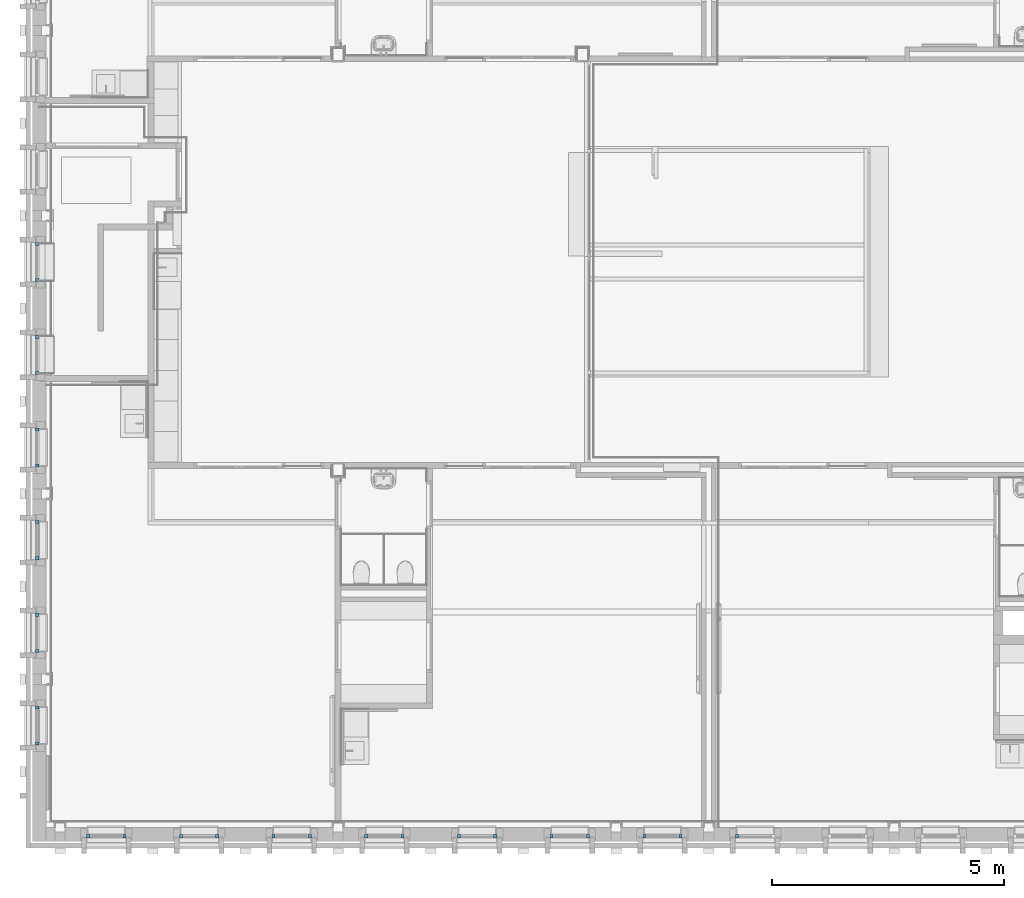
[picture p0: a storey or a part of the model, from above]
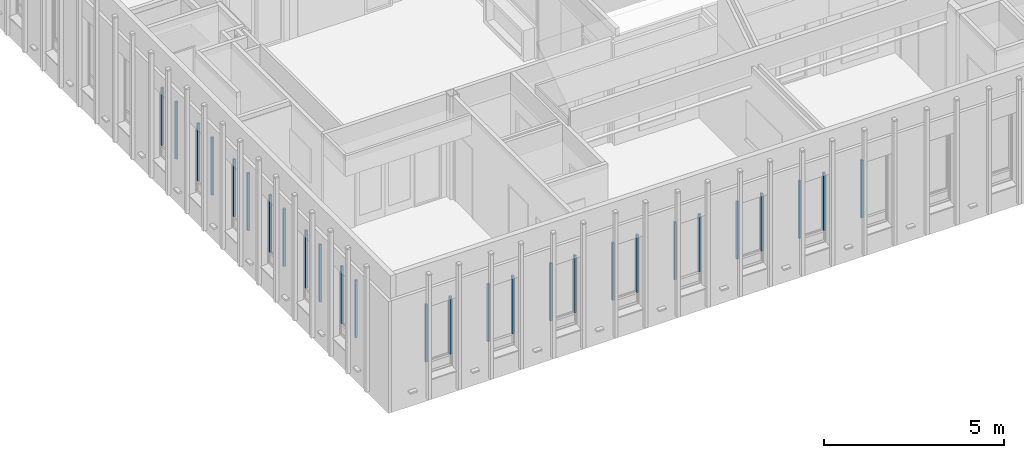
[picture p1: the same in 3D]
Properties of the parts of a building model (IFC2X3), part 1 of 94

# File
Description: ViewDefinition [CoordinationView_V2.0], RevitIdentifiers [VersionGUID: 146ff33c-e50f-46ca-b9aa-af931701fe89, NumberOfSaves: 1052], ExchangeRequirement [], CoordinateReference [CoordinateBase: Shared Coordinates, ProjectSite: Internal]
File name: 6755
Time: 2025-07-30T16:03:44
Organization: BDG Architecten
Written by: ODA IFC SDK 22.8
Made in: 22.1.30.34 - Exporter 22.6.0.0 - Alternate UI 22.6.0.0

# IfcProject, 6755
LongName: IKC Rummerinkhof Haren; Phase: Uitvoering Ontwerp

# IfcSite, Locatie
RefLatitude: 52, 22, 58, 797912; RefLongitude: 4, 54, 57, 599601; RefElevation: 0 mm
Phasing - Phase Created: 2. nieuwbouw
Dimensions - Projected Area: 0.473999 m2; Surface Area: 0.473999 m2
Identity Data - Workset: Workset1
Other - Category: Topography

# IfcSite: zitelementen trap:zitelementen trap, zitelementen trap:zitelementen trap:2230231
Material: <Unnamed>
Constraints - Moves With Nearby Elements: no
Phasing - Phase Created: 2. nieuwbouw
Dimensions - Area: 20.7661 m2; Volume: 9.77428 m3
Identity Data - Workset: Workset1
Other - Category: Site; Family: zitelementen trap; Family and Type: zitelementen trap: zitelementen trap; Type: zitelementen trap; Type Id: 2230229
Identity Data(Type) - Workset: Workset1; Type Name: zitelementen trap
Other(Type) - Category: Site; Family Name: zitelementen trap

# IfcBuilding, Bouwwerk
LongName: Bouwwerk
Text - CON: 22-12-2021; concepttekst: concept:; INST: 10-05-2022; modelverantwoordelijke: REU; ontwerpverantwoordelijke: SAM; Project_fase_afkorting: UO; projectverantwoordelijke: SAM; template_versie: 2019.1
Identity Data - Building Name: Bouwwerk; Organization Description: BDG Architecten; Organization Name: BDG Architecten; SiteName: Locatie; Workset: Project Info
Other - BCB_ProjectFolder: P:\0000_BDG_Revit_Bibliotheek\01 Template\; Category: Project Information; Client Name: Gemeente Groningen; Project Address: straatnaam + nummer postcode + plaatsnaam; Project Issue Date: 01-01-2019; Project Name: IKC Rummerinkhof Haren; Project Number: 6755; Project Status: Uitvoering Ontwerp

# IfcBuildingStorey: Level:A_hoogte_3.5mm (4)
In: Bouwwerk
Identity Data - Workset: Shared Levels and Grids
Other - Category: Levels; Family: Level
Constraints(Type) - Elevation Base: Project Base Point
Graphics(Type) - Line Pattern: levels; Line Weight: 1
Identity Data(Type) - Workset: Level Types
Other(Type) - Category: Levels; Family Name: Level
Name | LongName | Elevation (mm) | Constraints, Elevation (mm) | Computation Height (mm) | Building Story = Symbol at End 2 Default | Name | Structural = Symbol at End 1 Default | Family and Type | Type = Type Name | Type Id | Color | Symbol
00 begane grond | 00 begane grond | -5.41434e-13 | -1120 | 0 | no | ok. fundering | yes | Level: S_hoogte_1.8mm_fundering | S_hoogte_1.8mm_fundering | 2455 | 16711680 | NLRS_00_TAG_LVL_onder_binnen : 1.8mm | Extents - Scope Box: projectomtrek
01 eerste verdieping | 01 eerste verdieping | 4000 | 4000 | 1500 | yes | 01 eerste verdieping | no | Level: A_hoogte_3.5mm | A_hoogte_3.5mm | 2431 | 8421504 | NLRS_00_TAG_LVL : 3.5mm | Extents - Scope Box: projectomtrek
02 tweede verdieping | 02 tweede verdieping | 7800 | 7800 | 1500 | yes | 02 tweede verdieping | no | Level: A_hoogte_3.5mm | A_hoogte_3.5mm | 2431 | 8421504 | NLRS_00_TAG_LVL : 3.5mm
03 derde verdieping | 03 derde verdieping | 11600 | 11600 | 1500 | yes | 03 derde verdieping | no | Level: A_hoogte_3.5mm | A_hoogte_3.5mm | 2431 | 8421504 | NLRS_00_TAG_LVL : 3.5mm

# IfcAnnotation (51)
Name (Model Lines:...) | In | Group
2755334 | 01 eerste verdieping | Model Group:BI-30:2755094
2755564 | 01 eerste verdieping | Model Group:BI-30:2755094
2755577 | 01 eerste verdieping | Model Group:BI-30:2755094
2867687 | 00 begane grond | Model Group:pantry 1 kinderopvang:1511177
2868407 | 00 begane grond | Model Group:pantry 1 kinderopvang:1511177
2869288 | 00 begane grond | Model Group:pantry 1 kinderopvang:1223752
2869295 | 00 begane grond | Model Group:pantry 1 kinderopvang:1223752
2869762 | 00 begane grond | Model Group:pantry 1 kinderopvang:1511177
2869850 | 00 begane grond | Model Group:pantry 1 kinderopvang:1223752
2871598 | 00 begane grond | Model Group:pantry 1.2 MF BSO:1614348
2872757 | 01 eerste verdieping | Model Group:pantry 3 BS groepsruimten:1223713
2872777 | 02 tweede verdieping | Model Group:pantry 3 BS groepsruimten:1694326
2872792 | 01 eerste verdieping | Model Group:pantry 3 BS groepsruimten:2860118
2872797 | 01 eerste verdieping | Model Group:pantry 6 BSO startruimte:2860361
2872802 | 01 eerste verdieping | Model Group:pantry 3 BS groepsruimten:2860456
2872807 | 01 eerste verdieping | Model Group:pantry 3 BS groepsruimten:2860491
2872822 | 02 tweede verdieping | Model Group:pantry 3 BS groepsruimten:2860760
2872837 | 02 tweede verdieping | Model Group:pantry 3 BS groepsruimten:2860796
2873451 | 00 begane grond | Model Group:pantry 4 werkruimte OB:2071170
2873727 | 00 begane grond
2874626 | 01 eerste verdieping | Model Group:pantry 5 personeelsruimte:1672603
2875017 | 01 eerste verdieping | Model Group:pantry 5 personeelsruimte:1672603
2875172 | 01 eerste verdieping | Model Group:pantry 5 personeelsruimte:1672603
2875823 | 00 begane grond | Model Group:pantry 1.2 MF BSO:1614348
3028946 | 01 eerste verdieping
3221200 | 00 begane grond
3222013 | 00 begane grond
3222908 | 00 begane grond
3223677 | 00 begane grond
3267584 | 01 eerste verdieping | Model Group:pantry 3 BS groepsruimten:3267579
3267599 | 01 eerste verdieping | Model Group:pantry 3 BS groepsruimten:3267594
3267613 | 02 tweede verdieping | Model Group:pantry 3 BS groepsruimten:3267608
3267627 | 02 tweede verdieping | Model Group:pantry 3 BS groepsruimten:3267622
3267641 | 02 tweede verdieping | Model Group:pantry 3 BS groepsruimten:3267636
3270465 | 00 begane grond
3270484 | 00 begane grond
3473625 | 00 begane grond
3474388 | 00 begane grond
3685066 | 00 begane grond | Model Group:pantry 1.2 MF BSO:1614348
3694029 | 00 begane grond | Model Group:pantry 1 kinderopvang:1223752
4748769 | 01 eerste verdieping | Model Group:pantry 5 werkruimte MB BB:2860130
4749337 | 02 tweede verdieping | Model Group:pantry 5 werkruimte MB BB:4747283
4781338 | 00 begane grond
4782312 | 01 eerste verdieping | Model Group:pantry 5 werkruimte MB BB:2860130
4782402 | 02 tweede verdieping | Model Group:pantry 5 werkruimte MB BB:4747283
4782632 | 01 eerste verdieping
5027851 | 00 begane grond | Model Group:pantry 3 BS groepsruimten:5027846
5027942 | 00 begane grond | Model Group:pantry 3 BS groepsruimten:5027924
5027947 | 00 begane grond | Model Group:pantry 3 BS groepsruimten:5027929
5027957 | 00 begane grond | Model Group:pantry 3 BS groepsruimten:5027952
5101478 | 00 begane grond

# IfcBeam: NLRS_28_SF_LIB_balk hoeklijn_gen_ISR:balk_gen_L80x8 (13)
In: 01 eerste verdieping
Type - Structural Section Geometry - Centroid Horizontal: 22.6 mm; Centroid Vertical: 22.6 mm; Flange Fillet: 5 mm; Flange Thickness: 8 mm; Height: 80 mm; Web Fillet: 10 mm; Web Thickness: 8 mm; Width: 80 mm
Type - Structural Analysis - Perimeter: 0 mm; Warping Constant: 0; Elastic Modulus strong axis: 0.0000126 m3; Elastic Modulus weak axis: 0.0000126 m3; Moment of Inertia strong axis: 7.22e-07 m4; Moment of Inertia weak axis: 7.22e-07 m4; Nominal Weight: 9.62996; Plastic Modulus strong axis: 0 m3; Plastic Modulus weak axis: 0 m3; Principal Axes Angle: 45 deg; Section Area: 0.00123 m2; Torsional Moment of Inertia: 0 m4
Type - Structural - Section Shape: 11
Type - Dimensions - NLRS_C_breedte: 80 mm; NLRS_C_hoogte: 80 mm; r: 10 mm; RSen_C_thickness: 8 mm
Type - Identity Data - Assembly Code: 28.11; Assembly Description: hoofddraagconstructies; kolommen en liggers, kolom-/liggerconstructies; Code Name: EN 10056-1; DIN EN 10056-1; Description: L80X8; Section Name Key: L80X8; SmartRevit_Versie: 2019.1; Type Name: balk_gen_L80x8; Workset: Family : Structural Framing : NLRS_28_SF_LIB_balk hoeklijn_gen_ISR
Type - Other - Category: Structural Framing; Family Name: NLRS_28_SF_LIB_balk hoeklijn_gen_ISR
Classification: 28.11 Uniformat (Uniformat); Material: h2_staal_gen
Geometric Position - y Offset Value: 0 mm; yz Justification: Uniform; Join Status: Both joins enabled; End Extension: 434.108 mm; z Justification: Bottom; z Offset Value: -200 mm
Constraints - Reference Level: 01 eerste verdieping; Cross-Section Rotation: 0 deg; Orientation: Normal; Reference Level Elevation: 4000 mm; Work Plane: Reference Plane : dak fietsenstalling
Phasing - Phase Created: 2. nieuwbouw
Structural - Enable Analytical Model: yes; Stick Symbol Location: Center of Geometry; Structural Usage: Other
Identity Data - Workset: BDG_fietsenstalling
Other - Family: NLRS_28_SF_LIB_balk hoeklijn_gen_ISR; Family and Type: NLRS_28_SF_LIB_balk hoeklijn_gen_ISR: balk_gen_L80x8; Type: balk_gen_L80x8; Type Id: 4126976
Name (NLRS_28_SF_LIB_balk hoeklijn_gen_ISR:balk_gen_L80x8:...) | Start Extension (mm) | y Justification | End Level Offset (mm) | Start Level Offset (mm) | Cut Length (mm) | Length (mm) = NLRS_C_lengte (mm) | Volume (m3) | Group
4129964 | -92.8679 | Right | -1577.65 | -1835.93 | 3304.64 | 2963.4 | 0.00405391 | Model Group:hoeklijnen L80:4129968
4129966 | -767.325 | Left | -1577.65 | -1894.72 | 3304.68 | 3637.9 | 0.00405396 | Model Group:hoeklijnen L80:4129968
4136355 | 378.749 | Right | -1536.79 | -1829.51 | 3320.2 | 3358.6 | 0.00407299 | Model Group:fietsenstalling:4188142 | Geometric Position - End Join Cutback: 0 mm; Start Join Cutback: 0 mm
4137484 | -92.8679 | Right | -1577.65 | -1835.93 | 3304.64 | 2963.4 | 0.00405391 | Model Group:hoeklijnen L80:4137488
4137486 | -767.325 | Left | -1577.65 | -1894.72 | 3304.68 | 3637.9 | 0.00405396 | Model Group:hoeklijnen L80:4137488
4137510 | -92.8679 | Right | -1577.65 | -1835.93 | 3304.64 | 2963.4 | 0.00405391 | Model Group:hoeklijnen L80:4137514
4137512 | -767.325 | Left | -1577.65 | -1894.72 | 3304.68 | 3637.9 | 0.00405396 | Model Group:hoeklijnen L80:4137514
4137573 | -92.8679 | Right | -1577.65 | -1835.93 | 3304.64 | 2963.4 | 0.00405391 | Model Group:hoeklijnen L80:4137577
4137575 | -767.325 | Left | -1577.65 | -1894.72 | 3304.68 | 3637.9 | 0.00405396 | Model Group:hoeklijnen L80:4137577
4137597 | -92.8679 | Right | -1577.65 | -1835.93 | 3304.64 | 2963.4 | 0.00405391 | Model Group:hoeklijnen L80:4137601
4137599 | -767.325 | Left | -1577.65 | -1894.72 | 3304.68 | 3637.9 | 0.00405396 | Model Group:hoeklijnen L80:4137601
4137623 | -92.8679 | Right | -1577.65 | -1835.93 | 3304.64 | 2963.4 | 0.00405391 | Model Group:hoeklijnen L80:4137627
4137625 | -767.325 | Left | -1577.65 | -1894.72 | 3304.68 | 3637.9 | 0.00405396 | Model Group:hoeklijnen L80:4137627

# IfcBeam: NLRS_28_SF_LIB_balk koker ongelijk_gen_ISR:balk gen k150x100x4 (2)
In: 01 eerste verdieping
Type - PredefinedType: BEAM
Type - Structural Section Geometry - Centroid Horizontal: 50 mm; Centroid Vertical: 75 mm; Height: 150 mm; Inner Fillet: 4 mm; Outer Fillet: 8 mm; Wall Nominal Thickness: 4 mm; Width: 100 mm
Type - Structural Analysis - Nominal Weight: 0; Perimeter: 0 mm; Elastic Modulus strong axis: 0 m3; Elastic Modulus weak axis: 0 m3; Moment of Inertia strong axis: 0 m4; Moment of Inertia weak axis: 0 m4; Plastic Modulus strong axis: 0 m3; Plastic Modulus weak axis: 0 m3; Section Area: 0 m2; Torsional Modulus: 0 m3; Torsional Moment of Inertia: 0 m4
Type - Structural - Section Shape: 14
Type - Dimensions - NLRS_C_breedte: 100 mm; NLRS_C_hoogte: 150 mm; r: 8 mm; r1: 4 mm; RSen_C_thickness: 4 mm; Wall Design Thickness: 4 mm
Type - Identity Data - Workset: Family : Structural Framing : NLRS_28_SF_LIB_balk koker ongelijk_gen_ISR; Assembly Code: 28.10; Assembly Description: hoofddraagconstructies; kolommen en liggers, algemeen (verzamelniveau); Code Name: EN 10210-2; DIN EN 10210-2; Description: K150x100x4; SmartRevit_Versie: 2021.1; Type Name: balk gen k150x100x4
Type - Other - Category: Structural Framing; Family Name: NLRS_28_SF_LIB_balk koker ongelijk_gen_ISR
Classification: 28.10 Uniformat (Uniformat); Material: h2_staal_gen
Geometric Position - y Justification: Origin; y Offset Value: 0 mm; yz Justification: Uniform; z Justification: Top; z Offset Value: 0 mm; Join Status: Both joins enabled; End Extension: -112.5 mm; Start Extension: 575 mm
Constraints - Cross-Section Rotation: 0 deg
Phasing - Phase Created: 2. nieuwbouw
Structural - Enable Analytical Model: yes; Stick Symbol Location: Center of Geometry; Structural Usage: Other; Cut Length: 8445 mm
Dimensions - Length: 7982.5 mm; NLRS_C_lengte: 7982.5 mm; Volume: 0.0160015 m3
Identity Data - Workset: Workset1
Other - Family: NLRS_28_SF_LIB_balk koker ongelijk_gen_ISR; Family and Type: NLRS_28_SF_LIB_balk koker ongelijk_gen_ISR: balk gen k150x100x4; Type: balk gen k150x100x4; Type Id: 1358057
Name (NLRS_28_SF_LIB_balk koker ongelijk_gen_ISR:balk gen k150x100x4:...) | Reference Level | End Level Offset (mm) = Start Level Offset (mm) | Reference Level Elevation (mm) | Elevation at Bottom (mm) | Elevation at Top (mm)
3952707 | 01 eerste verdieping | 330 | 4000 | 4180 | 4330
3952937 | 01 ok. plafond | 430 | 6800 | 7080 | 7230

# IfcBeam: NLRS_28_SF_LIB_balk koker ongelijk_gen_ISR:balk gen k200x100x6 (6)
In: 01 eerste verdieping
Type - PredefinedType: BEAM
Type - Structural Section Geometry - Centroid Horizontal: 50 mm; Centroid Vertical: 100 mm; Height: 200 mm; Inner Fillet: 6 mm; Outer Fillet: 12 mm; Wall Nominal Thickness: 6 mm; Width: 100 mm
Type - Structural Analysis - Nominal Weight: 0; Perimeter: 0 mm; Elastic Modulus strong axis: 0 m3; Elastic Modulus weak axis: 0 m3; Moment of Inertia strong axis: 0 m4; Moment of Inertia weak axis: 0 m4; Plastic Modulus strong axis: 0 m3; Plastic Modulus weak axis: 0 m3; Section Area: 0 m2; Torsional Modulus: 0 m3; Torsional Moment of Inertia: 0 m4
Type - Structural - Section Shape: 14
Type - Dimensions - NLRS_C_breedte: 100 mm; NLRS_C_hoogte: 200 mm; r: 12 mm; r1: 6 mm; RSen_C_thickness: 6 mm; Wall Design Thickness: 6 mm
Type - Identity Data - Workset: Family : Structural Framing : NLRS_28_SF_LIB_balk koker ongelijk_gen_ISR; Assembly Code: 28.10; Assembly Description: hoofddraagconstructies; kolommen en liggers, algemeen (verzamelniveau); Code Name: EN 10210-2; DIN EN 10210-2; Description: K200x100x6; SmartRevit_Versie: 2021.1; Type Name: balk gen k200x100x6
Type - Other - Category: Structural Framing; Family Name: NLRS_28_SF_LIB_balk koker ongelijk_gen_ISR
Description: FRQ{AF4261DB-57B6-492A-99EC-BCCF86134FA2}; Classification: 28.10 Uniformat (Uniformat); Material: h2_staal_gen
ProfileProperties - SectionFamily: {AF4261DB-57B6-492A-99EC-BCCF86134FA2}FRQ; Section: FRQ{AF4261DB-57B6-492A-99EC-BCCF86134FA2}
Geometric Position - y Justification: Origin; y Offset Value: 0 mm; yz Justification: Uniform; z Justification: Top; z Offset Value: 0 mm; Join Status: Both joins enabled
Constraints - Reference Level: 01 eerste verdieping; End Level Offset: 2900 mm; Reference Level Elevation: 4000 mm; Start Level Offset: 2900 mm
Phasing - Phase Created: 2. nieuwbouw
Structural - Enable Analytical Model: yes; Stick Symbol Location: Center of Geometry; Structural Usage: Other; Coating: -
Identity Data - Workset: Workset1
Other - Family: NLRS_28_SF_LIB_balk koker ongelijk_gen_ISR; Family and Type: NLRS_28_SF_LIB_balk koker ongelijk_gen_ISR: balk gen k200x100x6; Type: balk gen k200x100x6; Type Id: 1357985
Name (NLRS_28_SF_LIB_balk koker ongelijk_gen_ISR:balk gen k200x100x6:...) | Cross-Section Rotation (deg) | Cut Length (mm) | Exact Weight (kg) | Paint Area (m2) | Weight (kg) | Elevation at Bottom (mm) | Elevation at Top (mm) | Length (mm) = NLRS_C_lengte (mm) | Volume (m3)
2552460 | 90 | 14868.8 | 138.321 | 8.92127 | 139.257 | 6750 | 7050 | 14768.7 | 0.0510409
2552454 | 90 | 6750 | 61.3457 | 4.05 | 63.2189 | 6850 | 6950 | 6550 | 0.0226368
2464441 | -90 | 6260 | 57.6931 | 3.756 | 58.6296 | 6750 | 7050 | 6160 | 0.021289
2552452 | 90 | 9725 | 90.1454 | 5.835 | 91.082 | 6850 | 6950 | 9725 | 0.033264
2552462 | -90 | 6175 | 56.897 | 3.705 | 57.8336 | 6750 | 7050 | 6075 | 0.0209952
2552456 | 90 | 18249.9 | 169.987 | 10.9499 | 170.924 | 6850 | 6950 | 18179.8 | 0.062726

# IfcBeam: NLRS_28_SF_LIB_balk koker ongelijk_gen_ISR:balk gen k80x50x4 (31)
In: 01 eerste verdieping
Type - PredefinedType: BEAM
Type - Structural Section Geometry - Centroid Horizontal: 25 mm; Centroid Vertical: 40 mm; Height: 80 mm; Inner Fillet: 4 mm; Outer Fillet: 8 mm; Wall Nominal Thickness: 4 mm; Width: 50 mm
Type - Structural Analysis - Elastic Modulus strong axis: 0 m3; Elastic Modulus weak axis: 0 m3; Moment of Inertia strong axis: 0 m4; Moment of Inertia weak axis: 0 m4; Nominal Weight: 0; Perimeter: 0 mm; Plastic Modulus strong axis: 0 m3; Plastic Modulus weak axis: 0 m3; Section Area: 0 m2; Torsional Modulus: 0 m3; Torsional Moment of Inertia: 0 m4
Type - Structural - Section Shape: 14
Type - Dimensions - NLRS_C_breedte: 50 mm; NLRS_C_hoogte: 80 mm; r: 8 mm; r1: 4 mm; RSen_C_thickness: 4 mm; Wall Design Thickness: 4 mm
Type - Identity Data - Assembly Code: 28.10; Assembly Description: hoofddraagconstructies; kolommen en liggers, algemeen (verzamelniveau); Code Name: EN 10210-2; DIN EN 10210-2; Description: K80x50x4; SmartRevit_Versie: 2021.1; Type Name: balk gen k80x50x4; Workset: Family : Structural Framing : NLRS_28_SF_LIB_balk koker ongelijk_gen_ISR
Type - Other - Category: Structural Framing; Family Name: NLRS_28_SF_LIB_balk koker ongelijk_gen_ISR
Classification: 28.10 Uniformat (Uniformat); Material: h2_staal_gen
Geometric Position - Join Status: One or two joins disabled; y Justification: Origin; y Offset Value: 0 mm; yz Justification: Uniform; z Justification: Top; z Offset Value: 0 mm
Constraints - Reference Level: 01 eerste verdieping; Reference Level Elevation: 4000 mm
Phasing - Phase Created: 2. nieuwbouw
Structural - Enable Analytical Model: yes; Stick Symbol Location: Center of Geometry; Structural Usage: Other
Identity Data - Workset: Workset1
Other - Family: NLRS_28_SF_LIB_balk koker ongelijk_gen_ISR; Family and Type: NLRS_28_SF_LIB_balk koker ongelijk_gen_ISR: balk gen k80x50x4; Type: balk gen k80x50x4; Type Id: 1358229
Name (NLRS_28_SF_LIB_balk koker ongelijk_gen_ISR:balk gen k80x50x4:...) | End Extension (mm) | Start Extension (mm) | Cross-Section Rotation (deg) | End Level Offset (mm) = Start Level Offset (mm) | Cut Length (mm) | Elevation at Bottom (mm) | Elevation at Top (mm) | Length (mm) = NLRS_C_lengte (mm) | Volume (m3)
2766380 | 0 | 0 | 90 | 900 | 1900 | 4875 | 4925 | 1900 | 0.0017761
2767286 | 0 | 0 | 90 | 900 | 1900 | 4875 | 4925 | 1900 | 0.0017761
2767301 | 0 | 0 | 90 | 900 | 1900 | 4875 | 4925 | 1900 | 0.0017761
2767314 | 0 | 0 | 90 | 900 | 1577 | 4875 | 4925 | 1577 | 0.00147416
2767377 | 0 | 0 | 90 | 900 | 1900 | 4875 | 4925 | 1900 | 0.0017761
2767541 | 65 | 0 | 90 | 900 | 1900 | 4875 | 4925 | 1835 | 0.0017761
2767805 | 0 | 0 | 90 | 900 | 1900 | 4875 | 4925 | 1900 | 0.0017761
2767822 | 0 | 0 | 90 | 900 | 1900 | 4875 | 4925 | 1900 | 0.0017761
2767837 | 0 | 0 | 90 | 900 | 1900 | 4875 | 4925 | 1900 | 0.0017761
2767852 | 0 | 0 | 90 | 900 | 1900 | 4875 | 4925 | 1900 | 0.0017761
2767869 | 0 | 0 | 90 | 900 | 1900 | 4875 | 4925 | 1900 | 0.0017761
2767888 | 0 | 0 | 90 | 900 | 990 | 4875 | 4925 | 990 | 0.000925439
2768090 | 0 | -15 | 90 | 900 | 2053.3 | 4875 | 4925 | 2068.3 | 0.0019194
2768313 | 0 | 0 | 90 | 900 | 2083.4 | 4875 | 4925 | 2083.4 | 0.00194754
2768391 | 0 | 0 | 90 | 900 | 2142.6 | 4875 | 4925 | 2142.6 | 0.00200287
2768988 | 0 | 0 | 90 | 330 | 860 | 4305 | 4355 | 860 | 0.000803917
2769003 | 0 | 0 | 90 | 900 | 270 | 4875 | 4925 | 270 | 0.000252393
2770761 | 0 | 0 | 90 | 900 | 1875 | 4875 | 4925 | 1875 | 0.00175273
2771299 | 0 | 0 | 90 | 900 | 912.7 | 4875 | 4925 | 912.7 | 0.00085318
2771316 | 0 | 0 | 90 | 900 | 1900.2 | 4875 | 4925 | 1900.2 | 0.00177628
2772880 | 0 | 0 | -90 | 300 | 1875 | 4275 | 4325 | 1875 | 0.00175273
2772883 | 0 | 0 | -90 | 300 | 1875 | 4275 | 4325 | 1875 | 0.00175273
2772885 | 0 | 0 | -90 | 300 | 1900.2 | 4275 | 4325 | 1900.2 | 0.00177628
2879938 | 0 | 0 | 90 | 900 | 1900 | 4875 | 4925 | 1900 | 0.0017761
2880081 | 0 | 0 | 90 | 900 | 1900 | 4875 | 4925 | 1900 | 0.0017761
2880092 | 0 | 0 | 90 | 900 | 1900 | 4875 | 4925 | 1900 | 0.0017761
2880107 | 0 | 0 | 90 | 900 | 1900 | 4875 | 4925 | 1900 | 0.0017761
2880124 | 0 | 0 | 90 | 900 | 1900 | 4875 | 4925 | 1900 | 0.0017761
2880139 | 0 | 0 | 90 | 900 | 1900 | 4875 | 4925 | 1900 | 0.0017761
2880150 | 0 | 0 | 90 | 900 | 1900 | 4875 | 4925 | 1900 | 0.0017761
2880163 | 0 | 0 | 90 | 900 | 525 | 4875 | 4925 | 525 | 0.000490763

# IfcBeam: NLRS_28_SF_LIB_balk koker_gen_ongelijk_ISR:balk_gen_K60x60x4 (20)
In: 00 begane grond
Type - Structural Section Geometry - Centroid Horizontal: 30 mm; Centroid Vertical: 30 mm; Height: 60 mm; Inner Fillet: 4 mm; Outer Fillet: 6 mm; Wall Nominal Thickness: 4 mm; Width: 60 mm
Type - Structural Analysis - Elastic Modulus strong axis: 0.0000109 m3; Elastic Modulus weak axis: 0.00000852 m3; Moment of Inertia strong axis: 3.28e-07 m4; Moment of Inertia weak axis: 1.7e-07 m4; Nominal Weight: 5.63998; Perimeter: 190 mm; Plastic Modulus strong axis: 0.0000138 m3; Plastic Modulus weak axis: 0.0000103 m3; Section Area: 0.000719 m2; Torsional Modulus: 0.00001371 m3; Torsional Moment of Inertia: 3.67e-07 m4
Type - Structural - Section Shape: 14
Type - Dimensions - NLRS_C_breedte: 60 mm; NLRS_C_hoogte: 60 mm; r: 4 mm; RSen_C_thickness: 4 mm; Wall Design Thickness: 4 mm
Type - Identity Data - Assembly Code: 28.11; Assembly Description: hoofddraagconstructies; kolommen en liggers, kolom-/liggerconstructies; Code Name: EN 10210-2; DIN EN 10210-2; Description: K60X40X4; Section Name Key: R60X40X4; SmartRevit_Versie: 2019.1; Type Name: balk_gen_K60x60x4; Workset: Family : Structural Framing : NLRS_28_SF_LIB_balk koker_gen_ongelijk_ISR
Type - Other - Category: Structural Framing; Family Name: NLRS_28_SF_LIB_balk koker_gen_ongelijk_ISR
Classification: 28.11 Uniformat (Uniformat); Material: h2_staal_gen
Geometric Position - End Extension: 0 mm; Join Status: One or two joins disabled; Start Extension: 0 mm; y Justification: Origin; y Offset Value: 0 mm; yz Justification: Uniform; z Justification: Top; z Offset Value: 0 mm
Constraints - Cross-Section Rotation: 0 deg
Phasing - Phase Created: 2. nieuwbouw
Structural - Enable Analytical Model: yes; Stick Symbol Location: Center of Geometry; Structural Usage: Other
Identity Data - Workset: BDG_fietsenstalling
Other - Family: NLRS_28_SF_LIB_balk koker_gen_ongelijk_ISR; Family and Type: NLRS_28_SF_LIB_balk koker_gen_ongelijk_ISR: balk_gen_K60x60x4; Type: balk_gen_K60x60x4; Type Id: 4098477
Name (NLRS_28_SF_LIB_balk koker_gen_ongelijk_ISR:balk_gen_K60x60x4:...) | End Level Offset (mm) = Start Level Offset (mm) | Reference Level | Reference Level Elevation (mm) | Cut Length (mm) = Length (mm) = NLRS_C_lengte (mm) | Elevation at Bottom (mm) | Elevation at Top (mm) | Volume (m3) | Group
4158217 | -600 | 00 ok. plafond | 2800 | 959.7 | 2140 | 2200 | 0.000820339 | Model Group:enkele deur-kokers:4158221
4158219 | 60 | 00 begane grond | 0 | 958.5 | 0 | 60 | 0.000819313 | Model Group:enkele deur-kokers:4158221
4158252 | -600 | 00 ok. plafond | 2800 | 959.7 | 2140 | 2200 | 0.000820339 | Model Group:enkele deur-kokers:4158256
4158254 | 60 | 00 begane grond | 0 | 958.5 | 0 | 60 | 0.000819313 | Model Group:enkele deur-kokers:4158256
4158441 | -600 | 00 ok. plafond | 2800 | 959.7 | 2140 | 2200 | 0.000820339 | Model Group:enkele deur-kokers:4158445
4158443 | 60 | 00 begane grond | 0 | 958.5 | 0 | 60 | 0.000819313 | Model Group:enkele deur-kokers:4158445
4158453 | -600 | 00 ok. plafond | 2800 | 959.7 | 2140 | 2200 | 0.000820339 | Model Group:enkele deur-kokers:4158457
4158455 | 60 | 00 begane grond | 0 | 958.5 | 0 | 60 | 0.000819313 | Model Group:enkele deur-kokers:4158457
4158493 | -600 | 00 ok. plafond | 2800 | 959.7 | 2140 | 2200 | 0.000820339 | Model Group:enkele deur-kokers:4158497
4158495 | 60 | 00 begane grond | 0 | 958.5 | 0 | 60 | 0.000819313 | Model Group:enkele deur-kokers:4158497
4158505 | -600 | 00 ok. plafond | 2800 | 959.7 | 2140 | 2200 | 0.000820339 | Model Group:enkele deur-kokers:4158509
4158507 | 60 | 00 begane grond | 0 | 958.5 | 0 | 60 | 0.000819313 | Model Group:enkele deur-kokers:4158509
4158519 | -600 | 00 ok. plafond | 2800 | 959.7 | 2140 | 2200 | 0.000820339 | Model Group:enkele deur-kokers:4158523
4158521 | 60 | 00 begane grond | 0 | 958.5 | 0 | 60 | 0.000819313 | Model Group:enkele deur-kokers:4158523
4158531 | -600 | 00 ok. plafond | 2800 | 959.7 | 2140 | 2200 | 0.000820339 | Model Group:enkele deur-kokers:4158535
4158533 | 60 | 00 begane grond | 0 | 958.5 | 0 | 60 | 0.000819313 | Model Group:enkele deur-kokers:4158535
4158545 | -600 | 00 ok. plafond | 2800 | 959.7 | 2140 | 2200 | 0.000820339 | Model Group:enkele deur-kokers:4158549
4158547 | 60 | 00 begane grond | 0 | 958.5 | 0 | 60 | 0.000819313 | Model Group:enkele deur-kokers:4158549
4158557 | -600 | 00 ok. plafond | 2800 | 959.7 | 2140 | 2200 | 0.000820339 | Model Group:enkele deur-kokers:4158561
4158559 | 60 | 00 begane grond | 0 | 958.5 | 0 | 60 | 0.000819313 | Model Group:enkele deur-kokers:4158561

# IfcBeam: NLRS_28_SF_LIB_balk unp_gen_ISR:balk_gen_UNP200 (6)
Type - PredefinedType: BEAM
Type - Structural Section Geometry - Centroid Horizontal: 19.2 mm; Centroid Vertical: 100 mm; Flange Fillet: 5.5 mm; Flange Thickness: 11 mm; Flange Thickness Location: 35 mm; Height: 200 mm; Sloped Flange Angle: 0 deg; Web Fillet: 11 mm; Web Thickness: 8 mm; Width: 70 mm
Type - Structural Analysis - Warping Constant: 0; Elastic Modulus strong axis: 0.00015 m3; Elastic Modulus weak axis: 0.0000224 m3; Moment of Inertia strong axis: 0.0000135 m4; Moment of Inertia weak axis: 0.00000114 m4; Nominal Weight: 21.9999; Perimeter: 611 mm; Plastic Modulus strong axis: 0 m3; Plastic Modulus weak axis: 0 m3; Section Area: 0.0028 m2; Torsional Moment of Inertia: 0 m4
Type - Structural - Section Shape: 10
Type - Dimensions - Clear Web Height: 0 mm; NLRS_C_breedte: 70 mm; NLRS_C_hoogte: 200 mm; r: 11 mm; r1: 5.5 mm; tf: 11 mm; tw: 8 mm; Web Toe of Fillet: 0 mm
Type - Identity Data - Assembly Code: 28.10; Assembly Description: hoofddraagconstructies; kolommen en liggers, algemeen (verzamelniveau); Code Name: DIN1026-1:2009; NF A 45-202; Description: UNP180; SmartRevit_Versie: 2021.1; Type Name: balk_gen_UNP200; Workset: Family : Structural Framing : NLRS_28_SF_LIB_balk unp_gen_ISR
Type - Other - Category: Structural Framing; Angle: 4.58 deg; Family Name: NLRS_28_SF_LIB_balk unp_gen_ISR
Classification: 28.10 Uniformat (Uniformat); Material: h2_staal_gen
Geometric Position - y Justification: Origin; y Offset Value: 0 mm; yz Justification: Uniform; z Justification: Top; z Offset Value: 0 mm; Join Status: Both joins enabled
Phasing - Phase Created: 2. nieuwbouw
Structural - Enable Analytical Model: yes; Stick Symbol Location: Center of Geometry; Structural Usage: Other
Other - Family: NLRS_28_SF_LIB_balk unp_gen_ISR; Family and Type: NLRS_28_SF_LIB_balk unp_gen_ISR: balk_gen_UNP200; Type: balk_gen_UNP200; Type Id: 3268208
Name (NLRS_28_SF_LIB_balk unp_gen_ISR:balk_gen_UNP200:...) | In | End Extension (mm) | Start Extension (mm) | Cross-Section Rotation (deg) | End Level Offset (mm) | Reference Level | Reference Level Elevation (mm) | Start Level Offset (mm) | Cut Length (mm) | Elevation at Bottom (mm) | Elevation at Top (mm) | Length (mm) = NLRS_C_lengte (mm) | Volume (m3) | Workset | Orientation | Work Plane | Group
3268982 | 00 begane grond | 0 | 0 | 90 | 3000 | 00 begane grond | 0 | 3000 | 2028.5 | 2980.8 | 3050.8 | 2033.8 | 0.00607789 | Workset1 | Geometric Position - End Join Cutback: -45.5 mm; Start Join Cutback: -45.5 mm; Structural - End Attachment Type: End Elevation; Start Attachment Type: End Elevation
4121682 | 01 eerste verdieping | -396.262 | 0 | 0 | -1829.51 | 01 eerste verdieping | 4000 | -1536.79 | 3460.23 |  |  | 3358.6 | 0.0100619 | BDG_fietsenstalling | Normal | Reference Plane : dak fietsenstalling | Model Group:UNP rand fietsenstalling:4046343
4121830 | 01 eerste verdieping | 0 | -72.33 | 0 | -1829.51 | 01 eerste verdieping | 4000 | -1829.51 | 14340 | 1966.82 | 2172.16 | 14238.4 | 0.0426652 | BDG_fietsenstalling | Normal | Reference Plane : dak fietsenstalling | Model Group:UNP rand fietsenstalling:4046343
4126428 | 01 eerste verdieping | 0 | 0 | 0 | -1536.79 | 01 eerste verdieping | 4000 | -1829.51 | 3460.23 |  |  | 3358.6 | 0.0100619 | BDG_fietsenstalling | Normal | Reference Plane : dak fietsenstalling | Model Group:UNP rand fietsenstalling:4046343
4126781 | 01 eerste verdieping | 0 | 0 | 0 | -1536.79 | 01 eerste verdieping | 4000 | -1536.79 | 14340 | 2262.3 | 2467.64 | 14238.4 | 0.0426652 | BDG_fietsenstalling | Normal | Reference Plane : dak fietsenstalling | Model Group:UNP rand fietsenstalling:4046343
4198678 | 00 begane grond | 0 | 0 | -90 | 3000 | 00 begane grond | 0 | 3000 | 1293 | 2980.8 | 3050.8 | 1298.3 | 0.00387415 | Workset1 | Geometric Position - End Join Cutback: -45.5 mm; Start Join Cutback: -45.5 mm; Structural - End Attachment Type: End Elevation; Start Attachment Type: End Elevation

# IfcBuildingElementProxy: 00_BDG_GM_Nulpunt:00_BDG_GM_Nulpunt, 00_BDG_GM_Nulpunt:00_BDG_GM_Nulpunt:668490
In: 00 begane grond
Type - Material: BDG - Zwart, BDG - Wit
Type - Constraints - Default Elevation: 0 mm
Type - Identity Data - algemeen_URL: www.bdgarchitecten.nl; Description: Nulpuntobject; Type Name: 00_BDG_GM_Nulpunt; Workset: Family : Generic Models : 00_BDG_GM_Nulpunt
Type - Other - Category: Generic Models; Family Name: 00_BDG_GM_Nulpunt
Constraints - Elevation from Level: 0 mm; Host: Level : 00 begane grond; Level: 00 begane grond; Moves With Nearby Elements: no; Offset from Host: 0 mm
Phasing - Phase Created: 2. nieuwbouw
Dimensions - Area: 3.45179 m2; Volume: 1.00565 m3
Identity Data - Workset: Workset1
Other - Family: 00_BDG_GM_Nulpunt; Family and Type: 00_BDG_GM_Nulpunt: 00_BDG_GM_Nulpunt; Type: 00_BDG_GM_Nulpunt; Type Id: 668474

# IfcBuildingElementProxy: 200_50_BDG_noodoverstort:NO-01 (2)
In: 03 derde verdieping
Type - Material: GAG_noodoverstort
Type - Constraints - Default Elevation: 0 mm
Type - Materials and Finishes - materiaal: GAG_noodoverstort
Type - Dimensions - breedte: 350 mm; diepte_binnen_stramien: 180 mm; diepte_buiten_stramien: 170 mm; hoek: 7.5 deg; hoogte: 120 mm; offset_peil: 225 mm
Type - Identity Data - Workset: Family : Generic Models : 200_50_BDG_noodoverstort; Description: NO.; Type Name: NO-01
Type - Other - Category: Generic Models; Family Name: 200_50_BDG_noodoverstort
Constraints - Moves With Nearby Elements: no; Level: 03 derde verdieping; Elevation from Level: 70 mm; Host: Level : 03 derde verdieping; Offset from Host: 70 mm
Phasing - Phase Created: 2. nieuwbouw
Dimensions - Area: 0.330895 m2; Volume: 0.00065803 m3
Identity Data - Workset: Workset1
Other - Family: 200_50_BDG_noodoverstort; Family and Type: 200_50_BDG_noodoverstort: NO-01; Type: NO-01; Type Id: 4693193
Name (200_50_BDG_noodoverstort:NO-01:...)
4693038
4693404

# IfcBuildingElementProxy: 200_50_BDG_noodoverstort:NO-02 (2)
In: 01 eerste verdieping
Type - Material: GAG_noodoverstort
Type - Constraints - Default Elevation: 0 mm
Type - Materials and Finishes - materiaal: GAG_noodoverstort
Type - Dimensions - breedte: 200 mm; diepte_binnen_stramien: 180 mm; diepte_buiten_stramien: 170 mm; hoek: 10 deg; hoogte: 120 mm; offset_peil: 225 mm
Type - Identity Data - Workset: Family : Generic Models : 200_50_BDG_noodoverstort; Description: NO.; Type Name: NO-02
Type - Other - Category: Generic Models; Family Name: 200_50_BDG_noodoverstort
Constraints - Moves With Nearby Elements: no; Elevation from Level: 270 mm; Host: Level : 02 bk. constructie gymzaal; Level: 02 bk. constructie gymzaal; Offset from Host: 270 mm
Phasing - Phase Created: 2. nieuwbouw
Dimensions - Area: 0.225896 m2; Volume: 0.000449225 m3
Identity Data - Workset: Workset1
Other - Family: 200_50_BDG_noodoverstort; Family and Type: 200_50_BDG_noodoverstort: NO-02; Type: NO-02; Type Id: 4692311
Name (200_50_BDG_noodoverstort:NO-02:...)
4692275
4692902

# IfcBuildingElementProxy: 200_50_BDG_noodoverstort:NO-03, 200_50_BDG_noodoverstort:NO-03:4690609
In: 01 eerste verdieping
Type - Material: GAG_noodoverstort
Type - Constraints - Default Elevation: 0 mm
Type - Materials and Finishes - materiaal: GAG_noodoverstort
Type - Dimensions - breedte: 350 mm; diepte_binnen_stramien: 110 mm; diepte_buiten_stramien: 260 mm; hoek: 10 deg; hoogte: 150 mm; offset_peil: 225 mm
Type - Identity Data - Workset: Family : Generic Models : 200_50_BDG_noodoverstort; Description: NO.; Type Name: NO-03
Type - Other - Category: Generic Models; Family Name: 200_50_BDG_noodoverstort
Constraints - Moves With Nearby Elements: no; Level: 01 eerste verdieping; Elevation from Level: 50 mm; Host: Level : 01 eerste verdieping; Offset from Host: 50 mm
Phasing - Phase Created: 2. nieuwbouw
Dimensions - Area: 0.374717 m2; Volume: 0.000745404 m3
Identity Data - Workset: Workset1
Other - Family: 200_50_BDG_noodoverstort; Family and Type: 200_50_BDG_noodoverstort: NO-03; Type: NO-03; Type Id: 4690830

# IfcBuildingElementProxy: 200_50_BDG_noodoverstort:noodoverstort verdieping, 200_50_BDG_noodoverstort:noodoverstort verdieping:2224659
In: 02 tweede verdieping
Type - Material: GAG_noodoverstort
Type - Constraints - Default Elevation: 0 mm
Type - Materials and Finishes - materiaal: GAG_noodoverstort
Type - Dimensions - breedte: 230 mm; diepte_binnen_stramien: 160 mm; diepte_buiten_stramien: 300 mm; hoek: 10 deg; hoogte: 70 mm; offset_peil: 225 mm
Type - Identity Data - Description: NO.; Type Name: noodoverstort verdieping; Workset: Family : Generic Models : 200_50_BDG_noodoverstort
Type - Other - Category: Generic Models; Family Name: 200_50_BDG_noodoverstort
Constraints - Moves With Nearby Elements: no; Level: 02 tweede verdieping; Elevation from Level: 50 mm; Host: Level : 02 tweede verdieping; Offset from Host: 50 mm
Phasing - Phase Created: 2. nieuwbouw
Dimensions - Area: 0.277723 m2; Volume: 0.000553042 m3
Identity Data - Workset: Workset1
Other - Family: 200_50_BDG_noodoverstort; Family and Type: 200_50_BDG_noodoverstort: noodoverstort verdieping; Type: noodoverstort verdieping; Type Id: 2224213

# IfcBuildingElementProxy: 28_BDG_ladderborging:Type 1, 28_BDG_ladderborging:Type 1:2803350
In: 01 eerste verdieping
Type - Material: Aluminium
Type - Constraints - Default Elevation: 0 mm
Type - Materials and Finishes - materiaal: Aluminium
Type - Identity Data - Type Name: Type 1; Workset: Family : Generic Models : 28_BDG_ladderborging
Type - Other - Category: Generic Models; Family Name: 28_BDG_ladderborging
Constraints - Level: 01 eerste verdieping; Elevation from Level: 2975 mm
Phasing - Phase Created: 2. nieuwbouw
Dimensions - Area: 0.158771 m2; Volume: 0.000748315 m3
Identity Data - Workset: Workset1
Other - Type: Type 1; Family: 28_BDG_ladderborging; Family and Type: 28_BDG_ladderborging: Type 1; Host Id: 1888559; Type Id: 2803331

# IfcBuildingElementProxy: 80_FUS_UN_garderobe:GK 1A 2231x350x1050 (2)
Type - Material: ISR_Hout
Type - Constraints - Default Elevation: 1219.2 mm; aantal_haken: 27
Type - Materials and Finishes - materiaal_kader: ISR_Hout; materiaal_kastframe: ISR_Hout
Type - Construction - 2 tussenpanelen: no; tussenpaneel: no
Type - Dimensions - diepte: 350 mm; diepte_kastplanken: 310 mm; kasthoogte: 1050 mm; lengte: 2231 mm; plaatmateriaal_dikte: 40 mm; rij-afstand haken: 75 mm
Type - Identity Data - Type Comments: GK 1A; Type Name: GK 1A 2231x350x1050; Workset: Family : Generic Models : 80_FUS_UN_garderobe
Type - Other - Category: Generic Models; afstand_eerste_laatste_tussenvak: 434 mm; ber_aantal_haken: 26; ber_aantal_haken_rij1: 13; ber_aantal_haken_rij2: 14; ber_afstand_eerste_haak: 100.5 mm; ber_lengte_haken_rij1: 1800 mm; ber_lengte_haken_rij2: 1950 mm; Family Name: 80_FUS_UN_garderobe
Material: <Unnamed>, ISR_Hout
Constraints - Elevation from Level: 0 mm; Offset from Host: 0 mm
Phasing - Phase Created: 2. nieuwbouw
Dimensions - Area: 6.56335 m2; Volume: 0.169559 m3
Identity Data - Workset: Workset1; Comments: GK 1A
Other - Family: 80_FUS_UN_garderobe; Family and Type: 80_FUS_UN_garderobe: GK 1A 2231x350x1050; Type: GK 1A 2231x350x1050; Type Id: 2808452
Name (80_FUS_UN_garderobe:GK 1A 2231x350x1050:...) | In | Level = Schedule Level | Work Plane
1784800 | 00 begane grond | 00 begane grond | Level : 00 begane grond
2882982 | 02 tweede verdieping | 02 tweede verdieping | Floor : NLRS_43_FL_cementdekvloer 50_gen_ISR

# IfcBuildingElementProxy: 80_FUS_UN_garderobe:GK 1B 3070x350x1050, 80_FUS_UN_garderobe:GK 1B 3070x350x1050:2812023
In: 00 begane grond
Type - Material: ISR_Hout
Type - Constraints - Default Elevation: 1219.2 mm; aantal_haken: 38
Type - Materials and Finishes - materiaal_kader: ISR_Hout; materiaal_kastframe: ISR_Hout
Type - Construction - 2 tussenpanelen: no; tussenpaneel: yes
Type - Dimensions - diepte: 350 mm; diepte_kastplanken: 310 mm; kasthoogte: 1050 mm; lengte: 3070 mm; plaatmateriaal_dikte: 40 mm; rij-afstand haken: 75 mm
Type - Identity Data - Workset: Family : Generic Models : 80_FUS_UN_garderobe; Type Comments: GK 1B; Type Name: GK 1B 3070x350x1050
Type - Other - Category: Generic Models; afstand_eerste_laatste_tussenvak: 434 mm; ber_aantal_haken: 37; ber_aantal_haken_rij1: 19; ber_aantal_haken_rij2: 19; ber_afstand_eerste_haak: 107.5 mm; ber_lengte_haken_rij1: 2700 mm; ber_lengte_haken_rij2: 2700 mm; Family Name: 80_FUS_UN_garderobe
Material: <Unnamed>, ISR_Hout
Constraints - Elevation from Level: 0 mm; Level: 00 begane grond; Offset from Host: 0 mm; Schedule Level: 00 begane grond; Work Plane: Level : 00 begane grond
Phasing - Phase Created: 2. nieuwbouw
Dimensions - Area: 8.30152 m2; Volume: 0.234678 m3
Identity Data - Workset: Workset1; Comments: GK 1B
Other - Family: 80_FUS_UN_garderobe; Family and Type: 80_FUS_UN_garderobe: GK 1B 3070x350x1050; Type: GK 1B 3070x350x1050; Type Id: 2812189

# IfcBuildingElementProxy: 80_FUS_UN_garderobe:GK 2 4750x350x1050 (2)
In: 00 begane grond
Type - Material: ISR_Hout
Type - Constraints - Default Elevation: 1219.2 mm; aantal_haken: 61
Type - Materials and Finishes - materiaal_kader: ISR_Hout; materiaal_kastframe: ISR_Hout
Type - Construction - tussenpaneel: no; 2 tussenpanelen: yes
Type - Dimensions - diepte: 350 mm; diepte_kastplanken: 310 mm; kasthoogte: 1050 mm; lengte: 4750 mm; plaatmateriaal_dikte: 40 mm; rij-afstand haken: 75 mm
Type - Identity Data - Workset: Family : Generic Models : 80_FUS_UN_garderobe; Type Comments: GK 2; Type Name: GK 2 4750x350x1050
Type - Other - Category: Generic Models; afstand_eerste_laatste_tussenvak: 434 mm; ber_aantal_haken: 60; ber_aantal_haken_rij1: 30; ber_aantal_haken_rij2: 31; ber_afstand_eerste_haak: 85 mm; ber_lengte_haken_rij1: 4350 mm; ber_lengte_haken_rij2: 4500 mm; Family Name: 80_FUS_UN_garderobe
Material: <Unnamed>, ISR_Hout
Constraints - Elevation from Level: 0 mm; Level: 00 begane grond; Offset from Host: 0 mm; Schedule Level: 00 begane grond; Work Plane: Level : 00 begane grond
Phasing - Phase Created: 2. nieuwbouw
Dimensions - Area: 11.7843 m2; Volume: 0.353543 m3
Identity Data - Workset: Workset1; Comments: GK 2
Other - Family: 80_FUS_UN_garderobe; Family and Type: 80_FUS_UN_garderobe: GK 2 4750x350x1050; Type: GK 2 4750x350x1050; Type Id: 2812893
Name (80_FUS_UN_garderobe:GK 2 4750x350x1050:...)
2812851
2813166

# IfcBuildingElementProxy: 80_FUS_UN_garderobe:GK 3 2110x600x1045, 80_FUS_UN_garderobe:GK 3 2110x600x1045:2812398
In: 00 begane grond
Type - Material: ISR_Hout
Type - Constraints - Default Elevation: 1219.2 mm; aantal_haken: 11
Type - Materials and Finishes - materiaal_kader: ISR_Hout; materiaal_kastframe: ISR_Hout
Type - Construction - 2 tussenpanelen: no; tussenpaneel: no
Type - Dimensions - diepte: 650 mm; diepte_kastplanken: 610 mm; kasthoogte: 1050 mm; lengte: 1045 mm; plaatmateriaal_dikte: 40 mm; rij-afstand haken: 100 mm
Type - Identity Data - Workset: Family : Generic Models : 80_FUS_UN_garderobe; Type Comments: GK 3; Type Name: GK 3 2110x600x1045
Type - Other - Category: Generic Models; afstand_eerste_laatste_tussenvak: 434 mm; ber_aantal_haken: 10; ber_aantal_haken_rij1: 5; ber_aantal_haken_rij2: 6; ber_afstand_eerste_haak: 107.5 mm; ber_lengte_haken_rij1: 600 mm; ber_lengte_haken_rij2: 750 mm; Family Name: 80_FUS_UN_garderobe
Material: <Unnamed>, ISR_Hout
Constraints - Elevation from Level: 0 mm; Level: 00 begane grond; Offset from Host: 0 mm; Schedule Level: 00 begane grond; Work Plane: Level : 00 begane grond
Phasing - Phase Created: 2. nieuwbouw
Dimensions - Area: 6.24961 m2; Volume: 0.135761 m3
Identity Data - Workset: Workset1; Comments: GK 3
Other - Family: 80_FUS_UN_garderobe; Family and Type: 80_FUS_UN_garderobe: GK 3 2110x600x1045; Type: GK 3 2110x600x1045; Type Id: 2812446

# IfcBuildingElementProxy: 80_FUS_UN_garderobe:GK 4A 3300x600x1050 (2)
Type - Material: ISR_Hout
Type - Constraints - Default Elevation: 1219.2 mm; aantal_haken: 41
Type - Materials and Finishes - materiaal_kader: ISR_Hout; materiaal_kastframe: ISR_Hout
Type - Construction - 2 tussenpanelen: no; tussenpaneel: yes
Type - Dimensions - diepte: 600 mm; diepte_kastplanken: 560 mm; kasthoogte: 1050 mm; lengte: 3300 mm; plaatmateriaal_dikte: 40 mm; rij-afstand haken: 100 mm
Type - Identity Data - Workset: Family : Generic Models : 80_FUS_UN_garderobe; Type Comments: GK 4A; Type Name: GK 4A 3300x600x1050
Type - Other - Category: Generic Models; afstand_eerste_laatste_tussenvak: 434 mm; ber_aantal_haken: 40; ber_aantal_haken_rij1: 20; ber_aantal_haken_rij2: 21; ber_afstand_eerste_haak: 110 mm; ber_lengte_haken_rij1: 2850 mm; ber_lengte_haken_rij2: 3000 mm; Family Name: 80_FUS_UN_garderobe
Material: <Unnamed>, ISR_Hout
Constraints - Elevation from Level: 0 mm; Offset from Host: 0 mm
Phasing - Phase Created: 2. nieuwbouw
Dimensions - Area: 11.6925 m2; Volume: 0.326985 m3
Identity Data - Workset: Workset1; Comments: GK 4A
Other - Family: 80_FUS_UN_garderobe; Family and Type: 80_FUS_UN_garderobe: GK 4A 3300x600x1050; Type: GK 4A 3300x600x1050; Type Id: 2830210
Name (80_FUS_UN_garderobe:GK 4A 3300x600x1050:...) | In | Work Plane
2854499 | 01 eerste verdieping | Floor : NLRS_43_FL_cementdekvloer 50_gen_ISR
2882969 | 02 tweede verdieping | Level : 02 tweede verdieping | Constraints - Level: 02 tweede verdieping; Schedule Level: 02 tweede verdieping

# IfcBuildingElementProxy: 80_FUS_UN_garderobe:GK 4B 1730x600x1050 (2)
Type - Material: ISR_Hout
Type - Constraints - Default Elevation: 1219.2 mm; aantal_haken: 21
Type - Materials and Finishes - materiaal_kader: ISR_Hout; materiaal_kastframe: ISR_Hout
Type - Construction - 2 tussenpanelen: no; tussenpaneel: no
Type - Dimensions - diepte: 600 mm; diepte_kastplanken: 560 mm; kasthoogte: 1050 mm; lengte: 1730 mm; plaatmateriaal_dikte: 40 mm; rij-afstand haken: 100 mm
Type - Identity Data - Workset: Family : Generic Models : 80_FUS_UN_garderobe; Type Comments: GK 4B; Type Name: GK 4B 1730x600x1050
Type - Other - Category: Generic Models; afstand_eerste_laatste_tussenvak: 434 mm; ber_aantal_haken: 20; ber_aantal_haken_rij1: 10; ber_aantal_haken_rij2: 11; ber_afstand_eerste_haak: 75 mm; ber_lengte_haken_rij1: 1350 mm; ber_lengte_haken_rij2: 1500 mm; Family Name: 80_FUS_UN_garderobe
Material: <Unnamed>, ISR_Hout
Constraints - Elevation from Level: 0 mm; Offset from Host: 0 mm
Phasing - Phase Created: 2. nieuwbouw
Dimensions - Area: 7.6563 m2; Volume: 0.182473 m3
Identity Data - Workset: Workset1; Comments: GK 4B
Other - Family: 80_FUS_UN_garderobe; Family and Type: 80_FUS_UN_garderobe: GK 4B 1730x600x1050; Type: GK 4B 1730x600x1050; Type Id: 2830577
Name (80_FUS_UN_garderobe:GK 4B 1730x600x1050:...) | In | Work Plane
2854500 | 01 eerste verdieping | Floor : NLRS_43_FL_cementdekvloer 50_gen_ISR
2882970 | 02 tweede verdieping | Level : 02 tweede verdieping | Constraints - Level: 02 tweede verdieping; Schedule Level: 02 tweede verdieping

# IfcBuildingElementProxy: 80_FUS_UN_garderobe:GK 5 2360x350x1050, 80_FUS_UN_garderobe:GK 5 2360x350x1050:3053404
In: 01 eerste verdieping
Type - Material: ISR_Hout
Type - Constraints - Default Elevation: 1219.2 mm; aantal_haken: 60
Type - Materials and Finishes - materiaal_kader: ISR_Hout; materiaal_kastframe: ISR_Hout
Type - Construction - tussenpaneel: no; 2 tussenpanelen: yes
Type - Dimensions - diepte: 350 mm; diepte_kastplanken: 310 mm; kasthoogte: 1050 mm; lengte: 4720 mm; plaatmateriaal_dikte: 40 mm; rij-afstand haken: 75 mm
Type - Identity Data - Workset: Family : Generic Models : 80_FUS_UN_garderobe; Type Comments: GK 5; Type Name: GK 5 2360x350x1050
Type - Other - Category: Generic Models; afstand_eerste_laatste_tussenvak: 434 mm; ber_aantal_haken: 59; ber_aantal_haken_rij1: 30; ber_aantal_haken_rij2: 30; ber_afstand_eerste_haak: 107.5 mm; ber_lengte_haken_rij1: 4350 mm; ber_lengte_haken_rij2: 4350 mm; Family Name: 80_FUS_UN_garderobe
Material: <Unnamed>, ISR_Hout
Constraints - Elevation from Level: 0 mm; Offset from Host: 0 mm; Work Plane: Floor : NLRS_43_FL_cementdekvloer 50_gen_ISR
Phasing - Phase Created: 2. nieuwbouw
Dimensions - Area: 11.7207 m2; Volume: 0.351622 m3
Identity Data - Workset: Workset1; Comments: GK 5
Other - Family: 80_FUS_UN_garderobe; Family and Type: 80_FUS_UN_garderobe: GK 5 2360x350x1050; Type: GK 5 2360x350x1050; Type Id: 2813336

# IfcBuildingElementProxy: 80_FUS_UN_garderobe:GK 6 2865x300x1050, 80_FUS_UN_garderobe:GK 6 2865x300x1050:2829682
In: 01 eerste verdieping
Type - Material: ISR_Hout
Type - Constraints - Default Elevation: 1219.2 mm; aantal_haken: 36
Type - Materials and Finishes - materiaal_kader: ISR_Hout; materiaal_kastframe: ISR_Hout
Type - Construction - 2 tussenpanelen: no; tussenpaneel: no
Type - Dimensions - diepte: 300 mm; diepte_kastplanken: 260 mm; kasthoogte: 1050 mm; lengte: 2865 mm; plaatmateriaal_dikte: 40 mm; rij-afstand haken: 50 mm
Type - Identity Data - Workset: Family : Generic Models : 80_FUS_UN_garderobe; Type Comments: GK 6; Type Name: GK 6 2865x300x1050
Type - Other - Category: Generic Models; afstand_eerste_laatste_tussenvak: 434 mm; ber_aantal_haken: 35; ber_aantal_haken_rij1: 18; ber_aantal_haken_rij2: 18; ber_afstand_eerste_haak: 80 mm; ber_lengte_haken_rij1: 2550 mm; ber_lengte_haken_rij2: 2550 mm; Family Name: 80_FUS_UN_garderobe
Material: <Unnamed>, ISR_Hout
Constraints - Elevation from Level: 0 mm; Offset from Host: 0 mm; Level: 01 eerste verdieping; Schedule Level: 01 eerste verdieping; Work Plane: Floor : NLRS_43_FL_cementdekvloer 50_gen_ISR
Phasing - Phase Created: 2. nieuwbouw
Dimensions - Area: 7.33908 m2; Volume: 0.197799 m3
Identity Data - Workset: Workset1; Comments: GK 6
Other - Family: 80_FUS_UN_garderobe; Family and Type: 80_FUS_UN_garderobe: GK 6 2865x300x1050; Type: GK 6 2865x300x1050; Type Id: 2829761

# IfcBuildingElementProxy: 80_FUS_UN_garderobe:GK 7 2475x350x1050 (2)
In: 02 tweede verdieping
Type - Material: ISR_Hout
Type - Constraints - Default Elevation: 1219.2 mm; aantal_haken: 30
Type - Materials and Finishes - materiaal_kader: ISR_Hout; materiaal_kastframe: ISR_Hout
Type - Construction - 2 tussenpanelen: no; tussenpaneel: no
Type - Dimensions - diepte: 350 mm; diepte_kastplanken: 310 mm; kasthoogte: 1050 mm; lengte: 2475 mm; plaatmateriaal_dikte: 40 mm; rij-afstand haken: 75 mm
Type - Identity Data - Workset: Family : Generic Models : 80_FUS_UN_garderobe; Type Comments: GK 7; Type Name: GK 7 2475x350x1050
Type - Other - Category: Generic Models; afstand_eerste_laatste_tussenvak: 434 mm; ber_aantal_haken: 29; ber_aantal_haken_rij1: 15; ber_aantal_haken_rij2: 15; ber_afstand_eerste_haak: 110 mm; ber_lengte_haken_rij1: 2100 mm; ber_lengte_haken_rij2: 2100 mm; Family Name: 80_FUS_UN_garderobe
Material: <Unnamed>, ISR_Hout
Constraints - Elevation from Level: 0 mm; Offset from Host: 0 mm; Level: 02 tweede verdieping; Schedule Level: 02 tweede verdieping; Work Plane: Floor : NLRS_43_FL_cementdekvloer 50_gen_ISR
Phasing - Phase Created: 2. nieuwbouw
Dimensions - Area: 7.06837 m2; Volume: 0.185149 m3
Identity Data - Workset: Workset1; Comments: GK 7
Other - Family: 80_FUS_UN_garderobe; Family and Type: 80_FUS_UN_garderobe: GK 7 2475x350x1050; Type: GK 7 2475x350x1050; Type Id: 3536025
Name (80_FUS_UN_garderobe:GK 7 2475x350x1050:...)
3535947
3536435

# IfcBuildingElementProxy: Aesy_Lift_A5000_standaard:liftschacht 1362 x 1520_glas_2_3_4_5, Aesy_Lift_A5000_standaard:liftschacht 1362 x 1520_glas_2_3_4_5:1723846
In: 00 begane grond
Type - Material: cibes_RAL_9016, cibes_glass, cibes_glass_black, cibes_plastic_red, cibes_plastic_yellow, Green, Black, Cibes_Chrome, cibes_floor_rubber, <Unnamed>
Type - Constraints(Type) - Default Elevation: 0 mm; hoogte_glaspaneel_boven_deur: 1950 mm; hoogte_paspaneel_glaswand: 526 mm; hoogte_plint_glaswand_tov_peil: 0 mm; hoogte_plintpaneel_tov_peil: 600 mm; hoogte_standaard_paneel: 910 mm; liftput_diepte: 50 mm; liftschacht_breedte: 1362 mm; liftschacht_lengte: 1520 mm; opvoerhoogte: 7800 mm; schachtkop: 2500 mm
Type - Materials and Finishes(Type) - materiaal: cibes_RAL_9016; materiaal_alarmknop: cibes_plastic_yellow; materiaal_alu_kaders: cibes_RAL_9016; materiaal_beugel_platform: Cibes_Chrome; materiaal_glas: cibes_glass; materiaal_level0_knop: Green; materiaal_levels_knop: Black; materiaal_liftdeur: cibes_RAL_9016; materiaal_noodknop: cibes_plastic_red; materiaal_vloerafwerking: cibes_floor_rubber; materiaal_zwart_glas: cibes_glass_black; materiaal spiegel: cibes_glass
Type - Construction(Type) - dak_exterieur: no; dak_interieur: yes; schacht: yes; wandtype_zijde_2: Aesy_glaswand : schachtwand_zijde_2; wandtype_zijde_3: Aesy_glaswand : schachtwand_zijde_3; wandtype_zijde_4: Aesy_glaswand : schachtwand_zijde_4; wandtype_zijde_5: Aesy_glaswand : schachtwand_zijde_5
Type - Dimensions(Type) - afstand_liftschacht_platform: 277.5 mm; afstand_liftschacht_wand4: 267.5 mm; afstand_liftschacht-aandrijving: 140 mm; hoekprofiel_onderkant: -50 mm; hoogte_paneel_boven_deur: 5581.5 mm; hoogte_paneel_boven_deur_bsp: 291.5 mm; lengte_schachtpaneel_zijde_2: 1480 mm; lengte_schachtpaneel_zijde_3: 1335 mm; lengte_schachtpaneel_zijde_4: 1430 mm; lengte_schachtpaneel_zijde_5: 1493 mm; liftput_breedte: 1380 mm; liftput_lengte: 1550 mm; ok_paneel_boven_deur: 2208.5 mm; paneel_boven_deur_afst_tussendorpel1: 522 mm; paneel_boven_deur_afst_tussendorpel2: 910 mm; platform_breedte: 1060 mm; platform_diepte: 1473 mm; staander_bovenkant: 10050 mm; staander_onderkant: -50 mm; staanders_buitenzijde: 1490 mm; totaalhoogte_liftschacht: 10300 mm
Type - Identity Data(Type) - Type Name: liftschacht 1362 x 1520_glas_2_3_4_5; Workset: Family : Mechanical Equipment : Aesy_Lift_A5000_standaard
Type - Other(Type) - Category: Mechanical Equipment; deurtype: Aesy_Aluminium_Deurelement : liftdeur2000_1362_osp; deurtype osp: Aesy_Aluminium_Deurelement : liftdeur2000_1362_osp; Family Name: Aesy_Lift_A5000_standaard; glaspaneel_10: no; glaspaneel_7: yes; glaspaneel_8: yes; glaspaneel_9: no; paneel_boven_deur: Aesy_vulpaneel_boven_deur : glaspaneel_boven_deur; paneel_boven_deur_bsp: Aesy_vulpaneel_boven_deur_bovenstestopplaats : glaspaneel; paneel_boven_deur_tussendorpel1: yes; paneel_boven_deur_tussendorpel2: yes; paspaneel: no
Constraints - Level: 00 begane grond; Moves With Nearby Elements: no; bk platformvloer: 0 mm
Phasing - Phase Created: 2. nieuwbouw
Dimensions - Area: 112.755 m2; Volume: 1.1223 m3
Identity Data - Workset: Workset1; Mark: 3
Other - Category: Mechanical Equipment; Family: Aesy_Lift_A5000_standaard; Family and Type: Aesy_Lift_A5000_standaard: liftschacht 1362 x 1520_glas_2_3_4_5; Host Id: 1295401; Type: liftschacht 1362 x 1520_glas_2_3_4_5; Type Id: 3081228

# IfcBuildingElementProxy: GM_BDG_Plantbak bouwkundig:GM_BDG_Plantbak bouwkundig (7)
In: 01 eerste verdieping
Type - Material: h2_staal_gen, p1_grond
Type - Constraints - Default Elevation: 0 mm
Type - Materials and Finishes - afwerking: h2_staal_gen; vulling: p1_grond
Type - Identity Data - Type Name: GM_BDG_Plantbak bouwkundig; Workset: Family : Generic Models : GM_BDG_Plantbak bouwkundig
Type - Other - Category: Generic Models; Family Name: GM_BDG_Plantbak bouwkundig
Constraints - Moves With Nearby Elements: no; Level: 01 eerste verdieping; Elevation from Level: 210 mm; Host: Level : 01 eerste verdieping; Offset from Host: 210 mm
Phasing - Phase Created: 2. nieuwbouw
Identity Data - Workset: Workset1
Other - Family: GM_BDG_Plantbak bouwkundig; Family and Type: GM_BDG_Plantbak bouwkundig: GM_BDG_Plantbak bouwkundig; hoek A (neg): no; Type: GM_BDG_Plantbak bouwkundig; Type Id: 2548495
Name (GM_BDG_Plantbak bouwkundig:GM_BDG_Plantbak bouwkundig:...) | Area (m2) | lengte (mm) | Volume (m3) | eindplaat A | eindplaat B | hoek A | hoek B | hoek B (neg)
2548391 | 14.9285 | 4950 | 0.751446 | yes | no | no | yes | no
2548397 | 28.5575 | 9490 | 1.47641 | no | yes | yes | no | no
2548398 | 36.0388 | 11740 | 1.87483 | no | yes | no | no | no
2548399 | 5.71231 | 1880 | 0.261216 | no | yes | yes | no | no
2548400 | 2.3289 | 850 | 0.0969116 | yes | no | no | no | yes
2548401 | 20.2145 | 7050 | 1.04593 | no | no | yes | no | yes
2548403 | 45.1376 | 14770.9 | 2.36071 | yes | yes | no | no | no

# IfcBuildingElementProxy: Geluidscherm frame:Geluidscherm frame, Geluidscherm frame:Geluidscherm frame:3320543
In: 01 eerste verdieping
Type - Material: h2_staal_gen
Type - Structural - Section Shape: 0
Type - Identity Data - Workset: Workset1; Type Name: Geluidscherm frame
Type - Other - Category: Structural Framing; Family Name: Geluidscherm frame
Constraints - Moves With Nearby Elements: no
Phasing - Phase Created: 2. nieuwbouw
Structural - Rebar Cover: 30mm <30 mm>
Dimensions - Volume: 0.0313955 m3
Other - Family: Geluidscherm frame; Family and Type: Geluidscherm frame: Geluidscherm frame; Type: Geluidscherm frame; Type Id: 3320541

# IfcBuildingElementProxy: Model Text:Model Text 1 (3)
Type - Text - Bold: no; Italic: no; Text Font: Agency FB; Text Size: 520 mm
Type - Identity Data - Type Name: Model Text 1; Workset: Model Text Types
Type - Other - Category: Generic Models; Family Name: Model Text
Phasing - Phase Created: 2. nieuwbouw
Graphics - Horizontal Align: Left
Identity Data - Workset: Workset1; Subcategory: Generic Models
Other - Family: Model Text; Family and Type: Model Text: Model Text 1; Type: Model Text 1; Type Id: 1528
Name (Model Text:Model Text 1:...) | In | Work Plane | Text | Depth (mm)
1900973 | 01 eerste verdieping | <not associated> | RUMMERINKHOF | 10
1901047 | 00 begane grond | Basic Wall : 21_WA_metselwerk_middel_100_gen_bdg | SPORT | 50
1901073 | 00 begane grond | Basic Wall : 21_WA_metselwerk_middel_100_gen_bdg | RUMMERINKHOF | 50

# IfcBuildingElementProxy: NLRS_21_GM_insectensteen_bdg:NLRS_21_GM_insectensteen_bdg (18)
In: 01 eerste verdieping
Type - Material: <Unnamed>
Type - Constraints(Type) - Default Elevation: 1219.2 mm
Type - Identity Data(Type) - Type Name: NLRS_21_GM_insectensteen_bdg; Workset: Family : Generic Models : NLRS_21_GM_insectensteen_bdg
Type - Other(Type) - Category: Generic Models; Family Name: NLRS_21_GM_insectensteen_bdg
Constraints - Level: 01 eerste verdieping; Schedule Level: 01 eerste verdieping; Host: Basic Wall : 21_WA_metselwerk_licht_100_gen_bdg
Phasing - Phase Created: 2. nieuwbouw
Dimensions - Area: 0.0585729 m2; Volume: 0.00125254 m3
Identity Data - Workset: Workset1
Other - Category: Generic Models; Family: NLRS_21_GM_insectensteen_bdg; Family and Type: NLRS_21_GM_insectensteen_bdg: NLRS_21_GM_insectensteen_bdg; Type: NLRS_21_GM_insectensteen_bdg; Type Id: 3061136
Name (NLRS_21_GM_insectensteen_bdg:NLRS_21_GM_insectensteen_bdg:...) | Elevation from Level (mm)
3061823 | 1332.5
3061891 | 1332.5
3062467 | 2070.5
3062469 | 2070.5
3062471 | 2070.5
3062498 | 1701
3062500 | 1701
3062502 | 1701
3062596 | 1701
3062598 | 2070.5
3062621 | 1332.5
3062661 | 1701
3062665 | 1701
3062667 | 2070.5
3062669 | 2070.5
3062694 | 1332.5
3062695 | 1332.5
3062696 | 1332.5

# IfcBuildingElementProxy: NLRS_21_GM_muurafdekker penant alu_bdg:NLRS_21_GM_muurafdekker penant alu_bdg (190)
Type - Material: Aluminium afdekker penant
Type - Constraints - Default Elevation: 0 mm
Type - Materials and Finishes - materiaal: Aluminium afdekker penant
Type - Identity Data - Type Name: NLRS_21_GM_muurafdekker penant alu_bdg; Workset: Family : Generic Models : NLRS_21_GM_muurafdekker penant alu_bdg
Type - Other - Category: Generic Models; Family Name: NLRS_21_GM_muurafdekker penant alu_bdg
Constraints - Moves With Nearby Elements: no
Phasing - Phase Created: 2. nieuwbouw
Identity Data - Workset: Workset1
Other - Family: NLRS_21_GM_muurafdekker penant alu_bdg; Family and Type: NLRS_21_GM_muurafdekker penant alu_bdg: NLRS_21_GM_muurafdekker penant alu_bdg; Type: NLRS_21_GM_muurafdekker penant alu_bdg; Type Id: 3960666
Name (NLRS_21_GM_muurafdekker penant alu_bdg:NLRS_21_GM_muurafdekker penant alu_bdg:...) | In | Level | Elevation from Level (mm) = Offset from Host (mm) | Host | Area (m2) | breedte (mm) | Volume (m3) | Group
3961972 | 02 tweede verdieping | 02 tweede verdieping | 4232 | Level : 02 tweede verdieping | 0.0508005 | 110 | 0.0000996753 | Model Group:21_penant v2:864468
3962064 | 02 tweede verdieping | 02 tweede verdieping | 4232 | Level : 02 tweede verdieping | 0.0508005 | 110 | 0.0000996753 | Model Group:21_penant v2:863826
3962068 | 02 tweede verdieping | 02 tweede verdieping | 4232 | Level : 02 tweede verdieping | 0.0508005 | 110 | 0.0000996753 | Model Group:21_penant v2:864499
3962070 | 02 tweede verdieping | 02 tweede verdieping | 4232 | Level : 02 tweede verdieping | 0.0508005 | 110 | 0.0000996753 | Model Group:21_penant v2:870619
3962072 | 02 tweede verdieping | 02 tweede verdieping | 4232 | Level : 02 tweede verdieping | 0.0508005 | 110 | 0.0000996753 | Model Group:21_penant v2:870636
3962074 | 02 tweede verdieping | 02 tweede verdieping | 4232 | Level : 02 tweede verdieping | 0.0508005 | 110 | 0.0000996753 | Model Group:21_penant v2:870660
3962076 | 02 tweede verdieping | 02 tweede verdieping | 4232 | Level : 02 tweede verdieping | 0.0508005 | 110 | 0.0000996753 | Model Group:21_penant v2:870701
3962078 | 02 tweede verdieping | 02 tweede verdieping | 4232 | Level : 02 tweede verdieping | 0.0508005 | 110 | 0.0000996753 | Model Group:21_penant v2:870718
3962080 | 02 tweede verdieping | 02 tweede verdieping | 4232 | Level : 02 tweede verdieping | 0.0508005 | 110 | 0.0000996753 | Model Group:21_penant v2:870742
3962082 | 02 tweede verdieping | 02 tweede verdieping | 4232 | Level : 02 tweede verdieping | 0.0508005 | 110 | 0.0000996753 | Model Group:21_penant v2:870814
3962084 | 02 tweede verdieping | 02 tweede verdieping | 4232 | Level : 02 tweede verdieping | 0.0508005 | 110 | 0.0000996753 | Model Group:21_penant v2:870831
3962086 | 02 tweede verdieping | 02 tweede verdieping | 4232 | Level : 02 tweede verdieping | 0.0508005 | 110 | 0.0000996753 | Model Group:21_penant v2:870855
3962088 | 02 tweede verdieping | 02 tweede verdieping | 4232 | Level : 02 tweede verdieping | 0.0508005 | 110 | 0.0000996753 | Model Group:21_penant v2:870922
3962090 | 02 tweede verdieping | 02 tweede verdieping | 4232 | Level : 02 tweede verdieping | 0.0508005 | 110 | 0.0000996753 | Model Group:21_penant v2:871619
3962092 | 02 tweede verdieping | 02 tweede verdieping | 4232 | Level : 02 tweede verdieping | 0.0508005 | 110 | 0.0000996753 | Model Group:21_penant v2:871652
3962094 | 02 tweede verdieping | 02 tweede verdieping | 4232 | Level : 02 tweede verdieping | 0.0508005 | 110 | 0.0000996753 | Model Group:21_penant v2:871685
3962096 | 02 tweede verdieping | 02 tweede verdieping | 4232 | Level : 02 tweede verdieping | 0.0508005 | 110 | 0.0000996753 | Model Group:21_penant v2:871871
3962098 | 02 tweede verdieping | 02 tweede verdieping | 4232 | Level : 02 tweede verdieping | 0.0508005 | 110 | 0.0000996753 | Model Group:21_penant v2:871903
3962100 | 02 tweede verdieping | 02 tweede verdieping | 4232 | Level : 02 tweede verdieping | 0.0508005 | 110 | 0.0000996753 | Model Group:21_penant v2:871935
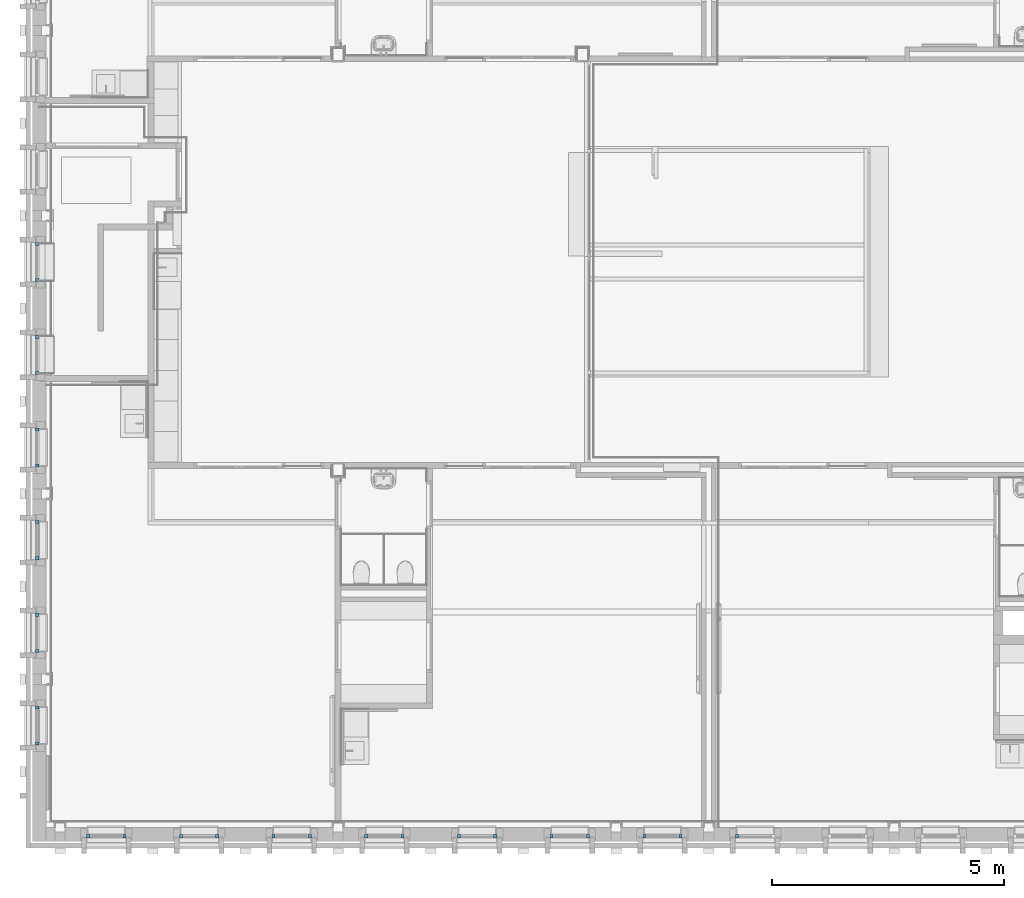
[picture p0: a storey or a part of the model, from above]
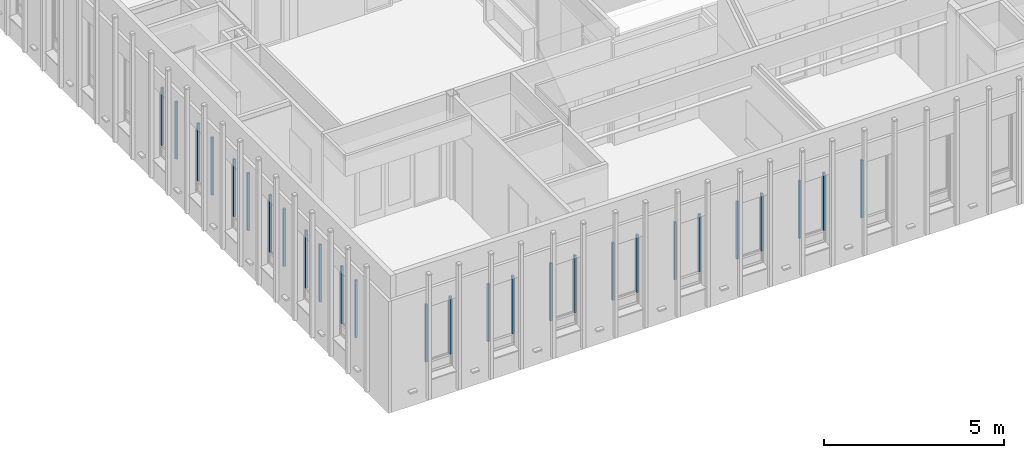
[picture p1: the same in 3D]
Properties of the parts of a building model (IFC2X3), part 2 of 94

# IfcBuildingElementProxy: NLRS_21_GM_muurafdekker penant alu_bdg:NLRS_21_GM_muurafdekker penant alu_bdg (190)
Name (NLRS_21_GM_muurafdekker penant alu_bdg:NLRS_21_GM_muurafdekker penant alu_bdg:...) | In | Level | Elevation from Level (mm) = Offset from Host (mm) | Host | Area (m2) | breedte (mm) | Volume (m3) | Group
3962102 | 02 tweede verdieping | 02 tweede verdieping | 4232 | Level : 02 tweede verdieping | 0.0508005 | 110 | 0.0000996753 | Model Group:21_penant v2:871967
3962104 | 02 tweede verdieping | 02 tweede verdieping | 4232 | Level : 02 tweede verdieping | 0.0508005 | 110 | 0.0000996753 | Model Group:21_penant v2:872009
3962106 | 02 tweede verdieping | 02 tweede verdieping | 4232 | Level : 02 tweede verdieping | 0.0508005 | 110 | 0.0000996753 | Model Group:21_penant v2:872275
3962108 | 02 tweede verdieping | 02 tweede verdieping | 4232 | Level : 02 tweede verdieping | 0.0508005 | 110 | 0.0000996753 | Model Group:21_penant v2:872809
3962110 | 02 tweede verdieping | 02 tweede verdieping | 4232 | Level : 02 tweede verdieping | 0.0508005 | 110 | 0.0000996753 | Model Group:21_penant v2:872842
3962112 | 02 tweede verdieping | 02 tweede verdieping | 4232 | Level : 02 tweede verdieping | 0.0508005 | 110 | 0.0000996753 | Model Group:21_penant v2:872875
3962114 | 02 tweede verdieping | 02 tweede verdieping | 4232 | Level : 02 tweede verdieping | 0.0508005 | 110 | 0.0000996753 | Model Group:21_penant v2:872908
3962116 | 02 tweede verdieping | 02 tweede verdieping | 4232 | Level : 02 tweede verdieping | 0.0508005 | 110 | 0.0000996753 | Model Group:21_penant v2:872941
3962118 | 02 tweede verdieping | 02 tweede verdieping | 4232 | Level : 02 tweede verdieping | 0.0508005 | 110 | 0.0000996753 | Model Group:21_penant v2:872974
3962120 | 02 tweede verdieping | 02 tweede verdieping | 4232 | Level : 02 tweede verdieping | 0.0508005 | 110 | 0.0000996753 | Model Group:21_penant v2:873007
3962122 | 02 tweede verdieping | 02 tweede verdieping | 4232 | Level : 02 tweede verdieping | 0.0508005 | 110 | 0.0000996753 | Model Group:21_penant v2:873040
3962124 | 02 tweede verdieping | 02 tweede verdieping | 4232 | Level : 02 tweede verdieping | 0.0508005 | 110 | 0.0000996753 | Model Group:21_penant v2:873073
3962126 | 02 tweede verdieping | 02 tweede verdieping | 4232 | Level : 02 tweede verdieping | 0.0508005 | 110 | 0.0000996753 | Model Group:21_penant v2:873106
3962128 | 02 tweede verdieping | 02 tweede verdieping | 4232 | Level : 02 tweede verdieping | 0.0508005 | 110 | 0.0000996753 | Model Group:21_penant v2:873392
3962130 | 02 tweede verdieping | 02 tweede verdieping | 4232 | Level : 02 tweede verdieping | 0.0508005 | 110 | 0.0000996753 | Model Group:21_penant v2:873442
3962132 | 02 tweede verdieping | 02 tweede verdieping | 4232 | Level : 02 tweede verdieping | 0.0508005 | 110 | 0.0000996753 | Model Group:21_penant v2:873473
3962134 | 02 tweede verdieping | 02 tweede verdieping | 4232 | Level : 02 tweede verdieping | 0.0508005 | 110 | 0.0000996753 | Model Group:21_penant v2:873504
3962136 | 02 tweede verdieping | 02 tweede verdieping | 4232 | Level : 02 tweede verdieping | 0.0508005 | 110 | 0.0000996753 | Model Group:21_penant v2:873535
3962138 | 02 tweede verdieping | 02 tweede verdieping | 4232 | Level : 02 tweede verdieping | 0.0508005 | 110 | 0.0000996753 | Model Group:21_penant v2:873566
3962140 | 02 tweede verdieping | 02 tweede verdieping | 4232 | Level : 02 tweede verdieping | 0.0508005 | 110 | 0.0000996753 | Model Group:21_penant v2:873597
3962142 | 02 tweede verdieping | 02 tweede verdieping | 4232 | Level : 02 tweede verdieping | 0.0508005 | 110 | 0.0000996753 | Model Group:21_penant v2:873628
3962144 | 02 tweede verdieping | 02 tweede verdieping | 4232 | Level : 02 tweede verdieping | 0.0508005 | 110 | 0.0000996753 | Model Group:21_penant v2:873659
3962146 | 02 tweede verdieping | 02 tweede verdieping | 4232 | Level : 02 tweede verdieping | 0.0508005 | 110 | 0.0000996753 | Model Group:21_penant v2:873690
3962148 | 02 tweede verdieping | 02 tweede verdieping | 4232 | Level : 02 tweede verdieping | 0.0508005 | 110 | 0.0000996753 | Model Group:21_penant v2:873721
3963197 | 02 tweede verdieping | 02 tweede verdieping | 4232 | Level : 02 tweede verdieping | 0.0508005 | 110 | 0.0000996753 | Model Group:21_penant v2:864468
3963294 | 02 tweede verdieping | 02 tweede verdieping | 4232 | Level : 02 tweede verdieping | 0.0508005 | 110 | 0.0000996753 | Model Group:21_penant v2:863826
3963298 | 02 tweede verdieping | 02 tweede verdieping | 4232 | Level : 02 tweede verdieping | 0.0508005 | 110 | 0.0000996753 | Model Group:21_penant v2:864499
3963300 | 02 tweede verdieping | 02 tweede verdieping | 4232 | Level : 02 tweede verdieping | 0.0508005 | 110 | 0.0000996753 | Model Group:21_penant v2:870619
3963302 | 02 tweede verdieping | 02 tweede verdieping | 4232 | Level : 02 tweede verdieping | 0.0508005 | 110 | 0.0000996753 | Model Group:21_penant v2:870636
3963304 | 02 tweede verdieping | 02 tweede verdieping | 4232 | Level : 02 tweede verdieping | 0.0508005 | 110 | 0.0000996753 | Model Group:21_penant v2:870660
3963306 | 02 tweede verdieping | 02 tweede verdieping | 4232 | Level : 02 tweede verdieping | 0.0508005 | 110 | 0.0000996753 | Model Group:21_penant v2:870701
3963308 | 02 tweede verdieping | 02 tweede verdieping | 4232 | Level : 02 tweede verdieping | 0.0508005 | 110 | 0.0000996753 | Model Group:21_penant v2:870718
3963310 | 02 tweede verdieping | 02 tweede verdieping | 4232 | Level : 02 tweede verdieping | 0.0508005 | 110 | 0.0000996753 | Model Group:21_penant v2:870742
3963312 | 02 tweede verdieping | 02 tweede verdieping | 4232 | Level : 02 tweede verdieping | 0.0508005 | 110 | 0.0000996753 | Model Group:21_penant v2:870814
3963314 | 02 tweede verdieping | 02 tweede verdieping | 4232 | Level : 02 tweede verdieping | 0.0508005 | 110 | 0.0000996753 | Model Group:21_penant v2:870831
3963316 | 02 tweede verdieping | 02 tweede verdieping | 4232 | Level : 02 tweede verdieping | 0.0508005 | 110 | 0.0000996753 | Model Group:21_penant v2:870855
3963318 | 02 tweede verdieping | 02 tweede verdieping | 4232 | Level : 02 tweede verdieping | 0.0508005 | 110 | 0.0000996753 | Model Group:21_penant v2:870922
3963320 | 02 tweede verdieping | 02 tweede verdieping | 4232 | Level : 02 tweede verdieping | 0.0508005 | 110 | 0.0000996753 | Model Group:21_penant v2:871619
3963322 | 02 tweede verdieping | 02 tweede verdieping | 4232 | Level : 02 tweede verdieping | 0.0508005 | 110 | 0.0000996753 | Model Group:21_penant v2:871652
3963324 | 02 tweede verdieping | 02 tweede verdieping | 4232 | Level : 02 tweede verdieping | 0.0508005 | 110 | 0.0000996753 | Model Group:21_penant v2:871685
3963326 | 02 tweede verdieping | 02 tweede verdieping | 4232 | Level : 02 tweede verdieping | 0.0508005 | 110 | 0.0000996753 | Model Group:21_penant v2:871871
3963328 | 02 tweede verdieping | 02 tweede verdieping | 4232 | Level : 02 tweede verdieping | 0.0508005 | 110 | 0.0000996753 | Model Group:21_penant v2:871903
3963330 | 02 tweede verdieping | 02 tweede verdieping | 4232 | Level : 02 tweede verdieping | 0.0508005 | 110 | 0.0000996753 | Model Group:21_penant v2:871935
3963332 | 02 tweede verdieping | 02 tweede verdieping | 4232 | Level : 02 tweede verdieping | 0.0508005 | 110 | 0.0000996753 | Model Group:21_penant v2:871967
3963334 | 02 tweede verdieping | 02 tweede verdieping | 4232 | Level : 02 tweede verdieping | 0.0508005 | 110 | 0.0000996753 | Model Group:21_penant v2:872009
3963336 | 02 tweede verdieping | 02 tweede verdieping | 4232 | Level : 02 tweede verdieping | 0.0508005 | 110 | 0.0000996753 | Model Group:21_penant v2:872275
3963338 | 02 tweede verdieping | 02 tweede verdieping | 4232 | Level : 02 tweede verdieping | 0.0508005 | 110 | 0.0000996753 | Model Group:21_penant v2:872809
3963340 | 02 tweede verdieping | 02 tweede verdieping | 4232 | Level : 02 tweede verdieping | 0.0508005 | 110 | 0.0000996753 | Model Group:21_penant v2:872842
3963342 | 02 tweede verdieping | 02 tweede verdieping | 4232 | Level : 02 tweede verdieping | 0.0508005 | 110 | 0.0000996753 | Model Group:21_penant v2:872875
3963344 | 02 tweede verdieping | 02 tweede verdieping | 4232 | Level : 02 tweede verdieping | 0.0508005 | 110 | 0.0000996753 | Model Group:21_penant v2:872908
3963346 | 02 tweede verdieping | 02 tweede verdieping | 4232 | Level : 02 tweede verdieping | 0.0508005 | 110 | 0.0000996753 | Model Group:21_penant v2:872941
3963348 | 02 tweede verdieping | 02 tweede verdieping | 4232 | Level : 02 tweede verdieping | 0.0508005 | 110 | 0.0000996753 | Model Group:21_penant v2:872974
3963350 | 02 tweede verdieping | 02 tweede verdieping | 4232 | Level : 02 tweede verdieping | 0.0508005 | 110 | 0.0000996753 | Model Group:21_penant v2:873007
3963352 | 02 tweede verdieping | 02 tweede verdieping | 4232 | Level : 02 tweede verdieping | 0.0508005 | 110 | 0.0000996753 | Model Group:21_penant v2:873040
3963354 | 02 tweede verdieping | 02 tweede verdieping | 4232 | Level : 02 tweede verdieping | 0.0508005 | 110 | 0.0000996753 | Model Group:21_penant v2:873073
3963356 | 02 tweede verdieping | 02 tweede verdieping | 4232 | Level : 02 tweede verdieping | 0.0508005 | 110 | 0.0000996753 | Model Group:21_penant v2:873106
3963358 | 02 tweede verdieping | 02 tweede verdieping | 4232 | Level : 02 tweede verdieping | 0.0508005 | 110 | 0.0000996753 | Model Group:21_penant v2:873392
3963360 | 02 tweede verdieping | 02 tweede verdieping | 4232 | Level : 02 tweede verdieping | 0.0508005 | 110 | 0.0000996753 | Model Group:21_penant v2:873442
3963362 | 02 tweede verdieping | 02 tweede verdieping | 4232 | Level : 02 tweede verdieping | 0.0508005 | 110 | 0.0000996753 | Model Group:21_penant v2:873473
3963364 | 02 tweede verdieping | 02 tweede verdieping | 4232 | Level : 02 tweede verdieping | 0.0508005 | 110 | 0.0000996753 | Model Group:21_penant v2:873504
3963366 | 02 tweede verdieping | 02 tweede verdieping | 4232 | Level : 02 tweede verdieping | 0.0508005 | 110 | 0.0000996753 | Model Group:21_penant v2:873535
3963368 | 02 tweede verdieping | 02 tweede verdieping | 4232 | Level : 02 tweede verdieping | 0.0508005 | 110 | 0.0000996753 | Model Group:21_penant v2:873566
3963370 | 02 tweede verdieping | 02 tweede verdieping | 4232 | Level : 02 tweede verdieping | 0.0508005 | 110 | 0.0000996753 | Model Group:21_penant v2:873597
3963372 | 02 tweede verdieping | 02 tweede verdieping | 4232 | Level : 02 tweede verdieping | 0.0508005 | 110 | 0.0000996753 | Model Group:21_penant v2:873628
3963374 | 02 tweede verdieping | 02 tweede verdieping | 4232 | Level : 02 tweede verdieping | 0.0508005 | 110 | 0.0000996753 | Model Group:21_penant v2:873659
3963376 | 02 tweede verdieping | 02 tweede verdieping | 4232 | Level : 02 tweede verdieping | 0.0508005 | 110 | 0.0000996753 | Model Group:21_penant v2:873690
3963378 | 02 tweede verdieping | 02 tweede verdieping | 4232 | Level : 02 tweede verdieping | 0.0508005 | 110 | 0.0000996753 | Model Group:21_penant v2:873721
3963453 | 02 tweede verdieping | 02 tweede verdieping | 419.042 | Level : 02 tweede verdieping | 0.0928629 | 225 | 0.000183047 | Model Group:21_penant v1:874890
3963590 | 02 tweede verdieping | 02 tweede verdieping | 419.042 | Level : 02 tweede verdieping | 0.0928629 | 225 | 0.000183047 | Model Group:21_penant v1:774399
3963592 | 02 tweede verdieping | 02 tweede verdieping | 419.042 | Level : 02 tweede verdieping | 0.0928629 | 225 | 0.000183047 | Model Group:21_penant v1:774488
3963594 | 02 tweede verdieping | 02 tweede verdieping | 419.042 | Level : 02 tweede verdieping | 0.0928629 | 225 | 0.000183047 | Model Group:21_penant v1:774500
3963598 | 02 tweede verdieping | 02 tweede verdieping | 419.042 | Level : 02 tweede verdieping | 0.0928629 | 225 | 0.000183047 | Model Group:21_penant v1:874894
3963600 | 02 tweede verdieping | 02 tweede verdieping | 419.042 | Level : 02 tweede verdieping | 0.0928629 | 225 | 0.000183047 | Model Group:21_penant v1:874898
3963602 | 02 tweede verdieping | 02 tweede verdieping | 419.042 | Level : 02 tweede verdieping | 0.0928629 | 225 | 0.000183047 | Model Group:21_penant v1:874980
3963604 | 02 tweede verdieping | 02 tweede verdieping | 419.042 | Level : 02 tweede verdieping | 0.0928629 | 225 | 0.000183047 | Model Group:21_penant v1:874984
3963606 | 02 tweede verdieping | 02 tweede verdieping | 419.042 | Level : 02 tweede verdieping | 0.0928629 | 225 | 0.000183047 | Model Group:21_penant v1:874988
3963608 | 02 tweede verdieping | 02 tweede verdieping | 419.042 | Level : 02 tweede verdieping | 0.0928629 | 225 | 0.000183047 | Model Group:21_penant v1:875217
3963610 | 02 tweede verdieping | 02 tweede verdieping | 419.042 | Level : 02 tweede verdieping | 0.0928629 | 225 | 0.000183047 | Model Group:21_penant v1:875253
3963612 | 02 tweede verdieping | 02 tweede verdieping | 419.042 | Level : 02 tweede verdieping | 0.0928629 | 225 | 0.000183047 | Model Group:21_penant v1:875289
3963614 | 02 tweede verdieping | 02 tweede verdieping | 419.042 | Level : 02 tweede verdieping | 0.0928629 | 225 | 0.000183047 | Model Group:21_penant v1:875325
3963616 | 02 tweede verdieping | 02 tweede verdieping | 419.042 | Level : 02 tweede verdieping | 0.0928629 | 225 | 0.000183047 | Model Group:21_penant v1:875361
3963618 | 02 tweede verdieping | 02 tweede verdieping | 419.042 | Level : 02 tweede verdieping | 0.0928629 | 225 | 0.000183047 | Model Group:21_penant v1:876469
3963620 | 02 tweede verdieping | 02 tweede verdieping | 419.042 | Level : 02 tweede verdieping | 0.0928629 | 225 | 0.000183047 | Model Group:21_penant v1:876484
3963622 | 02 tweede verdieping | 02 tweede verdieping | 419.042 | Level : 02 tweede verdieping | 0.0928629 | 225 | 0.000183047 | Model Group:21_penant v1:876499
3963624 | 02 tweede verdieping | 02 tweede verdieping | 419.042 | Level : 02 tweede verdieping | 0.0928629 | 225 | 0.000183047 | Model Group:21_penant v1:876887
3963626 | 02 tweede verdieping | 02 tweede verdieping | 419.042 | Level : 02 tweede verdieping | 0.0928629 | 225 | 0.000183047 | Model Group:21_penant v1:876902
3963628 | 02 tweede verdieping | 02 tweede verdieping | 419.042 | Level : 02 tweede verdieping | 0.0928629 | 225 | 0.000183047 | Model Group:21_penant v1:876917
3963630 | 02 tweede verdieping | 02 tweede verdieping | 419.042 | Level : 02 tweede verdieping | 0.0928629 | 225 | 0.000183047 | Model Group:21_penant v1:877004
3963632 | 02 tweede verdieping | 02 tweede verdieping | 419.042 | Level : 02 tweede verdieping | 0.0928629 | 225 | 0.000183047 | Model Group:21_penant v1:877019
3963634 | 02 tweede verdieping | 02 tweede verdieping | 419.042 | Level : 02 tweede verdieping | 0.0928629 | 225 | 0.000183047 | Model Group:21_penant v1:877034
3963636 | 02 tweede verdieping | 02 tweede verdieping | 419.042 | Level : 02 tweede verdieping | 0.0928629 | 225 | 0.000183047 | Model Group:21_penant v1:877094
3963638 | 02 tweede verdieping | 02 tweede verdieping | 419.042 | Level : 02 tweede verdieping | 0.0928629 | 225 | 0.000183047 | Model Group:21_penant v1:877109
3963640 | 02 tweede verdieping | 02 tweede verdieping | 419.042 | Level : 02 tweede verdieping | 0.0928629 | 225 | 0.000183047 | Model Group:21_penant v1:877124
3963642 | 02 tweede verdieping | 02 tweede verdieping | 419.042 | Level : 02 tweede verdieping | 0.0928629 | 225 | 0.000183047 | Model Group:21_penant v1:877184
3963644 | 02 tweede verdieping | 02 tweede verdieping | 419.042 | Level : 02 tweede verdieping | 0.0928629 | 225 | 0.000183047 | Model Group:21_penant v1:877199
3963646 | 02 tweede verdieping | 02 tweede verdieping | 419.042 | Level : 02 tweede verdieping | 0.0928629 | 225 | 0.000183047 | Model Group:21_penant v1:877214
3963648 | 02 tweede verdieping | 02 tweede verdieping | 419.042 | Level : 02 tweede verdieping | 0.0928629 | 225 | 0.000183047 | Model Group:21_penant v1:880918
3963650 | 02 tweede verdieping | 02 tweede verdieping | 419.042 | Level : 02 tweede verdieping | 0.0928629 | 225 | 0.000183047 | Model Group:21_penant v1:881607
3963652 | 02 tweede verdieping | 02 tweede verdieping | 419.042 | Level : 02 tweede verdieping | 0.0928629 | 225 | 0.000183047 | Model Group:21_penant v1:881643
3963654 | 02 tweede verdieping | 02 tweede verdieping | 419.042 | Level : 02 tweede verdieping | 0.0928629 | 225 | 0.000183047 | Model Group:21_penant v1:881679
3963656 | 02 tweede verdieping | 02 tweede verdieping | 419.042 | Level : 02 tweede verdieping | 0.0928629 | 225 | 0.000183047 | Model Group:21_penant v1:881755
3963658 | 02 tweede verdieping | 02 tweede verdieping | 419.042 | Level : 02 tweede verdieping | 0.0928629 | 225 | 0.000183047 | Model Group:21_penant v1:881782
3963660 | 02 tweede verdieping | 02 tweede verdieping | 419.042 | Level : 02 tweede verdieping | 0.0928629 | 225 | 0.000183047 | Model Group:21_penant v1:881809
3963662 | 02 tweede verdieping | 02 tweede verdieping | 419.042 | Level : 02 tweede verdieping | 0.0928629 | 225 | 0.000183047 | Model Group:21_penant v1:891629
3963664 | 02 tweede verdieping | 02 tweede verdieping | 419.042 | Level : 02 tweede verdieping | 0.0928629 | 225 | 0.000183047 | Model Group:21_penant v1:891651
3963666 | 02 tweede verdieping | 02 tweede verdieping | 419.042 | Level : 02 tweede verdieping | 0.0928629 | 225 | 0.000183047 | Model Group:21_penant v1:891673
3963668 | 02 tweede verdieping | 02 tweede verdieping | 419.042 | Level : 02 tweede verdieping | 0.0928629 | 225 | 0.000183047 | Model Group:21_penant v1:891695
3963670 | 02 tweede verdieping | 02 tweede verdieping | 419.042 | Level : 02 tweede verdieping | 0.0928629 | 225 | 0.000183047 | Model Group:21_penant v1:891717
3963672 | 02 tweede verdieping | 02 tweede verdieping | 419.042 | Level : 02 tweede verdieping | 0.0928629 | 225 | 0.000183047 | Model Group:21_penant v1:891763
3963674 | 02 tweede verdieping | 02 tweede verdieping | 419.042 | Level : 02 tweede verdieping | 0.0928629 | 225 | 0.000183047 | Model Group:21_penant v1:891785
3963676 | 02 tweede verdieping | 02 tweede verdieping | 419.042 | Level : 02 tweede verdieping | 0.0928629 | 225 | 0.000183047 | Model Group:21_penant v1:891807
3963678 | 02 tweede verdieping | 02 tweede verdieping | 419 | Level : 02 tweede verdieping | 0.0910341 | 220 | 0.000179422
3963680 | 02 tweede verdieping | 02 tweede verdieping | 419 | Level : 02 tweede verdieping | 0.0910341 | 220 | 0.000179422
3963682 | 02 tweede verdieping | 02 tweede verdieping | 419.042 | Level : 02 tweede verdieping | 0.0928629 | 225 | 0.000183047 | Model Group:21_penant v1:891902
3963684 | 02 tweede verdieping | 02 tweede verdieping | 419.042 | Level : 02 tweede verdieping | 0.0928629 | 225 | 0.000183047 | Model Group:21_penant v1:891924
3963686 | 02 tweede verdieping | 02 tweede verdieping | 419.042 | Level : 02 tweede verdieping | 0.0928629 | 225 | 0.000183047 | Model Group:21_penant v1:891946
3963688 | 02 tweede verdieping | 02 tweede verdieping | 419.042 | Level : 02 tweede verdieping | 0.0928629 | 225 | 0.000183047 | Model Group:21_penant v1:891974
3963690 | 02 tweede verdieping | 02 tweede verdieping | 419.042 | Level : 02 tweede verdieping | 0.0928629 | 225 | 0.000183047 | Model Group:21_penant v1:891996
3963963 | 02 tweede verdieping | 02 tweede verdieping | 419.019 | Level : 02 tweede verdieping | 0.0910341 | 220 | 0.000179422 | Model Group:21_penant v1 ROND:1302570
3963978 | 02 tweede verdieping | 02 tweede verdieping | 419.019 | Level : 02 tweede verdieping | 0.0910341 | 220 | 0.000179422 | Model Group:21_penant v1 ROND:1341016
3964053 | 01 eerste verdieping | 01 eerste verdieping | 1820.03 | Level : 01 eerste verdieping | 0.0910341 | 220 | 0.000179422
3964054 | 01 eerste verdieping | 01 eerste verdieping | 3173.11 | Level : 01 eerste verdieping | 0.0910341 | 220 | 0.000179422
3964055 | 02 tweede verdieping | 02 tweede verdieping | 419 | Level : 02 tweede verdieping | 0.0910341 | 220 | 0.000179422
3964056 | 02 tweede verdieping | 02 tweede verdieping | 419 | Level : 02 tweede verdieping | 0.0910341 | 220 | 0.000179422
3964086 | 02 tweede verdieping | 02 tweede verdieping | 4232 | Level : 02 tweede verdieping | 0.0508005 | 110 | 0.0000996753 | Model Group:21_penant v2 deur:871839
3964087 | 02 tweede verdieping | 02 tweede verdieping | 4232 | Level : 02 tweede verdieping | 0.0508005 | 110 | 0.0000996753 | Model Group:21_penant v2 deur:871839
3964088 | 02 tweede verdieping | 02 tweede verdieping | 4232 | Level : 02 tweede verdieping | 0.0508005 | 110 | 0.0000996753 | Model Group:21_penant v2 deur:871839
3964103 | 02 tweede verdieping | 02 tweede verdieping | 4232 | Level : 02 tweede verdieping | 0.0508005 | 110 | 0.0000996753 | Model Group:21_penant v2 deur:1483196
3964104 | 02 tweede verdieping | 02 tweede verdieping | 4232 | Level : 02 tweede verdieping | 0.0508005 | 110 | 0.0000996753 | Model Group:21_penant v2 deur:1483196
3964105 | 02 tweede verdieping | 02 tweede verdieping | 4232 | Level : 02 tweede verdieping | 0.0508005 | 110 | 0.0000996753 | Model Group:21_penant v2 deur:1483196
3964145 | 02 tweede verdieping | 02 tweede verdieping | 4232 | Level : 02 tweede verdieping | 0.0508005 | 110 | 0.0000996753
3964209 | 02 tweede verdieping | 02 tweede verdieping | 4232 | Level : 02 tweede verdieping | 0.0508005 | 110 | 0.0000996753
3964253 | 01 eerste verdieping | 01 eerste verdieping | 2989.03 | Level : 01 eerste verdieping | 0.0928629 | 225 | 0.000183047 | Model Group:21_penant_v1 gym:1912830
3964389 | 01 eerste verdieping | 01 eerste verdieping | 2989.03 | Level : 01 eerste verdieping | 0.0928629 | 225 | 0.000183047 | Model Group:21_penant_v1 gym:1911143
3964391 | 01 eerste verdieping | 01 eerste verdieping | 2989.03 | Level : 01 eerste verdieping | 0.0928629 | 225 | 0.000183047 | Model Group:21_penant_v1 gym:1911150
3964393 | 01 eerste verdieping | 01 eerste verdieping | 2989.03 | Level : 01 eerste verdieping | 0.0928629 | 225 | 0.000183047 | Model Group:21_penant_v1 gym:1911157
3964395 | 01 eerste verdieping | 01 eerste verdieping | 2989.03 | Level : 01 eerste verdieping | 0.0928629 | 225 | 0.000183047 | Model Group:21_penant_v1 gym:1911164
3964397 | 01 eerste verdieping | 01 eerste verdieping | 2989.03 | Level : 01 eerste verdieping | 0.0928629 | 225 | 0.000183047 | Model Group:21_penant_v1 gym:1911171
3964399 | 01 eerste verdieping | 01 eerste verdieping | 2989.03 | Level : 01 eerste verdieping | 0.0928629 | 225 | 0.000183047 | Model Group:21_penant_v1 gym:1911178
3964401 | 01 eerste verdieping | 01 eerste verdieping | 2989.03 | Level : 01 eerste verdieping | 0.0928629 | 225 | 0.000183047 | Model Group:21_penant_v1 gym:1911185
3964403 | 01 eerste verdieping | 01 eerste verdieping | 2989.03 | Level : 01 eerste verdieping | 0.0928629 | 225 | 0.000183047 | Model Group:21_penant_v1 gym:1912551
3964405 | 01 eerste verdieping | 01 eerste verdieping | 2989.03 | Level : 01 eerste verdieping | 0.0928629 | 225 | 0.000183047 | Model Group:21_penant_v1 gym:1912590
3964411 | 01 eerste verdieping | 01 eerste verdieping | 2989.03 | Level : 01 eerste verdieping | 0.0928629 | 225 | 0.000183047 | Model Group:21_penant_v1 gym:1912705
3964413 | 01 eerste verdieping | 01 eerste verdieping | 2989.03 | Level : 01 eerste verdieping | 0.0928629 | 225 | 0.000183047 | Model Group:21_penant_v1 gym:1912709
3964415 | 01 eerste verdieping | 01 eerste verdieping | 2989.03 | Level : 01 eerste verdieping | 0.0928629 | 225 | 0.000183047 | Model Group:21_penant_v1 gym:1912715
3964417 | 01 eerste verdieping | 01 eerste verdieping | 2989.03 | Level : 01 eerste verdieping | 0.0928629 | 225 | 0.000183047 | Model Group:21_penant_v1 gym:1912719
3964419 | 01 eerste verdieping | 01 eerste verdieping | 2989.03 | Level : 01 eerste verdieping | 0.0928629 | 225 | 0.000183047 | Model Group:21_penant_v1 gym:1912725
3964421 | 01 eerste verdieping | 01 eerste verdieping | 2989.03 | Level : 01 eerste verdieping | 0.0928629 | 225 | 0.000183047 | Model Group:21_penant_v1 gym:1912729
3964423 | 01 eerste verdieping | 01 eerste verdieping | 2989.03 | Level : 01 eerste verdieping | 0.0928629 | 225 | 0.000183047 | Model Group:21_penant_v1 gym:1912735
3964425 | 01 eerste verdieping | 01 eerste verdieping | 2989.03 | Level : 01 eerste verdieping | 0.0928629 | 225 | 0.000183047 | Model Group:21_penant_v1 gym:1912739
3964427 | 01 eerste verdieping | 01 eerste verdieping | 2989.03 | Level : 01 eerste verdieping | 0.0928629 | 225 | 0.000183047 | Model Group:21_penant_v1 gym:1912745
3964429 | 01 eerste verdieping | 01 eerste verdieping | 2989.03 | Level : 01 eerste verdieping | 0.0928629 | 225 | 0.000183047 | Model Group:21_penant_v1 gym:1912755
3964431 | 01 eerste verdieping | 01 eerste verdieping | 2989.03 | Level : 01 eerste verdieping | 0.0928629 | 225 | 0.000183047 | Model Group:21_penant_v1 gym:1912759
3964433 | 01 eerste verdieping | 01 eerste verdieping | 2989.03 | Level : 01 eerste verdieping | 0.0928629 | 225 | 0.000183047 | Model Group:21_penant_v1 gym:1912765
3964435 | 01 eerste verdieping | 01 eerste verdieping | 2989.03 | Level : 01 eerste verdieping | 0.0928629 | 225 | 0.000183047 | Model Group:21_penant_v1 gym:1912769
3964437 | 01 eerste verdieping | 01 eerste verdieping | 2989.03 | Level : 01 eerste verdieping | 0.0928629 | 225 | 0.000183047 | Model Group:21_penant_v1 gym:1912775
3964439 | 01 eerste verdieping | 01 eerste verdieping | 2989.03 | Level : 01 eerste verdieping | 0.0928629 | 225 | 0.000183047 | Model Group:21_penant_v1 gym:1912779
3964441 | 01 eerste verdieping | 01 eerste verdieping | 2989.03 | Level : 01 eerste verdieping | 0.0928629 | 225 | 0.000183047 | Model Group:21_penant_v1 gym:1912818
3964443 | 01 eerste verdieping | 01 eerste verdieping | 2989.03 | Level : 01 eerste verdieping | 0.0928629 | 225 | 0.000183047 | Model Group:21_penant_v1 gym:1913071
3964445 | 01 eerste verdieping | 01 eerste verdieping | 2989.03 | Level : 01 eerste verdieping | 0.0928629 | 225 | 0.000183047 | Model Group:21_penant_v1 gym:1913224
3964447 | 01 eerste verdieping | 01 eerste verdieping | 2989.03 | Level : 01 eerste verdieping | 0.0928629 | 225 | 0.000183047 | Model Group:21_penant_v1 gym:1913265
3964449 | 01 eerste verdieping | 01 eerste verdieping | 2989.03 | Level : 01 eerste verdieping | 0.0928629 | 225 | 0.000183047 | Model Group:21_penant_v1 gym:1913279
3964451 | 01 eerste verdieping | 01 eerste verdieping | 2989.03 | Level : 01 eerste verdieping | 0.0928629 | 225 | 0.000183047 | Model Group:21_penant_v1 gym:1913889
3964453 | 01 eerste verdieping | 01 eerste verdieping | 2989.03 | Level : 01 eerste verdieping | 0.0928629 | 225 | 0.000183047 | Model Group:21_penant_v1 gym:1913893
3964455 | 01 eerste verdieping | 01 eerste verdieping | 2989.03 | Level : 01 eerste verdieping | 0.0928629 | 225 | 0.000183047 | Model Group:21_penant_v1 gym:1913917
3964457 | 01 eerste verdieping | 01 eerste verdieping | 2989.03 | Level : 01 eerste verdieping | 0.0928629 | 225 | 0.000183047 | Model Group:21_penant_v1 gym:1913931
3964459 | 01 eerste verdieping | 01 eerste verdieping | 2989.03 | Level : 01 eerste verdieping | 0.0928629 | 225 | 0.000183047 | Model Group:21_penant_v1 gym:1913943
3964510 | 01 eerste verdieping | 01 eerste verdieping | 2989 | Level : 01 eerste verdieping | 0.0928629 | 225 | 0.000183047 | Model Group:21_penant_v1 gym laag:1913291
3964595 | 02 tweede verdieping | 02 tweede verdieping | 4232 | Level : 02 tweede verdieping | 0.0508005 | 110 | 0.0000996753
3964677 | 02 tweede verdieping | 02 tweede verdieping | 4232 | Level : 02 tweede verdieping | 0.0508005 | 110 | 0.0000996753
4444515 | 02 tweede verdieping | 02 tweede verdieping | 419.042 | Level : 02 tweede verdieping | 0.0928629 | 225 | 0.000183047 | Model Group:21_penant v1:774467

# IfcBuildingElementProxy: NLRS_21_GM_vleermuiskast_bdg:std (6)
In: 01 eerste verdieping
Type - Material: f2_beton prefab
Type - Constraints(Type) - Default Elevation: 0 mm
Type - Materials and Finishes(Type) - materiaal: f2_beton prefab
Type - Identity Data(Type) - Workset: Family : Generic Models : NLRS_21_GM_vleermuiskast_bdg; Type Name: std
Type - Other(Type) - Category: Generic Models; Family Name: NLRS_21_GM_vleermuiskast_bdg; uitbreiding: no
Constraints - Level: 01 eerste verdieping; Elevation from Level: 1707 mm
Phasing - Phase Created: 2. nieuwbouw
Dimensions - Area: 0.538016 m2; Volume: 0.00724071 m3
Identity Data - Workset: Workset1
Other - Category: Generic Models; Type: std; Family: NLRS_21_GM_vleermuiskast_bdg; Family and Type: NLRS_21_GM_vleermuiskast_bdg: std; Type Id: 3059170
Name (NLRS_21_GM_vleermuiskast_bdg:std:...) | Host Id
3059183 | 1885508
3059184 | 1887903
3059185 | 1885505
3059186 | 1885558
3059187 | 1885574
3060154 | 1885481

# IfcBuildingElementProxy: NLRS_21_GM_vleermuiskast_bdg:uitbreiding (2)
In: 01 eerste verdieping
Type - Material: f2_beton prefab
Type - Constraints(Type) - Default Elevation: 0 mm
Type - Materials and Finishes(Type) - materiaal: f2_beton prefab
Type - Identity Data(Type) - Type Name: uitbreiding; Workset: Family : Generic Models : NLRS_21_GM_vleermuiskast_bdg
Type - Other(Type) - Category: Generic Models; Family Name: NLRS_21_GM_vleermuiskast_bdg; uitbreiding: yes
Constraints - Level: 01 eerste verdieping; Elevation from Level: 1707 mm
Phasing - Phase Created: 2. nieuwbouw
Dimensions - Area: 0.538016 m2; Volume: 0.0203597 m3
Identity Data - Workset: Workset1
Other - Category: Generic Models; Family: NLRS_21_GM_vleermuiskast_bdg; Family and Type: NLRS_21_GM_vleermuiskast_bdg: uitbreiding; Type: uitbreiding; Type Id: 3063739
Name (NLRS_21_GM_vleermuiskast_bdg:uitbreiding:...) | Host Id
3059705 | 1885555
3060153 | 1884232

# IfcBuildingElementProxy: NLRS_24_GM_UN_betonnen bloktrede_gen_ISR:bloktrede bordes, NLRS_24_GM_UN_betonnen bloktrede_gen_ISR:bloktrede bordes:2978011
In: 00 begane grond
Type - PredefinedType: USERDEFINED; Material: f2_beton_prefab_gen
Type - Constraints - Default Elevation: 0 mm
Type - Materials and Finishes - NLRS_C_materiaal: f2_beton_prefab_gen
Type - Dimensions - hoek_a: 0 deg; hoek_b: 0 deg; optrede: 200 mm; sponning_breedte: 65 mm; sponning_hoogte: 20 mm; trede_breedte: 1100 mm; wel: 40 mm
Type - Identity Data - Workset: Family : Generic Models : NLRS_24_GM_UN_betonnen bloktrede_gen_ISR; Assembly Code: 24.11; Assembly Description: trappen en hellingen; trappen, rechte steektrappen; Datum_Gewijzigd: 12-11-2020; Description: bloktrede; Model: LOD300; SmartRevit_Versie: 2021.1; Type Name: bloktrede bordes
Type - Other - Category: Generic Models; berekende_hoek_a: 90 deg; berekende_hoek_b: 90 deg; Family Name: NLRS_24_GM_UN_betonnen bloktrede_gen_ISR; hulp_lengte_hoek_a: 400 mm; hulp_lengte_hoek_b: 400 mm
Classification: 24.11 Uniformat (Uniformat)
Constraints - Length: 4670 mm; Offset from Host: 1663.16 mm; Work Plane: Floor : NLRS_23_FL_basisvloer 500
Phasing - Phase Created: 2. nieuwbouw
Structural - Rebar Cover: 30mm <30 mm>
Dimensions - Area: 6.20155 m2; Volume: 1.00265 m3
Identity Data - Workset: Workset1
Other - Family: NLRS_24_GM_UN_betonnen bloktrede_gen_ISR; Family and Type: NLRS_24_GM_UN_betonnen bloktrede_gen_ISR: bloktrede bordes; Type: bloktrede bordes; Type Id: 2976348

# IfcBuildingElementProxy: NLRS_24_GM_UN_betonnen bloktrede_gen_ISR:bloktrede bordes boven, NLRS_24_GM_UN_betonnen bloktrede_gen_ISR:bloktrede bordes boven:2978204
In: 01 eerste verdieping
Type - PredefinedType: USERDEFINED; Material: f2_beton_prefab_gen
Type - Constraints - Default Elevation: 0 mm
Type - Materials and Finishes - NLRS_C_materiaal: f2_beton_prefab_gen
Type - Dimensions - hoek_a: 0 deg; hoek_b: 0 deg; optrede: 200 mm; sponning_breedte: 65 mm; sponning_hoogte: 20 mm; trede_breedte: 1700 mm; wel: 40 mm
Type - Identity Data - Workset: Family : Generic Models : NLRS_24_GM_UN_betonnen bloktrede_gen_ISR; Assembly Code: 24.11; Assembly Description: trappen en hellingen; trappen, rechte steektrappen; Datum_Gewijzigd: 12-11-2020; Description: bloktrede; Model: LOD300; SmartRevit_Versie: 2021.1; Type Name: bloktrede bordes boven
Type - Other - Category: Generic Models; berekende_hoek_a: 90 deg; berekende_hoek_b: 90 deg; Family Name: NLRS_24_GM_UN_betonnen bloktrede_gen_ISR; hulp_lengte_hoek_a: 400 mm; hulp_lengte_hoek_b: 400 mm
Classification: 24.11 Uniformat (Uniformat)
Constraints - Length: 4670 mm; Offset from Host: 3340 mm; Work Plane: Floor : NLRS_23_FL_basisvloer 500
Phasing - Phase Created: 2. nieuwbouw
Structural - Rebar Cover: 30mm <30 mm>
Dimensions - Area: 9.12355 m2; Volume: 1.56305 m3
Identity Data - Workset: Workset1
Other - Family: NLRS_24_GM_UN_betonnen bloktrede_gen_ISR; Family and Type: NLRS_24_GM_UN_betonnen bloktrede_gen_ISR: bloktrede bordes boven; Type: bloktrede bordes boven; Type Id: 2978278

# IfcBuildingElementProxy: NLRS_24_GM_UN_betonnen bloktrede_gen_ISR:bloktrede gen h 250 (17)
In: 00 begane grond
Type - PredefinedType: USERDEFINED; Material: f2_beton_prefab_gen
Type - Constraints - Default Elevation: 0 mm
Type - Materials and Finishes - NLRS_C_materiaal: f2_beton_prefab_gen
Type - Dimensions - hoek_a: 0 deg; hoek_b: 0 deg; optrede: 200 mm; sponning_breedte: 65 mm; sponning_hoogte: 20 mm; trede_breedte: 350 mm; wel: 40 mm
Type - Identity Data - Assembly Code: 24.11; Assembly Description: trappen en hellingen; trappen, rechte steektrappen; Datum_Gewijzigd: 12-11-2020; Description: bloktrede; Model: LOD300; SmartRevit_Versie: 2021.1; Type Name: bloktrede gen h 250; Workset: Family : Generic Models : NLRS_24_GM_UN_betonnen bloktrede_gen_ISR
Type - Other - Category: Generic Models; berekende_hoek_a: 90 deg; berekende_hoek_b: 90 deg; Family Name: NLRS_24_GM_UN_betonnen bloktrede_gen_ISR; hulp_lengte_hoek_a: 400 mm; hulp_lengte_hoek_b: 400 mm
Classification: 24.11 Uniformat (Uniformat)
Constraints - Length: 4670 mm; Work Plane: Floor : NLRS_23_FL_basisvloer 500
Phasing - Phase Created: 2. nieuwbouw
Structural - Rebar Cover: 30mm <30 mm>
Dimensions - Area: 2.54905 m2; Volume: 0.302149 m3
Identity Data - Workset: Workset1
Other - Family: NLRS_24_GM_UN_betonnen bloktrede_gen_ISR; Family and Type: NLRS_24_GM_UN_betonnen bloktrede_gen_ISR: bloktrede gen h 250; Type: bloktrede gen h 250; Type Id: 2971848
Name (NLRS_24_GM_UN_betonnen bloktrede_gen_ISR:bloktrede gen h 250:...) | Offset from Host (mm)
2977947 | 172.632
2977954 | 358.947
2977963 | 545.263
2977972 | 731.579
2977981 | 917.895
2977990 | 1104.21
2977997 | 1290.53
2978004 | 1476.84
2978041 | 1849.47
2978127 | 2035.79
2978134 | 2222.11
2978143 | 2408.42
2978152 | 2594.74
2978161 | 2781.05
2978170 | 2967.37
2978192 | 3153.68
2980998 | -13.6842

# IfcBuildingElementProxy: NLRS_27_GM_extra tribunetrede_bdg:NLRS_27_GM_extra tribunetrede_bdg, NLRS_27_GM_extra tribunetrede_bdg:NLRS_27_GM_extra tribunetrede_bdg:2084102
In: 01 eerste verdieping
Type - Material: ISR_Hout
Type - Constraints - Default Elevation: 0 mm
Type - Materials and Finishes - afwerking: ISR_Hout
Type - Identity Data - Type Name: NLRS_27_GM_extra tribunetrede_bdg; Workset: Family : Generic Models : NLRS_27_GM_extra tribunetrede_bdg
Type - Other - Category: Generic Models; Family Name: NLRS_27_GM_extra tribunetrede_bdg
Constraints - Elevation from Level: 0 mm; Moves With Nearby Elements: no; Offset from Host: 0 mm; Level: 01 eerste verdieping; Host: Floor : NLRS_43_FL_cementdekvloer 50_gen_ISR
Phasing - Phase Created: 2. nieuwbouw
Dimensions - Area: 4.25034 m2; Volume: 0.219881 m3
Identity Data - Workset: Workset1
Other - Family: NLRS_27_GM_extra tribunetrede_bdg; Family and Type: NLRS_27_GM_extra tribunetrede_bdg: NLRS_27_GM_extra tribunetrede_bdg; Type: NLRS_27_GM_extra tribunetrede_bdg; Type Id: 2084078

# IfcBuildingElementProxy: NLRS_27_GM_hellingbaanelement_bdg:NLRS_27_GM_hellingbaanelement_bdg, NLRS_27_GM_hellingbaanelement_bdg:NLRS_27_GM_hellingbaanelement_bdg:2079868
In: 01 eerste verdieping
Type - Material: ISR_Hout
Type - Constraints - Default Elevation: 0 mm
Type - Materials and Finishes - materiaal: ISR_Hout
Type - Identity Data - Type Name: NLRS_27_GM_hellingbaanelement_bdg; Workset: Family : Generic Models : NLRS_27_GM_hellingbaanelement_bdg
Type - Other - Category: Generic Models; Family Name: NLRS_27_GM_hellingbaanelement_bdg
Constraints - Elevation from Level: 0 mm; Moves With Nearby Elements: no; Offset from Host: 0 mm; Level: 01 eerste verdieping; Host: Floor : NLRS_43_FL_cementdekvloer 50_gen_ISR
Phasing - Phase Created: 2. nieuwbouw
Dimensions - Area: 14.3941 m2; Volume: 0.451663 m3
Identity Data - Workset: Workset1
Other - Family: NLRS_27_GM_hellingbaanelement_bdg; Family and Type: NLRS_27_GM_hellingbaanelement_bdg: NLRS_27_GM_hellingbaanelement_bdg; Type: NLRS_27_GM_hellingbaanelement_bdg; Type Id: 2079804

# IfcBuildingElementProxy: NLRS_27_GM_optrede V1_bdg:NLRS_27_GM_optrede V1_bdg, NLRS_27_GM_optrede V1_bdg:NLRS_27_GM_optrede V1_bdg:3524611
In: 01 eerste verdieping
Type - Material: <Unnamed>
Type - Constraints - Default Elevation: 0 mm
Type - Identity Data - Type Name: NLRS_27_GM_optrede V1_bdg; Workset: Family : Generic Models : NLRS_27_GM_optrede V1_bdg
Type - Other - Category: Generic Models; Family Name: NLRS_27_GM_optrede V1_bdg
Constraints - Elevation from Level: 0 mm; Moves With Nearby Elements: no; Offset from Host: 0 mm; Level: 01 eerste verdieping; Host: Floor : NLRS_43_FL_cementdekvloer 50_gen_ISR
Phasing - Phase Created: 2. nieuwbouw
Dimensions - Area: 4.1305 m2; Volume: 0.145381 m3
Identity Data - Workset: Workset1
Other - Family: NLRS_27_GM_optrede V1_bdg; Family and Type: NLRS_27_GM_optrede V1_bdg: NLRS_27_GM_optrede V1_bdg; Type: NLRS_27_GM_optrede V1_bdg; Type Id: 3520807

# IfcBuildingElementProxy: NLRS_27_GM_terrasbordes_bdg:NLRS_27_GM_terrasbordes_bdg, NLRS_27_GM_terrasbordes_bdg:NLRS_27_GM_terrasbordes_bdg:3521818
In: 02 tweede verdieping
Type - Material: <Unnamed>
Type - Constraints - Default Elevation: 0 mm
Type - Identity Data - Type Name: NLRS_27_GM_terrasbordes_bdg; Workset: Family : Generic Models : NLRS_27_GM_terrasbordes_bdg
Type - Other - Category: Generic Models; Family Name: NLRS_27_GM_terrasbordes_bdg
Constraints - Elevation from Level: 0 mm; Moves With Nearby Elements: no; Offset from Host: 0 mm; Level: 02 tweede verdieping; Host: Floor : NLRS_43_FL_cementdekvloer 50_gen_ISR
Phasing - Phase Created: 2. nieuwbouw
Dimensions - Area: 5.92092 m2; Volume: 0.207194 m3
Identity Data - Workset: Workset1
Other - Family: NLRS_27_GM_terrasbordes_bdg; Family and Type: NLRS_27_GM_terrasbordes_bdg: NLRS_27_GM_terrasbordes_bdg; Type: NLRS_27_GM_terrasbordes_bdg; Type Id: 2117319

# IfcBuildingElementProxy: NLRS_33_GM_FL_kruipluik:Kruipluik 600 x 1000 (5)
In: 00 begane grond
Type - Material: Default
Type - Constraints(Type) - Default Elevation: 1219.2 mm
Type - Materials and Finishes(Type) - material: Default
Type - Dimensions(Type) - breedte: 600 mm; diepte: 330 mm; hoogte: 0 mm; lengte: 800 mm; randdikte: 30 mm
Type - Identity Data(Type) - Description: kr.l.; Manufacturer: Fermi; Type Name: Kruipluik 600 x 1000; Workset: Family : Generic Models : NLRS_33_GM_FL_kruipluik
Type - Other(Type) - Category: Generic Models; Family Name: NLRS_33_GM_FL_kruipluik
Constraints - Level: 00 begane grond; Schedule Level: 00 begane grond
Phasing - Phase Created: 2. nieuwbouw
Dimensions - Area: 1.4028 m2; Volume: 0.03852 m3
Identity Data - Workset: Workset1
Other - Category: Generic Models; Family: NLRS_33_GM_FL_kruipluik; Family and Type: NLRS_33_GM_FL_kruipluik: Kruipluik 600 x 1000; Type: Kruipluik 600 x 1000; Type Id: 2108229
Name (NLRS_33_GM_FL_kruipluik:Kruipluik 600 x 1000:...) | Elevation from Level (mm) | Host
2108285 | 0 | Floor : NLRS_43_FL_cementdekvloer 60_gen_ISR
2108454 | 5 | Floor : 43_FL_schoonloopmat_5
2108660 | 0 | Floor : NLRS_43_FL_cementdekvloer 60_gen_ISR
2108764 | 0 | Floor : NLRS_43_FL_cementdekvloer 60_gen_ISR
2108983 | 0 | Floor : NLRS_43_FL_cementdekvloer 60_gen_ISR

# IfcBuildingElementProxy: NLRS_40_GM_UN_bekleding_kolom_gen_bdg:kolom HE140A (5)
In: 00 begane grond
Type - Material: ISR_brandwerende beplating
Type - Constraints - Default Elevation: 0 mm
Type - Materials and Finishes - materiaal_bekleding: ISR_brandwerende beplating
Type - Construction - beplating_achterzijde: yes; beplating_linkerzijde: yes; beplating_rechterzijde: yes; beplating_voorzijde: yes; beplating_zijkanten_afwijkend: no
Type - Dimensions - beplating_dikte: 15 mm; hoogte_beplating_links: 50 mm; hoogte_beplating_rechts: 75 mm; kolom_breedte: 133 mm; kolom_hoogte: 140 mm
Type - Identity Data - Workset: Family : Generic Models : NLRS_40_GM_UN_bekleding_kolom_gen_bdg; Type Name: kolom HE140A
Type - Other - Category: Generic Models; ber_beplating_links: 140 mm; ber_beplating_rechts: 140 mm; Family Name: NLRS_40_GM_UN_bekleding_kolom_gen_bdg
Constraints - Elevation from Level: 0 mm; Level: 00 begane grond; Moves With Nearby Elements: no; Offset from Host: 0 mm; Host: Level : 00 begane grond
Phasing - Phase Created: 2. nieuwbouw
Dimensions - Area: 2.53989 m2; hoogte: 3800 mm; Volume: 0.034542 m3
Identity Data - Workset: Workset1
Other - Family: NLRS_40_GM_UN_bekleding_kolom_gen_bdg; Family and Type: NLRS_40_GM_UN_bekleding_kolom_gen_bdg: kolom HE140A; Type: kolom HE140A; Type Id: 3541447
Name (NLRS_40_GM_UN_bekleding_kolom_gen_bdg:kolom HE140A:...)
3541398
3541904
3542301
3542698
3543095

# IfcBuildingElementProxy: NLRS_40_GM_UN_bekleding_kolom_gen_bdg:kolom HE240B (2)
In: 00 begane grond
Type - Material: ISR_brandwerende beplating
Type - Constraints - Default Elevation: 0 mm
Type - Materials and Finishes - materiaal_bekleding: ISR_brandwerende beplating
Type - Construction - beplating_achterzijde: yes; beplating_linkerzijde: yes; beplating_rechterzijde: yes; beplating_voorzijde: yes; beplating_zijkanten_afwijkend: no
Type - Dimensions - beplating_dikte: 15 mm; hoogte_beplating_links: 50 mm; hoogte_beplating_rechts: 75 mm; kolom_breedte: 240 mm; kolom_hoogte: 240 mm
Type - Identity Data - Type Name: kolom HE240B; Workset: Family : Generic Models : NLRS_40_GM_UN_bekleding_kolom_gen_bdg
Type - Other - Category: Generic Models; ber_beplating_links: 240 mm; ber_beplating_rechts: 240 mm; Family Name: NLRS_40_GM_UN_bekleding_kolom_gen_bdg
Constraints - Elevation from Level: 0 mm; Level: 00 begane grond; Moves With Nearby Elements: no; Offset from Host: 0 mm; Host: Floor : NLRS_43_FL_cementdekvloer 60_gen_ISR
Phasing - Phase Created: 2. nieuwbouw
Dimensions - Area: 4.8753 m2; hoogte: 4500 mm; Volume: 0.06885 m3
Identity Data - Workset: Workset1
Other - Family: NLRS_40_GM_UN_bekleding_kolom_gen_bdg; Family and Type: NLRS_40_GM_UN_bekleding_kolom_gen_bdg: kolom HE240B; Type: kolom HE240B; Type Id: 2996068
Name (NLRS_40_GM_UN_bekleding_kolom_gen_bdg:kolom HE240B:...)
2996138
4334296

# IfcBuildingElementProxy: NLRS_41_GM_WPB_kantplank-geisoleerd_generiek_ISR:10+120isol (27)
In: 00 begane grond
Type - Material: ISR_Vezelcement, n7_isolatie_PIR
Type - Constraints - Default Elevation: 1219.2 mm
Type - Materials and Finishes - beplating_materiaal: ISR_Vezelcement; isolatie_materiaal: n7_isolatie_PIR
Type - Dimensions - beplating_dikte: 10 mm; breedte: 50 mm; isolatie_dikte: 120 mm; kantplank_hoogte: 475 mm; sponninghoogte_bovenzijde_isolatie: 0 mm
Type - Identity Data - Assembly Code: 41.12; Assembly Description: buitenwandafwerkingen; bekledingen; Datum_Gewijzigd: 20160502; Description: kantplank; Model: LOD300; SmartRevit_Versie: 2019.1; Type Name: 10+120isol; Workset: Family : Generic Models : NLRS_41_GM_WPB_kantplank-geisoleerd_generiek_ISR
Type - Other - Category: Generic Models; berekende_isolatie_hoogte: 475 mm; berekende_vertical_offset_isolatie: 0 mm; Family Name: NLRS_41_GM_WPB_kantplank-geisoleerd_generiek_ISR
Classification: 41.12 Uniformat (Uniformat)
Constraints - Level: 00 begane grond; Moves With Nearby Elements: no
Phasing - Phase Created: 2. nieuwbouw
Graphics - hoek_b: 0 deg
Dimensions - verlenging_a: 0 mm; verlenging_b: 0 mm; NLRS_C_breedte: 50 mm; NLRS_C_hoogte: 475 mm
Identity Data - Workset: Workset1
Other - berekende_overstek_b: 0 mm; berekende_verlenging_a: 2000 mm; berekende_verlenging_b: 2000 mm; Family: NLRS_41_GM_WPB_kantplank-geisoleerd_generiek_ISR; Family and Type: NLRS_41_GM_WPB_kantplank-geisoleerd_generiek_ISR: 10+120isol; Type: 10+120isol; Type Id: 904604
Name (NLRS_41_GM_WPB_kantplank-geisoleerd_generiek_ISR:10+120isol:...) | Elevation from Level (mm) = Offset from Host (mm) | Host | lengte (mm) = NLRS_C_lengte (mm) | hoek_a (deg) | Area (m2) | element_lengte (mm) | Volume (m3) | berekende_hoek_a (deg) | berekende_overstek_a (mm)
897882 | 869.638 | Basic Wall : NLRS_22_WA_HSB bispouw 30-245-12-13 glaswol_gen_ISR | 1814 | 0 | 2.02087 | 1814 | 0.112014 | 0 | 0
897935 | 869.638 | Basic Wall : NLRS_22_WA_HSB bispouw 30-245-12-13 glaswol_gen_ISR | 914 | 0 | 1.04887 | 914 | 0.0564395 | 0 | 0
898543 | 869.638 | Basic Wall : NLRS_22_WA_HSB bispouw 30-245-12-13 glaswol_gen_ISR | 2114 | 0 | 2.34487 | 2114 | 0.130539 | 0 | 0
898555 | 869.638 | Basic Wall : NLRS_22_WA_HSB bispouw 30-245-12-13 glaswol_gen_ISR | 1514 | 0 | 1.69687 | 1514 | 0.0934895 | 0 | 0
1219782 | 869.638 | Basic Wall : NLRS_22_WA_HSB bispouw 30-245-12-13 glaswol_gen_ISR | 1814 | 0 | 2.02087 | 1814 | 0.112014 | 0 | 0
1220532 | 869.638 | Basic Wall : NLRS_22_WA_HSB bispouw 30-245-12-13 glaswol_gen_ISR | 3014 | 0 | 3.31687 | 3014 | 0.186114 | 0 | 0
1221366 | 869.638 | Basic Wall : NLRS_22_WA_HSB bispouw 30-245-12-13 glaswol_gen_ISR | 914 | 0 | 1.04887 | 914 | 0.0564395 | 0 | 0
1221377 | 869.638 | Basic Wall : NLRS_22_WA_HSB bispouw 30-245-12-13 glaswol_gen_ISR | 2980 | 0 | 3.28015 | 2980 | 0.184015 | 0 | 0
1221598 | 869.638 | Basic Wall : NLRS_22_WA_HSB bispouw 30-245-12-13 glaswol_gen_ISR | 3314 | 0 | 3.64087 | 3314 | 0.204639 | 0 | 0
1222353 | 869.638 | Basic Wall : NLRS_22_WA_HSB bispouw 30-245-12-13 glaswol_gen_ISR | 914 | 0 | 1.04887 | 914 | 0.0564395 | 0 | 0
1222795 | 869.638 | Basic Wall : NLRS_22_WA_HSB bispouw 30-245-12-13 glaswol_gen_ISR | 914 | 0 | 1.04887 | 914 | 0.0564395 | 0 | 0
1223372 | 869.638 | Basic Wall : NLRS_22_WA_HSB bispouw 30-245-12-13 glaswol_gen_ISR | 2714 | 0 | 2.99287 | 2714 | 0.167589 | 0 | 0
1224041 | 869.638 | Basic Wall : NLRS_22_WA_HSB bispouw 30-245-12-13 glaswol_gen_ISR | 2969.5 | 0 | 3.26881 | 2969.5 | 0.183367 | 0 | 0
1224160 | 869.638 | Basic Wall : NLRS_22_WA_HSB bispouw 30-245-12-13 glaswol_gen_ISR | 4189 | 0 | 4.58587 | 4189 | 0.258671 | 0 | 0
1488569 | 931.638 | Basic Wall : 22_WA_binnenwand_ms125 25-75-25 _gen_bdg | 3014 | 0 | 3.31687 | 3014 | 0.186114 | 0 | 0
1492643 | 931.638 | Basic Wall : NLRS_22_WA_HSB bispouw 30-245-12-13 glaswol_gen_ISR | 4189 | 0 | 4.58587 | 4189 | 0.258671 | 0 | 0
1493179 | 931.638 | Level : 00 begane grond | 3014 | 0 | 3.31687 | 3014 | 0.186114 | 0 | 0
1502428 | 931.638 | Level : 00 begane grond | 3014 | 0 | 3.31687 | 3014 | 0.186114 | 0 | 0
1502787 | 931.638 | Level : 00 begane grond | 3014 | 0 | 3.31687 | 3014 | 0.186114 | 0 | 0
1503068 | 931.638 | Level : 00 begane grond | 914 | 0 | 1.04887 | 914 | 0.0564395 | 0 | 0
1503710 | 931.638 | Level : 00 begane grond | 4189 | 0 | 4.58587 | 4189 | 0.258671 | 0 | 0
1822616 | 931.638 | Basic Wall : NLRS_22_WA_HSB bispouw 30-245-12-13 glaswol_gen_ISR | 4189 | 0 | 4.58587 | 4189 | 0.258671 | 0 | 0
2239504 | 931.638 | Basic Wall : NLRS_22_WA_HSB bispouw 30-245-12-13 glaswol_gen_ISR | 1367 | -45 | 1.51422 | 1367 | 0.0809922 | 45 | 0
2239550 | 931.638 | Basic Wall : NLRS_22_WA_HSB bispouw 30-245-12-13 glaswol_gen_ISR | 847 | -45 | 0.952615 | 847 | 0.0488822 | 45 | 0
2785705 | 931.638 | Basic Wall : 22_WA_binnenwand_ms125 25-75-25 _gen_bdg | 1864.5 | -45 | 2.05152 | 1864.5 | 0.111713 | 45 | 0
2786083 | 931.638 | Basic Wall : NLRS_22_WA_HSB bispouw 30-245-12-13 glaswol_gen_ISR | 2308 | 45 | 2.57593 | 2358 | 0.144775 | -45 | 50
2790502 | 931.638 | Basic Wall : 22_WA_binnenwand_ms125 25-75-25 _gen_bdg | 3100.76 | -45 | 3.38667 | 3100.76 | 0.188052 | 45 | 0

# IfcBuildingElementProxy: NLRS_41_GM_WPB_kantplank-geisoleerd_generiek_ISR:10+120isol h450 (2)
In: 00 begane grond
Type - Material: ISR_Vezelcement, n7_isolatie_PIR
Type - Constraints - Default Elevation: 1219.2 mm
Type - Materials and Finishes - beplating_materiaal: ISR_Vezelcement; isolatie_materiaal: n7_isolatie_PIR
Type - Dimensions - sponninghoogte_bovenzijde_isolatie: 0 mm; beplating_dikte: 10 mm; breedte: 50 mm; isolatie_dikte: 120 mm; kantplank_hoogte: 450 mm
Type - Identity Data - Workset: Family : Generic Models : NLRS_41_GM_WPB_kantplank-geisoleerd_generiek_ISR; Assembly Code: 41.12; Assembly Description: buitenwandafwerkingen; bekledingen; Datum_Gewijzigd: 20160502; Description: kantplank; Model: LOD300; SmartRevit_Versie: 2019.1; Type Name: 10+120isol h450
Type - Other - Category: Generic Models; berekende_vertical_offset_isolatie: 0 mm; berekende_isolatie_hoogte: 450 mm; Family Name: NLRS_41_GM_WPB_kantplank-geisoleerd_generiek_ISR
Classification: 41.12 Uniformat (Uniformat)
Constraints - Level: 00 begane grond; Moves With Nearby Elements: no; Host: Basic Wall : NLRS_22_WA_HSB bispouw 30-245-12-13 glaswol_gen_ISR
Phasing - Phase Created: 2. nieuwbouw
Graphics - hoek_a: 0 deg; hoek_b: 0 deg
Dimensions - verlenging_a: 0 mm; verlenging_b: 0 mm; NLRS_C_breedte: 50 mm; NLRS_C_hoogte: 450 mm
Identity Data - Workset: Workset1
Other - berekende_hoek_a: 0 deg; berekende_overstek_a: 0 mm; berekende_overstek_b: 0 mm; Family: NLRS_41_GM_WPB_kantplank-geisoleerd_generiek_ISR; berekende_verlenging_a: 2000 mm; berekende_verlenging_b: 2000 mm; Family and Type: NLRS_41_GM_WPB_kantplank-geisoleerd_generiek_ISR: 10+120isol h450; Type: 10+120isol h450; Type Id: 4863061
Name (NLRS_41_GM_WPB_kantplank-geisoleerd_generiek_ISR:10+120isol h450:...) | Elevation from Level (mm) = Offset from Host (mm) | lengte (mm) = element_lengte (mm) = NLRS_C_lengte (mm) | Area (m2) | Volume (m3)
1224052 | 869.638 | 2263 | 2.38939 | 0.132385
1818652 | 931.638 | 5014 | 5.22292 | 0.293319

# IfcBuildingElementProxy: NLRS_41_GM_WPB_multiplex-SH_generiek_ISR:151x10 gipsvezel dagkant (340)
Type - Material: f7_gipsvezel
Type - Constraints - Default Elevation: 1219.2 mm
Type - Materials and Finishes - materiaal: f7_gipsvezel
Type - Dimensions - breedte: 10 mm; hoogte: 151 mm
Type - Identity Data - Assembly Code: 42; Assembly Description: binnenwandafwerkingen; Datum_Gewijzigd: 20160502; Description: multiplex; Model: LOD300; SmartRevit_Versie: 2019.1; Type Name: 151x10 gipsvezel dagkant; Workset: Family : Generic Models : NLRS_41_GM_WPB_multiplex-SH_generiek_ISR
Type - Other - Category: Generic Models; Family Name: NLRS_41_GM_WPB_multiplex-SH_generiek_ISR
Classification: 42 Uniformat (Uniformat)
Constraints - Moves With Nearby Elements: no
Phasing - Phase Created: 2. nieuwbouw
Graphics - hoek_a: 0 deg; hoek_b: 0 deg
Dimensions - NLRS_C_breedte: 10 mm; NLRS_C_hoogte: 151 mm
Identity Data - Workset: Workset1
Other - berekende_hoek_a: 0 deg; berekende_overstek_a: 0 mm; berekende_overstek_b: 0 mm; Family: NLRS_41_GM_WPB_multiplex-SH_generiek_ISR; Family and Type: NLRS_41_GM_WPB_multiplex-SH_generiek_ISR: 151x10 gipsvezel dagkant; Type: 151x10 gipsvezel dagkant; Type Id: 776503
Name (NLRS_41_GM_WPB_multiplex-SH_generiek_ISR:151x10 gipsvezel dagkant:...) | In | Level | Elevation from Level (mm) = Offset from Host (mm) | Host | lengte (mm) = NLRS_C_lengte (mm) | Area (m2) | element_lengte (mm) | verlenging_a (mm) | verlenging_b (mm) | Volume (m3) | berekende_verlenging_a (mm) | berekende_verlenging_b (mm)
832756 | 01 eerste verdieping | 01 eerste verdieping | -3882.36 | Basic Wall : NLRS_22_WA_HSB bispouw 30-245-12-13 glaswol_gen_ISR | 2000 | 0.281972 | 1742 | -129 | -129 | 0.00263042 | 1871 | 1871
832757 | 01 eerste verdieping | 01 eerste verdieping | -16409.4 | Basic Wall : NLRS_22_WA_HSB bispouw 30-245-12-13 glaswol_gen_ISR | 2079 | 0.316748 | 1958 | -27 | -94 | 0.00295658 | 1973 | 1906
832758 | 01 eerste verdieping | 01 eerste verdieping | 27320.6 | Basic Wall : NLRS_22_WA_HSB bispouw 30-245-12-13 glaswol_gen_ISR | 2079 | 0.316748 | 1958 | -94 | -27 | 0.00295658 | 1906 | 1973
858916 | 01 eerste verdieping | 01 eerste verdieping | -3882.36 | Level : 01 eerste verdieping | 2000 | 0.281972 | 1742 | -129 | -129 | 0.00263042 | 1871 | 1871
858917 | 01 eerste verdieping | 01 eerste verdieping | -16409.4 | Level : 01 eerste verdieping | 2079 | 0.316748 | 1958 | -27 | -94 | 0.00295658 | 1973 | 1906
858918 | 01 eerste verdieping | 01 eerste verdieping | 27320.6 | Level : 01 eerste verdieping | 2079 | 0.316748 | 1958 | -94 | -27 | 0.00295658 | 1906 | 1973
858942 | 01 eerste verdieping | 01 eerste verdieping | -3882.36 | Level : 01 eerste verdieping | 2000 | 0.281972 | 1742 | -129 | -129 | 0.00263042 | 1871 | 1871
858943 | 01 eerste verdieping | 01 eerste verdieping | -16409.4 | Level : 01 eerste verdieping | 2079 | 0.316748 | 1958 | -27 | -94 | 0.00295658 | 1973 | 1906
858944 | 01 eerste verdieping | 01 eerste verdieping | 27320.6 | Level : 01 eerste verdieping | 2079 | 0.316748 | 1958 | -94 | -27 | 0.00295658 | 1906 | 1973
859971 | 02 tweede verdieping | 02 tweede verdieping | -773.711 | Basic Wall : NLRS_22_WA_HSB bispouw 30-245-12-13 glaswol_gen_ISR | 1112 | 0.132886 | 816 | -148 | -148 | 0.00123216 | 1852 | 1852
859972 | 02 tweede verdieping | 02 tweede verdieping | -12010.9 | Basic Wall : NLRS_22_WA_HSB bispouw 30-245-12-13 glaswol_gen_ISR | 2449 | 0.376318 | 2328 | -27 | -94 | 0.00351528 | 1973 | 1906
859973 | 02 tweede verdieping | 02 tweede verdieping | 29169.4 | Basic Wall : NLRS_22_WA_HSB bispouw 30-245-12-13 glaswol_gen_ISR | 2449 | 0.376318 | 2328 | -94 | -27 | 0.00351528 | 1906 | 1973
864457 | 02 tweede verdieping | 02 tweede verdieping | -773.711 | Level : 02 tweede verdieping | 1112 | 0.132886 | 816 | -148 | -148 | 0.00123216 | 1852 | 1852
864458 | 02 tweede verdieping | 02 tweede verdieping | -12010.9 | Level : 02 tweede verdieping | 2449 | 0.376318 | 2328 | -27 | -94 | 0.00351528 | 1973 | 1906
864459 | 02 tweede verdieping | 02 tweede verdieping | 29169.4 | Level : 02 tweede verdieping | 2449 | 0.376318 | 2328 | -94 | -27 | 0.00351528 | 1906 | 1973
864488 | 02 tweede verdieping | 02 tweede verdieping | -773.711 | Level : 02 tweede verdieping | 1112 | 0.132886 | 816 | -148 | -148 | 0.00123216 | 1852 | 1852
864489 | 02 tweede verdieping | 02 tweede verdieping | -12010.9 | Level : 02 tweede verdieping | 2449 | 0.376318 | 2328 | -27 | -94 | 0.00351528 | 1973 | 1906
864490 | 02 tweede verdieping | 02 tweede verdieping | 29169.4 | Level : 02 tweede verdieping | 2449 | 0.376318 | 2328 | -94 | -27 | 0.00351528 | 1906 | 1973
870615 | 02 tweede verdieping | 02 tweede verdieping | -773.711 | Level : 02 tweede verdieping | 1112 | 0.132886 | 816 | -148 | -148 | 0.00123216 | 1852 | 1852
870616 | 02 tweede verdieping | 02 tweede verdieping | -12010.9 | Level : 02 tweede verdieping | 2449 | 0.376318 | 2328 | -27 | -94 | 0.00351528 | 1973 | 1906
870617 | 02 tweede verdieping | 02 tweede verdieping | 29169.4 | Level : 02 tweede verdieping | 2449 | 0.376318 | 2328 | -94 | -27 | 0.00351528 | 1906 | 1973
870632 | 02 tweede verdieping | 02 tweede verdieping | -773.711 | Level : 02 tweede verdieping | 1112 | 0.132886 | 816 | -148 | -148 | 0.00123216 | 1852 | 1852
870633 | 02 tweede verdieping | 02 tweede verdieping | -12010.9 | Level : 02 tweede verdieping | 2449 | 0.376318 | 2328 | -27 | -94 | 0.00351528 | 1973 | 1906
870634 | 02 tweede verdieping | 02 tweede verdieping | 29169.4 | Level : 02 tweede verdieping | 2449 | 0.376318 | 2328 | -94 | -27 | 0.00351528 | 1906 | 1973
870649 | 02 tweede verdieping | 02 tweede verdieping | -773.711 | Level : 02 tweede verdieping | 1112 | 0.132886 | 816 | -148 | -148 | 0.00123216 | 1852 | 1852
870650 | 02 tweede verdieping | 02 tweede verdieping | -12010.9 | Level : 02 tweede verdieping | 2449 | 0.376318 | 2328 | -27 | -94 | 0.00351528 | 1973 | 1906
870651 | 02 tweede verdieping | 02 tweede verdieping | 29169.4 | Level : 02 tweede verdieping | 2449 | 0.376318 | 2328 | -94 | -27 | 0.00351528 | 1906 | 1973
870697 | 02 tweede verdieping | 02 tweede verdieping | -773.711 | Level : 02 tweede verdieping | 1112 | 0.132886 | 816 | -148 | -148 | 0.00123216 | 1852 | 1852
870698 | 02 tweede verdieping | 02 tweede verdieping | -12010.9 | Level : 02 tweede verdieping | 2449 | 0.376318 | 2328 | -27 | -94 | 0.00351528 | 1973 | 1906
870699 | 02 tweede verdieping | 02 tweede verdieping | 29169.4 | Level : 02 tweede verdieping | 2449 | 0.376318 | 2328 | -94 | -27 | 0.00351528 | 1906 | 1973
870714 | 02 tweede verdieping | 02 tweede verdieping | -773.711 | Level : 02 tweede verdieping | 1112 | 0.132886 | 816 | -148 | -148 | 0.00123216 | 1852 | 1852
870715 | 02 tweede verdieping | 02 tweede verdieping | -12010.9 | Level : 02 tweede verdieping | 2449 | 0.376318 | 2328 | -27 | -94 | 0.00351528 | 1973 | 1906
870716 | 02 tweede verdieping | 02 tweede verdieping | 29169.4 | Level : 02 tweede verdieping | 2449 | 0.376318 | 2328 | -94 | -27 | 0.00351528 | 1906 | 1973
870731 | 02 tweede verdieping | 02 tweede verdieping | -773.711 | Level : 02 tweede verdieping | 1112 | 0.132886 | 816 | -148 | -148 | 0.00123216 | 1852 | 1852
870732 | 02 tweede verdieping | 02 tweede verdieping | -12010.9 | Level : 02 tweede verdieping | 2449 | 0.376318 | 2328 | -27 | -94 | 0.00351528 | 1973 | 1906
870733 | 02 tweede verdieping | 02 tweede verdieping | 29169.4 | Level : 02 tweede verdieping | 2449 | 0.376318 | 2328 | -94 | -27 | 0.00351528 | 1906 | 1973
870810 | 02 tweede verdieping | 02 tweede verdieping | -773.711 | Level : 02 tweede verdieping | 1112 | 0.132886 | 816 | -148 | -148 | 0.00123216 | 1852 | 1852
870811 | 02 tweede verdieping | 02 tweede verdieping | -12010.9 | Level : 02 tweede verdieping | 2449 | 0.376318 | 2328 | -27 | -94 | 0.00351528 | 1973 | 1906
870812 | 02 tweede verdieping | 02 tweede verdieping | 29169.4 | Level : 02 tweede verdieping | 2449 | 0.376318 | 2328 | -94 | -27 | 0.00351528 | 1906 | 1973
870827 | 02 tweede verdieping | 02 tweede verdieping | -773.711 | Level : 02 tweede verdieping | 1112 | 0.132886 | 816 | -148 | -148 | 0.00123216 | 1852 | 1852
870828 | 02 tweede verdieping | 02 tweede verdieping | -12010.9 | Level : 02 tweede verdieping | 2449 | 0.376318 | 2328 | -27 | -94 | 0.00351528 | 1973 | 1906
870829 | 02 tweede verdieping | 02 tweede verdieping | 29169.4 | Level : 02 tweede verdieping | 2449 | 0.376318 | 2328 | -94 | -27 | 0.00351528 | 1906 | 1973
870844 | 02 tweede verdieping | 02 tweede verdieping | -773.711 | Level : 02 tweede verdieping | 1112 | 0.132886 | 816 | -148 | -148 | 0.00123216 | 1852 | 1852
870845 | 02 tweede verdieping | 02 tweede verdieping | -12010.9 | Level : 02 tweede verdieping | 2449 | 0.376318 | 2328 | -27 | -94 | 0.00351528 | 1973 | 1906
870846 | 02 tweede verdieping | 02 tweede verdieping | 29169.4 | Level : 02 tweede verdieping | 2449 | 0.376318 | 2328 | -94 | -27 | 0.00351528 | 1906 | 1973
870954 | 02 tweede verdieping | 02 tweede verdieping | 44732.6 | Basic Wall : 21_WA_metselwerk_licht_100_gen_bdg | 1112 | 0.132886 | 816 | -148 | -148 | 0.00123216 | 1852 | 1852
870955 | 02 tweede verdieping | 02 tweede verdieping | -2201.86 | Basic Wall : 21_WA_metselwerk_licht_100_gen_bdg | 2449 | 0.376318 | 2328 | -27 | -94 | 0.00351528 | 1973 | 1906
870956 | 02 tweede verdieping | 02 tweede verdieping | 20648.1 | Basic Wall : 21_WA_metselwerk_licht_100_gen_bdg | 2449 | 0.376318 | 2328 | -94 | -27 | 0.00351528 | 1906 | 1973
871632 | 02 tweede verdieping | 02 tweede verdieping | 44732.6 | Level : 02 tweede verdieping | 1112 | 0.132886 | 816 | -148 | -148 | 0.00123216 | 1852 | 1852
871633 | 02 tweede verdieping | 02 tweede verdieping | -2201.86 | Level : 02 tweede verdieping | 2449 | 0.376318 | 2328 | -27 | -94 | 0.00351528 | 1973 | 1906
871634 | 02 tweede verdieping | 02 tweede verdieping | 20648.1 | Level : 02 tweede verdieping | 2449 | 0.376318 | 2328 | -94 | -27 | 0.00351528 | 1906 | 1973
871665 | 02 tweede verdieping | 02 tweede verdieping | 44732.6 | Level : 02 tweede verdieping | 1112 | 0.132886 | 816 | -148 | -148 | 0.00123216 | 1852 | 1852
871666 | 02 tweede verdieping | 02 tweede verdieping | -2201.86 | Level : 02 tweede verdieping | 2449 | 0.376318 | 2328 | -27 | -94 | 0.00351528 | 1973 | 1906
871667 | 02 tweede verdieping | 02 tweede verdieping | 20648.1 | Level : 02 tweede verdieping | 2449 | 0.376318 | 2328 | -94 | -27 | 0.00351528 | 1906 | 1973
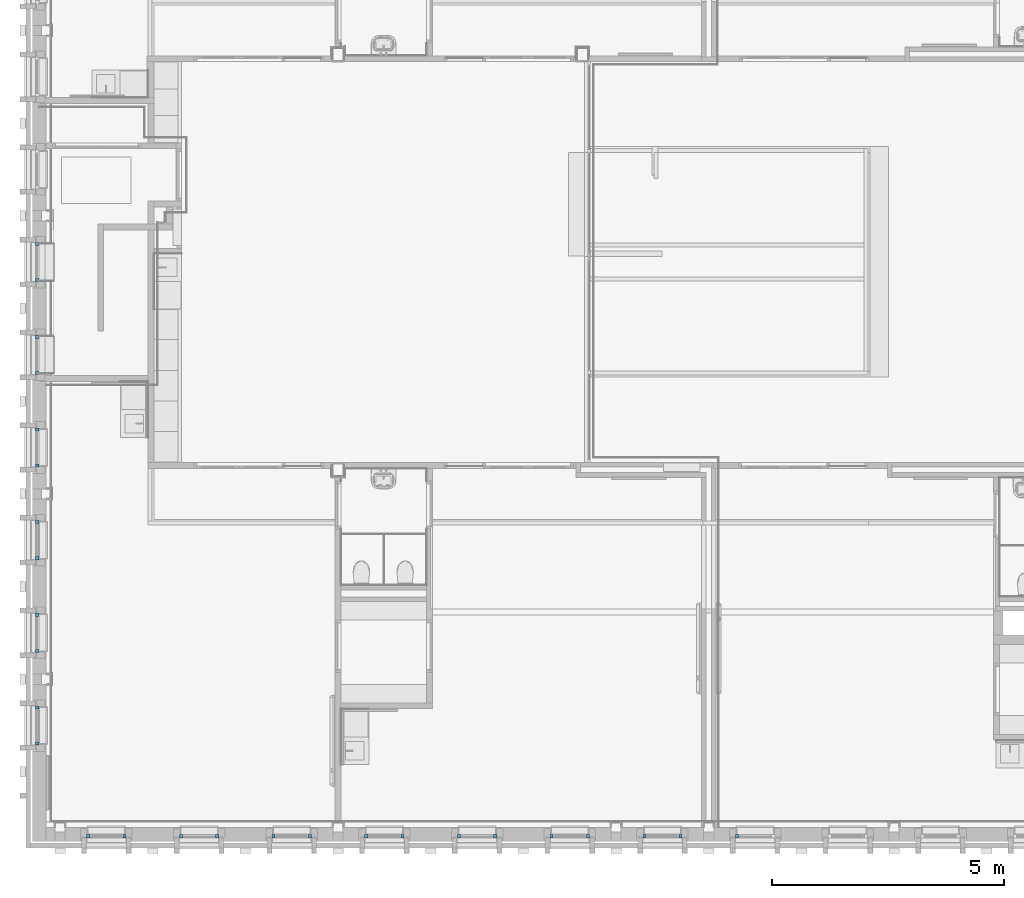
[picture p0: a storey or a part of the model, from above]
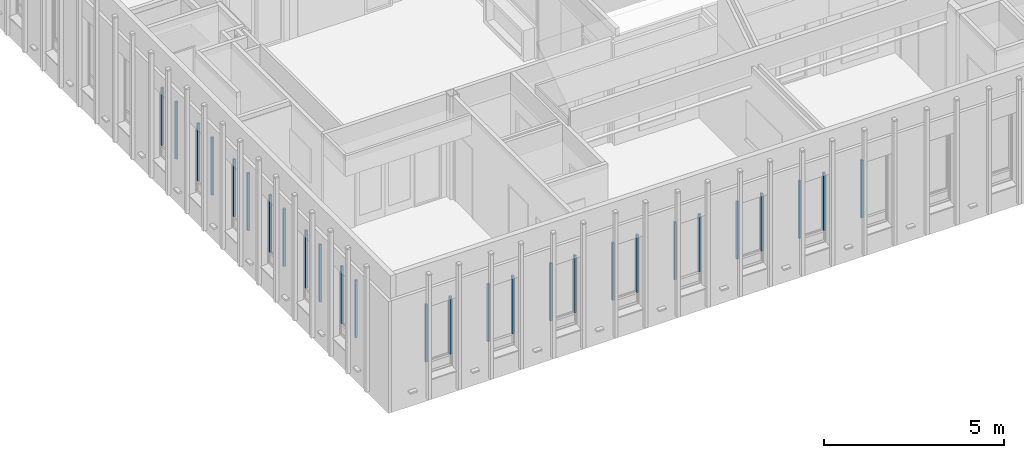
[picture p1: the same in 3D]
Properties of the parts of a building model (IFC2X3), part 3 of 94

# IfcBuildingElementProxy: NLRS_41_GM_WPB_multiplex-SH_generiek_ISR:151x10 gipsvezel dagkant (340)
Name (NLRS_41_GM_WPB_multiplex-SH_generiek_ISR:151x10 gipsvezel dagkant:...) | In | Level | Elevation from Level (mm) = Offset from Host (mm) | Host | lengte (mm) = NLRS_C_lengte (mm) | Area (m2) | element_lengte (mm) | verlenging_a (mm) | verlenging_b (mm) | Volume (m3) | berekende_verlenging_a (mm) | berekende_verlenging_b (mm)
871698 | 02 tweede verdieping | 02 tweede verdieping | 44732.6 | Level : 02 tweede verdieping | 1112 | 0.132886 | 816 | -148 | -148 | 0.00123216 | 1852 | 1852
871699 | 02 tweede verdieping | 02 tweede verdieping | -2201.86 | Level : 02 tweede verdieping | 2449 | 0.376318 | 2328 | -27 | -94 | 0.00351528 | 1973 | 1906
871700 | 02 tweede verdieping | 02 tweede verdieping | 20648.1 | Level : 02 tweede verdieping | 2449 | 0.376318 | 2328 | -94 | -27 | 0.00351528 | 1906 | 1973
871884 | 02 tweede verdieping | 02 tweede verdieping | 44732.6 | Level : 02 tweede verdieping | 1112 | 0.132886 | 816 | -148 | -148 | 0.00123216 | 1852 | 1852
871885 | 02 tweede verdieping | 02 tweede verdieping | -2201.86 | Level : 02 tweede verdieping | 2449 | 0.376318 | 2328 | -27 | -94 | 0.00351528 | 1973 | 1906
871886 | 02 tweede verdieping | 02 tweede verdieping | 20648.1 | Level : 02 tweede verdieping | 2449 | 0.376318 | 2328 | -94 | -27 | 0.00351528 | 1906 | 1973
871916 | 02 tweede verdieping | 02 tweede verdieping | 44732.6 | Level : 02 tweede verdieping | 1112 | 0.132886 | 816 | -148 | -148 | 0.00123216 | 1852 | 1852
871917 | 02 tweede verdieping | 02 tweede verdieping | -2201.86 | Level : 02 tweede verdieping | 2449 | 0.376318 | 2328 | -27 | -94 | 0.00351528 | 1973 | 1906
871918 | 02 tweede verdieping | 02 tweede verdieping | 20648.1 | Level : 02 tweede verdieping | 2449 | 0.376318 | 2328 | -94 | -27 | 0.00351528 | 1906 | 1973
871948 | 02 tweede verdieping | 02 tweede verdieping | 44732.6 | Level : 02 tweede verdieping | 1112 | 0.132886 | 816 | -148 | -148 | 0.00123216 | 1852 | 1852
871949 | 02 tweede verdieping | 02 tweede verdieping | -2201.86 | Level : 02 tweede verdieping | 2449 | 0.376318 | 2328 | -27 | -94 | 0.00351528 | 1973 | 1906
871950 | 02 tweede verdieping | 02 tweede verdieping | 20648.1 | Level : 02 tweede verdieping | 2449 | 0.376318 | 2328 | -94 | -27 | 0.00351528 | 1906 | 1973
871980 | 02 tweede verdieping | 02 tweede verdieping | 44732.6 | Level : 02 tweede verdieping | 1112 | 0.132886 | 816 | -148 | -148 | 0.00123216 | 1852 | 1852
871981 | 02 tweede verdieping | 02 tweede verdieping | -2201.86 | Level : 02 tweede verdieping | 2449 | 0.376318 | 2328 | -27 | -94 | 0.00351528 | 1973 | 1906
871982 | 02 tweede verdieping | 02 tweede verdieping | 20648.1 | Level : 02 tweede verdieping | 2449 | 0.376318 | 2328 | -94 | -27 | 0.00351528 | 1906 | 1973
872044 | 02 tweede verdieping | 02 tweede verdieping | -25047.4 | Basic Wall : 21_WA_metselwerk_licht_100_gen_bdg | 1112 | 0.132886 | 816 | -148 | -148 | 0.00123216 | 1852 | 1852
872045 | 02 tweede verdieping | 02 tweede verdieping | -22371.1 | Basic Wall : 21_WA_metselwerk_licht_100_gen_bdg | 2449 | 0.376318 | 2328 | -27 | -94 | 0.00351528 | 1973 | 1906
872046 | 02 tweede verdieping | 02 tweede verdieping | 40817.4 | Basic Wall : 21_WA_metselwerk_licht_100_gen_bdg | 2449 | 0.376318 | 2328 | -94 | -27 | 0.00351528 | 1906 | 1973
872079 | 02 tweede verdieping | 02 tweede verdieping | -25047.4 | Basic Wall : 21_WA_metselwerk_licht_100_gen_bdg | 1112 | 0.132886 | 816 | -148 | -148 | 0.00123216 | 1852 | 1852
872080 | 02 tweede verdieping | 02 tweede verdieping | -22508 | Basic Wall : 21_WA_metselwerk_licht_100_gen_bdg | 2449 | 0.376318 | 2328 | -27 | -94 | 0.00351528 | 1973 | 1906
872081 | 02 tweede verdieping | 02 tweede verdieping | 40954.3 | Basic Wall : 21_WA_metselwerk_licht_100_gen_bdg | 2449 | 0.376318 | 2328 | -94 | -27 | 0.00351528 | 1906 | 1973
872805 | 02 tweede verdieping | 02 tweede verdieping | -25047.4 | Level : 02 tweede verdieping | 1112 | 0.132886 | 816 | -148 | -148 | 0.00123216 | 1852 | 1852
872806 | 02 tweede verdieping | 02 tweede verdieping | -22508 | Level : 02 tweede verdieping | 2449 | 0.376318 | 2328 | -27 | -94 | 0.00351528 | 1973 | 1906
872807 | 02 tweede verdieping | 02 tweede verdieping | 40954.3 | Level : 02 tweede verdieping | 2449 | 0.376318 | 2328 | -94 | -27 | 0.00351528 | 1906 | 1973
872838 | 02 tweede verdieping | 02 tweede verdieping | -25047.4 | Level : 02 tweede verdieping | 1112 | 0.132886 | 816 | -148 | -148 | 0.00123216 | 1852 | 1852
872839 | 02 tweede verdieping | 02 tweede verdieping | -22508 | Level : 02 tweede verdieping | 2449 | 0.376318 | 2328 | -27 | -94 | 0.00351528 | 1973 | 1906
872840 | 02 tweede verdieping | 02 tweede verdieping | 40954.3 | Level : 02 tweede verdieping | 2449 | 0.376318 | 2328 | -94 | -27 | 0.00351528 | 1906 | 1973
872871 | 02 tweede verdieping | 02 tweede verdieping | -25047.4 | Level : 02 tweede verdieping | 1112 | 0.132886 | 816 | -148 | -148 | 0.00123216 | 1852 | 1852
872872 | 02 tweede verdieping | 02 tweede verdieping | -22508 | Level : 02 tweede verdieping | 2449 | 0.376318 | 2328 | -27 | -94 | 0.00351528 | 1973 | 1906
872873 | 02 tweede verdieping | 02 tweede verdieping | 40954.3 | Level : 02 tweede verdieping | 2449 | 0.376318 | 2328 | -94 | -27 | 0.00351528 | 1906 | 1973
872970 | 02 tweede verdieping | 02 tweede verdieping | -25047.4 | Level : 02 tweede verdieping | 1112 | 0.132886 | 816 | -148 | -148 | 0.00123216 | 1852 | 1852
872971 | 02 tweede verdieping | 02 tweede verdieping | -22508 | Level : 02 tweede verdieping | 2449 | 0.376318 | 2328 | -27 | -94 | 0.00351528 | 1973 | 1906
872972 | 02 tweede verdieping | 02 tweede verdieping | 40954.3 | Level : 02 tweede verdieping | 2449 | 0.376318 | 2328 | -94 | -27 | 0.00351528 | 1906 | 1973
873003 | 02 tweede verdieping | 02 tweede verdieping | -25047.4 | Level : 02 tweede verdieping | 1112 | 0.132886 | 816 | -148 | -148 | 0.00123216 | 1852 | 1852
873004 | 02 tweede verdieping | 02 tweede verdieping | -22508 | Level : 02 tweede verdieping | 2449 | 0.376318 | 2328 | -27 | -94 | 0.00351528 | 1973 | 1906
873005 | 02 tweede verdieping | 02 tweede verdieping | 40954.3 | Level : 02 tweede verdieping | 2449 | 0.376318 | 2328 | -94 | -27 | 0.00351528 | 1906 | 1973
873036 | 02 tweede verdieping | 02 tweede verdieping | -25047.4 | Level : 02 tweede verdieping | 1112 | 0.132886 | 816 | -148 | -148 | 0.00123216 | 1852 | 1852
873037 | 02 tweede verdieping | 02 tweede verdieping | -22508 | Level : 02 tweede verdieping | 2449 | 0.376318 | 2328 | -27 | -94 | 0.00351528 | 1973 | 1906
873038 | 02 tweede verdieping | 02 tweede verdieping | 40954.3 | Level : 02 tweede verdieping | 2449 | 0.376318 | 2328 | -94 | -27 | 0.00351528 | 1906 | 1973
873069 | 02 tweede verdieping | 02 tweede verdieping | -25047.4 | Level : 02 tweede verdieping | 1112 | 0.132886 | 816 | -148 | -148 | 0.00123216 | 1852 | 1852
873070 | 02 tweede verdieping | 02 tweede verdieping | -22508 | Level : 02 tweede verdieping | 2449 | 0.376318 | 2328 | -27 | -94 | 0.00351528 | 1973 | 1906
873071 | 02 tweede verdieping | 02 tweede verdieping | 40954.3 | Level : 02 tweede verdieping | 2449 | 0.376318 | 2328 | -94 | -27 | 0.00351528 | 1906 | 1973
873102 | 02 tweede verdieping | 02 tweede verdieping | -25047.4 | Level : 02 tweede verdieping | 1112 | 0.132886 | 816 | -148 | -148 | 0.00123216 | 1852 | 1852
873103 | 02 tweede verdieping | 02 tweede verdieping | -22508 | Level : 02 tweede verdieping | 2449 | 0.376318 | 2328 | -27 | -94 | 0.00351528 | 1973 | 1906
873104 | 02 tweede verdieping | 02 tweede verdieping | 40954.3 | Level : 02 tweede verdieping | 2449 | 0.376318 | 2328 | -94 | -27 | 0.00351528 | 1906 | 1973
873413 | 02 tweede verdieping | 02 tweede verdieping | -25047.4 | Level : 02 tweede verdieping | 1112 | 0.132886 | 816 | -148 | -148 | 0.00123216 | 1852 | 1852
873414 | 02 tweede verdieping | 02 tweede verdieping | -22371.1 | Level : 02 tweede verdieping | 2449 | 0.376318 | 2328 | -27 | -94 | 0.00351528 | 1973 | 1906
873415 | 02 tweede verdieping | 02 tweede verdieping | 40817.4 | Level : 02 tweede verdieping | 2449 | 0.376318 | 2328 | -94 | -27 | 0.00351528 | 1906 | 1973
873463 | 02 tweede verdieping | 02 tweede verdieping | -25047.4 | Level : 02 tweede verdieping | 1112 | 0.132886 | 816 | -148 | -148 | 0.00123216 | 1852 | 1852
873464 | 02 tweede verdieping | 02 tweede verdieping | -22371.1 | Level : 02 tweede verdieping | 2449 | 0.376318 | 2328 | -27 | -94 | 0.00351528 | 1973 | 1906
873465 | 02 tweede verdieping | 02 tweede verdieping | 40817.4 | Level : 02 tweede verdieping | 2449 | 0.376318 | 2328 | -94 | -27 | 0.00351528 | 1906 | 1973
873494 | 02 tweede verdieping | 02 tweede verdieping | -25047.4 | Level : 02 tweede verdieping | 1112 | 0.132886 | 816 | -148 | -148 | 0.00123216 | 1852 | 1852
873495 | 02 tweede verdieping | 02 tweede verdieping | -22371.1 | Level : 02 tweede verdieping | 2449 | 0.376318 | 2328 | -27 | -94 | 0.00351528 | 1973 | 1906
873496 | 02 tweede verdieping | 02 tweede verdieping | 40817.4 | Level : 02 tweede verdieping | 2449 | 0.376318 | 2328 | -94 | -27 | 0.00351528 | 1906 | 1973
873525 | 02 tweede verdieping | 02 tweede verdieping | -25047.4 | Level : 02 tweede verdieping | 1112 | 0.132886 | 816 | -148 | -148 | 0.00123216 | 1852 | 1852
873526 | 02 tweede verdieping | 02 tweede verdieping | -22371.1 | Level : 02 tweede verdieping | 2449 | 0.376318 | 2328 | -27 | -94 | 0.00351528 | 1973 | 1906
873527 | 02 tweede verdieping | 02 tweede verdieping | 40817.4 | Level : 02 tweede verdieping | 2449 | 0.376318 | 2328 | -94 | -27 | 0.00351528 | 1906 | 1973
873556 | 02 tweede verdieping | 02 tweede verdieping | -25047.4 | Level : 02 tweede verdieping | 1112 | 0.132886 | 816 | -148 | -148 | 0.00123216 | 1852 | 1852
873557 | 02 tweede verdieping | 02 tweede verdieping | -22371.1 | Level : 02 tweede verdieping | 2449 | 0.376318 | 2328 | -27 | -94 | 0.00351528 | 1973 | 1906
873558 | 02 tweede verdieping | 02 tweede verdieping | 40817.4 | Level : 02 tweede verdieping | 2449 | 0.376318 | 2328 | -94 | -27 | 0.00351528 | 1906 | 1973
873587 | 02 tweede verdieping | 02 tweede verdieping | -25047.4 | Level : 02 tweede verdieping | 1112 | 0.132886 | 816 | -148 | -148 | 0.00123216 | 1852 | 1852
873588 | 02 tweede verdieping | 02 tweede verdieping | -22371.1 | Level : 02 tweede verdieping | 2449 | 0.376318 | 2328 | -27 | -94 | 0.00351528 | 1973 | 1906
873589 | 02 tweede verdieping | 02 tweede verdieping | 40817.4 | Level : 02 tweede verdieping | 2449 | 0.376318 | 2328 | -94 | -27 | 0.00351528 | 1906 | 1973
873618 | 02 tweede verdieping | 02 tweede verdieping | -25047.4 | Level : 02 tweede verdieping | 1112 | 0.132886 | 816 | -148 | -148 | 0.00123216 | 1852 | 1852
873619 | 02 tweede verdieping | 02 tweede verdieping | -22371.1 | Level : 02 tweede verdieping | 2449 | 0.376318 | 2328 | -27 | -94 | 0.00351528 | 1973 | 1906
873620 | 02 tweede verdieping | 02 tweede verdieping | 40817.4 | Level : 02 tweede verdieping | 2449 | 0.376318 | 2328 | -94 | -27 | 0.00351528 | 1906 | 1973
873649 | 02 tweede verdieping | 02 tweede verdieping | -25047.4 | Level : 02 tweede verdieping | 1112 | 0.132886 | 816 | -148 | -148 | 0.00123216 | 1852 | 1852
873650 | 02 tweede verdieping | 02 tweede verdieping | -22371.1 | Level : 02 tweede verdieping | 2449 | 0.376318 | 2328 | -27 | -94 | 0.00351528 | 1973 | 1906
873651 | 02 tweede verdieping | 02 tweede verdieping | 40817.4 | Level : 02 tweede verdieping | 2449 | 0.376318 | 2328 | -94 | -27 | 0.00351528 | 1906 | 1973
873680 | 02 tweede verdieping | 02 tweede verdieping | -25047.4 | Level : 02 tweede verdieping | 1112 | 0.132886 | 816 | -148 | -148 | 0.00123216 | 1852 | 1852
873681 | 02 tweede verdieping | 02 tweede verdieping | -22371.1 | Level : 02 tweede verdieping | 2449 | 0.376318 | 2328 | -27 | -94 | 0.00351528 | 1973 | 1906
873682 | 02 tweede verdieping | 02 tweede verdieping | 40817.4 | Level : 02 tweede verdieping | 2449 | 0.376318 | 2328 | -94 | -27 | 0.00351528 | 1906 | 1973
873711 | 02 tweede verdieping | 02 tweede verdieping | -25047.4 | Level : 02 tweede verdieping | 1112 | 0.132886 | 816 | -148 | -148 | 0.00123216 | 1852 | 1852
873712 | 02 tweede verdieping | 02 tweede verdieping | -22371.1 | Level : 02 tweede verdieping | 2449 | 0.376318 | 2328 | -27 | -94 | 0.00351528 | 1973 | 1906
873713 | 02 tweede verdieping | 02 tweede verdieping | 40817.4 | Level : 02 tweede verdieping | 2449 | 0.376318 | 2328 | -94 | -27 | 0.00351528 | 1906 | 1973
873742 | 02 tweede verdieping | 02 tweede verdieping | -25047.4 | Level : 02 tweede verdieping | 1112 | 0.132886 | 816 | -148 | -148 | 0.00123216 | 1852 | 1852
873743 | 02 tweede verdieping | 02 tweede verdieping | -22371.1 | Level : 02 tweede verdieping | 2449 | 0.376318 | 2328 | -27 | -94 | 0.00351528 | 1973 | 1906
873744 | 02 tweede verdieping | 02 tweede verdieping | 40817.4 | Level : 02 tweede verdieping | 2449 | 0.376318 | 2328 | -94 | -27 | 0.00351528 | 1906 | 1973
874908 | 01 eerste verdieping | 01 eerste verdieping | -3882.36 | Level : 01 eerste verdieping | 2000 | 0.281972 | 1742 | -129 | -129 | 0.00263042 | 1871 | 1871
874909 | 01 eerste verdieping | 01 eerste verdieping | -16409.4 | Level : 01 eerste verdieping | 2079 | 0.316748 | 1958 | -27 | -94 | 0.00295658 | 1973 | 1906
874910 | 01 eerste verdieping | 01 eerste verdieping | 27320.6 | Level : 01 eerste verdieping | 2079 | 0.316748 | 1958 | -94 | -27 | 0.00295658 | 1906 | 1973
874920 | 01 eerste verdieping | 01 eerste verdieping | -3882.36 | Level : 01 eerste verdieping | 2000 | 0.281972 | 1742 | -129 | -129 | 0.00263042 | 1871 | 1871
874921 | 01 eerste verdieping | 01 eerste verdieping | -16409.4 | Level : 01 eerste verdieping | 2079 | 0.316748 | 1958 | -27 | -94 | 0.00295658 | 1973 | 1906
874922 | 01 eerste verdieping | 01 eerste verdieping | 27320.6 | Level : 01 eerste verdieping | 2079 | 0.316748 | 1958 | -94 | -27 | 0.00295658 | 1906 | 1973
874932 | 01 eerste verdieping | 01 eerste verdieping | -3882.36 | Level : 01 eerste verdieping | 2000 | 0.281972 | 1742 | -129 | -129 | 0.00263042 | 1871 | 1871
874933 | 01 eerste verdieping | 01 eerste verdieping | -16409.4 | Level : 01 eerste verdieping | 2079 | 0.316748 | 1958 | -27 | -94 | 0.00295658 | 1973 | 1906
874934 | 01 eerste verdieping | 01 eerste verdieping | 27320.6 | Level : 01 eerste verdieping | 2079 | 0.316748 | 1958 | -94 | -27 | 0.00295658 | 1906 | 1973
874998 | 01 eerste verdieping | 01 eerste verdieping | -3882.36 | Level : 01 eerste verdieping | 2000 | 0.281972 | 1742 | -129 | -129 | 0.00263042 | 1871 | 1871
874999 | 01 eerste verdieping | 01 eerste verdieping | -16409.4 | Level : 01 eerste verdieping | 2079 | 0.316748 | 1958 | -27 | -94 | 0.00295658 | 1973 | 1906
875000 | 01 eerste verdieping | 01 eerste verdieping | 27320.6 | Level : 01 eerste verdieping | 2079 | 0.316748 | 1958 | -94 | -27 | 0.00295658 | 1906 | 1973
875010 | 01 eerste verdieping | 01 eerste verdieping | -3882.36 | Level : 01 eerste verdieping | 2000 | 0.281972 | 1742 | -129 | -129 | 0.00263042 | 1871 | 1871
875011 | 01 eerste verdieping | 01 eerste verdieping | -16409.4 | Level : 01 eerste verdieping | 2079 | 0.316748 | 1958 | -27 | -94 | 0.00295658 | 1973 | 1906
875012 | 01 eerste verdieping | 01 eerste verdieping | 27320.6 | Level : 01 eerste verdieping | 2079 | 0.316748 | 1958 | -94 | -27 | 0.00295658 | 1906 | 1973
875022 | 01 eerste verdieping | 01 eerste verdieping | -3882.36 | Level : 01 eerste verdieping | 2000 | 0.281972 | 1742 | -129 | -129 | 0.00263042 | 1871 | 1871
875023 | 01 eerste verdieping | 01 eerste verdieping | -16409.4 | Level : 01 eerste verdieping | 2079 | 0.316748 | 1958 | -27 | -94 | 0.00295658 | 1973 | 1906
875024 | 01 eerste verdieping | 01 eerste verdieping | 27320.6 | Level : 01 eerste verdieping | 2079 | 0.316748 | 1958 | -94 | -27 | 0.00295658 | 1906 | 1973
875227 | 01 eerste verdieping | 01 eerste verdieping | -3882.36 | Level : 01 eerste verdieping | 2000 | 0.281972 | 1742 | -129 | -129 | 0.00263042 | 1871 | 1871
875228 | 01 eerste verdieping | 01 eerste verdieping | -16409.4 | Level : 01 eerste verdieping | 2079 | 0.316748 | 1958 | -27 | -94 | 0.00295658 | 1973 | 1906
875229 | 01 eerste verdieping | 01 eerste verdieping | 27320.6 | Level : 01 eerste verdieping | 2079 | 0.316748 | 1958 | -94 | -27 | 0.00295658 | 1906 | 1973
875263 | 01 eerste verdieping | 01 eerste verdieping | -3882.36 | Level : 01 eerste verdieping | 2000 | 0.281972 | 1742 | -129 | -129 | 0.00263042 | 1871 | 1871
875264 | 01 eerste verdieping | 01 eerste verdieping | -16409.4 | Level : 01 eerste verdieping | 2079 | 0.316748 | 1958 | -27 | -94 | 0.00295658 | 1973 | 1906
875265 | 01 eerste verdieping | 01 eerste verdieping | 27320.6 | Level : 01 eerste verdieping | 2079 | 0.316748 | 1958 | -94 | -27 | 0.00295658 | 1906 | 1973
875299 | 01 eerste verdieping | 01 eerste verdieping | -3882.36 | Level : 01 eerste verdieping | 2000 | 0.281972 | 1742 | -129 | -129 | 0.00263042 | 1871 | 1871
875300 | 01 eerste verdieping | 01 eerste verdieping | -16409.4 | Level : 01 eerste verdieping | 2079 | 0.316748 | 1958 | -27 | -94 | 0.00295658 | 1973 | 1906
875301 | 01 eerste verdieping | 01 eerste verdieping | 27320.6 | Level : 01 eerste verdieping | 2079 | 0.316748 | 1958 | -94 | -27 | 0.00295658 | 1906 | 1973
875335 | 01 eerste verdieping | 01 eerste verdieping | -3882.36 | Level : 01 eerste verdieping | 2000 | 0.281972 | 1742 | -129 | -129 | 0.00263042 | 1871 | 1871
875336 | 01 eerste verdieping | 01 eerste verdieping | -16409.4 | Level : 01 eerste verdieping | 2079 | 0.316748 | 1958 | -27 | -94 | 0.00295658 | 1973 | 1906
875337 | 01 eerste verdieping | 01 eerste verdieping | 27320.6 | Level : 01 eerste verdieping | 2079 | 0.316748 | 1958 | -94 | -27 | 0.00295658 | 1906 | 1973
875371 | 01 eerste verdieping | 01 eerste verdieping | -3882.36 | Level : 01 eerste verdieping | 2000 | 0.281972 | 1742 | -129 | -129 | 0.00263042 | 1871 | 1871
875372 | 01 eerste verdieping | 01 eerste verdieping | -16409.4 | Level : 01 eerste verdieping | 2079 | 0.316748 | 1958 | -27 | -94 | 0.00295658 | 1973 | 1906
875373 | 01 eerste verdieping | 01 eerste verdieping | 27320.6 | Level : 01 eerste verdieping | 2079 | 0.316748 | 1958 | -94 | -27 | 0.00295658 | 1906 | 1973
876536 | 01 eerste verdieping | 01 eerste verdieping | 40882.6 | Level : 01 eerste verdieping | 2000 | 0.281972 | 1742 | -129 | -129 | 0.00263042 | 1871 | 1871
876537 | 01 eerste verdieping | 01 eerste verdieping | 28778.1 | Level : 01 eerste verdieping | 2079 | 0.316748 | 1958 | -27 | -94 | 0.00295658 | 1973 | 1906
876538 | 01 eerste verdieping | 01 eerste verdieping | -17931.9 | Level : 01 eerste verdieping | 2079 | 0.316748 | 1958 | -94 | -27 | 0.00295658 | 1906 | 1973
876773 | 01 eerste verdieping | 01 eerste verdieping | 40882.6 | Level : 01 eerste verdieping | 2000 | 0.281972 | 1742 | -129 | -129 | 0.00263042 | 1871 | 1871
876774 | 01 eerste verdieping | 01 eerste verdieping | 28778.1 | Level : 01 eerste verdieping | 2079 | 0.316748 | 1958 | -27 | -94 | 0.00295658 | 1973 | 1906
876775 | 01 eerste verdieping | 01 eerste verdieping | -17931.9 | Level : 01 eerste verdieping | 2079 | 0.316748 | 1958 | -94 | -27 | 0.00295658 | 1906 | 1973
876792 | 01 eerste verdieping | 01 eerste verdieping | 40882.6 | Level : 01 eerste verdieping | 2000 | 0.281972 | 1742 | -129 | -129 | 0.00263042 | 1871 | 1871
876793 | 01 eerste verdieping | 01 eerste verdieping | 28778.1 | Level : 01 eerste verdieping | 2079 | 0.316748 | 1958 | -27 | -94 | 0.00295658 | 1973 | 1906
876794 | 01 eerste verdieping | 01 eerste verdieping | -17931.9 | Level : 01 eerste verdieping | 2079 | 0.316748 | 1958 | -94 | -27 | 0.00295658 | 1906 | 1973
876938 | 01 eerste verdieping | 01 eerste verdieping | 40882.6 | Level : 01 eerste verdieping | 2000 | 0.281972 | 1742 | -129 | -129 | 0.00263042 | 1871 | 1871
876939 | 01 eerste verdieping | 01 eerste verdieping | 28778.1 | Level : 01 eerste verdieping | 2079 | 0.316748 | 1958 | -27 | -94 | 0.00295658 | 1973 | 1906
876940 | 01 eerste verdieping | 01 eerste verdieping | -17931.9 | Level : 01 eerste verdieping | 2079 | 0.316748 | 1958 | -94 | -27 | 0.00295658 | 1906 | 1973
876950 | 01 eerste verdieping | 01 eerste verdieping | 40882.6 | Level : 01 eerste verdieping | 2000 | 0.281972 | 1742 | -129 | -129 | 0.00263042 | 1871 | 1871
876951 | 01 eerste verdieping | 01 eerste verdieping | 28778.1 | Level : 01 eerste verdieping | 2079 | 0.316748 | 1958 | -27 | -94 | 0.00295658 | 1973 | 1906
876952 | 01 eerste verdieping | 01 eerste verdieping | -17931.9 | Level : 01 eerste verdieping | 2079 | 0.316748 | 1958 | -94 | -27 | 0.00295658 | 1906 | 1973
876962 | 01 eerste verdieping | 01 eerste verdieping | 40882.6 | Level : 01 eerste verdieping | 2000 | 0.281972 | 1742 | -129 | -129 | 0.00263042 | 1871 | 1871
876963 | 01 eerste verdieping | 01 eerste verdieping | 28778.1 | Level : 01 eerste verdieping | 2079 | 0.316748 | 1958 | -27 | -94 | 0.00295658 | 1973 | 1906
876964 | 01 eerste verdieping | 01 eerste verdieping | -17931.9 | Level : 01 eerste verdieping | 2079 | 0.316748 | 1958 | -94 | -27 | 0.00295658 | 1906 | 1973
877055 | 01 eerste verdieping | 01 eerste verdieping | 40882.6 | Level : 01 eerste verdieping | 2000 | 0.281972 | 1742 | -129 | -129 | 0.00263042 | 1871 | 1871
877056 | 01 eerste verdieping | 01 eerste verdieping | 28778.1 | Level : 01 eerste verdieping | 2079 | 0.316748 | 1958 | -27 | -94 | 0.00295658 | 1973 | 1906
877057 | 01 eerste verdieping | 01 eerste verdieping | -17931.9 | Level : 01 eerste verdieping | 2079 | 0.316748 | 1958 | -94 | -27 | 0.00295658 | 1906 | 1973
877067 | 01 eerste verdieping | 01 eerste verdieping | 40882.6 | Level : 01 eerste verdieping | 2000 | 0.281972 | 1742 | -129 | -129 | 0.00263042 | 1871 | 1871
877068 | 01 eerste verdieping | 01 eerste verdieping | 28778.1 | Level : 01 eerste verdieping | 2079 | 0.316748 | 1958 | -27 | -94 | 0.00295658 | 1973 | 1906
877069 | 01 eerste verdieping | 01 eerste verdieping | -17931.9 | Level : 01 eerste verdieping | 2079 | 0.316748 | 1958 | -94 | -27 | 0.00295658 | 1906 | 1973
877079 | 01 eerste verdieping | 01 eerste verdieping | 40882.6 | Level : 01 eerste verdieping | 2000 | 0.281972 | 1742 | -129 | -129 | 0.00263042 | 1871 | 1871
877080 | 01 eerste verdieping | 01 eerste verdieping | 28778.1 | Level : 01 eerste verdieping | 2079 | 0.316748 | 1958 | -27 | -94 | 0.00295658 | 1973 | 1906
877081 | 01 eerste verdieping | 01 eerste verdieping | -17931.9 | Level : 01 eerste verdieping | 2079 | 0.316748 | 1958 | -94 | -27 | 0.00295658 | 1906 | 1973
877145 | 01 eerste verdieping | 01 eerste verdieping | 40882.6 | Level : 01 eerste verdieping | 2000 | 0.281972 | 1742 | -129 | -129 | 0.00263042 | 1871 | 1871
877146 | 01 eerste verdieping | 01 eerste verdieping | 28778.1 | Level : 01 eerste verdieping | 2079 | 0.316748 | 1958 | -27 | -94 | 0.00295658 | 1973 | 1906
877147 | 01 eerste verdieping | 01 eerste verdieping | -17931.9 | Level : 01 eerste verdieping | 2079 | 0.316748 | 1958 | -94 | -27 | 0.00295658 | 1906 | 1973
877157 | 01 eerste verdieping | 01 eerste verdieping | 40882.6 | Level : 01 eerste verdieping | 2000 | 0.281972 | 1742 | -129 | -129 | 0.00263042 | 1871 | 1871
877158 | 01 eerste verdieping | 01 eerste verdieping | 28778.1 | Level : 01 eerste verdieping | 2079 | 0.316748 | 1958 | -27 | -94 | 0.00295658 | 1973 | 1906
877159 | 01 eerste verdieping | 01 eerste verdieping | -17931.9 | Level : 01 eerste verdieping | 2079 | 0.316748 | 1958 | -94 | -27 | 0.00295658 | 1906 | 1973
877169 | 01 eerste verdieping | 01 eerste verdieping | 40882.6 | Level : 01 eerste verdieping | 2000 | 0.281972 | 1742 | -129 | -129 | 0.00263042 | 1871 | 1871
877170 | 01 eerste verdieping | 01 eerste verdieping | 28778.1 | Level : 01 eerste verdieping | 2079 | 0.316748 | 1958 | -27 | -94 | 0.00295658 | 1973 | 1906
877171 | 01 eerste verdieping | 01 eerste verdieping | -17931.9 | Level : 01 eerste verdieping | 2079 | 0.316748 | 1958 | -94 | -27 | 0.00295658 | 1906 | 1973
877235 | 01 eerste verdieping | 01 eerste verdieping | 40882.6 | Level : 01 eerste verdieping | 2000 | 0.281972 | 1742 | -129 | -129 | 0.00263042 | 1871 | 1871
877236 | 01 eerste verdieping | 01 eerste verdieping | 28778.1 | Level : 01 eerste verdieping | 2079 | 0.316748 | 1958 | -27 | -94 | 0.00295658 | 1973 | 1906
877237 | 01 eerste verdieping | 01 eerste verdieping | -17931.9 | Level : 01 eerste verdieping | 2079 | 0.316748 | 1958 | -94 | -27 | 0.00295658 | 1906 | 1973
877247 | 01 eerste verdieping | 01 eerste verdieping | 40882.6 | Level : 01 eerste verdieping | 2000 | 0.281972 | 1742 | -129 | -129 | 0.00263042 | 1871 | 1871
877248 | 01 eerste verdieping | 01 eerste verdieping | 28778.1 | Level : 01 eerste verdieping | 2079 | 0.316748 | 1958 | -27 | -94 | 0.00295658 | 1973 | 1906
877249 | 01 eerste verdieping | 01 eerste verdieping | -17931.9 | Level : 01 eerste verdieping | 2079 | 0.316748 | 1958 | -94 | -27 | 0.00295658 | 1906 | 1973
881637 | 01 eerste verdieping | 01 eerste verdieping | 16792.6 | Level : 01 eerste verdieping | 2000 | 0.281972 | 1742 | -129 | -129 | 0.00263042 | 1871 | 1871
881638 | 01 eerste verdieping | 01 eerste verdieping | -26974.3 | Level : 01 eerste verdieping | 2029 | 0.308698 | 1908 | -27 | -94 | 0.00288108 | 1973 | 1906
881639 | 01 eerste verdieping | 01 eerste verdieping | 38820.6 | Level : 01 eerste verdieping | 2029 | 0.308698 | 1908 | -94 | -27 | 0.00288108 | 1906 | 1973
881673 | 01 eerste verdieping | 01 eerste verdieping | 16792.6 | Level : 01 eerste verdieping | 2000 | 0.281972 | 1742 | -129 | -129 | 0.00263042 | 1871 | 1871
881674 | 01 eerste verdieping | 01 eerste verdieping | -26974.3 | Level : 01 eerste verdieping | 2079 | 0.316748 | 1958 | -27 | -94 | 0.00295658 | 1973 | 1906
881675 | 01 eerste verdieping | 01 eerste verdieping | 38820.6 | Level : 01 eerste verdieping | 2079 | 0.316748 | 1958 | -94 | -27 | 0.00295658 | 1906 | 1973
881749 | 01 eerste verdieping | 01 eerste verdieping | 16792.6 | Level : 01 eerste verdieping | 2000 | 0.281972 | 1742 | -129 | -129 | 0.00263042 | 1871 | 1871
881750 | 01 eerste verdieping | 01 eerste verdieping | -26974.3 | Level : 01 eerste verdieping | 2079 | 0.316748 | 1958 | -27 | -94 | 0.00295658 | 1973 | 1906
881751 | 01 eerste verdieping | 01 eerste verdieping | 38820.6 | Level : 01 eerste verdieping | 2079 | 0.316748 | 1958 | -94 | -27 | 0.00295658 | 1906 | 1973
881776 | 01 eerste verdieping | 01 eerste verdieping | 16792.6 | Level : 01 eerste verdieping | 2000 | 0.281972 | 1742 | -129 | -129 | 0.00263042 | 1871 | 1871
881777 | 01 eerste verdieping | 01 eerste verdieping | -26974.3 | Level : 01 eerste verdieping | 2079 | 0.316748 | 1958 | -27 | -94 | 0.00295658 | 1973 | 1906
881778 | 01 eerste verdieping | 01 eerste verdieping | 38820.6 | Level : 01 eerste verdieping | 2079 | 0.316748 | 1958 | -94 | -27 | 0.00295658 | 1906 | 1973
891626 | 01 eerste verdieping | 01 eerste verdieping | 16792.6 | Level : 01 eerste verdieping | 637.5 | 0.0647025 | 392.5 | -45 | -200 | 0.000592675 | 1955 | 1800
891628 | 01 eerste verdieping | 01 eerste verdieping | 38820.6 | Level : 01 eerste verdieping | 2079 | 0.316748 | 1958 | -94 | -27 | 0.00295658 | 1906 | 1973
891648 | 01 eerste verdieping | 01 eerste verdieping | 16792.6 | Level : 01 eerste verdieping | 2000 | 0.281972 | 1742 | -129 | -129 | 0.00263042 | 1871 | 1871
891649 | 01 eerste verdieping | 01 eerste verdieping | -26974.3 | Level : 01 eerste verdieping | 2079 | 0.316748 | 1958 | -27 | -94 | 0.00295658 | 1973 | 1906
891650 | 01 eerste verdieping | 01 eerste verdieping | 38820.6 | Level : 01 eerste verdieping | 2079 | 0.316748 | 1958 | -94 | -27 | 0.00295658 | 1906 | 1973
891670 | 01 eerste verdieping | 01 eerste verdieping | 16792.6 | Level : 01 eerste verdieping | 2000 | 0.281972 | 1742 | -129 | -129 | 0.00263042 | 1871 | 1871
891671 | 01 eerste verdieping | 01 eerste verdieping | -26974.3 | Level : 01 eerste verdieping | 2079 | 0.316748 | 1958 | -27 | -94 | 0.00295658 | 1973 | 1906
891672 | 01 eerste verdieping | 01 eerste verdieping | 38820.6 | Level : 01 eerste verdieping | 2079 | 0.316748 | 1958 | -94 | -27 | 0.00295658 | 1906 | 1973
891692 | 01 eerste verdieping | 01 eerste verdieping | 16792.6 | Level : 01 eerste verdieping | 2000 | 0.281972 | 1742 | -129 | -129 | 0.00263042 | 1871 | 1871
891693 | 01 eerste verdieping | 01 eerste verdieping | -26974.3 | Level : 01 eerste verdieping | 2079 | 0.316748 | 1958 | -27 | -94 | 0.00295658 | 1973 | 1906
891694 | 01 eerste verdieping | 01 eerste verdieping | 38820.6 | Level : 01 eerste verdieping | 2079 | 0.316748 | 1958 | -94 | -27 | 0.00295658 | 1906 | 1973
891714 | 01 eerste verdieping | 01 eerste verdieping | 16792.6 | Level : 01 eerste verdieping | 2000 | 0.281972 | 1742 | -129 | -129 | 0.00263042 | 1871 | 1871
891715 | 01 eerste verdieping | 01 eerste verdieping | -26974.3 | Level : 01 eerste verdieping | 2079 | 0.316748 | 1958 | -27 | -94 | 0.00295658 | 1973 | 1906
891716 | 01 eerste verdieping | 01 eerste verdieping | 38820.6 | Level : 01 eerste verdieping | 2079 | 0.316748 | 1958 | -94 | -27 | 0.00295658 | 1906 | 1973
891754 | 01 eerste verdieping | 01 eerste verdieping | 47298.7 | Basic Wall : 21_WA_metselwerk_licht_100_gen_bdg | 2000 | 0.281972 | 1742 | -129 | -129 | 0.00263042 | 1871 | 1871
891755 | 01 eerste verdieping | 01 eerste verdieping | -3326.48 | Basic Wall : 21_WA_metselwerk_licht_100_gen_bdg | 2079 | 0.316748 | 1958 | -27 | -94 | 0.00295658 | 1973 | 1906
891756 | 01 eerste verdieping | 01 eerste verdieping | 17904.9 | Basic Wall : 21_WA_metselwerk_licht_100_gen_bdg | 2079 | 0.316748 | 1958 | -94 | -27 | 0.00295658 | 1906 | 1973
891782 | 01 eerste verdieping | 01 eerste verdieping | 47298.7 | Level : 01 eerste verdieping | 2000 | 0.281972 | 1742 | -129 | -129 | 0.00263042 | 1871 | 1871
891783 | 01 eerste verdieping | 01 eerste verdieping | -3326.48 | Level : 01 eerste verdieping | 2079 | 0.316748 | 1958 | -27 | -94 | 0.00295658 | 1973 | 1906
891784 | 01 eerste verdieping | 01 eerste verdieping | 17904.9 | Level : 01 eerste verdieping | 2079 | 0.316748 | 1958 | -94 | -27 | 0.00295658 | 1906 | 1973
891899 | 01 eerste verdieping | 01 eerste verdieping | 47298.7 | Level : 01 eerste verdieping | 2000 | 0.281972 | 1742 | -129 | -129 | 0.00263042 | 1871 | 1871
891900 | 01 eerste verdieping | 01 eerste verdieping | -3326.48 | Level : 01 eerste verdieping | 2079 | 0.316748 | 1958 | -27 | -94 | 0.00295658 | 1973 | 1906
891901 | 01 eerste verdieping | 01 eerste verdieping | 17904.9 | Level : 01 eerste verdieping | 2079 | 0.316748 | 1958 | -94 | -27 | 0.00295658 | 1906 | 1973
891921 | 01 eerste verdieping | 01 eerste verdieping | 47298.7 | Level : 01 eerste verdieping | 2000 | 0.281972 | 1742 | -129 | -129 | 0.00263042 | 1871 | 1871
891922 | 01 eerste verdieping | 01 eerste verdieping | -3326.48 | Level : 01 eerste verdieping | 2079 | 0.316748 | 1958 | -27 | -94 | 0.00295658 | 1973 | 1906
891923 | 01 eerste verdieping | 01 eerste verdieping | 17904.9 | Level : 01 eerste verdieping | 2079 | 0.316748 | 1958 | -94 | -27 | 0.00295658 | 1906 | 1973
891943 | 01 eerste verdieping | 01 eerste verdieping | 47298.7 | Level : 01 eerste verdieping | 2000 | 0.30902 | 1910 | -45 | -45 | 0.0028841 | 1955 | 1955
891944 | 01 eerste verdieping | 01 eerste verdieping | -3326.48 | Level : 01 eerste verdieping | 2643 | 0.416568 | 2578 | -27 | -38 | 0.00389278 | 1973 | 1962
891945 | 01 eerste verdieping | 01 eerste verdieping | 17904.9 | Level : 01 eerste verdieping | 2643 | 0.416568 | 2578 | -38 | -27 | 0.00389278 | 1962 | 1973
891971 | 01 eerste verdieping | 01 eerste verdieping | 47298.7 | Level : 01 eerste verdieping | 2000 | 0.281972 | 1742 | -129 | -129 | 0.00263042 | 1871 | 1871
891972 | 01 eerste verdieping | 01 eerste verdieping | -3326.48 | Level : 01 eerste verdieping | 2079 | 0.316748 | 1958 | -27 | -94 | 0.00295658 | 1973 | 1906
891973 | 01 eerste verdieping | 01 eerste verdieping | 17904.9 | Level : 01 eerste verdieping | 2079 | 0.316748 | 1958 | -94 | -27 | 0.00295658 | 1906 | 1973
897888 | 00 begane grond | 00 begane grond | -8507.36 | Basic Wall : NLRS_22_WA_HSB bispouw 30-245-12-13 glaswol_gen_ISR | 1942 | 0.261042 | 1612 | -165 | -165 | 0.00243412 | 1835 | 1835
897889 | 00 begane grond | 00 begane grond | -22996.9 | Basic Wall : NLRS_22_WA_HSB bispouw 30-245-12-13 glaswol_gen_ISR | 3081 | 0.483061 | 2991 | -27 | -63 | 0.00451641 | 1973 | 1937
897890 | 00 begane grond | 00 begane grond | 25843.1 | Basic Wall : NLRS_22_WA_HSB bispouw 30-245-12-13 glaswol_gen_ISR | 3081 | 0.483061 | 2991 | -63 | -27 | 0.00451641 | 1937 | 1973
897941 | 00 begane grond | 00 begane grond | -8507.36 | Basic Wall : NLRS_22_WA_HSB bispouw 30-245-12-13 glaswol_gen_ISR | 1162 | 0.135462 | 832 | -165 | -165 | 0.00125632 | 1835 | 1835
897942 | 00 begane grond | 00 begane grond | -24616.9 | Basic Wall : NLRS_22_WA_HSB bispouw 30-245-12-13 glaswol_gen_ISR | 3081 | 0.483061 | 2991 | -27 | -63 | 0.00451641 | 1973 | 1937
897943 | 00 begane grond | 00 begane grond | 27463.1 | Basic Wall : NLRS_22_WA_HSB bispouw 30-245-12-13 glaswol_gen_ISR | 3081 | 0.483061 | 2991 | -63 | -27 | 0.00451641 | 1937 | 1973
898549 | 00 begane grond | 00 begane grond | -8507.36 | Basic Wall : NLRS_22_WA_HSB bispouw 30-245-12-13 glaswol_gen_ISR | 2362 | 0.328662 | 2032 | -165 | -165 | 0.00306832 | 1835 | 1835
898550 | 00 begane grond | 00 begane grond | -22996.9 | Basic Wall : NLRS_22_WA_HSB bispouw 30-245-12-13 glaswol_gen_ISR | 3081 | 0.483061 | 2991 | -27 | -63 | 0.00451641 | 1973 | 1937
898551 | 00 begane grond | 00 begane grond | 25843.1 | Basic Wall : NLRS_22_WA_HSB bispouw 30-245-12-13 glaswol_gen_ISR | 3081 | 0.483061 | 2991 | -63 | -27 | 0.00451641 | 1937 | 1973
898561 | 00 begane grond | 00 begane grond | -8507.36 | Basic Wall : NLRS_22_WA_HSB bispouw 30-245-12-13 glaswol_gen_ISR | 1762 | 0.232062 | 1432 | -165 | -165 | 0.00216232 | 1835 | 1835
898562 | 00 begane grond | 00 begane grond | -24616.9 | Basic Wall : NLRS_22_WA_HSB bispouw 30-245-12-13 glaswol_gen_ISR | 3081 | 0.483061 | 2991 | -27 | -63 | 0.00451641 | 1973 | 1937
898563 | 00 begane grond | 00 begane grond | 27463.1 | Basic Wall : NLRS_22_WA_HSB bispouw 30-245-12-13 glaswol_gen_ISR | 3081 | 0.483061 | 2991 | -63 | -27 | 0.00451641 | 1937 | 1973
1219787 | 00 begane grond | 00 begane grond | -8507.36 | Basic Wall : NLRS_22_WA_HSB bispouw 30-245-12-13 glaswol_gen_ISR | 2062 | 0.280362 | 1732 | -165 | -165 | 0.00261532 | 1835 | 1835
1219788 | 00 begane grond | 00 begane grond | -24616.9 | Basic Wall : NLRS_22_WA_HSB bispouw 30-245-12-13 glaswol_gen_ISR | 3081 | 0.483061 | 2991 | -27 | -63 | 0.00451641 | 1973 | 1937
1219789 | 00 begane grond | 00 begane grond | 27463.1 | Basic Wall : NLRS_22_WA_HSB bispouw 30-245-12-13 glaswol_gen_ISR | 3081 | 0.483061 | 2991 | -63 | -27 | 0.00451641 | 1937 | 1973
1220537 | 00 begane grond | 00 begane grond | -8507.36 | Basic Wall : NLRS_22_WA_HSB bispouw 30-245-12-13 glaswol_gen_ISR | 3262 | 0.473562 | 2932 | -165 | -165 | 0.00442732 | 1835 | 1835
1220538 | 00 begane grond | 00 begane grond | -22996.9 | Basic Wall : NLRS_22_WA_HSB bispouw 30-245-12-13 glaswol_gen_ISR | 3081 | 0.483061 | 2991 | -27 | -63 | 0.00451641 | 1973 | 1937
1220539 | 00 begane grond | 00 begane grond | 25843.1 | Basic Wall : NLRS_22_WA_HSB bispouw 30-245-12-13 glaswol_gen_ISR | 3081 | 0.483061 | 2991 | -63 | -27 | 0.00451641 | 1937 | 1973
1221371 | 00 begane grond | 00 begane grond | -8507.36 | Basic Wall : NLRS_22_WA_HSB bispouw 30-245-12-13 glaswol_gen_ISR | 1162 | 0.135462 | 832 | -165 | -165 | 0.00125632 | 1835 | 1835
1221372 | 00 begane grond | 00 begane grond | -22996.9 | Basic Wall : NLRS_22_WA_HSB bispouw 30-245-12-13 glaswol_gen_ISR | 3081 | 0.483061 | 2991 | -27 | -63 | 0.00451641 | 1973 | 1937
1221373 | 00 begane grond | 00 begane grond | 25843.1 | Basic Wall : NLRS_22_WA_HSB bispouw 30-245-12-13 glaswol_gen_ISR | 3081 | 0.483061 | 2991 | -63 | -27 | 0.00451641 | 1937 | 1973
1221382 | 00 begane grond | 00 begane grond | -8507.36 | Basic Wall : NLRS_22_WA_HSB bispouw 30-245-12-13 glaswol_gen_ISR | 3228 | 0.468088 | 2898 | -165 | -165 | 0.00437598 | 1835 | 1835
1221383 | 00 begane grond | 00 begane grond | -24616.9 | Basic Wall : NLRS_22_WA_HSB bispouw 30-245-12-13 glaswol_gen_ISR | 3081 | 0.483061 | 2991 | -27 | -63 | 0.00451641 | 1973 | 1937
1221384 | 00 begane grond | 00 begane grond | 27463.1 | Basic Wall : NLRS_22_WA_HSB bispouw 30-245-12-13 glaswol_gen_ISR | 3081 | 0.483061 | 2991 | -63 | -27 | 0.00451641 | 1937 | 1973
1221603 | 00 begane grond | 00 begane grond | -8507.36 | Basic Wall : NLRS_22_WA_HSB bispouw 30-245-12-13 glaswol_gen_ISR | 3562 | 0.521862 | 3232 | -165 | -165 | 0.00488032 | 1835 | 1835
1221604 | 00 begane grond | 00 begane grond | -22996.9 | Basic Wall : NLRS_22_WA_HSB bispouw 30-245-12-13 glaswol_gen_ISR | 3081 | 0.483061 | 2991 | -27 | -63 | 0.00451641 | 1973 | 1937
1221605 | 00 begane grond | 00 begane grond | 25843.1 | Basic Wall : NLRS_22_WA_HSB bispouw 30-245-12-13 glaswol_gen_ISR | 3081 | 0.483061 | 2991 | -63 | -27 | 0.00451641 | 1937 | 1973
1222358 | 00 begane grond | 00 begane grond | -8507.36 | Basic Wall : NLRS_22_WA_HSB bispouw 30-245-12-13 glaswol_gen_ISR | 1162 | 0.135462 | 832 | -165 | -165 | 0.00125632 | 1835 | 1835
1222359 | 00 begane grond | 00 begane grond | -22996.9 | Basic Wall : NLRS_22_WA_HSB bispouw 30-245-12-13 glaswol_gen_ISR | 3081 | 0.483061 | 2991 | -27 | -63 | 0.00451641 | 1973 | 1937
1222360 | 00 begane grond | 00 begane grond | 25843.1 | Basic Wall : NLRS_22_WA_HSB bispouw 30-245-12-13 glaswol_gen_ISR | 3081 | 0.483061 | 2991 | -63 | -27 | 0.00451641 | 1937 | 1973
1222800 | 00 begane grond | 00 begane grond | -8507.36 | Basic Wall : NLRS_22_WA_HSB bispouw 30-245-12-13 glaswol_gen_ISR | 1162 | 0.135462 | 832 | -165 | -165 | 0.00125632 | 1835 | 1835
1222801 | 00 begane grond | 00 begane grond | -22996.9 | Basic Wall : NLRS_22_WA_HSB bispouw 30-245-12-13 glaswol_gen_ISR | 3081 | 0.483061 | 2991 | -27 | -63 | 0.00451641 | 1973 | 1937
1222802 | 00 begane grond | 00 begane grond | 25843.1 | Basic Wall : NLRS_22_WA_HSB bispouw 30-245-12-13 glaswol_gen_ISR | 3081 | 0.483061 | 2991 | -63 | -27 | 0.00451641 | 1937 | 1973
1223377 | 00 begane grond | 00 begane grond | -8507.36 | Basic Wall : NLRS_22_WA_HSB bispouw 30-245-12-13 glaswol_gen_ISR | 2962 | 0.425262 | 2632 | -165 | -165 | 0.00397432 | 1835 | 1835
1223378 | 00 begane grond | 00 begane grond | -22996.9 | Basic Wall : NLRS_22_WA_HSB bispouw 30-245-12-13 glaswol_gen_ISR | 3081 | 0.483061 | 2991 | -27 | -63 | 0.00451641 | 1973 | 1937
1223379 | 00 begane grond | 00 begane grond | 25843.1 | Basic Wall : NLRS_22_WA_HSB bispouw 30-245-12-13 glaswol_gen_ISR | 3081 | 0.483061 | 2991 | -63 | -27 | 0.00451641 | 1937 | 1973
1224046 | 00 begane grond | 00 begane grond | -8507.36 | Basic Wall : NLRS_22_WA_HSB bispouw 30-245-12-13 glaswol_gen_ISR | 3097.5 | 0.447077 | 2767.5 | -165 | -165 | 0.00417892 | 1835 | 1835
1224047 | 00 begane grond | 00 begane grond | -22996.9 | Basic Wall : NLRS_22_WA_HSB bispouw 30-245-12-13 glaswol_gen_ISR | 3081 | 0.483061 | 2991 | -27 | -63 | 0.00451641 | 1973 | 1937
1224048 | 00 begane grond | 00 begane grond | 25843.1 | Basic Wall : NLRS_22_WA_HSB bispouw 30-245-12-13 glaswol_gen_ISR | 3081 | 0.483061 | 2991 | -63 | -27 | 0.00451641 | 1937 | 1973
1224165 | 00 begane grond | 00 begane grond | -8507.36 | Basic Wall : NLRS_22_WA_HSB bispouw 30-245-12-13 glaswol_gen_ISR | 4437 | 0.662737 | 4107 | -165 | -165 | 0.00620157 | 1835 | 1835
1224166 | 00 begane grond | 00 begane grond | -22996.9 | Basic Wall : NLRS_22_WA_HSB bispouw 30-245-12-13 glaswol_gen_ISR | 3081 | 0.483061 | 2991 | -27 | -63 | 0.00451641 | 1973 | 1937
1224167 | 00 begane grond | 00 begane grond | 25843.1 | Basic Wall : NLRS_22_WA_HSB bispouw 30-245-12-13 glaswol_gen_ISR | 3081 | 0.483061 | 2991 | -63 | -27 | 0.00451641 | 1937 | 1973
1488574 | 00 begane grond | 00 begane grond | 28480.1 | Basic Wall : 22_WA_binnenwand_ms125 25-75-25 _gen_bdg | 3262 | 0.473562 | 2932 | -165 | -165 | 0.00442732 | 1835 | 1835
1488575 | 00 begane grond | 00 begane grond | -32543.4 | Basic Wall : 22_WA_binnenwand_ms125 25-75-25 _gen_bdg | 3081 | 0.483061 | 2991 | -27 | -63 | 0.00451641 | 1973 | 1937
1488576 | 00 begane grond | 00 begane grond | 35389.6 | Basic Wall : 22_WA_binnenwand_ms125 25-75-25 _gen_bdg | 3081 | 0.483061 | 2991 | -63 | -27 | 0.00451641 | 1937 | 1973
1492648 | 00 begane grond | 00 begane grond | -28237.4 | Basic Wall : NLRS_22_WA_HSB bispouw 30-245-12-13 glaswol_gen_ISR | 4437 | 0.662737 | 4107 | -165 | -165 | 0.00620157 | 1835 | 1835
1492649 | 00 begane grond | 00 begane grond | -44552.2 | Basic Wall : NLRS_22_WA_HSB bispouw 30-245-12-13 glaswol_gen_ISR | 3081 | 0.483061 | 2991 | -27 | -63 | 0.00451641 | 1973 | 1937
1492650 | 00 begane grond | 00 begane grond | 49443.4 | Basic Wall : NLRS_22_WA_HSB bispouw 30-245-12-13 glaswol_gen_ISR | 3081 | 0.483061 | 2991 | -63 | -27 | 0.00451641 | 1937 | 1973
1492949 | 00 begane grond | 00 begane grond | 11497.6 | Basic Wall : 21_WA_metselwerk_middel_100_gen_bdg | 3562 | 0.521862 | 3232 | -165 | -165 | 0.00488032 | 1835 | 1835
1492950 | 00 begane grond | 00 begane grond | 48012.2 | Basic Wall : 21_WA_metselwerk_middel_100_gen_bdg | 2680 | 0.4185 | 2590 | -27 | -63 | 0.0039109 | 1973 | 1937
1492951 | 00 begane grond | 00 begane grond | -45165.9 | Basic Wall : 21_WA_metselwerk_middel_100_gen_bdg | 2680 | 0.4185 | 2590 | -63 | -27 | 0.0039109 | 1937 | 1973
1493184 | 00 begane grond | 00 begane grond | 11497.6 | Level : 00 begane grond | 3262 | 0.473562 | 2932 | -165 | -165 | 0.00442732 | 1835 | 1835
1493185 | 00 begane grond | 00 begane grond | 48012.2 | Level : 00 begane grond | 3081 | 0.483061 | 2991 | -27 | -63 | 0.00451641 | 1973 | 1937
1493186 | 00 begane grond | 00 begane grond | -45165.9 | Level : 00 begane grond | 3081 | 0.483061 | 2991 | -63 | -27 | 0.00451641 | 1937 | 1973
1822621 | 00 begane grond | 00 begane grond | 13912.6 | Basic Wall : NLRS_22_WA_HSB bispouw 30-245-12-13 glaswol_gen_ISR | 4437 | 0.662737 | 4107 | -165 | -165 | 0.00620157 | 1835 | 1835
1822622 | 00 begane grond | 00 begane grond | 51249.7 | Basic Wall : NLRS_22_WA_HSB bispouw 30-245-12-13 glaswol_gen_ISR | 3081 | 0.483061 | 2991 | -27 | -63 | 0.00451641 | 1973 | 1937
1822623 | 00 begane grond | 00 begane grond | -46358.4 | Basic Wall : NLRS_22_WA_HSB bispouw 30-245-12-13 glaswol_gen_ISR | 3081 | 0.483061 | 2991 | -63 | -27 | 0.00451641 | 1937 | 1973
1847952 | 02 tweede verdieping | 02 tweede verdieping | 42080.1 | Basic Wall : 22_WA_binnenwand_ms125 25-75-25 _gen_bdg | 5112 | 0.810052 | 5022 | -45 | -45 | 0.00758322 | 1955 | 1955
1847953 | 02 tweede verdieping | 02 tweede verdieping | -12629.4 | Basic Wall : 22_WA_binnenwand_ms125 25-75-25 _gen_bdg | 2815 | 0.435244 | 2694 | -27 | -94 | 0.00406794 | 1973 | 1906
1847954 | 02 tweede verdieping | 02 tweede verdieping | 31120.6 | Basic Wall : 22_WA_binnenwand_ms125 25-75-25 _gen_bdg | 2815 | 0.435244 | 2694 | -94 | -27 | 0.00406794 | 1906 | 1973
2239351 | 01 eerste verdieping | 01 eerste verdieping | 47298.7 | Level : 01 eerste verdieping | 1503 | 0.204048 | 1258 | -45 | -200 | 0.00189958 | 1955 | 1800
2239353 | 01 eerste verdieping | 01 eerste verdieping | 17904.9 | Level : 01 eerste verdieping | 2079 | 0.316748 | 1958 | -94 | -27 | 0.00295658 | 1906 | 1973
2239387 | 01 eerste verdieping | 01 eerste verdieping | -27532.4 | Basic Wall : NLRS_22_WA_HSB bispouw 30-245-12-13 glaswol_gen_ISR | 1103 | 0.139648 | 858 | -45 | -200 | 0.00129558 | 1955 | 1800
2239388 | 01 eerste verdieping | 01 eerste verdieping | 44915.4 | Basic Wall : NLRS_22_WA_HSB bispouw 30-245-12-13 glaswol_gen_ISR | 2079 | 0.316748 | 1958 | -94 | -27 | 0.00295658 | 1906 | 1973
2239481 | 01 eerste verdieping | 01 eerste verdieping | 16867.6 | Basic Wall : NLRS_22_WA_HSB bispouw 30-245-12-13 glaswol_gen_ISR | 603 | 0.059148 | 358 | -45 | -200 | 0.00054058 | 1955 | 1800
2239482 | 01 eerste verdieping | 01 eerste verdieping | 40069 | Basic Wall : NLRS_22_WA_HSB bispouw 30-245-12-13 glaswol_gen_ISR | 2079 | 0.316748 | 1958 | -94 | -27 | 0.00295658 | 1906 | 1973
2239499 | 01 eerste verdieping | 01 eerste verdieping | -3832.36 | Basic Wall : NLRS_22_WA_HSB bispouw 30-245-12-13 glaswol_gen_ISR | 1503 | 0.204048 | 1258 | -45 | -200 | 0.00189958 | 1955 | 1800
2239500 | 01 eerste verdieping | 01 eerste verdieping | -4384.86 | Basic Wall : NLRS_22_WA_HSB bispouw 30-245-12-13 glaswol_gen_ISR | 2079 | 0.316748 | 1958 | -94 | -27 | 0.00295658 | 1906 | 1973
2239509 | 00 begane grond | 00 begane grond | -30487.4 | Basic Wall : NLRS_22_WA_HSB bispouw 30-245-12-13 glaswol_gen_ISR | 1615 | 0.208395 | 1285 | -165 | -165 | 0.00194035 | 1835 | 1835
2239511 | 00 begane grond | 00 begane grond | 15543.7 | Basic Wall : NLRS_22_WA_HSB bispouw 30-245-12-13 glaswol_gen_ISR | 3109 | 0.487569 | 3019 | -63 | -27 | 0.00455869 | 1937 | 1973
2239554 | 00 begane grond | 00 begane grond | 13912.6 | Basic Wall : NLRS_22_WA_HSB bispouw 30-245-12-13 glaswol_gen_ISR | 1095 | 0.124675 | 765 | -165 | -165 | 0.00115515 | 1835 | 1835
2239555 | 00 begane grond | 00 begane grond | 36608.3 | Basic Wall : NLRS_22_WA_HSB bispouw 30-245-12-13 glaswol_gen_ISR | 3109 | 0.487569 | 3019 | -63 | -27 | 0.00455869 | 1937 | 1973
2546400 | 00 begane grond | 00 begane grond | 11497.6 | Level : 00 begane grond | 1162 | 0.135462 | 832 | -165 | -165 | 0.00125632 | 1835 | 1835
2546401 | 00 begane grond | 00 begane grond | 48012.2 | Level : 00 begane grond | 2680 | 0.4185 | 2590 | -27 | -63 | 0.0039109 | 1973 | 1937
2546402 | 00 begane grond | 00 begane grond | -45165.9 | Level : 00 begane grond | 2680 | 0.4185 | 2590 | -63 | -27 | 0.0039109 | 1937 | 1973
2749546 | 01 eerste verdieping | 01 eerste verdieping | 47298.7 | Level : 01 eerste verdieping | 2000 | 0.30902 | 1910 | -45 | -45 | 0.0028841 | 1955 | 1955
2749547 | 01 eerste verdieping | 01 eerste verdieping | -3326.48 | Level : 01 eerste verdieping | 2629 | 0.414314 | 2564 | -27 | -38 | 0.00387164 | 1973 | 1962
2749548 | 01 eerste verdieping | 01 eerste verdieping | 17904.9 | Level : 01 eerste verdieping | 2629 | 0.414314 | 2564 | -38 | -27 | 0.00387164 | 1962 | 1973
2749763 | 01 eerste verdieping | 01 eerste verdieping | -3882.36 | Level : 01 eerste verdieping | 805 | 0.089577 | 547 | -129 | -129 | 0.00082597 | 1871 | 1871
2749764 | 01 eerste verdieping | 01 eerste verdieping | -16409.4 | Level : 01 eerste verdieping | 2079 | 0.316748 | 1958 | -27 | -94 | 0.00295658 | 1973 | 1906
2749765 | 01 eerste verdieping | 01 eerste verdieping | 27320.6 | Level : 01 eerste verdieping | 2079 | 0.316748 | 1958 | -94 | -27 | 0.00295658 | 1906 | 1973
2759483 | 01 eerste verdieping | 01 eerste verdieping | 25705.1 | Basic Wall : 22_WA_binnenwand_ms125 25-75-25 _gen_bdg | 1503 | 0.204048 | 1258 | -45 | -200 | 0.00189958 | 1955 | 1800
2759484 | 01 eerste verdieping | 01 eerste verdieping | -5144.86 | Basic Wall : 22_WA_binnenwand_ms125 25-75-25 _gen_bdg | 2079 | 0.316748 | 1958 | -94 | -27 | 0.00295658 | 1906 | 1973
2762379 | 01 eerste verdieping | 01 eerste verdieping | 25698.5 | Basic Wall : 22_WA_koof_96 12-12-50 | 603 | 0.059148 | 358 | -45 | -200 | 0.00054058 | 1955 | 1800
2762380 | 01 eerste verdieping | 01 eerste verdieping | -4731.36 | Basic Wall : 22_WA_koof_96 12-12-50 | 2079 | 0.316748 | 1958 | -94 | -27 | 0.00295658 | 1906 | 1973
2785709 | 00 begane grond | 00 begane grond | -23909.9 | Basic Wall : 22_WA_binnenwand_ms125 25-75-25 _gen_bdg | 2112.5 | 0.288492 | 1782.5 | -165 | -165 | 0.00269157 | 1835 | 1835
2785710 | 00 begane grond | 00 begane grond | 16307.2 | Basic Wall : 22_WA_binnenwand_ms125 25-75-25 _gen_bdg | 3081 | 0.483061 | 2991 | -63 | -27 | 0.00451641 | 1937 | 1973
2790506 | 00 begane grond | 00 begane grond | -10144.9 | Basic Wall : 22_WA_binnenwand_ms125 25-75-25 _gen_bdg | 3348.76 | 0.48753 | 3018.76 | -165 | -165 | 0.00455833 | 1835 | 1835
2790507 | 00 begane grond | 00 begane grond | -31808.5 | Basic Wall : 22_WA_binnenwand_ms125 25-75-25 _gen_bdg | 3081 | 0.483061 | 2991 | -63 | -27 | 0.00451641 | 1937 | 1973

# IfcBuildingElementProxy: NLRS_41_GM_WPB_multiplex-SH_generiek_ISR:151x12 (8)
In: 00 begane grond
Type - Material: f7_gipsvezel
Type - Constraints - Default Elevation: 1219.2 mm
Type - Materials and Finishes - materiaal: f7_gipsvezel
Type - Dimensions - breedte: 12 mm; hoogte: 151 mm
Type - Identity Data - Workset: Family : Generic Models : NLRS_41_GM_WPB_multiplex-SH_generiek_ISR; Assembly Code: 42; Assembly Description: binnenwandafwerkingen; Datum_Gewijzigd: 20160502; Description: multiplex; Model: LOD300; SmartRevit_Versie: 2019.1; Type Name: 151x12
Type - Other - Category: Generic Models; Family Name: NLRS_41_GM_WPB_multiplex-SH_generiek_ISR
Classification: 42 Uniformat (Uniformat)
Constraints - Level: 00 begane grond; Moves With Nearby Elements: no; Host: Basic Wall : NLRS_22_WA_HSB bispouw 30-245-12-13 glaswol_gen_ISR
Phasing - Phase Created: 2. nieuwbouw
Graphics - hoek_a: 0 deg; hoek_b: 0 deg
Dimensions - NLRS_C_breedte: 12 mm; NLRS_C_hoogte: 151 mm
Identity Data - Workset: Workset1
Other - berekende_hoek_a: 0 deg; berekende_overstek_a: 0 mm; berekende_overstek_b: 0 mm; Family: NLRS_41_GM_WPB_multiplex-SH_generiek_ISR; Family and Type: NLRS_41_GM_WPB_multiplex-SH_generiek_ISR: 151x12; Type: 151x12; Type Id: 2783838
Name (NLRS_41_GM_WPB_multiplex-SH_generiek_ISR:151x12:...) | Elevation from Level (mm) = Offset from Host (mm) | lengte (mm) = NLRS_C_lengte (mm) | Area (m2) | element_lengte (mm) | verlenging_a (mm) | verlenging_b (mm) | Volume (m3) | berekende_verlenging_a (mm) | berekende_verlenging_b (mm)
1224057 | -8507.36 | 2461 | 0.349165 | 2131 | -165 | -165 | 0.00386137 | 1835 | 1835
1224058 | -22996.9 | 3081 | 0.489345 | 2991 | -27 | -63 | 0.00541969 | 1973 | 1937
1224059 | 25843.1 | 3081 | 0.489345 | 2991 | -63 | -27 | 0.00541969 | 1937 | 1973
1818657 | 16659.6 | 5212 | 0.797578 | 4882 | -165 | -165 | 0.00884618 | 1835 | 1835
1818658 | 13927.5 | 3081 | 0.489345 | 2991 | -27 | -63 | 0.00541969 | 1973 | 1937
1818659 | -9036.2 | 3081 | 0.489345 | 2991 | -63 | -27 | 0.00541969 | 1937 | 1973
2786087 | -17432.4 | 2671 | 0.383395 | 2341 | -165 | -165 | 0.00424189 | 1835 | 1835
2786088 | -8671.86 | 3081 | 0.489345 | 2991 | -63 | -27 | 0.00541969 | 1937 | 1973

# IfcBuildingElementProxy: NLRS_41_GM_WPB_multiplex-SH_generiek_ISR:214x10 (12)
In: 00 begane grond
Type - Material: i4_multiplex
Type - Constraints - Default Elevation: 1219.2 mm
Type - Materials and Finishes - materiaal: i4_multiplex
Type - Dimensions - breedte: 10 mm; hoogte: 214 mm
Type - Identity Data - Workset: Family : Generic Models : NLRS_41_GM_WPB_multiplex-SH_generiek_ISR; Assembly Code: 42; Assembly Description: binnenwandafwerkingen; Datum_Gewijzigd: 20160502; Description: multiplex; Model: LOD300; SmartRevit_Versie: 2019.1; Type Name: 214x10
Type - Other - Category: Generic Models; Family Name: NLRS_41_GM_WPB_multiplex-SH_generiek_ISR
Classification: 42 Uniformat (Uniformat)
Constraints - Level: 00 begane grond; Moves With Nearby Elements: no; Host: Level : 00 begane grond
Phasing - Phase Created: 2. nieuwbouw
Graphics - hoek_a: 0 deg; hoek_b: 0 deg
Dimensions - NLRS_C_breedte: 10 mm; NLRS_C_hoogte: 214 mm
Identity Data - Workset: Workset1
Other - berekende_hoek_a: 0 deg; berekende_overstek_a: 0 mm; berekende_overstek_b: 0 mm; Family: NLRS_41_GM_WPB_multiplex-SH_generiek_ISR; Family and Type: NLRS_41_GM_WPB_multiplex-SH_generiek_ISR: 214x10; Type: 214x10; Type Id: 4323287
Name (NLRS_41_GM_WPB_multiplex-SH_generiek_ISR:214x10:...) | Elevation from Level (mm) = Offset from Host (mm) | lengte (mm) = NLRS_C_lengte (mm) | Area (m2) | element_lengte (mm) | verlenging_a (mm) | verlenging_b (mm) | Volume (m3) | berekende_verlenging_a (mm) | berekende_verlenging_b (mm)
1502433 | 39467.6 | 3262 | 0.658908 | 2932 | -165 | -165 | 0.00627448 | 1835 | 1835
1502434 | 67773.1 | 3081 | 0.672124 | 2991 | -27 | -63 | 0.00640074 | 1973 | 1937
1502435 | -64926.9 | 3081 | 0.672124 | 2991 | -63 | -27 | 0.00640074 | 1937 | 1973
1502792 | 39467.6 | 3262 | 0.658908 | 2932 | -165 | -165 | 0.00627448 | 1835 | 1835
1502793 | 67773.1 | 3081 | 0.672124 | 2991 | -27 | -63 | 0.00640074 | 1973 | 1937
1502794 | -64926.9 | 3081 | 0.672124 | 2991 | -63 | -27 | 0.00640074 | 1937 | 1973
1503073 | 82867.6 | 1162 | 0.188508 | 832 | -165 | -165 | 0.00178048 | 1835 | 1835
1503074 | -25701.9 | 3081 | 0.672124 | 2991 | -27 | -63 | 0.00640074 | 1973 | 1937
1503075 | 28548.1 | 3081 | 0.672124 | 2991 | -63 | -27 | 0.00640074 | 1937 | 1973
1503715 | 82867.6 | 4437 | 0.922108 | 4107 | -165 | -165 | 0.00878898 | 1835 | 1835
1503716 | -25701.9 | 3081 | 0.672124 | 2991 | -27 | -63 | 0.00640074 | 1973 | 1937
1503717 | 28548.1 | 3081 | 0.672124 | 2991 | -63 | -27 | 0.00640074 | 1937 | 1973

# IfcBuildingElementProxy: NLRS_41_GM_WPB_multiplex-SH_generiek_ISR:306x10 gipsvezel dagkant (14)
Type - Material: f7_gipsvezel
Type - Constraints - Default Elevation: 1219.2 mm
Type - Materials and Finishes - materiaal: f7_gipsvezel
Type - Dimensions - breedte: 10 mm; hoogte: 306 mm
Type - Identity Data - Workset: Family : Generic Models : NLRS_41_GM_WPB_multiplex-SH_generiek_ISR; Assembly Code: 42; Assembly Description: binnenwandafwerkingen; Datum_Gewijzigd: 20160502; Description: multiplex; Model: LOD300; SmartRevit_Versie: 2019.1; Type Name: 306x10 gipsvezel dagkant
Type - Other - Category: Generic Models; Family Name: NLRS_41_GM_WPB_multiplex-SH_generiek_ISR
Classification: 42 Uniformat (Uniformat)
Constraints - Moves With Nearby Elements: no
Phasing - Phase Created: 2. nieuwbouw
Graphics - hoek_a: 0 deg; hoek_b: 0 deg
Dimensions - NLRS_C_breedte: 10 mm; NLRS_C_hoogte: 306 mm
Identity Data - Workset: Workset1
Other - berekende_hoek_a: 0 deg; berekende_overstek_a: 0 mm; berekende_overstek_b: 0 mm; Family: NLRS_41_GM_WPB_multiplex-SH_generiek_ISR; Family and Type: NLRS_41_GM_WPB_multiplex-SH_generiek_ISR: 306x10 gipsvezel dagkant; Type: 306x10 gipsvezel dagkant; Type Id: 4342096
Name (NLRS_41_GM_WPB_multiplex-SH_generiek_ISR:306x10 gipsvezel dagkant:...) | In | Level | Elevation from Level (mm) = Offset from Host (mm) | Host | lengte (mm) = NLRS_C_lengte (mm) | Area (m2) | element_lengte (mm) | verlenging_a (mm) | verlenging_b (mm) | Volume (m3) | berekende_verlenging_a (mm) | berekende_verlenging_b (mm)
872904 | 02 tweede verdieping | 02 tweede verdieping | -25047.4 | Level : 02 tweede verdieping | 1112 | 0.260916 | 816 | -148 | -148 | 0.00249696 | 1852 | 1852
872905 | 02 tweede verdieping | 02 tweede verdieping | -22508 | Level : 02 tweede verdieping | 2449 | 0.738708 | 2328 | -27 | -94 | 0.00712368 | 1973 | 1906
872906 | 02 tweede verdieping | 02 tweede verdieping | 40954.3 | Level : 02 tweede verdieping | 2449 | 0.738708 | 2328 | -94 | -27 | 0.00712368 | 1906 | 1973
872937 | 02 tweede verdieping | 02 tweede verdieping | -25047.4 | Level : 02 tweede verdieping | 1112 | 0.260916 | 816 | -148 | -148 | 0.00249696 | 1852 | 1852
872938 | 02 tweede verdieping | 02 tweede verdieping | -22508 | Level : 02 tweede verdieping | 2449 | 0.738708 | 2328 | -27 | -94 | 0.00712368 | 1973 | 1906
872939 | 02 tweede verdieping | 02 tweede verdieping | 40954.3 | Level : 02 tweede verdieping | 2449 | 0.738708 | 2328 | -94 | -27 | 0.00712368 | 1906 | 1973
880833 | 01 eerste verdieping | 01 eerste verdieping | 16792.6 | Basic Wall : NLRS_22_WA_HSB bispouw 30-245-12-13 glaswol_gen_ISR | 2000 | 0.551952 | 1737 | -131.5 | -131.5 | 0.00531522 | 1868.5 | 1868.5
880834 | 01 eerste verdieping | 01 eerste verdieping | -26974.3 | Basic Wall : NLRS_22_WA_HSB bispouw 30-245-12-13 glaswol_gen_ISR | 2079 | 0.621788 | 1958 | -27 | -94 | 0.00599148 | 1973 | 1906
880835 | 01 eerste verdieping | 01 eerste verdieping | 38820.6 | Basic Wall : NLRS_22_WA_HSB bispouw 30-245-12-13 glaswol_gen_ISR | 2079 | 0.621788 | 1958 | -94 | -27 | 0.00599148 | 1906 | 1973
881601 | 01 eerste verdieping | 01 eerste verdieping | 16792.6 | Level : 01 eerste verdieping | 2000 | 0.551952 | 1737 | -131.5 | -131.5 | 0.00531522 | 1868.5 | 1868.5
881602 | 01 eerste verdieping | 01 eerste verdieping | -26974.3 | Level : 01 eerste verdieping | 2079 | 0.621788 | 1958 | -27 | -94 | 0.00599148 | 1973 | 1906
881603 | 01 eerste verdieping | 01 eerste verdieping | 38820.6 | Level : 01 eerste verdieping | 2079 | 0.621788 | 1958 | -94 | -27 | 0.00599148 | 1906 | 1973
4343094 | 01 eerste verdieping | 01 eerste verdieping | 16792.6 | Level : 01 eerste verdieping | 1662.5 | 0.45099 | 1417.5 | -45 | -200 | 0.00433755 | 1955 | 1800
4343095 | 01 eerste verdieping | 01 eerste verdieping | 38820.6 | Level : 01 eerste verdieping | 2079 | 0.621788 | 1958 | -94 | -27 | 0.00599148 | 1906 | 1973

# IfcBuildingElementProxy: NLRS_41_GM_WPB_spouwlat-SH_generiek_ISR:185x28 (4)
Type - Material: i4_hout_gen
Type - Constraints - Default Elevation: 1219.2 mm
Type - Materials and Finishes - materiaal: i4_hout_gen
Type - Dimensions - breedte: 28 mm; hoogte: 185 mm
Type - Identity Data - Workset: Family : Generic Models : NLRS_41_GM_WPB_spouwlat-SH_generiek_ISR; Assembly Code: 21; Assembly Description: buitenwanden; Datum_Gewijzigd: 20160502; Description: spouwlat; Model: LOD300; SmartRevit_Versie: 2019.1; Type Name: 185x28
Type - Other - Category: Generic Models; Family Name: NLRS_41_GM_WPB_spouwlat-SH_generiek_ISR
Classification: 21 Uniformat (Uniformat)
Constraints - Moves With Nearby Elements: no
Phasing - Phase Created: 2. nieuwbouw
Graphics - hoek_a: 0 deg; hoek_b: 0 deg
Dimensions - NLRS_C_breedte: 28 mm; NLRS_C_hoogte: 185 mm; verlenging_a: -17 mm; verlenging_b: -17 mm
Identity Data - Workset: Workset1
Other - berekende_hoek_a: 0 deg; berekende_overstek_a: 0 mm; berekende_overstek_b: 0 mm; Family: NLRS_41_GM_WPB_spouwlat-SH_generiek_ISR; berekende_verlenging_a: 1983 mm; berekende_verlenging_b: 1983 mm; Family and Type: NLRS_41_GM_WPB_spouwlat-SH_generiek_ISR: 185x28; Type: 185x28; Type Id: 2324906
Name (NLRS_41_GM_WPB_spouwlat-SH_generiek_ISR:185x28:...) | In | Level | Elevation from Level (mm) = Offset from Host (mm) | Host | lengte (mm) = NLRS_C_lengte (mm) | Area (m2) | element_lengte (mm) | Volume (m3)
897886 | 00 begane grond | 00 begane grond | -22960.4 | Basic Wall : NLRS_22_WA_HSB bispouw 30-245-12-13 glaswol_gen_ISR | 3008 | 0.638642 | 2974 | 0.0154053
1224044 | 00 begane grond | 00 begane grond | -22960.4 | Basic Wall : NLRS_22_WA_HSB bispouw 30-245-12-13 glaswol_gen_ISR | 3008 | 0.638642 | 2974 | 0.0154053
2749761 | 01 eerste verdieping | 01 eerste verdieping | -16405.4 | Level : 01 eerste verdieping | 2020 | 0.428198 | 1986 | 0.0102875
2785707 | 00 begane grond | 00 begane grond | 16343.7 | Basic Wall : 22_WA_binnenwand_ms125 25-75-25 _gen_bdg | 3008 | 0.638642 | 2974 | 0.0154053

# IfcBuildingElementProxy: NLRS_41_GM_WPB_spouwlat-SH_generiek_ISR:185x45 (36)
Type - Material: i4_hout_gen
Type - Constraints - Default Elevation: 1219.2 mm
Type - Materials and Finishes - materiaal: i4_hout_gen
Type - Dimensions - breedte: 45 mm; hoogte: 185 mm
Type - Identity Data - Workset: Family : Generic Models : NLRS_41_GM_WPB_spouwlat-SH_generiek_ISR; Assembly Code: 21; Assembly Description: buitenwanden; Datum_Gewijzigd: 20160502; Description: spouwlat; Model: LOD300; SmartRevit_Versie: 2019.1; Type Name: 185x45
Type - Other - Category: Generic Models; Family Name: NLRS_41_GM_WPB_spouwlat-SH_generiek_ISR
Classification: 21 Uniformat (Uniformat)
Constraints - Moves With Nearby Elements: no
Phasing - Phase Created: 2. nieuwbouw
Graphics - hoek_a: 0 deg; hoek_b: 0 deg
Dimensions - NLRS_C_breedte: 45 mm; NLRS_C_hoogte: 185 mm; verlenging_b: 28 mm
Identity Data - Workset: Workset1
Other - berekende_hoek_a: 0 deg; berekende_overstek_a: 0 mm; berekende_overstek_b: 0 mm; Family: NLRS_41_GM_WPB_spouwlat-SH_generiek_ISR; berekende_verlenging_b: 2028 mm; Family and Type: NLRS_41_GM_WPB_spouwlat-SH_generiek_ISR: 185x45; Type: 185x45; Type Id: 775274
Name (NLRS_41_GM_WPB_spouwlat-SH_generiek_ISR:185x45:...) | In | Level | Elevation from Level (mm) = Offset from Host (mm) | Host | lengte (mm) = NLRS_C_lengte (mm) | Area (m2) | element_lengte (mm) | verlenging_a (mm) | Volume (m3) | berekende_verlenging_a (mm)
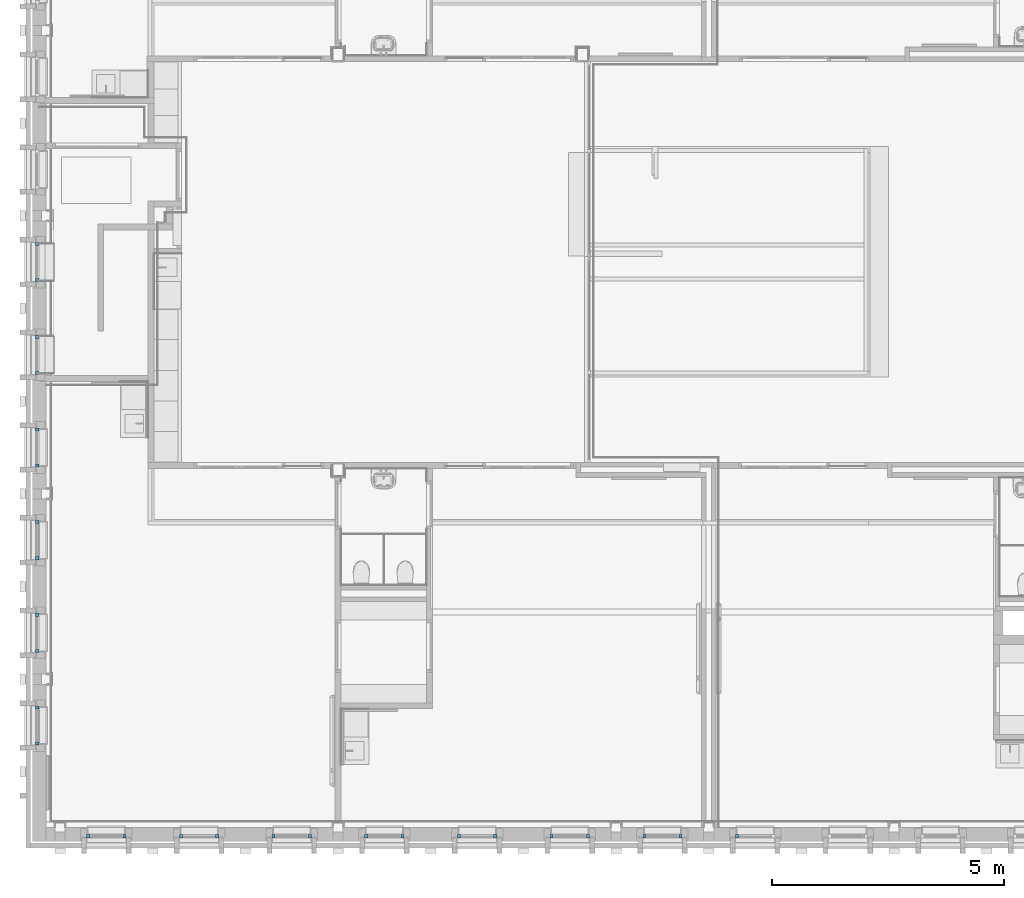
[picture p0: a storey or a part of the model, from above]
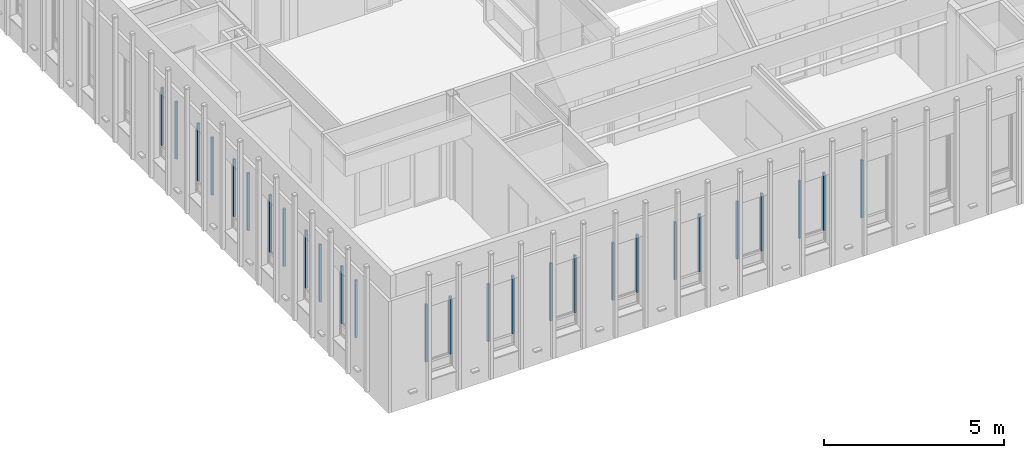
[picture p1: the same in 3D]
Properties of the parts of a building model (IFC2X3), part 4 of 94

# IfcBuildingElementProxy: NLRS_41_GM_WPB_spouwlat-SH_generiek_ISR:185x45 (36)
Name (NLRS_41_GM_WPB_spouwlat-SH_generiek_ISR:185x45:...) | In | Level | Elevation from Level (mm) = Offset from Host (mm) | Host | lengte (mm) = NLRS_C_lengte (mm) | Area (m2) | element_lengte (mm) | verlenging_a (mm) | Volume (m3) | berekende_verlenging_a (mm)
891622 | 01 eerste verdieping | 01 eerste verdieping | -2907.36 | Level : 01 eerste verdieping | 373 | 0.126315 | 513 | 112 | 0.00427073 | 2112
897887 | 00 begane grond | 00 begane grond | -9473.36 | Basic Wall : NLRS_22_WA_HSB bispouw 30-245-12-13 glaswol_gen_ISR | 1800 | 0.426235 | 1817 | -11 | 0.0151265 | 1989
897940 | 00 begane grond | 00 begane grond | -9473.36 | Basic Wall : NLRS_22_WA_HSB bispouw 30-245-12-13 glaswol_gen_ISR | 900 | 0.228205 | 956 | 28 | 0.0079587 | 2028
898548 | 00 begane grond | 00 begane grond | -9473.36 | Basic Wall : NLRS_22_WA_HSB bispouw 30-245-12-13 glaswol_gen_ISR | 2100 | 0.504205 | 2156 | 28 | 0.0179487 | 2028
898560 | 00 begane grond | 00 begane grond | -9473.36 | Basic Wall : NLRS_22_WA_HSB bispouw 30-245-12-13 glaswol_gen_ISR | 1500 | 0.366205 | 1556 | 28 | 0.0129537 | 2028
1219786 | 00 begane grond | 00 begane grond | -9473.36 | Basic Wall : NLRS_22_WA_HSB bispouw 30-245-12-13 glaswol_gen_ISR | 1800 | 0.435205 | 1856 | 28 | 0.0154512 | 2028
1220536 | 00 begane grond | 00 begane grond | -9473.36 | Basic Wall : NLRS_22_WA_HSB bispouw 30-245-12-13 glaswol_gen_ISR | 3000 | 0.711205 | 3056 | 28 | 0.0254412 | 2028
1221370 | 00 begane grond | 00 begane grond | -9473.36 | Basic Wall : NLRS_22_WA_HSB bispouw 30-245-12-13 glaswol_gen_ISR | 900 | 0.228205 | 956 | 28 | 0.0079587 | 2028
1221381 | 00 begane grond | 00 begane grond | -9473.36 | Basic Wall : NLRS_22_WA_HSB bispouw 30-245-12-13 glaswol_gen_ISR | 2966 | 0.703385 | 3022 | 28 | 0.0251582 | 2028
1221602 | 00 begane grond | 00 begane grond | -9473.36 | Basic Wall : NLRS_22_WA_HSB bispouw 30-245-12-13 glaswol_gen_ISR | 3300 | 0.780205 | 3356 | 28 | 0.0279387 | 2028
1222357 | 00 begane grond | 00 begane grond | -9473.36 | Basic Wall : NLRS_22_WA_HSB bispouw 30-245-12-13 glaswol_gen_ISR | 900 | 0.228205 | 956 | 28 | 0.0079587 | 2028
1222799 | 00 begane grond | 00 begane grond | -9473.36 | Basic Wall : NLRS_22_WA_HSB bispouw 30-245-12-13 glaswol_gen_ISR | 900 | 0.228205 | 956 | 28 | 0.0079587 | 2028
1223376 | 00 begane grond | 00 begane grond | -9473.36 | Basic Wall : NLRS_22_WA_HSB bispouw 30-245-12-13 glaswol_gen_ISR | 2700 | 0.642205 | 2756 | 28 | 0.0229437 | 2028
1224045 | 00 begane grond | 00 begane grond | -9473.36 | Basic Wall : NLRS_22_WA_HSB bispouw 30-245-12-13 glaswol_gen_ISR | 2955.5 | 0.692 | 2972.5 | -11 | 0.0247461 | 1989
1224164 | 00 begane grond | 00 begane grond | -9473.36 | Basic Wall : NLRS_22_WA_HSB bispouw 30-245-12-13 glaswol_gen_ISR | 4175 | 0.981455 | 4231 | 28 | 0.0352231 | 2028
1488573 | 00 begane grond | 00 begane grond | 27514.1 | Basic Wall : 22_WA_binnenwand_ms125 25-75-25 _gen_bdg | 3000 | 0.711205 | 3056 | 28 | 0.0254412 | 2028
1492647 | 00 begane grond | 00 begane grond | -31248.4 | Basic Wall : NLRS_22_WA_HSB bispouw 30-245-12-13 glaswol_gen_ISR | 4175 | 0.981455 | 4231 | 28 | 0.0352231 | 2028
1492945 | 00 begane grond | 00 begane grond | -7612.36 | Basic Wall : 21_WA_metselwerk_middel_100_gen_bdg | 3300 | 0.780205 | 3356 | 28 | 0.0279387 | 2028
1493183 | 00 begane grond | 00 begane grond | 10531.6 | Level : 00 begane grond | 3000 | 0.711205 | 3056 | 28 | 0.0254412 | 2028
1502432 | 00 begane grond | 00 begane grond | 38501.6 | Level : 00 begane grond | 3000 | 0.711205 | 3056 | 28 | 0.0254412 | 2028
1502791 | 00 begane grond | 00 begane grond | 38501.6 | Level : 00 begane grond | 3000 | 0.711205 | 3056 | 28 | 0.0254412 | 2028
1503072 | 00 begane grond | 00 begane grond | 81901.6 | Level : 00 begane grond | 900 | 0.228205 | 956 | 28 | 0.0079587 | 2028
1503714 | 00 begane grond | 00 begane grond | 81901.6 | Level : 00 begane grond | 4175 | 0.981455 | 4231 | 28 | 0.0352231 | 2028
1822620 | 00 begane grond | 00 begane grond | 10901.6 | Basic Wall : NLRS_22_WA_HSB bispouw 30-245-12-13 glaswol_gen_ISR | 4175 | 0.981455 | 4231 | 28 | 0.0352231 | 2028
2239347 | 01 eerste verdieping | 01 eerste verdieping | -31681.3 | Level : 01 eerste verdieping | 1238.5 | 0.32538 | 1378.5 | 112 | 0.011476 | 2112
2239384 | 01 eerste verdieping | 01 eerste verdieping | 41417.6 | Basic Wall : NLRS_22_WA_HSB bispouw 30-245-12-13 glaswol_gen_ISR | 838.5 | 0.23338 | 978.5 | 112 | 0.00814601 | 2112
2239478 | 01 eerste verdieping | 01 eerste verdieping | -2982.36 | Basic Wall : NLRS_22_WA_HSB bispouw 30-245-12-13 glaswol_gen_ISR | 338.5 | 0.11838 | 478.5 | 112 | 0.00398351 | 2112
2239496 | 01 eerste verdieping | 01 eerste verdieping | 15717.6 | Basic Wall : NLRS_22_WA_HSB bispouw 30-245-12-13 glaswol_gen_ISR | 1238.5 | 0.32538 | 1378.5 | 112 | 0.011476 | 2112
2239508 | 00 begane grond | 00 begane grond | -33498.4 | Basic Wall : NLRS_22_WA_HSB bispouw 30-245-12-13 glaswol_gen_ISR | 1353 | 0.332395 | 1409 | 28 | 0.0117299 | 2028
2239553 | 00 begane grond | 00 begane grond | 10901.6 | Basic Wall : NLRS_22_WA_HSB bispouw 30-245-12-13 glaswol_gen_ISR | 833 | 0.212795 | 889 | 28 | 0.00740093 | 2028
2546396 | 00 begane grond | 00 begane grond | -7612.36 | Level : 00 begane grond | 900 | 0.228205 | 956 | 28 | 0.0079587 | 2028
2759480 | 01 eerste verdieping | 01 eerste verdieping | -13819.9 | Basic Wall : 22_WA_binnenwand_ms125 25-75-25 _gen_bdg | 1238.5 | 0.32538 | 1378.5 | 112 | 0.011476 | 2112
2762376 | 01 eerste verdieping | 01 eerste verdieping | -13813.3 | Basic Wall : 22_WA_koof_96 12-12-50 | 338.5 | 0.11838 | 478.5 | 112 | 0.00398351 | 2112
2785708 | 00 begane grond | 00 begane grond | -24875.9 | Basic Wall : 22_WA_binnenwand_ms125 25-75-25 _gen_bdg | 1850.5 | 0.44682 | 1906.5 | 28 | 0.0158716 | 2028
2786086 | 00 begane grond | 00 begane grond | -18398.4 | Basic Wall : NLRS_22_WA_HSB bispouw 30-245-12-13 glaswol_gen_ISR | 2294 | 0.548825 | 2350 | 28 | 0.0195637 | 2028
2790505 | 00 begane grond | 00 begane grond | -11110.9 | Basic Wall : 22_WA_binnenwand_ms125 25-75-25 _gen_bdg | 3086.76 | 0.731159 | 3142.76 | 28 | 0.0261635 | 2028

# IfcBuildingElementProxy: NLRS_41_GM_WPB_spouwlat-SH_generiek_ISR:185x76 (97)
Type - Material: i4_hout_gen
Type - Constraints - Default Elevation: 1219.2 mm
Type - Materials and Finishes - materiaal: i4_hout_gen
Type - Dimensions - breedte: 76 mm; hoogte: 185 mm
Type - Identity Data - Assembly Code: 21; Assembly Description: buitenwanden; Datum_Gewijzigd: 20160502; Description: spouwlat; Model: LOD300; SmartRevit_Versie: 2019.1; Type Name: 185x76; Workset: Family : Generic Models : NLRS_41_GM_WPB_spouwlat-SH_generiek_ISR
Type - Other - Category: Generic Models; Family Name: NLRS_41_GM_WPB_spouwlat-SH_generiek_ISR
Classification: 21 Uniformat (Uniformat)
Constraints - Moves With Nearby Elements: no
Phasing - Phase Created: 2. nieuwbouw
Graphics - hoek_a: 0 deg; hoek_b: 0 deg
Dimensions - NLRS_C_breedte: 76 mm; NLRS_C_hoogte: 185 mm
Identity Data - Workset: Workset1
Other - berekende_hoek_a: 0 deg; berekende_overstek_a: 0 mm; berekende_overstek_b: 0 mm; Family: NLRS_41_GM_WPB_spouwlat-SH_generiek_ISR; Family and Type: NLRS_41_GM_WPB_spouwlat-SH_generiek_ISR: 185x76; Type: 185x76; Type Id: 2038274
Name (NLRS_41_GM_WPB_spouwlat-SH_generiek_ISR:185x76:...) | In | Level | Elevation from Level (mm) = Offset from Host (mm) | Host | lengte (mm) = NLRS_C_lengte (mm) | Area (m2) | element_lengte (mm) | verlenging_a (mm) | verlenging_b (mm) | Volume (m3) | berekende_verlenging_a (mm) | berekende_verlenging_b (mm)
832755 | 01 eerste verdieping | 01 eerste verdieping | -4898.36 | Basic Wall : NLRS_22_WA_HSB bispouw 30-245-12-13 glaswol_gen_ISR | 1771 | 0.534755 | 1995 | 112 | 112 | 0.0280497 | 2112 | 2112
858915 | 01 eerste verdieping | 01 eerste verdieping | -4898.36 | Level : 01 eerste verdieping | 1771 | 0.534755 | 1995 | 112 | 112 | 0.0280497 | 2112 | 2112
858941 | 01 eerste verdieping | 01 eerste verdieping | -4898.36 | Level : 01 eerste verdieping | 1771 | 0.534755 | 1995 | 112 | 112 | 0.0280497 | 2112 | 2112
859970 | 02 tweede verdieping | 02 tweede verdieping | -1739.71 | Basic Wall : NLRS_22_WA_HSB bispouw 30-245-12-13 glaswol_gen_ISR | 850 | 0.246872 | 892 | 21 | 21 | 0.0125415 | 2021 | 2021
864456 | 02 tweede verdieping | 02 tweede verdieping | -1739.71 | Level : 02 tweede verdieping | 850 | 0.246872 | 892 | 21 | 21 | 0.0125415 | 2021 | 2021
864487 | 02 tweede verdieping | 02 tweede verdieping | -1739.71 | Level : 02 tweede verdieping | 850 | 0.246872 | 892 | 21 | 21 | 0.0125415 | 2021 | 2021
870614 | 02 tweede verdieping | 02 tweede verdieping | -1739.71 | Level : 02 tweede verdieping | 850 | 0.246872 | 892 | 21 | 21 | 0.0125415 | 2021 | 2021
870631 | 02 tweede verdieping | 02 tweede verdieping | -1739.71 | Level : 02 tweede verdieping | 850 | 0.246872 | 892 | 21 | 21 | 0.0125415 | 2021 | 2021
870648 | 02 tweede verdieping | 02 tweede verdieping | -1739.71 | Level : 02 tweede verdieping | 850 | 0.246872 | 892 | 21 | 21 | 0.0125415 | 2021 | 2021
870696 | 02 tweede verdieping | 02 tweede verdieping | -1739.71 | Level : 02 tweede verdieping | 850 | 0.246872 | 892 | 21 | 21 | 0.0125415 | 2021 | 2021
870713 | 02 tweede verdieping | 02 tweede verdieping | -1739.71 | Level : 02 tweede verdieping | 850 | 0.246872 | 892 | 21 | 21 | 0.0125415 | 2021 | 2021
870730 | 02 tweede verdieping | 02 tweede verdieping | -1739.71 | Level : 02 tweede verdieping | 850 | 0.246872 | 892 | 21 | 21 | 0.0125415 | 2021 | 2021
870809 | 02 tweede verdieping | 02 tweede verdieping | -1739.71 | Level : 02 tweede verdieping | 850 | 0.246872 | 892 | 21 | 21 | 0.0125415 | 2021 | 2021
870826 | 02 tweede verdieping | 02 tweede verdieping | -1739.71 | Level : 02 tweede verdieping | 850 | 0.246872 | 892 | 21 | 21 | 0.0125415 | 2021 | 2021
870843 | 02 tweede verdieping | 02 tweede verdieping | -1739.71 | Level : 02 tweede verdieping | 850 | 0.246872 | 892 | 21 | 21 | 0.0125415 | 2021 | 2021
870953 | 02 tweede verdieping | 02 tweede verdieping | 43766.6 | Basic Wall : 21_WA_metselwerk_licht_100_gen_bdg | 850 | 0.246872 | 892 | 21 | 21 | 0.0125415 | 2021 | 2021
871631 | 02 tweede verdieping | 02 tweede verdieping | 43766.6 | Level : 02 tweede verdieping | 850 | 0.246872 | 892 | 21 | 21 | 0.0125415 | 2021 | 2021
871664 | 02 tweede verdieping | 02 tweede verdieping | 43766.6 | Level : 02 tweede verdieping | 850 | 0.246872 | 892 | 21 | 21 | 0.0125415 | 2021 | 2021
871697 | 02 tweede verdieping | 02 tweede verdieping | 43766.6 | Level : 02 tweede verdieping | 850 | 0.246872 | 892 | 21 | 21 | 0.0125415 | 2021 | 2021
871883 | 02 tweede verdieping | 02 tweede verdieping | 43766.6 | Level : 02 tweede verdieping | 850 | 0.246872 | 892 | 21 | 21 | 0.0125415 | 2021 | 2021
871915 | 02 tweede verdieping | 02 tweede verdieping | 43766.6 | Level : 02 tweede verdieping | 850 | 0.246872 | 892 | 21 | 21 | 0.0125415 | 2021 | 2021
871947 | 02 tweede verdieping | 02 tweede verdieping | 43766.6 | Level : 02 tweede verdieping | 850 | 0.246872 | 892 | 21 | 21 | 0.0125415 | 2021 | 2021
871979 | 02 tweede verdieping | 02 tweede verdieping | 43766.6 | Level : 02 tweede verdieping | 850 | 0.246872 | 892 | 21 | 21 | 0.0125415 | 2021 | 2021
872043 | 02 tweede verdieping | 02 tweede verdieping | -26013.4 | Basic Wall : 21_WA_metselwerk_licht_100_gen_bdg | 850 | 0.246872 | 892 | 21 | 21 | 0.0125415 | 2021 | 2021
872078 | 02 tweede verdieping | 02 tweede verdieping | -26013.4 | Basic Wall : 21_WA_metselwerk_licht_100_gen_bdg | 850 | 0.246872 | 892 | 21 | 21 | 0.0125415 | 2021 | 2021
872804 | 02 tweede verdieping | 02 tweede verdieping | -26013.4 | Level : 02 tweede verdieping | 850 | 0.246872 | 892 | 21 | 21 | 0.0125415 | 2021 | 2021
872837 | 02 tweede verdieping | 02 tweede verdieping | -26013.4 | Level : 02 tweede verdieping | 850 | 0.246872 | 892 | 21 | 21 | 0.0125415 | 2021 | 2021
872870 | 02 tweede verdieping | 02 tweede verdieping | -26013.4 | Level : 02 tweede verdieping | 850 | 0.246872 | 892 | 21 | 21 | 0.0125415 | 2021 | 2021
872903 | 02 tweede verdieping | 02 tweede verdieping | -26013.4 | Level : 02 tweede verdieping | 850 | 0.246872 | 892 | 21 | 21 | 0.0125415 | 2021 | 2021
872936 | 02 tweede verdieping | 02 tweede verdieping | -26013.4 | Level : 02 tweede verdieping | 850 | 0.246872 | 892 | 21 | 21 | 0.0125415 | 2021 | 2021
872969 | 02 tweede verdieping | 02 tweede verdieping | -26013.4 | Level : 02 tweede verdieping | 850 | 0.246872 | 892 | 21 | 21 | 0.0125415 | 2021 | 2021
873002 | 02 tweede verdieping | 02 tweede verdieping | -26013.4 | Level : 02 tweede verdieping | 850 | 0.246872 | 892 | 21 | 21 | 0.0125415 | 2021 | 2021
873035 | 02 tweede verdieping | 02 tweede verdieping | -26013.4 | Level : 02 tweede verdieping | 850 | 0.246872 | 892 | 21 | 21 | 0.0125415 | 2021 | 2021
873068 | 02 tweede verdieping | 02 tweede verdieping | -26013.4 | Level : 02 tweede verdieping | 850 | 0.246872 | 892 | 21 | 21 | 0.0125415 | 2021 | 2021
873101 | 02 tweede verdieping | 02 tweede verdieping | -26013.4 | Level : 02 tweede verdieping | 850 | 0.246872 | 892 | 21 | 21 | 0.0125415 | 2021 | 2021
873412 | 02 tweede verdieping | 02 tweede verdieping | -26013.4 | Level : 02 tweede verdieping | 850 | 0.246872 | 892 | 21 | 21 | 0.0125415 | 2021 | 2021
873462 | 02 tweede verdieping | 02 tweede verdieping | -26013.4 | Level : 02 tweede verdieping | 850 | 0.246872 | 892 | 21 | 21 | 0.0125415 | 2021 | 2021
873493 | 02 tweede verdieping | 02 tweede verdieping | -26013.4 | Level : 02 tweede verdieping | 850 | 0.246872 | 892 | 21 | 21 | 0.0125415 | 2021 | 2021
873524 | 02 tweede verdieping | 02 tweede verdieping | -26013.4 | Level : 02 tweede verdieping | 850 | 0.246872 | 892 | 21 | 21 | 0.0125415 | 2021 | 2021
873555 | 02 tweede verdieping | 02 tweede verdieping | -26013.4 | Level : 02 tweede verdieping | 850 | 0.246872 | 892 | 21 | 21 | 0.0125415 | 2021 | 2021
873586 | 02 tweede verdieping | 02 tweede verdieping | -26013.4 | Level : 02 tweede verdieping | 850 | 0.246872 | 892 | 21 | 21 | 0.0125415 | 2021 | 2021
873617 | 02 tweede verdieping | 02 tweede verdieping | -26013.4 | Level : 02 tweede verdieping | 850 | 0.246872 | 892 | 21 | 21 | 0.0125415 | 2021 | 2021
873648 | 02 tweede verdieping | 02 tweede verdieping | -26013.4 | Level : 02 tweede verdieping | 850 | 0.246872 | 892 | 21 | 21 | 0.0125415 | 2021 | 2021
873679 | 02 tweede verdieping | 02 tweede verdieping | -26013.4 | Level : 02 tweede verdieping | 850 | 0.246872 | 892 | 21 | 21 | 0.0125415 | 2021 | 2021
873710 | 02 tweede verdieping | 02 tweede verdieping | -26013.4 | Level : 02 tweede verdieping | 850 | 0.246872 | 892 | 21 | 21 | 0.0125415 | 2021 | 2021
873741 | 02 tweede verdieping | 02 tweede verdieping | -26013.4 | Level : 02 tweede verdieping | 850 | 0.246872 | 892 | 21 | 21 | 0.0125415 | 2021 | 2021
874907 | 01 eerste verdieping | 01 eerste verdieping | -4898.36 | Level : 01 eerste verdieping | 1771 | 0.534755 | 1995 | 112 | 112 | 0.0280497 | 2112 | 2112
874919 | 01 eerste verdieping | 01 eerste verdieping | -4898.36 | Level : 01 eerste verdieping | 1771 | 0.534755 | 1995 | 112 | 112 | 0.0280497 | 2112 | 2112
874931 | 01 eerste verdieping | 01 eerste verdieping | -4898.36 | Level : 01 eerste verdieping | 1771 | 0.534755 | 1995 | 112 | 112 | 0.0280497 | 2112 | 2112
874997 | 01 eerste verdieping | 01 eerste verdieping | -4898.36 | Level : 01 eerste verdieping | 1771 | 0.534755 | 1995 | 112 | 112 | 0.0280497 | 2112 | 2112
875009 | 01 eerste verdieping | 01 eerste verdieping | -4898.36 | Level : 01 eerste verdieping | 1771 | 0.534755 | 1995 | 112 | 112 | 0.0280497 | 2112 | 2112
875021 | 01 eerste verdieping | 01 eerste verdieping | -4898.36 | Level : 01 eerste verdieping | 1771 | 0.534755 | 1995 | 112 | 112 | 0.0280497 | 2112 | 2112
875226 | 01 eerste verdieping | 01 eerste verdieping | -4898.36 | Level : 01 eerste verdieping | 1771 | 0.534755 | 1995 | 112 | 112 | 0.0280497 | 2112 | 2112
875262 | 01 eerste verdieping | 01 eerste verdieping | -4898.36 | Level : 01 eerste verdieping | 1771 | 0.534755 | 1995 | 112 | 112 | 0.0280497 | 2112 | 2112
875298 | 01 eerste verdieping | 01 eerste verdieping | -4898.36 | Level : 01 eerste verdieping | 1771 | 0.534755 | 1995 | 112 | 112 | 0.0280497 | 2112 | 2112
875334 | 01 eerste verdieping | 01 eerste verdieping | -4898.36 | Level : 01 eerste verdieping | 1771 | 0.534755 | 1995 | 112 | 112 | 0.0280497 | 2112 | 2112
875370 | 01 eerste verdieping | 01 eerste verdieping | -4898.36 | Level : 01 eerste verdieping | 1771 | 0.534755 | 1995 | 112 | 112 | 0.0280497 | 2112 | 2112
876535 | 01 eerste verdieping | 01 eerste verdieping | 39916.6 | Level : 01 eerste verdieping | 1771 | 0.534755 | 1995 | 112 | 112 | 0.0280497 | 2112 | 2112
876772 | 01 eerste verdieping | 01 eerste verdieping | 39916.6 | Level : 01 eerste verdieping | 1771 | 0.534755 | 1995 | 112 | 112 | 0.0280497 | 2112 | 2112
876791 | 01 eerste verdieping | 01 eerste verdieping | 39916.6 | Level : 01 eerste verdieping | 1771 | 0.534755 | 1995 | 112 | 112 | 0.0280497 | 2112 | 2112
876937 | 01 eerste verdieping | 01 eerste verdieping | 39916.6 | Level : 01 eerste verdieping | 1771 | 0.534755 | 1995 | 112 | 112 | 0.0280497 | 2112 | 2112
876949 | 01 eerste verdieping | 01 eerste verdieping | 39916.6 | Level : 01 eerste verdieping | 1771 | 0.534755 | 1995 | 112 | 112 | 0.0280497 | 2112 | 2112
876961 | 01 eerste verdieping | 01 eerste verdieping | 39916.6 | Level : 01 eerste verdieping | 1771 | 0.534755 | 1995 | 112 | 112 | 0.0280497 | 2112 | 2112
877054 | 01 eerste verdieping | 01 eerste verdieping | 39916.6 | Level : 01 eerste verdieping | 1771 | 0.534755 | 1995 | 112 | 112 | 0.0280497 | 2112 | 2112
877066 | 01 eerste verdieping | 01 eerste verdieping | 39916.6 | Level : 01 eerste verdieping | 1771 | 0.534755 | 1995 | 112 | 112 | 0.0280497 | 2112 | 2112
877078 | 01 eerste verdieping | 01 eerste verdieping | 39916.6 | Level : 01 eerste verdieping | 1771 | 0.534755 | 1995 | 112 | 112 | 0.0280497 | 2112 | 2112
877144 | 01 eerste verdieping | 01 eerste verdieping | 39916.6 | Level : 01 eerste verdieping | 1771 | 0.534755 | 1995 | 112 | 112 | 0.0280497 | 2112 | 2112
877156 | 01 eerste verdieping | 01 eerste verdieping | 39916.6 | Level : 01 eerste verdieping | 1771 | 0.534755 | 1995 | 112 | 112 | 0.0280497 | 2112 | 2112
877168 | 01 eerste verdieping | 01 eerste verdieping | 39916.6 | Level : 01 eerste verdieping | 1771 | 0.534755 | 1995 | 112 | 112 | 0.0280497 | 2112 | 2112
877234 | 01 eerste verdieping | 01 eerste verdieping | 39916.6 | Level : 01 eerste verdieping | 1771 | 0.534755 | 1995 | 112 | 112 | 0.0280497 | 2112 | 2112
877246 | 01 eerste verdieping | 01 eerste verdieping | 39916.6 | Level : 01 eerste verdieping | 1771 | 0.534755 | 1995 | 112 | 112 | 0.0280497 | 2112 | 2112
880832 | 01 eerste verdieping | 01 eerste verdieping | 14826.6 | Basic Wall : NLRS_22_WA_HSB bispouw 30-245-12-13 glaswol_gen_ISR | 1771 | 0.534755 | 1995 | 112 | 112 | 0.0280497 | 2112 | 2112
881600 | 01 eerste verdieping | 01 eerste verdieping | 14826.6 | Level : 01 eerste verdieping | 1771 | 0.534755 | 1995 | 112 | 112 | 0.0280497 | 2112 | 2112
881636 | 01 eerste verdieping | 01 eerste verdieping | 14826.6 | Level : 01 eerste verdieping | 1771 | 0.534755 | 1995 | 112 | 112 | 0.0280497 | 2112 | 2112
881672 | 01 eerste verdieping | 01 eerste verdieping | 14826.6 | Level : 01 eerste verdieping | 1771 | 0.534755 | 1995 | 112 | 112 | 0.0280497 | 2112 | 2112
881748 | 01 eerste verdieping | 01 eerste verdieping | 14826.6 | Level : 01 eerste verdieping | 1771 | 0.534755 | 1995 | 112 | 112 | 0.0280497 | 2112 | 2112
881775 | 01 eerste verdieping | 01 eerste verdieping | 14826.6 | Level : 01 eerste verdieping | 1771 | 0.534755 | 1995 | 112 | 112 | 0.0280497 | 2112 | 2112
891625 | 01 eerste verdieping | 01 eerste verdieping | 14826.6 | Level : 01 eerste verdieping | 373 | 0.147953 | 513 | 28 | 112 | 0.00721278 | 2028 | 2112
891647 | 01 eerste verdieping | 01 eerste verdieping | 14826.6 | Level : 01 eerste verdieping | 1771 | 0.534755 | 1995 | 112 | 112 | 0.0280497 | 2112 | 2112
891669 | 01 eerste verdieping | 01 eerste verdieping | 14826.6 | Level : 01 eerste verdieping | 1771 | 0.534755 | 1995 | 112 | 112 | 0.0280497 | 2112 | 2112
891691 | 01 eerste verdieping | 01 eerste verdieping | 14826.6 | Level : 01 eerste verdieping | 1771 | 0.534755 | 1995 | 112 | 112 | 0.0280497 | 2112 | 2112
891713 | 01 eerste verdieping | 01 eerste verdieping | 14826.6 | Level : 01 eerste verdieping | 1771 | 0.534755 | 1995 | 112 | 112 | 0.0280497 | 2112 | 2112
891753 | 01 eerste verdieping | 01 eerste verdieping | 46332.7 | Basic Wall : 21_WA_metselwerk_licht_100_gen_bdg | 1771 | 0.534755 | 1995 | 112 | 112 | 0.0280497 | 2112 | 2112
891781 | 01 eerste verdieping | 01 eerste verdieping | 46332.7 | Level : 01 eerste verdieping | 1771 | 0.534755 | 1995 | 112 | 112 | 0.0280497 | 2112 | 2112
891898 | 01 eerste verdieping | 01 eerste verdieping | 46332.7 | Level : 01 eerste verdieping | 1771 | 0.534755 | 1995 | 112 | 112 | 0.0280497 | 2112 | 2112
891920 | 01 eerste verdieping | 01 eerste verdieping | 46332.7 | Level : 01 eerste verdieping | 1771 | 0.534755 | 1995 | 112 | 112 | 0.0280497 | 2112 | 2112
891970 | 01 eerste verdieping | 01 eerste verdieping | 46332.7 | Level : 01 eerste verdieping | 1771 | 0.534755 | 1995 | 112 | 112 | 0.0280497 | 2112 | 2112
1492948 | 00 begane grond | 00 begane grond | 10531.6 | Basic Wall : 21_WA_metselwerk_middel_100_gen_bdg | 3300 | 0.889976 | 3356 | 28 | 28 | 0.0471854 | 2028 | 2028
2239350 | 01 eerste verdieping | 01 eerste verdieping | 46332.7 | Level : 01 eerste verdieping | 1238.5 | 0.373848 | 1378.5 | 28 | 112 | 0.0193817 | 2028 | 2112
2239386 | 01 eerste verdieping | 01 eerste verdieping | -29498.4 | Basic Wall : NLRS_22_WA_HSB bispouw 30-245-12-13 glaswol_gen_ISR | 838.5 | 0.269449 | 978.5 | 28 | 112 | 0.0137577 | 2028 | 2112
2239480 | 01 eerste verdieping | 01 eerste verdieping | 14901.6 | Basic Wall : NLRS_22_WA_HSB bispouw 30-245-12-13 glaswol_gen_ISR | 338.5 | 0.138949 | 478.5 | 28 | 112 | 0.00672771 | 2028 | 2112
2239498 | 01 eerste verdieping | 01 eerste verdieping | -4798.36 | Basic Wall : NLRS_22_WA_HSB bispouw 30-245-12-13 glaswol_gen_ISR | 1238.5 | 0.373848 | 1378.5 | 28 | 112 | 0.0193817 | 2028 | 2112
2546399 | 00 begane grond | 00 begane grond | 10531.6 | Level : 00 begane grond | 900 | 0.263576 | 956 | 28 | 28 | 0.0134414 | 2028 | 2028
2749762 | 01 eerste verdieping | 01 eerste verdieping | -4898.36 | Level : 01 eerste verdieping | 576 | 0.22286 | 800 | 112 | 112 | 0.011248 | 2112 | 2112
2759482 | 01 eerste verdieping | 01 eerste verdieping | 24739.1 | Basic Wall : 22_WA_binnenwand_ms125 25-75-25 _gen_bdg | 1238.5 | 0.373848 | 1378.5 | 28 | 112 | 0.0193817 | 2028 | 2112
2762378 | 01 eerste verdieping | 01 eerste verdieping | 24732.5 | Basic Wall : 22_WA_koof_96 12-12-50 | 338.5 | 0.138949 | 478.5 | 28 | 112 | 0.00672771 | 2028 | 2112
4343093 | 01 eerste verdieping | 01 eerste verdieping | 14826.6 | Level : 01 eerste verdieping | 1398 | 0.415478 | 1538 | 28 | 112 | 0.0216243 | 2028 | 2112

# IfcBuildingElementProxy: NLRS_41_GM_WPB_spouwlat-SH_generiek_ISR:187x38 (3)
Type - Material: i4_hout_gen
Type - Constraints - Default Elevation: 1219.2 mm
Type - Materials and Finishes - materiaal: i4_hout_gen
Type - Dimensions - breedte: 38 mm; hoogte: 187 mm
Type - Identity Data - Workset: Family : Generic Models : NLRS_41_GM_WPB_spouwlat-SH_generiek_ISR; Assembly Code: 21; Assembly Description: buitenwanden; Datum_Gewijzigd: 20160502; Description: spouwlat; Model: LOD300; SmartRevit_Versie: 2019.1; Type Name: 187x38
Type - Other - Category: Generic Models; Family Name: NLRS_41_GM_WPB_spouwlat-SH_generiek_ISR
Classification: 21 Uniformat (Uniformat)
Constraints - Moves With Nearby Elements: no
Phasing - Phase Created: 2. nieuwbouw
Graphics - hoek_a: 0 deg; hoek_b: 0 deg
Dimensions - NLRS_C_breedte: 38 mm; NLRS_C_hoogte: 187 mm
Identity Data - Workset: Workset1
Other - berekende_hoek_a: 0 deg; berekende_overstek_a: 0 mm; berekende_overstek_b: 0 mm; Family: NLRS_41_GM_WPB_spouwlat-SH_generiek_ISR; Family and Type: NLRS_41_GM_WPB_spouwlat-SH_generiek_ISR: 187x38; Type: 187x38; Type Id: 2326734
Name (NLRS_41_GM_WPB_spouwlat-SH_generiek_ISR:187x38:...) | In | Level | Elevation from Level (mm) = Offset from Host (mm) | Host | lengte (mm) = NLRS_C_lengte (mm) | Area (m2) | element_lengte (mm) | verlenging_a (mm) = verlenging_b (mm) | Volume (m3) | berekende_verlenging_a (mm) = berekende_verlenging_b (mm)
1836032 | 01 eerste verdieping | 01 eerste verdieping | 43637 | Basic Wall : NLRS_22_WA_HSB bispouw 30-245-12-13 glaswol_gen_ISR | 1771 | 0.418181 | 1827 | 28 | 0.0129827 | 2028
1847951 | 02 tweede verdieping | 02 tweede verdieping | 41114.1 | Basic Wall : 22_WA_binnenwand_ms125 25-75-25 _gen_bdg | 4850 | 1.10781 | 4892 | 21 | 0.0347626 | 2021
2749552 | 01 eerste verdieping | 01 eerste verdieping | 43637 | Level : 01 eerste verdieping | 1771 | 0.418181 | 1827 | 28 | 0.0129827 | 2028

# IfcBuildingElementProxy: NLRS_41_GM_WPB_spouwlat-SH_generiek_ISR:DTS 130x80 (2)
In: 00 begane grond
Type - Material: 00_Natuursteen
Type - Constraints - Default Elevation: 1219.2 mm
Type - Materials and Finishes - materiaal: 00_Natuursteen
Type - Dimensions - breedte: 130 mm; hoogte: 80 mm
Type - Identity Data - Workset: Family : Generic Models : NLRS_41_GM_WPB_spouwlat-SH_generiek_ISR; Assembly Code: 21; Assembly Description: buitenwanden; Datum_Gewijzigd: 20160502; Description: spouwlat; Model: LOD300; SmartRevit_Versie: 2019.1; Type Name: DTS 130x80
Type - Other - Category: Generic Models; Family Name: NLRS_41_GM_WPB_spouwlat-SH_generiek_ISR
Classification: 21 Uniformat (Uniformat)
Constraints - Level: 00 begane grond; Moves With Nearby Elements: no; Elevation from Level: 959.638 mm; Host: Basic Wall : NLRS_22_WA_HSB bispouw 30-245-12-13 glaswol_gen_ISR; Offset from Host: 959.638 mm
Phasing - Phase Created: 2. nieuwbouw
Graphics - hoek_a: 0 deg; hoek_b: 0 deg
Dimensions - NLRS_C_breedte: 130 mm; NLRS_C_hoogte: 80 mm; verlenging_a: -45 mm; verlenging_b: -45 mm
Identity Data - Workset: Workset1
Other - berekende_hoek_a: 0 deg; berekende_overstek_a: 0 mm; berekende_overstek_b: 0 mm; Family: NLRS_41_GM_WPB_spouwlat-SH_generiek_ISR; berekende_verlenging_a: 1955 mm; berekende_verlenging_b: 1955 mm; Family and Type: NLRS_41_GM_WPB_spouwlat-SH_generiek_ISR: DTS 130x80; Type: DTS 130x80; Type Id: 4862059
Name (NLRS_41_GM_WPB_spouwlat-SH_generiek_ISR:DTS 130x80:...) | lengte (mm) = NLRS_C_lengte (mm) | Area (m2) | element_lengte (mm) | Volume (m3)
4862519 | 2461 | 0.50831 | 2371 | 0.0246584
4862538 | 5212 | 1.08602 | 5122 | 0.0532688

# IfcBuildingElementProxy: NLRS_41_GM_WPB_waterslag barok-SH_roval_ISR:waterslag_roval_Types Barok_roval_b 270 (43)
In: 02 tweede verdieping
Type - Material: h4_aluminium
Type - Constraints - Default Elevation: 1219.2 mm
Type - Dimensions - breedte: 270 mm; hoogte: 85 mm
Type - Identity Data - Workset: Family : Generic Models : NLRS_41_GM_WPB_waterslag barok-SH_roval_ISR; Assembly Code: 2D(41.1); Datum_Gewijzigd: 20150713; Description: Roval waterslag Barok; Model: LOD400; SmartRevit_Versie: 2015.4; Type Name: waterslag_roval_Types Barok_roval_b 270
Type - Other - Category: Generic Models; Family Name: NLRS_41_GM_WPB_waterslag barok-SH_roval_ISR
Classification: 2D(41.1) Uniformat (Uniformat)
Constraints - Moves With Nearby Elements: no; Level: 02 tweede verdieping; Elevation from Level: 869.638 mm; lengte: 1064 mm; Offset from Host: 869.638 mm
Phasing - Phase Created: 2. nieuwbouw
Graphics - hoek_a: 0 deg; hoek_b: 0 deg
Dimensions - Area: 0.2837 m2; element_lengte: 864 mm; NLRS_C_breedte: 270 mm; NLRS_C_hoogte: 85 mm; NLRS_C_lengte: 1064 mm; verlenging_a: -100 mm; verlenging_b: -100 mm; Volume: 0.000493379 m3
Identity Data - Workset: Workset1
Other - berekende_hoek_a: 0 deg; berekende_overstek_a: 0 mm; berekende_overstek_b: 0 mm; Family: NLRS_41_GM_WPB_waterslag barok-SH_roval_ISR; berekende_verlenging_a: 1900 mm; berekende_verlenging_b: 1900 mm; Family and Type: NLRS_41_GM_WPB_waterslag barok-SH_roval_ISR: waterslag_roval_Types Barok_roval_b 270; Type: waterslag_roval_Types Barok_roval_b 270; Type Id: 2037752
Name (NLRS_41_GM_WPB_waterslag barok-SH_roval_ISR:waterslag_roval_Types Barok_roval_b 270:...) | Host
859965 | Basic Wall : NLRS_22_WA_HSB bispouw 30-245-12-13 glaswol_gen_ISR
864451 | Level : 02 tweede verdieping
864482 | Level : 02 tweede verdieping
870609 | Level : 02 tweede verdieping
870626 | Level : 02 tweede verdieping
870643 | Level : 02 tweede verdieping
870691 | Level : 02 tweede verdieping
870708 | Level : 02 tweede verdieping
870725 | Level : 02 tweede verdieping
870804 | Level : 02 tweede verdieping
870821 | Level : 02 tweede verdieping
870838 | Level : 02 tweede verdieping
870948 | Basic Wall : 21_WA_metselwerk_licht_100_gen_bdg
871626 | Level : 02 tweede verdieping
871659 | Level : 02 tweede verdieping
871692 | Level : 02 tweede verdieping
871878 | Level : 02 tweede verdieping
871910 | Level : 02 tweede verdieping
871942 | Level : 02 tweede verdieping
871974 | Level : 02 tweede verdieping
872038 | Basic Wall : 21_WA_metselwerk_licht_100_gen_bdg
872073 | Basic Wall : 21_WA_metselwerk_licht_100_gen_bdg
872799 | Level : 02 tweede verdieping
872832 | Level : 02 tweede verdieping
872865 | Level : 02 tweede verdieping
872898 | Level : 02 tweede verdieping
872931 | Level : 02 tweede verdieping
872964 | Level : 02 tweede verdieping
872997 | Level : 02 tweede verdieping
873030 | Level : 02 tweede verdieping
873063 | Level : 02 tweede verdieping
873096 | Level : 02 tweede verdieping
873407 | Level : 02 tweede verdieping
873457 | Level : 02 tweede verdieping
873488 | Level : 02 tweede verdieping
873519 | Level : 02 tweede verdieping
873550 | Level : 02 tweede verdieping
873581 | Level : 02 tweede verdieping
873612 | Level : 02 tweede verdieping
873643 | Level : 02 tweede verdieping
873674 | Level : 02 tweede verdieping
873705 | Level : 02 tweede verdieping
873736 | Level : 02 tweede verdieping

# IfcBuildingElementProxy: NLRS_41_GM_WPB_waterslag barok-SH_roval_ISR:waterslag_roval_Types Barok_roval_b 320 (52)
In: 01 eerste verdieping
Type - Material: h4_aluminium
Type - Constraints - Default Elevation: 1219.2 mm
Type - Materials and Finishes - materiaal: h4_aluminium
Type - Dimensions - breedte: 320 mm; hoogte: 85 mm
Type - Identity Data - Assembly Code: 2D(41.1); Datum_Gewijzigd: 20150713; Description: Roval waterslag Barok; Model: LOD400; SmartRevit_Versie: 2015.4; Type Name: waterslag_roval_Types Barok_roval_b 320; Workset: Family : Generic Models : NLRS_41_GM_WPB_waterslag barok-SH_roval_ISR
Type - Other - Category: Generic Models; Family Name: NLRS_41_GM_WPB_waterslag barok-SH_roval_ISR
Classification: 2D(41.1) Uniformat (Uniformat)
Constraints - Moves With Nearby Elements: no; Level: 01 eerste verdieping
Phasing - Phase Created: 2. nieuwbouw
Graphics - hoek_b: 0 deg
Dimensions - verlenging_b: 0 mm; NLRS_C_breedte: 320 mm; NLRS_C_hoogte: 85 mm
Identity Data - Workset: Workset1
Other - berekende_overstek_b: 0 mm; berekende_verlenging_b: 2000 mm; Family: NLRS_41_GM_WPB_waterslag barok-SH_roval_ISR; Family and Type: NLRS_41_GM_WPB_waterslag barok-SH_roval_ISR: waterslag_roval_Types Barok_roval_b 320; Type: waterslag_roval_Types Barok_roval_b 320; Type Id: 865095
Name (NLRS_41_GM_WPB_waterslag barok-SH_roval_ISR:waterslag_roval_Types Barok_roval_b 320:...) | Elevation from Level (mm) = Offset from Host (mm) | Host | lengte (mm) = NLRS_C_lengte (mm) | hoek_a (deg) | verlenging_a (mm) | Area (m2) | element_lengte (mm) | Volume (m3) | berekende_hoek_a (deg) | berekende_overstek_a (mm) | berekende_verlenging_a (mm)
832750 | 889.638 | Basic Wall : NLRS_22_WA_HSB bispouw 30-245-12-13 glaswol_gen_ISR | 1785 | 0 | 0 | 0.675177 | 1785 | 0.0011754 | 0 | 0 | 2000
858910 | 889.638 | Level : 01 eerste verdieping | 1785 | 0 | 0 | 0.675177 | 1785 | 0.0011754 | 0 | 0 | 2000
858936 | 889.638 | Level : 01 eerste verdieping | 1785 | 0 | 0 | 0.675177 | 1785 | 0.0011754 | 0 | 0 | 2000
874902 | 889.638 | Level : 01 eerste verdieping | 1785 | 0 | 0 | 0.675177 | 1785 | 0.0011754 | 0 | 0 | 2000
874914 | 889.638 | Level : 01 eerste verdieping | 1785 | 0 | 0 | 0.675177 | 1785 | 0.0011754 | 0 | 0 | 2000
874926 | 889.638 | Level : 01 eerste verdieping | 1785 | 0 | 0 | 0.675177 | 1785 | 0.0011754 | 0 | 0 | 2000
874992 | 889.638 | Level : 01 eerste verdieping | 1785 | 0 | 0 | 0.675177 | 1785 | 0.0011754 | 0 | 0 | 2000
875004 | 889.638 | Level : 01 eerste verdieping | 1785 | 0 | 0 | 0.675177 | 1785 | 0.0011754 | 0 | 0 | 2000
875016 | 889.638 | Level : 01 eerste verdieping | 1785 | 0 | 0 | 0.675177 | 1785 | 0.0011754 | 0 | 0 | 2000
875221 | 889.638 | Level : 01 eerste verdieping | 1785 | 0 | 0 | 0.675177 | 1785 | 0.0011754 | 0 | 0 | 2000
875257 | 889.638 | Level : 01 eerste verdieping | 1785 | 0 | 0 | 0.675177 | 1785 | 0.0011754 | 0 | 0 | 2000
875293 | 889.638 | Level : 01 eerste verdieping | 1785 | 0 | 0 | 0.675177 | 1785 | 0.0011754 | 0 | 0 | 2000
875329 | 889.638 | Level : 01 eerste verdieping | 1785 | 0 | 0 | 0.675177 | 1785 | 0.0011754 | 0 | 0 | 2000
875365 | 889.638 | Level : 01 eerste verdieping | 1785 | 0 | 0 | 0.675177 | 1785 | 0.0011754 | 0 | 0 | 2000
876530 | 869.638 | Level : 01 eerste verdieping | 1785 | 0 | 0 | 0.675177 | 1785 | 0.0011754 | 0 | 0 | 2000
876767 | 869.638 | Level : 01 eerste verdieping | 1785 | 0 | 0 | 0.675177 | 1785 | 0.0011754 | 0 | 0 | 2000
876786 | 869.638 | Level : 01 eerste verdieping | 1785 | 0 | 0 | 0.675177 | 1785 | 0.0011754 | 0 | 0 | 2000
876932 | 869.638 | Level : 01 eerste verdieping | 1785 | 0 | 0 | 0.675177 | 1785 | 0.0011754 | 0 | 0 | 2000
876944 | 869.638 | Level : 01 eerste verdieping | 1785 | 0 | 0 | 0.675177 | 1785 | 0.0011754 | 0 | 0 | 2000
876956 | 869.638 | Level : 01 eerste verdieping | 1785 | 0 | 0 | 0.675177 | 1785 | 0.0011754 | 0 | 0 | 2000
877049 | 869.638 | Level : 01 eerste verdieping | 1785 | 0 | 0 | 0.675177 | 1785 | 0.0011754 | 0 | 0 | 2000
877061 | 869.638 | Level : 01 eerste verdieping | 1785 | 0 | 0 | 0.675177 | 1785 | 0.0011754 | 0 | 0 | 2000
877073 | 869.638 | Level : 01 eerste verdieping | 1785 | 0 | 0 | 0.675177 | 1785 | 0.0011754 | 0 | 0 | 2000
877139 | 869.638 | Level : 01 eerste verdieping | 1785 | 0 | 0 | 0.675177 | 1785 | 0.0011754 | 0 | 0 | 2000
877151 | 869.638 | Level : 01 eerste verdieping | 1785 | 0 | 0 | 0.675177 | 1785 | 0.0011754 | 0 | 0 | 2000
877163 | 869.638 | Level : 01 eerste verdieping | 1785 | 0 | 0 | 0.675177 | 1785 | 0.0011754 | 0 | 0 | 2000
877229 | 869.638 | Level : 01 eerste verdieping | 1785 | 0 | 0 | 0.675177 | 1785 | 0.0011754 | 0 | 0 | 2000
877241 | 869.638 | Level : 01 eerste verdieping | 1785 | 0 | 0 | 0.675177 | 1785 | 0.0011754 | 0 | 0 | 2000
880827 | 869.638 | Basic Wall : NLRS_22_WA_HSB bispouw 30-245-12-13 glaswol_gen_ISR | 1785 | 0 | 0 | 0.675177 | 1785 | 0.0011754 | 0 | 0 | 2000
881595 | 869.638 | Level : 01 eerste verdieping | 1785 | 0 | 0 | 0.675177 | 1785 | 0.0011754 | 0 | 0 | 2000
881631 | 869.638 | Level : 01 eerste verdieping | 1785 | 0 | 0 | 0.675177 | 1785 | 0.0011754 | 0 | 0 | 2000
881667 | 869.638 | Level : 01 eerste verdieping | 1785 | 0 | 0 | 0.675177 | 1785 | 0.0011754 | 0 | 0 | 2000
881743 | 869.638 | Level : 01 eerste verdieping | 1785 | 0 | 0 | 0.675177 | 1785 | 0.0011754 | 0 | 0 | 2000
881770 | 869.638 | Level : 01 eerste verdieping | 1785 | 0 | 0 | 0.675177 | 1785 | 0.0011754 | 0 | 0 | 2000
891620 | 869.638 | Level : 01 eerste verdieping | 387 | 0 | -7 | 0.144254 | 380 | 0.000250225 | 0 | 0 | 1993
891642 | 869.638 | Level : 01 eerste verdieping | 1785 | 0 | 0 | 0.675177 | 1785 | 0.0011754 | 0 | 0 | 2000
891664 | 869.638 | Level : 01 eerste verdieping | 1785 | 0 | 0 | 0.675177 | 1785 | 0.0011754 | 0 | 0 | 2000
891686 | 869.638 | Level : 01 eerste verdieping | 1785 | 0 | 0 | 0.675177 | 1785 | 0.0011754 | 0 | 0 | 2000
891708 | 869.638 | Level : 01 eerste verdieping | 1785 | 0 | 0 | 0.675177 | 1785 | 0.0011754 | 0 | 0 | 2000
891748 | 869.638 | Basic Wall : 21_WA_metselwerk_licht_100_gen_bdg | 1785 | 0 | 0 | 0.675177 | 1785 | 0.0011754 | 0 | 0 | 2000
891776 | 869.638 | Level : 01 eerste verdieping | 1785 | 0 | 0 | 0.675177 | 1785 | 0.0011754 | 0 | 0 | 2000
891893 | 869.638 | Level : 01 eerste verdieping | 1785 | 0 | 0 | 0.675177 | 1785 | 0.0011754 | 0 | 0 | 2000
891915 | 869.638 | Level : 01 eerste verdieping | 1785 | 0 | 0 | 0.675177 | 1785 | 0.0011754 | 0 | 0 | 2000
891965 | 869.638 | Level : 01 eerste verdieping | 1785 | 0 | 0 | 0.675177 | 1785 | 0.0011754 | 0 | 0 | 2000
2239345 | 869.638 | Level : 01 eerste verdieping | 1252.5 | 45 | 20 | 0.545643 | 1592.5 | 0.000948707 | -45 | 320 | 2020
2239382 | 876.638 | Basic Wall : NLRS_22_WA_HSB bispouw 30-245-12-13 glaswol_gen_ISR | 852.5 | 45 | 20 | 0.39449 | 1192.5 | 0.000685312 | -45 | 320 | 2020
2239476 | 876.638 | Basic Wall : NLRS_22_WA_HSB bispouw 30-245-12-13 glaswol_gen_ISR | 352.5 | 45 | 20 | 0.205549 | 692.5 | 0.000356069 | -45 | 320 | 2020
2239494 | 876.638 | Basic Wall : NLRS_22_WA_HSB bispouw 30-245-12-13 glaswol_gen_ISR | 1252.5 | 45 | 20 | 0.545643 | 1592.5 | 0.000948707 | -45 | 320 | 2020
2749757 | 889.638 | Level : 01 eerste verdieping | 590 | 0 | 0 | 0.223609 | 590 | 0.000388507 | 0 | 0 | 2000
2759478 | 876.638 | Basic Wall : 22_WA_binnenwand_ms125 25-75-25 _gen_bdg | 1252.5 | 45 | 20 | 0.545643 | 1592.5 | 0.000948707 | -45 | 320 | 2020
2762374 | 876.638 | Basic Wall : 22_WA_koof_96 12-12-50 | 352.5 | 45 | 20 | 0.205549 | 692.5 | 0.000356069 | -45 | 320 | 2020
4343089 | 869.638 | Level : 01 eerste verdieping | 1412 | 0 | -7 | 0.531582 | 1405 | 0.000925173 | 0 | 0 | 1993

# IfcBuildingElementProxy: NLRS_41_GM_un_screen_gen_bdg:screen95 (118)
Type - Material: h4_aluminium als kozijn
Type - Constraints - Default Elevation: 1219.2 mm; screendoek_gelijk_aan_hoogte: yes
Type - Dimensions - kast_afmeting: 95 mm; kast_breedte: 95 mm; kast_hoogte: 95 mm; screendoek_hoogte: 2850 mm
Type - Identity Data - Assembly Code: 31.20; Assembly Description: buitenwandopeningen; gevuld met ramen, algemeen (verzamelniveau); Description: screen; Type Name: screen95; Workset: Family : Generic Models : NLRS_41_GM_un_screen_gen_bdg
Type - Other - Category: Generic Models; Family Name: NLRS_41_GM_un_screen_gen_bdg; hartlijn diagonaal: no; kast_125: no; kast_75: no; kast_85: no
Classification: 31.20 Uniformat (Uniformat)
Phasing - Phase Created: 2. nieuwbouw
Identity Data - Workset: Workset1
Other - Family: NLRS_41_GM_un_screen_gen_bdg; Family and Type: NLRS_41_GM_un_screen_gen_bdg: screen95; NLRS_C_breedte_02: 0 mm; NLRS_C_hoogte_02: 50 mm; Type: screen95; Type Id: 867660
Name (NLRS_41_GM_un_screen_gen_bdg:screen95:...) | In | Level = Schedule Level | Elevation from Level (mm) | Offset from Host (mm) | Work Plane | Area (m2) | berekende_screendoek_hoogte (mm) = hoogte_totaal (mm) = NLRS_C_hoogte (mm) | breedte_totaal (mm) = NLRS_C_breedte (mm) = NLRS_C_breedte_01 (mm) | Volume (m3) | berekende_-hoogte (mm) | NLRS_C_hoogte_01 (mm) | Group
874673 | 01 eerste verdieping | 01 eerste verdieping | 2975 | 2975 | Level : 01 eerste verdieping | 0.587815 | 2115 | 1761 | 0.019529 | -2115 | 1970 | Model Group:BU-26:874674
874957 | 01 eerste verdieping | 01 eerste verdieping | 2975 | 2975 | Level : 01 eerste verdieping | 0.587815 | 2115 | 1761 | 0.019529 | -2115 | 1970 | Model Group:BU-26:874958
875038 | 01 eerste verdieping | 01 eerste verdieping | 2975 | 2975 | Level : 01 eerste verdieping | 0.587815 | 2115 | 1761 | 0.019529 | -2115 | 1970 | Model Group:BU-29A:875039
875047 | 01 eerste verdieping | 01 eerste verdieping | 2975 | 2975 | Level : 01 eerste verdieping | 0.587815 | 2115 | 1761 | 0.019529 | -2115 | 1970 | Model Group:BU-26:875048
875056 | 01 eerste verdieping | 01 eerste verdieping | 2975 | 2975 | Level : 01 eerste verdieping | 0.587815 | 2115 | 1761 | 0.019529 | -2115 | 1970 | Model Group:BU-28B:875057
875275 | 01 eerste verdieping | 01 eerste verdieping | 2975 | 2975 | Level : 01 eerste verdieping | 0.587815 | 2115 | 1761 | 0.019529 | -2115 | 1970 | Model Group:BU-26:875276
875311 | 01 eerste verdieping | 01 eerste verdieping | 2975 | 2975 | Level : 01 eerste verdieping | 0.588765 | 2115 | 1766 | 0.0195741 | -2115 | 1970 | Model Group:BU-28A:875312
875383 | 01 eerste verdieping | 01 eerste verdieping | 2975 | 2975 | Level : 01 eerste verdieping | 0.587815 | 2115 | 1761 | 0.019529 | -2115 | 1970 | Model Group:BU-26:875384
876494 | 01 eerste verdieping | 01 eerste verdieping | 2975 | 2975 | Level : 01 eerste verdieping | 0.587815 | 2115 | 1761 | 0.019529 | -2115 | 1970 | Model Group:BU-26:876495
876912 | 01 eerste verdieping | 01 eerste verdieping | 2975 | 2975 | Level : 01 eerste verdieping | 0.587815 | 2115 | 1761 | 0.019529 | -2115 | 1970 | Model Group:BU-26:876913
877029 | 01 eerste verdieping | 01 eerste verdieping | 2975 | 2975 | Level : 01 eerste verdieping | 0.587815 | 2115 | 1761 | 0.019529 | -2115 | 1970 | Model Group:BU-26:877030
877119 | 01 eerste verdieping | 01 eerste verdieping | 2975 | 2975 | Level : 01 eerste verdieping | 0.587815 | 2115 | 1761 | 0.019529 | -2115 | 1970 | Model Group:BU-26:877120
880928 | 01 eerste verdieping | 01 eerste verdieping | 2975 | 2975 | Level : 01 eerste verdieping | 0.587815 | 2115 | 1761 | 0.019529 | -2115 | 1970 | Model Group:BU-26:880929
881689 | 01 eerste verdieping | 01 eerste verdieping | 2975 | 2975 | Level : 01 eerste verdieping | 0.587815 | 2115 | 1761 | 0.019529 | -2115 | 1970 | Model Group:BU-26:881690
891681 | 01 eerste verdieping | 01 eerste verdieping | 2975 | 2975 | Level : 01 eerste verdieping | 0.587815 | 2115 | 1761 | 0.019529 | -2115 | 1970 | Model Group:BU-26:891682
891793 | 01 eerste verdieping | 01 eerste verdieping | 2975 | 2975 | Level : 01 eerste verdieping | 0.587815 | 2115 | 1761 | 0.019529 | -2115 | 1970 | Model Group:BU-26:891794
891910 | 01 eerste verdieping | 01 eerste verdieping | 2975 | 2975 | Level : 01 eerste verdieping | 0.587815 | 2115 | 1761 | 0.019529 | -2115 | 1970 | Model Group:BU-26:891911
891932 | 01 eerste verdieping | 01 eerste verdieping | 2975 | 2975 | Level : 01 eerste verdieping | 0.587815 | 2115 | 1761 | 0.019529 | -2115 | 1970 | Model Group:BU-26:891933
891982 | 01 eerste verdieping | 01 eerste verdieping | 2975 | 2975 | Level : 01 eerste verdieping | 0.587815 | 2115 | 1761 | 0.019529 | -2115 | 1970 | Model Group:BU-26:891983
1864621 | 01 eerste verdieping | 01 eerste verdieping | 2975 | 2975 | Level : 01 eerste verdieping | 0.587815 | 2115 | 1761 | 0.019529 | -2115 | 1970 | Model Group:BU-29:874949
1864939 | 01 eerste verdieping | 01 eerste verdieping | 2975 | 2975 | Level : 01 eerste verdieping | 0.587815 | 2115 | 1761 | 0.019529 | -2115 | 1970 | Model Group:BU-28B:874967
1864983 | 01 eerste verdieping | 01 eerste verdieping | 2975 | 2975 | Level : 01 eerste verdieping | 0.587815 | 2115 | 1761 | 0.019529 | -2115 | 1970 | Model Group:BU-29A:874609
1865008 | 01 eerste verdieping | 01 eerste verdieping | 2975 | 2975 | Level : 01 eerste verdieping | 0.587815 | 2115 | 1761 | 0.019529 | -2115 | 1970 | Model Group:BU-28B:874689
1865031 | 01 eerste verdieping | 01 eerste verdieping | 2975 | 2975 | Level : 01 eerste verdieping | 0.587815 | 2115 | 1761 | 0.019529 | -2115 | 1970 | Model Group:BU-29A:875240
1865575 | 01 eerste verdieping | 01 eerste verdieping | 2975 | 2975 | Level : 01 eerste verdieping | 0.588765 | 2115 | 1766 | 0.0195741 | -2115 | 1970 | Model Group:BU-28A:876928
1865609 | 01 eerste verdieping | 01 eerste verdieping | 2975 | 2975 | Level : 01 eerste verdieping | 0.588765 | 2115 | 1766 | 0.0195741 | -2115 | 1970 | Model Group:BU-28A:877135
1865656 | 01 eerste verdieping | 01 eerste verdieping | 2975 | 2975 | Level : 01 eerste verdieping | 0.588765 | 2115 | 1766 | 0.0195741 | -2115 | 1970 | Model Group:BI-29B:876898
1865675 | 01 eerste verdieping | 01 eerste verdieping | 2975 | 2975 | Level : 01 eerste verdieping | 0.588765 | 2115 | 1766 | 0.0195741 | -2115 | 1970 | Model Group:BI-29B:877015
1865782 | 01 eerste verdieping | 01 eerste verdieping | 2975 | 2975 | Level : 01 eerste verdieping | 0.588765 | 2115 | 1766 | 0.0195741 | -2115 | 1970 | Model Group:BU-28A:881793
1865803 | 01 eerste verdieping | 01 eerste verdieping | 2975 | 2975 | Level : 01 eerste verdieping | 0.588765 | 2115 | 1766 | 0.0195741 | -2115 | 1970 | Model Group:BI-29B:881766
1865924 | 01 eerste verdieping | 01 eerste verdieping | 2975 | 2975 | Level : 01 eerste verdieping | 0.587815 | 2115 | 1761 | 0.019529 | -2115 | 1970 | Model Group:BU-28B:891704
1865947 | 01 eerste verdieping | 01 eerste verdieping | 2975 | 2975 | Level : 01 eerste verdieping | 0.587815 | 2115 | 1761 | 0.019529 | -2115 | 1970 | Model Group:BU-29A:891726
1866083 | 01 eerste verdieping | 01 eerste verdieping | 2975 | 2975 | Level : 01 eerste verdieping | 0.587815 | 2115 | 1761 | 0.019529 | -2115 | 1970 | Model Group:BU-29C:891772
1867158 | 02 tweede verdieping | 02 tweede verdieping | 3168 | 3168 | Level : 02 tweede verdieping | 0.457225 | 2485 | 840 | 0.011883 | -2485 | 2340 | Model Group:BU-39:870548
1867595 | 02 tweede verdieping | 02 tweede verdieping | 3168 | 3168 | Level : 02 tweede verdieping | 0.457225 | 2485 | 840 | 0.011883 | -2485 | 2340 | Model Group:BU-39:870754
1867599 | 02 tweede verdieping | 02 tweede verdieping | 3168 | 3168 | Level : 02 tweede verdieping | 0.457225 | 2485 | 840 | 0.011883 | -2485 | 2340 | Model Group:BU-39:870867
1867605 | 02 tweede verdieping | 02 tweede verdieping | 3168 | 3168 | Level : 02 tweede verdieping | 0.457225 | 2485 | 840 | 0.011883 | -2485 | 2340 | Model Group:BU-39:871642
1867607 | 02 tweede verdieping | 02 tweede verdieping | 3168 | 3168 | Level : 02 tweede verdieping | 0.457225 | 2485 | 840 | 0.011883 | -2485 | 2340 | Model Group:BU-39:871675
1867613 | 02 tweede verdieping | 02 tweede verdieping | 3168 | 3168 | Level : 02 tweede verdieping | 0.457225 | 2485 | 840 | 0.011883 | -2485 | 2340 | Model Group:BU-39:871926
1867615 | 02 tweede verdieping | 02 tweede verdieping | 3168 | 3168 | Level : 02 tweede verdieping | 0.457225 | 2485 | 840 | 0.011883 | -2485 | 2340 | Model Group:BU-39:871958
1867623 | 02 tweede verdieping | 02 tweede verdieping | 3168 | 3168 | Level : 02 tweede verdieping | 0.457225 | 2485 | 840 | 0.011883 | -2485 | 2340 | Model Group:BU-39:872820
1867627 | 02 tweede verdieping | 02 tweede verdieping | 3168 | 3168 | Level : 02 tweede verdieping | 0.457225 | 2485 | 840 | 0.011883 | -2485 | 2340 | Model Group:BU-39:872886
1867629 | 02 tweede verdieping | 02 tweede verdieping | 3168 | 3168 | Level : 02 tweede verdieping | 0.457225 | 2485 | 840 | 0.011883 | -2485 | 2340 | Model Group:BU-39:872919
1867631 | 02 tweede verdieping | 02 tweede verdieping | 3168 | 3168 | Level : 02 tweede verdieping | 0.457225 | 2485 | 840 | 0.011883 | -2485 | 2340 | Model Group:BU-39:872952
1867633 | 02 tweede verdieping | 02 tweede verdieping | 3168 | 3168 | Level : 02 tweede verdieping | 0.457225 | 2485 | 840 | 0.011883 | -2485 | 2340 | Model Group:BU-39:872985
1867635 | 02 tweede verdieping | 02 tweede verdieping | 3168 | 3168 | Level : 02 tweede verdieping | 0.457225 | 2485 | 840 | 0.011883 | -2485 | 2340 | Model Group:BU-39:873018
1867639 | 02 tweede verdieping | 02 tweede verdieping | 3168 | 3168 | Level : 02 tweede verdieping | 0.457225 | 2485 | 840 | 0.011883 | -2485 | 2340 | Model Group:BU-39:873084
1867649 | 02 tweede verdieping | 02 tweede verdieping | 3168 | 3168 | Level : 02 tweede verdieping | 0.457225 | 2485 | 840 | 0.011883 | -2485 | 2340 | Model Group:BU-39:873515
1867655 | 02 tweede verdieping | 02 tweede verdieping | 3168 | 3168 | Level : 02 tweede verdieping | 0.457225 | 2485 | 840 | 0.011883 | -2485 | 2340 | Model Group:BU-39:873608
1867661 | 02 tweede verdieping | 02 tweede verdieping | 3168 | 3168 | Level : 02 tweede verdieping | 0.457225 | 2485 | 840 | 0.011883 | -2485 | 2340 | Model Group:BU-39:873701
1867725 | 02 tweede verdieping | 02 tweede verdieping | 3168 | 3168 | Level : 02 tweede verdieping | 0.457225 | 2485 | 840 | 0.011883 | -2485 | 2340 | Model Group:BU-39A:1867105
1869352 | 02 tweede verdieping | 02 tweede verdieping | 3168 | 3168 | Level : 02 tweede verdieping | 0.457225 | 2485 | 840 | 0.011883 | -2485 | 2340 | Model Group:BU-39A:865431
1869369 | 02 tweede verdieping | 02 tweede verdieping | 3168 | 3168 | Level : 02 tweede verdieping | 0.457225 | 2485 | 840 | 0.011883 | -2485 | 2340 | Model Group:BU-39A:870563
1869386 | 02 tweede verdieping | 02 tweede verdieping | 3168 | 3168 | Level : 02 tweede verdieping | 0.457225 | 2485 | 840 | 0.011883 | -2485 | 2340 | Model Group:BU-39A:870664
1869403 | 02 tweede verdieping | 02 tweede verdieping | 3168 | 3168 | Level : 02 tweede verdieping | 0.457225 | 2485 | 840 | 0.011883 | -2485 | 2340 | Model Group:BU-39A:870680
1869420 | 02 tweede verdieping | 02 tweede verdieping | 3168 | 3168 | Level : 02 tweede verdieping | 0.457225 | 2485 | 840 | 0.011883 | -2485 | 2340 | Model Group:BU-39A:870746
1869437 | 02 tweede verdieping | 02 tweede verdieping | 3168 | 3168 | Level : 02 tweede verdieping | 0.457225 | 2485 | 840 | 0.011883 | -2485 | 2340 | Model Group:BU-39A:870762
1869454 | 02 tweede verdieping | 02 tweede verdieping | 3168 | 3168 | Level : 02 tweede verdieping | 0.457225 | 2485 | 840 | 0.011883 | -2485 | 2340 | Model Group:BU-39A:870875
1869612 | 02 tweede verdieping | 02 tweede verdieping | 3168 | 3168 | Level : 02 tweede verdieping | 0.457225 | 2485 | 840 | 0.011883 | -2485 | 2340 | Model Group:BU-39B:873453
1869629 | 02 tweede verdieping | 02 tweede verdieping | 3168 | 3168 | Level : 02 tweede verdieping | 0.457225 | 2485 | 840 | 0.011883 | -2485 | 2340 | Model Group:BU-39B:873484
1869646 | 02 tweede verdieping | 02 tweede verdieping | 3168 | 3168 | Level : 02 tweede verdieping | 0.457225 | 2485 | 840 | 0.011883 | -2485 | 2340 | Model Group:BU-39B:873546
1869663 | 02 tweede verdieping | 02 tweede verdieping | 3168 | 3168 | Level : 02 tweede verdieping | 0.457225 | 2485 | 840 | 0.011883 | -2485 | 2340 | Model Group:BU-39B:873577
1869680 | 02 tweede verdieping | 02 tweede verdieping | 3168 | 3168 | Level : 02 tweede verdieping | 0.457225 | 2485 | 840 | 0.011883 | -2485 | 2340 | Model Group:BU-39B:873639
1869697 | 02 tweede verdieping | 02 tweede verdieping | 3168 | 3168 | Level : 02 tweede verdieping | 0.457225 | 2485 | 840 | 0.011883 | -2485 | 2340 | Model Group:BU-39B:873670
1869714 | 02 tweede verdieping | 02 tweede verdieping | 3168 | 3168 | Level : 02 tweede verdieping | 0.457225 | 2485 | 840 | 0.011883 | -2485 | 2340 | Model Group:BU-39B:873732
1869733 | 02 tweede verdieping | 02 tweede verdieping | 3168 | 3168 | Level : 02 tweede verdieping | 0.457225 | 2485 | 840 | 0.011883 | -2485 | 2340 | Model Group:BU-39B:871535
1869750 | 02 tweede verdieping | 02 tweede verdieping | 3168 | 3168 | Level : 02 tweede verdieping | 0.457225 | 2485 | 840 | 0.011883 | -2485 | 2340 | Model Group:BU-39B:871708
1869768 | 02 tweede verdieping | 02 tweede verdieping | 3168 | 3168 | Level : 02 tweede verdieping | 0.457225 | 2485 | 840 | 0.011883 | -2485 | 2340 | Model Group:BU-39A:871894
1869785 | 02 tweede verdieping | 02 tweede verdieping | 3168 | 3168 | Level : 02 tweede verdieping | 0.457225 | 2485 | 840 | 0.011883 | -2485 | 2340 | Model Group:BU-39A:871990
1869804 | 02 tweede verdieping | 02 tweede verdieping | 3168 | 3168 | Level : 02 tweede verdieping | 0.457225 | 2485 | 840 | 0.011883 | -2485 | 2340 | Model Group:BU-39A:872286
1869821 | 02 tweede verdieping | 02 tweede verdieping | 3168 | 3168 | Level : 02 tweede verdieping | 0.457225 | 2485 | 840 | 0.011883 | -2485 | 2340 | Model Group:BU-39A:872853
1869838 | 02 tweede verdieping | 02 tweede verdieping | 3168 | 3168 | Level : 02 tweede verdieping | 0.457225 | 2485 | 840 | 0.011883 | -2485 | 2340 | Model Group:BU-39A:873051
1869855 | 02 tweede verdieping | 02 tweede verdieping | 3168 | 3168 | Level : 02 tweede verdieping | 0.457225 | 2485 | 840 | 0.011883 | -2485 | 2340 | Model Group:BU-39A:873117
1898046 | 01 eerste verdieping | 01 eerste verdieping | 2975 | 2975 | Level : 01 eerste verdieping | 0.588765 | 2115 | 1766 | 0.0195741 | -2115 | 1970 | Model Group:BU-28A:877045
2012532 | 01 eerste verdieping | 01 eerste verdieping | 2975 | 2975 | Level : 01 eerste verdieping | 0.587815 | 2115 | 1761 | 0.019529 | -2115 | 1970 | Model Group:BU-29A:875348
2012562 | 01 eerste verdieping | 01 eerste verdieping | 2975 | 2975 | Level : 01 eerste verdieping | 0.587815 | 2115 | 1761 | 0.019529 | -2115 | 1970 | Model Group:BU-29A:891660
2012577 | 01 eerste verdieping | 01 eerste verdieping | 2975 | 2975 | Level : 01 eerste verdieping | 0.581815 | 2065 | 1761 | 0.019439 | -2065 | 1920
2172437 | 01 eerste verdieping | 01 eerste verdieping | 2975 | 2975 | Level : 01 eerste verdieping | 0.587815 | 2115 | 1761 | 0.019529 | -2115 | 1970 | Model Group:BU-27:891638
2266692 | 01 eerste verdieping | 01 eerste verdieping | 2975 | 2975 | Level : 01 eerste verdieping | 0.588765 | 2115 | 1766 | 0.0195741 | -2115 | 1970 | Model Group:BI-29B:876480
2266714 | 02 tweede verdieping | 02 tweede verdieping | 3168 | 3168 | Level : 02 tweede verdieping | 0.457225 | 2485 | 840 | 0.011883 | -2485 | 2340 | Model Group:BU-39B:873403
2266729 | 02 tweede verdieping | 02 tweede verdieping | 3168 | 3168 | Level : 02 tweede verdieping | 0.457225 | 2485 | 840 | 0.011883 | -2485 | 2340 | Model Group:BU-39A:870672
2776737 | 01 eerste verdieping | 01 eerste verdieping | 2975 | 2975 | Level : 01 eerste verdieping | 0.587815 | 2115 | 1761 | 0.019529 | -2115 | 1970 | Model Group:BU-29:2698865
3058136 | 00 begane grond | 00 begane grond | 3096 | 3096 | Floor : NLRS_43_FL_cementdekvloer 60_gen_ISR | 0.921835 | 3103 | 2895 | 0.0315418 | -3103 | 2958 | Model Group:BU-03 b5800:1818868
3058140 | 00 begane grond | 00 begane grond | 3096 | 3096 | <not associated> | 0.711885 | 3103 | 1790 | 0.0215691 | -3103 | 2958 | Model Group:BU-06 b1800:894434
3058152 | 00 begane grond |  | 0 | 3096 | <not associated> | 0.540885 | 3103 | 890 | 0.0134466 | -3103 | 2958 | Model Group:BU-07 b900:894363
3058158 | 00 begane grond | 00 begane grond | 3096 | 3096 | Level : 00 begane grond | 0.540885 | 3103 | 890 | 0.0134466 | -3103 | 2958 | Model Group:BU-07 b900:1502980
3058166 | 00 begane grond | 00 begane grond | 3096 | 3096 | <not associated> | 0.768885 | 3103 | 2090 | 0.0242766 | -3103 | 2958 | Model Group:BU-08 b2100:1220076
3058169 | 00 begane grond | 00 begane grond | 3096 | 3096 | <not associated> | 0.654885 | 3103 | 1490 | 0.0188616 | -3103 | 2958 | Model Group:BU-09 b1500:1220175
3058172 | 00 begane grond | 00 begane grond | 3096 | 3096 | <not associated> | 0.521885 | 3103 | 790 | 0.0125441 | -3103 | 2958
3058173 | 00 begane grond | 00 begane grond | 3096 | 3096 | <not associated> | 0.939885 | 3103 | 2990 | 0.0323992 | -3103 | 2958
3058174 | 00 begane grond | 00 begane grond | 3096 | 3096 | <not associated> | 0.562165 | 3103 | 1002 | 0.0144574 | -3103 | 2958 | Model Group:BU-47 b4200:1822720
3058175 | 00 begane grond | 00 begane grond | 3096 | 3096 | <not associated> | 0.760065 | 2716 | 2288 | 0.025367 | -2716 | 2571 | Model Group:BU-13 b3300:1862274
3058178 | 00 begane grond | 00 begane grond | 3096 | 3096 | Level : 00 begane grond | 0.787315 | 3103 | 2187 | 0.0251521 | -3103 | 2958
3058180 | 00 begane grond | 00 begane grond | 3096 | 3096 | Level : 00 begane grond | 0.562165 | 3103 | 1002 | 0.0144574 | -3103 | 2958 | Model Group:BU-12 b4200:1817348
3058183 | 00 begane grond | 00 begane grond | 3096 | 3096 | Level : 00 begane grond | 0.749885 | 3103 | 1990 | 0.0233741 | -3103 | 2958 | Model Group:BU-17 b3000:1900158
3058184 | 00 begane grond | 00 begane grond | 3096 | 3096 | Level : 00 begane grond | 0.552285 | 3103 | 950 | 0.0139881 | -3103 | 2958
3058187 | 00 begane grond | 00 begane grond | 3096 | 3096 | Level : 00 begane grond | 0.498895 | 3103 | 669 | 0.0114521 | -3103 | 2958
3058192 | 00 begane grond | 00 begane grond | 3096 | 3096 | Level : 00 begane grond | 0.93143 | 3103 | 2945.5 | 0.0319975 | -3103 | 2958
3058193 | 00 begane grond | 00 begane grond | 3096 | 3096 | Level : 00 begane grond | 0.782375 | 3103 | 2161 | 0.0249174 | -3103 | 2958
3058194 | 00 begane grond | 00 begane grond | 3096 | 3096 | Level : 00 begane grond | 0.562165 | 3103 | 1002 | 0.0144574 | -3103 | 2958
3058195 | 00 begane grond | 00 begane grond | 3096 | 3096 | Level : 00 begane grond | 0.562165 | 3103 | 1002 | 0.0144574 | -3103 | 2958
3058196 | 00 begane grond | 00 begane grond | 3096 | 3096 | <not associated> | 0.769835 | 3103 | 2095 | 0.0243218 | -3103 | 2958 | Model Group:BU-03 b5800:1818868
3058199 | 00 begane grond | 00 begane grond | 3096 | 3096 | <not associated> | 0.782375 | 3103 | 2161 | 0.0249174 | -3103 | 2958 | Model Group:BU-47 b4200:1822720
3058200 | 00 begane grond | 00 begane grond | 3096 | 3096 | Level : 00 begane grond | 0.782755 | 3103 | 2163 | 0.0249355 | -3103 | 2958 | Model Group:BU-12 b4200:1817348
3058219 | 00 begane grond | 00 begane grond | 3096 | 3096 | <not associated> | 0.515725 | 2716 | 1002 | 0.0137608 | -2716 | 2571 | Model Group:BU-13 b3300:1862274
3058237 | 01 eerste verdieping | 01 eerste verdieping | 2975 | 2975 | Level : 01 eerste verdieping | 0.588765 | 2115 | 1766 | 0.0195741 | -2115 | 1970 | Model Group:BU-28A:3058229
3058246 | 01 eerste verdieping | 01 eerste verdieping | 2975 | 2975 | Level : 01 eerste verdieping | 0.50032 | 2115 | 1300.5 | 0.015373 | -2115 | 1970 | Model Group:BU-36:2701416
3058250 | 01 eerste verdieping | 01 eerste verdieping | 2975 | 2975 | Level : 01 eerste verdieping | 0.50032 | 2115 | 1300.5 | 0.015373 | -2115 | 1970 | Model Group:BU-33:2712443
3058252 | 01 eerste verdieping | 01 eerste verdieping | 2975 | 2975 | Level : 01 eerste verdieping | 0.50032 | 2115 | 1300.5 | 0.015373 | -2115 | 1970 | Model Group:BU-33:2700705
3058259 | 01 eerste verdieping | 01 eerste verdieping | 2975 | 2975 | Level : 01 eerste verdieping | 0.467235 | 2703 | 755 | 0.0115083 | -2703 | 2558
3058272 | 02 tweede verdieping | 02 tweede verdieping | 3168 | 3168 | Level : 02 tweede verdieping | 0.518275 | 2894 | 903 | 0.0131878 | -2894 | 2749 | Model Group:BU-40:2712884
3058289 | 00 begane grond | 00 begane grond | 3096 | 3096 | <not associated> | 0.566345 | 3103 | 1024 | 0.014656 | -3103 | 2958 | Model Group:BU-14 b3000:1494513
3064877 | 02 tweede verdieping | 02 tweede verdieping | 3168 | 3168 | Level : 02 tweede verdieping | 0.518275 | 2894 | 903 | 0.0131878 | -2894 | 2749 | Model Group:BU-40:2712884
3451944 | 00 begane grond | 00 begane grond | 3096 | 3096 | Level : 00 begane grond | 0.494445 | 2716 | 890 | 0.01275 | -2716 | 2571 | Model Group:BU-45 b900:2546304
3539171 | 01 eerste verdieping | 01 eerste verdieping | 2975 | 2975 | Level : 01 eerste verdieping | 0.32932 | 2115 | 400.5 | 0.00725051 | -2115 | 1970 | Model Group:BU-37:2712501
3539735 | 01 eerste verdieping | 01 eerste verdieping | 2975 | 2975 | Level : 01 eerste verdieping | 0.32932 | 2115 | 400.5 | 0.00725051 | -2115 | 1970
4225767 | 00 begane grond | 00 begane grond | 3096 | 3096 | <not associated> | 0.559885 | 3103 | 990 | 0.0143491 | -3103 | 2958
4226131 | 00 begane grond | 00 begane grond | 3096 | 3096 | <not associated> | 0.562165 | 3103 | 1002 | 0.0144574 | -3103 | 2958

# IfcBuildingElementProxy: NLRS_41_SF_LIB_latei_staal_generiek_ISR:90x150 (126)
Type - Material: h2_staal_gen
Type - Constraints - bodemplaat: no; Default Elevation: 1219.2 mm
Type - Structural - Section Shape: 11
Type - Dimensions - bodemplaat_breedte: 80 mm; bodemplaat_dikte: 2 mm; bodemplaat_hoogte: 50 mm; latei_breedte: 90 mm; latei_dikte: 4 mm; latei_hoogte: 150 mm
Type - Identity Data - Assembly Code: 2D(41.12); Datum_Gewijzigd: 20150713; Description: latei; Model: LOD300; SmartRevit_Versie: 2015.3; Type Name: 90x150; Workset: Family : Structural Framing : NLRS_41_SF_LIB_latei_staal_generiek_ISR
Type - Other - Category: Structural Framing; Family Name: NLRS_41_SF_LIB_latei_staal_generiek_ISR
Classification: 2D(41.12) Uniformat (Uniformat)
Constraints - Moves With Nearby Elements: no
Phasing - Phase Created: 2. nieuwbouw
Graphics - hoek_b: 0 deg
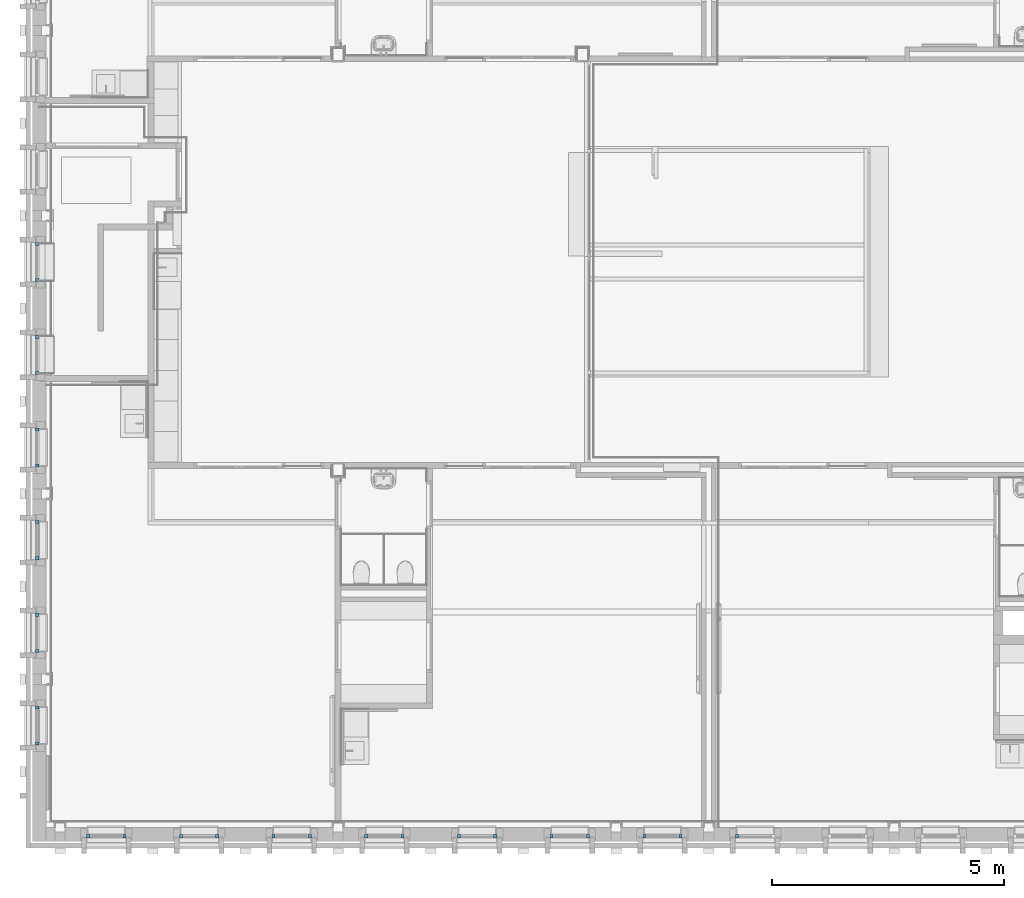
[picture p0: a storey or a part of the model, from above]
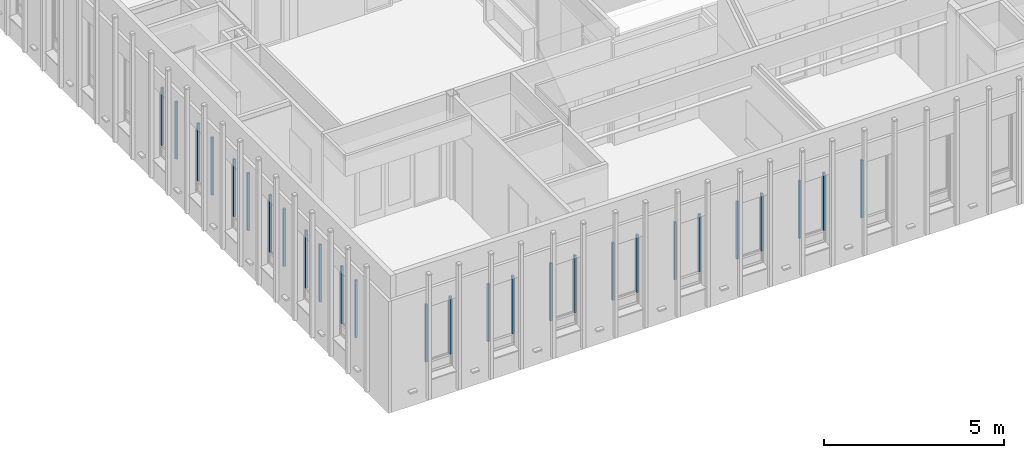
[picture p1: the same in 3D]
Properties of the parts of a building model (IFC2X3), part 5 of 94

# IfcBuildingElementProxy: NLRS_41_SF_LIB_latei_staal_generiek_ISR:90x150 (126)
Dimensions - berekende_hoek_b+180: 180 deg; NLRS_C_breedte: 90 mm; NLRS_C_hoogte: 150 mm; verlenging_a: 0 mm; verlenging_b: 0 mm
Identity Data - Workset: Workset1
Other - berekende_overstek_b: 0 mm; berekende_verlenging_a: 2000 mm; berekende_verlenging_b: 2000 mm; Family: NLRS_41_SF_LIB_latei_staal_generiek_ISR; Family and Type: NLRS_41_SF_LIB_latei_staal_generiek_ISR: 90x150; Type: 90x150; Type Id: 862346
Name (NLRS_41_SF_LIB_latei_staal_generiek_ISR:90x150:...) | In | Level | Host | lengte (mm) = NLRS_C_lengte (mm) | Offset from Host (mm) | hoek_a (deg) | berekende_hoek_a+180 (deg) | element_lengte (mm) | Volume (m3) | berekende_hoek_a (deg) | berekende_overstek_a (mm)
832749 | 01 eerste verdieping | 01 eerste verdieping | Basic Wall : NLRS_22_WA_HSB bispouw 30-245-12-13 glaswol_gen_ISR | 1785 | 1966.64 | 0 | -180 | 1785 | 0.0016747 | 0 | 0
858909 | 01 eerste verdieping | 01 eerste verdieping | Level : 01 eerste verdieping | 1785 | 1966.64 | 0 | -180 | 1785 | 0.0016747 | 0 | 0
858935 | 01 eerste verdieping | 01 eerste verdieping | Level : 01 eerste verdieping | 1785 | 1966.64 | 0 | -180 | 1785 | 0.0016747 | 0 | 0
859964 | 02 tweede verdieping | 02 tweede verdieping | Basic Wall : NLRS_22_WA_HSB bispouw 30-245-12-13 glaswol_gen_ISR | 1064 | 1966.64 | 0 | -180 | 1064 | 0.00099825 | 0 | 0
864450 | 02 tweede verdieping | 02 tweede verdieping | Level : 02 tweede verdieping | 1064 | 1966.64 | 0 | -180 | 1064 | 0.00099825 | 0 | 0
864481 | 02 tweede verdieping | 02 tweede verdieping | Level : 02 tweede verdieping | 1064 | 1966.64 | 0 | -180 | 1064 | 0.00099825 | 0 | 0
870608 | 02 tweede verdieping | 02 tweede verdieping | Level : 02 tweede verdieping | 1064 | 1966.64 | 0 | -180 | 1064 | 0.00099825 | 0 | 0
870625 | 02 tweede verdieping | 02 tweede verdieping | Level : 02 tweede verdieping | 1064 | 1966.64 | 0 | -180 | 1064 | 0.00099825 | 0 | 0
870642 | 02 tweede verdieping | 02 tweede verdieping | Level : 02 tweede verdieping | 1064 | 1966.64 | 0 | -180 | 1064 | 0.00099825 | 0 | 0
870690 | 02 tweede verdieping | 02 tweede verdieping | Level : 02 tweede verdieping | 1064 | 1966.64 | 0 | -180 | 1064 | 0.00099825 | 0 | 0
870707 | 02 tweede verdieping | 02 tweede verdieping | Level : 02 tweede verdieping | 1064 | 1966.64 | 0 | -180 | 1064 | 0.00099825 | 0 | 0
870724 | 02 tweede verdieping | 02 tweede verdieping | Level : 02 tweede verdieping | 1064 | 1966.64 | 0 | -180 | 1064 | 0.00099825 | 0 | 0
870803 | 02 tweede verdieping | 02 tweede verdieping | Level : 02 tweede verdieping | 1064 | 1966.64 | 0 | -180 | 1064 | 0.00099825 | 0 | 0
870820 | 02 tweede verdieping | 02 tweede verdieping | Level : 02 tweede verdieping | 1064 | 1966.64 | 0 | -180 | 1064 | 0.00099825 | 0 | 0
870837 | 02 tweede verdieping | 02 tweede verdieping | Level : 02 tweede verdieping | 1064 | 1966.64 | 0 | -180 | 1064 | 0.00099825 | 0 | 0
870947 | 02 tweede verdieping | 02 tweede verdieping | Basic Wall : 21_WA_metselwerk_licht_100_gen_bdg | 1064 | 1967.64 | 0 | -180 | 1064 | 0.00099825 | 0 | 0
871625 | 02 tweede verdieping | 02 tweede verdieping | Level : 02 tweede verdieping | 1064 | 1967.64 | 0 | -180 | 1064 | 0.00099825 | 0 | 0
871658 | 02 tweede verdieping | 02 tweede verdieping | Level : 02 tweede verdieping | 1064 | 1967.64 | 0 | -180 | 1064 | 0.00099825 | 0 | 0
871691 | 02 tweede verdieping | 02 tweede verdieping | Level : 02 tweede verdieping | 1064 | 1967.64 | 0 | -180 | 1064 | 0.00099825 | 0 | 0
871877 | 02 tweede verdieping | 02 tweede verdieping | Level : 02 tweede verdieping | 1064 | 1967.64 | 0 | -180 | 1064 | 0.00099825 | 0 | 0
871909 | 02 tweede verdieping | 02 tweede verdieping | Level : 02 tweede verdieping | 1064 | 1967.64 | 0 | -180 | 1064 | 0.00099825 | 0 | 0
871941 | 02 tweede verdieping | 02 tweede verdieping | Level : 02 tweede verdieping | 1064 | 1967.64 | 0 | -180 | 1064 | 0.00099825 | 0 | 0
871973 | 02 tweede verdieping | 02 tweede verdieping | Level : 02 tweede verdieping | 1064 | 1967.64 | 0 | -180 | 1064 | 0.00099825 | 0 | 0
872037 | 02 tweede verdieping | 02 tweede verdieping | Basic Wall : 21_WA_metselwerk_licht_100_gen_bdg | 1064 | 1967.64 | 0 | -180 | 1064 | 0.00099825 | 0 | 0
872072 | 02 tweede verdieping | 02 tweede verdieping | Basic Wall : 21_WA_metselwerk_licht_100_gen_bdg | 1064 | 1967.64 | 0 | -180 | 1064 | 0.00099825 | 0 | 0
872798 | 02 tweede verdieping | 02 tweede verdieping | Level : 02 tweede verdieping | 1064 | 1967.64 | 0 | -180 | 1064 | 0.00099825 | 0 | 0
872831 | 02 tweede verdieping | 02 tweede verdieping | Level : 02 tweede verdieping | 1064 | 1967.64 | 0 | -180 | 1064 | 0.00099825 | 0 | 0
872864 | 02 tweede verdieping | 02 tweede verdieping | Level : 02 tweede verdieping | 1064 | 1967.64 | 0 | -180 | 1064 | 0.00099825 | 0 | 0
872897 | 02 tweede verdieping | 02 tweede verdieping | Level : 02 tweede verdieping | 1064 | 1967.64 | 0 | -180 | 1064 | 0.00099825 | 0 | 0
872930 | 02 tweede verdieping | 02 tweede verdieping | Level : 02 tweede verdieping | 1064 | 1967.64 | 0 | -180 | 1064 | 0.00099825 | 0 | 0
872963 | 02 tweede verdieping | 02 tweede verdieping | Level : 02 tweede verdieping | 1064 | 1967.64 | 0 | -180 | 1064 | 0.00099825 | 0 | 0
872996 | 02 tweede verdieping | 02 tweede verdieping | Level : 02 tweede verdieping | 1064 | 1967.64 | 0 | -180 | 1064 | 0.00099825 | 0 | 0
873029 | 02 tweede verdieping | 02 tweede verdieping | Level : 02 tweede verdieping | 1064 | 1967.64 | 0 | -180 | 1064 | 0.00099825 | 0 | 0
873062 | 02 tweede verdieping | 02 tweede verdieping | Level : 02 tweede verdieping | 1064 | 1967.64 | 0 | -180 | 1064 | 0.00099825 | 0 | 0
873095 | 02 tweede verdieping | 02 tweede verdieping | Level : 02 tweede verdieping | 1064 | 1967.64 | 0 | -180 | 1064 | 0.00099825 | 0 | 0
873406 | 02 tweede verdieping | 02 tweede verdieping | Level : 02 tweede verdieping | 1064 | 1967.64 | 0 | -180 | 1064 | 0.00099825 | 0 | 0
873456 | 02 tweede verdieping | 02 tweede verdieping | Level : 02 tweede verdieping | 1064 | 1967.64 | 0 | -180 | 1064 | 0.00099825 | 0 | 0
873487 | 02 tweede verdieping | 02 tweede verdieping | Level : 02 tweede verdieping | 1064 | 1967.64 | 0 | -180 | 1064 | 0.00099825 | 0 | 0
873518 | 02 tweede verdieping | 02 tweede verdieping | Level : 02 tweede verdieping | 1064 | 1967.64 | 0 | -180 | 1064 | 0.00099825 | 0 | 0
873549 | 02 tweede verdieping | 02 tweede verdieping | Level : 02 tweede verdieping | 1064 | 1967.64 | 0 | -180 | 1064 | 0.00099825 | 0 | 0
873580 | 02 tweede verdieping | 02 tweede verdieping | Level : 02 tweede verdieping | 1064 | 1967.64 | 0 | -180 | 1064 | 0.00099825 | 0 | 0
873611 | 02 tweede verdieping | 02 tweede verdieping | Level : 02 tweede verdieping | 1064 | 1967.64 | 0 | -180 | 1064 | 0.00099825 | 0 | 0
873642 | 02 tweede verdieping | 02 tweede verdieping | Level : 02 tweede verdieping | 1064 | 1967.64 | 0 | -180 | 1064 | 0.00099825 | 0 | 0
873673 | 02 tweede verdieping | 02 tweede verdieping | Level : 02 tweede verdieping | 1064 | 1967.64 | 0 | -180 | 1064 | 0.00099825 | 0 | 0
873704 | 02 tweede verdieping | 02 tweede verdieping | Level : 02 tweede verdieping | 1064 | 1967.64 | 0 | -180 | 1064 | 0.00099825 | 0 | 0
873735 | 02 tweede verdieping | 02 tweede verdieping | Level : 02 tweede verdieping | 1064 | 1967.64 | 0 | -180 | 1064 | 0.00099825 | 0 | 0
874901 | 01 eerste verdieping | 01 eerste verdieping | Level : 01 eerste verdieping | 1785 | 1966.64 | 0 | -180 | 1785 | 0.0016747 | 0 | 0
874913 | 01 eerste verdieping | 01 eerste verdieping | Level : 01 eerste verdieping | 1785 | 1966.64 | 0 | -180 | 1785 | 0.0016747 | 0 | 0
874925 | 01 eerste verdieping | 01 eerste verdieping | Level : 01 eerste verdieping | 1785 | 1966.64 | 0 | -180 | 1785 | 0.0016747 | 0 | 0
874991 | 01 eerste verdieping | 01 eerste verdieping | Level : 01 eerste verdieping | 1785 | 1966.64 | 0 | -180 | 1785 | 0.0016747 | 0 | 0
875003 | 01 eerste verdieping | 01 eerste verdieping | Level : 01 eerste verdieping | 1785 | 1966.64 | 0 | -180 | 1785 | 0.0016747 | 0 | 0
875015 | 01 eerste verdieping | 01 eerste verdieping | Level : 01 eerste verdieping | 1785 | 1966.64 | 0 | -180 | 1785 | 0.0016747 | 0 | 0
875220 | 01 eerste verdieping | 01 eerste verdieping | Level : 01 eerste verdieping | 1785 | 1966.64 | 0 | -180 | 1785 | 0.0016747 | 0 | 0
875256 | 01 eerste verdieping | 01 eerste verdieping | Level : 01 eerste verdieping | 1785 | 1966.64 | 0 | -180 | 1785 | 0.0016747 | 0 | 0
875292 | 01 eerste verdieping | 01 eerste verdieping | Level : 01 eerste verdieping | 1785 | 1966.64 | 0 | -180 | 1785 | 0.0016747 | 0 | 0
875328 | 01 eerste verdieping | 01 eerste verdieping | Level : 01 eerste verdieping | 1785 | 1966.64 | 0 | -180 | 1785 | 0.0016747 | 0 | 0
875364 | 01 eerste verdieping | 01 eerste verdieping | Level : 01 eerste verdieping | 1785 | 1966.64 | 0 | -180 | 1785 | 0.0016747 | 0 | 0
876529 | 01 eerste verdieping | 01 eerste verdieping | Level : 01 eerste verdieping | 1785 | 1967.64 | 0 | -180 | 1785 | 0.0016747 | 0 | 0
876766 | 01 eerste verdieping | 01 eerste verdieping | Level : 01 eerste verdieping | 1785 | 1967.64 | 0 | -180 | 1785 | 0.0016747 | 0 | 0
876785 | 01 eerste verdieping | 01 eerste verdieping | Level : 01 eerste verdieping | 1785 | 1967.64 | 0 | -180 | 1785 | 0.0016747 | 0 | 0
876931 | 01 eerste verdieping | 01 eerste verdieping | Level : 01 eerste verdieping | 1785 | 1967.64 | 0 | -180 | 1785 | 0.0016747 | 0 | 0
876943 | 01 eerste verdieping | 01 eerste verdieping | Level : 01 eerste verdieping | 1785 | 1967.64 | 0 | -180 | 1785 | 0.0016747 | 0 | 0
876955 | 01 eerste verdieping | 01 eerste verdieping | Level : 01 eerste verdieping | 1785 | 1967.64 | 0 | -180 | 1785 | 0.0016747 | 0 | 0
877048 | 01 eerste verdieping | 01 eerste verdieping | Level : 01 eerste verdieping | 1785 | 1967.64 | 0 | -180 | 1785 | 0.0016747 | 0 | 0
877060 | 01 eerste verdieping | 01 eerste verdieping | Level : 01 eerste verdieping | 1785 | 1967.64 | 0 | -180 | 1785 | 0.0016747 | 0 | 0
877072 | 01 eerste verdieping | 01 eerste verdieping | Level : 01 eerste verdieping | 1785 | 1967.64 | 0 | -180 | 1785 | 0.0016747 | 0 | 0
877138 | 01 eerste verdieping | 01 eerste verdieping | Level : 01 eerste verdieping | 1785 | 1967.64 | 0 | -180 | 1785 | 0.0016747 | 0 | 0
877150 | 01 eerste verdieping | 01 eerste verdieping | Level : 01 eerste verdieping | 1785 | 1967.64 | 0 | -180 | 1785 | 0.0016747 | 0 | 0
877162 | 01 eerste verdieping | 01 eerste verdieping | Level : 01 eerste verdieping | 1785 | 1967.64 | 0 | -180 | 1785 | 0.0016747 | 0 | 0
877228 | 01 eerste verdieping | 01 eerste verdieping | Level : 01 eerste verdieping | 1785 | 1967.64 | 0 | -180 | 1785 | 0.0016747 | 0 | 0
877240 | 01 eerste verdieping | 01 eerste verdieping | Level : 01 eerste verdieping | 1785 | 1967.64 | 0 | -180 | 1785 | 0.0016747 | 0 | 0
880826 | 01 eerste verdieping | 01 eerste verdieping | Basic Wall : NLRS_22_WA_HSB bispouw 30-245-12-13 glaswol_gen_ISR | 1785 | 2967.64 | 0 | -180 | 1785 | 0.0016747 | 0 | 0
881594 | 01 eerste verdieping | 01 eerste verdieping | Level : 01 eerste verdieping | 1785 | 2967.64 | 0 | -180 | 1785 | 0.0016747 | 0 | 0
881630 | 01 eerste verdieping | 01 eerste verdieping | Level : 01 eerste verdieping | 1785 | 2967.64 | 0 | -180 | 1785 | 0.0016747 | 0 | 0
881666 | 01 eerste verdieping | 01 eerste verdieping | Level : 01 eerste verdieping | 1785 | 2967.64 | 0 | -180 | 1785 | 0.0016747 | 0 | 0
881742 | 01 eerste verdieping | 01 eerste verdieping | Level : 01 eerste verdieping | 1785 | 2967.64 | 0 | -180 | 1785 | 0.0016747 | 0 | 0
881769 | 01 eerste verdieping | 01 eerste verdieping | Level : 01 eerste verdieping | 1785 | 2967.64 | 0 | -180 | 1785 | 0.0016747 | 0 | 0
891619 | 01 eerste verdieping | 01 eerste verdieping | Level : 01 eerste verdieping | 387 | 2967.64 | 0 | -180 | 387 | 0.000363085 | 0 | 0
891641 | 01 eerste verdieping | 01 eerste verdieping | Level : 01 eerste verdieping | 1785 | 2967.64 | 0 | -180 | 1785 | 0.0016747 | 0 | 0
891663 | 01 eerste verdieping | 01 eerste verdieping | Level : 01 eerste verdieping | 1785 | 2967.64 | 0 | -180 | 1785 | 0.0016747 | 0 | 0
891685 | 01 eerste verdieping | 01 eerste verdieping | Level : 01 eerste verdieping | 1785 | 2967.64 | 0 | -180 | 1785 | 0.0016747 | 0 | 0
891707 | 01 eerste verdieping | 01 eerste verdieping | Level : 01 eerste verdieping | 1785 | 2967.64 | 0 | -180 | 1785 | 0.0016747 | 0 | 0
891747 | 01 eerste verdieping | 01 eerste verdieping | Basic Wall : 21_WA_metselwerk_licht_100_gen_bdg | 1785 | 1967.64 | 0 | -180 | 1785 | 0.0016747 | 0 | 0
891775 | 01 eerste verdieping | 01 eerste verdieping | Level : 01 eerste verdieping | 1785 | 1967.64 | 0 | -180 | 1785 | 0.0016747 | 0 | 0
891892 | 01 eerste verdieping | 01 eerste verdieping | Level : 01 eerste verdieping | 1785 | 1967.64 | 0 | -180 | 1785 | 0.0016747 | 0 | 0
891914 | 01 eerste verdieping | 01 eerste verdieping | Level : 01 eerste verdieping | 1785 | 1967.64 | 0 | -180 | 1785 | 0.0016747 | 0 | 0
891936 | 01 eerste verdieping | 01 eerste verdieping | Level : 01 eerste verdieping | 1785 | 1967.64 | 0 | -180 | 1785 | 0.0016747 | 0 | 0
891964 | 01 eerste verdieping | 01 eerste verdieping | Level : 01 eerste verdieping | 1785 | 1967.64 | 0 | -180 | 1785 | 0.0016747 | 0 | 0
897881 | 00 begane grond | 00 begane grond | Basic Wall : NLRS_22_WA_HSB bispouw 30-245-12-13 glaswol_gen_ISR | 1814 | 1967.64 | 0 | -180 | 1814 | 0.0017019 | 0 | 0
897934 | 00 begane grond | 00 begane grond | Basic Wall : NLRS_22_WA_HSB bispouw 30-245-12-13 glaswol_gen_ISR | 914 | 1967.64 | 0 | -180 | 914 | 0.000857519 | 0 | 0
898542 | 00 begane grond | 00 begane grond | Basic Wall : NLRS_22_WA_HSB bispouw 30-245-12-13 glaswol_gen_ISR | 2114 | 1967.64 | 0 | -180 | 2114 | 0.00198336 | 0 | 0
898554 | 00 begane grond | 00 begane grond | Basic Wall : NLRS_22_WA_HSB bispouw 30-245-12-13 glaswol_gen_ISR | 1514 | 1967.64 | 0 | -180 | 1514 | 0.00142044 | 0 | 0
1219781 | 00 begane grond | 00 begane grond | Basic Wall : NLRS_22_WA_HSB bispouw 30-245-12-13 glaswol_gen_ISR | 1814 | 1967.64 | 0 | -180 | 1814 | 0.0017019 | 0 | 0
1220531 | 00 begane grond | 00 begane grond | Basic Wall : NLRS_22_WA_HSB bispouw 30-245-12-13 glaswol_gen_ISR | 3014 | 1967.64 | 0 | -180 | 3014 | 0.00282775 | 0 | 0
1221365 | 00 begane grond | 00 begane grond | Basic Wall : NLRS_22_WA_HSB bispouw 30-245-12-13 glaswol_gen_ISR | 914 | 1967.64 | 0 | -180 | 914 | 0.000857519 | 0 | 0
1221376 | 00 begane grond | 00 begane grond | Basic Wall : NLRS_22_WA_HSB bispouw 30-245-12-13 glaswol_gen_ISR | 2980 | 1967.64 | 0 | -180 | 2980 | 0.00279585 | 0 | 0
1221597 | 00 begane grond | 00 begane grond | Basic Wall : NLRS_22_WA_HSB bispouw 30-245-12-13 glaswol_gen_ISR | 3314 | 1967.64 | 0 | -180 | 3314 | 0.00310921 | 0 | 0
1222352 | 00 begane grond | 00 begane grond | Basic Wall : NLRS_22_WA_HSB bispouw 30-245-12-13 glaswol_gen_ISR | 914 | 1967.64 | 0 | -180 | 914 | 0.000857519 | 0 | 0
1222794 | 00 begane grond | 00 begane grond | Basic Wall : NLRS_22_WA_HSB bispouw 30-245-12-13 glaswol_gen_ISR | 914 | 1967.64 | 0 | -180 | 914 | 0.000857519 | 0 | 0
1223371 | 00 begane grond | 00 begane grond | Basic Wall : NLRS_22_WA_HSB bispouw 30-245-12-13 glaswol_gen_ISR | 2714 | 1967.64 | 0 | -180 | 2714 | 0.00254629 | 0 | 0
1224040 | 00 begane grond | 00 begane grond | Basic Wall : NLRS_22_WA_HSB bispouw 30-245-12-13 glaswol_gen_ISR | 2969.5 | 1967.64 | 0 | -180 | 2969.5 | 0.002786 | 0 | 0
1224159 | 00 begane grond | 00 begane grond | Basic Wall : NLRS_22_WA_HSB bispouw 30-245-12-13 glaswol_gen_ISR | 4189 | 1967.64 | 0 | -180 | 4189 | 0.00393014 | 0 | 0
1488568 | 00 begane grond | 00 begane grond | Basic Wall : 22_WA_binnenwand_ms125 25-75-25 _gen_bdg | 3014 | 2077.64 | 0 | -180 | 3014 | 0.00282775 | 0 | 0
1492642 | 00 begane grond | 00 begane grond | Basic Wall : NLRS_22_WA_HSB bispouw 30-245-12-13 glaswol_gen_ISR | 4189 | 4122.64 | 0 | -180 | 4189 | 0.00393014 | 0 | 0
1492943 | 00 begane grond | 00 begane grond | Basic Wall : 21_WA_metselwerk_middel_100_gen_bdg | 3314 | 2077.64 | 0 | -180 | 3314 | 0.00310921 | 0 | 0
1502427 | 00 begane grond | 00 begane grond | Level : 00 begane grond | 3014 | 2077.64 | 0 | -180 | 3014 | 0.00282775 | 0 | 0
1502786 | 00 begane grond | 00 begane grond | Level : 00 begane grond | 3014 | 2077.64 | 0 | -180 | 3014 | 0.00282775 | 0 | 0
1503067 | 00 begane grond | 00 begane grond | Level : 00 begane grond | 914 | 2077.64 | 0 | -180 | 914 | 0.000857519 | 0 | 0
1503709 | 00 begane grond | 00 begane grond | Level : 00 begane grond | 4189 | 2077.64 | 0 | -180 | 4189 | 0.00393014 | 0 | 0
1822615 | 00 begane grond | 00 begane grond | Basic Wall : NLRS_22_WA_HSB bispouw 30-245-12-13 glaswol_gen_ISR | 4189 | 4122.64 | 0 | -180 | 4189 | 0.00393014 | 0 | 0
1847946 | 02 tweede verdieping | 02 tweede verdieping | Basic Wall : 22_WA_binnenwand_ms125 25-75-25 _gen_bdg | 5064 | 1967.64 | 0 | -180 | 5064 | 0.00475107 | 0 | 0
2239344 | 01 eerste verdieping | 01 eerste verdieping | Level : 01 eerste verdieping | 1252.5 | 1967.64 | 45 | -225 | 1342.5 | 0.00119247 | -45 | 90
2239381 | 01 eerste verdieping | 01 eerste verdieping | Basic Wall : NLRS_22_WA_HSB bispouw 30-245-12-13 glaswol_gen_ISR | 852.5 | 2962.64 | 45 | -225 | 942.5 | 0.000817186 | -45 | 90
2239475 | 01 eerste verdieping | 01 eerste verdieping | Basic Wall : NLRS_22_WA_HSB bispouw 30-245-12-13 glaswol_gen_ISR | 352.5 | 2962.64 | 45 | -225 | 442.5 | 0.000348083 | -45 | 90
2239493 | 01 eerste verdieping | 01 eerste verdieping | Basic Wall : NLRS_22_WA_HSB bispouw 30-245-12-13 glaswol_gen_ISR | 1252.5 | 1962.64 | 45 | -225 | 1342.5 | 0.00119247 | -45 | 90
2239503 | 00 begane grond | 00 begane grond | Basic Wall : NLRS_22_WA_HSB bispouw 30-245-12-13 glaswol_gen_ISR | 1367 | 4012.64 | -45 | -135 | 1367 | 0.00126516 | 45 | 0
2239549 | 00 begane grond | 00 begane grond | Basic Wall : NLRS_22_WA_HSB bispouw 30-245-12-13 glaswol_gen_ISR | 847 | 4012.64 | -45 | -135 | 847 | 0.000777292 | 45 | 0
2546395 | 00 begane grond | 00 begane grond | Level : 00 begane grond | 914 | 2077.64 | 0 | -180 | 914 | 0.000857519 | 0 | 0
2749542 | 01 eerste verdieping | 01 eerste verdieping | Level : 01 eerste verdieping | 1785 | 1967.64 | 0 | -180 | 1785 | 0.0016747 | 0 | 0
2749756 | 01 eerste verdieping | 01 eerste verdieping | Level : 01 eerste verdieping | 590 | 1966.64 | 0 | -180 | 590 | 0.000553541 | 0 | 0
2759477 | 01 eerste verdieping | 01 eerste verdieping | Basic Wall : 22_WA_binnenwand_ms125 25-75-25 _gen_bdg | 1252.5 | 1962.64 | 45 | -225 | 1342.5 | 0.00119247 | -45 | 90
2762373 | 01 eerste verdieping | 01 eerste verdieping | Basic Wall : 22_WA_koof_96 12-12-50 | 352.5 | 1962.64 | 45 | -225 | 442.5 | 0.000348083 | -45 | 90
2785704 | 00 begane grond | 00 begane grond | Basic Wall : 22_WA_binnenwand_ms125 25-75-25 _gen_bdg | 1864.5 | 1967.64 | -45 | -135 | 1864.5 | 0.00173191 | 45 | 0
2786082 | 00 begane grond | 00 begane grond | Basic Wall : NLRS_22_WA_HSB bispouw 30-245-12-13 glaswol_gen_ISR | 2308 | 1967.64 | 45 | -225 | 2398 | 0.00218274 | -45 | 90
2790501 | 00 begane grond | 00 begane grond | Basic Wall : 22_WA_binnenwand_ms125 25-75-25 _gen_bdg | 3100.76 | 1967.64 | -45 | -135 | 3100.76 | 0.00289178 | 45 | 0
4343088 | 01 eerste verdieping | 01 eerste verdieping | Level : 01 eerste verdieping | 1412 | 2967.64 | 0 | -180 | 1412 | 0.00132475 | 0 | 0

# IfcBuildingElementProxy: NLRS_42_GM_WPB_vensterbank_natuursteen-SH_generiek_ISR:180x18 vensterbank composiet (92)
Type - Material: 00_Natuursteen
Type - Constraints - Default Elevation: 1219.2 mm
Type - Materials and Finishes - materiaal: 00_Natuursteen
Type - Dimensions - breedte: 180 mm; hoogte: 18 mm
Type - Identity Data - Assembly Code: 42; Assembly Description: binnenwandafwerkingen; Datum_Gewijzigd: 20160502; Description: vensterbank; Model: LOD300; SmartRevit_Versie: 2019.1; Type Name: 180x18 vensterbank composiet; Workset: Family : Generic Models : NLRS_42_GM_WPB_vensterbank_natuursteen-SH_generiek_ISR
Type - Other - Category: Generic Models; Family Name: NLRS_42_GM_WPB_vensterbank_natuursteen-SH_generiek_ISR
Classification: 42 Uniformat (Uniformat)
Constraints - Moves With Nearby Elements: no
Phasing - Phase Created: 2. nieuwbouw
Graphics - hoek_a: 0 deg
Dimensions - NLRS_C_breedte: 180 mm; NLRS_C_hoogte: 18 mm
Identity Data - Workset: Workset1
Other - berekende_hoek_a: 0 deg; berekende_overstek_a: 0 mm; berekende_overstek_b: 0 mm; Family: NLRS_42_GM_WPB_vensterbank_natuursteen-SH_generiek_ISR; Family and Type: NLRS_42_GM_WPB_vensterbank_natuursteen-SH_generiek_ISR: 180x18 vensterbank composiet; Type: 180x18 vensterbank composiet; Type Id: 775209
Name (NLRS_42_GM_WPB_vensterbank_natuursteen-SH_generiek_ISR:180x18 vensterbank composiet:...) | In | Level | Elevation from Level (mm) = Offset from Host (mm) | Host | lengte (mm) = NLRS_C_lengte (mm) | hoek_b (deg) | Area (m2) | element_lengte (mm) | verlenging_a (mm) | verlenging_b (mm) | Volume (m3) | berekende_verlenging_a (mm) | berekende_verlenging_b (mm)
832751 | 01 eerste verdieping | 01 eerste verdieping | 951.638 | Basic Wall : NLRS_22_WA_HSB bispouw 30-245-12-13 glaswol_gen_ISR | 2000 | 0 | 0.347166 | 1737 | -131.5 | -131.5 | 0.00562788 | 1868.5 | 1868.5
858911 | 01 eerste verdieping | 01 eerste verdieping | 951.638 | Level : 01 eerste verdieping | 2000 | 0 | 0.347166 | 1737 | -131.5 | -131.5 | 0.00562788 | 1868.5 | 1868.5
858937 | 01 eerste verdieping | 01 eerste verdieping | 951.638 | Level : 01 eerste verdieping | 2000 | 0 | 0.347166 | 1737 | -131.5 | -131.5 | 0.00562788 | 1868.5 | 1868.5
859966 | 02 tweede verdieping | 02 tweede verdieping | 976.638 | Basic Wall : NLRS_22_WA_HSB bispouw 30-245-12-13 glaswol_gen_ISR | 1112 | 0 | 0.164808 | 816 | -148 | -148 | 0.00264384 | 1852 | 1852
864452 | 02 tweede verdieping | 02 tweede verdieping | 976.638 | Level : 02 tweede verdieping | 1112 | 0 | 0.164808 | 816 | -148 | -148 | 0.00264384 | 1852 | 1852
864483 | 02 tweede verdieping | 02 tweede verdieping | 976.638 | Level : 02 tweede verdieping | 1112 | 0 | 0.164808 | 816 | -148 | -148 | 0.00264384 | 1852 | 1852
870610 | 02 tweede verdieping | 02 tweede verdieping | 976.638 | Level : 02 tweede verdieping | 1112 | 0 | 0.164808 | 816 | -148 | -148 | 0.00264384 | 1852 | 1852
870627 | 02 tweede verdieping | 02 tweede verdieping | 976.638 | Level : 02 tweede verdieping | 1112 | 0 | 0.164808 | 816 | -148 | -148 | 0.00264384 | 1852 | 1852
870644 | 02 tweede verdieping | 02 tweede verdieping | 976.638 | Level : 02 tweede verdieping | 1112 | 0 | 0.164808 | 816 | -148 | -148 | 0.00264384 | 1852 | 1852
870692 | 02 tweede verdieping | 02 tweede verdieping | 976.638 | Level : 02 tweede verdieping | 1112 | 0 | 0.164808 | 816 | -148 | -148 | 0.00264384 | 1852 | 1852
870709 | 02 tweede verdieping | 02 tweede verdieping | 976.638 | Level : 02 tweede verdieping | 1112 | 0 | 0.164808 | 816 | -148 | -148 | 0.00264384 | 1852 | 1852
870726 | 02 tweede verdieping | 02 tweede verdieping | 976.638 | Level : 02 tweede verdieping | 1112 | 0 | 0.164808 | 816 | -148 | -148 | 0.00264384 | 1852 | 1852
870805 | 02 tweede verdieping | 02 tweede verdieping | 976.638 | Level : 02 tweede verdieping | 1112 | 0 | 0.164808 | 816 | -148 | -148 | 0.00264384 | 1852 | 1852
870822 | 02 tweede verdieping | 02 tweede verdieping | 976.638 | Level : 02 tweede verdieping | 1112 | 0 | 0.164808 | 816 | -148 | -148 | 0.00264384 | 1852 | 1852
870839 | 02 tweede verdieping | 02 tweede verdieping | 976.638 | Level : 02 tweede verdieping | 1112 | 0 | 0.164808 | 816 | -148 | -148 | 0.00264384 | 1852 | 1852
870949 | 02 tweede verdieping | 02 tweede verdieping | 976.638 | Basic Wall : 21_WA_metselwerk_licht_100_gen_bdg | 1112 | 0 | 0.164808 | 816 | -148 | -148 | 0.00264384 | 1852 | 1852
871627 | 02 tweede verdieping | 02 tweede verdieping | 976.638 | Level : 02 tweede verdieping | 1112 | 0 | 0.164808 | 816 | -148 | -148 | 0.00264384 | 1852 | 1852
871660 | 02 tweede verdieping | 02 tweede verdieping | 976.638 | Level : 02 tweede verdieping | 1112 | 0 | 0.164808 | 816 | -148 | -148 | 0.00264384 | 1852 | 1852
871693 | 02 tweede verdieping | 02 tweede verdieping | 976.638 | Level : 02 tweede verdieping | 1112 | 0 | 0.164808 | 816 | -148 | -148 | 0.00264384 | 1852 | 1852
871879 | 02 tweede verdieping | 02 tweede verdieping | 976.638 | Level : 02 tweede verdieping | 1112 | 0 | 0.164808 | 816 | -148 | -148 | 0.00264384 | 1852 | 1852
871911 | 02 tweede verdieping | 02 tweede verdieping | 976.638 | Level : 02 tweede verdieping | 1112 | 0 | 0.164808 | 816 | -148 | -148 | 0.00264384 | 1852 | 1852
871943 | 02 tweede verdieping | 02 tweede verdieping | 976.638 | Level : 02 tweede verdieping | 1112 | 0 | 0.164808 | 816 | -148 | -148 | 0.00264384 | 1852 | 1852
871975 | 02 tweede verdieping | 02 tweede verdieping | 976.638 | Level : 02 tweede verdieping | 1112 | 0 | 0.164808 | 816 | -148 | -148 | 0.00264384 | 1852 | 1852
872039 | 02 tweede verdieping | 02 tweede verdieping | 976.638 | Basic Wall : 21_WA_metselwerk_licht_100_gen_bdg | 1112 | 0 | 0.164808 | 816 | -148 | -148 | 0.00264384 | 1852 | 1852
872074 | 02 tweede verdieping | 02 tweede verdieping | 976.638 | Basic Wall : 21_WA_metselwerk_licht_100_gen_bdg | 1112 | 0 | 0.164808 | 816 | -148 | -148 | 0.00264384 | 1852 | 1852
872800 | 02 tweede verdieping | 02 tweede verdieping | 976.638 | Level : 02 tweede verdieping | 1112 | 0 | 0.164808 | 816 | -148 | -148 | 0.00264384 | 1852 | 1852
872833 | 02 tweede verdieping | 02 tweede verdieping | 976.638 | Level : 02 tweede verdieping | 1112 | 0 | 0.164808 | 816 | -148 | -148 | 0.00264384 | 1852 | 1852
872866 | 02 tweede verdieping | 02 tweede verdieping | 976.638 | Level : 02 tweede verdieping | 1112 | 0 | 0.164808 | 816 | -148 | -148 | 0.00264384 | 1852 | 1852
872965 | 02 tweede verdieping | 02 tweede verdieping | 976.638 | Level : 02 tweede verdieping | 1112 | 0 | 0.164808 | 816 | -148 | -148 | 0.00264384 | 1852 | 1852
872998 | 02 tweede verdieping | 02 tweede verdieping | 976.638 | Level : 02 tweede verdieping | 1112 | 0 | 0.164808 | 816 | -148 | -148 | 0.00264384 | 1852 | 1852
873031 | 02 tweede verdieping | 02 tweede verdieping | 976.638 | Level : 02 tweede verdieping | 1112 | 0 | 0.164808 | 816 | -148 | -148 | 0.00264384 | 1852 | 1852
873064 | 02 tweede verdieping | 02 tweede verdieping | 976.638 | Level : 02 tweede verdieping | 1112 | 0 | 0.164808 | 816 | -148 | -148 | 0.00264384 | 1852 | 1852
873097 | 02 tweede verdieping | 02 tweede verdieping | 976.638 | Level : 02 tweede verdieping | 1112 | 0 | 0.164808 | 816 | -148 | -148 | 0.00264384 | 1852 | 1852
873408 | 02 tweede verdieping | 02 tweede verdieping | 976.638 | Level : 02 tweede verdieping | 1112 | 0 | 0.164808 | 816 | -148 | -148 | 0.00264384 | 1852 | 1852
873458 | 02 tweede verdieping | 02 tweede verdieping | 976.638 | Level : 02 tweede verdieping | 1112 | 0 | 0.164808 | 816 | -148 | -148 | 0.00264384 | 1852 | 1852
873489 | 02 tweede verdieping | 02 tweede verdieping | 976.638 | Level : 02 tweede verdieping | 1112 | 0 | 0.164808 | 816 | -148 | -148 | 0.00264384 | 1852 | 1852
873520 | 02 tweede verdieping | 02 tweede verdieping | 976.638 | Level : 02 tweede verdieping | 1112 | 0 | 0.164808 | 816 | -148 | -148 | 0.00264384 | 1852 | 1852
873551 | 02 tweede verdieping | 02 tweede verdieping | 976.638 | Level : 02 tweede verdieping | 1112 | 0 | 0.164808 | 816 | -148 | -148 | 0.00264384 | 1852 | 1852
873582 | 02 tweede verdieping | 02 tweede verdieping | 976.638 | Level : 02 tweede verdieping | 1112 | 0 | 0.164808 | 816 | -148 | -148 | 0.00264384 | 1852 | 1852
873613 | 02 tweede verdieping | 02 tweede verdieping | 976.638 | Level : 02 tweede verdieping | 1112 | 0 | 0.164808 | 816 | -148 | -148 | 0.00264384 | 1852 | 1852
873644 | 02 tweede verdieping | 02 tweede verdieping | 976.638 | Level : 02 tweede verdieping | 1112 | 0 | 0.164808 | 816 | -148 | -148 | 0.00264384 | 1852 | 1852
873675 | 02 tweede verdieping | 02 tweede verdieping | 976.638 | Level : 02 tweede verdieping | 1112 | 0 | 0.164808 | 816 | -148 | -148 | 0.00264384 | 1852 | 1852
873706 | 02 tweede verdieping | 02 tweede verdieping | 976.638 | Level : 02 tweede verdieping | 1112 | 0 | 0.164808 | 816 | -148 | -148 | 0.00264384 | 1852 | 1852
873737 | 02 tweede verdieping | 02 tweede verdieping | 976.638 | Level : 02 tweede verdieping | 1112 | 0 | 0.164808 | 816 | -148 | -148 | 0.00264384 | 1852 | 1852
874903 | 01 eerste verdieping | 01 eerste verdieping | 951.638 | Level : 01 eerste verdieping | 2000 | 0 | 0.347166 | 1737 | -131.5 | -131.5 | 0.00562788 | 1868.5 | 1868.5
874915 | 01 eerste verdieping | 01 eerste verdieping | 951.638 | Level : 01 eerste verdieping | 2000 | 0 | 0.347166 | 1737 | -131.5 | -131.5 | 0.00562788 | 1868.5 | 1868.5
874927 | 01 eerste verdieping | 01 eerste verdieping | 951.638 | Level : 01 eerste verdieping | 2000 | 0 | 0.347166 | 1737 | -131.5 | -131.5 | 0.00562788 | 1868.5 | 1868.5
874993 | 01 eerste verdieping | 01 eerste verdieping | 951.638 | Level : 01 eerste verdieping | 2000 | 0 | 0.347166 | 1737 | -131.5 | -131.5 | 0.00562788 | 1868.5 | 1868.5
875005 | 01 eerste verdieping | 01 eerste verdieping | 951.638 | Level : 01 eerste verdieping | 2000 | 0 | 0.347166 | 1737 | -131.5 | -131.5 | 0.00562788 | 1868.5 | 1868.5
875017 | 01 eerste verdieping | 01 eerste verdieping | 951.638 | Level : 01 eerste verdieping | 2000 | 0 | 0.347166 | 1737 | -131.5 | -131.5 | 0.00562788 | 1868.5 | 1868.5
875222 | 01 eerste verdieping | 01 eerste verdieping | 951.638 | Level : 01 eerste verdieping | 2000 | 0 | 0.347166 | 1737 | -131.5 | -131.5 | 0.00562788 | 1868.5 | 1868.5
875258 | 01 eerste verdieping | 01 eerste verdieping | 951.638 | Level : 01 eerste verdieping | 2000 | 0 | 0.347166 | 1737 | -131.5 | -131.5 | 0.00562788 | 1868.5 | 1868.5
875294 | 01 eerste verdieping | 01 eerste verdieping | 951.638 | Level : 01 eerste verdieping | 2000 | 0 | 0.347166 | 1737 | -131.5 | -131.5 | 0.00562788 | 1868.5 | 1868.5
875330 | 01 eerste verdieping | 01 eerste verdieping | 951.638 | Level : 01 eerste verdieping | 2000 | 0 | 0.347166 | 1737 | -131.5 | -131.5 | 0.00562788 | 1868.5 | 1868.5
875366 | 01 eerste verdieping | 01 eerste verdieping | 951.638 | Level : 01 eerste verdieping | 2000 | 0 | 0.347166 | 1737 | -131.5 | -131.5 | 0.00562788 | 1868.5 | 1868.5
876531 | 01 eerste verdieping | 01 eerste verdieping | 976.638 | Level : 01 eerste verdieping | 2000 | 0 | 0.347166 | 1737 | -131.5 | -131.5 | 0.00562788 | 1868.5 | 1868.5
876768 | 01 eerste verdieping | 01 eerste verdieping | 976.638 | Level : 01 eerste verdieping | 2000 | 0 | 0.347166 | 1737 | -131.5 | -131.5 | 0.00562788 | 1868.5 | 1868.5
876787 | 01 eerste verdieping | 01 eerste verdieping | 976.638 | Level : 01 eerste verdieping | 2000 | 0 | 0.347166 | 1737 | -131.5 | -131.5 | 0.00562788 | 1868.5 | 1868.5
876933 | 01 eerste verdieping | 01 eerste verdieping | 976.638 | Level : 01 eerste verdieping | 2000 | 0 | 0.347166 | 1737 | -131.5 | -131.5 | 0.00562788 | 1868.5 | 1868.5
876945 | 01 eerste verdieping | 01 eerste verdieping | 976.638 | Level : 01 eerste verdieping | 2000 | 0 | 0.347166 | 1737 | -131.5 | -131.5 | 0.00562788 | 1868.5 | 1868.5
876957 | 01 eerste verdieping | 01 eerste verdieping | 976.638 | Level : 01 eerste verdieping | 2000 | 0 | 0.347166 | 1737 | -131.5 | -131.5 | 0.00562788 | 1868.5 | 1868.5
877050 | 01 eerste verdieping | 01 eerste verdieping | 976.638 | Level : 01 eerste verdieping | 2000 | 0 | 0.347166 | 1737 | -131.5 | -131.5 | 0.00562788 | 1868.5 | 1868.5
877062 | 01 eerste verdieping | 01 eerste verdieping | 976.638 | Level : 01 eerste verdieping | 2000 | 0 | 0.347166 | 1737 | -131.5 | -131.5 | 0.00562788 | 1868.5 | 1868.5
877074 | 01 eerste verdieping | 01 eerste verdieping | 976.638 | Level : 01 eerste verdieping | 2000 | 0 | 0.347166 | 1737 | -131.5 | -131.5 | 0.00562788 | 1868.5 | 1868.5
877140 | 01 eerste verdieping | 01 eerste verdieping | 976.638 | Level : 01 eerste verdieping | 2000 | 0 | 0.347166 | 1737 | -131.5 | -131.5 | 0.00562788 | 1868.5 | 1868.5
877152 | 01 eerste verdieping | 01 eerste verdieping | 976.638 | Level : 01 eerste verdieping | 2000 | 0 | 0.347166 | 1737 | -131.5 | -131.5 | 0.00562788 | 1868.5 | 1868.5
877164 | 01 eerste verdieping | 01 eerste verdieping | 976.638 | Level : 01 eerste verdieping | 2000 | 0 | 0.347166 | 1737 | -131.5 | -131.5 | 0.00562788 | 1868.5 | 1868.5
877230 | 01 eerste verdieping | 01 eerste verdieping | 976.638 | Level : 01 eerste verdieping | 2000 | 0 | 0.347166 | 1737 | -131.5 | -131.5 | 0.00562788 | 1868.5 | 1868.5
877242 | 01 eerste verdieping | 01 eerste verdieping | 976.638 | Level : 01 eerste verdieping | 2000 | 0 | 0.347166 | 1737 | -131.5 | -131.5 | 0.00562788 | 1868.5 | 1868.5
881632 | 01 eerste verdieping | 01 eerste verdieping | 976.638 | Level : 01 eerste verdieping | 2000 | 0 | 0.347166 | 1737 | -131.5 | -131.5 | 0.00562788 | 1868.5 | 1868.5
881668 | 01 eerste verdieping | 01 eerste verdieping | 976.638 | Level : 01 eerste verdieping | 2000 | 0 | 0.347166 | 1737 | -131.5 | -131.5 | 0.00562788 | 1868.5 | 1868.5
881744 | 01 eerste verdieping | 01 eerste verdieping | 976.638 | Level : 01 eerste verdieping | 2000 | 0 | 0.347166 | 1737 | -131.5 | -131.5 | 0.00562788 | 1868.5 | 1868.5
881771 | 01 eerste verdieping | 01 eerste verdieping | 976.638 | Level : 01 eerste verdieping | 2000 | 0 | 0.347166 | 1737 | -131.5 | -131.5 | 0.00562788 | 1868.5 | 1868.5
891621 | 01 eerste verdieping | 01 eerste verdieping | 976.638 | Level : 01 eerste verdieping | 637.5 | 0 | 0.066303 | 318.5 | -131.5 | -187.5 | 0.00103194 | 1868.5 | 1812.5
891643 | 01 eerste verdieping | 01 eerste verdieping | 976.638 | Level : 01 eerste verdieping | 2000 | 0 | 0.347166 | 1737 | -131.5 | -131.5 | 0.00562788 | 1868.5 | 1868.5
891665 | 01 eerste verdieping | 01 eerste verdieping | 976.638 | Level : 01 eerste verdieping | 2000 | 0 | 0.347166 | 1737 | -131.5 | -131.5 | 0.00562788 | 1868.5 | 1868.5
891687 | 01 eerste verdieping | 01 eerste verdieping | 976.638 | Level : 01 eerste verdieping | 2000 | 0 | 0.347166 | 1737 | -131.5 | -131.5 | 0.00562788 | 1868.5 | 1868.5
891709 | 01 eerste verdieping | 01 eerste verdieping | 976.638 | Level : 01 eerste verdieping | 2000 | 0 | 0.347166 | 1737 | -131.5 | -131.5 | 0.00562788 | 1868.5 | 1868.5
891749 | 01 eerste verdieping | 01 eerste verdieping | 976.638 | Basic Wall : 21_WA_metselwerk_licht_100_gen_bdg | 2000 | 0 | 0.347166 | 1737 | -131.5 | -131.5 | 0.00562788 | 1868.5 | 1868.5
891777 | 01 eerste verdieping | 01 eerste verdieping | 976.638 | Level : 01 eerste verdieping | 2000 | 0 | 0.347166 | 1737 | -131.5 | -131.5 | 0.00562788 | 1868.5 | 1868.5
891894 | 01 eerste verdieping | 01 eerste verdieping | 976.638 | Level : 01 eerste verdieping | 2000 | 0 | 0.347166 | 1737 | -131.5 | -131.5 | 0.00562788 | 1868.5 | 1868.5
891916 | 01 eerste verdieping | 01 eerste verdieping | 976.638 | Level : 01 eerste verdieping | 2000 | 0 | 0.347166 | 1737 | -131.5 | -131.5 | 0.00562788 | 1868.5 | 1868.5
891966 | 01 eerste verdieping | 01 eerste verdieping | 976.638 | Level : 01 eerste verdieping | 2000 | 0 | 0.347166 | 1737 | -131.5 | -131.5 | 0.00562788 | 1868.5 | 1868.5
2196515 | 00 begane grond | 00 begane grond | 976.638 | Basic Wall : NLRS_22_WA_HSB bispouw 30-245-12-13 glaswol_gen_ISR | 3562 | 0 | 0.649908 | 3266 | -148 | -148 | 0.0105818 | 1852 | 1852
2239346 | 01 eerste verdieping | 01 eerste verdieping | 976.638 | Level : 01 eerste verdieping | 1503 | -45 | 0.227552 | 1219.5 | -131.5 | -152 | 0.00365958 | 1868.5 | 1848
2239383 | 01 eerste verdieping | 01 eerste verdieping | 976.638 | Basic Wall : NLRS_22_WA_HSB bispouw 30-245-12-13 glaswol_gen_ISR | 1103 | -45 | 0.148352 | 819.5 | -131.5 | -152 | 0.00236358 | 1868.5 | 1848
2239477 | 01 eerste verdieping | 01 eerste verdieping | 976.638 | Basic Wall : NLRS_22_WA_HSB bispouw 30-245-12-13 glaswol_gen_ISR | 603 | -45 | 0.049352 | 319.5 | -131.5 | -152 | 0.00074358 | 1868.5 | 1848
2239495 | 01 eerste verdieping | 01 eerste verdieping | 976.638 | Basic Wall : NLRS_22_WA_HSB bispouw 30-245-12-13 glaswol_gen_ISR | 1503 | -45 | 0.227552 | 1219.5 | -131.5 | -152 | 0.00365958 | 1868.5 | 1848
2546403 | 00 begane grond | 00 begane grond | 1725 | Level : 00 begane grond | 1162 | 0 | 0.174708 | 866 | -148 | -148 | 0.00280584 | 1852 | 1852
2749758 | 01 eerste verdieping | 01 eerste verdieping | 951.638 | Level : 01 eerste verdieping | 805 | 0 | 0.110556 | 542 | -131.5 | -131.5 | 0.00175608 | 1868.5 | 1868.5
2759479 | 01 eerste verdieping | 01 eerste verdieping | 976.638 | Basic Wall : 22_WA_binnenwand_ms125 25-75-25 _gen_bdg | 1503 | -45 | 0.227552 | 1219.5 | -131.5 | -152 | 0.00365958 | 1868.5 | 1848
2762375 | 01 eerste verdieping | 01 eerste verdieping | 976.638 | Basic Wall : 22_WA_koof_96 12-12-50 | 603 | -45 | 0.049352 | 319.5 | -131.5 | -152 | 0.00074358 | 1868.5 | 1848

# IfcBuildingElementProxy: NLRS_42_GM_WPB_vensterbank_natuursteen-SH_generiek_ISR:335x18 vensterbank composiet (5)
Type - Material: 00_Natuursteen
Type - Constraints - Default Elevation: 1219.2 mm
Type - Materials and Finishes - materiaal: 00_Natuursteen
Type - Dimensions - breedte: 335 mm; hoogte: 18 mm
Type - Identity Data - Workset: Family : Generic Models : NLRS_42_GM_WPB_vensterbank_natuursteen-SH_generiek_ISR; Assembly Code: 42; Assembly Description: binnenwandafwerkingen; Datum_Gewijzigd: 20160502; Description: vensterbank; Model: LOD300; SmartRevit_Versie: 2019.1; Type Name: 335x18 vensterbank composiet
Type - Other - Category: Generic Models; Family Name: NLRS_42_GM_WPB_vensterbank_natuursteen-SH_generiek_ISR
Classification: 42 Uniformat (Uniformat)
Constraints - Moves With Nearby Elements: no; Elevation from Level: 976.638 mm; Offset from Host: 976.638 mm
Phasing - Phase Created: 2. nieuwbouw
Graphics - hoek_a: 0 deg; hoek_b: 0 deg
Dimensions - NLRS_C_breedte: 335 mm; NLRS_C_hoogte: 18 mm
Identity Data - Workset: Workset1
Other - berekende_hoek_a: 0 deg; berekende_overstek_a: 0 mm; berekende_overstek_b: 0 mm; Family: NLRS_42_GM_WPB_vensterbank_natuursteen-SH_generiek_ISR; Family and Type: NLRS_42_GM_WPB_vensterbank_natuursteen-SH_generiek_ISR: 335x18 vensterbank composiet; Type: 335x18 vensterbank composiet; Type Id: 4342040
Name (NLRS_42_GM_WPB_vensterbank_natuursteen-SH_generiek_ISR:335x18 vensterbank composiet:...) | In | Level | Host | lengte (mm) = NLRS_C_lengte (mm) | Area (m2) | element_lengte (mm) | verlenging_a (mm) | verlenging_b (mm) | Volume (m3) | berekende_verlenging_a (mm) | berekende_verlenging_b (mm)
872899 | 02 tweede verdieping | 02 tweede verdieping | Level : 02 tweede verdieping | 1112 | 0.294078 | 816 | -148 | -148 | 0.00492048 | 1852 | 1852
872932 | 02 tweede verdieping | 02 tweede verdieping | Level : 02 tweede verdieping | 1112 | 0.294078 | 816 | -148 | -148 | 0.00492048 | 1852 | 1852
880828 | 01 eerste verdieping | 01 eerste verdieping | Basic Wall : NLRS_22_WA_HSB bispouw 30-245-12-13 glaswol_gen_ISR | 2000 | 0.619191 | 1737 | -131.5 | -131.5 | 0.0104741 | 1868.5 | 1868.5
881596 | 01 eerste verdieping | 01 eerste verdieping | Level : 01 eerste verdieping | 2000 | 0.619191 | 1737 | -131.5 | -131.5 | 0.0104741 | 1868.5 | 1868.5
4343090 | 01 eerste verdieping | 01 eerste verdieping | Level : 01 eerste verdieping | 1662.5 | 0.480285 | 1343.5 | -131.5 | -187.5 | 0.0081013 | 1868.5 | 1812.5

# IfcBuildingElementProxy: NLRS_47_GM_WPB_hwa_gen_ISR:hwa_gen, NLRS_47_GM_WPB_hwa_gen_ISR:hwa_gen:5087125
In: 01 eerste verdieping
Type - Material: n6_kunststof_grijs
Type - Constraints - Default Elevation: 1219.2 mm
Type - Dimensions - tussenstuk_breedte: 0 mm; tussenstuk_hoogte: 0 mm; bovenstuk_hoogte: 400 mm; hwa_radius: 87.5 mm
Type - Identity Data - Assembly Code: 47.1; Description: hwa; Model: LOD300; SmartRevit_Versie: 2019.1; Type Name: hwa_gen; Workset: Family : Generic Models : NLRS_47_GM_WPB_hwa_gen_ISR
Type - Other - Category: Generic Models; berekende_binnen_radius: 82.5 mm; Family Name: NLRS_47_GM_WPB_hwa_gen_ISR
Classification: 47.1 Uniformat (Uniformat)
Constraints - Elevation from Level: 0 mm; Host: Level : 02 bk. ruwe vloer; Level: 02 bk. ruwe vloer; Schedule Level: 02 bk. ruwe vloer
Phasing - Phase Created: 2. nieuwbouw
Dimensions - Area: 2.26873 m2; hwa_hoogte: 3800 mm; Volume: 0.010147 m3
Identity Data - Workset: Workset1
Other - Family: NLRS_47_GM_WPB_hwa_gen_ISR; Family and Type: NLRS_47_GM_WPB_hwa_gen_ISR: hwa_gen; Type: hwa_gen; Type Id: 5085731

# IfcBuildingElementProxy: NLRS_47_GM_WPB_hwa_generiek_ISR:zinken HWA (2)
In: 01 eerste verdieping
Type - Material: ISR_Dak_zink
Type - Constraints - Default Elevation: -100 mm
Type - Materials and Finishes - materiaal: ISR_Dak_zink
Type - Dimensions - bovenstuk_hoogte: 50 mm; hwa_radius: 40 mm; tussenstuk_breedte: 0 mm; tussenstuk_hoogte: 0 mm
Type - Identity Data - Assembly Code: 52.12; Assembly Description: afvoeren; regenwater, afvoerinstallatie; buiten het gebouw; Datum_Gewijzigd: 20160502; Description: hwa; Model: LOD300; SmartRevit_Versie: 2016.2; Type Name: zinken HWA; Workset: Family : Generic Models : NLRS_47_GM_WPB_hwa_generiek_ISR
Type - Other - Category: Generic Models; berekende_binnen_radius: 35 mm; Family Name: NLRS_47_GM_WPB_hwa_generiek_ISR
Classification: 52.12 Uniformat (Uniformat); Group: Model Group:fietsenstalling:4188142
Constraints - Level: 01 eerste verdieping; Schedule Level: 01 eerste verdieping; Host: <not associated>
Phasing - Phase Created: 2. nieuwbouw
Structural - Rebar Cover: 30mm <30 mm>
Dimensions - Area: 0.534665 m2; hwa_hoogte: 2264.19 mm; Volume: 0.00266733 m3
Identity Data - Workset: BDG_fietsenstalling
Other - Family: NLRS_47_GM_WPB_hwa_generiek_ISR; Family and Type: NLRS_47_GM_WPB_hwa_generiek_ISR: zinken HWA; Type: zinken HWA; Type Id: 4051822
Name (NLRS_47_GM_WPB_hwa_generiek_ISR:zinken HWA:...) | Elevation from Level (mm)
4053864 | -1816.1
4078830 | -1816.16

# IfcBuildingElementProxy: NLRS_65_GM_WPB_brandscheiding_gen_ISR:30 minuten (2)
In: 00 begane grond
Type - Material: 65_30_minuten
Type - Fire Protection - NLRS_C_brandwerendheid: 30
Type - Constraints - Default Elevation: 0 mm
Type - Materials and Finishes - NLRS_C_materiaal: 65_30_minuten
Type - Graphics - brandscheiding_120_minuten: no; brandscheiding_90_minuten: no; brandscheiding_30_minuten: yes; brandscheiding_60_minuten: no
Type - Dimensions - offset_brandscheiding: 0 mm; dikte: 10 mm
Type - Identity Data - Workset: Family : Generic Models : NLRS_65_GM_WPB_brandscheiding_gen_ISR; Assembly Code: 65.1; Description: brandscheiding 30min; Manufacturer: gen; Model: LOD300; Type Comments: niet meenemen bij het clashen; Type Name: 30 minuten
Type - Other - Category: Generic Models; Family Name: NLRS_65_GM_WPB_brandscheiding_gen_ISR
Classification: 65.1 Uniformat (Uniformat)
Constraints - Offset from Host: 0 mm; Work Plane: Floor : NLRS_43_FL_cementdekvloer 60_gen_ISR
Phasing - Phase Created: 2. nieuwbouw
Dimensions - NLRS_C_hoogte: 3600 mm
Identity Data - Workset: Workset1
Other - Family: NLRS_65_GM_WPB_brandscheiding_gen_ISR; Family and Type: NLRS_65_GM_WPB_brandscheiding_gen_ISR: 30 minuten; Type: 30 minuten; Type Id: 1364372
Name (NLRS_65_GM_WPB_brandscheiding_gen_ISR:30 minuten:...) | Length (mm) | Area (m2) | Volume (m3)
2103321 | 8350 | 30.1795 | 0.3006
2104239 | 2493.48 | 9.03748 | 0.0897654

# IfcBuildingElementProxy: NLRS_65_GM_WPB_brandscheiding_gen_ISR:60 minuten (50)
Type - Material: 65_60_minuten
Type - Fire Protection - NLRS_C_brandwerendheid: 60
Type - Constraints - Default Elevation: 0 mm
Type - Materials and Finishes - NLRS_C_materiaal: 65_60_minuten
Type - Graphics - brandscheiding_120_minuten: no; brandscheiding_30_minuten: no; brandscheiding_60_minuten: yes; brandscheiding_90_minuten: no
Type - Dimensions - dikte: 10 mm; offset_brandscheiding: 0 mm
Type - Identity Data - Assembly Code: 65.1; Description: brandscheiding 60min; Manufacturer: gen; Model: LOD300; Type Comments: niet meenemen bij het clashen; Type Name: 60 minuten; Workset: Family : Generic Models : NLRS_65_GM_WPB_brandscheiding_gen_ISR
Type - Other - Category: Generic Models; Family Name: NLRS_65_GM_WPB_brandscheiding_gen_ISR
Classification: 65.1 Uniformat (Uniformat)
Constraints - Offset from Host: 0 mm
Phasing - Phase Created: 2. nieuwbouw
Identity Data - Workset: Workset1
Other - Family: NLRS_65_GM_WPB_brandscheiding_gen_ISR; Family and Type: NLRS_65_GM_WPB_brandscheiding_gen_ISR: 60 minuten; Type: 60 minuten; Type Id: 1364373
Name (NLRS_65_GM_WPB_brandscheiding_gen_ISR:60 minuten:...) | In | Length (mm) | Work Plane | Area (m2) | NLRS_C_hoogte (mm) | Volume (m3)
1364332 | 01 eerste verdieping | 8400 | Level : 01 eerste verdieping | 28.678 | 3400 | 0.2856
1798541 | 00 begane grond | 8658.78 | Level : 00 begane grond | 31.2942 | 3600 | 0.311716
1798712 | 00 begane grond | 8171.36 | Level : 00 begane grond | 29.5346 | 3600 | 0.294169
1798821 | 00 begane grond | 5781.22 | Level : 00 begane grond | 20.9062 | 3600 | 0.208124
1798904 | 00 begane grond | 2479.43 | Level : 00 begane grond | 8.98676 | 3600 | 0.0892596
1798957 | 00 begane grond | 3004.81 | Level : 00 begane grond | 10.8834 | 3600 | 0.108173
1799033 | 00 begane grond | 1260 | Level : 00 begane grond | 4.5846 | 3600 | 0.04536
1799060 | 00 begane grond | 320 | Level : 00 begane grond | 1.1912 | 3600 | 0.01152
1799268 | 00 begane grond | 13665.6 | Level : 00 begane grond | 49.3687 | 3600 | 0.49196
1799328 | 00 begane grond | 2200 | Level : 00 begane grond | 7.978 | 3600 | 0.0792
1799410 | 00 begane grond | 8460 | Level : 00 begane grond | 30.5766 | 3600 | 0.30456
1799767 | 00 begane grond | 2401.22 | Level : 00 begane grond | 8.7044 | 3600 | 0.0864439
1799819 | 00 begane grond | 3260 | Level : 00 begane grond | 11.8046 | 3600 | 0.11736
1799888 | 00 begane grond | 2400 | Level : 00 begane grond | 8.7 | 3600 | 0.0864
1799981 | 00 begane grond | 4050.89 | Level : 00 begane grond | 14.6597 | 3600 | 0.145832
1800219 | 00 begane grond | 9323.41 | Level : 00 begane grond | 33.6935 | 3600 | 0.335643
1800370 | 01 eerste verdieping | 2680 | Level : 01 eerste verdieping | 9.1728 | 3400 | 0.09112
1800446 | 01 eerste verdieping | 8000 | Level : 01 eerste verdieping | 27.314 | 3400 | 0.272
1800517 | 01 eerste verdieping | 2700 | Level : 01 eerste verdieping | 9.241 | 3400 | 0.0918
1800582 | 01 eerste verdieping | 7985.5 | Level : 01 eerste verdieping | 27.2646 | 3400 | 0.271507
1800655 | 01 eerste verdieping | 889.336 | Level : 01 eerste verdieping | 3.06664 | 3400 | 0.0302374
1800762 | 01 eerste verdieping | 3510 | Level : 01 eerste verdieping | 12.0031 | 3400 | 0.11934
1800815 | 01 eerste verdieping | 2125 | Level : 01 eerste verdieping | 7.28025 | 3400 | 0.07225
1800914 | 02 tweede verdieping | 8480 | Level : 02 tweede verdieping | 28.9508 | 3400 | 0.28832
1800915 | 02 tweede verdieping | 2680 | Level : 02 tweede verdieping | 9.1728 | 3400 | 0.09112
1800916 | 02 tweede verdieping | 7920 | Level : 02 tweede verdieping | 27.0412 | 3400 | 0.26928
1800917 | 02 tweede verdieping | 2700 | Level : 02 tweede verdieping | 9.241 | 3400 | 0.0918
1800918 | 02 tweede verdieping | 7985.5 | Level : 02 tweede verdieping | 27.2646 | 3400 | 0.271507
2102834 | 00 begane grond | 6364.34 | Floor : NLRS_43_FL_cementdekvloer 60_gen_ISR | 23.0113 | 3600 | 0.229116
2102977 | 00 begane grond | 6426.59 | Floor : NLRS_43_FL_cementdekvloer 60_gen_ISR | 23.236 | 3600 | 0.231357
2103113 | 00 begane grond | 2390 | Floor : NLRS_43_FL_cementdekvloer 60_gen_ISR | 8.6639 | 3600 | 0.08604
2105241 | 01 eerste verdieping | 1046 | Floor : NLRS_43_FL_cementdekvloer 50_gen_ISR | 3.60086 | 3400 | 0.035564
2105327 | 01 eerste verdieping | 473.272 | Floor : NLRS_43_FL_cementdekvloer 50_gen_ISR | 1.64786 | 3400 | 0.0160913
2105530 | 02 tweede verdieping | 911.916 | Level : 02 tweede verdieping | 3.14363 | 3400 | 0.0310051
2105531 | 02 tweede verdieping | 3510 | Level : 02 tweede verdieping | 12.0031 | 3400 | 0.11934
2105532 | 02 tweede verdieping | 2400 | Level : 02 tweede verdieping | 8.218 | 3400 | 0.0816
2105534 | 02 tweede verdieping | 1619.86 | Level : 02 tweede verdieping | 5.55774 | 3400 | 0.0550754
2105536 | 02 tweede verdieping | 473.272 | Level : 02 tweede verdieping | 1.64786 | 3400 | 0.0160913
2384846 | 02 tweede verdieping | 2272.36 | Level : 02 tweede verdieping | 7.78274 | 3400 | 0.0772601
2384896 | 02 tweede verdieping | 660 | Floor : NLRS_43_FL_cementdekvloer 50_gen_ISR | 2.2846 | 3400 | 0.02244
2409319 | 02 tweede verdieping | 160 | Level : 02 tweede verdieping | 0.5796 | 3400 | 0.00544
2409320 | 02 tweede verdieping | 210.136 | Level : 02 tweede verdieping | 0.750564 | 3400 | 0.00714463
2409329 | 01 eerste verdieping | 435 | Level : 01 eerste verdieping | 1.51735 | 3400 | 0.01479
2409330 | 01 eerste verdieping | 515 | Level : 01 eerste verdieping | 1.79015 | 3400 | 0.01751
3023053 | 01 eerste verdieping | 679.45 | Floor : NLRS_43_FL_cementdekvloer 50_gen_ISR | 2.35092 | 3400 | 0.0231013
3023112 | 01 eerste verdieping | 2260 | NLRS_70_GM_UN_aanrechtblad : std | 7.7406 | 3400 | 0.07684
5034014 | 00 begane grond | 2390 | Floor : NLRS_43_FL_cementdekvloer 60_gen_ISR | 8.6639 | 3600 | 0.08604
5045031 | 00 begane grond | 3307.94 | Floor : NLRS_43_FL_cementdekvloer 60_gen_ISR | 11.9777 | 3600 | 0.119086
5045104 | 00 begane grond | 3192 | Floor : NLRS_43_FL_cementdekvloer 60_gen_ISR | 11.5591 | 3600 | 0.114912
5045150 | 00 begane grond | 465 | Floor : NLRS_43_FL_cementdekvloer 60_gen_ISR | 1.71465 | 3600 | 0.01674

# IfcBuildingElementProxy: NLRS_70_FUS_wandspiegel_gen_bdg:1050x750mm (2)
In: 00 begane grond
Type - Material: <Unnamed>
Type - Constraints(Type) - Default Elevation: 1120 mm
Type - Dimensions(Type) - breedte: 1050 mm; hoogte: 750 mm; spiegel_dikte: 10 mm
Type - Identity Data(Type) - Description: spiegel 1050x750; Type Name: 1050x750mm; Workset: Family : Generic Models : NLRS_70_FUS_wandspiegel_gen_bdg
Type - Other(Type) - Category: Generic Models; Family Name: NLRS_70_FUS_wandspiegel_gen_bdg
Constraints - Level: 00 begane grond; Schedule Level: 00 begane grond; Host: <not associated>
Phasing - Phase Created: 2. nieuwbouw
Dimensions - Area: 0.8055 m2; Volume: 0.007875 m3
Identity Data - Workset: Workset1
Other - Category: Generic Models; Family: NLRS_70_FUS_wandspiegel_gen_bdg; Family and Type: NLRS_70_FUS_wandspiegel_gen_bdg: 1050x750mm; Type: 1050x750mm; Type Id: 5074581
Name (NLRS_70_FUS_wandspiegel_gen_bdg:1050x750mm:...) | Elevation from Level (mm)
5055068 | 1375
5055719 | 1075

# IfcBuildingElementProxy: NLRS_70_FUS_wandspiegel_gen_bdg:600x750mm, NLRS_70_FUS_wandspiegel_gen_bdg:600x750mm:5060379
In: 00 begane grond
Type - Material: <Unnamed>
Type - Constraints(Type) - Default Elevation: 1120 mm
Type - Dimensions(Type) - breedte: 600 mm; hoogte: 750 mm; spiegel_dikte: 10 mm
Type - Identity Data(Type) - Workset: Family : Generic Models : NLRS_70_FUS_wandspiegel_gen_bdg; Description: spiegel 600x750; Type Name: 600x750mm
Type - Other(Type) - Category: Generic Models; Family Name: NLRS_70_FUS_wandspiegel_gen_bdg
Constraints - Level: 00 begane grond; Schedule Level: 00 begane grond; Elevation from Level: 9175 mm; Host: <not associated>
Phasing - Phase Created: 2. nieuwbouw
Dimensions - Area: 0.4635 m2; Volume: 0.0045 m3
Identity Data - Workset: Workset1
Other - Category: Generic Models; Family: NLRS_70_FUS_wandspiegel_gen_bdg; Family and Type: NLRS_70_FUS_wandspiegel_gen_bdg: 600x750mm; Type: 600x750mm; Type Id: 5075414

# IfcBuildingElementProxy: NLRS_70_FUS_wandspiegel_gen_bdg:750x750mm (2)
In: 00 begane grond
Type - Material: <Unnamed>
Type - Constraints(Type) - Default Elevation: 1120 mm
Type - Dimensions(Type) - breedte: 750 mm; hoogte: 750 mm; spiegel_dikte: 10 mm
Type - Identity Data(Type) - Workset: Family : Generic Models : NLRS_70_FUS_wandspiegel_gen_bdg; Description: spiegel 750x750; Type Name: 750x750mm
Type - Other(Type) - Category: Generic Models; Family Name: NLRS_70_FUS_wandspiegel_gen_bdg
Constraints - Level: 00 begane grond; Schedule Level: 00 begane grond; Elevation from Level: 5375 mm; Host: <not associated>
Phasing - Phase Created: 2. nieuwbouw
Dimensions - Area: 0.5775 m2; Volume: 0.005625 m3
Identity Data - Workset: Workset1
Other - Category: Generic Models; Family: NLRS_70_FUS_wandspiegel_gen_bdg; Family and Type: NLRS_70_FUS_wandspiegel_gen_bdg: 750x750mm; Type: 750x750mm; Type Id: 5075056
Name (NLRS_70_FUS_wandspiegel_gen_bdg:750x750mm:...)
5058489
5059132

# IfcBuildingElementProxy: NLRS_70_FUS_wandspiegel_gen_bdg:900x750mm (8)
In: 00 begane grond
Type - Material: <Unnamed>
Type - Constraints(Type) - Default Elevation: 1120 mm
Type - Dimensions(Type) - breedte: 900 mm; hoogte: 750 mm; spiegel_dikte: 10 mm
Type - Identity Data(Type) - Workset: Family : Generic Models : NLRS_70_FUS_wandspiegel_gen_bdg; Description: spiegel 900x750; Type Comments: 900x750; Type Name: 900x750mm
Type - Other(Type) - Category: Generic Models; Family Name: NLRS_70_FUS_wandspiegel_gen_bdg
Constraints - Level: 00 begane grond; Schedule Level: 00 begane grond; Host: <not associated>
Phasing - Phase Created: 2. nieuwbouw
Dimensions - Area: 0.6915 m2; Volume: 0.00675 m3
Identity Data - Workset: Workset1
Other - Category: Generic Models; Family: NLRS_70_FUS_wandspiegel_gen_bdg; Family and Type: NLRS_70_FUS_wandspiegel_gen_bdg: 900x750mm; Type: 900x750mm; Type Id: 5052545
Name (NLRS_70_FUS_wandspiegel_gen_bdg:900x750mm:...) | Elevation from Level (mm)
5052574 | 1375
5056237 | 1525
5057531 | 1375
5057995 | 1525
5059366 | 5375
5059689 | 5375
5059998 | 9175
5060682 | 9175

# IfcBuildingElementProxy: NLRS_70_GM_UN_aanrechtblad300:std (2)
In: 00 begane grond
Type - Material: <Unnamed>
Type - Constraints - Default Elevation: 0 mm
Type - Identity Data - Type Name: std; Workset: Family : Generic Models : NLRS_70_GM_UN_aanrechtblad300
Type - Other - Category: Generic Models; Family Name: NLRS_70_GM_UN_aanrechtblad300
Constraints - Level: 00 begane grond; Moves With Nearby Elements: no; Elevation from Level: 870 mm; Host: Level : 00 begane grond; Offset from Host: 870 mm
Phasing - Phase Created: 2. nieuwbouw
Dimensions - Area: 0.25425 m2; breedte: 375 mm; diepte: 600 mm; dikte: 30 mm; Volume: 0.00675 m3
Identity Data - Workset: Workset1
Other - Type: std; aanrechtblad: no; wasbak: yes; Family: NLRS_70_GM_UN_aanrechtblad300; Family and Type: NLRS_70_GM_UN_aanrechtblad300: std; Type Id: 1690954
Name (NLRS_70_GM_UN_aanrechtblad300:std:...) | Group
1693031 | Model Group:pantry 1 kinderopvang:1223752
1693070 | Model Group:pantry 1 kinderopvang:1511177

# IfcBuildingElementProxy: NLRS_70_GM_UN_aanrechtblad:std (57)
Type - Material: <Unnamed>
Type - Constraints - Default Elevation: 0 mm
Type - Identity Data - Type Name: std; Workset: Family : Generic Models : NLRS_70_GM_UN_aanrechtblad
Type - Other - Category: Generic Models; Family Name: NLRS_70_GM_UN_aanrechtblad
Constraints - Moves With Nearby Elements: no; Elevation from Level: 870 mm; Offset from Host: 870 mm
Phasing - Phase Created: 2. nieuwbouw
Dimensions - dikte: 30 mm
Identity Data - Workset: Workset1
Other - Type: std; Family: NLRS_70_GM_UN_aanrechtblad; Family and Type: NLRS_70_GM_UN_aanrechtblad: std; Type Id: 1209147
Name (NLRS_70_GM_UN_aanrechtblad:std:...) | In | Level | Host | Area (m2) | breedte (mm) | diepte (mm) | Volume (m3) | aanrechtblad | wasbak | Group
1510250 | 00 begane grond | 00 begane grond | Level : 00 begane grond | 0.26 | 600 | 600 | 0.006 | no | yes | Model Group:pantry 1 kinderopvang:1223752
1510252 | 00 begane grond | 00 begane grond | Level : 00 begane grond | 0.396 | 600 | 600 | 0.0108 | yes | no | Model Group:pantry 1 kinderopvang:1223752
1511179 | 00 begane grond | 00 begane grond | Level : 00 begane grond | 0.26 | 600 | 600 | 0.006 | no | yes | Model Group:pantry 1 kinderopvang:1511177
1511181 | 00 begane grond | 00 begane grond | Level : 00 begane grond | 0.396 | 600 | 600 | 0.0108 | yes | no | Model Group:pantry 1 kinderopvang:1511177
1614345 | 00 begane grond | 00 begane grond | Level : 00 begane grond | 0.26 | 600 | 600 | 0.006 | no | yes | Model Group:pantry 1.2 MF BSO:1614348
1614347 | 00 begane grond | 00 begane grond | Level : 00 begane grond | 0.396 | 600 | 600 | 0.0108 | yes | no | Model Group:pantry 1.2 MF BSO:1614348
1672600 | 01 eerste verdieping | 01 eerste verdieping | Level : 01 eerste verdieping | 0.26 | 600 | 600 | 0.006 | no | yes | Model Group:pantry 5 personeelsruimte:1672603
1672602 | 01 eerste verdieping | 01 eerste verdieping | Level : 01 eerste verdieping | 0.396 | 600 | 600 | 0.0108 | yes | no | Model Group:pantry 5 personeelsruimte:1672603
1691999 | 01 eerste verdieping | 01 eerste verdieping | Level : 01 eerste verdieping | 0.396 | 600 | 600 | 0.0108 | yes | no | Model Group:pantry 5 personeelsruimte:1672603
1996525 | 00 begane grond | 00 begane grond | Level : 00 begane grond | 0.3545 | 600 | 750 | 0.0087 | no | yes | Model Group:70_verschoonmeubel KDV:1996810
1996645 | 00 begane grond | 00 begane grond | Level : 00 begane grond | 0.4905 | 600 | 750 | 0.0135 | yes | no | Model Group:70_verschoonmeubel KDV:1996810
1996670 | 00 begane grond | 00 begane grond | Level : 00 begane grond | 0.4905 | 600 | 750 | 0.0135 | yes | no | Model Group:70_verschoonmeubel KDV:1996810
1996683 | 00 begane grond | 00 begane grond | Level : 00 begane grond | 0.3735 | 450 | 750 | 0.010125 | yes | no | Model Group:70_verschoonmeubel KDV:1996810
1996758 | 00 begane grond | 00 begane grond | Level : 00 begane grond | 0.3735 | 450 | 750 | 0.010125 | yes | no | Model Group:70_verschoonmeubel KDV:1996810
2071172 | 00 begane grond | 00 begane grond | Level : 00 begane grond | 0.26 | 600 | 600 | 0.006 | no | yes | Model Group:pantry 4 werkruimte OB:2071170
2071174 | 00 begane grond | 00 begane grond | Level : 00 begane grond | 0.396 | 600 | 600 | 0.0108 | yes | no | Model Group:pantry 4 werkruimte OB:2071170
2860054 | 01 eerste verdieping | 01 eerste verdieping | Level : 01 eerste verdieping | 0.26 | 600 | 600 | 0.006 | no | yes | Model Group:pantry 3 BS groepsruimten:1223713
2860056 | 01 eerste verdieping | 01 eerste verdieping | Level : 01 eerste verdieping | 0.396 | 600 | 600 | 0.0108 | yes | no | Model Group:pantry 3 BS groepsruimten:1223713
2860134 | 01 eerste verdieping | 01 eerste verdieping | Level : 01 eerste verdieping | 0.396 | 600 | 600 | 0.0108 | yes | no | Model Group:pantry 5 werkruimte MB BB:2860130
2860319 | 01 eerste verdieping | 01 eerste verdieping | Level : 01 eerste verdieping | 0.396 | 600 | 600 | 0.0108 | yes | no | Model Group:pantry 5 personeelsruimte:1672603
2860363 | 01 eerste verdieping | 01 eerste verdieping | Level : 01 eerste verdieping | 0.26 | 600 | 600 | 0.006 | no | yes | Model Group:pantry 6 BSO startruimte:2860361
2860365 | 01 eerste verdieping | 01 eerste verdieping | Level : 01 eerste verdieping | 0.396 | 600 | 600 | 0.0108 | yes | no | Model Group:pantry 6 BSO startruimte:2860361
2860422 | 01 eerste verdieping | 01 eerste verdieping | Level : 01 eerste verdieping | 0.26 | 600 | 600 | 0.006 | no | yes | Model Group:pantry 3 BS groepsruimten:2860118
2860424 | 01 eerste verdieping | 01 eerste verdieping | Level : 01 eerste verdieping | 0.396 | 600 | 600 | 0.0108 | yes | no | Model Group:pantry 3 BS groepsruimten:2860118
2860458 | 01 eerste verdieping | 01 eerste verdieping | Level : 01 eerste verdieping | 0.26 | 600 | 600 | 0.006 | no | yes | Model Group:pantry 3 BS groepsruimten:2860456
2860460 | 01 eerste verdieping | 01 eerste verdieping | Level : 01 eerste verdieping | 0.396 | 600 | 600 | 0.0108 | yes | no | Model Group:pantry 3 BS groepsruimten:2860456
2860493 | 01 eerste verdieping | 01 eerste verdieping | Level : 01 eerste verdieping | 0.26 | 600 | 600 | 0.006 | no | yes | Model Group:pantry 3 BS groepsruimten:2860491
2860495 | 01 eerste verdieping | 01 eerste verdieping | Level : 01 eerste verdieping | 0.396 | 600 | 600 | 0.0108 | yes | no | Model Group:pantry 3 BS groepsruimten:2860491
2860703 | 02 tweede verdieping | 02 tweede verdieping | Level : 02 tweede verdieping | 0.26 | 600 | 600 | 0.006 | no | yes | Model Group:pantry 3 BS groepsruimten:1694326
2860705 | 02 tweede verdieping | 02 tweede verdieping | Level : 02 tweede verdieping | 0.396 | 600 | 600 | 0.0108 | yes | no | Model Group:pantry 3 BS groepsruimten:1694326
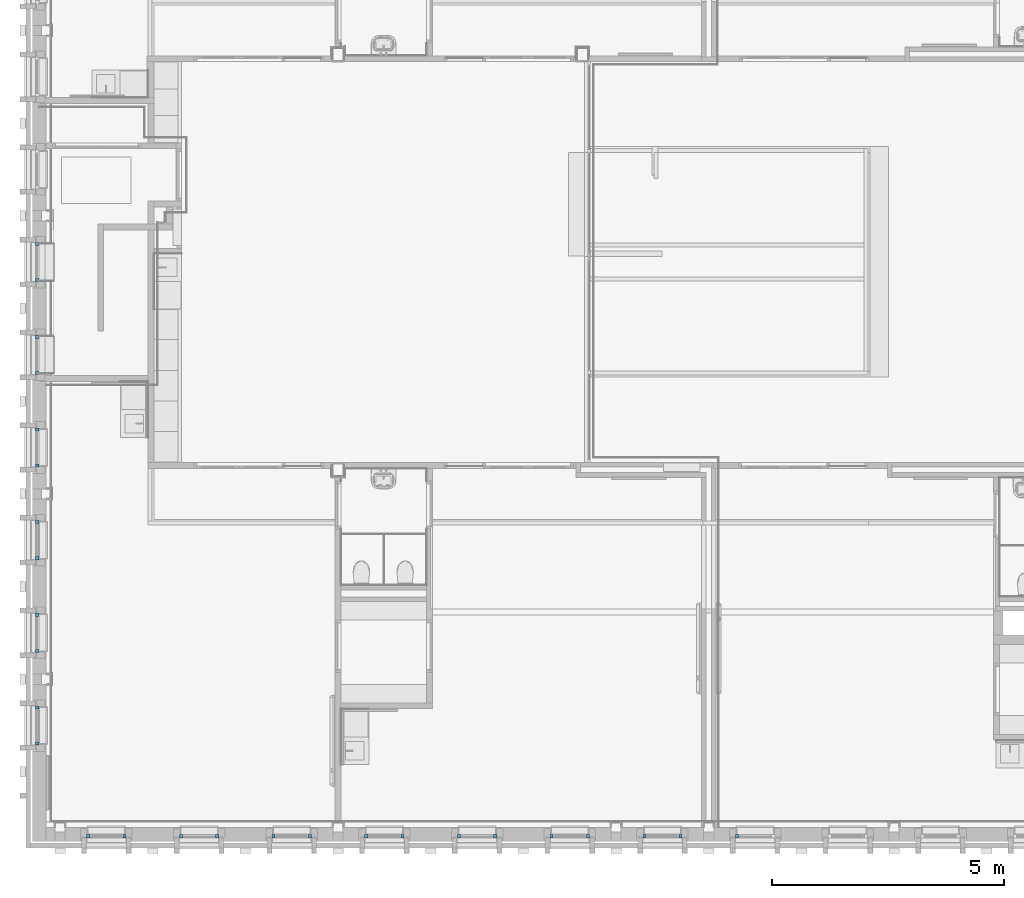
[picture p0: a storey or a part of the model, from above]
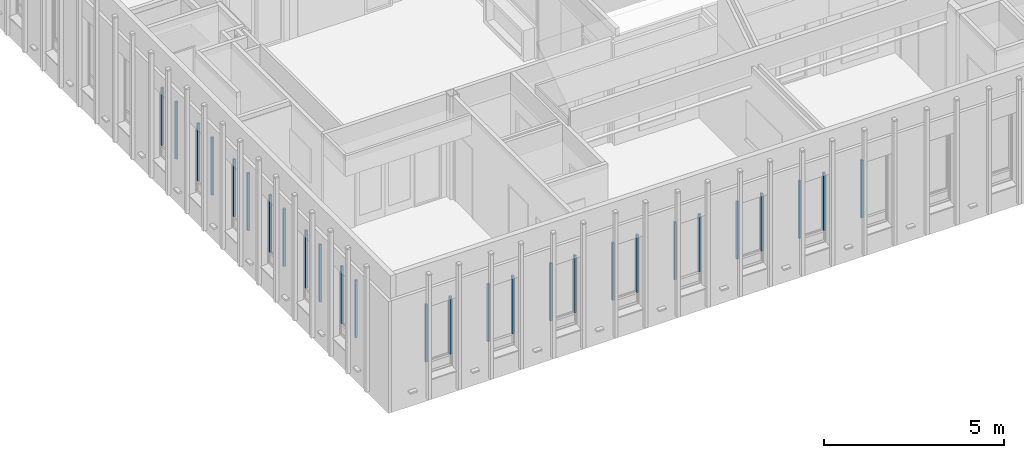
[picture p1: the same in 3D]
Properties of the parts of a building model (IFC2X3), part 6 of 94

# IfcBuildingElementProxy: NLRS_70_GM_UN_aanrechtblad:std (57)
Name (NLRS_70_GM_UN_aanrechtblad:std:...) | In | Level | Host | Area (m2) | breedte (mm) | diepte (mm) | Volume (m3) | aanrechtblad | wasbak | Group
2860762 | 02 tweede verdieping | 02 tweede verdieping | Level : 02 tweede verdieping | 0.26 | 600 | 600 | 0.006 | no | yes | Model Group:pantry 3 BS groepsruimten:2860760
2860764 | 02 tweede verdieping | 02 tweede verdieping | Level : 02 tweede verdieping | 0.396 | 600 | 600 | 0.0108 | yes | no | Model Group:pantry 3 BS groepsruimten:2860760
2860798 | 02 tweede verdieping | 02 tweede verdieping | Level : 02 tweede verdieping | 0.26 | 600 | 600 | 0.006 | no | yes | Model Group:pantry 3 BS groepsruimten:2860796
2860800 | 02 tweede verdieping | 02 tweede verdieping | Level : 02 tweede verdieping | 0.396 | 600 | 600 | 0.0108 | yes | no | Model Group:pantry 3 BS groepsruimten:2860796
3267581 | 01 eerste verdieping | 01 eerste verdieping | Level : 01 eerste verdieping | 0.26 | 600 | 600 | 0.006 | no | yes | Model Group:pantry 3 BS groepsruimten:3267579
3267583 | 01 eerste verdieping | 01 eerste verdieping | Level : 01 eerste verdieping | 0.396 | 600 | 600 | 0.0108 | yes | no | Model Group:pantry 3 BS groepsruimten:3267579
3267596 | 01 eerste verdieping | 01 eerste verdieping | Level : 01 eerste verdieping | 0.26 | 600 | 600 | 0.006 | no | yes | Model Group:pantry 3 BS groepsruimten:3267594
3267598 | 01 eerste verdieping | 01 eerste verdieping | Level : 01 eerste verdieping | 0.396 | 600 | 600 | 0.0108 | yes | no | Model Group:pantry 3 BS groepsruimten:3267594
3267610 | 02 tweede verdieping | 02 tweede verdieping | Level : 02 tweede verdieping | 0.26 | 600 | 600 | 0.006 | no | yes | Model Group:pantry 3 BS groepsruimten:3267608
3267612 | 02 tweede verdieping | 02 tweede verdieping | Level : 02 tweede verdieping | 0.396 | 600 | 600 | 0.0108 | yes | no | Model Group:pantry 3 BS groepsruimten:3267608
3267624 | 02 tweede verdieping | 02 tweede verdieping | Level : 02 tweede verdieping | 0.26 | 600 | 600 | 0.006 | no | yes | Model Group:pantry 3 BS groepsruimten:3267622
3267626 | 02 tweede verdieping | 02 tweede verdieping | Level : 02 tweede verdieping | 0.396 | 600 | 600 | 0.0108 | yes | no | Model Group:pantry 3 BS groepsruimten:3267622
3267638 | 02 tweede verdieping | 02 tweede verdieping | Level : 02 tweede verdieping | 0.26 | 600 | 600 | 0.006 | no | yes | Model Group:pantry 3 BS groepsruimten:3267636
3267640 | 02 tweede verdieping | 02 tweede verdieping | Level : 02 tweede verdieping | 0.396 | 600 | 600 | 0.0108 | yes | no | Model Group:pantry 3 BS groepsruimten:3267636
3684888 | 00 begane grond | 00 begane grond | Level : 00 begane grond | 0.396 | 600 | 600 | 0.0108 | yes | no | Model Group:pantry 1.2 MF BSO:1614348
3834208 | 01 eerste verdieping | 01 eerste verdieping | Level : 01 eerste verdieping | 0.396 | 600 | 600 | 0.0108 | yes | no | Model Group:pantry 6 BSO startruimte:2860361
4747287 | 02 tweede verdieping | 02 tweede verdieping | Level : 02 tweede verdieping | 0.396 | 600 | 600 | 0.0108 | yes | no | Model Group:pantry 5 werkruimte MB BB:4747283
4782425 | 01 eerste verdieping | 01 eerste verdieping | Level : 01 eerste verdieping | 0.26 | 600 | 600 | 0.006 | no | yes | Model Group:pantry 5 werkruimte MB BB:2860130
4782441 | 02 tweede verdieping | 02 tweede verdieping | Level : 02 tweede verdieping | 0.26 | 600 | 600 | 0.006 | no | yes | Model Group:pantry 5 werkruimte MB BB:4747283
5027848 | 00 begane grond | 00 begane grond | Level : 00 begane grond | 0.26 | 600 | 600 | 0.006 | no | yes | Model Group:pantry 3 BS groepsruimten:5027846
5027850 | 00 begane grond | 00 begane grond | Level : 00 begane grond | 0.396 | 600 | 600 | 0.0108 | yes | no | Model Group:pantry 3 BS groepsruimten:5027846
5027926 | 00 begane grond | 00 begane grond | Level : 00 begane grond | 0.26 | 600 | 600 | 0.006 | no | yes | Model Group:pantry 3 BS groepsruimten:5027924
5027928 | 00 begane grond | 00 begane grond | Level : 00 begane grond | 0.396 | 600 | 600 | 0.0108 | yes | no | Model Group:pantry 3 BS groepsruimten:5027924
5027931 | 00 begane grond | 00 begane grond | Level : 00 begane grond | 0.26 | 600 | 600 | 0.006 | no | yes | Model Group:pantry 3 BS groepsruimten:5027929
5027933 | 00 begane grond | 00 begane grond | Level : 00 begane grond | 0.396 | 600 | 600 | 0.0108 | yes | no | Model Group:pantry 3 BS groepsruimten:5027929
5027954 | 00 begane grond | 00 begane grond | Level : 00 begane grond | 0.26 | 600 | 600 | 0.006 | no | yes | Model Group:pantry 3 BS groepsruimten:5027952
5027956 | 00 begane grond | 00 begane grond | Level : 00 begane grond | 0.396 | 600 | 600 | 0.0108 | yes | no | Model Group:pantry 3 BS groepsruimten:5027952

# IfcBuildingElementProxy: NLRS_70_GM_opslagkisten trap:NLRS_70_GM_opslagkisten trap, NLRS_70_GM_opslagkisten trap:NLRS_70_GM_opslagkisten trap:3496828
In: 00 begane grond
Type - Material: ISR_Hout, <Unnamed>
Type - Constraints - Default Elevation: 0 mm
Type - Materials and Finishes - afwerking: ISR_Hout
Type - Identity Data - OmniClass Number: 23.40.20.00; OmniClass Title: General Furniture and Specialties; Type Name: NLRS_70_GM_opslagkisten trap; Workset: Family : Generic Models : NLRS_70_GM_opslagkisten trap
Type - Other - Category: Generic Models; Family Name: NLRS_70_GM_opslagkisten trap
Constraints - Elevation from Level: 0 mm; Level: 00 begane grond; Moves With Nearby Elements: no; Offset from Host: 0 mm; Host: Floor : NLRS_43_FL_cementdekvloer 60_gen_ISR
Phasing - Phase Created: 2. nieuwbouw
Dimensions - Area: 5.95884 m2; Volume: 0.112396 m3
Identity Data - Workset: Workset1
Other - Family: NLRS_70_GM_opslagkisten trap; Family and Type: NLRS_70_GM_opslagkisten trap: NLRS_70_GM_opslagkisten trap; Type: NLRS_70_GM_opslagkisten trap; Type Id: 3496787

# IfcBuildingElementProxy: NLRS_82 ME_UN_wasdroger_generiek_ISR:wasdroger_gen, NLRS_82 ME_UN_wasdroger_generiek_ISR:wasdroger_gen:2544603
In: 00 begane grond
Type - Material: <Unnamed>
Type - Mechanical - Flow - lucht_afvoer: 41.6667 m3/s
Type - Electrical - Loads - aansluit_waarde: 3000 W
Type - Text - text: yes
Type - Constraints - Default Elevation: 0 mm
Type - Dimensions - droger_breedte: 600 mm; droger_diepte: 590 mm; droger_hoogte: 850 mm; flex_diameter: 100 mm; NLRS_C_breedte: 600 mm; NLRS_C_diepte: 590 mm; NLRS_C_hoogte: 850 mm
Type - Identity Data - Assembly Code: 85.11; Assembly Description: losse schoonmaakinventaris; standaard, schoonmaakapparatuur; Description: wasdroger - luchtafvoer; Model: LOD300; SmartRevit_Versie: 2019.1; Type Comments: WD; Type Name: wasdroger_gen; Workset: Family : Mechanical Equipment : NLRS_82 ME_UN_wasdroger_generiek_ISR
Type - Other - Category: Mechanical Equipment; Family Name: NLRS_82 ME_UN_wasdroger_generiek_ISR; flex_radius: 50 mm
Classification: 85.11 Uniformat (Uniformat)
Constraints - Elevation from Level: 0 mm; Level: 00 begane grond; Offset from Host: 0 mm; Host: Level : 00 begane grond
Phasing - Phase Created: 2. nieuwbouw
Mechanical - System Classification: Exhaust Air,Power
Dimensions - Area: 1.19644 m2; Volume: 0.241119 m3
Identity Data - Workset: Workset1; Mark: 9
Other - Family: NLRS_82 ME_UN_wasdroger_generiek_ISR; Family and Type: NLRS_82 ME_UN_wasdroger_generiek_ISR: wasdroger_gen; Type: wasdroger_gen; Type Id: 1629792

# IfcBuildingElementProxy: NLRS_90_GM_UN_tafelblad vide:NLRS_90_GM_UN_tafelblad vide (2)
Type - Material: i4_multiplex
Type - Constraints - Default Elevation: 0 mm
Type - Materials and Finishes - afwerking: i4_multiplex
Type - Identity Data - Type Name: NLRS_90_GM_UN_tafelblad vide; Workset: Family : Generic Models : NLRS_90_GM_UN_tafelblad vide
Type - Other - Category: Generic Models; Family Name: NLRS_90_GM_UN_tafelblad vide
Constraints - Moves With Nearby Elements: no
Phasing - Phase Created: 2. nieuwbouw
Identity Data - Workset: Workset1
Other - Family: NLRS_90_GM_UN_tafelblad vide; Family and Type: NLRS_90_GM_UN_tafelblad vide: NLRS_90_GM_UN_tafelblad vide; Type: NLRS_90_GM_UN_tafelblad vide; Type Id: 1696780
Name (NLRS_90_GM_UN_tafelblad vide:NLRS_90_GM_UN_tafelblad vide:...) | In | Level | Area (m2) | breedte (mm) | Volume (m3) | Host Id
1696805 | 02 tweede verdieping | 02 tweede verdieping | 2.2556 | 4968 | 0.09936 | 895350
4899092 | 01 eerste verdieping | 01 eerste verdieping | 1.28 | 2800 | 0.056 | 865214

# IfcBuildingElementProxy: NLRS_90_PA_fiets_parkeerplaats:enkel_375x2000_2100_1250 (30)
In: 00 begane grond
Type - Material: 00_Luchtspouw
Type - Constraints - Default Elevation: 1219.2 mm
Type - Materials and Finishes - blok_materiaal: 00_Luchtspouw
Type - Graphics - dubbele_hoogte: no; enkele_hoogte: yes
Type - Dimensions - breedte: 375 mm; breedte_gangpad: 2100 mm; hoogte: 1250 mm; lengte: 2000 mm
Type - Identity Data - Description: fietsen; Type Name: enkel_375x2000_2100_1250; Workset: Family : Parking : NLRS_90_PA_fiets_parkeerplaats
Type - Other - Category: Parking; dubbele_hoogte_grijs: no; Family Name: NLRS_90_PA_fiets_parkeerplaats
Constraints - Level: bk. fundering; Schedule Level: bk. fundering; Offset from Host: 500 mm; Work Plane: Level : bk. fundering
Phasing - Phase Created: 2. nieuwbouw
Dimensions - Area: 3.71875 m2; Volume: 0.9375 m3
Identity Data - Workset: BDG_fietsenstalling
Other - Family: NLRS_90_PA_fiets_parkeerplaats; Family and Type: NLRS_90_PA_fiets_parkeerplaats: enkel_375x2000_2100_1250; gangpad: no; scooter_doorsnede: yes; Type: enkel_375x2000_2100_1250; Type Id: 4044294
Name (NLRS_90_PA_fiets_parkeerplaats:enkel_375x2000_2100_1250:...) | Group
4045816 | Model Group:6 fietsen:4064988
4063906 | Model Group:6 fietsen:4064988
4063959 | Model Group:6 fietsen:4064988
4063962 | Model Group:6 fietsen:4064988
4063965 | Model Group:6 fietsen:4064988
4063968 | Model Group:6 fietsen:4064988
4065020 | Model Group:6 fietsen:4065027
4065022 | Model Group:6 fietsen:4065027
4065023 | Model Group:6 fietsen:4065027
4065024 | Model Group:6 fietsen:4065027
4065025 | Model Group:6 fietsen:4065027
4065026 | Model Group:6 fietsen:4065027
4065213 | Model Group:6 fietsen:4065219
4065214 | Model Group:6 fietsen:4065219
4065215 | Model Group:6 fietsen:4065219
4065216 | Model Group:6 fietsen:4065219
4065217 | Model Group:6 fietsen:4065219
4065218 | Model Group:6 fietsen:4065219
4065229 | Model Group:6 fietsen:4065235
4065230 | Model Group:6 fietsen:4065235
4065231 | Model Group:6 fietsen:4065235
4065232 | Model Group:6 fietsen:4065235
4065233 | Model Group:6 fietsen:4065235
4065234 | Model Group:6 fietsen:4065235
4154648 | Model Group:6 fietsen:4154654
4154649 | Model Group:6 fietsen:4154654
4154650 | Model Group:6 fietsen:4154654
4154651 | Model Group:6 fietsen:4154654
4154652 | Model Group:6 fietsen:4154654
4154653 | Model Group:6 fietsen:4154654

# IfcBuildingElementProxy: Receptieloket:Receptieloket, Receptieloket:Receptieloket:1811872
In: 00 begane grond
Type - Material: ISR_Glas, <Unnamed>, i4_hout_gen
Type - Constraints(Type) - Default Elevation: 0 mm
Type - Materials and Finishes(Type) - materiaal_kastframe: i4_hout_gen
Type - Dimensions(Type) - diepte_balie: 300 mm; diepte_werkblad: 600 mm; dikte_blad: 40 mm; hoogte_balie: 1000 mm; hoogte_werkblad: 760 mm; lengte: 1600 mm
Type - Identity Data(Type) - Type Name: Receptieloket; Workset: Family : Generic Models : Receptieloket
Type - Other(Type) - Category: Generic Models; Family Name: Receptieloket
Constraints - Elevation from Level: 0 mm; Level: 00 begane grond; Moves With Nearby Elements: no; Offset from Host: 0 mm; Host: Level : 00 begane grond
Phasing - Phase Created: 2. nieuwbouw
Dimensions - Area: 4.9038 m2; Volume: 0.0827373 m3
Identity Data - Workset: Workset1; Mark: schuifloket
Other - Category: Generic Models; Family: Receptieloket; Family and Type: Receptieloket: Receptieloket; Type: Receptieloket; Type Id: 1811910

# IfcBuildingElementProxy: Smart_Board_4805:digibord (16)
Type - Material: Default, White Board Surface
Type - Constraints - Default Elevation: 0 mm
Type - Construction - Height: 1312 mm
Type - Dimensions - Width: 1973 mm
Type - Identity Data - Description: digibord; Type Name: digibord; Workset: Family : Generic Models : Smart_Board_4805
Type - Other - Category: Generic Models; Family Name: Smart_Board_4805
Phasing - Phase Created: 2. nieuwbouw
Dimensions - Area: 3.04742 m2; offset: 14.6893 mm; Volume: 0.0700128 m3
Identity Data - Workset: Workset1
Other - Family: Smart_Board_4805; Family and Type: Smart_Board_4805: digibord; Type: digibord; Type Id: 1669944
Name (Smart_Board_4805:digibord:...) | In | Level | Elevation from Level (mm) | Host Id
1670480 | 00 begane grond | 00 begane grond | 940 | 1337914
1670626 | 00 begane grond | 00 begane grond | 940 | 1832794
1670749 | 00 begane grond | 00 begane grond | 940.341 | 1218306
1670832 | 01 eerste verdieping | 01 eerste verdieping | 940 | 886608
1670969 | 01 eerste verdieping | 01 eerste verdieping | 940 | 1360041
1671135 | 01 eerste verdieping | 01 eerste verdieping | 940 | 1359936
1671173 | 01 eerste verdieping | 01 eerste verdieping | 940 | 889022
1671437 | 02 tweede verdieping | 02 tweede verdieping | 940 | 1360460
1671438 | 02 tweede verdieping | 02 tweede verdieping | 940 | 884331
1833385 | 00 begane grond | 00 begane grond | 940.341 | 1833038
1834281 | 01 eerste verdieping | 01 eerste verdieping | 940.341 | 1834253
1834509 | 01 eerste verdieping | 01 eerste verdieping | 940.341 | 1834398
1984004 | 02 tweede verdieping | 02 tweede verdieping | 940 | 1984003
1984006 | 02 tweede verdieping | 02 tweede verdieping | 940.341 | 1984005
1984126 | 02 tweede verdieping | 02 tweede verdieping | 940.341 | 1983178
1984156 | 02 tweede verdieping | 02 tweede verdieping | 940.341 | 1983179

# IfcBuildingElementProxy: afdekker:afdekker, afdekker:afdekker:5098842
In: 01 eerste verdieping
Type - Material: <Unnamed>
Type - Identity Data - Workset: Workset1; Type Name: afdekker
Type - Other - Category: Generic Models; Family Name: afdekker
Constraints - Moves With Nearby Elements: no
Phasing - Phase Created: 2. nieuwbouw
Dimensions - Area: 0.821852 m2; Volume: 0.00217881 m3
Other - Family: afdekker; Family and Type: afdekker: afdekker; Type: afdekker; Type Id: 5098840

# IfcBuildingElementProxy: dakveiligheid:dakveiligheid, dakveiligheid:dakveiligheid:2545922
In: 03 derde verdieping
Type - Material: h2_staal_gen
Type - Identity Data - Workset: Workset1; Type Name: dakveiligheid
Type - Other - Category: Generic Models; Family Name: dakveiligheid
Constraints - Elevation from Level: 0 mm; Moves With Nearby Elements: no
Phasing - Phase Created: 2. nieuwbouw
Dimensions - Area: 1.3113 m2; Volume: 0.00655632 m3
Other - Family: dakveiligheid; Family and Type: dakveiligheid: dakveiligheid; Type: dakveiligheid; Type Id: 2545920

# IfcBuildingElementProxy: dakveiligheid_gymzaal:dakveiligheid_gymzaal, dakveiligheid_gymzaal:dakveiligheid_gymzaal:2546215
In: 01 eerste verdieping
Type - Material: <Unnamed>
Type - Identity Data - Workset: Workset1; Type Name: dakveiligheid_gymzaal
Type - Other - Category: Generic Models; Family Name: dakveiligheid_gymzaal
Constraints - Elevation from Level: 0 mm; Moves With Nearby Elements: no
Phasing - Phase Created: 2. nieuwbouw
Dimensions - Area: 0.943577 m2; Volume: 0.00471775 m3
Other - Family: dakveiligheid_gymzaal; Family and Type: dakveiligheid_gymzaal: dakveiligheid_gymzaal; Type: dakveiligheid_gymzaal; Type Id: 2546213

# IfcColumn: NLRS_28_SCO_TLB_kolom ipe_gen_ISR:kolom_gen_HE120 (3)
In: 00 begane grond
Type - PredefinedType: COLUMN; Material: <Unnamed>, h2_staal_gen
Type - Structural Section Geometry - Centroid Horizontal: 60 mm; Centroid Vertical: 57 mm; Flange Thickness: 8 mm; Height: 114 mm; Web Fillet: 9 mm; Web Thickness: 5.3 mm; Width: 120 mm
Type - Structural Analysis - Warping Constant: 0; Elastic Modulus strong axis: 0.000146 m3; Elastic Modulus weak axis: 0.0000222 m3; Moment of Inertia strong axis: 0.0000132 m4; Moment of Inertia weak axis: 0.00000101 m4; Nominal Weight: 18.7999; Perimeter: 698 mm; Plastic Modulus strong axis: 0.000166 m3; Plastic Modulus weak axis: 0.0000346 m3; Section Area: 0.00239 m2; Torsional Moment of Inertia: 0 m4
Type - Structural - SG: 0; Section Shape: 6
Type - Dimensions - kr: 9 mm; NLRS_C_breedte: 120 mm; NLRS_C_hoogte: 114 mm; tf: 8 mm; tw: 5.3 mm
Type - Identity Data - Workset: Family : Structural Columns : NLRS_28_SCO_TLB_kolom ipe_gen_ISR; Assembly Code: 28.10; Assembly Description: hoofddraagconstructies; kolommen en liggers, algemeen (verzamelniveau); Code Name: EURONORM 19-57; DIN 1025; Datum_Gewijzigd: 12-11-2020; Description: IPE180; Section Name Key: IPE180; SmartRevit_Versie: 2021.1; Type Name: kolom_gen_HE120
Type - Other - Category: Structural Columns; Family Name: NLRS_28_SCO_TLB_kolom ipe_gen_ISR
Classification: 28.10 Uniformat (Uniformat); Material: h2_staal_gen
Constraints - Level: 00 begane grond; Column Style: Vertical; Moves With Grids: yes; Top Level: 01 eerste verdieping; Base Level: 00 begane grond; Base Offset: -300 mm; Top Offset: 3000 mm
Phasing - Phase Created: 2. nieuwbouw
Structural - Enable Analytical Model: yes
Dimensions - Length: 7300 mm; NLRS_C_lengte: 7300 mm; Volume: 0.0183165 m3
Identity Data - Workset: Workset1
Other - Family: NLRS_28_SCO_TLB_kolom ipe_gen_ISR; Family and Type: NLRS_28_SCO_TLB_kolom ipe_gen_ISR: kolom_gen_HE120; Type: kolom_gen_HE120; Type Id: 4015751
Name (NLRS_28_SCO_TLB_kolom ipe_gen_ISR:kolom_gen_HE120:...) | Column Location Mark
5095981 | H-8(2642)
5096151 | G(1098)-8(2642)
5096271 | F(448)-8(2642)

# IfcColumn: NLRS_28_SCO_TLB_kolom ipe_gen_ISR:kolom_gen_IPE180 (6)
In: 00 begane grond
Type - PredefinedType: COLUMN; Material: h2_staal
Type - Structural Section Geometry - Centroid Horizontal: 45.5 mm; Centroid Vertical: 90 mm; Flange Thickness: 8 mm; Height: 180 mm; Web Fillet: 9 mm; Web Thickness: 5.3 mm; Width: 91 mm
Type - Structural Analysis - Elastic Modulus strong axis: 0.000146 m3; Elastic Modulus weak axis: 0.0000222 m3; Moment of Inertia strong axis: 0.0000132 m4; Moment of Inertia weak axis: 0.00000101 m4; Nominal Weight: 18.7999; Perimeter: 698 mm; Plastic Modulus strong axis: 0.000166 m3; Plastic Modulus weak axis: 0.0000346 m3; Section Area: 0.00239 m2; Torsional Moment of Inertia: 0 m4; Warping Constant: 0
Type - Structural - SG: 0; Section Shape: 6
Type - Dimensions - kr: 9 mm; NLRS_C_breedte: 91 mm; NLRS_C_hoogte: 180 mm; tf: 8 mm; tw: 5.3 mm
Type - Identity Data - Assembly Code: 28.10; Assembly Description: hoofddraagconstructies; kolommen en liggers, algemeen (verzamelniveau); Code Name: EURONORM 19-57; DIN 1025; Datum_Gewijzigd: 12-11-2020; Description: IPE180; Section Name Key: IPE180; SmartRevit_Versie: 2021.1; Type Name: kolom_gen_IPE180; Workset: Family : Structural Columns : NLRS_28_SCO_TLB_kolom ipe_gen_ISR
Type - Other - Category: Structural Columns; Family Name: NLRS_28_SCO_TLB_kolom ipe_gen_ISR
Classification: 28.10 Uniformat (Uniformat)
Constraints - Base Offset: 0 mm; Column Style: Vertical; Moves With Grids: yes; Level: bk. fundering; Base Level: bk. fundering; Top Level: 00 begane grond; Top Offset: 3280 mm
Phasing - Phase Created: 2. nieuwbouw
Structural - Enable Analytical Model: yes
Materials and Finishes - Structural Material: h2_staal
Dimensions - Length: 3800 mm; NLRS_C_lengte: 3800 mm; Volume: 0.00910062 m3
Identity Data - Workset: Workset1
Other - Family: NLRS_28_SCO_TLB_kolom ipe_gen_ISR; Family and Type: NLRS_28_SCO_TLB_kolom ipe_gen_ISR: kolom_gen_IPE180; Type: kolom_gen_IPE180; Type Id: 3267651
Name (NLRS_28_SCO_TLB_kolom ipe_gen_ISR:kolom_gen_IPE180:...) | Column Location Mark
3268135 | F(500)-8(3215)
3268141 | G(-1017)-8(3215)
3268159 | H-9(-500)
3268165 | H-9(-1497)
3268171 | H-9(-2500)
4196771 | H(-572)-8(3215)

# IfcColumn: NLRS_28_SCO_TLB_kolom koker_gen_ISR1:kolom_gen_K60x60x4 (25)
In: 00 begane grond
Type - PredefinedType: COLUMN; Material: h2_staal_gen
Type - Structural Section Geometry - Centroid Horizontal: 30 mm; Centroid Vertical: 30 mm; Height: 60 mm; Inner Fillet: 3 mm; Outer Fillet: 6 mm; Wall Nominal Thickness: 3 mm; Width: 60 mm
Type - Text - Shape: rechthoek
Type - Structural - A: 0.001815 m2; Section Shape: 14; SG: 7850
Type - Dimensions - b: 60 mm; h: 60 mm; r: 6 mm; r_inw: 3 mm; t: 3 mm; Wall Design Thickness: 3 mm
Type - Identity Data - Assembly Code: 28.11; Assembly Description: hoofddraagconstructies; kolommen en liggers, kolom-/liggerconstructies; Description: K200X100X12.5; Model: LOD300; SmartRevit_Versie: 2019.1.2; Type Name: kolom_gen_K60x60x4; Workset: Family : Structural Columns : NLRS_28_SCO_TLB_kolom koker_gen_ISR1
Type - Other - Category: Structural Columns; Family Name: NLRS_28_SCO_TLB_kolom koker_gen_ISR1
Classification: 28.11 Uniformat (Uniformat)
Constraints - Level: 00 begane grond; Base Offset: 0 mm; Column Style: Vertical; Moves With Grids: yes; Top Level: 00 begane grond; Base Level: 00 begane grond; Top Offset: 2200 mm
Phasing - Phase Created: 2. nieuwbouw
Structural - Enable Analytical Model: yes
Materials and Finishes - Structural Material: h2_staal_gen; soortelijke_massa: 7850
Dimensions - Length: 2200 mm; NLRS_C_hoogte: 60 mm; Volume: 0.0014538 m3
Identity Data - Workset: BDG_fietsenstalling
Other - Family: NLRS_28_SCO_TLB_kolom koker_gen_ISR1; Family and Type: NLRS_28_SCO_TLB_kolom koker_gen_ISR1: kolom_gen_K60x60x4; Type: kolom_gen_K60x60x4; Type Id: 4096312
Name (NLRS_28_SCO_TLB_kolom koker_gen_ISR1:kolom_gen_K60x60x4:...) | Column Location Mark | Group
4096498 | A(-14663)-7(-529) | Model Group:fietsenstalling_dubbele deur:4153902
4154028 | A(-14663)-7(1971) | Model Group:fietsenstalling_dubbele deur:4154050
4154098 | A(-14663)-8(-1979) | Model Group:fietsenstalling_dubbele deur:4154120
4154166 | A(-14663)-8(521) | Model Group:fietsenstalling_dubbele deur:4154188
4154236 | A(-14663)-8(3021) | Model Group:fietsenstalling_dubbele deur:4154258
4158213 | A(-14663)-8(1938) | Model Group:enkele deur-kokers:4158221
4158223 | A(-14663)-8(2956) | Model Group:enkele deur-kokers:4158221
4158248 | A(-14663)-9(-2395) | Model Group:enkele deur-kokers:4158256
4158258 | A(-14663)-8(3086) | Model Group:enkele deur-kokers:4158256
4158437 | A(-14663)-7(-1612) | Model Group:enkele deur-kokers:4158445
4158447 | A(-14663)-7(-594) | Model Group:enkele deur-kokers:4158445
4158449 | A(-14663)-7(555) | Model Group:enkele deur-kokers:4158457
4158459 | A(-14663)-7(-464) | Model Group:enkele deur-kokers:4158457
4158489 | A(-14663)-7(888) | Model Group:enkele deur-kokers:4158497
4158499 | A(-14663)-7(1906) | Model Group:enkele deur-kokers:4158497
4158501 | A(-14663)-7(3055) | Model Group:enkele deur-kokers:4158509
4158511 | A(-14663)-7(2036) | Model Group:enkele deur-kokers:4158509
4158515 | A(-14663)-8(-3062) | Model Group:enkele deur-kokers:4158523
4158525 | A(-14663)-8(-2044) | Model Group:enkele deur-kokers:4158523
4158527 | A(-14663)-8(-895) | Model Group:enkele deur-kokers:4158535
4158537 | A(-14663)-8(-1914) | Model Group:enkele deur-kokers:4158535
4158541 | A(-14663)-8(-562) | Model Group:enkele deur-kokers:4158549
4158551 | A(-14663)-8(456) | Model Group:enkele deur-kokers:4158549
4158553 | A(-14663)-8(1605) | Model Group:enkele deur-kokers:4158561
4158563 | A(-14663)-8(586) | Model Group:enkele deur-kokers:4158561

# IfcColumn: NLRS_28_SCO_TLB_kolom koker_gen_ISR:kolom gen k140x50x5, NLRS_28_SCO_TLB_kolom koker_gen_ISR:kolom gen k140x50x5:2880290
In: 01 eerste verdieping
Type - PredefinedType: COLUMN; Material: h2_staal_gen
Type - Structural Section Geometry - Centroid Horizontal: 25 mm; Centroid Vertical: 70 mm; Height: 140 mm; Inner Fillet: 5 mm; Outer Fillet: 10 mm; Wall Nominal Thickness: 5 mm; Width: 50 mm
Type - Text - Shape: rechthoek
Type - Structural - SG: 0; Section Shape: 14
Type - Dimensions - NLRS_C_breedte: 50 mm; NLRS_C_hoogte: 140 mm; r: 10 mm; r_inw: 5 mm; RSen_C_thickness: 5 mm; Wall Design Thickness: 5 mm
Type - Identity Data - Workset: Family : Structural Columns : NLRS_28_SCO_TLB_kolom koker_gen_ISR; Assembly Code: 28.10; Assembly Description: hoofddraagconstructies; kolommen en liggers, algemeen (verzamelniveau); Description: K200x100x5; Model: LOD300; SmartRevit_Versie: 2021.1; Type Name: kolom gen k140x50x5
Type - Other - Category: Structural Columns; Family Name: NLRS_28_SCO_TLB_kolom koker_gen_ISR; h: 140 mm
Classification: 28.10 Uniformat (Uniformat)
Constraints - Level: 01 eerste verdieping; Base Offset: 0 mm; Base Level: 01 eerste verdieping; Column Style: Vertical; Moves With Grids: yes; Top Level: 01 eerste verdieping; Column Location Mark: F(225)-6(600); Top Offset: 2850 mm
Phasing - Phase Created: 2. nieuwbouw
Structural - Enable Analytical Model: yes
Dimensions - Length: 2850 mm; Volume: 0.00494648 m3
Identity Data - Workset: Workset1
Other - Family: NLRS_28_SCO_TLB_kolom koker_gen_ISR; Family and Type: NLRS_28_SCO_TLB_kolom koker_gen_ISR: kolom gen k140x50x5; Type: kolom gen k140x50x5; Type Id: 3200588

# IfcColumn: NLRS_28_SCO_TLB_kolom koker_gen_ISR:kolom gen k200x100x5 (8)
In: 01 eerste verdieping
Type - PredefinedType: COLUMN; Material: h2_staal_gen
Type - Structural Section Geometry - Centroid Horizontal: 50 mm; Centroid Vertical: 100 mm; Height: 200 mm; Inner Fillet: 5 mm; Outer Fillet: 10 mm; Wall Nominal Thickness: 5 mm; Width: 100 mm
Type - Text - Shape: rechthoek
Type - Structural - Section Shape: 14; SG: 0
Type - Dimensions - NLRS_C_breedte: 100 mm; NLRS_C_hoogte: 200 mm; r: 10 mm; r_inw: 5 mm; RSen_C_thickness: 5 mm; Wall Design Thickness: 5 mm
Type - Identity Data - Assembly Code: 28.10; Assembly Description: hoofddraagconstructies; kolommen en liggers, algemeen (verzamelniveau); Description: K200x100x5; Model: LOD300; SmartRevit_Versie: 2021.1; Type Name: kolom gen k200x100x5; Workset: Family : Structural Columns : NLRS_28_SCO_TLB_kolom koker_gen_ISR
Type - Other - Category: Structural Columns; Family Name: NLRS_28_SCO_TLB_kolom koker_gen_ISR; h: 200 mm
Classification: 28.10 Uniformat (Uniformat)
Constraints - Level: 01 eerste verdieping; Base Offset: 0 mm; Base Level: 01 eerste verdieping; Column Style: Vertical; Moves With Grids: yes; Top Level: 01 eerste verdieping; Top Offset: 2850 mm
Phasing - Phase Created: 2. nieuwbouw
Structural - Enable Analytical Model: yes
Dimensions - Length: 2850 mm; Volume: 0.00808147 m3
Identity Data - Workset: Workset1
Other - Family: NLRS_28_SCO_TLB_kolom koker_gen_ISR; Family and Type: NLRS_28_SCO_TLB_kolom koker_gen_ISR: kolom gen k200x100x5; Type: kolom gen k200x100x5; Type Id: 1355359
Name (NLRS_28_SCO_TLB_kolom koker_gen_ISR:kolom gen k200x100x5:...) | Column Location Mark
2548363 | F(245)-7(750)
2548365 | F(245)-7(-1250)
2548367 | F(245)-7(2750)
2548369 | F(245)-8(-1700)
2548371 | F(245)-8(300)
2548373 | F(245)-8(2300)
2548375 | F(245)-6(3200)
2548377 | F(245)-6(1200)

# IfcColumn: NLRS_28_SCO_TLB_kolom unp_gen_ISR:kolom_gen_UNP180 (2)
In: 00 begane grond
Type - PredefinedType: COLUMN; Material: h2_staal
Type - Structural Section Geometry - Sloped Flange Angle: 0 deg; Centroid Horizontal: 19.2 mm; Centroid Vertical: 90 mm; Flange Fillet: 5.5 mm; Flange Thickness: 11 mm; Flange Thickness Location: 35 mm; Height: 180 mm; Web Fillet: 11 mm; Web Thickness: 8 mm; Width: 70 mm
Type - Structural Analysis - Warping Constant: 0; Elastic Modulus strong axis: 0.00015 m3; Elastic Modulus weak axis: 0.0000224 m3; Moment of Inertia strong axis: 0.0000135 m4; Moment of Inertia weak axis: 0.00000114 m4; Nominal Weight: 21.9999; Perimeter: 611 mm; Plastic Modulus strong axis: 0 m3; Plastic Modulus weak axis: 0 m3; Section Area: 0.0028 m2; Torsional Moment of Inertia: 0 m4
Type - Structural - SG: 0; Section Shape: 10
Type - Dimensions - kr: 11 mm; NLRS_C_breedte: 70 mm; NLRS_C_hoogte: 180 mm; tf: 11 mm; tw: 8 mm
Type - Identity Data - Assembly Code: 28.10; Assembly Description: hoofddraagconstructies; kolommen en liggers, algemeen (verzamelniveau); Code Name: DIN1026-1:2009; NF A 45-202; Datum_Gewijzigd: 12-11-2020; Description: UNP180; Section Name Key: UPN 180; SmartRevit_Versie: 2021.1; Type Name: kolom_gen_UNP180; Workset: Family : Structural Columns : NLRS_28_SCO_TLB_kolom unp_gen_ISR
Type - Other - Category: Structural Columns; Angle: 4.58 deg; Family Name: NLRS_28_SCO_TLB_kolom unp_gen_ISR
Classification: 28.10 Uniformat (Uniformat)
Constraints - Base Offset: 0 mm; Column Style: Vertical; Moves With Grids: yes; Level: bk. fundering; Base Level: bk. fundering; Top Level: 00 begane grond; Top Offset: 3280 mm
Phasing - Phase Created: 2. nieuwbouw
Structural - Enable Analytical Model: yes
Materials and Finishes - Structural Material: h2_staal
Dimensions - Length: 3800 mm; NLRS_C_lengte: 3800 mm; Volume: 0.0107777 m3
Identity Data - Workset: Workset1
Other - Family: NLRS_28_SCO_TLB_kolom unp_gen_ISR; Family and Type: NLRS_28_SCO_TLB_kolom unp_gen_ISR: kolom_gen_UNP180; Type: kolom_gen_UNP180; Type Id: 4198274
Name (NLRS_28_SCO_TLB_kolom unp_gen_ISR:kolom_gen_UNP180:...) | Column Location Mark
4198229 | G(1179)-8(3215)
4198377 | G(1017)-8(3215)

# IfcColumn: NLRS_28_SC_TLB_kolom HEA_generiek_ISR:kolom_gen_HEA140 (12)
In: 00 begane grond
Type - PredefinedType: COLUMN; Material: h2_staal_gen
Type - Structural Section Geometry - Centroid Horizontal: 70 mm; Centroid Vertical: 66.5 mm; Flange Thickness: 8.5 mm; Height: 133 mm; Web Fillet: 12 mm; Web Thickness: 5.5 mm; Width: 140 mm
Type - Structural Analysis - Warping Constant: 0; Elastic Modulus strong axis: 0.0000728 m3; Elastic Modulus weak axis: 0.0000268 m3; Moment of Inertia strong axis: 0.00000349 m4; Moment of Inertia weak axis: 0.00000134 m4; Nominal Weight: 16.6999; Perimeter: 561 mm; Plastic Modulus strong axis: 0.00008301 m3; Plastic Modulus weak axis: 0.00004114 m3; Section Area: 0.00212 m2; Torsional Moment of Inertia: 0 m4
Type - Structural - Section Shape: 8
Type - Dimensions - kr: 12 mm; NLRS_C_breedte: 140 mm; NLRS_C_hoogte: 133 mm; tf: 8.5 mm; tw: 5.5 mm
Type - Identity Data - Assembly Code: 28.11; Assembly Description: hoofddraagconstructies; kolommen en liggers, kolom-/liggerconstructies; Code Name: EURONORM 53-62; DIN 1025-3; Description: HEA100; Section Name Key: HEA100; SmartRevit_Versie: 2019.1.2; Type Name: kolom_gen_HEA140; Workset: Family : Structural Columns : NLRS_28_SC_TLB_kolom HEA_generiek_ISR
Type - Other - Category: Structural Columns; Family Name: NLRS_28_SC_TLB_kolom HEA_generiek_ISR
Classification: 28.11 Uniformat (Uniformat); Group: Model Group:fietsenstalling:4188142
Constraints - Level: 00 begane grond; Base Offset: 0 mm; Column Style: Vertical; Moves With Grids: yes; Top Level: 00 begane grond; Base Level: 00 begane grond
Phasing - Phase Created: 2. nieuwbouw
Structural - Enable Analytical Model: yes
Materials and Finishes - soortelijke_massa: 7850; Structural Material: h2_staal_gen
Identity Data - Workset: BDG_fietsenstalling
Other - Family: NLRS_28_SC_TLB_kolom HEA_generiek_ISR; Family and Type: NLRS_28_SC_TLB_kolom HEA_generiek_ISR: kolom_gen_HEA140; Type: kolom_gen_HEA140; Type Id: 4080493
Name (NLRS_28_SC_TLB_kolom HEA_generiek_ISR:kolom_gen_HEA140:...) | Column Location Mark | Top Offset (mm) = Length (mm) = NLRS_C_lengte (mm) | Volume (m3)
4021813 | A(-17143)-7(-1779) | 2000 | 0.00628386
4022413 | A(-14703)-7(-1779) | 2200 | 0.00691224
4022427 | A(-17143)-9(-2229) | 2000 | 0.00628386
4022441 | A(-14703)-9(-2229) | 2200 | 0.00691224
4022480 | A(-17143)-8(1771) | 2000 | 0.00628386
4022482 | A(-14703)-8(1771) | 2200 | 0.00691224
4022519 | A(-17143)-8(-729) | 2000 | 0.00628386
4022521 | A(-14703)-8(-729) | 2200 | 0.00691224
4022537 | A(-17143)-7(3221) | 2000 | 0.00628386
4022539 | A(-14703)-7(3221) | 2200 | 0.00691224
4022557 | A(-17143)-7(721) | 2000 | 0.00628386
4022559 | A(-14703)-7(721) | 2200 | 0.00691224

# IfcColumn: Rectangular Mullion:CWM_Closing jamb Select 100 K/U_Multiwal, Rectangular Mullion:CWM_Closing jamb Select 100 K/U_Multiwal:1322232
In: 00 begane grond
Type - Description: SL Closing Jamb; PredefinedType: COLUMN; Material: Aluminium
Type - Data - BIMObjectName: Pr_20_76_51_02-Multiwal-SL Closing Jamb-LOD400; ClassificationName: Uniclass2015; ClassificationValue: Pr_20_76_51_02; COBie.Type.AccessibilityPerformance: N/A; COBie.Type.AssetType: Fixed; COBie.Type.Category: 23.25.20.14.11.11 - Curtain Wall Components; COBie.Type.CodePerformance: N/A; COBie.Type.Color: Aluminium - grey; COBie.Type.Constituents: N/A; COBie.Type.CreatedBy: Itannex bv; COBie.Type.CreatedOn: 2018.11.20; COBie.Type.Description: SL Closing Jamb; COBie.Type.DurationUnit: N/A; COBie.Type.ExpectedLife: N/A; COBie.Type.Features: N/A; COBie.Type.Finish: Aluminium; COBie.Type.Grade: 3; COBie.Type.Length: 60 mm; COBie.Type.Manufacturer: Multiwal; COBie.Type.Material: Aluminium; COBie.Type.ModelNumber: N/A; COBie.Type.ModelReference: SL Closing Jamb; COBie.Type.Name: Sluitlijst SL 100x60mm; COBie.Type.NominalHeight: 12000 mm; COBie.Type.NominalLength: 60 mm; COBie.Type.NominalWidth: 105 mm; COBie.Type.Shape: Rectangular; COBie.Type.Size: 100x60mm; COBie.Type.SustainabilityPerformance: N/A; COBie.Type.WarrantyDescription: N/A; COBie.Type.WarrantyDurationLabor: N/A; COBie.Type.WarrantyDurationParts: N/A; COBie.Type.WarrantyDurationUnit: N/A; COBie.Type.WarrantyGuarantorLabor: N/A; COBie.Type.WarrantyGuarantorParts: N/A
Type - General - RSen_C_content_creator: Itannex bv
Type - Constraints - Angle: 0 deg; Offset: 0 mm
Type - Materials and Finishes - Material: Aluminium
Type - Construction - Corner Mullion: no; Position: Perpendicular to Face; Profile: PR_Closing jamb_Multiwal : Select 100 K/U; Thickness: 105 mm
Type - Dimensions - Width on side 1: -20 mm; Width on side 2: 60 mm
Type - Identity Data - Workset: Family : Curtain Wall Mullions : Rectangular Mullion; Assembly Code: 22.14; Assembly Description: binnenwanden; niet constructief, systeemwanden; verplaatsbaar; Description: SL Closing Jamb; Manufacturer: Multiwal; Manufacturers Address: Norman Road, Rochdale, OL11 4HS, United Kingdom; Manufacturers Email: info@multiwal.co.uk; Manufacturers Telephone Number: +441273497370; Model: SL Closing Jamb; NLRS_C_content_datum_gewijzigd: 2018.11.20; NLRS_C_content_provider: Multiwal; NLRS_C_content_versie: 1.0; RSen_C_product_description: Closing jamb SL 100x60mm; Type Comments: for normal element NE; Type Name: CWM_Closing jamb Select 100 K/U_Multiwal; URL: https://uk.multiwal.eu/products/moveable-walls/moveable-wall-select/select-100-u/
Type - Other - Category: Curtain Wall Mullions; Family Name: Rectangular Mullion
Classification: 22.14 Uniformat (Uniformat); Group: Model Group:BI-11 8834x2800:2521973
Constraints - Level: 00 begane grond
Phasing - Phase Created: 2. nieuwbouw
Dimensions - Area: 0.511203 m2; Length: 2800 mm; Volume: 0.015344 m3
Identity Data - Workset: Workset1
Other - Family: Rectangular Mullion; Host Id: 1322223; Family and Type: Rectangular Mullion: CWM_Closing jamb Select 100 K/U_Multiwal; Type: CWM_Closing jamb Select 100 K/U_Multiwal; Type Id: 1316254

# IfcColumn: Rectangular Mullion:CWM_Wall jamb Select 100 K/U - 85mm_Multiwal, Rectangular Mullion:CWM_Wall jamb Select 100 K/U - 85mm_Multiwal:1322231
In: 00 begane grond
Type - Description: WAL Wall Jamb; PredefinedType: COLUMN; Material: Aluminium
Type - Data - BIMObjectName: Pr_20_76_51_02-Multiwal-WAL Wall Jamb-LOD400; ClassificationName: Uniclass2015; ClassificationValue: Pr_20_76_51_02; COBie.Type.AccessibilityPerformance: N/A; COBie.Type.AssetType: Fixed; COBie.Type.Category: 23.25.20.14.11.11 - Curtain Wall Components; COBie.Type.CodePerformance: N/A; COBie.Type.Color: Aluminium - grey; COBie.Type.Constituents: N/A; COBie.Type.CreatedBy: Itannex bv; COBie.Type.CreatedOn: 2018.11.20; COBie.Type.Description: WAL Wall Jamb; COBie.Type.DurationUnit: N/A; COBie.Type.ExpectedLife: N/A; COBie.Type.Features: N/A; COBie.Type.Finish: Aluminium; COBie.Type.Grade: 3; COBie.Type.Length: 85 mm; COBie.Type.Manufacturer: Multiwal; COBie.Type.Material: Aluminium; COBie.Type.ModelNumber: N/A; COBie.Type.ModelReference: WAL Wall Jamb; COBie.Type.Name: Wandlijst WAL 100x85mm; COBie.Type.NominalHeight: 12000 mm; COBie.Type.NominalLength: 85 mm; COBie.Type.NominalWidth: 105 mm; COBie.Type.Shape: Rectangular; COBie.Type.Size: 105x85mm; COBie.Type.SustainabilityPerformance: N/A; COBie.Type.WarrantyDescription: N/A; COBie.Type.WarrantyDurationLabor: N/A; COBie.Type.WarrantyDurationParts: N/A; COBie.Type.WarrantyDurationUnit: N/A; COBie.Type.WarrantyGuarantorLabor: N/A; COBie.Type.WarrantyGuarantorParts: N/A
Type - General - RSen_C_content_creator: Itannex bv
Type - Constraints - Angle: 0 deg; Offset: 0 mm
Type - Materials and Finishes - Material: Aluminium
Type - Construction - Corner Mullion: no; Position: Perpendicular to Face; Profile: PR_Wall jamb_Multiwal : Select 100 K/U - 85mm; Thickness: 105 mm
Type - Dimensions - Width on side 1: 85 mm; Width on side 2: -20 mm
Type - Identity Data - Workset: Family : Curtain Wall Mullions : Rectangular Mullion; Assembly Code: 22.14; Assembly Description: binnenwanden; niet constructief, systeemwanden; verplaatsbaar; Description: WAL Wall Jamb; Manufacturer: Multiwal; Manufacturers Address: Norman Road, Rochdale, OL11 4HS, United Kingdom; Manufacturers Email: info@multiwal.co.uk; Manufacturers Telephone Number: +441273497370; Model: WAL Wall Jamb; NLRS_C_content_datum_gewijzigd: 2018.11.20; NLRS_C_content_provider: Multiwal; NLRS_C_content_versie: 1.0; RSen_C_product_description: Wall jamb WAL 100x85mm; Type Comments: for telescopic element TE; Type Name: CWM_Wall jamb Select 100 K/U - 85mm_Multiwal; URL: https://uk.multiwal.eu/products/moveable-walls/moveable-wall-select/select-100-u/
Type - Other - Category: Curtain Wall Mullions; Family Name: Rectangular Mullion
Classification: 22.14 Uniformat (Uniformat); Group: Model Group:BI-11 8834x2800:2521973
Constraints - Level: 00 begane grond
Phasing - Phase Created: 2. nieuwbouw
Dimensions - Area: 0.583828 m2; Length: 2800 mm; Volume: 0.022694 m3
Identity Data - Workset: Workset1
Other - Family: Rectangular Mullion; Family and Type: Rectangular Mullion: CWM_Wall jamb Select 100 K/U - 85mm_Multiwal; Host Id: 1322223; Type: CWM_Wall jamb Select 100 K/U - 85mm_Multiwal; Type Id: 1316256

# IfcCovering: Compound Ceiling:NLRS_45_CE_P01 systeemplafond 600x1200 (10)
Type - PredefinedType: CEILING
Type - Analytical Properties - Roughness: 1; Absorptance: 0.1; Heat Transfer Coefficient (U): 1.14 kg/K/s3; Thermal Mass: 19.43; Thermal Resistance (R): 0.877193
Type - Graphics - Coarse Scale Fill Pattern: <Solid fill>; Coarse Scale Fill Color: 0
Type - Construction - Thickness: 50 mm
Type - Identity Data - Workset: Ceiling Types; Assembly Code: 45; Assembly Description: plafondafwerkingen; Description: systeemplafond balvast; SmartRevit_Versie: 2018.2; Type Name: NLRS_45_CE_P01 systeemplafond 600x1200
Type - Other - Category: Ceilings; Family Name: Compound Ceiling
Classification: 45 Uniformat (Uniformat); Material: m1_plafondplaten_600x1200 50 mm
Constraints - Room Bounding: yes; Height Offset From Level: 2800 mm
Phasing - Phase Created: 2. nieuwbouw
Identity Data - Workset: Workset1
Other - Family: Compound Ceiling; Family and Type: Compound Ceiling: NLRS_45_CE_P01 systeemplafond 600x1200; Type: NLRS_45_CE_P01 systeemplafond 600x1200; Type Id: 4986006
Name (Compound Ceiling:NLRS_45_CE_P01 systeemplafond 600x1200:...) | In | Level | Area (m2) | Perimeter (mm) | Volume (m3)
895453 | 01 eerste verdieping | 01 eerste verdieping | 2.70902 | 7260.04 | 0.135451
895671 | 01 eerste verdieping | 01 eerste verdieping | 2.7825 | 7400 | 0.139125
895776 | 02 tweede verdieping | 02 tweede verdieping | 1.87 | 6100 | 0.0935
895848 | 02 tweede verdieping | 02 tweede verdieping | 2.93733 | 7437 | 0.146867
895856 | 02 tweede verdieping | 02 tweede verdieping | 2.20186 | 6145 | 0.110093
895864 | 02 tweede verdieping | 02 tweede verdieping | 2.56989 | 6627 | 0.128494
895970 | 02 tweede verdieping | 02 tweede verdieping | 3.09156 | 7570 | 0.154578
895978 | 02 tweede verdieping | 02 tweede verdieping | 2.28214 | 6228.04 | 0.114107
1281998 | 01 eerste verdieping | 01 eerste verdieping | 3.096 | 7560 | 0.1548
2796306 | 01 eerste verdieping | 01 eerste verdieping | 1.88125 | 6095 | 0.0940625

# IfcCovering: Compound Ceiling:NLRS_45_CE_P01 systeemplafond 600x600 (55)
Type - PredefinedType: CEILING
Type - Analytical Properties - Roughness: 1; Absorptance: 0.1; Heat Transfer Coefficient (U): 1.14 kg/K/s3; Thermal Mass: 19.43; Thermal Resistance (R): 0.877193
Type - Graphics - Coarse Scale Fill Pattern: <Solid fill>; Coarse Scale Fill Color: 0
Type - Construction - Thickness: 100 mm
Type - Identity Data - Workset: Ceiling Types; Assembly Code: 45; Assembly Description: plafondafwerkingen; Description: systeemplafond; SmartRevit_Versie: 2018.2; Type Name: NLRS_45_CE_P01 systeemplafond 600x600
Type - Other - Category: Ceilings; Family Name: Compound Ceiling
Classification: 45 Uniformat (Uniformat); Material: ISR_Clashobject 50 mm, m1_plafondplaten_600x600 50 mm
Constraints - Room Bounding: yes
Phasing - Phase Created: 2. nieuwbouw
Identity Data - Workset: Workset1
Other - Family: Compound Ceiling; Family and Type: Compound Ceiling: NLRS_45_CE_P01 systeemplafond 600x600; Type: NLRS_45_CE_P01 systeemplafond 600x600; Type Id: 1303725
Name (Compound Ceiling:NLRS_45_CE_P01 systeemplafond 600x600:...) | In | Level | Height Offset From Level (mm) | Area (m2) | Perimeter (mm) | Volume (m3)
895412 | 01 eerste verdieping | 01 eerste verdieping | 2800 | 4.74683 | 8850.01 | 0.474683
895419 | 01 eerste verdieping | 01 eerste verdieping | 2800 | 4.04226 | 8070.01 | 0.404226
895446 | 01 eerste verdieping | 01 eerste verdieping | 2800 | 2.36236 | 6148 | 0.236236
895631 | 01 eerste verdieping | 01 eerste verdieping | 2800 | 4.65432 | 8750 | 0.465432
895639 | 01 eerste verdieping | 01 eerste verdieping | 2800 | 4.04225 | 8070 | 0.404225
895687 | 01 eerste verdieping | 01 eerste verdieping | 2850 | 12.7356 | 14590 | 1.27356
895695 | 01 eerste verdieping | 01 eerste verdieping | 2850 | 14.2047 | 15940 | 1.42047
895703 | 01 eerste verdieping | 01 eerste verdieping | 2800 | 4.91837 | 9040 | 0.491837
895784 | 02 tweede verdieping | 02 tweede verdieping | 3200 | 9.40581 | 20400 | 0.940581
895810 | 02 tweede verdieping | 02 tweede verdieping | 2800 | 4.65432 | 8750 | 0.465432
895818 | 02 tweede verdieping | 02 tweede verdieping | 2800 | 4.04225 | 8070 | 0.404225
895872 | 02 tweede verdieping | 02 tweede verdieping | 3050 | 11.0921 | 15656 | 1.10921
895882 | 02 tweede verdieping | 02 tweede verdieping | 2800 | 75.6588 | 66508 | 7.56588
895890 | 02 tweede verdieping | 02 tweede verdieping | 2800 | 75.2291 | 34694 | 7.52291
895910 | 02 tweede verdieping | 02 tweede verdieping | 2800 | 4.74682 | 8850 | 0.474682
895918 | 02 tweede verdieping | 02 tweede verdieping | 2800 | 4.04225 | 8070 | 0.404225
895948 | 02 tweede verdieping | 02 tweede verdieping | 3050 | 7.04678 | 10902 | 0.704678
896196 | 01 eerste verdieping | 01 eerste verdieping | 2850 | 32.9212 | 24633 | 3.29212
896206 | 01 eerste verdieping | 01 eerste verdieping | 2800 | 119.475 | 77655 | 11.9475
1291565 | 01 eerste verdieping | 01 eerste verdieping | 3200 | 5.56671 | 10645 | 0.556671
1350962 | 00 begane grond | 00 begane grond | 2800 | 9.31658 | 13040 | 0.931658
1352788 | 00 begane grond | 00 begane grond | 3200 | 10.6885 | 13674 | 1.06885
1352821 | 00 begane grond | 00 begane grond | 3000 | 18.1562 | 17696 | 1.81562
1352837 | 00 begane grond | 00 begane grond | 3000 | 9.63912 | 12595 | 0.963912
1353061 | 00 begane grond | 00 begane grond | 3200 | 35.0584 | 29806 | 3.50584
1353407 | 00 begane grond | 00 begane grond | 2800 | 12.1044 | 16250 | 1.21044
1353467 | 00 begane grond | 00 begane grond | 2800 | 91.6093 | 47175 | 9.16093
1354149 | 00 begane grond | 00 begane grond | 2800 | 21.1386 | 27702 | 2.11386
1354182 | 00 begane grond | 00 begane grond | 3200 | 3.707 | 7770 | 0.3707
1477666 | 01 eerste verdieping | 01 eerste verdieping | 2800 | 75.2291 | 34694 | 7.52291
1614874 | 00 begane grond | 00 begane grond | 2800 | 4.68 | 8700 | 0.468
1614930 | 00 begane grond | 00 begane grond | 2800 | 5.05512 | 9165 | 0.505512
1615029 | 00 begane grond | 00 begane grond | 2800 | 4.13475 | 8170 | 0.413475
1615069 | 00 begane grond | 00 begane grond | 2800 | 5.05512 | 9165 | 0.505512
1615130 | 00 begane grond | 00 begane grond | 2800 | 4.13475 | 8170 | 0.413475
1615199 | 00 begane grond | 00 begane grond | 2800 | 7.90855 | 12699.9 | 0.790855
1615209 | 00 begane grond | 00 begane grond | 2800 | 5.60021 | 9998.73 | 0.560021
1779853 | 00 begane grond | 00 begane grond | 2800 | 92.8085 | 95956.8 | 9.28087
1832648 | 00 begane grond | 00 begane grond | 2800 | 56.6821 | 31518 | 5.66821
1890087 | 00 begane grond | 00 begane grond | 2800 | 32.2457 | 49233 | 3.22457
1890099 | 00 begane grond | 00 begane grond | 2550 | 10.9751 | 13420 | 1.09751
1890108 | 00 begane grond | 00 begane grond | 2800 | 7.01575 | 10870 | 0.701575
1890116 | 00 begane grond | 00 begane grond | 2800 | 5.26737 | 9950 | 0.526737
1890464 | 00 begane grond | 00 begane grond | 2650 | 4.36035 | 8830 | 0.436035
2021601 | 00 begane grond | 00 begane grond | 2800 | 7.15575 | 10930 | 0.715575
2211352 | 02 tweede verdieping | 02 tweede verdieping | 2800 | 6.235 | 10100 | 0.6235
2212582 | 01 eerste verdieping | 01 eerste verdieping | 2800 | 5.48373 | 9496 | 0.548373
2212633 | 01 eerste verdieping | 01 eerste verdieping | 2800 | 15.617 | 17082 | 1.5617
2437747 | 00 begane grond | 00 begane grond | 2600 | 15.9598 | 18640 | 1.59598
3073107 | 00 begane grond | 00 begane grond | 3370 | 2.42078 | 7228.98 | 0.242078
3073478 | 00 begane grond | 00 begane grond | 2800 | 4.76969 | 10680 | 0.476969
3431365 | 00 begane grond | 00 begane grond | 2800 | 1.23947 | 4817.05 | 0.123947
3431475 | 00 begane grond | 00 begane grond | 2800 | 1.60578 | 5859.8 | 0.160578
4630861 | 00 begane grond | 00 begane grond | 3000 | 8.0574 | 11620 | 0.80574
4890189 | 02 tweede verdieping | 02 tweede verdieping | 2800 | 6.88562 | 13050 | 0.688562

# IfcCovering: Compound Ceiling:NLRS_45_CE_P02 systeemplafond 600x600+mwol 50mm (34)
Type - PredefinedType: CEILING
Type - Analytical Properties - Roughness: 1; Absorptance: 0.1; Heat Transfer Coefficient (U): 1.14 kg/K/s3; Thermal Mass: 19.43; Thermal Resistance (R): 0.877193
Type - Graphics - Coarse Scale Fill Pattern: <Solid fill>; Coarse Scale Fill Color: 0
Type - Construction - Thickness: 150 mm
Type - Identity Data - Assembly Code: 45; Assembly Description: plafondafwerkingen; Description: systeemplafond + minerale wol; SmartRevit_Versie: 2018.2; Type Name: NLRS_45_CE_P02 systeemplafond 600x600+mwol 50mm; Workset: Ceiling Types
Type - Other - Category: Ceilings; Family Name: Compound Ceiling
Classification: 45 Uniformat (Uniformat); Material: ISR_Clashobject 50 mm, isolatie 50 mm, m1_plafondplaten_600x600 50 mm
Constraints - Room Bounding: yes
Phasing - Phase Created: 2. nieuwbouw
Identity Data - Workset: Workset1
Other - Family: Compound Ceiling; Family and Type: Compound Ceiling: NLRS_45_CE_P02 systeemplafond 600x600+mwol 50mm; Type: NLRS_45_CE_P02 systeemplafond 600x600+mwol 50mm; Type Id: 2239340
Name (Compound Ceiling:NLRS_45_CE_P02 systeemplafond 600x600+mwol 50mm:...) | In | Level | Height Offset From Level (mm) | Area (m2) | Perimeter (mm) | Volume (m3)
895403 | 01 eerste verdieping | 01 eerste verdieping | 3200 | 43.9664 | 30090 | 6.59497
895426 | 01 eerste verdieping | 01 eerste verdieping | 3200 | 41.8201 | 28335 | 6.27302
895437 | 01 eerste verdieping | 01 eerste verdieping | 3200 | 43.6397 | 28340 | 6.54595
895621 | 01 eerste verdieping | 01 eerste verdieping | 3200 | 44.9634 | 31065 | 6.74451
895647 | 01 eerste verdieping | 01 eerste verdieping | 3200 | 41.8201 | 28335 | 6.27302
895659 | 01 eerste verdieping | 01 eerste verdieping | 3200 | 41.6184 | 28340 | 6.24276
895766 | 02 tweede verdieping | 02 tweede verdieping | 3200 | 45.3663 | 29775 | 6.80495
895800 | 02 tweede verdieping | 02 tweede verdieping | 3200 | 47.413 | 32493 | 7.11195
895826 | 02 tweede verdieping | 02 tweede verdieping | 3200 | 31.6695 | 24997 | 4.75043
895838 | 02 tweede verdieping | 02 tweede verdieping | 3200 | 29.8323 | 23939 | 4.47485
895898 | 02 tweede verdieping | 02 tweede verdieping | 3200 | 31.6779 | 24997 | 4.75169
895938 | 02 tweede verdieping | 02 tweede verdieping | 3200 | 30.7576 | 24047 | 4.61364
1322702 | 00 begane grond | 00 begane grond | 3000 | 53.9157 | 31981 | 8.08736
1323266 | 00 begane grond | 00 begane grond | 3000 | 53.0898 | 31744 | 7.96346
1323296 | 00 begane grond | 00 begane grond | 3000 | 53.1565 | 31606 | 7.97347
1323328 | 00 begane grond | 00 begane grond | 3000 | 53.5503 | 31856 | 8.03255
1350938 | 00 begane grond | 00 begane grond | 3200 | 7.43219 | 11616 | 1.11483
1350946 | 00 begane grond | 00 begane grond | 3200 | 7.2345 | 11090 | 1.08517
1350954 | 00 begane grond | 00 begane grond | 3200 | 7.2345 | 11090 | 1.08517
1350970 | 00 begane grond | 00 begane grond | 3200 | 7.46927 | 11320 | 1.12039
2172475 | 01 eerste verdieping | 01 eerste verdieping | 2800 | 11.1597 | 21775 | 1.67395
2172482 | 01 eerste verdieping | 01 eerste verdieping | 2800 | 6.36814 | 14281 | 0.955221
2172492 | 01 eerste verdieping | 01 eerste verdieping | 2800 | 4.28682 | 10025 | 0.643023
2172501 | 01 eerste verdieping | 01 eerste verdieping | 2800 | 4.28682 | 10025 | 0.643023
2172511 | 01 eerste verdieping | 01 eerste verdieping | 2800 | 6.36259 | 14281 | 0.954389
2172523 | 01 eerste verdieping | 01 eerste verdieping | 2800 | 6.36669 | 14510 | 0.955003
2175485 | 02 tweede verdieping | 02 tweede verdieping | 2800 | 6.18182 | 14267 | 0.927273
2175492 | 02 tweede verdieping | 02 tweede verdieping | 2800 | 5.85902 | 13815 | 0.878853
2175499 | 02 tweede verdieping | 02 tweede verdieping | 2800 | 4.28682 | 10025 | 0.643023
2175506 | 02 tweede verdieping | 02 tweede verdieping | 2800 | 4.28682 | 10025 | 0.643023
2175513 | 02 tweede verdieping | 02 tweede verdieping | 2800 | 6.32964 | 14211 | 0.949446
2175520 | 02 tweede verdieping | 02 tweede verdieping | 2800 | 6.21606 | 14180 | 0.932409
2411554 | 00 begane grond | 00 begane grond | 3200 | 55.3237 | 35862 | 8.29855
2411574 | 00 begane grond | 00 begane grond | 3200 | 55.3675 | 35566 | 8.30512

# IfcCovering: Compound Ceiling:NLRS_45_CE_P03 systeemplafond 600x600 balvast (2)
In: 00 begane grond
Type - PredefinedType: CEILING
Type - Analytical Properties - Roughness: 1; Absorptance: 0.1; Heat Transfer Coefficient (U): 1.14 kg/K/s3; Thermal Mass: 19.43; Thermal Resistance (R): 0.877193
Type - Graphics - Coarse Scale Fill Pattern: <Solid fill>; Coarse Scale Fill Color: 0
Type - Construction - Thickness: 100 mm
Type - Identity Data - Workset: Ceiling Types; Assembly Code: 45; Assembly Description: plafondafwerkingen; Description: systeemplafond balvast; SmartRevit_Versie: 2018.2; Type Name: NLRS_45_CE_P03 systeemplafond 600x600 balvast
Type - Other - Category: Ceilings; Family Name: Compound Ceiling
Classification: 45 Uniformat (Uniformat); Material: ISR_Clashobject 50 mm, m1_plafondplaten_600x600 50 mm
Constraints - Level: 00 begane grond; Room Bounding: yes
Phasing - Phase Created: 2. nieuwbouw
Identity Data - Workset: Workset1
Other - Family: Compound Ceiling; Family and Type: Compound Ceiling: NLRS_45_CE_P03 systeemplafond 600x600 balvast; Type: NLRS_45_CE_P03 systeemplafond 600x600 balvast; Type Id: 2418676
Name (Compound Ceiling:NLRS_45_CE_P03 systeemplafond 600x600 balvast:...) | Height Offset From Level (mm) | Area (m2) | Perimeter (mm) | Volume (m3)
1315792 | 3500 | 40.1449 | 25520 | 4.01449
1322519 | 3027 | 15.0802 | 20341.6 | 1.50802

# IfcCovering: Compound Ceiling:NLRS_45_CE_P04 plafond sport sanitair (3)
In: 00 begane grond
Type - PredefinedType: CEILING
Type - Analytical Properties - Roughness: 1; Absorptance: 0.1
Type - Graphics - Coarse Scale Fill Pattern: <Solid fill>; Coarse Scale Fill Color: 0
Type - Construction - Thickness: 100 mm
Type - Identity Data - Workset: Ceiling Types; Assembly Code: 45; Assembly Description: plafondafwerkingen; Description: systeemplafond, vochtbestendig; SmartRevit_Versie: 2018.2; Type Name: NLRS_45_CE_P04 plafond sport sanitair
Type - Other - Category: Ceilings; Family Name: Compound Ceiling
Classification: 45 Uniformat (Uniformat); Material: ISR_Clashobject 50 mm, m1_plafond sport 50 mm
Constraints - Level: 00 begane grond; Room Bounding: yes; Height Offset From Level: 2800 mm
Phasing - Phase Created: 2. nieuwbouw
Identity Data - Workset: Workset1
Other - Family: Compound Ceiling; Family and Type: Compound Ceiling: NLRS_45_CE_P04 plafond sport sanitair; Type: NLRS_45_CE_P04 plafond sport sanitair; Type Id: 2411540
Name (Compound Ceiling:NLRS_45_CE_P04 plafond sport sanitair:...) | Area (m2) | Perimeter (mm) | Volume (m3)
1890126 | 6.85452 | 12555 | 0.685452
1890148 | 41.467 | 36420 | 4.1467
1890180 | 41.5677 | 42052 | 4.15677

# IfcCovering: Compound Ceiling:NLRS_45_CE_P04 plafond sport sanitair 1200x600 (4)
In: 00 begane grond
Type - PredefinedType: CEILING
Type - Analytical Properties - Roughness: 1; Absorptance: 0.1
Type - Graphics - Coarse Scale Fill Pattern: <Solid fill>; Coarse Scale Fill Color: 0
Type - Construction - Thickness: 100 mm
Type - Identity Data - Workset: Ceiling Types; Assembly Code: 45; Assembly Description: plafondafwerkingen; Description: systeemplafond, vochtbestendig; SmartRevit_Versie: 2018.2; Type Name: NLRS_45_CE_P04 plafond sport sanitair 1200x600
Type - Other - Category: Ceilings; Family Name: Compound Ceiling
Classification: 45 Uniformat (Uniformat); Material: ISR_Clashobject 50 mm, m1_plafond sport 1200x600 50 mm
Constraints - Level: 00 begane grond; Room Bounding: yes; Height Offset From Level: 2800 mm
Phasing - Phase Created: 2. nieuwbouw
Identity Data - Workset: Workset1
Other - Family: Compound Ceiling; Family and Type: Compound Ceiling: NLRS_45_CE_P04 plafond sport sanitair 1200x600; Type: NLRS_45_CE_P04 plafond sport sanitair 1200x600; Type Id: 4985084
Name (Compound Ceiling:NLRS_45_CE_P04 plafond sport sanitair 1200x600:...) | Area (m2) | Perimeter (mm) | Volume (m3)
1890140 | 1.38125 | 4710 | 0.138125
1890172 | 1.494 | 4890 | 0.1494
1890204 | 1.80492 | 5551 | 0.180492
4980326 | 3.49954 | 8544 | 0.349954

# IfcCovering: Compound Ceiling:NLRS_45_CE_P05 gipsplafond (38)
Type - PredefinedType: CEILING
Type - Analytical Properties - Roughness: 1; Absorptance: 0.1
Type - Graphics - Coarse Scale Fill Pattern: <Solid fill>; Coarse Scale Fill Color: 0
Type - Construction - Thickness: 32 mm
Type - Identity Data - Workset: Ceiling Types; Assembly Code: 45; Assembly Description: plafondafwerkingen; Description: houtwol plafond; SmartRevit_Versie: 2018.2; Type Name: NLRS_45_CE_P05 gipsplafond
Type - Other - Category: Ceilings; Family Name: Compound Ceiling
Classification: 45 Uniformat (Uniformat); Material: ISR_Luchtspouw 22 mm, f7_gipsvezel 10 mm
Constraints - Room Bounding: yes
Phasing - Phase Created: 2. nieuwbouw
Identity Data - Workset: Workset1
Other - Family: Compound Ceiling; Family and Type: Compound Ceiling: NLRS_45_CE_P05 gipsplafond; Type: NLRS_45_CE_P05 gipsplafond; Type Id: 2021809
Name (Compound Ceiling:NLRS_45_CE_P05 gipsplafond:...) | In | Level | Height Offset From Level (mm) | Area (m2) | Perimeter (mm) | Volume (m3)
1324937 | 00 begane grond | 00 begane grond | 2800 | 8.96063 | 19469.8 | 0.28674
1351961 | 00 begane grond | 00 begane grond | 3027 | 5.31665 | 17701.7 | 0.170133
1645341 | 01 eerste verdieping | 01 eerste verdieping | 3200 | 3.44503 | 7617.13 | 0.110241
2022569 | 00 begane grond | 00 begane grond | 3027 | 12.9618 | 29950.7 | 0.414778
2072409 | 02 tweede verdieping | 02 tweede verdieping | 3400 | 4.83111 | 13448 | 0.154595
2199346 | 00 begane grond | 00 begane grond | 2800 | 9.88931 | 57210.3 | 0.316458
2211678 | 02 tweede verdieping | 02 tweede verdieping | 3036 | 0.9911 | 10311 | 0.0317152
2211716 | 02 tweede verdieping | 02 tweede verdieping | 3036 | 0.58 | 6200 | 0.01856
2211764 | 02 tweede verdieping | 02 tweede verdieping | 3036 | 0.7804 | 8204 | 0.0249728
2716500 | 00 begane grond | 00 begane grond | 2387 | 1.86935 | 12082 | 0.0598192
2738554 | 00 begane grond | 00 begane grond | 2400 | 1.2696 | 4624 | 0.0406272
3135589 | 02 tweede verdieping | 02 tweede verdieping | 2400 | 0.5175 | 3510 | 0.01656
3267572 | 00 begane grond | 00 ok. ruwe vloer | 2370 | 0.833887 | 3940.94 | 0.0266844
4194574 | 02 tweede verdieping | 02 tweede verdieping | 2387 | 0.60375 | 3250 | 0.01932
4632001 | 01 eerste verdieping | 01 eerste verdieping | 2400 | 1.365 | 5750 | 0.04368
4891435 | 02 tweede verdieping | 02 tweede verdieping | 3036 | 0.8 | 8400 | 0.0256
4892108 | 02 tweede verdieping | 02 tweede verdieping | 3036 | 1.57283 | 16712 | 0.0503306
4903780 | 01 eerste verdieping | 01 eerste verdieping | 3075 | 6.87225 | 87260 | 0.219912
4904253 | 01 eerste verdieping | 01 eerste verdieping | 3125 | 2.50857 | 36341 | 0.0802743
4983693 | 00 begane grond | 00 begane grond | 2800 | 0.69875 | 11430 | 0.02236
4985351 | 01 eerste verdieping | 01 eerste verdieping | 2800 | 0.642187 | 10525 | 0.02055
4985565 | 01 eerste verdieping | 01 eerste verdieping | 2800 | 0.730313 | 11935 | 0.02337
4985621 | 01 eerste verdieping | 01 eerste verdieping | 2800 | 0.85625 | 13950 | 0.0274
4986411 | 01 eerste verdieping | 01 eerste verdieping | 2800 | 0.642187 | 10525 | 0.02055
4986420 | 01 eerste verdieping | 01 eerste verdieping | 2800 | 0.730313 | 11935 | 0.02337
4986545 | 01 eerste verdieping | 01 eerste verdieping | 2800 | 0.769376 | 12560 | 0.02462
4986634 | 02 tweede verdieping | 02 tweede verdieping | 2800 | 0.642187 | 10525 | 0.02055
4986643 | 02 tweede verdieping | 02 tweede verdieping | 2800 | 0.725938 | 11865 | 0.02323
4986650 | 02 tweede verdieping | 02 tweede verdieping | 2800 | 0.74875 | 12230 | 0.02396
4986659 | 02 tweede verdieping | 02 tweede verdieping | 2800 | 0.642187 | 10525 | 0.02055
4986668 | 02 tweede verdieping | 02 tweede verdieping | 2800 | 0.725938 | 11865 | 0.02323
4986675 | 02 tweede verdieping | 02 tweede verdieping | 2800 | 0.74875 | 12230 | 0.02396
4987385 | 02 tweede verdieping | 02 tweede verdieping | 2800 | 0.725938 | 11865 | 0.02323
4987392 | 02 tweede verdieping | 02 tweede verdieping | 2800 | 0.74875 | 12230 | 0.02396
4987525 | 02 tweede verdieping | 02 tweede verdieping | 2800 | 0.725938 | 11865 | 0.02323
4987532 | 02 tweede verdieping | 02 tweede verdieping | 2800 | 0.74875 | 12230 | 0.02396
4987586 | 02 tweede verdieping | 02 tweede verdieping | 2800 | 2.09749 | 33809.8 | 0.0671197
4988157 | 01 eerste verdieping | 01 eerste verdieping | 2800 | 2.09749 | 33809.8 | 0.0671197

# IfcCovering: Compound Ceiling:NLRS_45_CE_P05 gipsplafond op ms-rail, Compound Ceiling:NLRS_45_CE_P05 gipsplafond op ms-rail:3032727
In: 01 eerste verdieping
Type - PredefinedType: CEILING
Type - Analytical Properties - Roughness: 1; Absorptance: 0.1
Type - Graphics - Coarse Scale Fill Pattern: <Solid fill>; Coarse Scale Fill Color: 0
Type - Construction - Thickness: 70 mm
Type - Identity Data - Workset: Ceiling Types; Assembly Code: 45; Assembly Description: plafondafwerkingen; Description: houtwol plafond; SmartRevit_Versie: 2018.2; Type Name: NLRS_45_CE_P05 gipsplafond op ms-rail
Type - Other - Category: Ceilings; Family Name: Compound Ceiling
Classification: 45 Uniformat (Uniformat); Material: n7_isolatie_glaswol 45 mm, f7_gips 12.5 mm, f7_gipsvezel 12.5 mm
Constraints - Room Bounding: yes; Level: 01 eerste verdieping; Height Offset From Level: -87.6683 mm
Phasing - Phase Created: 2. nieuwbouw
Dimensions - Area: 8.33067 m2; Perimeter: 11869 mm; Volume: 0.583147 m3
Identity Data - Workset: Workset1
Other - Family: Compound Ceiling; Family and Type: Compound Ceiling: NLRS_45_CE_P05 gipsplafond op ms-rail; Type: NLRS_45_CE_P05 gipsplafond op ms-rail; Type Id: 3033539

# IfcCovering: Compound Ceiling:NLRS_45_CE_P06 rigitone (5)
Type - PredefinedType: CEILING
Type - Analytical Properties - Roughness: 1; Absorptance: 0.1
Type - Graphics - Coarse Scale Fill Pattern: <Solid fill>; Coarse Scale Fill Color: 0
Type - Construction - Thickness: 82.5 mm
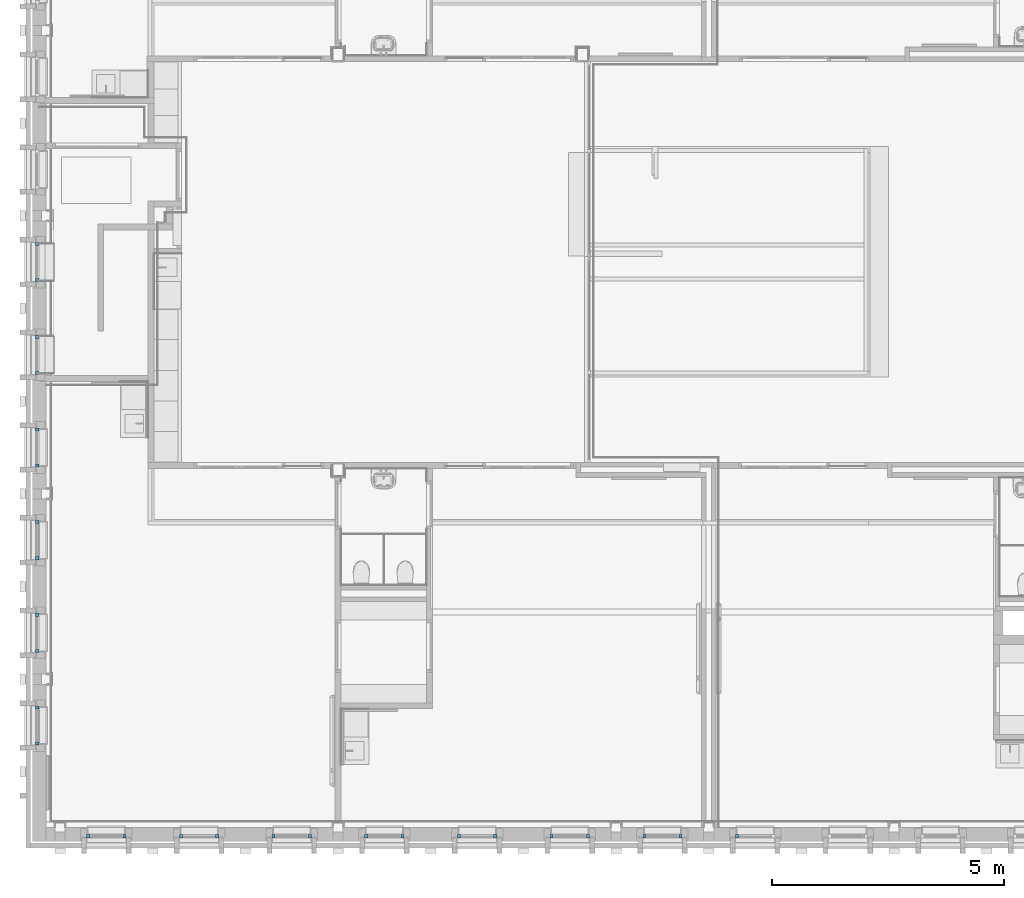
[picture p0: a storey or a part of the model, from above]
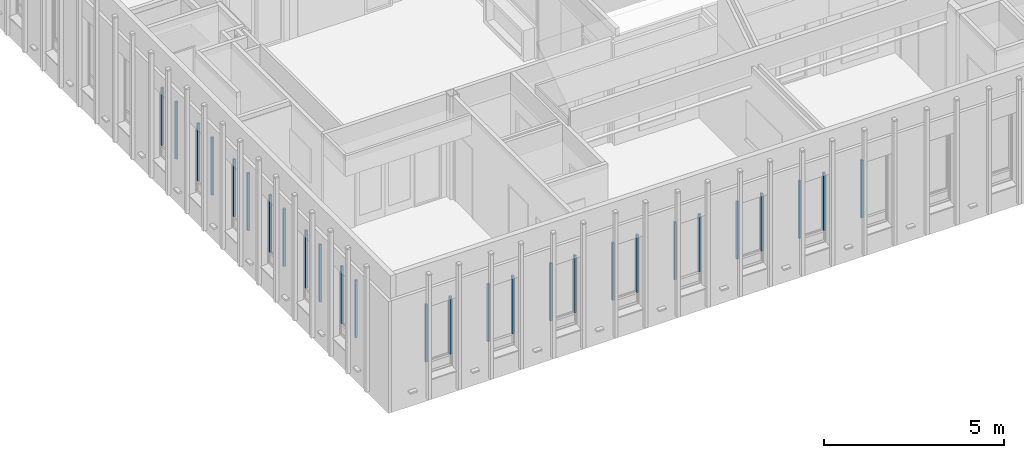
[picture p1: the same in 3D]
Properties of the parts of a building model (IFC2X3), part 7 of 94

# IfcCovering: Compound Ceiling:NLRS_45_CE_P06 rigitone (5)
Type - Identity Data - Workset: Ceiling Types; Assembly Code: 45; Assembly Description: plafondafwerkingen; Description: akoestisch plafond; SmartRevit_Versie: 2018.2; Type Name: NLRS_45_CE_P06 rigitone
Type - Other - Category: Ceilings; Family Name: Compound Ceiling
Classification: 45 Uniformat (Uniformat); Material: n7_isolatie_glaswol 50 mm, j9_luchtspouw 20 mm, f7_gips_rigitone_gyproc 8/18 12.5 mm
Constraints - Room Bounding: yes
Phasing - Phase Created: 2. nieuwbouw
Identity Data - Workset: Workset1
Other - Family: Compound Ceiling; Family and Type: Compound Ceiling: NLRS_45_CE_P06 rigitone; Type: NLRS_45_CE_P06 rigitone; Type Id: 2444890
Name (Compound Ceiling:NLRS_45_CE_P06 rigitone:...) | In | Level | Height Offset From Level (mm) | Area (m2) | Perimeter (mm) | Volume (m3)
1351017 | 00 begane grond | 00 begane grond | 3353 | 29.5462 | 38474.3 | 2.43756
2444835 | 02 tweede verdieping | 02 tweede verdieping | 3959.5 | 25.491 | 30843 | 2.10301
2445178 | 02 tweede verdieping | 02 tweede verdieping | 3959.5 | 25.491 | 30843 | 2.10301
3075750 | 02 tweede verdieping | 02 tweede verdieping | 3959.5 | 13.7324 | 15711.8 | 1.13293
3075857 | 02 tweede verdieping | 02 tweede verdieping | 3959.5 | 13.7324 | 15711.8 | 1.13293

# IfcCovering: Compound Ceiling:NLRS_45_CE_P10 cementvezel (4)
In: 00 begane grond
Type - PredefinedType: CEILING
Type - Analytical Properties - Roughness: 1; Absorptance: 0.1
Type - Graphics - Coarse Scale Fill Pattern: <Solid fill>; Coarse Scale Fill Color: 0
Type - Construction - Thickness: 73 mm
Type - Identity Data - Workset: Ceiling Types; Assembly Code: 45; Assembly Description: plafondafwerkingen; Description: houtwol plafond; SmartRevit_Versie: 2018.2; Type Name: NLRS_45_CE_P10 cementvezel
Type - Other - Category: Ceilings; Family Name: Compound Ceiling
Classification: 45 Uniformat (Uniformat); Material: ISR_Luchtspouw 50 mm, multiplex_horizontaal 15 mm, ISR_Vezelcement 8 mm
Constraints - Level: 00 begane grond; Room Bounding: yes; Height Offset From Level: 3000 mm
Phasing - Phase Created: 2. nieuwbouw
Identity Data - Workset: Workset1
Other - Family: Compound Ceiling; Family and Type: Compound Ceiling: NLRS_45_CE_P10 cementvezel; Type: NLRS_45_CE_P10 cementvezel; Type Id: 2022474
Name (Compound Ceiling:NLRS_45_CE_P10 cementvezel:...) | Area (m2) | Perimeter (mm) | Volume (m3)
2021834 | 28.4006 | 28169 | 2.07326
2200197 | 8.39271 | 12654 | 0.612668
2202080 | 9.1696 | 19483.8 | 0.669383
2418680 | 2.7092 | 7882.23 | 0.197772

# IfcCovering: Compound Ceiling:NLRS_45_CE_gipsplafond, Compound Ceiling:NLRS_45_CE_gipsplafond:3135602
In: 01 eerste verdieping
Type - PredefinedType: CEILING
Type - Analytical Properties - Roughness: 1; Absorptance: 0.1
Type - Graphics - Coarse Scale Fill Pattern: <Solid fill>; Coarse Scale Fill Color: 0
Type - Construction - Thickness: 50 mm
Type - Identity Data - Workset: Ceiling Types; Assembly Code: 45; Assembly Description: plafondafwerkingen; Description: houtwol plafond; SmartRevit_Versie: 2018.2; Type Name: NLRS_45_CE_gipsplafond
Type - Other - Category: Ceilings; Family Name: Compound Ceiling
Classification: 45 Uniformat (Uniformat); Material: ISR_Luchtspouw 40 mm, f7_gipsvezel 10 mm
Constraints - Room Bounding: yes; Level: 01 eerste verdieping; Height Offset From Level: 2400 mm
Phasing - Phase Created: 2. nieuwbouw
Dimensions - Area: 0.4968 m2; Perimeter: 3480 mm; Volume: 0.02484 m3
Identity Data - Workset: Workset1
Other - Family: Compound Ceiling; Family and Type: Compound Ceiling: NLRS_45_CE_gipsplafond; Type: NLRS_45_CE_gipsplafond; Type Id: 1351853

# IfcCurtainWall: Basic Wall:22_WA_binnenwand_ms125 25-75-25 _gen_bdg, Basic Wall:22_WA_binnenwand_ms125 25-75-25 _gen_bdg:2694146
In: 02 tweede verdieping
Type - Material: f7_gipsvezel 12.5 mm, f7_gips 12.5 mm, n7_isolatie_glaswol 75 mm, f7_gips 12.5 mm, f7_gipsvezel 12.5 mm
Type - Analytical Properties - Roughness: 1; Absorptance: 0.1
Type - Materials and Finishes - Structural Material: f7_gipsvezel
Type - Graphics - Coarse Scale Fill Pattern: <Solid fill>; Coarse Scale Fill Color: 12632256
Type - Construction - Function: Interior; Wrapping at Inserts: Do not wrap; Width: 125 mm; Wrapping at Ends: Exterior
Type - Identity Data - Workset: Wall Types; Assembly Code: 2E(22.11); Datum_Gewijzigd: 26-05-2014; Description: Binnenwand 100mm; Model: LOD300; SmartRevit_Versie: 2015.1; Type Name: 22_WA_binnenwand_ms125 25-75-25 _gen_bdg
Type - Other - Category: Walls; Family Name: Basic Wall
Cross-Section Definition - Cross-Section: Vertical
Constraints - Base Constraint: 02 tweede verdieping; Base Extension Distance: 0 mm; Related to Mass: no; Top Extension Distance: 0 mm; Base Offset: 0 mm; Location Line: Wall Centerline; Location Line Offset: -32.5 mm; Unconnected Height: 1050 mm
Phasing - Phase Created: 2. nieuwbouw
Structural - Enable Analytical Model: no; Structural: no; Structural Usage: Non-bearing
Dimensions - Area: 2.35746 m2; Height: 1050 mm; Length: 2245.2 mm; Volume: 0.294683 m3; Width: 2245.2 mm
Identity Data - Workset: Workset1; Categorize as: Panel
Other - Family: Basic Wall; Category: Curtain Panels; Family and Type: Basic Wall: 22_WA_binnenwand_ms125 25-75-25 _gen_bdg; Type: 22_WA_binnenwand_ms125 25-75-25 _gen_bdg; Type Id: 875572
Group: Model Group:BI-29bw 60min:1476114

# IfcCurtainWall: Curtain Wall:20_opening (11)
Type - Horizontal Grid(Type) - Adjust for Mullion Size: yes; Spacing: 1500 mm
Type - Vertical Grid(Type) - Adjust for Mullion Size: yes; Spacing: 1500 mm
Type - Construction(Type) - Function: Interior; Automatically Embed: yes; Join Condition: Border and Vertical Grid Continuous; Curtain Panel: Empty System Panel : leeg
Type - Identity Data(Type) - Workset: Curtain Wall Types; Type Name: 20_opening
Type - Other(Type) - Category: Walls; Family Name: Curtain Wall
Cross-Section Definition - Cross-Section: Vertical
Horizontal Grid - Angle: 0 deg; Justification: Beginning; Number: 4; Offset: 0 mm; sets with these values: 2
Constraints - Base is Attached: no; Related to Mass: no; Room Bounding: yes; Top is Attached: no
Phasing - Phase Created: 2. nieuwbouw
Structural - Enable Analytical Model: no; Structural: no; Structural Usage: Non-bearing
Identity Data - Workset: Workset1
Other - Category: Walls; Family: Curtain Wall; Family and Type: Curtain Wall: 20_opening; Type: 20_opening; Type Id: 1306490
Name (Curtain Wall:20_opening:...) | In | Base Constraint | Top Constraint | Base Offset (mm) | Top Offset (mm) | Unconnected Height (mm) | Area (m2) | Length (mm)
1306431 | 01 eerste verdieping | 01 eerste verdieping | Up to level: 01 eerste verdieping | -50 | 150 | 200 | 0.32 | 1600
1306777 | 01 eerste verdieping | 01 eerste verdieping | Up to level: 01 eerste verdieping | -50 | 2850 | 2900 | 4.93 | 1700
1340920 | 01 eerste verdieping | 01 eerste verdieping | Up to level: 01 eerste verdieping | -50 | 2850 | 2900 | 5.539 | 1910
1347514 | 01 eerste verdieping | 01 eerste verdieping | Up to level: 01 eerste verdieping | -50 | 2850 | 2900 | 4.93 | 1700
2387607 | 00 begane grond | bk. fundering | Up to level: 01 ok. ruwe vloer | 0 | 0 | 4150 | 1.245 | 300
2551990 | 01 eerste verdieping | 01 eerste verdieping | Up to level: 01 eerste verdieping | -50 | 2877 | 2927 | 10.3396 | 3532.5
2756939 | 01 eerste verdieping | 01 eerste verdieping | Up to level: 02 ok. ruwe vloer | 260 | -580 | 2590 | 4.921 | 1900
2765839 | 01 eerste verdieping | 01 eerste verdieping | Up to level: 02 ok. ruwe vloer | 260 | -580 | 2590 | 4.3771 | 1690
2769524 | 01 eerste verdieping | 01 eerste verdieping | Up to level: 02 ok. ruwe vloer | 260 | -580 | 2590 | 2.36338 | 912.5
5095168 | 00 begane grond | 00 begane grond | Up to level: 00 begane grond | -300 | 0 | 300 | 0.591473 | 1971.58
5095313 | 00 begane grond | 00 begane grond | Up to level: 00 begane grond | -320 | 0 | 320 | 0.3952 | 1235

# IfcCurtainWall: Curtain Wall:32_BDG_Jansen Economy 50 (3)
Type - Horizontal Mullions(Type) - Border 1 Type: Rectangular Mullion : CWM_Jansen Economy 50 bxh=50x60mm; Border 2 Type: Rectangular Mullion : CWM_Jansen Economy 50 bxh=50x60mm; Interior Type: Rectangular Mullion : CWM_Jansen Economy 50 bxh=50x60mm
Type - Vertical Mullions(Type) - Border 1 Type: Rectangular Mullion : CWM_Jansen Economy 50 bxh=50x60mm; Border 2 Type: Rectangular Mullion : CWM_Jansen Economy 50 bxh=50x60mm; Interior Type: Rectangular Mullion : CWM_Jansen Economy 50 bxh=50x60mm
Type - Horizontal Grid(Type) - Adjust for Mullion Size: yes; Spacing: 1500 mm
Type - Vertical Grid(Type) - Adjust for Mullion Size: yes; Spacing: 1500 mm
Type - Construction(Type) - Function: Interior; Automatically Embed: yes; Join Condition: Border and Vertical Grid Continuous; Curtain Panel: System Panel : glas binnen stalen kozijnen
Type - Identity Data(Type) - Workset: Curtain Wall Types; Type Name: 32_BDG_Jansen Economy 50
Type - Other(Type) - Category: Walls; Family Name: Curtain Wall
Cross-Section Definition - Cross-Section: Vertical
Horizontal Grid - Angle: 0 deg; Justification: Beginning; Number: 4; Offset: 0 mm; sets with these values: 2
Constraints - Base is Attached: no; Related to Mass: no; Room Bounding: yes; Top is Attached: no; Top Offset: 0 mm
Phasing - Phase Created: 2. nieuwbouw
Structural - Enable Analytical Model: no; Structural: no; Structural Usage: Non-bearing
Identity Data - Workset: Workset1
Other - Category: Walls; Family: Curtain Wall; Family and Type: Curtain Wall: 32_BDG_Jansen Economy 50; Type: 32_BDG_Jansen Economy 50; Type Id: 1470051
Name (Curtain Wall:32_BDG_Jansen Economy 50:...) | In | Base Constraint | Base Offset (mm) | Top Constraint | Unconnected Height (mm) | Area (m2) | Length (mm) | Comments | Group
1470455 | 01 eerste verdieping | 01 eerste verdieping | 1200 | Up to level: 01 ok. plafond | 1600 | 19.2638 | 8650 | BI-26bw | Model Group:BI-26bw:2535201
1476038 | 02 tweede verdieping | 02 tweede verdieping | 1200 | Up to level: 02 ok. plafond | 1600 | 24.22 | 8650 | BI-29bw | Model Group:BI-29bw 60min:1476114
1478229 | 00 begane grond | 00 begane grond | 0 | Up to level: 00 ok. plafond | 2800 | 21.042 | 7515 | BI-13bw | Model Group:BI-13bw 7515x2800:2527306

# IfcCurtainWall: Curtain Wall:32_gevelrooster DucoWall Screening 70 (2)
In: 01 eerste verdieping
Type - Horizontal Mullions - Interior Type: Rectangular Mullion : CWM_35x82
Type - Horizontal Grid - Adjust for Mullion Size: yes; Layout: Fixed Distance; Spacing: 75 mm
Type - Vertical Grid - Adjust for Mullion Size: yes; Spacing: 1500 mm
Type - Construction - Function: Exterior; Automatically Embed: no; Join Condition: Border and Vertical Grid Continuous; Curtain Panel: Empty System Panel : leeg
Type - Identity Data - Workset: Curtain Wall Types; Type Name: 32_gevelrooster DucoWall Screening 70
Type - Other - Category: Walls; Family Name: Curtain Wall
Cross-Section Definition - Cross-Section: Vertical
Horizontal Grid - Angle: 0 deg; Justification: Beginning; Offset: 0 mm; Number: 25
Vertical Grid - Angle: 0 deg; Justification: Beginning; Number: 4; Offset: 0 mm
Constraints - Base is Attached: no; Related to Mass: no; Room Bounding: yes; Top is Attached: no; Base Constraint: 01 eerste verdieping; Top Constraint: Up to level: 01 eerste verdieping; Base Offset: 775 mm; Top Offset: 2680 mm; Unconnected Height: 1905 mm
Phasing - Phase Created: 2. nieuwbouw
Structural - Enable Analytical Model: no; Structural: no; Structural Usage: Non-bearing
Identity Data - Workset: Workset1
Other - Family: Curtain Wall; Family and Type: Curtain Wall: 32_gevelrooster DucoWall Screening 70; Type: 32_gevelrooster DucoWall Screening 70; Type Id: 2176982
Name (Curtain Wall:32_gevelrooster DucoWall Screening 70:...) | Area (m2) | Length (mm)
2409143 | 3.34137 | 1754
2409220 | 1.69164 | 888

# IfcCurtainWall: Curtain Wall:32_ontwerpkozijn binnen 125*67 (17)
Type - Horizontal Mullions(Type) - Border 1 Type: Rectangular Mullion : 67x125; Border 2 Type: Rectangular Mullion : 67x125; Interior Type: Rectangular Mullion : 67x125
Type - Vertical Mullions(Type) - Border 1 Type: Rectangular Mullion : 67x125; Border 2 Type: Rectangular Mullion : 67x125; Interior Type: Rectangular Mullion : 67x125
Type - Horizontal Grid(Type) - Adjust for Mullion Size: yes; Spacing: 1500 mm
Type - Vertical Grid(Type) - Adjust for Mullion Size: yes; Spacing: 1500 mm
Type - Construction(Type) - Function: Interior; Automatically Embed: yes; Curtain Panel: System Panel : glas_offset-35; Join Condition: Border and Vertical Grid Continuous
Type - Identity Data(Type) - Workset: Curtain Wall Types; Type Name: 32_ontwerpkozijn binnen 125*67
Type - Other(Type) - Category: Walls; Family Name: Curtain Wall
Cross-Section Definition - Cross-Section: Vertical
Horizontal Grid - Angle: 0 deg; Justification: Beginning; Number: 4; Offset: 0 mm; sets with these values: 2
Constraints - Base is Attached: no; Related to Mass: no; Room Bounding: yes; Top is Attached: no
Phasing - Phase Created: 2. nieuwbouw
Structural - Enable Analytical Model: no; Structural: no; Structural Usage: Non-bearing
Identity Data - Workset: Workset1
Other - Category: Walls; Family: Curtain Wall; Family and Type: Curtain Wall: 32_ontwerpkozijn binnen 125*67; Type: 32_ontwerpkozijn binnen 125*67; Type Id: 1227226
Name (Curtain Wall:32_ontwerpkozijn binnen 125*67:...) | In | Top Offset (mm) | Base Constraint | Base Offset (mm) | Unconnected Height (mm) | Area (m2) | Length (mm) | Comments | Group | Top Constraint
1367977 | 00 begane grond | 0 | 00 begane grond | 0 | 2387 | 5.7288 | 2400 | BI-04bw | Model Group:BI-04bw 2400x2387:1367983
1420134 | 01 eerste verdieping | 0 | 01 eerste verdieping | 0 | 2387 | 5.7288 | 2400 | BI-04w | Model Group:BI-04w 2400x2387:1420140
1420368 | 01 eerste verdieping | 0 | 01 eerste verdieping | 0 | 2387 | 4.35627 | 1825 | BI-25bw | Model Group:BI-25bw 1825x2387:1420374
1612555 | 00 begane grond | 0 | 00 begane grond | 0 | 2800 | 11.802 | 4215 | BI-10 | Model Group:BI-10 4215x2800:2522162 | Up to level: 00 ok. plafond
1729467 | 02 tweede verdieping | 2800 | 02 tweede verdieping | 0 | 2800 | 5.5048 | 1966 | BI-28 | Model Group:BI-28:2534707 | Up to level: 02 tweede verdieping
1730033 | 01 eerste verdieping | 2800 | 01 eerste verdieping | 250 | 2550 | 5.1204 | 2008 | BI-22 | Model Group:BI-22 1965x2550:2532537 | Up to level: 01 eerste verdieping
1731562 | 02 tweede verdieping | 2800 | 02 tweede verdieping | 1050 | 1750 | 4.37115 | 2497.8 | BI-27 | Model Group:BI-27 2500x1700:2534618 | Up to level: 02 tweede verdieping
1731625 | 02 tweede verdieping | 2800 | 02 tweede verdieping | 1050 | 1750 | 0.81725 | 467 | BI-29 | Model Group:BI-28:2534707 | Up to level: 02 tweede verdieping
1734721 | 02 tweede verdieping | 2800 | 02 tweede verdieping | 1050 | 1750 | 0.81725 | 467 | BI-29 | Model Group:BI-28:2534707 | Up to level: 02 tweede verdieping
1735010 | 01 eerste verdieping | 2800 | 01 eerste verdieping | 1050 | 1750 | 5.01375 | 2865 | BI-20 | Model Group:BI-20 2865x1750:2532482 | Up to level: 01 eerste verdieping
1735395 | 01 eerste verdieping | 2800 | 01 eerste verdieping | 1050 | 1750 | 4.59375 | 2625 | BI-21w | Model Group:BI-21w 2630x1750:2532641 | Up to level: 01 eerste verdieping
1735559 | 01 eerste verdieping | 2800 | 01 eerste verdieping | 0 | 2800 | 12.8127 | 4575.96 | BI-23w | Model Group:BI-23w 4635x2800:2532690 | Up to level: 01 eerste verdieping
1940853 | 00 begane grond | 0 | 00 begane grond | 0 | 2387 | 2.98375 | 1250 | BI-31w | Model Group:BI-31w 1250x2387:1940859
2140318 | 00 begane grond | 0 | 00 begane grond | 0 | 2387 | 3.18426 | 1334 | BI-16y | Model Group:BI-16y 1334x2387:2530506
2534664 | 02 tweede verdieping | 2800 | 02 tweede verdieping | 1050 | 1750 | 4.37115 | 2497.8 | BI-27 | Model Group:BI-27 2500x1700:2534674 | Up to level: 02 tweede verdieping
2591152 | 00 begane grond | 0 | 00 begane grond | 0 | 2387 | 5.7288 | 2400 | BI-04av | Model Group:BI-04av 2400x2387:1367879
3843747 | 00 begane grond | 2387 | 00 begane grond | 0 | 2387 | 5.24663 | 2198 | BI-02 | Model Group:BI-02 2198x2387 (members excluded):3844191 | Up to level: 00 begane grond

# IfcCurtainWall: Curtain Wall:32_schuifwand binnen 40*85, Curtain Wall:32_schuifwand binnen 40*85:2082374
In: 01 eerste verdieping
Type - Horizontal Mullions - Border 1 Type: Rectangular Mullion : 3x85; Border 2 Type: Rectangular Mullion : 40x85
Type - Vertical Mullions - Border 1 Type: Rectangular Mullion : 3x85; Border 2 Type: Rectangular Mullion : 3x85
Type - Horizontal Grid - Adjust for Mullion Size: yes; Spacing: 1500 mm
Type - Vertical Grid - Adjust for Mullion Size: yes; Spacing: 1500 mm
Type - Construction - Function: Interior; Automatically Embed: yes; Curtain Panel: System Panel : glas_offset-35; Join Condition: Border and Vertical Grid Continuous
Type - Identity Data - Workset: Curtain Wall Types; Type Name: 32_schuifwand binnen 40*85
Type - Other - Category: Walls; Family Name: Curtain Wall
Cross-Section Definition - Cross-Section: Vertical
Horizontal Grid - Angle: 0 deg; Justification: Beginning; Number: 4; Offset: 0 mm; sets with these values: 2
Constraints - Base is Attached: no; Related to Mass: no; Room Bounding: yes; Top is Attached: no; Base Constraint: 01 eerste verdieping; Top Constraint: Up to level: 01 eerste verdieping; Base Offset: 0 mm; Top Offset: 2387 mm; Unconnected Height: 2387 mm
Phasing - Phase Created: 2. nieuwbouw
Structural - Enable Analytical Model: no; Structural: no; Structural Usage: Non-bearing
Dimensions - Area: 6.43297 m2; Length: 2695 mm
Identity Data - Workset: Workset1; Comments: BI-30
Other - Family: Curtain Wall; Family and Type: Curtain Wall: 32_schuifwand binnen 40*85; Type: 32_schuifwand binnen 40*85; Type Id: 2753422
Group: Model Group:BI-30:2755094

# IfcCurtainWall: Curtain Wall:CWA_Select 100 K_Multiwal, Curtain Wall:CWA_Select 100 K_Multiwal:1322223
In: 00 begane grond
Type - Description: Select 100 K
Type - Data - BIMObjectName: Pr_40_30_20_02-Multiwal-Select 100 K-LOD400; ClassificationName: Uniclass2015; ClassificationValue: Pr_40_30_20_02; COBie.Type.AccessibilityPerformance: N/A; COBie.Type.AssetType: Fixed; COBie.Type.Category: 23.25.20.14.11.11.17 - Infill Panels; COBie.Type.CodePerformance: N/A; COBie.Type.Color: N/A; COBie.Type.Constituents: N/A; COBie.Type.CreatedBy: Itannex bv; COBie.Type.CreatedOn: 2018.11.20; COBie.Type.Description: Select 100 K; COBie.Type.DurationUnit: N/A; COBie.Type.ExpectedLife: N/A; COBie.Type.Features: N/A; COBie.Type.Finish: N/A; COBie.Type.Grade: 3; COBie.Type.Length: 1260 mm; COBie.Type.Manufacturer: Multiwal; COBie.Type.Material: N/A; COBie.Type.ModelNumber: N/A; COBie.Type.ModelReference: 100 K; COBie.Type.Name: Select 100 K; COBie.Type.NominalHeight: 12000 mm; COBie.Type.NominalLength: 1260 mm; COBie.Type.NominalWidth: 105 mm; COBie.Type.Shape: Rectangular; COBie.Type.Size: 105 mm Thickness; COBie.Type.SustainabilityPerformance: N/A; COBie.Type.WarrantyDescription: N/A; COBie.Type.WarrantyDurationLabor: N/A; COBie.Type.WarrantyDurationParts: N/A; COBie.Type.WarrantyDurationUnit: N/A; COBie.Type.WarrantyGuarantorLabor: N/A; COBie.Type.WarrantyGuarantorParts: N/A
Type - General - RSen_C_code_ETIM: EC011925; RSen_C_code_ETIM_url: https://prod.etim-international.com/Class/Details?classId=EC011925&classVersion=3; RSen_C_content_creator: Itannex bv
Type - Vertical Mullions - Border 1 Type: Rectangular Mullion : CWM_Closing jamb Select 100 K/U_Multiwal; Border 2 Type: Rectangular Mullion : CWM_Wall jamb Select 100 K/U - 85mm_Multiwal
Type - Horizontal Grid - Adjust for Mullion Size: yes; Spacing: 12000 mm
Type - Vertical Grid - Adjust for Mullion Size: yes; Layout: Maximum Spacing; Spacing: 1260 mm
Type - Construction - Function: Interior; Automatically Embed: no; Join Condition: Not Defined; Curtain Panel: CP_NE Standard basic panel_Multiwal : NE - Select 100 K/U
Type - Identity Data - Workset: Curtain Wall Types; Assembly Code: 22.14; Assembly Description: binnenwanden; niet constructief, systeemwanden; verplaatsbaar; Description: Select 100 K; Manufacturers Address: Norman Road, Rochdale, OL11 4HS, United Kingdom; Manufacturers Email: info@multiwal.co.uk; Manufacturers Telephone Number: +441273497370; Model: Select 100 K; NLRS_C_content_datum_gewijzigd: 2018.11.20; NLRS_C_content_provider: Multiwal; NLRS_C_content_versie: 1.0; RSen_C_product_description: Select 100 K; Type Comments: Sound insulation 41-53 dB; Type Name: CWA_Select 100 K_Multiwal; URL: https://uk.multiwal.eu/products/moveable-walls/moveable-wall-select/select-100-k/
Type - Other - Category: Walls; Family Name: Curtain Wall
Classification: 22.14 Uniformat (Uniformat); Group: Model Group:BI-11 8834x2800:2521973
Cross-Section Definition - Cross-Section: Vertical
Horizontal Grid - Angle: 0 deg; Justification: Beginning; Number: 4; Offset: 0 mm
Vertical Grid - Angle: 0 deg; Justification: Beginning; Offset: 0 mm; Number: 6
Constraints - Base is Attached: no; Related to Mass: no; Room Bounding: yes; Top is Attached: no; Base Constraint: 00 begane grond; Base Offset: 0 mm; Top Constraint: Up to level: 00 begane grond; Top Offset: 2800 mm; Unconnected Height: 2800 mm
Phasing - Phase Created: 2. nieuwbouw
Structural - Enable Analytical Model: no; Structural: no; Structural Usage: Non-bearing
Dimensions - Area: 24.7361 m2; Length: 8834.33 mm
Identity Data - Workset: Workset1; Comments: BI-11
Other - Family: Curtain Wall; Family and Type: Curtain Wall: CWA_Select 100 K_Multiwal; Type: CWA_Select 100 K_Multiwal; Type Id: 1316253

# IfcCurtainWall: Curtain Wall:NLRS_21_CW_Ontwerpkozijn_aluminium_RT72 (137)
Type - Horizontal Mullions(Type) - Border 1 Type: Rectangular Mullion : RT72_Vo_raam; Border 2 Type: Rectangular Mullion : RT72_Vb_raam; Interior Type: Rectangular Mullion : RT72_Vm_raam
Type - Vertical Mullions(Type) - Border 1 Type: Rectangular Mullion : RT72_Hr_raam; Border 2 Type: Rectangular Mullion : RT72_Hl_raam; Interior Type: Rectangular Mullion : RT72_Hm_raam_78
Type - Horizontal Grid(Type) - Adjust for Mullion Size: no
Type - Vertical Grid(Type) - Adjust for Mullion Size: no
Type - Construction(Type) - Function: Exterior; Automatically Embed: no; Curtain Panel: System Panel : RT72_glas; Join Condition: Not Defined
Type - Identity Data(Type) - Type Name: NLRS_21_CW_Ontwerpkozijn_aluminium_RT72; Workset: Curtain Wall Types
Type - Other(Type) - Category: Walls; Family Name: Curtain Wall
Cross-Section Definition - Cross-Section: Vertical
Horizontal Grid - Angle: 0 deg; Justification: Beginning; Number: 4; Offset: 0 mm; sets with these values: 2
Constraints - Base is Attached: no; Related to Mass: no; Room Bounding: yes; Top is Attached: no
Phasing - Phase Created: 2. nieuwbouw
Structural - Enable Analytical Model: no; Structural: no; Structural Usage: Non-bearing
Identity Data - Workset: Workset1
Other - Category: Walls; Family: Curtain Wall; Family and Type: Curtain Wall: NLRS_21_CW_Ontwerpkozijn_aluminium_RT72; Type: NLRS_21_CW_Ontwerpkozijn_aluminium_RT72; Type Id: 835097
Name (Curtain Wall:NLRS_21_CW_Ontwerpkozijn_aluminium_RT72:...) | In | Base Constraint | Top Offset (mm) | Base Offset (mm) | Unconnected Height (mm) | Area (m2) | Length (mm) | Comments | Group
870541 | 02 tweede verdieping | 02 tweede verdieping | 0 | 673 | 2390 | 2.0315 | 850 | BU-39 | Model Group:31_2A:870547
870747 | 02 tweede verdieping | 02 tweede verdieping | 0 | 673 | 2390 | 2.0315 | 850 | BU-39 | Model Group:31_2A:870753
870860 | 02 tweede verdieping | 02 tweede verdieping | 0 | 673 | 2390 | 2.0315 | 850 | BU-39 | Model Group:31_2A:870866
871635 | 02 tweede verdieping | 02 tweede verdieping | 0 | 673 | 2390 | 2.0315 | 850 | BU-39 | Model Group:31_2A:871641
871668 | 02 tweede verdieping | 02 tweede verdieping | 0 | 673 | 2390 | 2.0315 | 850 | BU-39 | Model Group:31_2A:871674
871919 | 02 tweede verdieping | 02 tweede verdieping | 0 | 673 | 2390 | 2.0315 | 850 | BU-39 | Model Group:31_2A:871925
871951 | 02 tweede verdieping | 02 tweede verdieping | 0 | 673 | 2390 | 2.0315 | 850 | BU-39 | Model Group:31_2A:871957
872813 | 02 tweede verdieping | 02 tweede verdieping | 0 | 673 | 2390 | 2.0315 | 850 | BU-39 | Model Group:31_2A:872819
872879 | 02 tweede verdieping | 02 tweede verdieping | 0 | 673 | 2390 | 2.0315 | 850 | BU-39 | Model Group:31_2A:872885
872912 | 02 tweede verdieping | 02 tweede verdieping | 0 | 673 | 2390 | 2.0315 | 850 | BU-39 | Model Group:31_2A:872918
872945 | 02 tweede verdieping | 02 tweede verdieping | 0 | 673 | 2390 | 2.0315 | 850 | BU-39 | Model Group:31_2A:872951
872978 | 02 tweede verdieping | 02 tweede verdieping | 0 | 673 | 2390 | 2.0315 | 850 | BU-39 | Model Group:31_2A:872984
873011 | 02 tweede verdieping | 02 tweede verdieping | 0 | 673 | 2390 | 2.0315 | 850 | BU-39 | Model Group:31_2A:873017
873077 | 02 tweede verdieping | 02 tweede verdieping | 0 | 673 | 2390 | 2.0315 | 850 | BU-39 | Model Group:31_2A:873083
873508 | 02 tweede verdieping | 02 tweede verdieping | 0 | 673 | 2390 | 2.0315 | 850 | BU-39 | Model Group:31_2A:873514
873601 | 02 tweede verdieping | 02 tweede verdieping | 0 | 673 | 2390 | 2.0315 | 850 | BU-39 | Model Group:31_2A:873607
873694 | 02 tweede verdieping | 02 tweede verdieping | 0 | 673 | 2390 | 2.0315 | 850 | BU-39 | Model Group:31_2A:873700
874666 | 01 eerste verdieping | 01 eerste verdieping | 0 | 850 | 2020 | 3.57742 | 1771 | BU-26 | Model Group:31_1A:874672
874950 | 01 eerste verdieping | 01 eerste verdieping | 0 | 850 | 2020 | 3.57742 | 1771 | BU-26 | Model Group:31_1A:874956
875025 | 01 eerste verdieping | 01 eerste verdieping | 0 | 850 | 2020 | 3.57742 | 1771 | BU-29A | Model Group:31_1A DKD L:875031
875040 | 01 eerste verdieping | 01 eerste verdieping | 0 | 850 | 2020 | 3.57742 | 1771 | BU-26 | Model Group:31_1A:875046
875049 | 01 eerste verdieping | 01 eerste verdieping | 0 | 850 | 2020 | 3.57742 | 1771 | BU-28B | Model Group:31_1A DK R:875055
875268 | 01 eerste verdieping | 01 eerste verdieping | 0 | 850 | 2020 | 3.57742 | 1771 | BU-26 | Model Group:31_1A:875274
875304 | 01 eerste verdieping | 01 eerste verdieping | 0 | 850 | 2020 | 3.57742 | 1771 | BU-28A | Model Group:31_1A DKD R:875310
875376 | 01 eerste verdieping | 01 eerste verdieping | 0 | 850 | 2020 | 3.57742 | 1771 | BU-26 | Model Group:31_1A:875382
876487 | 01 eerste verdieping | 01 eerste verdieping | 0 | 850 | 2020 | 3.57742 | 1771 | BU-26 | Model Group:31_1A:876493
876905 | 01 eerste verdieping | 01 eerste verdieping | 0 | 850 | 2020 | 3.57742 | 1771 | BU-26 | Model Group:31_1A:876911
877022 | 01 eerste verdieping | 01 eerste verdieping | 0 | 850 | 2020 | 3.57742 | 1771 | BU-26 | Model Group:31_1A:877028
877112 | 01 eerste verdieping | 01 eerste verdieping | 0 | 850 | 2020 | 3.57742 | 1771 | BU-26 | Model Group:31_1A:877118
877202 | 01 eerste verdieping | 01 eerste verdieping | 0 | 850 | 2020 | 3.57742 | 1771 | BU-26 | Model Group:31_1A:877208
877517 | 02 tweede verdieping | 02 tweede verdieping | 3063 | 256 | 2807 | 13.6139 | 4850 | BU-40 | Model Group:BU-40:2712884 | Constraints - Top Constraint: Up to level: 02 tweede verdieping
880921 | 01 eerste verdieping | 01 eerste verdieping | 0 | 850 | 2020 | 3.57742 | 1771 | BU-26 | Model Group:31_1A:880927
881682 | 01 eerste verdieping | 01 eerste verdieping | 0 | 850 | 2020 | 3.57742 | 1771 | BU-26 | Model Group:31_1A:881688
881846 | 01 eerste verdieping | 01 eerste verdieping | 0 | 850 | 2020 | 0.82921 | 410.5 | BU-35 | Model Group:BU-35:2701985
891674 | 01 eerste verdieping | 01 eerste verdieping | 0 | 850 | 2020 | 3.57742 | 1771 | BU-26 | Model Group:31_1A:891680
891757 | 01 eerste verdieping | 01 eerste verdieping | 0 | 850 | 2020 | 1.16352 | 576 | BU-30 | Model Group:BU-30:2700215
891786 | 01 eerste verdieping | 01 eerste verdieping | 0 | 850 | 2020 | 3.57742 | 1771 | BU-26 | Model Group:31_1A:891792
891903 | 01 eerste verdieping | 01 eerste verdieping | 0 | 850 | 2020 | 3.57742 | 1771 | BU-26 | Model Group:31_1A:891909
891925 | 01 eerste verdieping | 01 eerste verdieping | 0 | 850 | 2020 | 3.57742 | 1771 | BU-26 | Model Group:31_1A:891931
891975 | 01 eerste verdieping | 01 eerste verdieping | 0 | 850 | 2020 | 3.57742 | 1771 | BU-26 | Model Group:31_1A:891981
891997 | 01 eerste verdieping | 01 eerste verdieping | 0 | 262 | 2608 | 4.61877 | 1771 | BU-32 | Model Group:BU-32:892003
892038 | 00 begane grond | 00 begane grond | 2991 | -17 | 3008 | 2.7072 | 900 | BU-07 | Model Group:BU-07 b900:894363 | Constraints - Top Constraint: Up to level: 00 begane grond
894428 | 00 begane grond | 00 begane grond | 2991 | -17 | 3008 | 5.4144 | 1800 | BU-06 | Model Group:BU-06 b1800:894434 | Constraints - Top Constraint: Up to level: 00 begane grond
1220070 | 00 begane grond | 00 begane grond | 2991 | -17 | 3008 | 6.3168 | 2100 | BU-08 | Model Group:BU-08 b2100:1220076 | Constraints - Top Constraint: Up to level: 00 begane grond
1220169 | 00 begane grond | 00 begane grond | 2991 | -17 | 3008 | 4.512 | 1500 | BU-09 | Model Group:BU-09 b1500:1220175 | Constraints - Top Constraint: Up to level: 00 begane grond
1220847 | 00 begane grond | 00 begane grond | 2991 | -17 | 3008 | 9.024 | 3000 | BU-11 | Model Group:BU-11 b3000:1220846 | Constraints - Top Constraint: Up to level: 00 begane grond
1300401 | 00 begane grond | 00 begane grond | 2991 | -17 | 3008 | 2.7072 | 900 | BU-07 | Model Group:BU-07 b900 (members excluded):1300407 | Constraints - Top Constraint: Up to level: 00 begane grond
1300453 | 00 begane grond | 00 begane grond | 2991 | -17 | 3008 | 8.1216 | 2700 | BU-22 | Model Group:BU-22 b2700:1300414 | Constraints - Top Constraint: Up to level: 00 begane grond
1300742 | 00 begane grond | 00 begane grond | 2991 | -17 | 3008 | 8.92173 | 2966 | BU-21 | Model Group:BU-21 b2966:1300741 | Constraints - Top Constraint: Up to level: 00 begane grond
1300954 | 00 begane grond | 00 begane grond | 2991 | -17 | 3008 | 9.9264 | 3300 | BU-20 | Model Group:BU-20 b3300:1300930 | Constraints - Top Constraint: Up to level: 00 begane grond
1300992 | 00 begane grond | 00 begane grond | 2991 | -17 | 3008 | 4.2864 | 1425 | BU-23 | Model Group:BU-23 b1353:2651710 | Constraints - Top Constraint: Up to level: 00 begane grond
1302054 | 01 eerste verdieping | 01 eerste verdieping | 2870 | 243 | 2627 | 4.65242 | 1771 | BU-31 | Model Group:BU-31:891953 | Constraints - Top Constraint: Up to level: 01 eerste verdieping
1493475 | 00 begane grond | 00 begane grond | 2991 | -17 | 3008 | 8.89014 | 2955.5 | BU-25 | Model Group:BU-25 b3000:1493474 | Constraints - Top Constraint: Up to level: 00 begane grond
1494105 | 00 begane grond | 00 begane grond | 2991 | -17 | 3008 | 12.5584 | 4175 | BU-02 | Model Group:BU-02 b4200:1494104 | Constraints - Top Constraint: Up to level: 00 begane grond
1494514 | 00 begane grond | 00 begane grond | 2991 | -17 | 3008 | 9.024 | 3000 | BU-14 | Model Group:BU-14 b3000:1494513 | Constraints - Top Constraint: Up to level: 00 begane grond
1502981 | 00 begane grond | 00 begane grond | 2991 | -17 | 3008 | 2.7072 | 900 | BU-07 | Model Group:BU-07 b900:1502980 | Constraints - Top Constraint: Up to level: 00 begane grond
1817349 | 00 begane grond | 00 begane grond | 2991 | -17 | 3008 | 12.5584 | 4175 | BU-12 | Model Group:BU-12 b4200:1817348 | Constraints - Top Constraint: Up to level: 00 begane grond
1818869 | 00 begane grond | 00 begane grond | 2991 | -17 | 3008 | 15.04 | 5000 | BU-03 | Model Group:BU-03 b5800:1818868 | Constraints - Top Constraint: Up to level: 00 begane grond
1819902 | 00 begane grond | 00 begane grond | 2991 | -37 | 3028 | 6.09385 | 2012.5 | BU-05 | Model Group:BU-05 b1910:2648634 | Constraints - Top Constraint: Up to level: 00 begane grond
1822151 | 00 begane grond | 00 begane grond | 2991 | -17 | 3008 | 5.4144 | 1800 | BU-10 | Model Group:BU-10 b1800:1822150 | Constraints - Top Constraint: Up to level: 00 begane grond
1823298 | 00 begane grond | 00 begane grond | 2991 | -17 | 3008 | 12.5584 | 4175 | BU-15 | Model Group:BU-15 b4200:1823297 | Constraints - Top Constraint: Up to level: 00 begane grond
1853992 | 00 begane grond | 00 begane grond | 2991 | -17 | 3008 | 9.03152 | 3002.5 | BU-18 | Model Group:BU-18 b3017:2651211 | Constraints - Top Constraint: Up to level: 00 begane grond
1854929 | 00 begane grond | 00 begane grond | 2991 | -17 | 3008 | 6.43411 | 2139 | BU-19 | Model Group:BU-19 b2067:2651286 | Constraints - Top Constraint: Up to level: 00 begane grond
1862275 | 00 begane grond | 00 begane grond | 2991 | 370 | 2621 | 8.6493 | 3300 | BU-13 | Model Group:BU-13 b3300:1862274 | Constraints - Top Constraint: Up to level: 00 begane grond
1864614 | 01 eerste verdieping | 01 eerste verdieping | 0 | 850 | 2020 | 3.57742 | 1771 | BU-29 | Model Group:31_1A SVGD L:1864620
1864932 | 01 eerste verdieping | 01 eerste verdieping | 0 | 850 | 2020 | 3.57742 | 1771 | BU-28B | Model Group:31_1A DK R:1864938
1864976 | 01 eerste verdieping | 01 eerste verdieping | 0 | 850 | 2020 | 3.57742 | 1771 | BU-29A | Model Group:31_1A DKD L:1864982
1865001 | 01 eerste verdieping | 01 eerste verdieping | 0 | 850 | 2020 | 3.57742 | 1771 | BU-28B | Model Group:31_1A DK R:1865007
1865024 | 01 eerste verdieping | 01 eerste verdieping | 0 | 850 | 2020 | 3.57742 | 1771 | BU-29A | Model Group:31_1A DKD L:1865030
1865340 | 01 eerste verdieping | 01 eerste verdieping | 0 | 850 | 2020 | 3.57742 | 1771 | BU-28A | Model Group:31_1A DKD R:1865346
1865361 | 01 eerste verdieping | 01 eerste verdieping | 0 | 850 | 2020 | 3.57742 | 1771 | BU-29B | Model Group:31_1A DK L:1865367
1865568 | 01 eerste verdieping | 01 eerste verdieping | 0 | 850 | 2020 | 3.57742 | 1771 | BU-28A | Model Group:31_1A DKD R:1865574
1865602 | 01 eerste verdieping | 01 eerste verdieping | 0 | 850 | 2020 | 3.57742 | 1771 | BU-28A | Model Group:31_1A DKD R:1865608
1865649 | 01 eerste verdieping | 01 eerste verdieping | 0 | 850 | 2020 | 3.57742 | 1771 | BU-29B | Model Group:31_1A DK L:1865655
1865668 | 01 eerste verdieping | 01 eerste verdieping | 0 | 850 | 2020 | 3.57742 | 1771 | BU-29B | Model Group:31_1A DK L:1865674
1865775 | 01 eerste verdieping | 01 eerste verdieping | 0 | 850 | 2020 | 3.57742 | 1771 | BU-28A | Model Group:31_1A DKD R:1865781
1865796 | 01 eerste verdieping | 01 eerste verdieping | 0 | 850 | 2020 | 3.57742 | 1771 | BU-29B | Model Group:31_1A DK L:1865802
1865917 | 01 eerste verdieping | 01 eerste verdieping | 0 | 850 | 2020 | 3.57742 | 1771 | BU-28B | Model Group:31_1A DK R:1865923
1865940 | 01 eerste verdieping | 01 eerste verdieping | 0 | 850 | 2020 | 3.57742 | 1771 | BU-29A | Model Group:31_1A DKD L:1865946
1866076 | 01 eerste verdieping | 01 eerste verdieping | 0 | 850 | 2020 | 3.57742 | 1771 | BU-29C | Model Group:31_1A DKg R:1866082
1867671 | 02 tweede verdieping | 02 tweede verdieping | 0 | 673 | 2390 | 2.0315 | 850 | BU-39A | Model Group:31_2A DK R:1867677
1869339 | 02 tweede verdieping | 02 tweede verdieping | 0 | 673 | 2390 | 2.0315 | 850 | BU-39A | Model Group:31_2A DK R:1869345
1869356 | 02 tweede verdieping | 02 tweede verdieping | 0 | 673 | 2390 | 2.0315 | 850 | BU-39A | Model Group:31_2A DK R:1869362
1869373 | 02 tweede verdieping | 02 tweede verdieping | 0 | 673 | 2390 | 2.0315 | 850 | BU-39A | Model Group:31_2A DK R:1869379
1869390 | 02 tweede verdieping | 02 tweede verdieping | 0 | 673 | 2390 | 2.0315 | 850 | BU-39A | Model Group:31_2A DK R:1869396
1869407 | 02 tweede verdieping | 02 tweede verdieping | 0 | 673 | 2390 | 2.0315 | 850 | BU-39A | Model Group:31_2A DK R:1869413
1869424 | 02 tweede verdieping | 02 tweede verdieping | 0 | 673 | 2390 | 2.0315 | 850 | BU-39A | Model Group:31_2A DK R:1869430
1869441 | 02 tweede verdieping | 02 tweede verdieping | 0 | 673 | 2390 | 2.0315 | 850 | BU-39A | Model Group:31_2A DK R:1869447
1869461 | 02 tweede verdieping | 02 tweede verdieping | 0 | 673 | 2390 | 2.0315 | 850 | BU-39B | Model Group:31_2A DK L:1869467
1869600 | 02 tweede verdieping | 02 tweede verdieping | 0 | 673 | 2390 | 2.0315 | 850 | BU-39B | Model Group:31_2A DK L:1869606
1869617 | 02 tweede verdieping | 02 tweede verdieping | 0 | 673 | 2390 | 2.0315 | 850 | BU-39B | Model Group:31_2A DK L:1869623
1869634 | 02 tweede verdieping | 02 tweede verdieping | 0 | 673 | 2390 | 2.0315 | 850 | BU-39B | Model Group:31_2A DK L:1869640
1869651 | 02 tweede verdieping | 02 tweede verdieping | 0 | 673 | 2390 | 2.0315 | 850 | BU-39B | Model Group:31_2A DK L:1869657
1869668 | 02 tweede verdieping | 02 tweede verdieping | 0 | 673 | 2390 | 2.0315 | 850 | BU-39B | Model Group:31_2A DK L:1869674
1869685 | 02 tweede verdieping | 02 tweede verdieping | 0 | 673 | 2390 | 2.0315 | 850 | BU-39B | Model Group:31_2A DK L:1869691
1869702 | 02 tweede verdieping | 02 tweede verdieping | 0 | 673 | 2390 | 2.0315 | 850 | BU-39B | Model Group:31_2A DK L:1869708
1869721 | 02 tweede verdieping | 02 tweede verdieping | 0 | 673 | 2390 | 2.0315 | 850 | BU-39B | Model Group:31_2A DK L:1869727
1869738 | 02 tweede verdieping | 02 tweede verdieping | 0 | 673 | 2390 | 2.0315 | 850 | BU-39B | Model Group:31_2A DK L:1869744
1869755 | 02 tweede verdieping | 02 tweede verdieping | 0 | 673 | 2390 | 2.0315 | 850 | BU-39A | Model Group:31_2A DK R:1869761
1869772 | 02 tweede verdieping | 02 tweede verdieping | 0 | 673 | 2390 | 2.0315 | 850 | BU-39A | Model Group:31_2A DK R:1869778
1869791 | 02 tweede verdieping | 02 tweede verdieping | 0 | 673 | 2390 | 2.0315 | 850 | BU-39A | Model Group:31_2A DK R:1869797
1869808 | 02 tweede verdieping | 02 tweede verdieping | 0 | 673 | 2390 | 2.0315 | 850 | BU-39A | Model Group:31_2A DK R:1869814
1869825 | 02 tweede verdieping | 02 tweede verdieping | 0 | 673 | 2390 | 2.0315 | 850 | BU-39A | Model Group:31_2A DK R:1869831
1869842 | 02 tweede verdieping | 02 tweede verdieping | 0 | 673 | 2390 | 2.0315 | 850 | BU-39A | Model Group:31_2A DK R:1869848
1897632 | 00 begane grond | 00 begane grond | 2991 | -17 | 3008 | 2.7072 | 900 | BU-07 | Model Group:BU-07 b900 (members excluded):1300686 | Constraints - Top Constraint: Up to level: 00 begane grond
1897646 | 00 begane grond | 00 begane grond | 2991 | -17 | 3008 | 2.7072 | 900 | BU-07 | Model Group:BU-07 b900 (members excluded):1818605 | Constraints - Top Constraint: Up to level: 00 begane grond
1898039 | 01 eerste verdieping | 01 eerste verdieping | 0 | 850 | 2020 | 3.57742 | 1771 | BU-28A | Model Group:31_1A DKD R:1898045
1932979 | 00 begane grond | 00 begane grond | 2991 | -17 | 3008 | 9.024 | 3000 | BU-17 | Model Group:BU-17 b3000:1900158 | Constraints - Top Constraint: Up to level: 00 begane grond
2012525 | 01 eerste verdieping | 01 eerste verdieping | 0 | 850 | 2020 | 3.57742 | 1771 | BU-29A | Model Group:31_1A DKD L:2012531
2012555 | 01 eerste verdieping | 01 eerste verdieping | 0 | 850 | 2020 | 3.57742 | 1771 | BU-29A | Model Group:31_1A DKD L:2012561
2012570 | 01 eerste verdieping | 01 eerste verdieping | 0 | 900 | 1970 | 3.48887 | 1771 | BU-38 | Model Group:BU-38:2702101
2172430 | 01 eerste verdieping | 01 eerste verdieping | 0 | 850 | 2020 | 3.57742 | 1771 | BU-27 | Model Group:31_1A SVGD R:2172436
2182229 | 03 derde verdieping | 03 derde verdieping | 1400 | 400 | 1000 | 5.906 | 5906 | BU-44 | Model Group:daklicht A1:2182252 | Constraints - Top Constraint: Up to level: 03 derde verdieping
2182282 | 03 derde verdieping | 03 derde verdieping | 1400 | 400 | 1000 | 5.906 | 5906 | BU-44 | Model Group:daklicht A1 (members excluded):2182288 | Constraints - Top Constraint: Up to level: 03 derde verdieping
2182302 | 03 derde verdieping | 03 derde verdieping | 1400 | 400 | 1000 | 6.025 | 6025 | BU-42 | Model Group:31_daklicht_B (members excluded):2194619 | Constraints - Top Constraint: Up to level: 03 derde verdieping
2194629 | 03 derde verdieping | 03 derde verdieping | 1400 | 400 | 1000 | 5.8425 | 5842.5 | BU-43 | Model Group:31_daklicht_C:2194635 | Constraints - Top Constraint: Up to level: 03 derde verdieping
2194776 | 03 derde verdieping | 03 derde verdieping | 1400 | 400 | 1000 | 6.025 | 6025 | BU-42 | Model Group:31_daklicht_B:2194786 | Constraints - Top Constraint: Up to level: 03 derde verdieping
2194787 | 03 derde verdieping | 03 derde verdieping | 1400 | 400 | 1000 | 5.8425 | 5842.5 | BU-43 | Model Group:31_daklicht_C:2194793 | Constraints - Top Constraint: Up to level: 03 derde verdieping
2245638 | 01 eerste verdieping | 01 eerste verdieping | 0 | 850 | 2020 | 2.43713 | 1206.5 | BU-33 | Model Group:BU-33:2700705
2245686 | 01 eerste verdieping | 01 eerste verdieping | 0 | 850 | 2020 | 1.83921 | 910.5 | BU-34 | Model Group:BU-34:2700766
2266685 | 01 eerste verdieping | 01 eerste verdieping | 0 | 850 | 2020 | 3.57742 | 1771 | BU-29B | Model Group:31_1A DK L:2266691
2266702 | 02 tweede verdieping | 02 tweede verdieping | 0 | 673 | 2390 | 2.0315 | 850 | BU-39B | Model Group:31_2A DK L:2266708
2266717 | 02 tweede verdieping | 02 tweede verdieping | 0 | 673 | 2390 | 2.0315 | 850 | BU-39A | Model Group:31_2A DK R:2266723
2649834 | 00 begane grond | 00 begane grond | 2991 | -17 | 3008 | 12.5584 | 4175 | BU-47 | Model Group:BU-47 b4200:1822720 | Constraints - Top Constraint: Up to level: 00 begane grond
2652544 | 00 begane grond | 00 begane grond | 2991 | -17 | 3008 | 9.024 | 3000 | BU-11 | Model Group:BU-11 b3000:1502212 | Constraints - Top Constraint: Up to level: 00 begane grond
2652630 | 00 begane grond | 00 begane grond | 2991 | -17 | 3008 | 9.024 | 3000 | BU-11 | Model Group:BU-11 b3000:1502763 | Constraints - Top Constraint: Up to level: 00 begane grond
2712306 | 01 eerste verdieping | 01 eerste verdieping | 0 | 850 | 2020 | 2.43713 | 1206.5 | BU-36 | Model Group:BU-36:2701416
2712495 | 01 eerste verdieping | 01 eerste verdieping | 0 | 850 | 2020 | 0.82921 | 410.5 | BU-37 | Model Group:BU-37:2712501
2760155 | 01 eerste verdieping | 01 eerste verdieping | 0 | 850 | 2020 | 2.43713 | 1206.5 | BU-33 | Model Group:BU-33:2712443
2776730 | 01 eerste verdieping | 01 eerste verdieping | 0 | 850 | 2020 | 3.57742 | 1771 | BU-29 | Model Group:31_1A SVGD L:2776736
3003068 | 00 begane grond | 00 begane grond | 2991 | -17 | 3008 | 6.76499 | 2249 | BU-01 | Model Group:BU-01 b1500:3003067 | Constraints - Top Constraint: Up to level: 00 begane grond
3016883 | 00 begane grond | 00 begane grond | 2991 | -17 | 3008 | 2.72224 | 905 | BU-24 | Constraints - Top Constraint: Up to level: 00 begane grond
3058230 | 01 eerste verdieping | 01 eerste verdieping | 0 | 850 | 2020 | 3.57742 | 1771 | BU-28A | Model Group:31_1A DKD R:3058236
3451930 | 00 begane grond | 00 begane grond | 2991 | 370 | 2621 | 2.3589 | 900 | BU-45 | Model Group:BU-45 b900:2546304 | Constraints - Top Constraint: Up to level: 00 begane grond
3702020 | 00 begane grond | 00 begane grond | 2991 | -17 | 3008 | 7.38765 | 2456 | BU-04 | Model Group:BU-04 b2500:1820005 | Constraints - Top Constraint: Up to level: 00 begane grond
3836657 | 00 begane grond | 00 begane grond | 2991 | -37 | 3028 | 5.96994 | 1971.58 | BU-16 | Model Group:BU-16:3836676 | Constraints - Top Constraint: Up to level: 00 begane grond
4196773 | 00 begane grond | 00 begane grond | 2991 | -37 | 3028 | 3.74261 | 1236 | BU-46 | Model Group:BU-46:4200502 | Constraints - Top Constraint: Up to level: 00 begane grond

# IfcCurtainWall: Curtain Wall:RSen_21_CWA_continuous louvre wall - DucoWall screening 70/75Z with 40/21-double support profile_gen_duco projects (7)
In: 01 eerste verdieping
Type - General - Edition number: 1
Type - Model Properties - WT_I Acoustic attenuation Rw (C,Ctr): n\a; WT_I Physical free area: 37; WT_I Visual free area: 53; WT_I Weather performance_v 0.5m/s: B; WT_I Weather performance_v 0m/s: A; WT_I Weather performance_v 1.5m/s: C; WT_I Weather performance_v 1m/s: C; WT_I Weather performance_v 2.5m/s: D; WT_I Weather performance_v 2m/s: D; WT_V K factor_exhaust: 25.00; WT_V K factor_intake: 30.20
Type - Vertical Mullions - Border 1 Type: Rectangular Mullion : RSen_21_CWM_support profile - 40x70-double - right_gen_duco projects; Border 2 Type: Rectangular Mullion : RSen_21_CWM_support profile - 40x70-double - left_gen_duco projects; Interior Type: Rectangular Mullion : RSen_21_CWM_support profile - 40x70-double_gen_duco projects
Type - Horizontal Grid - Adjust for Mullion Size: no; Layout: Fixed Distance; Spacing: 6000 mm
Type - Vertical Grid - Adjust for Mullion Size: no; Layout: Maximum Spacing; Spacing: 2000 mm
Type - Materials and Finishes - RSen_C_material_01: Aluminum - Duco - Anodized Silver; RSen_C_material_01_description: blade; RSen_C_material_02: Aluminum - Duco - Anodized Silver; RSen_C_material_02_description: support profile
Type - Construction - Function: Exterior; Automatically Embed: yes; Join Condition: Border and Vertical Grid Continuous; Curtain Panel: Screening 70-75 : Screening 70-75
Type - Identity Data - Workset: Curtain Wall Types; Assembly Code: B20; Description: duco projects_continuous louvre wall - ducowall 70/75Z with 40/21-double; Keynote: 10210; Manufacturer: Duco Projects; Model: screening 70/75Z with 40/21-double; RSen_C_code_gtin: -; RSen_C_content_provider: Duco Projects; RSen_C_model: DucoWall; RSen_C_type: screening 70/75Z with 40/21-double; RSen_C_type_comments: continuous louvre wall; Type Comments: continuous louvre wall; Type Name: RSen_21_CWA_continuous louvre wall - DucoWall screening 70/75Z with 40/21-double support profile_gen_duco projects; URL: http://www.duco.eu/en-gb-products/intensive-ventilation/continuous-louvre-walls; WT_I BaseKeynote: 21.1
Type - Other - Category: Walls; Family Name: Curtain Wall
Classification: B20 Uniformat (Uniformat)
Cross-Section Definition - Cross-Section: Vertical
Horizontal Grid - Angle: 0 deg; Justification: Beginning; Offset: 0 mm
Constraints - Base is Attached: no; Related to Mass: no; Room Bounding: yes; Top is Attached: no; Base Constraint: 01 eerste verdieping; Top Constraint: Up to level: 01 eerste verdieping; Top Offset: 2877 mm
Phasing - Phase Created: 2. nieuwbouw
Structural - Enable Analytical Model: no; Structural: no; Structural Usage: Non-bearing
Identity Data - Workset: Workset1
Other - Family: Curtain Wall; Family and Type: Curtain Wall: RSen_21_CWA_continuous louvre wall - DucoWall screening 70/75Z with 40/21-double support profile_gen_duco projects; Type: RSen_21_CWA_continuous louvre wall - DucoWall screening 70/75Z with 40/21-double support profile_gen_duco projects; Type Id: 3247639
Name (Curtain Wall:RSen_21_CWA_continuous louvre wall - DucoWall screening 70/75Z with 40/21-double support profile_gen_duco projects:...) | Horizontal Grid, Number | Angle (deg) = Offset (mm) | Justification | Vertical Grid, Number | Base Offset (mm) | Unconnected Height (mm) | Area (m2) | Length (mm)
2178599 | 28 | 0 | Beginning | 4 | 820 | 2057 | 3.6306 | 1765
2179969 | 28 | 0 | Beginning | 4 | 820 | 2057 | 0.294151 | 143
2551643 | 28 | 0 | Beginning | 4 | 820 | 2057 | 0.620357 | 301.583
2551798 | 34 | 0 | Beginning | 4 | 310 | 2567 | 3.61947 | 1410
2551890 | 34 | 0 | Beginning | 4 | 310 | 2567 | 1.51581 | 590.5
3195265 | 34 | 0 | Beginning | 4 | 310 | 2567 | 2.95975 | 1153
3256902 | 4 |  |  |  | 820 | 2057 | 3.63061 | 1765 | Horizontal Grid - sets with these values: 2

# IfcCurtainWall: Curtain Wall:railing 120x40 (6)
Type - Horizontal Mullions - Border 1 Type: Rectangular Mullion : 40x120 railing; Border 2 Type: Rectangular Mullion : 40x120 railing; Interior Type: Rectangular Mullion : 40x120 railing
Type - Vertical Mullions - Border 1 Type: Rectangular Mullion : 40x120 railing; Border 2 Type: Rectangular Mullion : 40x120 railing; Interior Type: Rectangular Mullion : 40x120 railing
Type - Horizontal Grid - Adjust for Mullion Size: no
Type - Vertical Grid - Adjust for Mullion Size: no; Spacing: 1800 mm
Type - Construction - Function: Exterior; Automatically Embed: no; Join Condition: Not Defined; Curtain Panel: Empty System Panel : leeg
Type - Identity Data - Workset: Curtain Wall Types; Type Name: railing 120x40
Type - Other - Category: Walls; Family Name: Curtain Wall
Cross-Section Definition - Cross-Section: Vertical
Horizontal Grid - Angle: 0 deg; Justification: Beginning; Number: 4; Offset: 0 mm
Constraints - Base is Attached: no; Related to Mass: no; Room Bounding: yes; Top is Attached: no; Top Constraint: Up to level: 02 tweede verdieping; Top Offset: 1280 mm
Phasing - Phase Created: 2. nieuwbouw
Structural - Enable Analytical Model: no; Structural: no; Structural Usage: Non-bearing
Identity Data - Workset: Workset1
Other - Family: Curtain Wall; Family and Type: Curtain Wall: railing 120x40; Type: railing 120x40; Type Id: 3263912
Name (Curtain Wall:railing 120x40:...) | In | Base Constraint | Base Offset (mm) | Unconnected Height (mm) | Area (m2) | Length (mm) | sets with these values
3262497 | 01 eerste verdieping | 01 eerste verdieping | 450 | 4630 | 9.19672 | 9015 | Vertical Grid - Angle: 0 deg; Justification: Beginning; Offset: 0 mm; Number: 5
3265965 | 02 tweede verdieping | 02 tweede verdieping | 233 | 1047 | 7.38659 | 7055 | 2
3270773 | 02 tweede verdieping | 02 tweede verdieping | 233 | 1047 | 1.79309 | 1765 | 2
3270779 | 02 tweede verdieping | 02 tweede verdieping | 233 | 1047 | 0.612045 | 584.57 | 2
3270785 | 02 tweede verdieping | 02 tweede verdieping | 233 | 1047 | 22.0341 | 21045 | 2
3270789 | 02 tweede verdieping | 02 tweede verdieping | 233 | 1047 | 4.06236 | 3880 | 2

# IfcDistributionPort (54)
Description: Flow
Name | FlowDirection
OutPort_1291628_4 | SOURCE
InPort_1291628_5 | SINK
InPort_1291628_6 | SINK
OutPort_1508872_4 | SOURCE
InPort_1508872_5 | SINK
InPort_1508872_6 | SINK
OutPort_1512360_4 | SOURCE
InPort_1512360_5 | SINK
InPort_1512360_6 | SINK
OutPort_1512564_4 | SOURCE
InPort_1512564_5 | SINK
InPort_1512564_6 | SINK
OutPort_1512620_4 | SOURCE
InPort_1512620_5 | SINK
InPort_1512620_6 | SINK
OutPort_1518944_4 | SOURCE
InPort_1518944_5 | SINK
InPort_1518944_6 | SINK
OutPort_1518992_4 | SOURCE
InPort_1518992_5 | SINK
InPort_1518992_6 | SINK
OutPort_1519494_4 | SOURCE
InPort_1519494_5 | SINK
InPort_1519494_6 | SINK
OutPort_1526379_4 | SOURCE
InPort_1526379_5 | SINK
InPort_1526379_6 | SINK
InPort_1808008_1 | SINK
OutPort_1808008_2 | SOURCE
InPort_1811464_1 | SINK
OutPort_1811464_2 | SOURCE
InPort_1814539_1 | SINK
InPort_1890558_1 | SINK
InPort_1932373_1 | SINK
InPort_1932698_1 | SINK
OutPort_1991821_4 | SOURCE
InPort_1991821_5 | SINK
InPort_1991821_6 | SINK
OutPort_2000490_4 | SOURCE
InPort_2000490_5 | SINK
InPort_2000490_6 | SINK
InPort_2204706_1 | SINK
OutPort_2437037_4 | SOURCE
InPort_2437037_5 | SINK
InPort_2437037_6 | SINK
InPort_2544580_1 | SINK
OutPort_2544580_2 | SOURCE
Port_2544580_3 | SOURCEANDSINK
OutPort_2544603_4 | SOURCE
Port_2544603_5 | SOURCEANDSINK
OutPort_4193503_4 | SOURCE
InPort_4193503_5 | SINK
InPort_4193503_6 | SINK
InPort_5033578_1 | SINK

# IfcDoor: 300_32_ISR_samenstelling_binnenkozijn_hout:dubbele deur (3)
Type - ConstructionType: USERDEFINED; ParameterTakesPrecedence: no; Sizeable: no; Material: n6_binnenkozijn
Type - Analytical Properties - Define Thermal Properties by: Schematic Type; Analytic Construction: <None>
Type - Constraints - Default Elevation: 0 mm
Type - Graphics - dubbele_deur: yes; Vlak B1: Panel : dubbel glas; deur_type: 32_ISR_onderdeel_deur : dichte deur
Type - Construction - Function: Interior; Construction Type: binnenkozijn hout
Type - Dimensions - tong_naald: 2 mm
Type - Identity Data - Workset: Family : Doors : 300_32_ISR_samenstelling_binnenkozijn_hout; Assembly Code: 2E(32.31.21); Datum_Gewijzigd: 14-11-2012; Description: binnendeur dubbel; Model: LOD300; SmartRevit_Versie: 2013.2; Type Comments: samenstelling; Type Mark: 44; Type Name: dubbele deur
Type - Other - Category: Doors; Family Name: 300_32_ISR_samenstelling_binnenkozijn_hout
Classification: 2E(32.31.21) Uniformat (Uniformat)
Fire Protection - brandwerendheid_120min: no; brandwerendheid_30min: no; brandwerendheid_90min: no
Constraints - Moves With Nearby Elements: no; Offset from Host: 0 mm
Phasing - Phase Created: 2. nieuwbouw
Graphics - WBDBO_tekst_andere_zijde: no; dorpel: no
Construction - stijl_breedte: 67 mm; stijl_diepte: 125 mm
Dimensions - deur_hoogte: 2315 mm; dikte_onderdorpel: 5 mm; ruimte_onder_deur: 20 mm
Identity Data - Workset: Workset1
Other - Family: 300_32_ISR_samenstelling_binnenkozijn_hout; berekende_ruimte_onder_deur: 20 mm; Family and Type: 300_32_ISR_samenstelling_binnenkozijn_hout: dubbele deur; stijl_lengte: 2337 mm; Type: dubbele deur; Type Id: 1416990
Name (300_32_ISR_samenstelling_binnenkozijn_hout:dubbele deur:...) | In | OverallHeight (mm) = kozijn_hoogte (mm) = Height (mm) | OverallWidth (mm) = kozijn_breedte (mm) = Width (mm) | zelfsluitend = brandwerendheid_60min | Level | deur_breedte (mm) | Host | Area (m2) | sponning_breedte (mm) | sponning_diepte (mm) | Thickness (mm) | Volume (m3) | Mark | berekende_deur_breedte (mm) | deur_offset (mm) | positie_deur (mm)
1763187 | 00 begane grond | 2387 | 1906 | no | 00 begane grond | 900 | Basic Wall : 22_WA_binnenwand_ms350 25-300-25 _gen_bdg | 1.51566 | 17 | 50 | 40 | 0.0493437 | 378 | 1802 | 451 | 52
2089377 | 02 tweede verdieping | 2387 | 1906 | no | 02 tweede verdieping | 900 | Basic Wall : 22_WA_binnenwand_ms125 25-75-25 _gen_bdg | 1.51566 | 17 | 50 | 40 | 0.0493437 | 436 | 1802 | 451 | 52
3832978 | 00 begane grond | 2379 | 1950 | yes | 00 begane grond | 930 | Basic Wall : NLRS_22_WA_HSB bispouw 30-245-12-13 glaswol_gen_ISR | 1.52801 | 25 | 65 | 55 | 0.044511 | 391 | 1862 | 466 | 44

# IfcDoor: 300_32_ISR_samenstelling_binnenkozijn_hout:dubbele deur met glas (3)
In: 00 begane grond
Type - ConstructionType: USERDEFINED; ParameterTakesPrecedence: no; Sizeable: no; Material: n6_binnenkozijn
Type - Analytical Properties - Define Thermal Properties by: Schematic Type; Analytic Construction: <None>
Type - Constraints - Default Elevation: 0 mm
Type - Graphics - dubbele_deur: yes; Vlak B1: Panel : dubbel glas; deur_type: 32_ISR_onderdeel_deur : deur met glas
Type - Construction - Function: Interior; Construction Type: binnenkozijn hout
Type - Dimensions - tong_naald: 2 mm
Type - Identity Data - Workset: Family : Doors : 300_32_ISR_samenstelling_binnenkozijn_hout; Assembly Code: 2E(32.31.21); Datum_Gewijzigd: 14-11-2012; Description: binnendeur dubbel; Model: LOD300; SmartRevit_Versie: 2013.2; Type Comments: samenstelling; Type Mark: 42; Type Name: dubbele deur met glas
Type - Other - Category: Doors; Family Name: 300_32_ISR_samenstelling_binnenkozijn_hout
OverallHeight: 2387 mm; OverallWidth: 1934 mm; Classification: 2E(32.31.21) Uniformat (Uniformat)
Fire Protection - brandwerendheid_120min: no; brandwerendheid_30min: no; brandwerendheid_90min: no
Constraints - Level: 00 begane grond; Moves With Nearby Elements: no; Offset from Host: 0 mm; Host: Basic Wall : 22_WA_binnenwand_ms125 25-75-25 _gen_bdg; kozijn_breedte: 1934 mm
Phasing - Phase Created: 2. nieuwbouw
Graphics - WBDBO_tekst_andere_zijde: no; dorpel: no
Construction - kozijn_hoogte: 2387 mm; stijl_breedte: 67 mm; stijl_diepte: 125 mm
Dimensions - dikte_onderdorpel: 5 mm; Height: 2387 mm; ruimte_onder_deur: 20 mm; Width: 1934 mm
Identity Data - Workset: Workset1
Other - Family: 300_32_ISR_samenstelling_binnenkozijn_hout; berekende_ruimte_onder_deur: 20 mm; Family and Type: 300_32_ISR_samenstelling_binnenkozijn_hout: dubbele deur met glas; Type: dubbele deur met glas; Type Id: 1416987
Name (300_32_ISR_samenstelling_binnenkozijn_hout:dubbele deur met glas:...) | zelfsluitend | brandwerendheid_60min | deur_breedte (mm) | Area (m2) | deur_hoogte (mm) | sponning_breedte (mm) | sponning_diepte (mm) | Thickness (mm) | Volume (m3) | Mark | berekende_deur_breedte (mm) | deur_offset (mm) | positie_deur (mm) | stijl_lengte (mm)
1419328 | no | no | 914 | 1.52468 | 2315 | 17 | 50 | 40 | 0.0495544 | 303 | 1830 | 458 | 52 | 2337
1945806 | yes | yes | 922 | 1.52593 | 2323 | 25 | 65 | 55 | 0.044511 | 420 | 1846 | 462 | 44 | 2345
2719869 | yes | no | 914 | 1.52468 | 2315 | 17 | 50 | 40 | 0.0495544 | 451 | 1830 | 458 | 52 | 2337

# IfcDoor: 300_32_ISR_samenstelling_binnenkozijn_hout:enkele deur met glasstrook (14)
Type - ConstructionType: USERDEFINED; ParameterTakesPrecedence: no; Sizeable: no; Material: n6_binnenkozijn
Type - Analytical Properties - Define Thermal Properties by: Schematic Type; Analytic Construction: <None>
Type - Constraints - Default Elevation: 0 mm
Type - Graphics - dubbele_deur: no; deur_type: 32_ISR_onderdeel_deur : deur met glasstrook; Vlak B1: Panel : dubbel glas
Type - Construction - Function: Interior; Construction Type: binnenkozijn hout
Type - Dimensions - tong_naald: 2 mm
Type - Identity Data - Assembly Code: 2E(32.31.21); Datum_Gewijzigd: 14-11-2012; Description: binnendeur enkel; Model: LOD300; SmartRevit_Versie: 2013.2; Type Comments: samenstelling; Type Mark: 47; Type Name: enkele deur met glasstrook; Workset: Family : Doors : 300_32_ISR_samenstelling_binnenkozijn_hout
Type - Other - Category: Doors; Family Name: 300_32_ISR_samenstelling_binnenkozijn_hout
OverallHeight: 2387 mm; Classification: 2E(32.31.21) Uniformat (Uniformat)
Fire Protection - zelfsluitend: no; brandwerendheid_120min: no; brandwerendheid_30min: no; brandwerendheid_60min: no; brandwerendheid_90min: no
Constraints - Moves With Nearby Elements: no; Offset from Host: 0 mm
Phasing - Phase Created: 2. nieuwbouw
Graphics - WBDBO_tekst_andere_zijde: no; dorpel: no
Construction - kozijn_hoogte: 2387 mm; stijl_breedte: 67 mm; stijl_diepte: 125 mm
Dimensions - deur_hoogte: 2315 mm; dikte_onderdorpel: 5 mm; Height: 2387 mm; ruimte_onder_deur: 20 mm; sponning_breedte: 17 mm; sponning_diepte: 50 mm; Thickness: 40 mm
Identity Data - Workset: Workset1
Other - deur_offset: 0 mm; berekende_ruimte_onder_deur: 20 mm; Family: 300_32_ISR_samenstelling_binnenkozijn_hout; Family and Type: 300_32_ISR_samenstelling_binnenkozijn_hout: enkele deur met glasstrook; positie_deur: 52 mm; stijl_lengte: 2337 mm; Type: enkele deur met glasstrook; Type Id: 1417018
Name (300_32_ISR_samenstelling_binnenkozijn_hout:enkele deur met glasstrook:...) | In | OverallWidth (mm) = kozijn_breedte (mm) = Width (mm) | Level | deur_breedte (mm) = berekende_deur_breedte (mm) | Host | Area (m2) | Volume (m3) | Mark
1292037 | 02 tweede verdieping | 1034 | 02 tweede verdieping | 930 | Basic Wall : 22_WA_binnenwand_ms125 25-75-25 _gen_bdg | 1.23488 | 0.0427819 | 87
1294821 | 00 begane grond | 1034 | 00 begane grond | 930 | Basic Wall : 22_WA_binnenwand_ms125 25-75-25 _gen_bdg | 1.23488 | 0.0427819 | 192
1294864 | 00 begane grond | 1034 | 00 begane grond | 930 | Basic Wall : 22_WA_binnenwand_ms125 25-75-25 _gen_bdg | 1.23488 | 0.0427819 | 195
1366925 | 00 begane grond | 1034 | 00 begane grond | 930 | Basic Wall : 22_WA_binnenwand_ms205 25-75-5-75-25 _gen_bdg | 1.23488 | 0.0427819 | 219
1366962 | 00 begane grond | 1034 | 00 begane grond | 930 | Basic Wall : 22_WA_binnenwand_ms125 25-75-25 _gen_bdg | 1.23488 | 0.0427819 | 222
1366998 | 00 begane grond | 1034 | 00 begane grond | 930 | Basic Wall : 22_WA_binnenwand_ms125 25-75-25 _gen_bdg | 1.23488 | 0.0427819 | 225
1367105 | 00 begane grond | 1034 | 00 begane grond | 930 | Basic Wall : 22_WA_binnenwand_ms125 25-75-25 _gen_bdg | 1.23488 | 0.0427819 | 228
1367158 | 00 begane grond | 1034 | 00 begane grond | 930 | Basic Wall : 22_WA_binnenwand_ms125 25-75-25 _gen_bdg | 1.23488 | 0.0427819 | 231
1367240 | 00 begane grond | 1034 | 00 begane grond | 930 | Basic Wall : 22_WA_binnenwand_ms125 25-75-25 _gen_bdg | 1.23488 | 0.0427819 | 234
1367337 | 00 begane grond | 1034 | 00 begane grond | 930 | Basic Wall : 22_WA_binnenwand_ms125 25-75-25 _gen_bdg | 1.23488 | 0.0427819 | 240
1367458 | 00 begane grond | 1034 | 00 begane grond | 930 | Basic Wall : 22_WA_binnenwand_ms125 25-75-25 _gen_bdg | 1.23488 | 0.0427819 | 243
1371862 | 00 begane grond | 1134 | 00 begane grond | 1030 | Basic Wall : 22_WA_kalkzandsteen_120mm | 1.26708 | 0.0435344 | 270
1516491 | 02 tweede verdieping | 1034 | 02 tweede verdieping | 930 | Basic Wall : 22_WA_binnenwand_ms125 25-75-25 _gen_bdg | 1.23488 | 0.0427819 | 299
1878840 | 00 begane grond | 1034 | 00 begane grond | 930 | Level : 00 begane grond | 1.23488 | 0.0427819 | 405

# IfcDoor: 300_32_ISR_samenstelling_binnenkozijn_hout_met_zijlicht:dubbele deur met glas 1xZL (12)
Type - ConstructionType: USERDEFINED; ParameterTakesPrecedence: no; Sizeable: no; Material: n6_binnenkozijn
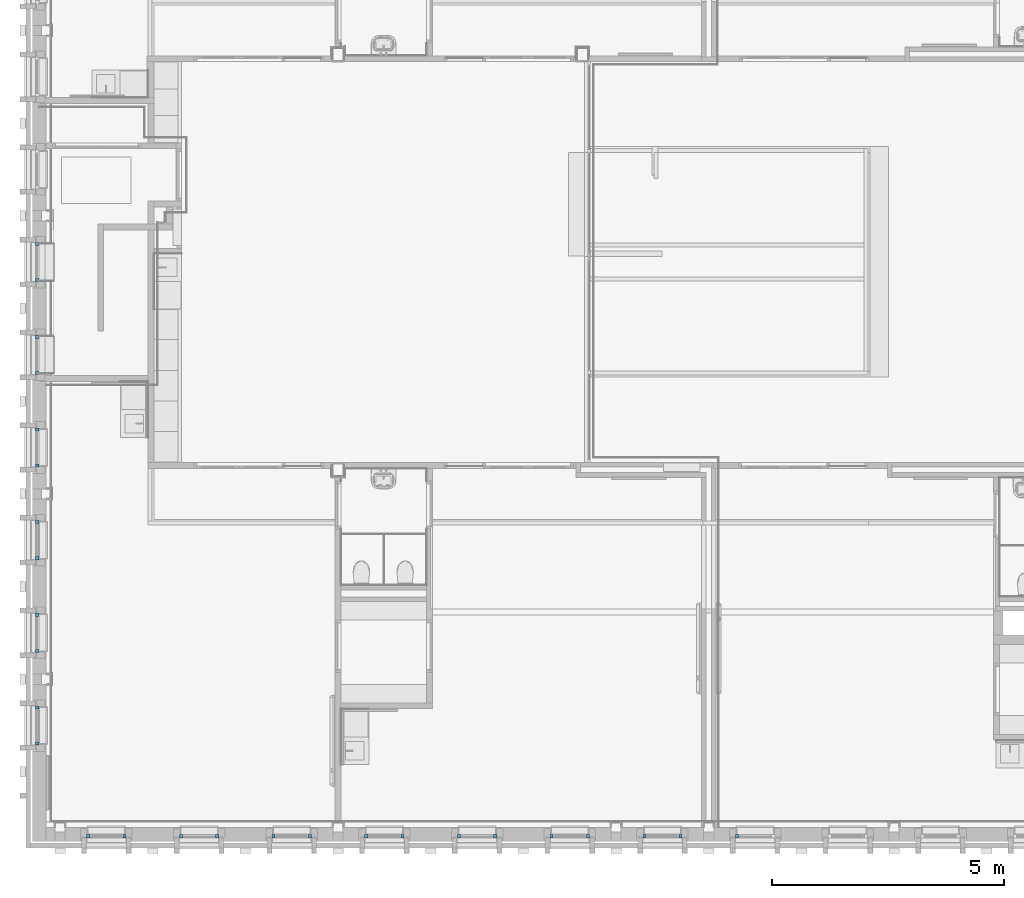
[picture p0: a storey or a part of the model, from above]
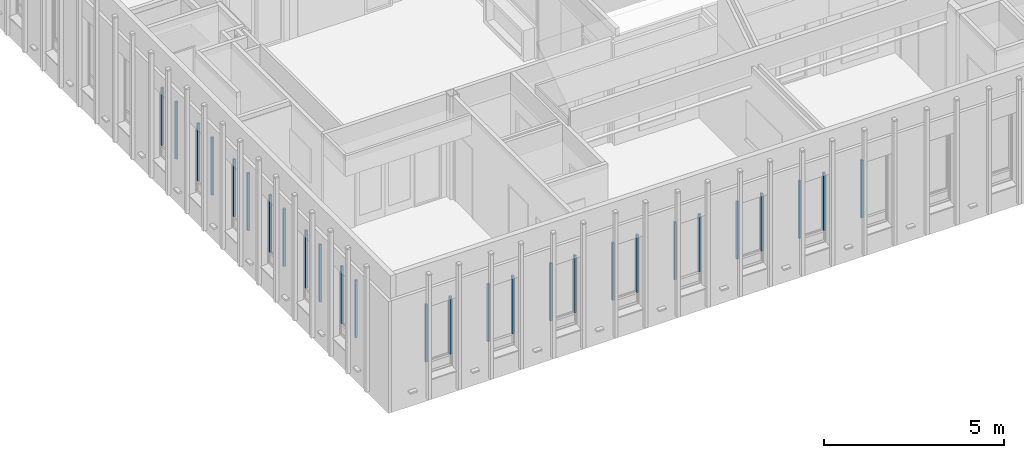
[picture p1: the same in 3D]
Properties of the parts of a building model (IFC2X3), part 8 of 94

# IfcDoor: 300_32_ISR_samenstelling_binnenkozijn_hout_met_zijlicht:dubbele deur met glas 1xZL (12)
Type - Analytical Properties - Define Thermal Properties by: Schematic Type; Analytic Construction: <None>
Type - Constraints - Default Elevation: 0 mm
Type - Materials and Finishes - glas_materiaal: ISR_Glas
Type - Graphics - dubbele_deur: yes; Vlak B1: Panel : dubbel glas; deur_type: 32_ISR_onderdeel_deur : deur met glas
Type - Construction - Function: Interior; Construction Type: binnenkozijn hout; stijl_breedte: 67 mm
Type - Dimensions - dikte_onderdorpel: 25 mm; tong_naald: 2 mm
Type - Identity Data - Workset: Family : Doors : 300_32_ISR_samenstelling_binnenkozijn_hout_met_zijlicht; Assembly Code: 2E(32.31.21); Datum_Gewijzigd: 14-11-2012; Description: binnendeur dubbel met zijlicht; Model: LOD300; SmartRevit_Versie: 2013.2; Type Comments: samenstelling; Type Mark: 33; Type Name: dubbele deur met glas 1xZL
Type - Other - Category: Doors; Family Name: 300_32_ISR_samenstelling_binnenkozijn_hout_met_zijlicht
OverallHeight: 2387 mm; Classification: 2E(32.31.21) Uniformat (Uniformat)
Fire Protection - zelfsluitend: no; brandwerendheid_120min: no; brandwerendheid_30min: no; brandwerendheid_60min: no; brandwerendheid_90min: no
Constraints - Moves With Nearby Elements: no; Offset from Host: 0 mm; deur_breedte: 930 mm
Phasing - Phase Created: 2. nieuwbouw
Graphics - dorpel: no; WBDBO_tekst_andere_zijde: yes; deur_LR_wisselen: no
Construction - kozijn_hoogte: 2387 mm; stijl_diepte: 125 mm; tussenstijl_breedte: 67 mm; tussenstijl_diepte: 125 mm
Dimensions - zijlicht_LR_verdelen: no; deur_hoogte: 2320 mm; Height: 2387 mm; ruimte_onder_deur: 15 mm; sponning_breedte: 17 mm; sponning_diepte: 50 mm; Thickness: 40 mm; Width: 1966 mm
Identity Data - Workset: Workset1
Other - deur_R: yes; Family: 300_32_ISR_samenstelling_binnenkozijn_hout_met_zijlicht; ts_delta: 0 mm; basis_breedte: 1966 mm; berekende_deur_breedte: 1862 mm; berekende_ruimte_onder_deur: 15 mm; deur_L: yes; deur_offset_l: 466 mm; deur_offset_r: 466 mm; Family and Type: 300_32_ISR_samenstelling_binnenkozijn_hout_met_zijlicht: dubbele deur met glas 1xZL; glas_hoogte: 2285 mm; ok_glas: 52 mm; positie_deur: 52 mm; positie_es_r: 983 mm; positie_ts: 949.5 mm; ref_onderdorpel: 33.5 mm; stijl_lengte: 2337 mm; Type: dubbele deur met glas 1xZL; Type Id: 1396174; void_es_r: 250 mm
Name (300_32_ISR_samenstelling_binnenkozijn_hout_met_zijlicht:dubbele deur met glas 1xZL:...) | In | OverallWidth (mm) | Level | Host | kozijn_breedte (mm) | zijlicht_breedte (mm) = zijlicht_lr_breedte (mm) | Area (m2) | Volume (m3) | Mark | positie_es_l (mm) | zijlicht_OD_lengte (mm) | zijlicht_pos (mm)
1419664 | 00 begane grond | 3764 | 00 begane grond | Basic Wall : 22_WA_binnenwand_ms125 25-75-25 _gen_bdg | 2890 | 891 | 3.01509 | 0.100844 | 313 | 1907 | 941 | 462
4001722 | 01 eerste verdieping | 3576 | 01 eerste verdieping | Basic Wall : 22_WA_binnenwand_ms125 25-75-25 _gen_bdg | 2796 | 797 | 2.96184 | 0.0987721 | 444 | 1813 | 847 | 415
4006592 | 01 eerste verdieping | 3576 | 01 eerste verdieping | Floor : NLRS_43_FL_cementdekvloer 50_gen_ISR | 2796 | 797 | 2.96184 | 0.0987721 | 446 | 1813 | 847 | 415
4006666 | 01 eerste verdieping | 3576 | 01 eerste verdieping | Floor : NLRS_43_FL_cementdekvloer 50_gen_ISR | 2796 | 797 | 2.96184 | 0.0987721 | 473 | 1813 | 847 | 415
4006701 | 01 eerste verdieping | 3576 | 01 eerste verdieping | Basic Wall : 22_WA_binnenwand_ms125 25-75-25 _gen_bdg | 2796 | 797 | 2.96184 | 0.0987721 | 483 | 1813 | 847 | 415
4006751 | 01 eerste verdieping | 3576 | 01 eerste verdieping | Floor : NLRS_43_FL_cementdekvloer 50_gen_ISR | 2796 | 797 | 2.96184 | 0.0987721 | 485 | 1813 | 847 | 415
4008222 | 02 tweede verdieping | 3576 | 02 tweede verdieping | Basic Wall : 21_WA_metselwerk_licht_100_gen_bdg | 2796 | 797 | 2.96184 | 0.0987721 | 493 | 1813 | 847 | 415
4008277 | 02 tweede verdieping | 3576 | 02 tweede verdieping | Floor : NLRS_43_FL_cementdekvloer 50_gen_ISR | 2796 | 797 | 2.96184 | 0.0987721 | 495 | 1813 | 847 | 415
4008306 | 02 tweede verdieping | 3576 | 02 tweede verdieping | Floor : NLRS_43_FL_cementdekvloer 50_gen_ISR | 2796 | 797 | 2.96184 | 0.0987721 | 500 | 1813 | 847 | 415
4008319 | 02 tweede verdieping | 3576 | 02 tweede verdieping | Basic Wall : 22_WA_binnenwand_ms125 25-75-25 _gen_bdg | 2796 | 797 | 2.96184 | 0.0987721 | 508 | 1813 | 847 | 415
4008390 | 02 tweede verdieping | 3576 | 02 tweede verdieping | Floor : NLRS_43_FL_cementdekvloer 50_gen_ISR | 2796 | 797 | 2.96184 | 0.0987721 | 510 | 1813 | 847 | 415
4008417 | 02 tweede verdieping | 3576 | 02 tweede verdieping | Floor : NLRS_43_FL_cementdekvloer 50_gen_ISR | 2796 | 797 | 2.96184 | 0.0987721 | 515 | 1813 | 847 | 415

# IfcDoor: 300_32_ISR_samenstelling_binnenkozijn_hout_met_zijlicht:enkele deur 1xZL (11)
Type - ConstructionType: USERDEFINED; ParameterTakesPrecedence: no; Sizeable: no; Material: n6_binnenkozijn
Type - Analytical Properties - Define Thermal Properties by: Schematic Type; Analytic Construction: <None>
Type - Constraints - Default Elevation: 0 mm
Type - Materials and Finishes - glas_materiaal: ISR_Glas
Type - Graphics - dubbele_deur: no; deur_type: 32_ISR_onderdeel_deur : dichte deur; Vlak B1: Panel : dubbel glas
Type - Construction - Function: Interior; Construction Type: binnenkozijn hout; stijl_breedte: 67 mm
Type - Dimensions - dikte_onderdorpel: 25 mm; tong_naald: 2 mm
Type - Identity Data - Assembly Code: 2E(32.31.21); Datum_Gewijzigd: 14-11-2012; Description: binnendeur enkel met zijlicht; Model: LOD300; SmartRevit_Versie: 2013.2; Type Comments: samenstelling; Type Mark: 32; Type Name: enkele deur 1xZL; Workset: Family : Doors : 300_32_ISR_samenstelling_binnenkozijn_hout_met_zijlicht
Type - Other - Category: Doors; Family Name: 300_32_ISR_samenstelling_binnenkozijn_hout_met_zijlicht
OverallHeight: 2387 mm; Classification: 2E(32.31.21) Uniformat (Uniformat)
Fire Protection - zelfsluitend: no; brandwerendheid_120min: no; brandwerendheid_30min: no; brandwerendheid_60min: no; brandwerendheid_90min: no
Constraints - Moves With Nearby Elements: no; Offset from Host: 0 mm; deur_breedte: 930 mm
Phasing - Phase Created: 2. nieuwbouw
Graphics - dorpel: no; deur_LR_wisselen: yes; WBDBO_tekst_andere_zijde: yes
Construction - kozijn_hoogte: 2387 mm; stijl_diepte: 125 mm; tussenstijl_breedte: 67 mm; tussenstijl_diepte: 125 mm
Dimensions - zijlicht_LR_verdelen: no; deur_hoogte: 2320 mm; Height: 2387 mm; ruimte_onder_deur: 15 mm; sponning_breedte: 17 mm; sponning_diepte: 50 mm; Thickness: 40 mm; Width: 1034 mm
Identity Data - Workset: Workset1
Other - basis_breedte: 1034 mm; berekende_deur_breedte: 930 mm; berekende_ruimte_onder_deur: 15 mm; deur_L: no; deur_offset_l: 0 mm; deur_offset_r: 0 mm; deur_R: yes; Family: 300_32_ISR_samenstelling_binnenkozijn_hout_met_zijlicht; Family and Type: 300_32_ISR_samenstelling_binnenkozijn_hout_met_zijlicht: enkele deur 1xZL; glas_hoogte: 2285 mm; ok_glas: 52 mm; positie_deur: 52 mm; positie_es_r: 517 mm; positie_ts: 483.5 mm; ref_onderdorpel: 33.5 mm; stijl_lengte: 2337 mm; ts_delta: 0 mm; Type: enkele deur 1xZL; Type Id: 1396169; void_es_r: 250 mm
Name (300_32_ISR_samenstelling_binnenkozijn_hout_met_zijlicht:enkele deur 1xZL:...) | In | OverallWidth (mm) | Level | Host | kozijn_breedte (mm) | zijlicht_breedte (mm) = zijlicht_lr_breedte (mm) | Area (m2) | Volume (m3) | Mark | positie_es_l (mm) | zijlicht_OD_lengte (mm) | zijlicht_pos (mm)
1292445 | 01 eerste verdieping | 1986 | 01 eerste verdieping | Basic Wall : 22_WA_binnenwand_ms205 25-75-5-75-25 _gen_bdg | 1535 | 468 | 2.45673 | 0.0845064 | 123 | 1018 | 518 | 250.5
1292583 | 01 eerste verdieping | 1986 | 01 eerste verdieping | Basic Wall : 22_WA_binnenwand_ms125 25-75-25 _gen_bdg | 1535 | 468 | 2.45673 | 0.0845064 | 129 | 1018 | 518 | 250.5
1292652 | 01 eerste verdieping | 1986 | 01 eerste verdieping | Basic Wall : 22_WA_binnenwand_ms125 25-75-25 _gen_bdg | 1535 | 468 | 2.45673 | 0.0845064 | 132 | 1018 | 518 | 250.5
1399701 | 00 begane grond | 4876 | 00 begane grond | Basic Wall : 22_WA_binnenwand_ms125 25-75-25 _gen_bdg | 2980 | 1913 | 3.2753 | 0.116359 | 279 | 2463 | 1963 | 973
1399972 | 00 begane grond | 4876 | 00 begane grond | Basic Wall : 22_WA_binnenwand_ms125 25-75-25 _gen_bdg | 2980 | 1913 | 3.2753 | 0.116359 | 284 | 2463 | 1963 | 973
1400065 | 00 begane grond | 4876 | 00 begane grond | Floor : NLRS_43_FL_cementdekvloer 60_gen_ISR | 2980 | 1913 | 3.2753 | 0.116359 | 287 | 2463 | 1963 | 973
1400117 | 00 begane grond | 4876 | 00 begane grond | Basic Wall : 22_WA_binnenwand_ms125 25-75-25 _gen_bdg | 2980 | 1913 | 3.2753 | 0.116359 | 293 | 2463 | 1963 | 973
1527030 | 00 begane grond | 1986 | 00 begane grond | Basic Wall : 22_WA_binnenwand_ms125 25-75-25 _gen_bdg | 1535 | 468 | 2.45673 | 0.0845064 | 300 | 1018 | 518 | 250.5
1612366 | 00 begane grond | 1986 | 00 begane grond | Basic Wall : 22_WA_binnenwand_ms125 25-75-25 _gen_bdg | 1535 | 468 | 2.45673 | 0.0845064 | 321 | 1018 | 518 | 250.5
1612427 | 00 begane grond | 1986 | 00 begane grond | Floor : NLRS_43_FL_cementdekvloer 60_gen_ISR | 1535 | 468 | 2.45673 | 0.0845064 | 323 | 1018 | 518 | 250.5
4493360 | 01 eerste verdieping | 2376 | 01 eerste verdieping | Floor : NLRS_43_FL_cementdekvloer 50_gen_ISR | 1730 | 663 | 2.56719 | 0.0888049 | 392 | 1213 | 713 | 348

# IfcDoor: 300_32_ISR_samenstelling_binnenkozijn_hout_met_zijlicht:enkele deur met glas 1xZL (2)
In: 00 begane grond
Type - ConstructionType: USERDEFINED; ParameterTakesPrecedence: no; Sizeable: no; Material: n6_binnenkozijn
Type - Analytical Properties - Define Thermal Properties by: Schematic Type; Analytic Construction: <None>
Type - Constraints - Default Elevation: 0 mm
Type - Materials and Finishes - glas_materiaal: ISR_Glas
Type - Graphics - dubbele_deur: no; Vlak B1: Panel : dubbel glas; deur_type: 32_ISR_onderdeel_deur : deur met glas
Type - Construction - Function: Interior; Construction Type: binnenkozijn hout; stijl_breedte: 67 mm
Type - Dimensions - dikte_onderdorpel: 25 mm; tong_naald: 2 mm
Type - Identity Data - Workset: Family : Doors : 300_32_ISR_samenstelling_binnenkozijn_hout_met_zijlicht; Assembly Code: 2E(32.31.21); Datum_Gewijzigd: 14-11-2012; Description: binnendeur enkel met zijlicht; Model: LOD300; SmartRevit_Versie: 2013.2; Type Comments: samenstelling; Type Mark: 720; Type Name: enkele deur met glas 1xZL
Type - Other - Category: Doors; Family Name: 300_32_ISR_samenstelling_binnenkozijn_hout_met_zijlicht
OverallHeight: 2387 mm; Classification: 2E(32.31.21) Uniformat (Uniformat)
Fire Protection - brandwerendheid_120min: no; brandwerendheid_30min: no; brandwerendheid_90min: no; brandwerendheid_60min: yes; zelfsluitend: yes
Constraints - Level: 00 begane grond; Moves With Nearby Elements: no; Offset from Host: 0 mm; deur_breedte: 930 mm; Host: Basic Wall : 22_WA_binnenwand_ms125 25-75-25 _gen_bdg
Phasing - Phase Created: 2. nieuwbouw
Graphics - dorpel: no; deur_LR_wisselen: yes; WBDBO_tekst_andere_zijde: yes
Construction - kozijn_hoogte: 2387 mm; stijl_diepte: 125 mm; tussenstijl_breedte: 67 mm; tussenstijl_diepte: 125 mm
Dimensions - zijlicht_LR_verdelen: no; deur_hoogte: 2315 mm; Height: 2387 mm; ruimte_onder_deur: 20 mm; sponning_breedte: 17 mm; sponning_diepte: 65 mm; Thickness: 55 mm; Width: 1034 mm
Identity Data - Workset: Workset1
Other - deur_L: no; deur_offset_l: 0 mm; deur_offset_r: 0 mm; deur_R: yes; Family: 300_32_ISR_samenstelling_binnenkozijn_hout_met_zijlicht; ts_delta: 0 mm; basis_breedte: 1034 mm; berekende_deur_breedte: 930 mm; berekende_ruimte_onder_deur: 20 mm; Family and Type: 300_32_ISR_samenstelling_binnenkozijn_hout_met_zijlicht: enkele deur met glas 1xZL; glas_hoogte: 2285 mm; ok_glas: 52 mm; positie_deur: 52 mm; positie_es_r: 517 mm; positie_ts: 483.5 mm; ref_onderdorpel: 33.5 mm; stijl_lengte: 2337 mm; Type: enkele deur met glas 1xZL; Type Id: 1396177; void_es_r: 250 mm
Name (300_32_ISR_samenstelling_binnenkozijn_hout_met_zijlicht:enkele deur met glas 1xZL:...) | OverallWidth (mm) | kozijn_breedte (mm) | zijlicht_breedte (mm) = zijlicht_lr_breedte (mm) | Area (m2) | Volume (m3) | Mark | positie_es_l (mm) | zijlicht_OD_lengte (mm) | zijlicht_pos (mm)
2522335 | 2796 | 1940 | 873 | 2.68342 | 0.0886961 | 464 | 1423 | 923 | 453
2659985 | 2286 | 1685 | 618 | 2.5397 | 0.0833636 | 383 | 1168 | 668 | 325.5

# IfcDoor: 31_DO_deur_0:deur_RT72_dicht, 31_DO_deur_0:deur_RT72_dicht:4196774
In: 00 begane grond
Type - ParameterTakesPrecedence: no; Sizeable: no; Material: <Unnamed>
Type - Analytical Properties - Define Thermal Properties by: Schematic Type; Analytic Construction: <None>
Type - Constraints - Offset: 8 mm; offset_bovenkant: 28 mm; offset_links: 28 mm; offset_onderkant: 28 mm; offset_rechts: 28 mm
Type - Dimensions - Thickness: 72 mm
Type - Identity Data - Workset: Family : Doors : 31_DO_deur_0; Assembly Code: 31.3; Description: deur dicht; Manufacturer: ITANNEX; Model: 01-05-2018; Type Comments: deuren; Type Mark: 26; Type Name: deur_RT72_dicht; URL: www.bimvoorfabrikanten.nl
Type - Other - Category: Doors; Family Name: 31_DO_deur_0
OverallHeight: 2373 mm; OverallWidth: 1156 mm; Group: Model Group:BU-46:4200502
Model Properties - diepte_offset_a: 0 mm; draairichting_a_type: BU deur rechts BDG : BU deur rechts
Constraints - Level: 00 begane grond
Phasing - Phase Created: 2. nieuwbouw
Dimensions - Area: 2.5487 m2; Height: 2317 mm; netto_breedte: 1156 mm; netto_hoogte: 2373 mm; paneel_oppervlakte: 2.74319 m2; Volume: 0.19751 m3; Width: 1100 mm
Identity Data - Workset: Workset1; Mark: 522
Other - Family: 31_DO_deur_0; Family and Type: 31_DO_deur_0: deur_RT72_dicht; HeightReport: 2317 mm; Host Id: 4196773; offset_a: 8 mm; offset_b: 16 mm; offset_bovenkant_a: 28 mm; offset_bovenkant_b: 56 mm; offset_links_a: 28 mm; offset_links_b: 56 mm; offset_onderkant_a: 28 mm; offset_onderkant_b: 56 mm; offset_rechts_a: 28 mm; offset_rechts_b: 56 mm; Type: deur_RT72_dicht; Type Id: 835119; WidthReport: 1100 mm

# IfcDoor: 31_DO_deur_0:deur_RT72_dicht L, 31_DO_deur_0:deur_RT72_dicht L:3836669
In: 00 begane grond
Type - ParameterTakesPrecedence: no; Sizeable: no; Material: <Unnamed>
Type - Analytical Properties - Define Thermal Properties by: Schematic Type; Analytic Construction: <None>
Type - Constraints - offset_rechts: 0 mm; Offset: 8 mm; offset_bovenkant: 28 mm; offset_links: 28 mm; offset_onderkant: 28 mm
Type - Dimensions - Thickness: 72 mm
Type - Identity Data - Workset: Family : Doors : 31_DO_deur_0; Assembly Code: 31.3; Description: deur dicht; Manufacturer: ITANNEX; Model: 01-05-2018; Type Comments: deuren; Type Mark: 105; Type Name: deur_RT72_dicht L; URL: www.bimvoorfabrikanten.nl
Type - Other - Category: Doors; Family Name: 31_DO_deur_0
OverallHeight: 2373 mm; OverallWidth: 960 mm; Group: Model Group:BU-16:3836676
Model Properties - diepte_offset_a: 0 mm; draairichting_a_type: BU deur links BDG : BU deur links
Constraints - Level: 00 begane grond
Phasing - Phase Created: 2. nieuwbouw
Dimensions - Area: 2.15944 m2; Height: 2317 mm; netto_breedte: 960 mm; netto_hoogte: 2373 mm; paneel_oppervlakte: 2.27808 m2; Volume: 0.164022 m3; Width: 932 mm
Identity Data - Workset: Workset1; Mark: 438
Other - offset_rechts_a: 0 mm; offset_rechts_b: 0 mm; Family: 31_DO_deur_0; Host Id: 3836657; Family and Type: 31_DO_deur_0: deur_RT72_dicht L; HeightReport: 2317 mm; offset_a: 8 mm; offset_b: 16 mm; offset_bovenkant_a: 28 mm; offset_bovenkant_b: 56 mm; offset_links_a: 28 mm; offset_links_b: 56 mm; offset_onderkant_a: 28 mm; offset_onderkant_b: 56 mm; Type: deur_RT72_dicht L; Type Id: 2011443; WidthReport: 932 mm

# IfcDoor: 31_DO_deur_0:deur_RT72_dicht dubbel R, 31_DO_deur_0:deur_RT72_dicht dubbel R:3836658
In: 00 begane grond
Type - ParameterTakesPrecedence: no; Sizeable: no; Material: <Unnamed>
Type - Analytical Properties - Define Thermal Properties by: Schematic Type; Analytic Construction: <None>
Type - Constraints - offset_links: 0 mm; Offset: 8 mm; offset_bovenkant: 28 mm; offset_onderkant: 28 mm; offset_rechts: 28 mm
Type - Dimensions - Thickness: 72 mm
Type - Identity Data - Workset: Family : Doors : 31_DO_deur_0; Assembly Code: 31.3; Description: deur dicht; Manufacturer: ITANNEX; Model: 01-05-2018; Type Comments: deuren; Type Mark: 104; Type Name: deur_RT72_dicht dubbel R; URL: www.bimvoorfabrikanten.nl
Type - Other - Category: Doors; Family Name: 31_DO_deur_0
OverallHeight: 2373 mm; OverallWidth: 931.577 mm; Group: Model Group:BU-16:3836676
Model Properties - diepte_offset_a: 0 mm; draairichting_a_type: BU deur rechts BDG : BU deur rechts
Constraints - Level: 00 begane grond
Phasing - Phase Created: 2. nieuwbouw
Dimensions - Area: 2.09359 m2; Height: 2317 mm; netto_breedte: 931.577 mm; netto_hoogte: 2373 mm; paneel_oppervlakte: 2.21063 m2; Volume: 0.159166 m3; Width: 903.577 mm
Identity Data - Workset: Workset1; Mark: 433
Other - offset_links_a: 0 mm; offset_links_b: 0 mm; Family: 31_DO_deur_0; Family and Type: 31_DO_deur_0: deur_RT72_dicht dubbel R; HeightReport: 2317 mm; Host Id: 3836657; offset_a: 8 mm; offset_b: 16 mm; offset_bovenkant_a: 28 mm; offset_bovenkant_b: 56 mm; offset_onderkant_a: 28 mm; offset_onderkant_b: 56 mm; offset_rechts_a: 28 mm; offset_rechts_b: 56 mm; Type: deur_RT72_dicht dubbel R; Type Id: 2011358; WidthReport: 903.577 mm

# IfcDoor: 31_DO_deur_0:std bi (3)
In: 00 begane grond
Type - ParameterTakesPrecedence: no; Sizeable: no; Material: <Unnamed>
Type - Analytical Properties - Define Thermal Properties by: Schematic Type; Analytic Construction: <None>
Type - Constraints - offset_bovenkant: 0 mm; offset_links: 0 mm; offset_onderkant: 0 mm; offset_rechts: 0 mm; Offset: 8 mm
Type - Dimensions - Thickness: 40 mm
Type - Identity Data - Workset: Family : Doors : 31_DO_deur_0; Assembly Code: 31.3; Description: deur dicht; Manufacturer: ITANNEX; Model: 01-05-2018; Type Comments: deuren; Type Mark: 107; Type Name: std bi; URL: www.bimvoorfabrikanten.nl
Type - Other - Category: Doors; Family Name: 31_DO_deur_0
OverallHeight: 2320 mm
Constraints - Level: 00 begane grond
Phasing - Phase Created: 2. nieuwbouw
Dimensions - Height: 2320 mm; netto_hoogte: 2320 mm
Identity Data - Workset: Workset1
Other - offset_bovenkant_a: 0 mm; offset_bovenkant_b: 0 mm; offset_links_a: 0 mm; offset_links_b: 0 mm; offset_onderkant_a: 0 mm; offset_onderkant_b: 0 mm; offset_rechts_a: 0 mm; offset_rechts_b: 0 mm; Family: 31_DO_deur_0; Family and Type: 31_DO_deur_0: std bi; HeightReport: 2320 mm; Type: std bi; Type Id: 2082719
Name (31_DO_deur_0:std bi:...) | OverallWidth (mm) = netto_breedte (mm) = Width (mm) = WidthReport (mm) | diepte_offset_a (mm) | draairichting_a_type | Area (m2) = paneel_oppervlakte (m2) | Volume (m3) | Host Id | offset_a (mm) | offset_b (mm) | Group
2140319 | 900 | 0 | BI deur links BDG : BI deur links | 2.088 | 0.08352 | 2140318 | 8 | 16 | Model Group:BI-16y 1334x2387:2530506
2140879 | 300 | 0 | BI deur rechts BDG : BI deur rechts | 0.696 | 0.02784 | 2140318 | 8 | 16 | Model Group:BI-16y 1334x2387:2530506
3843748 | 900 | 70 | BU deur links BDG : BU deur links | 2.088 | 0.08352 | 3843747 | 70 | 140 | Model Group:BI-02 2198x2387 (members excluded):3844191

# IfcDoor: 31_DO_deur_0:std bi schuif (3)
In: 01 eerste verdieping
Type - ParameterTakesPrecedence: no; Sizeable: no; Material: <Unnamed>
Type - Analytical Properties - Define Thermal Properties by: Schematic Type; Analytic Construction: <None>
Type - Constraints - offset_bovenkant: 0 mm; offset_links: 0 mm; offset_onderkant: 0 mm; offset_rechts: 0 mm; Offset: 8 mm
Type - Dimensions - Thickness: 19 mm
Type - Identity Data - Assembly Code: 31.3; Description: deur dicht; Manufacturer: ITANNEX; Model: 01-05-2018; Type Comments: deuren; Type Mark: BI-29x; Type Name: std bi schuif; URL: www.bimvoorfabrikanten.nl; Workset: Family : Doors : 31_DO_deur_0
Type - Other - Category: Doors; Family Name: 31_DO_deur_0
OverallHeight: 2344 mm; Group: Model Group:BI-30:2755094
Model Properties - draairichting_a_type: BI vast
Constraints - Level: 01 eerste verdieping
Phasing - Phase Created: 2. nieuwbouw
Dimensions - Height: 2344 mm; netto_hoogte: 2344 mm
Identity Data - Workset: Workset1
Other - offset_bovenkant_a: 0 mm; offset_bovenkant_b: 0 mm; offset_links_a: 0 mm; offset_links_b: 0 mm; offset_onderkant_a: 0 mm; offset_onderkant_b: 0 mm; offset_rechts_a: 0 mm; offset_rechts_b: 0 mm; Family: 31_DO_deur_0; Family and Type: 31_DO_deur_0: std bi schuif; HeightReport: 2344 mm; Host Id: 2082374; Type: std bi schuif; Type Id: 2753637
Name (31_DO_deur_0:std bi schuif:...) | OverallWidth (mm) = netto_breedte (mm) = Width (mm) = WidthReport (mm) | diepte_offset_a (mm) = offset_a (mm) | Area (m2) = paneel_oppervlakte (m2) | Volume (m3) | offset_b (mm)
2082375 | 897.5 | 35 | 2.10374 | 0.0399711 | 70
2082561 | 894 | 75 | 2.09554 | 0.0398152 | 150
2082636 | 897.5 | 35 | 2.10374 | 0.0399711 | 70

# IfcDoor: 31_DO_deur_1:0std_RT72_glasdeur (6)
Type - ParameterTakesPrecedence: no; Sizeable: no; Material: <Unnamed>
Type - Analytical Properties - Define Thermal Properties by: Schematic Type; Analytic Construction: <None>
Type - Constraints - Offset: 8 mm; offset_bovenkant: 28 mm; offset_links: 28 mm; offset_onderkant: 28 mm; offset_rechts: 28 mm
Type - Dimensions - SillStacks: 0; Frame: 94 mm; Head: 94 mm; Sill: 94 mm; Thickness: 72 mm
Type - Identity Data - Assembly Code: 31.3; Description: deur met 1 stapeldorpel; Manufacturer: ITANNEX; Model: 01-05-2018; Type Comments: deuren; Type Mark: 22; Type Name: 0std_RT72_glasdeur; URL: www.bimvoorfabrikanten.nl; Workset: Family : Doors : 31_DO_deur_1
Type - Other - Category: Doors; Family Name: 31_DO_deur_1
OverallWidth: 956 mm
Model Properties - subpaneel_a1_roedes_hor: 0; subpaneel_a1_roedes_ver: 0; subpaneel_a1_type: WI_subvak : glas 2; diepte_offset_a: 0 mm
Phasing - Phase Created: 2. nieuwbouw
Dimensions - netto_breedte: 956 mm; Width: 900 mm
Identity Data - Workset: Workset1
Other - SillStacksCalc: 2; Type: 0std_RT72_glasdeur; Family: 31_DO_deur_1; Family and Type: 31_DO_deur_1: 0std_RT72_glasdeur; offset_a: 8 mm; offset_b: 16 mm; offset_bovenkant_a: 28 mm; offset_bovenkant_b: 56 mm; offset_links_a: 28 mm; offset_links_b: 56 mm; offset_onderkant_a: 28 mm; offset_onderkant_b: 56 mm; offset_rechts_a: 28 mm; offset_rechts_b: 56 mm; subpaneel_a_breedte: 768 mm; Type Id: 835108; WidthReport: 900 mm
Name (31_DO_deur_1:0std_RT72_glasdeur:...) | In | OverallHeight (mm) = netto_hoogte (mm) | draairichting_a_type | Level | Area (m2) | Height (mm) = HeightReport (mm) | paneel_oppervlakte (m2) | Volume (m3) | Host Id | subpaneel_1_hoogte (mm) | subpaneel_a1_oppervlakte (m2) | Group
1837439 | 01 eerste verdieping | 2528 | BU deur links BDG : BU deur links | 01 eerste verdieping | 2.2248 | 2472 | 0.619648 | 0.0044496 | 891997 | 2340 | 1.79712 | Model Group:BU-32:892003
1300454 | 00 begane grond | 2353 | BU deur rechts BDG : BU deur rechts | 00 begane grond | 2.0673 | 2297 | 0.586748 | 0.0041346 | 1300453 | 2165 | 1.66272 | Model Group:BU-22 b2700:1300414
1300743 | 00 begane grond | 2353 | BU deur rechts BDG : BU deur rechts | 00 begane grond | 2.0673 | 2297 | 0.586748 | 0.0041346 | 1300742 | 2165 | 1.66272 | Model Group:BU-21 b2966:1300741
1300955 | 00 begane grond | 2353 | BU deur rechts BDG : BU deur rechts | 00 begane grond | 2.0673 | 2297 | 0.586748 | 0.0041346 | 1300954 | 2165 | 1.66272 | Model Group:BU-20 b3300:1300930
1817635 | 00 begane grond | 2353 | BU deur links BDG : BU deur links | 00 begane grond | 2.0673 | 2297 | 0.586748 | 0.0041346 | 1817349 | 2165 | 1.66272 | Model Group:BU-12 b4200:1817348
1932980 | 00 begane grond | 2353 | BU deur rechts BDG : BU deur rechts | 00 begane grond | 2.0673 | 2297 | 0.586748 | 0.0041346 | 1932979 | 2165 | 1.66272 | Model Group:BU-17 b3000:1900158 | Identity Data - Mark: 415

# IfcDoor: 31_DO_deur_1:0std_RT72_glasdeur bi (2)
In: 00 begane grond
Type - ParameterTakesPrecedence: no; Sizeable: no; Material: <Unnamed>
Type - Analytical Properties - Define Thermal Properties by: Schematic Type; Analytic Construction: <None>
Type - Constraints - Offset: -8 mm; offset_bovenkant: 28 mm; offset_links: 28 mm; offset_onderkant: 28 mm; offset_rechts: 28 mm
Type - Dimensions - SillStacks: 0; Frame: 94 mm; Head: 94 mm; Sill: 94 mm; Thickness: 72 mm
Type - Identity Data - Workset: Family : Doors : 31_DO_deur_1; Assembly Code: 31.3; Description: deur met 1 stapeldorpel; Manufacturer: ITANNEX; Model: 01-05-2018; Type Comments: deuren; Type Mark: BI-19x; Type Name: 0std_RT72_glasdeur bi; URL: www.bimvoorfabrikanten.nl
Type - Other - Category: Doors; Family Name: 31_DO_deur_1
OverallHeight: 2353 mm; OverallWidth: 956 mm
Model Properties - subpaneel_a1_roedes_hor: 0; subpaneel_a1_roedes_ver: 0; subpaneel_a1_type: WI_subvak : glas 2; diepte_offset_a: 0 mm
Constraints - Level: 00 begane grond
Phasing - Phase Created: 2. nieuwbouw
Dimensions - Area: 2.0673 m2; Height: 2297 mm; netto_breedte: 956 mm; netto_hoogte: 2353 mm; paneel_oppervlakte: 0.586748 m2; Volume: 0.0041346 m3; Width: 900 mm
Identity Data - Workset: Workset1
Other - offset_b: 0 mm; SillStacksCalc: 2; Family: 31_DO_deur_1; Family and Type: 31_DO_deur_1: 0std_RT72_glasdeur bi; HeightReport: 2297 mm; offset_a: 8 mm; offset_bovenkant_a: 28 mm; offset_bovenkant_b: 56 mm; offset_links_a: 28 mm; offset_links_b: 56 mm; offset_onderkant_a: 28 mm; offset_onderkant_b: 56 mm; offset_rechts_a: 28 mm; offset_rechts_b: 56 mm; subpaneel_1_hoogte: 2165 mm; subpaneel_a_breedte: 768 mm; subpaneel_a1_oppervlakte: 1.66272 m2; Type: 0std_RT72_glasdeur bi; Type Id: 4225593; WidthReport: 900 mm
Name (31_DO_deur_1:0std_RT72_glasdeur bi:...) | draairichting_a_type | Mark | Host Id | Group
1822152 | BI deur links BDG : BI deur links | 400 | 1822151 | Model Group:BU-10 b1800:1822150
2649845 | BI deur rechts BDG : BI deur rechts | 432 | 2649834 | Model Group:BU-47 b4200:1822720

# IfcDoor: 31_DO_deur_1:0std_RT72_glasdeur dubbel links (2)
In: 00 begane grond
Type - ParameterTakesPrecedence: no; Sizeable: no; Material: <Unnamed>
Type - Analytical Properties - Define Thermal Properties by: Schematic Type; Analytic Construction: <None>
Type - Constraints - offset_rechts: 0 mm; Offset: 10 mm; offset_bovenkant: 17 mm; offset_links: 17 mm; offset_onderkant: 17 mm
Type - Dimensions - SillStacks: 0; Frame: 94 mm; Head: 94 mm; Sill: 94 mm; Thickness: 72 mm
Type - Identity Data - Workset: Family : Doors : 31_DO_deur_1; Assembly Code: 31.3; Description: deur met 1 stapeldorpel; Manufacturer: ITANNEX; Model: 01-05-2018; Type Comments: deuren; Type Mark: 101; Type Name: 0std_RT72_glasdeur dubbel links; URL: www.bimvoorfabrikanten.nl
Type - Other - Category: Doors; Family Name: 31_DO_deur_1
OverallHeight: 2331 mm
Model Properties - subpaneel_a1_roedes_hor: 0; subpaneel_a1_roedes_ver: 0; subpaneel_a1_type: WI_subvak : glas 2; diepte_offset_a: 0 mm; draairichting_a_type: BU deur links BDG : BU deur links
Constraints - Level: 00 begane grond
Phasing - Phase Created: 2. nieuwbouw
Dimensions - Height: 2297 mm; netto_hoogte: 2331 mm
Identity Data - Workset: Workset1
Other - SillStacksCalc: 2; offset_rechts_a: 0 mm; offset_rechts_b: 0 mm; Family: 31_DO_deur_1; Family and Type: 31_DO_deur_1: 0std_RT72_glasdeur dubbel links; HeightReport: 2297 mm; offset_a: 10 mm; offset_b: 20 mm; offset_bovenkant_a: 17 mm; offset_bovenkant_b: 34 mm; offset_links_a: 17 mm; offset_links_b: 34 mm; offset_onderkant_a: 17 mm; offset_onderkant_b: 34 mm; subpaneel_1_hoogte: 2143 mm; Type: 0std_RT72_glasdeur dubbel links; Type Id: 1827904
Name (31_DO_deur_1:0std_RT72_glasdeur dubbel links:...) | OverallWidth (mm) | Area (m2) | netto_breedte (mm) | paneel_oppervlakte (m2) | Volume (m3) | Width (mm) = WidthReport (mm) | Mark | Host Id | subpaneel_a_breedte (mm) | subpaneel_a1_oppervlakte (m2) | Group
1823317 | 964.5 | 2.15688 | 956 | 0.582612 | 0.00431377 | 939 | 402 | 1823298 | 768 | 1.64582 | Model Group:BU-15 b4200:1823297
3003079 | 925.5 | 2.0673 | 917 | 0.57528 | 0.0041346 | 900 | 389 | 3003068 | 729 | 1.56225 | Model Group:BU-01 b1500:3003067

# IfcDoor: 31_DO_deur_1:0std_RT72_glasdeur dubbel rechts (2)
In: 00 begane grond
Type - ParameterTakesPrecedence: no; Sizeable: no; Material: <Unnamed>
Type - Analytical Properties - Define Thermal Properties by: Schematic Type; Analytic Construction: <None>
Type - Constraints - offset_links: 0 mm; Offset: 10 mm; offset_bovenkant: 17 mm; offset_onderkant: 17 mm; offset_rechts: 17 mm
Type - Dimensions - SillStacks: 0; Frame: 94 mm; Head: 94 mm; Sill: 94 mm; Thickness: 72 mm
Type - Identity Data - Workset: Family : Doors : 31_DO_deur_1; Assembly Code: 31.3; Description: deur met 1 stapeldorpel; Manufacturer: ITANNEX; Model: 01-05-2018; Type Comments: deuren; Type Mark: 100; Type Name: 0std_RT72_glasdeur dubbel rechts; URL: www.bimvoorfabrikanten.nl
Type - Other - Category: Doors; Family Name: 31_DO_deur_1
OverallHeight: 2331 mm
Model Properties - subpaneel_a1_roedes_hor: 0; subpaneel_a1_roedes_ver: 0; subpaneel_a1_type: WI_subvak : glas 2; diepte_offset_a: 0 mm; draairichting_a_type: BU deur rechts BDG : BU deur rechts
Constraints - Level: 00 begane grond
Phasing - Phase Created: 2. nieuwbouw
Dimensions - Height: 2297 mm; netto_hoogte: 2331 mm
Identity Data - Workset: Workset1
Other - SillStacksCalc: 2; offset_links_a: 0 mm; offset_links_b: 0 mm; Family: 31_DO_deur_1; Family and Type: 31_DO_deur_1: 0std_RT72_glasdeur dubbel rechts; HeightReport: 2297 mm; offset_a: 10 mm; offset_b: 20 mm; offset_bovenkant_a: 17 mm; offset_bovenkant_b: 34 mm; offset_onderkant_a: 17 mm; offset_onderkant_b: 34 mm; offset_rechts_a: 17 mm; offset_rechts_b: 34 mm; subpaneel_1_hoogte: 2143 mm; Type: 0std_RT72_glasdeur dubbel rechts; Type Id: 1827594
Name (31_DO_deur_1:0std_RT72_glasdeur dubbel rechts:...) | OverallWidth (mm) | Area (m2) | netto_breedte (mm) | paneel_oppervlakte (m2) | Volume (m3) | Width (mm) = WidthReport (mm) | Mark | Host Id | subpaneel_a_breedte (mm) | subpaneel_a1_oppervlakte (m2) | Group
1823299 | 964.5 | 2.15688 | 956 | 0.582612 | 0.00431377 | 939 | 401 | 1823298 | 768 | 1.64582 | Model Group:BU-15 b4200:1823297
3003087 | 659.5 | 1.4563 | 651 | 0.525272 | 0.0029126 | 634 | 390 | 3003068 | 463 | 0.992209 | Model Group:BU-01 b1500:3003067

# IfcDoor: 31_DO_deur_1:1std bi (7)
Type - ParameterTakesPrecedence: no; Sizeable: no; Material: <Unnamed>
Type - Analytical Properties - Define Thermal Properties by: Schematic Type; Analytic Construction: <None>
Type - Constraints - offset_bovenkant: 0 mm; offset_links: 0 mm; offset_rechts: 0 mm; Offset: -30 mm; offset_onderkant: -20 mm
Type - Dimensions - SillStacks: 0; Frame: 85 mm; Head: 85 mm; Sill: 180 mm; Thickness: 40 mm
Type - Identity Data - Workset: Family : Doors : 31_DO_deur_1; Assembly Code: 31.3; Description: deur met 1 stapeldorpel; Manufacturer: ITANNEX; Model: 01-05-2018; Type Comments: deuren; Type Mark: 97; Type Name: 1std bi; URL: www.bimvoorfabrikanten.nl
Type - Other - Category: Doors; Family Name: 31_DO_deur_1
Model Properties - subpaneel_a1_roedes_hor: 0; subpaneel_a1_roedes_ver: 0; subpaneel_a1_type: WI_subvak : glas 2
Phasing - Phase Created: 2. nieuwbouw
Identity Data - Workset: Workset1
Other - SillStacksCalc: 2; offset_bovenkant_a: 0 mm; offset_bovenkant_b: 0 mm; offset_links_a: 0 mm; offset_links_b: 0 mm; offset_onderkant_b: 0 mm; offset_rechts_a: 0 mm; offset_rechts_b: 0 mm; Family: 31_DO_deur_1; Family and Type: 31_DO_deur_1: 1std bi; offset_onderkant_a: 20 mm; Type: 1std bi; Type Id: 1632871
Name (31_DO_deur_1:1std bi:...) | In | OverallHeight (mm) = Height (mm) = HeightReport (mm) | OverallWidth (mm) = netto_breedte (mm) = Width (mm) = WidthReport (mm) | draairichting_a_type | diepte_offset_a (mm) = offset_a (mm) | Level | Area (m2) | netto_hoogte (mm) | paneel_oppervlakte (m2) | Volume (m3) | Host Id | offset_b (mm) | subpaneel_1_hoogte (mm) | subpaneel_a_breedte (mm) | subpaneel_a1_oppervlakte (m2) | Group
1612826 | 00 begane grond | 2320 | 916 | BU deur rechts BDG : BU deur rechts | 85 | 00 begane grond | 2.12512 | 2300 | 0.58869 | 0.00425024 | 1612555 | 170 | 2035 | 746 | 1.51811 | Model Group:BI-10 4215x2800:2522162
1612975 | 00 begane grond | 2320 | 916 | BU deur links BDG : BU deur links | 85 | 00 begane grond | 2.12512 | 2300 | 0.58869 | 0.00425024 | 1612555 | 170 | 2035 | 746 | 1.51811 | Model Group:BI-10 4215x2800:2522162
1729468 | 02 tweede verdieping | 2320 | 916 | BI deur links BDG : BI deur links | 10 | 02 tweede verdieping | 2.12512 | 2300 | 0.58869 | 0.00425024 | 1729467 | 20 | 2035 | 746 | 1.51811 | Model Group:BI-28:2534707
1729483 | 02 tweede verdieping | 2320 | 916 | BI deur rechts BDG : BI deur rechts | 10 | 02 tweede verdieping | 2.12512 | 2300 | 0.58869 | 0.00425024 | 1729467 | 20 | 2035 | 746 | 1.51811 | Model Group:BI-28:2534707 | Identity Data - Mark: 373
1730034 | 01 eerste verdieping | 2483 | 937 | BI deur links BDG : BI deur links | 10 | 01 eerste verdieping | 2.32657 | 2463 | 0.621965 | 0.00465314 | 1730033 | 20 | 2198 | 767 | 1.68587 | Model Group:BI-22 1965x2550:2532537
1730369 | 01 eerste verdieping | 2483 | 937 | BI deur rechts BDG : BI deur rechts | 10 | 01 eerste verdieping | 2.32657 | 2463 | 0.621965 | 0.00465314 | 1730033 | 20 | 2198 | 767 | 1.68587 | Model Group:BI-22 1965x2550:2532537
1735560 | 01 eerste verdieping | 2320 | 900 | BI deur links BDG : BI deur links | 10 | 01 eerste verdieping | 2.088 | 2300 | 0.58445 | 0.004176 | 1735559 | 20 | 2035 | 730 | 1.48555 | Model Group:BI-23w 4635x2800:2532690

# IfcDoor: 31_DO_deur_1:stalen pui (8)
Type - ParameterTakesPrecedence: no; Sizeable: no; Material: <Unnamed>
Type - Analytical Properties - Define Thermal Properties by: Schematic Type; Analytic Construction: <None>
Type - Constraints - offset_bovenkant: 0 mm; offset_links: 0 mm; offset_rechts: 0 mm; Offset: -25 mm; offset_onderkant: -20 mm
Type - Dimensions - SillStacks: 0; Frame: 70 mm; Head: 70 mm; Sill: 70 mm; Thickness: 50 mm
Type - Identity Data - Workset: Family : Doors : 31_DO_deur_1; Assembly Code: 31.3; Description: deur met 1 stapeldorpel; Manufacturer: ITANNEX; Model: 01-05-2018; Type Comments: deuren; Type Mark: BI-29y; Type Name: stalen pui; URL: www.bimvoorfabrikanten.nl
Type - Other - Category: Doors; Family Name: 31_DO_deur_1
Model Properties - subpaneel_a1_roedes_hor: 0; subpaneel_a1_roedes_ver: 0; subpaneel_a1_type: WI_subvak : glas 2; diepte_offset_a: 0 mm
Phasing - Phase Created: 2. nieuwbouw
Identity Data - Workset: Workset1
Other - offset_b: 0 mm; SillStacksCalc: 2; offset_bovenkant_a: 0 mm; offset_bovenkant_b: 0 mm; offset_links_a: 0 mm; offset_links_b: 0 mm; offset_onderkant_b: 0 mm; offset_rechts_a: 0 mm; offset_rechts_b: 0 mm; Family: 31_DO_deur_1; Family and Type: 31_DO_deur_1: stalen pui; offset_a: 25 mm; offset_onderkant_a: 20 mm; Type: stalen pui; Type Id: 3301137
Name (31_DO_deur_1:stalen pui:...) | In | OverallHeight (mm) | OverallWidth (mm) = netto_breedte (mm) = Width (mm) = WidthReport (mm) | draairichting_a_type | Level | Area (m2) | Height (mm) = HeightReport (mm) | netto_hoogte (mm) | paneel_oppervlakte (m2) | Volume (m3) | Host Id | subpaneel_1_hoogte (mm) | subpaneel_a_breedte (mm) | subpaneel_a1_oppervlakte (m2) | Group
1470456 | 01 eerste verdieping | 2332.5 | 920 | BU deur rechts BDG : BU deur rechts | 01 eerste verdieping | 2.1367 | 2322.5 | 2302.5 | 0.43155 | 0.0042734 | 1470455 | 2162.5 | 780 | 1.68675 | Model Group:BI-26bw:2535201
1474295 | 01 eerste verdieping | 2332.5 | 919.813 | BU deur links BDG : BU deur links | 01 eerste verdieping | 2.13627 | 2322.5 | 2302.5 | 0.431524 | 0.00427253 | 1470455 | 2162.5 | 779.813 | 1.68635 | Model Group:BI-26bw:2535201
2691239 | 02 tweede verdieping | 2332.5 | 920 | BU deur rechts BDG : BU deur rechts | 02 tweede verdieping | 2.1367 | 2322.5 | 2302.5 | 0.43155 | 0.0042734 | 1476038 | 2162.5 | 780 | 1.68675 | Model Group:BI-29bw 60min:1476114
2691240 | 02 tweede verdieping | 2332.5 | 919.963 | BI deur rechts BDG : BI deur rechts | 02 tweede verdieping | 2.13661 | 2322.5 | 2302.5 | 0.431545 | 0.00427323 | 1476038 | 2162.5 | 779.963 | 1.68667 | Model Group:BI-29bw 60min:1476114
2691241 | 02 tweede verdieping | 2332.5 | 927.337 | BI deur links BDG : BI deur links | 02 tweede verdieping | 2.15374 | 2322.5 | 2302.5 | 0.432577 | 0.00430748 | 1476038 | 2162.5 | 787.337 | 1.70262 | Model Group:BI-29bw 60min:1476114
2691242 | 02 tweede verdieping | 2332.5 | 925 | BU deur links BDG : BU deur links | 02 tweede verdieping | 2.14831 | 2322.5 | 2302.5 | 0.43225 | 0.00429663 | 1476038 | 2162.5 | 785 | 1.69756 | Model Group:BI-29bw 60min:1476114
1939634 | 00 begane grond | 2352.5 | 864.5 | BI deur links BDG : BI deur links | 00 begane grond | 2.02509 | 2342.5 | 2322.5 | 0.42658 | 0.00405018 | 1478229 | 2182.5 | 724.5 | 1.58122 | Model Group:BI-13bw 7515x2800:2527306 | Identity Data - Mark: 416
1480119 | 00 begane grond | 2352.5 | 935.5 | BU deur links BDG : BU deur links | 00 begane grond | 2.19141 | 2342.5 | 2322.5 | 0.43652 | 0.00438282 | 1478229 | 2182.5 | 795.5 | 1.73618 | Model Group:BI-13bw 7515x2800:2527306 | Identity Data - Mark: 337

# IfcDoor: 31_DO_stolpdeur:0std_RT72_glasdeur (5)
Type - ParameterTakesPrecedence: no; Sizeable: no; Material: <Unnamed>
Type - Analytical Properties - Define Thermal Properties by: Schematic Type; Analytic Construction: <None>
Type - Constraints - offset_b: 0 mm; offset_a: 0 mm
Type - Construction - opening: 0 mm; Width_A: 0 mm
Type - Dimensions - SillStacks: 0; Frame: 94 mm; Head: 94 mm; Sill: 94 mm; Thickness: 72 mm
Type - Identity Data - Assembly Code: 31.3; Description: stolpdeur met 1 subvak en 4 std; Manufacturer: ITANNEX; Model: 01-05-2018; Type Comments: stolpdeuren; Type Mark: 25; Type Name: 0std_RT72_glasdeur; URL: www.bimvoorfabrikanten.nl; Workset: Family : Doors : 31_DO_stolpdeur
Type - Other - Category: Doors; Family Name: 31_DO_stolpdeur
Model Properties - subpaneel_a1_roedes_hor: 0; subpaneel_a1_roedes_ver: 0; subpaneel_a1_type: WI_subvak : glas 2; diepte_offset_a: 0 mm; diepte_offset_b: 0 mm; draairichting_a_type: BU deur links BDG : BU deur links; draairichting_b_type: BU deur rechts BDG : BU deur rechts; subpaneel_b1_type: WI_subvak : glas 2
Constraints - offset_bovenkant: 0 mm; offset_links: 0 mm; offset_onderkant: 0 mm; offset_rechts: 0 mm
Phasing - Phase Created: 2. nieuwbouw
Identity Data - Workset: Workset1
Other - SillStacksCalc: 2; Family: 31_DO_stolpdeur; Family and Type: 31_DO_stolpdeur: 0std_RT72_glasdeur; offset_aa: 0 mm; offset_ab: 0 mm; offset_ba: 0 mm; offset_bb: 0 mm; offset_bovenkant_a: 0 mm; offset_bovenkant_b: 0 mm; offset_links_a: 0 mm; offset_links_b: 0 mm; offset_onderkant_a: 0 mm; offset_onderkant_b: 0 mm; offset_rechts_a: 0 mm; offset_rechts_b: 0 mm; Type: 0std_RT72_glasdeur; Type Id: 835112
Name (31_DO_stolpdeur:0std_RT72_glasdeur:...) | In | OverallHeight (mm) = Height (mm) = netto_hoogte (mm) = HeightReport (mm) | OverallWidth (mm) = netto_breedte (mm) = Width (mm) = WidthReport (mm) | Level | Area (m2) | paneel_oppervlakte (m2) | Volume (m3) | Host Id | CenterCalc (mm) = paneel_breedte_a (mm) = paneel_breedte_b (mm) | CenterLeft (mm) = CenterRight (mm) | subpaneel_1_hoogte (mm) | subpaneel_a_breedte (mm) = subpaneel_b_breedte (mm) | subpaneel_a1_oppervlakte (m2) = subpaneel_b1_oppervlakte (m2) | Group
877791 | 02 tweede verdieping | 2393 | 1800 | 02 tweede verdieping | 4.3074 | 1.16748 | 0.0086148 | 877517 | 900 | 450 | 2205 | 712 | 1.56996 | Model Group:BU-40:2712884
1302055 | 01 eerste verdieping | 2491 | 1635 | 01 eerste verdieping | 4.07278 | 1.17331 | 0.00814557 | 1302054 | 817.5 | 408.75 | 2303 | 629.5 | 1.44974 | Model Group:BU-31:891953
1494515 | 00 begane grond | 2297 | 1878 | 00 begane grond | 4.31377 | 1.14605 | 0.00862753 | 1494514 | 939 | 469.5 | 2109 | 751 | 1.58386 | Model Group:BU-14 b3000:1494513
1853993 | 00 begane grond | 2297 | 1881.5 | 00 begane grond | 4.32181 | 1.14671 | 0.00864361 | 1853992 | 940.75 | 470.375 | 2109 | 752.75 | 1.58755 | Model Group:BU-18 b3017:2651211 | Identity Data - Mark: 379
3702029 | 00 begane grond | 2317 | 1800 | 00 begane grond | 4.1706 | 1.1389 | 0.0083412 | 3702020 | 900 | 450 | 2129 | 712 | 1.51585 | Model Group:BU-04 b2500:1820005 | Identity Data - Mark: 385

# IfcDoor: 32_DO_kanteldeur_sport_Basiswall_bdg:32_DO_kanteldeur_sport_Basiswall_BI-32, 32_DO_kanteldeur_sport_Basiswall_bdg:32_DO_kanteldeur_sport_Basiswall_BI-32:2043463
In: 00 begane grond
Type - ParameterTakesPrecedence: no; Sizeable: no; Material: <Unnamed>, i4_multiplex_perfo, inbouwruimte
Type - Analytical Properties(Type) - Define Thermal Properties by: Schematic Type; Analytic Construction: <None>
Type - Constraints(Type) - dagmaat_breedte: 3700 mm; dagmaat_hoogte: 2500 mm
Type - Materials and Finishes(Type) - plank_materiaal: i4_multiplex_perfo
Type - Construction(Type) - Function: Interior; Wall Closure: By host
Type - Dimensions(Type) - Height: 2700 mm; plank_dikte: 16 mm; Width: 4000 mm
Type - Identity Data(Type) - Description: balbestendige kanteldeur v.v. basiswall beplating netto opening 4000x2500 mm; OmniClass Number: 23.30.10.00; OmniClass Title: Doors; Type Mark: 106; Type Name: 32_DO_kanteldeur_sport_Basiswall_BI-32; Workset: Family : Doors : 32_DO_kanteldeur_sport_Basiswall_bdg
Type - Other(Type) - Category: Doors; Family Name: 32_DO_kanteldeur_sport_Basiswall_bdg; Frame Projection Ext.: 25 mm; Frame Projection Int.: 25 mm; Frame Width: 75 mm
OverallHeight: 2700 mm; OverallWidth: 4000 mm
Constraints - Level: 00 begane grond; Sill Height: 0 mm
Phasing - Phase Created: 2. nieuwbouw
Dimensions - Area: 38.6015 m2; Volume: 2.87449 m3
Identity Data - Workset: Workset1; Comments: overheaddeur bxh 3700x2500
Other - Category: Doors; Family: 32_DO_kanteldeur_sport_Basiswall_bdg; Family and Type: 32_DO_kanteldeur_sport_Basiswall_bdg: 32_DO_kanteldeur_sport_Basiswall_BI-32; Head Height: 2700 mm; Host Id: 1510277; Type: 32_DO_kanteldeur_sport_Basiswall_BI-32; Type Id: 2043444

# IfcDoor: 32_ISR_onderdeel_deur:deur met glas, 32_ISR_onderdeel_deur:deur met glas:1419329
In: 00 begane grond
Type - OperationType: SINGLE_SWING_RIGHT; ConstructionType: USERDEFINED; ParameterTakesPrecedence: no; Sizeable: no; Material: a_paneel, ISR_Glas
Type - 32_ISR_onderdeel_deur:deur met glas:1419329:1 - PanelOperation: SWINGING
Type - Analytical Properties - Define Thermal Properties by: Schematic Type; Analytic Construction: <None>
Type - Materials and Finishes - glas_materiaal: ISR_Glas
Type - Graphics - deur_met_glas: yes; dichte_deur: no; symbool_plgr: graphic_rond : 90_gr
Type - Construction - Function: Interior; Construction Type: deurblad
Type - Dimensions - deur_lijst_borstwering: 300 mm; deur_lijst_breedte: 110 mm; deur_lijst_breedte_scharnier: 110 mm
Type - Identity Data - Workset: Family : Doors : 32_ISR_onderdeel_deur; Assembly Code: 2E(32.31.21); Datum_Gewijzigd: 14-11-2012; Description: deur met glas; Fire Rating: 60; Model: LOD300; SmartRevit_Versie: 2013.2; Type Comments: deurblad; Type Mark: 18; Type Name: deur met glas
Type - Other - Category: Doors; Family Name: 32_ISR_onderdeel_deur
OverallHeight: 2315 mm; OverallWidth: 914 mm; Classification: 2E(32.31.21) Uniformat (Uniformat)
Visibility - tekst_positie_boven: no
Fire Protection - zelfsluitend: no; brandwerendheid_120_min: no; brandwerendheid_30_min: no; brandwerendheid_60_min: no; brandwerendheid_90_min: no
Constraints - Level: 00 begane grond; Moves With Nearby Elements: no; deur_breedte: 914 mm; Host: Level : 00 begane grond; Offset from Host: 20 mm
Phasing - Phase Created: 2. nieuwbouw
Dimensions - Area: 4.62009 m2; deur_hoogte: 2315 mm; Height: 2315 mm; Thickness: 40 mm; Volume: 0.0449743 m3; Width: 914 mm
Identity Data - Workset: Workset1; Mark: 302
Other - tekst_boven: no; tekst_onder: no; Family: 32_ISR_onderdeel_deur; Family and Type: 32_ISR_onderdeel_deur: deur met glas; Type: deur met glas; Type Id: 1396098

# IfcDoor: 32_ISR_onderdeel_deur:deur met glas, 32_ISR_onderdeel_deur:deur met glas:1419384
In: 00 begane grond
Type - OperationType: SINGLE_SWING_RIGHT; ConstructionType: USERDEFINED; ParameterTakesPrecedence: no; Sizeable: no; Material: a_paneel, ISR_Glas
Type - Analytical Properties - Define Thermal Properties by: Schematic Type; Analytic Construction: <None>
Type - Materials and Finishes - glas_materiaal: ISR_Glas
Type - Graphics - deur_met_glas: yes; dichte_deur: no; symbool_plgr: graphic_rond : 90_gr
Type - Construction - Function: Interior; Construction Type: deurblad
Type - Dimensions - deur_lijst_borstwering: 300 mm; deur_lijst_breedte: 110 mm; deur_lijst_breedte_scharnier: 110 mm
Type - Identity Data - Workset: Family : Doors : 32_ISR_onderdeel_deur; Assembly Code: 2E(32.31.21); Datum_Gewijzigd: 14-11-2012; Description: deur met glas; Fire Rating: 60; Model: LOD300; SmartRevit_Versie: 2013.2; Type Comments: deurblad; Type Mark: 18; Type Name: deur met glas
Type - Other - Category: Doors; Family Name: 32_ISR_onderdeel_deur
Type - 32_ISR_onderdeel_deur:deur met glas:1419384:1 - PanelOperation: SWINGING
OverallHeight: 2315 mm; OverallWidth: 914 mm; Classification: 2E(32.31.21) Uniformat (Uniformat)
Visibility - tekst_positie_boven: no
Fire Protection - zelfsluitend: no; brandwerendheid_120_min: no; brandwerendheid_30_min: no; brandwerendheid_60_min: no; brandwerendheid_90_min: no
Constraints - Level: 00 begane grond; Moves With Nearby Elements: no; deur_breedte: 914 mm; Host: Level : 00 begane grond; Offset from Host: 10 mm
Phasing - Phase Created: 2. nieuwbouw
Dimensions - Area: 4.62009 m2; deur_hoogte: 2315 mm; Height: 2315 mm; Thickness: 40 mm; Volume: 0.0449743 m3; Width: 914 mm
Identity Data - Workset: Workset1; Mark: 304
Other - tekst_boven: no; tekst_onder: no; Family: 32_ISR_onderdeel_deur; Family and Type: 32_ISR_onderdeel_deur: deur met glas; Type: deur met glas; Type Id: 1396098

# IfcDoor: 32_ISR_onderdeel_deur:deur met glas (12)
Type - OperationType: SINGLE_SWING_RIGHT; ConstructionType: USERDEFINED; ParameterTakesPrecedence: no; Sizeable: no; Material: a_paneel, ISR_Glas
Type - Analytical Properties - Define Thermal Properties by: Schematic Type; Analytic Construction: <None>
Type - Materials and Finishes - glas_materiaal: ISR_Glas
Type - Graphics - deur_met_glas: yes; dichte_deur: no; symbool_plgr: graphic_rond : 90_gr
Type - Construction - Function: Interior; Construction Type: deurblad
Type - Dimensions - deur_lijst_borstwering: 300 mm; deur_lijst_breedte: 110 mm; deur_lijst_breedte_scharnier: 110 mm
Type - Identity Data - Workset: Family : Doors : 32_ISR_onderdeel_deur; Assembly Code: 2E(32.31.21); Datum_Gewijzigd: 14-11-2012; Description: deur met glas; Fire Rating: 60; Model: LOD300; SmartRevit_Versie: 2013.2; Type Comments: deurblad; Type Mark: 18; Type Name: deur met glas
Type - Other - Category: Doors; Family Name: 32_ISR_onderdeel_deur
Type - 32_ISR_onderdeel_deur:deur met glas:1419665:1 - PanelOperation: SWINGING
OverallHeight: 2320 mm; OverallWidth: 930 mm; Classification: 2E(32.31.21) Uniformat (Uniformat)
Visibility - tekst_positie_boven: yes
Fire Protection - zelfsluitend: no; brandwerendheid_120_min: no; brandwerendheid_30_min: no; brandwerendheid_60_min: no; brandwerendheid_90_min: no
Constraints - Moves With Nearby Elements: no; deur_breedte: 930 mm
Phasing - Phase Created: 2. nieuwbouw
Dimensions - Area: 4.7062 m2; deur_hoogte: 2320 mm; Height: 2320 mm; Thickness: 40 mm; Volume: 0.045621 m3; Width: 930 mm
Identity Data - Workset: Workset1
Other - tekst_boven: no; tekst_onder: no; Family: 32_ISR_onderdeel_deur; Family and Type: 32_ISR_onderdeel_deur: deur met glas; Type: deur met glas; Type Id: 1396098
Name (32_ISR_onderdeel_deur:deur met glas:...) | In | Level | Host | Offset from Host (mm) | Mark
1419665 | 00 begane grond | 00 begane grond | Level : 00 begane grond | 10 | 312
4001724 | 01 eerste verdieping | 01 eerste verdieping | Level : 01 eerste verdieping | 15 | 439
4006593 | 01 eerste verdieping | 01 eerste verdieping | Floor : NLRS_43_FL_cementdekvloer 50_gen_ISR | 15 | 447
4006668 | 01 eerste verdieping | 01 eerste verdieping | Floor : NLRS_43_FL_cementdekvloer 50_gen_ISR | 15 | 475
4006702 | 01 eerste verdieping | 01 eerste verdieping | Level : 01 eerste verdieping | 15 | 482
4006753 | 01 eerste verdieping | 01 eerste verdieping | Floor : NLRS_43_FL_cementdekvloer 50_gen_ISR | 15 | 487
4008224 | 02 tweede verdieping | 02 tweede verdieping | Level : 02 tweede verdieping | 15 | 491
4008278 | 02 tweede verdieping | 02 tweede verdieping | Floor : NLRS_43_FL_cementdekvloer 50_gen_ISR | 15 | 496
4008308 | 02 tweede verdieping | 02 tweede verdieping | Floor : NLRS_43_FL_cementdekvloer 50_gen_ISR | 15 | 502
4008320 | 02 tweede verdieping | 02 tweede verdieping | Level : 02 tweede verdieping | 15 | 507
4008392 | 02 tweede verdieping | 02 tweede verdieping | Floor : NLRS_43_FL_cementdekvloer 50_gen_ISR | 15 | 512
4008418 | 02 tweede verdieping | 02 tweede verdieping | Floor : NLRS_43_FL_cementdekvloer 50_gen_ISR | 15 | 516

# IfcDoor: 32_ISR_onderdeel_deur:deur met glas (12)
Type - OperationType: SINGLE_SWING_RIGHT; ConstructionType: USERDEFINED; ParameterTakesPrecedence: no; Sizeable: no; Material: a_paneel, ISR_Glas
Type - Analytical Properties - Define Thermal Properties by: Schematic Type; Analytic Construction: <None>
Type - Materials and Finishes - glas_materiaal: ISR_Glas
Type - Graphics - deur_met_glas: yes; dichte_deur: no; symbool_plgr: graphic_rond : 90_gr
Type - Construction - Function: Interior; Construction Type: deurblad
Type - Dimensions - deur_lijst_borstwering: 300 mm; deur_lijst_breedte: 110 mm; deur_lijst_breedte_scharnier: 110 mm
Type - Identity Data - Workset: Family : Doors : 32_ISR_onderdeel_deur; Assembly Code: 2E(32.31.21); Datum_Gewijzigd: 14-11-2012; Description: deur met glas; Fire Rating: 60; Model: LOD300; SmartRevit_Versie: 2013.2; Type Comments: deurblad; Type Mark: 18; Type Name: deur met glas
Type - Other - Category: Doors; Family Name: 32_ISR_onderdeel_deur
Type - 32_ISR_onderdeel_deur:deur met glas:1419666:1 - PanelOperation: SWINGING
OverallHeight: 2320 mm; OverallWidth: 930 mm; Classification: 2E(32.31.21) Uniformat (Uniformat)
Visibility - tekst_positie_boven: yes
Fire Protection - zelfsluitend: no; brandwerendheid_120_min: no; brandwerendheid_30_min: no; brandwerendheid_60_min: no; brandwerendheid_90_min: no
Constraints - Moves With Nearby Elements: no; deur_breedte: 930 mm
Phasing - Phase Created: 2. nieuwbouw
Dimensions - Area: 4.7062 m2; deur_hoogte: 2320 mm; Height: 2320 mm; Thickness: 40 mm; Volume: 0.045621 m3; Width: 930 mm
Identity Data - Workset: Workset1
Other - tekst_boven: no; tekst_onder: no; Family: 32_ISR_onderdeel_deur; Family and Type: 32_ISR_onderdeel_deur: deur met glas; Type: deur met glas; Type Id: 1396098
Name (32_ISR_onderdeel_deur:deur met glas:...) | In | Level | Host | Offset from Host (mm) | Mark
1419666 | 00 begane grond | 00 begane grond | Level : 00 begane grond | 10 | 311
4001723 | 01 eerste verdieping | 01 eerste verdieping | Level : 01 eerste verdieping | 15 | 440
4006594 | 01 eerste verdieping | 01 eerste verdieping | Floor : NLRS_43_FL_cementdekvloer 50_gen_ISR | 15 | 448
4006667 | 01 eerste verdieping | 01 eerste verdieping | Floor : NLRS_43_FL_cementdekvloer 50_gen_ISR | 15 | 474
4006703 | 01 eerste verdieping | 01 eerste verdieping | Level : 01 eerste verdieping | 15 | 481
4006752 | 01 eerste verdieping | 01 eerste verdieping | Floor : NLRS_43_FL_cementdekvloer 50_gen_ISR | 15 | 486
4008223 | 02 tweede verdieping | 02 tweede verdieping | Level : 02 tweede verdieping | 15 | 492
4008279 | 02 tweede verdieping | 02 tweede verdieping | Floor : NLRS_43_FL_cementdekvloer 50_gen_ISR | 15 | 497
4008307 | 02 tweede verdieping | 02 tweede verdieping | Floor : NLRS_43_FL_cementdekvloer 50_gen_ISR | 15 | 501
4008321 | 02 tweede verdieping | 02 tweede verdieping | Level : 02 tweede verdieping | 15 | 506
4008391 | 02 tweede verdieping | 02 tweede verdieping | Floor : NLRS_43_FL_cementdekvloer 50_gen_ISR | 15 | 511
4008419 | 02 tweede verdieping | 02 tweede verdieping | Floor : NLRS_43_FL_cementdekvloer 50_gen_ISR | 15 | 517

# IfcDoor: 32_ISR_onderdeel_deur:deur met glas, 32_ISR_onderdeel_deur:deur met glas:1945807
In: 00 begane grond
Type - OperationType: SINGLE_SWING_RIGHT; ConstructionType: USERDEFINED; ParameterTakesPrecedence: no; Sizeable: no; Material: a_paneel, ISR_Glas
Type - Analytical Properties - Define Thermal Properties by: Schematic Type; Analytic Construction: <None>
Type - Materials and Finishes - glas_materiaal: ISR_Glas
Type - Graphics - deur_met_glas: yes; dichte_deur: no; symbool_plgr: graphic_rond : 90_gr
Type - Construction - Function: Interior; Construction Type: deurblad
Type - Dimensions - deur_lijst_borstwering: 300 mm; deur_lijst_breedte: 110 mm; deur_lijst_breedte_scharnier: 110 mm
Type - Identity Data - Workset: Family : Doors : 32_ISR_onderdeel_deur; Assembly Code: 2E(32.31.21); Datum_Gewijzigd: 14-11-2012; Description: deur met glas; Fire Rating: 60; Model: LOD300; SmartRevit_Versie: 2013.2; Type Comments: deurblad; Type Mark: 18; Type Name: deur met glas
Type - Other - Category: Doors; Family Name: 32_ISR_onderdeel_deur
Type - 32_ISR_onderdeel_deur:deur met glas:1945807:1 - PanelOperation: SWINGING
OverallHeight: 2323 mm; OverallWidth: 922 mm; Classification: 2E(32.31.21) Uniformat (Uniformat)
Visibility - tekst_positie_boven: no
Fire Protection - brandwerendheid_120_min: no; brandwerendheid_30_min: no; brandwerendheid_90_min: no; zelfsluitend: yes; brandwerendheid_60_min: yes; fire_rating: 60
Constraints - Level: 00 begane grond; Moves With Nearby Elements: no; deur_breedte: 922 mm; Host: Level : 00 begane grond; Offset from Host: 10 mm
Phasing - Phase Created: 2. nieuwbouw
Dimensions - Area: 4.84976 m2; deur_hoogte: 2323 mm; Height: 2323 mm; Thickness: 55 mm; Volume: 0.0775116 m3; Width: 922 mm
Identity Data - Workset: Workset1; Mark: 419
Other - tekst_boven: no; Family: 32_ISR_onderdeel_deur; tekst_onder: yes; Family and Type: 32_ISR_onderdeel_deur: deur met glas; Type: deur met glas; Type Id: 1396098

# IfcDoor: 32_ISR_onderdeel_deur:deur met glas, 32_ISR_onderdeel_deur:deur met glas:1945808
In: 00 begane grond
Type - OperationType: SINGLE_SWING_RIGHT; ConstructionType: USERDEFINED; ParameterTakesPrecedence: no; Sizeable: no; Material: a_paneel, ISR_Glas
Type - Analytical Properties - Define Thermal Properties by: Schematic Type; Analytic Construction: <None>
Type - Materials and Finishes - glas_materiaal: ISR_Glas
Type - Graphics - deur_met_glas: yes; dichte_deur: no; symbool_plgr: graphic_rond : 90_gr
Type - Construction - Function: Interior; Construction Type: deurblad
Type - Dimensions - deur_lijst_borstwering: 300 mm; deur_lijst_breedte: 110 mm; deur_lijst_breedte_scharnier: 110 mm
Type - Identity Data - Workset: Family : Doors : 32_ISR_onderdeel_deur; Assembly Code: 2E(32.31.21); Datum_Gewijzigd: 14-11-2012; Description: deur met glas; Fire Rating: 60; Model: LOD300; SmartRevit_Versie: 2013.2; Type Comments: deurblad; Type Mark: 18; Type Name: deur met glas
Type - Other - Category: Doors; Family Name: 32_ISR_onderdeel_deur
Type - 32_ISR_onderdeel_deur:deur met glas:1945808:1 - PanelOperation: SWINGING
OverallHeight: 2323 mm; OverallWidth: 922 mm; Classification: 2E(32.31.21) Uniformat (Uniformat)
Visibility - tekst_positie_boven: no
Fire Protection - brandwerendheid_120_min: no; brandwerendheid_30_min: no; brandwerendheid_90_min: no; zelfsluitend: yes; brandwerendheid_60_min: yes; fire_rating: 60
Constraints - Level: 00 begane grond; Moves With Nearby Elements: no; deur_breedte: 922 mm; Host: Level : 00 begane grond; Offset from Host: 10 mm
Phasing - Phase Created: 2. nieuwbouw
Dimensions - Area: 4.84976 m2; deur_hoogte: 2323 mm; Height: 2323 mm; Thickness: 55 mm; Volume: 0.0775116 m3; Width: 922 mm
Identity Data - Workset: Workset1; Mark: 418
Other - tekst_boven: no; Family: 32_ISR_onderdeel_deur; tekst_onder: yes; Family and Type: 32_ISR_onderdeel_deur: deur met glas; Type: deur met glas; Type Id: 1396098

# IfcDoor: 32_ISR_onderdeel_deur:deur met glas, 32_ISR_onderdeel_deur:deur met glas:2522336
In: 00 begane grond
Type - OperationType: SINGLE_SWING_RIGHT; ConstructionType: USERDEFINED; ParameterTakesPrecedence: no; Sizeable: no; Material: a_paneel, ISR_Glas
Type - Analytical Properties - Define Thermal Properties by: Schematic Type; Analytic Construction: <None>
Type - Materials and Finishes - glas_materiaal: ISR_Glas
Type - Graphics - deur_met_glas: yes; dichte_deur: no; symbool_plgr: graphic_rond : 90_gr
Type - Construction - Function: Interior; Construction Type: deurblad
Type - Dimensions - deur_lijst_borstwering: 300 mm; deur_lijst_breedte: 110 mm; deur_lijst_breedte_scharnier: 110 mm
Type - Identity Data - Workset: Family : Doors : 32_ISR_onderdeel_deur; Assembly Code: 2E(32.31.21); Datum_Gewijzigd: 14-11-2012; Description: deur met glas; Fire Rating: 60; Model: LOD300; SmartRevit_Versie: 2013.2; Type Comments: deurblad; Type Mark: 18; Type Name: deur met glas
Type - Other - Category: Doors; Family Name: 32_ISR_onderdeel_deur
Type - 32_ISR_onderdeel_deur:deur met glas:2522336:1 - PanelOperation: SWINGING
OverallHeight: 2315 mm; OverallWidth: 930 mm; Classification: 2E(32.31.21) Uniformat (Uniformat)
Visibility - tekst_positie_boven: yes
Fire Protection - brandwerendheid_120_min: no; brandwerendheid_30_min: no; brandwerendheid_90_min: no; zelfsluitend: yes; brandwerendheid_60_min: yes; fire_rating: 60
Constraints - Level: 00 begane grond; Moves With Nearby Elements: no; deur_breedte: 930 mm; Host: Level : 00 begane grond; Offset from Host: 15 mm
Phasing - Phase Created: 2. nieuwbouw
Dimensions - Area: 4.87205 m2; deur_hoogte: 2315 mm; Height: 2315 mm; Thickness: 55 mm; Volume: 0.0778358 m3; Width: 930 mm
Identity Data - Workset: Workset1; Mark: 463
Other - tekst_onder: no; Family: 32_ISR_onderdeel_deur; Family and Type: 32_ISR_onderdeel_deur: deur met glas; Type: deur met glas; Type Id: 1396098; tekst_boven: yes

# IfcDoor: 32_ISR_onderdeel_deur:deur met glas, 32_ISR_onderdeel_deur:deur met glas:2661591
In: 00 begane grond
Type - OperationType: SINGLE_SWING_RIGHT; ConstructionType: USERDEFINED; ParameterTakesPrecedence: no; Sizeable: no; Material: a_paneel, ISR_Glas
Type - Analytical Properties - Define Thermal Properties by: Schematic Type; Analytic Construction: <None>
Type - Materials and Finishes - glas_materiaal: ISR_Glas
Type - Graphics - deur_met_glas: yes; dichte_deur: no; symbool_plgr: graphic_rond : 90_gr
Type - Construction - Function: Interior; Construction Type: deurblad
Type - Dimensions - deur_lijst_borstwering: 300 mm; deur_lijst_breedte: 110 mm; deur_lijst_breedte_scharnier: 110 mm
Type - Identity Data - Workset: Family : Doors : 32_ISR_onderdeel_deur; Assembly Code: 2E(32.31.21); Datum_Gewijzigd: 14-11-2012; Description: deur met glas; Fire Rating: 60; Model: LOD300; SmartRevit_Versie: 2013.2; Type Comments: deurblad; Type Mark: 18; Type Name: deur met glas
Type - Other - Category: Doors; Family Name: 32_ISR_onderdeel_deur
Type - 32_ISR_onderdeel_deur:deur met glas:2661591:1 - PanelOperation: SWINGING
OverallHeight: 2315 mm; OverallWidth: 930 mm; Classification: 2E(32.31.21) Uniformat (Uniformat)
Visibility - tekst_positie_boven: yes
Fire Protection - brandwerendheid_120_min: no; brandwerendheid_30_min: no; brandwerendheid_90_min: no; zelfsluitend: yes; brandwerendheid_60_min: yes; fire_rating: 60
Constraints - Level: 00 begane grond; Moves With Nearby Elements: no; deur_breedte: 930 mm; Host: Level : 00 begane grond; Offset from Host: 20 mm
Phasing - Phase Created: 2. nieuwbouw
Dimensions - Area: 4.87205 m2; deur_hoogte: 2315 mm; Height: 2315 mm; Thickness: 55 mm; Volume: 0.0778358 m3; Width: 930 mm
Identity Data - Workset: Workset1; Mark: 384
Other - tekst_onder: no; Family: 32_ISR_onderdeel_deur; Family and Type: 32_ISR_onderdeel_deur: deur met glas; Type: deur met glas; Type Id: 1396098; tekst_boven: yes

# IfcDoor: 32_ISR_onderdeel_deur:deur met glas, 32_ISR_onderdeel_deur:deur met glas:2719870
In: 00 begane grond
Type - OperationType: SINGLE_SWING_RIGHT; ConstructionType: USERDEFINED; ParameterTakesPrecedence: no; Sizeable: no; Material: a_paneel, ISR_Glas
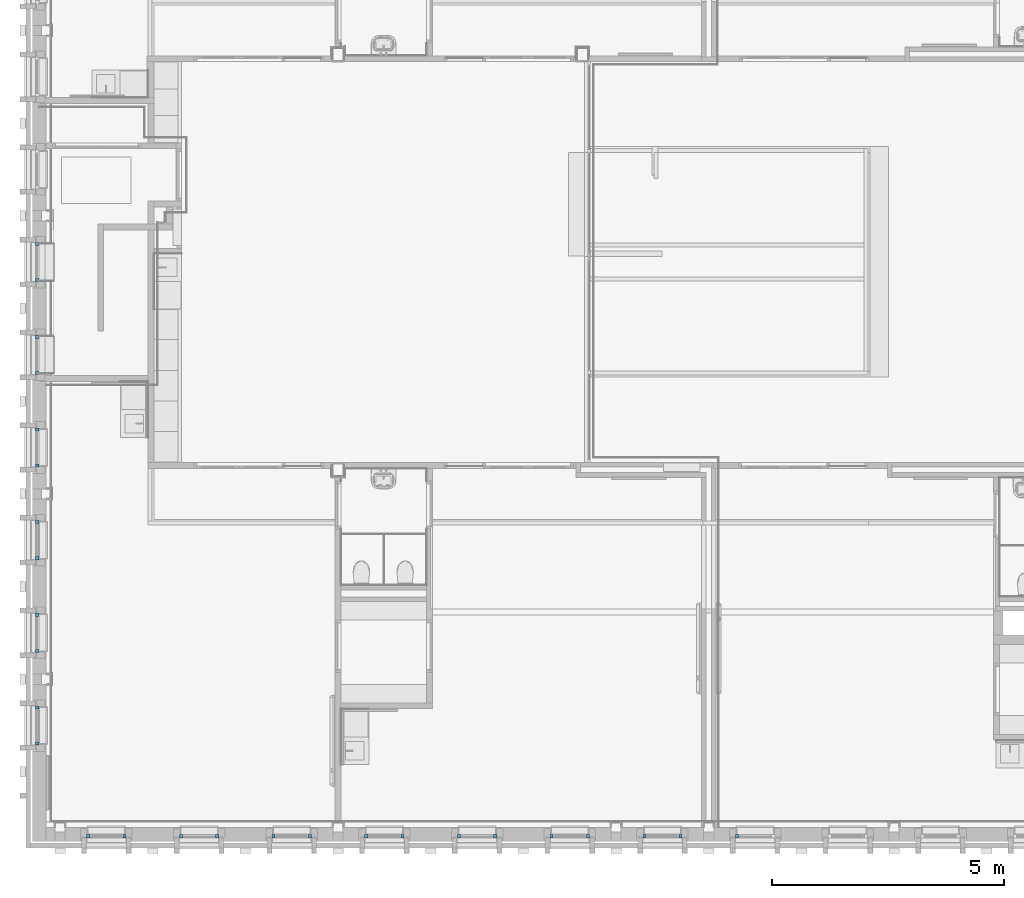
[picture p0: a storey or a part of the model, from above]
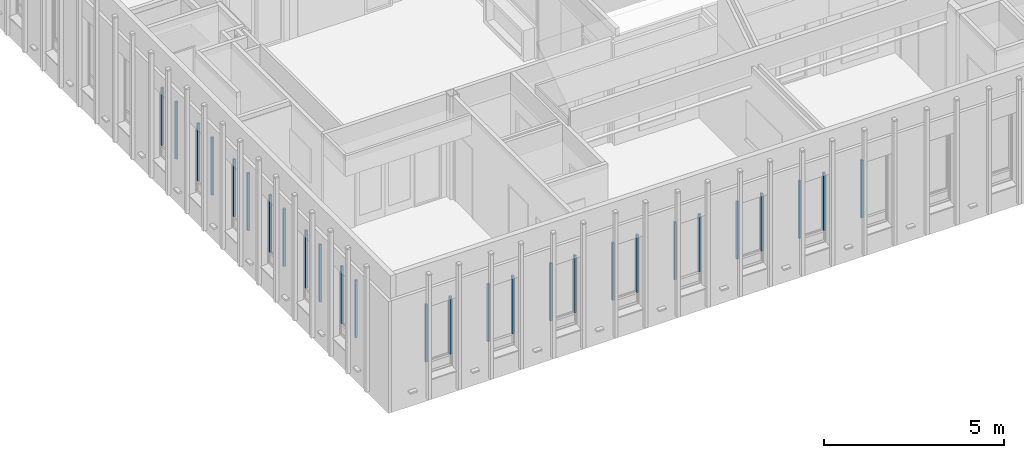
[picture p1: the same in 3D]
Properties of the parts of a building model (IFC2X3), part 9 of 94

# IfcDoor: 32_ISR_onderdeel_deur:deur met glas, 32_ISR_onderdeel_deur:deur met glas:2719870
Type - Analytical Properties - Define Thermal Properties by: Schematic Type; Analytic Construction: <None>
Type - Materials and Finishes - glas_materiaal: ISR_Glas
Type - Graphics - deur_met_glas: yes; dichte_deur: no; symbool_plgr: graphic_rond : 90_gr
Type - Construction - Function: Interior; Construction Type: deurblad
Type - Dimensions - deur_lijst_borstwering: 300 mm; deur_lijst_breedte: 110 mm; deur_lijst_breedte_scharnier: 110 mm
Type - Identity Data - Workset: Family : Doors : 32_ISR_onderdeel_deur; Assembly Code: 2E(32.31.21); Datum_Gewijzigd: 14-11-2012; Description: deur met glas; Fire Rating: 60; Model: LOD300; SmartRevit_Versie: 2013.2; Type Comments: deurblad; Type Mark: 18; Type Name: deur met glas
Type - Other - Category: Doors; Family Name: 32_ISR_onderdeel_deur
Type - 32_ISR_onderdeel_deur:deur met glas:2719870:1 - PanelOperation: SWINGING
OverallHeight: 2315 mm; OverallWidth: 914 mm; Classification: 2E(32.31.21) Uniformat (Uniformat)
Visibility - tekst_positie_boven: no
Fire Protection - brandwerendheid_120_min: no; brandwerendheid_30_min: no; brandwerendheid_60_min: no; brandwerendheid_90_min: no; zelfsluitend: yes
Constraints - Level: 00 begane grond; Moves With Nearby Elements: no; deur_breedte: 914 mm; Host: Level : 00 begane grond; Offset from Host: 10 mm
Phasing - Phase Created: 2. nieuwbouw
Dimensions - Area: 4.62009 m2; deur_hoogte: 2315 mm; Height: 2315 mm; Thickness: 40 mm; Volume: 0.0449743 m3; Width: 914 mm
Identity Data - Workset: Workset1; Mark: 452
Other - tekst_boven: no; tekst_onder: no; Family: 32_ISR_onderdeel_deur; Family and Type: 32_ISR_onderdeel_deur: deur met glas; Type: deur met glas; Type Id: 1396098

# IfcDoor: 32_ISR_onderdeel_deur:deur met glas, 32_ISR_onderdeel_deur:deur met glas:2719871
In: 00 begane grond
Type - OperationType: SINGLE_SWING_RIGHT; ConstructionType: USERDEFINED; ParameterTakesPrecedence: no; Sizeable: no; Material: a_paneel, ISR_Glas
Type - Analytical Properties - Define Thermal Properties by: Schematic Type; Analytic Construction: <None>
Type - Materials and Finishes - glas_materiaal: ISR_Glas
Type - Graphics - deur_met_glas: yes; dichte_deur: no; symbool_plgr: graphic_rond : 90_gr
Type - Construction - Function: Interior; Construction Type: deurblad
Type - Dimensions - deur_lijst_borstwering: 300 mm; deur_lijst_breedte: 110 mm; deur_lijst_breedte_scharnier: 110 mm
Type - Identity Data - Workset: Family : Doors : 32_ISR_onderdeel_deur; Assembly Code: 2E(32.31.21); Datum_Gewijzigd: 14-11-2012; Description: deur met glas; Fire Rating: 60; Model: LOD300; SmartRevit_Versie: 2013.2; Type Comments: deurblad; Type Mark: 18; Type Name: deur met glas
Type - Other - Category: Doors; Family Name: 32_ISR_onderdeel_deur
Type - 32_ISR_onderdeel_deur:deur met glas:2719871:1 - PanelOperation: SWINGING
OverallHeight: 2315 mm; OverallWidth: 914 mm; Classification: 2E(32.31.21) Uniformat (Uniformat)
Visibility - tekst_positie_boven: no
Fire Protection - brandwerendheid_120_min: no; brandwerendheid_30_min: no; brandwerendheid_60_min: no; brandwerendheid_90_min: no; zelfsluitend: yes
Constraints - Level: 00 begane grond; Moves With Nearby Elements: no; deur_breedte: 914 mm; Host: Level : 00 begane grond; Offset from Host: 10 mm
Phasing - Phase Created: 2. nieuwbouw
Dimensions - Area: 4.62009 m2; deur_hoogte: 2315 mm; Height: 2315 mm; Thickness: 40 mm; Volume: 0.0449743 m3; Width: 914 mm
Identity Data - Workset: Workset1; Mark: 453
Other - tekst_boven: no; tekst_onder: no; Family: 32_ISR_onderdeel_deur; Family and Type: 32_ISR_onderdeel_deur: deur met glas; Type: deur met glas; Type Id: 1396098

# IfcDoor: 32_ISR_onderdeel_deur:deur met glasstrook (7)
Type - OperationType: SINGLE_SWING_RIGHT; ConstructionType: USERDEFINED; ParameterTakesPrecedence: no; Sizeable: no; Material: a_paneel, ISR_Glas
Type - 32_ISR_onderdeel_deur:deur met glasstrook:1292038:1 - PanelOperation: SWINGING
Type - Analytical Properties - Define Thermal Properties by: Schematic Type; Analytic Construction: <None>
Type - Materials and Finishes - glas_materiaal: ISR_Glas
Type - Graphics - deur_met_glas: yes; dichte_deur: no; symbool_plgr: graphic_rond : 90_gr
Type - Construction - Function: Interior; Construction Type: deurblad
Type - Dimensions - deur_lijst_borstwering: 300 mm; deur_lijst_breedte: 110 mm; deur_lijst_breedte_scharnier: 670 mm
Type - Identity Data - Assembly Code: 2E(32.31.21); Datum_Gewijzigd: 14-11-2012; Description: deur met glas; Fire Rating: 60; Model: LOD300; SmartRevit_Versie: 2013.2; Type Comments: deurblad; Type Mark: 46; Type Name: deur met glasstrook; Workset: Family : Doors : 32_ISR_onderdeel_deur
Type - Other - Category: Doors; Family Name: 32_ISR_onderdeel_deur
OverallHeight: 2315 mm; OverallWidth: 930 mm; Classification: 2E(32.31.21) Uniformat (Uniformat)
Visibility - tekst_positie_boven: no
Fire Protection - zelfsluitend: no; brandwerendheid_120_min: no; brandwerendheid_30_min: no; brandwerendheid_60_min: no; brandwerendheid_90_min: no
Constraints - Moves With Nearby Elements: no; deur_breedte: 930 mm; Offset from Host: 20 mm
Phasing - Phase Created: 2. nieuwbouw
Dimensions - Area: 4.66825 m2; deur_hoogte: 2315 mm; Height: 2315 mm; Thickness: 40 mm; Volume: 0.0775455 m3; Width: 930 mm
Identity Data - Workset: Workset1
Other - tekst_boven: no; tekst_onder: no; Family: 32_ISR_onderdeel_deur; Family and Type: 32_ISR_onderdeel_deur: deur met glasstrook; Type: deur met glasstrook; Type Id: 1417016
Name (32_ISR_onderdeel_deur:deur met glasstrook:...) | In | Level | Host | Mark
1292038 | 02 tweede verdieping | 02 tweede verdieping | Level : 02 tweede verdieping | 86
1294822 | 00 begane grond | 00 begane grond | Level : 00 begane grond | 191
1366926 | 00 begane grond | 00 begane grond | Level : 00 begane grond | 218
1366999 | 00 begane grond | 00 begane grond | Level : 00 begane grond | 224
1367241 | 00 begane grond | 00 begane grond | Level : 00 begane grond | 233
1367338 | 00 begane grond | 00 begane grond | Level : 00 begane grond | 239
1878841 | 00 begane grond | 00 begane grond | Level : 00 begane grond | 404

# IfcDoor: 32_ISR_onderdeel_deur:deur met glasstrook (6)
Type - OperationType: SINGLE_SWING_RIGHT; ConstructionType: USERDEFINED; ParameterTakesPrecedence: no; Sizeable: no; Material: a_paneel, ISR_Glas
Type - Analytical Properties - Define Thermal Properties by: Schematic Type; Analytic Construction: <None>
Type - Materials and Finishes - glas_materiaal: ISR_Glas
Type - Graphics - deur_met_glas: yes; dichte_deur: no; symbool_plgr: graphic_rond : 90_gr
Type - Construction - Function: Interior; Construction Type: deurblad
Type - Dimensions - deur_lijst_borstwering: 300 mm; deur_lijst_breedte: 110 mm; deur_lijst_breedte_scharnier: 670 mm
Type - Identity Data - Assembly Code: 2E(32.31.21); Datum_Gewijzigd: 14-11-2012; Description: deur met glas; Fire Rating: 60; Model: LOD300; SmartRevit_Versie: 2013.2; Type Comments: deurblad; Type Mark: 46; Type Name: deur met glasstrook; Workset: Family : Doors : 32_ISR_onderdeel_deur
Type - Other - Category: Doors; Family Name: 32_ISR_onderdeel_deur
Type - 32_ISR_onderdeel_deur:deur met glasstrook:1294865:1 - PanelOperation: SWINGING
OverallHeight: 2315 mm; OverallWidth: 930 mm; Classification: 2E(32.31.21) Uniformat (Uniformat)
Visibility - tekst_positie_boven: no
Fire Protection - zelfsluitend: no; brandwerendheid_120_min: no; brandwerendheid_30_min: no; brandwerendheid_60_min: no; brandwerendheid_90_min: no
Constraints - Moves With Nearby Elements: no; deur_breedte: 930 mm; Offset from Host: 20 mm
Phasing - Phase Created: 2. nieuwbouw
Dimensions - Area: 4.66825 m2; deur_hoogte: 2315 mm; Height: 2315 mm; Thickness: 40 mm; Volume: 0.0775455 m3; Width: 930 mm
Identity Data - Workset: Workset1
Other - tekst_boven: no; tekst_onder: no; Family: 32_ISR_onderdeel_deur; Family and Type: 32_ISR_onderdeel_deur: deur met glasstrook; Type: deur met glasstrook; Type Id: 1417016
Name (32_ISR_onderdeel_deur:deur met glasstrook:...) | In | Level | Host | Mark
1294865 | 00 begane grond | 00 begane grond | Level : 00 begane grond | 194
1366963 | 00 begane grond | 00 begane grond | Level : 00 begane grond | 221
1367106 | 00 begane grond | 00 begane grond | Level : 00 begane grond | 227
1367159 | 00 begane grond | 00 begane grond | Level : 00 begane grond | 230
1367459 | 00 begane grond | 00 begane grond | Level : 00 begane grond | 242
1516492 | 02 tweede verdieping | 02 tweede verdieping | Level : 02 tweede verdieping | 298

# IfcDoor: 32_ISR_onderdeel_deur:deur met glasstrook, 32_ISR_onderdeel_deur:deur met glasstrook:1371863
In: 00 begane grond
Type - OperationType: SINGLE_SWING_RIGHT; ConstructionType: USERDEFINED; ParameterTakesPrecedence: no; Sizeable: no; Material: a_paneel, ISR_Glas
Type - Analytical Properties - Define Thermal Properties by: Schematic Type; Analytic Construction: <None>
Type - Materials and Finishes - glas_materiaal: ISR_Glas
Type - Graphics - deur_met_glas: yes; dichte_deur: no; symbool_plgr: graphic_rond : 90_gr
Type - Construction - Function: Interior; Construction Type: deurblad
Type - Dimensions - deur_lijst_borstwering: 300 mm; deur_lijst_breedte: 110 mm; deur_lijst_breedte_scharnier: 670 mm
Type - Identity Data - Assembly Code: 2E(32.31.21); Datum_Gewijzigd: 14-11-2012; Description: deur met glas; Fire Rating: 60; Model: LOD300; SmartRevit_Versie: 2013.2; Type Comments: deurblad; Type Mark: 46; Type Name: deur met glasstrook; Workset: Family : Doors : 32_ISR_onderdeel_deur
Type - Other - Category: Doors; Family Name: 32_ISR_onderdeel_deur
Type - 32_ISR_onderdeel_deur:deur met glasstrook:1371863:1 - PanelOperation: SWINGING
OverallHeight: 2315 mm; OverallWidth: 1030 mm; Classification: 2E(32.31.21) Uniformat (Uniformat)
Visibility - tekst_positie_boven: no
Fire Protection - zelfsluitend: no; brandwerendheid_120_min: no; brandwerendheid_30_min: no; brandwerendheid_60_min: no; brandwerendheid_90_min: no
Constraints - Level: 00 begane grond; Moves With Nearby Elements: no; deur_breedte: 1030 mm; Host: Level : 00 begane grond; Offset from Host: 20 mm
Phasing - Phase Created: 2. nieuwbouw
Dimensions - Area: 5.14425 m2; deur_hoogte: 2315 mm; Height: 2315 mm; Thickness: 40 mm; Volume: 0.0810905 m3; Width: 1030 mm
Identity Data - Workset: Workset1; Mark: 269
Other - tekst_boven: no; tekst_onder: no; Family: 32_ISR_onderdeel_deur; Family and Type: 32_ISR_onderdeel_deur: deur met glasstrook; Type: deur met glasstrook; Type Id: 1417016

# IfcDoor: 32_ISR_onderdeel_deur:dichte deur (7)
Type - OperationType: SINGLE_SWING_RIGHT; ConstructionType: USERDEFINED; ParameterTakesPrecedence: no; Sizeable: no; Material: a_paneel
Type - 32_ISR_onderdeel_deur:dichte deur:1399834:1 - PanelOperation: SWINGING
Type - Analytical Properties - Define Thermal Properties by: Schematic Type; Analytic Construction: <None>
Type - Graphics - deur_met_glas: no; dichte_deur: yes; symbool_plgr: graphic_rond : 90_gr
Type - Construction - Function: Interior; Construction Type: deurblad
Type - Dimensions - deur_lijst_borstwering: 300 mm; deur_lijst_breedte: 110 mm; deur_lijst_breedte_scharnier: 110 mm
Type - Identity Data - Workset: Family : Doors : 32_ISR_onderdeel_deur; Assembly Code: 2E(32.31.21); Datum_Gewijzigd: 14-11-2012; Description: deur; Model: LOD300; SmartRevit_Versie: 2013.2; Type Comments: deurblad; Type Mark: 19; Type Name: dichte deur
Type - Other - Category: Doors; Family Name: 32_ISR_onderdeel_deur
OverallHeight: 2320 mm; OverallWidth: 930 mm; Classification: 2E(32.31.21) Uniformat (Uniformat)
Visibility - tekst_positie_boven: yes
Fire Protection - zelfsluitend: no; brandwerendheid_120_min: no; brandwerendheid_30_min: no; brandwerendheid_60_min: no; brandwerendheid_90_min: no
Constraints - Moves With Nearby Elements: no; deur_breedte: 930 mm; Offset from Host: 15 mm
Phasing - Phase Created: 2. nieuwbouw
Dimensions - Area: 4.7062 m2; deur_hoogte: 2320 mm; Height: 2320 mm; Thickness: 40 mm; Volume: 0.086304 m3; Width: 930 mm
Identity Data - Workset: Workset1
Other - tekst_boven: no; tekst_onder: no; Type: dichte deur; Family: 32_ISR_onderdeel_deur; Family and Type: 32_ISR_onderdeel_deur: dichte deur; Type Id: 1396099
Name (32_ISR_onderdeel_deur:dichte deur:...) | In | Level | Host | Mark
1399834 | 00 begane grond | 00 begane grond | Level : 00 begane grond | 280
1400067 | 00 begane grond | 00 begane grond | Floor : NLRS_43_FL_cementdekvloer 60_gen_ISR | 289
1527031 | 00 begane grond | 00 begane grond | Level : 00 begane grond | 299
1612428 | 00 begane grond | 00 begane grond | Floor : NLRS_43_FL_cementdekvloer 60_gen_ISR | 324
2045690 | 01 eerste verdieping | 01 eerste verdieping | Level : 01 eerste verdieping | 425
2048871 | 01 eerste verdieping | 01 eerste verdieping | Level : 01 eerste verdieping | 427
2743619 | 01 eerste verdieping | 01 eerste verdieping | Level : 01 eerste verdieping | 477

# IfcDoor: 32_ISR_onderdeel_deur:dichte deur (4)
Type - OperationType: SINGLE_SWING_RIGHT; ConstructionType: USERDEFINED; ParameterTakesPrecedence: no; Sizeable: no; Material: a_paneel
Type - Analytical Properties - Define Thermal Properties by: Schematic Type; Analytic Construction: <None>
Type - Graphics - deur_met_glas: no; dichte_deur: yes; symbool_plgr: graphic_rond : 90_gr
Type - Construction - Function: Interior; Construction Type: deurblad
Type - Dimensions - deur_lijst_borstwering: 300 mm; deur_lijst_breedte: 110 mm; deur_lijst_breedte_scharnier: 110 mm
Type - Identity Data - Workset: Family : Doors : 32_ISR_onderdeel_deur; Assembly Code: 2E(32.31.21); Datum_Gewijzigd: 14-11-2012; Description: deur; Model: LOD300; SmartRevit_Versie: 2013.2; Type Comments: deurblad; Type Mark: 19; Type Name: dichte deur
Type - Other - Category: Doors; Family Name: 32_ISR_onderdeel_deur
Type - 32_ISR_onderdeel_deur:dichte deur:1400007:1 - PanelOperation: SWINGING
OverallHeight: 2320 mm; OverallWidth: 930 mm; Classification: 2E(32.31.21) Uniformat (Uniformat)
Visibility - tekst_positie_boven: yes
Fire Protection - zelfsluitend: no; brandwerendheid_120_min: no; brandwerendheid_30_min: no; brandwerendheid_60_min: no; brandwerendheid_90_min: no
Constraints - Moves With Nearby Elements: no; deur_breedte: 930 mm; Offset from Host: 15 mm
Phasing - Phase Created: 2. nieuwbouw
Dimensions - Area: 4.7062 m2; deur_hoogte: 2320 mm; Height: 2320 mm; Thickness: 40 mm; Volume: 0.086304 m3; Width: 930 mm
Identity Data - Workset: Workset1
Other - tekst_boven: no; tekst_onder: no; Type: dichte deur; Family: 32_ISR_onderdeel_deur; Family and Type: 32_ISR_onderdeel_deur: dichte deur; Type Id: 1396099
Name (32_ISR_onderdeel_deur:dichte deur:...) | In | Level | Host | Mark
1400007 | 00 begane grond | 00 begane grond | Level : 00 begane grond | 285
1400146 | 00 begane grond | 00 begane grond | Level : 00 begane grond | 294
1612367 | 00 begane grond | 00 begane grond | Level : 00 begane grond | 320
4493361 | 01 eerste verdieping | 01 eerste verdieping | Floor : NLRS_43_FL_cementdekvloer 50_gen_ISR | 398

# IfcDoor: 32_ISR_onderdeel_deur:dichte deur (2)
Type - OperationType: SINGLE_SWING_RIGHT; ConstructionType: USERDEFINED; ParameterTakesPrecedence: no; Sizeable: no; Material: a_paneel
Type - Analytical Properties - Define Thermal Properties by: Schematic Type; Analytic Construction: <None>
Type - Graphics - deur_met_glas: no; dichte_deur: yes; symbool_plgr: graphic_rond : 90_gr
Type - Construction - Function: Interior; Construction Type: deurblad
Type - Dimensions - deur_lijst_borstwering: 300 mm; deur_lijst_breedte: 110 mm; deur_lijst_breedte_scharnier: 110 mm
Type - Identity Data - Workset: Family : Doors : 32_ISR_onderdeel_deur; Assembly Code: 2E(32.31.21); Datum_Gewijzigd: 14-11-2012; Description: deur; Model: LOD300; SmartRevit_Versie: 2013.2; Type Comments: deurblad; Type Mark: 19; Type Name: dichte deur
Type - Other - Category: Doors; Family Name: 32_ISR_onderdeel_deur
Type - 32_ISR_onderdeel_deur:dichte deur:1763188:1 - PanelOperation: SWINGING
OverallHeight: 2315 mm; OverallWidth: 900 mm; Classification: 2E(32.31.21) Uniformat (Uniformat)
Visibility - tekst_positie_boven: no
Fire Protection - zelfsluitend: no; brandwerendheid_120_min: no; brandwerendheid_30_min: no; brandwerendheid_60_min: no; brandwerendheid_90_min: no
Constraints - Moves With Nearby Elements: no; deur_breedte: 900 mm
Phasing - Phase Created: 2. nieuwbouw
Dimensions - Area: 4.55345 m2; deur_hoogte: 2315 mm; Height: 2315 mm; Thickness: 40 mm; Volume: 0.08334 m3; Width: 900 mm
Identity Data - Workset: Workset1
Other - tekst_boven: no; tekst_onder: no; Type: dichte deur; Family: 32_ISR_onderdeel_deur; Family and Type: 32_ISR_onderdeel_deur: dichte deur; Type Id: 1396099
Name (32_ISR_onderdeel_deur:dichte deur:...) | In | Level | Host | Offset from Host (mm) | Mark
1763188 | 00 begane grond | 00 begane grond | Level : 00 begane grond | 10 | 377
2089378 | 02 tweede verdieping | 02 tweede verdieping | Level : 02 tweede verdieping | 20 | 435

# IfcDoor: 32_ISR_onderdeel_deur:dichte deur (2)
Type - OperationType: SINGLE_SWING_RIGHT; ConstructionType: USERDEFINED; ParameterTakesPrecedence: no; Sizeable: no; Material: a_paneel
Type - Analytical Properties - Define Thermal Properties by: Schematic Type; Analytic Construction: <None>
Type - Graphics - deur_met_glas: no; dichte_deur: yes; symbool_plgr: graphic_rond : 90_gr
Type - Construction - Function: Interior; Construction Type: deurblad
Type - Dimensions - deur_lijst_borstwering: 300 mm; deur_lijst_breedte: 110 mm; deur_lijst_breedte_scharnier: 110 mm
Type - Identity Data - Workset: Family : Doors : 32_ISR_onderdeel_deur; Assembly Code: 2E(32.31.21); Datum_Gewijzigd: 14-11-2012; Description: deur; Model: LOD300; SmartRevit_Versie: 2013.2; Type Comments: deurblad; Type Mark: 19; Type Name: dichte deur
Type - Other - Category: Doors; Family Name: 32_ISR_onderdeel_deur
Type - 32_ISR_onderdeel_deur:dichte deur:1763189:1 - PanelOperation: SWINGING
OverallHeight: 2315 mm; OverallWidth: 900 mm; Classification: 2E(32.31.21) Uniformat (Uniformat)
Visibility - tekst_positie_boven: no
Fire Protection - zelfsluitend: no; brandwerendheid_120_min: no; brandwerendheid_30_min: no; brandwerendheid_60_min: no; brandwerendheid_90_min: no
Constraints - Moves With Nearby Elements: no; deur_breedte: 900 mm; Offset from Host: 10 mm
Phasing - Phase Created: 2. nieuwbouw
Dimensions - Area: 4.55345 m2; deur_hoogte: 2315 mm; Height: 2315 mm; Thickness: 40 mm; Volume: 0.08334 m3; Width: 900 mm
Identity Data - Workset: Workset1
Other - tekst_boven: no; tekst_onder: no; Type: dichte deur; Family: 32_ISR_onderdeel_deur; Family and Type: 32_ISR_onderdeel_deur: dichte deur; Type Id: 1396099
Name (32_ISR_onderdeel_deur:dichte deur:...) | In | Level | Host | Mark
1763189 | 00 begane grond | 00 begane grond | Level : 00 begane grond | 376
2412596 | 02 tweede verdieping | 02 tweede verdieping | Level : 02 tweede verdieping | 437

# IfcDoor: 32_ISR_onderdeel_deur:dichte deur, 32_ISR_onderdeel_deur:dichte deur:3832979
In: 00 begane grond
Type - OperationType: SINGLE_SWING_RIGHT; ConstructionType: USERDEFINED; ParameterTakesPrecedence: no; Sizeable: no; Material: a_paneel
Type - Analytical Properties - Define Thermal Properties by: Schematic Type; Analytic Construction: <None>
Type - Graphics - deur_met_glas: no; dichte_deur: yes; symbool_plgr: graphic_rond : 90_gr
Type - Construction - Function: Interior; Construction Type: deurblad
Type - Dimensions - deur_lijst_borstwering: 300 mm; deur_lijst_breedte: 110 mm; deur_lijst_breedte_scharnier: 110 mm
Type - Identity Data - Workset: Family : Doors : 32_ISR_onderdeel_deur; Assembly Code: 2E(32.31.21); Datum_Gewijzigd: 14-11-2012; Description: deur; Model: LOD300; SmartRevit_Versie: 2013.2; Type Comments: deurblad; Type Mark: 19; Type Name: dichte deur
Type - Other - Category: Doors; Family Name: 32_ISR_onderdeel_deur
Type - 32_ISR_onderdeel_deur:dichte deur:3832979:1 - PanelOperation: SWINGING
OverallHeight: 2315 mm; OverallWidth: 930 mm; Classification: 2E(32.31.21) Uniformat (Uniformat)
Visibility - tekst_positie_boven: no
Fire Protection - brandwerendheid_120_min: no; brandwerendheid_30_min: no; brandwerendheid_90_min: no; zelfsluitend: yes; brandwerendheid_60_min: yes; fire_rating: 60
Constraints - Level: 00 begane grond; Moves With Nearby Elements: no; deur_breedte: 930 mm; Host: Level : 00 begane grond; Offset from Host: 20 mm
Phasing - Phase Created: 2. nieuwbouw
Dimensions - Area: 4.87205 m2; deur_hoogte: 2315 mm; Height: 2315 mm; Thickness: 55 mm; Volume: 0.118412 m3; Width: 930 mm
Identity Data - Workset: Workset1; Mark: 388
Other - tekst_boven: no; Type: dichte deur; Family: 32_ISR_onderdeel_deur; tekst_onder: yes; Family and Type: 32_ISR_onderdeel_deur: dichte deur; Type Id: 1396099

# IfcDoor: 32_ISR_onderdeel_deur:dichte deur, 32_ISR_onderdeel_deur:dichte deur:3832980
In: 00 begane grond
Type - OperationType: SINGLE_SWING_RIGHT; ConstructionType: USERDEFINED; ParameterTakesPrecedence: no; Sizeable: no; Material: a_paneel
Type - Analytical Properties - Define Thermal Properties by: Schematic Type; Analytic Construction: <None>
Type - Graphics - deur_met_glas: no; dichte_deur: yes; symbool_plgr: graphic_rond : 90_gr
Type - Construction - Function: Interior; Construction Type: deurblad
Type - Dimensions - deur_lijst_borstwering: 300 mm; deur_lijst_breedte: 110 mm; deur_lijst_breedte_scharnier: 110 mm
Type - Identity Data - Workset: Family : Doors : 32_ISR_onderdeel_deur; Assembly Code: 2E(32.31.21); Datum_Gewijzigd: 14-11-2012; Description: deur; Model: LOD300; SmartRevit_Versie: 2013.2; Type Comments: deurblad; Type Mark: 19; Type Name: dichte deur
Type - Other - Category: Doors; Family Name: 32_ISR_onderdeel_deur
Type - 32_ISR_onderdeel_deur:dichte deur:3832980:1 - PanelOperation: SWINGING
OverallHeight: 2315 mm; OverallWidth: 930 mm; Classification: 2E(32.31.21) Uniformat (Uniformat)
Visibility - tekst_positie_boven: no
Fire Protection - brandwerendheid_120_min: no; brandwerendheid_30_min: no; brandwerendheid_90_min: no; zelfsluitend: yes; brandwerendheid_60_min: yes; fire_rating: 60
Constraints - Level: 00 begane grond; Moves With Nearby Elements: no; deur_breedte: 930 mm; Host: Level : 00 begane grond; Offset from Host: 20 mm
Phasing - Phase Created: 2. nieuwbouw
Dimensions - Area: 4.87205 m2; deur_hoogte: 2315 mm; Height: 2315 mm; Thickness: 55 mm; Volume: 0.118412 m3; Width: 930 mm
Identity Data - Workset: Workset1; Mark: 387
Other - tekst_boven: no; Type: dichte deur; Family: 32_ISR_onderdeel_deur; tekst_onder: yes; Family and Type: 32_ISR_onderdeel_deur: dichte deur; Type Id: 1396099

# IfcDoor: 32_ISR_onderdeel_glasvlakvulling:glas (25)
Type - ConstructionType: USERDEFINED; ParameterTakesPrecedence: no; Sizeable: no; Material: ISR_Glas
Type - Analytical Properties - Define Thermal Properties by: Schematic Type; Analytic Construction: <None>
Type - Materials and Finishes - glas_materiaal: ISR_Glas
Type - Graphics - glas: yes; glas_symbool: 30_ISR_glassymbool_enkel
Type - Construction - Construction Type: glas in kozijn
Type - Dimensions - sponning_breedte: 17 mm
Type - Identity Data - Assembly Code: 2E(32.21.21); Datum_Gewijzigd: 14-11-2012; Description: glas in kozijn; Model: LOD300; SmartRevit_Versie: 2013.2; Type Comments: glas; Type Mark: 20; Type Name: glas; Workset: Family : Doors : 32_ISR_onderdeel_glasvlakvulling
Type - Other - Category: Doors; Family Name: 32_ISR_onderdeel_glasvlakvulling
OverallHeight: 2285 mm; Classification: 2E(32.21.21) Uniformat (Uniformat)
Analysis Results - lichtdoorlaat_hoogte: 2251 mm
Constraints - Moves With Nearby Elements: no; Offset from Host: 52 mm
Phasing - Phase Created: 2. nieuwbouw
Dimensions - glas_dikte: 8 mm; GlasHoogte: 2285 mm; Height: 2285 mm
Identity Data - Workset: Workset1
Other - Family: 32_ISR_onderdeel_glasvlakvulling; Family and Type: 32_ISR_onderdeel_glasvlakvulling: glas; glas_hartlijn: 35 mm; Type: glas; Type Id: 1396160
Name (32_ISR_onderdeel_glasvlakvulling:glas:...) | In | OverallWidth (mm) = GlasBreedte (mm) = Width (mm) | lichtdoorlaat_breedte (mm) | lichtdoorlaat_opp (m2) | Level | Host | Area (m2) | GlasOpp (m2) | Volume (m3) | Mark
1399704 | 00 begane grond | 1913 | 1879 | 3.63748 | 00 begane grond | Level : 00 begane grond | 8.80958 | 4.3712 | 0.0349696 | 276
1399974 | 00 begane grond | 1913 | 1879 | 3.63748 | 00 begane grond | Level : 00 begane grond | 8.80958 | 4.3712 | 0.0349696 | 282
1400066 | 00 begane grond | 1913 | 1879 | 3.63748 | 00 begane grond | Floor : NLRS_43_FL_cementdekvloer 60_gen_ISR | 8.80958 | 4.3712 | 0.0349696 | 288
1400119 | 00 begane grond | 1913 | 1879 | 3.63748 | 00 begane grond | Level : 00 begane grond | 8.80958 | 4.3712 | 0.0349696 | 291
1419667 | 00 begane grond | 891 | 857 | 1.65903 | 00 begane grond | Level : 00 begane grond | 4.12269 | 2.03594 | 0.0162875 | 310
1527032 | 00 begane grond | 468 | 434 | 0.840163 | 00 begane grond | Level : 00 begane grond | 2.18281 | 1.06938 | 0.00855504 | 298
1612368 | 00 begane grond | 468 | 434 | 0.840163 | 00 begane grond | Level : 00 begane grond | 2.18281 | 1.06938 | 0.00855504 | 319
1612429 | 00 begane grond | 468 | 434 | 0.840163 | 00 begane grond | Floor : NLRS_43_FL_cementdekvloer 60_gen_ISR | 2.18281 | 1.06938 | 0.00855504 | 325
2045674 | 01 eerste verdieping | 468 | 434 | 0.840163 | 01 eerste verdieping | Level : 01 eerste verdieping | 2.18281 | 1.06938 | 0.00855504 | 414
2048869 | 01 eerste verdieping | 468 | 434 | 0.840163 | 01 eerste verdieping | Level : 01 eerste verdieping | 2.18281 | 1.06938 | 0.00855504 | 426
2522337 | 00 begane grond | 873 | 839 | 1.62419 | 00 begane grond | Level : 00 begane grond | 4.04014 | 1.9948 | 0.0159584 | 462
2659987 | 00 begane grond | 618 | 584 | 1.13054 | 00 begane grond | Level : 00 begane grond | 2.87071 | 1.41213 | 0.011297 | 381
2743617 | 01 eerste verdieping | 468 | 434 | 0.840163 | 01 eerste verdieping | Level : 01 eerste verdieping | 2.18281 | 1.06938 | 0.00855504 | 476
4001725 | 01 eerste verdieping | 797 | 763 | 1.47706 | 01 eerste verdieping | Level : 01 eerste verdieping | 3.6916 | 1.82114 | 0.0145692 | 431
4006595 | 01 eerste verdieping | 797 | 763 | 1.47706 | 01 eerste verdieping | Floor : NLRS_43_FL_cementdekvloer 50_gen_ISR | 3.6916 | 1.82114 | 0.0145692 | 449
4006669 | 01 eerste verdieping | 797 | 763 | 1.47706 | 01 eerste verdieping | Floor : NLRS_43_FL_cementdekvloer 50_gen_ISR | 3.6916 | 1.82114 | 0.0145692 | 478
4006704 | 01 eerste verdieping | 797 | 763 | 1.47706 | 01 eerste verdieping | Level : 01 eerste verdieping | 3.6916 | 1.82114 | 0.0145692 | 480
4006754 | 01 eerste verdieping | 797 | 763 | 1.47706 | 01 eerste verdieping | Floor : NLRS_43_FL_cementdekvloer 50_gen_ISR | 3.6916 | 1.82114 | 0.0145692 | 488
4008225 | 02 tweede verdieping | 797 | 763 | 1.47706 | 02 tweede verdieping | Level : 02 tweede verdieping | 3.6916 | 1.82114 | 0.0145692 | 490
4008280 | 02 tweede verdieping | 797 | 763 | 1.47706 | 02 tweede verdieping | Floor : NLRS_43_FL_cementdekvloer 50_gen_ISR | 3.6916 | 1.82114 | 0.0145692 | 498
4008309 | 02 tweede verdieping | 797 | 763 | 1.47706 | 02 tweede verdieping | Floor : NLRS_43_FL_cementdekvloer 50_gen_ISR | 3.6916 | 1.82114 | 0.0145692 | 503
4008322 | 02 tweede verdieping | 797 | 763 | 1.47706 | 02 tweede verdieping | Level : 02 tweede verdieping | 3.6916 | 1.82114 | 0.0145692 | 505
4008393 | 02 tweede verdieping | 797 | 763 | 1.47706 | 02 tweede verdieping | Floor : NLRS_43_FL_cementdekvloer 50_gen_ISR | 3.6916 | 1.82114 | 0.0145692 | 513
4008420 | 02 tweede verdieping | 797 | 763 | 1.47706 | 02 tweede verdieping | Floor : NLRS_43_FL_cementdekvloer 50_gen_ISR | 3.6916 | 1.82114 | 0.0145692 | 518
4493362 | 01 eerste verdieping | 663 | 629 | 1.21766 | 01 eerste verdieping | Floor : NLRS_43_FL_cementdekvloer 50_gen_ISR | 3.07708 | 1.51496 | 0.0121196 | 412

# IfcDoor: DO_DT Pass door panel single hinged_Multiwal:DT - Select 100 K/U, DO_DT Pass door panel single hinged_Multiwal:DT - Select 100 K/U:1322224
In: 00 begane grond
Type - Description: DT Pass Door Panel (single hinged); ParameterTakesPrecedence: no; Sizeable: no; Material: Panel, Aluminium, black
Type - Analytical Properties - Define Thermal Properties by: Schematic Type; Analytic Construction: <None>
Type - Data - BIMObjectName: Pr_30_59_24_30-Multiwal-DT Pass Door Panel (single hinged)-LOD400; ClassificationName: Uniclass2015; ClassificationValue: Pr_30_59_24_30; COBie.Type.AccessibilityPerformance: N/A; COBie.Type.AssetType: Fixed; COBie.Type.Category: 23.30.10.00 - Doors; COBie.Type.CodePerformance: N/A; COBie.Type.Constituents: N/A; COBie.Type.CreatedBy: Itannex bv; COBie.Type.CreatedOn: 2018.11.29; COBie.Type.Description: DT Pass Door Panel (single hinged); COBie.Type.DurationUnit: N/A; COBie.Type.ExpectedLife: N/A; COBie.Type.Features: N/A; COBie.Type.Finish: N/A; COBie.Type.Grade: 3; COBie.Type.Manufacturer: Multiwal; COBie.Type.Material: N/A; COBie.Type.ModelNumber: N/A; COBie.Type.ModelReference: DT; COBie.Type.Name: Pass door panel (single hinged) DT - 100 K/U; COBie.Type.ReplacementCost: 0; COBie.Type.Shape: Rectangular; COBie.Type.Size: Thickness 105mm; COBie.Type.SustainabilityPerformance: N/A; COBie.Type.WarrantyDescription: N/A; COBie.Type.WarrantyDurationLabor: N/A; COBie.Type.WarrantyDurationParts: N/A; COBie.Type.WarrantyDurationUnit: N/A; COBie.Type.WarrantyGuarantorLabor: N/A; COBie.Type.WarrantyGuarantorParts: N/A
Type - General - RSen_C_code_ETIM: EC011925; RSen_C_code_ETIM_url: https://prod.etim-international.com/Class/Details?classId=EC011925&classVersion=3; RSen_C_content_creator: Itannex bv
Type - Materials and Finishes - NLRS_C_materiaal_01: ISR_Glas; NLRS_C_materiaal_02: Aluminium, black
Type - Construction - Function: Interior
Type - Dimensions - Thickness: 105 mm
Type - Identity Data - Assembly Code: 32.31; Assembly Description: binnenwandopeningen; gevuld met deuren, draaideuren; Description: DT Pass Door Panel (single hinged); Manufacturer: Multiwal; Manufacturers Address: Norman Road, Rochdale, OL11 4HS, United Kingdom; Manufacturers Email: info@multiwal.co.uk; Manufacturers Telephone Number: +441273497370; Model: DT; NLRS_C_content_datum_gewijzigd: 2018.12.28; NLRS_C_content_provider: Multiwal; NLRS_C_content_versie: 1.0; OmniClass Number: 23.30.10.00; OmniClass Title: Doors; RSen_C_product_description: Pass door panel (single hinged) DT - 100 K/U; Type Comments: Thickness 105mm, for Select 100 K/U; Type Mark: 9; Type Name: DT - Select 100 K/U; URL: https://uk.multiwal.eu/products/moveable-walls/moveable-wall-select/select-100-u/; Workset: Family : Doors : DO_DT Pass door panel single hinged_Multiwal
Type - Other - Category: Doors; Family Name: DO_DT Pass door panel single hinged_Multiwal; maxH: 12000 mm; maxW: 1210 mm; minH: 2000 mm; minW: 1210 mm
OverallHeight: 2800 mm; OverallWidth: 1230 mm; Classification: 22.14 Uniformat (Uniformat); Group: Model Group:BI-11 8834x2800:2521973
Data - COBie.Type.Area: 3.388 m2; COBie.Type.Length: 1210 mm; COBie.Type.NominalHeight: 2800 mm; COBie.Type.NominalLength: 1210 mm; COBie.Type.NominalWidth: 105 mm
Constraints - Level: 00 begane grond; door_height: 2100 mm; door_inside: yes; door_outside: no; door_rotation: Left/Inside; hinge_left: yes; hinge_right: no; soundproofing: 41; soundproofing_limits: 41-53 dB; window: no; window_height: 750 mm; window_height_offset: 1180 mm; window_manual_dimensions: no; window_width: 500 mm
Phasing - Phase Created: 2. nieuwbouw
Materials and Finishes - NLRS_C_materiaal: Panel
Construction - height_warning: -; width_warning: -
Dimensions - Area: 3.388 m2; glass_height: 0 mm; glass_width: 0 mm; H: 2800 mm; Height: 2800 mm; NLRS_C_breedte: 1210 mm; NLRS_C_hoogte: 2800 mm; RSen_C_thickness: 105 mm; s: 105 mm; Volume: 0.957872 m3; W: 1210 mm; W_door: 920 mm; W_panel: 145 mm; Width: 1210 mm
Identity Data - Workset: Workset1
Other - door_height_check: 2100 mm; door_inside_left: yes; door_inside_right: no; door_outside_left: no; door_outside_right: no; Family: DO_DT Pass door panel single hinged_Multiwal; Family and Type: DO_DT Pass door panel single hinged_Multiwal: DT - Select 100 K/U; glasspanel: no; Host Id: 1322223; max_door_height: 2300 mm; min_door_height: 2100 mm; panel_top: yes; panel_top_height: 675 mm; Type: DT - Select 100 K/U; Type Id: 1316252; Warning: no; window_H_check: 10 mm; window_height_offset_check: 2900 mm; window_offset_left: 760 mm; window_offset_right: 150 mm; window_W_check: 10 mm

# IfcDoor: NLRS_32_onderdeel_deur_BDG:deur met glasstrook, NLRS_32_onderdeel_deur_BDG:deur met glasstrook:1294757
In: 00 begane grond
Type - OperationType: SINGLE_SWING_RIGHT; ConstructionType: USERDEFINED; ParameterTakesPrecedence: no; Sizeable: no; Material: a_paneel, ISR_Glas
Type - Analytical Properties - Define Thermal Properties by: Schematic Type; Analytic Construction: <None>
Type - Graphics - symbool_plgr: graphic_rond : 90_gr; deur_met_glas: yes; dichte_deur: no
Type - Construction - Function: Interior; Construction Type: deurblad
Type - Dimensions - deur_lijst_borstwering: 300 mm; deur_lijst_breedte: 110 mm; deur_lijst_breedte_scharnier: 670 mm
Type - Identity Data - Workset: Family : Doors : NLRS_32_onderdeel_deur_BDG; Assembly Code: 2E(32.31.21); Datum_Gewijzigd: 14-11-2012; Description: deur met glas; Fire Rating: 60; Model: LOD300; SmartRevit_Versie: 2013.2; Type Comments: deurblad; Type Mark: 826; Type Name: deur met glasstrook
Type - Other - Category: Doors; Family Name: NLRS_32_onderdeel_deur_BDG
Type - NLRS_32_onderdeel_deur_BDG:deur met glasstrook:1294757:1 - PanelOperation: SWINGING
OverallHeight: 2323 mm; OverallWidth: 1046 mm; Classification: 2E(32.31.21) Uniformat (Uniformat)
Visibility - tekst_positie_boven: no
Fire Protection - brandwerendheid_120_min: no; brandwerendheid_60_min: no; brandwerendheid_90_min: no; zelfsluitend: yes; brandwerendheid_30_min: yes; fire_rating: 30
Constraints - Level: 00 begane grond; Moves With Nearby Elements: no; deur_breedte: 1046 mm; Host: Level : 00 begane grond; Offset from Host: 20 mm
Phasing - Phase Created: 2. nieuwbouw
Dimensions - Area: 5.40463 m2; deur_hoogte: 2323 mm; Height: 2323 mm; Thickness: 55 mm; Volume: 0.118376 m3; Width: 1046 mm
Identity Data - Workset: Workset1; Mark: 188
Other - Family: NLRS_32_onderdeel_deur_BDG; tekst_boven: no; Type: deur met glasstrook; tekst_onder: yes; Family and Type: NLRS_32_onderdeel_deur_BDG: deur met glasstrook; Type Id: 1251179

# IfcDoor: NLRS_32_onderdeel_deur_BDG:deur met glasstrook, NLRS_32_onderdeel_deur_BDG:deur met glasstrook:1294628
In: 00 begane grond
Type - OperationType: SINGLE_SWING_RIGHT; ConstructionType: USERDEFINED; ParameterTakesPrecedence: no; Sizeable: no; Material: a_paneel, ISR_Glas
Type - NLRS_32_onderdeel_deur_BDG:deur met glasstrook:1294628:1 - PanelOperation: SWINGING
Type - Analytical Properties - Define Thermal Properties by: Schematic Type; Analytic Construction: <None>
Type - Graphics - symbool_plgr: graphic_rond : 90_gr; deur_met_glas: yes; dichte_deur: no
Type - Construction - Function: Interior; Construction Type: deurblad
Type - Dimensions - deur_lijst_borstwering: 300 mm; deur_lijst_breedte: 110 mm; deur_lijst_breedte_scharnier: 670 mm
Type - Identity Data - Workset: Family : Doors : NLRS_32_onderdeel_deur_BDG; Assembly Code: 2E(32.31.21); Datum_Gewijzigd: 14-11-2012; Description: deur met glas; Fire Rating: 60; Model: LOD300; SmartRevit_Versie: 2013.2; Type Comments: deurblad; Type Mark: 826; Type Name: deur met glasstrook
Type - Other - Category: Doors; Family Name: NLRS_32_onderdeel_deur_BDG
OverallHeight: 2323 mm; OverallWidth: 1046 mm; Classification: 2E(32.31.21) Uniformat (Uniformat)
Visibility - tekst_positie_boven: no
Fire Protection - brandwerendheid_120_min: no; brandwerendheid_60_min: no; brandwerendheid_90_min: no; zelfsluitend: yes; brandwerendheid_30_min: yes; fire_rating: 30
Constraints - Level: 00 begane grond; Moves With Nearby Elements: no; deur_breedte: 1046 mm; Host: Level : 00 begane grond; Offset from Host: 20 mm
Phasing - Phase Created: 2. nieuwbouw
Dimensions - Area: 5.40463 m2; deur_hoogte: 2323 mm; Height: 2323 mm; Thickness: 55 mm; Volume: 0.118376 m3; Width: 1046 mm
Identity Data - Workset: Workset1; Mark: 185
Other - Family: NLRS_32_onderdeel_deur_BDG; tekst_boven: no; Type: deur met glasstrook; tekst_onder: yes; Family and Type: NLRS_32_onderdeel_deur_BDG: deur met glasstrook; Type Id: 1251179

# IfcDoor: NLRS_32_onderdeel_deur_BDG:dichte deur (14)
Type - OperationType: SINGLE_SWING_RIGHT; ConstructionType: USERDEFINED; ParameterTakesPrecedence: no; Sizeable: no; Material: a_paneel
Type - Analytical Properties - Define Thermal Properties by: Schematic Type; Analytic Construction: <None>
Type - Graphics - deur_met_glas: no; dichte_deur: yes; symbool_plgr: graphic_rond : 90_gr
Type - Construction - Function: Interior; Construction Type: deurblad
Type - Dimensions - deur_lijst_borstwering: 300 mm; deur_lijst_breedte: 110 mm; deur_lijst_breedte_scharnier: 110 mm
Type - Identity Data - Assembly Code: 2E(32.31.21); Datum_Gewijzigd: 14-11-2012; Description: deur; Model: LOD300; SmartRevit_Versie: 2013.2; Type Comments: deurblad; Type Mark: 680; Type Name: dichte deur; Workset: Family : Doors : NLRS_32_onderdeel_deur_BDG
Type - Other - Category: Doors; Family Name: NLRS_32_onderdeel_deur_BDG
Type - NLRS_32_onderdeel_deur_BDG:dichte deur:1291646:1 - PanelOperation: SWINGING
OverallHeight: 2315 mm; OverallWidth: 930 mm; Classification: 2E(32.31.21) Uniformat (Uniformat)
Visibility - tekst_positie_boven: no
Fire Protection - zelfsluitend: no; brandwerendheid_120_min: no; brandwerendheid_30_min: no; brandwerendheid_60_min: no; brandwerendheid_90_min: no
Constraints - Moves With Nearby Elements: no; deur_breedte: 930 mm; Offset from Host: 20 mm
Phasing - Phase Created: 2. nieuwbouw
Dimensions - Area: 4.69625 m2; deur_hoogte: 2315 mm; Height: 2315 mm; Thickness: 40 mm; Volume: 0.086118 m3; Width: 930 mm
Identity Data - Workset: Workset1
Other - Family: NLRS_32_onderdeel_deur_BDG; Family and Type: NLRS_32_onderdeel_deur_BDG: dichte deur; tekst_boven: no; tekst_onder: no; Type: dichte deur; Type Id: 1251178
Name (NLRS_32_onderdeel_deur_BDG:dichte deur:...) | In | Level | Host | Mark
1291646 | 02 tweede verdieping | 02 tweede verdieping | Level : 02 tweede verdieping | 41
1291652 | 02 tweede verdieping | 02 tweede verdieping | Level : 02 tweede verdieping | 44
1291658 | 02 tweede verdieping | 02 tweede verdieping | Level : 02 tweede verdieping | 50
1291678 | 02 tweede verdieping | 02 tweede verdieping | Level : 02 tweede verdieping | 65
1292212 | 01 eerste verdieping | 01 eerste verdieping | Level : 01 eerste verdieping | 110
1292918 | 01 eerste verdieping | 01 eerste verdieping | Level : 01 eerste verdieping | 140
1293823 | 00 begane grond | 00 begane grond | Level : 00 begane grond | 152
1293858 | 00 begane grond | 00 begane grond | Level : 00 begane grond | 155
1293908 | 00 begane grond | 00 begane grond | Level : 00 begane grond | 158
1294015 | 00 begane grond | 00 begane grond | Level : 00 begane grond | 161
1294117 | 00 begane grond | 00 begane grond | Level : 00 begane grond | 167
1371700 | 00 begane grond | 00 begane grond | Level : 00 begane grond | 257
1814316 | 00 begane grond | 00 begane grond | Level : 00 begane grond | 394
1878845 | 00 begane grond | 00 begane grond | Level : 00 begane grond | 407

# IfcDoor: NLRS_32_onderdeel_deur_BDG:dichte deur (9)
Type - OperationType: SINGLE_SWING_RIGHT; ConstructionType: USERDEFINED; ParameterTakesPrecedence: no; Sizeable: no; Material: a_paneel
Type - Analytical Properties - Define Thermal Properties by: Schematic Type; Analytic Construction: <None>
Type - Graphics - deur_met_glas: no; dichte_deur: yes; symbool_plgr: graphic_rond : 90_gr
Type - Construction - Function: Interior; Construction Type: deurblad
Type - Dimensions - deur_lijst_borstwering: 300 mm; deur_lijst_breedte: 110 mm; deur_lijst_breedte_scharnier: 110 mm
Type - Identity Data - Assembly Code: 2E(32.31.21); Datum_Gewijzigd: 14-11-2012; Description: deur; Model: LOD300; SmartRevit_Versie: 2013.2; Type Comments: deurblad; Type Mark: 680; Type Name: dichte deur; Workset: Family : Doors : NLRS_32_onderdeel_deur_BDG
Type - Other - Category: Doors; Family Name: NLRS_32_onderdeel_deur_BDG
Type - NLRS_32_onderdeel_deur_BDG:dichte deur:1291661:1 - PanelOperation: SWINGING
OverallHeight: 2315 mm; OverallWidth: 1030 mm; Classification: 2E(32.31.21) Uniformat (Uniformat)
Visibility - tekst_positie_boven: no
Fire Protection - zelfsluitend: no; brandwerendheid_120_min: no; brandwerendheid_30_min: no; brandwerendheid_60_min: no; brandwerendheid_90_min: no
Constraints - Moves With Nearby Elements: no; deur_breedte: 1030 mm; Offset from Host: 20 mm
Phasing - Phase Created: 2. nieuwbouw
Dimensions - Area: 5.17225 m2; deur_hoogte: 2315 mm; Height: 2315 mm; Thickness: 40 mm; Volume: 0.095378 m3; Width: 1030 mm
Identity Data - Workset: Workset1
Other - Family: NLRS_32_onderdeel_deur_BDG; Family and Type: NLRS_32_onderdeel_deur_BDG: dichte deur; tekst_boven: no; tekst_onder: no; Type: dichte deur; Type Id: 1251178
Name (NLRS_32_onderdeel_deur_BDG:dichte deur:...) | In | Level | Host | Mark
1291661 | 02 tweede verdieping | 02 tweede verdieping | Level : 02 tweede verdieping | 53
1291690 | 02 tweede verdieping | 02 tweede verdieping | Level : 02 tweede verdieping | 77
1292148 | 01 eerste verdieping | 01 eerste verdieping | Floor : NLRS_43_FL_cementdekvloer 50_gen_ISR | 93
1292157 | 01 eerste verdieping | 01 eerste verdieping | Floor : NLRS_43_FL_cementdekvloer 50_gen_ISR | 102
1294447 | 00 begane grond | 00 begane grond | Level : 00 begane grond | 179
1294946 | 00 begane grond | 00 begane grond | Level : 00 begane grond | 197
1328649 | 02 tweede verdieping | 02 tweede verdieping | Floor : NLRS_43_FL_cementdekvloer 50_gen_ISR | 142
1367302 | 00 begane grond | 00 begane grond | Level : 00 begane grond | 236
1371780 | 00 begane grond | 00 begane grond | Level : 00 begane grond | 263

# IfcDoor: NLRS_32_onderdeel_deur_BDG:dichte deur (12)
Type - OperationType: SINGLE_SWING_RIGHT; ConstructionType: USERDEFINED; ParameterTakesPrecedence: no; Sizeable: no; Material: a_paneel
Type - Analytical Properties - Define Thermal Properties by: Schematic Type; Analytic Construction: <None>
Type - Graphics - deur_met_glas: no; dichte_deur: yes; symbool_plgr: graphic_rond : 90_gr
Type - Construction - Function: Interior; Construction Type: deurblad
Type - Dimensions - deur_lijst_borstwering: 300 mm; deur_lijst_breedte: 110 mm; deur_lijst_breedte_scharnier: 110 mm
Type - Identity Data - Assembly Code: 2E(32.31.21); Datum_Gewijzigd: 14-11-2012; Description: deur; Model: LOD300; SmartRevit_Versie: 2013.2; Type Comments: deurblad; Type Mark: 680; Type Name: dichte deur; Workset: Family : Doors : NLRS_32_onderdeel_deur_BDG
Type - Other - Category: Doors; Family Name: NLRS_32_onderdeel_deur_BDG
Type - NLRS_32_onderdeel_deur_BDG:dichte deur:1291669:1 - PanelOperation: SWINGING
OverallHeight: 2315 mm; OverallWidth: 1030 mm; Classification: 2E(32.31.21) Uniformat (Uniformat)
Visibility - tekst_positie_boven: no
Fire Protection - zelfsluitend: no; brandwerendheid_120_min: no; brandwerendheid_30_min: no; brandwerendheid_60_min: no; brandwerendheid_90_min: no
Constraints - Moves With Nearby Elements: no; deur_breedte: 1030 mm; Offset from Host: 20 mm
Phasing - Phase Created: 2. nieuwbouw
Dimensions - Area: 5.17225 m2; deur_hoogte: 2315 mm; Height: 2315 mm; Thickness: 40 mm; Volume: 0.095378 m3; Width: 1030 mm
Identity Data - Workset: Workset1
Other - Family: NLRS_32_onderdeel_deur_BDG; Family and Type: NLRS_32_onderdeel_deur_BDG: dichte deur; tekst_boven: no; tekst_onder: no; Type: dichte deur; Type Id: 1251178
Name (NLRS_32_onderdeel_deur_BDG:dichte deur:...) | In | Level | Host | Mark
1291669 | 02 tweede verdieping | 02 tweede verdieping | Level : 02 tweede verdieping | 59
1291687 | 02 tweede verdieping | 02 tweede verdieping | Level : 02 tweede verdieping | 74
1291693 | 02 tweede verdieping | 02 tweede verdieping | Level : 02 tweede verdieping | 80
1292151 | 01 eerste verdieping | 01 eerste verdieping | Floor : NLRS_43_FL_cementdekvloer 50_gen_ISR | 96
1292154 | 01 eerste verdieping | 01 eerste verdieping | Floor : NLRS_43_FL_cementdekvloer 50_gen_ISR | 99
1292160 | 01 eerste verdieping | 01 eerste verdieping | Floor : NLRS_43_FL_cementdekvloer 50_gen_ISR | 105
1294411 | 00 begane grond | 00 begane grond | Level : 00 begane grond | 176
1294993 | 00 begane grond | 00 begane grond | Level : 00 begane grond | 200
1371810 | 00 begane grond | 00 begane grond | Level : 00 begane grond | 266
1878837 | 00 begane grond | 00 begane grond | Level : 00 begane grond | 397
2439710 | 00 begane grond | 00 begane grond | Level : 00 begane grond | 455
2444397 | 01 eerste verdieping | 01 eerste verdieping | Level : 01 eerste verdieping | 455

# IfcDoor: NLRS_32_onderdeel_deur_BDG:dichte deur (3)
Type - OperationType: SINGLE_SWING_RIGHT; ConstructionType: USERDEFINED; ParameterTakesPrecedence: no; Sizeable: no; Material: a_paneel
Type - Analytical Properties - Define Thermal Properties by: Schematic Type; Analytic Construction: <None>
Type - Graphics - deur_met_glas: no; dichte_deur: yes; symbool_plgr: graphic_rond : 90_gr
Type - Construction - Function: Interior; Construction Type: deurblad
Type - Dimensions - deur_lijst_borstwering: 300 mm; deur_lijst_breedte: 110 mm; deur_lijst_breedte_scharnier: 110 mm
Type - Identity Data - Assembly Code: 2E(32.31.21); Datum_Gewijzigd: 14-11-2012; Description: deur; Model: LOD300; SmartRevit_Versie: 2013.2; Type Comments: deurblad; Type Mark: 680; Type Name: dichte deur; Workset: Family : Doors : NLRS_32_onderdeel_deur_BDG
Type - Other - Category: Doors; Family Name: NLRS_32_onderdeel_deur_BDG
Type - NLRS_32_onderdeel_deur_BDG:dichte deur:1292163:1 - PanelOperation: SWINGING
OverallHeight: 2323 mm; OverallWidth: 1046 mm; Classification: 2E(32.31.21) Uniformat (Uniformat)
Visibility - tekst_positie_boven: no
Fire Protection - brandwerendheid_120_min: no; brandwerendheid_30_min: no; brandwerendheid_90_min: no; zelfsluitend: yes; brandwerendheid_60_min: yes; fire_rating: 60
Constraints - Moves With Nearby Elements: no; deur_breedte: 1046 mm; Offset from Host: 20 mm
Phasing - Phase Created: 2. nieuwbouw
Dimensions - Area: 5.44943 m2; deur_hoogte: 2323 mm; Height: 2323 mm; Thickness: 55 mm; Volume: 0.133642 m3; Width: 1046 mm
Identity Data - Workset: Workset1
Other - Family: NLRS_32_onderdeel_deur_BDG; Family and Type: NLRS_32_onderdeel_deur_BDG: dichte deur; tekst_boven: no; Type: dichte deur; Type Id: 1251178; tekst_onder: yes
Name (NLRS_32_onderdeel_deur_BDG:dichte deur:...) | In | Level | Host | Mark
1292163 | 01 eerste verdieping | 01 eerste verdieping | Floor : NLRS_43_FL_cementdekvloer 50_gen_ISR | 108
1367549 | 00 begane grond | 00 begane grond | Level : 00 begane grond | 251
2089157 | 02 tweede verdieping | 02 tweede verdieping | Floor : NLRS_43_FL_cementdekvloer 50_gen_ISR | 430

# IfcDoor: NLRS_32_onderdeel_deur_BDG:dichte deur, NLRS_32_onderdeel_deur_BDG:dichte deur:1367487
In: 00 begane grond
Type - OperationType: SINGLE_SWING_RIGHT; ConstructionType: USERDEFINED; ParameterTakesPrecedence: no; Sizeable: no; Material: a_paneel
Type - Analytical Properties - Define Thermal Properties by: Schematic Type; Analytic Construction: <None>
Type - Graphics - deur_met_glas: no; dichte_deur: yes; symbool_plgr: graphic_rond : 90_gr
Type - Construction - Function: Interior; Construction Type: deurblad
Type - Dimensions - deur_lijst_borstwering: 300 mm; deur_lijst_breedte: 110 mm; deur_lijst_breedte_scharnier: 110 mm
Type - Identity Data - Assembly Code: 2E(32.31.21); Datum_Gewijzigd: 14-11-2012; Description: deur; Model: LOD300; SmartRevit_Versie: 2013.2; Type Comments: deurblad; Type Mark: 680; Type Name: dichte deur; Workset: Family : Doors : NLRS_32_onderdeel_deur_BDG
Type - Other - Category: Doors; Family Name: NLRS_32_onderdeel_deur_BDG
Type - NLRS_32_onderdeel_deur_BDG:dichte deur:1367487:1 - PanelOperation: SWINGING
OverallHeight: 2323 mm; OverallWidth: 1046 mm; Classification: 2E(32.31.21) Uniformat (Uniformat)
Visibility - tekst_positie_boven: no
Fire Protection - brandwerendheid_120_min: no; brandwerendheid_30_min: no; brandwerendheid_90_min: no; zelfsluitend: yes; brandwerendheid_60_min: yes; fire_rating: 60
Constraints - Level: 00 begane grond; Moves With Nearby Elements: no; deur_breedte: 1046 mm; Host: Level : 00 begane grond; Offset from Host: 20 mm
Phasing - Phase Created: 2. nieuwbouw
Dimensions - Area: 5.44943 m2; deur_hoogte: 2323 mm; Height: 2323 mm; Thickness: 55 mm; Volume: 0.133642 m3; Width: 1046 mm
Identity Data - Workset: Workset1; Mark: 245
Other - Family: NLRS_32_onderdeel_deur_BDG; Family and Type: NLRS_32_onderdeel_deur_BDG: dichte deur; tekst_boven: no; Type: dichte deur; Type Id: 1251178; tekst_onder: yes

# IfcDoor: NLRS_32_onderdeel_deur_BDG:dichte deur (2)
In: 00 begane grond
Type - OperationType: SINGLE_SWING_RIGHT; ConstructionType: USERDEFINED; ParameterTakesPrecedence: no; Sizeable: no; Material: a_paneel
Type - Analytical Properties - Define Thermal Properties by: Schematic Type; Analytic Construction: <None>
Type - Graphics - deur_met_glas: no; dichte_deur: yes; symbool_plgr: graphic_rond : 90_gr
Type - Construction - Function: Interior; Construction Type: deurblad
Type - Dimensions - deur_lijst_borstwering: 300 mm; deur_lijst_breedte: 110 mm; deur_lijst_breedte_scharnier: 110 mm
Type - Identity Data - Assembly Code: 2E(32.31.21); Datum_Gewijzigd: 14-11-2012; Description: deur; Model: LOD300; SmartRevit_Versie: 2013.2; Type Comments: deurblad; Type Mark: 680; Type Name: dichte deur; Workset: Family : Doors : NLRS_32_onderdeel_deur_BDG
Type - Other - Category: Doors; Family Name: NLRS_32_onderdeel_deur_BDG
Type - NLRS_32_onderdeel_deur_BDG:dichte deur:2326505:1 - PanelOperation: SWINGING
OverallHeight: 2323 mm; OverallWidth: 946 mm; Classification: 2E(32.31.21) Uniformat (Uniformat)
Visibility - tekst_positie_boven: no
Fire Protection - brandwerendheid_120_min: no; brandwerendheid_30_min: no; brandwerendheid_90_min: no; zelfsluitend: yes; brandwerendheid_60_min: yes; fire_rating: 60
Constraints - Level: 00 begane grond; Moves With Nearby Elements: no; deur_breedte: 946 mm; Host: Level : 00 begane grond; Offset from Host: 20 mm
Phasing - Phase Created: 2. nieuwbouw
Dimensions - Area: 4.96583 m2; deur_hoogte: 2323 mm; Height: 2323 mm; Thickness: 55 mm; Volume: 0.120866 m3; Width: 946 mm
Identity Data - Workset: Workset1
Other - Family: NLRS_32_onderdeel_deur_BDG; Family and Type: NLRS_32_onderdeel_deur_BDG: dichte deur; tekst_boven: no; Type: dichte deur; Type Id: 1251178; tekst_onder: yes
Name (NLRS_32_onderdeel_deur_BDG:dichte deur:...) | Mark
2326505 | 423
5033766 | 457

# IfcDoor: NLRS_32_onderdeel_deur_BDG:dichte deur (14)
Type - OperationType: SINGLE_SWING_RIGHT; ConstructionType: USERDEFINED; ParameterTakesPrecedence: no; Sizeable: no; Material: a_paneel
Type - NLRS_32_onderdeel_deur_BDG:dichte deur:1281943:1 - PanelOperation: SWINGING
Type - Analytical Properties - Define Thermal Properties by: Schematic Type; Analytic Construction: <None>
Type - Graphics - deur_met_glas: no; dichte_deur: yes; symbool_plgr: graphic_rond : 90_gr
Type - Construction - Function: Interior; Construction Type: deurblad
Type - Dimensions - deur_lijst_borstwering: 300 mm; deur_lijst_breedte: 110 mm; deur_lijst_breedte_scharnier: 110 mm
Type - Identity Data - Assembly Code: 2E(32.31.21); Datum_Gewijzigd: 14-11-2012; Description: deur; Model: LOD300; SmartRevit_Versie: 2013.2; Type Comments: deurblad; Type Mark: 680; Type Name: dichte deur; Workset: Family : Doors : NLRS_32_onderdeel_deur_BDG
Type - Other - Category: Doors; Family Name: NLRS_32_onderdeel_deur_BDG
OverallHeight: 2315 mm; OverallWidth: 930 mm; Classification: 2E(32.31.21) Uniformat (Uniformat)
Visibility - tekst_positie_boven: no
Fire Protection - zelfsluitend: no; brandwerendheid_120_min: no; brandwerendheid_30_min: no; brandwerendheid_60_min: no; brandwerendheid_90_min: no
Constraints - Moves With Nearby Elements: no; deur_breedte: 930 mm
Phasing - Phase Created: 2. nieuwbouw
Dimensions - Area: 4.69625 m2; deur_hoogte: 2315 mm; Height: 2315 mm; Thickness: 40 mm; Volume: 0.086118 m3; Width: 930 mm
Identity Data - Workset: Workset1
Other - Family: NLRS_32_onderdeel_deur_BDG; Family and Type: NLRS_32_onderdeel_deur_BDG: dichte deur; tekst_boven: no; tekst_onder: no; Type: dichte deur; Type Id: 1251178
Name (NLRS_32_onderdeel_deur_BDG:dichte deur:...) | In | Level | Host | Offset from Host (mm) | Mark
1281943 | 02 tweede verdieping | 02 tweede verdieping | Level : 02 tweede verdieping | 10 | 36
1291675 | 02 tweede verdieping | 02 tweede verdieping | Level : 02 tweede verdieping | 20 | 62
1291681 | 02 tweede verdieping | 02 tweede verdieping | Level : 02 tweede verdieping | 20 | 68
1292273 | 01 eerste verdieping | 01 eerste verdieping | Level : 01 eerste verdieping | 20 | 113
1292328 | 01 eerste verdieping | 01 eerste verdieping | Level : 01 eerste verdieping | 20 | 116
1292392 | 01 eerste verdieping | 01 eerste verdieping | Level : 01 eerste verdieping | 20 | 119
1292839 | 01 eerste verdieping | 01 eerste verdieping | Level : 01 eerste verdieping | 20 | 137
1330448 | 01 eerste verdieping | 01 eerste verdieping | Level : 01 eerste verdieping | 20 | 147
1371640 | 00 begane grond | 00 begane grond | Level : 00 begane grond | 20 | 254
1371730 | 00 begane grond | 00 begane grond | Level : 00 begane grond | 20 | 260
1657870 | 00 begane grond | 00 begane grond | Level : 00 begane grond | 20 | 358
1878849 | 00 begane grond | 00 begane grond | Level : 00 begane grond | 20 | 410
2437633 | 00 begane grond | 00 begane grond | Level : 00 begane grond | 20 | 443
2544765 | 00 begane grond | 00 begane grond | Floor : NLRS_43_FL_cementdekvloer 60_gen_ISR | 20 | 467

# IfcDoor: NLRS_32_samenstelling_binnenkozijn_hout_BDG:enkele deur (55)
Type - ConstructionType: USERDEFINED; ParameterTakesPrecedence: no; Sizeable: no; Material: n6_binnenkozijn
Type - Analytical Properties - Define Thermal Properties by: Schematic Type; Analytic Construction: <None>
Type - Constraints - Default Elevation: 0 mm
Type - Graphics - dubbele_deur: no; deur_type: NLRS_32_onderdeel_deur_BDG : dichte deur; Vlak B1: Panel : dubbel glas
Type - Construction - Function: Interior; Construction Type: binnenkozijn hout
Type - Dimensions - tong_naald: 2 mm
Type - Identity Data - Assembly Code: 2E(32.31.21); Datum_Gewijzigd: 14-11-2012; Description: binnendeur enkel; Model: LOD300; SmartRevit_Versie: 2013.2; Type Comments: samenstelling; Type Mark: 678; Type Name: enkele deur; Workset: Family : Doors : NLRS_32_samenstelling_binnenkozijn_hout_BDG
Type - Other - Category: Doors; Family Name: NLRS_32_samenstelling_binnenkozijn_hout_BDG
OverallHeight: 2387 mm; Classification: 2E(32.31.21) Uniformat (Uniformat)
Fire Protection - brandwerendheid_120min: no; brandwerendheid_30min: no; brandwerendheid_90min: no
Constraints - Moves With Nearby Elements: no; Offset from Host: 0 mm
Phasing - Phase Created: 2. nieuwbouw
Graphics - WBDBO_tekst_andere_zijde: no; dorpel: no
Construction - kozijn_hoogte: 2387 mm; stijl_breedte: 67 mm; stijl_diepte: 125 mm
Dimensions - dikte_onderdorpel: 5 mm; Height: 2387 mm; ruimte_onder_deur: 20 mm
Identity Data - Workset: Workset1
Other - berekende_ruimte_onder_deur: 20 mm; deur_offset: 0 mm; Family: NLRS_32_samenstelling_binnenkozijn_hout_BDG; Family and Type: NLRS_32_samenstelling_binnenkozijn_hout_BDG: enkele deur; Type: enkele deur; Type Id: 1274095
Name (NLRS_32_samenstelling_binnenkozijn_hout_BDG:enkele deur:...) | In | OverallWidth (mm) = kozijn_breedte (mm) = Width (mm) | zelfsluitend = brandwerendheid_60min | Level | deur_breedte (mm) = berekende_deur_breedte (mm) | Host | Area (m2) | deur_hoogte (mm) | sponning_breedte (mm) | sponning_diepte (mm) | Thickness (mm) | Volume (m3) | Mark | positie_deur (mm) | stijl_lengte (mm)
1281942 | 02 tweede verdieping | 1034 | no | 02 tweede verdieping | 930 | Basic Wall : 22_WA_binnenwand_ms125 25-75-25 _gen_bdg | 1.23488 | 2315 | 17 | 50 | 40 | 0.0427819 | 37 | 52 | 2337
1291645 | 02 tweede verdieping | 1034 | no | 02 tweede verdieping | 930 | Basic Wall : 22_WA_binnenwand_ms125 25-75-25 _gen_bdg | 1.23488 | 2315 | 17 | 50 | 40 | 0.0427819 | 42 | 52 | 2337
1291651 | 02 tweede verdieping | 1034 | no | 02 tweede verdieping | 930 | Basic Wall : 22_WA_voorzetwand_ms100 25-75 _gen_bdg | 1.23488 | 2315 | 17 | 50 | 40 | 0.0427819 | 45 | 52 | 2337
1291657 | 02 tweede verdieping | 1034 | no | 02 tweede verdieping | 930 | Level : 02 tweede verdieping | 1.23488 | 2315 | 17 | 50 | 40 | 0.0427819 | 51 | 52 | 2337
1291660 | 02 tweede verdieping | 1134 | no | 02 tweede verdieping | 1030 | Level : 02 tweede verdieping | 1.26708 | 2315 | 17 | 50 | 40 | 0.0435344 | 54 | 52 | 2337
1291668 | 02 tweede verdieping | 1134 | no | 02 tweede verdieping | 1030 | Basic Wall : 22_WA_binnenwand_ms125 25-75-25 _gen_bdg | 1.26708 | 2315 | 17 | 50 | 40 | 0.0435344 | 60 | 52 | 2337
1291674 | 02 tweede verdieping | 1034 | no | 02 tweede verdieping | 930 | Basic Wall : 22_WA_binnenwand_ms125 25-75-25 _gen_bdg | 1.23488 | 2315 | 17 | 50 | 40 | 0.0427819 | 63 | 52 | 2337
1291677 | 02 tweede verdieping | 1034 | no | 02 tweede verdieping | 930 | Basic Wall : 22_WA_binnenwand_ms125 25-75-25 _gen_bdg | 1.23488 | 2315 | 17 | 50 | 40 | 0.0427819 | 66 | 52 | 2337
1291680 | 02 tweede verdieping | 1034 | no | 02 tweede verdieping | 930 | Level : 02 tweede verdieping | 1.23488 | 2315 | 17 | 50 | 40 | 0.0427819 | 69 | 52 | 2337
1291686 | 02 tweede verdieping | 1134 | no | 02 tweede verdieping | 1030 | Basic Wall : 22_WA_binnenwand_ms125 25-75-25 _gen_bdg | 1.26708 | 2315 | 17 | 50 | 40 | 0.0435344 | 75 | 52 | 2337
1291689 | 02 tweede verdieping | 1134 | no | 02 tweede verdieping | 1030 | Basic Wall : 22_WA_binnenwand_ms125 25-75-25 _gen_bdg | 1.26708 | 2315 | 17 | 50 | 40 | 0.0435344 | 78 | 52 | 2337
1291692 | 02 tweede verdieping | 1134 | no | 02 tweede verdieping | 1030 | Basic Wall : 22_WA_binnenwand_ms125 25-75-25 _gen_bdg | 1.26708 | 2315 | 17 | 50 | 40 | 0.0435344 | 81 | 52 | 2337
1292147 | 01 eerste verdieping | 1134 | no | 01 eerste verdieping | 1030 | Floor : NLRS_43_FL_cementdekvloer 50_gen_ISR | 1.26708 | 2315 | 17 | 50 | 40 | 0.0435344 | 92 | 52 | 2337
1292150 | 01 eerste verdieping | 1134 | no | 01 eerste verdieping | 1030 | Floor : NLRS_43_FL_cementdekvloer 50_gen_ISR | 1.26708 | 2315 | 17 | 50 | 40 | 0.0435344 | 95 | 52 | 2337
1292153 | 01 eerste verdieping | 1134 | no | 01 eerste verdieping | 1030 | Floor : NLRS_43_FL_cementdekvloer 50_gen_ISR | 1.26708 | 2315 | 17 | 50 | 40 | 0.0435344 | 98 | 52 | 2337
1292156 | 01 eerste verdieping | 1134 | no | 01 eerste verdieping | 1030 | Floor : NLRS_43_FL_cementdekvloer 50_gen_ISR | 1.26708 | 2315 | 17 | 50 | 40 | 0.0435344 | 101 | 52 | 2337
1292159 | 01 eerste verdieping | 1134 | no | 01 eerste verdieping | 1030 | Floor : NLRS_43_FL_cementdekvloer 50_gen_ISR | 1.26708 | 2315 | 17 | 50 | 40 | 0.0435344 | 104 | 52 | 2337
1292162 | 01 eerste verdieping | 1134 | yes | 01 eerste verdieping | 1046 | Floor : NLRS_43_FL_cementdekvloer 50_gen_ISR | 1.26833 | 2323 | 25 | 65 | 55 | 0.039111 | 107 | 44 | 2345
1292211 | 01 eerste verdieping | 1034 | no | 01 eerste verdieping | 930 | Basic Wall : NLRS_41_WA_sanitairwand 13_gen_ISR | 1.23488 | 2315 | 17 | 50 | 40 | 0.0427819 | 111 | 52 | 2337
1292272 | 01 eerste verdieping | 1034 | no | 01 eerste verdieping | 930 | Level : 01 eerste verdieping | 1.23488 | 2315 | 17 | 50 | 40 | 0.0427819 | 114 | 52 | 2337
1292327 | 01 eerste verdieping | 1034 | no | 01 eerste verdieping | 930 | Basic Wall : 22_WA_binnenwand_ms125 25-75-25 _gen_bdg | 1.23488 | 2315 | 17 | 50 | 40 | 0.0427819 | 117 | 52 | 2337
1292391 | 01 eerste verdieping | 1034 | no | 01 eerste verdieping | 930 | Level : 01 eerste verdieping | 1.23488 | 2315 | 17 | 50 | 40 | 0.0427819 | 120 | 52 | 2337
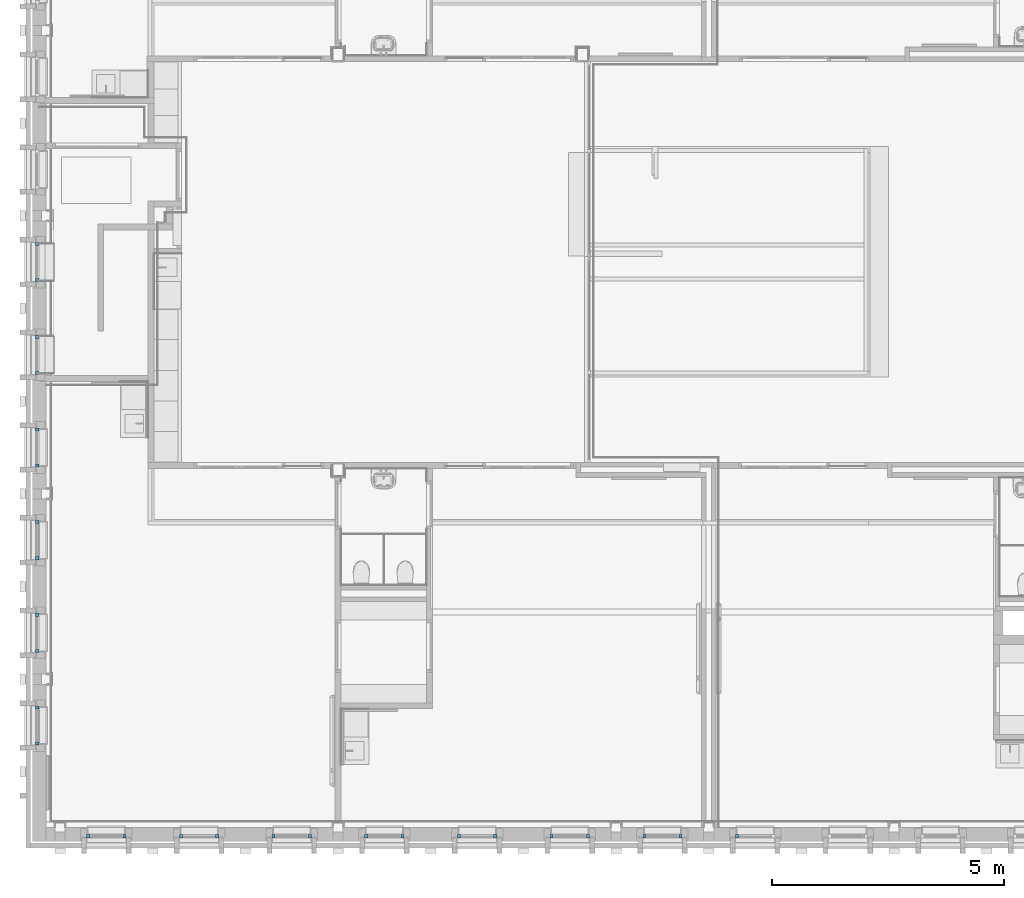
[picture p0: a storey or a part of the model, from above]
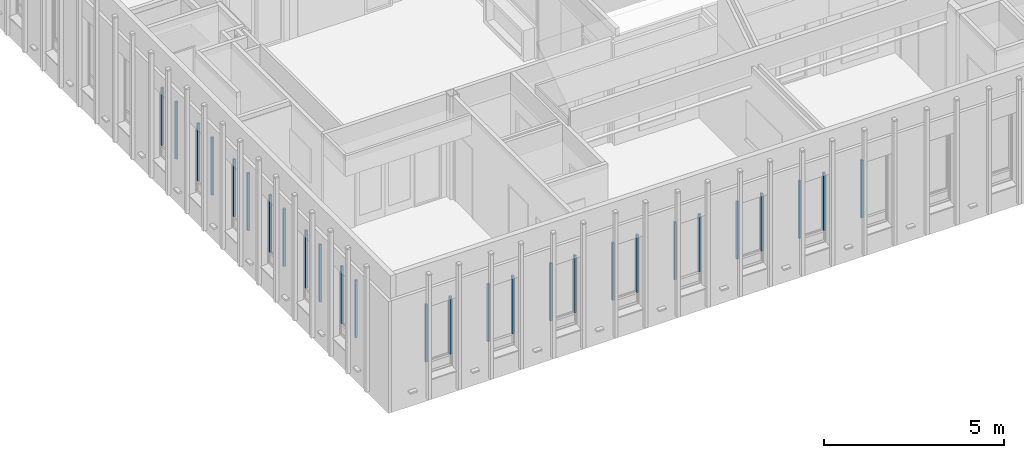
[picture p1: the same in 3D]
Properties of the parts of a building model (IFC2X3), part 10 of 94

# IfcDoor: NLRS_32_samenstelling_binnenkozijn_hout_BDG:enkele deur (55)
Name (NLRS_32_samenstelling_binnenkozijn_hout_BDG:enkele deur:...) | In | OverallWidth (mm) = kozijn_breedte (mm) = Width (mm) | zelfsluitend = brandwerendheid_60min | Level | deur_breedte (mm) = berekende_deur_breedte (mm) | Host | Area (m2) | deur_hoogte (mm) | sponning_breedte (mm) | sponning_diepte (mm) | Thickness (mm) | Volume (m3) | Mark | positie_deur (mm) | stijl_lengte (mm)
1292838 | 01 eerste verdieping | 1034 | no | 01 eerste verdieping | 930 | Basic Wall : 22_WA_binnenwand_ms125 25-75-25 _gen_bdg | 1.23488 | 2315 | 17 | 50 | 40 | 0.0427819 | 138 | 52 | 2337
1292917 | 01 eerste verdieping | 1034 | no | 01 eerste verdieping | 930 | Level : 01 eerste verdieping | 1.23488 | 2315 | 17 | 50 | 40 | 0.0427819 | 141 | 52 | 2337
1293822 | 00 begane grond | 1034 | no | 00 begane grond | 930 | Level : 00 begane grond | 1.23488 | 2315 | 17 | 50 | 40 | 0.0427819 | 153 | 52 | 2337
1293857 | 00 begane grond | 1034 | no | 00 begane grond | 930 | Level : 00 begane grond | 1.23488 | 2315 | 17 | 50 | 40 | 0.0427819 | 156 | 52 | 2337
1293907 | 00 begane grond | 1034 | no | 00 begane grond | 930 | Basic Wall : 22_WA_binnenwand_ms125 25-75-25 _gen_bdg | 1.23488 | 2315 | 17 | 50 | 40 | 0.0427819 | 159 | 52 | 2337
1294014 | 00 begane grond | 1034 | no | 00 begane grond | 930 | Basic Wall : 22_WA_binnenwand_ms125 25-75-25 _gen_bdg | 1.23488 | 2315 | 17 | 50 | 40 | 0.0427819 | 162 | 52 | 2337
1294116 | 00 begane grond | 1034 | no | 00 begane grond | 930 | Level : 00 begane grond | 1.23488 | 2315 | 17 | 50 | 40 | 0.0427819 | 168 | 52 | 2337
1294410 | 00 begane grond | 1134 | no | 00 begane grond | 1030 | Basic Wall : 22_WA_binnenwand_ms125 25-75-25 _gen_bdg | 1.26708 | 2315 | 17 | 50 | 40 | 0.0435344 | 177 | 52 | 2337
1294446 | 00 begane grond | 1134 | no | 00 begane grond | 1030 | Basic Wall : 22_WA_binnenwand_ms125 25-75-25 _gen_bdg | 1.26708 | 2315 | 17 | 50 | 40 | 0.0435344 | 180 | 52 | 2337
1294945 | 00 begane grond | 1134 | no | 00 begane grond | 1030 | Basic Wall : 22_WA_binnenwand_ms125 25-75-25 _gen_bdg | 1.26708 | 2315 | 17 | 50 | 40 | 0.0435344 | 198 | 52 | 2337
1294992 | 00 begane grond | 1134 | no | 00 begane grond | 1030 | Basic Wall : 22_WA_binnenwand_ms125 25-75-25 _gen_bdg | 1.26708 | 2315 | 17 | 50 | 40 | 0.0435344 | 201 | 52 | 2337
1328648 | 02 tweede verdieping | 1134 | no | 02 tweede verdieping | 1030 | Floor : NLRS_43_FL_cementdekvloer 50_gen_ISR | 1.26708 | 2315 | 17 | 50 | 40 | 0.0435344 | 90 | 52 | 2337
1330447 | 01 eerste verdieping | 1034 | no | 01 eerste verdieping | 930 | Basic Wall : 22_WA_binnenwand_ms125 25-75-25 _gen_bdg | 1.23488 | 2315 | 17 | 50 | 40 | 0.0427819 | 181 | 52 | 2337
1367301 | 00 begane grond | 1134 | no | 00 begane grond | 1030 | Basic Wall : 22_WA_binnenwand_ms125 25-75-25 _gen_bdg | 1.26708 | 2315 | 17 | 50 | 40 | 0.0435344 | 237 | 52 | 2337
1367486 | 00 begane grond | 1134 | yes | 00 begane grond | 1046 | Basic Wall : 22_WA_binnenwand_ms125 25-75-25 _gen_bdg | 1.26833 | 2323 | 25 | 65 | 55 | 0.039111 | 246 | 44 | 2345
1367548 | 00 begane grond | 1134 | yes | 00 begane grond | 1046 | Basic Wall : 22_WA_binnenwand_ms125 25-75-25 _gen_bdg | 1.26833 | 2323 | 25 | 65 | 55 | 0.039111 | 252 | 44 | 2345
1371639 | 00 begane grond | 1034 | no | 00 begane grond | 930 | Basic Wall : 22_WA_binnenwand_ms125 25-75-25 _gen_bdg | 1.23488 | 2315 | 17 | 50 | 40 | 0.0427819 | 255 | 52 | 2337
1371699 | 00 begane grond | 1034 | no | 00 begane grond | 930 | Basic Wall : 22_WA_kalkzandsteen_120mm | 1.23488 | 2315 | 17 | 50 | 40 | 0.0427819 | 258 | 52 | 2337
1371729 | 00 begane grond | 1034 | no | 00 begane grond | 930 | Basic Wall : 22_WA_kalkzandsteen_120mm | 1.23488 | 2315 | 17 | 50 | 40 | 0.0427819 | 261 | 52 | 2337
1371779 | 00 begane grond | 1134 | no | 00 begane grond | 1030 | Basic Wall : 22_WA_kalkzandsteen_120mm | 1.26708 | 2315 | 17 | 50 | 40 | 0.0435344 | 264 | 52 | 2337
1371809 | 00 begane grond | 1134 | no | 00 begane grond | 1030 | Basic Wall : 22_WA_kalkzandsteen_120mm | 1.26708 | 2315 | 17 | 50 | 40 | 0.0435344 | 267 | 52 | 2337
1657869 | 00 begane grond | 1034 | no | 00 begane grond | 930 | Basic Wall : 22_WA_binnenwand_ms125 25-75-25 _gen_bdg | 1.23488 | 2315 | 17 | 50 | 40 | 0.0427819 | 359 | 52 | 2337
1814315 | 00 begane grond | 1034 | no | 00 begane grond | 930 | Basic Wall : 22_WA_binnenwand_ms125 25-75-25 _gen_bdg | 1.23488 | 2315 | 17 | 50 | 40 | 0.0427819 | 395 | 52 | 2337
1878836 | 00 begane grond | 1134 | no | 00 begane grond | 1030 | Basic Wall : NLRS_22_WA_akoestische voorzetwand hout gym 96_gen_bdg | 1.26708 | 2315 | 17 | 50 | 40 | 0.0435344 | 399 | 52 | 2337
1878844 | 00 begane grond | 1034 | no | 00 begane grond | 930 | Level : 00 begane grond | 1.23488 | 2315 | 17 | 50 | 40 | 0.0427819 | 408 | 52 | 2337
1878848 | 00 begane grond | 1034 | no | 00 begane grond | 930 | Level : 00 begane grond | 1.23488 | 2315 | 17 | 50 | 40 | 0.0427819 | 411 | 52 | 2337
2089156 | 02 tweede verdieping | 1134 | yes | 02 tweede verdieping | 1046 | Floor : NLRS_43_FL_cementdekvloer 50_gen_ISR | 1.26833 | 2323 | 25 | 65 | 55 | 0.039111 | 429 | 44 | 2345
2326504 | 00 begane grond | 1034 | yes | 00 begane grond | 946 | Basic Wall : 22_WA_binnenwand_ms125 25-75-25 _gen_bdg | 1.23613 | 2323 | 25 | 65 | 55 | 0.038436 | 424 | 44 | 2345
2437632 | 00 begane grond | 1034 | no | 00 begane grond | 930 | Basic Wall : 22_WA_binnenwand_ms125 25-75-25 _gen_bdg | 1.23488 | 2315 | 17 | 50 | 40 | 0.0427819 | 442 | 52 | 2337
2439709 | 00 begane grond | 1134 | no | 00 begane grond | 1030 | Basic Wall : 22_WA_kalkzandsteen_120mm | 1.26708 | 2315 | 17 | 50 | 40 | 0.0435344 | 456 | 52 | 2337
2444396 | 01 eerste verdieping | 1134 | no | 01 eerste verdieping | 1030 | Basic Wall : 22_WA_binnenwand_ms125 25-75-25 _gen_bdg | 1.26708 | 2315 | 17 | 50 | 40 | 0.0435344 | 456 | 52 | 2337
2544764 | 00 begane grond | 1034 | no | 00 begane grond | 930 | Floor : NLRS_43_FL_cementdekvloer 60_gen_ISR | 1.23488 | 2315 | 17 | 50 | 40 | 0.0427819 | 466 | 52 | 2337
5033765 | 00 begane grond | 1034 | yes | 00 begane grond | 946 | Basic Wall : 22_WA_binnenwand_ms125 25-75-25 _gen_bdg | 1.23613 | 2323 | 25 | 65 | 55 | 0.038436 | 458 | 44 | 2345

# IfcDoor: NLRS_32_samenstelling_binnenkozijn_hout_BDG:enkele deur met glasstrook (2)
In: 00 begane grond
Type - ConstructionType: USERDEFINED; ParameterTakesPrecedence: no; Sizeable: no; Material: n6_binnenkozijn
Type - Analytical Properties - Define Thermal Properties by: Schematic Type; Analytic Construction: <None>
Type - Constraints - Default Elevation: 0 mm
Type - Graphics - dubbele_deur: no; Vlak B1: Panel : dubbel glas; deur_type: NLRS_32_onderdeel_deur_BDG : deur met glasstrook
Type - Construction - Function: Interior; Construction Type: binnenkozijn hout
Type - Dimensions - tong_naald: 2 mm
Type - Identity Data - Workset: Family : Doors : NLRS_32_samenstelling_binnenkozijn_hout_BDG; Assembly Code: 2E(32.31.21); Datum_Gewijzigd: 14-11-2012; Description: binnendeur enkel; Model: LOD300; SmartRevit_Versie: 2013.2; Type Comments: samenstelling; Type Mark: 828; Type Name: enkele deur met glasstrook
Type - Other - Category: Doors; Family Name: NLRS_32_samenstelling_binnenkozijn_hout_BDG
OverallHeight: 2387 mm; OverallWidth: 1134 mm; Classification: 2E(32.31.21) Uniformat (Uniformat)
Fire Protection - brandwerendheid_120min: no; brandwerendheid_60min: no; brandwerendheid_90min: no; zelfsluitend: yes; brandwerendheid_30min: yes
Constraints - Level: 00 begane grond; Moves With Nearby Elements: no; Offset from Host: 0 mm; deur_breedte: 1046 mm; kozijn_breedte: 1134 mm
Phasing - Phase Created: 2. nieuwbouw
Graphics - WBDBO_tekst_andere_zijde: no; dorpel: no
Construction - kozijn_hoogte: 2387 mm; stijl_breedte: 67 mm; stijl_diepte: 125 mm
Dimensions - Area: 1.26833 m2; deur_hoogte: 2323 mm; dikte_onderdorpel: 5 mm; Height: 2387 mm; ruimte_onder_deur: 20 mm; sponning_breedte: 25 mm; sponning_diepte: 65 mm; Thickness: 55 mm; Volume: 0.039111 m3; Width: 1134 mm
Identity Data - Workset: Workset1
Other - deur_offset: 0 mm; Family: NLRS_32_samenstelling_binnenkozijn_hout_BDG; Type: enkele deur met glasstrook; berekende_deur_breedte: 1046 mm; berekende_ruimte_onder_deur: 20 mm; Family and Type: NLRS_32_samenstelling_binnenkozijn_hout_BDG: enkele deur met glasstrook; positie_deur: 44 mm; stijl_lengte: 2345 mm; Type Id: 1274097
Name (NLRS_32_samenstelling_binnenkozijn_hout_BDG:enkele deur met glasstrook:...) | Host | Mark
1294627 | Level : 00 begane grond | 186
1294756 | Basic Wall : 22_WA_binnenwand_ms125 25-75-25 _gen_bdg | 189

# IfcFlowController: NLRS_56_PIA_UN_bekersifon_generiek_ISR:std (13)
Type - Material: <Unnamed>
Type - Constraints - Default Elevation: 0 mm
Type - Mechanical - Loss Method: Not Defined
Type - Dimensions - Afvoer Radius: 16 mm; Radius groot: 19 mm
Type - Identity Data - Assembly Code: 56.11.11; Assembly Description: cv-radiatorsysteem; Description: Bekersifon; Keynote: 15400; Manufacturer: Viega; Model: LOD300; SmartRevit_Versie: 2019.1; Type Name: std; Workset: Family : Pipe Accessories : NLRS_56_PIA_UN_bekersifon_generiek_ISR
Type - Other - Category: Pipe Accessories; Family Name: NLRS_56_PIA_UN_bekersifon_generiek_ISR
Classification: 56.11.11 Uniformat (Uniformat)
Insulation - Insulation Thickness: 0 mm
Constraints - Moves With Nearby Elements: no
Phasing - Phase Created: 2. nieuwbouw
Dimensions - Area: 0.0129865 m2; Volume: 0.000160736 m3
Identity Data - Workset: Workset1
Other - Family: NLRS_56_PIA_UN_bekersifon_generiek_ISR; Family and Type: NLRS_56_PIA_UN_bekersifon_generiek_ISR: std; Type: std; Type Id: 1245054
Name (NLRS_56_PIA_UN_bekersifon_generiek_ISR:std:...) | In | Elevation from Level (mm) | Mark
1291629 | 00 begane grond | -9335.87 | 3
1508874 | 00 begane grond | 59068 | 12
1512362 | 01 eerste verdieping | 25397.7 | 21
1512566 | 01 eerste verdieping | 22893 | 24
1512622 | 01 eerste verdieping | 21099.6 | 27
1518946 | 02 tweede verdieping | -18552.4 | 36
1518994 | 02 tweede verdieping | -1535.87 | 39
1519496 | 02 tweede verdieping | -18244.5 | 42
1526381 | 02 tweede verdieping | 35988.2 | 48
1991822 | 01 eerste verdieping | -29917 | 18
2000491 | 01 eerste verdieping | -23263.7 | 30
2437038 | 00 begane grond | -18512 | 52
4193504 | 02 tweede verdieping | 26160.1 | 64

# IfcFlowController: NLRS_74_PIA_UN_hoekstopkraan_generiek_ISR:std (26)
Type - Material: <Unnamed>
Type - Constraints - Default Elevation: 600 mm
Type - Mechanical - Loss Method: Not Defined
Type - Dimensions - Radius 1: 7.5 mm; Radius 2: 12 mm
Type - Identity Data - Assembly Code: 74.11.51; Assembly Description: kraancombinatie; Description: Hoekstopkraan; Keynote: 15400; Manufacturer: VSH; Model: LOD300; SmartRevit_Versie: 2019.1; Type Name: std; Workset: Family : Pipe Accessories : NLRS_74_PIA_UN_hoekstopkraan_generiek_ISR
Type - Other - Category: Pipe Accessories; Family Name: NLRS_74_PIA_UN_hoekstopkraan_generiek_ISR
Classification: 74.11.51 Uniformat (Uniformat)
Insulation - Insulation Thickness: 0 mm
Constraints - Moves With Nearby Elements: no
Phasing - Phase Created: 2. nieuwbouw
Dimensions - Area: 0.00428674 m2; Volume: 0.000026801 m3
Identity Data - Workset: Workset1
Other - Type: std; Family: NLRS_74_PIA_UN_hoekstopkraan_generiek_ISR; Family and Type: NLRS_74_PIA_UN_hoekstopkraan_generiek_ISR: std; Type Id: 1245053
Name (NLRS_74_PIA_UN_hoekstopkraan_generiek_ISR:std:...) | In | Mark
1291630 | 00 begane grond | 2
1291631 | 00 begane grond | 1
1508875 | 00 begane grond | 11
1508876 | 00 begane grond | 10
1512363 | 01 eerste verdieping | 20
1512364 | 01 eerste verdieping | 19
1512567 | 01 eerste verdieping | 23
1512568 | 01 eerste verdieping | 22
1512623 | 01 eerste verdieping | 26
1512624 | 01 eerste verdieping | 25
1518947 | 02 tweede verdieping | 35
1518948 | 02 tweede verdieping | 34
1518995 | 02 tweede verdieping | 38
1518996 | 02 tweede verdieping | 37
1519497 | 02 tweede verdieping | 41
1519498 | 02 tweede verdieping | 40
1526382 | 02 tweede verdieping | 47
1526383 | 02 tweede verdieping | 46
1991823 | 01 eerste verdieping | 17
1991824 | 01 eerste verdieping | 16
2000492 | 01 eerste verdieping | 29
2000493 | 01 eerste verdieping | 28
2437039 | 00 begane grond | 53
2437040 | 00 begane grond | 54
4193505 | 02 tweede verdieping | 65
4193506 | 02 tweede verdieping | 66

# IfcFlowTerminal: 300_74_ISR_brandslanghaspel_inbouw:65_BDG_BSH 30 m¹ (6)
Type - Material: RAL 9010 - wit
Type - Constraints(Type) - Default Elevation: 410 mm
Type - Materials and Finishes(Type) - haspelkast_materiaal: RAL 9010 - wit
Type - Dimensions(Type) - haspelkast_breedte: 790 mm; haspelkast_diepte: 185 mm; haspelkast_hoogte: 790 mm; leiding_diameter: 22 mm; leiding_radius: 11 mm
Type - Identity Data(Type) - Assembly Code: 65.13; Assembly Description: beveiliging; brand, brandbestrijding; Datum_Gewijzigd: 09-05-2012; Description: bsh; SmartRevit_Versie: 2013.1; Type Name: 65_BDG_BSH 30 m¹; Workset: Family : Plumbing Fixtures : 300_74_ISR_brandslanghaspel_inbouw
Type - Other(Type) - Category: Plumbing Fixtures; Family Name: 300_74_ISR_brandslanghaspel_inbouw; slang_lengte: 30000 mm
Classification: 65.13 Uniformat (Uniformat)
Phasing - Phase Created: 2. nieuwbouw
Mechanical - brandslanghaspel_kw_flow: 0.361 m3/s; System Classification: Domestic Cold Water
Graphics - slang_bereik: no
Dimensions - Area: 0.916815 m2; Volume: 0.115459 m3
Identity Data - Workset: Workset1
Other - Category: Plumbing Fixtures; Family: 300_74_ISR_brandslanghaspel_inbouw; Family and Type: 300_74_ISR_brandslanghaspel_inbouw: 65_BDG_BSH 30 m¹; Type: 65_BDG_BSH 30 m¹; Type Id: 1812937
Name (300_74_ISR_brandslanghaspel_inbouw:65_BDG_BSH 30 m¹:...) | In | Level = Schedule Level | Elevation from Level (mm) | Host | Mark
1814539 | 00 begane grond | 00 begane grond | 800 | <not associated> | 51
1890558 | 01 eerste verdieping | 01 eerste verdieping | 800 | Basic Wall : 22_WA_binnenwand_ms100 25-75 _gen_bdg | 85
1932373 | 00 begane grond | 00 begane grond | 800 | Basic Wall : 22_WA_binnenwand_ms125 25-75-25 _gen_bdg | 88
1932698 | 02 tweede verdieping | 02 tweede verdieping | 800 | <not associated> | 89
2204706 | 02 tweede verdieping |  | 0 | Basic Wall : 22_WA_voorzetwand_ms100 25-75 _gen_bdg | 96
5033578 | 00 begane grond | 00 begane grond | 800 | Basic Wall : 22_WA_voorzetwand_ms100 25-75 _gen_bdg | 130

# IfcFlowTerminal: 300_74_ISR_inbouwreservoir_toilet1:std 2_optie miva (2)
In: 00 begane grond
Type - Material: <Unnamed>
Type - Constraints - Default Elevation: 0 mm
Type - Mechanical - CWFU: 1; HWFU: 1; WFU: 1
Type - Dimensions - kw_radius: 7.5 mm; reservoir_breedte: 500 mm; reservoir_diepte: 120 mm; vwa_radius: 45 mm
Type - Identity Data - Assembly Code: 4A(74.11.11); Datum_Gewijzigd: 14-11-2012; Description: inbouwreservoir toilet; Model: LOD300; SmartRevit_Versie: 2013.2; Type Name: std 2_optie miva; Workset: Family : Plumbing Fixtures : 300_74_ISR_inbouwreservoir_toilet1
Type - Other - Category: Plumbing Fixtures; Family Name: 300_74_ISR_inbouwreservoir_toilet1
Classification: 4A(74.11.11) Uniformat (Uniformat)
Constraints - Elevation from Level: 0 mm; Host: Basic Wall : 22_WA_voorzetwand_ms100 25-75 _gen_bdg
Phasing - Phase Created: 2. nieuwbouw
Mechanical - KW_flow: 0.04 m3/s; System Classification: Domestic Cold Water,Sanitary
Dimensions - Area: 0.423339 m2; kw_hoogte: 1045 mm; reservoir_hoogte: 1120 mm; toilet_hoogte: 410 mm; Volume: 0.0258822 m3; wand_dikte: 50 mm
Identity Data - Workset: Workset1
Other - Family: 300_74_ISR_inbouwreservoir_toilet1; Family and Type: 300_74_ISR_inbouwreservoir_toilet1: std 2_optie miva; MIVA: yes; toilet: 300_74_ISR_toilet_wand : std; Type: std 2_optie miva; Type Id: 1808056
Name (300_74_ISR_inbouwreservoir_toilet1:std 2_optie miva:...) | Mark
1808008 | 37 | Constraints - Level: 00 begane grond; Schedule Level: 00 begane grond
1811464 | 49

# IfcFlowTerminal: 300_74_ISR_toilet_wand:std (2)
In: 00 begane grond
Type - Material: <Unnamed>
Type - Constraints - Default Elevation: 400 mm
Type - Dimensions - toilet_breedte: 355 mm; toilet_diepte: 530 mm
Type - Identity Data - Assembly Code: 4A(74.11.11); Datum_Gewijzigd: 14-11-2012; Description: wand toilet; Model: LOD300; SmartRevit_Versie: 2013.2; Type Name: std; Workset: Family : Plumbing Fixtures : 300_74_ISR_toilet_wand
Type - Other - Category: Plumbing Fixtures
Classification: 4A(74.11.11) Uniformat (Uniformat)
Constraints - Moves With Nearby Elements: no; Host: Basic Wall : 22_WA_voorzetwand_ms100 25-75 _gen_bdg
Phasing - Phase Created: 2. nieuwbouw
Dimensions - Area: 0.680955 m2; Volume: 0.0324605 m3
Identity Data - Workset: Workset1
Other - Type: std; Family and Type: 300_74_ISR_toilet_wand: std; Type Id: 1808054
Name (300_74_ISR_toilet_wand:std:...) | Mark
1808009 | 48
1811465 | 50

# IfcFlowTerminal: 74_BDG_wastrog toiletten:Type 1 (6)
In: 00 begane grond
Type - Material: Default
Type - Constraints - Default Elevation: 0 mm
Type - Dimensions - hoogte_wasbak: 600 mm
Type - Identity Data - Assembly Code: 82.11; Assembly Description: losse gebruikersinventaris; standaard, meubilering; Type Name: Type 1; Workset: Family : Plumbing Fixtures : 74_BDG_wastrog toiletten
Type - Other - Category: Plumbing Fixtures; Family Name: 74_BDG_wastrog toiletten
Classification: 82.11 Uniformat (Uniformat)
Constraints - Level: 00 begane grond
Phasing - Phase Created: 2. nieuwbouw
Dimensions - Area: 1.11539 m2; Volume: 0.0525117 m3
Identity Data - Workset: Workset1; algemeen_leverancier: ICN Solutions B.V.; algemeen_URL: www.3b-werkmethodiek.nl
Other - algemeen_methode: 3B Werkmethodiek; Family: 74_BDG_wastrog toiletten; Family and Type: 74_BDG_wastrog toiletten: Type 1; Type: Type 1; Type Id: 1964405
Name (74_BDG_wastrog toiletten:Type 1:...) | Elevation from Level (mm) | Mark | Host Id
1964459 | 800 | 90 | 1878851
1964932 | 800 | 92 | 1878850
3831228 | 400 | 120 | 2161149
4008949 | 400 | 121 | 2161147
4009167 | 400 | 122 | 2426873
4009217 | 400 | 123 | 2160282

# IfcFlowTerminal: 74_PF_WPB_douchehoek:74_PF_WPB_douchehoek (16)
In: 00 begane grond
Type - Material: <Unnamed>
Type - Constraints - Default Elevation: 1219.2 mm
Type - Dimensions - hoogte_douchewand: 2000 mm; hoogte_kraan: 1000 mm
Type - Identity Data - Type Name: 74_PF_WPB_douchehoek; Workset: Family : Plumbing Fixtures : 74_PF_WPB_douchehoek
Type - Other - Category: Plumbing Fixtures; Family Name: 74_PF_WPB_douchehoek
Constraints - Elevation from Level: 0 mm; Level: 00 begane grond; Offset from Host: 0 mm; Schedule Level: 00 begane grond
Phasing - Phase Created: 2. nieuwbouw
Dimensions - Volume: 0.00093295 m3
Identity Data - Workset: Workset1
Other - contouren: no; douchewand: no; Family: 74_PF_WPB_douchehoek; Family and Type: 74_PF_WPB_douchehoek: 74_PF_WPB_douchehoek; Type: 74_PF_WPB_douchehoek; Type Id: 1878877
Name (74_PF_WPB_douchehoek:74_PF_WPB_douchehoek:...) | Work Plane | Area (m2) | breedte (mm) | lengte (mm) | Mark
1878853 | Level : 00 begane grond | 1.642 | 900 | 800 | 7
1879784 | Level : 00 begane grond | 1.642 | 880 | 800 | 53
1879786 | Level : 00 begane grond | 1.642 | 880 | 800 | 55
1879788 | Level : 00 begane grond | 1.642 | 880 | 800 | 57
1882212 | Level : 00 begane grond | 1.642 | 880 | 800 | 63
1882575 | Level : 00 begane grond | 1.642 | 900 | 800 | 71
1882577 | Level : 00 begane grond | 1.642 | 880 | 800 | 73
1882579 | Level : 00 begane grond | 1.642 | 880 | 800 | 75
1882581 | Level : 00 begane grond | 1.642 | 880 | 800 | 77
1882603 | Level : 00 begane grond | 1.642 | 880 | 800 | 83
2409334 | Level : 00 begane grond | 1.642 | 880 | 800 | 101
2411518 | Floor : NLRS_43_FL_cementdekvloer 60_gen_ISR | 1.642 | 880 | 800 | 103
2411530 | Level : 00 begane grond | 1.642 | 880 | 800 | 105
2411532 | Level : 00 begane grond | 1.642 | 880 | 800 | 112
5073857 | Floor : NLRS_43_FL_cementdekvloer 60_gen_ISR | 2.51053 | 880 | 1231.03 | 131
5073968 | Level : 00 begane grond | 1.642 | 880 | 800 | 133

# IfcFlowTerminal: 74_PF_uitstortgootsteen:Type 1 (2)
In: 00 begane grond
Type - Material: <Unnamed>
Type - Constraints - Default Elevation: 0 mm
Type - Dimensions - hoogte_wasbak: 450 mm
Type - Identity Data - Assembly Code: 4A(74.10); Type Name: Type 1; Workset: Family : Plumbing Fixtures : 74_PF_uitstortgootsteen
Type - Other - Category: Plumbing Fixtures; Family Name: 74_PF_uitstortgootsteen
Classification: 4A(74.10) Uniformat (Uniformat)
Constraints - Level: 00 begane grond; Elevation from Level: 600 mm
Phasing - Phase Created: 2. nieuwbouw
Dimensions - Area: 0.758564 m2; Volume: 0.0234412 m3
Identity Data - Workset: Workset1; algemeen_leverancier: ICN Solutions B.V.; algemeen_URL: www.3b-werkmethodiek.nl
Other - Type: Type 1; algemeen_methode: 3B Werkmethodiek; Family: 74_PF_uitstortgootsteen; Family and Type: 74_PF_uitstortgootsteen: Type 1; Type Id: 1986444
Name (74_PF_uitstortgootsteen:Type 1:...) | Mark | Host Id
1987494 | 94 | 1218274
2326184 | 98 | 2326015

# IfcFlowTerminal: NLRS_74_PF_FB_toilet wand_generiek_ISR:toilet_gen (26)
Type - Material: <Unnamed>
Type - Constraints - Default Elevation: 400 mm
Type - Dimensions - toilet_breedte: 355 mm; toilet_diepte: 530 mm
Type - Identity Data - Assembly Code: 74.11.11; Assembly Description: closetcombinatie; Description: wand toilet; Model: LOD300; SmartRevit_Versie: 2019.1; Type Name: toilet_gen; Workset: Family : Plumbing Fixtures : NLRS_74_PF_FB_toilet wand_generiek_ISR
Type - Other - Category: Plumbing Fixtures; Family Name: NLRS_74_PF_FB_toilet wand_generiek_ISR
Classification: 74.11.11 Uniformat (Uniformat)
Constraints - Elevation from Level: 500 mm
Phasing - Phase Created: 2. nieuwbouw
Dimensions - Area: 0.681091 m2; Volume: 0.0325026 m3
Identity Data - Workset: Workset1
Other - Family: NLRS_74_PF_FB_toilet wand_generiek_ISR; Family and Type: NLRS_74_PF_FB_toilet wand_generiek_ISR: toilet_gen; Type: toilet_gen; Type Id: 1245062
Name (NLRS_74_PF_FB_toilet wand_generiek_ISR:toilet_gen:...) | In | Level = Schedule Level | Host | Mark
1244967 | 02 tweede verdieping | 02 tweede verdieping | Basic Wall : 22_WA_voorzetwand_ms100 25-75 _gen_bdg | 111
1291577 | 02 tweede verdieping | 02 tweede verdieping | Basic Wall : 22_WA_voorzetwand_ms100 25-75 _gen_bdg | 1
1291578 | 02 tweede verdieping | 02 tweede verdieping | Basic Wall : 22_WA_voorzetwand_ms100 25-75 _gen_bdg | 2
1291580 | 02 tweede verdieping | 02 tweede verdieping | Basic Wall : 22_WA_voorzetwand_ms100 25-75 _gen_bdg | 3
1291582 | 02 tweede verdieping | 02 tweede verdieping | Basic Wall : 22_WA_voorzetwand_ms100 25-75 _gen_bdg | 4
1291583 | 02 tweede verdieping | 02 tweede verdieping | Basic Wall : 22_WA_voorzetwand_ms100 25-75 _gen_bdg | 5
1291585 | 02 tweede verdieping | 02 tweede verdieping | Basic Wall : 22_WA_voorzetwand_ms100 25-75 _gen_bdg | 6
1291588 | 01 eerste verdieping | 01 eerste verdieping | Basic Wall : 22_WA_voorzetwand_ms100 25-75 _gen_bdg | 8
1291590 | 01 eerste verdieping | 01 eerste verdieping | Basic Wall : 22_WA_voorzetwand_ms100 25-75 _gen_bdg | 9
1291591 | 01 eerste verdieping | 01 eerste verdieping | Basic Wall : 22_WA_voorzetwand_ms100 25-75 _gen_bdg | 10
1291593 | 01 eerste verdieping | 01 eerste verdieping | Basic Wall : 22_WA_voorzetwand_ms100 25-75 _gen_bdg | 11
1291594 | 01 eerste verdieping | 01 eerste verdieping | Basic Wall : 22_WA_voorzetwand_ms100 25-75 _gen_bdg | 12
1291596 | 01 eerste verdieping | 01 eerste verdieping | Basic Wall : 22_WA_voorzetwand_ms100 25-75 _gen_bdg | 13
1291603 | 00 begane grond | 00 begane grond | Basic Wall : 22_WA_voorzetwand_ms100 25-75 _gen_bdg | 17
1291605 | 00 begane grond | 00 begane grond | Basic Wall : 22_WA_voorzetwand_ms100 25-75 _gen_bdg | 18
1330069 | 01 eerste verdieping | 01 eerste verdieping | Basic Wall : 22_WA_voorzetwand_ms100 25-75 _gen_bdg | 22
1370063 | 00 begane grond | 00 begane grond | Basic Wall : 22_WA_voorzetwand_ms100 25-75 _gen_bdg | 23
1370136 | 00 begane grond | 00 begane grond | Basic Wall : 22_WA_voorzetwand_ms100 25-75 _gen_bdg | 24
1370230 | 00 begane grond | 00 begane grond | Basic Wall : 22_WA_kalkzandsteen_120mm | 25
1370492 | 00 begane grond | 00 begane grond | Basic Wall : 22_WA_kalkzandsteen_120mm | 26
1370700 | 00 begane grond | 00 begane grond | Basic Wall : 22_WA_kalkzandsteen_120mm | 27
1370822 | 00 begane grond | 00 begane grond | Basic Wall : 22_WA_voorzetwand_ms100 25-75 _gen_bdg | 28
1371056 | 00 begane grond | 00 begane grond | Basic Wall : 22_WA_voorzetwand_ms100 25-75 _gen_bdg | 29
1509722 | 00 begane grond | 00 begane grond | Basic Wall : 22_WA_voorzetwand_ms100 25-75 _gen_bdg | 34
1509918 | 00 begane grond | 00 begane grond | Basic Wall : 22_WA_voorzetwand_ms100 25-75 _gen_bdg | 35
1509957 | 00 begane grond | 00 begane grond | Basic Wall : 22_WA_voorzetwand_ms100 25-75 _gen_bdg | 36

# IfcFlowTerminal: NLRS_74_PF_FB_wastafel_generiek_ISR:wastafel_gen (13)
Type - Material: <Unnamed>
Type - Constraints - Default Elevation: 900 mm
Type - Mechanical - CWFU: 1; HWFU: 1; wastafel_kw_flow: 0.083 m3/s; wastafel_vwa_flow: 0.5 m3/s; wastafel_ww_flow: 0.042 m3/s; WFU: 1
Type - Dimensions - afvoer_radius: 16 mm; wastafel_breedte: 550 mm; wastafel_diepte: 445 mm; wastafel_diepte_afvoer: 220 mm; wastafel_hoogte: 180 mm; water_radius: 7.5 mm
Type - Identity Data - Assembly Code: 74.11.31; Assembly Description: wastafelcombinatie; Description: wastafel; Model: LOD300; SmartRevit_Versie: 2019.1; Type Name: wastafel_gen; Workset: Family : Plumbing Fixtures : NLRS_74_PF_FB_wastafel_generiek_ISR
Type - Other - Category: Plumbing Fixtures; afvoer_radius_rond: 21 mm; Family Name: NLRS_74_PF_FB_wastafel_generiek_ISR; water_radius_rond: 10.5 mm
Classification: 74.11.31 Uniformat (Uniformat)
Phasing - Phase Created: 2. nieuwbouw
Mechanical - System Classification: Sanitary,Domestic Hot Water,Domestic Cold Water
Dimensions - Area: 0.415747 m2; Volume: 0.0238908 m3
Identity Data - Workset: Workset1
Other - Family: NLRS_74_PF_FB_wastafel_generiek_ISR; Family and Type: NLRS_74_PF_FB_wastafel_generiek_ISR: wastafel_gen; Hoekstopkraan: NLRS_74_PIA_UN_hoekstopkraan_generiek_ISR : std; Sifon: NLRS_56_PIA_UN_bekersifon_generiek_ISR : std; Type: wastafel_gen; Type Id: 1245063
Name (NLRS_74_PF_FB_wastafel_generiek_ISR:wastafel_gen:...) | In | Level = Schedule Level | Elevation from Level (mm) | Host | Mark
1291628 | 00 begane grond | 00 begane grond | 900 | Basic Wall : 22_WA_binnenwand_ms125 25-75-25 _gen_bdg | 19
1508872 | 00 begane grond | 00 begane grond | 900 | Basic Wall : 22_WA_binnenwand_ms125 25-75-25 _gen_bdg | 31
1512360 | 01 eerste verdieping | 01 eerste verdieping | 900 | NLRS_32_houten_binnenkozijn_BDG : BI-06v 930x2315 enkel 67x125 | 38
1512564 | 01 eerste verdieping | 01 eerste verdieping | 900 | Basic Wall : 22_WA_binnenwand_ms125 25-75-25 _gen_bdg | 39
1512620 | 01 eerste verdieping | 01 eerste verdieping | 900 | Basic Wall : 22_WA_binnenwand_ms125 25-75-25 _gen_bdg | 40
1518944 | 02 tweede verdieping | 02 tweede verdieping | 900 | Basic Wall : 22_WA_binnenwand_ms125 25-75-25 _gen_bdg | 43
1518992 | 02 tweede verdieping | 02 tweede verdieping | 900 | Basic Wall : 22_WA_voorzetwand_ms100 25-75 _gen_bdg | 44
1519494 | 02 tweede verdieping | 02 tweede verdieping | 900 | Basic Wall : 22_WA_voorzetwand_ms100 25-75 _gen_bdg | 45
1526379 | 02 tweede verdieping | 02 tweede verdieping | 900 | Basic Wall : 22_WA_binnenwand_ms125 25-75-25 _gen_bdg | 47
1991821 | 01 eerste verdieping | 01 eerste verdieping | 900 | Basic Wall : 22_WA_voorzetwand_ms100 25-75 _gen_bdg | 86
2000490 | 01 eerste verdieping | 01 eerste verdieping | 900 | Basic Wall : 22_WA_voorzetwand_ms100 25-75 _gen_bdg | 87
2437037 | 00 begane grond |  | 0 | Basic Wall : 22_WA_binnenwand_ms125 25-75-25 _gen_bdg | 114
4193503 | 02 tweede verdieping |  | 0 | Basic Wall : 22_WA_voorzetwand_ms100 25-75 _gen_bdg | 128

# IfcFlowTerminal: NLRS_82 PF_UN_wasmaschine_generiek_ISR:wasmachine_gen, NLRS_82 PF_UN_wasmaschine_generiek_ISR:wasmachine_gen:2544580
In: 00 begane grond
Type - Material: <Unnamed>
Type - Electrical - Loads - aansluit_waarde: 2300 W
Type - Text - text: yes
Type - Constraints - Default Elevation: 0 mm
Type - Dimensions - KW_radius: 11 mm; NLRS_C_breedte: 600 mm; NLRS_C_diepte: 590 mm; NLRS_C_hoogte: 850 mm; VWA_radius: 20 mm; wasmaschine_breedte: 600 mm; wasmaschine_diepte: 590 mm; wasmaschine_hoogte: 850 mm
Type - Identity Data - Assembly Code: 85.11; Assembly Description: losse schoonmaakinventaris; standaard, schoonmaakapparatuur; Description: wasmachine; Model: LOD300; SmartRevit_Versie: 2019.1; Type Comments: WM; Type Name: wasmachine_gen; Workset: Family : Plumbing Fixtures : NLRS_82 PF_UN_wasmaschine_generiek_ISR
Type - Other - Category: Plumbing Fixtures; Family Name: NLRS_82 PF_UN_wasmaschine_generiek_ISR
Classification: 85.11 Uniformat (Uniformat)
Constraints - Elevation from Level: 0 mm; Level: 00 begane grond; Offset from Host: 0 mm; Host: Level : 00 begane grond
Phasing - Phase Created: 2. nieuwbouw
Mechanical - System Classification: Domestic Cold Water,Sanitary,Power
Dimensions - Area: 1.19115 m2; Volume: 0.241093 m3
Identity Data - Workset: Workset1; Mark: 119
Other - Family: NLRS_82 PF_UN_wasmaschine_generiek_ISR; Family and Type: NLRS_82 PF_UN_wasmaschine_generiek_ISR: wasmachine_gen; Type: wasmachine_gen; Type Id: 1629793

# IfcFurnishingElement: 00_GM_kleedkamerbank:wandsysteem h=400 (6)
In: 00 begane grond
Type - Material: Steel, 45-345, Wood - Stained
Type - Constraints - Default Elevation: 0 mm
Type - Materials and Finishes - materiaal_constructie: Steel, 45-345; materiaal_haakjes: Steel, 45-345; materiaal_zitvlak_kapstok: Wood - Stained
Type - Dimensions - diepte_zitvlak: 536 mm; hoogte_kapstok: 1805 mm; hoogte_zitvlak: 400 mm
Type - Identity Data - Description: vrijhangende zitbank incl. haakjes; Type Name: wandsysteem h=400; Workset: Family : Furniture : 00_GM_kleedkamerbank
Type - Other - Category: Furniture; Family Name: 00_GM_kleedkamerbank; hoogte: 400 mm; vloersysteem: no; wandsysteem: yes
Constraints - Offset from Host: 0 mm; Work Plane: Level : 00 begane grond
Phasing - Phase Created: 2. nieuwbouw
Identity Data - Workset: Workset1
Other - Family: 00_GM_kleedkamerbank; Family and Type: 00_GM_kleedkamerbank: wandsysteem h=400; Type: wandsysteem h=400; Type Id: 1841924
Name (00_GM_kleedkamerbank:wandsysteem h=400:...) | getal1 = aantal_haakjes | Length (mm) = lengte (mm) | Area (m2) | Volume (m3) | constructie_hoh
1842418 | 24 | 4780 | 4.97074 | 0.0945125 | 4
1844525 | 11 | 2200 | 2.37004 | 0.0450222 | 2
1845664 | 15 | 3000 | 3.35802 | 0.0640063 | 3
1846092 | 20 | 4000 | 4.47345 | 0.0853418 | 4
1846600 | 20 | 4000 | 4.47345 | 0.0853418 | 4
1847088 | 10 | 2000 | 2.24259 | 0.0426709 | 2

# IfcFurnishingElement: 80_FUS_UN_bovenkast enkel:520x650x1337 (2)
In: 00 begane grond
Type - Material: i4_multiplex
Type - Constraints - Default Elevation: 0 mm
Type - Materials and Finishes - afwerking kastdeur: i4_multiplex; materiaal algemeen: i4_multiplex
Type - Dimensions - breedte: 520 mm; diepte_bovenkast: 650 mm; hoogte_bovenkast: 1337 mm; ok bovenkast tov vloer: 1500 mm
Type - Identity Data - Workset: Family : Furniture Systems : 80_FUS_UN_bovenkast enkel; Type Name: 520x650x1337
Type - Other - Category: Furniture Systems; Family Name: 80_FUS_UN_bovenkast enkel
Constraints - Level: 00 begane grond; Moves With Nearby Elements: no; Elevation from Level: -450 mm; Host: Floor : NLRS_43_FL_cementdekvloer 60_gen_ISR; Offset from Host: -450 mm
Phasing - Phase Created: 2. nieuwbouw
Dimensions - Area: 3.68382 m2; Volume: 0.0576722 m3
Identity Data - Workset: Workset1
Other - Family: 80_FUS_UN_bovenkast enkel; Family and Type: 80_FUS_UN_bovenkast enkel: 520x650x1337; Type: 520x650x1337; Type Id: 4780521
Name (80_FUS_UN_bovenkast enkel:520x650x1337:...)
4774701
4775119

# IfcFurnishingElement: 80_FUS_UN_bovenkast enkel:525x650x1337 (2)
In: 00 begane grond
Type - Material: i4_multiplex
Type - Constraints - Default Elevation: 0 mm
Type - Materials and Finishes - afwerking kastdeur: i4_multiplex; materiaal algemeen: i4_multiplex
Type - Dimensions - breedte: 525 mm; diepte_bovenkast: 650 mm; hoogte_bovenkast: 1337 mm; ok bovenkast tov vloer: 1500 mm
Type - Identity Data - Type Name: 525x650x1337; Workset: Family : Furniture Systems : 80_FUS_UN_bovenkast enkel
Type - Other - Category: Furniture Systems; Family Name: 80_FUS_UN_bovenkast enkel
Constraints - Level: 00 begane grond; Moves With Nearby Elements: no; Elevation from Level: -450 mm; Host: Floor : NLRS_43_FL_cementdekvloer 60_gen_ISR; Offset from Host: -450 mm
Phasing - Phase Created: 2. nieuwbouw
Dimensions - Area: 3.70346 m2; Volume: 0.0579974 m3
Identity Data - Workset: Workset1
Other - Family: 80_FUS_UN_bovenkast enkel; Family and Type: 80_FUS_UN_bovenkast enkel: 525x650x1337; Type: 525x650x1337; Type Id: 3057968
Name (80_FUS_UN_bovenkast enkel:525x650x1337:...)
2071442
4775338

# IfcFurnishingElement: 80_FUS_UN_bovenkast enkel:575x600x1337 (4)
Type - Material: i4_multiplex
Type - Constraints - Default Elevation: 0 mm
Type - Materials and Finishes - afwerking kastdeur: i4_multiplex; materiaal algemeen: i4_multiplex
Type - Dimensions - breedte: 575 mm; diepte_bovenkast: 600 mm; hoogte_bovenkast: 1337 mm; ok bovenkast tov vloer: 1500 mm
Type - Identity Data - Workset: Family : Furniture Systems : 80_FUS_UN_bovenkast enkel; Type Name: 575x600x1337
Type - Other - Category: Furniture Systems; Family Name: 80_FUS_UN_bovenkast enkel
Constraints - Moves With Nearby Elements: no; Elevation from Level: -450 mm; Host: Floor : NLRS_43_FL_cementdekvloer 50_gen_ISR; Offset from Host: -450 mm
Phasing - Phase Created: 2. nieuwbouw
Dimensions - Area: 3.71171 m2; Volume: 0.0584266 m3
Identity Data - Workset: Workset1
Other - Family: 80_FUS_UN_bovenkast enkel; Family and Type: 80_FUS_UN_bovenkast enkel: 575x600x1337; Type: 575x600x1337; Type Id: 3058038
Name (80_FUS_UN_bovenkast enkel:575x600x1337:...) | In | Level
2843341 | 01 eerste verdieping | 01 eerste verdieping
4778357 | 01 eerste verdieping | 01 eerste verdieping
4784255 | 02 tweede verdieping | 02 tweede verdieping
4784341 | 02 tweede verdieping | 02 tweede verdieping

# IfcFurnishingElement: 80_FUS_UN_bovenkast enkel:580x600x1337 (2)
Type - Material: i4_multiplex
Type - Constraints - Default Elevation: 0 mm
Type - Materials and Finishes - afwerking kastdeur: i4_multiplex; materiaal algemeen: i4_multiplex
Type - Dimensions - breedte: 580 mm; diepte_bovenkast: 600 mm; hoogte_bovenkast: 1337 mm; ok bovenkast tov vloer: 1500 mm
Type - Identity Data - Workset: Family : Furniture Systems : 80_FUS_UN_bovenkast enkel; Type Name: 580x600x1337
Type - Other - Category: Furniture Systems; Family Name: 80_FUS_UN_bovenkast enkel
Constraints - Moves With Nearby Elements: no; Elevation from Level: -450 mm; Host: Floor : NLRS_43_FL_cementdekvloer 50_gen_ISR; Offset from Host: -450 mm
Phasing - Phase Created: 2. nieuwbouw
Dimensions - Area: 3.73086 m2; Volume: 0.0587444 m3
Identity Data - Workset: Workset1
Other - Family: 80_FUS_UN_bovenkast enkel; Family and Type: 80_FUS_UN_bovenkast enkel: 580x600x1337; Type: 580x600x1337; Type Id: 4778278
Name (80_FUS_UN_bovenkast enkel:580x600x1337:...) | In | Level
2849403 | 01 eerste verdieping | 01 eerste verdieping
4784256 | 02 tweede verdieping | 02 tweede verdieping

# IfcFurnishingElement: 80_FUS_UN_bovenkast enkel:600x600x587 (6)
Type - Material: <Unnamed>
Type - Constraints - Default Elevation: 0 mm
Type - Dimensions - breedte: 600 mm; diepte_bovenkast: 600 mm; hoogte_bovenkast: 587 mm; ok bovenkast tov vloer: 1800 mm
Type - Identity Data - Workset: Family : Furniture Systems : 80_FUS_UN_bovenkast enkel; Type Name: 600x600x587
Type - Other - Category: Furniture Systems; Family Name: 80_FUS_UN_bovenkast enkel
Constraints - Elevation from Level: 0 mm; Moves With Nearby Elements: no; Offset from Host: 0 mm
Phasing - Phase Created: 2. nieuwbouw
Dimensions - Area: 2.04119 m2; Volume: 0.0317028 m3
Identity Data - Workset: Workset1
Other - Family: 80_FUS_UN_bovenkast enkel; Family and Type: 80_FUS_UN_bovenkast enkel: 600x600x587; Type: 600x600x587; Type Id: 2066879
Name (80_FUS_UN_bovenkast enkel:600x600x587:...) | In | Level | Host
2201780 | 01 eerste verdieping | 01 eerste verdieping | Floor : NLRS_43_FL_cementdekvloer 50_gen_ISR
2838676 | 01 eerste verdieping | 01 eerste verdieping | Floor : NLRS_43_FL_cementdekvloer 50_gen_ISR
2843502 | 00 begane grond | 00 begane grond | Floor : NLRS_43_FL_cementdekvloer 60_gen_ISR
2843598 | 00 begane grond | 00 begane grond | Floor : NLRS_43_FL_cementdekvloer 60_gen_ISR
2854497 | 02 tweede verdieping | 02 tweede verdieping | Floor : NLRS_43_FL_cementdekvloer 50_gen_ISR
2854501 | 02 tweede verdieping | 02 tweede verdieping | Floor : NLRS_43_FL_cementdekvloer 50_gen_ISR

# IfcFurnishingElement: 80_FUS_UN_bovenkast enkel:660x600x1337 (10)
Type - Material: i4_multiplex
Type - Constraints - Default Elevation: 0 mm
Type - Materials and Finishes - afwerking kastdeur: i4_multiplex; materiaal algemeen: i4_multiplex
Type - Dimensions - breedte: 660 mm; diepte_bovenkast: 600 mm; hoogte_bovenkast: 1337 mm; ok bovenkast tov vloer: 1050 mm
Type - Identity Data - Workset: Family : Furniture Systems : 80_FUS_UN_bovenkast enkel; Type Name: 660x600x1337
Type - Other - Category: Furniture Systems; Family Name: 80_FUS_UN_bovenkast enkel
Constraints - Elevation from Level: 0 mm; Moves With Nearby Elements: no; Offset from Host: 0 mm; Host: Floor : NLRS_43_FL_cementdekvloer 50_gen_ISR
Phasing - Phase Created: 2. nieuwbouw
Dimensions - Area: 4.03718 m2; Volume: 0.063828 m3
Identity Data - Workset: Workset1
Other - Family: 80_FUS_UN_bovenkast enkel; Family and Type: 80_FUS_UN_bovenkast enkel: 660x600x1337; Type: 660x600x1337; Type Id: 2842834
Name (80_FUS_UN_bovenkast enkel:660x600x1337:...) | In | Level
2843098 | 01 eerste verdieping | 01 eerste verdieping
2850231 | 01 eerste verdieping | 01 eerste verdieping
2850268 | 01 eerste verdieping | 01 eerste verdieping
2850303 | 01 eerste verdieping | 01 eerste verdieping
2850338 | 01 eerste verdieping | 01 eerste verdieping
2854502 | 02 tweede verdieping | 02 tweede verdieping
2854506 | 02 tweede verdieping | 02 tweede verdieping
2854507 | 02 tweede verdieping | 02 tweede verdieping
2854508 | 02 tweede verdieping | 02 tweede verdieping
2854509 | 02 tweede verdieping | 02 tweede verdieping

# IfcFurnishingElement: 80_FUS_UN_bovenkast enkel:kast boven koelkast (2)
In: 00 begane grond
Type - Material: <Unnamed>
Type - Constraints - Default Elevation: 0 mm
Type - Dimensions - breedte: 600 mm; diepte_bovenkast: 600 mm; hoogte_bovenkast: 500 mm; ok bovenkast tov vloer: 2000 mm
Type - Identity Data - Workset: Family : Furniture Systems : 80_FUS_UN_bovenkast enkel; Type Name: kast boven koelkast
Type - Other - Category: Furniture Systems; Family Name: 80_FUS_UN_bovenkast enkel
Constraints - Elevation from Level: 0 mm; Level: 00 begane grond; Moves With Nearby Elements: no; Offset from Host: 0 mm; Host: Level : 00 begane grond
Phasing - Phase Created: 2. nieuwbouw
Dimensions - Area: 1.8363 m2; Volume: 0.0284185 m3
Identity Data - Workset: Workset1
Other - Family: 80_FUS_UN_bovenkast enkel; Family and Type: 80_FUS_UN_bovenkast enkel: kast boven koelkast; Type: kast boven koelkast; Type Id: 2867443
Name (80_FUS_UN_bovenkast enkel:kast boven koelkast:...) | Group
2867290 | Model Group:pantry 1 kinderopvang:1511177
2867409 | Model Group:pantry 1 kinderopvang:1223752

# IfcFurnishingElement: 80_FUS_UN_bovenkast magnetron:kast boven koelkast, 80_FUS_UN_bovenkast magnetron:kast boven koelkast:3685344
In: 00 begane grond
Type - Material: <Unnamed>
Type - Constraints - Default Elevation: 0 mm
Type - Dimensions - breedte: 600 mm; diepte_bovenkast: 600 mm; hoogte_bovenkast: 500 mm; ok bovenkast tov vloer: 2000 mm
Type - Identity Data - Type Name: kast boven koelkast; Workset: Family : Furniture Systems : 80_FUS_UN_bovenkast magnetron
Type - Other - Category: Furniture Systems; Family Name: 80_FUS_UN_bovenkast magnetron
Constraints - Moves With Nearby Elements: no; Level: bk. fundering; Elevation from Level: 20 mm; Host: Level : bk. fundering; Offset from Host: 20 mm
Phasing - Phase Created: 2. nieuwbouw
Dimensions - Area: 1.84395 m2; Volume: 0.0269885 m3
Identity Data - Workset: Workset1
Other - Type: kast boven koelkast; Family: 80_FUS_UN_bovenkast magnetron; Family and Type: 80_FUS_UN_bovenkast magnetron: kast boven koelkast; Type Id: 3689569
Group: Model Group:pantry 1 kinderopvang:1511177

# IfcFurnishingElement: 80_FUS_UN_centrale keuken:zonder bovenkastjes_gen, 80_FUS_UN_centrale keuken:zonder bovenkastjes_gen:2500989
In: 00 begane grond
Type - Material: <Unnamed>
Type - Constraints - Default Elevation: 0 mm
Type - Graphics - met_bovenkastjes: no; met_kookzone: yes
Type - Dimensions - aanrecht_lengte: 1800 mm; blad_hoogte: 900 mm; bovenkast_hoogte: 900 mm; keuken_hoogte: 2200 mm
Type - Identity Data - Assembly Code: 73.11; Assembly Description: vaste keukenvoorzieningen; standaard, keukenmeubilering; Description: aanrechtblok zonder bovenkastjes; Model: LOD300; SmartRevit_Versie: 2019.1; Type Name: zonder bovenkastjes_gen; Workset: Family : Furniture Systems : 80_FUS_UN_centrale keuken
Type - Other - Category: Furniture Systems; afronding_bak: 50 mm; bak_afstand: 50 mm; bak_breedte_1: 300 mm; bak_breedte_2: 300 mm; bak_hoogte: 200 mm; bak_plaatsing: 875 mm; bovenkast_diepte: 300 mm; Family Name: 80_FUS_UN_centrale keuken; fornuis_plaatsing: 300 mm; vrije_hoogte: 600 mm
Classification: 73.11 Uniformat (Uniformat)
Constraints - Elevation from Level: 0 mm; Level: 00 begane grond; Moves With Nearby Elements: no; Offset from Host: 0 mm; Host: Level : 00 begane grond
Phasing - Phase Created: 2. nieuwbouw
Dimensions - Area: 6.39078 m2; NLRS_C_hoogte: 2200 mm; NLRS_C_lengte: 1800 mm; Volume: 1.67312 m3
Identity Data - Workset: Workset1
Other - Type: zonder bovenkastjes_gen; Family: 80_FUS_UN_centrale keuken; Family and Type: 80_FUS_UN_centrale keuken: zonder bovenkastjes_gen; Type Id: 2492144

# IfcFurnishingElement: 80_FUS_UN_centrale keuken_kookeiland:zonder bovenkastjes_gen, 80_FUS_UN_centrale keuken_kookeiland:zonder bovenkastjes_gen:1957233
In: 00 begane grond
Type - Material: <Unnamed>
Type - Constraints - Default Elevation: 0 mm
Type - Graphics - met_bovenkastjes: no; met_kookzone: yes
Type - Dimensions - aanrecht_lengte: 3000 mm; blad_hoogte: 900 mm; bovenkast_hoogte: 900 mm; keuken_hoogte: 2200 mm
Type - Identity Data - Assembly Code: 73.11; Assembly Description: vaste keukenvoorzieningen; standaard, keukenmeubilering; Description: aanrechtblok zonder bovenkastjes; Model: LOD300; SmartRevit_Versie: 2019.1; Type Name: zonder bovenkastjes_gen; Workset: Family : Furniture Systems : 80_FUS_UN_centrale keuken_kookeiland
Type - Other - Category: Furniture Systems; afronding_bak: 50 mm; bak_afstand: 50 mm; bak_breedte_1: 400 mm; bak_breedte_2: 400 mm; bak_hoogte: 200 mm; bak_plaatsing: 625 mm; bovenkast_diepte: 300 mm; Family Name: 80_FUS_UN_centrale keuken_kookeiland; fornuis_plaatsing: 25 mm; vrije_hoogte: 600 mm
Classification: 73.11 Uniformat (Uniformat)
Constraints - Elevation from Level: 0 mm; Level: 00 begane grond; Moves With Nearby Elements: no; Offset from Host: 0 mm; Host: Level : 00 begane grond
Phasing - Phase Created: 2. nieuwbouw
Dimensions - Area: 6.74277 m2; NLRS_C_hoogte: 2200 mm; NLRS_C_lengte: 3000 mm; Volume: 2.30056 m3
Identity Data - Workset: Workset1; Comments: keuken
Other - wasbak: yes; Family: 80_FUS_UN_centrale keuken_kookeiland; Family and Type: 80_FUS_UN_centrale keuken_kookeiland: zonder bovenkastjes_gen; Type: zonder bovenkastjes_gen; Type Id: 1956060

# IfcFurnishingElement: 80_FUS_UN_opslagplanken:diepte 400 (21)
Type - Material: i4_multiplex
Type - Constraints - Default Elevation: 0 mm
Type - Materials and Finishes - materiaal: i4_multiplex
Type - Dimensions - plankdiepte: 400 mm
Type - Identity Data - Type Name: diepte 400; Workset: Family : Furniture Systems : 80_FUS_UN_opslagplanken
Type - Other - Category: Furniture Systems; Family Name: 80_FUS_UN_opslagplanken
Constraints - Elevation from Level: 0 mm; Moves With Nearby Elements: no; Offset from Host: 0 mm
Phasing - Phase Created: 2. nieuwbouw
Identity Data - Workset: Workset1; Comments: legplanken
Other - Family: 80_FUS_UN_opslagplanken; Family and Type: 80_FUS_UN_opslagplanken: diepte 400; Type: diepte 400; Type Id: 3197045
Name (80_FUS_UN_opslagplanken:diepte 400:...) | In | Level | Host | Area (m2) | lengte (mm) | Volume (m3)
3197062 | 00 begane grond | 00 begane grond | Level : 00 begane grond | 2.355 | 1850 | 0.0444
3197291 | 00 begane grond | 00 begane grond | Level : 00 begane grond | 2.355 | 1850 | 0.0444
3197450 | 00 begane grond | 00 begane grond | Level : 00 begane grond | 2.355 | 1850 | 0.0444
3197451 | 00 begane grond | 00 begane grond | Level : 00 begane grond | 2.355 | 1850 | 0.0444
3197523 | 01 eerste verdieping | 01 eerste verdieping | Floor : NLRS_43_FL_cementdekvloer 50_gen_ISR | 1.1076 | 860 | 0.02064
3197692 | 01 eerste verdieping | 01 eerste verdieping | Floor : NLRS_43_FL_cementdekvloer 50_gen_ISR | 1.1076 | 860 | 0.02064
3197740 | 01 eerste verdieping | 01 eerste verdieping | Floor : NLRS_43_FL_cementdekvloer 50_gen_ISR | 1.95684 | 1534 | 0.036816
3197931 | 01 eerste verdieping | 01 eerste verdieping | Floor : NLRS_43_FL_cementdekvloer 50_gen_ISR | 1.4604 | 1140 | 0.02736
3198022 | 01 eerste verdieping | 01 eerste verdieping | Level : 01 eerste verdieping | 2.355 | 1850 | 0.0444
3198089 | 01 eerste verdieping | 01 eerste verdieping | Level : 01 eerste verdieping | 2.355 | 1850 | 0.0444
3198256 | 01 eerste verdieping | 01 eerste verdieping | Level : 01 eerste verdieping | 2.355 | 1850 | 0.0444
3198257 | 01 eerste verdieping | 01 eerste verdieping | Level : 01 eerste verdieping | 2.355 | 1850 | 0.0444
3198411 | 02 tweede verdieping | 02 tweede verdieping | Level : 02 tweede verdieping | 2.355 | 1850 | 0.0444
3198464 | 02 tweede verdieping | 02 tweede verdieping | Level : 02 tweede verdieping | 2.355 | 1850 | 0.0444
3198623 | 02 tweede verdieping | 02 tweede verdieping | Floor : NLRS_43_FL_cementdekvloer 50_gen_ISR | 1.5108 | 1180 | 0.02832
3198801 | 02 tweede verdieping | 02 tweede verdieping | Floor : NLRS_43_FL_cementdekvloer 50_gen_ISR | 1.5108 | 1180 | 0.02832
3199545 | 02 tweede verdieping | 02 tweede verdieping | Floor : NLRS_43_FL_cementdekvloer 50_gen_ISR | 1.45851 | 1138.5 | 0.027324
3199675 | 02 tweede verdieping | 02 tweede verdieping | Floor : NLRS_43_FL_cementdekvloer 50_gen_ISR | 1.45851 | 1138.5 | 0.027324
3199808 | 02 tweede verdieping | 02 tweede verdieping | Level : 02 tweede verdieping | 2.355 | 1850 | 0.0444
3199809 | 02 tweede verdieping | 02 tweede verdieping | Level : 02 tweede verdieping | 2.355 | 1850 | 0.0444
3247290 | 00 begane grond | 00 begane grond | Level : 00 begane grond | 2.418 | 1900 | 0.0456

# IfcFurnishingElement: 80_FUS_UN_opslagplanken:diepte 600, 80_FUS_UN_opslagplanken:diepte 600:3197346
In: 00 begane grond
Type - Material: i4_multiplex
Type - Constraints - Default Elevation: 0 mm
Type - Materials and Finishes - materiaal: i4_multiplex
Type - Dimensions - plankdiepte: 600 mm
Type - Identity Data - Workset: Family : Furniture Systems : 80_FUS_UN_opslagplanken; Type Name: diepte 600
Type - Other - Category: Furniture Systems; Family Name: 80_FUS_UN_opslagplanken
Constraints - Elevation from Level: 0 mm; Level: 00 begane grond; Moves With Nearby Elements: no; Offset from Host: 0 mm; Host: Level : 00 begane grond
Phasing - Phase Created: 2. nieuwbouw
Dimensions - Area: 2.268 m2; lengte: 1200 mm; Volume: 0.0432 m3
Identity Data - Workset: Workset1; Comments: legplanken
Other - Family: 80_FUS_UN_opslagplanken; Family and Type: 80_FUS_UN_opslagplanken: diepte 600; Type: diepte 600; Type Id: 3197363

# IfcFurnishingElement: 80_FUS_UN_pantry300:h900 b375 hoge bovenkast (2)
In: 00 begane grond
Type - Material: <Unnamed>
Type - Constraints - Default Elevation: 0 mm
Type - Materials and Finishes - mat_spoelbalk: ISR_RVS
Type - Dimensions - breedte: 375 mm; diepte: 600 mm; diepte_bovenkast: 300 mm; dikte_aanrechtblad: 30 mm; hoogte: 900 mm; hoogte_bovenkast: 1000 mm; hoogte_plint: 120 mm
Type - Identity Data - Type Name: h900 b375 hoge bovenkast; Workset: Family : Furniture Systems : 80_FUS_UN_pantry300
Type - Other - Category: Furniture Systems; Family Name: 80_FUS_UN_pantry300
Constraints - Elevation from Level: 0 mm; Level: 00 begane grond; Moves With Nearby Elements: no; Offset from Host: 0 mm; Host: Level : 00 begane grond
Phasing - Phase Created: 2. nieuwbouw
Dimensions - Area: 2.48215 m2; Volume: 0.2994 m3
Identity Data - Workset: Workset1; Comments: pantry 1
Other - 2 lades: no; 3 lades: no; aanrechtblad: no; bovenkast: yes; kastdeur: yes; Family: 80_FUS_UN_pantry300; Family and Type: 80_FUS_UN_pantry300: h900 b375 hoge bovenkast; Type: h900 b375 hoge bovenkast; Type Id: 2867212
Name (80_FUS_UN_pantry300:h900 b375 hoge bovenkast:...) | Group
1693023 | Model Group:pantry 1 kinderopvang:1223752
1693069 | Model Group:pantry 1 kinderopvang:1511177

# IfcFurnishingElement: 80_FUS_UN_pantry:h900 b450 d750 (2)
In: 00 begane grond
Type - Material: <Unnamed>
Type - Constraints - Default Elevation: 0 mm
Type - Materials and Finishes - mat_spoelbalk: ISR_RVS
Type - Dimensions - breedte: 450 mm; diepte: 750 mm; diepte_bovenkast: 300 mm; dikte_aanrechtblad: 30 mm; hoogte: 900 mm; hoogte_bovenkast: 600 mm; hoogte_plint: 120 mm
Type - Identity Data - Workset: Family : Furniture Systems : 80_FUS_UN_pantry; Type Name: h900 b450 d750
Type - Other - Category: Furniture Systems; Family Name: 80_FUS_UN_pantry
Constraints - Elevation from Level: 0 mm; Level: 00 begane grond; Moves With Nearby Elements: no; Offset from Host: 0 mm; Host: Level : 00 begane grond
Phasing - Phase Created: 2. nieuwbouw
Dimensions - Area: 2.76407 m2; Volume: 0.283272 m3
Identity Data - Workset: Workset1
Other - 2 lades: no; 3 lades: no; Family: 80_FUS_UN_pantry; kastdeur: yes; koelkast: no; kookplaat: no; oven: no; vaatwasser: no; aanrechtblad: yes; wasbak: no; bovenkast: no; Family and Type: 80_FUS_UN_pantry: h900 b450 d750; Type: h900 b450 d750; Type Id: 1996728
Group: Model Group:70_verschoonmeubel KDV:1996810
Name (80_FUS_UN_pantry:h900 b450 d750:...)
1996682
1996757

# IfcFurnishingElement: 80_FUS_UN_pantry:h900 b600 (48)
Type - Material: <Unnamed>
Type - Constraints - Default Elevation: 0 mm
Type - Materials and Finishes - mat_spoelbalk: ISR_RVS
Type - Dimensions - breedte: 600 mm; diepte: 600 mm; diepte_bovenkast: 300 mm; dikte_aanrechtblad: 30 mm; hoogte: 900 mm; hoogte_bovenkast: 1000 mm; hoogte_plint: 120 mm
Type - Identity Data - Workset: Family : Furniture Systems : 80_FUS_UN_pantry; Type Name: h900 b600
Type - Other - Category: Furniture Systems; Family Name: 80_FUS_UN_pantry
Constraints - Elevation from Level: 0 mm; Moves With Nearby Elements: no; Offset from Host: 0 mm
Phasing - Phase Created: 2. nieuwbouw
Dimensions - Area: 3.8987 m2
Identity Data - Workset: Workset1
Other - 2 lades: no; 3 lades: no; Family: 80_FUS_UN_pantry; kookplaat: no; Family and Type: 80_FUS_UN_pantry: h900 b600; Type: h900 b600; Type Id: 1209141
Name (80_FUS_UN_pantry:h900 b600:...) | In | Level | Host | Volume (m3) | Comments | aanrechtblad | bovenkast | kastdeur | koelkast | oven | vaatwasser | wasbak | Group
1614344 | 00 begane grond | 00 begane grond | Level : 00 begane grond | 0.479307 | pantry 2 | no | yes | yes | no | no | no | yes | Model Group:pantry 1.2 MF BSO:1614348
1614346 | 00 begane grond | 00 begane grond | Level : 00 begane grond | 0.479307 | pantry 2 | yes | yes | yes | no | no | yes | no | Model Group:pantry 1.2 MF BSO:1614348
1672599 | 01 eerste verdieping | 01 eerste verdieping | Level : 01 eerste verdieping | 0.479307 | pantry 5 | no | yes | yes | no | no | no | yes | Model Group:pantry 5 personeelsruimte:1672603
1672601 | 01 eerste verdieping | 01 eerste verdieping | Level : 01 eerste verdieping | 0.479307 | pantry 5 | yes | yes | yes | no | no | yes | no | Model Group:pantry 5 personeelsruimte:1672603
1691998 | 01 eerste verdieping | 01 eerste verdieping | Level : 01 eerste verdieping | 0.479307 | pantry 5 | yes | yes | yes | yes | no | no | no | Model Group:pantry 5 personeelsruimte:1672603
2071171 | 00 begane grond | 00 begane grond | Level : 00 begane grond | 0.299307 | pantry 4 | no | no | yes | no | no | no | yes | Model Group:pantry 4 werkruimte OB:2071170
2071173 | 00 begane grond | 00 begane grond | Level : 00 begane grond | 0.299307 | pantry 4 | yes | no | yes | no | no | no | no | Model Group:pantry 4 werkruimte OB:2071170
2860053 | 01 eerste verdieping | 01 eerste verdieping | Level : 01 eerste verdieping | 0.299307 | pantry 3 | no | no | yes | no | no | no | yes | Model Group:pantry 3 BS groepsruimten:1223713
2860055 | 01 eerste verdieping | 01 eerste verdieping | Level : 01 eerste verdieping | 0.299307 | pantry 3 | yes | no | yes | yes | no | no | no | Model Group:pantry 3 BS groepsruimten:1223713
2860133 | 01 eerste verdieping | 01 eerste verdieping | Level : 01 eerste verdieping | 0.299307 | pantry 7 | yes | no | yes | no | no | no | no | Model Group:pantry 5 werkruimte MB BB:2860130
2860318 | 01 eerste verdieping | 01 eerste verdieping | Level : 01 eerste verdieping | 0.474427 | pantry 5 | yes | yes | no | no | yes | no | no | Model Group:pantry 5 personeelsruimte:1672603
2860362 | 01 eerste verdieping | 01 eerste verdieping | Level : 01 eerste verdieping | 0.299307 | pantry 6 | no | no | yes | no | no | no | yes | Model Group:pantry 6 BSO startruimte:2860361
2860364 | 01 eerste verdieping | 01 eerste verdieping | Level : 01 eerste verdieping | 0.299307 | pantry 6 | yes | no | yes | yes | no | no | no | Model Group:pantry 6 BSO startruimte:2860361
2860421 | 01 eerste verdieping | 01 eerste verdieping | Level : 01 eerste verdieping | 0.299307 | pantry 3 | no | no | yes | no | no | no | yes | Model Group:pantry 3 BS groepsruimten:2860118
2860423 | 01 eerste verdieping | 01 eerste verdieping | Level : 01 eerste verdieping | 0.299307 | pantry 3 | yes | no | yes | yes | no | no | no | Model Group:pantry 3 BS groepsruimten:2860118
2860457 | 01 eerste verdieping | 01 eerste verdieping | Level : 01 eerste verdieping | 0.299307 | pantry 3 | no | no | yes | no | no | no | yes | Model Group:pantry 3 BS groepsruimten:2860456
2860459 | 01 eerste verdieping | 01 eerste verdieping | Level : 01 eerste verdieping | 0.299307 | pantry 3 | yes | no | yes | yes | no | no | no | Model Group:pantry 3 BS groepsruimten:2860456
2860492 | 01 eerste verdieping | 01 eerste verdieping | Level : 01 eerste verdieping | 0.299307 | pantry 3 | no | no | yes | no | no | no | yes | Model Group:pantry 3 BS groepsruimten:2860491
2860494 | 01 eerste verdieping | 01 eerste verdieping | Level : 01 eerste verdieping | 0.299307 | pantry 3 | yes | no | yes | yes | no | no | no | Model Group:pantry 3 BS groepsruimten:2860491
2860702 | 02 tweede verdieping | 02 tweede verdieping | Level : 02 tweede verdieping | 0.299307 | pantry 3 | no | no | yes | no | no | no | yes | Model Group:pantry 3 BS groepsruimten:1694326
2860704 | 02 tweede verdieping | 02 tweede verdieping | Level : 02 tweede verdieping | 0.299307 | pantry 3 | yes | no | yes | yes | no | no | no | Model Group:pantry 3 BS groepsruimten:1694326
2860761 | 02 tweede verdieping | 02 tweede verdieping | Level : 02 tweede verdieping | 0.299307 | pantry 3 | no | no | yes | no | no | no | yes | Model Group:pantry 3 BS groepsruimten:2860760
2860763 | 02 tweede verdieping | 02 tweede verdieping | Level : 02 tweede verdieping | 0.299307 | pantry 3 | yes | no | yes | yes | no | no | no | Model Group:pantry 3 BS groepsruimten:2860760
2860797 | 02 tweede verdieping | 02 tweede verdieping | Level : 02 tweede verdieping | 0.299307 | pantry 3 | no | no | yes | no | no | no | yes | Model Group:pantry 3 BS groepsruimten:2860796
2860799 | 02 tweede verdieping | 02 tweede verdieping | Level : 02 tweede verdieping | 0.299307 | pantry 3 | yes | no | yes | yes | no | no | no | Model Group:pantry 3 BS groepsruimten:2860796
3267580 | 01 eerste verdieping | 01 eerste verdieping | Level : 01 eerste verdieping | 0.299307 | pantry 3 | no | no | yes | no | no | no | yes | Model Group:pantry 3 BS groepsruimten:3267579
3267582 | 01 eerste verdieping | 01 eerste verdieping | Level : 01 eerste verdieping | 0.299307 | pantry 3 | yes | no | yes | yes | no | no | no | Model Group:pantry 3 BS groepsruimten:3267579
3267595 | 01 eerste verdieping | 01 eerste verdieping | Level : 01 eerste verdieping | 0.299307 | pantry 3 | no | no | yes | no | no | no | yes | Model Group:pantry 3 BS groepsruimten:3267594
3267597 | 01 eerste verdieping | 01 eerste verdieping | Level : 01 eerste verdieping | 0.299307 | pantry 3 | yes | no | yes | yes | no | no | no | Model Group:pantry 3 BS groepsruimten:3267594
3267609 | 02 tweede verdieping | 02 tweede verdieping | Level : 02 tweede verdieping | 0.299307 | pantry 3 | no | no | yes | no | no | no | yes | Model Group:pantry 3 BS groepsruimten:3267608
3267611 | 02 tweede verdieping | 02 tweede verdieping | Level : 02 tweede verdieping | 0.299307 | pantry 3 | yes | no | yes | yes | no | no | no | Model Group:pantry 3 BS groepsruimten:3267608
3267623 | 02 tweede verdieping | 02 tweede verdieping | Level : 02 tweede verdieping | 0.299307 | pantry 3 | no | no | yes | no | no | no | yes | Model Group:pantry 3 BS groepsruimten:3267622
3267625 | 02 tweede verdieping | 02 tweede verdieping | Level : 02 tweede verdieping | 0.299307 | pantry 3 | yes | no | yes | yes | no | no | no | Model Group:pantry 3 BS groepsruimten:3267622
3267637 | 02 tweede verdieping | 02 tweede verdieping | Level : 02 tweede verdieping | 0.299307 | pantry 3 | no | no | yes | no | no | no | yes | Model Group:pantry 3 BS groepsruimten:3267636
3267639 | 02 tweede verdieping | 02 tweede verdieping | Level : 02 tweede verdieping | 0.299307 | pantry 3 | yes | no | yes | yes | no | no | no | Model Group:pantry 3 BS groepsruimten:3267636
3684887 | 00 begane grond | 00 begane grond | Level : 00 begane grond | 0.479307 | pantry 2 | yes | yes | yes | yes | no | no | no | Model Group:pantry 1.2 MF BSO:1614348
3834207 | 01 eerste verdieping | 01 eerste verdieping | Level : 01 eerste verdieping | 0.299307 | pantry 6 | yes | no | yes | no | no | no | no | Model Group:pantry 6 BSO startruimte:2860361
4747286 | 02 tweede verdieping | 02 tweede verdieping | Level : 02 tweede verdieping | 0.299307 | pantry 7 | yes | no | yes | no | no | no | no | Model Group:pantry 5 werkruimte MB BB:4747283
4782424 | 01 eerste verdieping | 01 eerste verdieping | Level : 01 eerste verdieping | 0.299307 | pantry 7 | no | no | yes | no | no | no | yes | Model Group:pantry 5 werkruimte MB BB:2860130
4782440 | 02 tweede verdieping | 02 tweede verdieping | Level : 02 tweede verdieping | 0.299307 | pantry 7 | no | no | yes | no | no | no | yes | Model Group:pantry 5 werkruimte MB BB:4747283
5027847 | 00 begane grond | 00 begane grond | Level : 00 begane grond | 0.299307 | pantry 3 | no | no | yes | no | no | no | yes | Model Group:pantry 3 BS groepsruimten:5027846
5027849 | 00 begane grond | 00 begane grond | Level : 00 begane grond | 0.299307 | pantry 3 | yes | no | yes | yes | no | no | no | Model Group:pantry 3 BS groepsruimten:5027846
5027925 | 00 begane grond | 00 begane grond | Level : 00 begane grond | 0.299307 | pantry 3 | no | no | yes | no | no | no | yes | Model Group:pantry 3 BS groepsruimten:5027924
5027927 | 00 begane grond | 00 begane grond | Level : 00 begane grond | 0.299307 | pantry 3 | yes | no | yes | yes | no | no | no | Model Group:pantry 3 BS groepsruimten:5027924
5027930 | 00 begane grond | 00 begane grond | Level : 00 begane grond | 0.299307 | pantry 3 | no | no | yes | no | no | no | yes | Model Group:pantry 3 BS groepsruimten:5027929
5027932 | 00 begane grond | 00 begane grond | Level : 00 begane grond | 0.299307 | pantry 3 | yes | no | yes | yes | no | no | no | Model Group:pantry 3 BS groepsruimten:5027929
5027953 | 00 begane grond | 00 begane grond | Level : 00 begane grond | 0.299307 | pantry 3 | no | no | yes | no | no | no | yes | Model Group:pantry 3 BS groepsruimten:5027952
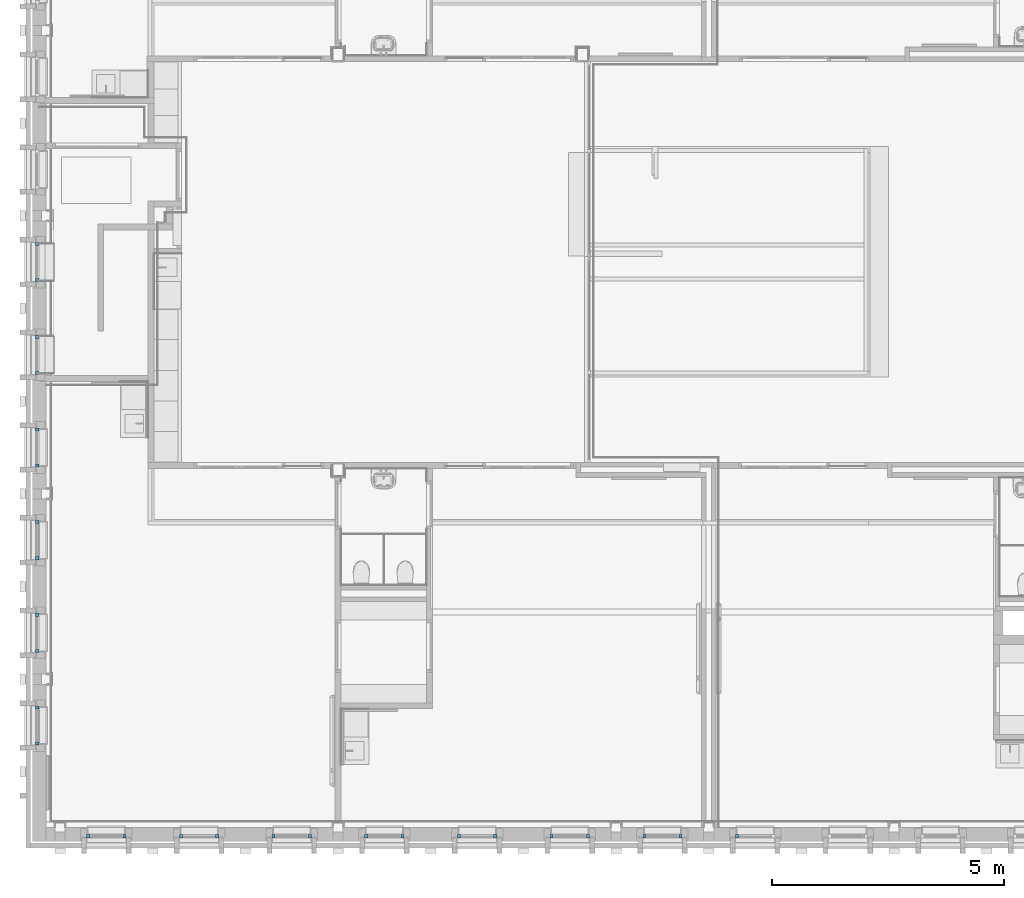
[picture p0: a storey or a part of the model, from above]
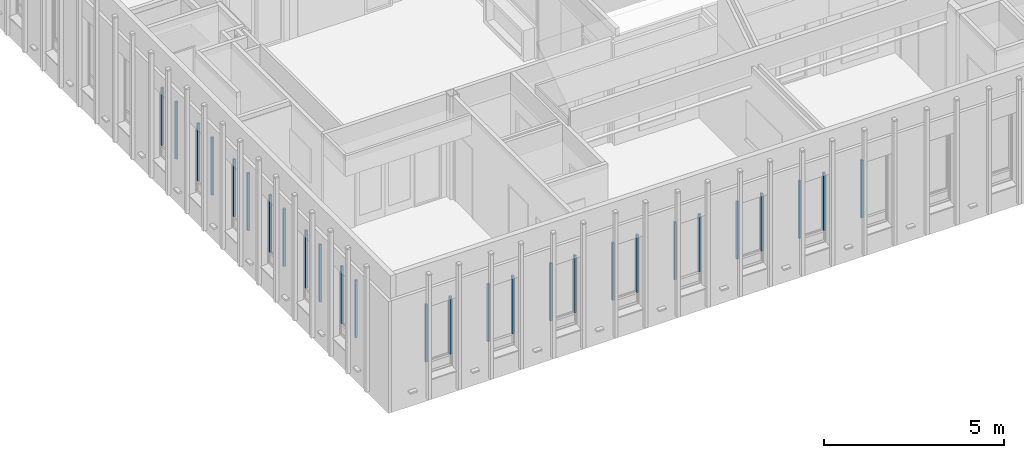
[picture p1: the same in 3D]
Properties of the parts of a building model (IFC2X3), part 11 of 94

# IfcFurnishingElement: 80_FUS_UN_pantry:h900 b600 (48)
Name (80_FUS_UN_pantry:h900 b600:...) | In | Level | Host | Volume (m3) | Comments | aanrechtblad | bovenkast | kastdeur | koelkast | oven | vaatwasser | wasbak | Group
5027955 | 00 begane grond | 00 begane grond | Level : 00 begane grond | 0.299307 | pantry 3 | yes | no | yes | yes | no | no | no | Model Group:pantry 3 BS groepsruimten:5027952

# IfcFurnishingElement: 80_FUS_UN_pantry:h900 b600 d750 (3)
In: 00 begane grond
Type - Material: <Unnamed>
Type - Constraints - Default Elevation: 0 mm
Type - Materials and Finishes - mat_spoelbalk: ISR_RVS
Type - Dimensions - breedte: 600 mm; diepte: 750 mm; diepte_bovenkast: 300 mm; dikte_aanrechtblad: 30 mm; hoogte: 900 mm; hoogte_bovenkast: 600 mm; hoogte_plint: 120 mm
Type - Identity Data - Workset: Family : Furniture Systems : 80_FUS_UN_pantry; Type Name: h900 b600 d750
Type - Other - Category: Furniture Systems; Family Name: 80_FUS_UN_pantry
Constraints - Elevation from Level: 0 mm; Level: 00 begane grond; Moves With Nearby Elements: no; Offset from Host: 0 mm; Host: Level : 00 begane grond
Phasing - Phase Created: 2. nieuwbouw
Dimensions - Area: 3.59495 m2; Volume: 0.377607 m3
Identity Data - Workset: Workset1
Other - 2 lades: no; 3 lades: no; Family: 80_FUS_UN_pantry; kastdeur: yes; koelkast: no; kookplaat: no; oven: no; vaatwasser: no; bovenkast: no; Family and Type: 80_FUS_UN_pantry: h900 b600 d750; Type: h900 b600 d750; Type Id: 1996617
Group: Model Group:70_verschoonmeubel KDV:1996810
Name (80_FUS_UN_pantry:h900 b600 d750:...) | aanrechtblad | wasbak
1996524 | no | yes
1996644 | yes | no
1996669 | yes | no

# IfcFurnishingElement: 80_FUS_UN_pantry:h900 b600 hoge bovenkast (4)
In: 00 begane grond
Type - Material: <Unnamed>
Type - Constraints - Default Elevation: 0 mm
Type - Materials and Finishes - mat_spoelbalk: ISR_RVS
Type - Dimensions - breedte: 600 mm; diepte: 600 mm; diepte_bovenkast: 300 mm; dikte_aanrechtblad: 30 mm; hoogte: 900 mm; hoogte_bovenkast: 1000 mm; hoogte_plint: 120 mm
Type - Identity Data - Type Name: h900 b600 hoge bovenkast; Workset: Family : Furniture Systems : 80_FUS_UN_pantry
Type - Other - Category: Furniture Systems; Family Name: 80_FUS_UN_pantry
Constraints - Elevation from Level: 0 mm; Level: 00 begane grond; Moves With Nearby Elements: no; Offset from Host: 0 mm; Host: Level : 00 begane grond
Phasing - Phase Created: 2. nieuwbouw
Dimensions - Area: 3.8987 m2; Volume: 0.479307 m3
Identity Data - Workset: Workset1; Comments: pantry 1
Other - 2 lades: no; 3 lades: no; bovenkast: yes; Family: 80_FUS_UN_pantry; Family and Type: 80_FUS_UN_pantry: h900 b600 hoge bovenkast; kastdeur: yes; koelkast: no; kookplaat: no; oven: no; Type: h900 b600 hoge bovenkast; Type Id: 2867156; vaatwasser: no
Name (80_FUS_UN_pantry:h900 b600 hoge bovenkast:...) | aanrechtblad | wasbak | Group
1510249 | no | yes | Model Group:pantry 1 kinderopvang:1223752
1510251 | yes | no | Model Group:pantry 1 kinderopvang:1223752
1511178 | no | yes | Model Group:pantry 1 kinderopvang:1511177
1511180 | yes | no | Model Group:pantry 1 kinderopvang:1511177

# IfcFurnishingElement: 80_FUS_UN_pantry:koelkast hoog (2)
In: 00 begane grond
Type - Material: <Unnamed>
Type - Constraints - Default Elevation: 0 mm
Type - Materials and Finishes - mat_spoelbalk: ISR_RVS
Type - Dimensions - breedte: 600 mm; diepte: 600 mm; diepte_bovenkast: 300 mm; dikte_aanrechtblad: 0 mm; hoogte: 1500 mm; hoogte_bovenkast: 600 mm; hoogte_plint: 120 mm
Type - Identity Data - Workset: Family : Furniture Systems : 80_FUS_UN_pantry; Type Name: koelkast hoog
Type - Other - Category: Furniture Systems; Family Name: 80_FUS_UN_pantry
Constraints - Elevation from Level: 0 mm; Level: 00 begane grond; Moves With Nearby Elements: no; Offset from Host: 0 mm; Host: Level : 00 begane grond
Phasing - Phase Created: 2. nieuwbouw
Dimensions - Area: 4.5083 m2; Volume: 0.518547 m3
Identity Data - Workset: Workset1; Comments: pantry 1.1
Other - 2 lades: no; 3 lades: no; Family: 80_FUS_UN_pantry; kastdeur: yes; kookplaat: no; oven: no; vaatwasser: no; aanrechtblad: yes; wasbak: no; bovenkast: no; Family and Type: 80_FUS_UN_pantry: koelkast hoog; koelkast: yes; Type: koelkast hoog; Type Id: 1952790
Name (80_FUS_UN_pantry:koelkast hoog:...) | Group
1510253 | Model Group:pantry 1 kinderopvang:1223752
1511182 | Model Group:pantry 1 kinderopvang:1511177

# IfcFurnishingElement: Commode:Commode, Commode:Commode:3830572
In: 00 begane grond
Type - Material: <Unnamed>
Type - Identity Data - Workset: Workset1; Type Name: Commode
Type - Other - Category: Furniture Systems; Family Name: Commode
Constraints - Moves With Nearby Elements: no
Phasing - Phase Created: 2. nieuwbouw
Dimensions - Area: 0.4788 m2; Volume: 0.02394 m3
Identity Data - Comments: commode
Other - Family: Commode; Family and Type: Commode: Commode; Type: Commode; Type Id: 3830570

# IfcFurnishingElement: NLRS_82_FU_UN_bed enkel_gen_ISR:kinderbed (12)
In: 00 begane grond
Type - Material: n6_kunststof_wit
Type - Constraints - Default Elevation: 0 mm
Type - Dimensions - bak_hoogte: 700 mm; bodem_dikte: 50 mm; kop_dikte: 50 mm; matras_afronding: 25 mm; matras_breedte: 700 mm; matras_dikte: 120 mm; matras_lengte: 1200 mm; poot_breedte: 42 mm; poot_diepte: 42 mm; poot_hoogte: 50 mm; zijkant_dikte: 25 mm
Type - Identity Data - Assembly Code: 82.10; Assembly Description: losse gebruikersinventaris; standaard, algemeen (verzamelniveau); Datum_Gewijzigd: 12-11-2020; Description: enkel kinderbed; Model: LOD300; SmartRevit_Versie: 2021.1; Type Name: kinderbed; Workset: Family : Furniture : NLRS_82_FU_UN_bed enkel_gen_ISR
Type - Other - Category: Furniture; Family Name: NLRS_82_FU_UN_bed enkel_gen_ISR
Classification: 82.10 Uniformat (Uniformat)
Constraints - Elevation from Level: 0 mm; Level: 00 begane grond; Moves With Nearby Elements: no; Offset from Host: 0 mm
Phasing - Phase Created: 2. nieuwbouw
Dimensions - Area: 3.98329 m2; NLRS_C_breedte: 750 mm; NLRS_C_hoogte: 220 mm; NLRS_C_lengte: 1300 mm; Volume: 0.195616 m3
Identity Data - Workset: Workset1
Other - Family: NLRS_82_FU_UN_bed enkel_gen_ISR; Family and Type: NLRS_82_FU_UN_bed enkel_gen_ISR: kinderbed; Type: kinderbed; Type Id: 1658805
Name (NLRS_82_FU_UN_bed enkel_gen_ISR:kinderbed:...) | Host
1658766 | Level : 00 begane grond
1659884 | Floor : NLRS_43_FL_cementdekvloer 60_gen_ISR
1659973 | Floor : NLRS_43_FL_cementdekvloer 60_gen_ISR
1660486 | Level : 00 begane grond
1660656 | Level : 00 begane grond
1660690 | Level : 00 begane grond
1661425 | Level : 00 begane grond
1661426 | Level : 00 begane grond
1661427 | Level : 00 begane grond
1661473 | Level : 00 begane grond
1661474 | Floor : NLRS_43_FL_cementdekvloer 60_gen_ISR
1661475 | Floor : NLRS_43_FL_cementdekvloer 60_gen_ISR

# IfcFurnishingElement: Postkast:Postkast, Postkast:Postkast:3702581
In: 00 begane grond
Type - Material: Panel
Type - Identity Data - Workset: Workset1; Type Mark: postkast; Type Name: Postkast
Type - Other - Category: Furniture Systems; Family Name: Postkast
Constraints - Moves With Nearby Elements: no
Phasing - Phase Created: 2. nieuwbouw
Dimensions - Area: 0.064264 m2; Volume: 0.0273074 m3
Other - Family: Postkast; Family and Type: Postkast: Postkast; Type: Postkast; Type Id: 3702579

# IfcGroup: Model Group:21_hsb_v0_A (2)
Constraints - Origin Level Offset: 0 mm; Reference Level: 00 begane grond
Identity Data - Workset: Workset1
Other - Category: Model Groups; Family: Model Group; Family and Type: Model Group: 21_hsb_v0_A; Type: 21_hsb_v0_A; Type Id: 897748
Identity Data(Type) - Workset: Workset1; Type Name: 21_hsb_v0_A
Other(Type) - Category: Model Groups; Family Name: Model Group
Name (Model Group:21_hsb_v0_A:...)
897872
1222349

# IfcGroup: Model Group:21_penant v1 (50)
Constraints - Origin Level Offset: 0 mm; Reference Level: 01 eerste verdieping
Identity Data - Workset: Workset1
Other - Category: Model Groups; Family: Model Group; Family and Type: Model Group: 21_penant v1; Type: 21_penant v1; Type Id: 863203
Identity Data(Type) - Workset: Workset1; Type Name: 21_penant v1
Other(Type) - Category: Model Groups; Family Name: Model Group
Name (Model Group:21_penant v1:...)
774399
774467
774488
774500
874890
874894
874898
874980
874984
874988
875217
875253
875289
875325
875361
876469
876484
876499
876887
876902
876917
877004
877019
877034
877094
877109
877124
877184
877199
877214
880918
881607
881643
881679
881755
881782
881809
891629
891651
891673
891695
891717
891763
891785
891807
891902
891924
891946
891974
891996

# IfcGroup: Model Group:21_penant v1 ROND (2)
Constraints - Origin Level Offset: 0 mm; Reference Level: 01 eerste verdieping
Identity Data - Workset: Workset1
Other - Category: Model Groups; Family: Model Group; Family and Type: Model Group: 21_penant v1 ROND; Type: 21_penant v1 ROND; Type Id: 3186733
Identity Data(Type) - Workset: Workset1; Type Name: 21_penant v1 ROND
Other(Type) - Category: Model Groups; Family Name: Model Group
Name (Model Group:21_penant v1 ROND:...)
1302570
1341016

# IfcGroup: Model Group:21_penant v2 (43)
Constraints - Origin Level Offset: 0 mm; Reference Level: 02 tweede verdieping
Identity Data - Workset: Workset1
Other - Category: Model Groups; Family: Model Group; Family and Type: Model Group: 21_penant v2; Type: 21_penant v2; Type Id: 863827
Identity Data(Type) - Workset: Workset1; Type Name: 21_penant v2
Other(Type) - Category: Model Groups; Family Name: Model Group
Name (Model Group:21_penant v2:...)
863826
864468
864499
870619
870636
870660
870701
870718
870742
870814
870831
870855
870922
871619
871652
871685
871871
871903
871935
871967
872009
872275
872809
872842
872875
872908
872941
872974
873007
873040
873073
873106
873392
873442
873473
873504
873535
873566
873597
873628
873659
873690
873721

# IfcGroup: Model Group:21_penant v2 deur (2)
Constraints - Origin Level Offset: 0 mm; Reference Level: 02 tweede verdieping
Identity Data - Workset: Workset1
Other - Category: Model Groups; Family: Model Group; Family and Type: Model Group: 21_penant v2 deur; Type: 21_penant v2 deur; Type Id: 1483013
Identity Data(Type) - Workset: Workset1; Type Name: 21_penant v2 deur
Other(Type) - Category: Model Groups; Family Name: Model Group
Name (Model Group:21_penant v2 deur:...)
871839
1483196

# IfcGroup: Model Group:21_penant_v0 (26)
Identity Data - Workset: Workset1
Other - Category: Model Groups; Family: Model Group; Family and Type: Model Group: 21_penant_v0; Type: 21_penant_v0; Type Id: 892304
Identity Data(Type) - Workset: Workset1; Type Name: 21_penant_v0
Other(Type) - Category: Model Groups; Family Name: Model Group
Name (Model Group:21_penant_v0:...) | Origin Level Offset (mm) | Reference Level
892303 | -20 | 00 begane grond
892310 | -20 | 00 begane grond
892358 | -20 | 00 begane grond
892370 | -20 | 00 begane grond
892382 | -20 | 00 begane grond
892408 | -20 | 00 begane grond
892433 | -20 | 00 begane grond
892447 | -20 | 00 begane grond
892464 | -20 | 00 begane grond
892518 | -20 | 00 begane grond
892530 | -20 | 00 begane grond
1223874 | -20 | 00 begane grond
1224081 | -20 | 00 begane grond
1224137 | -20 | 00 begane grond
1289941 | -20 | 00 begane grond
1308627 | 500 | bk. fundering
1310182 | -20 | 00 begane grond
1311150 | 500 | bk. fundering
1343011 | 500 | bk. fundering
1343144 | 500 | bk. fundering
1348665 | -20 | 00 begane grond
1348881 | 500 | bk. fundering
1500685 | 500 | bk. fundering
1500694 | 500 | bk. fundering
1500896 | 500 | bk. fundering
1500921 | 500 | bk. fundering

# IfcGroup: Model Group:21_penant_v1 gym (35)
Constraints - Reference Level: 01 eerste verdieping; Origin Level Offset: 500 mm
Identity Data - Workset: Workset1
Other - Category: Model Groups; Family: Model Group; Family and Type: Model Group: 21_penant_v1 gym; Type: 21_penant_v1 gym; Type Id: 1884013
Identity Data(Type) - Workset: Workset1; Type Name: 21_penant_v1 gym
Other(Type) - Category: Model Groups; Family Name: Model Group
Name (Model Group:21_penant_v1 gym:...)
1911143
1911150
1911157
1911164
1911171
1911178
1911185
1912551 | Group: Model Group:MW_gevelvlak_V1 a (members excluded):1885437
1912590 | Group: Model Group:MW_gevelvlak_V1 a (members excluded):1885437
1912705 | Group: Model Group:MW_gevelvlak_V1 a (members excluded):1885483
1912709 | Group: Model Group:MW_gevelvlak_V1 a (members excluded):1885483
1912715 | Group: Model Group:MW_gevelvlak_V1 a (members excluded):1885510
1912719 | Group: Model Group:MW_gevelvlak_V1 a (members excluded):1885510
1912725 | Group: Model Group:MW_gevelvlak_V1 a (members excluded):1885560
1912729 | Group: Model Group:MW_gevelvlak_V1 a (members excluded):1885560
1912735 | Group: Model Group:MW_gevelvlak_V1 a:1885576
1912739 | Group: Model Group:MW_gevelvlak_V1 a:1885576
1912745
1912755 | Group: Model Group:MW_gevelvlak_V1 a:1886481
1912759 | Group: Model Group:MW_gevelvlak_V1 a:1886481
1912765 | Group: Model Group:MW_gevelvlak_V1 a:1886487
1912769 | Group: Model Group:MW_gevelvlak_V1 a:1886487
1912775 | Group: Model Group:MW_gevelvlak_V1 a:1886493
1912779 | Group: Model Group:MW_gevelvlak_V1 a:1886493
1912818
1912830
1913071
1913224
1913265
1913279
1913889
1913893
1913917
1913931
1913943

# IfcGroup: Model Group:21_penant_v1 gym laag, Model Group:21_penant_v1 gym laag:1913291
Constraints - Reference Level: 01 eerste verdieping; Origin Level Offset: 500 mm
Identity Data - Workset: Workset1
Other - Category: Model Groups; Family: Model Group; Family and Type: Model Group: 21_penant_v1 gym laag; Type: 21_penant_v1 gym laag; Type Id: 2162936
Identity Data(Type) - Workset: Workset1; Type Name: 21_penant_v1 gym laag
Other(Type) - Category: Model Groups; Family Name: Model Group

# IfcGroup: Model Group:21_rond (2)
Constraints - Origin Level Offset: 0 mm; Reference Level: 01 eerste verdieping
Identity Data - Workset: Workset1
Other - Category: Model Groups; Family: Model Group; Family and Type: Model Group: 21_rond; Type: 21_rond; Type Id: 1344285
Identity Data(Type) - Workset: Workset1; Type Name: 21_rond
Other(Type) - Category: Model Groups; Family Name: Model Group
Name (Model Group:21_rond:...)
1344284
1344849

# IfcGroup: Model Group:31_1A (17)
Constraints - Origin Level Offset: 0 mm; Reference Level: 01 eerste verdieping
Identity Data - Workset: Workset1
Other - Category: Model Groups; Family: Model Group; Family and Type: Model Group: 31_1A; Type: 31_1A; Type Id: 858854
Identity Data(Type) - Workset: Workset1; Type Name: 31_1A
Other(Type) - Category: Model Groups; Family Name: Model Group
Name (Model Group:31_1A:...) | Group
874672 | Model Group:BU-26:874674
874956 | Model Group:BU-26:874958
875046 | Model Group:BU-26:875048
875274 | Model Group:BU-26:875276
875382 | Model Group:BU-26:875384
876493 | Model Group:BU-26:876495
876911 | Model Group:BU-26:876913
877028 | Model Group:BU-26:877030
877118 | Model Group:BU-26:877120
877208 | Model Group:BU-26 (members excluded):877210
880927 | Model Group:BU-26:880929
881688 | Model Group:BU-26:881690
891680 | Model Group:BU-26:891682
891792 | Model Group:BU-26:891794
891909 | Model Group:BU-26:891911
891931 | Model Group:BU-26:891933
891981 | Model Group:BU-26:891983

# IfcGroup: Model Group:31_1A DK L (5)
Constraints - Origin Level Offset: 0 mm; Reference Level: 01 eerste verdieping
Identity Data - Workset: Workset1
Other - Category: Model Groups; Family: Model Group; Family and Type: Model Group: 31_1A DK L; Type: 31_1A DK L; Type Id: 1865404
Identity Data(Type) - Workset: Workset1; Type Name: 31_1A DK L
Other(Type) - Category: Model Groups; Family Name: Model Group
Name (Model Group:31_1A DK L:...) | Group
1865367 | Model Group:BI-29B (members excluded):877105
1865655 | Model Group:BI-29B:876898
1865674 | Model Group:BI-29B:877015
1865802 | Model Group:BI-29B:881766
2266691 | Model Group:BI-29B:876480

# IfcGroup: Model Group:31_1A DK R (4)
Constraints - Origin Level Offset: 0 mm; Reference Level: 01 eerste verdieping
Identity Data - Workset: Workset1
Other - Category: Model Groups; Family: Model Group; Family and Type: Model Group: 31_1A DK R; Type: 31_1A DK R; Type Id: 1864654
Identity Data(Type) - Workset: Workset1; Type Name: 31_1A DK R
Other(Type) - Category: Model Groups; Family Name: Model Group
Name (Model Group:31_1A DK R:...) | Group
875055 | Model Group:BU-28B:875057
1864938 | Model Group:BU-28B:874967
1865007 | Model Group:BU-28B:874689
1865923 | Model Group:BU-28B:891704

# IfcGroup: Model Group:31_1A DKD L (6)
Constraints - Origin Level Offset: 0 mm; Reference Level: 01 eerste verdieping
Identity Data - Workset: Workset1
Other - Category: Model Groups; Family: Model Group; Family and Type: Model Group: 31_1A DKD L; Type: 31_1A DKD L; Type Id: 1864334
Identity Data(Type) - Workset: Workset1; Type Name: 31_1A DKD L
Other(Type) - Category: Model Groups; Family Name: Model Group
Name (Model Group:31_1A DKD L:...) | Group
875031 | Model Group:BU-29A:875039
1864982 | Model Group:BU-29A:874609
1865030 | Model Group:BU-29A:875240
1865946 | Model Group:BU-29A:891726
2012531 | Model Group:BU-29A:875348
2012561 | Model Group:BU-29A:891660

# IfcGroup: Model Group:31_1A DKD R (7)
Constraints - Origin Level Offset: 0 mm; Reference Level: 01 eerste verdieping
Identity Data - Workset: Workset1
Other - Category: Model Groups; Family: Model Group; Family and Type: Model Group: 31_1A DKD R; Type: 31_1A DKD R; Type Id: 1865074
Identity Data(Type) - Workset: Workset1; Type Name: 31_1A DKD R
Other(Type) - Category: Model Groups; Family Name: Model Group
Name (Model Group:31_1A DKD R:...) | Group
875310 | Model Group:BU-28A:875312
1865346 | Model Group:BU-28A (members excluded):877225
1865574 | Model Group:BU-28A:876928
1865608 | Model Group:BU-28A:877135
1865781 | Model Group:BU-28A:881793
1898045 | Model Group:BU-28A:877045
3058236 | Model Group:BU-28A:3058229

# IfcGroup: Model Group:31_1A DKg R, Model Group:31_1A DKg R:1866082
Constraints - Origin Level Offset: 0 mm; Reference Level: 01 eerste verdieping
Identity Data - Workset: Workset1
Other - Category: Model Groups; Family: Model Group; Family and Type: Model Group: 31_1A DKg R; Type: 31_1A DKg R; Type Id: 1866120
Identity Data(Type) - Workset: Workset1; Type Name: 31_1A DKg R
Other(Type) - Category: Model Groups; Family Name: Model Group
Group: Model Group:BU-29C:891772

# IfcGroup: Model Group:31_1A SVGD L (2)
Constraints - Origin Level Offset: 0 mm; Reference Level: 01 eerste verdieping
Identity Data - Workset: Workset1
Other - Category: Model Groups; Family: Model Group; Family and Type: Model Group: 31_1A SVGD L; Type: 31_1A SVGD L; Type Id: 2172416
Identity Data(Type) - Workset: Workset1; Type Name: 31_1A SVGD L
Other(Type) - Category: Model Groups; Family Name: Model Group
Name (Model Group:31_1A SVGD L:...) | Group
1864620 | Model Group:BU-29:874949
2776736 | Model Group:BU-29:2698865

# IfcGroup: Model Group:31_1A SVGD R, Model Group:31_1A SVGD R:2172436
Constraints - Origin Level Offset: 0 mm; Reference Level: 01 eerste verdieping
Identity Data - Workset: Workset1
Other - Category: Model Groups; Family: Model Group; Family and Type: Model Group: 31_1A SVGD R; Type: 31_1A SVGD R; Type Id: 2172385
Identity Data(Type) - Workset: Workset1; Type Name: 31_1A SVGD R
Other(Type) - Category: Model Groups; Family Name: Model Group
Group: Model Group:BU-27:891638

# IfcGroup: Model Group:31_2A (17)
Constraints - Origin Level Offset: 0 mm; Reference Level: 02 tweede verdieping
Identity Data - Workset: Workset1
Other - Category: Model Groups; Family: Model Group; Family and Type: Model Group: 31_2A; Type: 31_2A; Type Id: 861342
Identity Data(Type) - Workset: Workset1; Type Name: 31_2A
Other(Type) - Category: Model Groups; Family Name: Model Group
Name (Model Group:31_2A:...) | Group
870547 | Model Group:BU-39:870548
870753 | Model Group:BU-39:870754
870866 | Model Group:BU-39:870867
871641 | Model Group:BU-39:871642
871674 | Model Group:BU-39:871675
871925 | Model Group:BU-39:871926
871957 | Model Group:BU-39:871958
872819 | Model Group:BU-39:872820
872885 | Model Group:BU-39:872886
872918 | Model Group:BU-39:872919
872951 | Model Group:BU-39:872952
872984 | Model Group:BU-39:872985
873017 | Model Group:BU-39:873018
873083 | Model Group:BU-39:873084
873514 | Model Group:BU-39:873515
873607 | Model Group:BU-39:873608
873700 | Model Group:BU-39:873701

# IfcGroup: Model Group:31_2A DK L (11)
Constraints - Origin Level Offset: 0 mm; Reference Level: 02 tweede verdieping
Identity Data - Workset: Workset1
Other - Category: Model Groups; Family: Model Group; Family and Type: Model Group: 31_2A DK L; Type: 31_2A DK L; Type Id: 1869502
Identity Data(Type) - Workset: Workset1; Type Name: 31_2A DK L
Other(Type) - Category: Model Groups; Family Name: Model Group
Name (Model Group:31_2A DK L:...) | Group
1869467 | Model Group:BU-39B (members excluded):872020
1869606 | Model Group:BU-39B:873453
1869623 | Model Group:BU-39B:873484
1869640 | Model Group:BU-39B:873546
1869657 | Model Group:BU-39B:873577
1869674 | Model Group:BU-39B:873639
1869691 | Model Group:BU-39B:873670
1869708 | Model Group:BU-39B:873732
1869727 | Model Group:BU-39B:871535
1869744 | Model Group:BU-39B:871708
2266708 | Model Group:BU-39B:873403

# IfcGroup: Model Group:31_2A DK R (15)
Constraints - Origin Level Offset: 0 mm; Reference Level: 02 tweede verdieping
Identity Data - Workset: Workset1
Other - Category: Model Groups; Family: Model Group; Family and Type: Model Group: 31_2A DK R; Type: 31_2A DK R; Type Id: 1869198
Identity Data(Type) - Workset: Workset1; Type Name: 31_2A DK R
Other(Type) - Category: Model Groups; Family Name: Model Group
Name (Model Group:31_2A DK R:...) | Group
1867677 | Model Group:BU-39A:1867105
1869345 | Model Group:BU-39A:865431
1869362 | Model Group:BU-39A:870563
1869379 | Model Group:BU-39A:870664
1869396 | Model Group:BU-39A:870680
1869413 | Model Group:BU-39A:870746
1869430 | Model Group:BU-39A:870762
1869447 | Model Group:BU-39A:870875
1869761 | Model Group:BU-39A:871894
1869778 | Model Group:BU-39A:871990
1869797 | Model Group:BU-39A:872286
1869814 | Model Group:BU-39A:872853
1869831 | Model Group:BU-39A:873051
1869848 | Model Group:BU-39A:873117
2266723 | Model Group:BU-39A:870672

# IfcGroup: Model Group:31_daklicht_B (2)
Constraints - Origin Level Offset: 0 mm; Reference Level: 03 derde verdieping
Identity Data - Workset: Workset1
Other - Category: Model Groups; Family: Model Group; Family and Type: Model Group: 31_daklicht_B; Type: 31_daklicht_B; Type Id: 2194620
Identity Data(Type) - Workset: Workset1; Type Name: 31_daklicht_B
Other(Type) - Category: Model Groups; Family Name: Model Group
Name (Model Group:...) | Group
31_daklicht_B (members excluded):2194619 | Model Group:BU-42 daklicht B lokaal:2182308
31_daklicht_B:2194786 | Model Group:BU-42 daklicht B lokaal:2194782

# IfcGroup: Model Group:31_daklicht_C (2)
Constraints - Origin Level Offset: 0 mm; Reference Level: 03 derde verdieping
Identity Data - Workset: Workset1
Other - Category: Model Groups; Family: Model Group; Family and Type: Model Group: 31_daklicht_C; Type: 31_daklicht_C; Type Id: 2195000
Identity Data(Type) - Workset: Workset1; Type Name: 31_daklicht_C
Other(Type) - Category: Model Groups; Family Name: Model Group
Name (Model Group:31_daklicht_C:...) | Group
2194635 | Model Group:BU-42 daklicht B lokaal:2182308
2194793 | Model Group:BU-42 daklicht B lokaal:2194782

# IfcGroup: Model Group:6 fietsen (5)
Constraints - Reference Level: 00 begane grond; Origin Level Offset: -20 mm
Identity Data - Workset: BDG_fietsenstalling
Other - Category: Model Groups; Family: Model Group; Family and Type: Model Group: 6 fietsen; Type: 6 fietsen; Type Id: 4064989
Identity Data(Type) - Workset: BDG_fietsenstalling; Type Name: 6 fietsen
Other(Type) - Category: Model Groups; Family Name: Model Group
Group: Model Group:fietsenstalling:4188142
Name (Model Group:6 fietsen:...)
4064988
4065027
4065219
4065235
4154654

# IfcGroup: Model Group:70_verschoonmeubel KDV, Model Group:70_verschoonmeubel KDV:1996810
Constraints - Origin Level Offset: 0 mm; Reference Level: 00 begane grond
Identity Data - Workset: Workset1
Other - Category: Model Groups; Family: Model Group; Family and Type: Model Group: 70_verschoonmeubel KDV; Type: 70_verschoonmeubel KDV; Type Id: 1996811
Identity Data(Type) - Workset: Workset1; Type Name: 70_verschoonmeubel KDV
Other(Type) - Category: Model Groups; Family Name: Model Group

# IfcGroup: Model Group:BI-02 2198x2387, Model Group:BI-02 2198x2387 (members excluded):3844191
Constraints - Origin Level Offset: 0 mm; Reference Level: 00 begane grond
Identity Data - Workset: Workset1
Other - Category: Model Groups; Family: Model Group; Family and Type: Model Group: BI-02 2198x2387; Type: BI-02 2198x2387; Type Id: 3844192
Identity Data(Type) - Workset: Workset1; Type Name: BI-02 2198x2387
Other(Type) - Category: Model Groups; Family Name: Model Group

# IfcGroup: Model Group:BI-04av 2400x2387, Model Group:BI-04av 2400x2387:1367879
Constraints - Origin Level Offset: 0 mm; Reference Level: 00 begane grond
Identity Data - Workset: Workset1
Other - Category: Model Groups; Family: Model Group; Family and Type: Model Group: BI-04av 2400x2387; Type: BI-04av 2400x2387; Type Id: 1367880
Identity Data(Type) - Workset: Workset1; Type Name: BI-04av 2400x2387
Other(Type) - Category: Model Groups; Family Name: Model Group

# IfcGroup: Model Group:BI-04bw 2400x2387, Model Group:BI-04bw 2400x2387:1367983
Constraints - Origin Level Offset: 0 mm; Reference Level: 00 begane grond
Identity Data - Workset: Workset1
Other - Category: Model Groups; Family: Model Group; Family and Type: Model Group: BI-04bw 2400x2387; Type: BI-04bw 2400x2387; Type Id: 2530265
Identity Data(Type) - Workset: Workset1; Type Name: BI-04bw 2400x2387
Other(Type) - Category: Model Groups; Family Name: Model Group

# IfcGroup: Model Group:BI-04w 2400x2387, Model Group:BI-04w 2400x2387:1420140
Constraints - Origin Level Offset: 0 mm; Reference Level: 01 eerste verdieping
Identity Data - Workset: Workset1
Other - Category: Model Groups; Family: Model Group; Family and Type: Model Group: BI-04w 2400x2387; Type: BI-04w 2400x2387; Type Id: 2636025
Identity Data(Type) - Workset: Workset1; Type Name: BI-04w 2400x2387
Other(Type) - Category: Model Groups; Family Name: Model Group

# IfcGroup: Model Group:BI-10 4215x2800, Model Group:BI-10 4215x2800:2522162
Constraints - Origin Level Offset: 0 mm; Reference Level: 00 begane grond
Identity Data - Workset: Workset1
Other - Category: Model Groups; Family: Model Group; Family and Type: Model Group: BI-10 4215x2800; Type: BI-10 4215x2800; Type Id: 2522163
Identity Data(Type) - Workset: Workset1; Type Name: BI-10 4215x2800
Other(Type) - Category: Model Groups; Family Name: Model Group

# IfcGroup: Model Group:BI-11 8834x2800, Model Group:BI-11 8834x2800:2521973
Constraints - Origin Level Offset: 0 mm; Reference Level: 00 begane grond
Identity Data - Workset: Workset1
Other - Category: Model Groups; Family: Model Group; Family and Type: Model Group: BI-11 8834x2800; Type: BI-11 8834x2800; Type Id: 2521974
Identity Data(Type) - Workset: Workset1; Type Name: BI-11 8834x2800
Other(Type) - Category: Model Groups; Family Name: Model Group

# IfcGroup: Model Group:BI-13bw 7515x2800, Model Group:BI-13bw 7515x2800:2527306
Constraints - Origin Level Offset: 0 mm; Reference Level: 00 begane grond
Identity Data - Workset: Workset1
Other - Category: Model Groups; Family: Model Group; Family and Type: Model Group: BI-13bw 7515x2800; Type: BI-13bw 7515x2800; Type Id: 2527307
Identity Data(Type) - Workset: Workset1; Type Name: BI-13bw 7515x2800
Other(Type) - Category: Model Groups; Family Name: Model Group

# IfcGroup: Model Group:BI-16y 1334x2387, Model Group:BI-16y 1334x2387:2530506
Constraints - Origin Level Offset: 0 mm; Reference Level: 00 begane grond
Identity Data - Workset: Workset1
Other - Category: Model Groups; Family: Model Group; Family and Type: Model Group: BI-16y 1334x2387; Type: BI-16y 1334x2387; Type Id: 2530507
Identity Data(Type) - Workset: Workset1; Type Name: BI-16y 1334x2387
Other(Type) - Category: Model Groups; Family Name: Model Group

# IfcGroup: Model Group:BI-20 2865x1750, Model Group:BI-20 2865x1750:2532482
Constraints - Origin Level Offset: 0 mm; Reference Level: 01 eerste verdieping
Identity Data - Workset: Workset1
Other - Category: Model Groups; Family: Model Group; Family and Type: Model Group: BI-20 2865x1750; Type: BI-20 2865x1750; Type Id: 2532483
Identity Data(Type) - Workset: Workset1; Type Name: BI-20 2865x1750
Other(Type) - Category: Model Groups; Family Name: Model Group

# IfcGroup: Model Group:BI-21w 2630x1750, Model Group:BI-21w 2630x1750:2532641
Constraints - Origin Level Offset: 0 mm; Reference Level: 01 eerste verdieping
Identity Data - Workset: Workset1
Other - Category: Model Groups; Family: Model Group; Family and Type: Model Group: BI-21w 2630x1750; Type: BI-21w 2630x1750; Type Id: 2532642
Identity Data(Type) - Workset: Workset1; Type Name: BI-21w 2630x1750
Other(Type) - Category: Model Groups; Family Name: Model Group

# IfcGroup: Model Group:BI-22 1965x2550, Model Group:BI-22 1965x2550:2532537
Constraints - Origin Level Offset: 0 mm; Reference Level: 01 eerste verdieping
Identity Data - Workset: Workset1
Other - Category: Model Groups; Family: Model Group; Family and Type: Model Group: BI-22 1965x2550; Type: BI-22 1965x2550; Type Id: 2532538
Identity Data(Type) - Workset: Workset1; Type Name: BI-22 1965x2550
Other(Type) - Category: Model Groups; Family Name: Model Group

# IfcGroup: Model Group:BI-23w 4635x2800, Model Group:BI-23w 4635x2800:2532690
Constraints - Origin Level Offset: 0 mm; Reference Level: 01 eerste verdieping
Identity Data - Workset: Workset1
Other - Category: Model Groups; Family: Model Group; Family and Type: Model Group: BI-23w 4635x2800; Type: BI-23w 4635x2800; Type Id: 2532691
Identity Data(Type) - Workset: Workset1; Type Name: BI-23w 4635x2800
Other(Type) - Category: Model Groups; Family Name: Model Group

# IfcGroup: Model Group:BI-25bw 1825x2387, Model Group:BI-25bw 1825x2387:1420374
Constraints - Origin Level Offset: 0 mm; Reference Level: 01 eerste verdieping
Identity Data - Workset: Workset1
Other - Category: Model Groups; Family: Model Group; Family and Type: Model Group: BI-25bw 1825x2387; Type: BI-25bw 1825x2387; Type Id: 2534505
Identity Data(Type) - Workset: Workset1; Type Name: BI-25bw 1825x2387
Other(Type) - Category: Model Groups; Family Name: Model Group

# IfcGroup: Model Group:BI-26bw, Model Group:BI-26bw:2535201
Constraints - Origin Level Offset: 0 mm; Reference Level: 01 eerste verdieping
Identity Data - Workset: Workset1
Other - Category: Model Groups; Family: Model Group; Family and Type: Model Group: BI-26bw; Type: BI-26bw; Type Id: 2535202
Identity Data(Type) - Workset: Workset1; Type Name: BI-26bw
Other(Type) - Category: Model Groups; Family Name: Model Group

# IfcGroup: Model Group:BI-27 2500x1700 (2)
Constraints - Origin Level Offset: 0 mm; Reference Level: 02 tweede verdieping
Identity Data - Workset: Workset1
Other - Category: Model Groups; Family: Model Group; Family and Type: Model Group: BI-27 2500x1700; Type: BI-27 2500x1700; Type Id: 2534619
Identity Data(Type) - Workset: Workset1; Type Name: BI-27 2500x1700
Other(Type) - Category: Model Groups; Family Name: Model Group
Name (Model Group:BI-27 2500x1700:...)
2534618
2534674

# IfcGroup: Model Group:BI-28, Model Group:BI-28:2534707
Constraints - Origin Level Offset: 0 mm; Reference Level: 02 tweede verdieping
Identity Data - Workset: Workset1
Other - Category: Model Groups; Family: Model Group; Family and Type: Model Group: BI-28; Type: BI-28; Type Id: 2534708
Identity Data(Type) - Workset: Workset1; Type Name: BI-28
Other(Type) - Category: Model Groups; Family Name: Model Group

# IfcGroup: Model Group:BI-29B (5)
Constraints - Origin Level Offset: 0 mm; Reference Level: 01 eerste verdieping
Identity Data - Workset: Workset1
Other - Category: Model Groups; Family: Model Group; Family and Type: Model Group: BI-29B; Type: BI-29B; Type Id: 1865380
Identity Data(Type) - Workset: Workset1; Type Name: BI-29B
Other(Type) - Category: Model Groups; Family Name: Model Group
Name (Model Group:...)
BI-29B:876480
BI-29B:876898
BI-29B:877015
BI-29B (members excluded):877105
BI-29B:881766

# IfcGroup: Model Group:BI-29bw 60min, Model Group:BI-29bw 60min:1476114
Constraints - Origin Level Offset: 0 mm; Reference Level: 02 tweede verdieping
Identity Data - Workset: Workset1
Other - Category: Model Groups; Family: Model Group; Family and Type: Model Group: BI-29bw 60min; Type: BI-29bw 60min; Type Id: 1476660
Identity Data(Type) - Workset: Workset1; Type Name: BI-29bw 60min
Other(Type) - Category: Model Groups; Family Name: Model Group

# IfcGroup: Model Group:BI-30, Model Group:BI-30:2755094
Constraints - Origin Level Offset: 0 mm; Reference Level: 01 eerste verdieping
Identity Data - Workset: Workset1
Other - Category: Model Groups; Family: Model Group; Family and Type: Model Group: BI-30; Type: BI-30; Type Id: 2755095
Identity Data(Type) - Workset: Workset1; Type Name: BI-30
Other(Type) - Category: Model Groups; Family Name: Model Group

# IfcGroup: Model Group:BI-31w 1250x2387, Model Group:BI-31w 1250x2387:1940859
Constraints - Origin Level Offset: 0 mm; Reference Level: 00 begane grond
Identity Data - Workset: Workset1
Other - Category: Model Groups; Family: Model Group; Family and Type: Model Group: BI-31w 1250x2387; Type: BI-31w 1250x2387; Type Id: 1940869
Identity Data(Type) - Workset: Workset1; Type Name: BI-31w 1250x2387
Other(Type) - Category: Model Groups; Family Name: Model Group

# IfcGroup: Model Group:BU-01 b1500, Model Group:BU-01 b1500:3003067
Constraints - Origin Level Offset: 0 mm; Reference Level: 00 begane grond
Identity Data - Workset: Workset1
Other - Category: Model Groups; Family: Model Group; Family and Type: Model Group: BU-01 b1500; Type: BU-01 b1500; Type Id: 1818198
Identity Data(Type) - Workset: Workset1; Type Name: BU-01 b1500
Other(Type) - Category: Model Groups; Family Name: Model Group

# IfcGroup: Model Group:BU-02 b4200, Model Group:BU-02 b4200:1494104
Constraints - Reference Level: 00 begane grond; Origin Level Offset: -520 mm
Identity Data - Workset: Workset1
Other - Category: Model Groups; Family: Model Group; Family and Type: Model Group: BU-02 b4200; Type: BU-02 b4200; Type Id: 1494132
Identity Data(Type) - Workset: Workset1; Type Name: BU-02 b4200
Other(Type) - Category: Model Groups; Family Name: Model Group

# IfcGroup: Model Group:BU-03 b5800, Model Group:BU-03 b5800:1818868
Constraints - Origin Level Offset: 0 mm; Reference Level: 00 begane grond
Identity Data - Workset: Workset1
Other - Category: Model Groups; Family: Model Group; Family and Type: Model Group: BU-03 b5800; Type: BU-03 b5800; Type Id: 1818990
Identity Data(Type) - Workset: Workset1; Type Name: BU-03 b5800
Other(Type) - Category: Model Groups; Family Name: Model Group

# IfcGroup: Model Group:BU-04 b2500, Model Group:BU-04 b2500:1820005
Constraints - Origin Level Offset: 0 mm; Reference Level: 00 begane grond
Identity Data - Workset: Workset1
Other - Category: Model Groups; Family: Model Group; Family and Type: Model Group: BU-04 b2500; Type: BU-04 b2500; Type Id: 1820875
Identity Data(Type) - Workset: Workset1; Type Name: BU-04 b2500
Other(Type) - Category: Model Groups; Family Name: Model Group

# IfcGroup: Model Group:BU-05 b1910, Model Group:BU-05 b1910:2648634
Constraints - Origin Level Offset: 0 mm; Reference Level: 00 begane grond
Identity Data - Workset: Workset1
Other - Category: Model Groups; Family: Model Group; Family and Type: Model Group: BU-05 b1910; Type: BU-05 b1910; Type Id: 2648635
Identity Data(Type) - Workset: Workset1; Type Name: BU-05 b1910
Other(Type) - Category: Model Groups; Family Name: Model Group

# IfcGroup: Model Group:BU-06 b1800, Model Group:BU-06 b1800:894434
Constraints - Origin Level Offset: 0 mm; Reference Level: 00 begane grond
Identity Data - Workset: Workset1
Other - Category: Model Groups; Family: Model Group; Family and Type: Model Group: BU-06 b1800; Type: BU-06 b1800; Type Id: 894509
Identity Data(Type) - Workset: Workset1; Type Name: BU-06 b1800
Other(Type) - Category: Model Groups; Family Name: Model Group

# IfcGroup: Model Group:BU-07 b900 (5)
Constraints - Origin Level Offset: 0 mm; Reference Level: 00 begane grond
Identity Data - Workset: Workset1
Other - Category: Model Groups; Family: Model Group; Family and Type: Model Group: BU-07 b900; Type: BU-07 b900; Type Id: 894364
Identity Data(Type) - Workset: Workset1; Type Name: BU-07 b900
Other(Type) - Category: Model Groups; Family Name: Model Group
Name (Model Group:...)
BU-07 b900:894363
BU-07 b900 (members excluded):1300407
BU-07 b900 (members excluded):1300686
BU-07 b900:1502980
BU-07 b900 (members excluded):1818605

# IfcGroup: Model Group:BU-08 b2100, Model Group:BU-08 b2100:1220076
Constraints - Origin Level Offset: 0 mm; Reference Level: 00 begane grond
Identity Data - Workset: Workset1
Other - Category: Model Groups; Family: Model Group; Family and Type: Model Group: BU-08 b2100; Type: BU-08 b2100; Type Id: 1220252
Identity Data(Type) - Workset: Workset1; Type Name: BU-08 b2100
Other(Type) - Category: Model Groups; Family Name: Model Group

# IfcGroup: Model Group:BU-09 b1500, Model Group:BU-09 b1500:1220175
Constraints - Origin Level Offset: 0 mm; Reference Level: 00 begane grond
Identity Data - Workset: Workset1
Other - Category: Model Groups; Family: Model Group; Family and Type: Model Group: BU-09 b1500; Type: BU-09 b1500; Type Id: 1894393
Identity Data(Type) - Workset: Workset1; Type Name: BU-09 b1500
Other(Type) - Category: Model Groups; Family Name: Model Group

# IfcGroup: Model Group:BU-10 b1800, Model Group:BU-10 b1800:1822150
Constraints - Origin Level Offset: 0 mm; Reference Level: 00 begane grond
Identity Data - Workset: Workset1
Other - Category: Model Groups; Family: Model Group; Family and Type: Model Group: BU-10 b1800; Type: BU-10 b1800; Type Id: 1937884
Identity Data(Type) - Workset: Workset1; Type Name: BU-10 b1800
Other(Type) - Category: Model Groups; Family Name: Model Group

# IfcGroup: Model Group:BU-11 b3000 (3)
Constraints - Origin Level Offset: 0 mm; Reference Level: 00 begane grond
Identity Data - Workset: Workset1
Other - Category: Model Groups; Family: Model Group; Family and Type: Model Group: BU-11 b3000; Type: BU-11 b3000; Type Id: 1822008
Identity Data(Type) - Workset: Workset1; Type Name: BU-11 b3000
Other(Type) - Category: Model Groups; Family Name: Model Group
Name (Model Group:BU-11 b3000:...)
1220846
1502212
1502763

# IfcGroup: Model Group:BU-12 b4200, Model Group:BU-12 b4200:1817348
Constraints - Origin Level Offset: 0 mm; Reference Level: 00 begane grond
Identity Data - Workset: Workset1
Other - Category: Model Groups; Family: Model Group; Family and Type: Model Group: BU-12 b4200; Type: BU-12 b4200; Type Id: 2192685
Identity Data(Type) - Workset: Workset1; Type Name: BU-12 b4200
Other(Type) - Category: Model Groups; Family Name: Model Group

# IfcGroup: Model Group:BU-13 b3300, Model Group:BU-13 b3300:1862274
Constraints - Origin Level Offset: 0 mm; Reference Level: 00 begane grond
Identity Data - Workset: Workset1
Other - Category: Model Groups; Family: Model Group; Family and Type: Model Group: BU-13 b3300; Type: BU-13 b3300; Type Id: 1862376
Identity Data(Type) - Workset: Workset1; Type Name: BU-13 b3300
Other(Type) - Category: Model Groups; Family Name: Model Group

# IfcGroup: Model Group:BU-14 b3000, Model Group:BU-14 b3000:1494513
Constraints - Origin Level Offset: 0 mm; Reference Level: 00 begane grond
Identity Data - Workset: Workset1
Other - Category: Model Groups; Family: Model Group; Family and Type: Model Group: BU-14 b3000; Type: BU-14 b3000; Type Id: 1863181
Identity Data(Type) - Workset: Workset1; Type Name: BU-14 b3000
Other(Type) - Category: Model Groups; Family Name: Model Group

# IfcGroup: Model Group:BU-15 b4200, Model Group:BU-15 b4200:1823297
Constraints - Origin Level Offset: 0 mm; Reference Level: 00 begane grond
Identity Data - Workset: Workset1
Other - Category: Model Groups; Family: Model Group; Family and Type: Model Group: BU-15 b4200; Type: BU-15 b4200; Type Id: 1822960
Identity Data(Type) - Workset: Workset1; Type Name: BU-15 b4200
Other(Type) - Category: Model Groups; Family Name: Model Group

# IfcGroup: Model Group:BU-16, Model Group:BU-16:3836676
Constraints - Origin Level Offset: 0 mm; Reference Level: 00 begane grond
Identity Data - Workset: Workset1
Other - Category: Model Groups; Family: Model Group; Family and Type: Model Group: BU-16; Type: BU-16; Type Id: 2650965
Identity Data(Type) - Workset: Workset1; Type Name: BU-16
Other(Type) - Category: Model Groups; Family Name: Model Group

# IfcGroup: Model Group:BU-17 b3000, Model Group:BU-17 b3000:1900158
Constraints - Origin Level Offset: 0 mm; Reference Level: 00 begane grond
Identity Data - Workset: Workset1
Other - Category: Model Groups; Family: Model Group; Family and Type: Model Group: BU-17 b3000; Type: BU-17 b3000; Type Id: 1826371
Identity Data(Type) - Workset: Workset1; Type Name: BU-17 b3000
Other(Type) - Category: Model Groups; Family Name: Model Group

# IfcGroup: Model Group:BU-18 b3017, Model Group:BU-18 b3017:2651211
Constraints - Origin Level Offset: 0 mm; Reference Level: 00 begane grond
Identity Data - Workset: Workset1
Other - Category: Model Groups; Family: Model Group; Family and Type: Model Group: BU-18 b3017; Type: BU-18 b3017; Type Id: 2651212
Identity Data(Type) - Workset: Workset1; Type Name: BU-18 b3017
Other(Type) - Category: Model Groups; Family Name: Model Group

# IfcGroup: Model Group:BU-19 b2067, Model Group:BU-19 b2067:2651286
Constraints - Origin Level Offset: 0 mm; Reference Level: 00 begane grond
Identity Data - Workset: Workset1
Other - Category: Model Groups; Family: Model Group; Family and Type: Model Group: BU-19 b2067; Type: BU-19 b2067; Type Id: 2651287
Identity Data(Type) - Workset: Workset1; Type Name: BU-19 b2067
Other(Type) - Category: Model Groups; Family Name: Model Group

# IfcGroup: Model Group:BU-20 b3300, Model Group:BU-20 b3300:1300930
Constraints - Origin Level Offset: 0 mm; Reference Level: 00 begane grond
Identity Data - Workset: Workset1
Other - Category: Model Groups; Family: Model Group; Family and Type: Model Group: BU-20 b3300; Type: BU-20 b3300; Type Id: 1220966
Identity Data(Type) - Workset: Workset1; Type Name: BU-20 b3300
Other(Type) - Category: Model Groups; Family Name: Model Group

# IfcGroup: Model Group:BU-21 b2966, Model Group:BU-21 b2966:1300741
Constraints - Origin Level Offset: 0 mm; Reference Level: 00 begane grond
Identity Data - Workset: Workset1
Other - Category: Model Groups; Family: Model Group; Family and Type: Model Group: BU-21 b2966; Type: BU-21 b2966; Type Id: 1300764
Identity Data(Type) - Workset: Workset1; Type Name: BU-21 b2966
Other(Type) - Category: Model Groups; Family Name: Model Group

# IfcGroup: Model Group:BU-22 b2700, Model Group:BU-22 b2700:1300414
Constraints - Origin Level Offset: 0 mm; Reference Level: 00 begane grond
Identity Data - Workset: Workset1
Other - Category: Model Groups; Family: Model Group; Family and Type: Model Group: BU-22 b2700; Type: BU-22 b2700; Type Id: 1300541
Identity Data(Type) - Workset: Workset1; Type Name: BU-22 b2700
Other(Type) - Category: Model Groups; Family Name: Model Group

# IfcGroup: Model Group:BU-23 b1353, Model Group:BU-23 b1353:2651710
Constraints - Origin Level Offset: 0 mm; Reference Level: 00 begane grond
Identity Data - Workset: Workset1
Other - Category: Model Groups; Family: Model Group; Family and Type: Model Group: BU-23 b1353; Type: BU-23 b1353; Type Id: 2651711
Identity Data(Type) - Workset: Workset1; Type Name: BU-23 b1353
Other(Type) - Category: Model Groups; Family Name: Model Group

# IfcGroup: Model Group:BU-25 b3000, Model Group:BU-25 b3000:1493474
Constraints - Origin Level Offset: 0 mm; Reference Level: 00 begane grond
Identity Data - Workset: Workset1
Other - Category: Model Groups; Family: Model Group; Family and Type: Model Group: BU-25 b3000; Type: BU-25 b3000; Type Id: 1493608
Identity Data(Type) - Workset: Workset1; Type Name: BU-25 b3000
Other(Type) - Category: Model Groups; Family Name: Model Group

# IfcGroup: Model Group:BU-26 (17)
Constraints - Origin Level Offset: 0 mm; Reference Level: 01 eerste verdieping
Identity Data - Workset: Workset1
Other - Category: Model Groups; Family: Model Group; Family and Type: Model Group: BU-26; Type: BU-26; Type Id: 874610
Identity Data(Type) - Workset: Workset1; Type Name: BU-26
Other(Type) - Category: Model Groups; Family Name: Model Group
Name (Model Group:...)
BU-26:874674
BU-26:874958
BU-26:875048
BU-26:875276
BU-26:875384
BU-26:876495
BU-26:876913
BU-26:877030
BU-26:877120
BU-26 (members excluded):877210
BU-26:880929
BU-26:881690
BU-26:891682
BU-26:891794
BU-26:891911
BU-26:891933
BU-26:891983

# IfcGroup: Model Group:BU-27, Model Group:BU-27:891638
Constraints - Origin Level Offset: 0 mm; Reference Level: 01 eerste verdieping
Identity Data - Workset: Workset1
Other - Category: Model Groups; Family: Model Group; Family and Type: Model Group: BU-27; Type: BU-27; Type Id: 2776447
Identity Data(Type) - Workset: Workset1; Type Name: BU-27
Other(Type) - Category: Model Groups; Family Name: Model Group

# IfcGroup: Model Group:BU-28A (7)
Constraints - Origin Level Offset: 0 mm; Reference Level: 01 eerste verdieping
Identity Data - Workset: Workset1
Other - Category: Model Groups; Family: Model Group; Family and Type: Model Group: BU-28A; Type: BU-28A; Type Id: 1865056
Identity Data(Type) - Workset: Workset1; Type Name: BU-28A
Other(Type) - Category: Model Groups; Family Name: Model Group
Name (Model Group:...)
BU-28A:875312
BU-28A:876928
BU-28A:877045
BU-28A:877135
BU-28A (members excluded):877225
BU-28A:881793
BU-28A:3058229

# IfcGroup: Model Group:BU-28B (4)
Constraints - Origin Level Offset: 0 mm; Reference Level: 01 eerste verdieping
Identity Data - Workset: Workset1
Other - Category: Model Groups; Family: Model Group; Family and Type: Model Group: BU-28B; Type: BU-28B; Type Id: 1864635
Identity Data(Type) - Workset: Workset1; Type Name: BU-28B
Other(Type) - Category: Model Groups; Family Name: Model Group
Name (Model Group:BU-28B:...)
874689
874967
875057
891704

# IfcGroup: Model Group:BU-29 (2)
Constraints - Origin Level Offset: 0 mm; Reference Level: 01 eerste verdieping
Identity Data - Workset: Workset1
Other - Category: Model Groups; Family: Model Group; Family and Type: Model Group: BU-29; Type: BU-29; Type Id: 2172399
Identity Data(Type) - Workset: Workset1; Type Name: BU-29
Other(Type) - Category: Model Groups; Family Name: Model Group
Name (Model Group:BU-29:...)
874949
2698865

# IfcGroup: Model Group:BU-29A (6)
Constraints - Origin Level Offset: 0 mm; Reference Level: 01 eerste verdieping
Identity Data - Workset: Workset1
Other - Category: Model Groups; Family: Model Group; Family and Type: Model Group: BU-29A; Type: BU-29A; Type Id: 1864314
Identity Data(Type) - Workset: Workset1; Type Name: BU-29A
Other(Type) - Category: Model Groups; Family Name: Model Group
Name (Model Group:BU-29A:...)
874609
875039
875240
875348
891660
891726

# IfcGroup: Model Group:BU-29C, Model Group:BU-29C:891772
Constraints - Origin Level Offset: 0 mm; Reference Level: 01 eerste verdieping
Identity Data - Workset: Workset1
Other - Category: Model Groups; Family: Model Group; Family and Type: Model Group: BU-29C; Type: BU-29C; Type Id: 1866096
Identity Data(Type) - Workset: Workset1; Type Name: BU-29C
Other(Type) - Category: Model Groups; Family Name: Model Group

# IfcGroup: Model Group:BU-30, Model Group:BU-30:2700215
Constraints - Origin Level Offset: 0 mm; Reference Level: 01 eerste verdieping
Identity Data - Workset: Workset1
Other - Category: Model Groups; Family: Model Group; Family and Type: Model Group: BU-30; Type: BU-30; Type Id: 2700216
Identity Data(Type) - Workset: Workset1; Type Name: BU-30
Other(Type) - Category: Model Groups; Family Name: Model Group

# IfcGroup: Model Group:BU-31, Model Group:BU-31:891953
Constraints - Origin Level Offset: 0 mm; Reference Level: 01 eerste verdieping
Identity Data - Workset: Workset1
Other - Category: Model Groups; Family: Model Group; Family and Type: Model Group: BU-31; Type: BU-31; Type Id: 1301973
Identity Data(Type) - Workset: Workset1; Type Name: BU-31
Other(Type) - Category: Model Groups; Family Name: Model Group

# IfcGroup: Model Group:BU-32, Model Group:BU-32:892003
Constraints - Origin Level Offset: 0 mm; Reference Level: 01 eerste verdieping
Identity Data - Workset: Workset1
Other - Category: Model Groups; Family: Model Group; Family and Type: Model Group: BU-32; Type: BU-32; Type Id: 1837052
Identity Data(Type) - Workset: Workset1; Type Name: BU-32
Other(Type) - Category: Model Groups; Family Name: Model Group

# IfcGroup: Model Group:BU-33 (2)
Constraints - Origin Level Offset: 0 mm; Reference Level: 01 eerste verdieping
Identity Data - Workset: Workset1
Other - Category: Model Groups; Family: Model Group; Family and Type: Model Group: BU-33; Type: BU-33; Type Id: 2759830
Identity Data(Type) - Workset: Workset1; Type Name: BU-33
Other(Type) - Category: Model Groups; Family Name: Model Group
Name (Model Group:BU-33:...)
2700705
2712443

# IfcGroup: Model Group:BU-34, Model Group:BU-34:2700766
Constraints - Origin Level Offset: 0 mm; Reference Level: 01 eerste verdieping
Identity Data - Workset: Workset1
Other - Category: Model Groups; Family: Model Group; Family and Type: Model Group: BU-34; Type: BU-34; Type Id: 2700767
Identity Data(Type) - Workset: Workset1; Type Name: BU-34
Other(Type) - Category: Model Groups; Family Name: Model Group

# IfcGroup: Model Group:BU-35, Model Group:BU-35:2701985
Constraints - Origin Level Offset: 0 mm; Reference Level: 01 eerste verdieping
Identity Data - Workset: Workset1
Other - Category: Model Groups; Family: Model Group; Family and Type: Model Group: BU-35; Type: BU-35; Type Id: 2701986
Identity Data(Type) - Workset: Workset1; Type Name: BU-35
Other(Type) - Category: Model Groups; Family Name: Model Group

# IfcGroup: Model Group:BU-36, Model Group:BU-36:2701416
Constraints - Origin Level Offset: 0 mm; Reference Level: 01 eerste verdieping
Identity Data - Workset: Workset1
Other - Category: Model Groups; Family: Model Group; Family and Type: Model Group: BU-36; Type: BU-36; Type Id: 2700706
Identity Data(Type) - Workset: Workset1; Type Name: BU-36
Other(Type) - Category: Model Groups; Family Name: Model Group

# IfcGroup: Model Group:BU-37, Model Group:BU-37:2712501
Constraints - Origin Level Offset: 0 mm; Reference Level: 01 eerste verdieping
Identity Data - Workset: Workset1
Other - Category: Model Groups; Family: Model Group; Family and Type: Model Group: BU-37; Type: BU-37; Type Id: 2760187
Identity Data(Type) - Workset: Workset1; Type Name: BU-37
Other(Type) - Category: Model Groups; Family Name: Model Group

# IfcGroup: Model Group:BU-38, Model Group:BU-38:2702101
Constraints - Origin Level Offset: 0 mm; Reference Level: 01 eerste verdieping
Identity Data - Workset: Workset1
Other - Category: Model Groups; Family: Model Group; Family and Type: Model Group: BU-38; Type: BU-38; Type Id: 2702102
Identity Data(Type) - Workset: Workset1; Type Name: BU-38
Other(Type) - Category: Model Groups; Family Name: Model Group

# IfcGroup: Model Group:BU-39 (17)
Constraints - Origin Level Offset: 0 mm; Reference Level: 02 tweede verdieping
Identity Data - Workset: Workset1
Other - Category: Model Groups; Family: Model Group; Family and Type: Model Group: BU-39; Type: BU-39; Type Id: 865432
Identity Data(Type) - Workset: Workset1; Type Name: BU-39
Other(Type) - Category: Model Groups; Family Name: Model Group
Name (Model Group:BU-39:...)
870548
870754
870867
871642
871675
871926
871958
872820
872886
872919
872952
872985
873018
873084
873515
873608
873701

# IfcGroup: Model Group:BU-39A (15)
Constraints - Origin Level Offset: 0 mm; Reference Level: 02 tweede verdieping
Identity Data - Workset: Workset1
Other - Category: Model Groups; Family: Model Group; Family and Type: Model Group: BU-39A; Type: BU-39A; Type Id: 1866190
Identity Data(Type) - Workset: Workset1; Type Name: BU-39A
Other(Type) - Category: Model Groups; Family Name: Model Group
Name (Model Group:BU-39A:...)
865431
870563
870664
870672
870680
870746
870762
870875
871894
871990
872286
872853
873051
873117
1867105

# IfcGroup: Model Group:BU-39B (11)
Constraints - Origin Level Offset: 0 mm; Reference Level: 02 tweede verdieping
Identity Data - Workset: Workset1
Other - Category: Model Groups; Family: Model Group; Family and Type: Model Group: BU-39B; Type: BU-39B; Type Id: 1869478
Identity Data(Type) - Workset: Workset1; Type Name: BU-39B
Other(Type) - Category: Model Groups; Family Name: Model Group
Name (Model Group:...)
BU-39B:871535
BU-39B:871708
BU-39B (members excluded):872020
BU-39B:873403
BU-39B:873453
BU-39B:873484
BU-39B:873546
BU-39B:873577
BU-39B:873639
BU-39B:873670
BU-39B:873732

# IfcGroup: Model Group:BU-40, Model Group:BU-40:2712884
Constraints - Origin Level Offset: 0 mm; Reference Level: 02 tweede verdieping
Identity Data - Workset: Workset1
Other - Category: Model Groups; Family: Model Group; Family and Type: Model Group: BU-40; Type: BU-40; Type Id: 2712885
Identity Data(Type) - Workset: Workset1; Type Name: BU-40
Other(Type) - Category: Model Groups; Family Name: Model Group

# IfcGroup: Model Group:BU-42 daklicht B lokaal (2)
Constraints - Origin Level Offset: 0 mm; Reference Level: 03 derde verdieping
Identity Data - Workset: Workset1
Other - Category: Model Groups; Family: Model Group; Family and Type: Model Group: BU-42 daklicht B lokaal; Type: BU-42 daklicht B lokaal; Type Id: 2194601
Identity Data(Type) - Workset: Workset1; Type Name: BU-42 daklicht B lokaal
Other(Type) - Category: Model Groups; Family Name: Model Group
Name (Model Group:BU-42 daklicht B lokaal:...)
2182308
2194782

# IfcGroup: Model Group:BU-45 b900, Model Group:BU-45 b900:2546304
Constraints - Origin Level Offset: 0 mm; Reference Level: 00 begane grond
Identity Data - Workset: Workset1
Other - Category: Model Groups; Family: Model Group; Family and Type: Model Group: BU-45 b900; Type: BU-45 b900; Type Id: 3451907
Identity Data(Type) - Workset: Workset1; Type Name: BU-45 b900
Other(Type) - Category: Model Groups; Family Name: Model Group

# IfcGroup: Model Group:BU-46, Model Group:BU-46:4200502
Constraints - Origin Level Offset: 0 mm; Reference Level: 00 begane grond
Identity Data - Workset: Workset1
Other - Category: Model Groups; Family: Model Group; Family and Type: Model Group: BU-46; Type: BU-46; Type Id: 4200503
Identity Data(Type) - Workset: Workset1; Type Name: BU-46
Other(Type) - Category: Model Groups; Family Name: Model Group

# IfcGroup: Model Group:BU-47 b4200, Model Group:BU-47 b4200:1822720
Constraints - Origin Level Offset: 0 mm; Reference Level: 00 begane grond
Identity Data - Workset: Workset1
Other - Category: Model Groups; Family: Model Group; Family and Type: Model Group: BU-47 b4200; Type: BU-47 b4200; Type Id: 4225874
Identity Data(Type) - Workset: Workset1; Type Name: BU-47 b4200
Other(Type) - Category: Model Groups; Family Name: Model Group

# IfcGroup: Model Group:HSB iso 200 tpv. kolom V2 (16)
Constraints - Origin Level Offset: 0 mm; Reference Level: 02 tweede verdieping
Identity Data - Workset: Workset1
Other - Category: Model Groups; Family: Model Group; Family and Type: Model Group: HSB iso 200 tpv. kolom V2; Type: HSB iso 200 tpv. kolom V2; Type Id: 2574205
Identity Data(Type) - Workset: Workset1; Type Name: HSB iso 200 tpv. kolom V2
Other(Type) - Category: Model Groups; Family Name: Model Group
Name (Model Group:HSB iso 200 tpv. kolom V2:...)
2339525
2339559
2339574
2339589
2339600
2339636
2340615
2340655
2340666
2340677
2340688
2340699
2340737
2340748
2340761
2340838

# IfcGroup: Model Group:MW_gevelvlak_V1 a (8)
Constraints - Origin Level Offset: 0 mm; Reference Level: 01 eerste verdieping
Identity Data - Workset: Workset1
Other - Category: Model Groups; Family: Model Group; Family and Type: Model Group: MW_gevelvlak_V1 a; Type: MW_gevelvlak_V1 a; Type Id: 1885438
Identity Data(Type) - Workset: Workset1; Type Name: MW_gevelvlak_V1 a
Other(Type) - Category: Model Groups; Family Name: Model Group
Name (Model Group:...)
MW_gevelvlak_V1 a (members excluded):1885437
MW_gevelvlak_V1 a (members excluded):1885483
MW_gevelvlak_V1 a (members excluded):1885510
MW_gevelvlak_V1 a (members excluded):1885560
MW_gevelvlak_V1 a:1885576
MW_gevelvlak_V1 a:1886481
MW_gevelvlak_V1 a:1886487
MW_gevelvlak_V1 a:1886493

# IfcGroup: Model Group:UNP rand fietsenstalling, Model Group:UNP rand fietsenstalling:4046343
Constraints - Reference Level: 00 begane grond; Origin Level Offset: 2005.04 mm
Identity Data - Workset: BDG_fietsenstalling
Other - Category: Model Groups; Family: Model Group; Family and Type: Model Group: UNP rand fietsenstalling; Type: UNP rand fietsenstalling; Type Id: 4046344
Identity Data(Type) - Workset: BDG_fietsenstalling; Type Name: UNP rand fietsenstalling
Other(Type) - Category: Model Groups; Family Name: Model Group
Group: Model Group:fietsenstalling:4188142

# IfcGroup: Model Group:daklicht A1 (2)
Constraints - Origin Level Offset: 0 mm; Reference Level: 03 derde verdieping
Identity Data - Workset: Workset1
Other - Category: Model Groups; Family: Model Group; Family and Type: Model Group: daklicht A1; Type: daklicht A1; Type Id: 2182253
Identity Data(Type) - Workset: Workset1; Type Name: daklicht A1
Other(Type) - Category: Model Groups; Family Name: Model Group
Name (Model Group:...)
daklicht A1:2182252
daklicht A1 (members excluded):2182288

# IfcGroup: Model Group:enkele deur-kokers (10)
Constraints - Origin Level Offset: 0 mm; Reference Level: 00 begane grond
Identity Data - Workset: BDG_fietsenstalling
Other - Category: Model Groups; Family: Model Group; Family and Type: Model Group: enkele deur-kokers; Type: enkele deur-kokers; Type Id: 4104444
Identity Data(Type) - Workset: BDG_fietsenstalling; Type Name: enkele deur-kokers
Other(Type) - Category: Model Groups; Family Name: Model Group
Name (Model Group:enkele deur-kokers:...) | Group
4158221 | Model Group:fietsenstalling_dubbele deur:4154258
4158256 | Model Group:fietsenstalling_dubbele deur:4154258
4158445 | Model Group:fietsenstalling_dubbele deur:4153902
4158457 | Model Group:fietsenstalling_dubbele deur:4153902
4158497 | Model Group:fietsenstalling_dubbele deur:4154050
4158509 | Model Group:fietsenstalling_dubbele deur:4154050
4158523 | Model Group:fietsenstalling_dubbele deur:4154120
4158535 | Model Group:fietsenstalling_dubbele deur:4154120
4158549 | Model Group:fietsenstalling_dubbele deur:4154188
4158561 | Model Group:fietsenstalling_dubbele deur:4154188

# IfcGroup: Model Group:fietsenstalling, Model Group:fietsenstalling:4188142
Constraints - Origin Level Offset: 0 mm; Reference Level: 00 begane grond
Identity Data - Workset: BDG_fietsenstalling
Other - Category: Model Groups; Family: Model Group; Family and Type: Model Group: fietsenstalling; Type: fietsenstalling; Type Id: 4188143
Identity Data(Type) - Workset: BDG_fietsenstalling; Type Name: fietsenstalling
Other(Type) - Category: Model Groups; Family Name: Model Group

# IfcGroup: Model Group:fietsenstalling_dubbele deur (5)
Constraints - Origin Level Offset: 0 mm; Reference Level: 00 begane grond
Identity Data - Workset: BDG_fietsenstalling
Other - Category: Model Groups; Family: Model Group; Family and Type: Model Group: fietsenstalling_dubbele deur; Type: fietsenstalling_dubbele deur; Type Id: 4153903
Identity Data(Type) - Workset: BDG_fietsenstalling; Type Name: fietsenstalling_dubbele deur
Other(Type) - Category: Model Groups; Family Name: Model Group
Group: Model Group:fietsenstalling:4188142
Name (Model Group:fietsenstalling_dubbele deur:...)
4153902
4154050
4154120
4154188
4154258

# IfcGroup: Model Group:hoeklijnen L80 (6)
Constraints - Reference Level: 00 begane grond; Origin Level Offset: 1906.05 mm
Identity Data - Workset: BDG_fietsenstalling
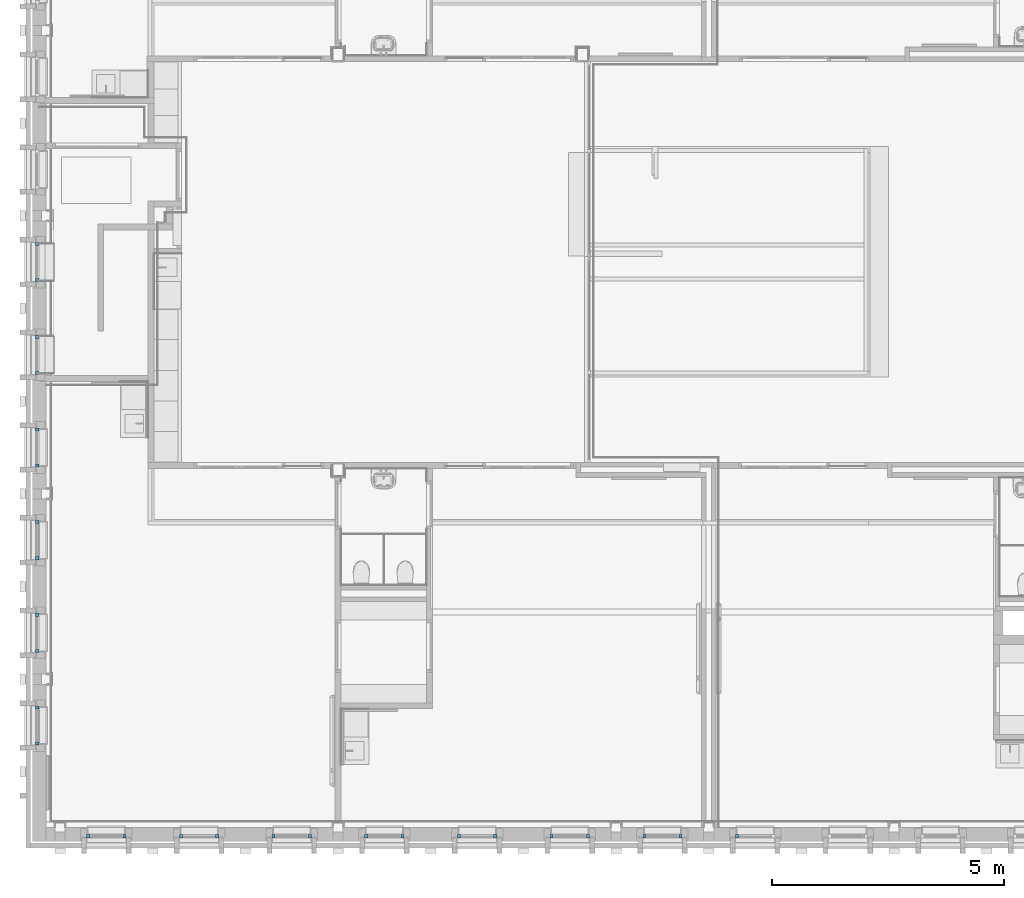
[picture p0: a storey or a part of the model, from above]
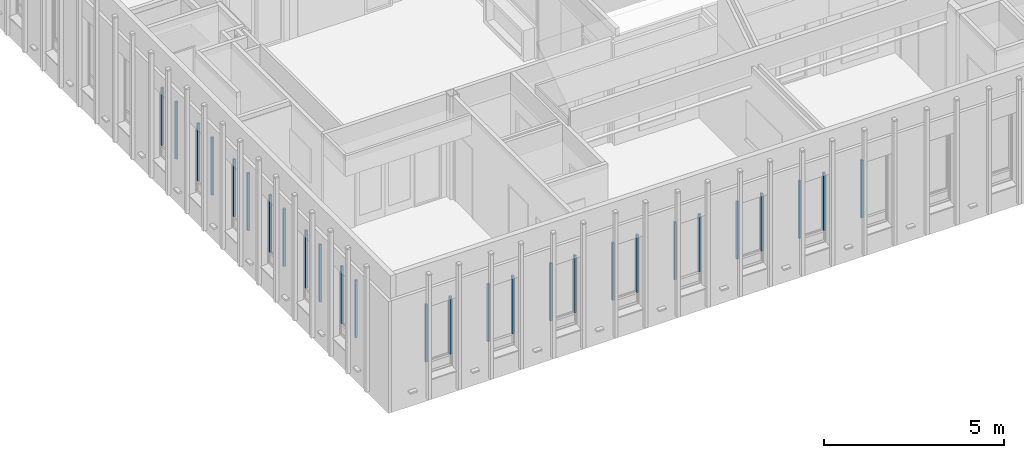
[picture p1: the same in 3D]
Properties of the parts of a building model (IFC2X3), part 12 of 94

# IfcGroup: Model Group:hoeklijnen L80 (6)
Other - Category: Model Groups; Family: Model Group; Family and Type: Model Group: hoeklijnen L80; Type: hoeklijnen L80; Type Id: 4129894
Identity Data(Type) - Workset: BDG_fietsenstalling; Type Name: hoeklijnen L80
Other(Type) - Category: Model Groups; Family Name: Model Group
Group: Model Group:fietsenstalling:4188142
Name (Model Group:hoeklijnen L80:...)
4129968
4137488
4137514
4137577
4137601
4137627

# IfcGroup: Model Group:pantry 1 kinderopvang (2)
Constraints - Origin Level Offset: 0 mm; Reference Level: 00 begane grond
Identity Data - Workset: Workset1
Other - Category: Model Groups; Family: Model Group; Family and Type: Model Group: pantry 1 kinderopvang; Type: pantry 1 kinderopvang; Type Id: 1511167
Identity Data(Type) - Workset: Workset1; Type Name: pantry 1 kinderopvang
Other(Type) - Category: Model Groups; Family Name: Model Group
Name (Model Group:pantry 1 kinderopvang:...)
1223752
1511177

# IfcGroup: Model Group:pantry 1.2 MF BSO, Model Group:pantry 1.2 MF BSO:1614348
Constraints - Origin Level Offset: 0 mm; Reference Level: 00 begane grond
Identity Data - Workset: Workset1
Other - Category: Model Groups; Family: Model Group; Family and Type: Model Group: pantry 1.2 MF BSO; Type: pantry 1.2 MF BSO; Type Id: 1223621
Identity Data(Type) - Workset: Workset1; Type Name: pantry 1.2 MF BSO
Other(Type) - Category: Model Groups; Family Name: Model Group

# IfcGroup: Model Group:pantry 3 BS groepsruimten (16)
Constraints - Origin Level Offset: 0 mm
Identity Data - Workset: Workset1
Other - Category: Model Groups; Family: Model Group; Family and Type: Model Group: pantry 3 BS groepsruimten; Type: pantry 3 BS groepsruimten; Type Id: 1693631
Identity Data(Type) - Workset: Workset1; Type Name: pantry 3 BS groepsruimten
Other(Type) - Category: Model Groups; Family Name: Model Group
Name (Model Group:pantry 3 BS groepsruimten:...) | Reference Level
1223713 | 01 eerste verdieping
1694326 | 02 tweede verdieping
2860118 | 01 eerste verdieping
2860456 | 01 eerste verdieping
2860491 | 01 eerste verdieping
2860760 | 02 tweede verdieping
2860796 | 02 tweede verdieping
3267579 | 01 eerste verdieping
3267594 | 01 eerste verdieping
3267608 | 02 tweede verdieping
3267622 | 02 tweede verdieping
3267636 | 02 tweede verdieping
5027846 | 00 begane grond
5027924 | 00 begane grond
5027929 | 00 begane grond
5027952 | 00 begane grond

# IfcGroup: Model Group:pantry 4 werkruimte OB, Model Group:pantry 4 werkruimte OB:2071170
Constraints - Origin Level Offset: 0 mm; Reference Level: 00 begane grond
Identity Data - Workset: Workset1
Other - Category: Model Groups; Family: Model Group; Family and Type: Model Group: pantry 4 werkruimte OB; Type: pantry 4 werkruimte OB; Type Id: 1671878
Identity Data(Type) - Workset: Workset1; Type Name: pantry 4 werkruimte OB
Other(Type) - Category: Model Groups; Family Name: Model Group

# IfcGroup: Model Group:pantry 5 personeelsruimte, Model Group:pantry 5 personeelsruimte:1672603
Constraints - Origin Level Offset: 0 mm; Reference Level: 01 eerste verdieping
Identity Data - Workset: Workset1
Other - Category: Model Groups; Family: Model Group; Family and Type: Model Group: pantry 5 personeelsruimte; Type: pantry 5 personeelsruimte; Type Id: 1691980
Identity Data(Type) - Workset: Workset1; Type Name: pantry 5 personeelsruimte
Other(Type) - Category: Model Groups; Family Name: Model Group

# IfcGroup: Model Group:pantry 5 werkruimte MB BB (2)
Constraints - Origin Level Offset: 0 mm
Identity Data - Workset: Workset1
Other - Category: Model Groups; Family: Model Group; Family and Type: Model Group: pantry 5 werkruimte MB BB; Type: pantry 5 werkruimte MB BB; Type Id: 2859973
Identity Data(Type) - Workset: Workset1; Type Name: pantry 5 werkruimte MB BB
Other(Type) - Category: Model Groups; Family Name: Model Group
Name (Model Group:pantry 5 werkruimte MB BB:...) | Reference Level
2860130 | 01 eerste verdieping
4747283 | 02 tweede verdieping

# IfcGroup: Model Group:pantry 6 BSO startruimte, Model Group:pantry 6 BSO startruimte:2860361
Constraints - Origin Level Offset: 0 mm; Reference Level: 01 eerste verdieping
Identity Data - Workset: Workset1
Other - Category: Model Groups; Family: Model Group; Family and Type: Model Group: pantry 6 BSO startruimte; Type: pantry 6 BSO startruimte; Type Id: 3834171
Identity Data(Type) - Workset: Workset1; Type Name: pantry 6 BSO startruimte
Other(Type) - Category: Model Groups; Family Name: Model Group

# IfcMember: Rectangular Mullion:125x125, Rectangular Mullion:125x125:1735148
In: 01 eerste verdieping
Type - PredefinedType: MULLION; Material: RAL 9010 - wit
Type - Constraints - Angle: 0 deg; Offset: 62.5 mm
Type - Materials and Finishes - Material: RAL 9010 - wit
Type - Construction - Corner Mullion: no; Position: Perpendicular to Face; Profile: System Mullion Profile: Rectangular; Thickness: 125 mm
Type - Dimensions - Width on side 1: 62.4 mm; Width on side 2: 62.5 mm
Type - Identity Data - Workset: Family : Curtain Wall Mullions : Rectangular Mullion; SmartRevit_Versie: 2013.2; Type Name: 125x125
Type - Other - Category: Curtain Wall Mullions; Family Name: Rectangular Mullion
Constraints - Level: 01 eerste verdieping
Phasing - Phase Created: 2. nieuwbouw
Dimensions - Area: 0.452938 m2; Length: 1750 mm; Volume: 0.0273219 m3
Identity Data - Workset: Workset1
Other - Family: Rectangular Mullion; Host Id: 1735010; Family and Type: Rectangular Mullion: 125x125; Type: 125x125; Type Id: 1728667
Group: Model Group:BI-20 2865x1750:2532482

# IfcMember: Rectangular Mullion:3x85 (5)
In: 01 eerste verdieping
Type - PredefinedType: MULLION; Material: RAL 9010 - wit
Type - Constraints - Angle: 0 deg; Offset: 62.5 mm
Type - Materials and Finishes - Material: RAL 9010 - wit
Type - Construction - Corner Mullion: no; Position: Perpendicular to Face; Profile: System Mullion Profile: Rectangular; Thickness: 85 mm
Type - Dimensions - Width on side 1: 1.5 mm; Width on side 2: 1.5 mm
Type - Identity Data - Workset: Family : Curtain Wall Mullions : Rectangular Mullion; SmartRevit_Versie: 2013.2; Type Name: 3x85
Type - Other - Category: Curtain Wall Mullions; Family Name: Rectangular Mullion
Constraints - Level: 01 eerste verdieping
Phasing - Phase Created: 2. nieuwbouw
Identity Data - Workset: Workset1
Other - Family: Rectangular Mullion; Host Id: 2082374; Family and Type: Rectangular Mullion: 3x85; Type: 3x85; Type Id: 2753402
Group: Model Group:BI-30:2755094
Name (Rectangular Mullion:3x85:...) | Area (m2) | Length (mm) | Volume (m3)
2082379 | 0.206527 | 2344 | 0.00059772
2082380 | 0.206527 | 2344 | 0.00059772
2755134 | 0.079499 | 900.5 | 0.000229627
2755135 | 0.078927 | 894 | 0.00022797
2755136 | 0.079499 | 900.5 | 0.000229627

# IfcMember: Rectangular Mullion:40x120 railing (152)
Type - PredefinedType: MULLION; Material: staal
Type - Constraints - Angle: 0 deg; Offset: 0 mm
Type - Materials and Finishes - Material: staal
Type - Construction - Corner Mullion: no; Position: Perpendicular to Face; Profile: System Mullion Profile: Rectangular; Thickness: 120 mm
Type - Dimensions - Width on side 1: 20 mm; Width on side 2: 20 mm
Type - Identity Data - Workset: Family : Curtain Wall Mullions : Rectangular Mullion; Type Name: 40x120 railing
Type - Other - Category: Curtain Wall Mullions; Family Name: Rectangular Mullion
Phasing - Phase Created: 2. nieuwbouw
Identity Data - Workset: Workset1
Other - Family: Rectangular Mullion; Family and Type: Rectangular Mullion: 40x120 railing; Type: 40x120 railing; Type Id: 3263895
Name (Rectangular Mullion:40x120 railing:...) | In | Level | Area (m2) | Length (mm) | Volume (m3) | Host Id
3262578 | 01 eerste verdieping | 01 eerste verdieping | 0.0303092 | 165 | 0.000761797 | 3262497
3264852 | 01 eerste verdieping | 01 eerste verdieping | 0.1056 | 630 | 0.003024 | 3262497
3265404 | 01 eerste verdieping | 01 eerste verdieping | 0.150268 | 1000.16 | 0.00433241 | 3262497
3265552 | 01 eerste verdieping | 01 eerste verdieping | 0.150268 | 1000.16 | 0.00433241 | 3262497
3265734 | 01 eerste verdieping | 01 eerste verdieping | 0.1648 | 1000 | 0.0048 | 3262497
3265735 | 01 eerste verdieping | 01 eerste verdieping | 0.0398536 | 224.652 | 0.00104813 | 3262497
3265736 | 01 eerste verdieping | 01 eerste verdieping | 0.16592 | 1007 | 0.0048336 | 3262497
3265776 | 01 eerste verdieping | 01 eerste verdieping | 0.1584 | 960 | 0.004608 | 3262497
3265777 | 01 eerste verdieping | 01 eerste verdieping | 0.1088 | 650 | 0.00312 | 3262497
3265778 | 01 eerste verdieping | 01 eerste verdieping | 0.16592 | 1007 | 0.0048336 | 3262497
3272419 | 01 eerste verdieping | 01 eerste verdieping | 0.1648 | 1000 | 0.0048 | 3262497
3272420 | 01 eerste verdieping | 01 eerste verdieping | 0.1584 | 960 | 0.004608 | 3262497
3272421 | 01 eerste verdieping | 01 eerste verdieping | 0.16592 | 1007 | 0.0048336 | 3262497
3272450 | 01 eerste verdieping | 01 eerste verdieping | 0.1648 | 1000 | 0.0048 | 3262497
3272451 | 01 eerste verdieping | 01 eerste verdieping | 0.1584 | 960 | 0.004608 | 3262497
3272452 | 01 eerste verdieping | 01 eerste verdieping | 0.16592 | 1007 | 0.0048336 | 3262497
3272606 | 01 eerste verdieping | 01 eerste verdieping | 0.150268 | 1000.16 | 0.00433241 | 3262497
3272647 | 01 eerste verdieping | 01 eerste verdieping | 0.150268 | 1000.16 | 0.00433241 | 3262497
3272686 | 01 eerste verdieping | 01 eerste verdieping | 0.150268 | 1000.16 | 0.00433241 | 3262497
4725173 | 01 eerste verdieping | 01 eerste verdieping | 0.160118 | 1000.16 | 0.0045666 | 3262497
4842577 | 01 eerste verdieping | 01 eerste verdieping | 0.0746694 | 445.195 | 0.00208688 | 3262497
4842578 | 01 eerste verdieping | 01 eerste verdieping | 0.166863 | 1018.46 | 0.0048584 | 3262497
4842579 | 01 eerste verdieping | 01 eerste verdieping | 0.199954 | 1219.71 | 0.00585461 | 3262497
4842580 | 01 eerste verdieping | 01 eerste verdieping | 0.199954 | 1219.71 | 0.00585461 | 3262497
4842581 | 01 eerste verdieping | 01 eerste verdieping | 0.199954 | 1219.71 | 0.00585461 | 3262497
4842582 | 01 eerste verdieping | 01 eerste verdieping | 0.199954 | 1219.71 | 0.00585461 | 3262497
4842583 | 01 eerste verdieping | 01 eerste verdieping | 0.155788 | 949.24 | 0.00452615 | 3262497
4842584 | 01 eerste verdieping | 01 eerste verdieping | 0.199954 | 1219.71 | 0.00585461 | 3262497
4842585 | 01 eerste verdieping | 01 eerste verdieping | 0.199954 | 1219.71 | 0.00585461 | 3262497
4842586 | 01 eerste verdieping | 01 eerste verdieping | 0.199954 | 1219.71 | 0.00585461 | 3262497
4842587 | 01 eerste verdieping | 01 eerste verdieping | 0.199954 | 1219.71 | 0.00585461 | 3262497
4842588 | 01 eerste verdieping | 01 eerste verdieping | 0.0726847 | 445.195 | 0.0019528 | 3262497
3265968 | 02 tweede verdieping | 02 tweede verdieping | 0.0536 | 305 | 0.001464 | 3265965
3265969 | 02 tweede verdieping | 02 tweede verdieping | 0.1152 | 690 | 0.003312 | 3265965
3265971 | 02 tweede verdieping | 02 tweede verdieping | 0.16592 | 1007 | 0.0048336 | 3265965
3266647 | 02 tweede verdieping | 02 tweede verdieping | 0.1248 | 750 | 0.0036 | 3265965
3266648 | 02 tweede verdieping | 02 tweede verdieping | 0.1584 | 960 | 0.004608 | 3265965
3266649 | 02 tweede verdieping | 02 tweede verdieping | 0.16592 | 1007 | 0.0048336 | 3265965
3266723 | 02 tweede verdieping | 02 tweede verdieping | 0.1648 | 1000 | 0.0048 | 3265965
3266724 | 02 tweede verdieping | 02 tweede verdieping | 0.1584 | 960 | 0.004608 | 3265965
3266725 | 02 tweede verdieping | 02 tweede verdieping | 0.16592 | 1007 | 0.0048336 | 3265965
3266743 | 02 tweede verdieping | 02 tweede verdieping | 0.1648 | 1000 | 0.0048 | 3265965
3266744 | 02 tweede verdieping | 02 tweede verdieping | 0.1584 | 960 | 0.004608 | 3265965
3266745 | 02 tweede verdieping | 02 tweede verdieping | 0.16592 | 1007 | 0.0048336 | 3265965
3272203 | 02 tweede verdieping | 02 tweede verdieping | 0.1584 | 960 | 0.004608 | 3265965
3272204 | 02 tweede verdieping | 02 tweede verdieping | 0.1648 | 1000 | 0.0048 | 3265965
3272205 | 02 tweede verdieping | 02 tweede verdieping | 0.1584 | 960 | 0.004608 | 3265965
3272206 | 02 tweede verdieping | 02 tweede verdieping | 0.1648 | 1000 | 0.0048 | 3265965
3272207 | 02 tweede verdieping | 02 tweede verdieping | 0.16592 | 1007 | 0.0048336 | 3265965
3272208 | 02 tweede verdieping | 02 tweede verdieping | 0.16592 | 1007 | 0.0048336 | 3265965
3272321 | 02 tweede verdieping | 02 tweede verdieping | 0.1648 | 1000 | 0.0048 | 3265965
3272322 | 02 tweede verdieping | 02 tweede verdieping | 0.1584 | 960 | 0.004608 | 3265965
3272323 | 02 tweede verdieping | 02 tweede verdieping | 0.16592 | 1007 | 0.0048336 | 3265965
3272342 | 02 tweede verdieping | 02 tweede verdieping | 0.1648 | 1000 | 0.0048 | 3265965
3272343 | 02 tweede verdieping | 02 tweede verdieping | 0.0504 | 285 | 0.001368 | 3265965
3272344 | 02 tweede verdieping | 02 tweede verdieping | 0.16592 | 1007 | 0.0048336 | 3265965
3270775 | 02 tweede verdieping | 02 tweede verdieping | 0.0712 | 415 | 0.001992 | 3270773
3270776 | 02 tweede verdieping | 02 tweede verdieping | 0.0366536 | 204.652 | 0.000952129 | 3270773
3270778 | 02 tweede verdieping | 02 tweede verdieping | 0.160118 | 1000.16 | 0.0045666 | 3270773
3273205 | 02 tweede verdieping | 02 tweede verdieping | 0.0271092 | 145 | 0.000665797 | 3270773
3273206 | 02 tweede verdieping | 02 tweede verdieping | 0.068 | 395 | 0.001896 | 3270773
3273207 | 02 tweede verdieping | 02 tweede verdieping | 0.16592 | 1007 | 0.0048336 | 3270773
3273263 | 02 tweede verdieping | 02 tweede verdieping | 0.150268 | 1000.16 | 0.00433241 | 3270773
4842727 | 02 tweede verdieping | 02 tweede verdieping | 0.166863 | 1018.46 | 0.0048584 | 3270773
4842728 | 02 tweede verdieping | 02 tweede verdieping | 0.0756451 | 451.293 | 0.00211616 | 3270773
4842729 | 02 tweede verdieping | 02 tweede verdieping | 0.0736605 | 451.293 | 0.00198207 | 3270773
4842730 | 02 tweede verdieping | 02 tweede verdieping | 0.155788 | 949.24 | 0.00452615 | 3270773
3270781 | 02 tweede verdieping | 02 tweede verdieping | 0.0515656 | 292.285 | 0.00140297 | 3270779
3270782 | 02 tweede verdieping | 02 tweede verdieping | 0.0483656 | 272.285 | 0.00130697 | 3270779
3273340 | 02 tweede verdieping | 02 tweede verdieping | 0.0515656 | 292.285 | 0.00140297 | 3270779
3273341 | 02 tweede verdieping | 02 tweede verdieping | 0.0483656 | 272.285 | 0.00130697 | 3270779
3273342 | 02 tweede verdieping | 02 tweede verdieping | 0.16592 | 1007 | 0.0048336 | 3270779
3270787 | 02 tweede verdieping | 02 tweede verdieping | 0.1088 | 650 | 0.00312 | 3270785
3270788 | 02 tweede verdieping | 02 tweede verdieping | 0.0648 | 375 | 0.0018 | 3270785
3270894 | 02 tweede verdieping | 02 tweede verdieping | 0.1648 | 1000 | 0.0048 | 3270785
3270895 | 02 tweede verdieping | 02 tweede verdieping | 0.1584 | 960 | 0.004608 | 3270785
3270896 | 02 tweede verdieping | 02 tweede verdieping | 0.16592 | 1007 | 0.0048336 | 3270785
3270899 | 02 tweede verdieping | 02 tweede verdieping | 0.1648 | 1000 | 0.0048 | 3270785
3270900 | 02 tweede verdieping | 02 tweede verdieping | 0.1584 | 960 | 0.004608 | 3270785
3270901 | 02 tweede verdieping | 02 tweede verdieping | 0.16592 | 1007 | 0.0048336 | 3270785
3270904 | 02 tweede verdieping | 02 tweede verdieping | 0.1648 | 1000 | 0.0048 | 3270785
3270905 | 02 tweede verdieping | 02 tweede verdieping | 0.1584 | 960 | 0.004608 | 3270785
3270906 | 02 tweede verdieping | 02 tweede verdieping | 0.16592 | 1007 | 0.0048336 | 3270785
3270909 | 02 tweede verdieping | 02 tweede verdieping | 0.1648 | 1000 | 0.0048 | 3270785
3270910 | 02 tweede verdieping | 02 tweede verdieping | 0.1584 | 960 | 0.004608 | 3270785
3270911 | 02 tweede verdieping | 02 tweede verdieping | 0.16592 | 1007 | 0.0048336 | 3270785
3270914 | 02 tweede verdieping | 02 tweede verdieping | 0.1648 | 1000 | 0.0048 | 3270785
3270915 | 02 tweede verdieping | 02 tweede verdieping | 0.1584 | 960 | 0.004608 | 3270785
3270916 | 02 tweede verdieping | 02 tweede verdieping | 0.16592 | 1007 | 0.0048336 | 3270785
3270919 | 02 tweede verdieping | 02 tweede verdieping | 0.1648 | 1000 | 0.0048 | 3270785
3270920 | 02 tweede verdieping | 02 tweede verdieping | 0.1584 | 960 | 0.004608 | 3270785
3270921 | 02 tweede verdieping | 02 tweede verdieping | 0.16592 | 1007 | 0.0048336 | 3270785
3270924 | 02 tweede verdieping | 02 tweede verdieping | 0.1648 | 1000 | 0.0048 | 3270785
3270925 | 02 tweede verdieping | 02 tweede verdieping | 0.1584 | 960 | 0.004608 | 3270785
3270926 | 02 tweede verdieping | 02 tweede verdieping | 0.16592 | 1007 | 0.0048336 | 3270785
3270929 | 02 tweede verdieping | 02 tweede verdieping | 0.1648 | 1000 | 0.0048 | 3270785
3270930 | 02 tweede verdieping | 02 tweede verdieping | 0.1584 | 960 | 0.004608 | 3270785
3270931 | 02 tweede verdieping | 02 tweede verdieping | 0.16592 | 1007 | 0.0048336 | 3270785
3270934 | 02 tweede verdieping | 02 tweede verdieping | 0.1648 | 1000 | 0.0048 | 3270785
3270935 | 02 tweede verdieping | 02 tweede verdieping | 0.1584 | 960 | 0.004608 | 3270785
3270936 | 02 tweede verdieping | 02 tweede verdieping | 0.16592 | 1007 | 0.0048336 | 3270785
3270939 | 02 tweede verdieping | 02 tweede verdieping | 0.1648 | 1000 | 0.0048 | 3270785
3270940 | 02 tweede verdieping | 02 tweede verdieping | 0.1584 | 960 | 0.004608 | 3270785
3270941 | 02 tweede verdieping | 02 tweede verdieping | 0.16592 | 1007 | 0.0048336 | 3270785
3272813 | 02 tweede verdieping | 02 tweede verdieping | 0.1584 | 960 | 0.004608 | 3270785
3272814 | 02 tweede verdieping | 02 tweede verdieping | 0.1648 | 1000 | 0.0048 | 3270785
3272815 | 02 tweede verdieping | 02 tweede verdieping | 0.1584 | 960 | 0.004608 | 3270785
3272816 | 02 tweede verdieping | 02 tweede verdieping | 0.1648 | 1000 | 0.0048 | 3270785
3272817 | 02 tweede verdieping | 02 tweede verdieping | 0.16592 | 1007 | 0.0048336 | 3270785
3272818 | 02 tweede verdieping | 02 tweede verdieping | 0.16592 | 1007 | 0.0048336 | 3270785
3272849 | 02 tweede verdieping | 02 tweede verdieping | 0.1648 | 1000 | 0.0048 | 3270785
3272850 | 02 tweede verdieping | 02 tweede verdieping | 0.1056 | 630 | 0.003024 | 3270785
3272851 | 02 tweede verdieping | 02 tweede verdieping | 0.16592 | 1007 | 0.0048336 | 3270785
3272900 | 02 tweede verdieping | 02 tweede verdieping | 0.1584 | 960 | 0.004608 | 3270785
3272901 | 02 tweede verdieping | 02 tweede verdieping | 0.1648 | 1000 | 0.0048 | 3270785
3272902 | 02 tweede verdieping | 02 tweede verdieping | 0.1584 | 960 | 0.004608 | 3270785
3272903 | 02 tweede verdieping | 02 tweede verdieping | 0.1648 | 1000 | 0.0048 | 3270785
3272904 | 02 tweede verdieping | 02 tweede verdieping | 0.1584 | 960 | 0.004608 | 3270785
3272905 | 02 tweede verdieping | 02 tweede verdieping | 0.1648 | 1000 | 0.0048 | 3270785
3272906 | 02 tweede verdieping | 02 tweede verdieping | 0.1584 | 960 | 0.004608 | 3270785
3272907 | 02 tweede verdieping | 02 tweede verdieping | 0.1648 | 1000 | 0.0048 | 3270785
3272908 | 02 tweede verdieping | 02 tweede verdieping | 0.1584 | 960 | 0.004608 | 3270785
3272909 | 02 tweede verdieping | 02 tweede verdieping | 0.1648 | 1000 | 0.0048 | 3270785
3272910 | 02 tweede verdieping | 02 tweede verdieping | 0.16592 | 1007 | 0.0048336 | 3270785
3272911 | 02 tweede verdieping | 02 tweede verdieping | 0.16592 | 1007 | 0.0048336 | 3270785
3272912 | 02 tweede verdieping | 02 tweede verdieping | 0.16592 | 1007 | 0.0048336 | 3270785
3272913 | 02 tweede verdieping | 02 tweede verdieping | 0.16592 | 1007 | 0.0048336 | 3270785
3272914 | 02 tweede verdieping | 02 tweede verdieping | 0.16592 | 1007 | 0.0048336 | 3270785
3272944 | 02 tweede verdieping | 02 tweede verdieping | 0.1584 | 960 | 0.004608 | 3270785
3272945 | 02 tweede verdieping | 02 tweede verdieping | 0.1648 | 1000 | 0.0048 | 3270785
3272946 | 02 tweede verdieping | 02 tweede verdieping | 0.16592 | 1007 | 0.0048336 | 3270785
3272984 | 02 tweede verdieping | 02 tweede verdieping | 0.1584 | 960 | 0.004608 | 3270785
3272985 | 02 tweede verdieping | 02 tweede verdieping | 0.1648 | 1000 | 0.0048 | 3270785
3272986 | 02 tweede verdieping | 02 tweede verdieping | 0.16592 | 1007 | 0.0048336 | 3270785
3273006 | 02 tweede verdieping | 02 tweede verdieping | 0.1584 | 960 | 0.004608 | 3270785
3273007 | 02 tweede verdieping | 02 tweede verdieping | 0.068 | 395 | 0.001896 | 3270785
3273008 | 02 tweede verdieping | 02 tweede verdieping | 0.16592 | 1007 | 0.0048336 | 3270785
3270791 | 02 tweede verdieping | 02 tweede verdieping | 0.1248 | 750 | 0.0036 | 3270789
3270792 | 02 tweede verdieping | 02 tweede verdieping | 0.0224 | 110 | 0.000528 | 3270789
3270793 | 02 tweede verdieping | 02 tweede verdieping | 0.16592 | 1007 | 0.0048336 | 3270789
3270944 | 02 tweede verdieping | 02 tweede verdieping | 0.1648 | 1000 | 0.0048 | 3270789
3270945 | 02 tweede verdieping | 02 tweede verdieping | 0.1584 | 960 | 0.004608 | 3270789
3270946 | 02 tweede verdieping | 02 tweede verdieping | 0.16592 | 1007 | 0.0048336 | 3270789
3270949 | 02 tweede verdieping | 02 tweede verdieping | 0.1648 | 1000 | 0.0048 | 3270789
3270950 | 02 tweede verdieping | 02 tweede verdieping | 0.1152 | 690 | 0.003312 | 3270789
3270951 | 02 tweede verdieping | 02 tweede verdieping | 0.16592 | 1007 | 0.0048336 | 3270789
3273085 | 02 tweede verdieping | 02 tweede verdieping | 0.1584 | 960 | 0.004608 | 3270789
3273086 | 02 tweede verdieping | 02 tweede verdieping | 0.1648 | 1000 | 0.0048 | 3270789
3273087 | 02 tweede verdieping | 02 tweede verdieping | 0.16592 | 1007 | 0.0048336 | 3270789
3273102 | 02 tweede verdieping | 02 tweede verdieping | 0.1584 | 960 | 0.004608 | 3270789
3273103 | 02 tweede verdieping | 02 tweede verdieping | 0.0256 | 130 | 0.000624 | 3270789
3273104 | 02 tweede verdieping | 02 tweede verdieping | 0.16592 | 1007 | 0.0048336 | 3270789

# IfcMember: Rectangular Mullion:40x85 (3)
In: 01 eerste verdieping
Type - PredefinedType: MULLION; Material: RAL 9010 - wit
Type - Constraints - Angle: 0 deg; Offset: 62.5 mm
Type - Materials and Finishes - Material: RAL 9010 - wit
Type - Construction - Corner Mullion: no; Position: Perpendicular to Face; Profile: System Mullion Profile: Rectangular; Thickness: 85 mm
Type - Dimensions - Width on side 1: 20 mm; Width on side 2: 20 mm
Type - Identity Data - Workset: Family : Curtain Wall Mullions : Rectangular Mullion; SmartRevit_Versie: 2013.2; Type Name: 40x85
Type - Other - Category: Curtain Wall Mullions; Family Name: Rectangular Mullion
Constraints - Level: 01 eerste verdieping
Phasing - Phase Created: 2. nieuwbouw
Identity Data - Workset: Workset1
Other - Family: Rectangular Mullion; Family and Type: Rectangular Mullion: 40x85; Host Id: 2082374; Type: 40x85; Type Id: 2753400
Group: Model Group:BI-30:2755094
Name (Rectangular Mullion:40x85:...) | Area (m2) | Length (mm) | Volume (m3)
2082377 | 0.115962 | 900.5 | 0.0030617
2082567 | 0.115962 | 900.5 | 0.0030617
2082643 | 0.11515 | 894 | 0.0030396

# IfcMember: Rectangular Mullion:67x125 (95)
Type - PredefinedType: MULLION; Material: RAL 9010 - wit
Type - Constraints - Angle: 0 deg; Offset: 62.5 mm
Type - Materials and Finishes - Material: RAL 9010 - wit
Type - Construction - Corner Mullion: no; Position: Perpendicular to Face; Profile: System Mullion Profile: Rectangular; Thickness: 125 mm
Type - Dimensions - Width on side 1: 33.5 mm; Width on side 2: 33.5 mm
Type - Identity Data - Workset: Family : Curtain Wall Mullions : Rectangular Mullion; SmartRevit_Versie: 2013.2; Type Name: 67x125
Type - Other - Category: Curtain Wall Mullions; Family Name: Rectangular Mullion
Phasing - Phase Created: 2. nieuwbouw
Identity Data - Workset: Workset1
Other - Family: Rectangular Mullion; Family and Type: Rectangular Mullion: 67x125; Type: 67x125; Type Id: 1227223
Name (Rectangular Mullion:67x125:...) | In | Level | Area (m2) | Length (mm) | Volume (m3) | Host Id | Group
1367979 | 00 begane grond | 00 begane grond | 0.469175 | 2400 | 0.0201 | 1367977 | Model Group:BI-04bw 2400x2387:1367983
1367980 | 00 begane grond | 00 begane grond | 0.469175 | 2400 | 0.0201 | 1367977 | Model Group:BI-04bw 2400x2387:1367983
1367981 | 00 begane grond | 00 begane grond | 0.440951 | 2253 | 0.0188689 | 1367977 | Model Group:BI-04bw 2400x2387:1367983
1367982 | 00 begane grond | 00 begane grond | 0.440951 | 2253 | 0.0188689 | 1367977 | Model Group:BI-04bw 2400x2387:1367983
1420136 | 01 eerste verdieping | 01 eerste verdieping | 0.469175 | 2400 | 0.0201 | 1420134 | Model Group:BI-04w 2400x2387:1420140
1420137 | 01 eerste verdieping | 01 eerste verdieping | 0.469175 | 2400 | 0.0201 | 1420134 | Model Group:BI-04w 2400x2387:1420140
1420138 | 01 eerste verdieping | 01 eerste verdieping | 0.440951 | 2253 | 0.0188689 | 1420134 | Model Group:BI-04w 2400x2387:1420140
1420139 | 01 eerste verdieping | 01 eerste verdieping | 0.440951 | 2253 | 0.0188689 | 1420134 | Model Group:BI-04w 2400x2387:1420140
1420370 | 01 eerste verdieping | 01 eerste verdieping | 0.358775 | 1825 | 0.0152844 | 1420368 | Model Group:BI-25bw 1825x2387:1420374
1420371 | 01 eerste verdieping | 01 eerste verdieping | 0.358775 | 1825 | 0.0152844 | 1420368 | Model Group:BI-25bw 1825x2387:1420374
1420372 | 01 eerste verdieping | 01 eerste verdieping | 0.440951 | 2253 | 0.0188689 | 1420368 | Model Group:BI-25bw 1825x2387:1420374
1420373 | 01 eerste verdieping | 01 eerste verdieping | 0.440951 | 2253 | 0.0188689 | 1420368 | Model Group:BI-25bw 1825x2387:1420374
1612558 | 00 begane grond | 00 begane grond | 0.197111 | 983 | 0.00823263 | 1612555 | Model Group:BI-10 4215x2800:2522162
1612559 | 00 begane grond | 00 begane grond | 0.453047 | 2316 | 0.0193965 | 1612555 | Model Group:BI-10 4215x2800:2522162
1612560 | 00 begane grond | 00 begane grond | 0.460247 | 2353.5 | 0.0197106 | 1612555 | Model Group:BI-10 4215x2800:2522162
1612561 | 00 begane grond | 00 begane grond | 0.081239 | 379.5 | 0.00317831 | 1612555 | Model Group:BI-10 4215x2800:2522162
1612833 | 00 begane grond | 00 begane grond | 0.446615 | 2282.5 | 0.0191159 | 1612555 | Model Group:BI-10 4215x2800:2522162
1612835 | 00 begane grond | 00 begane grond | 0.447383 | 2286.5 | 0.0191494 | 1612555 | Model Group:BI-10 4215x2800:2522162
1612982 | 00 begane grond | 00 begane grond | 0.190679 | 949.5 | 0.00795206 | 1612555 | Model Group:BI-10 4215x2800:2522162
1613152 | 00 begane grond | 00 begane grond | 0.081239 | 379.5 | 0.00317831 | 1612555 | Model Group:BI-10 4215x2800:2522162
1613153 | 00 begane grond | 00 begane grond | 0.447383 | 2286.5 | 0.0191494 | 1612555 | Model Group:BI-10 4215x2800:2522162
1613156 | 00 begane grond | 00 begane grond | 0.184247 | 916 | 0.0076715 | 1612555 | Model Group:BI-10 4215x2800:2522162
1613157 | 00 begane grond | 00 begane grond | 0.184247 | 916 | 0.0076715 | 1612555 | Model Group:BI-10 4215x2800:2522162
1613159 | 00 begane grond | 00 begane grond | 0.081239 | 379.5 | 0.00317831 | 1612555 | Model Group:BI-10 4215x2800:2522162
1729469 | 02 tweede verdieping | 02 tweede verdieping | 0.197111 | 983 | 0.00823263 | 1729467 | Model Group:BI-28:2534707
1729472 | 02 tweede verdieping | 02 tweede verdieping | 0.081239 | 379.5 | 0.00317831 | 1729467 | Model Group:BI-28:2534707
1729484 | 02 tweede verdieping | 02 tweede verdieping | 0.197111 | 983 | 0.00823263 | 1729467 | Model Group:BI-28:2534707
1729494 | 02 tweede verdieping | 02 tweede verdieping | 0.081239 | 379.5 | 0.00317831 | 1729467 | Model Group:BI-28:2534707
1729496 | 02 tweede verdieping | 02 tweede verdieping | 0.184247 | 916 | 0.0076715 | 1729467 | Model Group:BI-28:2534707
1729498 | 02 tweede verdieping | 02 tweede verdieping | 0.184247 | 916 | 0.0076715 | 1729467 | Model Group:BI-28:2534707
1732567 | 02 tweede verdieping | 02 tweede verdieping | 0.460247 | 2353.5 | 0.0197106 | 1729467 | Model Group:BI-28:2534707
1732648 | 02 tweede verdieping | 02 tweede verdieping | 0.460247 | 2353.5 | 0.0197106 | 1729467 | Model Group:BI-28:2534707
1730036 | 01 eerste verdieping | 01 eerste verdieping | 0.201143 | 1004 | 0.0084085 | 1730033 | Model Group:BI-22 1965x2550:2532537
1730038 | 01 eerste verdieping | 01 eerste verdieping | 0.485111 | 2483 | 0.0207951 | 1730033 | Model Group:BI-22 1965x2550:2532537
1730039 | 01 eerste verdieping | 01 eerste verdieping | 0.485111 | 2483 | 0.0207951 | 1730033 | Model Group:BI-22 1965x2550:2532537
1730381 | 01 eerste verdieping | 01 eerste verdieping | 0.201143 | 1004 | 0.0084085 | 1730033 | Model Group:BI-22 1965x2550:2532537
1731564 | 02 tweede verdieping | 02 tweede verdieping | 0.118206 | 625.5 | 0.00471512 | 1731562 | Model Group:BI-27 2500x1700:2534618
1731565 | 02 tweede verdieping | 02 tweede verdieping | 0.391857 | 1997.3 | 0.0167274 | 1731562 | Model Group:BI-27 2500x1700:2534618
1731566 | 02 tweede verdieping | 02 tweede verdieping | 0.318647 | 1616 | 0.013534 | 1731562 | Model Group:BI-27 2500x1700:2534618
1731569 | 02 tweede verdieping | 02 tweede verdieping | 0.391857 | 1997.3 | 0.0167274 | 1731562 | Model Group:BI-27 2500x1700:2534618
1731570 | 02 tweede verdieping | 02 tweede verdieping | 0.118206 | 625.5 | 0.00471513 | 1731562 | Model Group:BI-27 2500x1700:2534618
1731571 | 02 tweede verdieping | 02 tweede verdieping | 0.318647 | 1616 | 0.013534 | 1731562 | Model Group:BI-27 2500x1700:2534618
1731627 | 02 tweede verdieping | 02 tweede verdieping | 0.111774 | 592 | 0.00443456 | 1731625 | Model Group:BI-28:2534707
1731628 | 02 tweede verdieping | 02 tweede verdieping | 0.111774 | 592 | 0.00443456 | 1731625 | Model Group:BI-28:2534707
1734723 | 02 tweede verdieping | 02 tweede verdieping | 0.111774 | 592 | 0.00443456 | 1734721 | Model Group:BI-28:2534707
1734724 | 02 tweede verdieping | 02 tweede verdieping | 0.111774 | 592 | 0.00443456 | 1734721 | Model Group:BI-28:2534707
1735012 | 01 eerste verdieping | 01 eerste verdieping | 0.0148262 | 33.6 | 0.0002814 | 1735010 | Model Group:BI-20 2865x1750:2532482
1735013 | 01 eerste verdieping | 01 eerste verdieping | 0.534455 | 2740 | 0.0229475 | 1735010 | Model Group:BI-20 2865x1750:2532482
1735014 | 01 eerste verdieping | 01 eerste verdieping | 0.318647 | 1616 | 0.013534 | 1735010 | Model Group:BI-20 2865x1750:2532482
1735326 | 01 eerste verdieping | 01 eerste verdieping | 0.528023 | 2706.5 | 0.0226669 | 1735010 | Model Group:BI-20 2865x1750:2532482
1735328 | 01 eerste verdieping | 01 eerste verdieping | 0.318647 | 1616 | 0.013534 | 1735010 | Model Group:BI-20 2865x1750:2532482
1735397 | 01 eerste verdieping | 01 eerste verdieping | 0.512375 | 2625 | 0.0219844 | 1735395 | Model Group:BI-21w 2630x1750:2532641
1735398 | 01 eerste verdieping | 01 eerste verdieping | 0.512375 | 2625 | 0.0219844 | 1735395 | Model Group:BI-21w 2630x1750:2532641
1735399 | 01 eerste verdieping | 01 eerste verdieping | 0.318647 | 1616 | 0.013534 | 1735395 | Model Group:BI-21w 2630x1750:2532641
1735400 | 01 eerste verdieping | 01 eerste verdieping | 0.318647 | 1616 | 0.013534 | 1735395 | Model Group:BI-21w 2630x1750:2532641
1735563 | 01 eerste verdieping | 01 eerste verdieping | 0.354835 | 1804.48 | 0.0151125 | 1735559 | Model Group:BI-23w 4635x2800:2532690
1735565 | 01 eerste verdieping | 01 eerste verdieping | 0.447383 | 2286.5 | 0.0191494 | 1735559 | Model Group:BI-23w 4635x2800:2532690
1735566 | 01 eerste verdieping | 01 eerste verdieping | 0.081239 | 379.5 | 0.00317831 | 1735559 | Model Group:BI-23w 4635x2800:2532690
1735916 | 01 eerste verdieping | 01 eerste verdieping | 0.200471 | 1000.5 | 0.00837919 | 1735559 | Model Group:BI-23w 4635x2800:2532690
1735917 | 01 eerste verdieping | 01 eerste verdieping | 0.341971 | 1737.48 | 0.0145514 | 1735559 | Model Group:BI-23w 4635x2800:2532690
1735918 | 01 eerste verdieping | 01 eerste verdieping | 0.460247 | 2353.5 | 0.0197106 | 1735559 | Model Group:BI-23w 4635x2800:2532690
1736563 | 01 eerste verdieping | 01 eerste verdieping | 0.081239 | 379.5 | 0.00317831 | 1735559 | Model Group:BI-23w 4635x2800:2532690
1736564 | 01 eerste verdieping | 01 eerste verdieping | 0.460247 | 2353.5 | 0.0197106 | 1735559 | Model Group:BI-23w 4635x2800:2532690
1736569 | 01 eerste verdieping | 01 eerste verdieping | 0.081239 | 379.5 | 0.00317831 | 1735559 | Model Group:BI-23w 4635x2800:2532690
2080481 | 01 eerste verdieping | 01 eerste verdieping | 0.181175 | 900 | 0.0075375 | 1735559 | Model Group:BI-23w 4635x2800:2532690
2081492 | 01 eerste verdieping | 01 eerste verdieping | 0.348403 | 1770.98 | 0.014832 | 1735559 | Model Group:BI-23w 4635x2800:2532690
2753119 | 01 eerste verdieping | 01 eerste verdieping | 0.354835 | 1804.48 | 0.0151125 | 1735559 | Model Group:BI-23w 4635x2800:2532690
1940855 | 00 begane grond | 00 begane grond | 0.248375 | 1250 | 0.0104688 | 1940853 | Model Group:BI-31w 1250x2387:1940859
1940856 | 00 begane grond | 00 begane grond | 0.248375 | 1250 | 0.0104688 | 1940853 | Model Group:BI-31w 1250x2387:1940859
1940857 | 00 begane grond | 00 begane grond | 0.440951 | 2253 | 0.0188689 | 1940853 | Model Group:BI-31w 1250x2387:1940859
1940858 | 00 begane grond | 00 begane grond | 0.440951 | 2253 | 0.0188689 | 1940853 | Model Group:BI-31w 1250x2387:1940859
2140321 | 00 begane grond | 00 begane grond | 0.078839 | 367 | 0.00307362 | 2140318 | Model Group:BI-16y 1334x2387:2530506
2140323 | 00 begane grond | 00 begane grond | 0.453815 | 2320 | 0.01943 | 2140318 | Model Group:BI-16y 1334x2387:2530506
2140324 | 00 begane grond | 00 begane grond | 0.453815 | 2320 | 0.01943 | 2140318 | Model Group:BI-16y 1334x2387:2530506
2140884 | 00 begane grond | 00 begane grond | 0.194039 | 967 | 0.00809863 | 2140318 | Model Group:BI-16y 1334x2387:2530506
2534666 | 02 tweede verdieping | 02 tweede verdieping | 0.118206 | 625.5 | 0.00471512 | 2534664 | Model Group:BI-27 2500x1700:2534674
2534667 | 02 tweede verdieping | 02 tweede verdieping | 0.391857 | 1997.3 | 0.0167274 | 2534664 | Model Group:BI-27 2500x1700:2534674
2534668 | 02 tweede verdieping | 02 tweede verdieping | 0.318647 | 1616 | 0.013534 | 2534664 | Model Group:BI-27 2500x1700:2534674
2534671 | 02 tweede verdieping | 02 tweede verdieping | 0.391857 | 1997.3 | 0.0167274 | 2534664 | Model Group:BI-27 2500x1700:2534674
2534672 | 02 tweede verdieping | 02 tweede verdieping | 0.118206 | 625.5 | 0.00471512 | 2534664 | Model Group:BI-27 2500x1700:2534674
2534673 | 02 tweede verdieping | 02 tweede verdieping | 0.318647 | 1616 | 0.013534 | 2534664 | Model Group:BI-27 2500x1700:2534674
2591154 | 00 begane grond | 00 begane grond | 0.469175 | 2400 | 0.0201 | 2591152 | Model Group:BI-04av 2400x2387:1367879
2591155 | 00 begane grond | 00 begane grond | 0.469175 | 2400 | 0.0201 | 2591152 | Model Group:BI-04av 2400x2387:1367879
2591156 | 00 begane grond | 00 begane grond | 0.440951 | 2253 | 0.0188689 | 2591152 | Model Group:BI-04av 2400x2387:1367879
2591157 | 00 begane grond | 00 begane grond | 0.440951 | 2253 | 0.0188689 | 2591152 | Model Group:BI-04av 2400x2387:1367879
3843750 | 00 begane grond | 00 begane grond | 0.238295 | 1197.5 | 0.0100291 | 3843747 | Model Group:BI-02 2198x2387 (members excluded):3844191
3843752 | 00 begane grond | 00 begane grond | 0.062231 | 280.5 | 0.00234919 | 3843747 | Model Group:BI-02 2198x2387 (members excluded):3844191
3843753 | 00 begane grond | 00 begane grond | 0.387095 | 1972.5 | 0.0165197 | 3843747 | Model Group:BI-02 2198x2387 (members excluded):3844191
3843954 | 00 begane grond | 00 begane grond | 0.200471 | 1000.5 | 0.00837919 | 3843747 | Model Group:BI-02 2198x2387 (members excluded):3844191
3843955 | 00 begane grond | 00 begane grond | 0.231863 | 1164 | 0.0097485 | 3843747 | Model Group:BI-02 2198x2387 (members excluded):3844191
3843956 | 00 begane grond | 00 begane grond | 0.075095 | 347.5 | 0.00291031 | 3843747 | Model Group:BI-02 2198x2387 (members excluded):3844191
3844321 | 00 begane grond | 00 begane grond | 0.387095 | 1972.5 | 0.0165197 | 3843747 | Model Group:BI-02 2198x2387 (members excluded):3844191
3844322 | 00 begane grond | 00 begane grond | 0.075095 | 347.5 | 0.00291031 | 3843747 | Model Group:BI-02 2198x2387 (members excluded):3844191
3844324 | 00 begane grond | 00 begane grond | 0.218999 | 1097 | 0.00918737 | 3843747 | Model Group:BI-02 2198x2387 (members excluded):3844191
3844325 | 00 begane grond | 00 begane grond | 0.387095 | 1972.5 | 0.0165197 | 3843747 | Model Group:BI-02 2198x2387 (members excluded):3844191

# IfcMember: Rectangular Mullion:CWM_35x82 (50)
In: 01 eerste verdieping
Type - PredefinedType: MULLION; Material: <Unnamed>, a_kozijn
Type - Constraints - Angle: 28 deg; Offset: -63 mm
Type - Construction - Corner Mullion: no; Position: Perpendicular to Face; Profile: System Mullion Profile: Rectangular; Thickness: 82 mm
Type - Dimensions - Width on side 1: 17.5 mm; Width on side 2: 17.5 mm
Type - Identity Data - Workset: Family : Curtain Wall Mullions : Rectangular Mullion; SmartRevit_Versie: 2019.1; Type Name: CWM_35x82
Type - Other - Category: Curtain Wall Mullions; Family Name: Rectangular Mullion
Material: a_kozijn
Constraints - Level: 01 eerste verdieping
Phasing - Phase Created: 2. nieuwbouw
Identity Data - Workset: Workset1
Other - Family: Rectangular Mullion; Family and Type: Rectangular Mullion: CWM_35x82; Type: CWM_35x82; Type Id: 2177029
Name (Rectangular Mullion:CWM_35x82:...) | Area (m2) | Length (mm) | Volume (m3) | Host Id
2409195 | 0.208088 | 1754 | 0.00503398 | 2409143
2409196 | 0.208088 | 1754 | 0.00503398 | 2409143
2409197 | 0.208088 | 1754 | 0.00503398 | 2409143
2409198 | 0.208088 | 1754 | 0.00503398 | 2409143
2409199 | 0.208088 | 1754 | 0.00503398 | 2409143
2409200 | 0.208088 | 1754 | 0.00503398 | 2409143
2409201 | 0.208088 | 1754 | 0.00503398 | 2409143
2409202 | 0.208088 | 1754 | 0.00503398 | 2409143
2409203 | 0.208088 | 1754 | 0.00503398 | 2409143
2409204 | 0.208088 | 1754 | 0.00503398 | 2409143
2409205 | 0.208088 | 1754 | 0.00503398 | 2409143
2409206 | 0.208088 | 1754 | 0.00503398 | 2409143
2409207 | 0.208088 | 1754 | 0.00503398 | 2409143
2409208 | 0.208088 | 1754 | 0.00503398 | 2409143
2409209 | 0.208088 | 1754 | 0.00503398 | 2409143
2409210 | 0.208088 | 1754 | 0.00503398 | 2409143
2409211 | 0.208088 | 1754 | 0.00503398 | 2409143
2409212 | 0.208088 | 1754 | 0.00503398 | 2409143
2409213 | 0.208088 | 1754 | 0.00503398 | 2409143
2409214 | 0.208088 | 1754 | 0.00503398 | 2409143
2409215 | 0.208088 | 1754 | 0.00503398 | 2409143
2409216 | 0.208088 | 1754 | 0.00503398 | 2409143
2409217 | 0.208088 | 1754 | 0.00503398 | 2409143
2409218 | 0.208088 | 1754 | 0.00503398 | 2409143
2409219 | 0.208088 | 1754 | 0.00503398 | 2409143
2409272 | 0.106766 | 888 | 0.00254856 | 2409220
2409273 | 0.106766 | 888 | 0.00254856 | 2409220
2409274 | 0.106766 | 888 | 0.00254856 | 2409220
2409275 | 0.106766 | 888 | 0.00254856 | 2409220
2409276 | 0.106766 | 888 | 0.00254856 | 2409220
2409277 | 0.106766 | 888 | 0.00254856 | 2409220
2409278 | 0.106766 | 888 | 0.00254856 | 2409220
2409279 | 0.106766 | 888 | 0.00254856 | 2409220
2409280 | 0.106766 | 888 | 0.00254856 | 2409220
2409281 | 0.106766 | 888 | 0.00254856 | 2409220
2409282 | 0.106766 | 888 | 0.00254856 | 2409220
2409283 | 0.106766 | 888 | 0.00254856 | 2409220
2409284 | 0.106766 | 888 | 0.00254856 | 2409220
2409285 | 0.106766 | 888 | 0.00254856 | 2409220
2409286 | 0.106766 | 888 | 0.00254856 | 2409220
2409287 | 0.106766 | 888 | 0.00254856 | 2409220
2409288 | 0.106766 | 888 | 0.00254856 | 2409220
2409289 | 0.106766 | 888 | 0.00254856 | 2409220
2409290 | 0.106766 | 888 | 0.00254856 | 2409220
2409291 | 0.106766 | 888 | 0.00254856 | 2409220
2409292 | 0.106766 | 888 | 0.00254856 | 2409220
2409293 | 0.106766 | 888 | 0.00254856 | 2409220
2409294 | 0.106766 | 888 | 0.00254856 | 2409220
2409295 | 0.106766 | 888 | 0.00254856 | 2409220
2409296 | 0.106766 | 888 | 0.00254856 | 2409220

# IfcMember: Rectangular Mullion:CWM_Jansen Economy 50 bxh=50x60mm (83)
Type - PredefinedType: MULLION; Material: h2_staal_gen
Type - Constraints - Angle: 0 deg; Offset: 0 mm
Type - Materials and Finishes - Material: h2_staal_gen
Type - Construction - Corner Mullion: no; Position: Perpendicular to Face; Profile: System Mullion Profile: Rectangular; Thickness: 50 mm
Type - Dimensions - Width on side 1: 30 mm; Width on side 2: 30 mm
Type - Identity Data - Workset: Family : Curtain Wall Mullions : Rectangular Mullion; SmartRevit_Versie: 2019.1; Type Name: CWM_Jansen Economy 50 bxh=50x60mm
Type - Other - Category: Curtain Wall Mullions; Family Name: Rectangular Mullion
Phasing - Phase Created: 2. nieuwbouw
Identity Data - Workset: Workset1
Other - Family: Rectangular Mullion; Family and Type: Rectangular Mullion: CWM_Jansen Economy 50 bxh=50x60mm; Type: CWM_Jansen Economy 50 bxh=50x60mm; Type Id: 3299010
Name (Rectangular Mullion:CWM_Jansen Economy 50 bxh=50x60mm:...) | In | Level | Area (m2) | Length (mm) | Volume (m3) | Host Id | Group
1470457 | 01 eerste verdieping | 01 eerste verdieping | 0.2164 | 1940 | 0.00582 | 1470455 | Model Group:BI-26bw:2535201
1470458 | 01 eerste verdieping | 01 eerste verdieping | 0.246689 | 2215.35 | 0.00664605 | 1470455 | Model Group:BI-26bw:2535201
1470459 | 01 eerste verdieping | 01 eerste verdieping | 0.255175 | 2292.5 | 0.0068775 | 1470455 | Model Group:BI-26bw:2535201
1470460 | 01 eerste verdieping | 01 eerste verdieping | 0.045625 | 387.5 | 0.0011625 | 1470455 | Model Group:BI-26bw:2535201
1473921 | 01 eerste verdieping | 01 eerste verdieping | 0.275232 | 2474.84 | 0.00742451 | 1470455 | Model Group:BI-26bw:2535201
1473923 | 01 eerste verdieping | 01 eerste verdieping | 0.255175 | 2292.5 | 0.0068775 | 1470455 | Model Group:BI-26bw:2535201
1474085 | 01 eerste verdieping | 01 eerste verdieping | 0.107479 | 949.813 | 0.00284944 | 1470455 | Model Group:BI-26bw:2535201
1474087 | 01 eerste verdieping | 01 eerste verdieping | 0.261775 | 2352.5 | 0.0070575 | 1470455 | Model Group:BI-26bw:2535201
1474302 | 01 eerste verdieping | 01 eerste verdieping | 0.1108 | 980 | 0.00294 | 1470455 | Model Group:BI-26bw:2535201
1475195 | 01 eerste verdieping | 01 eerste verdieping | 0.045625 | 387.5 | 0.0011625 | 1470455 | Model Group:BI-26bw:2535201
1475196 | 01 eerste verdieping | 01 eerste verdieping | 0.261775 | 2352.5 | 0.0070575 | 1470455 | Model Group:BI-26bw:2535201
1475197 | 01 eerste verdieping | 01 eerste verdieping | 0.1042 | 920 | 0.00276 | 1470455 | Model Group:BI-26bw:2535201
1475198 | 01 eerste verdieping | 01 eerste verdieping | 0.104179 | 919.813 | 0.00275944 | 1470455 | Model Group:BI-26bw:2535201
1475201 | 01 eerste verdieping | 01 eerste verdieping | 0.045625 | 387.5 | 0.0011625 | 1470455 | Model Group:BI-26bw:2535201
1475202 | 01 eerste verdieping | 01 eerste verdieping | 0.045625 | 387.5 | 0.0011625 | 1470455 | Model Group:BI-26bw:2535201
1745531 | 01 eerste verdieping | 01 eerste verdieping | 0.2065 | 1850 | 0.00555 | 1470455 | Model Group:BI-26bw:2535201
1745590 | 01 eerste verdieping | 01 eerste verdieping | 0.0096 | 60 | 0.00018 | 1470455 | Model Group:BI-26bw:2535201
1745591 | 01 eerste verdieping | 01 eerste verdieping | 0.271932 | 2444.84 | 0.00733451 | 1470455 | Model Group:BI-26bw:2535201
1745592 | 01 eerste verdieping | 01 eerste verdieping | 0.139675 | 1242.5 | 0.0037275 | 1470455 | Model Group:BI-26bw:2535201
1745593 | 01 eerste verdieping | 01 eerste verdieping | 0.045625 | 387.5 | 0.0011625 | 1470455 | Model Group:BI-26bw:2535201
1745633 | 01 eerste verdieping | 01 eerste verdieping | 0.249989 | 2245.35 | 0.00673605 | 1470455 | Model Group:BI-26bw:2535201
1745634 | 01 eerste verdieping | 01 eerste verdieping | 0.0096 | 60 | 0.00018 | 1470455 | Model Group:BI-26bw:2535201
1745635 | 01 eerste verdieping | 01 eerste verdieping | 0.139675 | 1242.5 | 0.0037275 | 1470455 | Model Group:BI-26bw:2535201
1745636 | 01 eerste verdieping | 01 eerste verdieping | 0.045625 | 387.5 | 0.0011625 | 1470455 | Model Group:BI-26bw:2535201
2694503 | 01 eerste verdieping | 01 eerste verdieping | 0.2164 | 1940 | 0.00582 | 1470455 | Model Group:BI-26bw:2535201
3299653 | 01 eerste verdieping | 01 eerste verdieping | 0.0063 | 30 | 0.00009 | 1470455 | Model Group:BI-26bw:2535201
1476040 | 02 tweede verdieping | 02 tweede verdieping | 0.11135 | 985 | 0.002955 | 1476038 | Model Group:BI-29bw 60min:1476114
1476042 | 02 tweede verdieping | 02 tweede verdieping | 0.1218 | 1080 | 0.00324 | 1476038 | Model Group:BI-29bw 60min:1476114
1476043 | 02 tweede verdieping | 02 tweede verdieping | 0.045625 | 387.5 | 0.0011625 | 1476038 | Model Group:BI-29bw 60min:1476114
1476066 | 02 tweede verdieping | 02 tweede verdieping | 0.138988 | 1236.25 | 0.00370875 | 1476038 | Model Group:BI-29bw 60min:1476114
1476067 | 02 tweede verdieping | 02 tweede verdieping | 0.1218 | 1080 | 0.00324 | 1476038 | Model Group:BI-29bw 60min:1476114
1476071 | 02 tweede verdieping | 02 tweede verdieping | 0.107479 | 949.813 | 0.00284944 | 1476038 | Model Group:BI-29bw 60min:1476114
1476072 | 02 tweede verdieping | 02 tweede verdieping | 0.1218 | 1080 | 0.00324 | 1476038 | Model Group:BI-29bw 60min:1476114
1476075 | 02 tweede verdieping | 02 tweede verdieping | 0.108307 | 957.337 | 0.00287201 | 1476038 | Model Group:BI-29bw 60min:1476114
1476079 | 02 tweede verdieping | 02 tweede verdieping | 0.1108 | 980 | 0.00294 | 1476038 | Model Group:BI-29bw 60min:1476114
1476086 | 02 tweede verdieping | 02 tweede verdieping | 0.045625 | 387.5 | 0.0011625 | 1476038 | Model Group:BI-29bw 60min:1476114
1476087 | 02 tweede verdieping | 02 tweede verdieping | 0.142975 | 1272.5 | 0.0038175 | 1476038 | Model Group:BI-29bw 60min:1476114
1476088 | 02 tweede verdieping | 02 tweede verdieping | 0.1042 | 920 | 0.00276 | 1476038 | Model Group:BI-29bw 60min:1476114
1476089 | 02 tweede verdieping | 02 tweede verdieping | 0.104179 | 919.813 | 0.00275944 | 1476038 | Model Group:BI-29bw 60min:1476114
1476090 | 02 tweede verdieping | 02 tweede verdieping | 0.104746 | 924.963 | 0.00277489 | 1476038 | Model Group:BI-29bw 60min:1476114
1476091 | 02 tweede verdieping | 02 tweede verdieping | 0.045625 | 387.5 | 0.0011625 | 1476038 | Model Group:BI-29bw 60min:1476114
1476092 | 02 tweede verdieping | 02 tweede verdieping | 0.045625 | 387.5 | 0.0011625 | 1476038 | Model Group:BI-29bw 60min:1476114
1477010 | 02 tweede verdieping | 02 tweede verdieping | 0.105007 | 927.337 | 0.00278201 | 1476038 | Model Group:BI-29bw 60min:1476114
1745100 | 02 tweede verdieping | 02 tweede verdieping | 0.0096 | 60 | 0.00018 | 1476038 | Model Group:BI-29bw 60min:1476114
1745102 | 02 tweede verdieping | 02 tweede verdieping | 0.1218 | 1080 | 0.00324 | 1476038 | Model Group:BI-29bw 60min:1476114
1745103 | 02 tweede verdieping | 02 tweede verdieping | 0.045625 | 387.5 | 0.0011625 | 1476038 | Model Group:BI-29bw 60min:1476114
2688951 | 02 tweede verdieping | 02 tweede verdieping | 0.135687 | 1206.25 | 0.00361875 | 1476038 | Model Group:BI-29bw 60min:1476114
2690030 | 02 tweede verdieping | 02 tweede verdieping | 0.142975 | 1272.5 | 0.0038175 | 1476038 | Model Group:BI-29bw 60min:1476114
2690031 | 02 tweede verdieping | 02 tweede verdieping | 0.1218 | 1080 | 0.00324 | 1476038 | Model Group:BI-29bw 60min:1476114
2690034 | 02 tweede verdieping | 02 tweede verdieping | 0.246672 | 2215.2 | 0.0066456 | 1476038 | Model Group:BI-29bw 60min:1476114
2690039 | 02 tweede verdieping | 02 tweede verdieping | 0.142975 | 1272.5 | 0.0038175 | 1476038 | Model Group:BI-29bw 60min:1476114
2690040 | 02 tweede verdieping | 02 tweede verdieping | 0.142975 | 1272.5 | 0.0038175 | 1476038 | Model Group:BI-29bw 60min:1476114
2690041 | 02 tweede verdieping | 02 tweede verdieping | 0.142975 | 1272.5 | 0.0038175 | 1476038 | Model Group:BI-29bw 60min:1476114
2691326 | 02 tweede verdieping | 02 tweede verdieping | 0.249989 | 2245.35 | 0.00673605 | 1476038 | Model Group:BI-29bw 60min:1476114
2691328 | 02 tweede verdieping | 02 tweede verdieping | 0.0063 | 30 | 0.00009 | 1476038 | Model Group:BI-29bw 60min:1476114
2691330 | 02 tweede verdieping | 02 tweede verdieping | 0.139675 | 1242.5 | 0.0037275 | 1476038 | Model Group:BI-29bw 60min:1476114
2691331 | 02 tweede verdieping | 02 tweede verdieping | 0.045625 | 387.5 | 0.0011625 | 1476038 | Model Group:BI-29bw 60min:1476114
2692149 | 02 tweede verdieping | 02 tweede verdieping | 0.138987 | 1236.25 | 0.00370875 | 1476038 | Model Group:BI-29bw 60min:1476114
2692150 | 02 tweede verdieping | 02 tweede verdieping | 0.135688 | 1206.25 | 0.00361875 | 1476038 | Model Group:BI-29bw 60min:1476114
1478231 | 00 begane grond | 00 begane grond | 0.209662 | 1878.75 | 0.00563625 | 1478229 | Model Group:BI-13bw 7515x2800:2527306
1478233 | 00 begane grond | 00 begane grond | 0.257375 | 2312.5 | 0.0069375 | 1478229 | Model Group:BI-13bw 7515x2800:2527306
1478234 | 00 begane grond | 00 begane grond | 0.043425 | 367.5 | 0.0011025 | 1478229 | Model Group:BI-13bw 7515x2800:2527306
1478274 | 00 begane grond | 00 begane grond | 0.043425 | 367.5 | 0.0011025 | 1478229 | Model Group:BI-13bw 7515x2800:2527306
1478275 | 00 begane grond | 00 begane grond | 0.257375 | 2312.5 | 0.0069375 | 1478229 | Model Group:BI-13bw 7515x2800:2527306
1479526 | 00 begane grond | 00 begane grond | 0.109205 | 965.5 | 0.0028965 | 1478229 | Model Group:BI-13bw 7515x2800:2527306
1479527 | 00 begane grond | 00 begane grond | 0.0063 | 30 | 0.00009 | 1478229 | Model Group:BI-13bw 7515x2800:2527306
1479529 | 00 begane grond | 00 begane grond | 0.263975 | 2372.5 | 0.0071175 | 1478229 | Model Group:BI-13bw 7515x2800:2527306
1479530 | 00 begane grond | 00 begane grond | 0.043425 | 367.5 | 0.0011025 | 1478229 | Model Group:BI-13bw 7515x2800:2527306
1480286 | 00 begane grond | 00 begane grond | 0.101395 | 894.5 | 0.0026835 | 1478229 | Model Group:BI-13bw 7515x2800:2527306
1480926 | 00 begane grond | 00 begane grond | 0.105905 | 935.5 | 0.0028065 | 1478229 | Model Group:BI-13bw 7515x2800:2527306
1481156 | 00 begane grond | 00 begane grond | 0.206362 | 1848.75 | 0.00554625 | 1478229 | Model Group:BI-13bw 7515x2800:2527306
1481157 | 00 begane grond | 00 begane grond | 0.209662 | 1878.75 | 0.00563625 | 1478229 | Model Group:BI-13bw 7515x2800:2527306
1481158 | 00 begane grond | 00 begane grond | 0.257375 | 2312.5 | 0.0069375 | 1478229 | Model Group:BI-13bw 7515x2800:2527306
1481159 | 00 begane grond | 00 begane grond | 0.043425 | 367.5 | 0.0011025 | 1478229 | Model Group:BI-13bw 7515x2800:2527306
1939800 | 00 begane grond | 00 begane grond | 0.208425 | 1867.5 | 0.0056025 | 1478229 | Model Group:BI-13bw 7515x2800:2527306
1939802 | 00 begane grond | 00 begane grond | 0.098095 | 864.5 | 0.0025935 | 1478229 | Model Group:BI-13bw 7515x2800:2527306
1939803 | 00 begane grond | 00 begane grond | 0.263975 | 2372.5 | 0.0071175 | 1478229 | Model Group:BI-13bw 7515x2800:2527306
1939804 | 00 begane grond | 00 begane grond | 0.043425 | 367.5 | 0.0011025 | 1478229 | Model Group:BI-13bw 7515x2800:2527306
1941179 | 00 begane grond | 00 begane grond | 0.205125 | 1837.5 | 0.0055125 | 1478229 | Model Group:BI-13bw 7515x2800:2527306
2614211 | 00 begane grond | 00 begane grond | 0.0096 | 60 | 0.00018 | 1478229 | Model Group:BI-13bw 7515x2800:2527306
2614212 | 00 begane grond | 00 begane grond | 0.206362 | 1848.75 | 0.00554625 | 1478229 | Model Group:BI-13bw 7515x2800:2527306
2614213 | 00 begane grond | 00 begane grond | 0.257375 | 2312.5 | 0.0069375 | 1478229 | Model Group:BI-13bw 7515x2800:2527306
2614214 | 00 begane grond | 00 begane grond | 0.043425 | 367.5 | 0.0011025 | 1478229 | Model Group:BI-13bw 7515x2800:2527306

# IfcMember: Rectangular Mullion:RSen_21_CWM_support profile - 40x21-double_gen_duco projects, Rectangular Mullion:RSen_21_CWM_support profile - 40x21-double_gen_duco projects:3619625
In: 01 eerste verdieping
Type - PredefinedType: MULLION; Material: RSen_h4_aluminium
Type - General - Edition number: 1
Type - Constraints - Angle: 0 deg; Offset: 1 mm
Type - Materials and Finishes - Material: RSen_h4_aluminium
Type - Construction - Corner Mullion: no; Position: Perpendicular to Face; Profile: RSen_21_PRF_support profile_gen_duco projects : 40/21-double - gen_ducowall; Thickness: 21 mm
Type - Dimensions - Width on side 1: 0 mm; Width on side 2: 0 mm
Type - Identity Data - Workset: Family : Curtain Wall Mullions : Rectangular Mullion; Assembly Code: 20; Description: CW Mullion; Keynote: 10210; Manufacturer: Duco Projects; Model: 40/21-double; RSen_C_code_article: n\a; RSen_C_code_CBNL: Zonweringsinstallatie; RSen_C_code_CBNL_URL: http://ont.cbnl.org/cb/def/Zonweringsinstallatie; RSen_C_code_ETIM: Gevelstrook; RSen_C_code_ETIM_URL: http://prod.etim-international.com/Class/Details?classId=EC003108&classVersion=2; RSen_C_content_creator: © Witas; RSen_C_content_date_changed: 24/07/2017; RSen_C_content_date_issue: 24/07/2017; RSen_C_content_manual: http://www.witas.be/nl/duco-projects; RSen_C_content_provider: Duco Projects; RSen_C_content_version: 1; RSen_C_description: duco projects_40/21 - ducowall support profile; RSen_C_IFC_version: 2x3; RSen_C_model: DucoWall; RSen_C_revit_version: 2015; RSen_C_type: support profile; RSen_C_type_comments: 40/21; Type Name: RSen_21_CWM_support profile - 40x21-double_gen_duco projects; URL: http://www.duco.eu/en-gb-products/intensive-ventilation/continuous-louvre-walls; WT_I BaseKeynote: 21.1
Type - Other - Category: Curtain Wall Mullions; Family Name: Rectangular Mullion
Classification: B20 Uniformat (Uniformat)
Constraints - Level: 01 eerste verdieping
Phasing - Phase Created: 2. nieuwbouw
Dimensions - Area: 0.126317 m2; Length: 2057 mm; Volume: 0.00172788 m3
Identity Data - Workset: Workset1
Other - Family: Rectangular Mullion; Family and Type: Rectangular Mullion: RSen_21_CWM_support profile - 40x21-double_gen_duco projects; Host Id: 2551643; Type: RSen_21_CWM_support profile - 40x21-double_gen_duco projects; Type Id: 3247633

# IfcMember: Rectangular Mullion:RSen_21_CWM_support profile - 40x70-double - left_gen_duco projects (4)
In: 01 eerste verdieping
Type - PredefinedType: MULLION; Material: RSen_h4_aluminium
Type - General - Edition number: 1
Type - Constraints - Angle: 0 deg; Offset: 1 mm
Type - Materials and Finishes - Material: RSen_h4_aluminium
Type - Construction - Corner Mullion: no; Position: Perpendicular to Face; Profile: RSen_21_PRF_support profile_gen_duco projects : 40/70-double - border left_gen_ducowall; Thickness: 0 mm
Type - Dimensions - Width on side 1: 0 mm; Width on side 2: 0 mm
Type - Identity Data - Workset: Family : Curtain Wall Mullions : Rectangular Mullion; Assembly Code: 20; Description: CW Mullion; Keynote: 10210; Manufacturer: Duco Projects; Model: 40/70-double; RSen_C_code_article: n\a; RSen_C_code_CBNL: Zonweringsinstallatie; RSen_C_code_CBNL_URL: http://ont.cbnl.org/cb/def/Zonweringsinstallatie; RSen_C_code_ETIM: Gevelstrook; RSen_C_code_ETIM_URL: http://prod.etim-international.com/Class/Details?classId=EC003108&classVersion=2; RSen_C_content_creator: © Witas; RSen_C_content_date_changed: 24/07/2017; RSen_C_content_date_issue: 24/07/2017; RSen_C_content_manual: http://www.witas.be/nl/duco-projects; RSen_C_content_provider: Duco Projects; RSen_C_content_version: 1; RSen_C_description: duco projects_40/70 - ducowall support profile; RSen_C_IFC_version: 2x3; RSen_C_model: DucoWall; RSen_C_revit_version: 2015; RSen_C_type: support profile; RSen_C_type_comments: 40/70; Type Name: RSen_21_CWM_support profile - 40x70-double - left_gen_duco projects; URL: http://www.duco.eu/en-gb-products/intensive-ventilation/continuous-louvre-walls; WT_I BaseKeynote: 21.1
Type - Other - Category: Curtain Wall Mullions; Family Name: Rectangular Mullion
Classification: B20 Uniformat (Uniformat)
Constraints - Level: 01 eerste verdieping
Phasing - Phase Created: 2. nieuwbouw
Identity Data - Workset: Workset1
Other - Family: Rectangular Mullion; Family and Type: Rectangular Mullion: RSen_21_CWM_support profile - 40x70-double - left_gen_duco projects; Type: RSen_21_CWM_support profile - 40x70-double - left_gen_duco projects; Type Id: 3450881
Name (Rectangular Mullion:RSen_21_CWM_support profile - 40x70-double - left_gen_duco projects:...) | Area (m2) | Length (mm) | Volume (m3) | Host Id
3257540 | 0.232215 | 2057 | 0.00588302 | 2178599
3258436 | 0.28908 | 2567 | 0.00734162 | 2551798
3258434 | 0.28908 | 2567 | 0.00734162 | 2551890
3258438 | 0.28908 | 2567 | 0.00734162 | 3195265

# IfcMember: Rectangular Mullion:RSen_21_CWM_support profile - 40x70-double - right_gen_duco projects (4)
In: 01 eerste verdieping
Type - PredefinedType: MULLION; Material: RSen_h4_aluminium
Type - General - Edition number: 1
Type - Constraints - Angle: 0 deg; Offset: 1 mm
Type - Materials and Finishes - Material: RSen_h4_aluminium
Type - Construction - Corner Mullion: no; Position: Perpendicular to Face; Thickness: 0 mm; Profile: RSen_21_PRF_support profile_gen_duco projects : 40/70-double - border right_gen_ducowall
Type - Dimensions - Width on side 1: 0 mm; Width on side 2: 0 mm
Type - Identity Data - Workset: Family : Curtain Wall Mullions : Rectangular Mullion; Assembly Code: 20; Description: CW Mullion; Keynote: 10210; Manufacturer: Duco Projects; Model: 40/70-double; RSen_C_code_article: n\a; RSen_C_code_CBNL: Zonweringsinstallatie; RSen_C_code_CBNL_URL: http://ont.cbnl.org/cb/def/Zonweringsinstallatie; RSen_C_code_ETIM: Gevelstrook; RSen_C_code_ETIM_URL: http://prod.etim-international.com/Class/Details?classId=EC003108&classVersion=2; RSen_C_content_creator: © Witas; RSen_C_content_date_changed: 24/07/2017; RSen_C_content_date_issue: 24/07/2017; RSen_C_content_manual: http://www.witas.be/nl/duco-projects; RSen_C_content_provider: Duco Projects; RSen_C_content_version: 1; RSen_C_description: duco projects_40/70 - ducowall support profile; RSen_C_IFC_version: 2x3; RSen_C_model: DucoWall; RSen_C_revit_version: 2015; RSen_C_type: support profile; RSen_C_type_comments: 40/70; Type Name: RSen_21_CWM_support profile - 40x70-double - right_gen_duco projects; URL: http://www.duco.eu/en-gb-products/intensive-ventilation/continuous-louvre-walls; WT_I BaseKeynote: 21.1
Type - Other - Category: Curtain Wall Mullions; Family Name: Rectangular Mullion
Classification: B20 Uniformat (Uniformat)
Constraints - Level: 01 eerste verdieping
Phasing - Phase Created: 2. nieuwbouw
Identity Data - Workset: Workset1
Other - Family: Rectangular Mullion; Family and Type: Rectangular Mullion: RSen_21_CWM_support profile - 40x70-double - right_gen_duco projects; Type: RSen_21_CWM_support profile - 40x70-double - right_gen_duco projects; Type Id: 3450883
Name (Rectangular Mullion:RSen_21_CWM_support profile - 40x70-double - right_gen_duco projects:...) | Area (m2) | Length (mm) | Volume (m3) | Host Id
3257541 | 0.232215 | 2057 | 0.00588302 | 2178599
3258437 | 0.28908 | 2567 | 0.00734162 | 2551798
3258439 | 0.28908 | 2567 | 0.00734162 | 3195265
3256990 | 0.232215 | 2057 | 0.00588302 | 3256902

# IfcMember: Rectangular Mullion:RSen_21_CWM_support profile - 40x70-double_gen_duco projects (2)
In: 01 eerste verdieping
Type - PredefinedType: MULLION; Material: RSen_h4_aluminium
Type - General - Edition number: 1
Type - Constraints - Angle: 0 deg; Offset: 1 mm
Type - Materials and Finishes - Material: RSen_h4_aluminium
Type - Construction - Corner Mullion: no; Position: Perpendicular to Face; Profile: RSen_21_PRF_support profile_gen_duco projects : 40/70-double - gen_ducowall; Thickness: 71.5 mm
Type - Dimensions - Width on side 1: 0 mm; Width on side 2: 0 mm
Type - Identity Data - Workset: Family : Curtain Wall Mullions : Rectangular Mullion; Assembly Code: 20; Description: CW Mullion; Keynote: 10210; Manufacturer: Duco Projects; Model: 40/70-double; RSen_C_code_article: n\a; RSen_C_code_CBNL: Zonweringsinstallatie; RSen_C_code_CBNL_URL: http://ont.cbnl.org/cb/def/Zonweringsinstallatie; RSen_C_code_ETIM: Gevelstrook; RSen_C_code_ETIM_URL: http://prod.etim-international.com/Class/Details?classId=EC003108&classVersion=2; RSen_C_content_creator: © Witas; RSen_C_content_date_changed: 24/07/2017; RSen_C_content_date_issue: 24/07/2017; RSen_C_content_manual: http://www.witas.be/nl/duco-projects; RSen_C_content_provider: Duco Projects; RSen_C_content_version: 1; RSen_C_description: duco projects_40/70 - ducowall support profile; RSen_C_IFC_version: 2x3; RSen_C_model: DucoWall; RSen_C_revit_version: 2015; RSen_C_type: support profile; RSen_C_type_comments: 40/70; Type Name: RSen_21_CWM_support profile - 40x70-double_gen_duco projects; URL: http://www.duco.eu/en-gb-products/intensive-ventilation/continuous-louvre-walls; WT_I BaseKeynote: 21.1
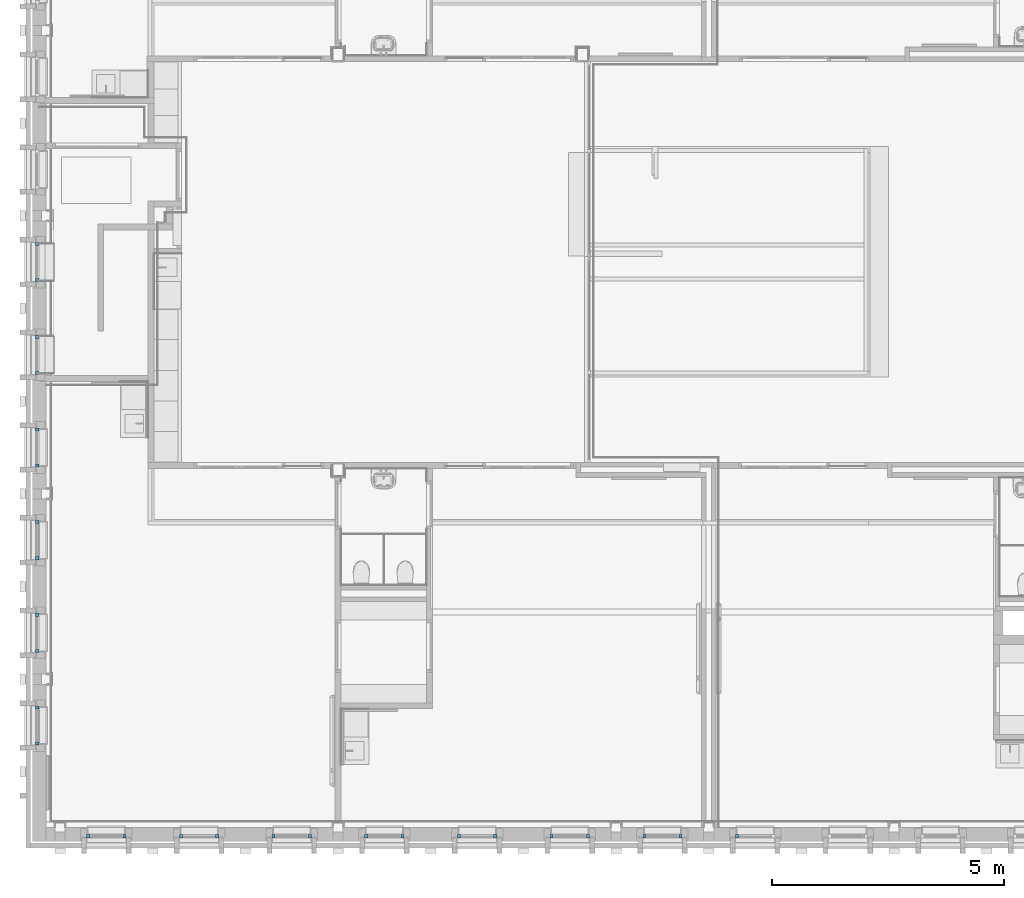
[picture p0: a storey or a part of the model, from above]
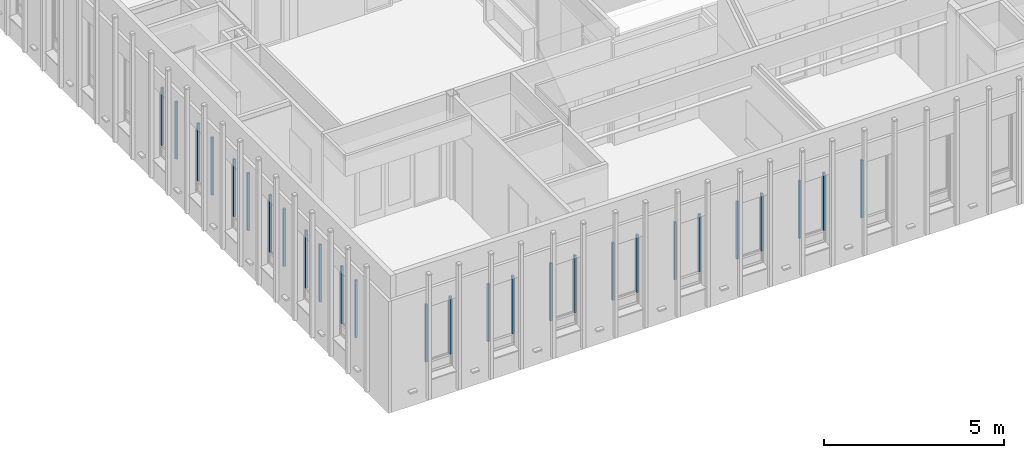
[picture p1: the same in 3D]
Properties of the parts of a building model (IFC2X3), part 13 of 94

# IfcMember: Rectangular Mullion:RSen_21_CWM_support profile - 40x70-double_gen_duco projects (2)
Type - Other - Category: Curtain Wall Mullions; Family Name: Rectangular Mullion
Classification: B20 Uniformat (Uniformat)
Constraints - Level: 01 eerste verdieping
Phasing - Phase Created: 2. nieuwbouw
Identity Data - Workset: Workset1
Other - Family: Rectangular Mullion; Family and Type: Rectangular Mullion: RSen_21_CWM_support profile - 40x70-double_gen_duco projects; Type: RSen_21_CWM_support profile - 40x70-double_gen_duco projects; Type Id: 3450885
Name (Rectangular Mullion:RSen_21_CWM_support profile - 40x70-double_gen_duco projects:...) | Area (m2) | Length (mm) | Volume (m3) | Host Id
3620893 | 0.28908 | 2567 | 0.00734162 | 2551890
3617929 | 0.232215 | 2057 | 0.00588302 | 3256902

# IfcMember: Rectangular Mullion:RT72_Hl_raam (215)
Type - PredefinedType: MULLION; Material: <Unnamed>, a_kozijn
Type - Constraints - Angle: 0 deg; Offset: 0 mm
Type - Construction - Corner Mullion: no; Position: Perpendicular to Face; Profile: BDG_RT72_Vm_raam : Hl_raam; Thickness: 72 mm
Type - Dimensions - Width on side 1: 34 mm; Width on side 2: 34 mm
Type - Identity Data - Workset: Family : Curtain Wall Mullions : Rectangular Mullion; Type Name: RT72_Hl_raam
Type - Other - Category: Curtain Wall Mullions; Family Name: Rectangular Mullion
Material: a_kozijn
Phasing - Phase Created: 2. nieuwbouw
Identity Data - Workset: Workset1
Other - Family: Rectangular Mullion; Family and Type: Rectangular Mullion: RT72_Hl_raam; Type: RT72_Hl_raam; Type Id: 835100
Name (Rectangular Mullion:RT72_Hl_raam:...) | In | Level | Area (m2) | Length (mm) | Volume (m3) | Host Id | Group
870545 | 02 tweede verdieping | 02 tweede verdieping | 0.047036 | 301 | 0.0014737 | 870541 | Model Group:31_2A:870547
879498 | 02 tweede verdieping | 02 tweede verdieping | 0.278316 | 1953 | 0.00956189 | 870541 | Model Group:31_2A:870547
870751 | 02 tweede verdieping | 02 tweede verdieping | 0.047036 | 301 | 0.0014737 | 870747 | Model Group:31_2A:870753
879534 | 02 tweede verdieping | 02 tweede verdieping | 0.278316 | 1953 | 0.00956189 | 870747 | Model Group:31_2A:870753
870864 | 02 tweede verdieping | 02 tweede verdieping | 0.047036 | 301 | 0.0014737 | 870860 | Model Group:31_2A:870866
879552 | 02 tweede verdieping | 02 tweede verdieping | 0.278316 | 1953 | 0.00956189 | 870860 | Model Group:31_2A:870866
871639 | 02 tweede verdieping | 02 tweede verdieping | 0.047036 | 301 | 0.0014737 | 871635 | Model Group:31_2A:871641
878915 | 02 tweede verdieping | 02 tweede verdieping | 0.278316 | 1953 | 0.00956189 | 871635 | Model Group:31_2A:871641
871672 | 02 tweede verdieping | 02 tweede verdieping | 0.047036 | 301 | 0.0014737 | 871668 | Model Group:31_2A:871674
879570 | 02 tweede verdieping | 02 tweede verdieping | 0.278316 | 1953 | 0.00956189 | 871668 | Model Group:31_2A:871674
871923 | 02 tweede verdieping | 02 tweede verdieping | 0.047036 | 301 | 0.0014737 | 871919 | Model Group:31_2A:871925
879588 | 02 tweede verdieping | 02 tweede verdieping | 0.278316 | 1953 | 0.00956189 | 871919 | Model Group:31_2A:871925
871955 | 02 tweede verdieping | 02 tweede verdieping | 0.047036 | 301 | 0.0014737 | 871951 | Model Group:31_2A:871957
879594 | 02 tweede verdieping | 02 tweede verdieping | 0.278316 | 1953 | 0.00956189 | 871951 | Model Group:31_2A:871957
872817 | 02 tweede verdieping | 02 tweede verdieping | 0.047036 | 301 | 0.0014737 | 872813 | Model Group:31_2A:872819
879618 | 02 tweede verdieping | 02 tweede verdieping | 0.278316 | 1953 | 0.00956189 | 872813 | Model Group:31_2A:872819
872883 | 02 tweede verdieping | 02 tweede verdieping | 0.047036 | 301 | 0.0014737 | 872879 | Model Group:31_2A:872885
879630 | 02 tweede verdieping | 02 tweede verdieping | 0.278316 | 1953 | 0.00956189 | 872879 | Model Group:31_2A:872885
872916 | 02 tweede verdieping | 02 tweede verdieping | 0.047036 | 301 | 0.0014737 | 872912 | Model Group:31_2A:872918
879636 | 02 tweede verdieping | 02 tweede verdieping | 0.278316 | 1953 | 0.00956189 | 872912 | Model Group:31_2A:872918
872949 | 02 tweede verdieping | 02 tweede verdieping | 0.047036 | 301 | 0.0014737 | 872945 | Model Group:31_2A:872951
879642 | 02 tweede verdieping | 02 tweede verdieping | 0.278316 | 1953 | 0.00956189 | 872945 | Model Group:31_2A:872951
872982 | 02 tweede verdieping | 02 tweede verdieping | 0.047036 | 301 | 0.0014737 | 872978 | Model Group:31_2A:872984
879648 | 02 tweede verdieping | 02 tweede verdieping | 0.278316 | 1953 | 0.00956189 | 872978 | Model Group:31_2A:872984
873015 | 02 tweede verdieping | 02 tweede verdieping | 0.047036 | 301 | 0.0014737 | 873011 | Model Group:31_2A:873017
879654 | 02 tweede verdieping | 02 tweede verdieping | 0.278316 | 1953 | 0.00956189 | 873011 | Model Group:31_2A:873017
873081 | 02 tweede verdieping | 02 tweede verdieping | 0.047036 | 301 | 0.0014737 | 873077 | Model Group:31_2A:873083
879666 | 02 tweede verdieping | 02 tweede verdieping | 0.278316 | 1953 | 0.00956189 | 873077 | Model Group:31_2A:873083
873512 | 02 tweede verdieping | 02 tweede verdieping | 0.047036 | 301 | 0.0014737 | 873508 | Model Group:31_2A:873514
879702 | 02 tweede verdieping | 02 tweede verdieping | 0.278316 | 1953 | 0.00956189 | 873508 | Model Group:31_2A:873514
873605 | 02 tweede verdieping | 02 tweede verdieping | 0.047036 | 301 | 0.0014737 | 873601 | Model Group:31_2A:873607
879720 | 02 tweede verdieping | 02 tweede verdieping | 0.278316 | 1953 | 0.00956189 | 873601 | Model Group:31_2A:873607
873698 | 02 tweede verdieping | 02 tweede verdieping | 0.047036 | 301 | 0.0014737 | 873694 | Model Group:31_2A:873700
879738 | 02 tweede verdieping | 02 tweede verdieping | 0.278316 | 1953 | 0.00956189 | 873694 | Model Group:31_2A:873700
874670 | 01 eerste verdieping | 01 eerste verdieping | 0.268656 | 1884 | 0.00922406 | 874666 | Model Group:31_1A:874672
874954 | 01 eerste verdieping | 01 eerste verdieping | 0.268656 | 1884 | 0.00922406 | 874950 | Model Group:31_1A:874956
875029 | 01 eerste verdieping | 01 eerste verdieping | 0.268656 | 1884 | 0.00922406 | 875025 | Model Group:31_1A DKD L:875031
875044 | 01 eerste verdieping | 01 eerste verdieping | 0.268656 | 1884 | 0.00922406 | 875040 | Model Group:31_1A:875046
875053 | 01 eerste verdieping | 01 eerste verdieping | 0.268656 | 1884 | 0.00922406 | 875049 | Model Group:31_1A DK R:875055
875272 | 01 eerste verdieping | 01 eerste verdieping | 0.268656 | 1884 | 0.00922406 | 875268 | Model Group:31_1A:875274
875308 | 01 eerste verdieping | 01 eerste verdieping | 0.268656 | 1884 | 0.00922406 | 875304 | Model Group:31_1A DKD R:875310
875380 | 01 eerste verdieping | 01 eerste verdieping | 0.268656 | 1884 | 0.00922406 | 875376 | Model Group:31_1A:875382
876491 | 01 eerste verdieping | 01 eerste verdieping | 0.268656 | 1884 | 0.00922406 | 876487 | Model Group:31_1A:876493
876909 | 01 eerste verdieping | 01 eerste verdieping | 0.268656 | 1884 | 0.00922406 | 876905 | Model Group:31_1A:876911
877026 | 01 eerste verdieping | 01 eerste verdieping | 0.268656 | 1884 | 0.00922406 | 877022 | Model Group:31_1A:877028
877116 | 01 eerste verdieping | 01 eerste verdieping | 0.268656 | 1884 | 0.00922406 | 877112 | Model Group:31_1A:877118
877206 | 01 eerste verdieping | 01 eerste verdieping | 0.268656 | 1884 | 0.00922406 | 877202 | Model Group:31_1A:877208
877521 | 02 tweede verdieping | 02 tweede verdieping | 0.345376 | 2432 | 0.0119071 | 877517 | Model Group:BU-40:2712884
877675 | 02 tweede verdieping | 02 tweede verdieping | 0.038356 | 239 | 0.00117014 | 877517 | Model Group:BU-40:2712884
1483767 | 02 tweede verdieping | 02 tweede verdieping | 0.345376 | 2432 | 0.0119071 | 877517 | Model Group:BU-40:2712884
1483768 | 02 tweede verdieping | 02 tweede verdieping | 0.038356 | 239 | 0.00117014 | 877517 | Model Group:BU-40:2712884
1483874 | 02 tweede verdieping | 02 tweede verdieping | 0.345376 | 2432 | 0.0119071 | 877517 | Model Group:BU-40:2712884
1483875 | 02 tweede verdieping | 02 tweede verdieping | 0.038356 | 239 | 0.00117014 | 877517 | Model Group:BU-40:2712884
1848503 | 02 tweede verdieping | 02 tweede verdieping | 0.345376 | 2432 | 0.0119071 | 877517 | Model Group:BU-40:2712884
1848504 | 02 tweede verdieping | 02 tweede verdieping | 0.038356 | 239 | 0.00117014 | 877517 | Model Group:BU-40:2712884
1848736 | 02 tweede verdieping | 02 tweede verdieping | 0.345376 | 2432 | 0.0119071 | 877517 | Model Group:BU-40:2712884
1848737 | 02 tweede verdieping | 02 tweede verdieping | 0.038356 | 239 | 0.00117014 | 877517 | Model Group:BU-40:2712884
880925 | 01 eerste verdieping | 01 eerste verdieping | 0.268656 | 1884 | 0.00922406 | 880921 | Model Group:31_1A:880927
881686 | 01 eerste verdieping | 01 eerste verdieping | 0.268656 | 1884 | 0.00922406 | 881682 | Model Group:31_1A:881688
881850 | 01 eerste verdieping | 01 eerste verdieping | 0.268656 | 1884 | 0.00922406 | 881846 | Model Group:BU-35:2701985
891678 | 01 eerste verdieping | 01 eerste verdieping | 0.268656 | 1884 | 0.00922406 | 891674 | Model Group:31_1A:891680
891761 | 01 eerste verdieping | 01 eerste verdieping | 0.268656 | 1884 | 0.00922406 | 891757 | Model Group:BU-30:2700215
891790 | 01 eerste verdieping | 01 eerste verdieping | 0.268656 | 1884 | 0.00922406 | 891786 | Model Group:31_1A:891792
891907 | 01 eerste verdieping | 01 eerste verdieping | 0.268656 | 1884 | 0.00922406 | 891903 | Model Group:31_1A:891909
891929 | 01 eerste verdieping | 01 eerste verdieping | 0.268656 | 1884 | 0.00922406 | 891925 | Model Group:31_1A:891931
891979 | 01 eerste verdieping | 01 eerste verdieping | 0.268656 | 1884 | 0.00922406 | 891975 | Model Group:31_1A:891981
892001 | 01 eerste verdieping | 01 eerste verdieping | 0.350976 | 2472 | 0.0121029 | 891997 | Model Group:BU-32:892003
892042 | 00 begane grond | 00 begane grond | 0.331936 | 2336 | 0.0114371 | 892038 | Model Group:BU-07 b900:894363
1826975 | 00 begane grond | 00 begane grond | 0.079936 | 536 | 0.00262426 | 892038 | Model Group:BU-07 b900:894363
894432 | 00 begane grond | 00 begane grond | 0.406976 | 2872 | 0.0140613 | 894428 | Model Group:BU-06 b1800:894434
1220074 | 00 begane grond | 00 begane grond | 0.331936 | 2336 | 0.0114371 | 1220070 | Model Group:BU-08 b2100:1220076
1861256 | 00 begane grond | 00 begane grond | 0.079936 | 536 | 0.00262426 | 1220070 | Model Group:BU-08 b2100:1220076
1220173 | 00 begane grond | 00 begane grond | 0.331936 | 2336 | 0.0114371 | 1220169 | Model Group:BU-09 b1500:1220175
1859846 | 00 begane grond | 00 begane grond | 0.079936 | 536 | 0.00262426 | 1220169 | Model Group:BU-09 b1500:1220175
1220851 | 00 begane grond | 00 begane grond | 0.331936 | 2336 | 0.0114371 | 1220847 | Model Group:BU-11 b3000:1220846
1492357 | 00 begane grond | 00 begane grond | 0.079936 | 536 | 0.00262426 | 1220847 | Model Group:BU-11 b3000:1220846
1300405 | 00 begane grond | 00 begane grond | 0.331936 | 2336 | 0.0114371 | 1300401 | Model Group:BU-07 b900 (members excluded):1300407
1827109 | 00 begane grond | 00 begane grond | 0.079936 | 536 | 0.00262426 | 1300401 | Model Group:BU-07 b900 (members excluded):1300407
1300457 | 00 begane grond | 00 begane grond | 0.331936 | 2336 | 0.0114371 | 1300453 | Model Group:BU-22 b2700:1300414
1490587 | 00 begane grond | 00 begane grond | 0.079936 | 536 | 0.00262426 | 1300453 | Model Group:BU-22 b2700:1300414
1300746 | 00 begane grond | 00 begane grond | 0.331936 | 2336 | 0.0114371 | 1300742 | Model Group:BU-21 b2966:1300741
1491547 | 00 begane grond | 00 begane grond | 0.079936 | 536 | 0.00262426 | 1300742 | Model Group:BU-21 b2966:1300741
1300958 | 00 begane grond | 00 begane grond | 0.331936 | 2336 | 0.0114371 | 1300954 | Model Group:BU-20 b3300:1300930
1492201 | 00 begane grond | 00 begane grond | 0.079936 | 536 | 0.00262426 | 1300954 | Model Group:BU-20 b3300:1300930
1300996 | 00 begane grond | 00 begane grond | 0.331936 | 2336 | 0.0114371 | 1300992 | Model Group:BU-23 b1353:2651710
1899462 | 00 begane grond | 00 begane grond | 0.079936 | 536 | 0.00262426 | 1300992 | Model Group:BU-23 b1353:2651710
1302058 | 01 eerste verdieping | 01 eerste verdieping | 0.353636 | 2491 | 0.0121959 | 1302054 | Model Group:BU-31:891953
1493479 | 00 begane grond | 00 begane grond | 0.331936 | 2336 | 0.0114371 | 1493475 | Model Group:BU-25 b3000:1493474
1493949 | 00 begane grond | 00 begane grond | 0.079936 | 536 | 0.00262426 | 1493475 | Model Group:BU-25 b3000:1493474
1494109 | 00 begane grond | 00 begane grond | 0.331936 | 2336 | 0.0114371 | 1494105 | Model Group:BU-02 b4200:1494104
1494119 | 00 begane grond | 00 begane grond | 0.079936 | 536 | 0.00262426 | 1494105 | Model Group:BU-02 b4200:1494104
1494518 | 00 begane grond | 00 begane grond | 0.331936 | 2336 | 0.0114371 | 1494514 | Model Group:BU-14 b3000:1494513
1494528 | 00 begane grond | 00 begane grond | 0.079936 | 536 | 0.00262426 | 1494514 | Model Group:BU-14 b3000:1494513
1502985 | 00 begane grond | 00 begane grond | 0.331936 | 2336 | 0.0114371 | 1502981 | Model Group:BU-07 b900:1502980
1827115 | 00 begane grond | 00 begane grond | 0.079936 | 536 | 0.00262426 | 1502981 | Model Group:BU-07 b900:1502980
1817353 | 00 begane grond | 00 begane grond | 0.331936 | 2336 | 0.0114371 | 1817349 | Model Group:BU-12 b4200:1817348
1817363 | 00 begane grond | 00 begane grond | 0.079936 | 536 | 0.00262426 | 1817349 | Model Group:BU-12 b4200:1817348
1818873 | 00 begane grond | 00 begane grond | 0.331936 | 2336 | 0.0114371 | 1818869 | Model Group:BU-03 b5800:1818868
1818883 | 00 begane grond | 00 begane grond | 0.079936 | 536 | 0.00262426 | 1818869 | Model Group:BU-03 b5800:1818868
1822155 | 00 begane grond | 00 begane grond | 0.331936 | 2336 | 0.0114371 | 1822151 | Model Group:BU-10 b1800:1822150
1822167 | 00 begane grond | 00 begane grond | 0.079936 | 536 | 0.00262426 | 1822151 | Model Group:BU-10 b1800:1822150
1823302 | 00 begane grond | 00 begane grond | 0.331936 | 2336 | 0.0114371 | 1823298 | Model Group:BU-15 b4200:1823297
1823312 | 00 begane grond | 00 begane grond | 0.079936 | 536 | 0.00262426 | 1823298 | Model Group:BU-15 b4200:1823297
1853996 | 00 begane grond | 00 begane grond | 0.331936 | 2336 | 0.0114371 | 1853992 | Model Group:BU-18 b3017:2651211
1854006 | 00 begane grond | 00 begane grond | 0.079936 | 536 | 0.00262426 | 1853992 | Model Group:BU-18 b3017:2651211
1862279 | 00 begane grond | 00 begane grond | 0.273836 | 1921 | 0.00940522 | 1862275 | Model Group:BU-13 b3300:1862274
1862289 | 00 begane grond | 00 begane grond | 0.083856 | 564 | 0.00276134 | 1862275 | Model Group:BU-13 b3300:1862274
1864618 | 01 eerste verdieping | 01 eerste verdieping | 0.268656 | 1884 | 0.00922406 | 1864614 | Model Group:31_1A SVGD L:1864620
1864936 | 01 eerste verdieping | 01 eerste verdieping | 0.268656 | 1884 | 0.00922406 | 1864932 | Model Group:31_1A DK R:1864938
1864980 | 01 eerste verdieping | 01 eerste verdieping | 0.268656 | 1884 | 0.00922406 | 1864976 | Model Group:31_1A DKD L:1864982
1865005 | 01 eerste verdieping | 01 eerste verdieping | 0.268656 | 1884 | 0.00922406 | 1865001 | Model Group:31_1A DK R:1865007
1865028 | 01 eerste verdieping | 01 eerste verdieping | 0.268656 | 1884 | 0.00922406 | 1865024 | Model Group:31_1A DKD L:1865030
1865344 | 01 eerste verdieping | 01 eerste verdieping | 0.268656 | 1884 | 0.00922406 | 1865340 | Model Group:31_1A DKD R:1865346
1865365 | 01 eerste verdieping | 01 eerste verdieping | 0.268656 | 1884 | 0.00922406 | 1865361 | Model Group:31_1A DK L:1865367
1865572 | 01 eerste verdieping | 01 eerste verdieping | 0.268656 | 1884 | 0.00922406 | 1865568 | Model Group:31_1A DKD R:1865574
1865606 | 01 eerste verdieping | 01 eerste verdieping | 0.268656 | 1884 | 0.00922406 | 1865602 | Model Group:31_1A DKD R:1865608
1865653 | 01 eerste verdieping | 01 eerste verdieping | 0.268656 | 1884 | 0.00922406 | 1865649 | Model Group:31_1A DK L:1865655
1865672 | 01 eerste verdieping | 01 eerste verdieping | 0.268656 | 1884 | 0.00922406 | 1865668 | Model Group:31_1A DK L:1865674
1865779 | 01 eerste verdieping | 01 eerste verdieping | 0.268656 | 1884 | 0.00922406 | 1865775 | Model Group:31_1A DKD R:1865781
1865800 | 01 eerste verdieping | 01 eerste verdieping | 0.268656 | 1884 | 0.00922406 | 1865796 | Model Group:31_1A DK L:1865802
1865921 | 01 eerste verdieping | 01 eerste verdieping | 0.268656 | 1884 | 0.00922406 | 1865917 | Model Group:31_1A DK R:1865923
1865944 | 01 eerste verdieping | 01 eerste verdieping | 0.268656 | 1884 | 0.00922406 | 1865940 | Model Group:31_1A DKD L:1865946
1866080 | 01 eerste verdieping | 01 eerste verdieping | 0.268656 | 1884 | 0.00922406 | 1866076 | Model Group:31_1A DKg R:1866082
1867675 | 02 tweede verdieping | 02 tweede verdieping | 0.047036 | 301 | 0.0014737 | 1867671 | Model Group:31_2A DK R:1867677
1867681 | 02 tweede verdieping | 02 tweede verdieping | 0.278316 | 1953 | 0.00956189 | 1867671 | Model Group:31_2A DK R:1867677
1869343 | 02 tweede verdieping | 02 tweede verdieping | 0.047036 | 301 | 0.0014737 | 1869339 | Model Group:31_2A DK R:1869345
1869348 | 02 tweede verdieping | 02 tweede verdieping | 0.278316 | 1953 | 0.00956189 | 1869339 | Model Group:31_2A DK R:1869345
1869360 | 02 tweede verdieping | 02 tweede verdieping | 0.047036 | 301 | 0.0014737 | 1869356 | Model Group:31_2A DK R:1869362
1869365 | 02 tweede verdieping | 02 tweede verdieping | 0.278316 | 1953 | 0.00956189 | 1869356 | Model Group:31_2A DK R:1869362
1869377 | 02 tweede verdieping | 02 tweede verdieping | 0.047036 | 301 | 0.0014737 | 1869373 | Model Group:31_2A DK R:1869379
1869382 | 02 tweede verdieping | 02 tweede verdieping | 0.278316 | 1953 | 0.00956189 | 1869373 | Model Group:31_2A DK R:1869379
1869394 | 02 tweede verdieping | 02 tweede verdieping | 0.047036 | 301 | 0.0014737 | 1869390 | Model Group:31_2A DK R:1869396
1869399 | 02 tweede verdieping | 02 tweede verdieping | 0.278316 | 1953 | 0.00956189 | 1869390 | Model Group:31_2A DK R:1869396
1869411 | 02 tweede verdieping | 02 tweede verdieping | 0.047036 | 301 | 0.0014737 | 1869407 | Model Group:31_2A DK R:1869413
1869416 | 02 tweede verdieping | 02 tweede verdieping | 0.278316 | 1953 | 0.00956189 | 1869407 | Model Group:31_2A DK R:1869413
1869428 | 02 tweede verdieping | 02 tweede verdieping | 0.047036 | 301 | 0.0014737 | 1869424 | Model Group:31_2A DK R:1869430
1869433 | 02 tweede verdieping | 02 tweede verdieping | 0.278316 | 1953 | 0.00956189 | 1869424 | Model Group:31_2A DK R:1869430
1869445 | 02 tweede verdieping | 02 tweede verdieping | 0.047036 | 301 | 0.0014737 | 1869441 | Model Group:31_2A DK R:1869447
1869450 | 02 tweede verdieping | 02 tweede verdieping | 0.278316 | 1953 | 0.00956189 | 1869441 | Model Group:31_2A DK R:1869447
1869465 | 02 tweede verdieping | 02 tweede verdieping | 0.047036 | 301 | 0.0014737 | 1869461 | Model Group:31_2A DK L:1869467
1869470 | 02 tweede verdieping | 02 tweede verdieping | 0.278316 | 1953 | 0.00956189 | 1869461 | Model Group:31_2A DK L:1869467
1869604 | 02 tweede verdieping | 02 tweede verdieping | 0.047036 | 301 | 0.0014737 | 1869600 | Model Group:31_2A DK L:1869606
1869609 | 02 tweede verdieping | 02 tweede verdieping | 0.278316 | 1953 | 0.00956189 | 1869600 | Model Group:31_2A DK L:1869606
1869621 | 02 tweede verdieping | 02 tweede verdieping | 0.047036 | 301 | 0.0014737 | 1869617 | Model Group:31_2A DK L:1869623
1869626 | 02 tweede verdieping | 02 tweede verdieping | 0.278316 | 1953 | 0.00956189 | 1869617 | Model Group:31_2A DK L:1869623
1869638 | 02 tweede verdieping | 02 tweede verdieping | 0.047036 | 301 | 0.0014737 | 1869634 | Model Group:31_2A DK L:1869640
1869643 | 02 tweede verdieping | 02 tweede verdieping | 0.278316 | 1953 | 0.00956189 | 1869634 | Model Group:31_2A DK L:1869640
1869655 | 02 tweede verdieping | 02 tweede verdieping | 0.047036 | 301 | 0.0014737 | 1869651 | Model Group:31_2A DK L:1869657
1869660 | 02 tweede verdieping | 02 tweede verdieping | 0.278316 | 1953 | 0.00956189 | 1869651 | Model Group:31_2A DK L:1869657
1869672 | 02 tweede verdieping | 02 tweede verdieping | 0.047036 | 301 | 0.0014737 | 1869668 | Model Group:31_2A DK L:1869674
1869677 | 02 tweede verdieping | 02 tweede verdieping | 0.278316 | 1953 | 0.00956189 | 1869668 | Model Group:31_2A DK L:1869674
1869689 | 02 tweede verdieping | 02 tweede verdieping | 0.047036 | 301 | 0.0014737 | 1869685 | Model Group:31_2A DK L:1869691
1869694 | 02 tweede verdieping | 02 tweede verdieping | 0.278316 | 1953 | 0.00956189 | 1869685 | Model Group:31_2A DK L:1869691
1869706 | 02 tweede verdieping | 02 tweede verdieping | 0.047036 | 301 | 0.0014737 | 1869702 | Model Group:31_2A DK L:1869708
1869711 | 02 tweede verdieping | 02 tweede verdieping | 0.278316 | 1953 | 0.00956189 | 1869702 | Model Group:31_2A DK L:1869708
1869725 | 02 tweede verdieping | 02 tweede verdieping | 0.047036 | 301 | 0.0014737 | 1869721 | Model Group:31_2A DK L:1869727
1869730 | 02 tweede verdieping | 02 tweede verdieping | 0.278316 | 1953 | 0.00956189 | 1869721 | Model Group:31_2A DK L:1869727
1869742 | 02 tweede verdieping | 02 tweede verdieping | 0.047036 | 301 | 0.0014737 | 1869738 | Model Group:31_2A DK L:1869744
1869747 | 02 tweede verdieping | 02 tweede verdieping | 0.278316 | 1953 | 0.00956189 | 1869738 | Model Group:31_2A DK L:1869744
1869759 | 02 tweede verdieping | 02 tweede verdieping | 0.047036 | 301 | 0.0014737 | 1869755 | Model Group:31_2A DK R:1869761
1869764 | 02 tweede verdieping | 02 tweede verdieping | 0.278316 | 1953 | 0.00956189 | 1869755 | Model Group:31_2A DK R:1869761
1869776 | 02 tweede verdieping | 02 tweede verdieping | 0.047036 | 301 | 0.0014737 | 1869772 | Model Group:31_2A DK R:1869778
1869781 | 02 tweede verdieping | 02 tweede verdieping | 0.278316 | 1953 | 0.00956189 | 1869772 | Model Group:31_2A DK R:1869778
1869795 | 02 tweede verdieping | 02 tweede verdieping | 0.047036 | 301 | 0.0014737 | 1869791 | Model Group:31_2A DK R:1869797
1869800 | 02 tweede verdieping | 02 tweede verdieping | 0.278316 | 1953 | 0.00956189 | 1869791 | Model Group:31_2A DK R:1869797
1869812 | 02 tweede verdieping | 02 tweede verdieping | 0.047036 | 301 | 0.0014737 | 1869808 | Model Group:31_2A DK R:1869814
1869817 | 02 tweede verdieping | 02 tweede verdieping | 0.278316 | 1953 | 0.00956189 | 1869808 | Model Group:31_2A DK R:1869814
1869829 | 02 tweede verdieping | 02 tweede verdieping | 0.047036 | 301 | 0.0014737 | 1869825 | Model Group:31_2A DK R:1869831
1869834 | 02 tweede verdieping | 02 tweede verdieping | 0.278316 | 1953 | 0.00956189 | 1869825 | Model Group:31_2A DK R:1869831
1869846 | 02 tweede verdieping | 02 tweede verdieping | 0.047036 | 301 | 0.0014737 | 1869842 | Model Group:31_2A DK R:1869848
1869851 | 02 tweede verdieping | 02 tweede verdieping | 0.278316 | 1953 | 0.00956189 | 1869842 | Model Group:31_2A DK R:1869848
1897636 | 00 begane grond | 00 begane grond | 0.331936 | 2336 | 0.0114371 | 1897632 | Model Group:BU-07 b900 (members excluded):1300686
1897640 | 00 begane grond | 00 begane grond | 0.079936 | 536 | 0.00262426 | 1897632 | Model Group:BU-07 b900 (members excluded):1300686
1897650 | 00 begane grond | 00 begane grond | 0.331936 | 2336 | 0.0114371 | 1897646 | Model Group:BU-07 b900 (members excluded):1818605
1897654 | 00 begane grond | 00 begane grond | 0.079936 | 536 | 0.00262426 | 1897646 | Model Group:BU-07 b900 (members excluded):1818605
1898043 | 01 eerste verdieping | 01 eerste verdieping | 0.268656 | 1884 | 0.00922406 | 1898039 | Model Group:31_1A DKD R:1898045
1932983 | 00 begane grond | 00 begane grond | 0.331936 | 2336 | 0.0114371 | 1932979 | Model Group:BU-17 b3000:1900158
1932993 | 00 begane grond | 00 begane grond | 0.079936 | 536 | 0.00262426 | 1932979 | Model Group:BU-17 b3000:1900158
2012529 | 01 eerste verdieping | 01 eerste verdieping | 0.268656 | 1884 | 0.00922406 | 2012525 | Model Group:31_1A DKD L:2012531
2012559 | 01 eerste verdieping | 01 eerste verdieping | 0.268656 | 1884 | 0.00922406 | 2012555 | Model Group:31_1A DKD L:2012561
2012574 | 01 eerste verdieping | 01 eerste verdieping | 0.261656 | 1834 | 0.00897926 | 2012570 | Model Group:BU-38:2702101
2172434 | 01 eerste verdieping | 01 eerste verdieping | 0.278176 | 1952 | 0.00955699 | 2172430 | Model Group:31_1A SVGD R:2172436
2172442 | 01 eerste verdieping | 01 eerste verdieping | 0.268656 | 1884 | 0.00922406 | 2172430 | Model Group:31_1A SVGD R:2172436
3023502 | 01 eerste verdieping | 01 eerste verdieping | 0.268656 | 1884 | 0.00922406 | 2172430 | Model Group:31_1A SVGD R:2172436
2182233 | 03 derde verdieping | 03 derde verdieping | 0.125856 | 864 | 0.00423014 | 2182229 | Model Group:daklicht A1:2182252
2182286 | 03 derde verdieping | 03 derde verdieping | 0.125856 | 864 | 0.00423014 | 2182282 | Model Group:daklicht A1 (members excluded):2182288
2182306 | 03 derde verdieping | 03 derde verdieping | 0.125856 | 864 | 0.00423014 | 2182302 | Model Group:31_daklicht_B (members excluded):2194619
2194633 | 03 derde verdieping | 03 derde verdieping | 0.125856 | 864 | 0.00423014 | 2194629 | Model Group:31_daklicht_C:2194635
2194780 | 03 derde verdieping | 03 derde verdieping | 0.125856 | 864 | 0.00423014 | 2194776 | Model Group:31_daklicht_B:2194786
2194791 | 03 derde verdieping | 03 derde verdieping | 0.125856 | 864 | 0.00423014 | 2194787 | Model Group:31_daklicht_C:2194793
2759867 | 01 eerste verdieping | 01 eerste verdieping | 0.268656 | 1884 | 0.00922406 | 2245638 | Model Group:BU-33:2700705
2266689 | 01 eerste verdieping | 01 eerste verdieping | 0.268656 | 1884 | 0.00922406 | 2266685 | Model Group:31_1A DK L:2266691
2266706 | 02 tweede verdieping | 02 tweede verdieping | 0.047036 | 301 | 0.0014737 | 2266702 | Model Group:31_2A DK L:2266708
2266711 | 02 tweede verdieping | 02 tweede verdieping | 0.278316 | 1953 | 0.00956189 | 2266702 | Model Group:31_2A DK L:2266708
2266721 | 02 tweede verdieping | 02 tweede verdieping | 0.047036 | 301 | 0.0014737 | 2266717 | Model Group:31_2A DK R:2266723
2266726 | 02 tweede verdieping | 02 tweede verdieping | 0.278316 | 1953 | 0.00956189 | 2266717 | Model Group:31_2A DK R:2266723
2649838 | 00 begane grond | 00 begane grond | 0.331936 | 2336 | 0.0114371 | 2649834 | Model Group:BU-47 b4200:1822720
2649842 | 00 begane grond | 00 begane grond | 0.079936 | 536 | 0.00262426 | 2649834 | Model Group:BU-47 b4200:1822720
2652548 | 00 begane grond | 00 begane grond | 0.331936 | 2336 | 0.0114371 | 2652544 | Model Group:BU-11 b3000:1502212
2652558 | 00 begane grond | 00 begane grond | 0.079936 | 536 | 0.00262426 | 2652544 | Model Group:BU-11 b3000:1502212
2652634 | 00 begane grond | 00 begane grond | 0.331936 | 2336 | 0.0114371 | 2652630 | Model Group:BU-11 b3000:1502763
2652644 | 00 begane grond | 00 begane grond | 0.079936 | 536 | 0.00262426 | 2652630 | Model Group:BU-11 b3000:1502763
2760159 | 01 eerste verdieping | 01 eerste verdieping | 0.268656 | 1884 | 0.00922406 | 2760155 | Model Group:BU-33:2712443
2776734 | 01 eerste verdieping | 01 eerste verdieping | 0.268656 | 1884 | 0.00922406 | 2776730 | Model Group:31_1A SVGD L:2776736
3003072 | 00 begane grond | 00 begane grond | 0.331936 | 2336 | 0.0114371 | 3003068 | Model Group:BU-01 b1500:3003067
3003076 | 00 begane grond | 00 begane grond | 0.079936 | 536 | 0.00262426 | 3003068 | Model Group:BU-01 b1500:3003067
3058234 | 01 eerste verdieping | 01 eerste verdieping | 0.268656 | 1884 | 0.00922406 | 3058230 | Model Group:31_1A DKD R:3058236
3451934 | 00 begane grond | 00 begane grond | 0.273836 | 1921 | 0.00940522 | 3451930 | Model Group:BU-45 b900:2546304
3451938 | 00 begane grond | 00 begane grond | 0.083856 | 564 | 0.00276134 | 3451930 | Model Group:BU-45 b900:2546304
3702024 | 00 begane grond | 00 begane grond | 0.334736 | 2356 | 0.011535 | 3702020 | Model Group:BU-04 b2500:1820005
3702027 | 00 begane grond | 00 begane grond | 0.077136 | 516 | 0.00252634 | 3702020 | Model Group:BU-04 b2500:1820005
3836661 | 00 begane grond | 00 begane grond | 0.334736 | 2356 | 0.011535 | 3836657 | Model Group:BU-16:3836676
3836665 | 00 begane grond | 00 begane grond | 0.079936 | 536 | 0.00262426 | 3836657 | Model Group:BU-16:3836676
4196777 | 00 begane grond | 00 begane grond | 0.334736 | 2356 | 0.011535 | 4196773 | Model Group:BU-46:4200502
4196781 | 00 begane grond | 00 begane grond | 0.079936 | 536 | 0.00262426 | 4196773 | Model Group:BU-46:4200502

# IfcMember: Rectangular Mullion:RT72_Hm_raam_78 (109)
Type - PredefinedType: MULLION; Material: <Unnamed>, a_kozijn
Type - Constraints - Angle: 0 deg; Offset: 0 mm
Type - Construction - Corner Mullion: no; Position: Perpendicular to Face; Profile: BDG_RT72_Vm_raam : Hm_raam_78; Thickness: 72 mm
Type - Dimensions - Width on side 1: 39 mm; Width on side 2: 39 mm
Type - Identity Data - Workset: Family : Curtain Wall Mullions : Rectangular Mullion; Type Name: RT72_Hm_raam_78
Type - Other - Category: Curtain Wall Mullions; Family Name: Rectangular Mullion
Material: a_kozijn
Phasing - Phase Created: 2. nieuwbouw
Identity Data - Workset: Workset1
Other - Family: Rectangular Mullion; Family and Type: Rectangular Mullion: RT72_Hm_raam_78; Type: RT72_Hm_raam_78; Type Id: 835092
Name (Rectangular Mullion:RT72_Hm_raam_78:...) | In | Level | Area (m2) | Length (mm) | Volume (m3) | Host Id | Group
1864426 | 01 eerste verdieping | 01 eerste verdieping | 0.288216 | 1884 | 0.0105805 | 875025 | Model Group:31_1A DKD L:875031
1864689 | 01 eerste verdieping | 01 eerste verdieping | 0.288216 | 1884 | 0.0105805 | 875049 | Model Group:31_1A DK R:875055
1865122 | 01 eerste verdieping | 01 eerste verdieping | 0.288216 | 1884 | 0.0105805 | 875304 | Model Group:31_1A DKD R:875310
877742 | 02 tweede verdieping | 02 tweede verdieping | 0.364566 | 2393 | 0.0134391 | 877517 | Model Group:BU-40:2712884
877804 | 02 tweede verdieping | 02 tweede verdieping | 0.364566 | 2393 | 0.0134391 | 877517 | Model Group:BU-40:2712884
1837447 | 01 eerste verdieping | 01 eerste verdieping | 0.376416 | 2472 | 0.0138828 | 891997 | Model Group:BU-32:892003
1861212 | 00 begane grond | 00 begane grond | 0.356016 | 2336 | 0.013119 | 1220070 | Model Group:BU-08 b2100:1220076
1861260 | 00 begane grond | 00 begane grond | 0.086016 | 536 | 0.00301018 | 1220070 | Model Group:BU-08 b2100:1220076
1859716 | 00 begane grond | 00 begane grond | 0.356016 | 2336 | 0.013119 | 1220169 | Model Group:BU-09 b1500:1220175
1859850 | 00 begane grond | 00 begane grond | 0.086016 | 536 | 0.00301018 | 1220169 | Model Group:BU-09 b1500:1220175
1492353 | 00 begane grond | 00 begane grond | 0.356016 | 2336 | 0.013119 | 1220847 | Model Group:BU-11 b3000:1220846
1492360 | 00 begane grond | 00 begane grond | 0.086016 | 536 | 0.00301018 | 1220847 | Model Group:BU-11 b3000:1220846
1489289 | 00 begane grond | 00 begane grond | 0.356016 | 2336 | 0.013119 | 1300453 | Model Group:BU-22 b2700:1300414
1490591 | 00 begane grond | 00 begane grond | 0.086016 | 536 | 0.00301018 | 1300453 | Model Group:BU-22 b2700:1300414
1491169 | 00 begane grond | 00 begane grond | 0.356016 | 2336 | 0.013119 | 1300742 | Model Group:BU-21 b2966:1300741
1491551 | 00 begane grond | 00 begane grond | 0.086016 | 536 | 0.00301018 | 1300742 | Model Group:BU-21 b2966:1300741
1491989 | 00 begane grond | 00 begane grond | 0.356016 | 2336 | 0.013119 | 1300954 | Model Group:BU-20 b3300:1300930
1492205 | 00 begane grond | 00 begane grond | 0.086016 | 536 | 0.00301018 | 1300954 | Model Group:BU-20 b3300:1300930
1899351 | 00 begane grond | 00 begane grond | 0.356016 | 2336 | 0.013119 | 1300992 | Model Group:BU-23 b1353:2651710
1899466 | 00 begane grond | 00 begane grond | 0.086016 | 536 | 0.00301018 | 1300992 | Model Group:BU-23 b1353:2651710
1493867 | 00 begane grond | 00 begane grond | 0.356016 | 2336 | 0.013119 | 1493475 | Model Group:BU-25 b3000:1493474
1493953 | 00 begane grond | 00 begane grond | 0.086016 | 536 | 0.00301018 | 1493475 | Model Group:BU-25 b3000:1493474
1494115 | 00 begane grond | 00 begane grond | 0.356016 | 2336 | 0.013119 | 1494105 | Model Group:BU-02 b4200:1494104
1494122 | 00 begane grond | 00 begane grond | 0.086016 | 536 | 0.00301018 | 1494105 | Model Group:BU-02 b4200:1494104
2012620 | 00 begane grond | 00 begane grond | 0.356016 | 2336 | 0.013119 | 1494105 | Model Group:BU-02 b4200:1494104
2012621 | 00 begane grond | 00 begane grond | 0.086016 | 536 | 0.00301018 | 1494105 | Model Group:BU-02 b4200:1494104
1823029 | 00 begane grond | 00 begane grond | 0.356016 | 2336 | 0.013119 | 1494514 | Model Group:BU-14 b3000:1494513
1823030 | 00 begane grond | 00 begane grond | 0.086016 | 536 | 0.00301018 | 1494514 | Model Group:BU-14 b3000:1494513
1817645 | 00 begane grond | 00 begane grond | 0.356016 | 2336 | 0.013119 | 1817349 | Model Group:BU-12 b4200:1817348
1817646 | 00 begane grond | 00 begane grond | 0.086016 | 536 | 0.00301018 | 1817349 | Model Group:BU-12 b4200:1817348
1817866 | 00 begane grond | 00 begane grond | 0.356016 | 2336 | 0.013119 | 1817349 | Model Group:BU-12 b4200:1817348
1817867 | 00 begane grond | 00 begane grond | 0.086016 | 536 | 0.00301018 | 1817349 | Model Group:BU-12 b4200:1817348
1818879 | 00 begane grond | 00 begane grond | 0.356016 | 2336 | 0.013119 | 1818869 | Model Group:BU-03 b5800:1818868
1818886 | 00 begane grond | 00 begane grond | 0.086016 | 536 | 0.00301018 | 1818869 | Model Group:BU-03 b5800:1818868
1818892 | 00 begane grond | 00 begane grond | 0.356016 | 2336 | 0.013119 | 1818869 | Model Group:BU-03 b5800:1818868
1818893 | 00 begane grond | 00 begane grond | 0.086016 | 536 | 0.00301018 | 1818869 | Model Group:BU-03 b5800:1818868
1819726 | 00 begane grond | 00 begane grond | 0.356016 | 2336 | 0.013119 | 1818869 | Model Group:BU-03 b5800:1818868
1819727 | 00 begane grond | 00 begane grond | 0.086016 | 536 | 0.00301018 | 1818869 | Model Group:BU-03 b5800:1818868
1822161 | 00 begane grond | 00 begane grond | 0.356016 | 2336 | 0.013119 | 1822151 | Model Group:BU-10 b1800:1822150
1822170 | 00 begane grond | 00 begane grond | 0.086016 | 536 | 0.00301018 | 1822151 | Model Group:BU-10 b1800:1822150
1823329 | 00 begane grond | 00 begane grond | 0.356016 | 2336 | 0.013119 | 1823298 | Model Group:BU-15 b4200:1823297
1823330 | 00 begane grond | 00 begane grond | 0.086016 | 536 | 0.00301018 | 1823298 | Model Group:BU-15 b4200:1823297
1853997 | 00 begane grond | 00 begane grond | 0.086016 | 536 | 0.00301018 | 1853992 | Model Group:BU-18 b3017:2651211
1854002 | 00 begane grond | 00 begane grond | 0.356016 | 2336 | 0.013119 | 1853992 | Model Group:BU-18 b3017:2651211
1854009 | 00 begane grond | 00 begane grond | 0.086016 | 536 | 0.00301018 | 1853992 | Model Group:BU-18 b3017:2651211
1856677 | 00 begane grond | 00 begane grond | 0.356016 | 2336 | 0.013119 | 1853992 | Model Group:BU-18 b3017:2651211
1856678 | 00 begane grond | 00 begane grond | 0.086016 | 536 | 0.00301018 | 1853992 | Model Group:BU-18 b3017:2651211
2793293 | 00 begane grond | 00 begane grond | 0.356016 | 2336 | 0.013119 | 1853992 | Model Group:BU-18 b3017:2651211
1862285 | 00 begane grond | 00 begane grond | 0.293766 | 1921 | 0.0107883 | 1862275 | Model Group:BU-13 b3300:1862274
1862292 | 00 begane grond | 00 begane grond | 0.090216 | 564 | 0.00316742 | 1862275 | Model Group:BU-13 b3300:1862274
1864626 | 01 eerste verdieping | 01 eerste verdieping | 0.288216 | 1884 | 0.0105805 | 1864614 | Model Group:31_1A SVGD L:1864620
1864944 | 01 eerste verdieping | 01 eerste verdieping | 0.288216 | 1884 | 0.0105805 | 1864932 | Model Group:31_1A DK R:1864938
1864988 | 01 eerste verdieping | 01 eerste verdieping | 0.288216 | 1884 | 0.0105805 | 1864976 | Model Group:31_1A DKD L:1864982
1865013 | 01 eerste verdieping | 01 eerste verdieping | 0.288216 | 1884 | 0.0105805 | 1865001 | Model Group:31_1A DK R:1865007
1865036 | 01 eerste verdieping | 01 eerste verdieping | 0.288216 | 1884 | 0.0105805 | 1865024 | Model Group:31_1A DKD L:1865030
1865352 | 01 eerste verdieping | 01 eerste verdieping | 0.288216 | 1884 | 0.0105805 | 1865340 | Model Group:31_1A DKD R:1865346
1865373 | 01 eerste verdieping | 01 eerste verdieping | 0.288216 | 1884 | 0.0105805 | 1865361 | Model Group:31_1A DK L:1865367
1865580 | 01 eerste verdieping | 01 eerste verdieping | 0.288216 | 1884 | 0.0105805 | 1865568 | Model Group:31_1A DKD R:1865574
1865614 | 01 eerste verdieping | 01 eerste verdieping | 0.288216 | 1884 | 0.0105805 | 1865602 | Model Group:31_1A DKD R:1865608
1865661 | 01 eerste verdieping | 01 eerste verdieping | 0.288216 | 1884 | 0.0105805 | 1865649 | Model Group:31_1A DK L:1865655
1865680 | 01 eerste verdieping | 01 eerste verdieping | 0.288216 | 1884 | 0.0105805 | 1865668 | Model Group:31_1A DK L:1865674
1865787 | 01 eerste verdieping | 01 eerste verdieping | 0.288216 | 1884 | 0.0105805 | 1865775 | Model Group:31_1A DKD R:1865781
1865808 | 01 eerste verdieping | 01 eerste verdieping | 0.288216 | 1884 | 0.0105805 | 1865796 | Model Group:31_1A DK L:1865802
1865929 | 01 eerste verdieping | 01 eerste verdieping | 0.288216 | 1884 | 0.0105805 | 1865917 | Model Group:31_1A DK R:1865923
1865952 | 01 eerste verdieping | 01 eerste verdieping | 0.288216 | 1884 | 0.0105805 | 1865940 | Model Group:31_1A DKD L:1865946
1866088 | 01 eerste verdieping | 01 eerste verdieping | 0.288216 | 1884 | 0.0105805 | 1866076 | Model Group:31_1A DKg R:1866082
1898051 | 01 eerste verdieping | 01 eerste verdieping | 0.288216 | 1884 | 0.0105805 | 1898039 | Model Group:31_1A DKD R:1898045
1932989 | 00 begane grond | 00 begane grond | 0.356016 | 2336 | 0.013119 | 1932979 | Model Group:BU-17 b3000:1900158
1932996 | 00 begane grond | 00 begane grond | 0.086016 | 536 | 0.00301018 | 1932979 | Model Group:BU-17 b3000:1900158
2012537 | 01 eerste verdieping | 01 eerste verdieping | 0.288216 | 1884 | 0.0105805 | 2012525 | Model Group:31_1A DKD L:2012531
2012567 | 01 eerste verdieping | 01 eerste verdieping | 0.288216 | 1884 | 0.0105805 | 2012555 | Model Group:31_1A DKD L:2012561
2012582 | 01 eerste verdieping | 01 eerste verdieping | 0.280716 | 1834 | 0.0102997 | 2012570 | Model Group:BU-38:2702101
2194546 | 03 derde verdieping | 03 derde verdieping | 0.135216 | 864 | 0.00485222 | 2182229 | Model Group:daklicht A1:2182252
2194551 | 03 derde verdieping | 03 derde verdieping | 0.135216 | 864 | 0.00485222 | 2182229 | Model Group:daklicht A1:2182252
2194558 | 03 derde verdieping | 03 derde verdieping | 0.135216 | 864 | 0.00485222 | 2182229 | Model Group:daklicht A1:2182252
2194589 | 03 derde verdieping | 03 derde verdieping | 0.135216 | 864 | 0.00485222 | 2182282 | Model Group:daklicht A1 (members excluded):2182288
2194594 | 03 derde verdieping | 03 derde verdieping | 0.135216 | 864 | 0.00485222 | 2182282 | Model Group:daklicht A1 (members excluded):2182288
2194599 | 03 derde verdieping | 03 derde verdieping | 0.135216 | 864 | 0.00485222 | 2182282 | Model Group:daklicht A1 (members excluded):2182288
2194883 | 03 derde verdieping | 03 derde verdieping | 0.135216 | 864 | 0.00485222 | 2182302 | Model Group:31_daklicht_B (members excluded):2194619
2194894 | 03 derde verdieping | 03 derde verdieping | 0.135216 | 864 | 0.00485222 | 2182302 | Model Group:31_daklicht_B (members excluded):2194619
2194905 | 03 derde verdieping | 03 derde verdieping | 0.135216 | 864 | 0.00485222 | 2182302 | Model Group:31_daklicht_B (members excluded):2194619
2195052 | 03 derde verdieping | 03 derde verdieping | 0.135216 | 864 | 0.00485222 | 2194629 | Model Group:31_daklicht_C:2194635
2195062 | 03 derde verdieping | 03 derde verdieping | 0.135216 | 864 | 0.00485222 | 2194629 | Model Group:31_daklicht_C:2194635
2195073 | 03 derde verdieping | 03 derde verdieping | 0.135216 | 864 | 0.00485222 | 2194629 | Model Group:31_daklicht_C:2194635
2194974 | 03 derde verdieping | 03 derde verdieping | 0.135216 | 864 | 0.00485222 | 2194776 | Model Group:31_daklicht_B:2194786
2194979 | 03 derde verdieping | 03 derde verdieping | 0.135216 | 864 | 0.00485222 | 2194776 | Model Group:31_daklicht_B:2194786
2194984 | 03 derde verdieping | 03 derde verdieping | 0.135216 | 864 | 0.00485222 | 2194776 | Model Group:31_daklicht_B:2194786
2195096 | 03 derde verdieping | 03 derde verdieping | 0.135216 | 864 | 0.00485222 | 2194787 | Model Group:31_daklicht_C:2194793
2195101 | 03 derde verdieping | 03 derde verdieping | 0.135216 | 864 | 0.00485222 | 2194787 | Model Group:31_daklicht_C:2194793
2195106 | 03 derde verdieping | 03 derde verdieping | 0.135216 | 864 | 0.00485222 | 2194787 | Model Group:31_daklicht_C:2194793
2266697 | 01 eerste verdieping | 01 eerste verdieping | 0.288216 | 1884 | 0.0105805 | 2266685 | Model Group:31_1A DK L:2266691
2649849 | 00 begane grond | 00 begane grond | 0.356016 | 2336 | 0.013119 | 2649834 | Model Group:BU-47 b4200:1822720
2649850 | 00 begane grond | 00 begane grond | 0.086016 | 536 | 0.00301018 | 2649834 | Model Group:BU-47 b4200:1822720
2649858 | 00 begane grond | 00 begane grond | 0.356016 | 2336 | 0.013119 | 2649834 | Model Group:BU-47 b4200:1822720
2649859 | 00 begane grond | 00 begane grond | 0.086016 | 536 | 0.00301018 | 2649834 | Model Group:BU-47 b4200:1822720
2652554 | 00 begane grond | 00 begane grond | 0.356016 | 2336 | 0.013119 | 2652544 | Model Group:BU-11 b3000:1502212
2652561 | 00 begane grond | 00 begane grond | 0.086016 | 536 | 0.00301018 | 2652544 | Model Group:BU-11 b3000:1502212
2652640 | 00 begane grond | 00 begane grond | 0.356016 | 2336 | 0.013119 | 2652630 | Model Group:BU-11 b3000:1502763
2652647 | 00 begane grond | 00 begane grond | 0.086016 | 536 | 0.00301018 | 2652630 | Model Group:BU-11 b3000:1502763
2776742 | 01 eerste verdieping | 01 eerste verdieping | 0.288216 | 1884 | 0.0105805 | 2776730 | Model Group:31_1A SVGD L:2776736
3003091 | 00 begane grond | 00 begane grond | 0.356016 | 2336 | 0.013119 | 3003068 | Model Group:BU-01 b1500:3003067
3003092 | 00 begane grond | 00 begane grond | 0.086016 | 536 | 0.00301018 | 3003068 | Model Group:BU-01 b1500:3003067
3003098 | 00 begane grond | 00 begane grond | 0.356016 | 2336 | 0.013119 | 3003068 | Model Group:BU-01 b1500:3003067
3003099 | 00 begane grond | 00 begane grond | 0.086016 | 536 | 0.00301018 | 3003068 | Model Group:BU-01 b1500:3003067
3016900 | 00 begane grond | 00 begane grond | 0.366216 | 2404 | 0.0135009 | 3016883
3016901 | 00 begane grond | 00 begane grond | 0.086016 | 536 | 0.00301018 | 3016883
3058242 | 01 eerste verdieping | 01 eerste verdieping | 0.288216 | 1884 | 0.0105805 | 3058230 | Model Group:31_1A DKD R:3058236
3702034 | 00 begane grond | 00 begane grond | 0.359016 | 2356 | 0.0132313 | 3702020 | Model Group:BU-04 b2500:1820005
3702035 | 00 begane grond | 00 begane grond | 0.083016 | 516 | 0.00289786 | 3702020 | Model Group:BU-04 b2500:1820005

# IfcMember: Rectangular Mullion:RT72_Hr_raam (203)
Type - PredefinedType: MULLION; Material: <Unnamed>, a_kozijn
Type - Constraints - Angle: 0 deg; Offset: 0 mm
Type - Construction - Corner Mullion: no; Position: Perpendicular to Face; Profile: BDG_RT72_Vm_raam : Hr_raam; Thickness: 72 mm
Type - Dimensions - Width on side 1: 34 mm; Width on side 2: 34 mm
Type - Identity Data - Workset: Family : Curtain Wall Mullions : Rectangular Mullion; Type Name: RT72_Hr_raam
Type - Other - Category: Curtain Wall Mullions; Family Name: Rectangular Mullion
Material: a_kozijn
Phasing - Phase Created: 2. nieuwbouw
Identity Data - Workset: Workset1
Other - Family: Rectangular Mullion; Family and Type: Rectangular Mullion: RT72_Hr_raam; Type: RT72_Hr_raam; Type Id: 835098
Name (Rectangular Mullion:RT72_Hr_raam:...) | In | Level | Area (m2) | Length (mm) | Volume (m3) | Host Id | Group
870546 | 02 tweede verdieping | 02 tweede verdieping | 0.278316 | 1953 | 0.00956189 | 870541 | Model Group:31_2A:870547
879499 | 02 tweede verdieping | 02 tweede verdieping | 0.047036 | 301 | 0.0014737 | 870541 | Model Group:31_2A:870547
870752 | 02 tweede verdieping | 02 tweede verdieping | 0.278316 | 1953 | 0.00956189 | 870747 | Model Group:31_2A:870753
879535 | 02 tweede verdieping | 02 tweede verdieping | 0.047036 | 301 | 0.0014737 | 870747 | Model Group:31_2A:870753
870865 | 02 tweede verdieping | 02 tweede verdieping | 0.278316 | 1953 | 0.00956189 | 870860 | Model Group:31_2A:870866
879553 | 02 tweede verdieping | 02 tweede verdieping | 0.047036 | 301 | 0.0014737 | 870860 | Model Group:31_2A:870866
871640 | 02 tweede verdieping | 02 tweede verdieping | 0.278316 | 1953 | 0.00956189 | 871635 | Model Group:31_2A:871641
878916 | 02 tweede verdieping | 02 tweede verdieping | 0.047036 | 301 | 0.0014737 | 871635 | Model Group:31_2A:871641
871673 | 02 tweede verdieping | 02 tweede verdieping | 0.278316 | 1953 | 0.00956189 | 871668 | Model Group:31_2A:871674
879571 | 02 tweede verdieping | 02 tweede verdieping | 0.047036 | 301 | 0.0014737 | 871668 | Model Group:31_2A:871674
871924 | 02 tweede verdieping | 02 tweede verdieping | 0.278316 | 1953 | 0.00956189 | 871919 | Model Group:31_2A:871925
879589 | 02 tweede verdieping | 02 tweede verdieping | 0.047036 | 301 | 0.0014737 | 871919 | Model Group:31_2A:871925
871956 | 02 tweede verdieping | 02 tweede verdieping | 0.278316 | 1953 | 0.00956189 | 871951 | Model Group:31_2A:871957
879595 | 02 tweede verdieping | 02 tweede verdieping | 0.047036 | 301 | 0.0014737 | 871951 | Model Group:31_2A:871957
872818 | 02 tweede verdieping | 02 tweede verdieping | 0.278316 | 1953 | 0.00956189 | 872813 | Model Group:31_2A:872819
879619 | 02 tweede verdieping | 02 tweede verdieping | 0.047036 | 301 | 0.0014737 | 872813 | Model Group:31_2A:872819
872884 | 02 tweede verdieping | 02 tweede verdieping | 0.278316 | 1953 | 0.00956189 | 872879 | Model Group:31_2A:872885
879631 | 02 tweede verdieping | 02 tweede verdieping | 0.047036 | 301 | 0.0014737 | 872879 | Model Group:31_2A:872885
872917 | 02 tweede verdieping | 02 tweede verdieping | 0.278316 | 1953 | 0.00956189 | 872912 | Model Group:31_2A:872918
879637 | 02 tweede verdieping | 02 tweede verdieping | 0.047036 | 301 | 0.0014737 | 872912 | Model Group:31_2A:872918
872950 | 02 tweede verdieping | 02 tweede verdieping | 0.278316 | 1953 | 0.00956189 | 872945 | Model Group:31_2A:872951
879643 | 02 tweede verdieping | 02 tweede verdieping | 0.047036 | 301 | 0.0014737 | 872945 | Model Group:31_2A:872951
872983 | 02 tweede verdieping | 02 tweede verdieping | 0.278316 | 1953 | 0.00956189 | 872978 | Model Group:31_2A:872984
879649 | 02 tweede verdieping | 02 tweede verdieping | 0.047036 | 301 | 0.0014737 | 872978 | Model Group:31_2A:872984
873016 | 02 tweede verdieping | 02 tweede verdieping | 0.278316 | 1953 | 0.00956189 | 873011 | Model Group:31_2A:873017
879655 | 02 tweede verdieping | 02 tweede verdieping | 0.047036 | 301 | 0.0014737 | 873011 | Model Group:31_2A:873017
873082 | 02 tweede verdieping | 02 tweede verdieping | 0.278316 | 1953 | 0.00956189 | 873077 | Model Group:31_2A:873083
879667 | 02 tweede verdieping | 02 tweede verdieping | 0.047036 | 301 | 0.0014737 | 873077 | Model Group:31_2A:873083
873513 | 02 tweede verdieping | 02 tweede verdieping | 0.278316 | 1953 | 0.00956189 | 873508 | Model Group:31_2A:873514
879703 | 02 tweede verdieping | 02 tweede verdieping | 0.047036 | 301 | 0.0014737 | 873508 | Model Group:31_2A:873514
873606 | 02 tweede verdieping | 02 tweede verdieping | 0.278316 | 1953 | 0.00956189 | 873601 | Model Group:31_2A:873607
879721 | 02 tweede verdieping | 02 tweede verdieping | 0.047036 | 301 | 0.0014737 | 873601 | Model Group:31_2A:873607
873699 | 02 tweede verdieping | 02 tweede verdieping | 0.278316 | 1953 | 0.00956189 | 873694 | Model Group:31_2A:873700
879739 | 02 tweede verdieping | 02 tweede verdieping | 0.047036 | 301 | 0.0014737 | 873694 | Model Group:31_2A:873700
874671 | 01 eerste verdieping | 01 eerste verdieping | 0.268656 | 1884 | 0.00922406 | 874666 | Model Group:31_1A:874672
874955 | 01 eerste verdieping | 01 eerste verdieping | 0.268656 | 1884 | 0.00922406 | 874950 | Model Group:31_1A:874956
875030 | 01 eerste verdieping | 01 eerste verdieping | 0.268656 | 1884 | 0.00922406 | 875025 | Model Group:31_1A DKD L:875031
875045 | 01 eerste verdieping | 01 eerste verdieping | 0.268656 | 1884 | 0.00922406 | 875040 | Model Group:31_1A:875046
875054 | 01 eerste verdieping | 01 eerste verdieping | 0.268656 | 1884 | 0.00922406 | 875049 | Model Group:31_1A DK R:875055
875273 | 01 eerste verdieping | 01 eerste verdieping | 0.268656 | 1884 | 0.00922406 | 875268 | Model Group:31_1A:875274
875309 | 01 eerste verdieping | 01 eerste verdieping | 0.268656 | 1884 | 0.00922406 | 875304 | Model Group:31_1A DKD R:875310
875381 | 01 eerste verdieping | 01 eerste verdieping | 0.268656 | 1884 | 0.00922406 | 875376 | Model Group:31_1A:875382
876492 | 01 eerste verdieping | 01 eerste verdieping | 0.268656 | 1884 | 0.00922406 | 876487 | Model Group:31_1A:876493
876910 | 01 eerste verdieping | 01 eerste verdieping | 0.268656 | 1884 | 0.00922406 | 876905 | Model Group:31_1A:876911
877027 | 01 eerste verdieping | 01 eerste verdieping | 0.268656 | 1884 | 0.00922406 | 877022 | Model Group:31_1A:877028
877117 | 01 eerste verdieping | 01 eerste verdieping | 0.268656 | 1884 | 0.00922406 | 877112 | Model Group:31_1A:877118
877207 | 01 eerste verdieping | 01 eerste verdieping | 0.268656 | 1884 | 0.00922406 | 877202 | Model Group:31_1A:877208
877522 | 02 tweede verdieping | 02 tweede verdieping | 0.038356 | 239 | 0.00117014 | 877517 | Model Group:BU-40:2712884
877676 | 02 tweede verdieping | 02 tweede verdieping | 0.345376 | 2432 | 0.0119071 | 877517 | Model Group:BU-40:2712884
880926 | 01 eerste verdieping | 01 eerste verdieping | 0.268656 | 1884 | 0.00922406 | 880921 | Model Group:31_1A:880927
881687 | 01 eerste verdieping | 01 eerste verdieping | 0.268656 | 1884 | 0.00922406 | 881682 | Model Group:31_1A:881688
891679 | 01 eerste verdieping | 01 eerste verdieping | 0.268656 | 1884 | 0.00922406 | 891674 | Model Group:31_1A:891680
891762 | 01 eerste verdieping | 01 eerste verdieping | 0.268656 | 1884 | 0.00922406 | 891757 | Model Group:BU-30:2700215
891791 | 01 eerste verdieping | 01 eerste verdieping | 0.268656 | 1884 | 0.00922406 | 891786 | Model Group:31_1A:891792
891908 | 01 eerste verdieping | 01 eerste verdieping | 0.268656 | 1884 | 0.00922406 | 891903 | Model Group:31_1A:891909
891930 | 01 eerste verdieping | 01 eerste verdieping | 0.268656 | 1884 | 0.00922406 | 891925 | Model Group:31_1A:891931
891980 | 01 eerste verdieping | 01 eerste verdieping | 0.268656 | 1884 | 0.00922406 | 891975 | Model Group:31_1A:891981
892002 | 01 eerste verdieping | 01 eerste verdieping | 0.350976 | 2472 | 0.0121029 | 891997 | Model Group:BU-32:892003
892043 | 00 begane grond | 00 begane grond | 0.079936 | 536 | 0.00262426 | 892038 | Model Group:BU-07 b900:894363
1826976 | 00 begane grond | 00 begane grond | 0.331936 | 2336 | 0.0114371 | 892038 | Model Group:BU-07 b900:894363
894433 | 00 begane grond | 00 begane grond | 0.406976 | 2872 | 0.0140613 | 894428 | Model Group:BU-06 b1800:894434
1220075 | 00 begane grond | 00 begane grond | 0.079936 | 536 | 0.00262426 | 1220070 | Model Group:BU-08 b2100:1220076
1861257 | 00 begane grond | 00 begane grond | 0.331936 | 2336 | 0.0114371 | 1220070 | Model Group:BU-08 b2100:1220076
1220174 | 00 begane grond | 00 begane grond | 0.079936 | 536 | 0.00262426 | 1220169 | Model Group:BU-09 b1500:1220175
1859847 | 00 begane grond | 00 begane grond | 0.331936 | 2336 | 0.0114371 | 1220169 | Model Group:BU-09 b1500:1220175
1220852 | 00 begane grond | 00 begane grond | 0.079936 | 536 | 0.00262426 | 1220847 | Model Group:BU-11 b3000:1220846
1492358 | 00 begane grond | 00 begane grond | 0.331936 | 2336 | 0.0114371 | 1220847 | Model Group:BU-11 b3000:1220846
1300406 | 00 begane grond | 00 begane grond | 0.079936 | 536 | 0.00262426 | 1300401 | Model Group:BU-07 b900 (members excluded):1300407
1827110 | 00 begane grond | 00 begane grond | 0.331936 | 2336 | 0.0114371 | 1300401 | Model Group:BU-07 b900 (members excluded):1300407
1300458 | 00 begane grond | 00 begane grond | 0.079936 | 536 | 0.00262426 | 1300453 | Model Group:BU-22 b2700:1300414
1490588 | 00 begane grond | 00 begane grond | 0.331936 | 2336 | 0.0114371 | 1300453 | Model Group:BU-22 b2700:1300414
1300747 | 00 begane grond | 00 begane grond | 0.079936 | 536 | 0.00262426 | 1300742 | Model Group:BU-21 b2966:1300741
1491548 | 00 begane grond | 00 begane grond | 0.331936 | 2336 | 0.0114371 | 1300742 | Model Group:BU-21 b2966:1300741
1300959 | 00 begane grond | 00 begane grond | 0.079936 | 536 | 0.00262426 | 1300954 | Model Group:BU-20 b3300:1300930
1492202 | 00 begane grond | 00 begane grond | 0.331936 | 2336 | 0.0114371 | 1300954 | Model Group:BU-20 b3300:1300930
1302059 | 01 eerste verdieping | 01 eerste verdieping | 0.353636 | 2491 | 0.0121959 | 1302054 | Model Group:BU-31:891953
1493480 | 00 begane grond | 00 begane grond | 0.079936 | 536 | 0.00262426 | 1493475 | Model Group:BU-25 b3000:1493474
1493950 | 00 begane grond | 00 begane grond | 0.331936 | 2336 | 0.0114371 | 1493475 | Model Group:BU-25 b3000:1493474
1494110 | 00 begane grond | 00 begane grond | 0.079936 | 536 | 0.00262426 | 1494105 | Model Group:BU-02 b4200:1494104
1494120 | 00 begane grond | 00 begane grond | 0.331936 | 2336 | 0.0114371 | 1494105 | Model Group:BU-02 b4200:1494104
1494519 | 00 begane grond | 00 begane grond | 0.079936 | 536 | 0.00262426 | 1494514 | Model Group:BU-14 b3000:1494513
1494529 | 00 begane grond | 00 begane grond | 0.331936 | 2336 | 0.0114371 | 1494514 | Model Group:BU-14 b3000:1494513
1502986 | 00 begane grond | 00 begane grond | 0.079936 | 536 | 0.00262426 | 1502981 | Model Group:BU-07 b900:1502980
1827116 | 00 begane grond | 00 begane grond | 0.331936 | 2336 | 0.0114371 | 1502981 | Model Group:BU-07 b900:1502980
1817354 | 00 begane grond | 00 begane grond | 0.079936 | 536 | 0.00262426 | 1817349 | Model Group:BU-12 b4200:1817348
1817364 | 00 begane grond | 00 begane grond | 0.331936 | 2336 | 0.0114371 | 1817349 | Model Group:BU-12 b4200:1817348
1818874 | 00 begane grond | 00 begane grond | 0.079936 | 536 | 0.00262426 | 1818869 | Model Group:BU-03 b5800:1818868
1818884 | 00 begane grond | 00 begane grond | 0.331936 | 2336 | 0.0114371 | 1818869 | Model Group:BU-03 b5800:1818868
1819907 | 00 begane grond | 00 begane grond | 0.409776 | 2892 | 0.0141592 | 1819902 | Model Group:BU-05 b1910:2648634
1822156 | 00 begane grond | 00 begane grond | 0.079936 | 536 | 0.00262426 | 1822151 | Model Group:BU-10 b1800:1822150
1822168 | 00 begane grond | 00 begane grond | 0.331936 | 2336 | 0.0114371 | 1822151 | Model Group:BU-10 b1800:1822150
1823303 | 00 begane grond | 00 begane grond | 0.079936 | 536 | 0.00262426 | 1823298 | Model Group:BU-15 b4200:1823297
1823313 | 00 begane grond | 00 begane grond | 0.331936 | 2336 | 0.0114371 | 1823298 | Model Group:BU-15 b4200:1823297
1854934 | 00 begane grond | 00 begane grond | 0.406976 | 2872 | 0.0140613 | 1854929 | Model Group:BU-19 b2067:2651286
1862280 | 00 begane grond | 00 begane grond | 0.083856 | 564 | 0.00276134 | 1862275 | Model Group:BU-13 b3300:1862274
1862290 | 00 begane grond | 00 begane grond | 0.273836 | 1921 | 0.00940522 | 1862275 | Model Group:BU-13 b3300:1862274
1864619 | 01 eerste verdieping | 01 eerste verdieping | 0.268656 | 1884 | 0.00922406 | 1864614 | Model Group:31_1A SVGD L:1864620
1864937 | 01 eerste verdieping | 01 eerste verdieping | 0.268656 | 1884 | 0.00922406 | 1864932 | Model Group:31_1A DK R:1864938
1864981 | 01 eerste verdieping | 01 eerste verdieping | 0.268656 | 1884 | 0.00922406 | 1864976 | Model Group:31_1A DKD L:1864982
1865006 | 01 eerste verdieping | 01 eerste verdieping | 0.268656 | 1884 | 0.00922406 | 1865001 | Model Group:31_1A DK R:1865007
1865029 | 01 eerste verdieping | 01 eerste verdieping | 0.268656 | 1884 | 0.00922406 | 1865024 | Model Group:31_1A DKD L:1865030
1865345 | 01 eerste verdieping | 01 eerste verdieping | 0.268656 | 1884 | 0.00922406 | 1865340 | Model Group:31_1A DKD R:1865346
1865366 | 01 eerste verdieping | 01 eerste verdieping | 0.268656 | 1884 | 0.00922406 | 1865361 | Model Group:31_1A DK L:1865367
1865573 | 01 eerste verdieping | 01 eerste verdieping | 0.268656 | 1884 | 0.00922406 | 1865568 | Model Group:31_1A DKD R:1865574
1865607 | 01 eerste verdieping | 01 eerste verdieping | 0.268656 | 1884 | 0.00922406 | 1865602 | Model Group:31_1A DKD R:1865608
1865654 | 01 eerste verdieping | 01 eerste verdieping | 0.268656 | 1884 | 0.00922406 | 1865649 | Model Group:31_1A DK L:1865655
1865673 | 01 eerste verdieping | 01 eerste verdieping | 0.268656 | 1884 | 0.00922406 | 1865668 | Model Group:31_1A DK L:1865674
1865780 | 01 eerste verdieping | 01 eerste verdieping | 0.268656 | 1884 | 0.00922406 | 1865775 | Model Group:31_1A DKD R:1865781
1865801 | 01 eerste verdieping | 01 eerste verdieping | 0.268656 | 1884 | 0.00922406 | 1865796 | Model Group:31_1A DK L:1865802
1865922 | 01 eerste verdieping | 01 eerste verdieping | 0.268656 | 1884 | 0.00922406 | 1865917 | Model Group:31_1A DK R:1865923
1865945 | 01 eerste verdieping | 01 eerste verdieping | 0.268656 | 1884 | 0.00922406 | 1865940 | Model Group:31_1A DKD L:1865946
1866081 | 01 eerste verdieping | 01 eerste verdieping | 0.268656 | 1884 | 0.00922406 | 1866076 | Model Group:31_1A DKg R:1866082
1867676 | 02 tweede verdieping | 02 tweede verdieping | 0.278316 | 1953 | 0.00956189 | 1867671 | Model Group:31_2A DK R:1867677
1867682 | 02 tweede verdieping | 02 tweede verdieping | 0.047036 | 301 | 0.0014737 | 1867671 | Model Group:31_2A DK R:1867677
1869344 | 02 tweede verdieping | 02 tweede verdieping | 0.278316 | 1953 | 0.00956189 | 1869339 | Model Group:31_2A DK R:1869345
1869349 | 02 tweede verdieping | 02 tweede verdieping | 0.047036 | 301 | 0.0014737 | 1869339 | Model Group:31_2A DK R:1869345
1869361 | 02 tweede verdieping | 02 tweede verdieping | 0.278316 | 1953 | 0.00956189 | 1869356 | Model Group:31_2A DK R:1869362
1869366 | 02 tweede verdieping | 02 tweede verdieping | 0.047036 | 301 | 0.0014737 | 1869356 | Model Group:31_2A DK R:1869362
1869378 | 02 tweede verdieping | 02 tweede verdieping | 0.278316 | 1953 | 0.00956189 | 1869373 | Model Group:31_2A DK R:1869379
1869383 | 02 tweede verdieping | 02 tweede verdieping | 0.047036 | 301 | 0.0014737 | 1869373 | Model Group:31_2A DK R:1869379
1869395 | 02 tweede verdieping | 02 tweede verdieping | 0.278316 | 1953 | 0.00956189 | 1869390 | Model Group:31_2A DK R:1869396
1869400 | 02 tweede verdieping | 02 tweede verdieping | 0.047036 | 301 | 0.0014737 | 1869390 | Model Group:31_2A DK R:1869396
1869412 | 02 tweede verdieping | 02 tweede verdieping | 0.278316 | 1953 | 0.00956189 | 1869407 | Model Group:31_2A DK R:1869413
1869417 | 02 tweede verdieping | 02 tweede verdieping | 0.047036 | 301 | 0.0014737 | 1869407 | Model Group:31_2A DK R:1869413
1869429 | 02 tweede verdieping | 02 tweede verdieping | 0.278316 | 1953 | 0.00956189 | 1869424 | Model Group:31_2A DK R:1869430
1869434 | 02 tweede verdieping | 02 tweede verdieping | 0.047036 | 301 | 0.0014737 | 1869424 | Model Group:31_2A DK R:1869430
1869446 | 02 tweede verdieping | 02 tweede verdieping | 0.278316 | 1953 | 0.00956189 | 1869441 | Model Group:31_2A DK R:1869447
1869451 | 02 tweede verdieping | 02 tweede verdieping | 0.047036 | 301 | 0.0014737 | 1869441 | Model Group:31_2A DK R:1869447
1869466 | 02 tweede verdieping | 02 tweede verdieping | 0.278316 | 1953 | 0.00956189 | 1869461 | Model Group:31_2A DK L:1869467
1869471 | 02 tweede verdieping | 02 tweede verdieping | 0.047036 | 301 | 0.0014737 | 1869461 | Model Group:31_2A DK L:1869467
1869605 | 02 tweede verdieping | 02 tweede verdieping | 0.278316 | 1953 | 0.00956189 | 1869600 | Model Group:31_2A DK L:1869606
1869610 | 02 tweede verdieping | 02 tweede verdieping | 0.047036 | 301 | 0.0014737 | 1869600 | Model Group:31_2A DK L:1869606
1869622 | 02 tweede verdieping | 02 tweede verdieping | 0.278316 | 1953 | 0.00956189 | 1869617 | Model Group:31_2A DK L:1869623
1869627 | 02 tweede verdieping | 02 tweede verdieping | 0.047036 | 301 | 0.0014737 | 1869617 | Model Group:31_2A DK L:1869623
1869639 | 02 tweede verdieping | 02 tweede verdieping | 0.278316 | 1953 | 0.00956189 | 1869634 | Model Group:31_2A DK L:1869640
1869644 | 02 tweede verdieping | 02 tweede verdieping | 0.047036 | 301 | 0.0014737 | 1869634 | Model Group:31_2A DK L:1869640
1869656 | 02 tweede verdieping | 02 tweede verdieping | 0.278316 | 1953 | 0.00956189 | 1869651 | Model Group:31_2A DK L:1869657
1869661 | 02 tweede verdieping | 02 tweede verdieping | 0.047036 | 301 | 0.0014737 | 1869651 | Model Group:31_2A DK L:1869657
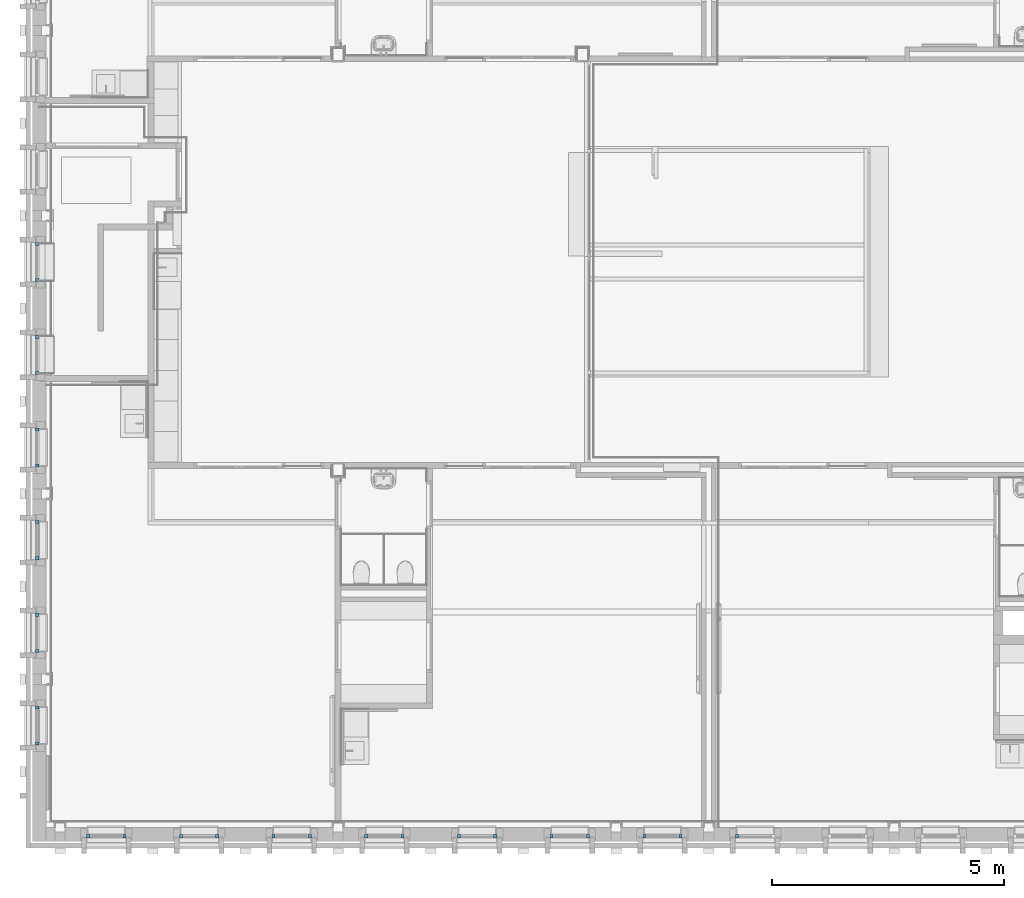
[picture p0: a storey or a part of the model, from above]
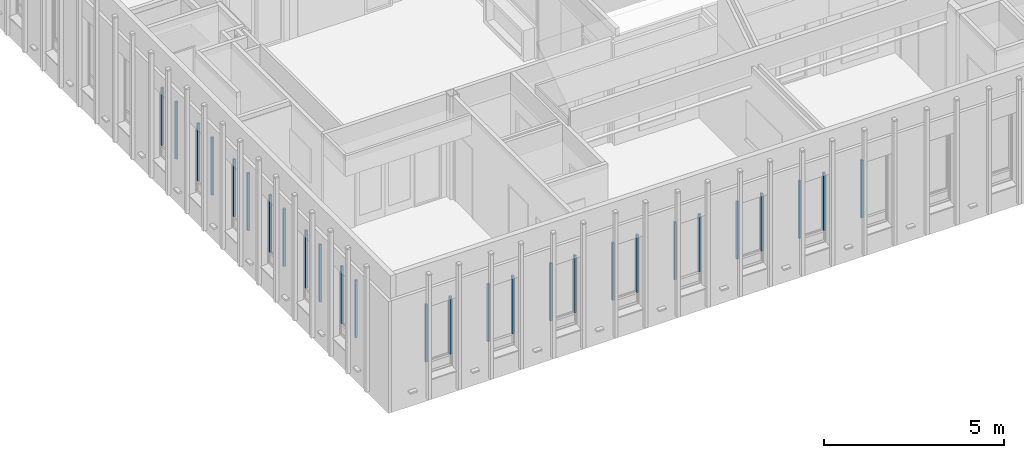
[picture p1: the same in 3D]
Properties of the parts of a building model (IFC2X3), part 14 of 94

# IfcMember: Rectangular Mullion:RT72_Hr_raam (203)
Name (Rectangular Mullion:RT72_Hr_raam:...) | In | Level | Area (m2) | Length (mm) | Volume (m3) | Host Id | Group
1869673 | 02 tweede verdieping | 02 tweede verdieping | 0.278316 | 1953 | 0.00956189 | 1869668 | Model Group:31_2A DK L:1869674
1869678 | 02 tweede verdieping | 02 tweede verdieping | 0.047036 | 301 | 0.0014737 | 1869668 | Model Group:31_2A DK L:1869674
1869690 | 02 tweede verdieping | 02 tweede verdieping | 0.278316 | 1953 | 0.00956189 | 1869685 | Model Group:31_2A DK L:1869691
1869695 | 02 tweede verdieping | 02 tweede verdieping | 0.047036 | 301 | 0.0014737 | 1869685 | Model Group:31_2A DK L:1869691
1869707 | 02 tweede verdieping | 02 tweede verdieping | 0.278316 | 1953 | 0.00956189 | 1869702 | Model Group:31_2A DK L:1869708
1869712 | 02 tweede verdieping | 02 tweede verdieping | 0.047036 | 301 | 0.0014737 | 1869702 | Model Group:31_2A DK L:1869708
1869726 | 02 tweede verdieping | 02 tweede verdieping | 0.278316 | 1953 | 0.00956189 | 1869721 | Model Group:31_2A DK L:1869727
1869731 | 02 tweede verdieping | 02 tweede verdieping | 0.047036 | 301 | 0.0014737 | 1869721 | Model Group:31_2A DK L:1869727
1869743 | 02 tweede verdieping | 02 tweede verdieping | 0.278316 | 1953 | 0.00956189 | 1869738 | Model Group:31_2A DK L:1869744
1869748 | 02 tweede verdieping | 02 tweede verdieping | 0.047036 | 301 | 0.0014737 | 1869738 | Model Group:31_2A DK L:1869744
1869760 | 02 tweede verdieping | 02 tweede verdieping | 0.278316 | 1953 | 0.00956189 | 1869755 | Model Group:31_2A DK R:1869761
1869765 | 02 tweede verdieping | 02 tweede verdieping | 0.047036 | 301 | 0.0014737 | 1869755 | Model Group:31_2A DK R:1869761
1869777 | 02 tweede verdieping | 02 tweede verdieping | 0.278316 | 1953 | 0.00956189 | 1869772 | Model Group:31_2A DK R:1869778
1869782 | 02 tweede verdieping | 02 tweede verdieping | 0.047036 | 301 | 0.0014737 | 1869772 | Model Group:31_2A DK R:1869778
1869796 | 02 tweede verdieping | 02 tweede verdieping | 0.278316 | 1953 | 0.00956189 | 1869791 | Model Group:31_2A DK R:1869797
1869801 | 02 tweede verdieping | 02 tweede verdieping | 0.047036 | 301 | 0.0014737 | 1869791 | Model Group:31_2A DK R:1869797
1869813 | 02 tweede verdieping | 02 tweede verdieping | 0.278316 | 1953 | 0.00956189 | 1869808 | Model Group:31_2A DK R:1869814
1869818 | 02 tweede verdieping | 02 tweede verdieping | 0.047036 | 301 | 0.0014737 | 1869808 | Model Group:31_2A DK R:1869814
1869830 | 02 tweede verdieping | 02 tweede verdieping | 0.278316 | 1953 | 0.00956189 | 1869825 | Model Group:31_2A DK R:1869831
1869835 | 02 tweede verdieping | 02 tweede verdieping | 0.047036 | 301 | 0.0014737 | 1869825 | Model Group:31_2A DK R:1869831
1869847 | 02 tweede verdieping | 02 tweede verdieping | 0.278316 | 1953 | 0.00956189 | 1869842 | Model Group:31_2A DK R:1869848
1869852 | 02 tweede verdieping | 02 tweede verdieping | 0.047036 | 301 | 0.0014737 | 1869842 | Model Group:31_2A DK R:1869848
1897637 | 00 begane grond | 00 begane grond | 0.079936 | 536 | 0.00262426 | 1897632 | Model Group:BU-07 b900 (members excluded):1300686
1897641 | 00 begane grond | 00 begane grond | 0.331936 | 2336 | 0.0114371 | 1897632 | Model Group:BU-07 b900 (members excluded):1300686
1897651 | 00 begane grond | 00 begane grond | 0.079936 | 536 | 0.00262426 | 1897646 | Model Group:BU-07 b900 (members excluded):1818605
1897655 | 00 begane grond | 00 begane grond | 0.331936 | 2336 | 0.0114371 | 1897646 | Model Group:BU-07 b900 (members excluded):1818605
1898044 | 01 eerste verdieping | 01 eerste verdieping | 0.268656 | 1884 | 0.00922406 | 1898039 | Model Group:31_1A DKD R:1898045
1932984 | 00 begane grond | 00 begane grond | 0.079936 | 536 | 0.00262426 | 1932979 | Model Group:BU-17 b3000:1900158
1932994 | 00 begane grond | 00 begane grond | 0.331936 | 2336 | 0.0114371 | 1932979 | Model Group:BU-17 b3000:1900158
2012530 | 01 eerste verdieping | 01 eerste verdieping | 0.268656 | 1884 | 0.00922406 | 2012525 | Model Group:31_1A DKD L:2012531
2012560 | 01 eerste verdieping | 01 eerste verdieping | 0.268656 | 1884 | 0.00922406 | 2012555 | Model Group:31_1A DKD L:2012561
2012575 | 01 eerste verdieping | 01 eerste verdieping | 0.261656 | 1834 | 0.00897926 | 2012570 | Model Group:BU-38:2702101
2172435 | 01 eerste verdieping | 01 eerste verdieping | 0.268656 | 1884 | 0.00922406 | 2172430 | Model Group:31_1A SVGD R:2172436
2182234 | 03 derde verdieping | 03 derde verdieping | 0.125856 | 864 | 0.00423014 | 2182229 | Model Group:daklicht A1:2182252
2182287 | 03 derde verdieping | 03 derde verdieping | 0.125856 | 864 | 0.00423014 | 2182282 | Model Group:daklicht A1 (members excluded):2182288
2182307 | 03 derde verdieping | 03 derde verdieping | 0.125856 | 864 | 0.00423014 | 2182302 | Model Group:31_daklicht_B (members excluded):2194619
2194634 | 03 derde verdieping | 03 derde verdieping | 0.125856 | 864 | 0.00423014 | 2194629 | Model Group:31_daklicht_C:2194635
2194781 | 03 derde verdieping | 03 derde verdieping | 0.125856 | 864 | 0.00423014 | 2194776 | Model Group:31_daklicht_B:2194786
2194792 | 03 derde verdieping | 03 derde verdieping | 0.125856 | 864 | 0.00423014 | 2194787 | Model Group:31_daklicht_C:2194793
2245691 | 01 eerste verdieping | 01 eerste verdieping | 0.268656 | 1884 | 0.00922406 | 2245686 | Model Group:BU-34:2700766
2266690 | 01 eerste verdieping | 01 eerste verdieping | 0.268656 | 1884 | 0.00922406 | 2266685 | Model Group:31_1A DK L:2266691
2266707 | 02 tweede verdieping | 02 tweede verdieping | 0.278316 | 1953 | 0.00956189 | 2266702 | Model Group:31_2A DK L:2266708
2266712 | 02 tweede verdieping | 02 tweede verdieping | 0.047036 | 301 | 0.0014737 | 2266702 | Model Group:31_2A DK L:2266708
2266722 | 02 tweede verdieping | 02 tweede verdieping | 0.278316 | 1953 | 0.00956189 | 2266717 | Model Group:31_2A DK R:2266723
2266727 | 02 tweede verdieping | 02 tweede verdieping | 0.047036 | 301 | 0.0014737 | 2266717 | Model Group:31_2A DK R:2266723
2649839 | 00 begane grond | 00 begane grond | 0.079936 | 536 | 0.00262426 | 2649834 | Model Group:BU-47 b4200:1822720
2649843 | 00 begane grond | 00 begane grond | 0.331936 | 2336 | 0.0114371 | 2649834 | Model Group:BU-47 b4200:1822720
2652549 | 00 begane grond | 00 begane grond | 0.079936 | 536 | 0.00262426 | 2652544 | Model Group:BU-11 b3000:1502212
2652559 | 00 begane grond | 00 begane grond | 0.331936 | 2336 | 0.0114371 | 2652544 | Model Group:BU-11 b3000:1502212
2652635 | 00 begane grond | 00 begane grond | 0.079936 | 536 | 0.00262426 | 2652630 | Model Group:BU-11 b3000:1502763
2652645 | 00 begane grond | 00 begane grond | 0.331936 | 2336 | 0.0114371 | 2652630 | Model Group:BU-11 b3000:1502763
2712311 | 01 eerste verdieping | 01 eerste verdieping | 0.268656 | 1884 | 0.00922406 | 2712306 | Model Group:BU-36:2701416
2712500 | 01 eerste verdieping | 01 eerste verdieping | 0.268656 | 1884 | 0.00922406 | 2712495 | Model Group:BU-37:2712501
2776735 | 01 eerste verdieping | 01 eerste verdieping | 0.268656 | 1884 | 0.00922406 | 2776730 | Model Group:31_1A SVGD L:2776736
3003073 | 00 begane grond | 00 begane grond | 0.079936 | 536 | 0.00262426 | 3003068 | Model Group:BU-01 b1500:3003067
3003077 | 00 begane grond | 00 begane grond | 0.331936 | 2336 | 0.0114371 | 3003068 | Model Group:BU-01 b1500:3003067
3016887 | 00 begane grond | 00 begane grond | 0.079936 | 536 | 0.00262426 | 3016883
3016890 | 00 begane grond | 00 begane grond | 0.331936 | 2336 | 0.0114371 | 3016883
3058235 | 01 eerste verdieping | 01 eerste verdieping | 0.268656 | 1884 | 0.00922406 | 3058230 | Model Group:31_1A DKD R:3058236
3451935 | 00 begane grond | 00 begane grond | 0.083856 | 564 | 0.00276134 | 3451930 | Model Group:BU-45 b900:2546304
3451939 | 00 begane grond | 00 begane grond | 0.273836 | 1921 | 0.00940522 | 3451930 | Model Group:BU-45 b900:2546304
3836662 | 00 begane grond | 00 begane grond | 0.079936 | 536 | 0.00262426 | 3836657 | Model Group:BU-16:3836676
3836666 | 00 begane grond | 00 begane grond | 0.334736 | 2356 | 0.011535 | 3836657 | Model Group:BU-16:3836676
4196778 | 00 begane grond | 00 begane grond | 0.079936 | 536 | 0.00262426 | 4196773 | Model Group:BU-46:4200502
4196782 | 00 begane grond | 00 begane grond | 0.334736 | 2356 | 0.011535 | 4196773 | Model Group:BU-46:4200502

# IfcMember: Rectangular Mullion:RT72_Hr_raam hoek A, Rectangular Mullion:RT72_Hr_raam hoek A:881851
In: 01 eerste verdieping
Type - PredefinedType: MULLION; Material: <Unnamed>, a_kozijn
Type - Constraints - Angle: 0 deg; Offset: 20 mm
Type - Construction - Corner Mullion: no; Position: Perpendicular to Face; Profile: RT72_hoekoplossing profiel : RT72_hoekoplossing profiel; Thickness: 104 mm
Type - Dimensions - Width on side 1: 52 mm; Width on side 2: 52 mm
Type - Identity Data - Workset: Family : Curtain Wall Mullions : Rectangular Mullion; Type Name: RT72_Hr_raam hoek A
Type - Other - Category: Curtain Wall Mullions; Family Name: Rectangular Mullion
Material: a_kozijn; Group: Model Group:BU-35:2701985
Constraints - Level: 01 eerste verdieping
Phasing - Phase Created: 2. nieuwbouw
Dimensions - Area: 0.429952 m2; Length: 2020 mm; Volume: 0.0197798 m3
Identity Data - Workset: Workset1
Other - Family: Rectangular Mullion; Host Id: 881846; Family and Type: Rectangular Mullion: RT72_Hr_raam hoek A; Type: RT72_Hr_raam hoek A; Type Id: 2758291

# IfcMember: Rectangular Mullion:RT72_Hr_raam hoek B (2)
In: 01 eerste verdieping
Type - PredefinedType: MULLION; Material: <Unnamed>, a_kozijn
Type - Constraints - Angle: 90 deg; Offset: 20 mm
Type - Construction - Corner Mullion: no; Position: Perpendicular to Face; Profile: RT72_hoekoplossing profiel : RT72_hoekoplossing profiel; Thickness: 104 mm
Type - Dimensions - Width on side 1: 52 mm; Width on side 2: 52 mm
Type - Identity Data - Workset: Family : Curtain Wall Mullions : Rectangular Mullion; Type Name: RT72_Hr_raam hoek B
Type - Other - Category: Curtain Wall Mullions; Family Name: Rectangular Mullion
Material: a_kozijn
Constraints - Level: 01 eerste verdieping
Phasing - Phase Created: 2. nieuwbouw
Dimensions - Area: 0.429952 m2; Length: 2020 mm; Volume: 0.0197798 m3
Identity Data - Workset: Workset1
Other - Family: Rectangular Mullion; Family and Type: Rectangular Mullion: RT72_Hr_raam hoek B; Type: RT72_Hr_raam hoek B; Type Id: 2759954
Name (Rectangular Mullion:RT72_Hr_raam hoek B:...) | Host Id | Group
2245690 | 2245686 | Model Group:BU-34:2700766
2712499 | 2712495 | Model Group:BU-37:2712501

# IfcMember: Rectangular Mullion:RT72_Hr_raam hoek omgekeerd, Rectangular Mullion:RT72_Hr_raam hoek omgekeerd:1854933
In: 00 begane grond
Type - PredefinedType: MULLION; Material: <Unnamed>, a_kozijn
Type - Constraints - Angle: 90 deg; Offset: 52 mm
Type - Construction - Corner Mullion: no; Position: Perpendicular to Face; Profile: RT72_hoekoplossing profiel - omgekeerd : RT72_hoekoplossing profiel - omgekeerd; Thickness: 104 mm
Type - Dimensions - Width on side 1: 52 mm; Width on side 2: 52 mm
Type - Identity Data - Workset: Family : Curtain Wall Mullions : Rectangular Mullion; Type Name: RT72_Hr_raam hoek omgekeerd
Type - Other - Category: Curtain Wall Mullions; Family Name: Rectangular Mullion
Material: a_kozijn; Group: Model Group:BU-19 b2067:2651286
Constraints - Level: 00 begane grond
Phasing - Phase Created: 2. nieuwbouw
Dimensions - Area: 0.607168 m2; Length: 2872 mm; Volume: 0.0281226 m3
Identity Data - Workset: Workset1
Other - Family: Rectangular Mullion; Host Id: 1854929; Family and Type: Rectangular Mullion: RT72_Hr_raam hoek omgekeerd; Type: RT72_Hr_raam hoek omgekeerd; Type Id: 2792376

# IfcMember: Rectangular Mullion:RT72_Vb_raam (266)
Type - PredefinedType: MULLION; Material: <Unnamed>, a_kozijn
Type - Constraints - Angle: 0 deg; Offset: 0 mm
Type - Construction - Corner Mullion: no; Position: Perpendicular to Face; Profile: BDG_RT72_Vm_raam : Vb_raam; Thickness: 72 mm
Type - Dimensions - Width on side 1: 34 mm; Width on side 2: 34 mm
Type - Identity Data - Type Name: RT72_Vb_raam; Workset: Family : Curtain Wall Mullions : Rectangular Mullion
Type - Other - Category: Curtain Wall Mullions; Family Name: Rectangular Mullion
Material: a_kozijn
Phasing - Phase Created: 2. nieuwbouw
Identity Data - Workset: Workset1
Other - Family: Rectangular Mullion; Family and Type: Rectangular Mullion: RT72_Vb_raam; Type: RT72_Vb_raam; Type Id: 835104
Name (Rectangular Mullion:RT72_Vb_raam:...) | In | Level | Area (m2) | Length (mm) | Volume (m3) | Host Id | Group
870543 | 02 tweede verdieping | 02 tweede verdieping | 0.123896 | 850 | 0.0041616 | 870541 | Model Group:31_2A:870547
879500 | 02 tweede verdieping | 02 tweede verdieping | 0.104856 | 714 | 0.00349574 | 870541 | Model Group:31_2A:870547
870749 | 02 tweede verdieping | 02 tweede verdieping | 0.123896 | 850 | 0.0041616 | 870747 | Model Group:31_2A:870753
879536 | 02 tweede verdieping | 02 tweede verdieping | 0.104856 | 714 | 0.00349574 | 870747 | Model Group:31_2A:870753
870862 | 02 tweede verdieping | 02 tweede verdieping | 0.123896 | 850 | 0.0041616 | 870860 | Model Group:31_2A:870866
879554 | 02 tweede verdieping | 02 tweede verdieping | 0.104856 | 714 | 0.00349574 | 870860 | Model Group:31_2A:870866
871637 | 02 tweede verdieping | 02 tweede verdieping | 0.123896 | 850 | 0.0041616 | 871635 | Model Group:31_2A:871641
878917 | 02 tweede verdieping | 02 tweede verdieping | 0.104856 | 714 | 0.00349574 | 871635 | Model Group:31_2A:871641
871670 | 02 tweede verdieping | 02 tweede verdieping | 0.123896 | 850 | 0.0041616 | 871668 | Model Group:31_2A:871674
879572 | 02 tweede verdieping | 02 tweede verdieping | 0.104856 | 714 | 0.00349574 | 871668 | Model Group:31_2A:871674
871921 | 02 tweede verdieping | 02 tweede verdieping | 0.123896 | 850 | 0.0041616 | 871919 | Model Group:31_2A:871925
879590 | 02 tweede verdieping | 02 tweede verdieping | 0.104856 | 714 | 0.00349574 | 871919 | Model Group:31_2A:871925
871953 | 02 tweede verdieping | 02 tweede verdieping | 0.123896 | 850 | 0.0041616 | 871951 | Model Group:31_2A:871957
879596 | 02 tweede verdieping | 02 tweede verdieping | 0.104856 | 714 | 0.00349574 | 871951 | Model Group:31_2A:871957
872815 | 02 tweede verdieping | 02 tweede verdieping | 0.123896 | 850 | 0.0041616 | 872813 | Model Group:31_2A:872819
879620 | 02 tweede verdieping | 02 tweede verdieping | 0.104856 | 714 | 0.00349574 | 872813 | Model Group:31_2A:872819
872881 | 02 tweede verdieping | 02 tweede verdieping | 0.123896 | 850 | 0.0041616 | 872879 | Model Group:31_2A:872885
879632 | 02 tweede verdieping | 02 tweede verdieping | 0.104856 | 714 | 0.00349574 | 872879 | Model Group:31_2A:872885
872914 | 02 tweede verdieping | 02 tweede verdieping | 0.123896 | 850 | 0.0041616 | 872912 | Model Group:31_2A:872918
879638 | 02 tweede verdieping | 02 tweede verdieping | 0.104856 | 714 | 0.00349574 | 872912 | Model Group:31_2A:872918
872947 | 02 tweede verdieping | 02 tweede verdieping | 0.123896 | 850 | 0.0041616 | 872945 | Model Group:31_2A:872951
879644 | 02 tweede verdieping | 02 tweede verdieping | 0.104856 | 714 | 0.00349574 | 872945 | Model Group:31_2A:872951
872980 | 02 tweede verdieping | 02 tweede verdieping | 0.123896 | 850 | 0.0041616 | 872978 | Model Group:31_2A:872984
879650 | 02 tweede verdieping | 02 tweede verdieping | 0.104856 | 714 | 0.00349574 | 872978 | Model Group:31_2A:872984
873013 | 02 tweede verdieping | 02 tweede verdieping | 0.123896 | 850 | 0.0041616 | 873011 | Model Group:31_2A:873017
879656 | 02 tweede verdieping | 02 tweede verdieping | 0.104856 | 714 | 0.00349574 | 873011 | Model Group:31_2A:873017
873079 | 02 tweede verdieping | 02 tweede verdieping | 0.123896 | 850 | 0.0041616 | 873077 | Model Group:31_2A:873083
879668 | 02 tweede verdieping | 02 tweede verdieping | 0.104856 | 714 | 0.00349574 | 873077 | Model Group:31_2A:873083
873510 | 02 tweede verdieping | 02 tweede verdieping | 0.123896 | 850 | 0.0041616 | 873508 | Model Group:31_2A:873514
879704 | 02 tweede verdieping | 02 tweede verdieping | 0.104856 | 714 | 0.00349574 | 873508 | Model Group:31_2A:873514
873603 | 02 tweede verdieping | 02 tweede verdieping | 0.123896 | 850 | 0.0041616 | 873601 | Model Group:31_2A:873607
879722 | 02 tweede verdieping | 02 tweede verdieping | 0.104856 | 714 | 0.00349574 | 873601 | Model Group:31_2A:873607
873696 | 02 tweede verdieping | 02 tweede verdieping | 0.123896 | 850 | 0.0041616 | 873694 | Model Group:31_2A:873700
879740 | 02 tweede verdieping | 02 tweede verdieping | 0.104856 | 714 | 0.00349574 | 873694 | Model Group:31_2A:873700
874668 | 01 eerste verdieping | 01 eerste verdieping | 0.252836 | 1771 | 0.00867082 | 874666 | Model Group:31_1A:874672
874952 | 01 eerste verdieping | 01 eerste verdieping | 0.252836 | 1771 | 0.00867082 | 874950 | Model Group:31_1A:874956
875027 | 01 eerste verdieping | 01 eerste verdieping | 0.067056 | 444 | 0.00217382 | 875025 | Model Group:31_1A DKD L:875031
1864424 | 01 eerste verdieping | 01 eerste verdieping | 0.190676 | 1327 | 0.00649699 | 875025 | Model Group:31_1A DKD L:875031
875042 | 01 eerste verdieping | 01 eerste verdieping | 0.252836 | 1771 | 0.00867082 | 875040 | Model Group:31_1A:875046
875051 | 01 eerste verdieping | 01 eerste verdieping | 0.190676 | 1327 | 0.00649699 | 875049 | Model Group:31_1A DK R:875055
1864687 | 01 eerste verdieping | 01 eerste verdieping | 0.067056 | 444 | 0.00217382 | 875049 | Model Group:31_1A DK R:875055
875270 | 01 eerste verdieping | 01 eerste verdieping | 0.252836 | 1771 | 0.00867082 | 875268 | Model Group:31_1A:875274
875306 | 01 eerste verdieping | 01 eerste verdieping | 0.190676 | 1327 | 0.00649699 | 875304 | Model Group:31_1A DKD R:875310
1865120 | 01 eerste verdieping | 01 eerste verdieping | 0.067056 | 444 | 0.00217382 | 875304 | Model Group:31_1A DKD R:875310
875378 | 01 eerste verdieping | 01 eerste verdieping | 0.252836 | 1771 | 0.00867082 | 875376 | Model Group:31_1A:875382
876489 | 01 eerste verdieping | 01 eerste verdieping | 0.252836 | 1771 | 0.00867082 | 876487 | Model Group:31_1A:876493
876907 | 01 eerste verdieping | 01 eerste verdieping | 0.252836 | 1771 | 0.00867082 | 876905 | Model Group:31_1A:876911
877024 | 01 eerste verdieping | 01 eerste verdieping | 0.252836 | 1771 | 0.00867082 | 877022 | Model Group:31_1A:877028
877114 | 01 eerste verdieping | 01 eerste verdieping | 0.252836 | 1771 | 0.00867082 | 877112 | Model Group:31_1A:877118
877204 | 01 eerste verdieping | 01 eerste verdieping | 0.252836 | 1771 | 0.00867082 | 877202 | Model Group:31_1A:877208
877519 | 02 tweede verdieping | 02 tweede verdieping | 0.127536 | 876 | 0.0042889 | 877517 | Model Group:BU-40:2712884
877739 | 02 tweede verdieping | 02 tweede verdieping | 0.267816 | 1878 | 0.00919469 | 877517 | Model Group:BU-40:2712884
877801 | 02 tweede verdieping | 02 tweede verdieping | 0.080146 | 537.5 | 0.0026316 | 877517 | Model Group:BU-40:2712884
1483764 | 02 tweede verdieping | 02 tweede verdieping | 0.015116 | 73 | 0.000357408 | 877517 | Model Group:BU-40:2712884
1483871 | 02 tweede verdieping | 02 tweede verdieping | 0.127466 | 875.5 | 0.00428645 | 877517 | Model Group:BU-40:2712884
1848500 | 02 tweede verdieping | 02 tweede verdieping | 0.080076 | 537 | 0.00262915 | 877517 | Model Group:BU-40:2712884
1848733 | 02 tweede verdieping | 02 tweede verdieping | 0.015116 | 73 | 0.000357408 | 877517 | Model Group:BU-40:2712884
880923 | 01 eerste verdieping | 01 eerste verdieping | 0.252836 | 1771 | 0.00867082 | 880921 | Model Group:31_1A:880927
881684 | 01 eerste verdieping | 01 eerste verdieping | 0.252836 | 1771 | 0.00867082 | 881682 | Model Group:31_1A:881688
881848 | 01 eerste verdieping | 01 eerste verdieping | 0.047806 | 306.5 | 0.00150062 | 881846 | Model Group:BU-35:2701985
891676 | 01 eerste verdieping | 01 eerste verdieping | 0.252836 | 1771 | 0.00867082 | 891674 | Model Group:31_1A:891680
891759 | 01 eerste verdieping | 01 eerste verdieping | 0.085536 | 576 | 0.0028201 | 891757 | Model Group:BU-30:2700215
891788 | 01 eerste verdieping | 01 eerste verdieping | 0.252836 | 1771 | 0.00867082 | 891786 | Model Group:31_1A:891792
891905 | 01 eerste verdieping | 01 eerste verdieping | 0.252836 | 1771 | 0.00867082 | 891903 | Model Group:31_1A:891909
891927 | 01 eerste verdieping | 01 eerste verdieping | 0.252836 | 1771 | 0.00867082 | 891925 | Model Group:31_1A:891931
891977 | 01 eerste verdieping | 01 eerste verdieping | 0.252836 | 1771 | 0.00867082 | 891975 | Model Group:31_1A:891981
891999 | 01 eerste verdieping | 01 eerste verdieping | 0.145876 | 1007 | 0.00493027 | 891997 | Model Group:BU-32:892003
1837445 | 01 eerste verdieping | 01 eerste verdieping | 0.111856 | 764 | 0.00374054 | 891997 | Model Group:BU-32:892003
892040 | 00 begane grond | 00 begane grond | 0.130896 | 900 | 0.0044064 | 892038 | Model Group:BU-07 b900:894363
894430 | 00 begane grond | 00 begane grond | 0.256896 | 1800 | 0.0088128 | 894428 | Model Group:BU-06 b1800:894434
1220072 | 00 begane grond | 00 begane grond | 0.145876 | 1007 | 0.00493027 | 1220070 | Model Group:BU-08 b2100:1220076
1861210 | 00 begane grond | 00 begane grond | 0.157916 | 1093 | 0.00535133 | 1220070 | Model Group:BU-08 b2100:1220076
1220171 | 00 begane grond | 00 begane grond | 0.073916 | 493 | 0.00241373 | 1220169 | Model Group:BU-09 b1500:1220175
1859714 | 00 begane grond | 00 begane grond | 0.145876 | 1007 | 0.00493027 | 1220169 | Model Group:BU-09 b1500:1220175
1220849 | 00 begane grond | 00 begane grond | 0.283916 | 1993 | 0.00975773 | 1220847 | Model Group:BU-11 b3000:1220846
1492351 | 00 begane grond | 00 begane grond | 0.145876 | 1007 | 0.00493027 | 1220847 | Model Group:BU-11 b3000:1220846
1300403 | 00 begane grond | 00 begane grond | 0.130896 | 900 | 0.0044064 | 1300401 | Model Group:BU-07 b900 (members excluded):1300407
1300455 | 00 begane grond | 00 begane grond | 0.241916 | 1693 | 0.00828893 | 1300453 | Model Group:BU-22 b2700:1300414
1489287 | 00 begane grond | 00 begane grond | 0.145876 | 1007 | 0.00493027 | 1300453 | Model Group:BU-22 b2700:1300414
1300744 | 00 begane grond | 00 begane grond | 0.279156 | 1959 | 0.00959126 | 1300742 | Model Group:BU-21 b2966:1300741
1491167 | 00 begane grond | 00 begane grond | 0.145876 | 1007 | 0.00493027 | 1300742 | Model Group:BU-21 b2966:1300741
1300956 | 00 begane grond | 00 begane grond | 0.325916 | 2293 | 0.0112265 | 1300954 | Model Group:BU-20 b3300:1300930
1491987 | 00 begane grond | 00 begane grond | 0.145876 | 1007 | 0.00493027 | 1300954 | Model Group:BU-20 b3300:1300930
1300994 | 00 begane grond | 00 begane grond | 0.145876 | 1007 | 0.00493027 | 1300992 | Model Group:BU-23 b1353:2651710
1899349 | 00 begane grond | 00 begane grond | 0.063416 | 418 | 0.00204653 | 1300992 | Model Group:BU-23 b1353:2651710
1302056 | 01 eerste verdieping | 01 eerste verdieping | 0.252836 | 1771 | 0.00867082 | 1302054 | Model Group:BU-31:891953
1493477 | 00 begane grond | 00 begane grond | 0.145876 | 1007 | 0.00493027 | 1493475 | Model Group:BU-25 b3000:1493474
1493865 | 00 begane grond | 00 begane grond | 0.277686 | 1948.5 | 0.00953986 | 1493475 | Model Group:BU-25 b3000:1493474
1494107 | 00 begane grond | 00 begane grond | 0.145876 | 1007 | 0.00493027 | 1494105 | Model Group:BU-02 b4200:1494104
1494113 | 00 begane grond | 00 begane grond | 0.307436 | 2161 | 0.0105803 | 1494105 | Model Group:BU-02 b4200:1494104
2012618 | 00 begane grond | 00 begane grond | 0.145876 | 1007 | 0.00493027 | 1494105 | Model Group:BU-02 b4200:1494104
1494516 | 00 begane grond | 00 begane grond | 0.146996 | 1015 | 0.00496944 | 1494514 | Model Group:BU-14 b3000:1494513
1823027 | 00 begane grond | 00 begane grond | 0.282796 | 1985 | 0.00971856 | 1494514 | Model Group:BU-14 b3000:1494513
1502983 | 00 begane grond | 00 begane grond | 0.130896 | 900 | 0.0044064 | 1502981 | Model Group:BU-07 b900:1502980
1817351 | 00 begane grond | 00 begane grond | 0.145876 | 1007 | 0.00493027 | 1817349 | Model Group:BU-12 b4200:1817348
1817643 | 00 begane grond | 00 begane grond | 0.307436 | 2161 | 0.0105803 | 1817349 | Model Group:BU-12 b4200:1817348
1817863 | 00 begane grond | 00 begane grond | 0.145876 | 1007 | 0.00493027 | 1817349 | Model Group:BU-12 b4200:1817348
1818871 | 00 begane grond | 00 begane grond | 0.161976 | 1122 | 0.00549331 | 1818869 | Model Group:BU-03 b5800:1818868
1818877 | 00 begane grond | 00 begane grond | 0.141816 | 978 | 0.00478829 | 1818869 | Model Group:BU-03 b5800:1818868
1818890 | 00 begane grond | 00 begane grond | 0.145876 | 1007 | 0.00493027 | 1818869 | Model Group:BU-03 b5800:1818868
1819724 | 00 begane grond | 00 begane grond | 0.269916 | 1893 | 0.00926813 | 1818869 | Model Group:BU-03 b5800:1818868
1819904 | 00 begane grond | 00 begane grond | 0.286646 | 2012.5 | 0.0098532 | 1819902 | Model Group:BU-05 b1910:2648634
1822153 | 00 begane grond | 00 begane grond | 0.115916 | 793 | 0.00388253 | 1822151 | Model Group:BU-10 b1800:1822150
1822159 | 00 begane grond | 00 begane grond | 0.145876 | 1007 | 0.00493027 | 1822151 | Model Group:BU-10 b1800:1822150
1823300 | 00 begane grond | 00 begane grond | 0.311496 | 2190 | 0.0107222 | 1823298 | Model Group:BU-15 b4200:1823297
1823319 | 00 begane grond | 00 begane grond | 0.145876 | 1007 | 0.00493027 | 1823298 | Model Group:BU-15 b4200:1823297
1823327 | 00 begane grond | 00 begane grond | 0.141816 | 978 | 0.00478829 | 1823298 | Model Group:BU-15 b4200:1823297
1853994 | 00 begane grond | 00 begane grond | 0.133836 | 921 | 0.00450922 | 1853992 | Model Group:BU-18 b3017:2651211
1854000 | 00 begane grond | 00 begane grond | 0.284686 | 1998.5 | 0.00978466 | 1853992 | Model Group:BU-18 b3017:2651211
1856675 | 00 begane grond | 00 begane grond | 0.016516 | 83 | 0.000406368 | 1853992 | Model Group:BU-18 b3017:2651211
1854931 | 00 begane grond | 00 begane grond | 0.304356 | 2139 | 0.0104725 | 1854929 | Model Group:BU-19 b2067:2651286
1862277 | 00 begane grond | 00 begane grond | 0.145876 | 1007 | 0.00493027 | 1862275 | Model Group:BU-13 b3300:1862274
1862283 | 00 begane grond | 00 begane grond | 0.325916 | 2293 | 0.0112265 | 1862275 | Model Group:BU-13 b3300:1862274
1864616 | 01 eerste verdieping | 01 eerste verdieping | 0.067056 | 444 | 0.00217382 | 1864614 | Model Group:31_1A SVGD L:1864620
1864624 | 01 eerste verdieping | 01 eerste verdieping | 0.190676 | 1327 | 0.00649699 | 1864614 | Model Group:31_1A SVGD L:1864620
1864934 | 01 eerste verdieping | 01 eerste verdieping | 0.190676 | 1327 | 0.00649699 | 1864932 | Model Group:31_1A DK R:1864938
1864942 | 01 eerste verdieping | 01 eerste verdieping | 0.067056 | 444 | 0.00217382 | 1864932 | Model Group:31_1A DK R:1864938
1864978 | 01 eerste verdieping | 01 eerste verdieping | 0.067056 | 444 | 0.00217382 | 1864976 | Model Group:31_1A DKD L:1864982
1864986 | 01 eerste verdieping | 01 eerste verdieping | 0.190676 | 1327 | 0.00649699 | 1864976 | Model Group:31_1A DKD L:1864982
1865003 | 01 eerste verdieping | 01 eerste verdieping | 0.190676 | 1327 | 0.00649699 | 1865001 | Model Group:31_1A DK R:1865007
1865011 | 01 eerste verdieping | 01 eerste verdieping | 0.067056 | 444 | 0.00217382 | 1865001 | Model Group:31_1A DK R:1865007
1865026 | 01 eerste verdieping | 01 eerste verdieping | 0.067056 | 444 | 0.00217382 | 1865024 | Model Group:31_1A DKD L:1865030
1865034 | 01 eerste verdieping | 01 eerste verdieping | 0.190676 | 1327 | 0.00649699 | 1865024 | Model Group:31_1A DKD L:1865030
1865342 | 01 eerste verdieping | 01 eerste verdieping | 0.190676 | 1327 | 0.00649699 | 1865340 | Model Group:31_1A DKD R:1865346
1865350 | 01 eerste verdieping | 01 eerste verdieping | 0.067056 | 444 | 0.00217382 | 1865340 | Model Group:31_1A DKD R:1865346
1865363 | 01 eerste verdieping | 01 eerste verdieping | 0.067056 | 444 | 0.00217382 | 1865361 | Model Group:31_1A DK L:1865367
1865371 | 01 eerste verdieping | 01 eerste verdieping | 0.190676 | 1327 | 0.00649699 | 1865361 | Model Group:31_1A DK L:1865367
1865570 | 01 eerste verdieping | 01 eerste verdieping | 0.190676 | 1327 | 0.00649699 | 1865568 | Model Group:31_1A DKD R:1865574
1865578 | 01 eerste verdieping | 01 eerste verdieping | 0.067056 | 444 | 0.00217382 | 1865568 | Model Group:31_1A DKD R:1865574
1865604 | 01 eerste verdieping | 01 eerste verdieping | 0.190676 | 1327 | 0.00649699 | 1865602 | Model Group:31_1A DKD R:1865608
1865612 | 01 eerste verdieping | 01 eerste verdieping | 0.067056 | 444 | 0.00217382 | 1865602 | Model Group:31_1A DKD R:1865608
1865651 | 01 eerste verdieping | 01 eerste verdieping | 0.067056 | 444 | 0.00217382 | 1865649 | Model Group:31_1A DK L:1865655
1865659 | 01 eerste verdieping | 01 eerste verdieping | 0.190676 | 1327 | 0.00649699 | 1865649 | Model Group:31_1A DK L:1865655
1865670 | 01 eerste verdieping | 01 eerste verdieping | 0.067056 | 444 | 0.00217382 | 1865668 | Model Group:31_1A DK L:1865674
1865678 | 01 eerste verdieping | 01 eerste verdieping | 0.190676 | 1327 | 0.00649699 | 1865668 | Model Group:31_1A DK L:1865674
1865777 | 01 eerste verdieping | 01 eerste verdieping | 0.190676 | 1327 | 0.00649699 | 1865775 | Model Group:31_1A DKD R:1865781
1865785 | 01 eerste verdieping | 01 eerste verdieping | 0.067056 | 444 | 0.00217382 | 1865775 | Model Group:31_1A DKD R:1865781
1865798 | 01 eerste verdieping | 01 eerste verdieping | 0.067056 | 444 | 0.00217382 | 1865796 | Model Group:31_1A DK L:1865802
1865806 | 01 eerste verdieping | 01 eerste verdieping | 0.190676 | 1327 | 0.00649699 | 1865796 | Model Group:31_1A DK L:1865802
1865919 | 01 eerste verdieping | 01 eerste verdieping | 0.190676 | 1327 | 0.00649699 | 1865917 | Model Group:31_1A DK R:1865923
1865927 | 01 eerste verdieping | 01 eerste verdieping | 0.067056 | 444 | 0.00217382 | 1865917 | Model Group:31_1A DK R:1865923
1865942 | 01 eerste verdieping | 01 eerste verdieping | 0.067056 | 444 | 0.00217382 | 1865940 | Model Group:31_1A DKD L:1865946
1865950 | 01 eerste verdieping | 01 eerste verdieping | 0.190676 | 1327 | 0.00649699 | 1865940 | Model Group:31_1A DKD L:1865946
1866078 | 01 eerste verdieping | 01 eerste verdieping | 0.067056 | 444 | 0.00217382 | 1866076 | Model Group:31_1A DKg R:1866082
1866086 | 01 eerste verdieping | 01 eerste verdieping | 0.190676 | 1327 | 0.00649699 | 1866076 | Model Group:31_1A DKg R:1866082
1867673 | 02 tweede verdieping | 02 tweede verdieping | 0.123896 | 850 | 0.0041616 | 1867671 | Model Group:31_2A DK R:1867677
1867683 | 02 tweede verdieping | 02 tweede verdieping | 0.104856 | 714 | 0.00349574 | 1867671 | Model Group:31_2A DK R:1867677
1869341 | 02 tweede verdieping | 02 tweede verdieping | 0.123896 | 850 | 0.0041616 | 1869339 | Model Group:31_2A DK R:1869345
1869350 | 02 tweede verdieping | 02 tweede verdieping | 0.104856 | 714 | 0.00349574 | 1869339 | Model Group:31_2A DK R:1869345
1869358 | 02 tweede verdieping | 02 tweede verdieping | 0.123896 | 850 | 0.0041616 | 1869356 | Model Group:31_2A DK R:1869362
1869367 | 02 tweede verdieping | 02 tweede verdieping | 0.104856 | 714 | 0.00349574 | 1869356 | Model Group:31_2A DK R:1869362
1869375 | 02 tweede verdieping | 02 tweede verdieping | 0.123896 | 850 | 0.0041616 | 1869373 | Model Group:31_2A DK R:1869379
1869384 | 02 tweede verdieping | 02 tweede verdieping | 0.104856 | 714 | 0.00349574 | 1869373 | Model Group:31_2A DK R:1869379
1869392 | 02 tweede verdieping | 02 tweede verdieping | 0.123896 | 850 | 0.0041616 | 1869390 | Model Group:31_2A DK R:1869396
1869401 | 02 tweede verdieping | 02 tweede verdieping | 0.104856 | 714 | 0.00349574 | 1869390 | Model Group:31_2A DK R:1869396
1869409 | 02 tweede verdieping | 02 tweede verdieping | 0.123896 | 850 | 0.0041616 | 1869407 | Model Group:31_2A DK R:1869413
1869418 | 02 tweede verdieping | 02 tweede verdieping | 0.104856 | 714 | 0.00349574 | 1869407 | Model Group:31_2A DK R:1869413
1869426 | 02 tweede verdieping | 02 tweede verdieping | 0.123896 | 850 | 0.0041616 | 1869424 | Model Group:31_2A DK R:1869430
1869435 | 02 tweede verdieping | 02 tweede verdieping | 0.104856 | 714 | 0.00349574 | 1869424 | Model Group:31_2A DK R:1869430
1869443 | 02 tweede verdieping | 02 tweede verdieping | 0.123896 | 850 | 0.0041616 | 1869441 | Model Group:31_2A DK R:1869447
1869452 | 02 tweede verdieping | 02 tweede verdieping | 0.104856 | 714 | 0.00349574 | 1869441 | Model Group:31_2A DK R:1869447
1869463 | 02 tweede verdieping | 02 tweede verdieping | 0.123896 | 850 | 0.0041616 | 1869461 | Model Group:31_2A DK L:1869467
1869472 | 02 tweede verdieping | 02 tweede verdieping | 0.104856 | 714 | 0.00349574 | 1869461 | Model Group:31_2A DK L:1869467
1869602 | 02 tweede verdieping | 02 tweede verdieping | 0.123896 | 850 | 0.0041616 | 1869600 | Model Group:31_2A DK L:1869606
1869611 | 02 tweede verdieping | 02 tweede verdieping | 0.104856 | 714 | 0.00349574 | 1869600 | Model Group:31_2A DK L:1869606
1869619 | 02 tweede verdieping | 02 tweede verdieping | 0.123896 | 850 | 0.0041616 | 1869617 | Model Group:31_2A DK L:1869623
1869628 | 02 tweede verdieping | 02 tweede verdieping | 0.104856 | 714 | 0.00349574 | 1869617 | Model Group:31_2A DK L:1869623
1869636 | 02 tweede verdieping | 02 tweede verdieping | 0.123896 | 850 | 0.0041616 | 1869634 | Model Group:31_2A DK L:1869640
1869645 | 02 tweede verdieping | 02 tweede verdieping | 0.104856 | 714 | 0.00349574 | 1869634 | Model Group:31_2A DK L:1869640
1869653 | 02 tweede verdieping | 02 tweede verdieping | 0.123896 | 850 | 0.0041616 | 1869651 | Model Group:31_2A DK L:1869657
1869662 | 02 tweede verdieping | 02 tweede verdieping | 0.104856 | 714 | 0.00349574 | 1869651 | Model Group:31_2A DK L:1869657
1869670 | 02 tweede verdieping | 02 tweede verdieping | 0.123896 | 850 | 0.0041616 | 1869668 | Model Group:31_2A DK L:1869674
1869679 | 02 tweede verdieping | 02 tweede verdieping | 0.104856 | 714 | 0.00349574 | 1869668 | Model Group:31_2A DK L:1869674
1869687 | 02 tweede verdieping | 02 tweede verdieping | 0.123896 | 850 | 0.0041616 | 1869685 | Model Group:31_2A DK L:1869691
1869696 | 02 tweede verdieping | 02 tweede verdieping | 0.104856 | 714 | 0.00349574 | 1869685 | Model Group:31_2A DK L:1869691
1869704 | 02 tweede verdieping | 02 tweede verdieping | 0.123896 | 850 | 0.0041616 | 1869702 | Model Group:31_2A DK L:1869708
1869713 | 02 tweede verdieping | 02 tweede verdieping | 0.104856 | 714 | 0.00349574 | 1869702 | Model Group:31_2A DK L:1869708
1869723 | 02 tweede verdieping | 02 tweede verdieping | 0.123896 | 850 | 0.0041616 | 1869721 | Model Group:31_2A DK L:1869727
1869732 | 02 tweede verdieping | 02 tweede verdieping | 0.104856 | 714 | 0.00349574 | 1869721 | Model Group:31_2A DK L:1869727
1869740 | 02 tweede verdieping | 02 tweede verdieping | 0.123896 | 850 | 0.0041616 | 1869738 | Model Group:31_2A DK L:1869744
1869749 | 02 tweede verdieping | 02 tweede verdieping | 0.104856 | 714 | 0.00349574 | 1869738 | Model Group:31_2A DK L:1869744
1869757 | 02 tweede verdieping | 02 tweede verdieping | 0.123896 | 850 | 0.0041616 | 1869755 | Model Group:31_2A DK R:1869761
1869766 | 02 tweede verdieping | 02 tweede verdieping | 0.104856 | 714 | 0.00349574 | 1869755 | Model Group:31_2A DK R:1869761
1869774 | 02 tweede verdieping | 02 tweede verdieping | 0.123896 | 850 | 0.0041616 | 1869772 | Model Group:31_2A DK R:1869778
1869783 | 02 tweede verdieping | 02 tweede verdieping | 0.104856 | 714 | 0.00349574 | 1869772 | Model Group:31_2A DK R:1869778
1869793 | 02 tweede verdieping | 02 tweede verdieping | 0.123896 | 850 | 0.0041616 | 1869791 | Model Group:31_2A DK R:1869797
1869802 | 02 tweede verdieping | 02 tweede verdieping | 0.104856 | 714 | 0.00349574 | 1869791 | Model Group:31_2A DK R:1869797
1869810 | 02 tweede verdieping | 02 tweede verdieping | 0.123896 | 850 | 0.0041616 | 1869808 | Model Group:31_2A DK R:1869814
1869819 | 02 tweede verdieping | 02 tweede verdieping | 0.104856 | 714 | 0.00349574 | 1869808 | Model Group:31_2A DK R:1869814
1869827 | 02 tweede verdieping | 02 tweede verdieping | 0.123896 | 850 | 0.0041616 | 1869825 | Model Group:31_2A DK R:1869831
1869836 | 02 tweede verdieping | 02 tweede verdieping | 0.104856 | 714 | 0.00349574 | 1869825 | Model Group:31_2A DK R:1869831
1869844 | 02 tweede verdieping | 02 tweede verdieping | 0.123896 | 850 | 0.0041616 | 1869842 | Model Group:31_2A DK R:1869848
1869853 | 02 tweede verdieping | 02 tweede verdieping | 0.104856 | 714 | 0.00349574 | 1869842 | Model Group:31_2A DK R:1869848
1897634 | 00 begane grond | 00 begane grond | 0.130896 | 900 | 0.0044064 | 1897632 | Model Group:BU-07 b900 (members excluded):1300686
1897648 | 00 begane grond | 00 begane grond | 0.130896 | 900 | 0.0044064 | 1897646 | Model Group:BU-07 b900 (members excluded):1818605
1898041 | 01 eerste verdieping | 01 eerste verdieping | 0.190676 | 1327 | 0.00649699 | 1898039 | Model Group:31_1A DKD R:1898045
1898049 | 01 eerste verdieping | 01 eerste verdieping | 0.067056 | 444 | 0.00217382 | 1898039 | Model Group:31_1A DKD R:1898045
1932981 | 00 begane grond | 00 begane grond | 0.283916 | 1993 | 0.00975773 | 1932979 | Model Group:BU-17 b3000:1900158
1932987 | 00 begane grond | 00 begane grond | 0.145876 | 1007 | 0.00493027 | 1932979 | Model Group:BU-17 b3000:1900158
2012527 | 01 eerste verdieping | 01 eerste verdieping | 0.067056 | 444 | 0.00217382 | 2012525 | Model Group:31_1A DKD L:2012531
2012535 | 01 eerste verdieping | 01 eerste verdieping | 0.190676 | 1327 | 0.00649699 | 2012525 | Model Group:31_1A DKD L:2012531
2012557 | 01 eerste verdieping | 01 eerste verdieping | 0.067056 | 444 | 0.00217382 | 2012555 | Model Group:31_1A DKD L:2012561
2012565 | 01 eerste verdieping | 01 eerste verdieping | 0.190676 | 1327 | 0.00649699 | 2012555 | Model Group:31_1A DKD L:2012561
2012572 | 01 eerste verdieping | 01 eerste verdieping | 0.190676 | 1327 | 0.00649699 | 2012570 | Model Group:BU-38:2702101
2012580 | 01 eerste verdieping | 01 eerste verdieping | 0.067056 | 444 | 0.00217382 | 2012570 | Model Group:BU-38:2702101
2172432 | 01 eerste verdieping | 01 eerste verdieping | 0.195506 | 1361.5 | 0.0066659 | 2172430 | Model Group:31_1A SVGD R:2172436
2172440 | 01 eerste verdieping | 01 eerste verdieping | 0.052006 | 336.5 | 0.0016475 | 2172430 | Model Group:31_1A SVGD R:2172436
3023665 | 01 eerste verdieping | 01 eerste verdieping | 0.015116 | 73 | 0.000357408 | 2172430 | Model Group:31_1A SVGD R:2172436
2182231 | 03 derde verdieping | 03 derde verdieping | 0.211606 | 1476.5 | 0.00722894 | 2182229 | Model Group:daklicht A1:2182252
2194544 | 03 derde verdieping | 03 derde verdieping | 0.211606 | 1476.5 | 0.00722894 | 2182229 | Model Group:daklicht A1:2182252
2194549 | 03 derde verdieping | 03 derde verdieping | 0.211606 | 1476.5 | 0.00722894 | 2182229 | Model Group:daklicht A1:2182252
2194556 | 03 derde verdieping | 03 derde verdieping | 0.211606 | 1476.5 | 0.00722894 | 2182229 | Model Group:daklicht A1:2182252
2182284 | 03 derde verdieping | 03 derde verdieping | 0.211606 | 1476.5 | 0.00722894 | 2182282 | Model Group:daklicht A1 (members excluded):2182288
2194587 | 03 derde verdieping | 03 derde verdieping | 0.211606 | 1476.5 | 0.00722894 | 2182282 | Model Group:daklicht A1 (members excluded):2182288
2194592 | 03 derde verdieping | 03 derde verdieping | 0.211606 | 1476.5 | 0.00722894 | 2182282 | Model Group:daklicht A1 (members excluded):2182288
2194597 | 03 derde verdieping | 03 derde verdieping | 0.211606 | 1476.5 | 0.00722894 | 2182282 | Model Group:daklicht A1 (members excluded):2182288
2182304 | 03 derde verdieping | 03 derde verdieping | 0.215771 | 1506.25 | 0.0073746 | 2182302 | Model Group:31_daklicht_B (members excluded):2194619
2194881 | 03 derde verdieping | 03 derde verdieping | 0.215771 | 1506.25 | 0.0073746 | 2182302 | Model Group:31_daklicht_B (members excluded):2194619
2194892 | 03 derde verdieping | 03 derde verdieping | 0.215771 | 1506.25 | 0.0073746 | 2182302 | Model Group:31_daklicht_B (members excluded):2194619
2194903 | 03 derde verdieping | 03 derde verdieping | 0.215771 | 1506.25 | 0.0073746 | 2182302 | Model Group:31_daklicht_B (members excluded):2194619
2194631 | 03 derde verdieping | 03 derde verdieping | 0.209383 | 1460.62 | 0.00715122 | 2194629 | Model Group:31_daklicht_C:2194635
2195050 | 03 derde verdieping | 03 derde verdieping | 0.209383 | 1460.62 | 0.00715122 | 2194629 | Model Group:31_daklicht_C:2194635
2195060 | 03 derde verdieping | 03 derde verdieping | 0.209383 | 1460.62 | 0.00715122 | 2194629 | Model Group:31_daklicht_C:2194635
2195071 | 03 derde verdieping | 03 derde verdieping | 0.209383 | 1460.62 | 0.00715122 | 2194629 | Model Group:31_daklicht_C:2194635
2194778 | 03 derde verdieping | 03 derde verdieping | 0.215771 | 1506.25 | 0.0073746 | 2194776 | Model Group:31_daklicht_B:2194786
2194972 | 03 derde verdieping | 03 derde verdieping | 0.215771 | 1506.25 | 0.0073746 | 2194776 | Model Group:31_daklicht_B:2194786
2194977 | 03 derde verdieping | 03 derde verdieping | 0.215771 | 1506.25 | 0.0073746 | 2194776 | Model Group:31_daklicht_B:2194786
2194982 | 03 derde verdieping | 03 derde verdieping | 0.215771 | 1506.25 | 0.0073746 | 2194776 | Model Group:31_daklicht_B:2194786
2194789 | 03 derde verdieping | 03 derde verdieping | 0.209383 | 1460.62 | 0.00715122 | 2194787 | Model Group:31_daklicht_C:2194793
2195094 | 03 derde verdieping | 03 derde verdieping | 0.209383 | 1460.62 | 0.00715122 | 2194787 | Model Group:31_daklicht_C:2194793
2195099 | 03 derde verdieping | 03 derde verdieping | 0.209383 | 1460.62 | 0.00715122 | 2194787 | Model Group:31_daklicht_C:2194793
2195104 | 03 derde verdieping | 03 derde verdieping | 0.209383 | 1460.62 | 0.00715122 | 2194787 | Model Group:31_daklicht_C:2194793
2245640 | 01 eerste verdieping | 01 eerste verdieping | 0.173806 | 1206.5 | 0.00590702 | 2245638 | Model Group:BU-33:2700705
2245688 | 01 eerste verdieping | 01 eerste verdieping | 0.117806 | 806.5 | 0.00394862 | 2245686 | Model Group:BU-34:2700766
2266687 | 01 eerste verdieping | 01 eerste verdieping | 0.067056 | 444 | 0.00217382 | 2266685 | Model Group:31_1A DK L:2266691
2266695 | 01 eerste verdieping | 01 eerste verdieping | 0.190676 | 1327 | 0.00649699 | 2266685 | Model Group:31_1A DK L:2266691
2266704 | 02 tweede verdieping | 02 tweede verdieping | 0.123896 | 850 | 0.0041616 | 2266702 | Model Group:31_2A DK L:2266708
2266713 | 02 tweede verdieping | 02 tweede verdieping | 0.104856 | 714 | 0.00349574 | 2266702 | Model Group:31_2A DK L:2266708
2266719 | 02 tweede verdieping | 02 tweede verdieping | 0.123896 | 850 | 0.0041616 | 2266717 | Model Group:31_2A DK R:2266723
2266728 | 02 tweede verdieping | 02 tweede verdieping | 0.104856 | 714 | 0.00349574 | 2266717 | Model Group:31_2A DK R:2266723
2649836 | 00 begane grond | 00 begane grond | 0.145876 | 1007 | 0.00493027 | 2649834 | Model Group:BU-47 b4200:1822720
2649847 | 00 begane grond | 00 begane grond | 0.307436 | 2161 | 0.0105803 | 2649834 | Model Group:BU-47 b4200:1822720
2649856 | 00 begane grond | 00 begane grond | 0.145876 | 1007 | 0.00493027 | 2649834 | Model Group:BU-47 b4200:1822720
2652546 | 00 begane grond | 00 begane grond | 0.283916 | 1993 | 0.00975773 | 2652544 | Model Group:BU-11 b3000:1502212
2652552 | 00 begane grond | 00 begane grond | 0.145876 | 1007 | 0.00493027 | 2652544 | Model Group:BU-11 b3000:1502212
2652632 | 00 begane grond | 00 begane grond | 0.283916 | 1993 | 0.00975773 | 2652630 | Model Group:BU-11 b3000:1502763
2652638 | 00 begane grond | 00 begane grond | 0.145876 | 1007 | 0.00493027 | 2652630 | Model Group:BU-11 b3000:1502763
2712308 | 01 eerste verdieping | 01 eerste verdieping | 0.173806 | 1206.5 | 0.00590702 | 2712306 | Model Group:BU-36:2701416
2712497 | 01 eerste verdieping | 01 eerste verdieping | 0.047806 | 306.5 | 0.00150062 | 2712495 | Model Group:BU-37:2712501
2760157 | 01 eerste verdieping | 01 eerste verdieping | 0.173806 | 1206.5 | 0.00590702 | 2760155 | Model Group:BU-33:2712443
2776732 | 01 eerste verdieping | 01 eerste verdieping | 0.067056 | 444 | 0.00217382 | 2776730 | Model Group:31_1A SVGD L:2776736
2776740 | 01 eerste verdieping | 01 eerste verdieping | 0.190676 | 1327 | 0.00649699 | 2776730 | Model Group:31_1A SVGD L:2776736
3003070 | 00 begane grond | 00 begane grond | 0.140416 | 968 | 0.00473933 | 3003068 | Model Group:BU-01 b1500:3003067
3003081 | 00 begane grond | 00 begane grond | 0.099116 | 673 | 0.00329501 | 3003068 | Model Group:BU-01 b1500:3003067
3003089 | 00 begane grond | 00 begane grond | 0.016516 | 83 | 0.000406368 | 3003068 | Model Group:BU-01 b1500:3003067
3003096 | 00 begane grond | 00 begane grond | 0.078396 | 525 | 0.0025704 | 3003068 | Model Group:BU-01 b1500:3003067
3016885 | 00 begane grond | 00 begane grond | 0.041996 | 265 | 0.00129744 | 3016883
3016897 | 00 begane grond | 00 begane grond | 0.094496 | 640 | 0.00313344 | 3016883
3058232 | 01 eerste verdieping | 01 eerste verdieping | 0.190676 | 1327 | 0.00649699 | 3058230 | Model Group:31_1A DKD R:3058236
3058240 | 01 eerste verdieping | 01 eerste verdieping | 0.067056 | 444 | 0.00217382 | 3058230 | Model Group:31_1A DKD R:3058236
3451932 | 00 begane grond | 00 begane grond | 0.130896 | 900 | 0.0044064 | 3451930 | Model Group:BU-45 b900:2546304
3702022 | 00 begane grond | 00 begane grond | 0.271876 | 1907 | 0.00933667 | 3702020 | Model Group:BU-04 b2500:1820005
3702031 | 00 begane grond | 00 begane grond | 0.081756 | 549 | 0.0026879 | 3702020 | Model Group:BU-04 b2500:1820005
3836659 | 00 begane grond | 00 begane grond | 0.144896 | 1000 | 0.004896 | 3836657 | Model Group:BU-16:3836676
3836671 | 00 begane grond | 00 begane grond | 0.140917 | 971.577 | 0.00475684 | 3836657 | Model Group:BU-16:3836676
4196775 | 00 begane grond | 00 begane grond | 0.177936 | 1236 | 0.00605146 | 4196773 | Model Group:BU-46:4200502

# IfcMember: Rectangular Mullion:RT72_Vm_raam (42)
Type - PredefinedType: MULLION; Material: <Unnamed>, a_kozijn
Type - Constraints - Angle: 0 deg; Offset: 0 mm
Type - Construction - Corner Mullion: no; Position: Perpendicular to Face; Profile: BDG_RT72_Vm_raam : Vm_raam; Thickness: 72 mm
Type - Dimensions - Width on side 1: 39 mm; Width on side 2: 39 mm
Type - Identity Data - Workset: Family : Curtain Wall Mullions : Rectangular Mullion; Type Name: RT72_Vm_raam
Type - Other - Category: Curtain Wall Mullions; Family Name: Rectangular Mullion
Material: a_kozijn
Phasing - Phase Created: 2. nieuwbouw
Identity Data - Workset: Workset1
Other - Family: Rectangular Mullion; Family and Type: Rectangular Mullion: RT72_Vm_raam; Type: RT72_Vm_raam; Type Id: 835094
Name (Rectangular Mullion:RT72_Vm_raam:...) | In | Level | Area (m2) | Length (mm) | Volume (m3) | Host Id | Group
877741 | 02 tweede verdieping | 02 tweede verdieping | 0.081066 | 503 | 0.00282485 | 877517 | Model Group:BU-40:2712884
877803 | 02 tweede verdieping | 02 tweede verdieping | 0.287316 | 1878 | 0.0105468 | 877517 | Model Group:BU-40:2712884
1848735 | 02 tweede verdieping | 02 tweede verdieping | 0.081141 | 503.5 | 0.00282766 | 877517 | Model Group:BU-40:2712884
1826977 | 00 begane grond | 00 begane grond | 0.120216 | 764 | 0.00429062 | 892038 | Model Group:BU-07 b900:894363
1861259 | 00 begane grond | 00 begane grond | 0.140616 | 900 | 0.0050544 | 1220070 | Model Group:BU-08 b2100:1220076
1859848 | 00 begane grond | 00 begane grond | 0.140616 | 900 | 0.0050544 | 1220169 | Model Group:BU-09 b1500:1220175
1492359 | 00 begane grond | 00 begane grond | 0.140616 | 900 | 0.0050544 | 1220847 | Model Group:BU-11 b3000:1220846
1827111 | 00 begane grond | 00 begane grond | 0.120216 | 764 | 0.00429062 | 1300401 | Model Group:BU-07 b900 (members excluded):1300407
1490589 | 00 begane grond | 00 begane grond | 0.140616 | 900 | 0.0050544 | 1300453 | Model Group:BU-22 b2700:1300414
1491549 | 00 begane grond | 00 begane grond | 0.140616 | 900 | 0.0050544 | 1300742 | Model Group:BU-21 b2966:1300741
1492203 | 00 begane grond | 00 begane grond | 0.140616 | 900 | 0.0050544 | 1300954 | Model Group:BU-20 b3300:1300930
1899465 | 00 begane grond | 00 begane grond | 0.140616 | 900 | 0.0050544 | 1300992 | Model Group:BU-23 b1353:2651710
1493952 | 00 begane grond | 00 begane grond | 0.140616 | 900 | 0.0050544 | 1493475 | Model Group:BU-25 b3000:1493474
1494121 | 00 begane grond | 00 begane grond | 0.140616 | 900 | 0.0050544 | 1494105 | Model Group:BU-02 b4200:1494104
2012622 | 00 begane grond | 00 begane grond | 0.140616 | 900 | 0.0050544 | 1494105 | Model Group:BU-02 b4200:1494104
1494539 | 00 begane grond | 00 begane grond | 0.287316 | 1878 | 0.0105468 | 1494514 | Model Group:BU-14 b3000:1494513
1827117 | 00 begane grond | 00 begane grond | 0.120216 | 764 | 0.00429062 | 1502981 | Model Group:BU-07 b900:1502980
1826558 | 00 begane grond | 00 begane grond | 0.140616 | 900 | 0.0050544 | 1817349 | Model Group:BU-12 b4200:1817348
1899584 | 00 begane grond | 00 begane grond | 0.140616 | 900 | 0.0050544 | 1817349 | Model Group:BU-12 b4200:1817348
1818894 | 00 begane grond | 00 begane grond | 0.140616 | 900 | 0.0050544 | 1818869 | Model Group:BU-03 b5800:1818868
1826855 | 00 begane grond | 00 begane grond | 0.140616 | 900 | 0.0050544 | 1818869 | Model Group:BU-03 b5800:1818868
1822169 | 00 begane grond | 00 begane grond | 0.140616 | 900 | 0.0050544 | 1822151 | Model Group:BU-10 b1800:1822150
1823323 | 00 begane grond | 00 begane grond | 0.146466 | 939 | 0.00527342 | 1823298 | Model Group:BU-15 b4200:1823297
1828107 | 00 begane grond | 00 begane grond | 0.146466 | 939 | 0.00527342 | 1823298 | Model Group:BU-15 b4200:1823297
1854008 | 00 begane grond | 00 begane grond | 0.287841 | 1881.5 | 0.0105665 | 1853992 | Model Group:BU-18 b3017:2651211
1934441 | 00 begane grond | 00 begane grond | 0.127716 | 814 | 0.00457142 | 1853992 | Model Group:BU-18 b3017:2651211
1863143 | 00 begane grond | 00 begane grond | 0.140616 | 900 | 0.0050544 | 1862275 | Model Group:BU-13 b3300:1862274
1897642 | 00 begane grond | 00 begane grond | 0.120216 | 764 | 0.00429062 | 1897632 | Model Group:BU-07 b900 (members excluded):1300686
1897656 | 00 begane grond | 00 begane grond | 0.120216 | 764 | 0.00429062 | 1897646 | Model Group:BU-07 b900 (members excluded):1818605
1932995 | 00 begane grond | 00 begane grond | 0.140616 | 900 | 0.0050544 | 1932979 | Model Group:BU-17 b3000:1900158
2649860 | 00 begane grond | 00 begane grond | 0.140616 | 900 | 0.0050544 | 2649834 | Model Group:BU-47 b4200:1822720
2649861 | 00 begane grond | 00 begane grond | 0.140616 | 900 | 0.0050544 | 2649834 | Model Group:BU-47 b4200:1822720
2652560 | 00 begane grond | 00 begane grond | 0.140616 | 900 | 0.0050544 | 2652544 | Model Group:BU-11 b3000:1502212
2652646 | 00 begane grond | 00 begane grond | 0.140616 | 900 | 0.0050544 | 2652630 | Model Group:BU-11 b3000:1502763
3003085 | 00 begane grond | 00 begane grond | 0.140616 | 900 | 0.0050544 | 3003068 | Model Group:BU-01 b1500:3003067
3003102 | 00 begane grond | 00 begane grond | 0.100716 | 634 | 0.00356054 | 3003068 | Model Group:BU-01 b1500:3003067
3016891 | 00 begane grond | 00 begane grond | 0.085566 | 533 | 0.00299333 | 3016883
3451940 | 00 begane grond | 00 begane grond | 0.120216 | 764 | 0.00429062 | 3451930 | Model Group:BU-45 b900:2546304
3702033 | 00 begane grond | 00 begane grond | 0.275616 | 1800 | 0.0101088 | 3702020 | Model Group:BU-04 b2500:1820005
3836667 | 00 begane grond | 00 begane grond | 0.141153 | 903.577 | 0.00507449 | 3836657 | Model Group:BU-16:3836676
3836673 | 00 begane grond | 00 begane grond | 0.145416 | 932 | 0.00523411 | 3836657 | Model Group:BU-16:3836676
4196783 | 00 begane grond | 00 begane grond | 0.170616 | 1100 | 0.0061776 | 4196773 | Model Group:BU-46:4200502

# IfcMember: Rectangular Mullion:RT72_Vo_raam (223)
Type - PredefinedType: MULLION; Material: <Unnamed>, a_kozijn
Type - Constraints - Angle: 0 deg; Offset: 0 mm
Type - Construction - Corner Mullion: no; Position: Perpendicular to Face; Profile: BDG_RT72_Vm_raam : Vo_raam; Thickness: 72 mm
Type - Dimensions - Width on side 1: 34 mm; Width on side 2: 34 mm
Type - Identity Data - Workset: Family : Curtain Wall Mullions : Rectangular Mullion; Type Name: RT72_Vo_raam
Type - Other - Category: Curtain Wall Mullions; Family Name: Rectangular Mullion
Material: a_kozijn
Phasing - Phase Created: 2. nieuwbouw
Identity Data - Workset: Workset1
Other - Family: Rectangular Mullion; Family and Type: Rectangular Mullion: RT72_Vo_raam; Type: RT72_Vo_raam; Type Id: 835102
Name (Rectangular Mullion:RT72_Vo_raam:...) | In | Level | Area (m2) | Length (mm) | Volume (m3) | Host Id | Group
870544 | 02 tweede verdieping | 02 tweede verdieping | 0.123896 | 850 | 0.0041616 | 870541 | Model Group:31_2A:870547
870750 | 02 tweede verdieping | 02 tweede verdieping | 0.123896 | 850 | 0.0041616 | 870747 | Model Group:31_2A:870753
870863 | 02 tweede verdieping | 02 tweede verdieping | 0.123896 | 850 | 0.0041616 | 870860 | Model Group:31_2A:870866
871638 | 02 tweede verdieping | 02 tweede verdieping | 0.123896 | 850 | 0.0041616 | 871635 | Model Group:31_2A:871641
871671 | 02 tweede verdieping | 02 tweede verdieping | 0.123896 | 850 | 0.0041616 | 871668 | Model Group:31_2A:871674
871922 | 02 tweede verdieping | 02 tweede verdieping | 0.123896 | 850 | 0.0041616 | 871919 | Model Group:31_2A:871925
871954 | 02 tweede verdieping | 02 tweede verdieping | 0.123896 | 850 | 0.0041616 | 871951 | Model Group:31_2A:871957
872816 | 02 tweede verdieping | 02 tweede verdieping | 0.123896 | 850 | 0.0041616 | 872813 | Model Group:31_2A:872819
872882 | 02 tweede verdieping | 02 tweede verdieping | 0.123896 | 850 | 0.0041616 | 872879 | Model Group:31_2A:872885
872915 | 02 tweede verdieping | 02 tweede verdieping | 0.123896 | 850 | 0.0041616 | 872912 | Model Group:31_2A:872918
872948 | 02 tweede verdieping | 02 tweede verdieping | 0.123896 | 850 | 0.0041616 | 872945 | Model Group:31_2A:872951
872981 | 02 tweede verdieping | 02 tweede verdieping | 0.123896 | 850 | 0.0041616 | 872978 | Model Group:31_2A:872984
873014 | 02 tweede verdieping | 02 tweede verdieping | 0.123896 | 850 | 0.0041616 | 873011 | Model Group:31_2A:873017
873080 | 02 tweede verdieping | 02 tweede verdieping | 0.123896 | 850 | 0.0041616 | 873077 | Model Group:31_2A:873083
873511 | 02 tweede verdieping | 02 tweede verdieping | 0.123896 | 850 | 0.0041616 | 873508 | Model Group:31_2A:873514
873604 | 02 tweede verdieping | 02 tweede verdieping | 0.123896 | 850 | 0.0041616 | 873601 | Model Group:31_2A:873607
873697 | 02 tweede verdieping | 02 tweede verdieping | 0.123896 | 850 | 0.0041616 | 873694 | Model Group:31_2A:873700
874669 | 01 eerste verdieping | 01 eerste verdieping | 0.252836 | 1771 | 0.00867082 | 874666 | Model Group:31_1A:874672
874953 | 01 eerste verdieping | 01 eerste verdieping | 0.252836 | 1771 | 0.00867082 | 874950 | Model Group:31_1A:874956
875028 | 01 eerste verdieping | 01 eerste verdieping | 0.190676 | 1327 | 0.00649699 | 875025 | Model Group:31_1A DKD L:875031
1864425 | 01 eerste verdieping | 01 eerste verdieping | 0.067056 | 444 | 0.00217382 | 875025 | Model Group:31_1A DKD L:875031
875043 | 01 eerste verdieping | 01 eerste verdieping | 0.252836 | 1771 | 0.00867082 | 875040 | Model Group:31_1A:875046
875052 | 01 eerste verdieping | 01 eerste verdieping | 0.067056 | 444 | 0.00217382 | 875049 | Model Group:31_1A DK R:875055
1864688 | 01 eerste verdieping | 01 eerste verdieping | 0.190676 | 1327 | 0.00649699 | 875049 | Model Group:31_1A DK R:875055
875271 | 01 eerste verdieping | 01 eerste verdieping | 0.252836 | 1771 | 0.00867082 | 875268 | Model Group:31_1A:875274
875307 | 01 eerste verdieping | 01 eerste verdieping | 0.067056 | 444 | 0.00217382 | 875304 | Model Group:31_1A DKD R:875310
1865121 | 01 eerste verdieping | 01 eerste verdieping | 0.190676 | 1327 | 0.00649699 | 875304 | Model Group:31_1A DKD R:875310
875379 | 01 eerste verdieping | 01 eerste verdieping | 0.252836 | 1771 | 0.00867082 | 875376 | Model Group:31_1A:875382
876490 | 01 eerste verdieping | 01 eerste verdieping | 0.252836 | 1771 | 0.00867082 | 876487 | Model Group:31_1A:876493
876908 | 01 eerste verdieping | 01 eerste verdieping | 0.252836 | 1771 | 0.00867082 | 876905 | Model Group:31_1A:876911
877025 | 01 eerste verdieping | 01 eerste verdieping | 0.252836 | 1771 | 0.00867082 | 877022 | Model Group:31_1A:877028
877115 | 01 eerste verdieping | 01 eerste verdieping | 0.252836 | 1771 | 0.00867082 | 877112 | Model Group:31_1A:877118
877205 | 01 eerste verdieping | 01 eerste verdieping | 0.252836 | 1771 | 0.00867082 | 877202 | Model Group:31_1A:877208
877520 | 02 tweede verdieping | 02 tweede verdieping | 0.127466 | 875.5 | 0.00428645 | 877517 | Model Group:BU-40:2712884
877740 | 02 tweede verdieping | 02 tweede verdieping | 0.080076 | 537 | 0.00262915 | 877517 | Model Group:BU-40:2712884
877802 | 02 tweede verdieping | 02 tweede verdieping | 0.267816 | 1878 | 0.00919469 | 877517 | Model Group:BU-40:2712884
1483765 | 02 tweede verdieping | 02 tweede verdieping | 0.127536 | 876 | 0.0042889 | 877517 | Model Group:BU-40:2712884
1483872 | 02 tweede verdieping | 02 tweede verdieping | 0.015116 | 73 | 0.000357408 | 877517 | Model Group:BU-40:2712884
1848501 | 02 tweede verdieping | 02 tweede verdieping | 0.015116 | 73 | 0.000357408 | 877517 | Model Group:BU-40:2712884
1848734 | 02 tweede verdieping | 02 tweede verdieping | 0.080146 | 537.5 | 0.0026316 | 877517 | Model Group:BU-40:2712884
880924 | 01 eerste verdieping | 01 eerste verdieping | 0.252836 | 1771 | 0.00867082 | 880921 | Model Group:31_1A:880927
881685 | 01 eerste verdieping | 01 eerste verdieping | 0.252836 | 1771 | 0.00867082 | 881682 | Model Group:31_1A:881688
881849 | 01 eerste verdieping | 01 eerste verdieping | 0.047806 | 306.5 | 0.00150062 | 881846 | Model Group:BU-35:2701985
891677 | 01 eerste verdieping | 01 eerste verdieping | 0.252836 | 1771 | 0.00867082 | 891674 | Model Group:31_1A:891680
891760 | 01 eerste verdieping | 01 eerste verdieping | 0.085536 | 576 | 0.0028201 | 891757 | Model Group:BU-30:2700215
891789 | 01 eerste verdieping | 01 eerste verdieping | 0.252836 | 1771 | 0.00867082 | 891786 | Model Group:31_1A:891792
891906 | 01 eerste verdieping | 01 eerste verdieping | 0.252836 | 1771 | 0.00867082 | 891903 | Model Group:31_1A:891909
891928 | 01 eerste verdieping | 01 eerste verdieping | 0.252836 | 1771 | 0.00867082 | 891925 | Model Group:31_1A:891931
891978 | 01 eerste verdieping | 01 eerste verdieping | 0.252836 | 1771 | 0.00867082 | 891975 | Model Group:31_1A:891981
892000 | 01 eerste verdieping | 01 eerste verdieping | 0.111856 | 764 | 0.00374054 | 891997 | Model Group:BU-32:892003
1837446 | 01 eerste verdieping | 01 eerste verdieping | 0.145876 | 1007 | 0.00493027 | 891997 | Model Group:BU-32:892003
892041 | 00 begane grond | 00 begane grond | 0.130896 | 900 | 0.0044064 | 892038 | Model Group:BU-07 b900:894363
894431 | 00 begane grond | 00 begane grond | 0.256896 | 1800 | 0.0088128 | 894428 | Model Group:BU-06 b1800:894434
1220073 | 00 begane grond | 00 begane grond | 0.157916 | 1093 | 0.00535133 | 1220070 | Model Group:BU-08 b2100:1220076
1861211 | 00 begane grond | 00 begane grond | 0.145876 | 1007 | 0.00493027 | 1220070 | Model Group:BU-08 b2100:1220076
1220172 | 00 begane grond | 00 begane grond | 0.145876 | 1007 | 0.00493027 | 1220169 | Model Group:BU-09 b1500:1220175
1859715 | 00 begane grond | 00 begane grond | 0.073916 | 493 | 0.00241373 | 1220169 | Model Group:BU-09 b1500:1220175
1220850 | 00 begane grond | 00 begane grond | 0.145876 | 1007 | 0.00493027 | 1220847 | Model Group:BU-11 b3000:1220846
1492352 | 00 begane grond | 00 begane grond | 0.283916 | 1993 | 0.00975773 | 1220847 | Model Group:BU-11 b3000:1220846
1300404 | 00 begane grond | 00 begane grond | 0.130896 | 900 | 0.0044064 | 1300401 | Model Group:BU-07 b900 (members excluded):1300407
1300456 | 00 begane grond | 00 begane grond | 0.145876 | 1007 | 0.00493027 | 1300453 | Model Group:BU-22 b2700:1300414
1489288 | 00 begane grond | 00 begane grond | 0.241916 | 1693 | 0.00828893 | 1300453 | Model Group:BU-22 b2700:1300414
1300745 | 00 begane grond | 00 begane grond | 0.145876 | 1007 | 0.00493027 | 1300742 | Model Group:BU-21 b2966:1300741
1491168 | 00 begane grond | 00 begane grond | 0.279156 | 1959 | 0.00959126 | 1300742 | Model Group:BU-21 b2966:1300741
1300957 | 00 begane grond | 00 begane grond | 0.145876 | 1007 | 0.00493027 | 1300954 | Model Group:BU-20 b3300:1300930
1491988 | 00 begane grond | 00 begane grond | 0.325916 | 2293 | 0.0112265 | 1300954 | Model Group:BU-20 b3300:1300930
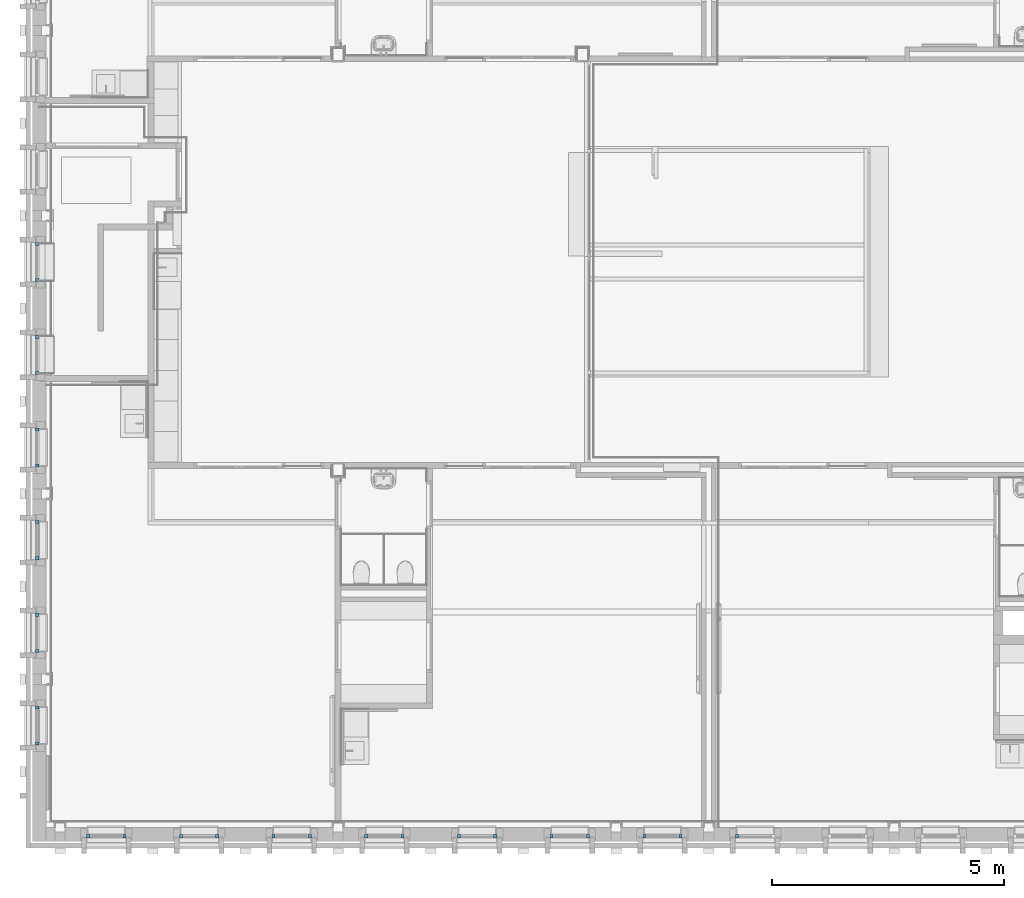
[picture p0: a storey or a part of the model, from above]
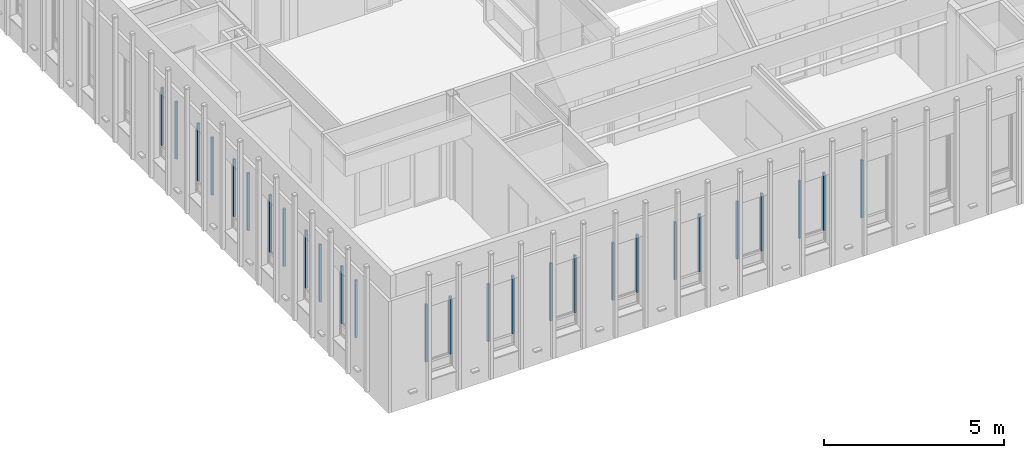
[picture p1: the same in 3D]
Properties of the parts of a building model (IFC2X3), part 15 of 94

# IfcMember: Rectangular Mullion:RT72_Vo_raam (223)
Name (Rectangular Mullion:RT72_Vo_raam:...) | In | Level | Area (m2) | Length (mm) | Volume (m3) | Host Id | Group
1300995 | 00 begane grond | 00 begane grond | 0.063416 | 418 | 0.00204653 | 1300992 | Model Group:BU-23 b1353:2651710
1899350 | 00 begane grond | 00 begane grond | 0.145876 | 1007 | 0.00493027 | 1300992 | Model Group:BU-23 b1353:2651710
1302057 | 01 eerste verdieping | 01 eerste verdieping | 0.252836 | 1771 | 0.00867082 | 1302054 | Model Group:BU-31:891953
1493478 | 00 begane grond | 00 begane grond | 0.277686 | 1948.5 | 0.00953986 | 1493475 | Model Group:BU-25 b3000:1493474
1493866 | 00 begane grond | 00 begane grond | 0.145876 | 1007 | 0.00493027 | 1493475 | Model Group:BU-25 b3000:1493474
1494108 | 00 begane grond | 00 begane grond | 0.145876 | 1007 | 0.00493027 | 1494105 | Model Group:BU-02 b4200:1494104
1494114 | 00 begane grond | 00 begane grond | 0.145876 | 1007 | 0.00493027 | 1494105 | Model Group:BU-02 b4200:1494104
2012619 | 00 begane grond | 00 begane grond | 0.307436 | 2161 | 0.0105803 | 1494105 | Model Group:BU-02 b4200:1494104
1494517 | 00 begane grond | 00 begane grond | 0.282796 | 1985 | 0.00971856 | 1494514 | Model Group:BU-14 b3000:1494513
1823028 | 00 begane grond | 00 begane grond | 0.146996 | 1015 | 0.00496944 | 1494514 | Model Group:BU-14 b3000:1494513
1502984 | 00 begane grond | 00 begane grond | 0.130896 | 900 | 0.0044064 | 1502981 | Model Group:BU-07 b900:1502980
1817352 | 00 begane grond | 00 begane grond | 0.145876 | 1007 | 0.00493027 | 1817349 | Model Group:BU-12 b4200:1817348
1817644 | 00 begane grond | 00 begane grond | 0.145876 | 1007 | 0.00493027 | 1817349 | Model Group:BU-12 b4200:1817348
1817864 | 00 begane grond | 00 begane grond | 0.307436 | 2161 | 0.0105803 | 1817349 | Model Group:BU-12 b4200:1817348
1818872 | 00 begane grond | 00 begane grond | 0.145876 | 1007 | 0.00493027 | 1818869 | Model Group:BU-03 b5800:1818868
1818878 | 00 begane grond | 00 begane grond | 0.161976 | 1122 | 0.00549331 | 1818869 | Model Group:BU-03 b5800:1818868
1818891 | 00 begane grond | 00 begane grond | 0.269916 | 1893 | 0.00926813 | 1818869 | Model Group:BU-03 b5800:1818868
1819725 | 00 begane grond | 00 begane grond | 0.141816 | 978 | 0.00478829 | 1818869 | Model Group:BU-03 b5800:1818868
1819905 | 00 begane grond | 00 begane grond | 0.286646 | 2012.5 | 0.0098532 | 1819902 | Model Group:BU-05 b1910:2648634
1822154 | 00 begane grond | 00 begane grond | 0.145876 | 1007 | 0.00493027 | 1822151 | Model Group:BU-10 b1800:1822150
1822160 | 00 begane grond | 00 begane grond | 0.115916 | 793 | 0.00388253 | 1822151 | Model Group:BU-10 b1800:1822150
1823301 | 00 begane grond | 00 begane grond | 0.145876 | 1007 | 0.00493027 | 1823298 | Model Group:BU-15 b4200:1823297
1823320 | 00 begane grond | 00 begane grond | 0.141816 | 978 | 0.00478829 | 1823298 | Model Group:BU-15 b4200:1823297
1823328 | 00 begane grond | 00 begane grond | 0.311496 | 2190 | 0.0107222 | 1823298 | Model Group:BU-15 b4200:1823297
1853995 | 00 begane grond | 00 begane grond | 0.284686 | 1998.5 | 0.00978466 | 1853992 | Model Group:BU-18 b3017:2651211
1854001 | 00 begane grond | 00 begane grond | 0.016516 | 83 | 0.000406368 | 1853992 | Model Group:BU-18 b3017:2651211
1856676 | 00 begane grond | 00 begane grond | 0.133836 | 921 | 0.00450922 | 1853992 | Model Group:BU-18 b3017:2651211
1854932 | 00 begane grond | 00 begane grond | 0.304356 | 2139 | 0.0104725 | 1854929 | Model Group:BU-19 b2067:2651286
1862278 | 00 begane grond | 00 begane grond | 0.325916 | 2293 | 0.0112265 | 1862275 | Model Group:BU-13 b3300:1862274
1862284 | 00 begane grond | 00 begane grond | 0.145876 | 1007 | 0.00493027 | 1862275 | Model Group:BU-13 b3300:1862274
1864617 | 01 eerste verdieping | 01 eerste verdieping | 0.190676 | 1327 | 0.00649699 | 1864614 | Model Group:31_1A SVGD L:1864620
1864625 | 01 eerste verdieping | 01 eerste verdieping | 0.067056 | 444 | 0.00217382 | 1864614 | Model Group:31_1A SVGD L:1864620
1864935 | 01 eerste verdieping | 01 eerste verdieping | 0.067056 | 444 | 0.00217382 | 1864932 | Model Group:31_1A DK R:1864938
1864943 | 01 eerste verdieping | 01 eerste verdieping | 0.190676 | 1327 | 0.00649699 | 1864932 | Model Group:31_1A DK R:1864938
1864979 | 01 eerste verdieping | 01 eerste verdieping | 0.190676 | 1327 | 0.00649699 | 1864976 | Model Group:31_1A DKD L:1864982
1864987 | 01 eerste verdieping | 01 eerste verdieping | 0.067056 | 444 | 0.00217382 | 1864976 | Model Group:31_1A DKD L:1864982
1865004 | 01 eerste verdieping | 01 eerste verdieping | 0.067056 | 444 | 0.00217382 | 1865001 | Model Group:31_1A DK R:1865007
1865012 | 01 eerste verdieping | 01 eerste verdieping | 0.190676 | 1327 | 0.00649699 | 1865001 | Model Group:31_1A DK R:1865007
1865027 | 01 eerste verdieping | 01 eerste verdieping | 0.190676 | 1327 | 0.00649699 | 1865024 | Model Group:31_1A DKD L:1865030
1865035 | 01 eerste verdieping | 01 eerste verdieping | 0.067056 | 444 | 0.00217382 | 1865024 | Model Group:31_1A DKD L:1865030
1865343 | 01 eerste verdieping | 01 eerste verdieping | 0.067056 | 444 | 0.00217382 | 1865340 | Model Group:31_1A DKD R:1865346
1865351 | 01 eerste verdieping | 01 eerste verdieping | 0.190676 | 1327 | 0.00649699 | 1865340 | Model Group:31_1A DKD R:1865346
1865364 | 01 eerste verdieping | 01 eerste verdieping | 0.190676 | 1327 | 0.00649699 | 1865361 | Model Group:31_1A DK L:1865367
1865372 | 01 eerste verdieping | 01 eerste verdieping | 0.067056 | 444 | 0.00217382 | 1865361 | Model Group:31_1A DK L:1865367
1865571 | 01 eerste verdieping | 01 eerste verdieping | 0.067056 | 444 | 0.00217382 | 1865568 | Model Group:31_1A DKD R:1865574
1865579 | 01 eerste verdieping | 01 eerste verdieping | 0.190676 | 1327 | 0.00649699 | 1865568 | Model Group:31_1A DKD R:1865574
1865605 | 01 eerste verdieping | 01 eerste verdieping | 0.067056 | 444 | 0.00217382 | 1865602 | Model Group:31_1A DKD R:1865608
1865613 | 01 eerste verdieping | 01 eerste verdieping | 0.190676 | 1327 | 0.00649699 | 1865602 | Model Group:31_1A DKD R:1865608
1865652 | 01 eerste verdieping | 01 eerste verdieping | 0.190676 | 1327 | 0.00649699 | 1865649 | Model Group:31_1A DK L:1865655
1865660 | 01 eerste verdieping | 01 eerste verdieping | 0.067056 | 444 | 0.00217382 | 1865649 | Model Group:31_1A DK L:1865655
1865671 | 01 eerste verdieping | 01 eerste verdieping | 0.190676 | 1327 | 0.00649699 | 1865668 | Model Group:31_1A DK L:1865674
1865679 | 01 eerste verdieping | 01 eerste verdieping | 0.067056 | 444 | 0.00217382 | 1865668 | Model Group:31_1A DK L:1865674
1865778 | 01 eerste verdieping | 01 eerste verdieping | 0.067056 | 444 | 0.00217382 | 1865775 | Model Group:31_1A DKD R:1865781
1865786 | 01 eerste verdieping | 01 eerste verdieping | 0.190676 | 1327 | 0.00649699 | 1865775 | Model Group:31_1A DKD R:1865781
1865799 | 01 eerste verdieping | 01 eerste verdieping | 0.190676 | 1327 | 0.00649699 | 1865796 | Model Group:31_1A DK L:1865802
1865807 | 01 eerste verdieping | 01 eerste verdieping | 0.067056 | 444 | 0.00217382 | 1865796 | Model Group:31_1A DK L:1865802
1865920 | 01 eerste verdieping | 01 eerste verdieping | 0.067056 | 444 | 0.00217382 | 1865917 | Model Group:31_1A DK R:1865923
1865928 | 01 eerste verdieping | 01 eerste verdieping | 0.190676 | 1327 | 0.00649699 | 1865917 | Model Group:31_1A DK R:1865923
1865943 | 01 eerste verdieping | 01 eerste verdieping | 0.190676 | 1327 | 0.00649699 | 1865940 | Model Group:31_1A DKD L:1865946
1865951 | 01 eerste verdieping | 01 eerste verdieping | 0.067056 | 444 | 0.00217382 | 1865940 | Model Group:31_1A DKD L:1865946
1866079 | 01 eerste verdieping | 01 eerste verdieping | 0.190676 | 1327 | 0.00649699 | 1866076 | Model Group:31_1A DKg R:1866082
1866087 | 01 eerste verdieping | 01 eerste verdieping | 0.067056 | 444 | 0.00217382 | 1866076 | Model Group:31_1A DKg R:1866082
1867674 | 02 tweede verdieping | 02 tweede verdieping | 0.123896 | 850 | 0.0041616 | 1867671 | Model Group:31_2A DK R:1867677
1869342 | 02 tweede verdieping | 02 tweede verdieping | 0.123896 | 850 | 0.0041616 | 1869339 | Model Group:31_2A DK R:1869345
1869359 | 02 tweede verdieping | 02 tweede verdieping | 0.123896 | 850 | 0.0041616 | 1869356 | Model Group:31_2A DK R:1869362
1869376 | 02 tweede verdieping | 02 tweede verdieping | 0.123896 | 850 | 0.0041616 | 1869373 | Model Group:31_2A DK R:1869379
1869393 | 02 tweede verdieping | 02 tweede verdieping | 0.123896 | 850 | 0.0041616 | 1869390 | Model Group:31_2A DK R:1869396
1869410 | 02 tweede verdieping | 02 tweede verdieping | 0.123896 | 850 | 0.0041616 | 1869407 | Model Group:31_2A DK R:1869413
1869427 | 02 tweede verdieping | 02 tweede verdieping | 0.123896 | 850 | 0.0041616 | 1869424 | Model Group:31_2A DK R:1869430
1869444 | 02 tweede verdieping | 02 tweede verdieping | 0.123896 | 850 | 0.0041616 | 1869441 | Model Group:31_2A DK R:1869447
1869464 | 02 tweede verdieping | 02 tweede verdieping | 0.123896 | 850 | 0.0041616 | 1869461 | Model Group:31_2A DK L:1869467
1869603 | 02 tweede verdieping | 02 tweede verdieping | 0.123896 | 850 | 0.0041616 | 1869600 | Model Group:31_2A DK L:1869606
1869620 | 02 tweede verdieping | 02 tweede verdieping | 0.123896 | 850 | 0.0041616 | 1869617 | Model Group:31_2A DK L:1869623
1869637 | 02 tweede verdieping | 02 tweede verdieping | 0.123896 | 850 | 0.0041616 | 1869634 | Model Group:31_2A DK L:1869640
1869654 | 02 tweede verdieping | 02 tweede verdieping | 0.123896 | 850 | 0.0041616 | 1869651 | Model Group:31_2A DK L:1869657
1869671 | 02 tweede verdieping | 02 tweede verdieping | 0.123896 | 850 | 0.0041616 | 1869668 | Model Group:31_2A DK L:1869674
1869688 | 02 tweede verdieping | 02 tweede verdieping | 0.123896 | 850 | 0.0041616 | 1869685 | Model Group:31_2A DK L:1869691
1869705 | 02 tweede verdieping | 02 tweede verdieping | 0.123896 | 850 | 0.0041616 | 1869702 | Model Group:31_2A DK L:1869708
1869724 | 02 tweede verdieping | 02 tweede verdieping | 0.123896 | 850 | 0.0041616 | 1869721 | Model Group:31_2A DK L:1869727
1869741 | 02 tweede verdieping | 02 tweede verdieping | 0.123896 | 850 | 0.0041616 | 1869738 | Model Group:31_2A DK L:1869744
1869758 | 02 tweede verdieping | 02 tweede verdieping | 0.123896 | 850 | 0.0041616 | 1869755 | Model Group:31_2A DK R:1869761
1869775 | 02 tweede verdieping | 02 tweede verdieping | 0.123896 | 850 | 0.0041616 | 1869772 | Model Group:31_2A DK R:1869778
1869794 | 02 tweede verdieping | 02 tweede verdieping | 0.123896 | 850 | 0.0041616 | 1869791 | Model Group:31_2A DK R:1869797
1869811 | 02 tweede verdieping | 02 tweede verdieping | 0.123896 | 850 | 0.0041616 | 1869808 | Model Group:31_2A DK R:1869814
1869828 | 02 tweede verdieping | 02 tweede verdieping | 0.123896 | 850 | 0.0041616 | 1869825 | Model Group:31_2A DK R:1869831
1869845 | 02 tweede verdieping | 02 tweede verdieping | 0.123896 | 850 | 0.0041616 | 1869842 | Model Group:31_2A DK R:1869848
1897635 | 00 begane grond | 00 begane grond | 0.130896 | 900 | 0.0044064 | 1897632 | Model Group:BU-07 b900 (members excluded):1300686
1897649 | 00 begane grond | 00 begane grond | 0.130896 | 900 | 0.0044064 | 1897646 | Model Group:BU-07 b900 (members excluded):1818605
1898042 | 01 eerste verdieping | 01 eerste verdieping | 0.067056 | 444 | 0.00217382 | 1898039 | Model Group:31_1A DKD R:1898045
1898050 | 01 eerste verdieping | 01 eerste verdieping | 0.190676 | 1327 | 0.00649699 | 1898039 | Model Group:31_1A DKD R:1898045
1932982 | 00 begane grond | 00 begane grond | 0.145876 | 1007 | 0.00493027 | 1932979 | Model Group:BU-17 b3000:1900158
1932988 | 00 begane grond | 00 begane grond | 0.283916 | 1993 | 0.00975773 | 1932979 | Model Group:BU-17 b3000:1900158
2012528 | 01 eerste verdieping | 01 eerste verdieping | 0.190676 | 1327 | 0.00649699 | 2012525 | Model Group:31_1A DKD L:2012531
2012536 | 01 eerste verdieping | 01 eerste verdieping | 0.067056 | 444 | 0.00217382 | 2012525 | Model Group:31_1A DKD L:2012531
2012558 | 01 eerste verdieping | 01 eerste verdieping | 0.190676 | 1327 | 0.00649699 | 2012555 | Model Group:31_1A DKD L:2012561
2012566 | 01 eerste verdieping | 01 eerste verdieping | 0.067056 | 444 | 0.00217382 | 2012555 | Model Group:31_1A DKD L:2012561
2012573 | 01 eerste verdieping | 01 eerste verdieping | 0.067056 | 444 | 0.00217382 | 2012570 | Model Group:BU-38:2702101
2012581 | 01 eerste verdieping | 01 eerste verdieping | 0.190676 | 1327 | 0.00649699 | 2012570 | Model Group:BU-38:2702101
2172433 | 01 eerste verdieping | 01 eerste verdieping | 0.052006 | 336.5 | 0.0016475 | 2172430 | Model Group:31_1A SVGD R:2172436
3023501 | 01 eerste verdieping | 01 eerste verdieping | 0.185986 | 1293.5 | 0.00633298 | 2172430 | Model Group:31_1A SVGD R:2172436
3023666 | 01 eerste verdieping | 01 eerste verdieping | 0.015116 | 73 | 0.000357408 | 2172430 | Model Group:31_1A SVGD R:2172436
2182232 | 03 derde verdieping | 03 derde verdieping | 0.211606 | 1476.5 | 0.00722894 | 2182229 | Model Group:daklicht A1:2182252
2194545 | 03 derde verdieping | 03 derde verdieping | 0.211606 | 1476.5 | 0.00722894 | 2182229 | Model Group:daklicht A1:2182252
2194550 | 03 derde verdieping | 03 derde verdieping | 0.211606 | 1476.5 | 0.00722894 | 2182229 | Model Group:daklicht A1:2182252
2194557 | 03 derde verdieping | 03 derde verdieping | 0.211606 | 1476.5 | 0.00722894 | 2182229 | Model Group:daklicht A1:2182252
2182285 | 03 derde verdieping | 03 derde verdieping | 0.211606 | 1476.5 | 0.00722894 | 2182282 | Model Group:daklicht A1 (members excluded):2182288
2194588 | 03 derde verdieping | 03 derde verdieping | 0.211606 | 1476.5 | 0.00722894 | 2182282 | Model Group:daklicht A1 (members excluded):2182288
2194593 | 03 derde verdieping | 03 derde verdieping | 0.211606 | 1476.5 | 0.00722894 | 2182282 | Model Group:daklicht A1 (members excluded):2182288
2194598 | 03 derde verdieping | 03 derde verdieping | 0.211606 | 1476.5 | 0.00722894 | 2182282 | Model Group:daklicht A1 (members excluded):2182288
2182305 | 03 derde verdieping | 03 derde verdieping | 0.215771 | 1506.25 | 0.0073746 | 2182302 | Model Group:31_daklicht_B (members excluded):2194619
2194882 | 03 derde verdieping | 03 derde verdieping | 0.215771 | 1506.25 | 0.0073746 | 2182302 | Model Group:31_daklicht_B (members excluded):2194619
2194893 | 03 derde verdieping | 03 derde verdieping | 0.215771 | 1506.25 | 0.0073746 | 2182302 | Model Group:31_daklicht_B (members excluded):2194619
2194904 | 03 derde verdieping | 03 derde verdieping | 0.215771 | 1506.25 | 0.0073746 | 2182302 | Model Group:31_daklicht_B (members excluded):2194619
2194632 | 03 derde verdieping | 03 derde verdieping | 0.209383 | 1460.62 | 0.00715122 | 2194629 | Model Group:31_daklicht_C:2194635
2195051 | 03 derde verdieping | 03 derde verdieping | 0.209383 | 1460.62 | 0.00715122 | 2194629 | Model Group:31_daklicht_C:2194635
2195061 | 03 derde verdieping | 03 derde verdieping | 0.209383 | 1460.62 | 0.00715122 | 2194629 | Model Group:31_daklicht_C:2194635
2195072 | 03 derde verdieping | 03 derde verdieping | 0.209383 | 1460.62 | 0.00715122 | 2194629 | Model Group:31_daklicht_C:2194635
2194779 | 03 derde verdieping | 03 derde verdieping | 0.215771 | 1506.25 | 0.0073746 | 2194776 | Model Group:31_daklicht_B:2194786
2194973 | 03 derde verdieping | 03 derde verdieping | 0.215771 | 1506.25 | 0.0073746 | 2194776 | Model Group:31_daklicht_B:2194786
2194978 | 03 derde verdieping | 03 derde verdieping | 0.215771 | 1506.25 | 0.0073746 | 2194776 | Model Group:31_daklicht_B:2194786
2194983 | 03 derde verdieping | 03 derde verdieping | 0.215771 | 1506.25 | 0.0073746 | 2194776 | Model Group:31_daklicht_B:2194786
2194790 | 03 derde verdieping | 03 derde verdieping | 0.209383 | 1460.62 | 0.00715122 | 2194787 | Model Group:31_daklicht_C:2194793
2195095 | 03 derde verdieping | 03 derde verdieping | 0.209383 | 1460.62 | 0.00715122 | 2194787 | Model Group:31_daklicht_C:2194793
2195100 | 03 derde verdieping | 03 derde verdieping | 0.209383 | 1460.62 | 0.00715122 | 2194787 | Model Group:31_daklicht_C:2194793
2195105 | 03 derde verdieping | 03 derde verdieping | 0.209383 | 1460.62 | 0.00715122 | 2194787 | Model Group:31_daklicht_C:2194793
2245641 | 01 eerste verdieping | 01 eerste verdieping | 0.173806 | 1206.5 | 0.00590702 | 2245638 | Model Group:BU-33:2700705
2245689 | 01 eerste verdieping | 01 eerste verdieping | 0.117806 | 806.5 | 0.00394862 | 2245686 | Model Group:BU-34:2700766
2266688 | 01 eerste verdieping | 01 eerste verdieping | 0.190676 | 1327 | 0.00649699 | 2266685 | Model Group:31_1A DK L:2266691
2266696 | 01 eerste verdieping | 01 eerste verdieping | 0.067056 | 444 | 0.00217382 | 2266685 | Model Group:31_1A DK L:2266691
2266705 | 02 tweede verdieping | 02 tweede verdieping | 0.123896 | 850 | 0.0041616 | 2266702 | Model Group:31_2A DK L:2266708
2266720 | 02 tweede verdieping | 02 tweede verdieping | 0.123896 | 850 | 0.0041616 | 2266717 | Model Group:31_2A DK R:2266723
2649837 | 00 begane grond | 00 begane grond | 0.145876 | 1007 | 0.00493027 | 2649834 | Model Group:BU-47 b4200:1822720
2649848 | 00 begane grond | 00 begane grond | 0.145876 | 1007 | 0.00493027 | 2649834 | Model Group:BU-47 b4200:1822720
2649857 | 00 begane grond | 00 begane grond | 0.307436 | 2161 | 0.0105803 | 2649834 | Model Group:BU-47 b4200:1822720
2652547 | 00 begane grond | 00 begane grond | 0.145876 | 1007 | 0.00493027 | 2652544 | Model Group:BU-11 b3000:1502212
2652553 | 00 begane grond | 00 begane grond | 0.283916 | 1993 | 0.00975773 | 2652544 | Model Group:BU-11 b3000:1502212
2652633 | 00 begane grond | 00 begane grond | 0.145876 | 1007 | 0.00493027 | 2652630 | Model Group:BU-11 b3000:1502763
2652639 | 00 begane grond | 00 begane grond | 0.283916 | 1993 | 0.00975773 | 2652630 | Model Group:BU-11 b3000:1502763
2712309 | 01 eerste verdieping | 01 eerste verdieping | 0.173806 | 1206.5 | 0.00590702 | 2712306 | Model Group:BU-36:2701416
2712498 | 01 eerste verdieping | 01 eerste verdieping | 0.047806 | 306.5 | 0.00150062 | 2712495 | Model Group:BU-37:2712501
2760158 | 01 eerste verdieping | 01 eerste verdieping | 0.173806 | 1206.5 | 0.00590702 | 2760155 | Model Group:BU-33:2712443
2776733 | 01 eerste verdieping | 01 eerste verdieping | 0.190676 | 1327 | 0.00649699 | 2776730 | Model Group:31_1A SVGD L:2776736
2776741 | 01 eerste verdieping | 01 eerste verdieping | 0.067056 | 444 | 0.00217382 | 2776730 | Model Group:31_1A SVGD L:2776736
3003071 | 00 begane grond | 00 begane grond | 0.078396 | 525 | 0.0025704 | 3003068 | Model Group:BU-01 b1500:3003067
3003082 | 00 begane grond | 00 begane grond | 0.140416 | 968 | 0.00473933 | 3003068 | Model Group:BU-01 b1500:3003067
3003090 | 00 begane grond | 00 begane grond | 0.099116 | 673 | 0.00329501 | 3003068 | Model Group:BU-01 b1500:3003067
3003097 | 00 begane grond | 00 begane grond | 0.016516 | 83 | 0.000406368 | 3003068 | Model Group:BU-01 b1500:3003067
3016886 | 00 begane grond | 00 begane grond | 0.089036 | 601 | 0.0029425 | 3016883
3016898 | 00 begane grond | 00 begane grond | 0.036536 | 226 | 0.0011065 | 3016883
3058233 | 01 eerste verdieping | 01 eerste verdieping | 0.067056 | 444 | 0.00217382 | 3058230 | Model Group:31_1A DKD R:3058236
3058241 | 01 eerste verdieping | 01 eerste verdieping | 0.190676 | 1327 | 0.00649699 | 3058230 | Model Group:31_1A DKD R:3058236
3451933 | 00 begane grond | 00 begane grond | 0.130896 | 900 | 0.0044064 | 3451930 | Model Group:BU-45 b900:2546304
3702023 | 00 begane grond | 00 begane grond | 0.081756 | 549 | 0.0026879 | 3702020 | Model Group:BU-04 b2500:1820005
3702032 | 00 begane grond | 00 begane grond | 0.271876 | 1907 | 0.00933667 | 3702020 | Model Group:BU-04 b2500:1820005
3836660 | 00 begane grond | 00 begane grond | 0.140917 | 971.577 | 0.00475684 | 3836657 | Model Group:BU-16:3836676
3836672 | 00 begane grond | 00 begane grond | 0.144896 | 1000 | 0.004896 | 3836657 | Model Group:BU-16:3836676
4196776 | 00 begane grond | 00 begane grond | 0.177936 | 1236 | 0.00605146 | 4196773 | Model Group:BU-46:4200502

# IfcOpeningElement: Opening (823)
Name | In | Classification | Level | Sill Height (mm) | Phase Created | Area (m2) | Height (mm) | Width (mm) | Identity Data, Workset | Mark | Other, Category | Family | Family and Type | Head Height (mm) | Host Id | Type | Type Id | Analytic Construction | Define Thermal Properties by | Assembly Code | Datum_Gewijzigd | Description | Type Mark | Type Name | Identity Data(Type), Workset | Other(Type), Category | Family Name
Basic Wall:NLRS_22_WA_HSB bispouw 30-245-12-13 glaswol_gen_ISR:772305 | 02 tweede verdieping | 21.10 Uniformat (Uniformat) | 02 tweede verdieping | 673 | 2. nieuwbouw | 3.88842 | 2390 | 850 | Workset1 | 86 | Windows | NLRS_31_WI_WB_sparingmaker_generiek_BDG | NLRS_31_WI_WB_sparingmaker_generiek_BDG: mw_hsb_raam negge 180_alu v2 | 3063 | 2338901 | mw_hsb_raam negge 180_alu v2 | 863574 | <None> | Schematic Type | 31 | 20160502 | buitenblad Detail | 57 | mw_hsb_raam negge 180_alu v2 | Family : Windows : NLRS_31_WI_WB_sparingmaker_generiek_BDG | Windows | NLRS_31_WI_WB_sparingmaker_generiek_BDG | General - samenstelling: NLRS_31_WI_UN_samenstelling_leeg_generiek_ISR : std; Dimensions - NLRS_C_breedte: 850 mm; NLRS_C_hoogte: 2390 mm; Layers(Type) - binnenblad_afwerking_boven: yes; binnenblad_afwerking_boven_hoek_links: 0 deg; binnenblad_afwerking_boven_hoek_rechts: 0 deg; binnenblad_afwerking_boven_plaatsing_y: 17 mm; binnenblad_afwerking_boven_type: NLRS_41_GM_WPB_multiplex-SH_generiek_ISR : 151x10 gipsvezel dagkant; binnenblad_afwerking_boven_verlenging_links: -148 mm; binnenblad_afwerking_boven_verlenging_rechts: -148 mm; binnenblad_afwerking_links: yes; binnenblad_afwerking_links_hoek_boven: 0 deg; binnenblad_afwerking_links_hoek_onder: 0 deg; binnenblad_afwerking_links_plaatsing_y: 148 mm; binnenblad_afwerking_links_type: NLRS_41_GM_WPB_multiplex-SH_generiek_ISR : 151x10 gipsvezel dagkant; binnenblad_afwerking_links_verlenging_boven: -27 mm; binnenblad_afwerking_links_verlenging_onder: -94 mm; binnenblad_afwerking_plaatsing_x: 149 mm; binnenblad_afwerking_rechts: yes; binnenblad_afwerking_rechts_hoek_boven: 0 deg; binnenblad_afwerking_rechts_hoek_onder: 0 deg; binnenblad_afwerking_rechts_plaatsing_y: 148 mm; binnenblad_afwerking_rechts_type: NLRS_41_GM_WPB_multiplex-SH_generiek_ISR : 151x10 gipsvezel dagkant; binnenblad_afwerking_rechts_verlenging_boven: -27 mm; binnenblad_afwerking_rechts_verlenging_onder: -94 mm; buitenblad_afwerking_boven: no; buitenblad_afwerking_boven_hoek_links: 0 deg; buitenblad_afwerking_boven_hoek_rechts: 0 deg; buitenblad_afwerking_boven_plaatsing_y: 0 mm; buitenblad_afwerking_boven_type: NLRS_41_GM_WPB_omgezet metselwerk-SH_generiek_ISR : std; buitenblad_afwerking_boven_verlenging_links: 0 mm; buitenblad_afwerking_boven_verlenging_rechts: 0 mm; buitenblad_afwerking_links: no; buitenblad_afwerking_links_hoek_boven: 0 deg; buitenblad_afwerking_links_hoek_onder: 0 deg; buitenblad_afwerking_links_plaatsing_y: 0 mm; buitenblad_afwerking_links_type: NLRS_41_GM_WPB_omgezet metselwerk-SH_generiek_ISR : std; buitenblad_afwerking_links_verlenging_boven: 0 mm; buitenblad_afwerking_links_verlenging_onder: 0 mm; buitenblad_afwerking_plaatsing_x: 0 mm; buitenblad_afwerking_rechts: no; buitenblad_afwerking_rechts_hoek_boven: 0 deg; buitenblad_afwerking_rechts_hoek_onder: 0 deg; buitenblad_afwerking_rechts_plaatsing_y: 0 mm; buitenblad_afwerking_rechts_type: NLRS_41_GM_WPB_omgezet metselwerk-SH_generiek_ISR : std; buitenblad_afwerking_rechts_verlenging_boven: 0 mm; buitenblad_afwerking_rechts_verlenging_onder: 0 mm; Constraints(Type) - lossing_binnenblad: 0 mm; offset_binnenblad_boven: 134 mm; offset_binnenblad_links: 131 mm; offset_binnenblad_onder: 59 mm; offset_binnenblad_rechts: 131 mm; offset_binnenbladbeplating_boven: 17 mm; offset_binnenbladbeplating_links: 148 mm; offset_binnenbladbeplating_onder: 17 mm; offset_binnenbladbeplating_rechts: 148 mm; offset_buitenblad_boven: 12 mm; offset_buitenblad_links: 107 mm; offset_buitenblad_onder: 70 mm; offset_buitenblad_rechts: 107 mm; offset_isolatie_boven: 48 mm; offset_isolatie_links: 28 mm; offset_isolatie_onder: 28 mm; offset_isolatie_rechts: 28 mm; Structural(Type) - rekje: no; rekje_plaatsing_x: 0 mm; rekje_plaatsing_y: 0 mm; rekje_type: NLRS_41_GM_WPB_rekje-SH_generiek_ISR : std; rekje_verlenging_links: 200 mm; rekje_verlenging_rechts: 200 mm; spouwlat_boven: yes; spouwlat_boven_plaatsing_y: -17 mm; spouwlat_boven_type: NLRS_41_GM_WPB_spouwlat_isolatie_gen_bdg : 187x38 + isolatie 113x200; spouwlat_boven_verlenging_links: 21 mm; spouwlat_boven_verlenging_rechts: 21 mm; spouwlat_links: yes; spouwlat_links_plaatsing_y: -17 mm; spouwlat_links_type: NLRS_41_GM_WPB_spouwlat_isolatie_gen_bdg : 187x38 + isolatie 110x180; spouwlat_links_verlenging_boven: -17 mm; spouwlat_links_verlenging_onder: -17 mm; spouwlat_onder: yes; spouwlat_onder_plaatsing_y: -17 mm; spouwlat_onder_type: NLRS_41_GM_WPB_spouwlat-SH_generiek_ISR : 185x76; spouwlat_onder_verlenging_links: 21 mm; spouwlat_onder_verlenging_rechts: 21 mm; spouwlat_plaatsing_x: -275 mm; spouwlat_rechts: yes; spouwlat_rechts_plaatsing_y: -17 mm; spouwlat_rechts_type: NLRS_41_GM_WPB_spouwlat_isolatie_gen_bdg : 187x38 + isolatie 110x180; spouwlat_rechts_verlenging_boven: -17 mm; spouwlat_rechts_verlenging_onder: -17 mm; Materials and Finishes(Type) - geveldrager: yes; geveldrager_hoek_a: 0 deg; geveldrager_hoek_b: 0 deg; geveldrager_plaatsing_x: -10 mm; geveldrager_plaatsing_y: 8 mm; geveldrager_type: NLRS_41_SF_LIB_latei_staal_generiek_ISR : 90x150; geveldrager_verlenging_a: 0 mm; geveldrager_verlenging_b: 0 mm; latei: no; latei_hoek_a: 0 deg; latei_hoek_b: 0 deg; latei_plaatsing_x: 0 mm; latei_plaatsing_y: 0 mm; latei_type: NLRS_41_SF_LIB_latei_beton_generiek_ISR : 150x100; latei_verlenging_a: 100 mm; latei_verlenging_b: 100 mm; vensterbank: yes; vensterbank_hoek_a: 0 deg; vensterbank_hoek_b: 0 deg; vensterbank_plaatsing_x: 149 mm; vensterbank_plaatsing_y: 17 mm; vensterbank_type: NLRS_42_GM_WPB_vensterbank_natuursteen-SH_generiek_ISR : 180x18 vensterbank composiet; vensterbank_verlenging_a: -148 mm; vensterbank_verlenging_b: -148 mm; waterslag: yes; waterslag_hoek_a: 0 deg; waterslag_hoek_b: 0 deg; waterslag_plaatsing_x: -25 mm; waterslag_plaatsing_y: 90 mm; waterslag_type: NLRS_41_GM_WPB_waterslag barok-SH_roval_ISR : waterslag_roval_Types Barok_roval_b 270; waterslag_verlenging_a: -100 mm; waterslag_verlenging_b: -100 mm; Graphics(Type) - doorval_hoek_links: 0 deg; doorval_hoek_rechts: 0 deg; doorval_plaatsing_x: 30 mm; doorval_plaatsing_y: 300 mm; doorval_type: NLRS_41_GM_WPB_doorvalbeveiliging-SH_generiek_ISR : std; doorval_verlenging_links: 0 mm; doorval_verlenging_rechts: 0 mm; doorvalbeveiliging: no; ventilatie: no; ventilatie_plaatsing_x: 114 mm; ventilatie_plaatsing_y: 0 mm; ventilatie_type: NLRS_41_GM_WPB_ventilatie-SH_topstream_ISR : std; ventilatie_verlenging_links: 0 mm; ventilatie_verlenging_rechts: 0 mm; Construction(Type) - binnenblad_beplating: 200 mm; binnenblad_hout: 275 mm; buitenblad: 100 mm; isolatie: 10 mm; luchtspouw: 30 mm; negge: 215 mm; Dimensions(Type) - binnenbladhost: yes; buitenbladhost: no; clashobject: no; wrapping_exterior: 0 mm; wrapping_interior: 0 mm; Identity Data(Type) - Assembly Description: buitenwandopeningen; Other(Type) - a_binnen_boven_1: 134 mm; a_binnen_boven_2: 134 mm; a_binnen_links_1: 131 mm; a_binnen_links_2: 131 mm; a_binnen_onder_1: 59 mm; a_binnen_onder_2: 59 mm; a_binnen_rechts_1: 131 mm; a_binnen_rechts_2: 131 mm; a_binnenbepl_boven_1: 17 mm; a_binnenbepl_links_1: 148 mm; a_binnenbepl_onder_1: 17 mm; a_binnenbepl_rechts_1: 148 mm; a_binnenwand_afwerking_boven_y: 17 mm; a_binnenwand_afwerking_links_y: 148 mm; a_binnenwand_afwerking_rechts_y: 148 mm; a_binnenwand_afwerking_x: 149 mm; a_buitenblad_boven: 12 mm; a_buitenblad_boven_y: 0 mm; a_buitenblad_links: 107 mm; a_buitenblad_links_y: 0 mm; a_buitenblad_onder: 70 mm; a_buitenblad_rechts: 107 mm; a_buitenblad_rechts_y: 0 mm; a_buitenblad_x: 0 mm; a_doorval_x: 30 mm; a_doorval_y: 300 mm; a_geveldrager_x: 10 mm; a_geveldrager_y: 8 mm; a_isolatie_boven: 48 mm; a_isolatie_links: 28 mm; a_isolatie_onder: 28 mm; a_isolatie_rechts: 28 mm; a_latei_x: 0 mm; a_latei_y: 0 mm; a_rekje_x: 0 mm; a_rekje_y: 0 mm; a_spouwlat_boven_y: 17 mm; a_spouwlat_links_y: 17 mm; a_spouwlat_onder_y: 17 mm; a_spouwlat_rechts_y: 17 mm; a_spouwlat_x: 275 mm; a_vensterbank_x: 149 mm; a_vensterbank_y: 17 mm; a_ventilatie_x: 114 mm; a_ventilatie_y: 0 mm; a_waterslag_x: 25 mm; a_waterslag_y: 90 mm; b_binnen_boven_1: 268 mm; b_binnen_boven_2: 268 mm; b_binnen_links_1: 262 mm; b_binnen_links_2: 262 mm; b_binnen_onder_1: 118 mm; b_binnen_onder_2: 118 mm; b_binnen_rechts_1: 262 mm; b_binnen_rechts_2: 262 mm; b_binnenwand_afwerking_boven_y: 34 mm; b_binnenwand_afwerking_links_y: 296 mm; b_binnenwand_afwerking_rechts_y: 296 mm; b_binnenwand_afwerking_x: 298 mm; b_buitenblad_boven: 24 mm; b_buitenblad_boven_y: 0 mm; b_buitenblad_links: 214 mm; b_buitenblad_links_y: 0 mm; b_buitenblad_onder: 140 mm; b_buitenblad_rechts: 214 mm; b_buitenblad_rechts_y: 0 mm; b_buitenblad_x: 0 mm; b_doorval_x: 60 mm; b_doorval_y: 600 mm; b_geveldrager_x: 0 mm; b_geveldrager_y: 16 mm; b_isolatie_boven: 96 mm; b_isolatie_links: 56 mm; b_isolatie_onder: 56 mm; b_isolatie_rechts: 56 mm; b_latei_x: 0 mm; b_latei_y: 0 mm; b_rekje_x: 0 mm; b_rekje_y: 0 mm; b_spouwlat_boven_y: 0 mm; b_spouwlat_links_y: 0 mm; b_spouwlat_onder_y: 0 mm; b_spouwlat_rechts_y: 0 mm; b_spouwlat_x: 0 mm; b_vensterbank_x: 298 mm; b_vensterbank_y: 34 mm; b_ventilatie_x: 228 mm; b_ventilatie_y: 0 mm; b_waterslag_x: 0 mm; b_waterslag_y: 180 mm; berekende_binnen-buiten_host: 140 mm; offset_binnenblad_boven_2: 134 mm; offset_binnenblad_links_2: 131 mm; offset_binnenblad_onder_2: 59 mm; offset_binnenblad_rechts_2: 131 mm
Basic Wall:NLRS_22_WA_HSB bispouw 30-245-12-13 glaswol_gen_ISR:772305 | 02 tweede verdieping | 21.10 Uniformat (Uniformat) | 02 tweede verdieping | 673 | 2. nieuwbouw | 3.88842 | 2390 | 850 | Workset1 | 88 | Windows | NLRS_31_WI_WB_sparingmaker_generiek_BDG | NLRS_31_WI_WB_sparingmaker_generiek_BDG: mw_hsb_raam negge 180_alu v2 | 3063 | 2338901 | mw_hsb_raam negge 180_alu v2 | 863574 | <None> | Schematic Type | 31 | 20160502 | buitenblad Detail | 57 | mw_hsb_raam negge 180_alu v2 | Family : Windows : NLRS_31_WI_WB_sparingmaker_generiek_BDG | Windows | NLRS_31_WI_WB_sparingmaker_generiek_BDG | General - samenstelling: NLRS_31_WI_UN_samenstelling_leeg_generiek_ISR : std; Dimensions - NLRS_C_breedte: 850 mm; NLRS_C_hoogte: 2390 mm; Layers(Type) - binnenblad_afwerking_boven: yes; binnenblad_afwerking_boven_hoek_links: 0 deg; binnenblad_afwerking_boven_hoek_rechts: 0 deg; binnenblad_afwerking_boven_plaatsing_y: 17 mm; binnenblad_afwerking_boven_type: NLRS_41_GM_WPB_multiplex-SH_generiek_ISR : 151x10 gipsvezel dagkant; binnenblad_afwerking_boven_verlenging_links: -148 mm; binnenblad_afwerking_boven_verlenging_rechts: -148 mm; binnenblad_afwerking_links: yes; binnenblad_afwerking_links_hoek_boven: 0 deg; binnenblad_afwerking_links_hoek_onder: 0 deg; binnenblad_afwerking_links_plaatsing_y: 148 mm; binnenblad_afwerking_links_type: NLRS_41_GM_WPB_multiplex-SH_generiek_ISR : 151x10 gipsvezel dagkant; binnenblad_afwerking_links_verlenging_boven: -27 mm; binnenblad_afwerking_links_verlenging_onder: -94 mm; binnenblad_afwerking_plaatsing_x: 149 mm; binnenblad_afwerking_rechts: yes; binnenblad_afwerking_rechts_hoek_boven: 0 deg; binnenblad_afwerking_rechts_hoek_onder: 0 deg; binnenblad_afwerking_rechts_plaatsing_y: 148 mm; binnenblad_afwerking_rechts_type: NLRS_41_GM_WPB_multiplex-SH_generiek_ISR : 151x10 gipsvezel dagkant; binnenblad_afwerking_rechts_verlenging_boven: -27 mm; binnenblad_afwerking_rechts_verlenging_onder: -94 mm; buitenblad_afwerking_boven: no; buitenblad_afwerking_boven_hoek_links: 0 deg; buitenblad_afwerking_boven_hoek_rechts: 0 deg; buitenblad_afwerking_boven_plaatsing_y: 0 mm; buitenblad_afwerking_boven_type: NLRS_41_GM_WPB_omgezet metselwerk-SH_generiek_ISR : std; buitenblad_afwerking_boven_verlenging_links: 0 mm; buitenblad_afwerking_boven_verlenging_rechts: 0 mm; buitenblad_afwerking_links: no; buitenblad_afwerking_links_hoek_boven: 0 deg; buitenblad_afwerking_links_hoek_onder: 0 deg; buitenblad_afwerking_links_plaatsing_y: 0 mm; buitenblad_afwerking_links_type: NLRS_41_GM_WPB_omgezet metselwerk-SH_generiek_ISR : std; buitenblad_afwerking_links_verlenging_boven: 0 mm; buitenblad_afwerking_links_verlenging_onder: 0 mm; buitenblad_afwerking_plaatsing_x: 0 mm; buitenblad_afwerking_rechts: no; buitenblad_afwerking_rechts_hoek_boven: 0 deg; buitenblad_afwerking_rechts_hoek_onder: 0 deg; buitenblad_afwerking_rechts_plaatsing_y: 0 mm; buitenblad_afwerking_rechts_type: NLRS_41_GM_WPB_omgezet metselwerk-SH_generiek_ISR : std; buitenblad_afwerking_rechts_verlenging_boven: 0 mm; buitenblad_afwerking_rechts_verlenging_onder: 0 mm; Constraints(Type) - lossing_binnenblad: 0 mm; offset_binnenblad_boven: 134 mm; offset_binnenblad_links: 131 mm; offset_binnenblad_onder: 59 mm; offset_binnenblad_rechts: 131 mm; offset_binnenbladbeplating_boven: 17 mm; offset_binnenbladbeplating_links: 148 mm; offset_binnenbladbeplating_onder: 17 mm; offset_binnenbladbeplating_rechts: 148 mm; offset_buitenblad_boven: 12 mm; offset_buitenblad_links: 107 mm; offset_buitenblad_onder: 70 mm; offset_buitenblad_rechts: 107 mm; offset_isolatie_boven: 48 mm; offset_isolatie_links: 28 mm; offset_isolatie_onder: 28 mm; offset_isolatie_rechts: 28 mm; Structural(Type) - rekje: no; rekje_plaatsing_x: 0 mm; rekje_plaatsing_y: 0 mm; rekje_type: NLRS_41_GM_WPB_rekje-SH_generiek_ISR : std; rekje_verlenging_links: 200 mm; rekje_verlenging_rechts: 200 mm; spouwlat_boven: yes; spouwlat_boven_plaatsing_y: -17 mm; spouwlat_boven_type: NLRS_41_GM_WPB_spouwlat_isolatie_gen_bdg : 187x38 + isolatie 113x200; spouwlat_boven_verlenging_links: 21 mm; spouwlat_boven_verlenging_rechts: 21 mm; spouwlat_links: yes; spouwlat_links_plaatsing_y: -17 mm; spouwlat_links_type: NLRS_41_GM_WPB_spouwlat_isolatie_gen_bdg : 187x38 + isolatie 110x180; spouwlat_links_verlenging_boven: -17 mm; spouwlat_links_verlenging_onder: -17 mm; spouwlat_onder: yes; spouwlat_onder_plaatsing_y: -17 mm; spouwlat_onder_type: NLRS_41_GM_WPB_spouwlat-SH_generiek_ISR : 185x76; spouwlat_onder_verlenging_links: 21 mm; spouwlat_onder_verlenging_rechts: 21 mm; spouwlat_plaatsing_x: -275 mm; spouwlat_rechts: yes; spouwlat_rechts_plaatsing_y: -17 mm; spouwlat_rechts_type: NLRS_41_GM_WPB_spouwlat_isolatie_gen_bdg : 187x38 + isolatie 110x180; spouwlat_rechts_verlenging_boven: -17 mm; spouwlat_rechts_verlenging_onder: -17 mm; Materials and Finishes(Type) - geveldrager: yes; geveldrager_hoek_a: 0 deg; geveldrager_hoek_b: 0 deg; geveldrager_plaatsing_x: -10 mm; geveldrager_plaatsing_y: 8 mm; geveldrager_type: NLRS_41_SF_LIB_latei_staal_generiek_ISR : 90x150; geveldrager_verlenging_a: 0 mm; geveldrager_verlenging_b: 0 mm; latei: no; latei_hoek_a: 0 deg; latei_hoek_b: 0 deg; latei_plaatsing_x: 0 mm; latei_plaatsing_y: 0 mm; latei_type: NLRS_41_SF_LIB_latei_beton_generiek_ISR : 150x100; latei_verlenging_a: 100 mm; latei_verlenging_b: 100 mm; vensterbank: yes; vensterbank_hoek_a: 0 deg; vensterbank_hoek_b: 0 deg; vensterbank_plaatsing_x: 149 mm; vensterbank_plaatsing_y: 17 mm; vensterbank_type: NLRS_42_GM_WPB_vensterbank_natuursteen-SH_generiek_ISR : 180x18 vensterbank composiet; vensterbank_verlenging_a: -148 mm; vensterbank_verlenging_b: -148 mm; waterslag: yes; waterslag_hoek_a: 0 deg; waterslag_hoek_b: 0 deg; waterslag_plaatsing_x: -25 mm; waterslag_plaatsing_y: 90 mm; waterslag_type: NLRS_41_GM_WPB_waterslag barok-SH_roval_ISR : waterslag_roval_Types Barok_roval_b 270; waterslag_verlenging_a: -100 mm; waterslag_verlenging_b: -100 mm; Graphics(Type) - doorval_hoek_links: 0 deg; doorval_hoek_rechts: 0 deg; doorval_plaatsing_x: 30 mm; doorval_plaatsing_y: 300 mm; doorval_type: NLRS_41_GM_WPB_doorvalbeveiliging-SH_generiek_ISR : std; doorval_verlenging_links: 0 mm; doorval_verlenging_rechts: 0 mm; doorvalbeveiliging: no; ventilatie: no; ventilatie_plaatsing_x: 114 mm; ventilatie_plaatsing_y: 0 mm; ventilatie_type: NLRS_41_GM_WPB_ventilatie-SH_topstream_ISR : std; ventilatie_verlenging_links: 0 mm; ventilatie_verlenging_rechts: 0 mm; Construction(Type) - binnenblad_beplating: 200 mm; binnenblad_hout: 275 mm; buitenblad: 100 mm; isolatie: 10 mm; luchtspouw: 30 mm; negge: 215 mm; Dimensions(Type) - binnenbladhost: yes; buitenbladhost: no; clashobject: no; wrapping_exterior: 0 mm; wrapping_interior: 0 mm; Identity Data(Type) - Assembly Description: buitenwandopeningen; Other(Type) - a_binnen_boven_1: 134 mm; a_binnen_boven_2: 134 mm; a_binnen_links_1: 131 mm; a_binnen_links_2: 131 mm; a_binnen_onder_1: 59 mm; a_binnen_onder_2: 59 mm; a_binnen_rechts_1: 131 mm; a_binnen_rechts_2: 131 mm; a_binnenbepl_boven_1: 17 mm; a_binnenbepl_links_1: 148 mm; a_binnenbepl_onder_1: 17 mm; a_binnenbepl_rechts_1: 148 mm; a_binnenwand_afwerking_boven_y: 17 mm; a_binnenwand_afwerking_links_y: 148 mm; a_binnenwand_afwerking_rechts_y: 148 mm; a_binnenwand_afwerking_x: 149 mm; a_buitenblad_boven: 12 mm; a_buitenblad_boven_y: 0 mm; a_buitenblad_links: 107 mm; a_buitenblad_links_y: 0 mm; a_buitenblad_onder: 70 mm; a_buitenblad_rechts: 107 mm; a_buitenblad_rechts_y: 0 mm; a_buitenblad_x: 0 mm; a_doorval_x: 30 mm; a_doorval_y: 300 mm; a_geveldrager_x: 10 mm; a_geveldrager_y: 8 mm; a_isolatie_boven: 48 mm; a_isolatie_links: 28 mm; a_isolatie_onder: 28 mm; a_isolatie_rechts: 28 mm; a_latei_x: 0 mm; a_latei_y: 0 mm; a_rekje_x: 0 mm; a_rekje_y: 0 mm; a_spouwlat_boven_y: 17 mm; a_spouwlat_links_y: 17 mm; a_spouwlat_onder_y: 17 mm; a_spouwlat_rechts_y: 17 mm; a_spouwlat_x: 275 mm; a_vensterbank_x: 149 mm; a_vensterbank_y: 17 mm; a_ventilatie_x: 114 mm; a_ventilatie_y: 0 mm; a_waterslag_x: 25 mm; a_waterslag_y: 90 mm; b_binnen_boven_1: 268 mm; b_binnen_boven_2: 268 mm; b_binnen_links_1: 262 mm; b_binnen_links_2: 262 mm; b_binnen_onder_1: 118 mm; b_binnen_onder_2: 118 mm; b_binnen_rechts_1: 262 mm; b_binnen_rechts_2: 262 mm; b_binnenwand_afwerking_boven_y: 34 mm; b_binnenwand_afwerking_links_y: 296 mm; b_binnenwand_afwerking_rechts_y: 296 mm; b_binnenwand_afwerking_x: 298 mm; b_buitenblad_boven: 24 mm; b_buitenblad_boven_y: 0 mm; b_buitenblad_links: 214 mm; b_buitenblad_links_y: 0 mm; b_buitenblad_onder: 140 mm; b_buitenblad_rechts: 214 mm; b_buitenblad_rechts_y: 0 mm; b_buitenblad_x: 0 mm; b_doorval_x: 60 mm; b_doorval_y: 600 mm; b_geveldrager_x: 0 mm; b_geveldrager_y: 16 mm; b_isolatie_boven: 96 mm; b_isolatie_links: 56 mm; b_isolatie_onder: 56 mm; b_isolatie_rechts: 56 mm; b_latei_x: 0 mm; b_latei_y: 0 mm; b_rekje_x: 0 mm; b_rekje_y: 0 mm; b_spouwlat_boven_y: 0 mm; b_spouwlat_links_y: 0 mm; b_spouwlat_onder_y: 0 mm; b_spouwlat_rechts_y: 0 mm; b_spouwlat_x: 0 mm; b_vensterbank_x: 298 mm; b_vensterbank_y: 34 mm; b_ventilatie_x: 228 mm; b_ventilatie_y: 0 mm; b_waterslag_x: 0 mm; b_waterslag_y: 180 mm; berekende_binnen-buiten_host: 140 mm; offset_binnenblad_boven_2: 134 mm; offset_binnenblad_links_2: 131 mm; offset_binnenblad_onder_2: 59 mm; offset_binnenblad_rechts_2: 131 mm
Basic Wall:NLRS_22_WA_HSB bispouw 30-245-12-13 glaswol_gen_ISR:772305 | 02 tweede verdieping | 21.10 Uniformat (Uniformat) | 02 tweede verdieping | 673 | 2. nieuwbouw | 3.88842 | 2390 | 850 | Workset1 | 90 | Windows | NLRS_31_WI_WB_sparingmaker_generiek_BDG | NLRS_31_WI_WB_sparingmaker_generiek_BDG: mw_hsb_raam negge 180_alu v2 | 3063 | 2338990 | mw_hsb_raam negge 180_alu v2 | 863574 | <None> | Schematic Type | 31 | 20160502 | buitenblad Detail | 57 | mw_hsb_raam negge 180_alu v2 | Family : Windows : NLRS_31_WI_WB_sparingmaker_generiek_BDG | Windows | NLRS_31_WI_WB_sparingmaker_generiek_BDG | General - samenstelling: NLRS_31_WI_UN_samenstelling_leeg_generiek_ISR : std; Dimensions - NLRS_C_breedte: 850 mm; NLRS_C_hoogte: 2390 mm; Layers(Type) - binnenblad_afwerking_boven: yes; binnenblad_afwerking_boven_hoek_links: 0 deg; binnenblad_afwerking_boven_hoek_rechts: 0 deg; binnenblad_afwerking_boven_plaatsing_y: 17 mm; binnenblad_afwerking_boven_type: NLRS_41_GM_WPB_multiplex-SH_generiek_ISR : 151x10 gipsvezel dagkant; binnenblad_afwerking_boven_verlenging_links: -148 mm; binnenblad_afwerking_boven_verlenging_rechts: -148 mm; binnenblad_afwerking_links: yes; binnenblad_afwerking_links_hoek_boven: 0 deg; binnenblad_afwerking_links_hoek_onder: 0 deg; binnenblad_afwerking_links_plaatsing_y: 148 mm; binnenblad_afwerking_links_type: NLRS_41_GM_WPB_multiplex-SH_generiek_ISR : 151x10 gipsvezel dagkant; binnenblad_afwerking_links_verlenging_boven: -27 mm; binnenblad_afwerking_links_verlenging_onder: -94 mm; binnenblad_afwerking_plaatsing_x: 149 mm; binnenblad_afwerking_rechts: yes; binnenblad_afwerking_rechts_hoek_boven: 0 deg; binnenblad_afwerking_rechts_hoek_onder: 0 deg; binnenblad_afwerking_rechts_plaatsing_y: 148 mm; binnenblad_afwerking_rechts_type: NLRS_41_GM_WPB_multiplex-SH_generiek_ISR : 151x10 gipsvezel dagkant; binnenblad_afwerking_rechts_verlenging_boven: -27 mm; binnenblad_afwerking_rechts_verlenging_onder: -94 mm; buitenblad_afwerking_boven: no; buitenblad_afwerking_boven_hoek_links: 0 deg; buitenblad_afwerking_boven_hoek_rechts: 0 deg; buitenblad_afwerking_boven_plaatsing_y: 0 mm; buitenblad_afwerking_boven_type: NLRS_41_GM_WPB_omgezet metselwerk-SH_generiek_ISR : std; buitenblad_afwerking_boven_verlenging_links: 0 mm; buitenblad_afwerking_boven_verlenging_rechts: 0 mm; buitenblad_afwerking_links: no; buitenblad_afwerking_links_hoek_boven: 0 deg; buitenblad_afwerking_links_hoek_onder: 0 deg; buitenblad_afwerking_links_plaatsing_y: 0 mm; buitenblad_afwerking_links_type: NLRS_41_GM_WPB_omgezet metselwerk-SH_generiek_ISR : std; buitenblad_afwerking_links_verlenging_boven: 0 mm; buitenblad_afwerking_links_verlenging_onder: 0 mm; buitenblad_afwerking_plaatsing_x: 0 mm; buitenblad_afwerking_rechts: no; buitenblad_afwerking_rechts_hoek_boven: 0 deg; buitenblad_afwerking_rechts_hoek_onder: 0 deg; buitenblad_afwerking_rechts_plaatsing_y: 0 mm; buitenblad_afwerking_rechts_type: NLRS_41_GM_WPB_omgezet metselwerk-SH_generiek_ISR : std; buitenblad_afwerking_rechts_verlenging_boven: 0 mm; buitenblad_afwerking_rechts_verlenging_onder: 0 mm; Constraints(Type) - lossing_binnenblad: 0 mm; offset_binnenblad_boven: 134 mm; offset_binnenblad_links: 131 mm; offset_binnenblad_onder: 59 mm; offset_binnenblad_rechts: 131 mm; offset_binnenbladbeplating_boven: 17 mm; offset_binnenbladbeplating_links: 148 mm; offset_binnenbladbeplating_onder: 17 mm; offset_binnenbladbeplating_rechts: 148 mm; offset_buitenblad_boven: 12 mm; offset_buitenblad_links: 107 mm; offset_buitenblad_onder: 70 mm; offset_buitenblad_rechts: 107 mm; offset_isolatie_boven: 48 mm; offset_isolatie_links: 28 mm; offset_isolatie_onder: 28 mm; offset_isolatie_rechts: 28 mm; Structural(Type) - rekje: no; rekje_plaatsing_x: 0 mm; rekje_plaatsing_y: 0 mm; rekje_type: NLRS_41_GM_WPB_rekje-SH_generiek_ISR : std; rekje_verlenging_links: 200 mm; rekje_verlenging_rechts: 200 mm; spouwlat_boven: yes; spouwlat_boven_plaatsing_y: -17 mm; spouwlat_boven_type: NLRS_41_GM_WPB_spouwlat_isolatie_gen_bdg : 187x38 + isolatie 113x200; spouwlat_boven_verlenging_links: 21 mm; spouwlat_boven_verlenging_rechts: 21 mm; spouwlat_links: yes; spouwlat_links_plaatsing_y: -17 mm; spouwlat_links_type: NLRS_41_GM_WPB_spouwlat_isolatie_gen_bdg : 187x38 + isolatie 110x180; spouwlat_links_verlenging_boven: -17 mm; spouwlat_links_verlenging_onder: -17 mm; spouwlat_onder: yes; spouwlat_onder_plaatsing_y: -17 mm; spouwlat_onder_type: NLRS_41_GM_WPB_spouwlat-SH_generiek_ISR : 185x76; spouwlat_onder_verlenging_links: 21 mm; spouwlat_onder_verlenging_rechts: 21 mm; spouwlat_plaatsing_x: -275 mm; spouwlat_rechts: yes; spouwlat_rechts_plaatsing_y: -17 mm; spouwlat_rechts_type: NLRS_41_GM_WPB_spouwlat_isolatie_gen_bdg : 187x38 + isolatie 110x180; spouwlat_rechts_verlenging_boven: -17 mm; spouwlat_rechts_verlenging_onder: -17 mm; Materials and Finishes(Type) - geveldrager: yes; geveldrager_hoek_a: 0 deg; geveldrager_hoek_b: 0 deg; geveldrager_plaatsing_x: -10 mm; geveldrager_plaatsing_y: 8 mm; geveldrager_type: NLRS_41_SF_LIB_latei_staal_generiek_ISR : 90x150; geveldrager_verlenging_a: 0 mm; geveldrager_verlenging_b: 0 mm; latei: no; latei_hoek_a: 0 deg; latei_hoek_b: 0 deg; latei_plaatsing_x: 0 mm; latei_plaatsing_y: 0 mm; latei_type: NLRS_41_SF_LIB_latei_beton_generiek_ISR : 150x100; latei_verlenging_a: 100 mm; latei_verlenging_b: 100 mm; vensterbank: yes; vensterbank_hoek_a: 0 deg; vensterbank_hoek_b: 0 deg; vensterbank_plaatsing_x: 149 mm; vensterbank_plaatsing_y: 17 mm; vensterbank_type: NLRS_42_GM_WPB_vensterbank_natuursteen-SH_generiek_ISR : 180x18 vensterbank composiet; vensterbank_verlenging_a: -148 mm; vensterbank_verlenging_b: -148 mm; waterslag: yes; waterslag_hoek_a: 0 deg; waterslag_hoek_b: 0 deg; waterslag_plaatsing_x: -25 mm; waterslag_plaatsing_y: 90 mm; waterslag_type: NLRS_41_GM_WPB_waterslag barok-SH_roval_ISR : waterslag_roval_Types Barok_roval_b 270; waterslag_verlenging_a: -100 mm; waterslag_verlenging_b: -100 mm; Graphics(Type) - doorval_hoek_links: 0 deg; doorval_hoek_rechts: 0 deg; doorval_plaatsing_x: 30 mm; doorval_plaatsing_y: 300 mm; doorval_type: NLRS_41_GM_WPB_doorvalbeveiliging-SH_generiek_ISR : std; doorval_verlenging_links: 0 mm; doorval_verlenging_rechts: 0 mm; doorvalbeveiliging: no; ventilatie: no; ventilatie_plaatsing_x: 114 mm; ventilatie_plaatsing_y: 0 mm; ventilatie_type: NLRS_41_GM_WPB_ventilatie-SH_topstream_ISR : std; ventilatie_verlenging_links: 0 mm; ventilatie_verlenging_rechts: 0 mm; Construction(Type) - binnenblad_beplating: 200 mm; binnenblad_hout: 275 mm; buitenblad: 100 mm; isolatie: 10 mm; luchtspouw: 30 mm; negge: 215 mm; Dimensions(Type) - binnenbladhost: yes; buitenbladhost: no; clashobject: no; wrapping_exterior: 0 mm; wrapping_interior: 0 mm; Identity Data(Type) - Assembly Description: buitenwandopeningen; Other(Type) - a_binnen_boven_1: 134 mm; a_binnen_boven_2: 134 mm; a_binnen_links_1: 131 mm; a_binnen_links_2: 131 mm; a_binnen_onder_1: 59 mm; a_binnen_onder_2: 59 mm; a_binnen_rechts_1: 131 mm; a_binnen_rechts_2: 131 mm; a_binnenbepl_boven_1: 17 mm; a_binnenbepl_links_1: 148 mm; a_binnenbepl_onder_1: 17 mm; a_binnenbepl_rechts_1: 148 mm; a_binnenwand_afwerking_boven_y: 17 mm; a_binnenwand_afwerking_links_y: 148 mm; a_binnenwand_afwerking_rechts_y: 148 mm; a_binnenwand_afwerking_x: 149 mm; a_buitenblad_boven: 12 mm; a_buitenblad_boven_y: 0 mm; a_buitenblad_links: 107 mm; a_buitenblad_links_y: 0 mm; a_buitenblad_onder: 70 mm; a_buitenblad_rechts: 107 mm; a_buitenblad_rechts_y: 0 mm; a_buitenblad_x: 0 mm; a_doorval_x: 30 mm; a_doorval_y: 300 mm; a_geveldrager_x: 10 mm; a_geveldrager_y: 8 mm; a_isolatie_boven: 48 mm; a_isolatie_links: 28 mm; a_isolatie_onder: 28 mm; a_isolatie_rechts: 28 mm; a_latei_x: 0 mm; a_latei_y: 0 mm; a_rekje_x: 0 mm; a_rekje_y: 0 mm; a_spouwlat_boven_y: 17 mm; a_spouwlat_links_y: 17 mm; a_spouwlat_onder_y: 17 mm; a_spouwlat_rechts_y: 17 mm; a_spouwlat_x: 275 mm; a_vensterbank_x: 149 mm; a_vensterbank_y: 17 mm; a_ventilatie_x: 114 mm; a_ventilatie_y: 0 mm; a_waterslag_x: 25 mm; a_waterslag_y: 90 mm; b_binnen_boven_1: 268 mm; b_binnen_boven_2: 268 mm; b_binnen_links_1: 262 mm; b_binnen_links_2: 262 mm; b_binnen_onder_1: 118 mm; b_binnen_onder_2: 118 mm; b_binnen_rechts_1: 262 mm; b_binnen_rechts_2: 262 mm; b_binnenwand_afwerking_boven_y: 34 mm; b_binnenwand_afwerking_links_y: 296 mm; b_binnenwand_afwerking_rechts_y: 296 mm; b_binnenwand_afwerking_x: 298 mm; b_buitenblad_boven: 24 mm; b_buitenblad_boven_y: 0 mm; b_buitenblad_links: 214 mm; b_buitenblad_links_y: 0 mm; b_buitenblad_onder: 140 mm; b_buitenblad_rechts: 214 mm; b_buitenblad_rechts_y: 0 mm; b_buitenblad_x: 0 mm; b_doorval_x: 60 mm; b_doorval_y: 600 mm; b_geveldrager_x: 0 mm; b_geveldrager_y: 16 mm; b_isolatie_boven: 96 mm; b_isolatie_links: 56 mm; b_isolatie_onder: 56 mm; b_isolatie_rechts: 56 mm; b_latei_x: 0 mm; b_latei_y: 0 mm; b_rekje_x: 0 mm; b_rekje_y: 0 mm; b_spouwlat_boven_y: 0 mm; b_spouwlat_links_y: 0 mm; b_spouwlat_onder_y: 0 mm; b_spouwlat_rechts_y: 0 mm; b_spouwlat_x: 0 mm; b_vensterbank_x: 298 mm; b_vensterbank_y: 34 mm; b_ventilatie_x: 228 mm; b_ventilatie_y: 0 mm; b_waterslag_x: 0 mm; b_waterslag_y: 180 mm; berekende_binnen-buiten_host: 140 mm; offset_binnenblad_boven_2: 134 mm; offset_binnenblad_links_2: 131 mm; offset_binnenblad_onder_2: 59 mm; offset_binnenblad_rechts_2: 131 mm
Basic Wall:NLRS_22_WA_HSB bispouw 30-245-12-13 glaswol_gen_ISR:772305 | 02 tweede verdieping | 21.10 Uniformat (Uniformat) | 02 tweede verdieping | 673 | 2. nieuwbouw | 3.88842 | 2390 | 850 | Workset1 | 92 | Windows | NLRS_31_WI_WB_sparingmaker_generiek_BDG | NLRS_31_WI_WB_sparingmaker_generiek_BDG: mw_hsb_raam negge 180_alu v2 trappenhuis | 3063 | 2338990 | mw_hsb_raam negge 180_alu v2 trappenhuis | 4342392 | <None> | Schematic Type | 31 | 20160502 | buitenblad Detail | 107 | mw_hsb_raam negge 180_alu v2 trappenhuis | Family : Windows : NLRS_31_WI_WB_sparingmaker_generiek_BDG | Windows | NLRS_31_WI_WB_sparingmaker_generiek_BDG | General - samenstelling: NLRS_31_WI_UN_samenstelling_leeg_generiek_ISR : std; Dimensions - NLRS_C_breedte: 850 mm; NLRS_C_hoogte: 2390 mm; Layers(Type) - binnenblad_afwerking_boven: yes; binnenblad_afwerking_boven_hoek_links: 0 deg; binnenblad_afwerking_boven_hoek_rechts: 0 deg; binnenblad_afwerking_boven_plaatsing_y: 17 mm; binnenblad_afwerking_boven_type: NLRS_41_GM_WPB_multiplex-SH_generiek_ISR : 306x10 gipsvezel dagkant; binnenblad_afwerking_boven_verlenging_links: -148 mm; binnenblad_afwerking_boven_verlenging_rechts: -148 mm; binnenblad_afwerking_links: yes; binnenblad_afwerking_links_hoek_boven: 0 deg; binnenblad_afwerking_links_hoek_onder: 0 deg; binnenblad_afwerking_links_plaatsing_y: 148 mm; binnenblad_afwerking_links_type: NLRS_41_GM_WPB_multiplex-SH_generiek_ISR : 306x10 gipsvezel dagkant; binnenblad_afwerking_links_verlenging_boven: -27 mm; binnenblad_afwerking_links_verlenging_onder: -94 mm; binnenblad_afwerking_plaatsing_x: 149 mm; binnenblad_afwerking_rechts: yes; binnenblad_afwerking_rechts_hoek_boven: 0 deg; binnenblad_afwerking_rechts_hoek_onder: 0 deg; binnenblad_afwerking_rechts_plaatsing_y: 148 mm; binnenblad_afwerking_rechts_type: NLRS_41_GM_WPB_multiplex-SH_generiek_ISR : 306x10 gipsvezel dagkant; binnenblad_afwerking_rechts_verlenging_boven: -27 mm; binnenblad_afwerking_rechts_verlenging_onder: -94 mm; buitenblad_afwerking_boven: no; buitenblad_afwerking_boven_hoek_links: 0 deg; buitenblad_afwerking_boven_hoek_rechts: 0 deg; buitenblad_afwerking_boven_plaatsing_y: 0 mm; buitenblad_afwerking_boven_type: NLRS_41_GM_WPB_omgezet metselwerk-SH_generiek_ISR : std; buitenblad_afwerking_boven_verlenging_links: 0 mm; buitenblad_afwerking_boven_verlenging_rechts: 0 mm; buitenblad_afwerking_links: no; buitenblad_afwerking_links_hoek_boven: 0 deg; buitenblad_afwerking_links_hoek_onder: 0 deg; buitenblad_afwerking_links_plaatsing_y: 0 mm; buitenblad_afwerking_links_type: NLRS_41_GM_WPB_omgezet metselwerk-SH_generiek_ISR : std; buitenblad_afwerking_links_verlenging_boven: 0 mm; buitenblad_afwerking_links_verlenging_onder: 0 mm; buitenblad_afwerking_plaatsing_x: 0 mm; buitenblad_afwerking_rechts: no; buitenblad_afwerking_rechts_hoek_boven: 0 deg; buitenblad_afwerking_rechts_hoek_onder: 0 deg; buitenblad_afwerking_rechts_plaatsing_y: 0 mm; buitenblad_afwerking_rechts_type: NLRS_41_GM_WPB_omgezet metselwerk-SH_generiek_ISR : std; buitenblad_afwerking_rechts_verlenging_boven: 0 mm; buitenblad_afwerking_rechts_verlenging_onder: 0 mm; Constraints(Type) - lossing_binnenblad: 0 mm; offset_binnenblad_boven: 134 mm; offset_binnenblad_links: 131 mm; offset_binnenblad_onder: 59 mm; offset_binnenblad_rechts: 131 mm; offset_binnenbladbeplating_boven: 17 mm; offset_binnenbladbeplating_links: 148 mm; offset_binnenbladbeplating_onder: 17 mm; offset_binnenbladbeplating_rechts: 148 mm; offset_buitenblad_boven: 12 mm; offset_buitenblad_links: 107 mm; offset_buitenblad_onder: 70 mm; offset_buitenblad_rechts: 107 mm; offset_isolatie_boven: 48 mm; offset_isolatie_links: 28 mm; offset_isolatie_onder: 28 mm; offset_isolatie_rechts: 28 mm; Structural(Type) - rekje: no; rekje_plaatsing_x: 0 mm; rekje_plaatsing_y: 0 mm; rekje_type: NLRS_41_GM_WPB_rekje-SH_generiek_ISR : std; rekje_verlenging_links: 200 mm; rekje_verlenging_rechts: 200 mm; spouwlat_boven: yes; spouwlat_boven_plaatsing_y: -17 mm; spouwlat_boven_type: NLRS_41_GM_WPB_spouwlat_isolatie_gen_bdg : 187x38 + isolatie 113x200; spouwlat_boven_verlenging_links: 21 mm; spouwlat_boven_verlenging_rechts: 21 mm; spouwlat_links: yes; spouwlat_links_plaatsing_y: -17 mm; spouwlat_links_type: NLRS_41_GM_WPB_spouwlat_isolatie_gen_bdg : 187x38 + isolatie 110x180; spouwlat_links_verlenging_boven: -17 mm; spouwlat_links_verlenging_onder: -17 mm; spouwlat_onder: yes; spouwlat_onder_plaatsing_y: -17 mm; spouwlat_onder_type: NLRS_41_GM_WPB_spouwlat-SH_generiek_ISR : 185x76; spouwlat_onder_verlenging_links: 21 mm; spouwlat_onder_verlenging_rechts: 21 mm; spouwlat_plaatsing_x: -275 mm; spouwlat_rechts: yes; spouwlat_rechts_plaatsing_y: -17 mm; spouwlat_rechts_type: NLRS_41_GM_WPB_spouwlat_isolatie_gen_bdg : 187x38 + isolatie 110x180; spouwlat_rechts_verlenging_boven: -17 mm; spouwlat_rechts_verlenging_onder: -17 mm; Materials and Finishes(Type) - geveldrager: yes; geveldrager_hoek_a: 0 deg; geveldrager_hoek_b: 0 deg; geveldrager_plaatsing_x: -10 mm; geveldrager_plaatsing_y: 8 mm; geveldrager_type: NLRS_41_SF_LIB_latei_staal_generiek_ISR : 90x150; geveldrager_verlenging_a: 0 mm; geveldrager_verlenging_b: 0 mm; latei: no; latei_hoek_a: 0 deg; latei_hoek_b: 0 deg; latei_plaatsing_x: 0 mm; latei_plaatsing_y: 0 mm; latei_type: NLRS_41_SF_LIB_latei_beton_generiek_ISR : 150x100; latei_verlenging_a: 100 mm; latei_verlenging_b: 100 mm; vensterbank: yes; vensterbank_hoek_a: 0 deg; vensterbank_hoek_b: 0 deg; vensterbank_plaatsing_x: 149 mm; vensterbank_plaatsing_y: 17 mm; vensterbank_type: NLRS_42_GM_WPB_vensterbank_natuursteen-SH_generiek_ISR : 335x18 vensterbank composiet; vensterbank_verlenging_a: -148 mm; vensterbank_verlenging_b: -148 mm; waterslag: yes; waterslag_hoek_a: 0 deg; waterslag_hoek_b: 0 deg; waterslag_plaatsing_x: -25 mm; waterslag_plaatsing_y: 90 mm; waterslag_type: NLRS_41_GM_WPB_waterslag barok-SH_roval_ISR : waterslag_roval_Types Barok_roval_b 270; waterslag_verlenging_a: -100 mm; waterslag_verlenging_b: -100 mm; Graphics(Type) - doorval_hoek_links: 0 deg; doorval_hoek_rechts: 0 deg; doorval_plaatsing_x: 30 mm; doorval_plaatsing_y: 300 mm; doorval_type: NLRS_41_GM_WPB_doorvalbeveiliging-SH_generiek_ISR : std; doorval_verlenging_links: 0 mm; doorval_verlenging_rechts: 0 mm; doorvalbeveiliging: no; ventilatie: no; ventilatie_plaatsing_x: 114 mm; ventilatie_plaatsing_y: 0 mm; ventilatie_type: NLRS_41_GM_WPB_ventilatie-SH_topstream_ISR : std; ventilatie_verlenging_links: 0 mm; ventilatie_verlenging_rechts: 0 mm; Construction(Type) - binnenblad_beplating: 200 mm; binnenblad_hout: 275 mm; buitenblad: 100 mm; isolatie: 10 mm; luchtspouw: 30 mm; negge: 215 mm; Dimensions(Type) - binnenbladhost: yes; buitenbladhost: no; clashobject: no; wrapping_exterior: 0 mm; wrapping_interior: 0 mm; Identity Data(Type) - Assembly Description: buitenwandopeningen; Other(Type) - a_binnen_boven_1: 134 mm; a_binnen_boven_2: 134 mm; a_binnen_links_1: 131 mm; a_binnen_links_2: 131 mm; a_binnen_onder_1: 59 mm; a_binnen_onder_2: 59 mm; a_binnen_rechts_1: 131 mm; a_binnen_rechts_2: 131 mm; a_binnenbepl_boven_1: 17 mm; a_binnenbepl_links_1: 148 mm; a_binnenbepl_onder_1: 17 mm; a_binnenbepl_rechts_1: 148 mm; a_binnenwand_afwerking_boven_y: 17 mm; a_binnenwand_afwerking_links_y: 148 mm; a_binnenwand_afwerking_rechts_y: 148 mm; a_binnenwand_afwerking_x: 149 mm; a_buitenblad_boven: 12 mm; a_buitenblad_boven_y: 0 mm; a_buitenblad_links: 107 mm; a_buitenblad_links_y: 0 mm; a_buitenblad_onder: 70 mm; a_buitenblad_rechts: 107 mm; a_buitenblad_rechts_y: 0 mm; a_buitenblad_x: 0 mm; a_doorval_x: 30 mm; a_doorval_y: 300 mm; a_geveldrager_x: 10 mm; a_geveldrager_y: 8 mm; a_isolatie_boven: 48 mm; a_isolatie_links: 28 mm; a_isolatie_onder: 28 mm; a_isolatie_rechts: 28 mm; a_latei_x: 0 mm; a_latei_y: 0 mm; a_rekje_x: 0 mm; a_rekje_y: 0 mm; a_spouwlat_boven_y: 17 mm; a_spouwlat_links_y: 17 mm; a_spouwlat_onder_y: 17 mm; a_spouwlat_rechts_y: 17 mm; a_spouwlat_x: 275 mm; a_vensterbank_x: 149 mm; a_vensterbank_y: 17 mm; a_ventilatie_x: 114 mm; a_ventilatie_y: 0 mm; a_waterslag_x: 25 mm; a_waterslag_y: 90 mm; b_binnen_boven_1: 268 mm; b_binnen_boven_2: 268 mm; b_binnen_links_1: 262 mm; b_binnen_links_2: 262 mm; b_binnen_onder_1: 118 mm; b_binnen_onder_2: 118 mm; b_binnen_rechts_1: 262 mm; b_binnen_rechts_2: 262 mm; b_binnenwand_afwerking_boven_y: 34 mm; b_binnenwand_afwerking_links_y: 296 mm; b_binnenwand_afwerking_rechts_y: 296 mm; b_binnenwand_afwerking_x: 298 mm; b_buitenblad_boven: 24 mm; b_buitenblad_boven_y: 0 mm; b_buitenblad_links: 214 mm; b_buitenblad_links_y: 0 mm; b_buitenblad_onder: 140 mm; b_buitenblad_rechts: 214 mm; b_buitenblad_rechts_y: 0 mm; b_buitenblad_x: 0 mm; b_doorval_x: 60 mm; b_doorval_y: 600 mm; b_geveldrager_x: 0 mm; b_geveldrager_y: 16 mm; b_isolatie_boven: 96 mm; b_isolatie_links: 56 mm; b_isolatie_onder: 56 mm; b_isolatie_rechts: 56 mm; b_latei_x: 0 mm; b_latei_y: 0 mm; b_rekje_x: 0 mm; b_rekje_y: 0 mm; b_spouwlat_boven_y: 0 mm; b_spouwlat_links_y: 0 mm; b_spouwlat_onder_y: 0 mm; b_spouwlat_rechts_y: 0 mm; b_spouwlat_x: 0 mm; b_vensterbank_x: 298 mm; b_vensterbank_y: 34 mm; b_ventilatie_x: 228 mm; b_ventilatie_y: 0 mm; b_waterslag_x: 0 mm; b_waterslag_y: 180 mm; berekende_binnen-buiten_host: 140 mm; offset_binnenblad_boven_2: 134 mm; offset_binnenblad_links_2: 131 mm; offset_binnenblad_onder_2: 59 mm; offset_binnenblad_rechts_2: 131 mm
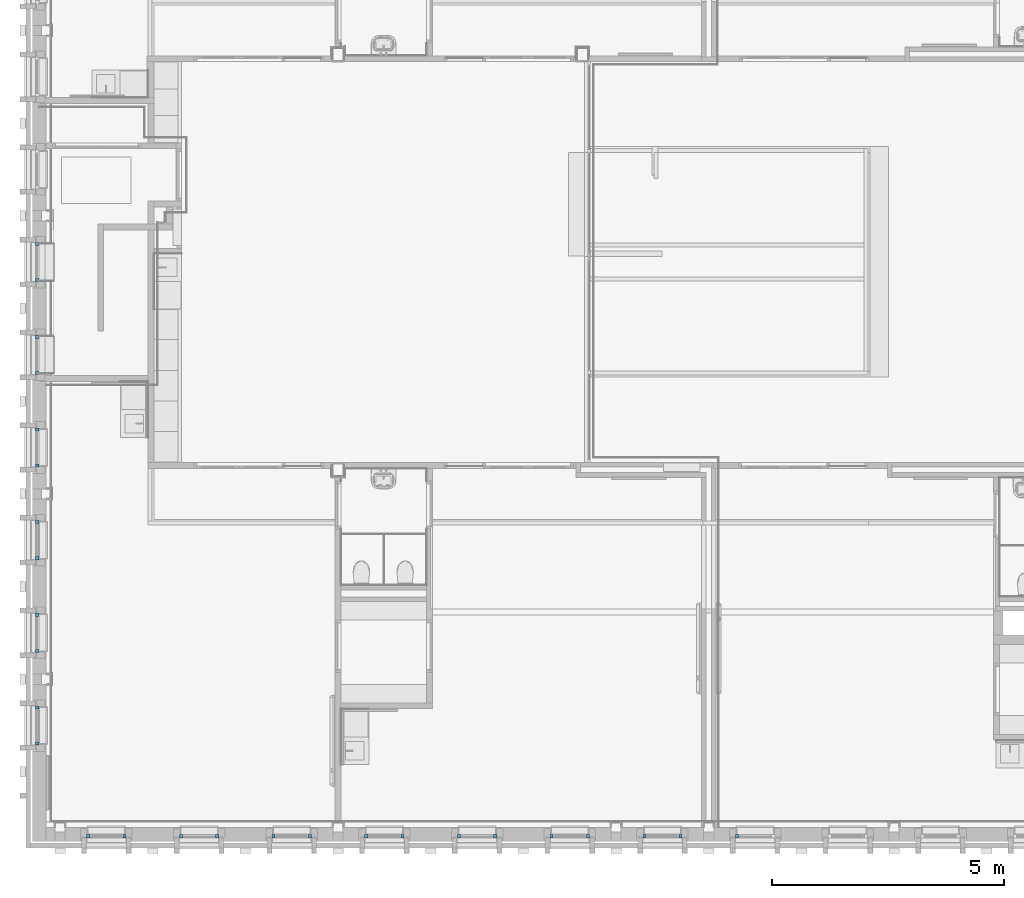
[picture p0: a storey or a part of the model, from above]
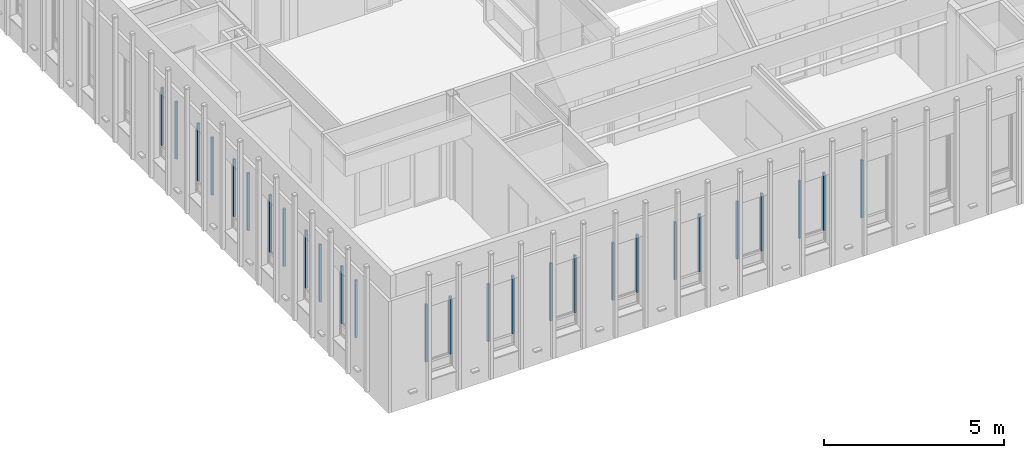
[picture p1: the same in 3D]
Properties of the parts of a building model (IFC2X3), part 64 of 94

# IfcOpeningElement: Opening (823)
Name | In | Classification | Level | Sill Height (mm) | Phase Created | Area (m2) | Height (mm) | Width (mm) | Identity Data, Workset | Mark | Other, Category | Family | Family and Type | Head Height (mm) | Host Id | Type | Type Id | Analytic Construction | Define Thermal Properties by | Assembly Code | Datum_Gewijzigd | Description | Type Mark | Type Name | Identity Data(Type), Workset | Other(Type), Category | Family Name
Basic Wall:21_WA_metselwerk_licht_100_gen_bdg:2351650 | 02 tweede verdieping | 2D(21.11.11) Uniformat (Uniformat) | 02 tweede verdieping | 673 | 2. nieuwbouw | 3.88842 | 2390 | 850 | Workset1 | 62 | Windows | NLRS_31_WI_WB_sparingmaker_generiek_BDG | NLRS_31_WI_WB_sparingmaker_generiek_BDG: mw_hsb_raam negge 180_alu v2 | 3063 | 772307 | mw_hsb_raam negge 180_alu v2 | 863574 | <None> | Schematic Type | 31 | 20160502 | buitenblad Detail | 57 | mw_hsb_raam negge 180_alu v2 | Family : Windows : NLRS_31_WI_WB_sparingmaker_generiek_BDG | Windows | NLRS_31_WI_WB_sparingmaker_generiek_BDG | General - samenstelling: NLRS_31_WI_UN_samenstelling_leeg_generiek_ISR : std; Dimensions - NLRS_C_breedte: 850 mm; NLRS_C_hoogte: 2390 mm; Layers(Type) - binnenblad_afwerking_boven: yes; binnenblad_afwerking_boven_hoek_links: 0 deg; binnenblad_afwerking_boven_hoek_rechts: 0 deg; binnenblad_afwerking_boven_plaatsing_y: 17 mm; binnenblad_afwerking_boven_type: NLRS_41_GM_WPB_multiplex-SH_generiek_ISR : 151x10 gipsvezel dagkant; binnenblad_afwerking_boven_verlenging_links: -148 mm; binnenblad_afwerking_boven_verlenging_rechts: -148 mm; binnenblad_afwerking_links: yes; binnenblad_afwerking_links_hoek_boven: 0 deg; binnenblad_afwerking_links_hoek_onder: 0 deg; binnenblad_afwerking_links_plaatsing_y: 148 mm; binnenblad_afwerking_links_type: NLRS_41_GM_WPB_multiplex-SH_generiek_ISR : 151x10 gipsvezel dagkant; binnenblad_afwerking_links_verlenging_boven: -27 mm; binnenblad_afwerking_links_verlenging_onder: -94 mm; binnenblad_afwerking_plaatsing_x: 149 mm; binnenblad_afwerking_rechts: yes; binnenblad_afwerking_rechts_hoek_boven: 0 deg; binnenblad_afwerking_rechts_hoek_onder: 0 deg; binnenblad_afwerking_rechts_plaatsing_y: 148 mm; binnenblad_afwerking_rechts_type: NLRS_41_GM_WPB_multiplex-SH_generiek_ISR : 151x10 gipsvezel dagkant; binnenblad_afwerking_rechts_verlenging_boven: -27 mm; binnenblad_afwerking_rechts_verlenging_onder: -94 mm; buitenblad_afwerking_boven: no; buitenblad_afwerking_boven_hoek_links: 0 deg; buitenblad_afwerking_boven_hoek_rechts: 0 deg; buitenblad_afwerking_boven_plaatsing_y: 0 mm; buitenblad_afwerking_boven_type: NLRS_41_GM_WPB_omgezet metselwerk-SH_generiek_ISR : std; buitenblad_afwerking_boven_verlenging_links: 0 mm; buitenblad_afwerking_boven_verlenging_rechts: 0 mm; buitenblad_afwerking_links: no; buitenblad_afwerking_links_hoek_boven: 0 deg; buitenblad_afwerking_links_hoek_onder: 0 deg; buitenblad_afwerking_links_plaatsing_y: 0 mm; buitenblad_afwerking_links_type: NLRS_41_GM_WPB_omgezet metselwerk-SH_generiek_ISR : std; buitenblad_afwerking_links_verlenging_boven: 0 mm; buitenblad_afwerking_links_verlenging_onder: 0 mm; buitenblad_afwerking_plaatsing_x: 0 mm; buitenblad_afwerking_rechts: no; buitenblad_afwerking_rechts_hoek_boven: 0 deg; buitenblad_afwerking_rechts_hoek_onder: 0 deg; buitenblad_afwerking_rechts_plaatsing_y: 0 mm; buitenblad_afwerking_rechts_type: NLRS_41_GM_WPB_omgezet metselwerk-SH_generiek_ISR : std; buitenblad_afwerking_rechts_verlenging_boven: 0 mm; buitenblad_afwerking_rechts_verlenging_onder: 0 mm; Constraints(Type) - lossing_binnenblad: 0 mm; offset_binnenblad_boven: 134 mm; offset_binnenblad_links: 131 mm; offset_binnenblad_onder: 59 mm; offset_binnenblad_rechts: 131 mm; offset_binnenbladbeplating_boven: 17 mm; offset_binnenbladbeplating_links: 148 mm; offset_binnenbladbeplating_onder: 17 mm; offset_binnenbladbeplating_rechts: 148 mm; offset_buitenblad_boven: 12 mm; offset_buitenblad_links: 107 mm; offset_buitenblad_onder: 70 mm; offset_buitenblad_rechts: 107 mm; offset_isolatie_boven: 48 mm; offset_isolatie_links: 28 mm; offset_isolatie_onder: 28 mm; offset_isolatie_rechts: 28 mm; Structural(Type) - rekje: no; rekje_plaatsing_x: 0 mm; rekje_plaatsing_y: 0 mm; rekje_type: NLRS_41_GM_WPB_rekje-SH_generiek_ISR : std; rekje_verlenging_links: 200 mm; rekje_verlenging_rechts: 200 mm; spouwlat_boven: yes; spouwlat_boven_plaatsing_y: -17 mm; spouwlat_boven_type: NLRS_41_GM_WPB_spouwlat_isolatie_gen_bdg : 187x38 + isolatie 113x200; spouwlat_boven_verlenging_links: 21 mm; spouwlat_boven_verlenging_rechts: 21 mm; spouwlat_links: yes; spouwlat_links_plaatsing_y: -17 mm; spouwlat_links_type: NLRS_41_GM_WPB_spouwlat_isolatie_gen_bdg : 187x38 + isolatie 110x180; spouwlat_links_verlenging_boven: -17 mm; spouwlat_links_verlenging_onder: -17 mm; spouwlat_onder: yes; spouwlat_onder_plaatsing_y: -17 mm; spouwlat_onder_type: NLRS_41_GM_WPB_spouwlat-SH_generiek_ISR : 185x76; spouwlat_onder_verlenging_links: 21 mm; spouwlat_onder_verlenging_rechts: 21 mm; spouwlat_plaatsing_x: -275 mm; spouwlat_rechts: yes; spouwlat_rechts_plaatsing_y: -17 mm; spouwlat_rechts_type: NLRS_41_GM_WPB_spouwlat_isolatie_gen_bdg : 187x38 + isolatie 110x180; spouwlat_rechts_verlenging_boven: -17 mm; spouwlat_rechts_verlenging_onder: -17 mm; Materials and Finishes(Type) - geveldrager: yes; geveldrager_hoek_a: 0 deg; geveldrager_hoek_b: 0 deg; geveldrager_plaatsing_x: -10 mm; geveldrager_plaatsing_y: 8 mm; geveldrager_type: NLRS_41_SF_LIB_latei_staal_generiek_ISR : 90x150; geveldrager_verlenging_a: 0 mm; geveldrager_verlenging_b: 0 mm; latei: no; latei_hoek_a: 0 deg; latei_hoek_b: 0 deg; latei_plaatsing_x: 0 mm; latei_plaatsing_y: 0 mm; latei_type: NLRS_41_SF_LIB_latei_beton_generiek_ISR : 150x100; latei_verlenging_a: 100 mm; latei_verlenging_b: 100 mm; vensterbank: yes; vensterbank_hoek_a: 0 deg; vensterbank_hoek_b: 0 deg; vensterbank_plaatsing_x: 149 mm; vensterbank_plaatsing_y: 17 mm; vensterbank_type: NLRS_42_GM_WPB_vensterbank_natuursteen-SH_generiek_ISR : 180x18 vensterbank composiet; vensterbank_verlenging_a: -148 mm; vensterbank_verlenging_b: -148 mm; waterslag: yes; waterslag_hoek_a: 0 deg; waterslag_hoek_b: 0 deg; waterslag_plaatsing_x: -25 mm; waterslag_plaatsing_y: 90 mm; waterslag_type: NLRS_41_GM_WPB_waterslag barok-SH_roval_ISR : waterslag_roval_Types Barok_roval_b 270; waterslag_verlenging_a: -100 mm; waterslag_verlenging_b: -100 mm; Graphics(Type) - doorval_hoek_links: 0 deg; doorval_hoek_rechts: 0 deg; doorval_plaatsing_x: 30 mm; doorval_plaatsing_y: 300 mm; doorval_type: NLRS_41_GM_WPB_doorvalbeveiliging-SH_generiek_ISR : std; doorval_verlenging_links: 0 mm; doorval_verlenging_rechts: 0 mm; doorvalbeveiliging: no; ventilatie: no; ventilatie_plaatsing_x: 114 mm; ventilatie_plaatsing_y: 0 mm; ventilatie_type: NLRS_41_GM_WPB_ventilatie-SH_topstream_ISR : std; ventilatie_verlenging_links: 0 mm; ventilatie_verlenging_rechts: 0 mm; Construction(Type) - binnenblad_beplating: 200 mm; binnenblad_hout: 275 mm; buitenblad: 100 mm; isolatie: 10 mm; luchtspouw: 30 mm; negge: 215 mm; Dimensions(Type) - binnenbladhost: yes; buitenbladhost: no; clashobject: no; wrapping_exterior: 0 mm; wrapping_interior: 0 mm; Identity Data(Type) - Assembly Description: buitenwandopeningen; Other(Type) - a_binnen_boven_1: 134 mm; a_binnen_boven_2: 134 mm; a_binnen_links_1: 131 mm; a_binnen_links_2: 131 mm; a_binnen_onder_1: 59 mm; a_binnen_onder_2: 59 mm; a_binnen_rechts_1: 131 mm; a_binnen_rechts_2: 131 mm; a_binnenbepl_boven_1: 17 mm; a_binnenbepl_links_1: 148 mm; a_binnenbepl_onder_1: 17 mm; a_binnenbepl_rechts_1: 148 mm; a_binnenwand_afwerking_boven_y: 17 mm; a_binnenwand_afwerking_links_y: 148 mm; a_binnenwand_afwerking_rechts_y: 148 mm; a_binnenwand_afwerking_x: 149 mm; a_buitenblad_boven: 12 mm; a_buitenblad_boven_y: 0 mm; a_buitenblad_links: 107 mm; a_buitenblad_links_y: 0 mm; a_buitenblad_onder: 70 mm; a_buitenblad_rechts: 107 mm; a_buitenblad_rechts_y: 0 mm; a_buitenblad_x: 0 mm; a_doorval_x: 30 mm; a_doorval_y: 300 mm; a_geveldrager_x: 10 mm; a_geveldrager_y: 8 mm; a_isolatie_boven: 48 mm; a_isolatie_links: 28 mm; a_isolatie_onder: 28 mm; a_isolatie_rechts: 28 mm; a_latei_x: 0 mm; a_latei_y: 0 mm; a_rekje_x: 0 mm; a_rekje_y: 0 mm; a_spouwlat_boven_y: 17 mm; a_spouwlat_links_y: 17 mm; a_spouwlat_onder_y: 17 mm; a_spouwlat_rechts_y: 17 mm; a_spouwlat_x: 275 mm; a_vensterbank_x: 149 mm; a_vensterbank_y: 17 mm; a_ventilatie_x: 114 mm; a_ventilatie_y: 0 mm; a_waterslag_x: 25 mm; a_waterslag_y: 90 mm; b_binnen_boven_1: 268 mm; b_binnen_boven_2: 268 mm; b_binnen_links_1: 262 mm; b_binnen_links_2: 262 mm; b_binnen_onder_1: 118 mm; b_binnen_onder_2: 118 mm; b_binnen_rechts_1: 262 mm; b_binnen_rechts_2: 262 mm; b_binnenwand_afwerking_boven_y: 34 mm; b_binnenwand_afwerking_links_y: 296 mm; b_binnenwand_afwerking_rechts_y: 296 mm; b_binnenwand_afwerking_x: 298 mm; b_buitenblad_boven: 24 mm; b_buitenblad_boven_y: 0 mm; b_buitenblad_links: 214 mm; b_buitenblad_links_y: 0 mm; b_buitenblad_onder: 140 mm; b_buitenblad_rechts: 214 mm; b_buitenblad_rechts_y: 0 mm; b_buitenblad_x: 0 mm; b_doorval_x: 60 mm; b_doorval_y: 600 mm; b_geveldrager_x: 0 mm; b_geveldrager_y: 16 mm; b_isolatie_boven: 96 mm; b_isolatie_links: 56 mm; b_isolatie_onder: 56 mm; b_isolatie_rechts: 56 mm; b_latei_x: 0 mm; b_latei_y: 0 mm; b_rekje_x: 0 mm; b_rekje_y: 0 mm; b_spouwlat_boven_y: 0 mm; b_spouwlat_links_y: 0 mm; b_spouwlat_onder_y: 0 mm; b_spouwlat_rechts_y: 0 mm; b_spouwlat_x: 0 mm; b_vensterbank_x: 298 mm; b_vensterbank_y: 34 mm; b_ventilatie_x: 228 mm; b_ventilatie_y: 0 mm; b_waterslag_x: 0 mm; b_waterslag_y: 180 mm; berekende_binnen-buiten_host: 140 mm; offset_binnenblad_boven_2: 134 mm; offset_binnenblad_links_2: 131 mm; offset_binnenblad_onder_2: 59 mm; offset_binnenblad_rechts_2: 131 mm
Basic Wall:21_WA_metselwerk_licht_100_gen_bdg:2351650 | 02 tweede verdieping | 2D(21.11.11) Uniformat (Uniformat) | 02 tweede verdieping | 673 | 2. nieuwbouw | 3.88842 | 2390 | 850 | Workset1 | 64 | Windows | NLRS_31_WI_WB_sparingmaker_generiek_BDG | NLRS_31_WI_WB_sparingmaker_generiek_BDG: mw_hsb_raam negge 180_alu v2 | 3063 | 772307 | mw_hsb_raam negge 180_alu v2 | 863574 | <None> | Schematic Type | 31 | 20160502 | buitenblad Detail | 57 | mw_hsb_raam negge 180_alu v2 | Family : Windows : NLRS_31_WI_WB_sparingmaker_generiek_BDG | Windows | NLRS_31_WI_WB_sparingmaker_generiek_BDG | General - samenstelling: NLRS_31_WI_UN_samenstelling_leeg_generiek_ISR : std; Dimensions - NLRS_C_breedte: 850 mm; NLRS_C_hoogte: 2390 mm; Layers(Type) - binnenblad_afwerking_boven: yes; binnenblad_afwerking_boven_hoek_links: 0 deg; binnenblad_afwerking_boven_hoek_rechts: 0 deg; binnenblad_afwerking_boven_plaatsing_y: 17 mm; binnenblad_afwerking_boven_type: NLRS_41_GM_WPB_multiplex-SH_generiek_ISR : 151x10 gipsvezel dagkant; binnenblad_afwerking_boven_verlenging_links: -148 mm; binnenblad_afwerking_boven_verlenging_rechts: -148 mm; binnenblad_afwerking_links: yes; binnenblad_afwerking_links_hoek_boven: 0 deg; binnenblad_afwerking_links_hoek_onder: 0 deg; binnenblad_afwerking_links_plaatsing_y: 148 mm; binnenblad_afwerking_links_type: NLRS_41_GM_WPB_multiplex-SH_generiek_ISR : 151x10 gipsvezel dagkant; binnenblad_afwerking_links_verlenging_boven: -27 mm; binnenblad_afwerking_links_verlenging_onder: -94 mm; binnenblad_afwerking_plaatsing_x: 149 mm; binnenblad_afwerking_rechts: yes; binnenblad_afwerking_rechts_hoek_boven: 0 deg; binnenblad_afwerking_rechts_hoek_onder: 0 deg; binnenblad_afwerking_rechts_plaatsing_y: 148 mm; binnenblad_afwerking_rechts_type: NLRS_41_GM_WPB_multiplex-SH_generiek_ISR : 151x10 gipsvezel dagkant; binnenblad_afwerking_rechts_verlenging_boven: -27 mm; binnenblad_afwerking_rechts_verlenging_onder: -94 mm; buitenblad_afwerking_boven: no; buitenblad_afwerking_boven_hoek_links: 0 deg; buitenblad_afwerking_boven_hoek_rechts: 0 deg; buitenblad_afwerking_boven_plaatsing_y: 0 mm; buitenblad_afwerking_boven_type: NLRS_41_GM_WPB_omgezet metselwerk-SH_generiek_ISR : std; buitenblad_afwerking_boven_verlenging_links: 0 mm; buitenblad_afwerking_boven_verlenging_rechts: 0 mm; buitenblad_afwerking_links: no; buitenblad_afwerking_links_hoek_boven: 0 deg; buitenblad_afwerking_links_hoek_onder: 0 deg; buitenblad_afwerking_links_plaatsing_y: 0 mm; buitenblad_afwerking_links_type: NLRS_41_GM_WPB_omgezet metselwerk-SH_generiek_ISR : std; buitenblad_afwerking_links_verlenging_boven: 0 mm; buitenblad_afwerking_links_verlenging_onder: 0 mm; buitenblad_afwerking_plaatsing_x: 0 mm; buitenblad_afwerking_rechts: no; buitenblad_afwerking_rechts_hoek_boven: 0 deg; buitenblad_afwerking_rechts_hoek_onder: 0 deg; buitenblad_afwerking_rechts_plaatsing_y: 0 mm; buitenblad_afwerking_rechts_type: NLRS_41_GM_WPB_omgezet metselwerk-SH_generiek_ISR : std; buitenblad_afwerking_rechts_verlenging_boven: 0 mm; buitenblad_afwerking_rechts_verlenging_onder: 0 mm; Constraints(Type) - lossing_binnenblad: 0 mm; offset_binnenblad_boven: 134 mm; offset_binnenblad_links: 131 mm; offset_binnenblad_onder: 59 mm; offset_binnenblad_rechts: 131 mm; offset_binnenbladbeplating_boven: 17 mm; offset_binnenbladbeplating_links: 148 mm; offset_binnenbladbeplating_onder: 17 mm; offset_binnenbladbeplating_rechts: 148 mm; offset_buitenblad_boven: 12 mm; offset_buitenblad_links: 107 mm; offset_buitenblad_onder: 70 mm; offset_buitenblad_rechts: 107 mm; offset_isolatie_boven: 48 mm; offset_isolatie_links: 28 mm; offset_isolatie_onder: 28 mm; offset_isolatie_rechts: 28 mm; Structural(Type) - rekje: no; rekje_plaatsing_x: 0 mm; rekje_plaatsing_y: 0 mm; rekje_type: NLRS_41_GM_WPB_rekje-SH_generiek_ISR : std; rekje_verlenging_links: 200 mm; rekje_verlenging_rechts: 200 mm; spouwlat_boven: yes; spouwlat_boven_plaatsing_y: -17 mm; spouwlat_boven_type: NLRS_41_GM_WPB_spouwlat_isolatie_gen_bdg : 187x38 + isolatie 113x200; spouwlat_boven_verlenging_links: 21 mm; spouwlat_boven_verlenging_rechts: 21 mm; spouwlat_links: yes; spouwlat_links_plaatsing_y: -17 mm; spouwlat_links_type: NLRS_41_GM_WPB_spouwlat_isolatie_gen_bdg : 187x38 + isolatie 110x180; spouwlat_links_verlenging_boven: -17 mm; spouwlat_links_verlenging_onder: -17 mm; spouwlat_onder: yes; spouwlat_onder_plaatsing_y: -17 mm; spouwlat_onder_type: NLRS_41_GM_WPB_spouwlat-SH_generiek_ISR : 185x76; spouwlat_onder_verlenging_links: 21 mm; spouwlat_onder_verlenging_rechts: 21 mm; spouwlat_plaatsing_x: -275 mm; spouwlat_rechts: yes; spouwlat_rechts_plaatsing_y: -17 mm; spouwlat_rechts_type: NLRS_41_GM_WPB_spouwlat_isolatie_gen_bdg : 187x38 + isolatie 110x180; spouwlat_rechts_verlenging_boven: -17 mm; spouwlat_rechts_verlenging_onder: -17 mm; Materials and Finishes(Type) - geveldrager: yes; geveldrager_hoek_a: 0 deg; geveldrager_hoek_b: 0 deg; geveldrager_plaatsing_x: -10 mm; geveldrager_plaatsing_y: 8 mm; geveldrager_type: NLRS_41_SF_LIB_latei_staal_generiek_ISR : 90x150; geveldrager_verlenging_a: 0 mm; geveldrager_verlenging_b: 0 mm; latei: no; latei_hoek_a: 0 deg; latei_hoek_b: 0 deg; latei_plaatsing_x: 0 mm; latei_plaatsing_y: 0 mm; latei_type: NLRS_41_SF_LIB_latei_beton_generiek_ISR : 150x100; latei_verlenging_a: 100 mm; latei_verlenging_b: 100 mm; vensterbank: yes; vensterbank_hoek_a: 0 deg; vensterbank_hoek_b: 0 deg; vensterbank_plaatsing_x: 149 mm; vensterbank_plaatsing_y: 17 mm; vensterbank_type: NLRS_42_GM_WPB_vensterbank_natuursteen-SH_generiek_ISR : 180x18 vensterbank composiet; vensterbank_verlenging_a: -148 mm; vensterbank_verlenging_b: -148 mm; waterslag: yes; waterslag_hoek_a: 0 deg; waterslag_hoek_b: 0 deg; waterslag_plaatsing_x: -25 mm; waterslag_plaatsing_y: 90 mm; waterslag_type: NLRS_41_GM_WPB_waterslag barok-SH_roval_ISR : waterslag_roval_Types Barok_roval_b 270; waterslag_verlenging_a: -100 mm; waterslag_verlenging_b: -100 mm; Graphics(Type) - doorval_hoek_links: 0 deg; doorval_hoek_rechts: 0 deg; doorval_plaatsing_x: 30 mm; doorval_plaatsing_y: 300 mm; doorval_type: NLRS_41_GM_WPB_doorvalbeveiliging-SH_generiek_ISR : std; doorval_verlenging_links: 0 mm; doorval_verlenging_rechts: 0 mm; doorvalbeveiliging: no; ventilatie: no; ventilatie_plaatsing_x: 114 mm; ventilatie_plaatsing_y: 0 mm; ventilatie_type: NLRS_41_GM_WPB_ventilatie-SH_topstream_ISR : std; ventilatie_verlenging_links: 0 mm; ventilatie_verlenging_rechts: 0 mm; Construction(Type) - binnenblad_beplating: 200 mm; binnenblad_hout: 275 mm; buitenblad: 100 mm; isolatie: 10 mm; luchtspouw: 30 mm; negge: 215 mm; Dimensions(Type) - binnenbladhost: yes; buitenbladhost: no; clashobject: no; wrapping_exterior: 0 mm; wrapping_interior: 0 mm; Identity Data(Type) - Assembly Description: buitenwandopeningen; Other(Type) - a_binnen_boven_1: 134 mm; a_binnen_boven_2: 134 mm; a_binnen_links_1: 131 mm; a_binnen_links_2: 131 mm; a_binnen_onder_1: 59 mm; a_binnen_onder_2: 59 mm; a_binnen_rechts_1: 131 mm; a_binnen_rechts_2: 131 mm; a_binnenbepl_boven_1: 17 mm; a_binnenbepl_links_1: 148 mm; a_binnenbepl_onder_1: 17 mm; a_binnenbepl_rechts_1: 148 mm; a_binnenwand_afwerking_boven_y: 17 mm; a_binnenwand_afwerking_links_y: 148 mm; a_binnenwand_afwerking_rechts_y: 148 mm; a_binnenwand_afwerking_x: 149 mm; a_buitenblad_boven: 12 mm; a_buitenblad_boven_y: 0 mm; a_buitenblad_links: 107 mm; a_buitenblad_links_y: 0 mm; a_buitenblad_onder: 70 mm; a_buitenblad_rechts: 107 mm; a_buitenblad_rechts_y: 0 mm; a_buitenblad_x: 0 mm; a_doorval_x: 30 mm; a_doorval_y: 300 mm; a_geveldrager_x: 10 mm; a_geveldrager_y: 8 mm; a_isolatie_boven: 48 mm; a_isolatie_links: 28 mm; a_isolatie_onder: 28 mm; a_isolatie_rechts: 28 mm; a_latei_x: 0 mm; a_latei_y: 0 mm; a_rekje_x: 0 mm; a_rekje_y: 0 mm; a_spouwlat_boven_y: 17 mm; a_spouwlat_links_y: 17 mm; a_spouwlat_onder_y: 17 mm; a_spouwlat_rechts_y: 17 mm; a_spouwlat_x: 275 mm; a_vensterbank_x: 149 mm; a_vensterbank_y: 17 mm; a_ventilatie_x: 114 mm; a_ventilatie_y: 0 mm; a_waterslag_x: 25 mm; a_waterslag_y: 90 mm; b_binnen_boven_1: 268 mm; b_binnen_boven_2: 268 mm; b_binnen_links_1: 262 mm; b_binnen_links_2: 262 mm; b_binnen_onder_1: 118 mm; b_binnen_onder_2: 118 mm; b_binnen_rechts_1: 262 mm; b_binnen_rechts_2: 262 mm; b_binnenwand_afwerking_boven_y: 34 mm; b_binnenwand_afwerking_links_y: 296 mm; b_binnenwand_afwerking_rechts_y: 296 mm; b_binnenwand_afwerking_x: 298 mm; b_buitenblad_boven: 24 mm; b_buitenblad_boven_y: 0 mm; b_buitenblad_links: 214 mm; b_buitenblad_links_y: 0 mm; b_buitenblad_onder: 140 mm; b_buitenblad_rechts: 214 mm; b_buitenblad_rechts_y: 0 mm; b_buitenblad_x: 0 mm; b_doorval_x: 60 mm; b_doorval_y: 600 mm; b_geveldrager_x: 0 mm; b_geveldrager_y: 16 mm; b_isolatie_boven: 96 mm; b_isolatie_links: 56 mm; b_isolatie_onder: 56 mm; b_isolatie_rechts: 56 mm; b_latei_x: 0 mm; b_latei_y: 0 mm; b_rekje_x: 0 mm; b_rekje_y: 0 mm; b_spouwlat_boven_y: 0 mm; b_spouwlat_links_y: 0 mm; b_spouwlat_onder_y: 0 mm; b_spouwlat_rechts_y: 0 mm; b_spouwlat_x: 0 mm; b_vensterbank_x: 298 mm; b_vensterbank_y: 34 mm; b_ventilatie_x: 228 mm; b_ventilatie_y: 0 mm; b_waterslag_x: 0 mm; b_waterslag_y: 180 mm; berekende_binnen-buiten_host: 140 mm; offset_binnenblad_boven_2: 134 mm; offset_binnenblad_links_2: 131 mm; offset_binnenblad_onder_2: 59 mm; offset_binnenblad_rechts_2: 131 mm
Basic Wall:21_WA_metselwerk_licht_100_gen_bdg:2351650 | 02 tweede verdieping | 2D(21.11.11) Uniformat (Uniformat) | 02 tweede verdieping | 673 | 2. nieuwbouw | 3.88842 | 2390 | 850 | Workset1 | 66 | Windows | NLRS_31_WI_WB_sparingmaker_generiek_BDG | NLRS_31_WI_WB_sparingmaker_generiek_BDG: mw_hsb_raam negge 180_alu v2 | 3063 | 772307 | mw_hsb_raam negge 180_alu v2 | 863574 | <None> | Schematic Type | 31 | 20160502 | buitenblad Detail | 57 | mw_hsb_raam negge 180_alu v2 | Family : Windows : NLRS_31_WI_WB_sparingmaker_generiek_BDG | Windows | NLRS_31_WI_WB_sparingmaker_generiek_BDG | General - samenstelling: NLRS_31_WI_UN_samenstelling_leeg_generiek_ISR : std; Dimensions - NLRS_C_breedte: 850 mm; NLRS_C_hoogte: 2390 mm; Layers(Type) - binnenblad_afwerking_boven: yes; binnenblad_afwerking_boven_hoek_links: 0 deg; binnenblad_afwerking_boven_hoek_rechts: 0 deg; binnenblad_afwerking_boven_plaatsing_y: 17 mm; binnenblad_afwerking_boven_type: NLRS_41_GM_WPB_multiplex-SH_generiek_ISR : 151x10 gipsvezel dagkant; binnenblad_afwerking_boven_verlenging_links: -148 mm; binnenblad_afwerking_boven_verlenging_rechts: -148 mm; binnenblad_afwerking_links: yes; binnenblad_afwerking_links_hoek_boven: 0 deg; binnenblad_afwerking_links_hoek_onder: 0 deg; binnenblad_afwerking_links_plaatsing_y: 148 mm; binnenblad_afwerking_links_type: NLRS_41_GM_WPB_multiplex-SH_generiek_ISR : 151x10 gipsvezel dagkant; binnenblad_afwerking_links_verlenging_boven: -27 mm; binnenblad_afwerking_links_verlenging_onder: -94 mm; binnenblad_afwerking_plaatsing_x: 149 mm; binnenblad_afwerking_rechts: yes; binnenblad_afwerking_rechts_hoek_boven: 0 deg; binnenblad_afwerking_rechts_hoek_onder: 0 deg; binnenblad_afwerking_rechts_plaatsing_y: 148 mm; binnenblad_afwerking_rechts_type: NLRS_41_GM_WPB_multiplex-SH_generiek_ISR : 151x10 gipsvezel dagkant; binnenblad_afwerking_rechts_verlenging_boven: -27 mm; binnenblad_afwerking_rechts_verlenging_onder: -94 mm; buitenblad_afwerking_boven: no; buitenblad_afwerking_boven_hoek_links: 0 deg; buitenblad_afwerking_boven_hoek_rechts: 0 deg; buitenblad_afwerking_boven_plaatsing_y: 0 mm; buitenblad_afwerking_boven_type: NLRS_41_GM_WPB_omgezet metselwerk-SH_generiek_ISR : std; buitenblad_afwerking_boven_verlenging_links: 0 mm; buitenblad_afwerking_boven_verlenging_rechts: 0 mm; buitenblad_afwerking_links: no; buitenblad_afwerking_links_hoek_boven: 0 deg; buitenblad_afwerking_links_hoek_onder: 0 deg; buitenblad_afwerking_links_plaatsing_y: 0 mm; buitenblad_afwerking_links_type: NLRS_41_GM_WPB_omgezet metselwerk-SH_generiek_ISR : std; buitenblad_afwerking_links_verlenging_boven: 0 mm; buitenblad_afwerking_links_verlenging_onder: 0 mm; buitenblad_afwerking_plaatsing_x: 0 mm; buitenblad_afwerking_rechts: no; buitenblad_afwerking_rechts_hoek_boven: 0 deg; buitenblad_afwerking_rechts_hoek_onder: 0 deg; buitenblad_afwerking_rechts_plaatsing_y: 0 mm; buitenblad_afwerking_rechts_type: NLRS_41_GM_WPB_omgezet metselwerk-SH_generiek_ISR : std; buitenblad_afwerking_rechts_verlenging_boven: 0 mm; buitenblad_afwerking_rechts_verlenging_onder: 0 mm; Constraints(Type) - lossing_binnenblad: 0 mm; offset_binnenblad_boven: 134 mm; offset_binnenblad_links: 131 mm; offset_binnenblad_onder: 59 mm; offset_binnenblad_rechts: 131 mm; offset_binnenbladbeplating_boven: 17 mm; offset_binnenbladbeplating_links: 148 mm; offset_binnenbladbeplating_onder: 17 mm; offset_binnenbladbeplating_rechts: 148 mm; offset_buitenblad_boven: 12 mm; offset_buitenblad_links: 107 mm; offset_buitenblad_onder: 70 mm; offset_buitenblad_rechts: 107 mm; offset_isolatie_boven: 48 mm; offset_isolatie_links: 28 mm; offset_isolatie_onder: 28 mm; offset_isolatie_rechts: 28 mm; Structural(Type) - rekje: no; rekje_plaatsing_x: 0 mm; rekje_plaatsing_y: 0 mm; rekje_type: NLRS_41_GM_WPB_rekje-SH_generiek_ISR : std; rekje_verlenging_links: 200 mm; rekje_verlenging_rechts: 200 mm; spouwlat_boven: yes; spouwlat_boven_plaatsing_y: -17 mm; spouwlat_boven_type: NLRS_41_GM_WPB_spouwlat_isolatie_gen_bdg : 187x38 + isolatie 113x200; spouwlat_boven_verlenging_links: 21 mm; spouwlat_boven_verlenging_rechts: 21 mm; spouwlat_links: yes; spouwlat_links_plaatsing_y: -17 mm; spouwlat_links_type: NLRS_41_GM_WPB_spouwlat_isolatie_gen_bdg : 187x38 + isolatie 110x180; spouwlat_links_verlenging_boven: -17 mm; spouwlat_links_verlenging_onder: -17 mm; spouwlat_onder: yes; spouwlat_onder_plaatsing_y: -17 mm; spouwlat_onder_type: NLRS_41_GM_WPB_spouwlat-SH_generiek_ISR : 185x76; spouwlat_onder_verlenging_links: 21 mm; spouwlat_onder_verlenging_rechts: 21 mm; spouwlat_plaatsing_x: -275 mm; spouwlat_rechts: yes; spouwlat_rechts_plaatsing_y: -17 mm; spouwlat_rechts_type: NLRS_41_GM_WPB_spouwlat_isolatie_gen_bdg : 187x38 + isolatie 110x180; spouwlat_rechts_verlenging_boven: -17 mm; spouwlat_rechts_verlenging_onder: -17 mm; Materials and Finishes(Type) - geveldrager: yes; geveldrager_hoek_a: 0 deg; geveldrager_hoek_b: 0 deg; geveldrager_plaatsing_x: -10 mm; geveldrager_plaatsing_y: 8 mm; geveldrager_type: NLRS_41_SF_LIB_latei_staal_generiek_ISR : 90x150; geveldrager_verlenging_a: 0 mm; geveldrager_verlenging_b: 0 mm; latei: no; latei_hoek_a: 0 deg; latei_hoek_b: 0 deg; latei_plaatsing_x: 0 mm; latei_plaatsing_y: 0 mm; latei_type: NLRS_41_SF_LIB_latei_beton_generiek_ISR : 150x100; latei_verlenging_a: 100 mm; latei_verlenging_b: 100 mm; vensterbank: yes; vensterbank_hoek_a: 0 deg; vensterbank_hoek_b: 0 deg; vensterbank_plaatsing_x: 149 mm; vensterbank_plaatsing_y: 17 mm; vensterbank_type: NLRS_42_GM_WPB_vensterbank_natuursteen-SH_generiek_ISR : 180x18 vensterbank composiet; vensterbank_verlenging_a: -148 mm; vensterbank_verlenging_b: -148 mm; waterslag: yes; waterslag_hoek_a: 0 deg; waterslag_hoek_b: 0 deg; waterslag_plaatsing_x: -25 mm; waterslag_plaatsing_y: 90 mm; waterslag_type: NLRS_41_GM_WPB_waterslag barok-SH_roval_ISR : waterslag_roval_Types Barok_roval_b 270; waterslag_verlenging_a: -100 mm; waterslag_verlenging_b: -100 mm; Graphics(Type) - doorval_hoek_links: 0 deg; doorval_hoek_rechts: 0 deg; doorval_plaatsing_x: 30 mm; doorval_plaatsing_y: 300 mm; doorval_type: NLRS_41_GM_WPB_doorvalbeveiliging-SH_generiek_ISR : std; doorval_verlenging_links: 0 mm; doorval_verlenging_rechts: 0 mm; doorvalbeveiliging: no; ventilatie: no; ventilatie_plaatsing_x: 114 mm; ventilatie_plaatsing_y: 0 mm; ventilatie_type: NLRS_41_GM_WPB_ventilatie-SH_topstream_ISR : std; ventilatie_verlenging_links: 0 mm; ventilatie_verlenging_rechts: 0 mm; Construction(Type) - binnenblad_beplating: 200 mm; binnenblad_hout: 275 mm; buitenblad: 100 mm; isolatie: 10 mm; luchtspouw: 30 mm; negge: 215 mm; Dimensions(Type) - binnenbladhost: yes; buitenbladhost: no; clashobject: no; wrapping_exterior: 0 mm; wrapping_interior: 0 mm; Identity Data(Type) - Assembly Description: buitenwandopeningen; Other(Type) - a_binnen_boven_1: 134 mm; a_binnen_boven_2: 134 mm; a_binnen_links_1: 131 mm; a_binnen_links_2: 131 mm; a_binnen_onder_1: 59 mm; a_binnen_onder_2: 59 mm; a_binnen_rechts_1: 131 mm; a_binnen_rechts_2: 131 mm; a_binnenbepl_boven_1: 17 mm; a_binnenbepl_links_1: 148 mm; a_binnenbepl_onder_1: 17 mm; a_binnenbepl_rechts_1: 148 mm; a_binnenwand_afwerking_boven_y: 17 mm; a_binnenwand_afwerking_links_y: 148 mm; a_binnenwand_afwerking_rechts_y: 148 mm; a_binnenwand_afwerking_x: 149 mm; a_buitenblad_boven: 12 mm; a_buitenblad_boven_y: 0 mm; a_buitenblad_links: 107 mm; a_buitenblad_links_y: 0 mm; a_buitenblad_onder: 70 mm; a_buitenblad_rechts: 107 mm; a_buitenblad_rechts_y: 0 mm; a_buitenblad_x: 0 mm; a_doorval_x: 30 mm; a_doorval_y: 300 mm; a_geveldrager_x: 10 mm; a_geveldrager_y: 8 mm; a_isolatie_boven: 48 mm; a_isolatie_links: 28 mm; a_isolatie_onder: 28 mm; a_isolatie_rechts: 28 mm; a_latei_x: 0 mm; a_latei_y: 0 mm; a_rekje_x: 0 mm; a_rekje_y: 0 mm; a_spouwlat_boven_y: 17 mm; a_spouwlat_links_y: 17 mm; a_spouwlat_onder_y: 17 mm; a_spouwlat_rechts_y: 17 mm; a_spouwlat_x: 275 mm; a_vensterbank_x: 149 mm; a_vensterbank_y: 17 mm; a_ventilatie_x: 114 mm; a_ventilatie_y: 0 mm; a_waterslag_x: 25 mm; a_waterslag_y: 90 mm; b_binnen_boven_1: 268 mm; b_binnen_boven_2: 268 mm; b_binnen_links_1: 262 mm; b_binnen_links_2: 262 mm; b_binnen_onder_1: 118 mm; b_binnen_onder_2: 118 mm; b_binnen_rechts_1: 262 mm; b_binnen_rechts_2: 262 mm; b_binnenwand_afwerking_boven_y: 34 mm; b_binnenwand_afwerking_links_y: 296 mm; b_binnenwand_afwerking_rechts_y: 296 mm; b_binnenwand_afwerking_x: 298 mm; b_buitenblad_boven: 24 mm; b_buitenblad_boven_y: 0 mm; b_buitenblad_links: 214 mm; b_buitenblad_links_y: 0 mm; b_buitenblad_onder: 140 mm; b_buitenblad_rechts: 214 mm; b_buitenblad_rechts_y: 0 mm; b_buitenblad_x: 0 mm; b_doorval_x: 60 mm; b_doorval_y: 600 mm; b_geveldrager_x: 0 mm; b_geveldrager_y: 16 mm; b_isolatie_boven: 96 mm; b_isolatie_links: 56 mm; b_isolatie_onder: 56 mm; b_isolatie_rechts: 56 mm; b_latei_x: 0 mm; b_latei_y: 0 mm; b_rekje_x: 0 mm; b_rekje_y: 0 mm; b_spouwlat_boven_y: 0 mm; b_spouwlat_links_y: 0 mm; b_spouwlat_onder_y: 0 mm; b_spouwlat_rechts_y: 0 mm; b_spouwlat_x: 0 mm; b_vensterbank_x: 298 mm; b_vensterbank_y: 34 mm; b_ventilatie_x: 228 mm; b_ventilatie_y: 0 mm; b_waterslag_x: 0 mm; b_waterslag_y: 180 mm; berekende_binnen-buiten_host: 140 mm; offset_binnenblad_boven_2: 134 mm; offset_binnenblad_links_2: 131 mm; offset_binnenblad_onder_2: 59 mm; offset_binnenblad_rechts_2: 131 mm
Basic Wall:21_WA_metselwerk_licht_100_gen_bdg:2351650 | 02 tweede verdieping | 2D(21.11.11) Uniformat (Uniformat) | 02 tweede verdieping | 673 | 2. nieuwbouw | 3.88842 | 2390 | 850 | Workset1 | 68 | Windows | NLRS_31_WI_WB_sparingmaker_generiek_BDG | NLRS_31_WI_WB_sparingmaker_generiek_BDG: mw_hsb_raam negge 180_alu v2 | 3063 | 772307 | mw_hsb_raam negge 180_alu v2 | 863574 | <None> | Schematic Type | 31 | 20160502 | buitenblad Detail | 57 | mw_hsb_raam negge 180_alu v2 | Family : Windows : NLRS_31_WI_WB_sparingmaker_generiek_BDG | Windows | NLRS_31_WI_WB_sparingmaker_generiek_BDG | General - samenstelling: NLRS_31_WI_UN_samenstelling_leeg_generiek_ISR : std; Dimensions - NLRS_C_breedte: 850 mm; NLRS_C_hoogte: 2390 mm; Layers(Type) - binnenblad_afwerking_boven: yes; binnenblad_afwerking_boven_hoek_links: 0 deg; binnenblad_afwerking_boven_hoek_rechts: 0 deg; binnenblad_afwerking_boven_plaatsing_y: 17 mm; binnenblad_afwerking_boven_type: NLRS_41_GM_WPB_multiplex-SH_generiek_ISR : 151x10 gipsvezel dagkant; binnenblad_afwerking_boven_verlenging_links: -148 mm; binnenblad_afwerking_boven_verlenging_rechts: -148 mm; binnenblad_afwerking_links: yes; binnenblad_afwerking_links_hoek_boven: 0 deg; binnenblad_afwerking_links_hoek_onder: 0 deg; binnenblad_afwerking_links_plaatsing_y: 148 mm; binnenblad_afwerking_links_type: NLRS_41_GM_WPB_multiplex-SH_generiek_ISR : 151x10 gipsvezel dagkant; binnenblad_afwerking_links_verlenging_boven: -27 mm; binnenblad_afwerking_links_verlenging_onder: -94 mm; binnenblad_afwerking_plaatsing_x: 149 mm; binnenblad_afwerking_rechts: yes; binnenblad_afwerking_rechts_hoek_boven: 0 deg; binnenblad_afwerking_rechts_hoek_onder: 0 deg; binnenblad_afwerking_rechts_plaatsing_y: 148 mm; binnenblad_afwerking_rechts_type: NLRS_41_GM_WPB_multiplex-SH_generiek_ISR : 151x10 gipsvezel dagkant; binnenblad_afwerking_rechts_verlenging_boven: -27 mm; binnenblad_afwerking_rechts_verlenging_onder: -94 mm; buitenblad_afwerking_boven: no; buitenblad_afwerking_boven_hoek_links: 0 deg; buitenblad_afwerking_boven_hoek_rechts: 0 deg; buitenblad_afwerking_boven_plaatsing_y: 0 mm; buitenblad_afwerking_boven_type: NLRS_41_GM_WPB_omgezet metselwerk-SH_generiek_ISR : std; buitenblad_afwerking_boven_verlenging_links: 0 mm; buitenblad_afwerking_boven_verlenging_rechts: 0 mm; buitenblad_afwerking_links: no; buitenblad_afwerking_links_hoek_boven: 0 deg; buitenblad_afwerking_links_hoek_onder: 0 deg; buitenblad_afwerking_links_plaatsing_y: 0 mm; buitenblad_afwerking_links_type: NLRS_41_GM_WPB_omgezet metselwerk-SH_generiek_ISR : std; buitenblad_afwerking_links_verlenging_boven: 0 mm; buitenblad_afwerking_links_verlenging_onder: 0 mm; buitenblad_afwerking_plaatsing_x: 0 mm; buitenblad_afwerking_rechts: no; buitenblad_afwerking_rechts_hoek_boven: 0 deg; buitenblad_afwerking_rechts_hoek_onder: 0 deg; buitenblad_afwerking_rechts_plaatsing_y: 0 mm; buitenblad_afwerking_rechts_type: NLRS_41_GM_WPB_omgezet metselwerk-SH_generiek_ISR : std; buitenblad_afwerking_rechts_verlenging_boven: 0 mm; buitenblad_afwerking_rechts_verlenging_onder: 0 mm; Constraints(Type) - lossing_binnenblad: 0 mm; offset_binnenblad_boven: 134 mm; offset_binnenblad_links: 131 mm; offset_binnenblad_onder: 59 mm; offset_binnenblad_rechts: 131 mm; offset_binnenbladbeplating_boven: 17 mm; offset_binnenbladbeplating_links: 148 mm; offset_binnenbladbeplating_onder: 17 mm; offset_binnenbladbeplating_rechts: 148 mm; offset_buitenblad_boven: 12 mm; offset_buitenblad_links: 107 mm; offset_buitenblad_onder: 70 mm; offset_buitenblad_rechts: 107 mm; offset_isolatie_boven: 48 mm; offset_isolatie_links: 28 mm; offset_isolatie_onder: 28 mm; offset_isolatie_rechts: 28 mm; Structural(Type) - rekje: no; rekje_plaatsing_x: 0 mm; rekje_plaatsing_y: 0 mm; rekje_type: NLRS_41_GM_WPB_rekje-SH_generiek_ISR : std; rekje_verlenging_links: 200 mm; rekje_verlenging_rechts: 200 mm; spouwlat_boven: yes; spouwlat_boven_plaatsing_y: -17 mm; spouwlat_boven_type: NLRS_41_GM_WPB_spouwlat_isolatie_gen_bdg : 187x38 + isolatie 113x200; spouwlat_boven_verlenging_links: 21 mm; spouwlat_boven_verlenging_rechts: 21 mm; spouwlat_links: yes; spouwlat_links_plaatsing_y: -17 mm; spouwlat_links_type: NLRS_41_GM_WPB_spouwlat_isolatie_gen_bdg : 187x38 + isolatie 110x180; spouwlat_links_verlenging_boven: -17 mm; spouwlat_links_verlenging_onder: -17 mm; spouwlat_onder: yes; spouwlat_onder_plaatsing_y: -17 mm; spouwlat_onder_type: NLRS_41_GM_WPB_spouwlat-SH_generiek_ISR : 185x76; spouwlat_onder_verlenging_links: 21 mm; spouwlat_onder_verlenging_rechts: 21 mm; spouwlat_plaatsing_x: -275 mm; spouwlat_rechts: yes; spouwlat_rechts_plaatsing_y: -17 mm; spouwlat_rechts_type: NLRS_41_GM_WPB_spouwlat_isolatie_gen_bdg : 187x38 + isolatie 110x180; spouwlat_rechts_verlenging_boven: -17 mm; spouwlat_rechts_verlenging_onder: -17 mm; Materials and Finishes(Type) - geveldrager: yes; geveldrager_hoek_a: 0 deg; geveldrager_hoek_b: 0 deg; geveldrager_plaatsing_x: -10 mm; geveldrager_plaatsing_y: 8 mm; geveldrager_type: NLRS_41_SF_LIB_latei_staal_generiek_ISR : 90x150; geveldrager_verlenging_a: 0 mm; geveldrager_verlenging_b: 0 mm; latei: no; latei_hoek_a: 0 deg; latei_hoek_b: 0 deg; latei_plaatsing_x: 0 mm; latei_plaatsing_y: 0 mm; latei_type: NLRS_41_SF_LIB_latei_beton_generiek_ISR : 150x100; latei_verlenging_a: 100 mm; latei_verlenging_b: 100 mm; vensterbank: yes; vensterbank_hoek_a: 0 deg; vensterbank_hoek_b: 0 deg; vensterbank_plaatsing_x: 149 mm; vensterbank_plaatsing_y: 17 mm; vensterbank_type: NLRS_42_GM_WPB_vensterbank_natuursteen-SH_generiek_ISR : 180x18 vensterbank composiet; vensterbank_verlenging_a: -148 mm; vensterbank_verlenging_b: -148 mm; waterslag: yes; waterslag_hoek_a: 0 deg; waterslag_hoek_b: 0 deg; waterslag_plaatsing_x: -25 mm; waterslag_plaatsing_y: 90 mm; waterslag_type: NLRS_41_GM_WPB_waterslag barok-SH_roval_ISR : waterslag_roval_Types Barok_roval_b 270; waterslag_verlenging_a: -100 mm; waterslag_verlenging_b: -100 mm; Graphics(Type) - doorval_hoek_links: 0 deg; doorval_hoek_rechts: 0 deg; doorval_plaatsing_x: 30 mm; doorval_plaatsing_y: 300 mm; doorval_type: NLRS_41_GM_WPB_doorvalbeveiliging-SH_generiek_ISR : std; doorval_verlenging_links: 0 mm; doorval_verlenging_rechts: 0 mm; doorvalbeveiliging: no; ventilatie: no; ventilatie_plaatsing_x: 114 mm; ventilatie_plaatsing_y: 0 mm; ventilatie_type: NLRS_41_GM_WPB_ventilatie-SH_topstream_ISR : std; ventilatie_verlenging_links: 0 mm; ventilatie_verlenging_rechts: 0 mm; Construction(Type) - binnenblad_beplating: 200 mm; binnenblad_hout: 275 mm; buitenblad: 100 mm; isolatie: 10 mm; luchtspouw: 30 mm; negge: 215 mm; Dimensions(Type) - binnenbladhost: yes; buitenbladhost: no; clashobject: no; wrapping_exterior: 0 mm; wrapping_interior: 0 mm; Identity Data(Type) - Assembly Description: buitenwandopeningen; Other(Type) - a_binnen_boven_1: 134 mm; a_binnen_boven_2: 134 mm; a_binnen_links_1: 131 mm; a_binnen_links_2: 131 mm; a_binnen_onder_1: 59 mm; a_binnen_onder_2: 59 mm; a_binnen_rechts_1: 131 mm; a_binnen_rechts_2: 131 mm; a_binnenbepl_boven_1: 17 mm; a_binnenbepl_links_1: 148 mm; a_binnenbepl_onder_1: 17 mm; a_binnenbepl_rechts_1: 148 mm; a_binnenwand_afwerking_boven_y: 17 mm; a_binnenwand_afwerking_links_y: 148 mm; a_binnenwand_afwerking_rechts_y: 148 mm; a_binnenwand_afwerking_x: 149 mm; a_buitenblad_boven: 12 mm; a_buitenblad_boven_y: 0 mm; a_buitenblad_links: 107 mm; a_buitenblad_links_y: 0 mm; a_buitenblad_onder: 70 mm; a_buitenblad_rechts: 107 mm; a_buitenblad_rechts_y: 0 mm; a_buitenblad_x: 0 mm; a_doorval_x: 30 mm; a_doorval_y: 300 mm; a_geveldrager_x: 10 mm; a_geveldrager_y: 8 mm; a_isolatie_boven: 48 mm; a_isolatie_links: 28 mm; a_isolatie_onder: 28 mm; a_isolatie_rechts: 28 mm; a_latei_x: 0 mm; a_latei_y: 0 mm; a_rekje_x: 0 mm; a_rekje_y: 0 mm; a_spouwlat_boven_y: 17 mm; a_spouwlat_links_y: 17 mm; a_spouwlat_onder_y: 17 mm; a_spouwlat_rechts_y: 17 mm; a_spouwlat_x: 275 mm; a_vensterbank_x: 149 mm; a_vensterbank_y: 17 mm; a_ventilatie_x: 114 mm; a_ventilatie_y: 0 mm; a_waterslag_x: 25 mm; a_waterslag_y: 90 mm; b_binnen_boven_1: 268 mm; b_binnen_boven_2: 268 mm; b_binnen_links_1: 262 mm; b_binnen_links_2: 262 mm; b_binnen_onder_1: 118 mm; b_binnen_onder_2: 118 mm; b_binnen_rechts_1: 262 mm; b_binnen_rechts_2: 262 mm; b_binnenwand_afwerking_boven_y: 34 mm; b_binnenwand_afwerking_links_y: 296 mm; b_binnenwand_afwerking_rechts_y: 296 mm; b_binnenwand_afwerking_x: 298 mm; b_buitenblad_boven: 24 mm; b_buitenblad_boven_y: 0 mm; b_buitenblad_links: 214 mm; b_buitenblad_links_y: 0 mm; b_buitenblad_onder: 140 mm; b_buitenblad_rechts: 214 mm; b_buitenblad_rechts_y: 0 mm; b_buitenblad_x: 0 mm; b_doorval_x: 60 mm; b_doorval_y: 600 mm; b_geveldrager_x: 0 mm; b_geveldrager_y: 16 mm; b_isolatie_boven: 96 mm; b_isolatie_links: 56 mm; b_isolatie_onder: 56 mm; b_isolatie_rechts: 56 mm; b_latei_x: 0 mm; b_latei_y: 0 mm; b_rekje_x: 0 mm; b_rekje_y: 0 mm; b_spouwlat_boven_y: 0 mm; b_spouwlat_links_y: 0 mm; b_spouwlat_onder_y: 0 mm; b_spouwlat_rechts_y: 0 mm; b_spouwlat_x: 0 mm; b_vensterbank_x: 298 mm; b_vensterbank_y: 34 mm; b_ventilatie_x: 228 mm; b_ventilatie_y: 0 mm; b_waterslag_x: 0 mm; b_waterslag_y: 180 mm; berekende_binnen-buiten_host: 140 mm; offset_binnenblad_boven_2: 134 mm; offset_binnenblad_links_2: 131 mm; offset_binnenblad_onder_2: 59 mm; offset_binnenblad_rechts_2: 131 mm
Basic Wall:21_WA_metselwerk_licht_100_gen_bdg:2351650 | 02 tweede verdieping | 2D(21.11.11) Uniformat (Uniformat) | 02 tweede verdieping | 673 | 2. nieuwbouw | 3.88842 | 2390 | 850 | Workset1 | 74 | Windows | NLRS_31_WI_WB_sparingmaker_generiek_BDG | NLRS_31_WI_WB_sparingmaker_generiek_BDG: mw_hsb_raam negge 180_alu v2 | 3063 | 772307 | mw_hsb_raam negge 180_alu v2 | 863574 | <None> | Schematic Type | 31 | 20160502 | buitenblad Detail | 57 | mw_hsb_raam negge 180_alu v2 | Family : Windows : NLRS_31_WI_WB_sparingmaker_generiek_BDG | Windows | NLRS_31_WI_WB_sparingmaker_generiek_BDG | General - samenstelling: NLRS_31_WI_UN_samenstelling_leeg_generiek_ISR : std; Dimensions - NLRS_C_breedte: 850 mm; NLRS_C_hoogte: 2390 mm; Layers(Type) - binnenblad_afwerking_boven: yes; binnenblad_afwerking_boven_hoek_links: 0 deg; binnenblad_afwerking_boven_hoek_rechts: 0 deg; binnenblad_afwerking_boven_plaatsing_y: 17 mm; binnenblad_afwerking_boven_type: NLRS_41_GM_WPB_multiplex-SH_generiek_ISR : 151x10 gipsvezel dagkant; binnenblad_afwerking_boven_verlenging_links: -148 mm; binnenblad_afwerking_boven_verlenging_rechts: -148 mm; binnenblad_afwerking_links: yes; binnenblad_afwerking_links_hoek_boven: 0 deg; binnenblad_afwerking_links_hoek_onder: 0 deg; binnenblad_afwerking_links_plaatsing_y: 148 mm; binnenblad_afwerking_links_type: NLRS_41_GM_WPB_multiplex-SH_generiek_ISR : 151x10 gipsvezel dagkant; binnenblad_afwerking_links_verlenging_boven: -27 mm; binnenblad_afwerking_links_verlenging_onder: -94 mm; binnenblad_afwerking_plaatsing_x: 149 mm; binnenblad_afwerking_rechts: yes; binnenblad_afwerking_rechts_hoek_boven: 0 deg; binnenblad_afwerking_rechts_hoek_onder: 0 deg; binnenblad_afwerking_rechts_plaatsing_y: 148 mm; binnenblad_afwerking_rechts_type: NLRS_41_GM_WPB_multiplex-SH_generiek_ISR : 151x10 gipsvezel dagkant; binnenblad_afwerking_rechts_verlenging_boven: -27 mm; binnenblad_afwerking_rechts_verlenging_onder: -94 mm; buitenblad_afwerking_boven: no; buitenblad_afwerking_boven_hoek_links: 0 deg; buitenblad_afwerking_boven_hoek_rechts: 0 deg; buitenblad_afwerking_boven_plaatsing_y: 0 mm; buitenblad_afwerking_boven_type: NLRS_41_GM_WPB_omgezet metselwerk-SH_generiek_ISR : std; buitenblad_afwerking_boven_verlenging_links: 0 mm; buitenblad_afwerking_boven_verlenging_rechts: 0 mm; buitenblad_afwerking_links: no; buitenblad_afwerking_links_hoek_boven: 0 deg; buitenblad_afwerking_links_hoek_onder: 0 deg; buitenblad_afwerking_links_plaatsing_y: 0 mm; buitenblad_afwerking_links_type: NLRS_41_GM_WPB_omgezet metselwerk-SH_generiek_ISR : std; buitenblad_afwerking_links_verlenging_boven: 0 mm; buitenblad_afwerking_links_verlenging_onder: 0 mm; buitenblad_afwerking_plaatsing_x: 0 mm; buitenblad_afwerking_rechts: no; buitenblad_afwerking_rechts_hoek_boven: 0 deg; buitenblad_afwerking_rechts_hoek_onder: 0 deg; buitenblad_afwerking_rechts_plaatsing_y: 0 mm; buitenblad_afwerking_rechts_type: NLRS_41_GM_WPB_omgezet metselwerk-SH_generiek_ISR : std; buitenblad_afwerking_rechts_verlenging_boven: 0 mm; buitenblad_afwerking_rechts_verlenging_onder: 0 mm; Constraints(Type) - lossing_binnenblad: 0 mm; offset_binnenblad_boven: 134 mm; offset_binnenblad_links: 131 mm; offset_binnenblad_onder: 59 mm; offset_binnenblad_rechts: 131 mm; offset_binnenbladbeplating_boven: 17 mm; offset_binnenbladbeplating_links: 148 mm; offset_binnenbladbeplating_onder: 17 mm; offset_binnenbladbeplating_rechts: 148 mm; offset_buitenblad_boven: 12 mm; offset_buitenblad_links: 107 mm; offset_buitenblad_onder: 70 mm; offset_buitenblad_rechts: 107 mm; offset_isolatie_boven: 48 mm; offset_isolatie_links: 28 mm; offset_isolatie_onder: 28 mm; offset_isolatie_rechts: 28 mm; Structural(Type) - rekje: no; rekje_plaatsing_x: 0 mm; rekje_plaatsing_y: 0 mm; rekje_type: NLRS_41_GM_WPB_rekje-SH_generiek_ISR : std; rekje_verlenging_links: 200 mm; rekje_verlenging_rechts: 200 mm; spouwlat_boven: yes; spouwlat_boven_plaatsing_y: -17 mm; spouwlat_boven_type: NLRS_41_GM_WPB_spouwlat_isolatie_gen_bdg : 187x38 + isolatie 113x200; spouwlat_boven_verlenging_links: 21 mm; spouwlat_boven_verlenging_rechts: 21 mm; spouwlat_links: yes; spouwlat_links_plaatsing_y: -17 mm; spouwlat_links_type: NLRS_41_GM_WPB_spouwlat_isolatie_gen_bdg : 187x38 + isolatie 110x180; spouwlat_links_verlenging_boven: -17 mm; spouwlat_links_verlenging_onder: -17 mm; spouwlat_onder: yes; spouwlat_onder_plaatsing_y: -17 mm; spouwlat_onder_type: NLRS_41_GM_WPB_spouwlat-SH_generiek_ISR : 185x76; spouwlat_onder_verlenging_links: 21 mm; spouwlat_onder_verlenging_rechts: 21 mm; spouwlat_plaatsing_x: -275 mm; spouwlat_rechts: yes; spouwlat_rechts_plaatsing_y: -17 mm; spouwlat_rechts_type: NLRS_41_GM_WPB_spouwlat_isolatie_gen_bdg : 187x38 + isolatie 110x180; spouwlat_rechts_verlenging_boven: -17 mm; spouwlat_rechts_verlenging_onder: -17 mm; Materials and Finishes(Type) - geveldrager: yes; geveldrager_hoek_a: 0 deg; geveldrager_hoek_b: 0 deg; geveldrager_plaatsing_x: -10 mm; geveldrager_plaatsing_y: 8 mm; geveldrager_type: NLRS_41_SF_LIB_latei_staal_generiek_ISR : 90x150; geveldrager_verlenging_a: 0 mm; geveldrager_verlenging_b: 0 mm; latei: no; latei_hoek_a: 0 deg; latei_hoek_b: 0 deg; latei_plaatsing_x: 0 mm; latei_plaatsing_y: 0 mm; latei_type: NLRS_41_SF_LIB_latei_beton_generiek_ISR : 150x100; latei_verlenging_a: 100 mm; latei_verlenging_b: 100 mm; vensterbank: yes; vensterbank_hoek_a: 0 deg; vensterbank_hoek_b: 0 deg; vensterbank_plaatsing_x: 149 mm; vensterbank_plaatsing_y: 17 mm; vensterbank_type: NLRS_42_GM_WPB_vensterbank_natuursteen-SH_generiek_ISR : 180x18 vensterbank composiet; vensterbank_verlenging_a: -148 mm; vensterbank_verlenging_b: -148 mm; waterslag: yes; waterslag_hoek_a: 0 deg; waterslag_hoek_b: 0 deg; waterslag_plaatsing_x: -25 mm; waterslag_plaatsing_y: 90 mm; waterslag_type: NLRS_41_GM_WPB_waterslag barok-SH_roval_ISR : waterslag_roval_Types Barok_roval_b 270; waterslag_verlenging_a: -100 mm; waterslag_verlenging_b: -100 mm; Graphics(Type) - doorval_hoek_links: 0 deg; doorval_hoek_rechts: 0 deg; doorval_plaatsing_x: 30 mm; doorval_plaatsing_y: 300 mm; doorval_type: NLRS_41_GM_WPB_doorvalbeveiliging-SH_generiek_ISR : std; doorval_verlenging_links: 0 mm; doorval_verlenging_rechts: 0 mm; doorvalbeveiliging: no; ventilatie: no; ventilatie_plaatsing_x: 114 mm; ventilatie_plaatsing_y: 0 mm; ventilatie_type: NLRS_41_GM_WPB_ventilatie-SH_topstream_ISR : std; ventilatie_verlenging_links: 0 mm; ventilatie_verlenging_rechts: 0 mm; Construction(Type) - binnenblad_beplating: 200 mm; binnenblad_hout: 275 mm; buitenblad: 100 mm; isolatie: 10 mm; luchtspouw: 30 mm; negge: 215 mm; Dimensions(Type) - binnenbladhost: yes; buitenbladhost: no; clashobject: no; wrapping_exterior: 0 mm; wrapping_interior: 0 mm; Identity Data(Type) - Assembly Description: buitenwandopeningen; Other(Type) - a_binnen_boven_1: 134 mm; a_binnen_boven_2: 134 mm; a_binnen_links_1: 131 mm; a_binnen_links_2: 131 mm; a_binnen_onder_1: 59 mm; a_binnen_onder_2: 59 mm; a_binnen_rechts_1: 131 mm; a_binnen_rechts_2: 131 mm; a_binnenbepl_boven_1: 17 mm; a_binnenbepl_links_1: 148 mm; a_binnenbepl_onder_1: 17 mm; a_binnenbepl_rechts_1: 148 mm; a_binnenwand_afwerking_boven_y: 17 mm; a_binnenwand_afwerking_links_y: 148 mm; a_binnenwand_afwerking_rechts_y: 148 mm; a_binnenwand_afwerking_x: 149 mm; a_buitenblad_boven: 12 mm; a_buitenblad_boven_y: 0 mm; a_buitenblad_links: 107 mm; a_buitenblad_links_y: 0 mm; a_buitenblad_onder: 70 mm; a_buitenblad_rechts: 107 mm; a_buitenblad_rechts_y: 0 mm; a_buitenblad_x: 0 mm; a_doorval_x: 30 mm; a_doorval_y: 300 mm; a_geveldrager_x: 10 mm; a_geveldrager_y: 8 mm; a_isolatie_boven: 48 mm; a_isolatie_links: 28 mm; a_isolatie_onder: 28 mm; a_isolatie_rechts: 28 mm; a_latei_x: 0 mm; a_latei_y: 0 mm; a_rekje_x: 0 mm; a_rekje_y: 0 mm; a_spouwlat_boven_y: 17 mm; a_spouwlat_links_y: 17 mm; a_spouwlat_onder_y: 17 mm; a_spouwlat_rechts_y: 17 mm; a_spouwlat_x: 275 mm; a_vensterbank_x: 149 mm; a_vensterbank_y: 17 mm; a_ventilatie_x: 114 mm; a_ventilatie_y: 0 mm; a_waterslag_x: 25 mm; a_waterslag_y: 90 mm; b_binnen_boven_1: 268 mm; b_binnen_boven_2: 268 mm; b_binnen_links_1: 262 mm; b_binnen_links_2: 262 mm; b_binnen_onder_1: 118 mm; b_binnen_onder_2: 118 mm; b_binnen_rechts_1: 262 mm; b_binnen_rechts_2: 262 mm; b_binnenwand_afwerking_boven_y: 34 mm; b_binnenwand_afwerking_links_y: 296 mm; b_binnenwand_afwerking_rechts_y: 296 mm; b_binnenwand_afwerking_x: 298 mm; b_buitenblad_boven: 24 mm; b_buitenblad_boven_y: 0 mm; b_buitenblad_links: 214 mm; b_buitenblad_links_y: 0 mm; b_buitenblad_onder: 140 mm; b_buitenblad_rechts: 214 mm; b_buitenblad_rechts_y: 0 mm; b_buitenblad_x: 0 mm; b_doorval_x: 60 mm; b_doorval_y: 600 mm; b_geveldrager_x: 0 mm; b_geveldrager_y: 16 mm; b_isolatie_boven: 96 mm; b_isolatie_links: 56 mm; b_isolatie_onder: 56 mm; b_isolatie_rechts: 56 mm; b_latei_x: 0 mm; b_latei_y: 0 mm; b_rekje_x: 0 mm; b_rekje_y: 0 mm; b_spouwlat_boven_y: 0 mm; b_spouwlat_links_y: 0 mm; b_spouwlat_onder_y: 0 mm; b_spouwlat_rechts_y: 0 mm; b_spouwlat_x: 0 mm; b_vensterbank_x: 298 mm; b_vensterbank_y: 34 mm; b_ventilatie_x: 228 mm; b_ventilatie_y: 0 mm; b_waterslag_x: 0 mm; b_waterslag_y: 180 mm; berekende_binnen-buiten_host: 140 mm; offset_binnenblad_boven_2: 134 mm; offset_binnenblad_links_2: 131 mm; offset_binnenblad_onder_2: 59 mm; offset_binnenblad_rechts_2: 131 mm
Basic Wall:21_WA_metselwerk_licht_100_gen_bdg:2351650 | 02 tweede verdieping | 2D(21.11.11) Uniformat (Uniformat) | 02 tweede verdieping | 673 | 2. nieuwbouw | 3.88842 | 2390 | 850 | Workset1 | 76 | Windows | NLRS_31_WI_WB_sparingmaker_generiek_BDG | NLRS_31_WI_WB_sparingmaker_generiek_BDG: mw_hsb_raam negge 180_alu v2 | 3063 | 772307 | mw_hsb_raam negge 180_alu v2 | 863574 | <None> | Schematic Type | 31 | 20160502 | buitenblad Detail | 57 | mw_hsb_raam negge 180_alu v2 | Family : Windows : NLRS_31_WI_WB_sparingmaker_generiek_BDG | Windows | NLRS_31_WI_WB_sparingmaker_generiek_BDG | General - samenstelling: NLRS_31_WI_UN_samenstelling_leeg_generiek_ISR : std; Dimensions - NLRS_C_breedte: 850 mm; NLRS_C_hoogte: 2390 mm; Layers(Type) - binnenblad_afwerking_boven: yes; binnenblad_afwerking_boven_hoek_links: 0 deg; binnenblad_afwerking_boven_hoek_rechts: 0 deg; binnenblad_afwerking_boven_plaatsing_y: 17 mm; binnenblad_afwerking_boven_type: NLRS_41_GM_WPB_multiplex-SH_generiek_ISR : 151x10 gipsvezel dagkant; binnenblad_afwerking_boven_verlenging_links: -148 mm; binnenblad_afwerking_boven_verlenging_rechts: -148 mm; binnenblad_afwerking_links: yes; binnenblad_afwerking_links_hoek_boven: 0 deg; binnenblad_afwerking_links_hoek_onder: 0 deg; binnenblad_afwerking_links_plaatsing_y: 148 mm; binnenblad_afwerking_links_type: NLRS_41_GM_WPB_multiplex-SH_generiek_ISR : 151x10 gipsvezel dagkant; binnenblad_afwerking_links_verlenging_boven: -27 mm; binnenblad_afwerking_links_verlenging_onder: -94 mm; binnenblad_afwerking_plaatsing_x: 149 mm; binnenblad_afwerking_rechts: yes; binnenblad_afwerking_rechts_hoek_boven: 0 deg; binnenblad_afwerking_rechts_hoek_onder: 0 deg; binnenblad_afwerking_rechts_plaatsing_y: 148 mm; binnenblad_afwerking_rechts_type: NLRS_41_GM_WPB_multiplex-SH_generiek_ISR : 151x10 gipsvezel dagkant; binnenblad_afwerking_rechts_verlenging_boven: -27 mm; binnenblad_afwerking_rechts_verlenging_onder: -94 mm; buitenblad_afwerking_boven: no; buitenblad_afwerking_boven_hoek_links: 0 deg; buitenblad_afwerking_boven_hoek_rechts: 0 deg; buitenblad_afwerking_boven_plaatsing_y: 0 mm; buitenblad_afwerking_boven_type: NLRS_41_GM_WPB_omgezet metselwerk-SH_generiek_ISR : std; buitenblad_afwerking_boven_verlenging_links: 0 mm; buitenblad_afwerking_boven_verlenging_rechts: 0 mm; buitenblad_afwerking_links: no; buitenblad_afwerking_links_hoek_boven: 0 deg; buitenblad_afwerking_links_hoek_onder: 0 deg; buitenblad_afwerking_links_plaatsing_y: 0 mm; buitenblad_afwerking_links_type: NLRS_41_GM_WPB_omgezet metselwerk-SH_generiek_ISR : std; buitenblad_afwerking_links_verlenging_boven: 0 mm; buitenblad_afwerking_links_verlenging_onder: 0 mm; buitenblad_afwerking_plaatsing_x: 0 mm; buitenblad_afwerking_rechts: no; buitenblad_afwerking_rechts_hoek_boven: 0 deg; buitenblad_afwerking_rechts_hoek_onder: 0 deg; buitenblad_afwerking_rechts_plaatsing_y: 0 mm; buitenblad_afwerking_rechts_type: NLRS_41_GM_WPB_omgezet metselwerk-SH_generiek_ISR : std; buitenblad_afwerking_rechts_verlenging_boven: 0 mm; buitenblad_afwerking_rechts_verlenging_onder: 0 mm; Constraints(Type) - lossing_binnenblad: 0 mm; offset_binnenblad_boven: 134 mm; offset_binnenblad_links: 131 mm; offset_binnenblad_onder: 59 mm; offset_binnenblad_rechts: 131 mm; offset_binnenbladbeplating_boven: 17 mm; offset_binnenbladbeplating_links: 148 mm; offset_binnenbladbeplating_onder: 17 mm; offset_binnenbladbeplating_rechts: 148 mm; offset_buitenblad_boven: 12 mm; offset_buitenblad_links: 107 mm; offset_buitenblad_onder: 70 mm; offset_buitenblad_rechts: 107 mm; offset_isolatie_boven: 48 mm; offset_isolatie_links: 28 mm; offset_isolatie_onder: 28 mm; offset_isolatie_rechts: 28 mm; Structural(Type) - rekje: no; rekje_plaatsing_x: 0 mm; rekje_plaatsing_y: 0 mm; rekje_type: NLRS_41_GM_WPB_rekje-SH_generiek_ISR : std; rekje_verlenging_links: 200 mm; rekje_verlenging_rechts: 200 mm; spouwlat_boven: yes; spouwlat_boven_plaatsing_y: -17 mm; spouwlat_boven_type: NLRS_41_GM_WPB_spouwlat_isolatie_gen_bdg : 187x38 + isolatie 113x200; spouwlat_boven_verlenging_links: 21 mm; spouwlat_boven_verlenging_rechts: 21 mm; spouwlat_links: yes; spouwlat_links_plaatsing_y: -17 mm; spouwlat_links_type: NLRS_41_GM_WPB_spouwlat_isolatie_gen_bdg : 187x38 + isolatie 110x180; spouwlat_links_verlenging_boven: -17 mm; spouwlat_links_verlenging_onder: -17 mm; spouwlat_onder: yes; spouwlat_onder_plaatsing_y: -17 mm; spouwlat_onder_type: NLRS_41_GM_WPB_spouwlat-SH_generiek_ISR : 185x76; spouwlat_onder_verlenging_links: 21 mm; spouwlat_onder_verlenging_rechts: 21 mm; spouwlat_plaatsing_x: -275 mm; spouwlat_rechts: yes; spouwlat_rechts_plaatsing_y: -17 mm; spouwlat_rechts_type: NLRS_41_GM_WPB_spouwlat_isolatie_gen_bdg : 187x38 + isolatie 110x180; spouwlat_rechts_verlenging_boven: -17 mm; spouwlat_rechts_verlenging_onder: -17 mm; Materials and Finishes(Type) - geveldrager: yes; geveldrager_hoek_a: 0 deg; geveldrager_hoek_b: 0 deg; geveldrager_plaatsing_x: -10 mm; geveldrager_plaatsing_y: 8 mm; geveldrager_type: NLRS_41_SF_LIB_latei_staal_generiek_ISR : 90x150; geveldrager_verlenging_a: 0 mm; geveldrager_verlenging_b: 0 mm; latei: no; latei_hoek_a: 0 deg; latei_hoek_b: 0 deg; latei_plaatsing_x: 0 mm; latei_plaatsing_y: 0 mm; latei_type: NLRS_41_SF_LIB_latei_beton_generiek_ISR : 150x100; latei_verlenging_a: 100 mm; latei_verlenging_b: 100 mm; vensterbank: yes; vensterbank_hoek_a: 0 deg; vensterbank_hoek_b: 0 deg; vensterbank_plaatsing_x: 149 mm; vensterbank_plaatsing_y: 17 mm; vensterbank_type: NLRS_42_GM_WPB_vensterbank_natuursteen-SH_generiek_ISR : 180x18 vensterbank composiet; vensterbank_verlenging_a: -148 mm; vensterbank_verlenging_b: -148 mm; waterslag: yes; waterslag_hoek_a: 0 deg; waterslag_hoek_b: 0 deg; waterslag_plaatsing_x: -25 mm; waterslag_plaatsing_y: 90 mm; waterslag_type: NLRS_41_GM_WPB_waterslag barok-SH_roval_ISR : waterslag_roval_Types Barok_roval_b 270; waterslag_verlenging_a: -100 mm; waterslag_verlenging_b: -100 mm; Graphics(Type) - doorval_hoek_links: 0 deg; doorval_hoek_rechts: 0 deg; doorval_plaatsing_x: 30 mm; doorval_plaatsing_y: 300 mm; doorval_type: NLRS_41_GM_WPB_doorvalbeveiliging-SH_generiek_ISR : std; doorval_verlenging_links: 0 mm; doorval_verlenging_rechts: 0 mm; doorvalbeveiliging: no; ventilatie: no; ventilatie_plaatsing_x: 114 mm; ventilatie_plaatsing_y: 0 mm; ventilatie_type: NLRS_41_GM_WPB_ventilatie-SH_topstream_ISR : std; ventilatie_verlenging_links: 0 mm; ventilatie_verlenging_rechts: 0 mm; Construction(Type) - binnenblad_beplating: 200 mm; binnenblad_hout: 275 mm; buitenblad: 100 mm; isolatie: 10 mm; luchtspouw: 30 mm; negge: 215 mm; Dimensions(Type) - binnenbladhost: yes; buitenbladhost: no; clashobject: no; wrapping_exterior: 0 mm; wrapping_interior: 0 mm; Identity Data(Type) - Assembly Description: buitenwandopeningen; Other(Type) - a_binnen_boven_1: 134 mm; a_binnen_boven_2: 134 mm; a_binnen_links_1: 131 mm; a_binnen_links_2: 131 mm; a_binnen_onder_1: 59 mm; a_binnen_onder_2: 59 mm; a_binnen_rechts_1: 131 mm; a_binnen_rechts_2: 131 mm; a_binnenbepl_boven_1: 17 mm; a_binnenbepl_links_1: 148 mm; a_binnenbepl_onder_1: 17 mm; a_binnenbepl_rechts_1: 148 mm; a_binnenwand_afwerking_boven_y: 17 mm; a_binnenwand_afwerking_links_y: 148 mm; a_binnenwand_afwerking_rechts_y: 148 mm; a_binnenwand_afwerking_x: 149 mm; a_buitenblad_boven: 12 mm; a_buitenblad_boven_y: 0 mm; a_buitenblad_links: 107 mm; a_buitenblad_links_y: 0 mm; a_buitenblad_onder: 70 mm; a_buitenblad_rechts: 107 mm; a_buitenblad_rechts_y: 0 mm; a_buitenblad_x: 0 mm; a_doorval_x: 30 mm; a_doorval_y: 300 mm; a_geveldrager_x: 10 mm; a_geveldrager_y: 8 mm; a_isolatie_boven: 48 mm; a_isolatie_links: 28 mm; a_isolatie_onder: 28 mm; a_isolatie_rechts: 28 mm; a_latei_x: 0 mm; a_latei_y: 0 mm; a_rekje_x: 0 mm; a_rekje_y: 0 mm; a_spouwlat_boven_y: 17 mm; a_spouwlat_links_y: 17 mm; a_spouwlat_onder_y: 17 mm; a_spouwlat_rechts_y: 17 mm; a_spouwlat_x: 275 mm; a_vensterbank_x: 149 mm; a_vensterbank_y: 17 mm; a_ventilatie_x: 114 mm; a_ventilatie_y: 0 mm; a_waterslag_x: 25 mm; a_waterslag_y: 90 mm; b_binnen_boven_1: 268 mm; b_binnen_boven_2: 268 mm; b_binnen_links_1: 262 mm; b_binnen_links_2: 262 mm; b_binnen_onder_1: 118 mm; b_binnen_onder_2: 118 mm; b_binnen_rechts_1: 262 mm; b_binnen_rechts_2: 262 mm; b_binnenwand_afwerking_boven_y: 34 mm; b_binnenwand_afwerking_links_y: 296 mm; b_binnenwand_afwerking_rechts_y: 296 mm; b_binnenwand_afwerking_x: 298 mm; b_buitenblad_boven: 24 mm; b_buitenblad_boven_y: 0 mm; b_buitenblad_links: 214 mm; b_buitenblad_links_y: 0 mm; b_buitenblad_onder: 140 mm; b_buitenblad_rechts: 214 mm; b_buitenblad_rechts_y: 0 mm; b_buitenblad_x: 0 mm; b_doorval_x: 60 mm; b_doorval_y: 600 mm; b_geveldrager_x: 0 mm; b_geveldrager_y: 16 mm; b_isolatie_boven: 96 mm; b_isolatie_links: 56 mm; b_isolatie_onder: 56 mm; b_isolatie_rechts: 56 mm; b_latei_x: 0 mm; b_latei_y: 0 mm; b_rekje_x: 0 mm; b_rekje_y: 0 mm; b_spouwlat_boven_y: 0 mm; b_spouwlat_links_y: 0 mm; b_spouwlat_onder_y: 0 mm; b_spouwlat_rechts_y: 0 mm; b_spouwlat_x: 0 mm; b_vensterbank_x: 298 mm; b_vensterbank_y: 34 mm; b_ventilatie_x: 228 mm; b_ventilatie_y: 0 mm; b_waterslag_x: 0 mm; b_waterslag_y: 180 mm; berekende_binnen-buiten_host: 140 mm; offset_binnenblad_boven_2: 134 mm; offset_binnenblad_links_2: 131 mm; offset_binnenblad_onder_2: 59 mm; offset_binnenblad_rechts_2: 131 mm
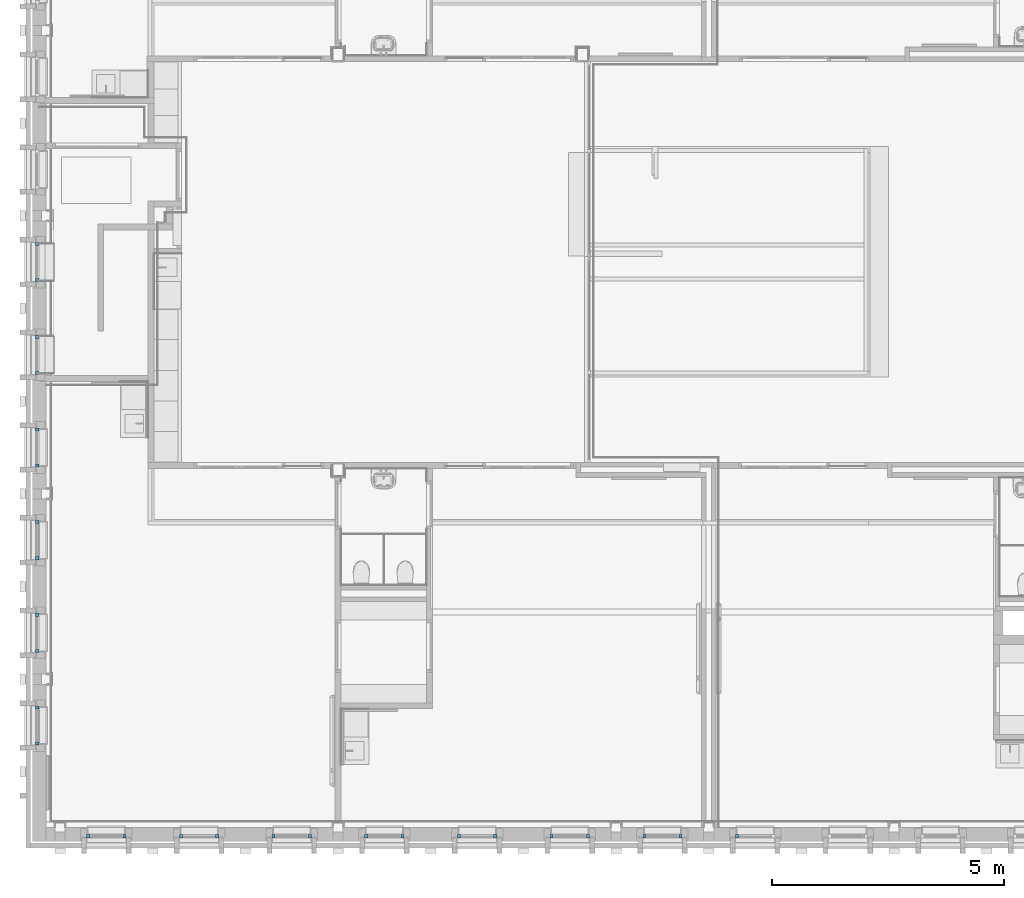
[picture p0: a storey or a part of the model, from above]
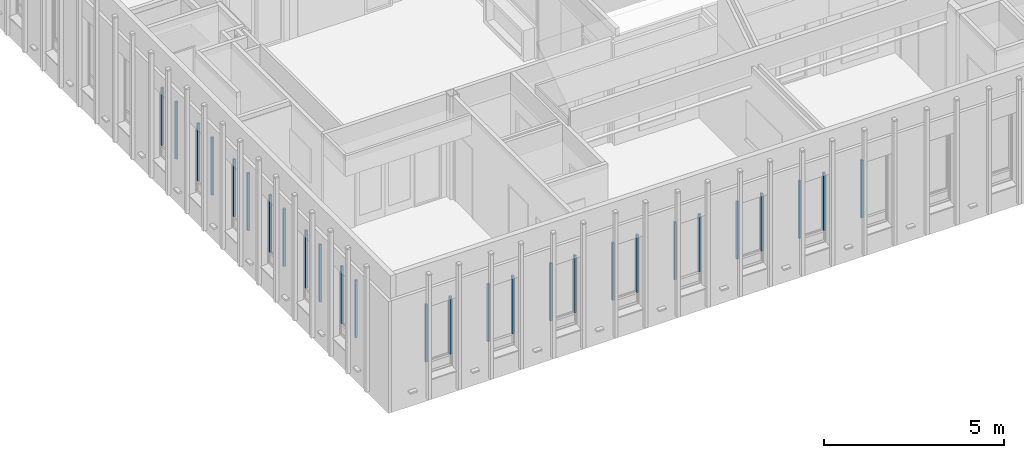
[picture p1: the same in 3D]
Properties of the parts of a building model (IFC2X3), part 66 of 94

# IfcOpeningElement: Opening (823)
Name | In | Classification | Level | Sill Height (mm) | Phase Created | Area (m2) | Height (mm) | Width (mm) | Identity Data, Workset | Mark | Other, Category | Family | Family and Type | Head Height (mm) | Host Id | Type | Type Id | Analytic Construction | Define Thermal Properties by | Assembly Code | Datum_Gewijzigd | Description | Type Mark | Type Name | Identity Data(Type), Workset | Other(Type), Category | Family Name
Basic Wall:21_WA_tegelwerk 10:2431288 | 00 begane grond | 2D(21.10) Uniformat (Uniformat) | 00 begane grond | 0 | 2. nieuwbouw |  | 2387 | 1034 | Workset1 | 406 | Doors | NLRS_32_houten_binnenkozijn_BDG | NLRS_32_houten_binnenkozijn_BDG: BI-06w 930x2315 enkel 67x125 | 2387 | 1500223 | BI-06w 930x2315 enkel 67x125 | 2595981 | <None> | Schematic Type | 2E(32.3) | 14-11-2012 | wandsparing met houten binnenkozijn | BI-06w | BI-06w 930x2315 enkel 67x125 | Family : Doors : NLRS_32_houten_binnenkozijn_BDG | Doors | NLRS_32_houten_binnenkozijn_BDG | Constraints - kozijn_breedte: 1034 mm; Graphics - WBDBO_tekst_andere_zijde: no; Construction - deur_in_wand_as: yes; host_dikte: 96 mm; kozijn_hoogte: 2387 mm; neggemaat: 0 mm; Other - berekende_negge: 585.5 mm; Fire Protection(Type) - brand_zelfsluitend: no; brandw_120min: no; brandw_30min: no; brandw_60min: no; brandw_90min: no; deur_dikte: 40 mm; fire_rating: zie bijbehorende samenstelling; Text(Type) - rep_stijl_breedte: 67 mm; rep_stijl_diepte: 125 mm; rep_tussenstijl_breedte: 67 mm; rep_zelfsl.: no; Constraints(Type) - deur_breedte: 930 mm; ruimte_onder_deur: 20 mm; Construction(Type) - Function: Interior; Construction Type: wandopening met kozijn; dorpel: no; sponning_breedte: 17 mm; sponning_diepte: 50 mm; stijl_breedte: 67 mm; stijl_diepte: 125 mm; Wall Closure: By host; zelfsluitend: no; Dimensions(Type) - deur_hoogte: 2315 mm; dikte_onderdorpel: 5 mm; dubbele_deur: no; Rough Width: 0 mm; Identity Data(Type) - Fire Rating: zie bijbehorende samenstelling; OmniClass Number: 23.30.10.00; OmniClass Title: Doors; SmartRevit_Versie: 2013.2; Type Comments: wandopening met samenstelling; Other(Type) - config_dubbel: NLRS_32_samenstelling_binnenkozijn_hout_BDG : dubbele deur; config_enkel: NLRS_32_samenstelling_binnenkozijn_hout_BDG : enkele deur; deur_config: NLRS_32_samenstelling_binnenkozijn_hout_BDG : enkele deur
Basic Wall:21_WA_tegelwerk 10:2431638 | 00 begane grond | 2D(21.10) Uniformat (Uniformat) | 00 begane grond | 0 | 2. nieuwbouw |  | 2387 | 1034 | Workset1 | 259 | Doors | NLRS_32_houten_binnenkozijn_BDG | NLRS_32_houten_binnenkozijn_BDG: BI-06v 930x2315 enkel 67x125 | 2387 | 1368308 | BI-06v 930x2315 enkel 67x125 | 4228679 | <None> | Schematic Type | 2E(32.3) | 14-11-2012 | wandsparing met houten binnenkozijn | BI-06v | BI-06v 930x2315 enkel 67x125 | Family : Doors : NLRS_32_houten_binnenkozijn_BDG | Doors | NLRS_32_houten_binnenkozijn_BDG | Constraints - kozijn_breedte: 1034 mm; Graphics - WBDBO_tekst_andere_zijde: no; Construction - deur_in_wand_as: yes; host_dikte: 120 mm; kozijn_hoogte: 2387 mm; neggemaat: 0 mm; Other - berekende_negge: 597.5 mm; Fire Protection(Type) - brand_zelfsluitend: no; brandw_120min: no; brandw_30min: no; brandw_60min: no; brandw_90min: no; deur_dikte: 40 mm; fire_rating: zie bijbehorende samenstelling; Text(Type) - rep_stijl_breedte: 67 mm; rep_stijl_diepte: 125 mm; rep_tussenstijl_breedte: 67 mm; rep_zelfsl.: no; Constraints(Type) - deur_breedte: 930 mm; ruimte_onder_deur: 20 mm; Construction(Type) - Function: Interior; Construction Type: wandopening met kozijn; dorpel: no; sponning_breedte: 17 mm; sponning_diepte: 50 mm; stijl_breedte: 67 mm; stijl_diepte: 125 mm; Wall Closure: By host; zelfsluitend: no; Dimensions(Type) - deur_hoogte: 2315 mm; dikte_onderdorpel: 5 mm; dubbele_deur: no; Rough Width: 0 mm; Identity Data(Type) - Fire Rating: zie bijbehorende samenstelling; OmniClass Number: 23.30.10.00; OmniClass Title: Doors; SmartRevit_Versie: 2013.2; Type Comments: wandopening met samenstelling; Other(Type) - config_dubbel: NLRS_32_samenstelling_binnenkozijn_hout_BDG : dubbele deur; config_enkel: NLRS_32_samenstelling_binnenkozijn_hout_BDG : enkele deur; deur_config: NLRS_32_samenstelling_binnenkozijn_hout_BDG : enkele deur
Basic Wall:21_WA_tegelwerk 10:2431638 | 00 begane grond | 2D(21.10) Uniformat (Uniformat) | 00 begane grond | 0 | 2. nieuwbouw |  | 2387 | 1134 | Workset1 | 262 | Doors | NLRS_32_houten_binnenkozijn_BDG | NLRS_32_houten_binnenkozijn_BDG: BI-05v 1030x2315 enkel 67x125 | 2387 | 1368308 | BI-05v 1030x2315 enkel 67x125 | 2627564 | <None> | Schematic Type | 2E(32.3) | 14-11-2012 | wandsparing met houten binnenkozijn | BI-05v | BI-05v 1030x2315 enkel 67x125 | Family : Doors : NLRS_32_houten_binnenkozijn_BDG | Doors | NLRS_32_houten_binnenkozijn_BDG | Constraints - kozijn_breedte: 1134 mm; Graphics - WBDBO_tekst_andere_zijde: no; Construction - deur_in_wand_as: yes; host_dikte: 120 mm; kozijn_hoogte: 2387 mm; neggemaat: 0 mm; Other - berekende_negge: 597.5 mm; Fire Protection(Type) - brand_zelfsluitend: no; brandw_120min: no; brandw_30min: no; brandw_60min: no; brandw_90min: no; deur_dikte: 40 mm; fire_rating: zie bijbehorende samenstelling; Text(Type) - rep_stijl_breedte: 67 mm; rep_stijl_diepte: 125 mm; rep_tussenstijl_breedte: 67 mm; rep_zelfsl.: no; Constraints(Type) - deur_breedte: 1030 mm; ruimte_onder_deur: 20 mm; Construction(Type) - Function: Interior; Construction Type: wandopening met kozijn; dorpel: no; sponning_breedte: 17 mm; sponning_diepte: 50 mm; stijl_breedte: 67 mm; stijl_diepte: 125 mm; Wall Closure: By host; zelfsluitend: no; Dimensions(Type) - deur_hoogte: 2315 mm; dikte_onderdorpel: 5 mm; dubbele_deur: no; Rough Width: 0 mm; Identity Data(Type) - Fire Rating: zie bijbehorende samenstelling; OmniClass Number: 23.30.10.00; OmniClass Title: Doors; SmartRevit_Versie: 2013.2; Type Comments: wandopening met samenstelling; Other(Type) - config_dubbel: NLRS_32_samenstelling_binnenkozijn_hout_BDG : dubbele deur; config_enkel: NLRS_32_samenstelling_binnenkozijn_hout_BDG : enkele deur; deur_config: NLRS_32_samenstelling_binnenkozijn_hout_BDG : enkele deur
Basic Wall:21_WA_tegelwerk 10:2432054 | 00 begane grond | 2D(21.10) Uniformat (Uniformat) | 00 begane grond | 0 | 2. nieuwbouw |  | 2387 | 1034 | Workset1 | 256 | Doors | NLRS_32_houten_binnenkozijn_BDG | NLRS_32_houten_binnenkozijn_BDG: BI-06v 930x2315 enkel 67x125 | 2387 | 1368560 | BI-06v 930x2315 enkel 67x125 | 4228679 | <None> | Schematic Type | 2E(32.3) | 14-11-2012 | wandsparing met houten binnenkozijn | BI-06v | BI-06v 930x2315 enkel 67x125 | Family : Doors : NLRS_32_houten_binnenkozijn_BDG | Doors | NLRS_32_houten_binnenkozijn_BDG | Constraints - kozijn_breedte: 1034 mm; Graphics - WBDBO_tekst_andere_zijde: no; Construction - deur_in_wand_as: yes; host_dikte: 120 mm; kozijn_hoogte: 2387 mm; neggemaat: 0 mm; Other - berekende_negge: 597.5 mm; Fire Protection(Type) - brand_zelfsluitend: no; brandw_120min: no; brandw_30min: no; brandw_60min: no; brandw_90min: no; deur_dikte: 40 mm; fire_rating: zie bijbehorende samenstelling; Text(Type) - rep_stijl_breedte: 67 mm; rep_stijl_diepte: 125 mm; rep_tussenstijl_breedte: 67 mm; rep_zelfsl.: no; Constraints(Type) - deur_breedte: 930 mm; ruimte_onder_deur: 20 mm; Construction(Type) - Function: Interior; Construction Type: wandopening met kozijn; dorpel: no; sponning_breedte: 17 mm; sponning_diepte: 50 mm; stijl_breedte: 67 mm; stijl_diepte: 125 mm; Wall Closure: By host; zelfsluitend: no; Dimensions(Type) - deur_hoogte: 2315 mm; dikte_onderdorpel: 5 mm; dubbele_deur: no; Rough Width: 0 mm; Identity Data(Type) - Fire Rating: zie bijbehorende samenstelling; OmniClass Number: 23.30.10.00; OmniClass Title: Doors; SmartRevit_Versie: 2013.2; Type Comments: wandopening met samenstelling; Other(Type) - config_dubbel: NLRS_32_samenstelling_binnenkozijn_hout_BDG : dubbele deur; config_enkel: NLRS_32_samenstelling_binnenkozijn_hout_BDG : enkele deur; deur_config: NLRS_32_samenstelling_binnenkozijn_hout_BDG : enkele deur
Basic Wall:21_WA_tegelwerk 10:2433276 | 00 begane grond | 2D(21.10) Uniformat (Uniformat) | 00 begane grond | 0 | 2. nieuwbouw |  | 2387 | 1034 | Workset1 | 259 | Doors | NLRS_32_houten_binnenkozijn_BDG | NLRS_32_houten_binnenkozijn_BDG: BI-06v 930x2315 enkel 67x125 | 2387 | 1368308 | BI-06v 930x2315 enkel 67x125 | 4228679 | <None> | Schematic Type | 2E(32.3) | 14-11-2012 | wandsparing met houten binnenkozijn | BI-06v | BI-06v 930x2315 enkel 67x125 | Family : Doors : NLRS_32_houten_binnenkozijn_BDG | Doors | NLRS_32_houten_binnenkozijn_BDG | Constraints - kozijn_breedte: 1034 mm; Graphics - WBDBO_tekst_andere_zijde: no; Construction - deur_in_wand_as: yes; host_dikte: 120 mm; kozijn_hoogte: 2387 mm; neggemaat: 0 mm; Other - berekende_negge: 597.5 mm; Fire Protection(Type) - brand_zelfsluitend: no; brandw_120min: no; brandw_30min: no; brandw_60min: no; brandw_90min: no; deur_dikte: 40 mm; fire_rating: zie bijbehorende samenstelling; Text(Type) - rep_stijl_breedte: 67 mm; rep_stijl_diepte: 125 mm; rep_tussenstijl_breedte: 67 mm; rep_zelfsl.: no; Constraints(Type) - deur_breedte: 930 mm; ruimte_onder_deur: 20 mm; Construction(Type) - Function: Interior; Construction Type: wandopening met kozijn; dorpel: no; sponning_breedte: 17 mm; sponning_diepte: 50 mm; stijl_breedte: 67 mm; stijl_diepte: 125 mm; Wall Closure: By host; zelfsluitend: no; Dimensions(Type) - deur_hoogte: 2315 mm; dikte_onderdorpel: 5 mm; dubbele_deur: no; Rough Width: 0 mm; Identity Data(Type) - Fire Rating: zie bijbehorende samenstelling; OmniClass Number: 23.30.10.00; OmniClass Title: Doors; SmartRevit_Versie: 2013.2; Type Comments: wandopening met samenstelling; Other(Type) - config_dubbel: NLRS_32_samenstelling_binnenkozijn_hout_BDG : dubbele deur; config_enkel: NLRS_32_samenstelling_binnenkozijn_hout_BDG : enkele deur; deur_config: NLRS_32_samenstelling_binnenkozijn_hout_BDG : enkele deur
Basic Wall:21_WA_tegelwerk 10:2433276 | 00 begane grond | 2D(21.10) Uniformat (Uniformat) | 00 begane grond | 0 | 2. nieuwbouw |  | 2387 | 1134 | Workset1 | 262 | Doors | NLRS_32_houten_binnenkozijn_BDG | NLRS_32_houten_binnenkozijn_BDG: BI-05v 1030x2315 enkel 67x125 | 2387 | 1368308 | BI-05v 1030x2315 enkel 67x125 | 2627564 | <None> | Schematic Type | 2E(32.3) | 14-11-2012 | wandsparing met houten binnenkozijn | BI-05v | BI-05v 1030x2315 enkel 67x125 | Family : Doors : NLRS_32_houten_binnenkozijn_BDG | Doors | NLRS_32_houten_binnenkozijn_BDG | Constraints - kozijn_breedte: 1134 mm; Graphics - WBDBO_tekst_andere_zijde: no; Construction - deur_in_wand_as: yes; host_dikte: 120 mm; kozijn_hoogte: 2387 mm; neggemaat: 0 mm; Other - berekende_negge: 597.5 mm; Fire Protection(Type) - brand_zelfsluitend: no; brandw_120min: no; brandw_30min: no; brandw_60min: no; brandw_90min: no; deur_dikte: 40 mm; fire_rating: zie bijbehorende samenstelling; Text(Type) - rep_stijl_breedte: 67 mm; rep_stijl_diepte: 125 mm; rep_tussenstijl_breedte: 67 mm; rep_zelfsl.: no; Constraints(Type) - deur_breedte: 1030 mm; ruimte_onder_deur: 20 mm; Construction(Type) - Function: Interior; Construction Type: wandopening met kozijn; dorpel: no; sponning_breedte: 17 mm; sponning_diepte: 50 mm; stijl_breedte: 67 mm; stijl_diepte: 125 mm; Wall Closure: By host; zelfsluitend: no; Dimensions(Type) - deur_hoogte: 2315 mm; dikte_onderdorpel: 5 mm; dubbele_deur: no; Rough Width: 0 mm; Identity Data(Type) - Fire Rating: zie bijbehorende samenstelling; OmniClass Number: 23.30.10.00; OmniClass Title: Doors; SmartRevit_Versie: 2013.2; Type Comments: wandopening met samenstelling; Other(Type) - config_dubbel: NLRS_32_samenstelling_binnenkozijn_hout_BDG : dubbele deur; config_enkel: NLRS_32_samenstelling_binnenkozijn_hout_BDG : enkele deur; deur_config: NLRS_32_samenstelling_binnenkozijn_hout_BDG : enkele deur
Basic Wall:22_WA_voorzetwand_ms100 25-75 _gen_bdg:2435824 | 01 eerste verdieping | 2E(22.11) Uniformat (Uniformat) |  |  | 2. nieuwbouw | 4.35627 |  |  | Workset1 |  | Walls | Curtain Wall | Curtain Wall: 32_ontwerpkozijn binnen 125*67 |  |  | 32_ontwerpkozijn binnen 125*67 | 1227226 | Constraints - Base Constraint: 01 eerste verdieping; Base Offset: 0 mm; Top Offset: 0 mm; Unconnected Height: 2387 mm; Base is Attached: no; Related to Mass: no; Room Bounding: yes; Top is Attached: no; Cross-Section Definition - Cross-Section: Vertical; Horizontal Grid - Angle: 0 deg; Justification: Beginning; Number: 4; Offset: 0 mm; sets with these values: 2; Structural - Enable Analytical Model: no; Structural: no; Structural Usage: Non-bearing; Dimensions - Length: 1825 mm; Identity Data - Comments: BI-25bw
Basic Wall:22_WA_binnenwand_ms125 25-75-25 _gen_bdg:2436050 | 02 tweede verdieping | 2E(22.11) Uniformat (Uniformat) |  |  | 2. nieuwbouw |  |  |  | Workset1 |  | Walls: Rectangular Straight Wall Opening | Constraints - Base Constraint: 02 tweede verdieping; Base Offset: 0 mm; Top Offset: 0 mm; Unconnected Height: 2387 mm
Basic Wall:22_WA_binnenwand_ms125 25-75-25 _gen_bdg:2439282 | 01 eerste verdieping | 2E(22.11) Uniformat (Uniformat) |  |  | 2. nieuwbouw | 6.43297 |  |  | Workset1 |  | Walls | Curtain Wall | Curtain Wall: 32_schuifwand binnen 40*85 |  |  | 32_schuifwand binnen 40*85 | 2753422 | Constraints - Base Constraint: 01 eerste verdieping; Base Offset: 0 mm; Top Constraint: Up to level: 01 eerste verdieping; Top Offset: 2387 mm; Unconnected Height: 2387 mm; Base is Attached: no; Related to Mass: no; Room Bounding: yes; Top is Attached: no; Cross-Section Definition - Cross-Section: Vertical; Horizontal Grid - Angle: 0 deg; Justification: Beginning; Number: 4; Offset: 0 mm; sets with these values: 2; Structural - Enable Analytical Model: no; Structural: no; Structural Usage: Non-bearing; Dimensions - Length: 2695 mm; Identity Data - Comments: BI-30
Basic Wall:22_WA_binnenwand_ms125 25-75-25 _gen_bdg:2444394 | 01 eerste verdieping | 2E(22.11) Uniformat (Uniformat) | 01 eerste verdieping | 0 | 2. nieuwbouw |  | 2387 | 1034 | Workset1 | 382 | Doors | NLRS_32_houten_binnenkozijn_met_zijlicht_BDG | NLRS_32_houten_binnenkozijn_met_zijlicht_BDG: BI-24w 930x2315 enkel 1ZL (1730) | 2387 | 4871045 | BI-24w 930x2315 enkel 1ZL (1730) | 2444405 | <None> | Schematic Type | 2E(32.3) | 14-11-2012 | wandsparing met houten binnenkozijn | BI-24w | BI-24w 930x2315 enkel 1ZL (1730) | Family : Doors : NLRS_32_houten_binnenkozijn_met_zijlicht_BDG | Doors | NLRS_32_houten_binnenkozijn_met_zijlicht_BDG | Construction - deur_in_wand_as: yes; host_dikte: 125 mm; kozijn_hoogte: 2387 mm; neggemaat: 0 mm; Other - berekende_negge: 600 mm; ref_rechts: 865 mm; Fire Protection(Type) - brand_zelfsluitend: no; brandw_120min: no; brandw_30min: no; brandw_60min: no; brandw_90min: no; deur_dikte: 40 mm; fire_rating: zie bijbehorende samenstelling; Text(Type) - rep_stijl_breedte: 67 mm; rep_stijl_diepte: 125 mm; rep_tussenstijl_breedte: 67 mm; rep_zelfsl.: no; Constraints(Type) - deur_breedte: 930 mm; ruimte_onder_deur: 15 mm; kozijn_breedte: 1730 mm; plafond_hoogte: 0 mm; Construction(Type) - Function: Interior; Construction Type: wandopening met kozijn; dorpel: no; stijl_breedte: 67 mm; stijl_diepte: 125 mm; Wall Closure: By host; zelfsluitend: no; samenstelling: 300_32_ISR_samenstelling_binnenkozijn_hout_met_zijlicht : enkele deur 1xZL; tussenstijl_breedte: 67 mm; tussenstijl_diepte: 125 mm; Dimensions(Type) - deur_hoogte: 2320 mm; dikte_onderdorpel: 25 mm; dubbele_deur: no; sponning_breedte: 17 mm; sponning_diepte: 50 mm; zijlicht_LR_verdelen: no; Identity Data(Type) - Fire Rating: zie bijbehorende samenstelling; Model: D; OmniClass Number: 23.30.10.00; OmniClass Title: Doors; SmartRevit_Versie: 2013.2; Type Comments: wandopening met samenstelling; Manufacturer: Rw = ntb; Graphics(Type) - deur_LR_wisselen: yes; WBDBO_tekst_andere_zijde: yes; Other(Type) - config_deur_dubbel 1xZL: 300_32_ISR_samenstelling_binnenkozijn_hout_met_zijlicht : dubbele deur 1xZL; config_deur_dubbel 2xZL: 300_32_ISR_samenstelling_binnenkozijn_hout_met_zijlicht : dubbele deur 1xZL; config_deur_enkel 1xZL: 300_32_ISR_samenstelling_binnenkozijn_hout_met_zijlicht : enkele deur 1xZL; config_deur_enkel 2xZL: 300_32_ISR_samenstelling_binnenkozijn_hout_met_zijlicht : enkele deur 2xZL
Basic Wall:22_WA_binnenwand_ms125 25-75-25 _gen_bdg:2473493 | 00 begane grond | 2E(22.11) Uniformat (Uniformat) | 00 begane grond |  | 2. nieuwbouw | 0.916815 |  |  | Workset1 | 88 | Plumbing Fixtures | 300_74_ISR_brandslanghaspel_inbouw | 300_74_ISR_brandslanghaspel_inbouw: 65_BDG_BSH 30 m¹ |  |  | 65_BDG_BSH 30 m¹ | 1812937 | Constraints - Elevation from Level: 800 mm; Schedule Level: 00 begane grond; Host: Basic Wall : 22_WA_binnenwand_ms125 25-75-25 _gen_bdg; Dimensions - Volume: 0.115459 m3; Mechanical - brandslanghaspel_kw_flow: 0.361 m3/s; System Classification: Domestic Cold Water; Graphics - slang_bereik: no
Basic Wall:22_WA_koof_83 12-71:2501230 | 00 begane grond | 2E(22.11) Uniformat (Uniformat) | 01 eerste verdieping | 0 | 2. nieuwbouw |  | 2387 | 1966 | Workset1 | 484 | Doors | NLRS_32_houten_binnenkozijn_met_zijlicht_BDG | NLRS_32_houten_binnenkozijn_met_zijlicht_BDG: BI-19w 930x2738 dubbel met glas 1ZL (2796) | 2387 | 4871542 | BI-19w 930x2738 dubbel met glas 1ZL (2796) | 4001767 | <None> | Schematic Type | 2E(32.3) | 14-11-2012 | wandsparing met houten binnenkozijn | BI-19w | BI-19w 930x2738 dubbel met glas 1ZL (2796) | Family : Doors : NLRS_32_houten_binnenkozijn_met_zijlicht_BDG | Doors | NLRS_32_houten_binnenkozijn_met_zijlicht_BDG | Construction - deur_in_wand_as: yes; host_dikte: 125 mm; kozijn_hoogte: 2387 mm; neggemaat: 20 mm; Other - berekende_negge: 600 mm; ref_rechts: 1398 mm; Fire Protection(Type) - brand_zelfsluitend: no; brandw_120min: no; brandw_30min: no; brandw_60min: no; brandw_90min: no; deur_dikte: 40 mm; fire_rating: zie bijbehorende samenstelling; Text(Type) - rep_stijl_breedte: 67 mm; rep_stijl_diepte: 125 mm; rep_tussenstijl_breedte: 67 mm; rep_zelfsl.: no; Constraints(Type) - deur_breedte: 930 mm; ruimte_onder_deur: 15 mm; kozijn_breedte: 2796 mm; plafond_hoogte: 0 mm; Construction(Type) - Function: Interior; Construction Type: wandopening met kozijn; dorpel: no; stijl_breedte: 67 mm; stijl_diepte: 125 mm; Wall Closure: By host; zelfsluitend: no; samenstelling: 300_32_ISR_samenstelling_binnenkozijn_hout_met_zijlicht : dubbele deur met glas 1xZL; tussenstijl_breedte: 67 mm; tussenstijl_diepte: 125 mm; Dimensions(Type) - deur_hoogte: 2320 mm; dikte_onderdorpel: 25 mm; dubbele_deur: yes; sponning_breedte: 17 mm; sponning_diepte: 50 mm; zijlicht_LR_verdelen: no; Identity Data(Type) - Fire Rating: zie bijbehorende samenstelling; Model: K; OmniClass Number: 23.30.10.00; OmniClass Title: Doors; SmartRevit_Versie: 2013.2; Type Comments: wandopening met samenstelling; Graphics(Type) - deur_LR_wisselen: no; WBDBO_tekst_andere_zijde: yes; Other(Type) - config_deur_dubbel 1xZL: 300_32_ISR_samenstelling_binnenkozijn_hout_met_zijlicht : dubbele deur met glas 1xZL; config_deur_dubbel 2xZL: 300_32_ISR_samenstelling_binnenkozijn_hout_met_zijlicht : dubbele deur met glas 2xZL; config_deur_enkel 1xZL: 300_32_ISR_samenstelling_binnenkozijn_hout_met_zijlicht : enkele deur met glas 1xZL; config_deur_enkel 2xZL: 300_32_ISR_samenstelling_binnenkozijn_hout_met_zijlicht : enkele deur met glas 2xZL
Basic Wall:NLRS_20_WA_RVS Carlstahl 2 TRANS:1830774 | 00 begane grond |  |  |  |  |  |  |  | Workset1 |  | Lines: <Sketch> | Dimensions - Length: 2899.77 mm
Basic Wall:NLRS_20_WA_RVS Carlstahl 2 TRANS:1830774 | 00 begane grond |  |  |  |  |  |  |  | Workset1 |  | Lines: <Sketch> | Dimensions - Length: 2806.21 mm
Basic Wall:21_WA_metselwerk_licht_100_gen_bdg:2551961 | 01 eerste verdieping | 2D(21.11.11) Uniformat (Uniformat) |  |  | 2. nieuwbouw | 10.3396 |  |  | Workset1 |  | Walls | Curtain Wall | Curtain Wall: 20_opening |  |  | 20_opening | 1306490 | Constraints - Base Constraint: 01 eerste verdieping; Base Offset: -50 mm; Top Constraint: Up to level: 01 eerste verdieping; Top Offset: 2877 mm; Unconnected Height: 2927 mm; Base is Attached: no; Related to Mass: no; Room Bounding: yes; Top is Attached: no; Cross-Section Definition - Cross-Section: Vertical; Horizontal Grid - Angle: 0 deg; Justification: Beginning; Number: 4; Offset: 0 mm; sets with these values: 2; Structural - Enable Analytical Model: no; Structural: no; Structural Usage: Non-bearing; Dimensions - Length: 3532.5 mm
Basic Wall:21_WA_metselwerk_licht_100_gen_bdg:1331771 | 01 eerste verdieping | 2D(21.11.11) Uniformat (Uniformat) |  |  |  |  |  |  | Workset1 |  | Lines: <Sketch> | Dimensions - Length: 2727 mm
Basic Wall:NLRS_20_WA_RVS Carlstahl 2 TRANS:1830774 | 02 tweede verdieping |  |  |  |  |  |  |  | Workset1 |  | Lines: <Sketch> | Dimensions - Length: 110.852 mm
Basic Wall:22_WA_binnenwand_ms125 25-75-25 _gen_bdg:2715807 | 00 begane grond | 2E(22.11) Uniformat (Uniformat) | 00 begane grond | 0 | 2. nieuwbouw |  | 2387 | 1034 | Workset1 | 357 | Doors | NLRS_32_houten_binnenkozijn_BDG | NLRS_32_houten_binnenkozijn_BDG: BI-06 930x2315 enkel 67x125 | 2387 | 2715734 | BI-06 930x2315 enkel 67x125 | 1274087 | <None> | Schematic Type | 2E(32.3) | 14-11-2012 | wandsparing met houten binnenkozijn | BI-06 | BI-06 930x2315 enkel 67x125 | Family : Doors : NLRS_32_houten_binnenkozijn_BDG | Doors | NLRS_32_houten_binnenkozijn_BDG | Constraints - kozijn_breedte: 1034 mm; Graphics - WBDBO_tekst_andere_zijde: no; Construction - deur_in_wand_as: yes; host_dikte: 125 mm; kozijn_hoogte: 2387 mm; neggemaat: 0 mm; Other - berekende_negge: 600 mm; Fire Protection(Type) - brand_zelfsluitend: no; brandw_120min: no; brandw_30min: no; brandw_60min: no; brandw_90min: no; deur_dikte: 40 mm; fire_rating: zie bijbehorende samenstelling; Text(Type) - rep_stijl_breedte: 67 mm; rep_stijl_diepte: 125 mm; rep_tussenstijl_breedte: 67 mm; rep_zelfsl.: no; Constraints(Type) - deur_breedte: 930 mm; ruimte_onder_deur: 20 mm; Construction(Type) - Function: Interior; Construction Type: wandopening met kozijn; dorpel: no; sponning_breedte: 17 mm; sponning_diepte: 50 mm; stijl_breedte: 67 mm; stijl_diepte: 125 mm; Wall Closure: By host; zelfsluitend: no; Dimensions(Type) - deur_hoogte: 2315 mm; dikte_onderdorpel: 5 mm; dubbele_deur: no; Rough Width: 0 mm; Identity Data(Type) - Fire Rating: zie bijbehorende samenstelling; OmniClass Number: 23.30.10.00; OmniClass Title: Doors; SmartRevit_Versie: 2013.2; Type Comments: wandopening met samenstelling; Other(Type) - config_dubbel: NLRS_32_samenstelling_binnenkozijn_hout_BDG : dubbele deur; config_enkel: NLRS_32_samenstelling_binnenkozijn_hout_BDG : enkele deur; deur_config: NLRS_32_samenstelling_binnenkozijn_hout_BDG : enkele deur
Basic Wall:22_WA_binnenwand_ms100 25-50-25 _gen_bdg:2720548 | 00 begane grond | 2E(22.11) Uniformat (Uniformat) | 00 begane grond | 0 | 2. nieuwbouw |  | 2387 | 1934 | Workset1 | 450 | Doors | NLRS_32_houten_binnenkozijn_BDG | NLRS_32_houten_binnenkozijn_BDG: BI-14c 930x2315 dubbel met glas (1965) | 2387 | 2719867 | BI-14c 930x2315 dubbel met glas (1965) | 2623191 | <None> | Schematic Type | 2E(32.3) | 14-11-2012 | wandsparing met houten binnenkozijn | BI-14c | BI-14c 930x2315 dubbel met glas (1965) | Family : Doors : NLRS_32_houten_binnenkozijn_BDG | Doors | NLRS_32_houten_binnenkozijn_BDG | Constraints - kozijn_breedte: 1934 mm; Graphics - WBDBO_tekst_andere_zijde: no; Construction - deur_in_wand_as: yes; host_dikte: 125 mm; kozijn_hoogte: 2387 mm; neggemaat: 0 mm; Other - berekende_negge: 600 mm; Fire Protection(Type) - brand_zelfsluitend: no; brandw_120min: no; brandw_30min: no; brandw_60min: no; brandw_90min: no; deur_dikte: 40 mm; fire_rating: zie bijbehorende samenstelling; Text(Type) - rep_stijl_breedte: 67 mm; rep_stijl_diepte: 125 mm; rep_tussenstijl_breedte: 67 mm; rep_zelfsl.: yes; rep_zelfsluitend: ja; Constraints(Type) - deur_breedte: 914 mm; ruimte_onder_deur: 20 mm; Construction(Type) - Function: Interior; Construction Type: wandopening met kozijn; dorpel: no; sponning_breedte: 17 mm; sponning_diepte: 50 mm; stijl_breedte: 67 mm; stijl_diepte: 125 mm; Wall Closure: By host; zelfsluitend: yes; Dimensions(Type) - deur_hoogte: 2315 mm; dikte_onderdorpel: 5 mm; dubbele_deur: yes; Rough Width: 0 mm; Identity Data(Type) - Fire Rating: zie bijbehorende samenstelling; Model: BI-A6; OmniClass Number: 23.30.10.00; OmniClass Title: Doors; SmartRevit_Versie: 2013.2; Type Comments: wandopening met samenstelling; Other(Type) - config_dubbel: 300_32_ISR_samenstelling_binnenkozijn_hout : dubbele deur met glas; config_enkel: 300_32_ISR_samenstelling_binnenkozijn_hout : enkele deur met glas; deur_config: 300_32_ISR_samenstelling_binnenkozijn_hout : dubbele deur met glas
Basic Wall:NLRS_22_WA_HSB bispouw 30-245-12-13 glaswol_gen_ISR:2729110 | 00 begane grond | 21.10 Uniformat (Uniformat) | 00 begane grond | -17 | 2. nieuwbouw | 16.4352 | 3008 | 4175 | Workset1 | 381 | Windows | NLRS_31_WI_WB_sparingmaker_generiek_BDG | NLRS_31_WI_WB_sparingmaker_generiek_BDG: mw_hsb_raam negge 180_alu gym | 2991 | 2729820 | mw_hsb_raam negge 180_alu gym | 4323309 | <None> | Schematic Type | 31 | 20160502 | buitenblad Detail | 105 | mw_hsb_raam negge 180_alu gym | Family : Windows : NLRS_31_WI_WB_sparingmaker_generiek_BDG | Windows | NLRS_31_WI_WB_sparingmaker_generiek_BDG | General - samenstelling: NLRS_31_WI_UN_samenstelling_leeg_generiek_ISR : std; Dimensions - NLRS_C_breedte: 4175 mm; NLRS_C_hoogte: 3008 mm; Layers(Type) - binnenblad_afwerking_boven: yes; binnenblad_afwerking_boven_hoek_links: 0 deg; binnenblad_afwerking_boven_hoek_rechts: 0 deg; binnenblad_afwerking_boven_plaatsing_y: 17 mm; binnenblad_afwerking_boven_type: NLRS_41_GM_WPB_multiplex-SH_generiek_ISR : 214x10; binnenblad_afwerking_boven_verlenging_links: -165 mm; binnenblad_afwerking_boven_verlenging_rechts: -165 mm; binnenblad_afwerking_links: yes; binnenblad_afwerking_links_hoek_boven: 0 deg; binnenblad_afwerking_links_hoek_onder: 0 deg; binnenblad_afwerking_links_plaatsing_y: 148 mm; binnenblad_afwerking_links_type: NLRS_41_GM_WPB_multiplex-SH_generiek_ISR : 214x10; binnenblad_afwerking_links_verlenging_boven: -27 mm; binnenblad_afwerking_links_verlenging_onder: -63 mm; binnenblad_afwerking_plaatsing_x: 149 mm; binnenblad_afwerking_rechts: yes; binnenblad_afwerking_rechts_hoek_boven: 0 deg; binnenblad_afwerking_rechts_hoek_onder: 0 deg; binnenblad_afwerking_rechts_plaatsing_y: 148 mm; binnenblad_afwerking_rechts_type: NLRS_41_GM_WPB_multiplex-SH_generiek_ISR : 214x10; binnenblad_afwerking_rechts_verlenging_boven: -27 mm; binnenblad_afwerking_rechts_verlenging_onder: -63 mm; buitenblad_afwerking_boven: no; buitenblad_afwerking_boven_hoek_links: 0 deg; buitenblad_afwerking_boven_hoek_rechts: 0 deg; buitenblad_afwerking_boven_plaatsing_y: 0 mm; buitenblad_afwerking_boven_type: NLRS_41_GM_WPB_omgezet metselwerk-SH_generiek_ISR : std; buitenblad_afwerking_boven_verlenging_links: 0 mm; buitenblad_afwerking_boven_verlenging_rechts: 0 mm; buitenblad_afwerking_links: no; buitenblad_afwerking_links_hoek_boven: 0 deg; buitenblad_afwerking_links_hoek_onder: 0 deg; buitenblad_afwerking_links_plaatsing_y: 0 mm; buitenblad_afwerking_links_type: NLRS_41_GM_WPB_omgezet metselwerk-SH_generiek_ISR : std; buitenblad_afwerking_links_verlenging_boven: 0 mm; buitenblad_afwerking_links_verlenging_onder: 0 mm; buitenblad_afwerking_plaatsing_x: 0 mm; buitenblad_afwerking_rechts: no; buitenblad_afwerking_rechts_hoek_boven: 0 deg; buitenblad_afwerking_rechts_hoek_onder: 0 deg; buitenblad_afwerking_rechts_plaatsing_y: 0 mm; buitenblad_afwerking_rechts_type: NLRS_41_GM_WPB_omgezet metselwerk-SH_generiek_ISR : std; buitenblad_afwerking_rechts_verlenging_boven: 0 mm; buitenblad_afwerking_rechts_verlenging_onder: 0 mm; Constraints(Type) - lossing_binnenblad: 0 mm; offset_binnenblad_boven: 148 mm; offset_binnenblad_links: 131 mm; offset_binnenblad_onder: 73 mm; offset_binnenblad_rechts: 131 mm; offset_binnenbladbeplating_boven: 17 mm; offset_binnenbladbeplating_links: 148 mm; offset_binnenbladbeplating_onder: 17 mm; offset_binnenbladbeplating_rechts: 148 mm; offset_buitenblad_boven: 12 mm; offset_buitenblad_links: 7 mm; offset_buitenblad_onder: 70 mm; offset_buitenblad_rechts: 7 mm; offset_isolatie_boven: 48 mm; offset_isolatie_links: 28 mm; offset_isolatie_onder: 28 mm; offset_isolatie_rechts: 28 mm; Structural(Type) - rekje: no; rekje_plaatsing_x: 0 mm; rekje_plaatsing_y: 0 mm; rekje_type: NLRS_41_GM_WPB_rekje-SH_generiek_ISR : std; rekje_verlenging_links: 200 mm; rekje_verlenging_rechts: 200 mm; spouwlat_boven: yes; spouwlat_boven_plaatsing_y: -17 mm; spouwlat_boven_type: NLRS_41_GM_WPB_spouwlat_isolatie_gen_bdg : 187x38 + isolatie 127x200; spouwlat_boven_verlenging_links: 28 mm; spouwlat_boven_verlenging_rechts: 28 mm; spouwlat_links: yes; spouwlat_links_plaatsing_y: -17 mm; spouwlat_links_type: NLRS_41_GM_WPB_spouwlat_isolatie_gen_bdg : 187x38 + isolatie 110x180; spouwlat_links_verlenging_boven: -17 mm; spouwlat_links_verlenging_onder: -17 mm; spouwlat_onder: yes; spouwlat_onder_plaatsing_y: -17 mm; spouwlat_onder_type: NLRS_41_GM_WPB_spouwlat-SH_generiek_ISR : 185x45; spouwlat_onder_verlenging_links: 28 mm; spouwlat_onder_verlenging_rechts: 28 mm; spouwlat_plaatsing_x: -275 mm; spouwlat_rechts: yes; spouwlat_rechts_plaatsing_y: -17 mm; spouwlat_rechts_type: NLRS_41_GM_WPB_spouwlat_isolatie_gen_bdg : 187x38 + isolatie 110x180; spouwlat_rechts_verlenging_boven: -17 mm; spouwlat_rechts_verlenging_onder: -17 mm; Materials and Finishes(Type) - geveldrager: yes; geveldrager_hoek_a: 0 deg; geveldrager_hoek_b: 0 deg; geveldrager_plaatsing_x: -10 mm; geveldrager_plaatsing_y: 8 mm; geveldrager_type: NLRS_41_SF_LIB_latei_staal_generiek_ISR : 90x150; geveldrager_verlenging_a: 0 mm; geveldrager_verlenging_b: 0 mm; latei: no; latei_hoek_a: 0 deg; latei_hoek_b: 0 deg; latei_plaatsing_x: 0 mm; latei_plaatsing_y: 0 mm; latei_type: NLRS_41_SF_LIB_latei_beton_generiek_ISR : 150x100; latei_verlenging_a: 100 mm; latei_verlenging_b: 100 mm; vensterbank: no; vensterbank_hoek_a: 0 deg; vensterbank_hoek_b: 0 deg; vensterbank_plaatsing_x: 149 mm; vensterbank_plaatsing_y: 17 mm; vensterbank_type: NLRS_42_GM_WPB_vensterbank_natuursteen-SH_generiek_ISR : 180x18 vensterbank composiet; vensterbank_verlenging_a: -45 mm; vensterbank_verlenging_b: -45 mm; waterslag: yes; waterslag_hoek_a: 0 deg; waterslag_hoek_b: 0 deg; waterslag_plaatsing_x: -155 mm; waterslag_plaatsing_y: 28 mm; waterslag_type: NLRS_41_GM_WPB_kantplank-geisoleerd_generiek_ISR : 10+120isol; waterslag_verlenging_a: 0 mm; waterslag_verlenging_b: 0 mm; Graphics(Type) - doorval_hoek_links: 0 deg; doorval_hoek_rechts: 0 deg; doorval_plaatsing_x: 30 mm; doorval_plaatsing_y: 300 mm; doorval_type: NLRS_41_GM_WPB_doorvalbeveiliging-SH_generiek_ISR : std; doorval_verlenging_links: 0 mm; doorval_verlenging_rechts: 0 mm; doorvalbeveiliging: no; ventilatie: no; ventilatie_plaatsing_x: 114 mm; ventilatie_plaatsing_y: 0 mm; ventilatie_type: NLRS_41_GM_WPB_ventilatie-SH_topstream_ISR : std; ventilatie_verlenging_links: 0 mm; ventilatie_verlenging_rechts: 0 mm; Construction(Type) - binnenblad_beplating: 125 mm; binnenblad_hout: 275 mm; buitenblad: 100 mm; isolatie: 10 mm; luchtspouw: 30 mm; negge: 215 mm; Dimensions(Type) - binnenbladhost: yes; buitenbladhost: no; clashobject: no; wrapping_exterior: 0 mm; wrapping_interior: 0 mm; Identity Data(Type) - Assembly Description: buitenwandopeningen; Other(Type) - a_binnen_boven_1: 148 mm; a_binnen_boven_2: 148 mm; a_binnen_links_1: 131 mm; a_binnen_links_2: 131 mm; a_binnen_onder_1: 73 mm; a_binnen_onder_2: 73 mm; a_binnen_rechts_1: 131 mm; a_binnen_rechts_2: 131 mm; a_binnenbepl_boven_1: 17 mm; a_binnenbepl_links_1: 148 mm; a_binnenbepl_onder_1: 17 mm; a_binnenbepl_rechts_1: 148 mm; a_binnenwand_afwerking_boven_y: 17 mm; a_binnenwand_afwerking_links_y: 148 mm; a_binnenwand_afwerking_rechts_y: 148 mm; a_binnenwand_afwerking_x: 149 mm; a_buitenblad_boven: 12 mm; a_buitenblad_boven_y: 0 mm; a_buitenblad_links: 7 mm; a_buitenblad_links_y: 0 mm; a_buitenblad_onder: 70 mm; a_buitenblad_rechts: 7 mm; a_buitenblad_rechts_y: 0 mm; a_buitenblad_x: 0 mm; a_doorval_x: 30 mm; a_doorval_y: 300 mm; a_geveldrager_x: 10 mm; a_geveldrager_y: 8 mm; a_isolatie_boven: 48 mm; a_isolatie_links: 28 mm; a_isolatie_onder: 28 mm; a_isolatie_rechts: 28 mm; a_latei_x: 0 mm; a_latei_y: 0 mm; a_rekje_x: 0 mm; a_rekje_y: 0 mm; a_spouwlat_boven_y: 17 mm; a_spouwlat_links_y: 17 mm; a_spouwlat_onder_y: 17 mm; a_spouwlat_rechts_y: 17 mm; a_spouwlat_x: 275 mm; a_vensterbank_x: 149 mm; a_vensterbank_y: 17 mm; a_ventilatie_x: 114 mm; a_ventilatie_y: 0 mm; a_waterslag_x: 155 mm; a_waterslag_y: 28 mm; b_binnen_boven_1: 296 mm; b_binnen_boven_2: 296 mm; b_binnen_links_1: 262 mm; b_binnen_links_2: 262 mm; b_binnen_onder_1: 146 mm; b_binnen_onder_2: 146 mm; b_binnen_rechts_1: 262 mm; b_binnen_rechts_2: 262 mm; b_binnenwand_afwerking_boven_y: 34 mm; b_binnenwand_afwerking_links_y: 296 mm; b_binnenwand_afwerking_rechts_y: 296 mm; b_binnenwand_afwerking_x: 298 mm; b_buitenblad_boven: 24 mm; b_buitenblad_boven_y: 0 mm; b_buitenblad_links: 14 mm; b_buitenblad_links_y: 0 mm; b_buitenblad_onder: 140 mm; b_buitenblad_rechts: 14 mm; b_buitenblad_rechts_y: 0 mm; b_buitenblad_x: 0 mm; b_doorval_x: 60 mm; b_doorval_y: 600 mm; b_geveldrager_x: 0 mm; b_geveldrager_y: 16 mm; b_isolatie_boven: 96 mm; b_isolatie_links: 56 mm; b_isolatie_onder: 56 mm; b_isolatie_rechts: 56 mm; b_latei_x: 0 mm; b_latei_y: 0 mm; b_rekje_x: 0 mm; b_rekje_y: 0 mm; b_spouwlat_boven_y: 0 mm; b_spouwlat_links_y: 0 mm; b_spouwlat_onder_y: 0 mm; b_spouwlat_rechts_y: 0 mm; b_spouwlat_x: 0 mm; b_vensterbank_x: 298 mm; b_vensterbank_y: 34 mm; b_ventilatie_x: 228 mm; b_ventilatie_y: 0 mm; b_waterslag_x: 0 mm; b_waterslag_y: 56 mm; berekende_binnen-buiten_host: 140 mm; offset_binnenblad_boven_2: 148 mm; offset_binnenblad_links_2: 131 mm; offset_binnenblad_onder_2: 73 mm; offset_binnenblad_rechts_2: 131 mm
Basic Wall:NLRS_22_WA_HSB bispouw 30-245-12-13 glaswol_gen_ISR:2729456 | 00 begane grond | 21.10 Uniformat (Uniformat) | 00 begane grond | -17 | 2. nieuwbouw | 4.95962 | 3008 | 900 | Workset1 | 375 | Windows | NLRS_31_WI_WB_sparingmaker_generiek_BDG | NLRS_31_WI_WB_sparingmaker_generiek_BDG: mw_hsb_raam negge 180_alu gym | 2991 | 2729110 | mw_hsb_raam negge 180_alu gym | 4323309 | <None> | Schematic Type | 31 | 20160502 | buitenblad Detail | 105 | mw_hsb_raam negge 180_alu gym | Family : Windows : NLRS_31_WI_WB_sparingmaker_generiek_BDG | Windows | NLRS_31_WI_WB_sparingmaker_generiek_BDG | General - samenstelling: NLRS_31_WI_UN_samenstelling_leeg_generiek_ISR : std; Dimensions - NLRS_C_breedte: 900 mm; NLRS_C_hoogte: 3008 mm; Layers(Type) - binnenblad_afwerking_boven: yes; binnenblad_afwerking_boven_hoek_links: 0 deg; binnenblad_afwerking_boven_hoek_rechts: 0 deg; binnenblad_afwerking_boven_plaatsing_y: 17 mm; binnenblad_afwerking_boven_type: NLRS_41_GM_WPB_multiplex-SH_generiek_ISR : 214x10; binnenblad_afwerking_boven_verlenging_links: -165 mm; binnenblad_afwerking_boven_verlenging_rechts: -165 mm; binnenblad_afwerking_links: yes; binnenblad_afwerking_links_hoek_boven: 0 deg; binnenblad_afwerking_links_hoek_onder: 0 deg; binnenblad_afwerking_links_plaatsing_y: 148 mm; binnenblad_afwerking_links_type: NLRS_41_GM_WPB_multiplex-SH_generiek_ISR : 214x10; binnenblad_afwerking_links_verlenging_boven: -27 mm; binnenblad_afwerking_links_verlenging_onder: -63 mm; binnenblad_afwerking_plaatsing_x: 149 mm; binnenblad_afwerking_rechts: yes; binnenblad_afwerking_rechts_hoek_boven: 0 deg; binnenblad_afwerking_rechts_hoek_onder: 0 deg; binnenblad_afwerking_rechts_plaatsing_y: 148 mm; binnenblad_afwerking_rechts_type: NLRS_41_GM_WPB_multiplex-SH_generiek_ISR : 214x10; binnenblad_afwerking_rechts_verlenging_boven: -27 mm; binnenblad_afwerking_rechts_verlenging_onder: -63 mm; buitenblad_afwerking_boven: no; buitenblad_afwerking_boven_hoek_links: 0 deg; buitenblad_afwerking_boven_hoek_rechts: 0 deg; buitenblad_afwerking_boven_plaatsing_y: 0 mm; buitenblad_afwerking_boven_type: NLRS_41_GM_WPB_omgezet metselwerk-SH_generiek_ISR : std; buitenblad_afwerking_boven_verlenging_links: 0 mm; buitenblad_afwerking_boven_verlenging_rechts: 0 mm; buitenblad_afwerking_links: no; buitenblad_afwerking_links_hoek_boven: 0 deg; buitenblad_afwerking_links_hoek_onder: 0 deg; buitenblad_afwerking_links_plaatsing_y: 0 mm; buitenblad_afwerking_links_type: NLRS_41_GM_WPB_omgezet metselwerk-SH_generiek_ISR : std; buitenblad_afwerking_links_verlenging_boven: 0 mm; buitenblad_afwerking_links_verlenging_onder: 0 mm; buitenblad_afwerking_plaatsing_x: 0 mm; buitenblad_afwerking_rechts: no; buitenblad_afwerking_rechts_hoek_boven: 0 deg; buitenblad_afwerking_rechts_hoek_onder: 0 deg; buitenblad_afwerking_rechts_plaatsing_y: 0 mm; buitenblad_afwerking_rechts_type: NLRS_41_GM_WPB_omgezet metselwerk-SH_generiek_ISR : std; buitenblad_afwerking_rechts_verlenging_boven: 0 mm; buitenblad_afwerking_rechts_verlenging_onder: 0 mm; Constraints(Type) - lossing_binnenblad: 0 mm; offset_binnenblad_boven: 148 mm; offset_binnenblad_links: 131 mm; offset_binnenblad_onder: 73 mm; offset_binnenblad_rechts: 131 mm; offset_binnenbladbeplating_boven: 17 mm; offset_binnenbladbeplating_links: 148 mm; offset_binnenbladbeplating_onder: 17 mm; offset_binnenbladbeplating_rechts: 148 mm; offset_buitenblad_boven: 12 mm; offset_buitenblad_links: 7 mm; offset_buitenblad_onder: 70 mm; offset_buitenblad_rechts: 7 mm; offset_isolatie_boven: 48 mm; offset_isolatie_links: 28 mm; offset_isolatie_onder: 28 mm; offset_isolatie_rechts: 28 mm; Structural(Type) - rekje: no; rekje_plaatsing_x: 0 mm; rekje_plaatsing_y: 0 mm; rekje_type: NLRS_41_GM_WPB_rekje-SH_generiek_ISR : std; rekje_verlenging_links: 200 mm; rekje_verlenging_rechts: 200 mm; spouwlat_boven: yes; spouwlat_boven_plaatsing_y: -17 mm; spouwlat_boven_type: NLRS_41_GM_WPB_spouwlat_isolatie_gen_bdg : 187x38 + isolatie 127x200; spouwlat_boven_verlenging_links: 28 mm; spouwlat_boven_verlenging_rechts: 28 mm; spouwlat_links: yes; spouwlat_links_plaatsing_y: -17 mm; spouwlat_links_type: NLRS_41_GM_WPB_spouwlat_isolatie_gen_bdg : 187x38 + isolatie 110x180; spouwlat_links_verlenging_boven: -17 mm; spouwlat_links_verlenging_onder: -17 mm; spouwlat_onder: yes; spouwlat_onder_plaatsing_y: -17 mm; spouwlat_onder_type: NLRS_41_GM_WPB_spouwlat-SH_generiek_ISR : 185x45; spouwlat_onder_verlenging_links: 28 mm; spouwlat_onder_verlenging_rechts: 28 mm; spouwlat_plaatsing_x: -275 mm; spouwlat_rechts: yes; spouwlat_rechts_plaatsing_y: -17 mm; spouwlat_rechts_type: NLRS_41_GM_WPB_spouwlat_isolatie_gen_bdg : 187x38 + isolatie 110x180; spouwlat_rechts_verlenging_boven: -17 mm; spouwlat_rechts_verlenging_onder: -17 mm; Materials and Finishes(Type) - geveldrager: yes; geveldrager_hoek_a: 0 deg; geveldrager_hoek_b: 0 deg; geveldrager_plaatsing_x: -10 mm; geveldrager_plaatsing_y: 8 mm; geveldrager_type: NLRS_41_SF_LIB_latei_staal_generiek_ISR : 90x150; geveldrager_verlenging_a: 0 mm; geveldrager_verlenging_b: 0 mm; latei: no; latei_hoek_a: 0 deg; latei_hoek_b: 0 deg; latei_plaatsing_x: 0 mm; latei_plaatsing_y: 0 mm; latei_type: NLRS_41_SF_LIB_latei_beton_generiek_ISR : 150x100; latei_verlenging_a: 100 mm; latei_verlenging_b: 100 mm; vensterbank: no; vensterbank_hoek_a: 0 deg; vensterbank_hoek_b: 0 deg; vensterbank_plaatsing_x: 149 mm; vensterbank_plaatsing_y: 17 mm; vensterbank_type: NLRS_42_GM_WPB_vensterbank_natuursteen-SH_generiek_ISR : 180x18 vensterbank composiet; vensterbank_verlenging_a: -45 mm; vensterbank_verlenging_b: -45 mm; waterslag: yes; waterslag_hoek_a: 0 deg; waterslag_hoek_b: 0 deg; waterslag_plaatsing_x: -155 mm; waterslag_plaatsing_y: 28 mm; waterslag_type: NLRS_41_GM_WPB_kantplank-geisoleerd_generiek_ISR : 10+120isol; waterslag_verlenging_a: 0 mm; waterslag_verlenging_b: 0 mm; Graphics(Type) - doorval_hoek_links: 0 deg; doorval_hoek_rechts: 0 deg; doorval_plaatsing_x: 30 mm; doorval_plaatsing_y: 300 mm; doorval_type: NLRS_41_GM_WPB_doorvalbeveiliging-SH_generiek_ISR : std; doorval_verlenging_links: 0 mm; doorval_verlenging_rechts: 0 mm; doorvalbeveiliging: no; ventilatie: no; ventilatie_plaatsing_x: 114 mm; ventilatie_plaatsing_y: 0 mm; ventilatie_type: NLRS_41_GM_WPB_ventilatie-SH_topstream_ISR : std; ventilatie_verlenging_links: 0 mm; ventilatie_verlenging_rechts: 0 mm; Construction(Type) - binnenblad_beplating: 125 mm; binnenblad_hout: 275 mm; buitenblad: 100 mm; isolatie: 10 mm; luchtspouw: 30 mm; negge: 215 mm; Dimensions(Type) - binnenbladhost: yes; buitenbladhost: no; clashobject: no; wrapping_exterior: 0 mm; wrapping_interior: 0 mm; Identity Data(Type) - Assembly Description: buitenwandopeningen; Other(Type) - a_binnen_boven_1: 148 mm; a_binnen_boven_2: 148 mm; a_binnen_links_1: 131 mm; a_binnen_links_2: 131 mm; a_binnen_onder_1: 73 mm; a_binnen_onder_2: 73 mm; a_binnen_rechts_1: 131 mm; a_binnen_rechts_2: 131 mm; a_binnenbepl_boven_1: 17 mm; a_binnenbepl_links_1: 148 mm; a_binnenbepl_onder_1: 17 mm; a_binnenbepl_rechts_1: 148 mm; a_binnenwand_afwerking_boven_y: 17 mm; a_binnenwand_afwerking_links_y: 148 mm; a_binnenwand_afwerking_rechts_y: 148 mm; a_binnenwand_afwerking_x: 149 mm; a_buitenblad_boven: 12 mm; a_buitenblad_boven_y: 0 mm; a_buitenblad_links: 7 mm; a_buitenblad_links_y: 0 mm; a_buitenblad_onder: 70 mm; a_buitenblad_rechts: 7 mm; a_buitenblad_rechts_y: 0 mm; a_buitenblad_x: 0 mm; a_doorval_x: 30 mm; a_doorval_y: 300 mm; a_geveldrager_x: 10 mm; a_geveldrager_y: 8 mm; a_isolatie_boven: 48 mm; a_isolatie_links: 28 mm; a_isolatie_onder: 28 mm; a_isolatie_rechts: 28 mm; a_latei_x: 0 mm; a_latei_y: 0 mm; a_rekje_x: 0 mm; a_rekje_y: 0 mm; a_spouwlat_boven_y: 17 mm; a_spouwlat_links_y: 17 mm; a_spouwlat_onder_y: 17 mm; a_spouwlat_rechts_y: 17 mm; a_spouwlat_x: 275 mm; a_vensterbank_x: 149 mm; a_vensterbank_y: 17 mm; a_ventilatie_x: 114 mm; a_ventilatie_y: 0 mm; a_waterslag_x: 155 mm; a_waterslag_y: 28 mm; b_binnen_boven_1: 296 mm; b_binnen_boven_2: 296 mm; b_binnen_links_1: 262 mm; b_binnen_links_2: 262 mm; b_binnen_onder_1: 146 mm; b_binnen_onder_2: 146 mm; b_binnen_rechts_1: 262 mm; b_binnen_rechts_2: 262 mm; b_binnenwand_afwerking_boven_y: 34 mm; b_binnenwand_afwerking_links_y: 296 mm; b_binnenwand_afwerking_rechts_y: 296 mm; b_binnenwand_afwerking_x: 298 mm; b_buitenblad_boven: 24 mm; b_buitenblad_boven_y: 0 mm; b_buitenblad_links: 14 mm; b_buitenblad_links_y: 0 mm; b_buitenblad_onder: 140 mm; b_buitenblad_rechts: 14 mm; b_buitenblad_rechts_y: 0 mm; b_buitenblad_x: 0 mm; b_doorval_x: 60 mm; b_doorval_y: 600 mm; b_geveldrager_x: 0 mm; b_geveldrager_y: 16 mm; b_isolatie_boven: 96 mm; b_isolatie_links: 56 mm; b_isolatie_onder: 56 mm; b_isolatie_rechts: 56 mm; b_latei_x: 0 mm; b_latei_y: 0 mm; b_rekje_x: 0 mm; b_rekje_y: 0 mm; b_spouwlat_boven_y: 0 mm; b_spouwlat_links_y: 0 mm; b_spouwlat_onder_y: 0 mm; b_spouwlat_rechts_y: 0 mm; b_spouwlat_x: 0 mm; b_vensterbank_x: 298 mm; b_vensterbank_y: 34 mm; b_ventilatie_x: 228 mm; b_ventilatie_y: 0 mm; b_waterslag_x: 0 mm; b_waterslag_y: 56 mm; berekende_binnen-buiten_host: 140 mm; offset_binnenblad_boven_2: 148 mm; offset_binnenblad_links_2: 131 mm; offset_binnenblad_onder_2: 73 mm; offset_binnenblad_rechts_2: 131 mm
Basic Wall:NLRS_22_WA_HSB bispouw 30-245-12-13 glaswol_gen_ISR:2729456 | 00 begane grond | 21.10 Uniformat (Uniformat) | 00 begane grond | -17 | 2. nieuwbouw | 16.4352 | 3008 | 4175 | Workset1 | 381 | Windows | NLRS_31_WI_WB_sparingmaker_generiek_BDG | NLRS_31_WI_WB_sparingmaker_generiek_BDG: mw_hsb_raam negge 180_alu gym | 2991 | 2729820 | mw_hsb_raam negge 180_alu gym | 4323309 | <None> | Schematic Type | 31 | 20160502 | buitenblad Detail | 105 | mw_hsb_raam negge 180_alu gym | Family : Windows : NLRS_31_WI_WB_sparingmaker_generiek_BDG | Windows | NLRS_31_WI_WB_sparingmaker_generiek_BDG | General - samenstelling: NLRS_31_WI_UN_samenstelling_leeg_generiek_ISR : std; Dimensions - NLRS_C_breedte: 4175 mm; NLRS_C_hoogte: 3008 mm; Layers(Type) - binnenblad_afwerking_boven: yes; binnenblad_afwerking_boven_hoek_links: 0 deg; binnenblad_afwerking_boven_hoek_rechts: 0 deg; binnenblad_afwerking_boven_plaatsing_y: 17 mm; binnenblad_afwerking_boven_type: NLRS_41_GM_WPB_multiplex-SH_generiek_ISR : 214x10; binnenblad_afwerking_boven_verlenging_links: -165 mm; binnenblad_afwerking_boven_verlenging_rechts: -165 mm; binnenblad_afwerking_links: yes; binnenblad_afwerking_links_hoek_boven: 0 deg; binnenblad_afwerking_links_hoek_onder: 0 deg; binnenblad_afwerking_links_plaatsing_y: 148 mm; binnenblad_afwerking_links_type: NLRS_41_GM_WPB_multiplex-SH_generiek_ISR : 214x10; binnenblad_afwerking_links_verlenging_boven: -27 mm; binnenblad_afwerking_links_verlenging_onder: -63 mm; binnenblad_afwerking_plaatsing_x: 149 mm; binnenblad_afwerking_rechts: yes; binnenblad_afwerking_rechts_hoek_boven: 0 deg; binnenblad_afwerking_rechts_hoek_onder: 0 deg; binnenblad_afwerking_rechts_plaatsing_y: 148 mm; binnenblad_afwerking_rechts_type: NLRS_41_GM_WPB_multiplex-SH_generiek_ISR : 214x10; binnenblad_afwerking_rechts_verlenging_boven: -27 mm; binnenblad_afwerking_rechts_verlenging_onder: -63 mm; buitenblad_afwerking_boven: no; buitenblad_afwerking_boven_hoek_links: 0 deg; buitenblad_afwerking_boven_hoek_rechts: 0 deg; buitenblad_afwerking_boven_plaatsing_y: 0 mm; buitenblad_afwerking_boven_type: NLRS_41_GM_WPB_omgezet metselwerk-SH_generiek_ISR : std; buitenblad_afwerking_boven_verlenging_links: 0 mm; buitenblad_afwerking_boven_verlenging_rechts: 0 mm; buitenblad_afwerking_links: no; buitenblad_afwerking_links_hoek_boven: 0 deg; buitenblad_afwerking_links_hoek_onder: 0 deg; buitenblad_afwerking_links_plaatsing_y: 0 mm; buitenblad_afwerking_links_type: NLRS_41_GM_WPB_omgezet metselwerk-SH_generiek_ISR : std; buitenblad_afwerking_links_verlenging_boven: 0 mm; buitenblad_afwerking_links_verlenging_onder: 0 mm; buitenblad_afwerking_plaatsing_x: 0 mm; buitenblad_afwerking_rechts: no; buitenblad_afwerking_rechts_hoek_boven: 0 deg; buitenblad_afwerking_rechts_hoek_onder: 0 deg; buitenblad_afwerking_rechts_plaatsing_y: 0 mm; buitenblad_afwerking_rechts_type: NLRS_41_GM_WPB_omgezet metselwerk-SH_generiek_ISR : std; buitenblad_afwerking_rechts_verlenging_boven: 0 mm; buitenblad_afwerking_rechts_verlenging_onder: 0 mm; Constraints(Type) - lossing_binnenblad: 0 mm; offset_binnenblad_boven: 148 mm; offset_binnenblad_links: 131 mm; offset_binnenblad_onder: 73 mm; offset_binnenblad_rechts: 131 mm; offset_binnenbladbeplating_boven: 17 mm; offset_binnenbladbeplating_links: 148 mm; offset_binnenbladbeplating_onder: 17 mm; offset_binnenbladbeplating_rechts: 148 mm; offset_buitenblad_boven: 12 mm; offset_buitenblad_links: 7 mm; offset_buitenblad_onder: 70 mm; offset_buitenblad_rechts: 7 mm; offset_isolatie_boven: 48 mm; offset_isolatie_links: 28 mm; offset_isolatie_onder: 28 mm; offset_isolatie_rechts: 28 mm; Structural(Type) - rekje: no; rekje_plaatsing_x: 0 mm; rekje_plaatsing_y: 0 mm; rekje_type: NLRS_41_GM_WPB_rekje-SH_generiek_ISR : std; rekje_verlenging_links: 200 mm; rekje_verlenging_rechts: 200 mm; spouwlat_boven: yes; spouwlat_boven_plaatsing_y: -17 mm; spouwlat_boven_type: NLRS_41_GM_WPB_spouwlat_isolatie_gen_bdg : 187x38 + isolatie 127x200; spouwlat_boven_verlenging_links: 28 mm; spouwlat_boven_verlenging_rechts: 28 mm; spouwlat_links: yes; spouwlat_links_plaatsing_y: -17 mm; spouwlat_links_type: NLRS_41_GM_WPB_spouwlat_isolatie_gen_bdg : 187x38 + isolatie 110x180; spouwlat_links_verlenging_boven: -17 mm; spouwlat_links_verlenging_onder: -17 mm; spouwlat_onder: yes; spouwlat_onder_plaatsing_y: -17 mm; spouwlat_onder_type: NLRS_41_GM_WPB_spouwlat-SH_generiek_ISR : 185x45; spouwlat_onder_verlenging_links: 28 mm; spouwlat_onder_verlenging_rechts: 28 mm; spouwlat_plaatsing_x: -275 mm; spouwlat_rechts: yes; spouwlat_rechts_plaatsing_y: -17 mm; spouwlat_rechts_type: NLRS_41_GM_WPB_spouwlat_isolatie_gen_bdg : 187x38 + isolatie 110x180; spouwlat_rechts_verlenging_boven: -17 mm; spouwlat_rechts_verlenging_onder: -17 mm; Materials and Finishes(Type) - geveldrager: yes; geveldrager_hoek_a: 0 deg; geveldrager_hoek_b: 0 deg; geveldrager_plaatsing_x: -10 mm; geveldrager_plaatsing_y: 8 mm; geveldrager_type: NLRS_41_SF_LIB_latei_staal_generiek_ISR : 90x150; geveldrager_verlenging_a: 0 mm; geveldrager_verlenging_b: 0 mm; latei: no; latei_hoek_a: 0 deg; latei_hoek_b: 0 deg; latei_plaatsing_x: 0 mm; latei_plaatsing_y: 0 mm; latei_type: NLRS_41_SF_LIB_latei_beton_generiek_ISR : 150x100; latei_verlenging_a: 100 mm; latei_verlenging_b: 100 mm; vensterbank: no; vensterbank_hoek_a: 0 deg; vensterbank_hoek_b: 0 deg; vensterbank_plaatsing_x: 149 mm; vensterbank_plaatsing_y: 17 mm; vensterbank_type: NLRS_42_GM_WPB_vensterbank_natuursteen-SH_generiek_ISR : 180x18 vensterbank composiet; vensterbank_verlenging_a: -45 mm; vensterbank_verlenging_b: -45 mm; waterslag: yes; waterslag_hoek_a: 0 deg; waterslag_hoek_b: 0 deg; waterslag_plaatsing_x: -155 mm; waterslag_plaatsing_y: 28 mm; waterslag_type: NLRS_41_GM_WPB_kantplank-geisoleerd_generiek_ISR : 10+120isol; waterslag_verlenging_a: 0 mm; waterslag_verlenging_b: 0 mm; Graphics(Type) - doorval_hoek_links: 0 deg; doorval_hoek_rechts: 0 deg; doorval_plaatsing_x: 30 mm; doorval_plaatsing_y: 300 mm; doorval_type: NLRS_41_GM_WPB_doorvalbeveiliging-SH_generiek_ISR : std; doorval_verlenging_links: 0 mm; doorval_verlenging_rechts: 0 mm; doorvalbeveiliging: no; ventilatie: no; ventilatie_plaatsing_x: 114 mm; ventilatie_plaatsing_y: 0 mm; ventilatie_type: NLRS_41_GM_WPB_ventilatie-SH_topstream_ISR : std; ventilatie_verlenging_links: 0 mm; ventilatie_verlenging_rechts: 0 mm; Construction(Type) - binnenblad_beplating: 125 mm; binnenblad_hout: 275 mm; buitenblad: 100 mm; isolatie: 10 mm; luchtspouw: 30 mm; negge: 215 mm; Dimensions(Type) - binnenbladhost: yes; buitenbladhost: no; clashobject: no; wrapping_exterior: 0 mm; wrapping_interior: 0 mm; Identity Data(Type) - Assembly Description: buitenwandopeningen; Other(Type) - a_binnen_boven_1: 148 mm; a_binnen_boven_2: 148 mm; a_binnen_links_1: 131 mm; a_binnen_links_2: 131 mm; a_binnen_onder_1: 73 mm; a_binnen_onder_2: 73 mm; a_binnen_rechts_1: 131 mm; a_binnen_rechts_2: 131 mm; a_binnenbepl_boven_1: 17 mm; a_binnenbepl_links_1: 148 mm; a_binnenbepl_onder_1: 17 mm; a_binnenbepl_rechts_1: 148 mm; a_binnenwand_afwerking_boven_y: 17 mm; a_binnenwand_afwerking_links_y: 148 mm; a_binnenwand_afwerking_rechts_y: 148 mm; a_binnenwand_afwerking_x: 149 mm; a_buitenblad_boven: 12 mm; a_buitenblad_boven_y: 0 mm; a_buitenblad_links: 7 mm; a_buitenblad_links_y: 0 mm; a_buitenblad_onder: 70 mm; a_buitenblad_rechts: 7 mm; a_buitenblad_rechts_y: 0 mm; a_buitenblad_x: 0 mm; a_doorval_x: 30 mm; a_doorval_y: 300 mm; a_geveldrager_x: 10 mm; a_geveldrager_y: 8 mm; a_isolatie_boven: 48 mm; a_isolatie_links: 28 mm; a_isolatie_onder: 28 mm; a_isolatie_rechts: 28 mm; a_latei_x: 0 mm; a_latei_y: 0 mm; a_rekje_x: 0 mm; a_rekje_y: 0 mm; a_spouwlat_boven_y: 17 mm; a_spouwlat_links_y: 17 mm; a_spouwlat_onder_y: 17 mm; a_spouwlat_rechts_y: 17 mm; a_spouwlat_x: 275 mm; a_vensterbank_x: 149 mm; a_vensterbank_y: 17 mm; a_ventilatie_x: 114 mm; a_ventilatie_y: 0 mm; a_waterslag_x: 155 mm; a_waterslag_y: 28 mm; b_binnen_boven_1: 296 mm; b_binnen_boven_2: 296 mm; b_binnen_links_1: 262 mm; b_binnen_links_2: 262 mm; b_binnen_onder_1: 146 mm; b_binnen_onder_2: 146 mm; b_binnen_rechts_1: 262 mm; b_binnen_rechts_2: 262 mm; b_binnenwand_afwerking_boven_y: 34 mm; b_binnenwand_afwerking_links_y: 296 mm; b_binnenwand_afwerking_rechts_y: 296 mm; b_binnenwand_afwerking_x: 298 mm; b_buitenblad_boven: 24 mm; b_buitenblad_boven_y: 0 mm; b_buitenblad_links: 14 mm; b_buitenblad_links_y: 0 mm; b_buitenblad_onder: 140 mm; b_buitenblad_rechts: 14 mm; b_buitenblad_rechts_y: 0 mm; b_buitenblad_x: 0 mm; b_doorval_x: 60 mm; b_doorval_y: 600 mm; b_geveldrager_x: 0 mm; b_geveldrager_y: 16 mm; b_isolatie_boven: 96 mm; b_isolatie_links: 56 mm; b_isolatie_onder: 56 mm; b_isolatie_rechts: 56 mm; b_latei_x: 0 mm; b_latei_y: 0 mm; b_rekje_x: 0 mm; b_rekje_y: 0 mm; b_spouwlat_boven_y: 0 mm; b_spouwlat_links_y: 0 mm; b_spouwlat_onder_y: 0 mm; b_spouwlat_rechts_y: 0 mm; b_spouwlat_x: 0 mm; b_vensterbank_x: 298 mm; b_vensterbank_y: 34 mm; b_ventilatie_x: 228 mm; b_ventilatie_y: 0 mm; b_waterslag_x: 0 mm; b_waterslag_y: 56 mm; berekende_binnen-buiten_host: 140 mm; offset_binnenblad_boven_2: 148 mm; offset_binnenblad_links_2: 131 mm; offset_binnenblad_onder_2: 73 mm; offset_binnenblad_rechts_2: 131 mm
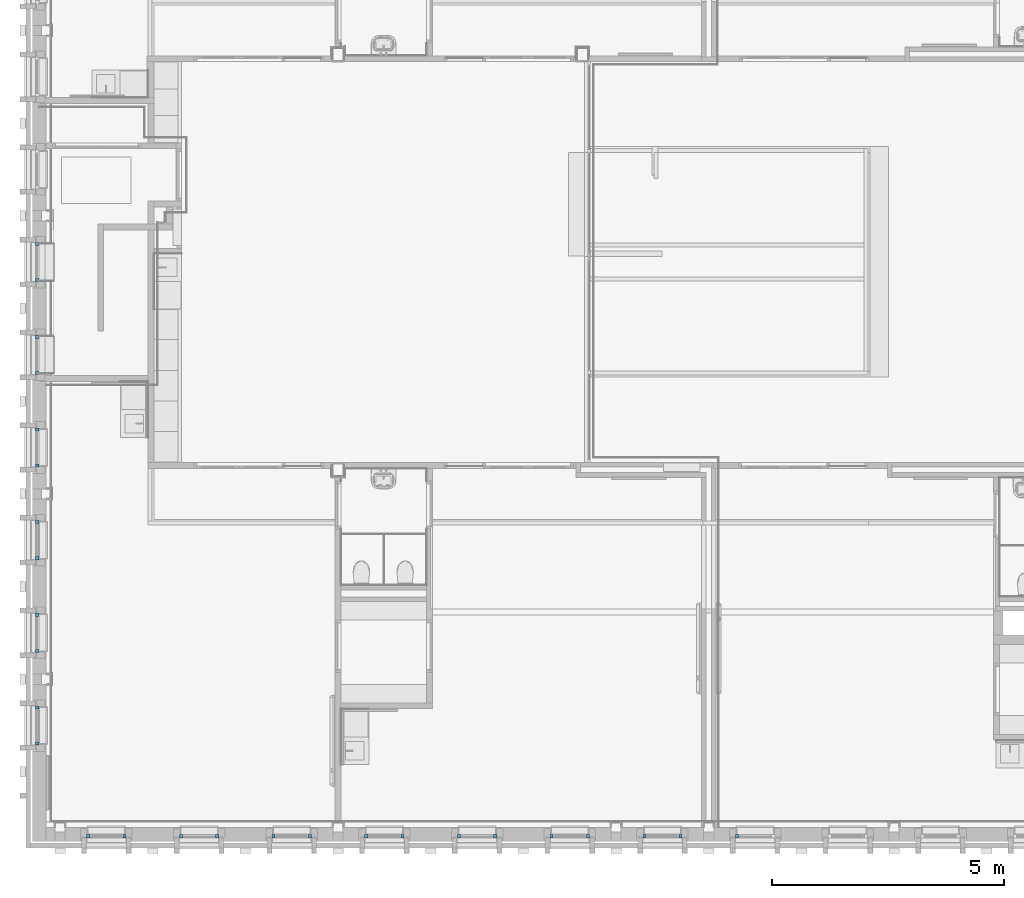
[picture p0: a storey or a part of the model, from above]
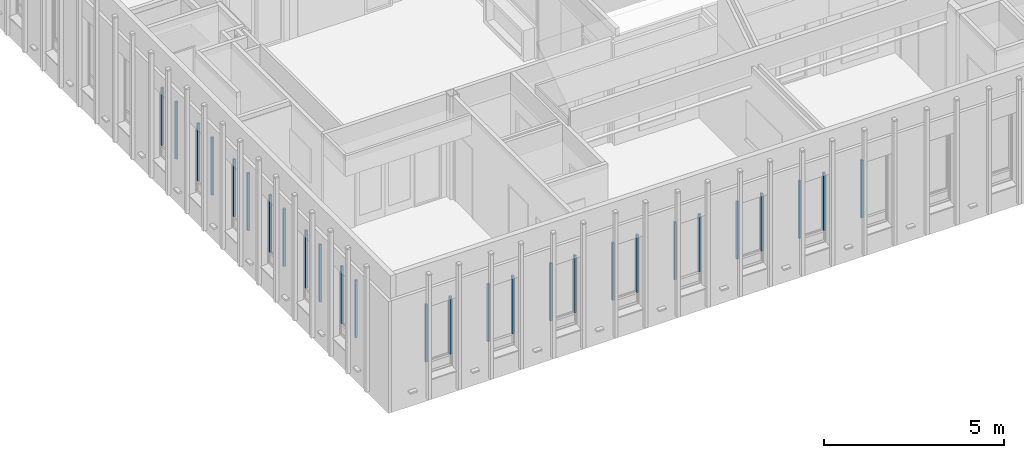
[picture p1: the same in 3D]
Properties of the parts of a building model (IFC2X3), part 74 of 94

# IfcOpeningElement: Opening (823)
Name | In | Classification | Level | Sill Height (mm) | Phase Created | Area (m2) | Height (mm) | Width (mm) | Identity Data, Workset | Mark | Other, Category | Family | Family and Type | Head Height (mm) | Host Id | Type | Type Id | Analytic Construction | Define Thermal Properties by | Assembly Code | Datum_Gewijzigd | Description | Type Mark | Type Name | Identity Data(Type), Workset | Other(Type), Category | Family Name
Basic Wall:22_WA_voorzetwand_ms100 25-75 _gen_bdg:2968116 | 00 begane grond | 2E(22.11) Uniformat (Uniformat) | 01 eerste verdieping | 850 | 2. nieuwbouw | 5.61642 | 2020 | 1771 | Workset1 | 192 | Windows | NLRS_31_WI_WB_sparingmaker_generiek_BDG | NLRS_31_WI_WB_sparingmaker_generiek_BDG: mw_hsb_raam negge 180_alu v1 trappenhuis | 2870 | 772577 | mw_hsb_raam negge 180_alu v1 trappenhuis | 4342109 | <None> | Schematic Type | 31 | 20160502 | buitenblad Detail | 106 | mw_hsb_raam negge 180_alu v1 trappenhuis | Family : Windows : NLRS_31_WI_WB_sparingmaker_generiek_BDG | Windows | NLRS_31_WI_WB_sparingmaker_generiek_BDG | General - samenstelling: NLRS_31_WI_UN_samenstelling_leeg_generiek_ISR : std; Dimensions - NLRS_C_breedte: 1771 mm; NLRS_C_hoogte: 2020 mm; Layers(Type) - binnenblad_afwerking_boven: yes; binnenblad_afwerking_boven_hoek_links: 0 deg; binnenblad_afwerking_boven_hoek_rechts: 0 deg; binnenblad_afwerking_boven_plaatsing_y: 17 mm; binnenblad_afwerking_boven_type: NLRS_41_GM_WPB_multiplex-SH_generiek_ISR : 306x10 gipsvezel dagkant; binnenblad_afwerking_boven_verlenging_links: -131.5 mm; binnenblad_afwerking_boven_verlenging_rechts: -131.5 mm; binnenblad_afwerking_links: yes; binnenblad_afwerking_links_hoek_boven: 0 deg; binnenblad_afwerking_links_hoek_onder: 0 deg; binnenblad_afwerking_links_plaatsing_y: 131.5 mm; binnenblad_afwerking_links_type: NLRS_41_GM_WPB_multiplex-SH_generiek_ISR : 306x10 gipsvezel dagkant; binnenblad_afwerking_links_verlenging_boven: -27 mm; binnenblad_afwerking_links_verlenging_onder: -94 mm; binnenblad_afwerking_plaatsing_x: 149 mm; binnenblad_afwerking_rechts: yes; binnenblad_afwerking_rechts_hoek_boven: 0 deg; binnenblad_afwerking_rechts_hoek_onder: 0 deg; binnenblad_afwerking_rechts_plaatsing_y: 131.5 mm; binnenblad_afwerking_rechts_type: NLRS_41_GM_WPB_multiplex-SH_generiek_ISR : 306x10 gipsvezel dagkant; binnenblad_afwerking_rechts_verlenging_boven: -27 mm; binnenblad_afwerking_rechts_verlenging_onder: -94 mm; buitenblad_afwerking_boven: no; buitenblad_afwerking_boven_hoek_links: 0 deg; buitenblad_afwerking_boven_hoek_rechts: 0 deg; buitenblad_afwerking_boven_plaatsing_y: 0 mm; buitenblad_afwerking_boven_type: NLRS_41_GM_WPB_omgezet metselwerk-SH_generiek_ISR : std; buitenblad_afwerking_boven_verlenging_links: 0 mm; buitenblad_afwerking_boven_verlenging_rechts: 0 mm; buitenblad_afwerking_links: no; buitenblad_afwerking_links_hoek_boven: 0 deg; buitenblad_afwerking_links_hoek_onder: 0 deg; buitenblad_afwerking_links_plaatsing_y: 0 mm; buitenblad_afwerking_links_type: NLRS_41_GM_WPB_omgezet metselwerk-SH_generiek_ISR : std; buitenblad_afwerking_links_verlenging_boven: 0 mm; buitenblad_afwerking_links_verlenging_onder: 0 mm; buitenblad_afwerking_plaatsing_x: 0 mm; buitenblad_afwerking_rechts: no; buitenblad_afwerking_rechts_hoek_boven: 0 deg; buitenblad_afwerking_rechts_hoek_onder: 0 deg; buitenblad_afwerking_rechts_plaatsing_y: 0 mm; buitenblad_afwerking_rechts_type: NLRS_41_GM_WPB_omgezet metselwerk-SH_generiek_ISR : std; buitenblad_afwerking_rechts_verlenging_boven: 0 mm; buitenblad_afwerking_rechts_verlenging_onder: 0 mm; Constraints(Type) - lossing_binnenblad: 0 mm; offset_binnenblad_boven: 148 mm; offset_binnenblad_links: 114.5 mm; offset_binnenblad_onder: 59 mm; offset_binnenblad_rechts: 114.5 mm; offset_binnenbladbeplating_boven: 17 mm; offset_binnenbladbeplating_links: 131.5 mm; offset_binnenbladbeplating_onder: 17 mm; offset_binnenbladbeplating_rechts: 131.5 mm; offset_buitenblad_boven: 7 mm; offset_buitenblad_links: 7 mm; offset_buitenblad_onder: 70 mm; offset_buitenblad_rechts: 7 mm; offset_isolatie_boven: 48 mm; offset_isolatie_links: 28 mm; offset_isolatie_onder: 21 mm; offset_isolatie_rechts: 21 mm; Structural(Type) - rekje: no; rekje_plaatsing_x: 0 mm; rekje_plaatsing_y: 0 mm; rekje_type: NLRS_41_GM_WPB_rekje-SH_generiek_ISR : std; rekje_verlenging_links: 200 mm; rekje_verlenging_rechts: 200 mm; spouwlat_boven: yes; spouwlat_boven_plaatsing_y: -17 mm; spouwlat_boven_type: NLRS_41_GM_WPB_spouwlat_isolatie_gen_bdg : 187x38 + isolatie 127x200; spouwlat_boven_verlenging_links: 112 mm; spouwlat_boven_verlenging_rechts: 112 mm; spouwlat_links: yes; spouwlat_links_plaatsing_y: -17 mm; spouwlat_links_type: NLRS_41_GM_WPB_spouwlat_isolatie_gen_bdg : 187x38 + isolatie 93.5x187; spouwlat_links_verlenging_boven: -17 mm; spouwlat_links_verlenging_onder: -17 mm; spouwlat_onder: yes; spouwlat_onder_plaatsing_y: -17 mm; spouwlat_onder_type: NLRS_41_GM_WPB_spouwlat-SH_generiek_ISR : 185x76; spouwlat_onder_verlenging_links: 112 mm; spouwlat_onder_verlenging_rechts: 112 mm; spouwlat_plaatsing_x: -275 mm; spouwlat_rechts: yes; spouwlat_rechts_plaatsing_y: -17 mm; spouwlat_rechts_type: NLRS_41_GM_WPB_spouwlat_isolatie_gen_bdg : 187x38 + isolatie 93.5x187; spouwlat_rechts_verlenging_boven: -17 mm; spouwlat_rechts_verlenging_onder: -17 mm; Materials and Finishes(Type) - geveldrager: yes; geveldrager_hoek_a: 0 deg; geveldrager_hoek_b: 0 deg; geveldrager_plaatsing_x: -10 mm; geveldrager_plaatsing_y: 3 mm; geveldrager_type: NLRS_41_SF_LIB_latei_staal_generiek_ISR : 90x150; geveldrager_verlenging_a: 0 mm; geveldrager_verlenging_b: 0 mm; latei: no; latei_hoek_a: 0 deg; latei_hoek_b: 0 deg; latei_plaatsing_x: 0 mm; latei_plaatsing_y: 0 mm; latei_type: NLRS_41_SF_LIB_latei_beton_generiek_ISR : 150x100; latei_verlenging_a: 100 mm; latei_verlenging_b: 100 mm; vensterbank: yes; vensterbank_hoek_a: 0 deg; vensterbank_hoek_b: 0 deg; vensterbank_plaatsing_x: 149 mm; vensterbank_plaatsing_y: 17 mm; vensterbank_type: NLRS_42_GM_WPB_vensterbank_natuursteen-SH_generiek_ISR : 335x18 vensterbank composiet; vensterbank_verlenging_a: -131.5 mm; vensterbank_verlenging_b: -131.5 mm; waterslag: yes; waterslag_hoek_a: 0 deg; waterslag_hoek_b: 0 deg; waterslag_plaatsing_x: -125 mm; waterslag_plaatsing_y: 83 mm; waterslag_type: NLRS_41_GM_WPB_waterslag barok-SH_roval_ISR : waterslag_roval_Types Barok_roval_b 320; waterslag_verlenging_a: 0 mm; waterslag_verlenging_b: 0 mm; Graphics(Type) - doorval_hoek_links: 0 deg; doorval_hoek_rechts: 0 deg; doorval_plaatsing_x: 30 mm; doorval_plaatsing_y: 300 mm; doorval_type: NLRS_41_GM_WPB_doorvalbeveiliging-SH_generiek_ISR : std; doorval_verlenging_links: 0 mm; doorval_verlenging_rechts: 0 mm; doorvalbeveiliging: no; ventilatie: no; ventilatie_plaatsing_x: 114 mm; ventilatie_plaatsing_y: 0 mm; ventilatie_type: NLRS_41_GM_WPB_ventilatie-SH_topstream_ISR : std; ventilatie_verlenging_links: 0 mm; ventilatie_verlenging_rechts: 0 mm; Construction(Type) - binnenblad_beplating: 200 mm; binnenblad_hout: 275 mm; buitenblad: 180 mm; isolatie: 10 mm; luchtspouw: 30 mm; negge: 215 mm; Dimensions(Type) - binnenbladhost: yes; buitenbladhost: no; clashobject: no; wrapping_exterior: 0 mm; wrapping_interior: 0 mm; Identity Data(Type) - Assembly Description: buitenwandopeningen; Other(Type) - a_binnen_boven_1: 148 mm; a_binnen_boven_2: 148 mm; a_binnen_links_1: 114.5 mm; a_binnen_links_2: 114.5 mm; a_binnen_onder_1: 59 mm; a_binnen_onder_2: 59 mm; a_binnen_rechts_1: 114.5 mm; a_binnen_rechts_2: 114.5 mm; a_binnenbepl_boven_1: 17 mm; a_binnenbepl_links_1: 131.5 mm; a_binnenbepl_onder_1: 17 mm; a_binnenbepl_rechts_1: 131.5 mm; a_binnenwand_afwerking_boven_y: 17 mm; a_binnenwand_afwerking_links_y: 131.5 mm; a_binnenwand_afwerking_rechts_y: 131.5 mm; a_binnenwand_afwerking_x: 149 mm; a_buitenblad_boven: 7 mm; a_buitenblad_boven_y: 0 mm; a_buitenblad_links: 7 mm; a_buitenblad_links_y: 0 mm; a_buitenblad_onder: 70 mm; a_buitenblad_rechts: 7 mm; a_buitenblad_rechts_y: 0 mm; a_buitenblad_x: 0 mm; a_doorval_x: 30 mm; a_doorval_y: 300 mm; a_geveldrager_x: 10 mm; a_geveldrager_y: 3 mm; a_isolatie_boven: 48 mm; a_isolatie_links: 28 mm; a_isolatie_onder: 21 mm; a_isolatie_rechts: 21 mm; a_latei_x: 0 mm; a_latei_y: 0 mm; a_rekje_x: 0 mm; a_rekje_y: 0 mm; a_spouwlat_boven_y: 17 mm; a_spouwlat_links_y: 17 mm; a_spouwlat_onder_y: 17 mm; a_spouwlat_rechts_y: 17 mm; a_spouwlat_x: 275 mm; a_vensterbank_x: 149 mm; a_vensterbank_y: 17 mm; a_ventilatie_x: 114 mm; a_ventilatie_y: 0 mm; a_waterslag_x: 125 mm; a_waterslag_y: 83 mm; b_binnen_boven_1: 296 mm; b_binnen_boven_2: 296 mm; b_binnen_links_1: 229 mm; b_binnen_links_2: 229 mm; b_binnen_onder_1: 118 mm; b_binnen_onder_2: 118 mm; b_binnen_rechts_1: 229 mm; b_binnen_rechts_2: 229 mm; b_binnenwand_afwerking_boven_y: 34 mm; b_binnenwand_afwerking_links_y: 263 mm; b_binnenwand_afwerking_rechts_y: 263 mm; b_binnenwand_afwerking_x: 298 mm; b_buitenblad_boven: 14 mm; b_buitenblad_boven_y: 0 mm; b_buitenblad_links: 14 mm; b_buitenblad_links_y: 0 mm; b_buitenblad_onder: 140 mm; b_buitenblad_rechts: 14 mm; b_buitenblad_rechts_y: 0 mm; b_buitenblad_x: 0 mm; b_doorval_x: 60 mm; b_doorval_y: 600 mm; b_geveldrager_x: 0 mm; b_geveldrager_y: 6 mm; b_isolatie_boven: 96 mm; b_isolatie_links: 56 mm; b_isolatie_onder: 42 mm; b_isolatie_rechts: 42 mm; b_latei_x: 0 mm; b_latei_y: 0 mm; b_rekje_x: 0 mm; b_rekje_y: 0 mm; b_spouwlat_boven_y: 0 mm; b_spouwlat_links_y: 0 mm; b_spouwlat_onder_y: 0 mm; b_spouwlat_rechts_y: 0 mm; b_spouwlat_x: 0 mm; b_vensterbank_x: 298 mm; b_vensterbank_y: 34 mm; b_ventilatie_x: 228 mm; b_ventilatie_y: 0 mm; b_waterslag_x: 0 mm; b_waterslag_y: 166 mm; berekende_binnen-buiten_host: 220 mm; offset_binnenblad_boven_2: 148 mm; offset_binnenblad_links_2: 114.5 mm; offset_binnenblad_onder_2: 59 mm; offset_binnenblad_rechts_2: 114.5 mm
Basic Wall:22_WA_voorzetwand_ms100 25-75 _gen_bdg:2968116 | 00 begane grond | 2E(22.11) Uniformat (Uniformat) | 01 eerste verdieping | 850 | 2. nieuwbouw | 5.56865 | 1970 | 1771 | Workset1 | 194 | Windows | NLRS_31_WI_WB_sparingmaker_generiek_BDG | NLRS_31_WI_WB_sparingmaker_generiek_BDG: mw_hsb_raam negge 180_alu v1 opbouwcorrectie | 2820 | 772577 | mw_hsb_raam negge 180_alu v1 opbouwcorrectie | 3475888 | <None> | Schematic Type | 31 | 20160502 | buitenblad Detail | 102 | mw_hsb_raam negge 180_alu v1 opbouwcorrectie | Family : Windows : NLRS_31_WI_WB_sparingmaker_generiek_BDG | Windows | NLRS_31_WI_WB_sparingmaker_generiek_BDG | General - samenstelling: NLRS_31_WI_UN_samenstelling_leeg_generiek_ISR : std; Dimensions - NLRS_C_breedte: 1771 mm; NLRS_C_hoogte: 1970 mm; Layers(Type) - binnenblad_afwerking_boven: yes; binnenblad_afwerking_boven_hoek_links: 0 deg; binnenblad_afwerking_boven_hoek_rechts: 0 deg; binnenblad_afwerking_boven_plaatsing_y: 17 mm; binnenblad_afwerking_boven_type: NLRS_41_GM_WPB_multiplex-SH_generiek_ISR : 151x10 gipsvezel dagkant; binnenblad_afwerking_boven_verlenging_links: -129 mm; binnenblad_afwerking_boven_verlenging_rechts: -129 mm; binnenblad_afwerking_links: yes; binnenblad_afwerking_links_hoek_boven: 0 deg; binnenblad_afwerking_links_hoek_onder: 0 deg; binnenblad_afwerking_links_plaatsing_y: 131.5 mm; binnenblad_afwerking_links_type: NLRS_41_GM_WPB_multiplex-SH_generiek_ISR : 151x10 gipsvezel dagkant; binnenblad_afwerking_links_verlenging_boven: -27 mm; binnenblad_afwerking_links_verlenging_onder: -94 mm; binnenblad_afwerking_plaatsing_x: 149 mm; binnenblad_afwerking_rechts: yes; binnenblad_afwerking_rechts_hoek_boven: 0 deg; binnenblad_afwerking_rechts_hoek_onder: 0 deg; binnenblad_afwerking_rechts_plaatsing_y: 131.5 mm; binnenblad_afwerking_rechts_type: NLRS_41_GM_WPB_multiplex-SH_generiek_ISR : 151x10 gipsvezel dagkant; binnenblad_afwerking_rechts_verlenging_boven: -27 mm; binnenblad_afwerking_rechts_verlenging_onder: -94 mm; buitenblad_afwerking_boven: no; buitenblad_afwerking_boven_hoek_links: 0 deg; buitenblad_afwerking_boven_hoek_rechts: 0 deg; buitenblad_afwerking_boven_plaatsing_y: 0 mm; buitenblad_afwerking_boven_type: NLRS_41_GM_WPB_omgezet metselwerk-SH_generiek_ISR : std; buitenblad_afwerking_boven_verlenging_links: 0 mm; buitenblad_afwerking_boven_verlenging_rechts: 0 mm; buitenblad_afwerking_links: no; buitenblad_afwerking_links_hoek_boven: 0 deg; buitenblad_afwerking_links_hoek_onder: 0 deg; buitenblad_afwerking_links_plaatsing_y: 0 mm; buitenblad_afwerking_links_type: NLRS_41_GM_WPB_omgezet metselwerk-SH_generiek_ISR : std; buitenblad_afwerking_links_verlenging_boven: 0 mm; buitenblad_afwerking_links_verlenging_onder: 0 mm; buitenblad_afwerking_plaatsing_x: 0 mm; buitenblad_afwerking_rechts: no; buitenblad_afwerking_rechts_hoek_boven: 0 deg; buitenblad_afwerking_rechts_hoek_onder: 0 deg; buitenblad_afwerking_rechts_plaatsing_y: 0 mm; buitenblad_afwerking_rechts_type: NLRS_41_GM_WPB_omgezet metselwerk-SH_generiek_ISR : std; buitenblad_afwerking_rechts_verlenging_boven: 0 mm; buitenblad_afwerking_rechts_verlenging_onder: 0 mm; Constraints(Type) - lossing_binnenblad: 0 mm; offset_binnenblad_boven: 177 mm; offset_binnenblad_links: 114.5 mm; offset_binnenblad_onder: 59 mm; offset_binnenblad_rechts: 114.5 mm; offset_binnenbladbeplating_boven: 17 mm; offset_binnenbladbeplating_links: 131.5 mm; offset_binnenbladbeplating_onder: 17 mm; offset_binnenbladbeplating_rechts: 131.5 mm; offset_buitenblad_boven: 12 mm; offset_buitenblad_links: 7 mm; offset_buitenblad_onder: 70 mm; offset_buitenblad_rechts: 7 mm; offset_isolatie_boven: 48 mm; offset_isolatie_links: 28 mm; offset_isolatie_onder: 21 mm; offset_isolatie_rechts: 21 mm; Structural(Type) - rekje: no; rekje_plaatsing_x: 0 mm; rekje_plaatsing_y: 0 mm; rekje_type: NLRS_41_GM_WPB_rekje-SH_generiek_ISR : std; rekje_verlenging_links: 200 mm; rekje_verlenging_rechts: 200 mm; spouwlat_boven: yes; spouwlat_boven_plaatsing_y: -17 mm; spouwlat_boven_type: NLRS_41_GM_WPB_spouwlat_isolatie_gen_bdg : 187x38 + isolatie 156x200; spouwlat_boven_verlenging_links: 112 mm; spouwlat_boven_verlenging_rechts: 112 mm; spouwlat_links: yes; spouwlat_links_plaatsing_y: -17 mm; spouwlat_links_type: NLRS_41_GM_WPB_spouwlat_isolatie_gen_bdg : 187x38 + isolatie 93.5x187; spouwlat_links_verlenging_boven: -17 mm; spouwlat_links_verlenging_onder: -17 mm; spouwlat_onder: yes; spouwlat_onder_plaatsing_y: -17 mm; spouwlat_onder_type: NLRS_41_GM_WPB_spouwlat-SH_generiek_ISR : 185x76; spouwlat_onder_verlenging_links: 112 mm; spouwlat_onder_verlenging_rechts: 112 mm; spouwlat_plaatsing_x: -275 mm; spouwlat_rechts: yes; spouwlat_rechts_plaatsing_y: -17 mm; spouwlat_rechts_type: NLRS_41_GM_WPB_spouwlat_isolatie_gen_bdg : 187x38 + isolatie 93.5x187; spouwlat_rechts_verlenging_boven: -17 mm; spouwlat_rechts_verlenging_onder: -17 mm; Materials and Finishes(Type) - geveldrager: yes; geveldrager_hoek_a: 0 deg; geveldrager_hoek_b: 0 deg; geveldrager_plaatsing_x: -10 mm; geveldrager_plaatsing_y: 3 mm; geveldrager_type: NLRS_41_SF_LIB_latei_staal_generiek_ISR : 90x150; geveldrager_verlenging_a: 0 mm; geveldrager_verlenging_b: 0 mm; latei: no; latei_hoek_a: 0 deg; latei_hoek_b: 0 deg; latei_plaatsing_x: 0 mm; latei_plaatsing_y: 0 mm; latei_type: NLRS_41_SF_LIB_latei_beton_generiek_ISR : 150x100; latei_verlenging_a: 100 mm; latei_verlenging_b: 100 mm; vensterbank: yes; vensterbank_hoek_a: 0 deg; vensterbank_hoek_b: 0 deg; vensterbank_plaatsing_x: 149 mm; vensterbank_plaatsing_y: 17 mm; vensterbank_type: NLRS_42_GM_WPB_vensterbank_natuursteen-SH_generiek_ISR : 180x18 vensterbank composiet; vensterbank_verlenging_a: -131.5 mm; vensterbank_verlenging_b: -131.5 mm; waterslag: yes; waterslag_hoek_a: 0 deg; waterslag_hoek_b: 0 deg; waterslag_plaatsing_x: -125 mm; waterslag_plaatsing_y: 83 mm; waterslag_type: NLRS_41_GM_WPB_waterslag barok-SH_roval_ISR : waterslag_roval_Types Barok_roval_b 320; waterslag_verlenging_a: 0 mm; waterslag_verlenging_b: 0 mm; Graphics(Type) - doorval_hoek_links: 0 deg; doorval_hoek_rechts: 0 deg; doorval_plaatsing_x: 30 mm; doorval_plaatsing_y: 300 mm; doorval_type: NLRS_41_GM_WPB_doorvalbeveiliging-SH_generiek_ISR : std; doorval_verlenging_links: 0 mm; doorval_verlenging_rechts: 0 mm; doorvalbeveiliging: no; ventilatie: no; ventilatie_plaatsing_x: 114 mm; ventilatie_plaatsing_y: 0 mm; ventilatie_type: NLRS_41_GM_WPB_ventilatie-SH_topstream_ISR : std; ventilatie_verlenging_links: 0 mm; ventilatie_verlenging_rechts: 0 mm; Construction(Type) - binnenblad_beplating: 200 mm; binnenblad_hout: 275 mm; buitenblad: 180 mm; isolatie: 10 mm; luchtspouw: 30 mm; negge: 215 mm; Dimensions(Type) - binnenbladhost: yes; buitenbladhost: no; clashobject: no; wrapping_exterior: 0 mm; wrapping_interior: 0 mm; Identity Data(Type) - Assembly Description: buitenwandopeningen; Other(Type) - a_binnen_boven_1: 177 mm; a_binnen_boven_2: 177 mm; a_binnen_links_1: 114.5 mm; a_binnen_links_2: 114.5 mm; a_binnen_onder_1: 59 mm; a_binnen_onder_2: 59 mm; a_binnen_rechts_1: 114.5 mm; a_binnen_rechts_2: 114.5 mm; a_binnenbepl_boven_1: 17 mm; a_binnenbepl_links_1: 131.5 mm; a_binnenbepl_onder_1: 17 mm; a_binnenbepl_rechts_1: 131.5 mm; a_binnenwand_afwerking_boven_y: 17 mm; a_binnenwand_afwerking_links_y: 131.5 mm; a_binnenwand_afwerking_rechts_y: 131.5 mm; a_binnenwand_afwerking_x: 149 mm; a_buitenblad_boven: 12 mm; a_buitenblad_boven_y: 0 mm; a_buitenblad_links: 7 mm; a_buitenblad_links_y: 0 mm; a_buitenblad_onder: 70 mm; a_buitenblad_rechts: 7 mm; a_buitenblad_rechts_y: 0 mm; a_buitenblad_x: 0 mm; a_doorval_x: 30 mm; a_doorval_y: 300 mm; a_geveldrager_x: 10 mm; a_geveldrager_y: 3 mm; a_isolatie_boven: 48 mm; a_isolatie_links: 28 mm; a_isolatie_onder: 21 mm; a_isolatie_rechts: 21 mm; a_latei_x: 0 mm; a_latei_y: 0 mm; a_rekje_x: 0 mm; a_rekje_y: 0 mm; a_spouwlat_boven_y: 17 mm; a_spouwlat_links_y: 17 mm; a_spouwlat_onder_y: 17 mm; a_spouwlat_rechts_y: 17 mm; a_spouwlat_x: 275 mm; a_vensterbank_x: 149 mm; a_vensterbank_y: 17 mm; a_ventilatie_x: 114 mm; a_ventilatie_y: 0 mm; a_waterslag_x: 125 mm; a_waterslag_y: 83 mm; b_binnen_boven_1: 354 mm; b_binnen_boven_2: 354 mm; b_binnen_links_1: 229 mm; b_binnen_links_2: 229 mm; b_binnen_onder_1: 118 mm; b_binnen_onder_2: 118 mm; b_binnen_rechts_1: 229 mm; b_binnen_rechts_2: 229 mm; b_binnenwand_afwerking_boven_y: 34 mm; b_binnenwand_afwerking_links_y: 263 mm; b_binnenwand_afwerking_rechts_y: 263 mm; b_binnenwand_afwerking_x: 298 mm; b_buitenblad_boven: 24 mm; b_buitenblad_boven_y: 0 mm; b_buitenblad_links: 14 mm; b_buitenblad_links_y: 0 mm; b_buitenblad_onder: 140 mm; b_buitenblad_rechts: 14 mm; b_buitenblad_rechts_y: 0 mm; b_buitenblad_x: 0 mm; b_doorval_x: 60 mm; b_doorval_y: 600 mm; b_geveldrager_x: 0 mm; b_geveldrager_y: 6 mm; b_isolatie_boven: 96 mm; b_isolatie_links: 56 mm; b_isolatie_onder: 42 mm; b_isolatie_rechts: 42 mm; b_latei_x: 0 mm; b_latei_y: 0 mm; b_rekje_x: 0 mm; b_rekje_y: 0 mm; b_spouwlat_boven_y: 0 mm; b_spouwlat_links_y: 0 mm; b_spouwlat_onder_y: 0 mm; b_spouwlat_rechts_y: 0 mm; b_spouwlat_x: 0 mm; b_vensterbank_x: 298 mm; b_vensterbank_y: 34 mm; b_ventilatie_x: 228 mm; b_ventilatie_y: 0 mm; b_waterslag_x: 0 mm; b_waterslag_y: 166 mm; berekende_binnen-buiten_host: 220 mm; offset_binnenblad_boven_2: 177 mm; offset_binnenblad_links_2: 114.5 mm; offset_binnenblad_onder_2: 59 mm; offset_binnenblad_rechts_2: 114.5 mm
Basic Wall:22_WA_voorzetwand_ms100 25-75 _gen_bdg:2968116 | 00 begane grond | 2E(22.11) Uniformat (Uniformat) | 01 eerste verdieping | 850 | 2. nieuwbouw | 5.6824 | 2020 | 1771 | Workset1 | 196 | Windows | NLRS_31_WI_WB_sparingmaker_generiek_BDG | NLRS_31_WI_WB_sparingmaker_generiek_BDG: mw_hsb_raam negge 180_alu v1 opbouwcorrectie | 2870 | 772577 | mw_hsb_raam negge 180_alu v1 opbouwcorrectie | 3475888 | <None> | Schematic Type | 31 | 20160502 | buitenblad Detail | 102 | mw_hsb_raam negge 180_alu v1 opbouwcorrectie | Family : Windows : NLRS_31_WI_WB_sparingmaker_generiek_BDG | Windows | NLRS_31_WI_WB_sparingmaker_generiek_BDG | General - samenstelling: NLRS_31_WI_UN_samenstelling_leeg_generiek_ISR : std; Dimensions - NLRS_C_breedte: 1771 mm; NLRS_C_hoogte: 2020 mm; Layers(Type) - binnenblad_afwerking_boven: yes; binnenblad_afwerking_boven_hoek_links: 0 deg; binnenblad_afwerking_boven_hoek_rechts: 0 deg; binnenblad_afwerking_boven_plaatsing_y: 17 mm; binnenblad_afwerking_boven_type: NLRS_41_GM_WPB_multiplex-SH_generiek_ISR : 151x10 gipsvezel dagkant; binnenblad_afwerking_boven_verlenging_links: -129 mm; binnenblad_afwerking_boven_verlenging_rechts: -129 mm; binnenblad_afwerking_links: yes; binnenblad_afwerking_links_hoek_boven: 0 deg; binnenblad_afwerking_links_hoek_onder: 0 deg; binnenblad_afwerking_links_plaatsing_y: 131.5 mm; binnenblad_afwerking_links_type: NLRS_41_GM_WPB_multiplex-SH_generiek_ISR : 151x10 gipsvezel dagkant; binnenblad_afwerking_links_verlenging_boven: -27 mm; binnenblad_afwerking_links_verlenging_onder: -94 mm; binnenblad_afwerking_plaatsing_x: 149 mm; binnenblad_afwerking_rechts: yes; binnenblad_afwerking_rechts_hoek_boven: 0 deg; binnenblad_afwerking_rechts_hoek_onder: 0 deg; binnenblad_afwerking_rechts_plaatsing_y: 131.5 mm; binnenblad_afwerking_rechts_type: NLRS_41_GM_WPB_multiplex-SH_generiek_ISR : 151x10 gipsvezel dagkant; binnenblad_afwerking_rechts_verlenging_boven: -27 mm; binnenblad_afwerking_rechts_verlenging_onder: -94 mm; buitenblad_afwerking_boven: no; buitenblad_afwerking_boven_hoek_links: 0 deg; buitenblad_afwerking_boven_hoek_rechts: 0 deg; buitenblad_afwerking_boven_plaatsing_y: 0 mm; buitenblad_afwerking_boven_type: NLRS_41_GM_WPB_omgezet metselwerk-SH_generiek_ISR : std; buitenblad_afwerking_boven_verlenging_links: 0 mm; buitenblad_afwerking_boven_verlenging_rechts: 0 mm; buitenblad_afwerking_links: no; buitenblad_afwerking_links_hoek_boven: 0 deg; buitenblad_afwerking_links_hoek_onder: 0 deg; buitenblad_afwerking_links_plaatsing_y: 0 mm; buitenblad_afwerking_links_type: NLRS_41_GM_WPB_omgezet metselwerk-SH_generiek_ISR : std; buitenblad_afwerking_links_verlenging_boven: 0 mm; buitenblad_afwerking_links_verlenging_onder: 0 mm; buitenblad_afwerking_plaatsing_x: 0 mm; buitenblad_afwerking_rechts: no; buitenblad_afwerking_rechts_hoek_boven: 0 deg; buitenblad_afwerking_rechts_hoek_onder: 0 deg; buitenblad_afwerking_rechts_plaatsing_y: 0 mm; buitenblad_afwerking_rechts_type: NLRS_41_GM_WPB_omgezet metselwerk-SH_generiek_ISR : std; buitenblad_afwerking_rechts_verlenging_boven: 0 mm; buitenblad_afwerking_rechts_verlenging_onder: 0 mm; Constraints(Type) - lossing_binnenblad: 0 mm; offset_binnenblad_boven: 177 mm; offset_binnenblad_links: 114.5 mm; offset_binnenblad_onder: 59 mm; offset_binnenblad_rechts: 114.5 mm; offset_binnenbladbeplating_boven: 17 mm; offset_binnenbladbeplating_links: 131.5 mm; offset_binnenbladbeplating_onder: 17 mm; offset_binnenbladbeplating_rechts: 131.5 mm; offset_buitenblad_boven: 12 mm; offset_buitenblad_links: 7 mm; offset_buitenblad_onder: 70 mm; offset_buitenblad_rechts: 7 mm; offset_isolatie_boven: 48 mm; offset_isolatie_links: 28 mm; offset_isolatie_onder: 21 mm; offset_isolatie_rechts: 21 mm; Structural(Type) - rekje: no; rekje_plaatsing_x: 0 mm; rekje_plaatsing_y: 0 mm; rekje_type: NLRS_41_GM_WPB_rekje-SH_generiek_ISR : std; rekje_verlenging_links: 200 mm; rekje_verlenging_rechts: 200 mm; spouwlat_boven: yes; spouwlat_boven_plaatsing_y: -17 mm; spouwlat_boven_type: NLRS_41_GM_WPB_spouwlat_isolatie_gen_bdg : 187x38 + isolatie 156x200; spouwlat_boven_verlenging_links: 112 mm; spouwlat_boven_verlenging_rechts: 112 mm; spouwlat_links: yes; spouwlat_links_plaatsing_y: -17 mm; spouwlat_links_type: NLRS_41_GM_WPB_spouwlat_isolatie_gen_bdg : 187x38 + isolatie 93.5x187; spouwlat_links_verlenging_boven: -17 mm; spouwlat_links_verlenging_onder: -17 mm; spouwlat_onder: yes; spouwlat_onder_plaatsing_y: -17 mm; spouwlat_onder_type: NLRS_41_GM_WPB_spouwlat-SH_generiek_ISR : 185x76; spouwlat_onder_verlenging_links: 112 mm; spouwlat_onder_verlenging_rechts: 112 mm; spouwlat_plaatsing_x: -275 mm; spouwlat_rechts: yes; spouwlat_rechts_plaatsing_y: -17 mm; spouwlat_rechts_type: NLRS_41_GM_WPB_spouwlat_isolatie_gen_bdg : 187x38 + isolatie 93.5x187; spouwlat_rechts_verlenging_boven: -17 mm; spouwlat_rechts_verlenging_onder: -17 mm; Materials and Finishes(Type) - geveldrager: yes; geveldrager_hoek_a: 0 deg; geveldrager_hoek_b: 0 deg; geveldrager_plaatsing_x: -10 mm; geveldrager_plaatsing_y: 3 mm; geveldrager_type: NLRS_41_SF_LIB_latei_staal_generiek_ISR : 90x150; geveldrager_verlenging_a: 0 mm; geveldrager_verlenging_b: 0 mm; latei: no; latei_hoek_a: 0 deg; latei_hoek_b: 0 deg; latei_plaatsing_x: 0 mm; latei_plaatsing_y: 0 mm; latei_type: NLRS_41_SF_LIB_latei_beton_generiek_ISR : 150x100; latei_verlenging_a: 100 mm; latei_verlenging_b: 100 mm; vensterbank: yes; vensterbank_hoek_a: 0 deg; vensterbank_hoek_b: 0 deg; vensterbank_plaatsing_x: 149 mm; vensterbank_plaatsing_y: 17 mm; vensterbank_type: NLRS_42_GM_WPB_vensterbank_natuursteen-SH_generiek_ISR : 180x18 vensterbank composiet; vensterbank_verlenging_a: -131.5 mm; vensterbank_verlenging_b: -131.5 mm; waterslag: yes; waterslag_hoek_a: 0 deg; waterslag_hoek_b: 0 deg; waterslag_plaatsing_x: -125 mm; waterslag_plaatsing_y: 83 mm; waterslag_type: NLRS_41_GM_WPB_waterslag barok-SH_roval_ISR : waterslag_roval_Types Barok_roval_b 320; waterslag_verlenging_a: 0 mm; waterslag_verlenging_b: 0 mm; Graphics(Type) - doorval_hoek_links: 0 deg; doorval_hoek_rechts: 0 deg; doorval_plaatsing_x: 30 mm; doorval_plaatsing_y: 300 mm; doorval_type: NLRS_41_GM_WPB_doorvalbeveiliging-SH_generiek_ISR : std; doorval_verlenging_links: 0 mm; doorval_verlenging_rechts: 0 mm; doorvalbeveiliging: no; ventilatie: no; ventilatie_plaatsing_x: 114 mm; ventilatie_plaatsing_y: 0 mm; ventilatie_type: NLRS_41_GM_WPB_ventilatie-SH_topstream_ISR : std; ventilatie_verlenging_links: 0 mm; ventilatie_verlenging_rechts: 0 mm; Construction(Type) - binnenblad_beplating: 200 mm; binnenblad_hout: 275 mm; buitenblad: 180 mm; isolatie: 10 mm; luchtspouw: 30 mm; negge: 215 mm; Dimensions(Type) - binnenbladhost: yes; buitenbladhost: no; clashobject: no; wrapping_exterior: 0 mm; wrapping_interior: 0 mm; Identity Data(Type) - Assembly Description: buitenwandopeningen; Other(Type) - a_binnen_boven_1: 177 mm; a_binnen_boven_2: 177 mm; a_binnen_links_1: 114.5 mm; a_binnen_links_2: 114.5 mm; a_binnen_onder_1: 59 mm; a_binnen_onder_2: 59 mm; a_binnen_rechts_1: 114.5 mm; a_binnen_rechts_2: 114.5 mm; a_binnenbepl_boven_1: 17 mm; a_binnenbepl_links_1: 131.5 mm; a_binnenbepl_onder_1: 17 mm; a_binnenbepl_rechts_1: 131.5 mm; a_binnenwand_afwerking_boven_y: 17 mm; a_binnenwand_afwerking_links_y: 131.5 mm; a_binnenwand_afwerking_rechts_y: 131.5 mm; a_binnenwand_afwerking_x: 149 mm; a_buitenblad_boven: 12 mm; a_buitenblad_boven_y: 0 mm; a_buitenblad_links: 7 mm; a_buitenblad_links_y: 0 mm; a_buitenblad_onder: 70 mm; a_buitenblad_rechts: 7 mm; a_buitenblad_rechts_y: 0 mm; a_buitenblad_x: 0 mm; a_doorval_x: 30 mm; a_doorval_y: 300 mm; a_geveldrager_x: 10 mm; a_geveldrager_y: 3 mm; a_isolatie_boven: 48 mm; a_isolatie_links: 28 mm; a_isolatie_onder: 21 mm; a_isolatie_rechts: 21 mm; a_latei_x: 0 mm; a_latei_y: 0 mm; a_rekje_x: 0 mm; a_rekje_y: 0 mm; a_spouwlat_boven_y: 17 mm; a_spouwlat_links_y: 17 mm; a_spouwlat_onder_y: 17 mm; a_spouwlat_rechts_y: 17 mm; a_spouwlat_x: 275 mm; a_vensterbank_x: 149 mm; a_vensterbank_y: 17 mm; a_ventilatie_x: 114 mm; a_ventilatie_y: 0 mm; a_waterslag_x: 125 mm; a_waterslag_y: 83 mm; b_binnen_boven_1: 354 mm; b_binnen_boven_2: 354 mm; b_binnen_links_1: 229 mm; b_binnen_links_2: 229 mm; b_binnen_onder_1: 118 mm; b_binnen_onder_2: 118 mm; b_binnen_rechts_1: 229 mm; b_binnen_rechts_2: 229 mm; b_binnenwand_afwerking_boven_y: 34 mm; b_binnenwand_afwerking_links_y: 263 mm; b_binnenwand_afwerking_rechts_y: 263 mm; b_binnenwand_afwerking_x: 298 mm; b_buitenblad_boven: 24 mm; b_buitenblad_boven_y: 0 mm; b_buitenblad_links: 14 mm; b_buitenblad_links_y: 0 mm; b_buitenblad_onder: 140 mm; b_buitenblad_rechts: 14 mm; b_buitenblad_rechts_y: 0 mm; b_buitenblad_x: 0 mm; b_doorval_x: 60 mm; b_doorval_y: 600 mm; b_geveldrager_x: 0 mm; b_geveldrager_y: 6 mm; b_isolatie_boven: 96 mm; b_isolatie_links: 56 mm; b_isolatie_onder: 42 mm; b_isolatie_rechts: 42 mm; b_latei_x: 0 mm; b_latei_y: 0 mm; b_rekje_x: 0 mm; b_rekje_y: 0 mm; b_spouwlat_boven_y: 0 mm; b_spouwlat_links_y: 0 mm; b_spouwlat_onder_y: 0 mm; b_spouwlat_rechts_y: 0 mm; b_spouwlat_x: 0 mm; b_vensterbank_x: 298 mm; b_vensterbank_y: 34 mm; b_ventilatie_x: 228 mm; b_ventilatie_y: 0 mm; b_waterslag_x: 0 mm; b_waterslag_y: 166 mm; berekende_binnen-buiten_host: 220 mm; offset_binnenblad_boven_2: 177 mm; offset_binnenblad_links_2: 114.5 mm; offset_binnenblad_onder_2: 59 mm; offset_binnenblad_rechts_2: 114.5 mm
Basic Wall:22_WA_voorzetwand_ms100 25-75 _gen_bdg:2968116 | 00 begane grond | 2E(22.11) Uniformat (Uniformat) | 01 eerste verdieping | 850 | 2. nieuwbouw | 5.6824 | 2020 | 1771 | Workset1 | 198 | Windows | NLRS_31_WI_WB_sparingmaker_generiek_BDG | NLRS_31_WI_WB_sparingmaker_generiek_BDG: mw_hsb_raam negge 180_alu v1 opbouwcorrectie | 2870 | 772577 | mw_hsb_raam negge 180_alu v1 opbouwcorrectie | 3475888 | <None> | Schematic Type | 31 | 20160502 | buitenblad Detail | 102 | mw_hsb_raam negge 180_alu v1 opbouwcorrectie | Family : Windows : NLRS_31_WI_WB_sparingmaker_generiek_BDG | Windows | NLRS_31_WI_WB_sparingmaker_generiek_BDG | General - samenstelling: NLRS_31_WI_UN_samenstelling_leeg_generiek_ISR : std; Dimensions - NLRS_C_breedte: 1771 mm; NLRS_C_hoogte: 2020 mm; Layers(Type) - binnenblad_afwerking_boven: yes; binnenblad_afwerking_boven_hoek_links: 0 deg; binnenblad_afwerking_boven_hoek_rechts: 0 deg; binnenblad_afwerking_boven_plaatsing_y: 17 mm; binnenblad_afwerking_boven_type: NLRS_41_GM_WPB_multiplex-SH_generiek_ISR : 151x10 gipsvezel dagkant; binnenblad_afwerking_boven_verlenging_links: -129 mm; binnenblad_afwerking_boven_verlenging_rechts: -129 mm; binnenblad_afwerking_links: yes; binnenblad_afwerking_links_hoek_boven: 0 deg; binnenblad_afwerking_links_hoek_onder: 0 deg; binnenblad_afwerking_links_plaatsing_y: 131.5 mm; binnenblad_afwerking_links_type: NLRS_41_GM_WPB_multiplex-SH_generiek_ISR : 151x10 gipsvezel dagkant; binnenblad_afwerking_links_verlenging_boven: -27 mm; binnenblad_afwerking_links_verlenging_onder: -94 mm; binnenblad_afwerking_plaatsing_x: 149 mm; binnenblad_afwerking_rechts: yes; binnenblad_afwerking_rechts_hoek_boven: 0 deg; binnenblad_afwerking_rechts_hoek_onder: 0 deg; binnenblad_afwerking_rechts_plaatsing_y: 131.5 mm; binnenblad_afwerking_rechts_type: NLRS_41_GM_WPB_multiplex-SH_generiek_ISR : 151x10 gipsvezel dagkant; binnenblad_afwerking_rechts_verlenging_boven: -27 mm; binnenblad_afwerking_rechts_verlenging_onder: -94 mm; buitenblad_afwerking_boven: no; buitenblad_afwerking_boven_hoek_links: 0 deg; buitenblad_afwerking_boven_hoek_rechts: 0 deg; buitenblad_afwerking_boven_plaatsing_y: 0 mm; buitenblad_afwerking_boven_type: NLRS_41_GM_WPB_omgezet metselwerk-SH_generiek_ISR : std; buitenblad_afwerking_boven_verlenging_links: 0 mm; buitenblad_afwerking_boven_verlenging_rechts: 0 mm; buitenblad_afwerking_links: no; buitenblad_afwerking_links_hoek_boven: 0 deg; buitenblad_afwerking_links_hoek_onder: 0 deg; buitenblad_afwerking_links_plaatsing_y: 0 mm; buitenblad_afwerking_links_type: NLRS_41_GM_WPB_omgezet metselwerk-SH_generiek_ISR : std; buitenblad_afwerking_links_verlenging_boven: 0 mm; buitenblad_afwerking_links_verlenging_onder: 0 mm; buitenblad_afwerking_plaatsing_x: 0 mm; buitenblad_afwerking_rechts: no; buitenblad_afwerking_rechts_hoek_boven: 0 deg; buitenblad_afwerking_rechts_hoek_onder: 0 deg; buitenblad_afwerking_rechts_plaatsing_y: 0 mm; buitenblad_afwerking_rechts_type: NLRS_41_GM_WPB_omgezet metselwerk-SH_generiek_ISR : std; buitenblad_afwerking_rechts_verlenging_boven: 0 mm; buitenblad_afwerking_rechts_verlenging_onder: 0 mm; Constraints(Type) - lossing_binnenblad: 0 mm; offset_binnenblad_boven: 177 mm; offset_binnenblad_links: 114.5 mm; offset_binnenblad_onder: 59 mm; offset_binnenblad_rechts: 114.5 mm; offset_binnenbladbeplating_boven: 17 mm; offset_binnenbladbeplating_links: 131.5 mm; offset_binnenbladbeplating_onder: 17 mm; offset_binnenbladbeplating_rechts: 131.5 mm; offset_buitenblad_boven: 12 mm; offset_buitenblad_links: 7 mm; offset_buitenblad_onder: 70 mm; offset_buitenblad_rechts: 7 mm; offset_isolatie_boven: 48 mm; offset_isolatie_links: 28 mm; offset_isolatie_onder: 21 mm; offset_isolatie_rechts: 21 mm; Structural(Type) - rekje: no; rekje_plaatsing_x: 0 mm; rekje_plaatsing_y: 0 mm; rekje_type: NLRS_41_GM_WPB_rekje-SH_generiek_ISR : std; rekje_verlenging_links: 200 mm; rekje_verlenging_rechts: 200 mm; spouwlat_boven: yes; spouwlat_boven_plaatsing_y: -17 mm; spouwlat_boven_type: NLRS_41_GM_WPB_spouwlat_isolatie_gen_bdg : 187x38 + isolatie 156x200; spouwlat_boven_verlenging_links: 112 mm; spouwlat_boven_verlenging_rechts: 112 mm; spouwlat_links: yes; spouwlat_links_plaatsing_y: -17 mm; spouwlat_links_type: NLRS_41_GM_WPB_spouwlat_isolatie_gen_bdg : 187x38 + isolatie 93.5x187; spouwlat_links_verlenging_boven: -17 mm; spouwlat_links_verlenging_onder: -17 mm; spouwlat_onder: yes; spouwlat_onder_plaatsing_y: -17 mm; spouwlat_onder_type: NLRS_41_GM_WPB_spouwlat-SH_generiek_ISR : 185x76; spouwlat_onder_verlenging_links: 112 mm; spouwlat_onder_verlenging_rechts: 112 mm; spouwlat_plaatsing_x: -275 mm; spouwlat_rechts: yes; spouwlat_rechts_plaatsing_y: -17 mm; spouwlat_rechts_type: NLRS_41_GM_WPB_spouwlat_isolatie_gen_bdg : 187x38 + isolatie 93.5x187; spouwlat_rechts_verlenging_boven: -17 mm; spouwlat_rechts_verlenging_onder: -17 mm; Materials and Finishes(Type) - geveldrager: yes; geveldrager_hoek_a: 0 deg; geveldrager_hoek_b: 0 deg; geveldrager_plaatsing_x: -10 mm; geveldrager_plaatsing_y: 3 mm; geveldrager_type: NLRS_41_SF_LIB_latei_staal_generiek_ISR : 90x150; geveldrager_verlenging_a: 0 mm; geveldrager_verlenging_b: 0 mm; latei: no; latei_hoek_a: 0 deg; latei_hoek_b: 0 deg; latei_plaatsing_x: 0 mm; latei_plaatsing_y: 0 mm; latei_type: NLRS_41_SF_LIB_latei_beton_generiek_ISR : 150x100; latei_verlenging_a: 100 mm; latei_verlenging_b: 100 mm; vensterbank: yes; vensterbank_hoek_a: 0 deg; vensterbank_hoek_b: 0 deg; vensterbank_plaatsing_x: 149 mm; vensterbank_plaatsing_y: 17 mm; vensterbank_type: NLRS_42_GM_WPB_vensterbank_natuursteen-SH_generiek_ISR : 180x18 vensterbank composiet; vensterbank_verlenging_a: -131.5 mm; vensterbank_verlenging_b: -131.5 mm; waterslag: yes; waterslag_hoek_a: 0 deg; waterslag_hoek_b: 0 deg; waterslag_plaatsing_x: -125 mm; waterslag_plaatsing_y: 83 mm; waterslag_type: NLRS_41_GM_WPB_waterslag barok-SH_roval_ISR : waterslag_roval_Types Barok_roval_b 320; waterslag_verlenging_a: 0 mm; waterslag_verlenging_b: 0 mm; Graphics(Type) - doorval_hoek_links: 0 deg; doorval_hoek_rechts: 0 deg; doorval_plaatsing_x: 30 mm; doorval_plaatsing_y: 300 mm; doorval_type: NLRS_41_GM_WPB_doorvalbeveiliging-SH_generiek_ISR : std; doorval_verlenging_links: 0 mm; doorval_verlenging_rechts: 0 mm; doorvalbeveiliging: no; ventilatie: no; ventilatie_plaatsing_x: 114 mm; ventilatie_plaatsing_y: 0 mm; ventilatie_type: NLRS_41_GM_WPB_ventilatie-SH_topstream_ISR : std; ventilatie_verlenging_links: 0 mm; ventilatie_verlenging_rechts: 0 mm; Construction(Type) - binnenblad_beplating: 200 mm; binnenblad_hout: 275 mm; buitenblad: 180 mm; isolatie: 10 mm; luchtspouw: 30 mm; negge: 215 mm; Dimensions(Type) - binnenbladhost: yes; buitenbladhost: no; clashobject: no; wrapping_exterior: 0 mm; wrapping_interior: 0 mm; Identity Data(Type) - Assembly Description: buitenwandopeningen; Other(Type) - a_binnen_boven_1: 177 mm; a_binnen_boven_2: 177 mm; a_binnen_links_1: 114.5 mm; a_binnen_links_2: 114.5 mm; a_binnen_onder_1: 59 mm; a_binnen_onder_2: 59 mm; a_binnen_rechts_1: 114.5 mm; a_binnen_rechts_2: 114.5 mm; a_binnenbepl_boven_1: 17 mm; a_binnenbepl_links_1: 131.5 mm; a_binnenbepl_onder_1: 17 mm; a_binnenbepl_rechts_1: 131.5 mm; a_binnenwand_afwerking_boven_y: 17 mm; a_binnenwand_afwerking_links_y: 131.5 mm; a_binnenwand_afwerking_rechts_y: 131.5 mm; a_binnenwand_afwerking_x: 149 mm; a_buitenblad_boven: 12 mm; a_buitenblad_boven_y: 0 mm; a_buitenblad_links: 7 mm; a_buitenblad_links_y: 0 mm; a_buitenblad_onder: 70 mm; a_buitenblad_rechts: 7 mm; a_buitenblad_rechts_y: 0 mm; a_buitenblad_x: 0 mm; a_doorval_x: 30 mm; a_doorval_y: 300 mm; a_geveldrager_x: 10 mm; a_geveldrager_y: 3 mm; a_isolatie_boven: 48 mm; a_isolatie_links: 28 mm; a_isolatie_onder: 21 mm; a_isolatie_rechts: 21 mm; a_latei_x: 0 mm; a_latei_y: 0 mm; a_rekje_x: 0 mm; a_rekje_y: 0 mm; a_spouwlat_boven_y: 17 mm; a_spouwlat_links_y: 17 mm; a_spouwlat_onder_y: 17 mm; a_spouwlat_rechts_y: 17 mm; a_spouwlat_x: 275 mm; a_vensterbank_x: 149 mm; a_vensterbank_y: 17 mm; a_ventilatie_x: 114 mm; a_ventilatie_y: 0 mm; a_waterslag_x: 125 mm; a_waterslag_y: 83 mm; b_binnen_boven_1: 354 mm; b_binnen_boven_2: 354 mm; b_binnen_links_1: 229 mm; b_binnen_links_2: 229 mm; b_binnen_onder_1: 118 mm; b_binnen_onder_2: 118 mm; b_binnen_rechts_1: 229 mm; b_binnen_rechts_2: 229 mm; b_binnenwand_afwerking_boven_y: 34 mm; b_binnenwand_afwerking_links_y: 263 mm; b_binnenwand_afwerking_rechts_y: 263 mm; b_binnenwand_afwerking_x: 298 mm; b_buitenblad_boven: 24 mm; b_buitenblad_boven_y: 0 mm; b_buitenblad_links: 14 mm; b_buitenblad_links_y: 0 mm; b_buitenblad_onder: 140 mm; b_buitenblad_rechts: 14 mm; b_buitenblad_rechts_y: 0 mm; b_buitenblad_x: 0 mm; b_doorval_x: 60 mm; b_doorval_y: 600 mm; b_geveldrager_x: 0 mm; b_geveldrager_y: 6 mm; b_isolatie_boven: 96 mm; b_isolatie_links: 56 mm; b_isolatie_onder: 42 mm; b_isolatie_rechts: 42 mm; b_latei_x: 0 mm; b_latei_y: 0 mm; b_rekje_x: 0 mm; b_rekje_y: 0 mm; b_spouwlat_boven_y: 0 mm; b_spouwlat_links_y: 0 mm; b_spouwlat_onder_y: 0 mm; b_spouwlat_rechts_y: 0 mm; b_spouwlat_x: 0 mm; b_vensterbank_x: 298 mm; b_vensterbank_y: 34 mm; b_ventilatie_x: 228 mm; b_ventilatie_y: 0 mm; b_waterslag_x: 0 mm; b_waterslag_y: 166 mm; berekende_binnen-buiten_host: 220 mm; offset_binnenblad_boven_2: 177 mm; offset_binnenblad_links_2: 114.5 mm; offset_binnenblad_onder_2: 59 mm; offset_binnenblad_rechts_2: 114.5 mm
Basic Wall:22_WA_voorzetwand_ms100 25-75 _gen_bdg:2968116 | 00 begane grond | 2E(22.11) Uniformat (Uniformat) | 01 eerste verdieping | 850 | 2. nieuwbouw | 5.6824 | 2020 | 1771 | Workset1 | 200 | Windows | NLRS_31_WI_WB_sparingmaker_generiek_BDG | NLRS_31_WI_WB_sparingmaker_generiek_BDG: mw_hsb_raam negge 180_alu v1 opbouwcorrectie | 2870 | 772577 | mw_hsb_raam negge 180_alu v1 opbouwcorrectie | 3475888 | <None> | Schematic Type | 31 | 20160502 | buitenblad Detail | 102 | mw_hsb_raam negge 180_alu v1 opbouwcorrectie | Family : Windows : NLRS_31_WI_WB_sparingmaker_generiek_BDG | Windows | NLRS_31_WI_WB_sparingmaker_generiek_BDG | General - samenstelling: NLRS_31_WI_UN_samenstelling_leeg_generiek_ISR : std; Dimensions - NLRS_C_breedte: 1771 mm; NLRS_C_hoogte: 2020 mm; Layers(Type) - binnenblad_afwerking_boven: yes; binnenblad_afwerking_boven_hoek_links: 0 deg; binnenblad_afwerking_boven_hoek_rechts: 0 deg; binnenblad_afwerking_boven_plaatsing_y: 17 mm; binnenblad_afwerking_boven_type: NLRS_41_GM_WPB_multiplex-SH_generiek_ISR : 151x10 gipsvezel dagkant; binnenblad_afwerking_boven_verlenging_links: -129 mm; binnenblad_afwerking_boven_verlenging_rechts: -129 mm; binnenblad_afwerking_links: yes; binnenblad_afwerking_links_hoek_boven: 0 deg; binnenblad_afwerking_links_hoek_onder: 0 deg; binnenblad_afwerking_links_plaatsing_y: 131.5 mm; binnenblad_afwerking_links_type: NLRS_41_GM_WPB_multiplex-SH_generiek_ISR : 151x10 gipsvezel dagkant; binnenblad_afwerking_links_verlenging_boven: -27 mm; binnenblad_afwerking_links_verlenging_onder: -94 mm; binnenblad_afwerking_plaatsing_x: 149 mm; binnenblad_afwerking_rechts: yes; binnenblad_afwerking_rechts_hoek_boven: 0 deg; binnenblad_afwerking_rechts_hoek_onder: 0 deg; binnenblad_afwerking_rechts_plaatsing_y: 131.5 mm; binnenblad_afwerking_rechts_type: NLRS_41_GM_WPB_multiplex-SH_generiek_ISR : 151x10 gipsvezel dagkant; binnenblad_afwerking_rechts_verlenging_boven: -27 mm; binnenblad_afwerking_rechts_verlenging_onder: -94 mm; buitenblad_afwerking_boven: no; buitenblad_afwerking_boven_hoek_links: 0 deg; buitenblad_afwerking_boven_hoek_rechts: 0 deg; buitenblad_afwerking_boven_plaatsing_y: 0 mm; buitenblad_afwerking_boven_type: NLRS_41_GM_WPB_omgezet metselwerk-SH_generiek_ISR : std; buitenblad_afwerking_boven_verlenging_links: 0 mm; buitenblad_afwerking_boven_verlenging_rechts: 0 mm; buitenblad_afwerking_links: no; buitenblad_afwerking_links_hoek_boven: 0 deg; buitenblad_afwerking_links_hoek_onder: 0 deg; buitenblad_afwerking_links_plaatsing_y: 0 mm; buitenblad_afwerking_links_type: NLRS_41_GM_WPB_omgezet metselwerk-SH_generiek_ISR : std; buitenblad_afwerking_links_verlenging_boven: 0 mm; buitenblad_afwerking_links_verlenging_onder: 0 mm; buitenblad_afwerking_plaatsing_x: 0 mm; buitenblad_afwerking_rechts: no; buitenblad_afwerking_rechts_hoek_boven: 0 deg; buitenblad_afwerking_rechts_hoek_onder: 0 deg; buitenblad_afwerking_rechts_plaatsing_y: 0 mm; buitenblad_afwerking_rechts_type: NLRS_41_GM_WPB_omgezet metselwerk-SH_generiek_ISR : std; buitenblad_afwerking_rechts_verlenging_boven: 0 mm; buitenblad_afwerking_rechts_verlenging_onder: 0 mm; Constraints(Type) - lossing_binnenblad: 0 mm; offset_binnenblad_boven: 177 mm; offset_binnenblad_links: 114.5 mm; offset_binnenblad_onder: 59 mm; offset_binnenblad_rechts: 114.5 mm; offset_binnenbladbeplating_boven: 17 mm; offset_binnenbladbeplating_links: 131.5 mm; offset_binnenbladbeplating_onder: 17 mm; offset_binnenbladbeplating_rechts: 131.5 mm; offset_buitenblad_boven: 12 mm; offset_buitenblad_links: 7 mm; offset_buitenblad_onder: 70 mm; offset_buitenblad_rechts: 7 mm; offset_isolatie_boven: 48 mm; offset_isolatie_links: 28 mm; offset_isolatie_onder: 21 mm; offset_isolatie_rechts: 21 mm; Structural(Type) - rekje: no; rekje_plaatsing_x: 0 mm; rekje_plaatsing_y: 0 mm; rekje_type: NLRS_41_GM_WPB_rekje-SH_generiek_ISR : std; rekje_verlenging_links: 200 mm; rekje_verlenging_rechts: 200 mm; spouwlat_boven: yes; spouwlat_boven_plaatsing_y: -17 mm; spouwlat_boven_type: NLRS_41_GM_WPB_spouwlat_isolatie_gen_bdg : 187x38 + isolatie 156x200; spouwlat_boven_verlenging_links: 112 mm; spouwlat_boven_verlenging_rechts: 112 mm; spouwlat_links: yes; spouwlat_links_plaatsing_y: -17 mm; spouwlat_links_type: NLRS_41_GM_WPB_spouwlat_isolatie_gen_bdg : 187x38 + isolatie 93.5x187; spouwlat_links_verlenging_boven: -17 mm; spouwlat_links_verlenging_onder: -17 mm; spouwlat_onder: yes; spouwlat_onder_plaatsing_y: -17 mm; spouwlat_onder_type: NLRS_41_GM_WPB_spouwlat-SH_generiek_ISR : 185x76; spouwlat_onder_verlenging_links: 112 mm; spouwlat_onder_verlenging_rechts: 112 mm; spouwlat_plaatsing_x: -275 mm; spouwlat_rechts: yes; spouwlat_rechts_plaatsing_y: -17 mm; spouwlat_rechts_type: NLRS_41_GM_WPB_spouwlat_isolatie_gen_bdg : 187x38 + isolatie 93.5x187; spouwlat_rechts_verlenging_boven: -17 mm; spouwlat_rechts_verlenging_onder: -17 mm; Materials and Finishes(Type) - geveldrager: yes; geveldrager_hoek_a: 0 deg; geveldrager_hoek_b: 0 deg; geveldrager_plaatsing_x: -10 mm; geveldrager_plaatsing_y: 3 mm; geveldrager_type: NLRS_41_SF_LIB_latei_staal_generiek_ISR : 90x150; geveldrager_verlenging_a: 0 mm; geveldrager_verlenging_b: 0 mm; latei: no; latei_hoek_a: 0 deg; latei_hoek_b: 0 deg; latei_plaatsing_x: 0 mm; latei_plaatsing_y: 0 mm; latei_type: NLRS_41_SF_LIB_latei_beton_generiek_ISR : 150x100; latei_verlenging_a: 100 mm; latei_verlenging_b: 100 mm; vensterbank: yes; vensterbank_hoek_a: 0 deg; vensterbank_hoek_b: 0 deg; vensterbank_plaatsing_x: 149 mm; vensterbank_plaatsing_y: 17 mm; vensterbank_type: NLRS_42_GM_WPB_vensterbank_natuursteen-SH_generiek_ISR : 180x18 vensterbank composiet; vensterbank_verlenging_a: -131.5 mm; vensterbank_verlenging_b: -131.5 mm; waterslag: yes; waterslag_hoek_a: 0 deg; waterslag_hoek_b: 0 deg; waterslag_plaatsing_x: -125 mm; waterslag_plaatsing_y: 83 mm; waterslag_type: NLRS_41_GM_WPB_waterslag barok-SH_roval_ISR : waterslag_roval_Types Barok_roval_b 320; waterslag_verlenging_a: 0 mm; waterslag_verlenging_b: 0 mm; Graphics(Type) - doorval_hoek_links: 0 deg; doorval_hoek_rechts: 0 deg; doorval_plaatsing_x: 30 mm; doorval_plaatsing_y: 300 mm; doorval_type: NLRS_41_GM_WPB_doorvalbeveiliging-SH_generiek_ISR : std; doorval_verlenging_links: 0 mm; doorval_verlenging_rechts: 0 mm; doorvalbeveiliging: no; ventilatie: no; ventilatie_plaatsing_x: 114 mm; ventilatie_plaatsing_y: 0 mm; ventilatie_type: NLRS_41_GM_WPB_ventilatie-SH_topstream_ISR : std; ventilatie_verlenging_links: 0 mm; ventilatie_verlenging_rechts: 0 mm; Construction(Type) - binnenblad_beplating: 200 mm; binnenblad_hout: 275 mm; buitenblad: 180 mm; isolatie: 10 mm; luchtspouw: 30 mm; negge: 215 mm; Dimensions(Type) - binnenbladhost: yes; buitenbladhost: no; clashobject: no; wrapping_exterior: 0 mm; wrapping_interior: 0 mm; Identity Data(Type) - Assembly Description: buitenwandopeningen; Other(Type) - a_binnen_boven_1: 177 mm; a_binnen_boven_2: 177 mm; a_binnen_links_1: 114.5 mm; a_binnen_links_2: 114.5 mm; a_binnen_onder_1: 59 mm; a_binnen_onder_2: 59 mm; a_binnen_rechts_1: 114.5 mm; a_binnen_rechts_2: 114.5 mm; a_binnenbepl_boven_1: 17 mm; a_binnenbepl_links_1: 131.5 mm; a_binnenbepl_onder_1: 17 mm; a_binnenbepl_rechts_1: 131.5 mm; a_binnenwand_afwerking_boven_y: 17 mm; a_binnenwand_afwerking_links_y: 131.5 mm; a_binnenwand_afwerking_rechts_y: 131.5 mm; a_binnenwand_afwerking_x: 149 mm; a_buitenblad_boven: 12 mm; a_buitenblad_boven_y: 0 mm; a_buitenblad_links: 7 mm; a_buitenblad_links_y: 0 mm; a_buitenblad_onder: 70 mm; a_buitenblad_rechts: 7 mm; a_buitenblad_rechts_y: 0 mm; a_buitenblad_x: 0 mm; a_doorval_x: 30 mm; a_doorval_y: 300 mm; a_geveldrager_x: 10 mm; a_geveldrager_y: 3 mm; a_isolatie_boven: 48 mm; a_isolatie_links: 28 mm; a_isolatie_onder: 21 mm; a_isolatie_rechts: 21 mm; a_latei_x: 0 mm; a_latei_y: 0 mm; a_rekje_x: 0 mm; a_rekje_y: 0 mm; a_spouwlat_boven_y: 17 mm; a_spouwlat_links_y: 17 mm; a_spouwlat_onder_y: 17 mm; a_spouwlat_rechts_y: 17 mm; a_spouwlat_x: 275 mm; a_vensterbank_x: 149 mm; a_vensterbank_y: 17 mm; a_ventilatie_x: 114 mm; a_ventilatie_y: 0 mm; a_waterslag_x: 125 mm; a_waterslag_y: 83 mm; b_binnen_boven_1: 354 mm; b_binnen_boven_2: 354 mm; b_binnen_links_1: 229 mm; b_binnen_links_2: 229 mm; b_binnen_onder_1: 118 mm; b_binnen_onder_2: 118 mm; b_binnen_rechts_1: 229 mm; b_binnen_rechts_2: 229 mm; b_binnenwand_afwerking_boven_y: 34 mm; b_binnenwand_afwerking_links_y: 263 mm; b_binnenwand_afwerking_rechts_y: 263 mm; b_binnenwand_afwerking_x: 298 mm; b_buitenblad_boven: 24 mm; b_buitenblad_boven_y: 0 mm; b_buitenblad_links: 14 mm; b_buitenblad_links_y: 0 mm; b_buitenblad_onder: 140 mm; b_buitenblad_rechts: 14 mm; b_buitenblad_rechts_y: 0 mm; b_buitenblad_x: 0 mm; b_doorval_x: 60 mm; b_doorval_y: 600 mm; b_geveldrager_x: 0 mm; b_geveldrager_y: 6 mm; b_isolatie_boven: 96 mm; b_isolatie_links: 56 mm; b_isolatie_onder: 42 mm; b_isolatie_rechts: 42 mm; b_latei_x: 0 mm; b_latei_y: 0 mm; b_rekje_x: 0 mm; b_rekje_y: 0 mm; b_spouwlat_boven_y: 0 mm; b_spouwlat_links_y: 0 mm; b_spouwlat_onder_y: 0 mm; b_spouwlat_rechts_y: 0 mm; b_spouwlat_x: 0 mm; b_vensterbank_x: 298 mm; b_vensterbank_y: 34 mm; b_ventilatie_x: 228 mm; b_ventilatie_y: 0 mm; b_waterslag_x: 0 mm; b_waterslag_y: 166 mm; berekende_binnen-buiten_host: 220 mm; offset_binnenblad_boven_2: 177 mm; offset_binnenblad_links_2: 114.5 mm; offset_binnenblad_onder_2: 59 mm; offset_binnenblad_rechts_2: 114.5 mm
Basic Wall:22_WA_voorzetwand_ms100 25-75 _gen_bdg:2968116 | 00 begane grond | 2E(22.11) Uniformat (Uniformat) | 01 eerste verdieping | 850 | 2. nieuwbouw | 5.6824 | 2020 | 1771 | Workset1 | 206 | Windows | NLRS_31_WI_WB_sparingmaker_generiek_BDG | NLRS_31_WI_WB_sparingmaker_generiek_BDG: mw_hsb_raam negge 180_alu v1 opbouwcorrectie | 2870 | 772577 | mw_hsb_raam negge 180_alu v1 opbouwcorrectie | 3475888 | <None> | Schematic Type | 31 | 20160502 | buitenblad Detail | 102 | mw_hsb_raam negge 180_alu v1 opbouwcorrectie | Family : Windows : NLRS_31_WI_WB_sparingmaker_generiek_BDG | Windows | NLRS_31_WI_WB_sparingmaker_generiek_BDG | General - samenstelling: NLRS_31_WI_UN_samenstelling_leeg_generiek_ISR : std; Dimensions - NLRS_C_breedte: 1771 mm; NLRS_C_hoogte: 2020 mm; Layers(Type) - binnenblad_afwerking_boven: yes; binnenblad_afwerking_boven_hoek_links: 0 deg; binnenblad_afwerking_boven_hoek_rechts: 0 deg; binnenblad_afwerking_boven_plaatsing_y: 17 mm; binnenblad_afwerking_boven_type: NLRS_41_GM_WPB_multiplex-SH_generiek_ISR : 151x10 gipsvezel dagkant; binnenblad_afwerking_boven_verlenging_links: -129 mm; binnenblad_afwerking_boven_verlenging_rechts: -129 mm; binnenblad_afwerking_links: yes; binnenblad_afwerking_links_hoek_boven: 0 deg; binnenblad_afwerking_links_hoek_onder: 0 deg; binnenblad_afwerking_links_plaatsing_y: 131.5 mm; binnenblad_afwerking_links_type: NLRS_41_GM_WPB_multiplex-SH_generiek_ISR : 151x10 gipsvezel dagkant; binnenblad_afwerking_links_verlenging_boven: -27 mm; binnenblad_afwerking_links_verlenging_onder: -94 mm; binnenblad_afwerking_plaatsing_x: 149 mm; binnenblad_afwerking_rechts: yes; binnenblad_afwerking_rechts_hoek_boven: 0 deg; binnenblad_afwerking_rechts_hoek_onder: 0 deg; binnenblad_afwerking_rechts_plaatsing_y: 131.5 mm; binnenblad_afwerking_rechts_type: NLRS_41_GM_WPB_multiplex-SH_generiek_ISR : 151x10 gipsvezel dagkant; binnenblad_afwerking_rechts_verlenging_boven: -27 mm; binnenblad_afwerking_rechts_verlenging_onder: -94 mm; buitenblad_afwerking_boven: no; buitenblad_afwerking_boven_hoek_links: 0 deg; buitenblad_afwerking_boven_hoek_rechts: 0 deg; buitenblad_afwerking_boven_plaatsing_y: 0 mm; buitenblad_afwerking_boven_type: NLRS_41_GM_WPB_omgezet metselwerk-SH_generiek_ISR : std; buitenblad_afwerking_boven_verlenging_links: 0 mm; buitenblad_afwerking_boven_verlenging_rechts: 0 mm; buitenblad_afwerking_links: no; buitenblad_afwerking_links_hoek_boven: 0 deg; buitenblad_afwerking_links_hoek_onder: 0 deg; buitenblad_afwerking_links_plaatsing_y: 0 mm; buitenblad_afwerking_links_type: NLRS_41_GM_WPB_omgezet metselwerk-SH_generiek_ISR : std; buitenblad_afwerking_links_verlenging_boven: 0 mm; buitenblad_afwerking_links_verlenging_onder: 0 mm; buitenblad_afwerking_plaatsing_x: 0 mm; buitenblad_afwerking_rechts: no; buitenblad_afwerking_rechts_hoek_boven: 0 deg; buitenblad_afwerking_rechts_hoek_onder: 0 deg; buitenblad_afwerking_rechts_plaatsing_y: 0 mm; buitenblad_afwerking_rechts_type: NLRS_41_GM_WPB_omgezet metselwerk-SH_generiek_ISR : std; buitenblad_afwerking_rechts_verlenging_boven: 0 mm; buitenblad_afwerking_rechts_verlenging_onder: 0 mm; Constraints(Type) - lossing_binnenblad: 0 mm; offset_binnenblad_boven: 177 mm; offset_binnenblad_links: 114.5 mm; offset_binnenblad_onder: 59 mm; offset_binnenblad_rechts: 114.5 mm; offset_binnenbladbeplating_boven: 17 mm; offset_binnenbladbeplating_links: 131.5 mm; offset_binnenbladbeplating_onder: 17 mm; offset_binnenbladbeplating_rechts: 131.5 mm; offset_buitenblad_boven: 12 mm; offset_buitenblad_links: 7 mm; offset_buitenblad_onder: 70 mm; offset_buitenblad_rechts: 7 mm; offset_isolatie_boven: 48 mm; offset_isolatie_links: 28 mm; offset_isolatie_onder: 21 mm; offset_isolatie_rechts: 21 mm; Structural(Type) - rekje: no; rekje_plaatsing_x: 0 mm; rekje_plaatsing_y: 0 mm; rekje_type: NLRS_41_GM_WPB_rekje-SH_generiek_ISR : std; rekje_verlenging_links: 200 mm; rekje_verlenging_rechts: 200 mm; spouwlat_boven: yes; spouwlat_boven_plaatsing_y: -17 mm; spouwlat_boven_type: NLRS_41_GM_WPB_spouwlat_isolatie_gen_bdg : 187x38 + isolatie 156x200; spouwlat_boven_verlenging_links: 112 mm; spouwlat_boven_verlenging_rechts: 112 mm; spouwlat_links: yes; spouwlat_links_plaatsing_y: -17 mm; spouwlat_links_type: NLRS_41_GM_WPB_spouwlat_isolatie_gen_bdg : 187x38 + isolatie 93.5x187; spouwlat_links_verlenging_boven: -17 mm; spouwlat_links_verlenging_onder: -17 mm; spouwlat_onder: yes; spouwlat_onder_plaatsing_y: -17 mm; spouwlat_onder_type: NLRS_41_GM_WPB_spouwlat-SH_generiek_ISR : 185x76; spouwlat_onder_verlenging_links: 112 mm; spouwlat_onder_verlenging_rechts: 112 mm; spouwlat_plaatsing_x: -275 mm; spouwlat_rechts: yes; spouwlat_rechts_plaatsing_y: -17 mm; spouwlat_rechts_type: NLRS_41_GM_WPB_spouwlat_isolatie_gen_bdg : 187x38 + isolatie 93.5x187; spouwlat_rechts_verlenging_boven: -17 mm; spouwlat_rechts_verlenging_onder: -17 mm; Materials and Finishes(Type) - geveldrager: yes; geveldrager_hoek_a: 0 deg; geveldrager_hoek_b: 0 deg; geveldrager_plaatsing_x: -10 mm; geveldrager_plaatsing_y: 3 mm; geveldrager_type: NLRS_41_SF_LIB_latei_staal_generiek_ISR : 90x150; geveldrager_verlenging_a: 0 mm; geveldrager_verlenging_b: 0 mm; latei: no; latei_hoek_a: 0 deg; latei_hoek_b: 0 deg; latei_plaatsing_x: 0 mm; latei_plaatsing_y: 0 mm; latei_type: NLRS_41_SF_LIB_latei_beton_generiek_ISR : 150x100; latei_verlenging_a: 100 mm; latei_verlenging_b: 100 mm; vensterbank: yes; vensterbank_hoek_a: 0 deg; vensterbank_hoek_b: 0 deg; vensterbank_plaatsing_x: 149 mm; vensterbank_plaatsing_y: 17 mm; vensterbank_type: NLRS_42_GM_WPB_vensterbank_natuursteen-SH_generiek_ISR : 180x18 vensterbank composiet; vensterbank_verlenging_a: -131.5 mm; vensterbank_verlenging_b: -131.5 mm; waterslag: yes; waterslag_hoek_a: 0 deg; waterslag_hoek_b: 0 deg; waterslag_plaatsing_x: -125 mm; waterslag_plaatsing_y: 83 mm; waterslag_type: NLRS_41_GM_WPB_waterslag barok-SH_roval_ISR : waterslag_roval_Types Barok_roval_b 320; waterslag_verlenging_a: 0 mm; waterslag_verlenging_b: 0 mm; Graphics(Type) - doorval_hoek_links: 0 deg; doorval_hoek_rechts: 0 deg; doorval_plaatsing_x: 30 mm; doorval_plaatsing_y: 300 mm; doorval_type: NLRS_41_GM_WPB_doorvalbeveiliging-SH_generiek_ISR : std; doorval_verlenging_links: 0 mm; doorval_verlenging_rechts: 0 mm; doorvalbeveiliging: no; ventilatie: no; ventilatie_plaatsing_x: 114 mm; ventilatie_plaatsing_y: 0 mm; ventilatie_type: NLRS_41_GM_WPB_ventilatie-SH_topstream_ISR : std; ventilatie_verlenging_links: 0 mm; ventilatie_verlenging_rechts: 0 mm; Construction(Type) - binnenblad_beplating: 200 mm; binnenblad_hout: 275 mm; buitenblad: 180 mm; isolatie: 10 mm; luchtspouw: 30 mm; negge: 215 mm; Dimensions(Type) - binnenbladhost: yes; buitenbladhost: no; clashobject: no; wrapping_exterior: 0 mm; wrapping_interior: 0 mm; Identity Data(Type) - Assembly Description: buitenwandopeningen; Other(Type) - a_binnen_boven_1: 177 mm; a_binnen_boven_2: 177 mm; a_binnen_links_1: 114.5 mm; a_binnen_links_2: 114.5 mm; a_binnen_onder_1: 59 mm; a_binnen_onder_2: 59 mm; a_binnen_rechts_1: 114.5 mm; a_binnen_rechts_2: 114.5 mm; a_binnenbepl_boven_1: 17 mm; a_binnenbepl_links_1: 131.5 mm; a_binnenbepl_onder_1: 17 mm; a_binnenbepl_rechts_1: 131.5 mm; a_binnenwand_afwerking_boven_y: 17 mm; a_binnenwand_afwerking_links_y: 131.5 mm; a_binnenwand_afwerking_rechts_y: 131.5 mm; a_binnenwand_afwerking_x: 149 mm; a_buitenblad_boven: 12 mm; a_buitenblad_boven_y: 0 mm; a_buitenblad_links: 7 mm; a_buitenblad_links_y: 0 mm; a_buitenblad_onder: 70 mm; a_buitenblad_rechts: 7 mm; a_buitenblad_rechts_y: 0 mm; a_buitenblad_x: 0 mm; a_doorval_x: 30 mm; a_doorval_y: 300 mm; a_geveldrager_x: 10 mm; a_geveldrager_y: 3 mm; a_isolatie_boven: 48 mm; a_isolatie_links: 28 mm; a_isolatie_onder: 21 mm; a_isolatie_rechts: 21 mm; a_latei_x: 0 mm; a_latei_y: 0 mm; a_rekje_x: 0 mm; a_rekje_y: 0 mm; a_spouwlat_boven_y: 17 mm; a_spouwlat_links_y: 17 mm; a_spouwlat_onder_y: 17 mm; a_spouwlat_rechts_y: 17 mm; a_spouwlat_x: 275 mm; a_vensterbank_x: 149 mm; a_vensterbank_y: 17 mm; a_ventilatie_x: 114 mm; a_ventilatie_y: 0 mm; a_waterslag_x: 125 mm; a_waterslag_y: 83 mm; b_binnen_boven_1: 354 mm; b_binnen_boven_2: 354 mm; b_binnen_links_1: 229 mm; b_binnen_links_2: 229 mm; b_binnen_onder_1: 118 mm; b_binnen_onder_2: 118 mm; b_binnen_rechts_1: 229 mm; b_binnen_rechts_2: 229 mm; b_binnenwand_afwerking_boven_y: 34 mm; b_binnenwand_afwerking_links_y: 263 mm; b_binnenwand_afwerking_rechts_y: 263 mm; b_binnenwand_afwerking_x: 298 mm; b_buitenblad_boven: 24 mm; b_buitenblad_boven_y: 0 mm; b_buitenblad_links: 14 mm; b_buitenblad_links_y: 0 mm; b_buitenblad_onder: 140 mm; b_buitenblad_rechts: 14 mm; b_buitenblad_rechts_y: 0 mm; b_buitenblad_x: 0 mm; b_doorval_x: 60 mm; b_doorval_y: 600 mm; b_geveldrager_x: 0 mm; b_geveldrager_y: 6 mm; b_isolatie_boven: 96 mm; b_isolatie_links: 56 mm; b_isolatie_onder: 42 mm; b_isolatie_rechts: 42 mm; b_latei_x: 0 mm; b_latei_y: 0 mm; b_rekje_x: 0 mm; b_rekje_y: 0 mm; b_spouwlat_boven_y: 0 mm; b_spouwlat_links_y: 0 mm; b_spouwlat_onder_y: 0 mm; b_spouwlat_rechts_y: 0 mm; b_spouwlat_x: 0 mm; b_vensterbank_x: 298 mm; b_vensterbank_y: 34 mm; b_ventilatie_x: 228 mm; b_ventilatie_y: 0 mm; b_waterslag_x: 0 mm; b_waterslag_y: 166 mm; berekende_binnen-buiten_host: 220 mm; offset_binnenblad_boven_2: 177 mm; offset_binnenblad_links_2: 114.5 mm; offset_binnenblad_onder_2: 59 mm; offset_binnenblad_rechts_2: 114.5 mm
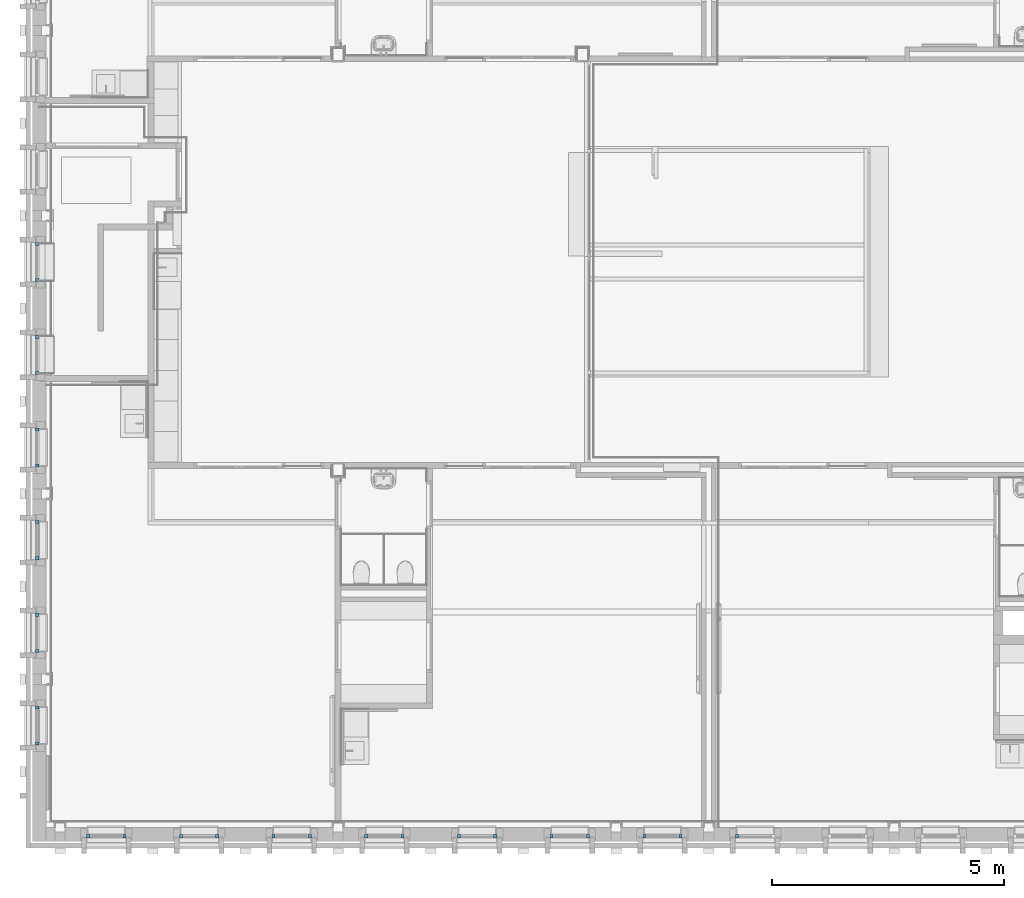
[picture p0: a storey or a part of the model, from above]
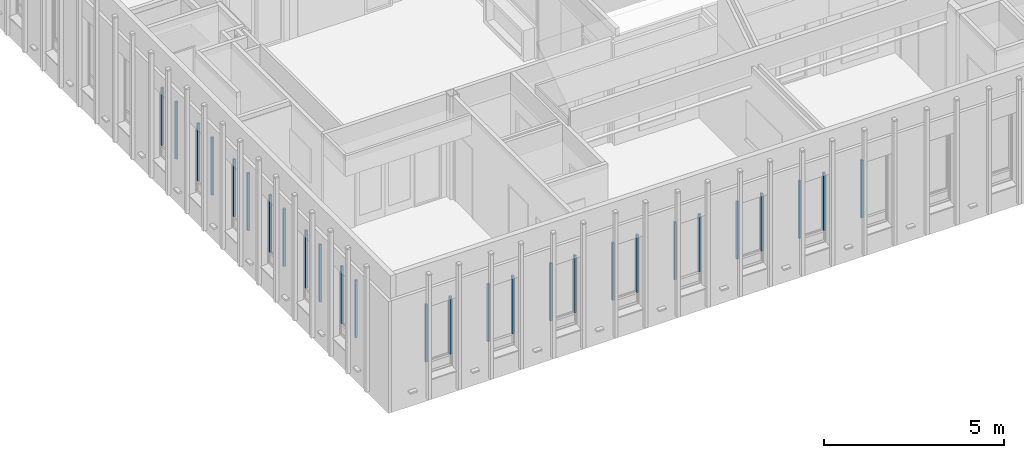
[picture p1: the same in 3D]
Properties of the parts of a building model (IFC2X3), part 80 of 94

# IfcOpeningElement: Opening (823)
Name | In | Classification | Level | Sill Height (mm) | Phase Created | Area (m2) | Height (mm) | Width (mm) | Identity Data, Workset | Mark | Other, Category | Family | Family and Type | Head Height (mm) | Host Id | Type | Type Id | Analytic Construction | Define Thermal Properties by | Assembly Code | Datum_Gewijzigd | Description | Type Mark | Type Name | Identity Data(Type), Workset | Other(Type), Category | Family Name
Basic Wall:22_WA_voorzetwand_ms100 25-75 _gen_bdg:3267593 | 01 eerste verdieping | 2E(22.11) Uniformat (Uniformat) | 01 eerste verdieping | 850 | 2. nieuwbouw | 4.15957 | 2020 | 1238.5 | Workset1 | 675 | Windows | NLRS_31_WI_WB_sparingmaker_generiek_BDG | NLRS_31_WI_WB_sparingmaker_generiek_BDG: mw_hsb_raam negge 180_alu v1 hoek | 2870 | 772577 | mw_hsb_raam negge 180_alu v1 hoek | 2239354 | <None> | Schematic Type | 31 | 20160502 | buitenblad Detail | 88 | mw_hsb_raam negge 180_alu v1 hoek | Family : Windows : NLRS_31_WI_WB_sparingmaker_generiek_BDG | Windows | NLRS_31_WI_WB_sparingmaker_generiek_BDG | General - samenstelling: NLRS_31_WI_UN_samenstelling_leeg_generiek_ISR : std; Dimensions - NLRS_C_breedte: 1238.5 mm; NLRS_C_hoogte: 2020 mm; Layers(Type) - binnenblad_afwerking_boven: yes; binnenblad_afwerking_boven_hoek_links: 0 deg; binnenblad_afwerking_boven_hoek_rechts: 0 deg; binnenblad_afwerking_boven_plaatsing_y: 17 mm; binnenblad_afwerking_boven_type: NLRS_41_GM_WPB_multiplex-SH_generiek_ISR : 151x10 gipsvezel dagkant; binnenblad_afwerking_boven_verlenging_links: -45 mm; binnenblad_afwerking_boven_verlenging_rechts: -200 mm; binnenblad_afwerking_links: yes; binnenblad_afwerking_links_hoek_boven: 0 deg; binnenblad_afwerking_links_hoek_onder: 0 deg; binnenblad_afwerking_links_plaatsing_y: 131.5 mm; binnenblad_afwerking_links_type: NLRS_41_GM_WPB_multiplex-SH_generiek_ISR : 151x10 gipsvezel dagkant; binnenblad_afwerking_links_verlenging_boven: -27 mm; binnenblad_afwerking_links_verlenging_onder: -94 mm; binnenblad_afwerking_plaatsing_x: 149 mm; binnenblad_afwerking_rechts: no; binnenblad_afwerking_rechts_hoek_boven: 0 deg; binnenblad_afwerking_rechts_hoek_onder: 0 deg; binnenblad_afwerking_rechts_plaatsing_y: 45 mm; binnenblad_afwerking_rechts_type: NLRS_41_GM_WPB_multiplex-SH_generiek_ISR : 151x10 gipsvezel dagkant; binnenblad_afwerking_rechts_verlenging_boven: -27 mm; binnenblad_afwerking_rechts_verlenging_onder: -94 mm; buitenblad_afwerking_boven: no; buitenblad_afwerking_boven_hoek_links: 0 deg; buitenblad_afwerking_boven_hoek_rechts: 0 deg; buitenblad_afwerking_boven_plaatsing_y: 0 mm; buitenblad_afwerking_boven_type: NLRS_41_GM_WPB_omgezet metselwerk-SH_generiek_ISR : std; buitenblad_afwerking_boven_verlenging_links: 0 mm; buitenblad_afwerking_boven_verlenging_rechts: 0 mm; buitenblad_afwerking_links: no; buitenblad_afwerking_links_hoek_boven: 0 deg; buitenblad_afwerking_links_hoek_onder: 0 deg; buitenblad_afwerking_links_plaatsing_y: 0 mm; buitenblad_afwerking_links_type: NLRS_41_GM_WPB_omgezet metselwerk-SH_generiek_ISR : std; buitenblad_afwerking_links_verlenging_boven: 0 mm; buitenblad_afwerking_links_verlenging_onder: 0 mm; buitenblad_afwerking_plaatsing_x: 0 mm; buitenblad_afwerking_rechts: no; buitenblad_afwerking_rechts_hoek_boven: 0 deg; buitenblad_afwerking_rechts_hoek_onder: 0 deg; buitenblad_afwerking_rechts_plaatsing_y: 0 mm; buitenblad_afwerking_rechts_type: NLRS_41_GM_WPB_omgezet metselwerk-SH_generiek_ISR : std; buitenblad_afwerking_rechts_verlenging_boven: 0 mm; buitenblad_afwerking_rechts_verlenging_onder: 0 mm; Constraints(Type) - lossing_binnenblad: 0 mm; offset_binnenblad_boven: 28 mm; offset_binnenblad_links: 114.5 mm; offset_binnenblad_onder: 59 mm; offset_binnenblad_rechts: 150 mm; offset_binnenbladbeplating_boven: 17 mm; offset_binnenbladbeplating_links: 131.5 mm; offset_binnenbladbeplating_onder: 17 mm; offset_binnenbladbeplating_rechts: 45 mm; offset_buitenblad_boven: 12 mm; offset_buitenblad_links: 7 mm; offset_buitenblad_onder: 70 mm; offset_buitenblad_rechts: 7 mm; offset_isolatie_boven: 48 mm; offset_isolatie_links: 28 mm; offset_isolatie_onder: 28 mm; offset_isolatie_rechts: 28 mm; Structural(Type) - rekje: no; rekje_plaatsing_x: 0 mm; rekje_plaatsing_y: 0 mm; rekje_type: NLRS_41_GM_WPB_rekje-SH_generiek_ISR : std; rekje_verlenging_links: 200 mm; rekje_verlenging_rechts: 200 mm; spouwlat_boven: yes; spouwlat_boven_plaatsing_y: -17 mm; spouwlat_boven_type: NLRS_41_GM_WPB_spouwlat-SH_generiek_ISR : 185x45; spouwlat_boven_verlenging_links: 112 mm; spouwlat_boven_verlenging_rechts: 28 mm; spouwlat_links: yes; spouwlat_links_plaatsing_y: -17 mm; spouwlat_links_type: NLRS_41_GM_WPB_spouwlat_isolatie_gen_bdg : 187x38 + isolatie 93.5x187; spouwlat_links_verlenging_boven: -17 mm; spouwlat_links_verlenging_onder: -17 mm; spouwlat_onder: yes; spouwlat_onder_plaatsing_y: -17 mm; spouwlat_onder_type: NLRS_41_GM_WPB_spouwlat-SH_generiek_ISR : 185x76; spouwlat_onder_verlenging_links: 112 mm; spouwlat_onder_verlenging_rechts: 28 mm; spouwlat_plaatsing_x: -275 mm; spouwlat_rechts: no; spouwlat_rechts_plaatsing_y: -17 mm; spouwlat_rechts_type: NLRS_41_GM_WPB_spouwlat-SH_generiek_ISR : 185x45; spouwlat_rechts_verlenging_boven: -17 mm; spouwlat_rechts_verlenging_onder: -17 mm; Materials and Finishes(Type) - geveldrager: yes; geveldrager_hoek_a: 45 deg; geveldrager_hoek_b: 0 deg; geveldrager_plaatsing_x: -10 mm; geveldrager_plaatsing_y: 3 mm; geveldrager_type: NLRS_41_SF_LIB_latei_staal_generiek_ISR : 90x150; geveldrager_verlenging_a: 0 mm; geveldrager_verlenging_b: 0 mm; latei: no; latei_hoek_a: 45 deg; latei_hoek_b: 0 deg; latei_plaatsing_x: 0 mm; latei_plaatsing_y: 0 mm; latei_type: NLRS_41_SF_LIB_latei_beton_generiek_ISR : 150x100; latei_verlenging_a: 100 mm; latei_verlenging_b: 100 mm; vensterbank: yes; vensterbank_hoek_a: 0 deg; vensterbank_hoek_b: -45 deg; vensterbank_plaatsing_x: 149 mm; vensterbank_plaatsing_y: 17 mm; vensterbank_type: NLRS_42_GM_WPB_vensterbank_natuursteen-SH_generiek_ISR : 180x18 vensterbank composiet; vensterbank_verlenging_a: -131.5 mm; vensterbank_verlenging_b: -152 mm; waterslag: yes; waterslag_hoek_a: 45 deg; waterslag_hoek_b: 0 deg; waterslag_plaatsing_x: -125 mm; waterslag_plaatsing_y: 83 mm; waterslag_type: NLRS_41_GM_WPB_waterslag barok-SH_roval_ISR : waterslag_roval_Types Barok_roval_b 320; waterslag_verlenging_a: 20 mm; waterslag_verlenging_b: 0 mm; Graphics(Type) - doorval_hoek_links: 0 deg; doorval_hoek_rechts: 0 deg; doorval_plaatsing_x: 30 mm; doorval_plaatsing_y: 300 mm; doorval_type: NLRS_41_GM_WPB_doorvalbeveiliging-SH_generiek_ISR : std; doorval_verlenging_links: 0 mm; doorval_verlenging_rechts: 0 mm; doorvalbeveiliging: no; ventilatie: no; ventilatie_plaatsing_x: 114 mm; ventilatie_plaatsing_y: 0 mm; ventilatie_type: NLRS_41_GM_WPB_ventilatie-SH_topstream_ISR : std; ventilatie_verlenging_links: 0 mm; ventilatie_verlenging_rechts: 0 mm; Construction(Type) - binnenblad_beplating: 25 mm; binnenblad_hout: 275 mm; buitenblad: 180 mm; isolatie: 10 mm; luchtspouw: 30 mm; negge: 215 mm; Dimensions(Type) - binnenbladhost: yes; buitenbladhost: no; clashobject: no; wrapping_exterior: 0 mm; wrapping_interior: 0 mm; Identity Data(Type) - Assembly Description: buitenwandopeningen; Other(Type) - a_binnen_boven_1: 28 mm; a_binnen_boven_2: 28 mm; a_binnen_links_1: 114.5 mm; a_binnen_links_2: 114.5 mm; a_binnen_onder_1: 59 mm; a_binnen_onder_2: 59 mm; a_binnen_rechts_1: 150 mm; a_binnen_rechts_2: 150 mm; a_binnenbepl_boven_1: 17 mm; a_binnenbepl_links_1: 131.5 mm; a_binnenbepl_onder_1: 17 mm; a_binnenbepl_rechts_1: 45 mm; a_binnenwand_afwerking_boven_y: 17 mm; a_binnenwand_afwerking_links_y: 131.5 mm; a_binnenwand_afwerking_rechts_y: 45 mm; a_binnenwand_afwerking_x: 149 mm; a_buitenblad_boven: 12 mm; a_buitenblad_boven_y: 0 mm; a_buitenblad_links: 7 mm; a_buitenblad_links_y: 0 mm; a_buitenblad_onder: 70 mm; a_buitenblad_rechts: 7 mm; a_buitenblad_rechts_y: 0 mm; a_buitenblad_x: 0 mm; a_doorval_x: 30 mm; a_doorval_y: 300 mm; a_geveldrager_x: 10 mm; a_geveldrager_y: 3 mm; a_isolatie_boven: 48 mm; a_isolatie_links: 28 mm; a_isolatie_onder: 28 mm; a_isolatie_rechts: 28 mm; a_latei_x: 0 mm; a_latei_y: 0 mm; a_rekje_x: 0 mm; a_rekje_y: 0 mm; a_spouwlat_boven_y: 17 mm; a_spouwlat_links_y: 17 mm; a_spouwlat_onder_y: 17 mm; a_spouwlat_rechts_y: 17 mm; a_spouwlat_x: 275 mm; a_vensterbank_x: 149 mm; a_vensterbank_y: 17 mm; a_ventilatie_x: 114 mm; a_ventilatie_y: 0 mm; a_waterslag_x: 125 mm; a_waterslag_y: 83 mm; b_binnen_boven_1: 56 mm; b_binnen_boven_2: 56 mm; b_binnen_links_1: 229 mm; b_binnen_links_2: 229 mm; b_binnen_onder_1: 118 mm; b_binnen_onder_2: 118 mm; b_binnen_rechts_1: 300 mm; b_binnen_rechts_2: 300 mm; b_binnenwand_afwerking_boven_y: 34 mm; b_binnenwand_afwerking_links_y: 263 mm; b_binnenwand_afwerking_rechts_y: 90 mm; b_binnenwand_afwerking_x: 298 mm; b_buitenblad_boven: 24 mm; b_buitenblad_boven_y: 0 mm; b_buitenblad_links: 14 mm; b_buitenblad_links_y: 0 mm; b_buitenblad_onder: 140 mm; b_buitenblad_rechts: 14 mm; b_buitenblad_rechts_y: 0 mm; b_buitenblad_x: 0 mm; b_doorval_x: 60 mm; b_doorval_y: 600 mm; b_geveldrager_x: 0 mm; b_geveldrager_y: 6 mm; b_isolatie_boven: 96 mm; b_isolatie_links: 56 mm; b_isolatie_onder: 56 mm; b_isolatie_rechts: 56 mm; b_latei_x: 0 mm; b_latei_y: 0 mm; b_rekje_x: 0 mm; b_rekje_y: 0 mm; b_spouwlat_boven_y: 0 mm; b_spouwlat_links_y: 0 mm; b_spouwlat_onder_y: 0 mm; b_spouwlat_rechts_y: 0 mm; b_spouwlat_x: 0 mm; b_vensterbank_x: 298 mm; b_vensterbank_y: 34 mm; b_ventilatie_x: 228 mm; b_ventilatie_y: 0 mm; b_waterslag_x: 0 mm; b_waterslag_y: 166 mm; berekende_binnen-buiten_host: 220 mm; offset_binnenblad_boven_2: 28 mm; offset_binnenblad_links_2: 114.5 mm; offset_binnenblad_onder_2: 59 mm; offset_binnenblad_rechts_2: 150 mm
Basic Wall:22_WA_voorzetwand_ms100 25-75 _gen_bdg:3267593 | 01 eerste verdieping | 2E(22.11) Uniformat (Uniformat) | 01 eerste verdieping | 850 | 2. nieuwbouw | 4.15957 | 2020 | 1238.5 | Workset1 | 670 | Windows | NLRS_31_WI_WB_sparingmaker_generiek_BDG | NLRS_31_WI_WB_sparingmaker_generiek_BDG: mw_hsb_raam negge 180_alu v1 hoek | 2870 | 772577 | mw_hsb_raam negge 180_alu v1 hoek | 2239354 | <None> | Schematic Type | 31 | 20160502 | buitenblad Detail | 88 | mw_hsb_raam negge 180_alu v1 hoek | Family : Windows : NLRS_31_WI_WB_sparingmaker_generiek_BDG | Windows | NLRS_31_WI_WB_sparingmaker_generiek_BDG | General - samenstelling: NLRS_31_WI_UN_samenstelling_leeg_generiek_ISR : std; Dimensions - NLRS_C_breedte: 1238.5 mm; NLRS_C_hoogte: 2020 mm; Layers(Type) - binnenblad_afwerking_boven: yes; binnenblad_afwerking_boven_hoek_links: 0 deg; binnenblad_afwerking_boven_hoek_rechts: 0 deg; binnenblad_afwerking_boven_plaatsing_y: 17 mm; binnenblad_afwerking_boven_type: NLRS_41_GM_WPB_multiplex-SH_generiek_ISR : 151x10 gipsvezel dagkant; binnenblad_afwerking_boven_verlenging_links: -45 mm; binnenblad_afwerking_boven_verlenging_rechts: -200 mm; binnenblad_afwerking_links: yes; binnenblad_afwerking_links_hoek_boven: 0 deg; binnenblad_afwerking_links_hoek_onder: 0 deg; binnenblad_afwerking_links_plaatsing_y: 131.5 mm; binnenblad_afwerking_links_type: NLRS_41_GM_WPB_multiplex-SH_generiek_ISR : 151x10 gipsvezel dagkant; binnenblad_afwerking_links_verlenging_boven: -27 mm; binnenblad_afwerking_links_verlenging_onder: -94 mm; binnenblad_afwerking_plaatsing_x: 149 mm; binnenblad_afwerking_rechts: no; binnenblad_afwerking_rechts_hoek_boven: 0 deg; binnenblad_afwerking_rechts_hoek_onder: 0 deg; binnenblad_afwerking_rechts_plaatsing_y: 45 mm; binnenblad_afwerking_rechts_type: NLRS_41_GM_WPB_multiplex-SH_generiek_ISR : 151x10 gipsvezel dagkant; binnenblad_afwerking_rechts_verlenging_boven: -27 mm; binnenblad_afwerking_rechts_verlenging_onder: -94 mm; buitenblad_afwerking_boven: no; buitenblad_afwerking_boven_hoek_links: 0 deg; buitenblad_afwerking_boven_hoek_rechts: 0 deg; buitenblad_afwerking_boven_plaatsing_y: 0 mm; buitenblad_afwerking_boven_type: NLRS_41_GM_WPB_omgezet metselwerk-SH_generiek_ISR : std; buitenblad_afwerking_boven_verlenging_links: 0 mm; buitenblad_afwerking_boven_verlenging_rechts: 0 mm; buitenblad_afwerking_links: no; buitenblad_afwerking_links_hoek_boven: 0 deg; buitenblad_afwerking_links_hoek_onder: 0 deg; buitenblad_afwerking_links_plaatsing_y: 0 mm; buitenblad_afwerking_links_type: NLRS_41_GM_WPB_omgezet metselwerk-SH_generiek_ISR : std; buitenblad_afwerking_links_verlenging_boven: 0 mm; buitenblad_afwerking_links_verlenging_onder: 0 mm; buitenblad_afwerking_plaatsing_x: 0 mm; buitenblad_afwerking_rechts: no; buitenblad_afwerking_rechts_hoek_boven: 0 deg; buitenblad_afwerking_rechts_hoek_onder: 0 deg; buitenblad_afwerking_rechts_plaatsing_y: 0 mm; buitenblad_afwerking_rechts_type: NLRS_41_GM_WPB_omgezet metselwerk-SH_generiek_ISR : std; buitenblad_afwerking_rechts_verlenging_boven: 0 mm; buitenblad_afwerking_rechts_verlenging_onder: 0 mm; Constraints(Type) - lossing_binnenblad: 0 mm; offset_binnenblad_boven: 28 mm; offset_binnenblad_links: 114.5 mm; offset_binnenblad_onder: 59 mm; offset_binnenblad_rechts: 150 mm; offset_binnenbladbeplating_boven: 17 mm; offset_binnenbladbeplating_links: 131.5 mm; offset_binnenbladbeplating_onder: 17 mm; offset_binnenbladbeplating_rechts: 45 mm; offset_buitenblad_boven: 12 mm; offset_buitenblad_links: 7 mm; offset_buitenblad_onder: 70 mm; offset_buitenblad_rechts: 7 mm; offset_isolatie_boven: 48 mm; offset_isolatie_links: 28 mm; offset_isolatie_onder: 28 mm; offset_isolatie_rechts: 28 mm; Structural(Type) - rekje: no; rekje_plaatsing_x: 0 mm; rekje_plaatsing_y: 0 mm; rekje_type: NLRS_41_GM_WPB_rekje-SH_generiek_ISR : std; rekje_verlenging_links: 200 mm; rekje_verlenging_rechts: 200 mm; spouwlat_boven: yes; spouwlat_boven_plaatsing_y: -17 mm; spouwlat_boven_type: NLRS_41_GM_WPB_spouwlat-SH_generiek_ISR : 185x45; spouwlat_boven_verlenging_links: 112 mm; spouwlat_boven_verlenging_rechts: 28 mm; spouwlat_links: yes; spouwlat_links_plaatsing_y: -17 mm; spouwlat_links_type: NLRS_41_GM_WPB_spouwlat_isolatie_gen_bdg : 187x38 + isolatie 93.5x187; spouwlat_links_verlenging_boven: -17 mm; spouwlat_links_verlenging_onder: -17 mm; spouwlat_onder: yes; spouwlat_onder_plaatsing_y: -17 mm; spouwlat_onder_type: NLRS_41_GM_WPB_spouwlat-SH_generiek_ISR : 185x76; spouwlat_onder_verlenging_links: 112 mm; spouwlat_onder_verlenging_rechts: 28 mm; spouwlat_plaatsing_x: -275 mm; spouwlat_rechts: no; spouwlat_rechts_plaatsing_y: -17 mm; spouwlat_rechts_type: NLRS_41_GM_WPB_spouwlat-SH_generiek_ISR : 185x45; spouwlat_rechts_verlenging_boven: -17 mm; spouwlat_rechts_verlenging_onder: -17 mm; Materials and Finishes(Type) - geveldrager: yes; geveldrager_hoek_a: 45 deg; geveldrager_hoek_b: 0 deg; geveldrager_plaatsing_x: -10 mm; geveldrager_plaatsing_y: 3 mm; geveldrager_type: NLRS_41_SF_LIB_latei_staal_generiek_ISR : 90x150; geveldrager_verlenging_a: 0 mm; geveldrager_verlenging_b: 0 mm; latei: no; latei_hoek_a: 45 deg; latei_hoek_b: 0 deg; latei_plaatsing_x: 0 mm; latei_plaatsing_y: 0 mm; latei_type: NLRS_41_SF_LIB_latei_beton_generiek_ISR : 150x100; latei_verlenging_a: 100 mm; latei_verlenging_b: 100 mm; vensterbank: yes; vensterbank_hoek_a: 0 deg; vensterbank_hoek_b: -45 deg; vensterbank_plaatsing_x: 149 mm; vensterbank_plaatsing_y: 17 mm; vensterbank_type: NLRS_42_GM_WPB_vensterbank_natuursteen-SH_generiek_ISR : 180x18 vensterbank composiet; vensterbank_verlenging_a: -131.5 mm; vensterbank_verlenging_b: -152 mm; waterslag: yes; waterslag_hoek_a: 45 deg; waterslag_hoek_b: 0 deg; waterslag_plaatsing_x: -125 mm; waterslag_plaatsing_y: 83 mm; waterslag_type: NLRS_41_GM_WPB_waterslag barok-SH_roval_ISR : waterslag_roval_Types Barok_roval_b 320; waterslag_verlenging_a: 20 mm; waterslag_verlenging_b: 0 mm; Graphics(Type) - doorval_hoek_links: 0 deg; doorval_hoek_rechts: 0 deg; doorval_plaatsing_x: 30 mm; doorval_plaatsing_y: 300 mm; doorval_type: NLRS_41_GM_WPB_doorvalbeveiliging-SH_generiek_ISR : std; doorval_verlenging_links: 0 mm; doorval_verlenging_rechts: 0 mm; doorvalbeveiliging: no; ventilatie: no; ventilatie_plaatsing_x: 114 mm; ventilatie_plaatsing_y: 0 mm; ventilatie_type: NLRS_41_GM_WPB_ventilatie-SH_topstream_ISR : std; ventilatie_verlenging_links: 0 mm; ventilatie_verlenging_rechts: 0 mm; Construction(Type) - binnenblad_beplating: 25 mm; binnenblad_hout: 275 mm; buitenblad: 180 mm; isolatie: 10 mm; luchtspouw: 30 mm; negge: 215 mm; Dimensions(Type) - binnenbladhost: yes; buitenbladhost: no; clashobject: no; wrapping_exterior: 0 mm; wrapping_interior: 0 mm; Identity Data(Type) - Assembly Description: buitenwandopeningen; Other(Type) - a_binnen_boven_1: 28 mm; a_binnen_boven_2: 28 mm; a_binnen_links_1: 114.5 mm; a_binnen_links_2: 114.5 mm; a_binnen_onder_1: 59 mm; a_binnen_onder_2: 59 mm; a_binnen_rechts_1: 150 mm; a_binnen_rechts_2: 150 mm; a_binnenbepl_boven_1: 17 mm; a_binnenbepl_links_1: 131.5 mm; a_binnenbepl_onder_1: 17 mm; a_binnenbepl_rechts_1: 45 mm; a_binnenwand_afwerking_boven_y: 17 mm; a_binnenwand_afwerking_links_y: 131.5 mm; a_binnenwand_afwerking_rechts_y: 45 mm; a_binnenwand_afwerking_x: 149 mm; a_buitenblad_boven: 12 mm; a_buitenblad_boven_y: 0 mm; a_buitenblad_links: 7 mm; a_buitenblad_links_y: 0 mm; a_buitenblad_onder: 70 mm; a_buitenblad_rechts: 7 mm; a_buitenblad_rechts_y: 0 mm; a_buitenblad_x: 0 mm; a_doorval_x: 30 mm; a_doorval_y: 300 mm; a_geveldrager_x: 10 mm; a_geveldrager_y: 3 mm; a_isolatie_boven: 48 mm; a_isolatie_links: 28 mm; a_isolatie_onder: 28 mm; a_isolatie_rechts: 28 mm; a_latei_x: 0 mm; a_latei_y: 0 mm; a_rekje_x: 0 mm; a_rekje_y: 0 mm; a_spouwlat_boven_y: 17 mm; a_spouwlat_links_y: 17 mm; a_spouwlat_onder_y: 17 mm; a_spouwlat_rechts_y: 17 mm; a_spouwlat_x: 275 mm; a_vensterbank_x: 149 mm; a_vensterbank_y: 17 mm; a_ventilatie_x: 114 mm; a_ventilatie_y: 0 mm; a_waterslag_x: 125 mm; a_waterslag_y: 83 mm; b_binnen_boven_1: 56 mm; b_binnen_boven_2: 56 mm; b_binnen_links_1: 229 mm; b_binnen_links_2: 229 mm; b_binnen_onder_1: 118 mm; b_binnen_onder_2: 118 mm; b_binnen_rechts_1: 300 mm; b_binnen_rechts_2: 300 mm; b_binnenwand_afwerking_boven_y: 34 mm; b_binnenwand_afwerking_links_y: 263 mm; b_binnenwand_afwerking_rechts_y: 90 mm; b_binnenwand_afwerking_x: 298 mm; b_buitenblad_boven: 24 mm; b_buitenblad_boven_y: 0 mm; b_buitenblad_links: 14 mm; b_buitenblad_links_y: 0 mm; b_buitenblad_onder: 140 mm; b_buitenblad_rechts: 14 mm; b_buitenblad_rechts_y: 0 mm; b_buitenblad_x: 0 mm; b_doorval_x: 60 mm; b_doorval_y: 600 mm; b_geveldrager_x: 0 mm; b_geveldrager_y: 6 mm; b_isolatie_boven: 96 mm; b_isolatie_links: 56 mm; b_isolatie_onder: 56 mm; b_isolatie_rechts: 56 mm; b_latei_x: 0 mm; b_latei_y: 0 mm; b_rekje_x: 0 mm; b_rekje_y: 0 mm; b_spouwlat_boven_y: 0 mm; b_spouwlat_links_y: 0 mm; b_spouwlat_onder_y: 0 mm; b_spouwlat_rechts_y: 0 mm; b_spouwlat_x: 0 mm; b_vensterbank_x: 298 mm; b_vensterbank_y: 34 mm; b_ventilatie_x: 228 mm; b_ventilatie_y: 0 mm; b_waterslag_x: 0 mm; b_waterslag_y: 166 mm; berekende_binnen-buiten_host: 220 mm; offset_binnenblad_boven_2: 28 mm; offset_binnenblad_links_2: 114.5 mm; offset_binnenblad_onder_2: 59 mm; offset_binnenblad_rechts_2: 150 mm
Basic Wall:22_WA_voorzetwand_ms100 25-75 _gen_bdg:3267593 | 01 eerste verdieping | 2E(22.11) Uniformat (Uniformat) | 01 eerste verdieping | 850 | 2. nieuwbouw | 4.772 | 2020 | 1398 | Workset1 | 727 | Windows | NLRS_31_WI_WB_sparingmaker_generiek_BDG | NLRS_31_WI_WB_sparingmaker_generiek_BDG: mw_hsb_raam negge 180_alu v1 eenz trappenhuis | 2870 | 772577 | mw_hsb_raam negge 180_alu v1 eenz trappenhuis | 4342761 | <None> | Schematic Type | 31 | 20160502 | buitenblad Detail | 108 | mw_hsb_raam negge 180_alu v1 eenz trappenhuis | Family : Windows : NLRS_31_WI_WB_sparingmaker_generiek_BDG | Windows | NLRS_31_WI_WB_sparingmaker_generiek_BDG | General - samenstelling: NLRS_31_WI_UN_samenstelling_leeg_generiek_ISR : std; Dimensions - NLRS_C_breedte: 1398 mm; NLRS_C_hoogte: 2020 mm; Layers(Type) - binnenblad_afwerking_boven: yes; binnenblad_afwerking_boven_hoek_links: 0 deg; binnenblad_afwerking_boven_hoek_rechts: 0 deg; binnenblad_afwerking_boven_plaatsing_y: 17 mm; binnenblad_afwerking_boven_type: NLRS_41_GM_WPB_multiplex-SH_generiek_ISR : 306x10 gipsvezel dagkant; binnenblad_afwerking_boven_verlenging_links: -45 mm; binnenblad_afwerking_boven_verlenging_rechts: -200 mm; binnenblad_afwerking_links: yes; binnenblad_afwerking_links_hoek_boven: 0 deg; binnenblad_afwerking_links_hoek_onder: 0 deg; binnenblad_afwerking_links_plaatsing_y: 131.5 mm; binnenblad_afwerking_links_type: NLRS_41_GM_WPB_multiplex-SH_generiek_ISR : 306x10 gipsvezel dagkant; binnenblad_afwerking_links_verlenging_boven: -27 mm; binnenblad_afwerking_links_verlenging_onder: -94 mm; binnenblad_afwerking_plaatsing_x: 149 mm; binnenblad_afwerking_rechts: no; binnenblad_afwerking_rechts_hoek_boven: 0 deg; binnenblad_afwerking_rechts_hoek_onder: 0 deg; binnenblad_afwerking_rechts_plaatsing_y: 45 mm; binnenblad_afwerking_rechts_type: NLRS_41_GM_WPB_multiplex-SH_generiek_ISR : 306x10 gipsvezel dagkant; binnenblad_afwerking_rechts_verlenging_boven: -27 mm; binnenblad_afwerking_rechts_verlenging_onder: -94 mm; buitenblad_afwerking_boven: no; buitenblad_afwerking_boven_hoek_links: 0 deg; buitenblad_afwerking_boven_hoek_rechts: 0 deg; buitenblad_afwerking_boven_plaatsing_y: 0 mm; buitenblad_afwerking_boven_type: NLRS_41_GM_WPB_omgezet metselwerk-SH_generiek_ISR : std; buitenblad_afwerking_boven_verlenging_links: 0 mm; buitenblad_afwerking_boven_verlenging_rechts: 0 mm; buitenblad_afwerking_links: no; buitenblad_afwerking_links_hoek_boven: 0 deg; buitenblad_afwerking_links_hoek_onder: 0 deg; buitenblad_afwerking_links_plaatsing_y: 0 mm; buitenblad_afwerking_links_type: NLRS_41_GM_WPB_omgezet metselwerk-SH_generiek_ISR : std; buitenblad_afwerking_links_verlenging_boven: 0 mm; buitenblad_afwerking_links_verlenging_onder: 0 mm; buitenblad_afwerking_plaatsing_x: 0 mm; buitenblad_afwerking_rechts: no; buitenblad_afwerking_rechts_hoek_boven: 0 deg; buitenblad_afwerking_rechts_hoek_onder: 0 deg; buitenblad_afwerking_rechts_plaatsing_y: 0 mm; buitenblad_afwerking_rechts_type: NLRS_41_GM_WPB_omgezet metselwerk-SH_generiek_ISR : std; buitenblad_afwerking_rechts_verlenging_boven: 0 mm; buitenblad_afwerking_rechts_verlenging_onder: 0 mm; Constraints(Type) - lossing_binnenblad: 0 mm; offset_binnenblad_boven: 148 mm; offset_binnenblad_links: 114.5 mm; offset_binnenblad_onder: 59 mm; offset_binnenblad_rechts: 150 mm; offset_binnenbladbeplating_boven: 17 mm; offset_binnenbladbeplating_links: 131.5 mm; offset_binnenbladbeplating_onder: 17 mm; offset_binnenbladbeplating_rechts: 45 mm; offset_buitenblad_boven: 7 mm; offset_buitenblad_links: 7 mm; offset_buitenblad_onder: 70 mm; offset_buitenblad_rechts: 7 mm; offset_isolatie_boven: 48 mm; offset_isolatie_links: 28 mm; offset_isolatie_onder: 28 mm; offset_isolatie_rechts: 28 mm; Structural(Type) - rekje: no; rekje_plaatsing_x: 0 mm; rekje_plaatsing_y: 0 mm; rekje_type: NLRS_41_GM_WPB_rekje-SH_generiek_ISR : std; rekje_verlenging_links: 200 mm; rekje_verlenging_rechts: 200 mm; spouwlat_boven: yes; spouwlat_boven_plaatsing_y: -17 mm; spouwlat_boven_type: NLRS_41_GM_WPB_spouwlat_isolatie_gen_bdg : 187x38 + isolatie 127x200; spouwlat_boven_verlenging_links: 112 mm; spouwlat_boven_verlenging_rechts: 28 mm; spouwlat_links: yes; spouwlat_links_plaatsing_y: -17 mm; spouwlat_links_type: NLRS_41_GM_WPB_spouwlat_isolatie_gen_bdg : 187x38 + isolatie 93.5x187; spouwlat_links_verlenging_boven: -17 mm; spouwlat_links_verlenging_onder: -17 mm; spouwlat_onder: yes; spouwlat_onder_plaatsing_y: -17 mm; spouwlat_onder_type: NLRS_41_GM_WPB_spouwlat-SH_generiek_ISR : 185x76; spouwlat_onder_verlenging_links: 112 mm; spouwlat_onder_verlenging_rechts: 28 mm; spouwlat_plaatsing_x: -275 mm; spouwlat_rechts: no; spouwlat_rechts_plaatsing_y: -17 mm; spouwlat_rechts_type: NLRS_41_GM_WPB_spouwlat-SH_generiek_ISR : 185x45; spouwlat_rechts_verlenging_boven: -17 mm; spouwlat_rechts_verlenging_onder: -17 mm; Materials and Finishes(Type) - geveldrager: yes; geveldrager_hoek_a: 0 deg; geveldrager_hoek_b: 0 deg; geveldrager_plaatsing_x: -10 mm; geveldrager_plaatsing_y: 3 mm; geveldrager_type: NLRS_41_SF_LIB_latei_staal_generiek_ISR : 90x150; geveldrager_verlenging_a: 0 mm; geveldrager_verlenging_b: 0 mm; latei: no; latei_hoek_a: 0 deg; latei_hoek_b: 0 deg; latei_plaatsing_x: 0 mm; latei_plaatsing_y: 0 mm; latei_type: NLRS_41_SF_LIB_latei_beton_generiek_ISR : 150x100; latei_verlenging_a: 100 mm; latei_verlenging_b: 100 mm; vensterbank: yes; vensterbank_hoek_a: 0 deg; vensterbank_hoek_b: 0 deg; vensterbank_plaatsing_x: 149 mm; vensterbank_plaatsing_y: 17 mm; vensterbank_type: NLRS_42_GM_WPB_vensterbank_natuursteen-SH_generiek_ISR : 335x18 vensterbank composiet; vensterbank_verlenging_a: -131.5 mm; vensterbank_verlenging_b: -187.5 mm; waterslag: yes; waterslag_hoek_a: 0 deg; waterslag_hoek_b: 0 deg; waterslag_plaatsing_x: -125 mm; waterslag_plaatsing_y: 83 mm; waterslag_type: NLRS_41_GM_WPB_waterslag barok-SH_roval_ISR : waterslag_roval_Types Barok_roval_b 320; waterslag_verlenging_a: -7 mm; waterslag_verlenging_b: 0 mm; Graphics(Type) - doorval_hoek_links: 0 deg; doorval_hoek_rechts: 0 deg; doorval_plaatsing_x: 30 mm; doorval_plaatsing_y: 300 mm; doorval_type: NLRS_41_GM_WPB_doorvalbeveiliging-SH_generiek_ISR : std; doorval_verlenging_links: 0 mm; doorval_verlenging_rechts: 0 mm; doorvalbeveiliging: no; ventilatie: no; ventilatie_plaatsing_x: 114 mm; ventilatie_plaatsing_y: 0 mm; ventilatie_type: NLRS_41_GM_WPB_ventilatie-SH_topstream_ISR : std; ventilatie_verlenging_links: 0 mm; ventilatie_verlenging_rechts: 0 mm; Construction(Type) - binnenblad_beplating: 200 mm; binnenblad_hout: 275 mm; buitenblad: 180 mm; isolatie: 10 mm; luchtspouw: 30 mm; negge: 215 mm; Dimensions(Type) - binnenbladhost: yes; buitenbladhost: no; clashobject: no; wrapping_exterior: 0 mm; wrapping_interior: 0 mm; Identity Data(Type) - Assembly Description: buitenwandopeningen; Other(Type) - a_binnen_boven_1: 148 mm; a_binnen_boven_2: 148 mm; a_binnen_links_1: 114.5 mm; a_binnen_links_2: 114.5 mm; a_binnen_onder_1: 59 mm; a_binnen_onder_2: 59 mm; a_binnen_rechts_1: 150 mm; a_binnen_rechts_2: 150 mm; a_binnenbepl_boven_1: 17 mm; a_binnenbepl_links_1: 131.5 mm; a_binnenbepl_onder_1: 17 mm; a_binnenbepl_rechts_1: 45 mm; a_binnenwand_afwerking_boven_y: 17 mm; a_binnenwand_afwerking_links_y: 131.5 mm; a_binnenwand_afwerking_rechts_y: 45 mm; a_binnenwand_afwerking_x: 149 mm; a_buitenblad_boven: 7 mm; a_buitenblad_boven_y: 0 mm; a_buitenblad_links: 7 mm; a_buitenblad_links_y: 0 mm; a_buitenblad_onder: 70 mm; a_buitenblad_rechts: 7 mm; a_buitenblad_rechts_y: 0 mm; a_buitenblad_x: 0 mm; a_doorval_x: 30 mm; a_doorval_y: 300 mm; a_geveldrager_x: 10 mm; a_geveldrager_y: 3 mm; a_isolatie_boven: 48 mm; a_isolatie_links: 28 mm; a_isolatie_onder: 28 mm; a_isolatie_rechts: 28 mm; a_latei_x: 0 mm; a_latei_y: 0 mm; a_rekje_x: 0 mm; a_rekje_y: 0 mm; a_spouwlat_boven_y: 17 mm; a_spouwlat_links_y: 17 mm; a_spouwlat_onder_y: 17 mm; a_spouwlat_rechts_y: 17 mm; a_spouwlat_x: 275 mm; a_vensterbank_x: 149 mm; a_vensterbank_y: 17 mm; a_ventilatie_x: 114 mm; a_ventilatie_y: 0 mm; a_waterslag_x: 125 mm; a_waterslag_y: 83 mm; b_binnen_boven_1: 296 mm; b_binnen_boven_2: 296 mm; b_binnen_links_1: 229 mm; b_binnen_links_2: 229 mm; b_binnen_onder_1: 118 mm; b_binnen_onder_2: 118 mm; b_binnen_rechts_1: 300 mm; b_binnen_rechts_2: 300 mm; b_binnenwand_afwerking_boven_y: 34 mm; b_binnenwand_afwerking_links_y: 263 mm; b_binnenwand_afwerking_rechts_y: 90 mm; b_binnenwand_afwerking_x: 298 mm; b_buitenblad_boven: 14 mm; b_buitenblad_boven_y: 0 mm; b_buitenblad_links: 14 mm; b_buitenblad_links_y: 0 mm; b_buitenblad_onder: 140 mm; b_buitenblad_rechts: 14 mm; b_buitenblad_rechts_y: 0 mm; b_buitenblad_x: 0 mm; b_doorval_x: 60 mm; b_doorval_y: 600 mm; b_geveldrager_x: 0 mm; b_geveldrager_y: 6 mm; b_isolatie_boven: 96 mm; b_isolatie_links: 56 mm; b_isolatie_onder: 56 mm; b_isolatie_rechts: 56 mm; b_latei_x: 0 mm; b_latei_y: 0 mm; b_rekje_x: 0 mm; b_rekje_y: 0 mm; b_spouwlat_boven_y: 0 mm; b_spouwlat_links_y: 0 mm; b_spouwlat_onder_y: 0 mm; b_spouwlat_rechts_y: 0 mm; b_spouwlat_x: 0 mm; b_vensterbank_x: 298 mm; b_vensterbank_y: 34 mm; b_ventilatie_x: 228 mm; b_ventilatie_y: 0 mm; b_waterslag_x: 0 mm; b_waterslag_y: 166 mm; berekende_binnen-buiten_host: 220 mm; offset_binnenblad_boven_2: 148 mm; offset_binnenblad_links_2: 114.5 mm; offset_binnenblad_onder_2: 59 mm; offset_binnenblad_rechts_2: 150 mm
Basic Wall:NLRS_41_WA_aluminium voorzet 20+15+22_gen_ISR:3613219 | 00 begane grond | 41.12 Uniformat (Uniformat) |  |  |  |  |  |  | Workset1 |  | Lines: <Sketch> | Dimensions - Length: 448 mm
2 x Basic Wall:NLRS_20_WA_RVS Carlstahl 2 TRANS:1830774 | 02 tweede verdieping |  |  |  |  |  |  |  | BDG_fietsenstalling |  | Lines: <Sketch> | Dimensions - Length: 6094.54 mm
Basic Wall:22_WA_binnenwand_ms100 25-75 _gen_bdg:4493357 | 01 eerste verdieping | 2E(22.11) Uniformat (Uniformat) | 01 eerste verdieping | 0 | 2. nieuwbouw |  | 2387 | 1034 | Workset1 | 382 | Doors | NLRS_32_houten_binnenkozijn_met_zijlicht_BDG | NLRS_32_houten_binnenkozijn_met_zijlicht_BDG: BI-24w 930x2315 enkel 1ZL (1730) | 2387 | 4871045 | BI-24w 930x2315 enkel 1ZL (1730) | 2444405 | <None> | Schematic Type | 2E(32.3) | 14-11-2012 | wandsparing met houten binnenkozijn | BI-24w | BI-24w 930x2315 enkel 1ZL (1730) | Family : Doors : NLRS_32_houten_binnenkozijn_met_zijlicht_BDG | Doors | NLRS_32_houten_binnenkozijn_met_zijlicht_BDG | Construction - deur_in_wand_as: yes; host_dikte: 125 mm; kozijn_hoogte: 2387 mm; neggemaat: 0 mm; Other - berekende_negge: 600 mm; ref_rechts: 865 mm; Fire Protection(Type) - brand_zelfsluitend: no; brandw_120min: no; brandw_30min: no; brandw_60min: no; brandw_90min: no; deur_dikte: 40 mm; fire_rating: zie bijbehorende samenstelling; Text(Type) - rep_stijl_breedte: 67 mm; rep_stijl_diepte: 125 mm; rep_tussenstijl_breedte: 67 mm; rep_zelfsl.: no; Constraints(Type) - deur_breedte: 930 mm; ruimte_onder_deur: 15 mm; kozijn_breedte: 1730 mm; plafond_hoogte: 0 mm; Construction(Type) - Function: Interior; Construction Type: wandopening met kozijn; dorpel: no; stijl_breedte: 67 mm; stijl_diepte: 125 mm; Wall Closure: By host; zelfsluitend: no; samenstelling: 300_32_ISR_samenstelling_binnenkozijn_hout_met_zijlicht : enkele deur 1xZL; tussenstijl_breedte: 67 mm; tussenstijl_diepte: 125 mm; Dimensions(Type) - deur_hoogte: 2320 mm; dikte_onderdorpel: 25 mm; dubbele_deur: no; sponning_breedte: 17 mm; sponning_diepte: 50 mm; zijlicht_LR_verdelen: no; Identity Data(Type) - Fire Rating: zie bijbehorende samenstelling; Model: D; OmniClass Number: 23.30.10.00; OmniClass Title: Doors; SmartRevit_Versie: 2013.2; Type Comments: wandopening met samenstelling; Manufacturer: Rw = ntb; Graphics(Type) - deur_LR_wisselen: yes; WBDBO_tekst_andere_zijde: yes; Other(Type) - config_deur_dubbel 1xZL: 300_32_ISR_samenstelling_binnenkozijn_hout_met_zijlicht : dubbele deur 1xZL; config_deur_dubbel 2xZL: 300_32_ISR_samenstelling_binnenkozijn_hout_met_zijlicht : dubbele deur 1xZL; config_deur_enkel 1xZL: 300_32_ISR_samenstelling_binnenkozijn_hout_met_zijlicht : enkele deur 1xZL; config_deur_enkel 2xZL: 300_32_ISR_samenstelling_binnenkozijn_hout_met_zijlicht : enkele deur 2xZL
Basic Wall:22_WA_binnenwand_ms125 25-75-25 _gen_bdg:4868999 | 01 eerste verdieping | 2E(22.11) Uniformat (Uniformat) | 01 eerste verdieping | 0 | 2. nieuwbouw |  | 2387 | 1966 | Workset1 | 445 | Doors | NLRS_32_houten_binnenkozijn_met_zijlicht_BDG | NLRS_32_houten_binnenkozijn_met_zijlicht_BDG: BI-19w 930x2738 dubbel met glas 1ZL (2796) | 2387 | 4868796 | BI-19w 930x2738 dubbel met glas 1ZL (2796) | 4001767 | <None> | Schematic Type | 2E(32.3) | 14-11-2012 | wandsparing met houten binnenkozijn | BI-19w | BI-19w 930x2738 dubbel met glas 1ZL (2796) | Family : Doors : NLRS_32_houten_binnenkozijn_met_zijlicht_BDG | Doors | NLRS_32_houten_binnenkozijn_met_zijlicht_BDG | Construction - deur_in_wand_as: yes; host_dikte: 125 mm; kozijn_hoogte: 2387 mm; neggemaat: 20 mm; Other - berekende_negge: 600 mm; ref_rechts: 1398 mm; Fire Protection(Type) - brand_zelfsluitend: no; brandw_120min: no; brandw_30min: no; brandw_60min: no; brandw_90min: no; deur_dikte: 40 mm; fire_rating: zie bijbehorende samenstelling; Text(Type) - rep_stijl_breedte: 67 mm; rep_stijl_diepte: 125 mm; rep_tussenstijl_breedte: 67 mm; rep_zelfsl.: no; Constraints(Type) - deur_breedte: 930 mm; ruimte_onder_deur: 15 mm; kozijn_breedte: 2796 mm; plafond_hoogte: 0 mm; Construction(Type) - Function: Interior; Construction Type: wandopening met kozijn; dorpel: no; stijl_breedte: 67 mm; stijl_diepte: 125 mm; Wall Closure: By host; zelfsluitend: no; samenstelling: 300_32_ISR_samenstelling_binnenkozijn_hout_met_zijlicht : dubbele deur met glas 1xZL; tussenstijl_breedte: 67 mm; tussenstijl_diepte: 125 mm; Dimensions(Type) - deur_hoogte: 2320 mm; dikte_onderdorpel: 25 mm; dubbele_deur: yes; sponning_breedte: 17 mm; sponning_diepte: 50 mm; zijlicht_LR_verdelen: no; Identity Data(Type) - Fire Rating: zie bijbehorende samenstelling; Model: K; OmniClass Number: 23.30.10.00; OmniClass Title: Doors; SmartRevit_Versie: 2013.2; Type Comments: wandopening met samenstelling; Graphics(Type) - deur_LR_wisselen: no; WBDBO_tekst_andere_zijde: yes; Other(Type) - config_deur_dubbel 1xZL: 300_32_ISR_samenstelling_binnenkozijn_hout_met_zijlicht : dubbele deur met glas 1xZL; config_deur_dubbel 2xZL: 300_32_ISR_samenstelling_binnenkozijn_hout_met_zijlicht : dubbele deur met glas 2xZL; config_deur_enkel 1xZL: 300_32_ISR_samenstelling_binnenkozijn_hout_met_zijlicht : enkele deur met glas 1xZL; config_deur_enkel 2xZL: 300_32_ISR_samenstelling_binnenkozijn_hout_met_zijlicht : enkele deur met glas 2xZL
Basic Wall:22_WA_2xgips 25 _gen_bdg:4869562 | 01 eerste verdieping | 2E(22.11) Uniformat (Uniformat) | 01 eerste verdieping | 0 | 2. nieuwbouw |  | 2387 | 1966 | Workset1 | 445 | Doors | NLRS_32_houten_binnenkozijn_met_zijlicht_BDG | NLRS_32_houten_binnenkozijn_met_zijlicht_BDG: BI-19w 930x2738 dubbel met glas 1ZL (2796) | 2387 | 4868796 | BI-19w 930x2738 dubbel met glas 1ZL (2796) | 4001767 | <None> | Schematic Type | 2E(32.3) | 14-11-2012 | wandsparing met houten binnenkozijn | BI-19w | BI-19w 930x2738 dubbel met glas 1ZL (2796) | Family : Doors : NLRS_32_houten_binnenkozijn_met_zijlicht_BDG | Doors | NLRS_32_houten_binnenkozijn_met_zijlicht_BDG | Construction - deur_in_wand_as: yes; host_dikte: 125 mm; kozijn_hoogte: 2387 mm; neggemaat: 20 mm; Other - berekende_negge: 600 mm; ref_rechts: 1398 mm; Fire Protection(Type) - brand_zelfsluitend: no; brandw_120min: no; brandw_30min: no; brandw_60min: no; brandw_90min: no; deur_dikte: 40 mm; fire_rating: zie bijbehorende samenstelling; Text(Type) - rep_stijl_breedte: 67 mm; rep_stijl_diepte: 125 mm; rep_tussenstijl_breedte: 67 mm; rep_zelfsl.: no; Constraints(Type) - deur_breedte: 930 mm; ruimte_onder_deur: 15 mm; kozijn_breedte: 2796 mm; plafond_hoogte: 0 mm; Construction(Type) - Function: Interior; Construction Type: wandopening met kozijn; dorpel: no; stijl_breedte: 67 mm; stijl_diepte: 125 mm; Wall Closure: By host; zelfsluitend: no; samenstelling: 300_32_ISR_samenstelling_binnenkozijn_hout_met_zijlicht : dubbele deur met glas 1xZL; tussenstijl_breedte: 67 mm; tussenstijl_diepte: 125 mm; Dimensions(Type) - deur_hoogte: 2320 mm; dikte_onderdorpel: 25 mm; dubbele_deur: yes; sponning_breedte: 17 mm; sponning_diepte: 50 mm; zijlicht_LR_verdelen: no; Identity Data(Type) - Fire Rating: zie bijbehorende samenstelling; Model: K; OmniClass Number: 23.30.10.00; OmniClass Title: Doors; SmartRevit_Versie: 2013.2; Type Comments: wandopening met samenstelling; Graphics(Type) - deur_LR_wisselen: no; WBDBO_tekst_andere_zijde: yes; Other(Type) - config_deur_dubbel 1xZL: 300_32_ISR_samenstelling_binnenkozijn_hout_met_zijlicht : dubbele deur met glas 1xZL; config_deur_dubbel 2xZL: 300_32_ISR_samenstelling_binnenkozijn_hout_met_zijlicht : dubbele deur met glas 2xZL; config_deur_enkel 1xZL: 300_32_ISR_samenstelling_binnenkozijn_hout_met_zijlicht : enkele deur met glas 1xZL; config_deur_enkel 2xZL: 300_32_ISR_samenstelling_binnenkozijn_hout_met_zijlicht : enkele deur met glas 2xZL
Basic Wall:22_WA_2xgips 25 _gen_bdg:4869563 | 01 eerste verdieping | 2E(22.11) Uniformat (Uniformat) | 01 eerste verdieping | 0 | 2. nieuwbouw |  | 2387 | 1966 | Workset1 | 445 | Doors | NLRS_32_houten_binnenkozijn_met_zijlicht_BDG | NLRS_32_houten_binnenkozijn_met_zijlicht_BDG: BI-19w 930x2738 dubbel met glas 1ZL (2796) | 2387 | 4868796 | BI-19w 930x2738 dubbel met glas 1ZL (2796) | 4001767 | <None> | Schematic Type | 2E(32.3) | 14-11-2012 | wandsparing met houten binnenkozijn | BI-19w | BI-19w 930x2738 dubbel met glas 1ZL (2796) | Family : Doors : NLRS_32_houten_binnenkozijn_met_zijlicht_BDG | Doors | NLRS_32_houten_binnenkozijn_met_zijlicht_BDG | Construction - deur_in_wand_as: yes; host_dikte: 125 mm; kozijn_hoogte: 2387 mm; neggemaat: 20 mm; Other - berekende_negge: 600 mm; ref_rechts: 1398 mm; Fire Protection(Type) - brand_zelfsluitend: no; brandw_120min: no; brandw_30min: no; brandw_60min: no; brandw_90min: no; deur_dikte: 40 mm; fire_rating: zie bijbehorende samenstelling; Text(Type) - rep_stijl_breedte: 67 mm; rep_stijl_diepte: 125 mm; rep_tussenstijl_breedte: 67 mm; rep_zelfsl.: no; Constraints(Type) - deur_breedte: 930 mm; ruimte_onder_deur: 15 mm; kozijn_breedte: 2796 mm; plafond_hoogte: 0 mm; Construction(Type) - Function: Interior; Construction Type: wandopening met kozijn; dorpel: no; stijl_breedte: 67 mm; stijl_diepte: 125 mm; Wall Closure: By host; zelfsluitend: no; samenstelling: 300_32_ISR_samenstelling_binnenkozijn_hout_met_zijlicht : dubbele deur met glas 1xZL; tussenstijl_breedte: 67 mm; tussenstijl_diepte: 125 mm; Dimensions(Type) - deur_hoogte: 2320 mm; dikte_onderdorpel: 25 mm; dubbele_deur: yes; sponning_breedte: 17 mm; sponning_diepte: 50 mm; zijlicht_LR_verdelen: no; Identity Data(Type) - Fire Rating: zie bijbehorende samenstelling; Model: K; OmniClass Number: 23.30.10.00; OmniClass Title: Doors; SmartRevit_Versie: 2013.2; Type Comments: wandopening met samenstelling; Graphics(Type) - deur_LR_wisselen: no; WBDBO_tekst_andere_zijde: yes; Other(Type) - config_deur_dubbel 1xZL: 300_32_ISR_samenstelling_binnenkozijn_hout_met_zijlicht : dubbele deur met glas 1xZL; config_deur_dubbel 2xZL: 300_32_ISR_samenstelling_binnenkozijn_hout_met_zijlicht : dubbele deur met glas 2xZL; config_deur_enkel 1xZL: 300_32_ISR_samenstelling_binnenkozijn_hout_met_zijlicht : enkele deur met glas 1xZL; config_deur_enkel 2xZL: 300_32_ISR_samenstelling_binnenkozijn_hout_met_zijlicht : enkele deur met glas 2xZL
Basic Wall:22_WA_binnenwand_ms125 25-75-25 _gen_bdg:4871370 | 01 eerste verdieping | 2E(22.11) Uniformat (Uniformat) |  |  | 2. nieuwbouw | 4.35627 |  |  | Workset1 |  | Walls | Curtain Wall | Curtain Wall: 32_ontwerpkozijn binnen 125*67 |  |  | 32_ontwerpkozijn binnen 125*67 | 1227226 | Constraints - Base Constraint: 01 eerste verdieping; Base Offset: 0 mm; Top Offset: 0 mm; Unconnected Height: 2387 mm; Base is Attached: no; Related to Mass: no; Room Bounding: yes; Top is Attached: no; Cross-Section Definition - Cross-Section: Vertical; Horizontal Grid - Angle: 0 deg; Justification: Beginning; Number: 4; Offset: 0 mm; sets with these values: 2; Structural - Enable Analytical Model: no; Structural: no; Structural Usage: Non-bearing; Dimensions - Length: 1825 mm; Identity Data - Comments: BI-25bw
Basic Wall:22_WA_binnenwand_ms125 25-75-25 _gen_bdg:4871370 | 01 eerste verdieping | 2E(22.11) Uniformat (Uniformat) |  |  | 2. nieuwbouw | 5.7288 |  |  | Workset1 |  | Walls | Curtain Wall | Curtain Wall: 32_ontwerpkozijn binnen 125*67 |  |  | 32_ontwerpkozijn binnen 125*67 | 1227226 | Constraints - Base Constraint: 01 eerste verdieping; Base Offset: 0 mm; Top Offset: 0 mm; Unconnected Height: 2387 mm; Base is Attached: no; Related to Mass: no; Room Bounding: yes; Top is Attached: no; Cross-Section Definition - Cross-Section: Vertical; Horizontal Grid - Angle: 0 deg; Justification: Beginning; Number: 4; Offset: 0 mm; sets with these values: 2; Structural - Enable Analytical Model: no; Structural: no; Structural Usage: Non-bearing; Dimensions - Length: 2400 mm; Identity Data - Comments: BI-04w
Basic Wall:22_WA_binnenwand_ms125 25-75-25 _gen_bdg:4871488 | 01 eerste verdieping | 2E(22.11) Uniformat (Uniformat) |  |  | 2. nieuwbouw | 4.35627 |  |  | Workset1 |  | Walls | Curtain Wall | Curtain Wall: 32_ontwerpkozijn binnen 125*67 |  |  | 32_ontwerpkozijn binnen 125*67 | 1227226 | Constraints - Base Constraint: 01 eerste verdieping; Base Offset: 0 mm; Top Offset: 0 mm; Unconnected Height: 2387 mm; Base is Attached: no; Related to Mass: no; Room Bounding: yes; Top is Attached: no; Cross-Section Definition - Cross-Section: Vertical; Horizontal Grid - Angle: 0 deg; Justification: Beginning; Number: 4; Offset: 0 mm; sets with these values: 2; Structural - Enable Analytical Model: no; Structural: no; Structural Usage: Non-bearing; Dimensions - Length: 1825 mm; Identity Data - Comments: BI-25bw
Basic Wall:22_WA_binnenwand_ms125 25-75-25 _gen_bdg:4871488 | 01 eerste verdieping | 2E(22.11) Uniformat (Uniformat) | 01 eerste verdieping | 0 | 2. nieuwbouw |  | 2387 | 1966 | Workset1 | 484 | Doors | NLRS_32_houten_binnenkozijn_met_zijlicht_BDG | NLRS_32_houten_binnenkozijn_met_zijlicht_BDG: BI-19w 930x2738 dubbel met glas 1ZL (2796) | 2387 | 4871542 | BI-19w 930x2738 dubbel met glas 1ZL (2796) | 4001767 | <None> | Schematic Type | 2E(32.3) | 14-11-2012 | wandsparing met houten binnenkozijn | BI-19w | BI-19w 930x2738 dubbel met glas 1ZL (2796) | Family : Doors : NLRS_32_houten_binnenkozijn_met_zijlicht_BDG | Doors | NLRS_32_houten_binnenkozijn_met_zijlicht_BDG | Construction - deur_in_wand_as: yes; host_dikte: 125 mm; kozijn_hoogte: 2387 mm; neggemaat: 20 mm; Other - berekende_negge: 600 mm; ref_rechts: 1398 mm; Fire Protection(Type) - brand_zelfsluitend: no; brandw_120min: no; brandw_30min: no; brandw_60min: no; brandw_90min: no; deur_dikte: 40 mm; fire_rating: zie bijbehorende samenstelling; Text(Type) - rep_stijl_breedte: 67 mm; rep_stijl_diepte: 125 mm; rep_tussenstijl_breedte: 67 mm; rep_zelfsl.: no; Constraints(Type) - deur_breedte: 930 mm; ruimte_onder_deur: 15 mm; kozijn_breedte: 2796 mm; plafond_hoogte: 0 mm; Construction(Type) - Function: Interior; Construction Type: wandopening met kozijn; dorpel: no; stijl_breedte: 67 mm; stijl_diepte: 125 mm; Wall Closure: By host; zelfsluitend: no; samenstelling: 300_32_ISR_samenstelling_binnenkozijn_hout_met_zijlicht : dubbele deur met glas 1xZL; tussenstijl_breedte: 67 mm; tussenstijl_diepte: 125 mm; Dimensions(Type) - deur_hoogte: 2320 mm; dikte_onderdorpel: 25 mm; dubbele_deur: yes; sponning_breedte: 17 mm; sponning_diepte: 50 mm; zijlicht_LR_verdelen: no; Identity Data(Type) - Fire Rating: zie bijbehorende samenstelling; Model: K; OmniClass Number: 23.30.10.00; OmniClass Title: Doors; SmartRevit_Versie: 2013.2; Type Comments: wandopening met samenstelling; Graphics(Type) - deur_LR_wisselen: no; WBDBO_tekst_andere_zijde: yes; Other(Type) - config_deur_dubbel 1xZL: 300_32_ISR_samenstelling_binnenkozijn_hout_met_zijlicht : dubbele deur met glas 1xZL; config_deur_dubbel 2xZL: 300_32_ISR_samenstelling_binnenkozijn_hout_met_zijlicht : dubbele deur met glas 2xZL; config_deur_enkel 1xZL: 300_32_ISR_samenstelling_binnenkozijn_hout_met_zijlicht : enkele deur met glas 1xZL; config_deur_enkel 2xZL: 300_32_ISR_samenstelling_binnenkozijn_hout_met_zijlicht : enkele deur met glas 2xZL
Basic Wall:22_WA_binnenwand_ms125 25-75-25 _gen_bdg:4875166 | 02 tweede verdieping | 2E(22.11) Uniformat (Uniformat) | 02 tweede verdieping | 0 | 2. nieuwbouw |  | 2387 | 1966 | Workset1 | 494 | Doors | NLRS_32_houten_binnenkozijn_met_zijlicht_BDG | NLRS_32_houten_binnenkozijn_met_zijlicht_BDG: BI-19w 930x2738 dubbel met glas 1ZL (2796) | 2387 | 4875242 | BI-19w 930x2738 dubbel met glas 1ZL (2796) | 4001767 | <None> | Schematic Type | 2E(32.3) | 14-11-2012 | wandsparing met houten binnenkozijn | BI-19w | BI-19w 930x2738 dubbel met glas 1ZL (2796) | Family : Doors : NLRS_32_houten_binnenkozijn_met_zijlicht_BDG | Doors | NLRS_32_houten_binnenkozijn_met_zijlicht_BDG | Construction - deur_in_wand_as: yes; host_dikte: 125 mm; kozijn_hoogte: 2387 mm; neggemaat: 20 mm; Other - berekende_negge: 600 mm; ref_rechts: 1398 mm; Fire Protection(Type) - brand_zelfsluitend: no; brandw_120min: no; brandw_30min: no; brandw_60min: no; brandw_90min: no; deur_dikte: 40 mm; fire_rating: zie bijbehorende samenstelling; Text(Type) - rep_stijl_breedte: 67 mm; rep_stijl_diepte: 125 mm; rep_tussenstijl_breedte: 67 mm; rep_zelfsl.: no; Constraints(Type) - deur_breedte: 930 mm; ruimte_onder_deur: 15 mm; kozijn_breedte: 2796 mm; plafond_hoogte: 0 mm; Construction(Type) - Function: Interior; Construction Type: wandopening met kozijn; dorpel: no; stijl_breedte: 67 mm; stijl_diepte: 125 mm; Wall Closure: By host; zelfsluitend: no; samenstelling: 300_32_ISR_samenstelling_binnenkozijn_hout_met_zijlicht : dubbele deur met glas 1xZL; tussenstijl_breedte: 67 mm; tussenstijl_diepte: 125 mm; Dimensions(Type) - deur_hoogte: 2320 mm; dikte_onderdorpel: 25 mm; dubbele_deur: yes; sponning_breedte: 17 mm; sponning_diepte: 50 mm; zijlicht_LR_verdelen: no; Identity Data(Type) - Fire Rating: zie bijbehorende samenstelling; Model: K; OmniClass Number: 23.30.10.00; OmniClass Title: Doors; SmartRevit_Versie: 2013.2; Type Comments: wandopening met samenstelling; Graphics(Type) - deur_LR_wisselen: no; WBDBO_tekst_andere_zijde: yes; Other(Type) - config_deur_dubbel 1xZL: 300_32_ISR_samenstelling_binnenkozijn_hout_met_zijlicht : dubbele deur met glas 1xZL; config_deur_dubbel 2xZL: 300_32_ISR_samenstelling_binnenkozijn_hout_met_zijlicht : dubbele deur met glas 2xZL; config_deur_enkel 1xZL: 300_32_ISR_samenstelling_binnenkozijn_hout_met_zijlicht : enkele deur met glas 1xZL; config_deur_enkel 2xZL: 300_32_ISR_samenstelling_binnenkozijn_hout_met_zijlicht : enkele deur met glas 2xZL
Basic Wall:22_WA_2xgips 25 _gen_bdg:4875320 | 02 tweede verdieping | 2E(22.11) Uniformat (Uniformat) | 02 tweede verdieping | 0 | 2. nieuwbouw |  | 2387 | 1966 | Workset1 | 494 | Doors | NLRS_32_houten_binnenkozijn_met_zijlicht_BDG | NLRS_32_houten_binnenkozijn_met_zijlicht_BDG: BI-19w 930x2738 dubbel met glas 1ZL (2796) | 2387 | 4875242 | BI-19w 930x2738 dubbel met glas 1ZL (2796) | 4001767 | <None> | Schematic Type | 2E(32.3) | 14-11-2012 | wandsparing met houten binnenkozijn | BI-19w | BI-19w 930x2738 dubbel met glas 1ZL (2796) | Family : Doors : NLRS_32_houten_binnenkozijn_met_zijlicht_BDG | Doors | NLRS_32_houten_binnenkozijn_met_zijlicht_BDG | Construction - deur_in_wand_as: yes; host_dikte: 125 mm; kozijn_hoogte: 2387 mm; neggemaat: 20 mm; Other - berekende_negge: 600 mm; ref_rechts: 1398 mm; Fire Protection(Type) - brand_zelfsluitend: no; brandw_120min: no; brandw_30min: no; brandw_60min: no; brandw_90min: no; deur_dikte: 40 mm; fire_rating: zie bijbehorende samenstelling; Text(Type) - rep_stijl_breedte: 67 mm; rep_stijl_diepte: 125 mm; rep_tussenstijl_breedte: 67 mm; rep_zelfsl.: no; Constraints(Type) - deur_breedte: 930 mm; ruimte_onder_deur: 15 mm; kozijn_breedte: 2796 mm; plafond_hoogte: 0 mm; Construction(Type) - Function: Interior; Construction Type: wandopening met kozijn; dorpel: no; stijl_breedte: 67 mm; stijl_diepte: 125 mm; Wall Closure: By host; zelfsluitend: no; samenstelling: 300_32_ISR_samenstelling_binnenkozijn_hout_met_zijlicht : dubbele deur met glas 1xZL; tussenstijl_breedte: 67 mm; tussenstijl_diepte: 125 mm; Dimensions(Type) - deur_hoogte: 2320 mm; dikte_onderdorpel: 25 mm; dubbele_deur: yes; sponning_breedte: 17 mm; sponning_diepte: 50 mm; zijlicht_LR_verdelen: no; Identity Data(Type) - Fire Rating: zie bijbehorende samenstelling; Model: K; OmniClass Number: 23.30.10.00; OmniClass Title: Doors; SmartRevit_Versie: 2013.2; Type Comments: wandopening met samenstelling; Graphics(Type) - deur_LR_wisselen: no; WBDBO_tekst_andere_zijde: yes; Other(Type) - config_deur_dubbel 1xZL: 300_32_ISR_samenstelling_binnenkozijn_hout_met_zijlicht : dubbele deur met glas 1xZL; config_deur_dubbel 2xZL: 300_32_ISR_samenstelling_binnenkozijn_hout_met_zijlicht : dubbele deur met glas 2xZL; config_deur_enkel 1xZL: 300_32_ISR_samenstelling_binnenkozijn_hout_met_zijlicht : enkele deur met glas 1xZL; config_deur_enkel 2xZL: 300_32_ISR_samenstelling_binnenkozijn_hout_met_zijlicht : enkele deur met glas 2xZL
Basic Wall:22_WA_voorzetwand_ms100 25-75 _gen_bdg:5033381 | 00 begane grond | 2E(22.11) Uniformat (Uniformat) | 00 begane grond |  | 2. nieuwbouw | 0.916815 |  |  | Workset1 | 130 | Plumbing Fixtures | 300_74_ISR_brandslanghaspel_inbouw | 300_74_ISR_brandslanghaspel_inbouw: 65_BDG_BSH 30 m¹ |  |  | 65_BDG_BSH 30 m¹ | 1812937 | Constraints - Elevation from Level: 800 mm; Schedule Level: 00 begane grond; Host: Basic Wall : 22_WA_voorzetwand_ms100 25-75 _gen_bdg; Dimensions - Volume: 0.115459 m3; Mechanical - brandslanghaspel_kw_flow: 0.361 m3/s; System Classification: Domestic Cold Water; Graphics - slang_bereik: no
Basic Wall:21_WA_tegelwerk 10:5057061 | 00 begane grond | 2D(21.10) Uniformat (Uniformat) | 00 begane grond |  | 2. nieuwbouw | 0.6915 |  |  | Workset1 |  | Generic Models | NLRS_70_FUS_wandspiegel_gen_bdg | NLRS_70_FUS_wandspiegel_gen_bdg: 900x750mm |  |  | 900x750mm | 5052545 | Constraints - Elevation from Level: 1375 mm; Schedule Level: 00 begane grond; Host: <not associated>; Dimensions - Volume: 0.00675 m3
Basic Wall:22_WA_binnenwand_ms100 25-75 _gen_bdg:5081102 | 01 eerste verdieping | 2E(22.11) Uniformat (Uniformat) |  |  | 2. nieuwbouw |  |  |  | Workset1 |  | Generic Models | Generic Models 1 | Generic Models 1: Generic Models 1 |  |  | Generic Models 1 | 5087266 |  |  |  |  |  |  | Generic Models 1 | Workset1 | Generic Models | Generic Models 1 | Constraints - Moves With Nearby Elements: no
Basic Wall:22_WA_binnenwand_ms100 25-75 _gen_bdg:5081103 | 01 eerste verdieping | 2E(22.11) Uniformat (Uniformat) |  |  | 2. nieuwbouw |  |  |  | Workset1 |  | Generic Models | Generic Models 1 | Generic Models 1: Generic Models 1 |  |  | Generic Models 1 | 5087266 |  |  |  |  |  |  | Generic Models 1 | Workset1 | Generic Models | Generic Models 1 | Constraints - Moves With Nearby Elements: no
Basic Wall:22_WA_binnenwand_ms100 25-75 _gen_bdg:5081247 | 01 eerste verdieping | 2E(22.11) Uniformat (Uniformat) |  |  | 2. nieuwbouw |  |  |  | Workset1 |  | Generic Models | Generic Models 1 | Generic Models 1: Generic Models 1 |  |  | Generic Models 1 | 5087266 |  |  |  |  |  |  | Generic Models 1 | Workset1 | Generic Models | Generic Models 1 | Constraints - Moves With Nearby Elements: no
Basic Wall:NLRS_22_WA_HSB bispouw 30-245-12-13 glaswol_gen_ISR:772305 | 02 tweede verdieping
9 x Basic Wall:NLRS_22_WA_HSB bispouw 30-245-12-13 glaswol_gen_ISR:772307 | 02 tweede verdieping
16 x Basic Wall:NLRS_22_WA_HSB bispouw 30-245-12-13 glaswol_gen_ISR:772576 | 01 eerste verdieping
14 x Basic Wall:NLRS_22_WA_HSB bispouw 30-245-12-13 glaswol_gen_ISR:772577 | 01 eerste verdieping
16 x Basic Wall:NLRS_22_WA_HSB bispouw 30-245-12-13 glaswol_gen_ISR:772578 | 01 eerste verdieping
Basic Wall:NLRS_22_WA_HSB bispouw 30-245-12-13 glaswol_gen_ISR:772864 | 00 begane grond
Basic Wall:NLRS_22_WA_HSB bispouw 30-245-12-13 glaswol_gen_ISR:773244 | 00 begane grond
2 x Basic Wall:22_WA_binnenwand_ms125 25-75-25 _gen_bdg:875971 | 02 tweede verdieping
Basic Wall:22_WA_binnenwand_ms125 25-75-25 _gen_bdg:882212 | 02 tweede verdieping
Basic Wall:22_WA_binnenwand_ms125 25-75-25 _gen_bdg:882646 | 02 tweede verdieping
Basic Wall:22_WA_binnenwand_ms125 25-75-25 _gen_bdg:883342 | 02 tweede verdieping
2 x Basic Wall:22_WA_binnenwand_ms125 25-75-25 _gen_bdg:883587 | 02 tweede verdieping
2 x Basic Wall:22_WA_binnenwand_ms125 25-75-25 _gen_bdg:884331 | 02 tweede verdieping
2 x Basic Wall:22_WA_binnenwand_ms125 25-75-25 _gen_bdg:884509 | 02 tweede verdieping
Basic Wall:22_WA_binnenwand_ms125 25-75-25 _gen_bdg:885964 | 01 eerste verdieping
2 x Basic Wall:22_WA_binnenwand_ms125 25-75-25 _gen_bdg:887006 | 01 eerste verdieping
Basic Wall:22_WA_binnenwand_ms125 25-75-25 _gen_bdg:887320 | 01 eerste verdieping
2 x Basic Wall:22_WA_binnenwand_ms125 25-75-25 _gen_bdg:887921 | 01 eerste verdieping
2 x Basic Wall:22_WA_binnenwand_ms125 25-75-25 _gen_bdg:888483 | 01 eerste verdieping
Basic Wall:22_WA_binnenwand_ms125 25-75-25 _gen_bdg:889178 | 01 eerste verdieping
Basic Wall:22_WA_binnenwand_ms125 25-75-25 _gen_bdg:889217 | 01 eerste verdieping
Basic Wall:22_WA_binnenwand_ms125 25-75-25 _gen_bdg:890481 | 02 tweede verdieping
Basic Wall:22_WA_binnenwand_ms125 25-75-25 _gen_bdg:896080 | 01 eerste verdieping
Basic Wall:NLRS_22_WA_HSB bispouw 30-245-12-13 glaswol_gen_ISR:897586 | 00 begane grond
2 x Basic Wall:NLRS_22_WA_HSB bispouw 30-245-12-13 glaswol_gen_ISR:897842 | 00 begane grond
2 x Basic Wall:NLRS_22_WA_HSB bispouw 30-245-12-13 glaswol_gen_ISR:897869 | 00 begane grond
Basic Wall:22_WA_binnenwand_ms125 25-75-25 _gen_bdg:1218256 | 00 begane grond
2 x Basic Wall:22_WA_binnenwand_ms125 25-75-25 _gen_bdg:1218258 | 00 begane grond
2 x Basic Wall:22_WA_binnenwand_ms125 25-75-25 _gen_bdg:1218260 | 00 begane grond
3 x Basic Wall:22_WA_binnenwand_ms125 25-75-25 _gen_bdg:1218264 | 00 begane grond
Basic Wall:22_WA_binnenwand_ms125 25-75-25 _gen_bdg:1218267 | 00 begane grond
Basic Wall:22_WA_binnenwand_ms125 25-75-25 _gen_bdg:1218269 | 00 begane grond
3 x Basic Wall:22_WA_binnenwand_ms125 25-75-25 _gen_bdg:1218272 | 00 begane grond
2 x Basic Wall:22_WA_binnenwand_ms125 25-75-25 _gen_bdg:1218275 | 00 begane grond
2 x Basic Wall:22_WA_binnenwand_ms125 25-75-25 _gen_bdg:1218277 | 00 begane grond
2 x Basic Wall:22_WA_binnenwand_ms125 25-75-25 _gen_bdg:1218284 | 00 begane grond
Basic Wall:22_WA_binnenwand_ms125 25-75-25 _gen_bdg:1218292 | 00 begane grond
2 x Basic Wall:22_WA_binnenwand_ms125 25-75-25 _gen_bdg:1218294 | 00 begane grond
2 x Basic Wall:22_WA_binnenwand_ms125 25-75-25 _gen_bdg:1218296 | 00 begane grond
Basic Wall:22_WA_binnenwand_ms125 25-75-25 _gen_bdg:1218303 | 00 begane grond
2 x Basic Wall:22_WA_binnenwand_ms125 25-75-25 _gen_bdg:1218307 | 00 begane grond
Basic Wall:NLRS_22_WA_HSB bispouw 30-245-12-13 glaswol_gen_ISR:1219764 | 00 begane grond
Basic Wall:NLRS_22_WA_HSB bispouw 30-245-12-13 glaswol_gen_ISR:1220525 | 00 begane grond
2 x Basic Wall:NLRS_22_WA_HSB bispouw 30-245-12-13 glaswol_gen_ISR:1221337 | 00 begane grond
2 x Basic Wall:NLRS_22_WA_HSB bispouw 30-245-12-13 glaswol_gen_ISR:1222346 | 00 begane grond
2 x Basic Wall:NLRS_22_WA_HSB bispouw 30-245-12-13 glaswol_gen_ISR:1223365 | 00 begane grond
Basic Wall:NLRS_22_WA_HSB bispouw 30-245-12-13 glaswol_gen_ISR:1224034 | 00 begane grond
Basic Wall:NLRS_22_WA_HSB bispouw 30-245-12-13 glaswol_gen_ISR:1224142 | 00 begane grond
2 x Basic Wall:22_WA_binnenwand_ms125 25-75-25 _gen_bdg:1225369 | 00 begane grond
2 x Basic Wall:22_WA_binnenwand_ms125 25-75-25 _gen_bdg:1225371 | 00 begane grond
Basic Wall:22_WA_binnenwand_ms125 25-75-25 _gen_bdg:1330329 | 01 eerste verdieping
Basic Wall:22_WA_binnenwand_ms125 25-75-25 _gen_bdg:1336886 | 00 begane grond
3 x Basic Wall:22_WA_binnenwand_ms125 25-75-25 _gen_bdg:1337641 | 00 begane grond
2 x Basic Wall:22_WA_binnenwand_ms125 25-75-25 _gen_bdg:1359936 | 01 eerste verdieping
2 x Basic Wall:22_WA_binnenwand_ms125 25-75-25 _gen_bdg:1360041 | 01 eerste verdieping
2 x Basic Wall:22_WA_binnenwand_ms125 25-75-25 _gen_bdg:1360460 | 02 tweede verdieping
3 x Basic Wall:22_WA_kalkzandsteen_120mm:1368250 | 00 begane grond
2 x Basic Wall:22_WA_kalkzandsteen_120mm:1368308 | 00 begane grond
Basic Wall:22_WA_kalkzandsteen_120mm:1368560 | 00 begane grond
Basic Wall:22_WA_kalkzandsteen_120mm:1368821 | 00 begane grond
Basic Wall:22_WA_kalkzandsteen_120mm:1368942 | 00 begane grond
Basic Wall:NLRS_22_WA_HSB bispouw 30-245-12-13 glaswol_gen_ISR:1500020 | 00 begane grond
4 x Basic Wall:NLRS_22_WA_akoestische voorzetwand hout gym 96_gen_bdg:1500223 | 00 begane grond
Basic Wall:NLRS_22_WA_akoestische voorzetwand hout gym 96_gen_bdg:1510277 | 00 begane grond
Basic Wall:22_WA_binnenwand_ms125 25-75-25 _gen_bdg:1516281 | 02 tweede verdieping
Basic Wall:22_WA_binnenwand_ms125 25-75-25 _gen_bdg:1516439 | 02 tweede verdieping
Basic Wall:22_WA_binnenwand_ms125 25-75-25 _gen_bdg:1615334 | 00 begane grond
Basic Wall:NLRS_22_WA_HSB bispouw 30-245-12-13 glaswol_gen_ISR:1822551 | 00 begane grond
Basic Wall:22_WA_binnenwand_ms125 25-75-25 _gen_bdg:2073717 | 01 eerste verdieping
Basic Wall:22_WA_binnenwand_ms125 25-75-25 _gen_bdg:2089168 | 02 tweede verdieping
3 x Basic Wall:NLRS_22_WA_HSB bispouw 30-245-12-13 glaswol_gen_ISR:2335924 | 02 tweede verdieping
3 x Basic Wall:NLRS_22_WA_HSB bispouw 30-245-12-13 glaswol_gen_ISR:2336364 | 02 tweede verdieping
Basic Wall:NLRS_22_WA_HSB bispouw 30-245-12-13 glaswol_gen_ISR:2336465 | 02 tweede verdieping
2 x Basic Wall:NLRS_22_WA_HSB bispouw 30-245-12-13 glaswol_gen_ISR:2336545 | 02 tweede verdieping
Basic Wall:NLRS_22_WA_HSB bispouw 30-245-12-13 glaswol_gen_ISR:2336577 | 02 tweede verdieping
2 x Basic Wall:NLRS_22_WA_HSB bispouw 30-245-12-13 glaswol_gen_ISR:2338631 | 02 tweede verdieping
2 x Basic Wall:NLRS_22_WA_HSB bispouw 30-245-12-13 glaswol_gen_ISR:2338901 | 02 tweede verdieping
3 x Basic Wall:NLRS_22_WA_HSB bispouw 30-245-12-13 glaswol_gen_ISR:2338990 | 02 tweede verdieping
2 x Basic Wall:NLRS_22_WA_HSB bispouw 30-245-12-13 glaswol_gen_ISR:2339043 | 02 tweede verdieping
2 x Basic Wall:NLRS_22_WA_HSB bispouw 30-245-12-13 glaswol_gen_ISR:2339114 | 02 tweede verdieping
3 x Basic Wall:NLRS_22_WA_HSB bispouw 30-245-12-13 glaswol_gen_ISR:2339224 | 02 tweede verdieping
Basic Wall:NLRS_22_WA_HSB bispouw 30-245-12-13 glaswol_gen_ISR:2341393 | 02 tweede verdieping
3 x Basic Wall:NLRS_22_WA_HSB bispouw 30-245-12-13 glaswol_gen_ISR:2341550 | 02 tweede verdieping
Basic Wall:NLRS_22_WA_HSB bispouw 30-245-12-13 glaswol_gen_ISR:2341762 | 02 tweede verdieping
2 x Basic Wall:NLRS_22_WA_HSB bispouw 30-245-12-13 glaswol_gen_ISR:2341873 | 02 tweede verdieping
3 x Basic Wall:NLRS_22_WA_HSB bispouw 30-245-12-13 glaswol_gen_ISR:2342127 | 02 tweede verdieping
Basic Wall:NLRS_22_WA_HSB bispouw 30-245-12-13 glaswol_gen_ISR:2347297 | 00 begane grond
Basic Wall:NLRS_22_WA_HSB bispouw 30-245-12-13 glaswol_gen_ISR:2348540 | 00 begane grond
Basic Wall:NLRS_22_WA_HSB bispouw 30-245-12-13 glaswol_gen_ISR:2348840 | 00 begane grond
Basic Wall:NLRS_22_WA_HSB bispouw 30-245-12-13 glaswol_gen_ISR:2349608 | 00 begane grond
Basic Wall:NLRS_22_WA_HSB bispouw 30-245-12-13 glaswol_gen_ISR:2349780 | 00 begane grond
Basic Wall:NLRS_22_WA_HSB bispouw 30-245-12-13 glaswol_gen_ISR:2350073 | 00 begane grond
Basic Wall:22_WA_binnenwand_ms125 25-75-25 _gen_bdg:2437630 | 00 begane grond
Basic Wall:22_WA_binnenwand_ms125 25-75-25 _gen_bdg:2444394 | 01 eerste verdieping
Basic Wall:22_WA_binnenwand_ms125 25-75-25 _gen_bdg:2473493 | 00 begane grond
2 x Basic Wall:22_WA_binnenwand_ms125 25-75-25 _gen_bdg:2473573 | 00 begane grond
Basic Wall:22_WA_binnenwand_ms125 25-75-25 _gen_bdg:2474530 | 01 eerste verdieping
Basic Wall:22_WA_binnenwand_ms125 25-75-25 _gen_bdg:2476092 | 02 tweede verdieping
Basic Wall:22_WA_binnenwand_ms125 25-75-25 _gen_bdg:2476112 | 02 tweede verdieping
2 x Basic Wall:22_WA_binnenwand_ms125 25-75-25 _gen_bdg:2500529 | 00 begane grond
Basic Wall:22_WA_binnenwand_ms125 25-75-25 _gen_bdg:2715734 | 00 begane grond
Basic Wall:22_WA_binnenwand_ms125 25-75-25 _gen_bdg:2719867 | 00 begane grond
Basic Wall:NLRS_22_WA_HSB bispouw 30-245-12-13 glaswol_gen_ISR:2727333 | 00 begane grond
Basic Wall:NLRS_22_WA_HSB bispouw 30-245-12-13 glaswol_gen_ISR:2727573 | 00 begane grond
Basic Wall:NLRS_22_WA_HSB bispouw 30-245-12-13 glaswol_gen_ISR:2729110 | 00 begane grond
Basic Wall:NLRS_22_WA_HSB bispouw 30-245-12-13 glaswol_gen_ISR:2729820 | 00 begane grond
Basic Wall:NLRS_22_WA_HSB bispouw 30-245-12-13 glaswol_gen_ISR:2732862 | 00 begane grond
Basic Wall:NLRS_22_WA_HSB bispouw 30-245-12-13 glaswol_gen_ISR:3528058 | 00 begane grond
Basic Wall:22_WA_binnenwand_ms125 25-75-25 _gen_bdg:4868796 | 01 eerste verdieping
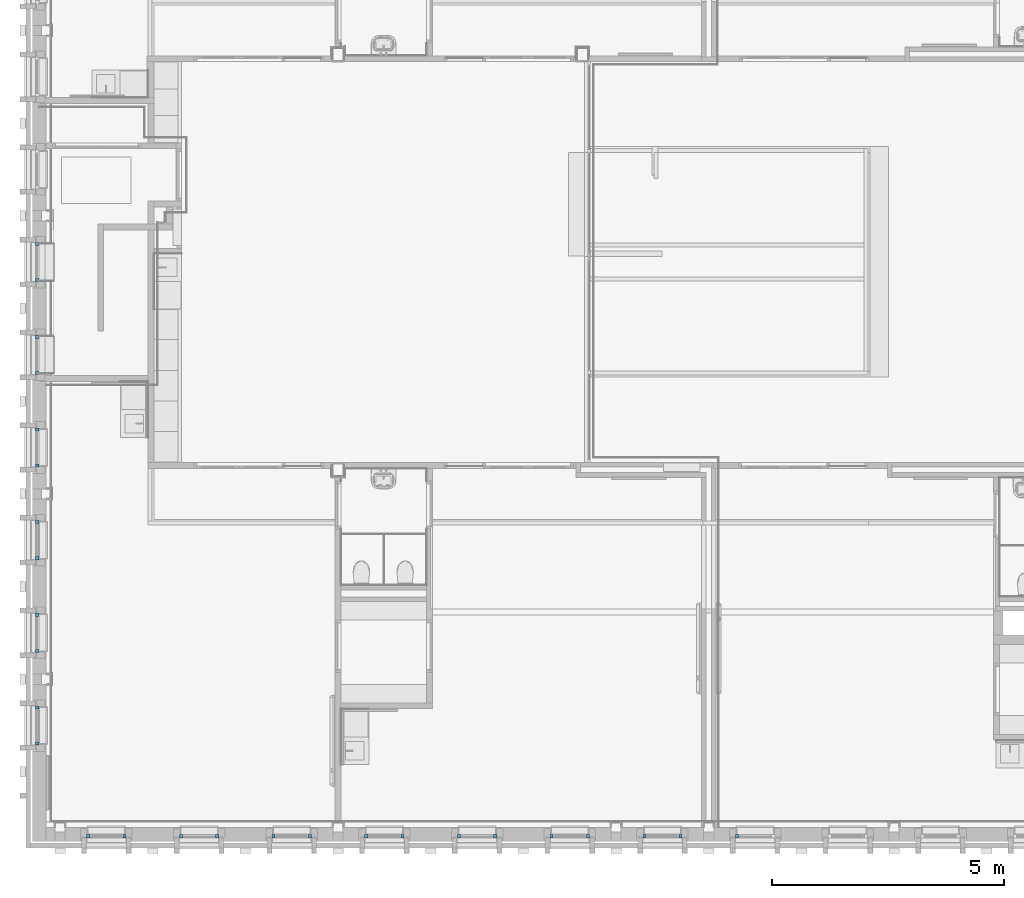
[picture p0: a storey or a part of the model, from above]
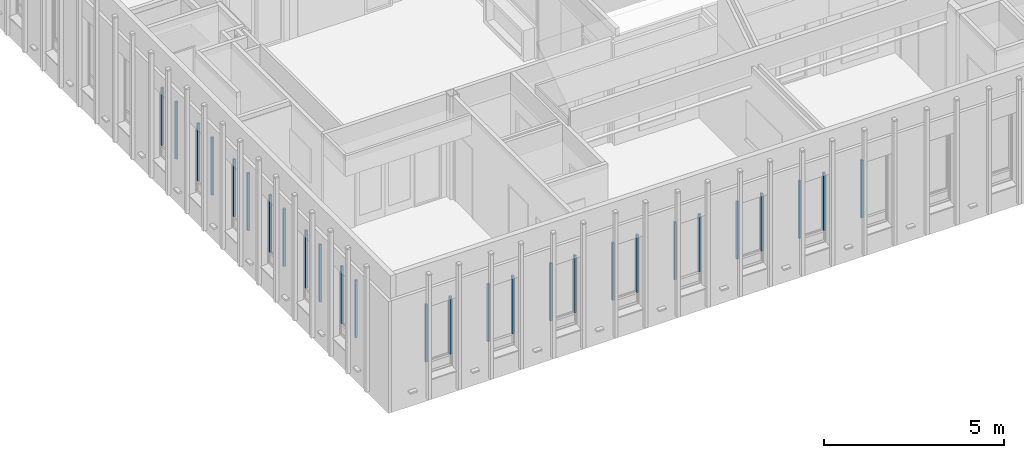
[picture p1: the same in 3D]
Properties of the parts of a building model (IFC2X3), part 81 of 94

# IfcOpeningElement: Opening (823)
Name | In | Classification | Level | Sill Height (mm) | Phase Created | Area (m2) | Height (mm) | Width (mm) | Identity Data, Workset | Mark | Other, Category | Family | Family and Type | Head Height (mm) | Host Id | Type | Type Id | Analytic Construction | Define Thermal Properties by | Assembly Code | Datum_Gewijzigd | Description | Type Mark | Type Name | Identity Data(Type), Workset | Other(Type), Category | Family Name
Basic Wall:22_WA_binnenwand_ms125 25-75-25 _gen_bdg:4869150 | 01 eerste verdieping
Basic Wall:22_WA_binnenwand_ms125 25-75-25 _gen_bdg:4871045 | 01 eerste verdieping
Basic Wall:22_WA_binnenwand_ms125 25-75-25 _gen_bdg:4871542 | 01 eerste verdieping
Basic Wall:22_WA_binnenwand_ms125 25-75-25 _gen_bdg:4873587 | 02 tweede verdieping
Basic Wall:22_WA_binnenwand_ms125 25-75-25 _gen_bdg:4873789 | 02 tweede verdieping
Basic Wall:22_WA_binnenwand_ms125 25-75-25 _gen_bdg:4874972 | 02 tweede verdieping
Basic Wall:22_WA_binnenwand_ms125 25-75-25 _gen_bdg:4875242 | 02 tweede verdieping

# IfcOpeningElement: Recess, Floor:NLRS_43_FL_cementdekvloer 60_gen_ISR:1295401
In: 00 begane grond
Classification: 43.21.11 Uniformat (Uniformat)
Constraints - Level: 00 begane grond; Moves With Nearby Elements: no; bk platformvloer: 0 mm
Phasing - Phase Created: 2. nieuwbouw
Dimensions - Area: 112.755 m2; Volume: 1.1223 m3
Identity Data - Workset: Workset1; Mark: 3
Other - Category: Mechanical Equipment; Family: Aesy_Lift_A5000_standaard; Family and Type: Aesy_Lift_A5000_standaard: liftschacht 1362 x 1520_glas_2_3_4_5; Host Id: 1295401; Type: liftschacht 1362 x 1520_glas_2_3_4_5; Type Id: 3081228

# IfcPlate: CP_NE Standard basic panel_Multiwal:NE - Select 100 K/U (5)
In: 00 begane grond
Type - Description: NE Normal Panel; PredefinedType: CURTAIN_PANEL; Material: ISR_Glas, Panel, Aluminium, black
Type - Analytical Properties - Define Thermal Properties by: Schematic Type; Analytic Construction: <None>
Type - Data - BIMObjectName: Pr_40_30_20_02-Multiwal-NE Normal Panel-LOD400; ClassificationName: Uniclass2015; ClassificationValue: Pr_40_30_20_02; COBie.Type.AccessibilityPerformance: N/A; COBie.Type.AssetType: Fixed; COBie.Type.Category: 23.25.20.14.11.11.17 - Infill Panels; COBie.Type.CodePerformance: N/A; COBie.Type.Constituents: N/A; COBie.Type.CreatedBy: Itannex bv; COBie.Type.CreatedOn: 2018.11.29; COBie.Type.Description: NE Normal Panel; COBie.Type.DurationUnit: N/A; COBie.Type.ExpectedLife: N/A; COBie.Type.Features: N/A; COBie.Type.Finish: N/A; COBie.Type.Grade: 3; COBie.Type.Manufacturer: Multiwal; COBie.Type.Material: N/A; COBie.Type.ModelNumber: N/A; COBie.Type.ModelReference: NE; COBie.Type.Name: Standard basic panel NE - 100 K/U; COBie.Type.ReplacementCost: 0; COBie.Type.Shape: Rectangular; COBie.Type.Size: Thickness 105mm; COBie.Type.SustainabilityPerformance: N/A; COBie.Type.WarrantyDescription: N/A; COBie.Type.WarrantyDurationLabor: N/A; COBie.Type.WarrantyDurationParts: N/A; COBie.Type.WarrantyDurationUnit: N/A; COBie.Type.WarrantyGuarantorLabor: N/A; COBie.Type.WarrantyGuarantorParts: N/A
Type - General - RSen_C_code_ETIM: EC011925; RSen_C_code_ETIM_url: https://prod.etim-international.com/Class/Details?classId=EC011925&classVersion=3; RSen_C_content_creator: Itannex bv
Type - Materials and Finishes - NLRS_C_materiaal_01: ISR_Glas; NLRS_C_materiaal_02: Aluminium, black
Type - Dimensions - s: 105 mm
Type - Identity Data - Assembly Code: 22.14; Assembly Description: binnenwanden; niet constructief, systeemwanden; verplaatsbaar; Description: NE Normal Panel; Manufacturer: Multiwal; Manufacturers Address: Norman Road, Rochdale, OL11 4HS, United Kingdom; Manufacturers Email: info@multiwal.co.uk; Manufacturers Telephone Number: +441273497370; Model: NE; NLRS_C_content_datum_gewijzigd: 2018.12.28; NLRS_C_content_provider: Multiwal; NLRS_C_content_versie: 1.0; OmniClass Number: 23.25.20.14.11.11.17; OmniClass Title: Infill Panels; RSen_C_product_description: Standard basic panel NE - 100 K/U; Type Comments: Thickness 105mm, for Select 100 K/U; Type Name: NE - Select 100 K/U; URL: https://uk.multiwal.eu/products/moveable-walls/moveable-wall-select/select-100-u/; Workset: Family : Curtain Panels : CP_NE Standard basic panel_Multiwal
Type - Other - Category: Curtain Panels; Family Name: CP_NE Standard basic panel_Multiwal; maxH: 12000 mm; maxW: 1260 mm; minH: 2000 mm; minW: 600 mm
Classification: 22.14 Uniformat (Uniformat); Group: Model Group:BI-11 8834x2800:2521973
Data - COBie.Type.NominalHeight: 2800 mm; COBie.Type.NominalWidth: 105 mm
Constraints - Level: 00 begane grond; soundproofing: 41; soundproofing_limits: 41-53 dB; window: yes; window_height: 2300 mm; window_height_offset: 0 mm; window_manual_dimensions: yes; window_width: 1180 mm
Phasing - Phase Created: 2. nieuwbouw
Materials and Finishes - NLRS_C_materiaal: Panel
Construction - height_warning: -
Dimensions - glass_height: 2100 mm; H: 2800 mm; Height: 2800 mm; NLRS_C_hoogte: 2800 mm; RSen_C_thickness: 105 mm
Identity Data - Workset: Workset1
Other - Host Id: 1322223; Family: CP_NE Standard basic panel_Multiwal; Family and Type: CP_NE Standard basic panel_Multiwal: NE - Select 100 K/U; glasspanel: yes; Type: NE - Select 100 K/U; Type Id: 1316251; Warning_height: no; window_H_check: 2100 mm; window_height_offset_check: 350 mm; window_offset: 100 mm
Name (CP_NE Standard basic panel_Multiwal:NE - Select 100 K/U:...) | COBie.Type.Area (m2) = Area (m2) | COBie.Type.Length (mm) = COBie.Type.NominalLength (mm) = NLRS_C_breedte (mm) = W (mm) = Width (mm) | width_warning | glass_width (mm) = window_W_check (mm) | Volume (m3) | Warning_width
1322226 | 3.63547 | 1298.38 | Element width too large | 1098.38 | 0.379062 | yes
1322228 | 3.48373 | 1244.19 | - | 1044.19 | 0.363241 | no
1322230 | 3.48373 | 1244.19 | - | 1044.19 | 0.363241 | no | Identity Data - Mark: 55
1322234 | 3.48373 | 1244.19 | - | 1044.19 | 0.363241 | no
1322236 | 3.57947 | 1278.38 | Element width too large | 1078.38 | 0.373223 | yes

# IfcPlate: CP_NE Standard basic panel_Multiwal:NE - Select 100 K/U, CP_NE Standard basic panel_Multiwal:NE - Select 100 K/U:1322238
In: 00 begane grond
Type - Description: NE Normal Panel; PredefinedType: CURTAIN_PANEL; Material: Panel, Aluminium, black
Type - Analytical Properties - Define Thermal Properties by: Schematic Type; Analytic Construction: <None>
Type - Data - BIMObjectName: Pr_40_30_20_02-Multiwal-NE Normal Panel-LOD400; ClassificationName: Uniclass2015; ClassificationValue: Pr_40_30_20_02; COBie.Type.AccessibilityPerformance: N/A; COBie.Type.AssetType: Fixed; COBie.Type.Category: 23.25.20.14.11.11.17 - Infill Panels; COBie.Type.CodePerformance: N/A; COBie.Type.Constituents: N/A; COBie.Type.CreatedBy: Itannex bv; COBie.Type.CreatedOn: 2018.11.29; COBie.Type.Description: NE Normal Panel; COBie.Type.DurationUnit: N/A; COBie.Type.ExpectedLife: N/A; COBie.Type.Features: N/A; COBie.Type.Finish: N/A; COBie.Type.Grade: 3; COBie.Type.Manufacturer: Multiwal; COBie.Type.Material: N/A; COBie.Type.ModelNumber: N/A; COBie.Type.ModelReference: NE; COBie.Type.Name: Standard basic panel NE - 100 K/U; COBie.Type.ReplacementCost: 0; COBie.Type.Shape: Rectangular; COBie.Type.Size: Thickness 105mm; COBie.Type.SustainabilityPerformance: N/A; COBie.Type.WarrantyDescription: N/A; COBie.Type.WarrantyDurationLabor: N/A; COBie.Type.WarrantyDurationParts: N/A; COBie.Type.WarrantyDurationUnit: N/A; COBie.Type.WarrantyGuarantorLabor: N/A; COBie.Type.WarrantyGuarantorParts: N/A
Type - General - RSen_C_code_ETIM: EC011925; RSen_C_code_ETIM_url: https://prod.etim-international.com/Class/Details?classId=EC011925&classVersion=3; RSen_C_content_creator: Itannex bv
Type - Materials and Finishes - NLRS_C_materiaal_01: ISR_Glas; NLRS_C_materiaal_02: Aluminium, black
Type - Dimensions - s: 105 mm
Type - Identity Data - Assembly Code: 22.14; Assembly Description: binnenwanden; niet constructief, systeemwanden; verplaatsbaar; Description: NE Normal Panel; Manufacturer: Multiwal; Manufacturers Address: Norman Road, Rochdale, OL11 4HS, United Kingdom; Manufacturers Email: info@multiwal.co.uk; Manufacturers Telephone Number: +441273497370; Model: NE; NLRS_C_content_datum_gewijzigd: 2018.12.28; NLRS_C_content_provider: Multiwal; NLRS_C_content_versie: 1.0; OmniClass Number: 23.25.20.14.11.11.17; OmniClass Title: Infill Panels; RSen_C_product_description: Standard basic panel NE - 100 K/U; Type Comments: Thickness 105mm, for Select 100 K/U; Type Name: NE - Select 100 K/U; URL: https://uk.multiwal.eu/products/moveable-walls/moveable-wall-select/select-100-u/; Workset: Family : Curtain Panels : CP_NE Standard basic panel_Multiwal
Type - Other - Category: Curtain Panels; Family Name: CP_NE Standard basic panel_Multiwal; maxH: 12000 mm; maxW: 1260 mm; minH: 2000 mm; minW: 600 mm
Classification: 22.14 Uniformat (Uniformat); Group: Model Group:BI-11 8834x2800:2521973
Data - COBie.Type.Area: 3.388 m2; COBie.Type.Length: 1210 mm; COBie.Type.NominalHeight: 2800 mm; COBie.Type.NominalLength: 1210 mm; COBie.Type.NominalWidth: 105 mm
Constraints - Level: 00 begane grond; window: no; window_manual_dimensions: no; soundproofing: 41; soundproofing_limits: 41-53 dB; window_height: 750 mm; window_height_offset: 500 mm; window_width: 1180 mm
Phasing - Phase Created: 2. nieuwbouw
Materials and Finishes - NLRS_C_materiaal: Panel
Construction - height_warning: -; width_warning: -
Dimensions - glass_height: 0 mm; glass_width: 0 mm; Area: 3.388 m2; H: 2800 mm; Height: 2800 mm; NLRS_C_breedte: 1210 mm; NLRS_C_hoogte: 2800 mm; RSen_C_thickness: 105 mm; Volume: 0.35326 m3; W: 1210 mm; Width: 1210 mm
Identity Data - Workset: Workset1
Other - glasspanel: no; Host Id: 1322223; Family: CP_NE Standard basic panel_Multiwal; Family and Type: CP_NE Standard basic panel_Multiwal: NE - Select 100 K/U; Type: NE - Select 100 K/U; Type Id: 1316251; Warning_height: no; Warning_width: no; window_H_check: 10 mm; window_height_offset_check: 2900 mm; window_offset: 600 mm; window_W_check: 10 mm

# IfcPlate: Screening 70-75:Screening 70-75 (10)
In: 01 eerste verdieping
Type - PredefinedType: CURTAIN_PANEL; Material: Aluminum - Duco - Anodized Silver
Type - Analytical Properties - Define Thermal Properties by: Schematic Type; Analytic Construction: <None>
Type - Materials and Finishes - Blade material: Aluminum - Duco - Anodized Silver
Type - Identity Data - OmniClass Number: 23.25.20.14.11.11.17; OmniClass Title: Infill Panels; Type Name: Screening 70-75; Workset: Family : Curtain Panels : Screening 70-75
Type - Other - Category: Curtain Panels; Family Name: Screening 70-75
Classification: B20 Uniformat (Uniformat)
Constraints - Level: 01 eerste verdieping
Phasing - Phase Created: 2. nieuwbouw
Dimensions - Blade pitch: 75 mm; Left side angle: 0 deg; Right side angle: 0 deg
Identity Data - Workset: Workset1
Other - Family: Screening 70-75; Family and Type: Screening 70-75: Screening 70-75; Type: Screening 70-75; Type Id: 3247641
Name (Screening 70-75:Screening 70-75:...) | Area (m2) | Height (mm) | Volume (m3) | Width (mm) | Bld_cnt = Bld_cnt_cntrl | Host Id
2178600 | 3.6306 | 2057 | 0.0208568 | 1765 | 26 | 2178599
2179970 | 0.294151 | 2057 | 0.00113289 | 143 | 26 | 2179969
2551644 | 0.253011 | 2057 | 0.000896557 | 123 | 26 | 2551643
3619506 | 0.367346 | 2057 | 0.0021103 | 178.583 | 26 | 2551643
2551729 | 3.61947 | 2567 | 0.0211476 | 1410 | 33 | 2551798
2551833 | 0.5134 | 2567 | 0.00299966 | 200 | 33 | 2551890
3620750 | 1.00241 | 2567 | 0.00585685 | 390.5 | 33 | 2551890
3195208 | 2.95975 | 2567 | 0.0172931 | 1153 | 33 | 3195265
3256903 | 2.2987 | 2057 | 0.0132053 | 1117.5 | 26 | 3256902
3617796 | 1.33191 | 2057 | 0.00765142 | 647.5 | 26 | 3256902

# IfcPlate: System Panel:CP_isolatie_60mm_offset30 (2)
Type - PredefinedType: CURTAIN_PANEL; Material: n7_isolatie_gen
Type - Analytical Properties - Define Thermal Properties by: Schematic Type; Analytic Construction: <None>
Type - Constraints - Offset: 30 mm
Type - Materials and Finishes - Material: n7_isolatie_gen
Type - Dimensions - Thickness: 60 mm
Type - Identity Data - Workset: Family : Curtain Panels : System Panel; Assembly Code: 21.23; Assembly Description: buitenwanden; constructief, systeemwanden; Description: isolatie 60mm; SmartRevit_Versie: 2019.1; Type Name: CP_isolatie_60mm_offset30
Type - Other - Category: Curtain Panels; Family Name: System Panel
Phasing - Phase Created: 2. nieuwbouw
Dimensions - Width: 5 mm
Identity Data - Workset: Workset1
Other - Family: System Panel; Family and Type: System Panel: CP_isolatie_60mm_offset30; Type: CP_isolatie_60mm_offset30; Type Id: 474912
Name (System Panel:CP_isolatie_60mm_offset30:...) | In | Level | Area (m2) | Height (mm) | Volume (m3) | Host Id | Group
2172439 | 01 eerste verdieping | 01 eerste verdieping | 0.00942 | 1884 | 0.0005652 | 2172430 | Model Group:31_1A SVGD R:2172436
3003094 | 00 begane grond | 00 begane grond | 0.01436 | 2872 | 0.0008616 | 3003068 | Model Group:BU-01 b1500:3003067

# IfcPlate: System Panel:CP_sw paneel 60mm_offset30 (3)
In: 00 begane grond
Type - PredefinedType: CURTAIN_PANEL; Material: <Unnamed>
Type - Analytical Properties - Define Thermal Properties by: Schematic Type; Analytic Construction: <None>
Type - Constraints - Offset: 30 mm
Type - Dimensions - Thickness: 60 mm
Type - Identity Data - Workset: Family : Curtain Panels : System Panel; Assembly Code: 21.23; Assembly Description: buitenwanden; constructief, systeemwanden; Description: sw paneel 60mm; SmartRevit_Versie: 2019.1; Type Name: CP_sw paneel 60mm_offset30
Type - Other - Category: Curtain Panels; Family Name: System Panel
Constraints - Level: 00 begane grond
Phasing - Phase Created: 2. nieuwbouw
Identity Data - Workset: Workset1
Other - Family: System Panel; Family and Type: System Panel: CP_sw paneel 60mm_offset30; Type: CP_sw paneel 60mm_offset30; Type Id: 474896
Name (System Panel:CP_sw paneel 60mm_offset30:...) | Area (m2) | Height (mm) | Volume (m3) | Width (mm) | Host Id | Group
1853999 | 0.01436 | 2872 | 0.0008616 | 5 | 1853992 | Model Group:BU-18 b3017:2651211
3836664 | 0.912282 | 497 | 0.0547369 | 1835.58 | 3836657 | Model Group:BU-16:3836676
4196780 | 0.5467 | 497 | 0.032802 | 1100 | 4196773 | Model Group:BU-46:4200502

# IfcPlate: System Panel:RT72_glas (172)
Type - PredefinedType: CURTAIN_PANEL; Material: ISR_Glas
Type - Analytical Properties - Define Thermal Properties by: Schematic Type; Analytic Construction: <None>
Type - Constraints - Offset: 53.5 mm
Type - Materials and Finishes - Material: ISR_Glas
Type - Dimensions - Thickness: 23 mm
Type - Identity Data - Type Name: RT72_glas; Workset: Family : Curtain Panels : System Panel
Type - Other - Category: Curtain Panels; Family Name: System Panel
Phasing - Phase Created: 2. nieuwbouw
Identity Data - Workset: Workset1
Other - Family: System Panel; Family and Type: System Panel: RT72_glas; Type: RT72_glas; Type Id: 835106
Name (System Panel:RT72_glas:...) | In | Level | Area (m2) | Height (mm) | Volume (m3) | Width (mm) | Host Id | Group
870542 | 02 tweede verdieping | 02 tweede verdieping | 0.190638 | 267 | 0.00438467 | 714 | 870541 | Model Group:31_2A:870547
879497 | 02 tweede verdieping | 02 tweede verdieping | 1.37017 | 1919 | 0.0315138 | 714 | 870541 | Model Group:31_2A:870547
870748 | 02 tweede verdieping | 02 tweede verdieping | 0.190638 | 267 | 0.00438467 | 714 | 870747 | Model Group:31_2A:870753
879533 | 02 tweede verdieping | 02 tweede verdieping | 1.37017 | 1919 | 0.0315138 | 714 | 870747 | Model Group:31_2A:870753
870861 | 02 tweede verdieping | 02 tweede verdieping | 0.190638 | 267 | 0.00438467 | 714 | 870860 | Model Group:31_2A:870866
879551 | 02 tweede verdieping | 02 tweede verdieping | 1.37017 | 1919 | 0.0315138 | 714 | 870860 | Model Group:31_2A:870866
871636 | 02 tweede verdieping | 02 tweede verdieping | 0.190638 | 267 | 0.00438467 | 714 | 871635 | Model Group:31_2A:871641
878908 | 02 tweede verdieping | 02 tweede verdieping | 1.37017 | 1919 | 0.0315138 | 714 | 871635 | Model Group:31_2A:871641
871669 | 02 tweede verdieping | 02 tweede verdieping | 0.190638 | 267 | 0.00438467 | 714 | 871668 | Model Group:31_2A:871674
879569 | 02 tweede verdieping | 02 tweede verdieping | 1.37017 | 1919 | 0.0315138 | 714 | 871668 | Model Group:31_2A:871674
871920 | 02 tweede verdieping | 02 tweede verdieping | 0.190638 | 267 | 0.00438467 | 714 | 871919 | Model Group:31_2A:871925
879587 | 02 tweede verdieping | 02 tweede verdieping | 1.37017 | 1919 | 0.0315138 | 714 | 871919 | Model Group:31_2A:871925
871952 | 02 tweede verdieping | 02 tweede verdieping | 0.190638 | 267 | 0.00438467 | 714 | 871951 | Model Group:31_2A:871957
879593 | 02 tweede verdieping | 02 tweede verdieping | 1.37017 | 1919 | 0.0315138 | 714 | 871951 | Model Group:31_2A:871957
872814 | 02 tweede verdieping | 02 tweede verdieping | 0.190638 | 267 | 0.00438467 | 714 | 872813 | Model Group:31_2A:872819
879617 | 02 tweede verdieping | 02 tweede verdieping | 1.37017 | 1919 | 0.0315138 | 714 | 872813 | Model Group:31_2A:872819
872880 | 02 tweede verdieping | 02 tweede verdieping | 0.190638 | 267 | 0.00438467 | 714 | 872879 | Model Group:31_2A:872885
879629 | 02 tweede verdieping | 02 tweede verdieping | 1.37017 | 1919 | 0.0315138 | 714 | 872879 | Model Group:31_2A:872885
872913 | 02 tweede verdieping | 02 tweede verdieping | 0.190638 | 267 | 0.00438467 | 714 | 872912 | Model Group:31_2A:872918
879635 | 02 tweede verdieping | 02 tweede verdieping | 1.37017 | 1919 | 0.0315138 | 714 | 872912 | Model Group:31_2A:872918
872946 | 02 tweede verdieping | 02 tweede verdieping | 0.190638 | 267 | 0.00438467 | 714 | 872945 | Model Group:31_2A:872951
879641 | 02 tweede verdieping | 02 tweede verdieping | 1.37017 | 1919 | 0.0315138 | 714 | 872945 | Model Group:31_2A:872951
872979 | 02 tweede verdieping | 02 tweede verdieping | 0.190638 | 267 | 0.00438467 | 714 | 872978 | Model Group:31_2A:872984
879647 | 02 tweede verdieping | 02 tweede verdieping | 1.37017 | 1919 | 0.0315138 | 714 | 872978 | Model Group:31_2A:872984
873012 | 02 tweede verdieping | 02 tweede verdieping | 0.190638 | 267 | 0.00438467 | 714 | 873011 | Model Group:31_2A:873017
879653 | 02 tweede verdieping | 02 tweede verdieping | 1.37017 | 1919 | 0.0315138 | 714 | 873011 | Model Group:31_2A:873017
873078 | 02 tweede verdieping | 02 tweede verdieping | 0.190638 | 267 | 0.00438467 | 714 | 873077 | Model Group:31_2A:873083
879665 | 02 tweede verdieping | 02 tweede verdieping | 1.37017 | 1919 | 0.0315138 | 714 | 873077 | Model Group:31_2A:873083
873509 | 02 tweede verdieping | 02 tweede verdieping | 0.190638 | 267 | 0.00438467 | 714 | 873508 | Model Group:31_2A:873514
879701 | 02 tweede verdieping | 02 tweede verdieping | 1.37017 | 1919 | 0.0315138 | 714 | 873508 | Model Group:31_2A:873514
873602 | 02 tweede verdieping | 02 tweede verdieping | 0.190638 | 267 | 0.00438467 | 714 | 873601 | Model Group:31_2A:873607
879719 | 02 tweede verdieping | 02 tweede verdieping | 1.37017 | 1919 | 0.0315138 | 714 | 873601 | Model Group:31_2A:873607
873695 | 02 tweede verdieping | 02 tweede verdieping | 0.190638 | 267 | 0.00438467 | 714 | 873694 | Model Group:31_2A:873700
879737 | 02 tweede verdieping | 02 tweede verdieping | 1.37017 | 1919 | 0.0315138 | 714 | 873694 | Model Group:31_2A:873700
874667 | 01 eerste verdieping | 01 eerste verdieping | 3.08034 | 1884 | 0.0708478 | 1635 | 874666 | Model Group:31_1A:874672
874951 | 01 eerste verdieping | 01 eerste verdieping | 3.08034 | 1884 | 0.0708478 | 1635 | 874950 | Model Group:31_1A:874956
875026 | 01 eerste verdieping | 01 eerste verdieping | 2.29848 | 1884 | 0.052865 | 1220 | 875025 | Model Group:31_1A DKD L:875031
875041 | 01 eerste verdieping | 01 eerste verdieping | 3.08034 | 1884 | 0.0708478 | 1635 | 875040 | Model Group:31_1A:875046
875269 | 01 eerste verdieping | 01 eerste verdieping | 3.08034 | 1884 | 0.0708478 | 1635 | 875268 | Model Group:31_1A:875274
1865113 | 01 eerste verdieping | 01 eerste verdieping | 2.29848 | 1884 | 0.052865 | 1220 | 875304 | Model Group:31_1A DKD R:875310
875377 | 01 eerste verdieping | 01 eerste verdieping | 3.08034 | 1884 | 0.0708478 | 1635 | 875376 | Model Group:31_1A:875382
876488 | 01 eerste verdieping | 01 eerste verdieping | 3.08034 | 1884 | 0.0708478 | 1635 | 876487 | Model Group:31_1A:876493
876906 | 01 eerste verdieping | 01 eerste verdieping | 3.08034 | 1884 | 0.0708478 | 1635 | 876905 | Model Group:31_1A:876911
877023 | 01 eerste verdieping | 01 eerste verdieping | 3.08034 | 1884 | 0.0708478 | 1635 | 877022 | Model Group:31_1A:877028
877113 | 01 eerste verdieping | 01 eerste verdieping | 3.08034 | 1884 | 0.0708478 | 1635 | 877112 | Model Group:31_1A:877118
877203 | 01 eerste verdieping | 01 eerste verdieping | 3.08034 | 1884 | 0.0708478 | 1635 | 877202 | Model Group:31_1A:877208
877518 | 02 tweede verdieping | 02 tweede verdieping | 2.06602 | 2671 | 0.0475184 | 773.5 | 877517 | Model Group:BU-40:2712884
1483860 | 02 tweede verdieping | 02 tweede verdieping | 0.013355 | 2671 | 0.000307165 | 5 | 877517 | Model Group:BU-40:2712884
1848724 | 02 tweede verdieping | 02 tweede verdieping | 1.11155 | 2393 | 0.0255656 | 464.5 | 877517 | Model Group:BU-40:2712884
877727 | 02 tweede verdieping | 02 tweede verdieping | 1.11035 | 2393 | 0.0255381 | 464 | 877517 | Model Group:BU-40:2712884
1848490 | 02 tweede verdieping | 02 tweede verdieping | 0.013355 | 2671 | 0.000307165 | 5 | 877517 | Model Group:BU-40:2712884
1483752 | 02 tweede verdieping | 02 tweede verdieping | 2.06735 | 2671 | 0.0475491 | 774 | 877517 | Model Group:BU-40:2712884
1848725 | 02 tweede verdieping | 02 tweede verdieping | 0.5769 | 200 | 0.0132687 | 2884.5 | 877517 | Model Group:BU-40:2712884
880922 | 01 eerste verdieping | 01 eerste verdieping | 3.08034 | 1884 | 0.0708478 | 1635 | 880921 | Model Group:31_1A:880927
881683 | 01 eerste verdieping | 01 eerste verdieping | 3.08034 | 1884 | 0.0708478 | 1635 | 881682 | Model Group:31_1A:881688
881847 | 01 eerste verdieping | 01 eerste verdieping | 0.449334 | 1884 | 0.0103347 | 238.5 | 881846 | Model Group:BU-35:2701985
891675 | 01 eerste verdieping | 01 eerste verdieping | 3.08034 | 1884 | 0.0708478 | 1635 | 891674 | Model Group:31_1A:891680
891787 | 01 eerste verdieping | 01 eerste verdieping | 3.08034 | 1884 | 0.0708478 | 1635 | 891786 | Model Group:31_1A:891792
891904 | 01 eerste verdieping | 01 eerste verdieping | 3.08034 | 1884 | 0.0708478 | 1635 | 891903 | Model Group:31_1A:891909
891926 | 01 eerste verdieping | 01 eerste verdieping | 3.08034 | 1884 | 0.0708478 | 1635 | 891925 | Model Group:31_1A:891931
891976 | 01 eerste verdieping | 01 eerste verdieping | 3.08034 | 1884 | 0.0708478 | 1635 | 891975 | Model Group:31_1A:891981
891998 | 01 eerste verdieping | 01 eerste verdieping | 1.6241 | 2472 | 0.0373544 | 657 | 891997 | Model Group:BU-32:892003
1826968 | 00 begane grond | 00 begane grond | 0.379708 | 497 | 0.00873328 | 764 | 892038 | Model Group:BU-07 b900:894363
894429 | 00 begane grond | 00 begane grond | 4.77901 | 2872 | 0.109917 | 1664 | 894428 | Model Group:BU-06 b1800:894434
1220071 | 00 begane grond | 00 begane grond | 2.83179 | 2872 | 0.0651312 | 986 | 1220070 | Model Group:BU-08 b2100:1220076
1861245 | 00 begane grond | 00 begane grond | 0.4473 | 497 | 0.0102879 | 900 | 1220070 | Model Group:BU-08 b2100:1220076
1859708 | 00 begane grond | 00 begane grond | 1.10859 | 2872 | 0.0254976 | 386 | 1220169 | Model Group:BU-09 b1500:1220175
1859835 | 00 begane grond | 00 begane grond | 0.4473 | 497 | 0.0102879 | 900 | 1220169 | Model Group:BU-09 b1500:1220175
1492350 | 00 begane grond | 00 begane grond | 5.41659 | 2872 | 0.124582 | 1886 | 1220847 | Model Group:BU-11 b3000:1220846
1492355 | 00 begane grond | 00 begane grond | 0.4473 | 497 | 0.0102879 | 900 | 1220847 | Model Group:BU-11 b3000:1220846
1827108 | 00 begane grond | 00 begane grond | 0.379708 | 497 | 0.00873328 | 764 | 1300401 | Model Group:BU-07 b900 (members excluded):1300407
1489280 | 00 begane grond | 00 begane grond | 4.55499 | 2872 | 0.104765 | 1586 | 1300453 | Model Group:BU-22 b2700:1300414
1490425 | 00 begane grond | 00 begane grond | 0.4473 | 497 | 0.0102879 | 900 | 1300453 | Model Group:BU-22 b2700:1300414 | Identity Data - Mark: 295
1491160 | 00 begane grond | 00 begane grond | 5.31894 | 2872 | 0.122336 | 1852 | 1300742 | Model Group:BU-21 b2966:1300741
1491980 | 00 begane grond | 00 begane grond | 6.27819 | 2872 | 0.144398 | 2186 | 1300954 | Model Group:BU-20 b3300:1300930
1492189 | 00 begane grond | 00 begane grond | 0.4473 | 497 | 0.0102879 | 900 | 1300954 | Model Group:BU-20 b3300:1300930
1300993 | 00 begane grond | 00 begane grond | 1.08849 | 2872 | 0.0250352 | 379 | 1300992 | Model Group:BU-23 b1353:2651710
1899342 | 00 begane grond | 00 begane grond | 2.0673 | 2297 | 0.0475479 | 900 | 1300992 | Model Group:BU-23 b1353:2651710
1899451 | 00 begane grond | 00 begane grond | 0.4473 | 497 | 0.0102879 | 900 | 1300992 | Model Group:BU-23 b1353:2651710
1493476 | 00 begane grond | 00 begane grond | 5.28879 | 2872 | 0.121642 | 1841.5 | 1493475 | Model Group:BU-25 b3000:1493474
1493938 | 00 begane grond | 00 begane grond | 0.4473 | 497 | 0.0102879 | 900 | 1493475 | Model Group:BU-25 b3000:1493474
2012616 | 00 begane grond | 00 begane grond | 5.98238 | 2872 | 0.137595 | 2083 | 1494105 | Model Group:BU-02 b4200:1494104
1494117 | 00 begane grond | 00 begane grond | 0.4473 | 497 | 0.0102879 | 900 | 1494105 | Model Group:BU-02 b4200:1494104
1494118 | 00 begane grond | 00 begane grond | 0.4473 | 497 | 0.0102879 | 900 | 1494105 | Model Group:BU-02 b4200:1494104
1823019 | 00 begane grond | 00 begane grond | 2.60778 | 2872 | 0.0599788 | 908 | 1494514 | Model Group:BU-14 b3000:1494513
1494526 | 00 begane grond | 00 begane grond | 0.933366 | 497 | 0.0214674 | 1878 | 1494514 | Model Group:BU-14 b3000:1494513
1827114 | 00 begane grond | 00 begane grond | 0.379708 | 497 | 0.00873328 | 764 | 1502981 | Model Group:BU-07 b900:1502980
1817851 | 00 begane grond | 00 begane grond | 5.98238 | 2872 | 0.137595 | 2083 | 1817349 | Model Group:BU-12 b4200:1817348
1817361 | 00 begane grond | 00 begane grond | 0.4473 | 497 | 0.0102879 | 900 | 1817349 | Model Group:BU-12 b4200:1817348
1817636 | 00 begane grond | 00 begane grond | 0.4473 | 497 | 0.0102879 | 900 | 1817349 | Model Group:BU-12 b4200:1817348
1818888 | 00 begane grond | 00 begane grond | 5.21268 | 2872 | 0.119892 | 1815 | 1818869 | Model Group:BU-03 b5800:1818868
1818876 | 00 begane grond | 00 begane grond | 2.91508 | 2872 | 0.0670468 | 1015 | 1818869 | Model Group:BU-03 b5800:1818868
1818881 | 00 begane grond | 00 begane grond | 0.4473 | 497 | 0.0102879 | 900 | 1818869 | Model Group:BU-03 b5800:1818868
1819717 | 00 begane grond | 00 begane grond | 0.4473 | 497 | 0.0102879 | 900 | 1818869 | Model Group:BU-03 b5800:1818868
1819903 | 00 begane grond | 00 begane grond | 5.62349 | 2892 | 0.12934 | 1944.5 | 1819902 | Model Group:BU-05 b1910:2648634
1822158 | 00 begane grond | 00 begane grond | 1.97019 | 2872 | 0.0453144 | 686 | 1822151 | Model Group:BU-10 b1800:1822150
1822165 | 00 begane grond | 00 begane grond | 0.4473 | 497 | 0.0102879 | 900 | 1822151 | Model Group:BU-10 b1800:1822150
1823325 | 00 begane grond | 00 begane grond | 5.98238 | 2872 | 0.137595 | 2083 | 1823298 | Model Group:BU-15 b4200:1823297
1823310 | 00 begane grond | 00 begane grond | 0.933366 | 497 | 0.0214674 | 1878 | 1823298 | Model Group:BU-15 b4200:1823297
1854004 | 00 begane grond | 00 begane grond | 0.935106 | 497 | 0.0215074 | 1881.5 | 1853992 | Model Group:BU-18 b3017:2651211
1856668 | 00 begane grond | 00 begane grond | 0.404558 | 497 | 0.00930483 | 814 | 1853992 | Model Group:BU-18 b3017:2651211
1854930 | 00 begane grond | 00 begane grond | 5.64922 | 2872 | 0.129932 | 1967 | 1854929 | Model Group:BU-19 b2067:2651286
1862276 | 00 begane grond | 00 begane grond | 5.43221 | 2485 | 0.124941 | 2186 | 1862275 | Model Group:BU-13 b3300:1862274 | Identity Data - Mark: 461
1862288 | 00 begane grond | 00 begane grond | 0.4725 | 525 | 0.0108675 | 900 | 1862275 | Model Group:BU-13 b3300:1862274
1864615 | 01 eerste verdieping | 01 eerste verdieping | 2.29848 | 1884 | 0.052865 | 1220 | 1864614 | Model Group:31_1A SVGD L:1864620
1864623 | 01 eerste verdieping | 01 eerste verdieping | 0.634908 | 1884 | 0.0146029 | 337 | 1864614 | Model Group:31_1A SVGD L:1864620 | Identity Data - Mark: 471
1864977 | 01 eerste verdieping | 01 eerste verdieping | 2.29848 | 1884 | 0.052865 | 1220 | 1864976 | Model Group:31_1A DKD L:1864982
1865025 | 01 eerste verdieping | 01 eerste verdieping | 2.29848 | 1884 | 0.052865 | 1220 | 1865024 | Model Group:31_1A DKD L:1865030
1865349 | 01 eerste verdieping | 01 eerste verdieping | 2.29848 | 1884 | 0.052865 | 1220 | 1865340 | Model Group:31_1A DKD R:1865346
1865577 | 01 eerste verdieping | 01 eerste verdieping | 2.29848 | 1884 | 0.052865 | 1220 | 1865568 | Model Group:31_1A DKD R:1865574
1865611 | 01 eerste verdieping | 01 eerste verdieping | 2.29848 | 1884 | 0.052865 | 1220 | 1865602 | Model Group:31_1A DKD R:1865608
1865784 | 01 eerste verdieping | 01 eerste verdieping | 2.29848 | 1884 | 0.052865 | 1220 | 1865775 | Model Group:31_1A DKD R:1865781
1865941 | 01 eerste verdieping | 01 eerste verdieping | 2.29848 | 1884 | 0.052865 | 1220 | 1865940 | Model Group:31_1A DKD L:1865946
1866085 | 01 eerste verdieping | 01 eerste verdieping | 0.634908 | 1884 | 0.0146029 | 337 | 1866076 | Model Group:31_1A DKg R:1866082 | Identity Data - Mark: 515
1867672 | 02 tweede verdieping | 02 tweede verdieping | 0.190638 | 267 | 0.00438467 | 714 | 1867671 | Model Group:31_2A DK R:1867677
1869340 | 02 tweede verdieping | 02 tweede verdieping | 0.190638 | 267 | 0.00438467 | 714 | 1869339 | Model Group:31_2A DK R:1869345
1869357 | 02 tweede verdieping | 02 tweede verdieping | 0.190638 | 267 | 0.00438467 | 714 | 1869356 | Model Group:31_2A DK R:1869362
1869374 | 02 tweede verdieping | 02 tweede verdieping | 0.190638 | 267 | 0.00438467 | 714 | 1869373 | Model Group:31_2A DK R:1869379
1869391 | 02 tweede verdieping | 02 tweede verdieping | 0.190638 | 267 | 0.00438467 | 714 | 1869390 | Model Group:31_2A DK R:1869396
1869408 | 02 tweede verdieping | 02 tweede verdieping | 0.190638 | 267 | 0.00438467 | 714 | 1869407 | Model Group:31_2A DK R:1869413
1869425 | 02 tweede verdieping | 02 tweede verdieping | 0.190638 | 267 | 0.00438467 | 714 | 1869424 | Model Group:31_2A DK R:1869430
1869442 | 02 tweede verdieping | 02 tweede verdieping | 0.190638 | 267 | 0.00438467 | 714 | 1869441 | Model Group:31_2A DK R:1869447
1869462 | 02 tweede verdieping | 02 tweede verdieping | 0.190638 | 267 | 0.00438467 | 714 | 1869461 | Model Group:31_2A DK L:1869467
1869601 | 02 tweede verdieping | 02 tweede verdieping | 0.190638 | 267 | 0.00438467 | 714 | 1869600 | Model Group:31_2A DK L:1869606
1869618 | 02 tweede verdieping | 02 tweede verdieping | 0.190638 | 267 | 0.00438467 | 714 | 1869617 | Model Group:31_2A DK L:1869623
1869635 | 02 tweede verdieping | 02 tweede verdieping | 0.190638 | 267 | 0.00438467 | 714 | 1869634 | Model Group:31_2A DK L:1869640
1869652 | 02 tweede verdieping | 02 tweede verdieping | 0.190638 | 267 | 0.00438467 | 714 | 1869651 | Model Group:31_2A DK L:1869657
1869669 | 02 tweede verdieping | 02 tweede verdieping | 0.190638 | 267 | 0.00438467 | 714 | 1869668 | Model Group:31_2A DK L:1869674
1869686 | 02 tweede verdieping | 02 tweede verdieping | 0.190638 | 267 | 0.00438467 | 714 | 1869685 | Model Group:31_2A DK L:1869691
1869703 | 02 tweede verdieping | 02 tweede verdieping | 0.190638 | 267 | 0.00438467 | 714 | 1869702 | Model Group:31_2A DK L:1869708
1869722 | 02 tweede verdieping | 02 tweede verdieping | 0.190638 | 267 | 0.00438467 | 714 | 1869721 | Model Group:31_2A DK L:1869727
1869739 | 02 tweede verdieping | 02 tweede verdieping | 0.190638 | 267 | 0.00438467 | 714 | 1869738 | Model Group:31_2A DK L:1869744
1869756 | 02 tweede verdieping | 02 tweede verdieping | 0.190638 | 267 | 0.00438467 | 714 | 1869755 | Model Group:31_2A DK R:1869761
1869773 | 02 tweede verdieping | 02 tweede verdieping | 0.190638 | 267 | 0.00438467 | 714 | 1869772 | Model Group:31_2A DK R:1869778
1869792 | 02 tweede verdieping | 02 tweede verdieping | 0.190638 | 267 | 0.00438467 | 714 | 1869791 | Model Group:31_2A DK R:1869797
1869809 | 02 tweede verdieping | 02 tweede verdieping | 0.190638 | 267 | 0.00438467 | 714 | 1869808 | Model Group:31_2A DK R:1869814
1869826 | 02 tweede verdieping | 02 tweede verdieping | 0.190638 | 267 | 0.00438467 | 714 | 1869825 | Model Group:31_2A DK R:1869831
1869843 | 02 tweede verdieping | 02 tweede verdieping | 0.190638 | 267 | 0.00438467 | 714 | 1869842 | Model Group:31_2A DK R:1869848
1897639 | 00 begane grond | 00 begane grond | 0.379708 | 497 | 0.00873328 | 764 | 1897632 | Model Group:BU-07 b900 (members excluded):1300686
1897653 | 00 begane grond | 00 begane grond | 0.379708 | 497 | 0.00873328 | 764 | 1897646 | Model Group:BU-07 b900 (members excluded):1818605
1898048 | 01 eerste verdieping | 01 eerste verdieping | 2.29848 | 1884 | 0.052865 | 1220 | 1898039 | Model Group:31_1A DKD R:1898045
1932986 | 00 begane grond | 00 begane grond | 5.41659 | 2872 | 0.124582 | 1886 | 1932979 | Model Group:BU-17 b3000:1900158
1932991 | 00 begane grond | 00 begane grond | 0.4473 | 497 | 0.0102879 | 900 | 1932979 | Model Group:BU-17 b3000:1900158
2012526 | 01 eerste verdieping | 01 eerste verdieping | 2.29848 | 1884 | 0.052865 | 1220 | 2012525 | Model Group:31_1A DKD L:2012531
2012556 | 01 eerste verdieping | 01 eerste verdieping | 2.29848 | 1884 | 0.052865 | 1220 | 2012555 | Model Group:31_1A DKD L:2012561
2012579 | 01 eerste verdieping | 01 eerste verdieping | 2.23748 | 1834 | 0.051462 | 1220 | 2012570 | Model Group:BU-38:2702101
2172431 | 01 eerste verdieping | 01 eerste verdieping | 0.441798 | 1884 | 0.0101614 | 234.5 | 2172430 | Model Group:31_1A SVGD R:2172436
3023493 | 01 eerste verdieping | 01 eerste verdieping | 2.3729 | 1884 | 0.0545767 | 1259.5 | 2172430 | Model Group:31_1A SVGD R:2172436
2245639 | 01 eerste verdieping | 01 eerste verdieping | 2.14493 | 1884 | 0.0493335 | 1138.5 | 2245638 | Model Group:BU-33:2700705
2245687 | 01 eerste verdieping | 01 eerste verdieping | 1.39133 | 1884 | 0.0320007 | 738.5 | 2245686 | Model Group:BU-34:2700766
2266703 | 02 tweede verdieping | 02 tweede verdieping | 0.190638 | 267 | 0.00438467 | 714 | 2266702 | Model Group:31_2A DK L:2266708
2266718 | 02 tweede verdieping | 02 tweede verdieping | 0.190638 | 267 | 0.00438467 | 714 | 2266717 | Model Group:31_2A DK R:2266723
2649854 | 00 begane grond | 00 begane grond | 5.98238 | 2872 | 0.137595 | 2083 | 2649834 | Model Group:BU-47 b4200:1822720
2649841 | 00 begane grond | 00 begane grond | 0.4473 | 497 | 0.0102879 | 900 | 2649834 | Model Group:BU-47 b4200:1822720
2649846 | 00 begane grond | 00 begane grond | 0.4473 | 497 | 0.0102879 | 900 | 2649834 | Model Group:BU-47 b4200:1822720
2652551 | 00 begane grond | 00 begane grond | 5.41659 | 2872 | 0.124582 | 1886 | 2652544 | Model Group:BU-11 b3000:1502212
2652556 | 00 begane grond | 00 begane grond | 0.4473 | 497 | 0.0102879 | 900 | 2652544 | Model Group:BU-11 b3000:1502212
2652637 | 00 begane grond | 00 begane grond | 5.41659 | 2872 | 0.124582 | 1886 | 2652630 | Model Group:BU-11 b3000:1502763
2652642 | 00 begane grond | 00 begane grond | 0.4473 | 497 | 0.0102879 | 900 | 2652630 | Model Group:BU-11 b3000:1502763
2712307 | 01 eerste verdieping | 01 eerste verdieping | 2.14493 | 1884 | 0.0493335 | 1138.5 | 2712306 | Model Group:BU-36:2701416
2712496 | 01 eerste verdieping | 01 eerste verdieping | 0.449334 | 1884 | 0.0103347 | 238.5 | 2712495 | Model Group:BU-37:2712501
2760156 | 01 eerste verdieping | 01 eerste verdieping | 2.14493 | 1884 | 0.0493335 | 1138.5 | 2760155 | Model Group:BU-33:2712443
2776731 | 01 eerste verdieping | 01 eerste verdieping | 2.29848 | 1884 | 0.052865 | 1220 | 2776730 | Model Group:31_1A SVGD L:2776736
2776739 | 01 eerste verdieping | 01 eerste verdieping | 0.634908 | 1884 | 0.0146029 | 337 | 2776730 | Model Group:31_1A SVGD L:2776736
3003069 | 00 begane grond | 00 begane grond | 1.2005 | 2872 | 0.0276114 | 418 | 3003068 | Model Group:BU-01 b1500:3003067
3003088 | 00 begane grond | 00 begane grond | 0.762398 | 497 | 0.0175352 | 1534 | 3003068 | Model Group:BU-01 b1500:3003067
3016895 | 00 begane grond | 00 begane grond | 0.649072 | 2872 | 0.0149287 | 226 | 3016883
3016889 | 00 begane grond | 00 begane grond | 0.264901 | 497 | 0.00609272 | 533 | 3016883
3058239 | 01 eerste verdieping | 01 eerste verdieping | 2.29848 | 1884 | 0.052865 | 1220 | 3058230 | Model Group:31_1A DKD R:3058236
3451937 | 00 begane grond | 00 begane grond | 0.4011 | 525 | 0.0092253 | 764 | 3451930 | Model Group:BU-45 b900:2546304
3702021 | 00 begane grond | 00 begane grond | 1.46472 | 2872 | 0.0336886 | 510 | 3702020 | Model Group:BU-04 b2500:1820005
3702030 | 00 begane grond | 00 begane grond | 0.8586 | 477 | 0.0197478 | 1800 | 3702020 | Model Group:BU-04 b2500:1820005

# IfcPlate: System Panel:glas binnen (3)
In: 00 begane grond
Type - PredefinedType: CURTAIN_PANEL; Material: ISR_Glas
Type - Analytical Properties - Define Thermal Properties by: Schematic Type; Analytic Construction: <None>
Type - Constraints - Offset: 0 mm
Type - Materials and Finishes - Material: ISR_Glas
Type - Dimensions - Thickness: 25 mm
Type - Identity Data - Workset: Family : Curtain Panels : System Panel; SmartRevit_Versie: 2013.2; Type Name: glas binnen
Type - Other - Category: Curtain Panels; Family Name: System Panel
Constraints - Level: 00 begane grond
Phasing - Phase Created: 2. nieuwbouw
Dimensions - Height: 2680 mm
Identity Data - Workset: Workset1
Other - Family: System Panel; Family and Type: System Panel: glas binnen; Host Id: 1478229; Type: glas binnen; Type Id: 1470139
Group: Model Group:BI-13bw 7515x2800:2527306
Name (System Panel:glas binnen:...) | Area (m2) | Volume (m3) | Width (mm)
1478230 | 4.7637 | 0.119092 | 1777.5 | Identity Data - Mark: 333
2614204 | 4.79385 | 0.119846 | 1788.75
1481148 | 4.79385 | 0.119846 | 1788.75

# IfcPlate: System Panel:glas binnen stalen kozijnen (11)
Type - PredefinedType: CURTAIN_PANEL; Material: ISR_Glas
Type - Analytical Properties - Define Thermal Properties by: Schematic Type; Analytic Construction: <None>
Type - Constraints - Offset: 16.3 mm
Type - Materials and Finishes - Material: ISR_Glas
Type - Dimensions - Thickness: 5.5 mm
Type - Identity Data - Workset: Family : Curtain Panels : System Panel; SmartRevit_Versie: 2013.2; Type Name: glas binnen stalen kozijnen
Type - Other - Category: Curtain Panels; Family Name: System Panel
Phasing - Phase Created: 2. nieuwbouw
Identity Data - Workset: Workset1
Other - Family: System Panel; Family and Type: System Panel: glas binnen stalen kozijnen; Type: glas binnen stalen kozijnen; Type Id: 3300140
Name (System Panel:glas binnen stalen kozijnen:...) | In | Level | Area (m2) | Height (mm) | Volume (m3) | Width (mm) | Host Id | Group
1474079 | 01 eerste verdieping | 01 eerste verdieping | 3.56212 | 1630 | 0.0195917 | 2185.35 | 1470455 | Model Group:BI-26bw:2535201
1745583 | 01 eerste verdieping | 01 eerste verdieping | 3.93618 | 1630 | 0.021649 | 2414.84 | 1470455 | Model Group:BI-26bw:2535201
1473911 | 01 eerste verdieping | 01 eerste verdieping | 4.18563 | 2262.5 | 0.0230209 | 1850 | 1470455 | Model Group:BI-26bw:2535201
1475173 | 01 eerste verdieping | 01 eerste verdieping | 0.657733 | 357.5 | 0.00361753 | 1839.81 | 1470455 | Model Group:BI-26bw:2535201
1475176 | 01 eerste verdieping | 01 eerste verdieping | 0.661375 | 357.5 | 0.00363756 | 1850 | 1470455 | Model Group:BI-26bw:2535201
1745092 | 02 tweede verdieping | 02 tweede verdieping | 3.23275 | 2680 | 0.0177801 | 1206.25 | 1476038 | Model Group:BI-29bw 60min:1476114
2692140 | 02 tweede verdieping | 02 tweede verdieping | 3.23275 | 2680 | 0.0177801 | 1206.25 | 1476038 | Model Group:BI-29bw 60min:1476114
2689428 | 02 tweede verdieping | 02 tweede verdieping | 3.56188 | 1630 | 0.0195903 | 2185.2 | 1476038 | Model Group:BI-29bw 60min:1476114
1476081 | 02 tweede verdieping | 02 tweede verdieping | 0.657787 | 357.5 | 0.00361783 | 1839.96 | 1476038 | Model Group:BI-29bw 60min:1476114
1476084 | 02 tweede verdieping | 02 tweede verdieping | 0.66221 | 357.5 | 0.00364216 | 1852.34 | 1476038 | Model Group:BI-29bw 60min:1476114
1939635 | 00 begane grond | 00 begane grond | 0.6075 | 337.5 | 0.00334125 | 1800 | 1478229 | Model Group:BI-13bw 7515x2800:2527306

# IfcPlate: System Panel:glas_offset-35 (20)
Type - PredefinedType: CURTAIN_PANEL; Material: ISR_Glas
Type - Analytical Properties - Define Thermal Properties by: Schematic Type; Analytic Construction: <None>
Type - Constraints - Offset: 41 mm
Type - Materials and Finishes - Material: ISR_Glas
Type - Dimensions - Thickness: 25 mm
Type - Identity Data - Workset: Family : Curtain Panels : System Panel; SmartRevit_Versie: 2013.2; Type Name: glas_offset-35
Type - Other - Category: Curtain Panels; Family Name: System Panel
Phasing - Phase Created: 2. nieuwbouw
Identity Data - Workset: Workset1
Other - Family: System Panel; Family and Type: System Panel: glas_offset-35; Type: glas_offset-35; Type Id: 1227230
Name (System Panel:glas_offset-35:...) | In | Level | Area (m2) | Height (mm) | Volume (m3) | Width (mm) | Host Id | Group
1367978 | 00 begane grond | 00 begane grond | 5.1053 | 2253 | 0.127632 | 2266 | 1367977 | Model Group:BI-04bw 2400x2387:1367983
1420135 | 01 eerste verdieping | 01 eerste verdieping | 5.1053 | 2253 | 0.127632 | 2266 | 1420134 | Model Group:BI-04w 2400x2387:1420140
1420369 | 01 eerste verdieping | 01 eerste verdieping | 3.80982 | 2253 | 0.0952456 | 1691 | 1420368 | Model Group:BI-25bw 1825x2387:1420374
1612556 | 00 begane grond | 00 begane grond | 5.81721 | 2666 | 0.14543 | 2182 | 1612555 | Model Group:BI-10 4215x2800:2522162
1613135 | 00 begane grond | 00 begane grond | 0.633872 | 346 | 0.0158468 | 1832 | 1612555 | Model Group:BI-10 4215x2800:2522162
1729490 | 02 tweede verdieping | 02 tweede verdieping | 0.633872 | 346 | 0.0158468 | 1832 | 1729467 | Model Group:BI-28:2534707
1731563 | 02 tweede verdieping | 02 tweede verdieping | 3.06523 | 1616 | 0.0766307 | 1896.8 | 1731562 | Model Group:BI-27 2500x1700:2534618
1731568 | 02 tweede verdieping | 02 tweede verdieping | 0.754672 | 1616 | 0.0188668 | 467 | 1731562 | Model Group:BI-27 2500x1700:2534618
1731626 | 02 tweede verdieping | 02 tweede verdieping | 0.754672 | 1616 | 0.0188668 | 467 | 1731625 | Model Group:BI-28:2534707
1734722 | 02 tweede verdieping | 02 tweede verdieping | 0.754672 | 1616 | 0.0188668 | 467 | 1734721 | Model Group:BI-28:2534707
1735011 | 01 eerste verdieping | 01 eerste verdieping | 4.2113 | 1616 | 0.105282 | 2606 | 1735010 | Model Group:BI-20 2865x1750:2532482
1735396 | 01 eerste verdieping | 01 eerste verdieping | 4.02546 | 1616 | 0.100636 | 2491 | 1735395 | Model Group:BI-21w 2630x1750:2532641
1735909 | 01 eerste verdieping | 01 eerste verdieping | 4.63213 | 2666 | 0.115803 | 1737.48 | 1735559 | Model Group:BI-23w 4635x2800:2532690
2081484 | 01 eerste verdieping | 01 eerste verdieping | 4.63213 | 2666 | 0.115803 | 1737.48 | 1735559 | Model Group:BI-23w 4635x2800:2532690
1736547 | 01 eerste verdieping | 01 eerste verdieping | 0.3114 | 346 | 0.007785 | 900 | 1735559 | Model Group:BI-23w 4635x2800:2532690
1940854 | 00 begane grond | 00 begane grond | 2.51435 | 2253 | 0.0628587 | 1116 | 1940853 | Model Group:BI-31w 1250x2387:1940859
2534665 | 02 tweede verdieping | 02 tweede verdieping | 3.06523 | 1616 | 0.0766307 | 1896.8 | 2534664 | Model Group:BI-27 2500x1700:2534674
2534670 | 02 tweede verdieping | 02 tweede verdieping | 0.754672 | 1616 | 0.0188668 | 467 | 2534664 | Model Group:BI-27 2500x1700:2534674
2591153 | 00 begane grond | 00 begane grond | 5.1053 | 2253 | 0.127632 | 2266 | 2591152 | Model Group:BI-04av 2400x2387:1367879
3844249 | 00 begane grond | 00 begane grond | 2.12708 | 1939 | 0.0531771 | 1097 | 3843747 | Model Group:BI-02 2198x2387 (members excluded):3844191

# IfcPlate: stafstaal deuren:stafstaal deuren, stafstaal deuren:stafstaal deuren:3029358
In: 01 eerste verdieping
Type - Material: h2_staal_gen
Type - Identity Data - Workset: Workset1; Type Name: stafstaal deuren
Type - Other - Category: Structural Stiffeners; Family Name: stafstaal deuren
Constraints - Moves With Nearby Elements: no
Phasing - Phase Created: 2. nieuwbouw
Dimensions - Area: 0.0936659 m2; Volume: 0.000495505 m3
Other - Family: stafstaal deuren; Family and Type: stafstaal deuren: stafstaal deuren; Type: stafstaal deuren; Type Id: 3029356

# IfcRailing: Afdekker tribunetrap:Afdekker tribunetrap, Afdekker tribunetrap:Afdekker tribunetrap:2502234
In: 00 begane grond
Type - Material: ISR_Hout, i4_hout_Eiken_gen
Type - Identity Data - Workset: Workset1; Type Name: Afdekker tribunetrap
Type - Other - Category: Railings; Family Name: Afdekker tribunetrap
Constraints - Moves With Nearby Elements: no
Phasing - Phase Created: 2. nieuwbouw
Dimensions - Area: 0.366852 m2; Volume: 0.121196 m3
Other - Family: Afdekker tribunetrap; Family and Type: Afdekker tribunetrap: Afdekker tribunetrap; Type: Afdekker tribunetrap; Type Id: 2502232

# IfcRailing: Railing:34_BDG_trap_BU_v0, Railing:34_BDG_trap_BU_v0:2986304
In: 00 begane grond
Classification: 34 Uniformat (Uniformat); Material: h2_staal_gen
Constraints - Base Offset: 0 mm; Base Level: 00 begane grond; Offset from Path: 0 mm
Phasing - Phase Created: 2. nieuwbouw
Dimensions - Length: 7763.14 mm
Identity Data - Workset: Workset1
Other - Category: Railings; Family: Railing; Family and Type: Railing: 34_BDG_trap_BU_v0; Type: 34_BDG_trap_BU_v0; Type Id: 2983556
Top Rail(Type) - Height: 1219.2 mm; Use Top Rail: no
Construction(Type) - Angled Joins: No Connector; Baluster Offset: 0 mm; Landing Height Adjustment: 0 mm; Rail Connections: Weld; Tangent Joins: Extend Rails to Meet; Use Landing Height Adjustment: no; Railing Height: 1000 mm
Identity Data(Type) - Workset: Railing Types; Assembly Code: 34; Assembly Description: balustrades en leuningen; Description: leuning rond 40mm; Model: LOD300; SmartRevit_Versie: 2017.3; Type Name: 34_BDG_trap_BU_v0
Other(Type) - Category: Railings; Family Name: Railing

# IfcRailing: Railing:NLRS_44_RAI_LB_leuning 60x20_generiek_BDG (9)
Classification: 34 Uniformat (Uniformat); Material: h3_RVS
Constraints - Base Offset: 0 mm
Phasing - Phase Created: 2. nieuwbouw
Identity Data - Workset: Workset1
Other - Category: Railings; Family: Railing; Family and Type: Railing: NLRS_44_RAI_LB_leuning 60x20_generiek_BDG; Type: NLRS_44_RAI_LB_leuning 60x20_generiek_BDG; Type Id: 3033600
Top Rail(Type) - Height: 1219.2 mm; Use Top Rail: no
Construction(Type) - Angled Joins: No Connector; Baluster Offset: 0 mm; Landing Height Adjustment: 0 mm; Rail Connections: Weld; Tangent Joins: Extend Rails to Meet; Use Landing Height Adjustment: no; Railing Height: 900 mm
Identity Data(Type) - Workset: Railing Types; Assembly Code: 34; Assembly Description: balustrades en leuningen; Description: leuning 60x20; Model: LOD300; SmartRevit_Versie: 2017.3; Type Name: NLRS_44_RAI_LB_leuning 60x20_generiek_BDG
Other(Type) - Category: Railings; Family Name: Railing
Name (Railing:NLRS_44_RAI_LB_leuning 60x20_generiek_BDG:...) | In | Offset from Path (mm) | Length (mm)
1616105 | 01 eerste verdieping | 30 | 6037.37
1616109 | 01 eerste verdieping | 30 | 9498.09
1770818 | 00 begane grond | 30 | 5762.72
1770822 | 00 begane grond | 30 | 9954.01
3033592 | 01 eerste verdieping | 0 | 6055.45 | Constraints - Base Level: 01 eerste verdieping
3033618 | 01 eerste verdieping | 0 | 6055.45 | Constraints - Base Level: 01 eerste verdieping
3076341 | 00 begane grond | 0 | 7763.14 | Constraints - Base Level: 00 begane grond
4730250 | 00 begane grond | 0 | 6662.59
4730377 | 01 eerste verdieping | 0 | 520 | Constraints - Base Level: 01 eerste verdieping

# IfcRailing: Railing:NLRS_44_RAI_LB_middenleuning 60x20_generiek_BDG (2)
Classification: 34 Uniformat (Uniformat); Material: h3_RVS
Constraints - Base Offset: 0 mm
Phasing - Phase Created: 2. nieuwbouw
Identity Data - Workset: Workset1
Other - Category: Railings; Family: Railing; Family and Type: Railing: NLRS_44_RAI_LB_middenleuning 60x20_generiek_BDG; Type: NLRS_44_RAI_LB_middenleuning 60x20_generiek_BDG; Type Id: 3219132
Top Rail(Type) - Height: 1219.2 mm; Use Top Rail: no
Construction(Type) - Angled Joins: No Connector; Baluster Offset: 0 mm; Landing Height Adjustment: 0 mm; Rail Connections: Weld; Railing Height: 900 mm; Tangent Joins: Extend Rails to Meet; Use Landing Height Adjustment: no
Identity Data(Type) - Assembly Code: 34; Assembly Description: balustrades en leuningen; Description: leuning 60x20; Model: LOD300; SmartRevit_Versie: 2017.3; Type Name: NLRS_44_RAI_LB_middenleuning 60x20_generiek_BDG; Workset: Railing Types
Other(Type) - Category: Railings; Family Name: Railing
Name (Railing:NLRS_44_RAI_LB_middenleuning 60x20_generiek_BDG:...) | In | Offset from Path (mm) | Length (mm)
1307775 | 01 eerste verdieping | 140 | 6602.5
3219039 | 00 begane grond | 0 | 6370.26 | Constraints - Base Level: 00 begane grond

# IfcRoof: Basic Roof:NLRS_27_RO_EPS drukvaste isolatie + dakbedekking 230-3-3_gen_bdg (4)
In: 01 eerste verdieping
Classification: 27.11 Uniformat (Uniformat); Material: s9_bitumen 3 mm, s9_bitumen 3 mm, n7_isolatie_gen 230 mm
Constraints - Related to Mass: no; Room Bounding: yes; Cutoff Offset: 0 mm; Base Level: 01 eerste verdieping; Base Offset From Level: -50 mm
Phasing - Phase Created: 2. nieuwbouw
Construction - Fascia Depth: 0 mm; Rafter Cut: Plumb Cut; Maximum Ridge Height: 4186 mm
Dimensions - Thickness: 236 mm
Identity Data - Workset: Workset1
Other - Category: Roofs; Family: Basic Roof; Family and Type: Basic Roof: NLRS_27_RO_EPS drukvaste isolatie + dakbedekking 230-3-3_gen_bdg; Type: NLRS_27_RO_EPS drukvaste isolatie + dakbedekking 230-3-3_gen_bdg; Type Id: 3212183
Name (Basic Roof:NLRS_27_RO_EPS drukvaste isolatie + dakbedekking 230-3-3_gen_bdg:...) | Area (m2) | Volume (m3)
3212181 | 6.6352 | 1.56591
3212710 | 3.31188 | 0.781604
3213010 | 8.5384 | 2.01506
3958213 | 6.0892 | 1.43705

# IfcRoof: Basic Roof:NLRS_27_RO_PIR dakisolatie + dakbedekking 130-3-3_gen_bdg, Basic Roof:NLRS_27_RO_PIR dakisolatie + dakbedekking 130-3-3_gen_bdg:880274
In: 02 tweede verdieping
Classification: 27.11 Uniformat (Uniformat); Material: s9_bitumen 3 mm, s9_bitumen 3 mm, n7_dakisolatie_gen 130 mm
Slab Shape Edit - Curved Edge Condition: 0
Constraints - Related to Mass: no; Room Bounding: yes; Cutoff Offset: 0 mm; Base Level: 02 tweede verdieping; Base Offset From Level: -50 mm
Phasing - Phase Created: 2. nieuwbouw
Construction - Fascia Depth: 0 mm; Rafter Cut: Plumb Cut; Maximum Ridge Height: 7886 mm
Dimensions - Area: 112.176 m2; Volume: 23.4494 m3
Identity Data - Workset: Workset1
Other - Category: Roofs; Family: Basic Roof; Family and Type: Basic Roof: NLRS_27_RO_PIR dakisolatie + dakbedekking 130-3-3_gen_bdg; Type: NLRS_27_RO_PIR dakisolatie + dakbedekking 130-3-3_gen_bdg; Type Id: 880316
Analytical Properties(Type) - Roughness: 1; Absorptance: 0.1; Heat Transfer Coefficient (U): 833333 kg/K/s3; Thermal Mass: 11.7432; Thermal Resistance (R): 0.0000012
Graphics(Type) - Coarse Scale Fill Pattern: <Solid fill>; Coarse Scale Fill Color: 8421504
Construction(Type) - Default Thickness: 136 mm
Identity Data(Type) - Workset: Roof Types; Assembly Code: 27.11; Assembly Description: daken; niet constructief, vlakke daken; Description: PIR afschotisolatie + dakbedekking; SmartRevit_Versie: 2017.3; Type Name: NLRS_27_RO_PIR dakisolatie + dakbedekking 130-3-3_gen_bdg
Other(Type) - Category: Roofs; Family Name: Basic Roof

# IfcRoof: Basic Roof:NLRS_27_RO_PIR dakisolatie 100_gen_bdg (3)
Classification: 27.11 Uniformat (Uniformat); Material: n7_dakisolatie_gen 100 mm
Constraints - Related to Mass: no; Room Bounding: yes; Cutoff Offset: 0 mm
Phasing - Phase Created: 2. nieuwbouw
Construction - Fascia Depth: 0 mm; Rafter Cut: Plumb Cut; Maximum Ridge Height: 4050 mm
Dimensions - Thickness: 100 mm
Identity Data - Workset: Workset1
Other - Category: Roofs; Family: Basic Roof; Family and Type: Basic Roof: NLRS_27_RO_PIR dakisolatie 100_gen_bdg; Type: NLRS_27_RO_PIR dakisolatie 100_gen_bdg; Type Id: 2002782
Name (Basic Roof:NLRS_27_RO_PIR dakisolatie 100_gen_bdg:...) | In | Curved Edge Condition | Base Level | Base Offset From Level (mm) | Area (m2) | Volume (m3)
1301771 | 01 eerste verdieping | 0 | 01 eerste verdieping | -50 | 444.599 | 44.4599
2006157 | 01 eerste verdieping | 1 | 01 eerste verdieping | -50 | 73.6394 | 7.36394 | Dimensions - Slope: 0
3345975 | 00 begane grond |  | 01 ok. ruwe vloer | 320 | 15.7513 | 1.57513

# IfcRoof: Basic Roof:NLRS_27_RO_PIR dakisolatie afschot + dakbedekking 30-3-3_gen_bdg (4)
Classification: 27.11 Uniformat (Uniformat); Material: s9_bitumen 3 mm, s9_bitumen 3 mm, n7_dakisolatie_gen 30 mm
Slab Shape Edit - Curved Edge Condition: 0
Constraints - Related to Mass: no; Room Bounding: yes; Cutoff Offset: 0 mm
Phasing - Phase Created: 2. nieuwbouw
Construction - Fascia Depth: 0 mm; Rafter Cut: Plumb Cut; Maximum Ridge Height: 4086 mm
Identity Data - Workset: Workset1
Other - Category: Roofs; Family: Basic Roof; Family and Type: Basic Roof: NLRS_27_RO_PIR dakisolatie afschot + dakbedekking 30-3-3_gen_bdg; Type: NLRS_27_RO_PIR dakisolatie afschot + dakbedekking 30-3-3_gen_bdg; Type Id: 2002951
Analytical Properties(Type) - Roughness: 1; Absorptance: 0.1; Heat Transfer Coefficient (U): 833333 kg/K/s3; Thermal Mass: 11.7432; Thermal Resistance (R): 0.0000012
Graphics(Type) - Coarse Scale Fill Pattern: <Solid fill>; Coarse Scale Fill Color: 8421504
Construction(Type) - Default Thickness: 36 mm
Identity Data(Type) - Workset: Roof Types; Assembly Code: 27.11; Assembly Description: daken; niet constructief, vlakke daken; Description: PIR afschotisolatie + dakbedekking; SmartRevit_Versie: 2017.3; Type Name: NLRS_27_RO_PIR dakisolatie afschot + dakbedekking 30-3-3_gen_bdg
Other(Type) - Category: Roofs; Family Name: Basic Roof
Name (Basic Roof:NLRS_27_RO_PIR dakisolatie afschot + dakbedekking 30-3-3_gen_bdg:...) | In | Base Level | Base Offset From Level (mm) | Area (m2) | Volume (m3)
2002843 | 01 eerste verdieping | 01 eerste verdieping | 50 | 359.37 | 27.9819 | Dimensions - Slope: 0
2249088 | 01 eerste verdieping | 01 eerste verdieping | 50 | 141.484 | 11.86 | Dimensions - Slope: 0
3346046 | 00 begane grond | 01 ok. ruwe vloer | 420 | 15.7531 | 1.92289
4690059 | 01 eerste verdieping | 01 eerste verdieping | 50 | 18.08 | 2.73159

# IfcRoof: Basic Roof:NLRS_27_RO_SAB 100R/825, Basic Roof:NLRS_27_RO_SAB 100R/825:4130970
In: 00 begane grond
Classification: 27.11 Uniformat (Uniformat); Material: h2_staal 100 mm; Group: Model Group:fietsenstalling:4188142
Constraints - Related to Mass: no; Room Bounding: yes; Cutoff Offset: 0 mm; Base Level: 00 bk. ruwe vloer; Base Offset From Level: 2032.92 mm
Phasing - Phase Created: 2. nieuwbouw
Construction - Fascia Depth: 0 mm; Rafter Cut: Plumb Cut; Maximum Ridge Height: 2361.16 mm
Dimensions - Slope: 5; Area: 46.8987 m2; Thickness: 100 mm; Volume: 4.68987 m3
Identity Data - Workset: BDG_fietsenstalling
Other - Category: Roofs; Family: Basic Roof; Family and Type: Basic Roof: NLRS_27_RO_SAB 100R/825; Type: NLRS_27_RO_SAB 100R/825; Type Id: 4131005

# IfcRoof: Basic Roof:NLRS_27_RO_Unidek Aero 6.3 + bitumen 3+3+215_gen_bdg 2 (4)
In: 03 derde verdieping
Classification: 27.11 Uniformat (Uniformat); Material: s9_bitumen 3 mm, s9_bitumen 3 mm, multiplex_horizontaal 18 mm, n7_dakisolatie_gen 246 mm, multiplex_horizontaal 12 mm
Constraints - Related to Mass: no; Room Bounding: yes; Base Level: 03 derde verdieping; Cutoff Offset: 0 mm; Base Offset From Level: 0 mm
Phasing - Phase Created: 2. nieuwbouw
Construction - Fascia Depth: 0 mm; Rafter Cut: Plumb Cut; Maximum Ridge Height: 13494.8 mm
Dimensions - Slope: 33; Thickness: 282 mm
Identity Data - Workset: Workset1
Other - Category: Roofs; Family: Basic Roof; Family and Type: Basic Roof: NLRS_27_RO_Unidek Aero 6.3 + bitumen 3+3+215_gen_bdg 2; Type: NLRS_27_RO_Unidek Aero 6.3 + bitumen 3+3+215_gen_bdg 2; Type Id: 2171866
Name (Basic Roof:NLRS_27_RO_Unidek Aero 6.3 + bitumen 3+3+215_gen_bdg 2:...) | Area (m2) | Volume (m3) | Group
2182219 | 18.618 | 5.25029 | Model Group:daklicht A1:2182252
2182274 | 18.618 | 5.25029 | Model Group:daklicht A1 (members excluded):2182288
2182296 | 36.3647 | 10.2548 | Model Group:BU-42 daklicht B lokaal:2182308
2194770 | 36.3647 | 10.2548 | Model Group:BU-42 daklicht B lokaal:2194782

# IfcRoof: Basic Roof:NLRS_27_RO_daktegels 500x500x50_gen_bdg (2)
Classification: 27.11 Uniformat (Uniformat); Material: g3_tegels_grijs_500x500 50 mm
Constraints - Related to Mass: no; Room Bounding: yes; Cutoff Offset: 0 mm
Phasing - Phase Created: 2. nieuwbouw
Construction - Fascia Depth: 0 mm; Rafter Cut: Plumb Cut
Dimensions - Thickness: 50 mm
Identity Data - Workset: Workset1
Other - Category: Roofs; Family: Basic Roof; Family and Type: Basic Roof: NLRS_27_RO_daktegels 500x500x50_gen_bdg; Type: NLRS_27_RO_daktegels 500x500x50_gen_bdg; Type Id: 1302098
Name (Basic Roof:NLRS_27_RO_daktegels 500x500x50_gen_bdg:...) | In | Base Level | Base Offset From Level (mm) | Maximum Ridge Height (mm) | Area (m2) | Volume (m3)
1303146 | 02 tweede verdieping | 02 tweede verdieping | 223 | 8073 | 103.154 | 5.15771
2548296 | 01 eerste verdieping | 01 eerste verdieping | 210 | 4260 | 317.57 | 15.8785

# IfcRoof: Basic Roof:NLRS_27_RO_steenwolisolatie + dakbedekking 180-3-3_gen_bdg, Basic Roof:NLRS_27_RO_steenwolisolatie + dakbedekking 180-3-3_gen_bdg:874240
In: 03 derde verdieping
Classification: 27.11 Uniformat (Uniformat); Material: s9_bitumen 3 mm, s9_bitumen 3 mm, n7_dakisolatie_gen 180 mm
Slab Shape Edit - Curved Edge Condition: 0
Constraints - Related to Mass: no; Room Bounding: yes; Base Level: 03 derde verdieping; Base Offset From Level: -50 mm; Cutoff Offset: 0 mm
Phasing - Phase Created: 2. nieuwbouw
Construction - Fascia Depth: 0 mm; Maximum Ridge Height: 11736 mm; Rafter Cut: Plumb Cut
Dimensions - Area: 516.732 m2; Volume: 144.548 m3
Identity Data - Workset: Workset1
Other - Category: Roofs; Family: Basic Roof; Family and Type: Basic Roof: NLRS_27_RO_steenwolisolatie + dakbedekking 180-3-3_gen_bdg; Type: NLRS_27_RO_steenwolisolatie + dakbedekking 180-3-3_gen_bdg; Type Id: 476088
Analytical Properties(Type) - Roughness: 1; Absorptance: 0.1; Heat Transfer Coefficient (U): 833333 kg/K/s3; Thermal Mass: 11.7432; Thermal Resistance (R): 0.0000012
Graphics(Type) - Coarse Scale Fill Pattern: <Solid fill>; Coarse Scale Fill Color: 8421504
Construction(Type) - Default Thickness: 186 mm
Identity Data(Type) - Assembly Code: 27.11; Assembly Description: daken; niet constructief, vlakke daken; Description: steenwol afschotisolatie + dakbedekking; SmartRevit_Versie: 2017.3; Type Name: NLRS_27_RO_steenwolisolatie + dakbedekking 180-3-3_gen_bdg; Workset: Roof Types
Other(Type) - Category: Roofs; Family Name: Basic Roof

# IfcRoof: Basic Roof:NLRS_27_RO_steenwolisolatie afschot + dakbedekking 240-3-3_gen_bdg, Basic Roof:NLRS_27_RO_steenwolisolatie afschot + dakbedekking 240-3-3_gen_bdg:2097891
In: 01 eerste verdieping
Classification: 27.11 Uniformat (Uniformat); Material: s9_bitumen 3 mm, s9_bitumen 3 mm, n7_dakisolatie_gen 240 mm
Slab Shape Edit - Curved Edge Condition: 0
Constraints - Related to Mass: no; Room Bounding: yes; Cutoff Offset: 0 mm; Base Level: 02 bk. constructie gymzaal; Base Offset From Level: 108 mm
Phasing - Phase Created: 2. nieuwbouw
Construction - Fascia Depth: 0 mm; Rafter Cut: Plumb Cut; Maximum Ridge Height: 6854 mm
Dimensions - Slope: 0; Area: 326.287 m2; Volume: 115.737 m3
Identity Data - Workset: Workset1
Other - Category: Roofs; Family: Basic Roof; Family and Type: Basic Roof: NLRS_27_RO_steenwolisolatie afschot + dakbedekking 240-3-3_gen_bdg; Type: NLRS_27_RO_steenwolisolatie afschot + dakbedekking 240-3-3_gen_bdg; Type Id: 2097906
Analytical Properties(Type) - Roughness: 1; Absorptance: 0.1; Heat Transfer Coefficient (U): 833333 kg/K/s3; Thermal Mass: 11.7432; Thermal Resistance (R): 0.0000012
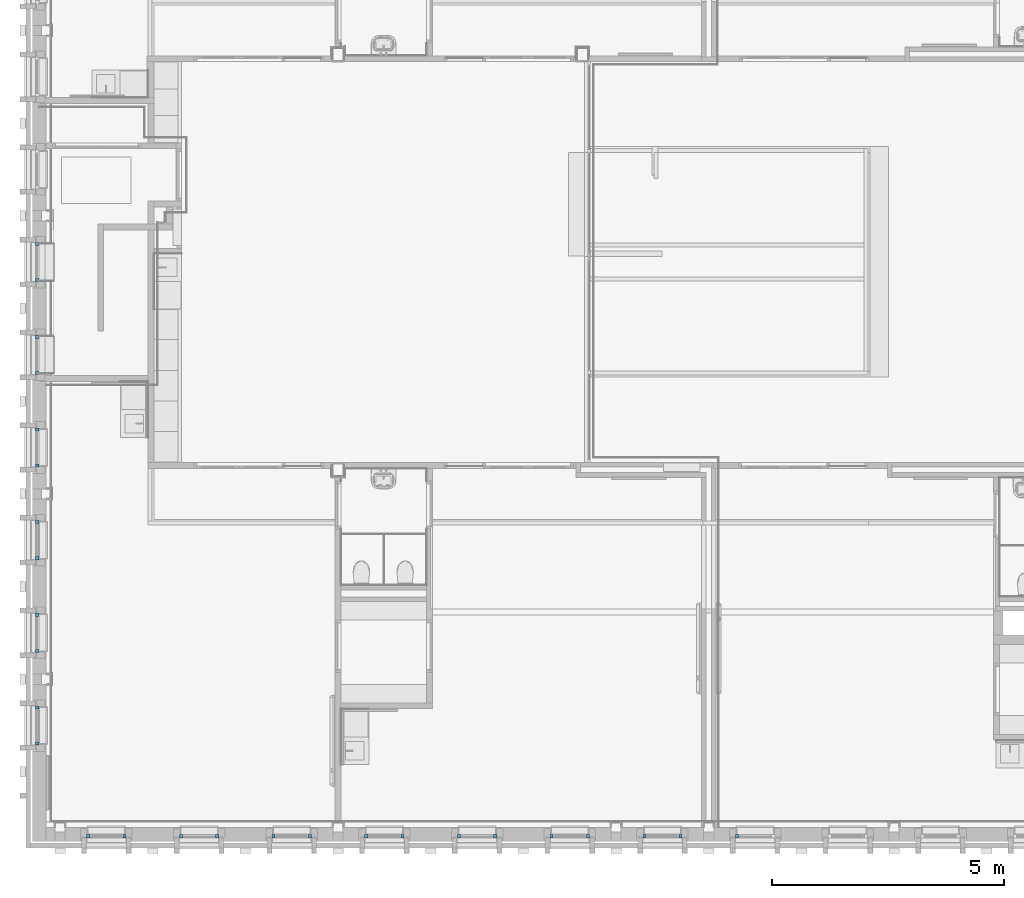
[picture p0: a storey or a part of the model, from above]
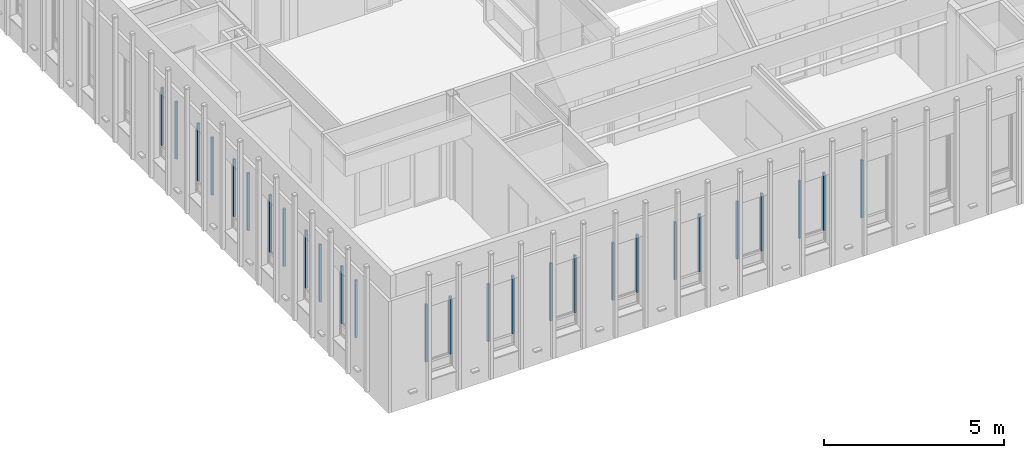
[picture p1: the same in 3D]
Properties of the parts of a building model (IFC2X3), part 82 of 94

# IfcRoof: Basic Roof:NLRS_27_RO_steenwolisolatie afschot + dakbedekking 240-3-3_gen_bdg, Basic Roof:NLRS_27_RO_steenwolisolatie afschot + dakbedekking 240-3-3_gen_bdg:2097891
Graphics(Type) - Coarse Scale Fill Pattern: <Solid fill>; Coarse Scale Fill Color: 8421504
Construction(Type) - Default Thickness: 246 mm
Identity Data(Type) - Workset: Roof Types; Assembly Code: 27.11; Assembly Description: daken; niet constructief, vlakke daken; Description: steenwol afschotisolatie + dakbedekking; SmartRevit_Versie: 2017.3; Type Name: NLRS_27_RO_steenwolisolatie afschot + dakbedekking 240-3-3_gen_bdg
Other(Type) - Category: Roofs; Family Name: Basic Roof

# IfcRoof: Basic Roof:NLRS_27_RO_trapeziumplaat, Basic Roof:NLRS_27_RO_trapeziumplaat:4022684
In: 00 begane grond
Classification: 27.11 Uniformat (Uniformat); Material: a_begroeiing 50 mm, s9_bitumen 3 mm, ISR_Luchtspouw 17 mm, Tr_21_isolatie_hoogwaardig 30 mm; Group: Model Group:fietsenstalling:4188142
Constraints - Related to Mass: no; Room Bounding: yes; Cutoff Offset: 0 mm; Base Level: 00 begane grond; Base Offset From Level: 2073.3 mm
Phasing - Phase Created: 2. nieuwbouw
Construction - Fascia Depth: 0 mm; Rafter Cut: Plumb Cut; Maximum Ridge Height: 2461.54 mm
Dimensions - Area: 46.8987 m2; Slope: 5; Thickness: 100 mm; Volume: 4.68987 m3
Identity Data - Workset: BDG_fietsenstalling
Other - Category: Roofs; Family: Basic Roof; Family and Type: Basic Roof: NLRS_27_RO_trapeziumplaat; Type: NLRS_27_RO_trapeziumplaat; Type Id: 4022686

# IfcRoof: NLRS_16_GM_PSkist_gen_bdg:balk 500x600 (21)
In: 00 begane grond
Classification: 16.10 Uniformat (Uniformat); Material: ISR_Isolatie PS
Constraints - Elevation from Level: 0 mm; Offset from Host: 0 mm; Level: bk. fundering; Schedule Level: bk. fundering; Work Plane: Level : bk. fundering
Phasing - Phase Created: 2. nieuwbouw
Dimensions - verlenging_L: 0 mm; verlenging_R: 0 mm; hoek_L: 0 deg; hoek_R: 0 deg
Identity Data - Workset: Workset1
Other - Category: Generic Models; berekende_overstek_a: 0 mm; berekende_overstek_b: 0 mm; Berekende_hoek_a+180: 180 deg; Berekende_hoek_b: -180 deg; Berekende_hoek_b+180: 0 deg; eindschot_L: no; Family: NLRS_16_GM_PSkist_gen_bdg; berekende_verlenging_a: 2000 mm; berekende_verlenging_b: 2000 mm; Family and Type: NLRS_16_GM_PSkist_gen_bdg: balk 500x600; Type: balk 500x600; Type Id: 3217241
Name (NLRS_16_GM_PSkist_gen_bdg:balk 500x600:...) | Area (m2) | element_lengte (mm) = lengte (mm) | Volume (m3) | eindschot_R
3217158 | 23.3138 | 5913.36 | 1.09918 | no
3382729 | 58.6067 | 17390.7 | 3.26553 | no
3382737 | 63.2679 | 18720 | 3.575 | yes
3382763 | 46.3067 | 13270 | 2.54519 | no
3382773 | 48.504 | 13980 | 2.68136 | no
3382783 | 73.1297 | 21937.3 | 4.20758 | no
3382855 | 68.0016 | 20461.7 | 3.84167 | no
3382867 | 36.7886 | 10267.5 | 1.93431 | no
3382889 | 62.0398 | 18500 | 3.4783 | no
3382899 | 17.6278 | 8330 | 1.59769 | no
3382907 | 15.8326 | 7430 | 1.42507 | no
3383388 | 3.72462 | 1360 | 0.260848 | no
3383669 | 5.49992 | 2250 | 0.46155 | yes
3383839 | 5.49992 | 2250 | 0.43155 | no
3384271 | 17.8966 | 4089.83 | 0.784429 | no
3829193 | 28.872 | 7650 | 1.42727 | yes
3829199 | 20.717 | 5250 | 0.91595 | no
3829205 | 10.7161 | 4865 | 0.933107 | no
3829240 | 28.7597 | 7600 | 1.45768 | no
3829247 | 15.5134 | 7270 | 1.39439 | no
3829385 | 21.9422 | 5510 | 1.01552 | no

# IfcRoof: NLRS_16_GM_PSkist_gen_bdg:balk 550x600 (2)
In: 00 begane grond
Classification: 16.10 Uniformat (Uniformat); Material: ISR_Isolatie PS
Constraints - Elevation from Level: 0 mm; Offset from Host: 0 mm; Level: bk. fundering; Schedule Level: bk. fundering; Work Plane: Level : bk. fundering
Phasing - Phase Created: 2. nieuwbouw
Dimensions - verlenging_L: 0 mm; verlenging_R: 0 mm; hoek_L: 0 deg; hoek_R: 0 deg
Identity Data - Workset: Workset1
Other - Category: Generic Models; berekende_overstek_a: 0 mm; berekende_overstek_b: 0 mm; Berekende_hoek_a+180: 180 deg; Berekende_hoek_b: -180 deg; Berekende_hoek_b+180: 0 deg; Family: NLRS_16_GM_PSkist_gen_bdg; eindschot_L: yes; berekende_verlenging_a: 2000 mm; berekende_verlenging_b: 2000 mm; Family and Type: NLRS_16_GM_PSkist_gen_bdg: balk 550x600; Type: balk 550x600; Type Id: 3186697
Constraints(Type) - Default Elevation: 1219.2 mm; breedte_achter: 120 mm; breedte_voor: 30 mm
Materials and Finishes(Type) - materiaal: ISR_Isolatie PS
Dimensions(Type) - balk_breedte: 550 mm; balk_hoogte: 600 mm
Identity Data(Type) - Workset: Family : Generic Models : NLRS_16_GM_PSkist_gen_bdg; Assembly Code: 16.10; Assembly Description: funderingsconstructies; voeten en balken, algemeen (verzamelniveau); Description: PS funderingsbekisting; Model: daktrim; Type Name: balk 550x600
Other(Type) - Category: Generic Models; Family Name: NLRS_16_GM_PSkist_gen_bdg
Name (NLRS_16_GM_PSkist_gen_bdg:balk 550x600:...) | Area (m2) | element_lengte (mm) = lengte (mm) | Volume (m3) | eindschot_R
3382929 | 41.7617 | 11383 | 2.1594 | yes
3829201 | 17.3673 | 3743 | 0.694008 | no

# IfcRoof: NLRS_16_GM_PSkist_gen_bdg:balk 600x600 (4)
In: 00 begane grond
Classification: 16.10 Uniformat (Uniformat); Material: ISR_Isolatie PS
Constraints - Elevation from Level: 0 mm; Offset from Host: 0 mm; Level: bk. fundering; Schedule Level: bk. fundering; Work Plane: Level : bk. fundering
Phasing - Phase Created: 2. nieuwbouw
Dimensions - verlenging_L: 0 mm; verlenging_R: 0 mm; hoek_L: 0 deg; hoek_R: 0 deg
Identity Data - Workset: Workset1
Other - Category: Generic Models; berekende_overstek_a: 0 mm; berekende_overstek_b: 0 mm; Berekende_hoek_a+180: 180 deg; Berekende_hoek_b: -180 deg; Berekende_hoek_b+180: 0 deg; berekende_verlenging_a: 2000 mm; berekende_verlenging_b: 2000 mm; Family: NLRS_16_GM_PSkist_gen_bdg; Family and Type: NLRS_16_GM_PSkist_gen_bdg: balk 600x600; Type: balk 600x600; Type Id: 3186693
Constraints(Type) - Default Elevation: 1219.2 mm; breedte_achter: 120 mm; breedte_voor: 30 mm
Materials and Finishes(Type) - materiaal: ISR_Isolatie PS
Dimensions(Type) - balk_breedte: 600 mm; balk_hoogte: 600 mm
Identity Data(Type) - Assembly Code: 16.10; Assembly Description: funderingsconstructies; voeten en balken, algemeen (verzamelniveau); Description: PS funderingsbekisting; Model: daktrim; Type Name: balk 600x600; Workset: Family : Generic Models : NLRS_16_GM_PSkist_gen_bdg
Other(Type) - Category: Generic Models; Family Name: NLRS_16_GM_PSkist_gen_bdg
Name (NLRS_16_GM_PSkist_gen_bdg:balk 600x600:...) | Area (m2) | element_lengte (mm) = lengte (mm) | Volume (m3) | eindschot_L | eindschot_R
3186703 | 80.5191 | 22637.2 | 4.49426 | no | yes
3195188 | 72.8186 | 20427.7 | 4.02602 | no | no
3195199 | 100.422 | 28815.3 | 5.65249 | yes | no
3829305 | 8.47744 | 870 | 0.157556 | no | no

# IfcRoof: NLRS_16_GM_PSkist_gen_bdg:balk 650x600 (6)
In: 00 begane grond
Classification: 16.10 Uniformat (Uniformat); Material: ISR_Isolatie PS
Constraints - Elevation from Level: 0 mm; Offset from Host: 0 mm; Level: bk. fundering; Schedule Level: bk. fundering; Work Plane: Level : bk. fundering
Phasing - Phase Created: 2. nieuwbouw
Dimensions - verlenging_L: 0 mm; verlenging_R: 0 mm; hoek_L: 0 deg; hoek_R: 0 deg
Identity Data - Workset: Workset1
Other - Category: Generic Models; berekende_overstek_a: 0 mm; berekende_overstek_b: 0 mm; Berekende_hoek_a+180: 180 deg; Berekende_hoek_b: -180 deg; Berekende_hoek_b+180: 0 deg; Family: NLRS_16_GM_PSkist_gen_bdg; berekende_verlenging_a: 2000 mm; berekende_verlenging_b: 2000 mm; Family and Type: NLRS_16_GM_PSkist_gen_bdg: balk 650x600; Type: balk 650x600; Type Id: 3186701
Name (NLRS_16_GM_PSkist_gen_bdg:balk 650x600:...) | Area (m2) | element_lengte (mm) = lengte (mm) | Volume (m3) | eindschot_R | eindschot_L
3186708 | 151.061 | 42653 | 8.5912 | yes | yes
3382718 | 84.5812 | 23395 | 4.56181 | no | yes
3382719 | 94.1302 | 25882.5 | 5.19853 | yes | yes
3382747 | 40.9015 | 10280 | 2.07964 | no | no
3382921 | 41.2685 | 10454.7 | 2.07999 | no | no
3829228 | 30.3684 | 7270 | 1.42522 | no | no

# IfcRoof: NLRS_16_GM_PSkist_gen_bdg:balk 700x600, NLRS_16_GM_PSkist_gen_bdg:balk 700x600:3829254
In: 00 begane grond
Classification: 16.10 Uniformat (Uniformat); Material: ISR_Isolatie PS
Constraints - Elevation from Level: 0 mm; Offset from Host: 0 mm; Level: bk. fundering; Schedule Level: bk. fundering; Work Plane: Level : bk. fundering
Phasing - Phase Created: 2. nieuwbouw
Dimensions - verlenging_L: 0 mm; verlenging_R: 0 mm; hoek_L: 0 deg; hoek_R: 0 deg; Area: 28.3477 m2; element_lengte: 6462.67 mm; lengte: 6462.67 mm; Volume: 1.25302 m3
Identity Data - Workset: Workset1
Other - Category: Generic Models; berekende_overstek_a: 0 mm; berekende_overstek_b: 0 mm; Berekende_hoek_a+180: 180 deg; Berekende_hoek_b: -180 deg; Berekende_hoek_b+180: 0 deg; eindschot_L: no; Family: NLRS_16_GM_PSkist_gen_bdg; eindschot_R: no; berekende_verlenging_a: 2000 mm; berekende_verlenging_b: 2000 mm; Family and Type: NLRS_16_GM_PSkist_gen_bdg: balk 700x600; Type: balk 700x600; Type Id: 3829258
Constraints(Type) - Default Elevation: 1219.2 mm; breedte_achter: 120 mm; breedte_voor: 30 mm
Materials and Finishes(Type) - materiaal: ISR_Isolatie PS
Dimensions(Type) - balk_breedte: 700 mm; balk_hoogte: 600 mm
Identity Data(Type) - Workset: Family : Generic Models : NLRS_16_GM_PSkist_gen_bdg; Assembly Code: 16.10; Assembly Description: funderingsconstructies; voeten en balken, algemeen (verzamelniveau); Description: PS funderingsbekisting; Model: daktrim; Type Name: balk 700x600
Other(Type) - Category: Generic Models; Family Name: NLRS_16_GM_PSkist_gen_bdg

# IfcRoof: NLRS_41_GM_muurafdekker_aluminium_gen_bdg:aluminium muurafdekker b170 muurb100 (3)
In: 01 eerste verdieping
Classification: 41.10 Uniformat (Uniformat); Material: <Unnamed>, multiplex_horizontaal
Constraints - Level: 02 dakrand gymzaal; Schedule Level: 02 dakrand gymzaal; Elevation from Level: 75 mm; Offset from Host: 75 mm; Work Plane: Level : 02 dakrand gymzaal
Phasing - Phase Created: 2. nieuwbouw
Dimensions - verlenging_L: 0 mm; verlenging_R: 0 mm
Identity Data - Workset: Workset1
Other - Category: Generic Models; Family: NLRS_41_GM_muurafdekker_aluminium_gen_bdg; berekende_verlenging_a: 2000 mm; berekende_verlenging_b: 2000 mm; Family and Type: NLRS_41_GM_muurafdekker_aluminium_gen_bdg: aluminium muurafdekker b170 muurb100; Type: aluminium muurafdekker b170 muurb100; Type Id: 4884203
Constraints(Type) - Default Elevation: 0 mm; breedte_achter: 140 mm; breedte_voor: 30 mm
Materials and Finishes(Type) - materiaal_plank: multiplex_horizontaal
Dimensions(Type) - bk_multiplex_tov_bk_afdekker: -40 mm; breedte: 170 mm; dikte: 2 mm; helling: 2 deg; hoogte_aanzicht: 50 mm; multiplex_breedte: 100 mm; multiplex_dikte: 20 mm
Identity Data(Type) - Workset: Family : Generic Models : NLRS_41_GM_muurafdekker_aluminium_gen_bdg; Assembly Code: 41.10; Assembly Description: buitenwandafwerkingen; algemeen (verzamelniveau); Description: daktrim; Model: daktrim; Type Name: aluminium muurafdekker b170 muurb100
Other(Type) - Category: Generic Models; multiplex: yes; Family Name: NLRS_41_GM_muurafdekker_aluminium_gen_bdg
Name (NLRS_41_GM_muurafdekker_aluminium_gen_bdg:aluminium muurafdekker b170 muurb100:...) | hoek_R (deg) = Berekende_hoek_b+180 (deg) | hoek_L (deg) | Area (m2) | element_lengte (mm) | lengte (mm) | Volume (m3) | berekende_overstek_a (mm) | Berekende_hoek_b (deg) | Berekende_hoek_a+180 (deg) | berekende_overstek_b (mm)
4884148 | 45 | 0 | 1.5178 | 3655 | 3625 | 0.00934748 | 0 | -135 | 180 | 30
4884667 | 45 | 45 | 6.37066 | 15180 | 15120 | 0.0392812 | 30 | -135 | 225 | 30
4884747 | 0 | 45 | 1.5178 | 3655 | 3625 | 0.00934748 | 30 | -180 | 225 | 0

# IfcRoof: NLRS_41_GM_muurafdekker_aluminium_gen_bdg:aluminium muurafdekker b287 muurb217, NLRS_41_GM_muurafdekker_aluminium_gen_bdg:aluminium muurafdekker b287 muurb217:1922220
In: 01 eerste verdieping
Classification: 41.10 Uniformat (Uniformat); Material: <Unnamed>
Constraints - Level: 02 dakrand gymzaal; Schedule Level: 02 dakrand gymzaal; Elevation from Level: 75 mm; Offset from Host: 75 mm; Work Plane: Level : 02 dakrand gymzaal
Phasing - Phase Created: 2. nieuwbouw
Dimensions - verlenging_L: 0 mm; verlenging_R: 0 mm; Area: 9.7527 m2; element_lengte: 15180 mm; hoek_L: 52.94 deg; hoek_R: 52.94 deg; lengte: 15100.6 mm; Volume: 0.0768644 m3
Identity Data - Workset: Workset1
Other - Category: Generic Models; Family: NLRS_41_GM_muurafdekker_aluminium_gen_bdg; Berekende_hoek_a+180: 232.94 deg; Berekende_hoek_b: -127.06 deg; Berekende_hoek_b+180: 52.94 deg; berekende_overstek_a: 39.7247 mm; berekende_overstek_b: 39.7247 mm; berekende_verlenging_a: 2000 mm; berekende_verlenging_b: 2000 mm; Family and Type: NLRS_41_GM_muurafdekker_aluminium_gen_bdg: aluminium muurafdekker b287 muurb217; Type: aluminium muurafdekker b287 muurb217; Type Id: 2369404
Constraints(Type) - Default Elevation: 0 mm; breedte_achter: 257 mm; breedte_voor: 30 mm
Dimensions(Type) - bk_multiplex_tov_bk_afdekker: -40 mm; breedte: 287 mm; dikte: 2 mm; helling: 2 deg; hoogte_aanzicht: 50 mm; multiplex_breedte: 217 mm; multiplex_dikte: 20 mm
Identity Data(Type) - Workset: Family : Generic Models : NLRS_41_GM_muurafdekker_aluminium_gen_bdg; Assembly Code: 41.10; Assembly Description: buitenwandafwerkingen; algemeen (verzamelniveau); Description: daktrim; Model: daktrim; Type Name: aluminium muurafdekker b287 muurb217
Other(Type) - Category: Generic Models; multiplex: yes; Family Name: NLRS_41_GM_muurafdekker_aluminium_gen_bdg

# IfcRoof: NLRS_41_GM_muurafdekker_aluminium_gen_bdg:aluminium muurafdekker b320 muurb258, NLRS_41_GM_muurafdekker_aluminium_gen_bdg:aluminium muurafdekker b320 muurb258:3308447
In: 01 eerste verdieping
Classification: 41.10 Uniformat (Uniformat); Material: <Unnamed>
Constraints - Level: 01 eerste verdieping; Schedule Level: 01 eerste verdieping; Elevation from Level: 815 mm; Offset from Host: 815 mm; Work Plane: Level : 01 eerste verdieping
Phasing - Phase Created: 2. nieuwbouw
Dimensions - verlenging_L: 0 mm; verlenging_R: 0 mm; hoek_L: 0 deg; hoek_R: 0 deg; Area: 3.63592 m2; element_lengte: 4957.5 mm; lengte: 4957.5 mm; Volume: 0.0301216 m3
Identity Data - Workset: Workset1
Other - Category: Generic Models; berekende_overstek_a: 0 mm; berekende_overstek_b: 0 mm; Family: NLRS_41_GM_muurafdekker_aluminium_gen_bdg; Berekende_hoek_a+180: 180 deg; Berekende_hoek_b: -180 deg; Berekende_hoek_b+180: 0 deg; berekende_verlenging_a: 2000 mm; berekende_verlenging_b: 2000 mm; Family and Type: NLRS_41_GM_muurafdekker_aluminium_gen_bdg: aluminium muurafdekker b320 muurb258; Type: aluminium muurafdekker b320 muurb258; Type Id: 3308581

# IfcRoof: NLRS_41_GM_muurafdekker_aluminium_gen_bdg:aluminium muurafdekker b378 muurb308 (4)
In: 03 derde verdieping
Classification: 41.10 Uniformat (Uniformat); Material: <Unnamed>
Constraints - Level: 03 derde verdieping; Schedule Level: 03 derde verdieping; Elevation from Level: 680 mm; Offset from Host: 680 mm; Work Plane: Level : 03 derde verdieping
Phasing - Phase Created: 2. nieuwbouw
Dimensions - hoek_L: 45 deg; hoek_R: 45 deg; verlenging_L: 0 mm; verlenging_R: 0 mm
Identity Data - Workset: Workset1
Other - Category: Generic Models; Berekende_hoek_a+180: 225 deg; Berekende_hoek_b: -135 deg; Berekende_hoek_b+180: 45 deg; berekende_overstek_a: 30 mm; berekende_overstek_b: 30 mm; berekende_verlenging_a: 2000 mm; berekende_verlenging_b: 2000 mm; Family: NLRS_41_GM_muurafdekker_aluminium_gen_bdg; Family and Type: NLRS_41_GM_muurafdekker_aluminium_gen_bdg: aluminium muurafdekker b378 muurb308; Type: aluminium muurafdekker b378 muurb308; Type Id: 2270156
Constraints(Type) - Default Elevation: 0 mm; breedte_achter: 347 mm; breedte_voor: 30 mm
Dimensions(Type) - bk_multiplex_tov_bk_afdekker: -40 mm; breedte: 377 mm; dikte: 2 mm; helling: 2 deg; hoogte_aanzicht: 50 mm; multiplex_breedte: 308 mm; multiplex_dikte: 20 mm
Identity Data(Type) - Assembly Code: 41.10; Assembly Description: buitenwandafwerkingen; algemeen (verzamelniveau); Description: daktrim; Model: daktrim; Type Name: aluminium muurafdekker b378 muurb308; Workset: Family : Generic Models : NLRS_41_GM_muurafdekker_aluminium_gen_bdg
Other(Type) - Category: Generic Models; Family Name: NLRS_41_GM_muurafdekker_aluminium_gen_bdg; multiplex: yes
Name (NLRS_41_GM_muurafdekker_aluminium_gen_bdg:aluminium muurafdekker b378 muurb308:...) | Area (m2) | element_lengte (mm) | lengte (mm) | Volume (m3)
1748047 | 21.1306 | 25540 | 25480 | 0.180974
1749455 | 21.1306 | 25540 | 25480 | 0.180974
1749658 | 20.9627 | 25340 | 25280 | 0.179536
1749686 | 20.9627 | 25340 | 25280 | 0.179536

# IfcRoof: NLRS_41_GM_muurafdekker_aluminium_gen_bdg:aluminium muurafdekker b380 muurb310 (3)
In: 01 eerste verdieping
Classification: 41.10 Uniformat (Uniformat); Material: <Unnamed>
Constraints - Elevation from Level: 75 mm; Level: 02 dakrand gymzaal; Offset from Host: 75 mm; Schedule Level: 02 dakrand gymzaal; Work Plane: Level : 02 dakrand gymzaal
Phasing - Phase Created: 2. nieuwbouw
Dimensions - verlenging_L: 0 mm; verlenging_R: 0 mm
Identity Data - Workset: Workset1
Other - Category: Generic Models; Family: NLRS_41_GM_muurafdekker_aluminium_gen_bdg; berekende_verlenging_a: 2000 mm; berekende_verlenging_b: 2000 mm; Family and Type: NLRS_41_GM_muurafdekker_aluminium_gen_bdg: aluminium muurafdekker b380 muurb310; Type: aluminium muurafdekker b380 muurb310; Type Id: 2369432
Constraints(Type) - Default Elevation: 0 mm; breedte_achter: 350 mm; breedte_voor: 30 mm
Dimensions(Type) - bk_multiplex_tov_bk_afdekker: -40 mm; breedte: 380 mm; dikte: 2 mm; helling: 2 deg; hoogte_aanzicht: 50 mm; multiplex_breedte: 310 mm; multiplex_dikte: 20 mm
Identity Data(Type) - Workset: Family : Generic Models : NLRS_41_GM_muurafdekker_aluminium_gen_bdg; Assembly Code: 41.10; Assembly Description: buitenwandafwerkingen; algemeen (verzamelniveau); Description: daktrim; Model: daktrim; Type Name: aluminium muurafdekker b380 muurb310
Other(Type) - Category: Generic Models; multiplex: yes; Family Name: NLRS_41_GM_muurafdekker_aluminium_gen_bdg
Name (NLRS_41_GM_muurafdekker_aluminium_gen_bdg:aluminium muurafdekker b380 muurb310:...) | hoek_L (deg) | hoek_R (deg) = Berekende_hoek_b+180 (deg) | Area (m2) | element_lengte (mm) | lengte (mm) | Volume (m3) | Berekende_hoek_a+180 (deg) | Berekende_hoek_b (deg) | berekende_overstek_a (mm) | berekende_overstek_b (mm)
1921887 | 45 | 45 | 12.5081 | 15180 | 15120 | 0.107151 | 225 | -135 | 30 | 30
1922119 | 45 | 37.06 | 19.2202 | 23085.2 | 23032.5 | 0.164683 | 225 | -142.94 | 30 | 22.6559
1922363 | 37.06 | 45 | 19.22 | 23085 | 23032.3 | 0.164681 | 217.06 | -135 | 22.6559 | 30

# IfcRoof: NLRS_41_GM_muurafdekker_aluminium_gen_bdg:aluminium muurafdekker b390 muurb320 (3)
Classification: 41.10 Uniformat (Uniformat); Material: <Unnamed>
Phasing - Phase Created: 2. nieuwbouw
Dimensions - verlenging_L: 0 mm; verlenging_R: 0 mm; hoek_R: 0 deg
Identity Data - Workset: Workset1
Other - Category: Generic Models; berekende_overstek_b: 0 mm; Family: NLRS_41_GM_muurafdekker_aluminium_gen_bdg; Berekende_hoek_b: -180 deg; Berekende_hoek_b+180: 0 deg; berekende_verlenging_a: 2000 mm; berekende_verlenging_b: 2000 mm; Family and Type: NLRS_41_GM_muurafdekker_aluminium_gen_bdg: aluminium muurafdekker b390 muurb320; Type: aluminium muurafdekker b390 muurb320; Type Id: 1924857
Name (NLRS_41_GM_muurafdekker_aluminium_gen_bdg:aluminium muurafdekker b390 muurb320:...) | In | Level = Schedule Level | Elevation from Level (mm) | Offset from Host (mm) | Work Plane | Area (m2) | element_lengte (mm) | hoek_L (deg) | lengte (mm) | Volume (m3) | Berekende_hoek_a+180 (deg) | berekende_overstek_a (mm)
1924694 | 02 tweede verdieping | 02 tweede verdieping | 643 | 643 | Level : 02 tweede verdieping | 3.56372 | 4347.54 | 50.61 | 4311 | 0.0306811 | 230.61 | 36.5356
1924955 | 01 eerste verdieping | 01 eerste verdieping | 2607.23 | 40 | Basic Wall : 21_WA_metselwerk_licht_100_gen_bdg | 5.54936 | 6412.5 | 0 | 6412.5 | 0.0478119 | 180 | 0
1925353 | 01 eerste verdieping | 01 eerste verdieping | 477.567 | 40 | <not associated> | 0.515468 | 587.816 | 0 | 587.816 | 0.00438279 | 180 | 0

# IfcRoof: NLRS_41_GM_muurafdekker_aluminium_gen_bdg:aluminium muurafdekker b410 muurb340 (6)
In: 01 eerste verdieping
Classification: 41.10 Uniformat (Uniformat); Material: <Unnamed>
Constraints - Level: 01 eerste verdieping; Schedule Level: 01 eerste verdieping; Elevation from Level: 815 mm; Offset from Host: 815 mm; Work Plane: Level : 01 eerste verdieping
Phasing - Phase Created: 2. nieuwbouw
Dimensions - verlenging_L: 0 mm; verlenging_R: 0 mm
Identity Data - Workset: Workset1
Other - Category: Generic Models; Family: NLRS_41_GM_muurafdekker_aluminium_gen_bdg; berekende_verlenging_a: 2000 mm; berekende_verlenging_b: 2000 mm; Family and Type: NLRS_41_GM_muurafdekker_aluminium_gen_bdg: aluminium muurafdekker b410 muurb340; Type: aluminium muurafdekker b410 muurb340; Type Id: 2250847
Name (NLRS_41_GM_muurafdekker_aluminium_gen_bdg:aluminium muurafdekker b410 muurb340:...) | hoek_L (deg) | hoek_R (deg) = Berekende_hoek_b+180 (deg) | Area (m2) | element_lengte (mm) | lengte (mm) | Volume (m3) | berekende_overstek_a (mm) | berekende_overstek_b (mm) | Berekende_hoek_a+180 (deg) | Berekende_hoek_b (deg)
2096506 | 0 | 0 | 5.28652 | 5837.59 | 5837.59 | 0.046094 | 0 | 0 | 180 | -180
2096682 | 0 | 0 | 6.03018 | 6660 | 6660 | 0.0525879 | 0 | 0 | 180 | -180
2549656 | 0 | 45 | 11.6626 | 13090 | 13060 | 0.101773 | 0 | 30 | 180 | -135
2549657 | 45 | 0 | 6.11047 | 6950 | 6920 | 0.0532908 | 30 | 0 | 225 | -180
2549659 | 0 | 0 | 13.6259 | 15060 | 15060 | 0.118915 | 0 | 0 | 180 | -180
2549660 | -55.2 | 0 | 12.3315 | 13923 | 13376.3 | 0.107563 | 546.748 | 0 | 124.8 | -180

# IfcRoof: NLRS_41_GM_muurafdekker_aluminium_gen_bdg:aluminium muurafdekker b450 muurb382, NLRS_41_GM_muurafdekker_aluminium_gen_bdg:aluminium muurafdekker b450 muurb382:1753955
In: 01 eerste verdieping
Classification: 41.10 Uniformat (Uniformat); Material: <Unnamed>
Constraints - Level: 01 eerste verdieping; Schedule Level: 01 eerste verdieping; Elevation from Level: 815 mm; Offset from Host: 815 mm; Work Plane: Level : 01 eerste verdieping
Phasing - Phase Created: 2. nieuwbouw
Dimensions - verlenging_L: 0 mm; verlenging_R: 0 mm; Area: 13.329 m2; element_lengte: 13505.6 mm; hoek_L: 0 deg; hoek_R: 0 deg; lengte: 13505.6 mm; Volume: 0.119067 m3
Identity Data - Workset: Workset1
Other - Category: Generic Models; berekende_overstek_a: 0 mm; berekende_overstek_b: 0 mm; Family: NLRS_41_GM_muurafdekker_aluminium_gen_bdg; Berekende_hoek_a+180: 180 deg; Berekende_hoek_b: -180 deg; Berekende_hoek_b+180: 0 deg; berekende_verlenging_a: 2000 mm; berekende_verlenging_b: 2000 mm; Family and Type: NLRS_41_GM_muurafdekker_aluminium_gen_bdg: aluminium muurafdekker b450 muurb382; Type: aluminium muurafdekker b450 muurb382; Type Id: 1753986

# IfcRoof: NLRS_41_GM_muurafdekker_aluminium_gen_bdg:aluminium muurafdekker b475 muurb410 (3)
In: 02 tweede verdieping
Classification: 41.10 Uniformat (Uniformat); Material: <Unnamed>
Constraints - Level: 02 tweede verdieping; Schedule Level: 02 tweede verdieping; Elevation from Level: 643 mm; Offset from Host: 643 mm; Work Plane: Level : 02 tweede verdieping
Phasing - Phase Created: 2. nieuwbouw
Dimensions - verlenging_L: 0 mm; verlenging_R: 0 mm
Identity Data - Workset: Workset1
Other - Category: Generic Models; Family: NLRS_41_GM_muurafdekker_aluminium_gen_bdg; berekende_verlenging_a: 2000 mm; berekende_verlenging_b: 2000 mm; Family and Type: NLRS_41_GM_muurafdekker_aluminium_gen_bdg: aluminium muurafdekker b475 muurb410; Type: aluminium muurafdekker b475 muurb410; Type Id: 1924120
Constraints(Type) - Default Elevation: 0 mm; breedte_achter: 445 mm; breedte_voor: 30 mm
Dimensions(Type) - bk_multiplex_tov_bk_afdekker: -40 mm; breedte: 475 mm; dikte: 2 mm; helling: 2 deg; hoogte_aanzicht: 50 mm; multiplex_breedte: 410 mm; multiplex_dikte: 20 mm
Identity Data(Type) - Workset: Family : Generic Models : NLRS_41_GM_muurafdekker_aluminium_gen_bdg; Assembly Code: 41.10; Assembly Description: buitenwandafwerkingen; algemeen (verzamelniveau); Description: daktrim; Model: daktrim; Type Name: aluminium muurafdekker b475 muurb410
Other(Type) - Category: Generic Models; multiplex: yes; Family Name: NLRS_41_GM_muurafdekker_aluminium_gen_bdg
Name (NLRS_41_GM_muurafdekker_aluminium_gen_bdg:aluminium muurafdekker b475 muurb410:...) | hoek_R (deg) = Berekende_hoek_b+180 (deg) | hoek_L (deg) | Area (m2) | element_lengte (mm) | lengte (mm) | Volume (m3) | berekende_overstek_a (mm) | Berekende_hoek_b (deg) | Berekende_hoek_a+180 (deg) | berekende_overstek_b (mm)
1923927 | 45 | 0 | 21.9839 | 21378.4 | 21348.4 | 0.199296 | 0 | -135 | 180 | 30
1924297 | 0 | 45 | 4.47358 | 4530 | 4500 | 0.0404796 | 30 | -180 | 225 | 0
1924525 | 39.39 | 0 | 7.72321 | 7615.03 | 7590.4 | 0.0699569 | 0 | -140.61 | 180 | 24.6335

# IfcRoof: NLRS_41_GM_muurafdekker_aluminium_gen_bdg:aluminium muurafdekker b590 muurb530 (4)
Classification: 41.10 Uniformat (Uniformat); Material: <Unnamed>
Phasing - Phase Created: 2. nieuwbouw
Dimensions - verlenging_L: 0 mm; verlenging_R: 0 mm; hoek_L: 0 deg
Identity Data - Workset: Workset1
Other - Category: Generic Models; berekende_overstek_a: 0 mm; Family: NLRS_41_GM_muurafdekker_aluminium_gen_bdg; Berekende_hoek_a+180: 180 deg; berekende_verlenging_a: 2000 mm; berekende_verlenging_b: 2000 mm; Family and Type: NLRS_41_GM_muurafdekker_aluminium_gen_bdg: aluminium muurafdekker b590 muurb530; Type: aluminium muurafdekker b590 muurb530; Type Id: 1761608
Name (NLRS_41_GM_muurafdekker_aluminium_gen_bdg:aluminium muurafdekker b590 muurb530:...) | In | Level = Schedule Level | Elevation from Level (mm) | Offset from Host (mm) | Work Plane | hoek_R (deg) = Berekende_hoek_b+180 (deg) | Area (m2) | element_lengte (mm) | lengte (mm) | Volume (m3) | berekende_overstek_b (mm) | Berekende_hoek_b (deg)
1760751 | 00 begane grond | 00 begane grond | 2262.64 | 39.4872 | 41_GM_fb_rollaag_metselwerk_middel : h=419 | 0 | 3.78772 | 2962.8 | 2962.8 | 0.0357204 | 0 | -180
2549658 | 01 eerste verdieping | 01 eerste verdieping | 820 | 820 | Level : 01 eerste verdieping | -34.8 | 1.86155 | 1655.31 | 1266.1 | 0.0174873 | 389.21 | -214.8
2983871 | 00 begane grond |  | 0 | 65 | <not associated> | 0 | 0.967697 | 749.9 | 749.9 | 0.00904102 | 0 | -180
2984950 | 00 begane grond | 00 begane grond | 3977.15 | 39.4872 | <not associated> | 0 | 3.63021 | 2839.2 | 2839.2 | 0.0342302 | 0 | -180

# IfcRoof: NLRS_41_GM_muurafdekker_aluminium_rond_Bgen_bdg:aluminium afdekker_rond_b410-r2370 muurb 340, NLRS_41_GM_muurafdekker_aluminium_rond_Bgen_bdg:aluminium afdekker_rond_b410-r2370 muurb 340:2386465
In: 01 eerste verdieping
Classification: 41.10 Uniformat (Uniformat); Material: <Unnamed>
Constraints - Level: 01 eerste verdieping; Schedule Level: 01 eerste verdieping; Elevation from Level: 815 mm; Offset from Host: 815 mm; Work Plane: Level : 01 eerste verdieping
Phasing - Phase Created: 2. nieuwbouw
Dimensions - Area: 1.72681 m2; element_lengte: 2548.29 mm; hoek: 42.83 deg; Volume: 0.0149982 m3
Identity Data - Workset: Workset1
Other - Category: Generic Models; Family: NLRS_41_GM_muurafdekker_aluminium_rond_Bgen_bdg; Family and Type: NLRS_41_GM_muurafdekker_aluminium_rond_Bgen_bdg: aluminium afdekker_rond_b410-r2370 muurb 340; Type: aluminium afdekker_rond_b410-r2370 muurb 340; Type Id: 2384265
Constraints(Type) - Default Elevation: 0 mm; breedte_achter: 380 mm; breedte_voor: 30 mm
Dimensions(Type) - bk_multiplex_tov_bk_afdekker: -40 mm; breedte: 410 mm; dikte: 2 mm; helling: 2 deg; hoogte_aanzicht: 50 mm; multiplex_breedte: 340 mm; multiplex_dikte: 20 mm; straal: 2370 mm
Identity Data(Type) - Workset: Family : Generic Models : NLRS_41_GM_muurafdekker_aluminium_rond_Bgen_bdg; Assembly Code: 41.10; Assembly Description: buitenwandafwerkingen; algemeen (verzamelniveau); Description: aluminium muurafdekke; Type Name: aluminium afdekker_rond_b410-r2370 muurb 340
Other(Type) - Category: Generic Models; multiplex: yes; Family Name: NLRS_41_GM_muurafdekker_aluminium_rond_Bgen_bdg

# IfcRoof: NLRS_41_GM_muurafdekker_aluminium_rond_Bgen_bdg:aluminium afdekker_rond_b450-r2250 muurb 382, NLRS_41_GM_muurafdekker_aluminium_rond_Bgen_bdg:aluminium afdekker_rond_b450-r2250 muurb 382:2384422
In: 01 eerste verdieping
Classification: 41.10 Uniformat (Uniformat); Material: <Unnamed>
Constraints - Level: 01 eerste verdieping; Schedule Level: 01 eerste verdieping; Elevation from Level: 815 mm; Offset from Host: 815 mm; Work Plane: Level : 01 eerste verdieping
Phasing - Phase Created: 2. nieuwbouw
Dimensions - hoek: 45 deg; Area: 1.56055 m2; element_lengte: 2548.29 mm; Volume: 0.013861 m3
Identity Data - Workset: Workset1
Other - Category: Generic Models; Type: aluminium afdekker_rond_b450-r2250 muurb 382; Family: NLRS_41_GM_muurafdekker_aluminium_rond_Bgen_bdg; Family and Type: NLRS_41_GM_muurafdekker_aluminium_rond_Bgen_bdg: aluminium afdekker_rond_b450-r2250 muurb 382; Type Id: 2384269
Constraints(Type) - Default Elevation: 0 mm; breedte_achter: 420 mm; breedte_voor: 30 mm
Dimensions(Type) - bk_multiplex_tov_bk_afdekker: -40 mm; breedte: 450 mm; dikte: 2 mm; helling: 2 deg; hoogte_aanzicht: 50 mm; multiplex_breedte: 382 mm; multiplex_dikte: 20 mm; straal: 1810 mm
Identity Data(Type) - Assembly Code: 41.10; Assembly Description: buitenwandafwerkingen; algemeen (verzamelniveau); Description: aluminium muurafdekke; Type Name: aluminium afdekker_rond_b450-r2250 muurb 382; Workset: Family : Generic Models : NLRS_41_GM_muurafdekker_aluminium_rond_Bgen_bdg
Other(Type) - Category: Generic Models; multiplex: yes; Family Name: NLRS_41_GM_muurafdekker_aluminium_rond_Bgen_bdg

# IfcRoof: NLRS_41_GM_muurafdekker_aluminium_rond_gen_bdg:aluminium afdekker_rond_b410-r1080 muurb 340, NLRS_41_GM_muurafdekker_aluminium_rond_gen_bdg:aluminium afdekker_rond_b410-r1080 muurb 340:2096505
In: 01 eerste verdieping
Classification: 41.10 Uniformat (Uniformat); Material: <Unnamed>
Constraints - Level: 01 eerste verdieping; Schedule Level: 01 eerste verdieping; Elevation from Level: 815 mm; Offset from Host: 815 mm; Work Plane: Level : 01 eerste verdieping
Phasing - Phase Created: 2. nieuwbouw
Dimensions - hoek: 90 deg; Area: 1.29613 m2; element_lengte: 2548.29 mm; Volume: 0.0112745 m3
Identity Data - Workset: Workset1
Other - Category: Generic Models; Family: NLRS_41_GM_muurafdekker_aluminium_rond_gen_bdg; Family and Type: NLRS_41_GM_muurafdekker_aluminium_rond_gen_bdg: aluminium afdekker_rond_b410-r1080 muurb 340; Type: aluminium afdekker_rond_b410-r1080 muurb 340; Type Id: 2096585
Constraints(Type) - Default Elevation: 0 mm; breedte_achter: 380 mm; breedte_voor: 30 mm
Dimensions(Type) - bk_multiplex_tov_bk_afdekker: -40 mm; breedte: 410 mm; dikte: 2 mm; helling: 2 deg; hoogte_aanzicht: 50 mm; multiplex_breedte: 340 mm; multiplex_dikte: 20 mm; straal: 1080 mm
Identity Data(Type) - Workset: Family : Generic Models : NLRS_41_GM_muurafdekker_aluminium_rond_gen_bdg; Assembly Code: 41.10; Assembly Description: buitenwandafwerkingen; algemeen (verzamelniveau); Description: aluminium muurafdekke; Type Name: aluminium afdekker_rond_b410-r1080 muurb 340
Other(Type) - Category: Generic Models; multiplex: yes; Family Name: NLRS_41_GM_muurafdekker_aluminium_rond_gen_bdg

# IfcRoof: NLRS_41_GM_muurafdekker_aluminium_rond_gen_bdg:aluminium afdekker_rond_b410-r2130 muurb 340, NLRS_41_GM_muurafdekker_aluminium_rond_gen_bdg:aluminium afdekker_rond_b410-r2130 muurb 340:2096507
In: 01 eerste verdieping
Classification: 41.10 Uniformat (Uniformat); Material: <Unnamed>
Constraints - Level: 01 eerste verdieping; Schedule Level: 01 eerste verdieping; Elevation from Level: 815 mm; Offset from Host: 815 mm; Work Plane: Level : 01 eerste verdieping
Phasing - Phase Created: 2. nieuwbouw
Dimensions - Area: 1.33073 m2; element_lengte: 2548.29 mm; hoek: 42.83 deg; Volume: 0.0115632 m3
Identity Data - Workset: Workset1
Other - Category: Generic Models; Family: NLRS_41_GM_muurafdekker_aluminium_rond_gen_bdg; Family and Type: NLRS_41_GM_muurafdekker_aluminium_rond_gen_bdg: aluminium afdekker_rond_b410-r2130 muurb 340; Type: aluminium afdekker_rond_b410-r2130 muurb 340; Type Id: 2096903
Constraints(Type) - Default Elevation: 0 mm; breedte_achter: 380 mm; breedte_voor: 30 mm
Dimensions(Type) - bk_multiplex_tov_bk_afdekker: -40 mm; breedte: 410 mm; dikte: 2 mm; helling: 2 deg; hoogte_aanzicht: 50 mm; multiplex_breedte: 340 mm; multiplex_dikte: 20 mm; straal: 2130 mm
Identity Data(Type) - Workset: Family : Generic Models : NLRS_41_GM_muurafdekker_aluminium_rond_gen_bdg; Assembly Code: 41.10; Assembly Description: buitenwandafwerkingen; algemeen (verzamelniveau); Description: aluminium muurafdekke; Type Name: aluminium afdekker_rond_b410-r2130 muurb 340
Other(Type) - Category: Generic Models; multiplex: yes; Family Name: NLRS_41_GM_muurafdekker_aluminium_rond_gen_bdg

# IfcRoof: NLRS_41_GM_muurafdekker_aluminium_rond_gen_bdg:aluminium afdekker_rond_b450-r1200 muurb 382, NLRS_41_GM_muurafdekker_aluminium_rond_gen_bdg:aluminium afdekker_rond_b450-r1200 muurb 382:1753724
In: 01 eerste verdieping
Classification: 41.10 Uniformat (Uniformat); Material: <Unnamed>
Constraints - Level: 01 eerste verdieping; Schedule Level: 01 eerste verdieping; Elevation from Level: 815 mm; Offset from Host: 815 mm; Work Plane: Level : 01 eerste verdieping
Phasing - Phase Created: 2. nieuwbouw
Dimensions - Area: 1.56665 m2; element_lengte: 2548.29 mm; hoek: 90 deg; Volume: 0.0139509 m3
Identity Data - Workset: Workset1
Other - Category: Generic Models; Family: NLRS_41_GM_muurafdekker_aluminium_rond_gen_bdg; Family and Type: NLRS_41_GM_muurafdekker_aluminium_rond_gen_bdg: aluminium afdekker_rond_b450-r1200 muurb 382; Type: aluminium afdekker_rond_b450-r1200 muurb 382; Type Id: 1749885
Constraints(Type) - Default Elevation: 0 mm; breedte_achter: 420 mm; breedte_voor: 30 mm
Dimensions(Type) - bk_multiplex_tov_bk_afdekker: -40 mm; breedte: 450 mm; dikte: 2 mm; helling: 2 deg; hoogte_aanzicht: 50 mm; multiplex_breedte: 382 mm; multiplex_dikte: 20 mm; straal: 1200 mm
Identity Data(Type) - Assembly Code: 41.10; Assembly Description: buitenwandafwerkingen; algemeen (verzamelniveau); Description: aluminium muurafdekke; Type Name: aluminium afdekker_rond_b450-r1200 muurb 382; Workset: Family : Generic Models : NLRS_41_GM_muurafdekker_aluminium_rond_gen_bdg
Other(Type) - Category: Generic Models; multiplex: yes; Family Name: NLRS_41_GM_muurafdekker_aluminium_rond_gen_bdg

# IfcRoof: NLRS_41_GM_muurafdekker_aluminium_rond_gen_bdg:aluminium afdekker_rond_b450-r2250 muurb 382, NLRS_41_GM_muurafdekker_aluminium_rond_gen_bdg:aluminium afdekker_rond_b450-r2250 muurb 382:1754517
In: 01 eerste verdieping
Classification: 41.10 Uniformat (Uniformat); Material: <Unnamed>
Constraints - Level: 01 eerste verdieping; Schedule Level: 01 eerste verdieping; Elevation from Level: 815 mm; Offset from Host: 815 mm; Work Plane: Level : 01 eerste verdieping
Phasing - Phase Created: 2. nieuwbouw
Dimensions - Area: 1.60178 m2; element_lengte: 2548.29 mm; hoek: 45 deg; Volume: 0.0142512 m3
Identity Data - Workset: Workset1
Other - Category: Generic Models; Family: NLRS_41_GM_muurafdekker_aluminium_rond_gen_bdg; Family and Type: NLRS_41_GM_muurafdekker_aluminium_rond_gen_bdg: aluminium afdekker_rond_b450-r2250 muurb 382; Type: aluminium afdekker_rond_b450-r2250 muurb 382; Type Id: 1754564
Constraints(Type) - Default Elevation: 0 mm; breedte_achter: 420 mm; breedte_voor: 30 mm
Dimensions(Type) - bk_multiplex_tov_bk_afdekker: -40 mm; breedte: 450 mm; dikte: 2 mm; helling: 2 deg; hoogte_aanzicht: 50 mm; multiplex_breedte: 382 mm; multiplex_dikte: 20 mm; straal: 2250 mm
Identity Data(Type) - Workset: Family : Generic Models : NLRS_41_GM_muurafdekker_aluminium_rond_gen_bdg; Assembly Code: 41.10; Assembly Description: buitenwandafwerkingen; algemeen (verzamelniveau); Description: aluminium muurafdekke; Type Name: aluminium afdekker_rond_b450-r2250 muurb 382
Other(Type) - Category: Generic Models; multiplex: yes; Family Name: NLRS_41_GM_muurafdekker_aluminium_rond_gen_bdg

# IfcRoof: NLRS_42_GM_houten_regel_gen_bdg:houten afdekker 32x139 (10)
In: 01 eerste verdieping
Classification: 41.10 Uniformat (Uniformat); Material: i4_hout_Eiken_gen
Constraints - Offset from Host: 0 mm; Level: 01 eerste verdieping; Schedule Level: 01 eerste verdieping
Phasing - Phase Created: 2. nieuwbouw
Dimensions - verlenging_L: 0 mm; verlenging_R: 0 mm
Identity Data - Workset: Workset1
Other - Category: Generic Models; berekende_overstek_a: 200 mm; berekende_overstek_b: 200 mm; berekende_verlenging_a: 2000 mm; berekende_verlenging_b: 2000 mm; Family: NLRS_42_GM_houten_regel_gen_bdg; Family and Type: NLRS_42_GM_houten_regel_gen_bdg: houten afdekker 32x139; Type: houten afdekker 32x139; Type Id: 3148215
Name (NLRS_42_GM_houten_regel_gen_bdg:houten afdekker 32x139:...) | Elevation from Level (mm) | Work Plane | hoek_L (deg) | hoek_R (deg) = Berekende_hoek_b+180 (deg) | Area (m2) | element_lengte (mm) | lengte (mm) | Volume (m3) | Berekende_hoek_a+180 (deg) | Berekende_hoek_b (deg)
3148216 | 1050 | Basic Wall : 22_WA_binnenwand_ms125 25-75-25 _gen_bdg | 0 | 0 | 0.754374 | 4785.53 | 4385.53 | 0.0195069 | 180 | -180
3150707 | 1050 | Basic Wall : 22_WA_binnenwand_ms125 25-75-25 _gen_bdg | 0 | 0 | 0.692415 | 4423.2 | 4023.2 | 0.0178952 | 180 | -180
3151951 | 2949.98 | Basic Wall : 22_WA_binnenwand_ms125 25-75-25 _Rigitone_gen_bdg 2 | 0 | 0 | 1.08361 | 6710.9 | 6310.9 | 0.0280709 | 180 | -180
3151955 | 4850 | Basic Wall : 22_WA_binnenwand_ms125 25-75-25 _gen_bdg | -45 | -45 | 0.789128 | 4853 | 4453 | 0.0203629 | 135 | -225
3151957 | 4850 | Basic Wall : 22_WA_binnenwand_ms125 25-75-25 _gen_bdg | 0 | 0 | 0.271304 | 1960.56 | 1560.56 | 0.00694138 | 180 | -180
3151961 | 2964.64 | <not associated> | 0 | 0 | 1.07531 | 6662.34 | 6262.34 | 0.0278549 | 180 | -180
3151965 | 4850 | <not associated> | -45 | -45 | 0.112396 | 895.5 | 495.5 | 0.00275998 | 135 | -225
3151969 | 4850 | <not associated> | 0 | -45 | 0.0377445 | 526.829 | 126.829 | 0.000842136 | 180 | -225
3151984 | 4850 | <not associated> | -45 | -45 | 0.834443 | 5118 | 4718 | 0.0215417 | 135 | -225
3151986 | 4850 | <not associated> | -45 | 0 | 1.02598 | 6306 | 5906 | 0.0265479 | 135 | -180

# IfcRoof: NLRS_47_GM_muurafdekker_gen_bdg:daktrim (4)
In: 01 eerste verdieping
Classification: 47.10 Uniformat (Uniformat); Material: <Unnamed>; Group: Model Group:fietsenstalling:4188142
Constraints - Level: 01 eerste verdieping; Schedule Level: 01 eerste verdieping; Work Plane: Reference Plane : dak fietsenstalling
Phasing - Phase Created: 2. nieuwbouw
Dimensions - hoek_L: 45 deg; hoek_R: 45 deg; verlenging_L: 0 mm; verlenging_R: 0 mm
Identity Data - Workset: BDG_fietsenstalling
Other - Category: Generic Models; Berekende_hoek_a+180: 225 deg; Berekende_hoek_b: -135 deg; Berekende_hoek_b+180: 45 deg; berekende_overstek_a: 30 mm; berekende_overstek_b: 30 mm; berekende_verlenging_a: 2000 mm; berekende_verlenging_b: 2000 mm; Family: NLRS_47_GM_muurafdekker_gen_bdg; Family and Type: NLRS_47_GM_muurafdekker_gen_bdg: daktrim; Type: daktrim; Type Id: 4123889
Constraints(Type) - Default Elevation: 0 mm; breedte_achter: 150 mm; breedte_voor: 30 mm
Dimensions(Type) - beplating_breedte: 105 mm; beplating_dikte: 15 mm; beplating_offset: -25 mm; breedte: 180 mm; dikte: 2 mm; helling: 2 deg; hoogte_aanzicht: 40 mm
Identity Data(Type) - Assembly Code: 47.10; Assembly Description: dakafwerkingen; afwerkingen, algemeen (verzamelniveau); Description: daktrim; Model: daktrim; Type Name: daktrim; Workset: Family : Generic Models : NLRS_47_GM_muurafdekker_gen_bdg
Other(Type) - Category: Generic Models; beplating: no; Family Name: NLRS_47_GM_muurafdekker_gen_bdg
Name (NLRS_47_GM_muurafdekker_gen_bdg:daktrim:...) | Elevation from Level (mm) | Offset from Host (mm) | Area (m2) | element_lengte (mm) | lengte (mm) | Volume (m3)
4126320 | -1683.54 | 458.234 | 1.12938 | 3519 | 3459 | 0.00112564
4135390 | -1683.12 | 458.67 | 1.12938 | 3519 | 3459 | 0.00112564
4135513 | -1532.39 | 458.66 | 4.96646 | 14399.8 | 14339.8 | 0.00495184
4135643 | -1833.87 | 458.66 | 4.96646 | 14399.8 | 14339.8 | 0.00495184

# IfcSlab: Basic Roof:NLRS_27_RO_EPS drukvaste isolatie + dakbedekking 230-3-3_gen_bdg (4)
In: 01 eerste verdieping
Type - PredefinedType: ROOF
Type - Analytical Properties - Roughness: 1; Absorptance: 0.1; Heat Transfer Coefficient (U): 833333 kg/K/s3; Thermal Mass: 11.7432; Thermal Resistance (R): 0.0000012
Type - Graphics - Coarse Scale Fill Pattern: <Solid fill>; Coarse Scale Fill Color: 8421504
Type - Construction - Default Thickness: 236 mm
Type - Identity Data - Workset: Roof Types; Assembly Code: 27.11; Assembly Description: daken; niet constructief, vlakke daken; Description: PIR afschotisolatie + dakbedekking; SmartRevit_Versie: 2017.3; Type Name: NLRS_27_RO_EPS drukvaste isolatie + dakbedekking 230-3-3_gen_bdg
Type - Other - Category: Roofs; Family Name: Basic Roof
Classification: 27.11 Uniformat (Uniformat); Material: s9_bitumen 3 mm, s9_bitumen 3 mm, n7_isolatie_gen 230 mm
Name (Basic Roof:NLRS_27_RO_EPS drukvaste isolatie + dakbedekking 230-3-3_gen_bdg:...)
3212181
3212710
3213010
3958213

# IfcSlab: Basic Roof:NLRS_27_RO_PIR dakisolatie 100_gen_bdg (3)
Type - PredefinedType: ROOF
Type - Analytical Properties - Roughness: 1; Absorptance: 0.1
Type - Graphics - Coarse Scale Fill Pattern: <Solid fill>; Coarse Scale Fill Color: 8421504
Type - Construction - Default Thickness: 100 mm
Type - Identity Data - Workset: Roof Types; Assembly Code: 27.11; Assembly Description: daken; niet constructief, vlakke daken; Description: PIR afschotisolatie + dakbedekking; SmartRevit_Versie: 2017.3; Type Name: NLRS_27_RO_PIR dakisolatie 100_gen_bdg
Type - Other - Category: Roofs; Family Name: Basic Roof
Classification: 27.11 Uniformat (Uniformat); Material: n7_dakisolatie_gen 100 mm
Name (Basic Roof:NLRS_27_RO_PIR dakisolatie 100_gen_bdg:...) | In
1301771 | 01 eerste verdieping
2006157 | 01 eerste verdieping
3345975 | 00 begane grond

# IfcSlab: Basic Roof:NLRS_27_RO_SAB 100R/825, Basic Roof:NLRS_27_RO_SAB 100R/825:4130970
In: 00 begane grond
Type - PredefinedType: ROOF
Type - Analytical Properties - Roughness: 1; Absorptance: 0.1; Heat Transfer Coefficient (U): 450 kg/K/s3; Thermal Mass: 376.8; Thermal Resistance (R): 0.00222222
Type - Graphics - Coarse Scale Fill Pattern: <Solid fill>; Coarse Scale Fill Color: 8421504
Type - Construction - Default Thickness: 100 mm
Type - Identity Data - Workset: Roof Types; Assembly Code: 27.11; Assembly Description: daken; niet constructief, vlakke daken; Description: Trapeziumplaat; SmartRevit_Versie: 2017.3; Type Name: NLRS_27_RO_SAB 100R/825
Type - Other - Category: Roofs; Family Name: Basic Roof
Classification: 27.11 Uniformat (Uniformat); Material: h2_staal 100 mm; Group: Model Group:fietsenstalling:4188142

# IfcSlab: Basic Roof:NLRS_27_RO_Unidek Aero 6.3 + bitumen 3+3+215_gen_bdg 2 (4)
In: 03 derde verdieping
Type - PredefinedType: ROOF
Type - Analytical Properties - Roughness: 1; Absorptance: 0.1; Heat Transfer Coefficient (U): 833333 kg/K/s3; Thermal Mass: 11.7432; Thermal Resistance (R): 0.0000012
Type - Graphics - Coarse Scale Fill Pattern: <Solid fill>; Coarse Scale Fill Color: 8421504
Type - Construction - Default Thickness: 282 mm
Type - Identity Data - Workset: Roof Types; Assembly Code: 27.11; Assembly Description: daken; niet constructief, vlakke daken; Description: PIR afschotisolatie + dakbedekking; SmartRevit_Versie: 2017.3; Type Name: NLRS_27_RO_Unidek Aero 6.3 + bitumen 3+3+215_gen_bdg 2
Type - Other - Category: Roofs; Family Name: Basic Roof
Classification: 27.11 Uniformat (Uniformat); Material: s9_bitumen 3 mm, s9_bitumen 3 mm, multiplex_horizontaal 18 mm, n7_dakisolatie_gen 246 mm, multiplex_horizontaal 12 mm
Name (Basic Roof:NLRS_27_RO_Unidek Aero 6.3 + bitumen 3+3+215_gen_bdg 2:...) | Group
2182219 | Model Group:daklicht A1:2182252
2182274 | Model Group:daklicht A1 (members excluded):2182288
2182296 | Model Group:BU-42 daklicht B lokaal:2182308
2194770 | Model Group:BU-42 daklicht B lokaal:2194782

# IfcSlab: Basic Roof:NLRS_27_RO_daktegels 500x500x50_gen_bdg (2)
Type - PredefinedType: ROOF
Type - Analytical Properties - Roughness: 1; Absorptance: 0.1
Type - Graphics - Coarse Scale Fill Pattern: <Solid fill>; Coarse Scale Fill Color: 8421504
Type - Construction - Default Thickness: 50 mm
Type - Identity Data - Workset: Roof Types; Assembly Code: 27.11; Assembly Description: daken; niet constructief, vlakke daken; Description: PIR afschotisolatie + dakbedekking; SmartRevit_Versie: 2017.3; Type Name: NLRS_27_RO_daktegels 500x500x50_gen_bdg
Type - Other - Category: Roofs; Family Name: Basic Roof
Classification: 27.11 Uniformat (Uniformat); Material: g3_tegels_grijs_500x500 50 mm
Name (Basic Roof:NLRS_27_RO_daktegels 500x500x50_gen_bdg:...) | In
1303146 | 02 tweede verdieping
2548296 | 01 eerste verdieping

# IfcSlab: Basic Roof:NLRS_27_RO_trapeziumplaat, Basic Roof:NLRS_27_RO_trapeziumplaat:4022684
In: 00 begane grond
Type - PredefinedType: ROOF
Type - Analytical Properties - Roughness: 1; Absorptance: 0.1; Heat Transfer Coefficient (U): 1666667 kg/K/s3; Thermal Mass: 5.8716; Thermal Resistance (R): 6e-07
Type - Graphics - Coarse Scale Fill Pattern: <Solid fill>; Coarse Scale Fill Color: 8421504
Type - Construction - Default Thickness: 100 mm
Type - Identity Data - Workset: Roof Types; Assembly Code: 27.11; Assembly Description: daken; niet constructief, vlakke daken; Description: PIR afschotisolatie + dakbedekking; SmartRevit_Versie: 2017.3; Type Name: NLRS_27_RO_trapeziumplaat
Type - Other - Category: Roofs; Family Name: Basic Roof
Classification: 27.11 Uniformat (Uniformat); Material: a_begroeiing 50 mm, s9_bitumen 3 mm, ISR_Luchtspouw 17 mm, Tr_21_isolatie_hoogwaardig 30 mm; Group: Model Group:fietsenstalling:4188142

# IfcSlab: Floor:23_FL_isolatie_110-110mm (2)
In: 01 eerste verdieping
Type - PredefinedType: FLOOR; Material: ISR_Isolatie PS 110 mm, ISR_Isolatie PS 110 mm
Type - Analytical Properties - Roughness: 1; Absorptance: 0.1
Type - Graphics - Coarse Scale Fill Pattern: <Solid fill>; Coarse Scale Fill Color: 12632256
Type - Construction - Function: Interior; Default Thickness: 220 mm
Type - Identity Data - Workset: Floor Types; Assembly Code: 2F(43); Datum_Gewijzigd: 26-05-2014; Description: Isolatie 150mm +2 mm dakbedekking; Model: LOD300; SmartRevit_Versie: 2015.1; Type Name: 23_FL_isolatie_110-110mm
Type - Other - Category: Floors; Family Name: Floor
Classification: 2F(43) Uniformat (Uniformat)
Slab Shape Edit - Curved Edge Condition: 0
Constraints - Related to Mass: no; Room Bounding: yes
Phasing - Phase Created: 2. nieuwbouw
Structural - Enable Analytical Model: no; Structural: no
Dimensions - Thickness: 220 mm
Identity Data - Workset: Workset1; Comments: schraaprooster
Other - Family: Floor; Family and Type: Floor: 23_FL_isolatie_110-110mm; Type: 23_FL_isolatie_110-110mm; Type Id: 3357413
Name (Floor:23_FL_isolatie_110-110mm:...) | Level | Height Offset From Level (mm) | Area (m2) | Elevation at Bottom (mm) | Elevation at Top (mm) | Perimeter (mm) | Volume (m3)
3357411 | 01 eerste verdieping | -386 | 6.7626 | 3394 | 3614 | 11114 | 1.48777
3637441 | 02 ok. ruwe vloer | 0 | 8.8425 | 7210 | 7430 | 11950 | 1.94535

# IfcSlab: Floor:23_FL_isolatie_150mm, Floor:23_FL_isolatie_150mm:5094558
In: 00 begane grond
Type - PredefinedType: FLOOR; Material: ISR_Isolatie 150 mm
Type - Analytical Properties - Roughness: 1; Absorptance: 0.1
Type - Materials and Finishes - Structural Material: ISR_Isolatie
Type - Graphics - Coarse Scale Fill Pattern: <Solid fill>; Coarse Scale Fill Color: 12632256
Type - Construction - Function: Interior; Default Thickness: 150 mm
Type - Identity Data - Workset: Floor Types; Assembly Code: 43.10; Assembly Description: vloerafwerkingen; verhoogd, algemeen (verzamelniveau); Datum_Gewijzigd: 26-05-2014; Description: Isolatie 150mm; Model: LOD300; SmartRevit_Versie: 2015.1; Type Name: 23_FL_isolatie_150mm
Type - Other - Category: Floors; Family Name: Floor
Classification: 43.10 Uniformat (Uniformat)
Constraints - Level: 00 begane grond; Related to Mass: no; Room Bounding: yes; Height Offset From Level: -520 mm
Phasing - Phase Created: 2. nieuwbouw
Structural - Enable Analytical Model: no; Structural: no
Dimensions - Area: 1.957 m2; Elevation at Bottom: -670 mm; Elevation at Top: -520 mm; Perimeter: 11060 mm; Thickness: 150 mm; Volume: 0.29355 m3
Identity Data - Workset: Workset1; Comments: schraaprooster
Other - Family: Floor; Family and Type: Floor: 23_FL_isolatie_150mm; Type: 23_FL_isolatie_150mm; Type Id: 5094616

# IfcSlab: Floor:27_FL_multiplex+essen_20+22_eindvlak trap 3, Floor:27_FL_multiplex+essen_20+22_eindvlak trap 3:4878523
In: 01 eerste verdieping
Type - PredefinedType: FLOOR; Material: ISR_Hout 22 mm, multiplex_horizontaal 20 mm
Type - Analytical Properties - Roughness: 1; Absorptance: 0.1
Type - Materials and Finishes - Structural Material: multiplex_horizontaal
Type - Graphics - Coarse Scale Fill Color: 0
Type - Construction - Function: Interior; Default Thickness: 42 mm
Type - Identity Data - Workset: Floor Types; Assembly Code: 2F(43.21.11); Datum_Gewijzigd: 26-05-2014; Description: Sportvloer 11 + dekvloer 50; Model: LOD300; SmartRevit_Versie: 2015.1; Type Name: 27_FL_multiplex+essen_20+22_eindvlak trap 3
Type - Other - Category: Floors; Family Name: Floor
Classification: 2F(43.21.11) Uniformat (Uniformat)
Constraints - Related to Mass: no; Room Bounding: yes; Level: 01 eerste verdieping; Height Offset From Level: 0 mm
Phasing - Phase Created: 2. nieuwbouw
Structural - Enable Analytical Model: no; Structural: no
Dimensions - Area: 0.9125 m2; Elevation at Bottom: 3958 mm; Elevation at Top: 4000 mm; Perimeter: 4380 mm; Thickness: 42 mm; Volume: 0.038325 m3
Identity Data - Workset: Workset1; Comments: schraaprooster
Other - Family: Floor; Family and Type: Floor: 27_FL_multiplex+essen_20+22_eindvlak trap 3; Type: 27_FL_multiplex+essen_20+22_eindvlak trap 3; Type Id: 4878525

# IfcSlab: Floor:43_FL_brandwerende beplating_15 (8)
Type - PredefinedType: FLOOR; Material: ISR_brandwerende beplating 15 mm
Type - Analytical Properties - Roughness: 1; Absorptance: 0.1
Type - Graphics - Coarse Scale Fill Pattern: <Solid fill>; Coarse Scale Fill Color: 12632256
Type - Construction - Function: Interior; Default Thickness: 15 mm
Type - Identity Data - Workset: Floor Types; Assembly Code: 2F(43); Datum_Gewijzigd: 26-05-2014; Description: afwerkvloer 50mm; Model: LOD200; SmartRevit_Versie: 2015.1; Type Name: 43_FL_brandwerende beplating_15
Type - Other - Category: Floors; Family Name: Floor
Classification: 2F(43) Uniformat (Uniformat)
Constraints - Related to Mass: no; Room Bounding: yes
Phasing - Phase Created: 2. nieuwbouw
Structural - Enable Analytical Model: no; Structural: no
Dimensions - Thickness: 15 mm
Identity Data - Workset: Workset1; Comments: schraaprooster
Other - Family: Floor; Family and Type: Floor: 43_FL_brandwerende beplating_15; Type: 43_FL_brandwerende beplating_15; Type Id: 4901577
Name (Floor:43_FL_brandwerende beplating_15:...) | In | Level | Height Offset From Level (mm) | Area (m2) | Elevation at Bottom (mm) | Elevation at Top (mm) | Perimeter (mm) | Volume (m3)
4901575 | 01 eerste verdieping | 02 ok. ruwe vloer | -260 | 6.26583 | 7155 | 7170 | 48718.7 | 0.0939874
4901828 | 01 eerste verdieping | 02 ok. ruwe vloer | -340 | 7.23 | 7075 | 7090 | 48800 | 0.10845
4902560 | 01 eerste verdieping | 02 ok. ruwe vloer | -310 | 17.376 | 7105 | 7120 | 117040 | 0.26064
4902560:2 | 01 eerste verdieping | 02 ok. ruwe vloer | -310 | 17.376 | 7105 | 7120 | 117040 | 0.26064
4906277 | 02 tweede verdieping | 03 ok. ruwe vloer | -190 | 4.832 | 11095 | 11110 | 48720 | 0.07248
4906491 | 02 tweede verdieping | 03 ok. ruwe vloer | -190 | 4.83198 | 11095 | 11110 | 48719.8 | 0.0724798
4906860 | 02 tweede verdieping | 03 ok. ruwe vloer | -230 | 11.9232 | 11055 | 11070 | 100320 | 0.178848
4906860:2 | 02 tweede verdieping | 03 ok. ruwe vloer | -230 | 11.9232 | 11055 | 11070 | 100320 | 0.178848

# IfcSlab: Floor:43_FL_multiplex_18 (2)
Type - PredefinedType: FLOOR; Material: i4_multiplex 18 mm
Type - Analytical Properties - Roughness: 1; Absorptance: 0.1
Type - Graphics - Coarse Scale Fill Pattern: <Solid fill>; Coarse Scale Fill Color: 12632256
Type - Construction - Function: Interior; Default Thickness: 18 mm
Type - Identity Data - Workset: Floor Types; Assembly Code: 2F(43); Datum_Gewijzigd: 26-05-2014; Description: afwerkvloer 50mm; Model: LOD200; SmartRevit_Versie: 2015.1; Type Name: 43_FL_multiplex_18
Type - Other - Category: Floors; Family Name: Floor
Classification: 2F(43) Uniformat (Uniformat)
Constraints - Related to Mass: no; Room Bounding: yes; Height Offset From Level: -50 mm
Phasing - Phase Created: 2. nieuwbouw
Structural - Enable Analytical Model: no; Structural: no
Dimensions - Thickness: 18 mm
Identity Data - Workset: Workset1
Other - Family: Floor; Family and Type: Floor: 43_FL_multiplex_18; Type: 43_FL_multiplex_18; Type Id: 1763205
Name (Floor:43_FL_multiplex_18:...) | In | Level | Area (m2) | Elevation at Bottom (mm) | Elevation at Top (mm) | Perimeter (mm) | Volume (m3)
2195661 | 03 derde verdieping | 03 derde verdieping | 4.27256 | 11532 | 11550 | 14410 | 0.076906
5096346 | 01 eerste verdieping | 01 eerste verdieping | 2.4384 | 3932 | 3950 | 11120 | 0.0438912 | Identity Data - Comments: schraaprooster

# IfcSlab: Floor:43_FL_multiplex_40 (3)
Type - PredefinedType: FLOOR; Material: i4_multiplex 40 mm
Type - Analytical Properties - Roughness: 1; Absorptance: 0.1
Type - Graphics - Coarse Scale Fill Pattern: <Solid fill>; Coarse Scale Fill Color: 12632256
Type - Construction - Function: Interior; Default Thickness: 40 mm
Type - Identity Data - Workset: Floor Types; Assembly Code: 2F(43); Datum_Gewijzigd: 26-05-2014; Description: afwerkvloer 50mm; Model: LOD200; SmartRevit_Versie: 2015.1; Type Name: 43_FL_multiplex_40
Type - Other - Category: Floors; Family Name: Floor
Classification: 2F(43) Uniformat (Uniformat)
Constraints - Related to Mass: no; Room Bounding: yes
Phasing - Phase Created: 2. nieuwbouw
Structural - Enable Analytical Model: no; Structural: no
Dimensions - Thickness: 40 mm
Identity Data - Workset: Workset1
Other - Family: Floor; Family and Type: Floor: 43_FL_multiplex_40; Type: 43_FL_multiplex_40; Type Id: 3215316
Name (Floor:43_FL_multiplex_40:...) | In | Level | Height Offset From Level (mm) | Area (m2) | Elevation at Bottom (mm) | Elevation at Top (mm) | Perimeter (mm) | Volume (m3)
1763204 | 00 begane grond | 00 begane grond | 400 | 0.6345 | 360 | 400 | 3720 | 0.02538
2081769 | 01 eerste verdieping | 01 eerste verdieping | 265 | 5.55212 | 4225 | 4265 | 9546 | 0.222085
3462856 | 00 begane grond | 00 begane grond | 1770 | 0.6345 | 1730 | 1770 | 3720 | 0.02538

# IfcSlab: Floor:43_FL_schoonloopmat_5 (8)
Type - PredefinedType: FLOOR; Material: ISR_Vloer_afwerking_schoonloop 5 mm
Type - Analytical Properties - Roughness: 1; Absorptance: 0.1
Type - Graphics - Coarse Scale Fill Pattern: <Solid fill>; Coarse Scale Fill Color: 12632256
Type - Construction - Function: Interior; Default Thickness: 5 mm
Type - Identity Data - Workset: Floor Types; Assembly Code: 2F(43); Datum_Gewijzigd: 26-05-2014; Description: afwerkvloer 50mm; Model: LOD200; SmartRevit_Versie: 2015.1; Type Name: 43_FL_schoonloopmat_5
Type - Other - Category: Floors; Family Name: Floor
Classification: 2F(43) Uniformat (Uniformat)
Constraints - Related to Mass: no; Room Bounding: yes
Phasing - Phase Created: 2. nieuwbouw
Structural - Enable Analytical Model: no; Structural: no
Dimensions - Thickness: 5 mm
Identity Data - Workset: Workset1
Other - Family: Floor; Family and Type: Floor: 43_FL_schoonloopmat_5; Type: 43_FL_schoonloopmat_5; Type Id: 2231908
Name (Floor:43_FL_schoonloopmat_5:...) | In | Level | Height Offset From Level (mm) | Area (m2) | Elevation at Bottom (mm) | Elevation at Top (mm) | Perimeter (mm) | Volume (m3)
2231907 | 00 begane grond | 00 begane grond | 5 | 3.83845 | 0 | 5 | 7934 | 0.0191922
2231920 | 00 begane grond | 00 begane grond | 5 | 12.484 | 0 | 5 | 16581 | 0.0624198
2231929 | 00 begane grond | 00 begane grond | 5 | 11.3434 | 0 | 5 | 14286 | 0.0567169
2231940 | 00 begane grond | 00 begane grond | 5 | 5.74659 | 0 | 5 | 11633 | 0.0287329
2231950 | 01 eerste verdieping | 01 eerste verdieping | 270 | 5.74578 | 4265 | 4270 | 9798 | 0.0287289
2231963 | 02 tweede verdieping | 02 tweede verdieping | 5 | 3.2625 | 7800 | 7805 | 8050 | 0.0163125
3522872 | 02 tweede verdieping | 02 tweede verdieping | 144 | 1.2125 | 7939 | 7944 | 10200 | 0.0060625 | Identity Data - Comments: schraaprooster
3522903 | 02 tweede verdieping | 02 tweede verdieping | 283 | 2.70432 | 8078 | 8083 | 7053.6 | 0.0135216 | Identity Data - Comments: schraaprooster

# IfcSlab: Floor:43_FL_sportvloer+cementdekvloer_11+50 - opbouw 5, Floor:43_FL_sportvloer+cementdekvloer_11+50 - opbouw 5:3178255
In: 00 begane grond
Type - PredefinedType: FLOOR; Material: ISR_Vloer_afwerking 11 mm, q2_cementdekvloer 49 mm
Type - Analytical Properties - Roughness: 1; Absorptance: 0.1
Type - Materials and Finishes - Structural Material: q2_cementdekvloer
Type - Graphics - Coarse Scale Fill Color: 0
Type - Construction - Function: Interior; Default Thickness: 60 mm
Type - Identity Data - Workset: Floor Types; Assembly Code: 2F(43.21.11); Datum_Gewijzigd: 26-05-2014; Description: Sportvloer 11 + dekvloer 50; Model: LOD300; SmartRevit_Versie: 2015.1; Type Name: 43_FL_sportvloer+cementdekvloer_11+50 - opbouw 5
Type - Other - Category: Floors; Family Name: Floor
Classification: 2F(43.21.11) Uniformat (Uniformat)
Constraints - Level: 00 begane grond; Related to Mass: no; Room Bounding: yes; Height Offset From Level: 0 mm
Phasing - Phase Created: 2. nieuwbouw
Structural - Enable Analytical Model: no; Structural: no
Dimensions - Elevation at Top: 0 mm; Area: 318.457 m2; Elevation at Bottom: -60 mm; Perimeter: 74388 mm; Thickness: 60 mm; Volume: 19.1074 m3
Identity Data - Workset: Workset1; Comments: schraaprooster
Other - Family: Floor; Family and Type: Floor: 43_FL_sportvloer+cementdekvloer_11+50 - opbouw 5; Type: 43_FL_sportvloer+cementdekvloer_11+50 - opbouw 5; Type Id: 587138

# IfcSlab: Floor:NLRS_23_FL_aftimmering ok trap MS_50+25 (2)
In: 00 begane grond
Type - PredefinedType: FLOOR; Material: n7_isolatie_glaswol 50 mm, f7_gips 12.5 mm, f7_gipsvezel 12.5 mm
Type - Analytical Properties - Roughness: 1; Absorptance: 0.1
Type - Graphics - Coarse Scale Fill Pattern: <Solid fill>; Coarse Scale Fill Color: 4210752
Type - Construction - Function: Interior; Default Thickness: 75 mm
Type - Identity Data - Workset: Floor Types; Description: basisvloer 250mm; Model: LOD200; SmartRevit_Versie: 2018.2; Type Name: NLRS_23_FL_aftimmering ok trap MS_50+25
Type - Other - Category: Floors; Family Name: Floor
Constraints - Level: 00 begane grond; Related to Mass: no; Room Bounding: yes; Height Offset From Level: 2035.71 mm
Phasing - Phase Created: 2. nieuwbouw
Structural - Enable Analytical Model: no; Structural: no
Dimensions - Elevation at Bottom: 1960.71 mm; Elevation at Top: 2035.71 mm; Thickness: 75 mm
Identity Data - Workset: Workset1
Other - Family: Floor; Family and Type: Floor: NLRS_23_FL_aftimmering ok trap MS_50+25; Type: NLRS_23_FL_aftimmering ok trap MS_50+25; Type Id: 2741164
Name (Floor:NLRS_23_FL_aftimmering ok trap MS_50+25:...) | Area (m2) | Perimeter (mm) | Volume (m3)
2741272 | 0.816 | 3620 | 0.0612
3066154 | 0.906582 | 3808.71 | 0.0679936

# IfcSlab: Floor:NLRS_23_FL_basisvloer 50, Floor:NLRS_23_FL_basisvloer 50:5041386
In: 00 begane grond
Type - PredefinedType: FLOOR; Material: a_vloer_generiek 50 mm
Type - Analytical Properties - Roughness: 1; Absorptance: 0.1
Type - Materials and Finishes - Structural Material: a_vloer_generiek
Type - Graphics - Coarse Scale Fill Pattern: <Solid fill>; Coarse Scale Fill Color: 4210752
Type - Construction - Function: Interior; Default Thickness: 50 mm
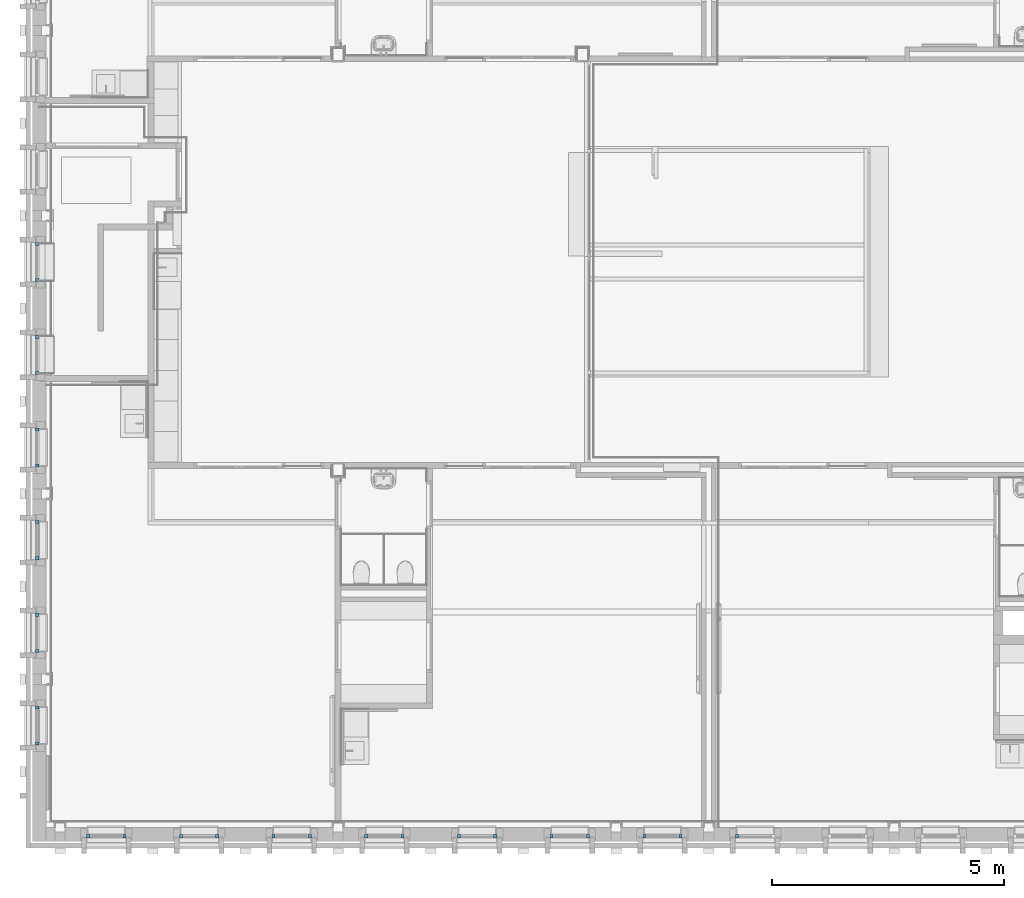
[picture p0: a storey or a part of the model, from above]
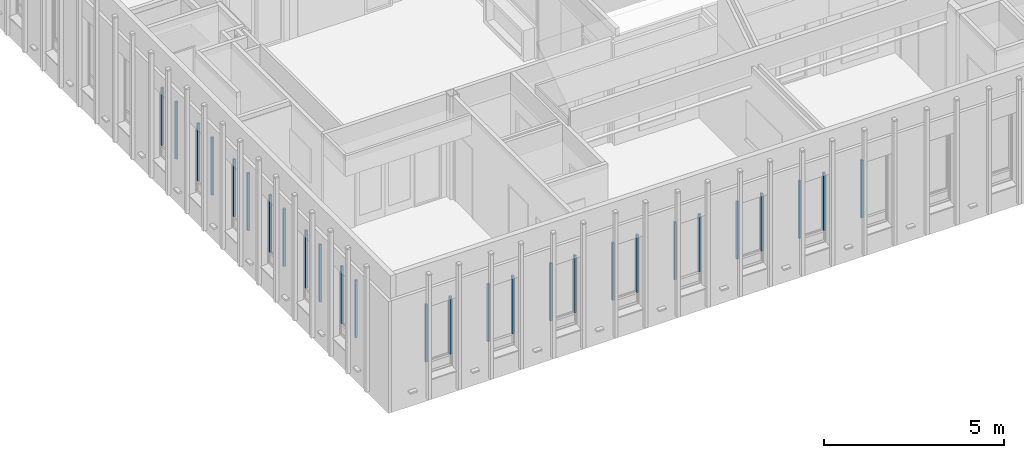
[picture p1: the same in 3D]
Properties of the parts of a building model (IFC2X3), part 83 of 94

# IfcSlab: Floor:NLRS_23_FL_basisvloer 50, Floor:NLRS_23_FL_basisvloer 50:5041386
Type - Identity Data - Workset: Floor Types; Description: basisvloer 100mm; Model: LOD200; SmartRevit_Versie: 2018.2; Type Name: NLRS_23_FL_basisvloer 50
Type - Other - Category: Floors; Family Name: Floor
Constraints - Level: 00 begane grond; Related to Mass: no; Room Bounding: yes; Height Offset From Level: 720 mm
Phasing - Phase Created: 2. nieuwbouw
Structural - Enable Analytical Model: no; Structural: no
Dimensions - Area: 0.523 m2; Elevation at Bottom: 670 mm; Elevation at Top: 720 mm; Perimeter: 3092 mm; Thickness: 50 mm; Volume: 0.02615 m3
Identity Data - Workset: Workset1; Comments: schraaprooster
Other - Family: Floor; Family and Type: Floor: NLRS_23_FL_basisvloer 50; Type: NLRS_23_FL_basisvloer 50; Type Id: 3999699

# IfcSlab: Floor:NLRS_23_FL_basisvloer 500 (2)
In: 00 begane grond
Type - PredefinedType: FLOOR; Material: a_vloer_generiek 500 mm
Type - Analytical Properties - Roughness: 1; Absorptance: 0.1
Type - Materials and Finishes - Structural Material: a_vloer_generiek
Type - Graphics - Coarse Scale Fill Pattern: <Solid fill>; Coarse Scale Fill Color: 4210752
Type - Construction - Function: Interior; Default Thickness: 500 mm
Type - Identity Data - Workset: Floor Types; Description: basisvloer 250mm; Model: LOD200; SmartRevit_Versie: 2018.2; Type Name: NLRS_23_FL_basisvloer 500
Type - Other - Category: Floors; Family Name: Floor
Constraints - Level: 00 begane grond; Related to Mass: no; Room Bounding: yes
Phasing - Phase Created: 2. nieuwbouw
Structural - Enable Analytical Model: no; Structural: no
Dimensions - Thickness: 500 mm
Identity Data - Workset: Workset1
Other - Family: Floor; Family and Type: Floor: NLRS_23_FL_basisvloer 500; Type: NLRS_23_FL_basisvloer 500; Type Id: 1957242
Name (Floor:NLRS_23_FL_basisvloer 500:...) | Height Offset From Level (mm) = Elevation at Top (mm) | Area (m2) | Elevation at Bottom (mm) | Perimeter (mm) | Volume (m3)
2230458 | 720 | 25.4471 | 220 | 31265 | 12.7234
2230514 | 360 | 54.3226 | -140 | 48138.8 | 27.1609

# IfcSlab: Floor:NLRS_23_FL_gewapend beton 150_gen_ISR, Floor:NLRS_23_FL_gewapend beton 150_gen_ISR:5094317
In: 00 begane grond
Type - PredefinedType: FLOOR; Material: f2_beton ihwg_gen 200 mm
Type - Analytical Properties - Roughness: 1; Absorptance: 0.1
Type - Materials and Finishes - Structural Material: f2_beton ihwg_gen
Type - Graphics - Coarse Scale Fill Pattern: <Solid fill>; Coarse Scale Fill Color: 8421504
Type - Construction - Function: Interior; Default Thickness: 200 mm
Type - Identity Data - Workset: Floor Types; Assembly Code: 23.21.41; Assembly Description: vloerconstructie, gestort beton; Description: betonvloer 150mm ihwg; Model: LOD300; SmartRevit_Versie: 2018.2; Type Name: NLRS_23_FL_gewapend beton 150_gen_ISR
Type - Other - Category: Floors; Family Name: Floor
Classification: 23.21.41 Uniformat (Uniformat)
Constraints - Level: 00 begane grond; Related to Mass: no; Room Bounding: yes; Height Offset From Level: -320 mm
Phasing - Phase Created: 2. nieuwbouw
Structural - Enable Analytical Model: no; Structural: no
Dimensions - Area: 20.7638 m2; Elevation at Bottom: -520 mm; Elevation at Top: -320 mm; Perimeter: 18726 mm; Thickness: 200 mm; Volume: 4.15275 m3
Identity Data - Workset: Workset1; Comments: schraaprooster
Other - Family: Floor; Family and Type: Floor: NLRS_23_FL_gewapend beton 150_gen_ISR; Type: NLRS_23_FL_gewapend beton 150_gen_ISR; Type Id: 5094339

# IfcSlab: Floor:NLRS_23_FL_isolatie 140_gen_ISR, Floor:NLRS_23_FL_isolatie 140_gen_ISR:2801203
In: 00 begane grond
Type - PredefinedType: FLOOR; Material: n7_isolatie_gen 140 mm
Type - Analytical Properties - Roughness: 1; Absorptance: 0.1
Type - Materials and Finishes - Structural Material: n7_isolatie_gen
Type - Graphics - Coarse Scale Fill Pattern: <Solid fill>; Coarse Scale Fill Color: 12632256
Type - Construction - Function: Interior; Default Thickness: 140 mm
Type - Identity Data - Workset: Floor Types; Assembly Code: 43; Assembly Description: vloerafwerkingen; Description: isolatie 100mm; Model: LOD300; SmartRevit_Versie: 2018.2; Type Name: NLRS_23_FL_isolatie 140_gen_ISR
Type - Other - Category: Floors; Family Name: Floor
Classification: 43 Uniformat (Uniformat)
Constraints - Level: 00 begane grond; Related to Mass: no; Room Bounding: yes; Height Offset From Level: -260 mm
Phasing - Phase Created: 2. nieuwbouw
Structural - Enable Analytical Model: no; Structural: no
Dimensions - Area: 306.3 m2; Elevation at Bottom: -400 mm; Elevation at Top: -260 mm; Perimeter: 71799.7 mm; Thickness: 140 mm; Volume: 42.882 m3
Identity Data - Workset: Workset1
Other - Family: Floor; Family and Type: Floor: NLRS_23_FL_isolatie 140_gen_ISR; Type: NLRS_23_FL_isolatie 140_gen_ISR; Type Id: 2801205

# IfcSlab: Floor:NLRS_23_FL_schraaprooster 20 (6)
Type - PredefinedType: FLOOR; Material: h2_staal_rooster 20 mm
Type - Analytical Properties - Roughness: 1; Absorptance: 0.1
Type - Materials and Finishes - Structural Material: h2_staal_rooster
Type - Graphics - Coarse Scale Fill Pattern: <Solid fill>; Coarse Scale Fill Color: 12632256
Type - Construction - Function: Interior; Default Thickness: 20 mm
Type - Identity Data - Workset: Floor Types; Assembly Code: 43; Assembly Description: vloerafwerkingen; Description: isolatie 100mm; Model: LOD300; SmartRevit_Versie: 2018.2; Type Name: NLRS_23_FL_schraaprooster 20
Type - Other - Category: Floors; Family Name: Floor
Classification: 43 Uniformat (Uniformat)
Constraints - Related to Mass: no; Room Bounding: yes
Phasing - Phase Created: 2. nieuwbouw
Structural - Enable Analytical Model: no; Structural: no
Dimensions - Thickness: 20 mm
Identity Data - Workset: Workset1; Comments: schraaprooster
Other - Family: Floor; Family and Type: Floor: NLRS_23_FL_schraaprooster 20; Type: NLRS_23_FL_schraaprooster 20; Type Id: 3021259
Name (Floor:NLRS_23_FL_schraaprooster 20:...) | In | Level | Height Offset From Level (mm) | Area (m2) | Elevation at Bottom (mm) | Elevation at Top (mm) | Perimeter (mm) | Volume (m3)
3021257 | 00 begane grond | 00 begane grond | -20 | 2.925 | -40 | -20 | 7100 | 0.0585
3021391 | 00 begane grond | 00 begane grond | -20 | 1.95 | -40 | -20 | 5900 | 0.039
3021488 | 00 begane grond | 00 begane grond | -20 | 2 | -40 | -20 | 6000 | 0.04
3021578 | 00 begane grond | 00 begane grond | -20 | 2 | -40 | -20 | 6000 | 0.04
3024343 | 01 eerste verdieping | 01 eerste verdieping | 260 | 1.74837 | 4240 | 4260 | 5520 | 0.0349675
3025589 | 02 tweede verdieping | 02 tweede verdieping | 273 | 1.88 | 8053 | 8073 | 5760 | 0.0376

# IfcSlab: Floor:NLRS_43_FL_cementdekvloer 50_gen_ISR (2)
Type - PredefinedType: FLOOR; Material: q2_cementdekvloer 50 mm
Type - Analytical Properties - Roughness: 1; Absorptance: 0.1
Type - Materials and Finishes - Structural Material: q2_cementdekvloer
Type - Graphics - Coarse Scale Fill Color: 0
Type - Construction - Function: Interior; Default Thickness: 50 mm
Type - Identity Data - Assembly Code: 43.21.11; Assembly Description: cementdekvloer; Description: cementdekvloer 50mm; Model: LOD300; SmartRevit_Versie: 2018.2; Type Name: NLRS_43_FL_cementdekvloer 50_gen_ISR; Workset: Floor Types
Type - Other - Category: Floors; Family Name: Floor
Classification: 43.21.11 Uniformat (Uniformat)
Constraints - Related to Mass: no; Room Bounding: yes; Height Offset From Level: 0 mm
Phasing - Phase Created: 2. nieuwbouw
Structural - Enable Analytical Model: no; Structural: no
Dimensions - Thickness: 50 mm
Identity Data - Workset: Workset1
Other - Family: Floor; Family and Type: Floor: NLRS_43_FL_cementdekvloer 50_gen_ISR; Type: NLRS_43_FL_cementdekvloer 50_gen_ISR; Type Id: 2258479
Name (Floor:NLRS_43_FL_cementdekvloer 50_gen_ISR:...) | In | Level | Area (m2) | Elevation at Bottom (mm) | Elevation at Top (mm) | Perimeter (mm) | Volume (m3)
865214 | 01 eerste verdieping | 01 eerste verdieping | 642.065 | 3950 | 4000 | 164330 | 32.1032
895350 | 02 tweede verdieping | 02 tweede verdieping | 560.378 | 7750 | 7800 | 143164 | 28.0189

# IfcSlab: Floor:NLRS_43_FL_cementdekvloer 60_gen_ISR, Floor:NLRS_43_FL_cementdekvloer 60_gen_ISR:1295401
In: 00 begane grond
Type - PredefinedType: FLOOR; Material: i3_vloer_afwerking 60 mm
Type - Analytical Properties - Roughness: 1; Absorptance: 0.1
Type - Materials and Finishes - Structural Material: i3_vloer_afwerking
Type - Graphics - Coarse Scale Fill Color: 0
Type - Construction - Function: Interior; Default Thickness: 60 mm
Type - Identity Data - Workset: Floor Types; Assembly Code: 43.21.11; Assembly Description: cementdekvloer; Description: cementdekvloer 50mm; Model: LOD300; SmartRevit_Versie: 2018.2; Type Name: NLRS_43_FL_cementdekvloer 60_gen_ISR
Type - Other - Category: Floors; Family Name: Floor
Classification: 43.21.11 Uniformat (Uniformat)
Constraints - Level: 00 begane grond; Related to Mass: no; Room Bounding: yes; Height Offset From Level: 0 mm
Phasing - Phase Created: 2. nieuwbouw
Structural - Enable Analytical Model: no; Structural: no
Dimensions - Area: 1213.27 m2; Elevation at Bottom: -60 mm; Elevation at Top: 0 mm; Perimeter: 202682 mm; Thickness: 60 mm; Volume: 72.6895 m3
Identity Data - Workset: Workset1
Other - Family: Floor; Family and Type: Floor: NLRS_43_FL_cementdekvloer 60_gen_ISR; Type: NLRS_43_FL_cementdekvloer 60_gen_ISR; Type Id: 475482

# IfcSlab: Floor:NLRS_90_FL_tegelvloer 300x300 + zand_gen_ISR 2 (2)
In: 00 begane grond
Type - PredefinedType: FLOOR; Material: g3_tegels_grijs_300x300 40 mm, p1_zand 280 mm
Type - Analytical Properties - Roughness: 1; Absorptance: 0.1
Type - Graphics - Coarse Scale Fill Color: 0
Type - Construction - Function: Interior; Default Thickness: 320 mm
Type - Identity Data - Workset: Floor Types; Assembly Code: 43.22.31; Assembly Description: tegelvloer, keramisch; Description: tegelvloer 300x300; Model: LOD300; SmartRevit_Versie: 2018.2; Type Name: NLRS_90_FL_tegelvloer 300x300 + zand_gen_ISR 2
Type - Other - Category: Floors; Family Name: Floor
Classification: 43.22.31 Uniformat (Uniformat)
Constraints - Level: 00 begane grond; Related to Mass: no; Room Bounding: yes
Phasing - Phase Created: 2. nieuwbouw
Structural - Enable Analytical Model: no; Structural: no
Dimensions - Thickness: 320 mm
Identity Data - Workset: Workset1; Comments: schraaprooster
Other - Family: Floor; Family and Type: Floor: NLRS_90_FL_tegelvloer 300x300 + zand_gen_ISR 2; Type: NLRS_90_FL_tegelvloer 300x300 + zand_gen_ISR 2; Type Id: 5094979
Name (Floor:NLRS_90_FL_tegelvloer 300x300 + zand_gen_ISR 2:...) | Height Offset From Level (mm) = Elevation at Top (mm) | Area (m2) | Elevation at Bottom (mm) | Perimeter (mm) | Volume (m3)
3218931 | 0 | 7.37614 | -320 | 11288 | 2.36037
4200130 | -20 | 10.4134 | -340 | 13098 | 3.33227

# IfcSlab: Monolithic Landing:ST_250 mm Thickness (3)
Type - PredefinedType: LANDING
Type - Treads - Same as Run: yes
Type - Materials and Finishes - Monolithic Material: f2_beton_prefab_gen
Type - Construction - Monolithic Thickness: 250 mm
Type - Identity Data - Workset: Stair Types; Type Name: ST_250 mm Thickness
Type - Other - Category: Stairs: Landings; Family Name: Monolithic Landing
Classification: 24.10 Uniformat (Uniformat); Material: f2_beton_prefab_gen
Phasing - Phase Created: 2. nieuwbouw
Dimensions - Total Thickness: 250 mm
Identity Data - Workset: Workset1
Other - Family: Monolithic Landing; Family and Type: Monolithic Landing: ST_250 mm Thickness; Type: ST_250 mm Thickness; Type Id: 1771036
Name (Cast-In-Place Stair:Stair:...) | In | Relative Height (mm)
1615872 Landing 1 | 01 eerste verdieping | 2090
1769840 Landing 1 | 00 begane grond | 380.952
1769840 Landing 2 | 00 begane grond | 2285.71

# IfcSlab: NLRS_16_GM_PSkist_gen_bdg:balk 500x600 (12)
In: 00 begane grond
Type - PredefinedType: ROOF
Type - Constraints(Type) - Default Elevation: 1219.2 mm; breedte_achter: 120 mm; breedte_voor: 30 mm
Type - Materials and Finishes(Type) - materiaal: ISR_Isolatie PS
Type - Dimensions(Type) - balk_breedte: 500 mm; balk_hoogte: 600 mm
Type - Identity Data(Type) - Workset: Family : Generic Models : NLRS_16_GM_PSkist_gen_bdg; Assembly Code: 16.10; Assembly Description: funderingsconstructies; voeten en balken, algemeen (verzamelniveau); Description: PS funderingsbekisting; Model: daktrim; Type Name: balk 500x600
Type - Other(Type) - Category: Generic Models; Family Name: NLRS_16_GM_PSkist_gen_bdg
Classification: 16.10 Uniformat (Uniformat)
Name (NLRS_16_GM_PSkist_gen_bdg:balk 500x600:...)
3382763:1
3382773:1
3382783:1
3382899:1
3382907:1
3383388:1
3383669:1
3383839:1
3384271:1
3829205:1
3829240:1
3829247:1

# IfcSlab: NLRS_16_GM_PSkist_gen_bdg:balk 650x600, NLRS_16_GM_PSkist_gen_bdg:balk 650x600:3382747:1
In: 00 begane grond
Type - PredefinedType: ROOF
Type - Constraints(Type) - Default Elevation: 1219.2 mm; breedte_achter: 120 mm; breedte_voor: 30 mm
Type - Materials and Finishes(Type) - materiaal: ISR_Isolatie PS
Type - Dimensions(Type) - balk_breedte: 650 mm; balk_hoogte: 600 mm
Type - Identity Data(Type) - Workset: Family : Generic Models : NLRS_16_GM_PSkist_gen_bdg; Assembly Code: 16.10; Assembly Description: funderingsconstructies; voeten en balken, algemeen (verzamelniveau); Description: PS funderingsbekisting; Model: daktrim; Type Name: balk 650x600
Type - Other(Type) - Category: Generic Models; Family Name: NLRS_16_GM_PSkist_gen_bdg
Classification: 16.10 Uniformat (Uniformat)

# IfcSlab: NLRS_41_GM_muurafdekker_aluminium_gen_bdg:aluminium muurafdekker b320 muurb258, NLRS_41_GM_muurafdekker_aluminium_gen_bdg:aluminium muurafdekker b320 muurb258:3308447:1
In: 01 eerste verdieping
Type - PredefinedType: ROOF
Type - Constraints - Default Elevation: 0 mm; breedte_achter: 290 mm; breedte_voor: 30 mm
Type - Dimensions - bk_multiplex_tov_bk_afdekker: -40 mm; breedte: 320 mm; dikte: 2 mm; helling: 2 deg; hoogte_aanzicht: 50 mm; multiplex_breedte: 258 mm; multiplex_dikte: 20 mm
Type - Identity Data - Workset: Family : Generic Models : NLRS_41_GM_muurafdekker_aluminium_gen_bdg; Assembly Code: 41.10; Assembly Description: buitenwandafwerkingen; algemeen (verzamelniveau); Description: daktrim; Model: daktrim; Type Name: aluminium muurafdekker b320 muurb258
Type - Other - Category: Generic Models; multiplex: yes; Family Name: NLRS_41_GM_muurafdekker_aluminium_gen_bdg
Classification: 41.10 Uniformat (Uniformat)

# IfcSlab: NLRS_41_GM_muurafdekker_aluminium_gen_bdg:aluminium muurafdekker b390 muurb320 (2)
In: 01 eerste verdieping
Type - PredefinedType: ROOF
Type - Constraints(Type) - Default Elevation: 0 mm; breedte_achter: 360 mm; breedte_voor: 30 mm
Type - Dimensions(Type) - bk_multiplex_tov_bk_afdekker: -40 mm; breedte: 390 mm; dikte: 2 mm; helling: 2 deg; hoogte_aanzicht: 50 mm; multiplex_breedte: 320 mm; multiplex_dikte: 20 mm
Type - Identity Data(Type) - Workset: Family : Generic Models : NLRS_41_GM_muurafdekker_aluminium_gen_bdg; Assembly Code: 41.10; Assembly Description: buitenwandafwerkingen; algemeen (verzamelniveau); Description: daktrim; Model: daktrim; Type Name: aluminium muurafdekker b390 muurb320
Type - Other(Type) - Category: Generic Models; multiplex: yes; Family Name: NLRS_41_GM_muurafdekker_aluminium_gen_bdg
Classification: 41.10 Uniformat (Uniformat)
Name (NLRS_41_GM_muurafdekker_aluminium_gen_bdg:aluminium muurafdekker b390 muurb320:...)
1924955:1
1925353:1

# IfcSlab: NLRS_41_GM_muurafdekker_aluminium_gen_bdg:aluminium muurafdekker b410 muurb340 (3)
In: 01 eerste verdieping
Type - PredefinedType: ROOF
Type - Constraints - Default Elevation: 0 mm; breedte_achter: 380 mm; breedte_voor: 30 mm
Type - Dimensions - bk_multiplex_tov_bk_afdekker: -40 mm; breedte: 410 mm; dikte: 2 mm; helling: 2 deg; hoogte_aanzicht: 50 mm; multiplex_breedte: 340 mm; multiplex_dikte: 20 mm
Type - Identity Data - Workset: Family : Generic Models : NLRS_41_GM_muurafdekker_aluminium_gen_bdg; Assembly Code: 41.10; Assembly Description: buitenwandafwerkingen; algemeen (verzamelniveau); Description: daktrim; Model: daktrim; Type Name: aluminium muurafdekker b410 muurb340
Type - Other - Category: Generic Models; multiplex: yes; Family Name: NLRS_41_GM_muurafdekker_aluminium_gen_bdg
Classification: 41.10 Uniformat (Uniformat)
Name (NLRS_41_GM_muurafdekker_aluminium_gen_bdg:aluminium muurafdekker b410 muurb340:...)
2096506:1
2096682:1
2549659:1

# IfcSlab: NLRS_41_GM_muurafdekker_aluminium_gen_bdg:aluminium muurafdekker b450 muurb382, NLRS_41_GM_muurafdekker_aluminium_gen_bdg:aluminium muurafdekker b450 muurb382:1753955:1
In: 01 eerste verdieping
Type - PredefinedType: ROOF
Type - Constraints - Default Elevation: 0 mm; breedte_achter: 420 mm; breedte_voor: 30 mm
Type - Dimensions - bk_multiplex_tov_bk_afdekker: -40 mm; breedte: 450 mm; dikte: 2 mm; helling: 2 deg; hoogte_aanzicht: 50 mm; multiplex_breedte: 382 mm; multiplex_dikte: 20 mm
Type - Identity Data - Workset: Family : Generic Models : NLRS_41_GM_muurafdekker_aluminium_gen_bdg; Assembly Code: 41.10; Assembly Description: buitenwandafwerkingen; algemeen (verzamelniveau); Description: daktrim; Model: daktrim; Type Name: aluminium muurafdekker b450 muurb382
Type - Other - Category: Generic Models; multiplex: yes; Family Name: NLRS_41_GM_muurafdekker_aluminium_gen_bdg
Classification: 41.10 Uniformat (Uniformat)

# IfcSlab: NLRS_41_GM_muurafdekker_aluminium_gen_bdg:aluminium muurafdekker b590 muurb530 (3)
In: 00 begane grond
Type - PredefinedType: ROOF
Type - Constraints - Default Elevation: 0 mm; breedte_achter: 560 mm; breedte_voor: 30 mm
Type - Dimensions - bk_multiplex_tov_bk_afdekker: -45 mm; breedte: 590 mm; dikte: 2 mm; helling: 2 deg; hoogte_aanzicht: 50 mm; multiplex_breedte: 530 mm; multiplex_dikte: 20 mm
Type - Identity Data - Workset: Family : Generic Models : NLRS_41_GM_muurafdekker_aluminium_gen_bdg; Assembly Code: 41.10; Assembly Description: buitenwandafwerkingen; algemeen (verzamelniveau); Description: daktrim; Model: daktrim; Type Name: aluminium muurafdekker b590 muurb530
Type - Other - Category: Generic Models; multiplex: yes; Family Name: NLRS_41_GM_muurafdekker_aluminium_gen_bdg
Classification: 41.10 Uniformat (Uniformat)
Name (NLRS_41_GM_muurafdekker_aluminium_gen_bdg:aluminium muurafdekker b590 muurb530:...)
1760751:1
2983871:1
2984950:1

# IfcSlab: NLRS_42_GM_houten_regel_gen_bdg:houten afdekker 32x139 (9)
In: 01 eerste verdieping
Type - PredefinedType: ROOF
Type - Constraints - Default Elevation: 0 mm
Type - Materials and Finishes - materiaal: i4_hout_Eiken_gen
Type - Dimensions - bk_regel_tov_wand: 0 mm; breedte: 139 mm; dikte: 32 mm; hoogte_aanzicht: 50 mm; voorkant_regel_tov_voorkant_wand: -7 mm
Type - Identity Data - Assembly Code: 41.10; Assembly Description: buitenwandafwerkingen; algemeen (verzamelniveau); Description: daktrim; Model: daktrim; Type Name: houten afdekker 32x139; Workset: Family : Generic Models : NLRS_42_GM_houten_regel_gen_bdg
Type - Other - Category: Generic Models; Family Name: NLRS_42_GM_houten_regel_gen_bdg
Classification: 41.10 Uniformat (Uniformat)
Name (NLRS_42_GM_houten_regel_gen_bdg:houten afdekker 32x139:...)
3148216:1
3150707:1
3151951:1
3151955:1
3151957:1
3151965:1
3151969:1
3151984:1
3151986:1

# IfcSlab: Pad:ontgraving (2)
In: 00 begane grond
Type - PredefinedType: FLOOR; Material: <Unnamed> 2 mm
Type - Analytical Properties - Roughness: 1; Absorptance: 0.1
Type - Graphics - Coarse Scale Fill Color: 0
Type - Construction - Thickness: 2 mm
Type - Identity Data - Type Name: ontgraving; Workset: Pad Types
Type - Other - Category: Site: Pads; Family Name: Pad
Constraints - Level: 00 begane grond; Room Bounding: yes
Phasing - Phase Created: 2. nieuwbouw
Identity Data - Workset: Workset1
Other - Family: Pad; Family and Type: Pad: ontgraving; Type: ontgraving; Type Id: 18148
Name (Pad:ontgraving:...) | Height Offset From Level (mm) | Area (m2) | Perimeter (mm) | Volume (m3)
4192385 | -1320 | 1624.61 | 222648 | 3.24922
4192388 | -400 | 306.3 | 71799.7 | 0.6126

# IfcStair: Assembled Stair:27_BDG_houten trap, Assembled Stair:Stair:1495102
In: 00 begane grond
ShapeType: STRAIGHT_RUN_STAIR; Classification: 24.10 Uniformat (Uniformat)
Constraints - Top Offset: 0 mm; Base Offset: 0 mm; Base Level: 00 begane grond; Desired Stair Height: 4000 mm; Top Level: 01 eerste verdieping
Phasing - Phase Created: 2. nieuwbouw
Structural - Rebar Cover: 30mm <30 mm>
Dimensions - Tread/Riser Start Number: 1; Actual Number of Risers: 22; Actual Riser Height: 181.818 mm; Actual Tread Depth: 260 mm; Desired Number of Risers: 22
Identity Data - Workset: Workset1; Comments: trap 3
Other - Category: Stairs; Family: Assembled Stair; Family and Type: Assembled Stair: 27_BDG_houten trap; Type: 27_BDG_houten trap; Type Id: 1495114
Supports(Type) - Left Lateral Offset: 0 mm; Middle Support: no; Middle Support Number: 0; Right Lateral Offset: 0 mm
Calculation Rules(Type) - Maximum Riser Height: 360 mm; Minimum Run Width: 1500 mm; Minimum Tread Depth: 520 mm
Graphics(Type) - Cut Mark Type: ST_Single Zigzag
Construction(Type) - Function: Interior; Landing Type: ST_220 mm Thickness; Run Type: ST_0 mm Nosing 200 Hout trap
Identity Data(Type) - Workset: Stair Types; Assembly Code: 24.10; Assembly Description: trappen en hellingen; trappen, algemeen (verzamelniveau); Description: Houten tribunetrap; Type Name: 27_BDG_houten trap
Other(Type) - Category: Stairs; Family Name: Assembled Stair

# IfcStair: Assembled Stair:27_BDG_houten trap buiten, Assembled Stair:Stair:1307534
In: 01 eerste verdieping
ShapeType: STRAIGHT_RUN_STAIR; Classification: 24.10 Uniformat (Uniformat)
Constraints - Base Level: 01 eerste verdieping; Base Offset: 260 mm; Desired Stair Height: 3813 mm; Top Level: 02 tweede verdieping; Top Offset: 273 mm
Phasing - Phase Created: 2. nieuwbouw
Dimensions - Actual Number of Risers: 21; Actual Riser Height: 181.571 mm; Actual Tread Depth: 260 mm; Desired Number of Risers: 21; Tread/Riser Start Number: 1
Identity Data - Workset: Workset1; Comments: trap 2
Other - Category: Stairs; Family: Assembled Stair; Family and Type: Assembled Stair: 27_BDG_houten trap buiten; Type: 27_BDG_houten trap buiten; Type Id: 3076378
Supports(Type) - Left Lateral Offset: 0 mm; Middle Support: no; Middle Support Number: 0; Middle Support Type: ST_Carriage; Right Lateral Offset: 0 mm
Calculation Rules(Type) - Maximum Riser Height: 210 mm; Minimum Run Width: 1500 mm; Minimum Tread Depth: 260 mm
Graphics(Type) - Cut Mark Type: ST_Single Zigzag
Construction(Type) - Function: Interior; Landing Type: ST_Non-Monolithic Landing; Run Type: houten treden + stootborden
Identity Data(Type) - Assembly Code: 24.10; Assembly Description: trappen en hellingen; trappen, algemeen (verzamelniveau); Description: Houten tribunetrap; Type Name: 27_BDG_houten trap buiten; Workset: Stair Types
Other(Type) - Category: Stairs; Family Name: Assembled Stair

# IfcStair: Assembled Stair:27_BDG_houten treden, Assembled Stair:Stair:3030916
In: 01 eerste verdieping
ShapeType: STRAIGHT_RUN_STAIR; Classification: 24.10 Uniformat (Uniformat)
Constraints - Top Offset: 0 mm; Base Offset: 0 mm; Base Level: 01 eerste verdieping; Top Level: 02 tweede verdieping; Desired Stair Height: 3800 mm
Phasing - Phase Created: 2. nieuwbouw
Dimensions - Tread/Riser Start Number: 1; Actual Number of Risers: 21; Actual Riser Height: 180.952 mm; Actual Tread Depth: 240 mm; Desired Number of Risers: 21
Identity Data - Workset: Workset1; Comments: trap 5
Other - Category: Stairs; Family: Assembled Stair; Family and Type: Assembled Stair: 27_BDG_houten treden; Type: 27_BDG_houten treden; Type Id: 3030914
Supports(Type) - Left Lateral Offset: 0 mm; Middle Support: no; Middle Support Number: 0; Right Lateral Offset: 0 mm
Calculation Rules(Type) - Maximum Riser Height: 360 mm; Minimum Run Width: 1500 mm; Minimum Tread Depth: 520 mm
Graphics(Type) - Cut Mark Type: ST_Single Zigzag
Construction(Type) - Function: Interior; Landing Type: ST_220 mm Thickness; Run Type: ST_28 mm Tread 10 mm Nosing 28 mm Riser
Identity Data(Type) - Workset: Stair Types; Assembly Code: 24.10; Assembly Description: trappen en hellingen; trappen, algemeen (verzamelniveau); Description: Houten tribunetrap; Type Name: 27_BDG_houten treden
Other(Type) - Category: Stairs; Family Name: Assembled Stair

# IfcStair: Assembled Stair:27_BDG_houten tribunetrap, Assembled Stair:Stair:1495941
In: 00 begane grond
ShapeType: STRAIGHT_RUN_STAIR; Classification: 24.10 Uniformat (Uniformat)
Constraints - Top Offset: 0 mm; Base Offset: 0 mm; Base Level: 00 begane grond; Top Level: 01 eerste verdieping; Desired Stair Height: 4000 mm
Phasing - Phase Created: 2. nieuwbouw
Structural - Rebar Cover: 30mm <30 mm>
Dimensions - Tread/Riser Start Number: 1; Actual Number of Risers: 11; Actual Riser Height: 363.636 mm; Actual Tread Depth: 520 mm; Desired Number of Risers: 11
Identity Data - Workset: Workset1; Comments: trap 3
Other - Category: Stairs; Family: Assembled Stair; Family and Type: Assembled Stair: 27_BDG_houten tribunetrap; Type: 27_BDG_houten tribunetrap; Type Id: 1496623
Supports(Type) - Left Lateral Offset: 0 mm; Middle Support: no; Middle Support Number: 0; Right Lateral Offset: 0 mm
Calculation Rules(Type) - Maximum Riser Height: 360 mm; Minimum Run Width: 1500 mm; Minimum Tread Depth: 520 mm
Graphics(Type) - Cut Mark Type: ST_Single Zigzag
Construction(Type) - Function: Interior; Landing Type: ST_220 mm Thickness; Run Type: ST_0 mm Nosing 200 Hout tribune
Identity Data(Type) - Workset: Stair Types; Assembly Code: 24.10; Assembly Description: trappen en hellingen; trappen, algemeen (verzamelniveau); Description: Houten tribunetrap; Type Name: 27_BDG_houten tribunetrap
Other(Type) - Category: Stairs; Family Name: Assembled Stair

# IfcStair: Cast-In-Place Stair:27_ST_beton trap (2)
Classification: 24.10 Uniformat (Uniformat)
Constraints - Top Offset: 0 mm; Base Offset: 0 mm
Phasing - Phase Created: 2. nieuwbouw
Structural - Rebar Cover: 30mm <30 mm>
Dimensions - Tread/Riser Start Number: 1; Actual Tread Depth: 220 mm
Identity Data - Workset: Workset1
Other - Category: Stairs; Family: Cast-In-Place Stair; Family and Type: Cast-In-Place Stair: 27_ST_beton trap; Type: 27_ST_beton trap; Type Id: 18184
Supports(Type) - Left Lateral Offset: 0 mm; Middle Support: no; Middle Support Number: 0; Right Lateral Offset: 0 mm
Calculation Rules(Type) - Maximum Riser Height: 185 mm; Minimum Run Width: 1000 mm; Minimum Tread Depth: 230 mm
Graphics(Type) - Cut Mark Type: ST_Single Zigzag
Construction(Type) - Function: Interior; Landing Type: ST_250 mm Thickness; Run Type: ST_25 mm Nosing
Identity Data(Type) - Workset: Stair Types; Assembly Code: 24.10; Assembly Description: trappen en hellingen; trappen, algemeen (verzamelniveau); Description: betonnen trap; Type Name: 27_ST_beton trap
Other(Type) - Category: Stairs; Family Name: Cast-In-Place Stair
Name (Cast-In-Place Stair:Stair:...) | In | Base Level | Top Level | Desired Stair Height (mm) | Actual Number of Risers = Desired Number of Risers | Actual Riser Height (mm) | Comments
1615872 | 01 eerste verdieping | 01 eerste verdieping | 02 tweede verdieping | 3800 | 20 | 190 | trap 4b | ShapeType: HALF_TURN_STAIR
1769840 | 00 begane grond | 00 begane grond | 01 eerste verdieping | 4000 | 21 | 190.476 | trap 4a

# IfcStair: Precast Stair:ST_Precast Stair recht, Precast Stair:Stair:1496818
In: 01 eerste verdieping
ShapeType: STRAIGHT_RUN_STAIR
Constraints - Base Level: 01 eerste verdieping; Top Level: 02 tweede verdieping; Base Offset: -80 mm; Desired Stair Height: 3981 mm; Top Offset: 101 mm
Phasing - Phase Created: 2. nieuwbouw
Structural - Rebar Cover: 30mm <30 mm>
Dimensions - Tread/Riser Start Number: 1; Actual Number of Risers: 21; Actual Riser Height: 180.955 mm; Actual Tread Depth: 240 mm; Desired Number of Risers: 22
Identity Data - Workset: Workset1; Comments: trap 5
Other - Category: Stairs; Family: Precast Stair; Family and Type: Precast Stair: ST_Precast Stair recht; Type: ST_Precast Stair recht; Type Id: 3031172
Supports(Type) - Left Lateral Offset: 0 mm; Middle Support: no; Middle Support Number: 0; Right Lateral Offset: 0 mm
End Connection(Type) - Connection Method: Notch; Horizontal Gap Distance: 10 mm; Notch Extension: 100 mm; Notch Thickness: 100 mm; Vertical Gap Distance: 10 mm
Calculation Rules(Type) - Maximum Riser Height: 185 mm; Minimum Run Width: 1000 mm; Minimum Tread Depth: 230 mm
Graphics(Type) - Cut Mark Type: ST_Single Zigzag
Construction(Type) - Function: Interior; Landing Type: ST_220 mm Thickness; Run Type: ST_0 mm Nosing
Identity Data(Type) - Workset: Stair Types; Type Name: ST_Precast Stair recht
Other(Type) - Category: Stairs; Family Name: Precast Stair

# IfcStairFlight: Monolithic Run:ST_0 mm Nosing, Precast Stair:Stair:1496818 Run 1
In: 01 eerste verdieping
Type - PredefinedType: STRAIGHT
Type - Risers - Riser To Tread Connection: Extend Riser Behind Tread; Riser: no; Riser Thickness: 0 mm; Slanted: yes
Type - Treads - Apply Nosing Profile: Front Only; Nosing Length: 0 mm; Tread: no; Tread Thickness: 0 mm
Type - Materials and Finishes - Monolithic Material: f2_beton_prefab_gen
Type - Construction - Underside Surface: Smooth; Structural Depth: 150 mm
Type - Identity Data - Workset: Stair Types; Type Name: ST_0 mm Nosing
Type - Other - Category: Stairs: Runs; Family Name: Monolithic Run
NumberOfRiser: 21; NumberOfTreads: 21; RiserHeight: 0.593683 mm; TreadLength: 0.787402 mm; Material: f2_beton_prefab_gen
Constraints - Location Line: Run: Center; Relative Base Height: 0 mm; Relative Top Height: 3800.05 mm; Run Height: 3800.05 mm
Phasing - Phase Created: 2. nieuwbouw
Construction - Begin with Riser: yes; End with Riser: no; Extend Below Riser Base: 0 mm
Dimensions - Actual Number of Risers: 21; Actual Number of Treads: 21; Actual Riser Height: 180.955 mm; Actual Run Width: 1500 mm; Actual Tread Depth: 240 mm
Identity Data - Workset: Workset1
Other - Family: Monolithic Run; Family and Type: Monolithic Run: ST_0 mm Nosing; Type: ST_0 mm Nosing; Type Id: 3031173

# IfcStairFlight: Monolithic Run:ST_0 mm Nosing 200 Hout trap, Assembled Stair:Stair:1495102 Run 1
In: 00 begane grond
Type - Risers - Riser: yes; Slanted: no; Riser Thickness: 40 mm; Riser To Tread Connection: Extend Tread Under Riser
Type - Treads - Apply Nosing Profile: Front Only; Nosing Length: 0 mm; Tread: yes; Tread Thickness: 62 mm
Type - Materials and Finishes - Monolithic Material: ISR_Hout; Riser Material: ISR_Hout; Tread Material: ISR_Hout
Type - Construction - Structural Depth: 161.4 mm; Underside Surface: Smooth
Type - Identity Data - Workset: Stair Types; Type Name: ST_0 mm Nosing 200 Hout trap
Type - Other - Category: Stairs: Runs; Family Name: Monolithic Run
NumberOfRiser: 22; NumberOfTreads: 22; RiserHeight: 0.596516 mm; TreadLength: 0.853018 mm; Classification: 24.10 Uniformat (Uniformat); Material: ISR_Hout
Constraints - Relative Base Height: 0 mm; Relative Top Height: 4000 mm; Run Height: 4000 mm
Phasing - Phase Created: 2. nieuwbouw
Construction - Begin with Riser: yes; End with Riser: no; Extend Below Riser Base: 0 mm
Dimensions - Actual Number of Risers: 22; Actual Number of Treads: 22; Actual Riser Height: 181.818 mm
Identity Data - Workset: Workset1
Other - Family: Monolithic Run; Family and Type: Monolithic Run: ST_0 mm Nosing 200 Hout trap; Type: ST_0 mm Nosing 200 Hout trap; Type Id: 1495241

# IfcStairFlight: Monolithic Run:ST_0 mm Nosing 200 Hout tribune, Assembled Stair:Stair:1495941 Run 1
In: 00 begane grond
Type - PredefinedType: STRAIGHT
Type - Risers - Riser: yes; Riser To Tread Connection: Extend Riser Behind Tread; Slanted: no; Riser Thickness: 62 mm
Type - Treads - Apply Nosing Profile: Front Only; Nosing Length: 0 mm; Tread: yes; Tread Thickness: 62 mm
Type - Materials and Finishes - Monolithic Material: ISR_Hout; Riser Material: ISR_Hout; Tread Material: ISR_Hout
Type - Construction - Underside Surface: Smooth; Structural Depth: 12.4 mm
Type - Identity Data - Workset: Stair Types; Type Name: ST_0 mm Nosing 200 Hout tribune
Type - Other - Category: Stairs: Runs; Family Name: Monolithic Run
NumberOfRiser: 11; NumberOfTreads: 11; RiserHeight: 1.19303 mm; TreadLength: 1.70604 mm; Classification: 24.10 Uniformat (Uniformat); Material: ISR_Hout
Constraints - Location Line: Run: Center; Relative Base Height: 0 mm; Relative Top Height: 4000 mm; Run Height: 4000 mm
Phasing - Phase Created: 2. nieuwbouw
Construction - Begin with Riser: yes; End with Riser: no; Extend Below Riser Base: 0 mm
Dimensions - Actual Number of Risers: 11; Actual Number of Treads: 11; Actual Riser Height: 363.636 mm; Actual Run Width: 2944.84 mm; Actual Tread Depth: 520 mm
Identity Data - Workset: Workset1
Other - Family: Monolithic Run; Family and Type: Monolithic Run: ST_0 mm Nosing 200 Hout tribune; Type: ST_0 mm Nosing 200 Hout tribune; Type Id: 1496709

# IfcStairFlight: Monolithic Run:ST_25 mm Nosing (5)
Type - PredefinedType: STRAIGHT
Type - Risers - Riser To Tread Connection: Extend Riser Behind Tread; Riser: no; Riser Thickness: 0 mm; Slanted: yes
Type - Treads - Apply Nosing Profile: Front Only; Tread: no; Tread Thickness: 0 mm; Nosing Length: 25 mm
Type - Materials and Finishes - Monolithic Material: f2_beton_prefab_gen
Type - Construction - Underside Surface: Smooth; Structural Depth: 150 mm
Type - Identity Data - Workset: Stair Types; Type Name: ST_25 mm Nosing
Type - Other - Category: Stairs: Runs; Family Name: Monolithic Run
TreadLength: 0.721785 mm; Classification: 24.10 Uniformat (Uniformat); Material: f2_beton_prefab_gen
Constraints - Location Line: Run: Center
Phasing - Phase Created: 2. nieuwbouw
Dimensions - Actual Tread Depth: 220 mm
Identity Data - Workset: Workset1
Other - Family: Monolithic Run; Family and Type: Monolithic Run: ST_25 mm Nosing; Type: ST_25 mm Nosing; Type Id: 18182
Name (Cast-In-Place Stair:Stair:...) | In | NumberOfRiser = Actual Number of Risers | NumberOfTreads = Actual Number of Treads | RiserHeight (mm) | Relative Base Height (mm) | Relative Top Height (mm) | Run Height (mm) | Begin with Riser | End with Riser | Actual Riser Height (mm) | Actual Run Width (mm)
1615872 Run 1 | 01 eerste verdieping | 11 | 10 | 0.62336 | 0 | 2090 | 2090 | yes | yes | 190 | 930 | Construction - Extend Below Riser Base: 0 mm
1615872 Run 2 | 01 eerste verdieping | 9 | 10 | 0.62336 | 2090 | 3800 | 1710 | no | no | 190 | 930
1769840 Run 1 | 00 begane grond | 2 | 1 | 0.624922 | 0 | 380.952 | 380.952 | yes | yes | 190.476 | 850 | Construction - Extend Below Riser Base: 0 mm
1769840 Run 2 | 00 begane grond | 10 | 9 | 0.624922 | 380.952 | 2285.71 | 1904.76 | yes | yes | 190.476 | 930
1769840 Run 3 | 00 begane grond | 9 | 9 | 0.624922 | 2285.71 | 4000 | 1714.29 | yes | no | 190.476 | 930

# IfcStairFlight: Non-Monolithic Run:ST_28 mm Tread 10 mm Nosing 28 mm Riser, Assembled Stair:Stair:3030916 Run 1
In: 01 eerste verdieping
Type - PredefinedType: STRAIGHT
Type - Risers - Riser: yes; Riser To Tread Connection: Extend Riser Behind Tread; Slanted: yes; Riser Profile: NLRS_PR_stootbord_schuin_hout_bdg : NLRS_PR_stootbord_schuin_hout_bdg; Riser Thickness: 20 mm
Type - Treads - Apply Nosing Profile: Front Only; Nosing Length: 0 mm; Tread: yes; Nosing Profile: NLRS_PR_tredeneud_hout_bdg : NLRS_PR_tredeneud_hout_bdg; Tread Profile: 00_ISR_p_rechthoek_trede : 280x40; Tread Thickness: 40 mm
Type - Materials and Finishes - Riser Material: i4_hout_gen; Tread Material: i4_hout_gen
Type - Identity Data - Workset: Stair Types; Type Name: ST_28 mm Tread 10 mm Nosing 28 mm Riser
Type - Other - Category: Stairs: Runs; Family Name: Non-Monolithic Run
NumberOfRiser: 21; NumberOfTreads: 21; RiserHeight: 0.593676 mm; TreadLength: 0.787402 mm; Classification: 24.10 Uniformat (Uniformat); Material: i4_hout_gen
Constraints - Location Line: Run: Center; Relative Base Height: 0 mm; Relative Top Height: 3800 mm; Run Height: 3800 mm
Phasing - Phase Created: 2. nieuwbouw
Construction - Begin with Riser: yes; End with Riser: no; Extend Below Riser Base: 0 mm
Dimensions - Actual Number of Risers: 21; Actual Number of Treads: 21; Actual Riser Height: 180.952 mm; Actual Run Width: 1500 mm; Actual Tread Depth: 240 mm
Identity Data - Workset: Workset1
Other - Family: Non-Monolithic Run; Family and Type: Non-Monolithic Run: ST_28 mm Tread 10 mm Nosing 28 mm Riser; Type: ST_28 mm Tread 10 mm Nosing 28 mm Riser; Type Id: 2196520

# IfcStairFlight: Non-Monolithic Run:houten treden + stootborden, Assembled Stair:Stair:1307534 Run 1
In: 01 eerste verdieping
Type - PredefinedType: STRAIGHT
Type - Risers - Riser: yes; Riser Thickness: 20 mm; Riser To Tread Connection: Extend Riser Behind Tread; Slanted: no
Type - Treads - Apply Nosing Profile: Front Only; Nosing Length: 0 mm; Tread: yes; Tread Thickness: 40 mm
Type - Materials and Finishes - Riser Material: i4_hout_gen; Tread Material: i4_hout_gen
Type - Identity Data - Workset: Stair Types; Type Name: houten treden + stootborden
Type - Other - Category: Stairs: Runs; Family Name: Non-Monolithic Run
NumberOfRiser: 21; NumberOfTreads: 21; RiserHeight: 0.595707 mm; TreadLength: 0.853018 mm; Classification: 24.10 Uniformat (Uniformat); Material: i4_hout_gen
Constraints - Location Line: Run: Center; Relative Base Height: 0 mm; Relative Top Height: 3813 mm; Run Height: 3813 mm
Phasing - Phase Created: 2. nieuwbouw
Construction - Begin with Riser: yes; End with Riser: no; Extend Below Riser Base: 0 mm
Dimensions - Actual Number of Risers: 21; Actual Number of Treads: 21; Actual Riser Height: 181.571 mm; Actual Run Width: 2705 mm; Actual Tread Depth: 260 mm
Identity Data - Workset: Workset1
Other - Family: Non-Monolithic Run; Family and Type: Non-Monolithic Run: houten treden + stootborden; Type: houten treden + stootborden; Type Id: 3076765

# IfcWall: 41_GM_fb_rollaag_metselwerk_middel:h=419 (10)
In: 03 derde verdieping
Type - Material: g2_metselwerk_geel_staand
Type - Constraints(Type) - Default Elevation: 1219.2 mm
Type - Materials and Finishes(Type) - materiaal: g2_metselwerk_geel_staand
Type - Dimensions(Type) - hoogte_rollaag: 419 mm
Type - Identity Data(Type) - Assembly Code: 2D(21.11.11); Type Comments: BS; Type Name: h=419; Workset: Family : Generic Models : 41_GM_fb_rollaag_metselwerk_middel
Type - Other(Type) - Category: Generic Models; Family Name: 41_GM_fb_rollaag_metselwerk_middel
Classification: 2D(21.11.11) Uniformat (Uniformat)
Constraints - Level: 03 derde verdieping; Schedule Level: 03 derde verdieping
Phasing - Phase Created: 2. nieuwbouw
Identity Data - Workset: Workset1
Other - Category: Generic Models; Family: 41_GM_fb_rollaag_metselwerk_middel; Family and Type: 41_GM_fb_rollaag_metselwerk_middel: h=419; Type: h=419; Type Id: 2236802
Name (41_GM_fb_rollaag_metselwerk_middel:h=419:...) | Elevation from Level (mm) | Host | Area (m2) | hoek_a (deg) | hoek_b (deg) | lengte (mm) | Volume (m3) | ber_overstek_a (mm) | ber_overstek_b (mm) | ber_hoek_a (deg) | ber_hoek_a+180 (deg) | ber_hoek_b+180 (deg)
2236807 | -10237.6 | Basic Wall : 21_WA_metselwerk_middel_100_gen_bdg | 1.4843 | 26.77 | 18.23 | 2946.9 | 0.116156 | 0 | 0 | -26.77 | 153.23 | -161.77
2237196 | -8486 | Basic Wall : 21_WA_metselwerk_middel_100_gen_bdg | 0.424711 | 18.24 | -18.23 | 733.366 | 0.0307263 | 0 | 138.003 | -18.24 | 161.76 | -198.23
2237537 | -8486.02 | Basic Wall : 21_WA_metselwerk_middel_100_gen_bdg | 1.49446 | -18.23 | 18.23 | 2794.5 | 0.11709 | 138.003 | 0 | 18.23 | 198.23 | -161.77
2237933 | -11620 | Basic Wall : 21_WA_metselwerk_middel_100_gen_bdg | 0.707028 | 0 | 26.77 | 1382.4 | 0.0534942 | 0 | 0 | 0 | 180 | -153.23
2238530 | -6825 | Basic Wall : 21_WA_metselwerk_middel_100_gen_bdg | 0.717924 | 18.23 | 0 | 1369.42 | 0.0544875 | 0 | 0 | -18.23 | 161.77 | -180
2239204 | -11620 | <not associated> | 0.707028 | 0 | 26.77 | 1382.4 | 0.0534942 | 0 | 0 | 0 | 180 | -153.23
4728604 | -10237.6 | <not associated> | 1.4843 | 26.77 | 18.23 | 2946.9 | 0.116156 | 0 | 0 | -26.77 | 153.23 | -161.77
4728605 | -8486 | <not associated> | 0.424711 | 18.24 | -18.23 | 733.366 | 0.0307263 | 0 | 138.003 | -18.24 | 161.76 | -198.23
4728606 | -8486.02 | <not associated> | 1.49446 | -18.23 | 18.23 | 2794.5 | 0.11709 | 138.003 | 0 | 18.23 | 198.23 | -161.77
4728607 | -6825 | <not associated> | 0.717924 | 18.23 | 0 | 1369.42 | 0.0544875 | 0 | 0 | -18.23 | 161.77 | -180

# IfcWall: Basic Wall:21_WA_metselwerk_middel_100_gen_bdg, Basic Wall:21_WA_metselwerk_middel_100_gen_bdg:1341908
In: 00 begane grond
Type - PredefinedType: STANDARD; Material: g2_metselwerk_geel 100 mm
Type - Analytical Properties - Roughness: 1; Absorptance: 0.1; Heat Transfer Coefficient (U): 5.4 kg/K/s3; Thermal Mass: 130.2; Thermal Resistance (R): 0.185185
Type - Materials and Finishes - Structural Material: g2_metselwerk_geel
Type - Graphics - Coarse Scale Fill Pattern: <Solid fill>; Coarse Scale Fill Color: 4210752
Type - Construction - Wrapping at Inserts: Do not wrap; Function: Exterior; Width: 100 mm
Type - Identity Data - Workset: Wall Types; Assembly Code: 2D(21.11.11); Datum_Gewijzigd: 26-05-2014; Description: horizontaal metselwerk D=100 mm; Model: LOD300; SmartRevit_Versie: 2015.1; Type Comments: hatch; Type Name: 21_WA_metselwerk_middel_100_gen_bdg
Type - Other - Category: Walls; Family Name: Basic Wall
Classification: 2D(21.11.11) Uniformat (Uniformat)
Cross-Section Definition - Cross-Section: Vertical
Constraints - Base Extension Distance: 0 mm; Base is Attached: no; Location Line: Finish Face: Exterior; Related to Mass: no; Room Bounding: yes; Top Extension Distance: 0 mm; Top is Attached: no; Base Constraint: bk. fundering; Base Offset: 0 mm; Top Constraint: Up to level: 00 begane grond; Top Offset: 3433 mm; Unconnected Height: 3953 mm
Phasing - Phase Created: 2. nieuwbouw
Structural - Enable Analytical Model: no; Structural: no; Structural Usage: Non-bearing
Dimensions - Area: 1.69979 m2; Length: 430 mm; Volume: 0.159492 m3
Identity Data - Workset: Workset1
Other - Family: Basic Wall; Family and Type: Basic Wall: 21_WA_metselwerk_middel_100_gen_bdg; Type: 21_WA_metselwerk_middel_100_gen_bdg; Type Id: 587139

# IfcWall: Basic Wall:22_WA_ aftimmering gips_22-13 _gen_bdg, Basic Wall:22_WA_ aftimmering gips_22-13 _gen_bdg:3431083
In: 00 begane grond
Type - PredefinedType: STANDARD; Material: f7_gipsvezel 12.5 mm, ISR_Luchtspouw 22 mm
Type - Analytical Properties - Roughness: 1; Absorptance: 0.1
Type - Materials and Finishes - Structural Material: ISR_Luchtspouw
Type - Graphics - Coarse Scale Fill Pattern: <Solid fill>; Coarse Scale Fill Color: 12632256
Type - Construction - Function: Interior; Wrapping at Inserts: Do not wrap; Wrapping at Ends: Exterior; Width: 34.5 mm
Type - Identity Data - Workset: Wall Types; Assembly Code: 2E(22.11); Datum_Gewijzigd: 26-05-2014; Description: Binnenwand 100mm; Model: LOD300; SmartRevit_Versie: 2015.1; Type Name: 22_WA_ aftimmering gips_22-13 _gen_bdg
Type - Other - Category: Walls; Family Name: Basic Wall
Classification: 2E(22.11) Uniformat (Uniformat)
Cross-Section Definition - Cross-Section: Slanted; Angle From Vertical: -55.03 deg
Constraints - Base Extension Distance: 0 mm; Base is Attached: no; Related to Mass: no; Top Extension Distance: 0 mm; Top is Attached: no; Base Constraint: 00 begane grond; Top Constraint: Up to level: 00 begane grond; Room Bounding: no; Location Line: Finish Face: Interior; Base Offset: 1220 mm; Top Offset: 2850 mm; Unconnected Height: 1630 mm
Phasing - Phase Created: 2. nieuwbouw
Structural - Enable Analytical Model: no; Structural: no; Structural Usage: Non-bearing
Dimensions - Area: 11.4606 m2; Length: 4029.84 mm; Volume: 0.395392 m3
Identity Data - Workset: Workset1
Other - Family: Basic Wall; Family and Type: Basic Wall: 22_WA_ aftimmering gips_22-13 _gen_bdg; Type: 22_WA_ aftimmering gips_22-13 _gen_bdg; Type Id: 3430992

# IfcWall: Basic Wall:22_WA_binnenwand_ms350 25-300-25 _gen_bdg, Basic Wall:22_WA_binnenwand_ms350 25-300-25 _gen_bdg:2493344
In: 00 begane grond
Type - PredefinedType: STANDARD; Material: f7_gipsvezel 12.5 mm, f7_gips 12.5 mm, n7_isolatie_glaswol 300 mm, f7_gips 12.5 mm, f7_gipsvezel 12.5 mm
Type - Analytical Properties - Roughness: 1; Absorptance: 0.1
Type - Materials and Finishes - Structural Material: f7_gipsvezel
Type - Graphics - Coarse Scale Fill Pattern: <Solid fill>; Coarse Scale Fill Color: 12632256
Type - Construction - Function: Interior; Wrapping at Inserts: Do not wrap; Width: 350 mm
Type - Identity Data - Workset: Wall Types; Assembly Code: 2E(22.11); Datum_Gewijzigd: 26-05-2014; Description: Binnenwand 100mm; Model: LOD300; SmartRevit_Versie: 2015.1; Type Name: 22_WA_binnenwand_ms350 25-300-25 _gen_bdg
Type - Other - Category: Walls; Family Name: Basic Wall
Classification: 2E(22.11) Uniformat (Uniformat)
Cross-Section Definition - Cross-Section: Vertical
Constraints - Base Extension Distance: 0 mm; Base is Attached: no; Related to Mass: no; Room Bounding: yes; Top Extension Distance: 0 mm; Top is Attached: no; Base Constraint: 00 begane grond; Top Constraint: Up to level: 01 ok. ruwe vloer; Base Offset: 0 mm; Location Line: Wall Centerline; Top Offset: -274.5 mm; Unconnected Height: 3355.5 mm
Phasing - Phase Created: 2. nieuwbouw
Structural - Enable Analytical Model: no; Structural: no; Structural Usage: Non-bearing
Dimensions - Area: 9.40644 m2; Length: 5375 mm; Volume: 3.26079 m3
Identity Data - Workset: Workset1
Other - Family: Basic Wall; Family and Type: Basic Wall: 22_WA_binnenwand_ms350 25-300-25 _gen_bdg; Type: 22_WA_binnenwand_ms350 25-300-25 _gen_bdg; Type Id: 2493111

# IfcWall: Basic Wall:22_WA_binnenwand_ms75 25-50 _gen_bdg (3)
In: 00 begane grond
Type - PredefinedType: STANDARD; Material: n7_isolatie_glaswol 50 mm, f7_gips 12.5 mm, f7_gipsvezel 12.5 mm
Type - Analytical Properties - Roughness: 1; Absorptance: 0.1
Type - Materials and Finishes - Structural Material: f7_gipsvezel
Type - Graphics - Coarse Scale Fill Pattern: <Solid fill>; Coarse Scale Fill Color: 12632256
Type - Construction - Function: Interior; Wrapping at Inserts: Do not wrap; Wrapping at Ends: Exterior; Width: 75 mm
Type - Identity Data - Workset: Wall Types; Assembly Code: 2E(22.11); Datum_Gewijzigd: 26-05-2014; Description: Binnenwand 100mm; Model: LOD300; SmartRevit_Versie: 2015.1; Type Name: 22_WA_binnenwand_ms75 25-50 _gen_bdg
Type - Other - Category: Walls; Family Name: Basic Wall
Classification: 2E(22.11) Uniformat (Uniformat)
Cross-Section Definition - Cross-Section: Slanted
Constraints - Base Extension Distance: 0 mm; Base is Attached: no; Location Line: Finish Face: Exterior; Related to Mass: no; Room Bounding: yes; Top Extension Distance: 0 mm; Top is Attached: no; Base Constraint: 00 begane grond; Top Constraint: Up to level: 00 begane grond
Phasing - Phase Created: 2. nieuwbouw
Structural - Enable Analytical Model: no; Structural: no; Structural Usage: Non-bearing
Identity Data - Workset: Workset1
Other - Family: Basic Wall; Family and Type: Basic Wall: 22_WA_binnenwand_ms75 25-50 _gen_bdg; Type: 22_WA_binnenwand_ms75 25-50 _gen_bdg; Type Id: 2740145
Name (Basic Wall:22_WA_binnenwand_ms75 25-50 _gen_bdg:...) | Angle From Vertical (deg) | Base Offset (mm) | Top Offset (mm) | Unconnected Height (mm) | Area (m2) | Length (mm) | Volume (m3)
2740949 | -49.114 | 900 | 2036 | 1136 | 1.86063 | 1072.5 | 0.134429
3066478 | -49.114 | 1960.71 | 3370 | 1409.29 | 2.06692 | 960 | 0.149914
3267569 | 55.55 | 1319.47 | 2050 | 730.527 | 0.79421 | 615 | 0.0595658

# IfcWall: Basic Wall:22_WA_koof_96 12-12-50, Basic Wall:22_WA_koof_96 12-12-50:2173515
In: 01 eerste verdieping
Type - PredefinedType: STANDARD; Material: f7_gipsvezel 12.5 mm, f7_gips 12.5 mm, ISR_Luchtspouw 50 mm
Type - Analytical Properties - Roughness: 1; Absorptance: 0.1
Type - Graphics - Coarse Scale Fill Pattern: <Solid fill>; Coarse Scale Fill Color: 12632256
Type - Construction - Function: Interior; Wrapping at Inserts: Do not wrap; Width: 75 mm
Type - Identity Data - Workset: Wall Types; Assembly Code: 2E(22.11); Datum_Gewijzigd: 26-05-2014; Description: Binnenwand 125mm; Model: LOD300; SmartRevit_Versie: 2015.1; Type Name: 22_WA_koof_96 12-12-50
Type - Other - Category: Walls; Family Name: Basic Wall
Classification: 2E(22.11) Uniformat (Uniformat)
Cross-Section Definition - Angle From Vertical: -25.5 deg; Cross-Section: Slanted
Constraints - Base Extension Distance: 0 mm; Base is Attached: no; Location Line: Finish Face: Exterior; Related to Mass: no; Room Bounding: yes; Top Extension Distance: 0 mm; Top is Attached: no; Base Constraint: 01 eerste verdieping; Top Constraint: Up to level: 01 eerste verdieping; Base Offset: -50 mm; Top Offset: 850 mm; Unconnected Height: 900 mm
Phasing - Phase Created: 2. nieuwbouw
Structural - Enable Analytical Model: no; Structural: no; Structural Usage: Non-bearing
Dimensions - Area: 2.1937 m2; Length: 2200 mm; Volume: 0.164527 m3
Identity Data - Workset: Workset1
Other - Family: Basic Wall; Family and Type: Basic Wall: 22_WA_koof_96 12-12-50; Type: 22_WA_koof_96 12-12-50; Type Id: 3292293

# IfcWall: Basic Wall:NLRS_22_WA_HSB bispouw 30-245-12-13 glaswol_gen_ISR, Basic Wall:NLRS_22_WA_HSB bispouw 30-245-12-13 glaswol_gen_ISR:772579
In: 01 eerste verdieping
Type - PredefinedType: STANDARD; Material: n7_isolatie_glaswol 30 mm, n7_isolatie_glaswol 245 mm, i4_multiplex 12 mm, f7_gipsvezel 13 mm
Type - Analytical Properties - Absorptance: 0.1; Roughness: 1
Type - Materials and Finishes - Structural Material: n7_isolatie_glaswol
Type - Graphics - Coarse Scale Fill Color: 4210752; Coarse Scale Fill Pattern: <Solid fill>
Type - Construction - Function: Interior; Width: 300 mm; Wrapping at Inserts: Do not wrap
Type - Identity Data - Assembly Code: 21.10; Assembly Description: buitenwanden; niet constructief, algemeen (verzamelniveau); Description: gevelsluitend element; SmartRevit_Versie: 2018.2; Type Name: NLRS_22_WA_HSB bispouw 30-245-12-13 glaswol_gen_ISR; Workset: Wall Types
Type - Other - Category: Walls; Family Name: Basic Wall
Classification: 21.10 Uniformat (Uniformat)
Cross-Section Definition - Cross-Section: Vertical
Constraints - Base Extension Distance: 0 mm; Base is Attached: no; Location Line: Finish Face: Exterior; Related to Mass: no; Room Bounding: yes; Top Extension Distance: 0 mm; Top is Attached: no; Base Constraint: 01 eerste verdieping; Top Constraint: Up to level: 02 ok. ruwe vloer; Base Offset: -30 mm; Top Offset: -375 mm; Unconnected Height: 3085 mm
Phasing - Phase Created: 2. nieuwbouw
Structural - Enable Analytical Model: no; Structural: no; Structural Usage: Non-bearing
Dimensions - Area: 20.511 m2; Length: 16357.5 mm; Volume: 4.02853 m3
Identity Data - Workset: Workset1
Other - Family: Basic Wall; Family and Type: Basic Wall: NLRS_22_WA_HSB bispouw 30-245-12-13 glaswol_gen_ISR; Type: NLRS_22_WA_HSB bispouw 30-245-12-13 glaswol_gen_ISR; Type Id: 474264

# IfcWall: Basic Wall:NLRS_41_WA_vezelcement voorzet 10+160_gen_ISR, Basic Wall:NLRS_41_WA_vezelcement voorzet 10+160_gen_ISR:3345572
In: 01 eerste verdieping
Type - PredefinedType: STANDARD; Material: ISR_Vezelcement 10 mm, ISR_Luchtspouw 160 mm
Type - Analytical Properties - Roughness: 1; Absorptance: 0.1
Type - Graphics - Coarse Scale Fill Pattern: <Solid fill>; Coarse Scale Fill Color: 4210752
Type - Construction - Function: Interior; Wrapping at Inserts: Do not wrap; Width: 170 mm
Type - Identity Data - Workset: Wall Types; Assembly Code: 41.12; Assembly Description: buitenwandafwerkingen; bekledingen; Description: beplating 12mm; Model: LOD300; SmartRevit_Versie: 2018.2; Type Name: NLRS_41_WA_vezelcement voorzet 10+160_gen_ISR
Type - Other - Category: Walls; Family Name: Basic Wall
Classification: 41.12 Uniformat (Uniformat)
Cross-Section Definition - Cross-Section: Vertical
Constraints - Base Extension Distance: 0 mm; Base is Attached: no; Related to Mass: no; Room Bounding: yes; Top Extension Distance: 0 mm; Top is Attached: no; Base Constraint: 01 eerste verdieping; Top Constraint: Up to level: 01 eerste verdieping; Location Line: Finish Face: Interior; Base Offset: 231.135 mm; Top Offset: 775 mm; Unconnected Height: 543.865 mm
Phasing - Phase Created: 2. nieuwbouw
Structural - Enable Analytical Model: no; Structural: no; Structural Usage: Non-bearing
Dimensions - Area: 8.57521 m2; Length: 16188.9 mm; Volume: 1.4405 m3
Identity Data - Workset: Workset1
Other - Family: Basic Wall; Family and Type: Basic Wall: NLRS_41_WA_vezelcement voorzet 10+160_gen_ISR; Type: NLRS_41_WA_vezelcement voorzet 10+160_gen_ISR; Type Id: 3345411

# IfcWallStandardCase: Basic Wall:16_FU_poeren_300x500 (17)
In: 00 begane grond
Type - PredefinedType: STANDARD; Material: f2_beton ihwg_gen 200 mm
Type - Analytical Properties - Roughness: 1; Absorptance: 0.1
Type - Materials and Finishes - Structural Material: f2_beton ihwg_gen
Type - Graphics - Coarse Scale Fill Pattern: <Solid fill>; Coarse Scale Fill Color: 4210752
Type - Construction - Wrapping at Inserts: Do not wrap; Function: Exterior; Width: 200 mm
Type - Identity Data - Workset: Wall Types; Assembly Code: 2D(21.10); Datum_Gewijzigd: 26-05-2014; Description: beton poeren; Model: LOD300; SmartRevit_Versie: 2015.1; Type Comments: hatch; Type Name: 16_FU_poeren_300x500
Type - Other - Category: Walls; Family Name: Basic Wall
Classification: 2D(21.10) Uniformat (Uniformat); Group: Model Group:fietsenstalling:4188142
Cross-Section Definition - Cross-Section: Vertical
Constraints - Base Extension Distance: 0 mm; Base is Attached: no; Related to Mass: no; Room Bounding: yes; Top Extension Distance: 0 mm; Top is Attached: no; Base Constraint: bk. fundering; Base Offset: 0 mm; Top Constraint: Up to level: 00 begane grond; Location Line: Wall Centerline; Top Offset: -20 mm; Unconnected Height: 500 mm
Phasing - Phase Created: 2. nieuwbouw
Structural - Enable Analytical Model: no; Structural: no; Structural Usage: Non-bearing
Dimensions - Area: 0.1 m2; Length: 200 mm; Volume: 0.02 m3
Identity Data - Workset: BDG_fietsenstalling
Other - Family: Basic Wall; Family and Type: Basic Wall: 16_FU_poeren_300x500; Type: 16_FU_poeren_300x500; Type Id: 4068313
Name (Basic Wall:16_FU_poeren_300x500:...)
4068367
4068609
4068867
4068868
4068877
4068878
4068887
4068888
4068899
4068900
4068909
4068910
4116155
4116275
4116286
4116368
4116377

# IfcWallStandardCase: Basic Wall:21_WA_isolatie glaswol_150_gen_bdg, Basic Wall:21_WA_isolatie glaswol_150_gen_bdg:3379201
In: 01 eerste verdieping
Type - PredefinedType: STANDARD; Material: n7_isolatie_glaswol 150 mm
Type - Analytical Properties - Roughness: 1; Absorptance: 0.1
Type - Graphics - Coarse Scale Fill Pattern: <Solid fill>; Coarse Scale Fill Color: 4210752
Type - Construction - Wrapping at Inserts: Do not wrap; Function: Exterior; Width: 150 mm
Type - Identity Data - Workset: Wall Types; Assembly Code: 2D(21.10); Datum_Gewijzigd: 26-05-2014; Description: isolatie D=138 mm luchtspouw; Model: LOD300; SmartRevit_Versie: 2015.1; Type Comments: hatch; Type Name: 21_WA_isolatie glaswol_150_gen_bdg
Type - Other - Category: Walls; Family Name: Basic Wall
Classification: 2D(21.10) Uniformat (Uniformat)
Cross-Section Definition - Cross-Section: Vertical
Constraints - Base Extension Distance: 0 mm; Base is Attached: no; Related to Mass: no; Room Bounding: yes; Top Extension Distance: 0 mm; Top is Attached: no; Base Constraint: 01 eerste verdieping; Top Constraint: Up to level: 01 eerste verdieping; Location Line: Core Face: Exterior; Base Offset: -755 mm; Top Offset: 50 mm; Unconnected Height: 805 mm
Phasing - Phase Created: 2. nieuwbouw
Structural - Enable Analytical Model: no; Structural: no; Structural Usage: Non-bearing
Dimensions - Area: 4.08037 m2; Length: 5160 mm; Volume: 0.612056 m3
Identity Data - Workset: Workset1
Other - Family: Basic Wall; Family and Type: Basic Wall: 21_WA_isolatie glaswol_150_gen_bdg; Type: 21_WA_isolatie glaswol_150_gen_bdg; Type Id: 4832227

# IfcWallStandardCase: Basic Wall:21_WA_isolatie_100_gen_bdg (4)
In: 00 begane grond
Type - PredefinedType: STANDARD; Material: n7_isolatie_PIR 100 mm
Type - Analytical Properties - Roughness: 1; Absorptance: 0.1
Type - Materials and Finishes - Structural Material: n7_isolatie_PIR
Type - Graphics - Coarse Scale Fill Pattern: <Solid fill>; Coarse Scale Fill Color: 4210752
Type - Construction - Wrapping at Inserts: Do not wrap; Function: Exterior; Width: 100 mm
Type - Identity Data - Workset: Wall Types; Assembly Code: 2D(21.10); Datum_Gewijzigd: 26-05-2014; Description: PIR isolatie; Model: LOD300; SmartRevit_Versie: 2015.1; Type Comments: hatch; Type Name: 21_WA_isolatie_100_gen_bdg
Type - Other - Category: Walls; Family Name: Basic Wall
Classification: 2D(21.10) Uniformat (Uniformat)
Cross-Section Definition - Cross-Section: Vertical
Constraints - Base Extension Distance: 0 mm; Base is Attached: no; Related to Mass: no; Room Bounding: yes; Top Extension Distance: 0 mm; Top is Attached: no
Phasing - Phase Created: 2. nieuwbouw
Structural - Enable Analytical Model: no; Structural: no; Structural Usage: Non-bearing
Identity Data - Workset: Workset1
Other - Family: Basic Wall; Family and Type: Basic Wall: 21_WA_isolatie_100_gen_bdg; Type: 21_WA_isolatie_100_gen_bdg; Type Id: 3178307
Name (Basic Wall:21_WA_isolatie_100_gen_bdg:...) | Base Constraint | Top Constraint | Location Line | Base Offset (mm) | Top Offset (mm) | Unconnected Height (mm) | Area (m2) | Length (mm) | Volume (m3)
3178303 | 00 begane grond | Up to level: 00 begane grond | Core Face: Interior | -520 | -30 | 490 | 2.51443 | 5081.5 | 0.251443
3178305 | 00 begane grond | Up to level: 00 begane grond | Core Face: Interior | -520 | -30 | 490 | 11.1548 | 22765 | 1.11548
3178306 | 00 begane grond | Up to level: 00 begane grond | Core Face: Interior | -520 | -30 | 490 | 7.05404 | 14446 | 0.705404
3357855 | 01 ok. ruwe vloer | Up to level: 01 ok. ruwe vloer | Finish Face: Interior | -1410 | -410 | 1000 | 0.29 | 290 | 0.029

# IfcWallStandardCase: Basic Wall:21_WA_isolatie_160_gen_bdg (3)
In: 02 tweede verdieping
Type - PredefinedType: STANDARD; Material: ISR_Isolatie 160 mm
Type - Analytical Properties - Roughness: 1; Absorptance: 0.1
Type - Materials and Finishes - Structural Material: ISR_Isolatie
Type - Graphics - Coarse Scale Fill Pattern: <Solid fill>; Coarse Scale Fill Color: 4210752
Type - Construction - Wrapping at Inserts: Do not wrap; Function: Exterior; Width: 160 mm
Type - Identity Data - Workset: Wall Types; Assembly Code: 2D(21.10); Datum_Gewijzigd: 26-05-2014; Description: isolatie D=138 mm luchtspouw; Model: LOD300; SmartRevit_Versie: 2015.1; Type Comments: hatch; Type Name: 21_WA_isolatie_160_gen_bdg
Type - Other - Category: Walls; Family Name: Basic Wall
Classification: 2D(21.10) Uniformat (Uniformat)
Cross-Section Definition - Cross-Section: Vertical
Constraints - Base Constraint: 02 tweede verdieping; Base Extension Distance: 0 mm; Base is Attached: no; Related to Mass: no; Room Bounding: yes; Top Extension Distance: 0 mm; Top is Attached: no; Top Constraint: Up to level: 02 tweede verdieping; Base Offset: -50 mm; Location Line: Core Face: Interior
Phasing - Phase Created: 2. nieuwbouw
Structural - Enable Analytical Model: no; Structural: no; Structural Usage: Non-bearing
Identity Data - Workset: Workset1
Other - Family: Basic Wall; Family and Type: Basic Wall: 21_WA_isolatie_160_gen_bdg; Type: 21_WA_isolatie_160_gen_bdg; Type Id: 587141
Name (Basic Wall:21_WA_isolatie_160_gen_bdg:...) | Top Offset (mm) | Unconnected Height (mm) | Area (m2) | Length (mm) | Volume (m3)
880007 | 600 | 650 | 2.8145 | 4410 | 0.45032
880008 | 603 | 653 | 4.62324 | 7080 | 0.739718
880009 | 570 | 620 | 13.0727 | 21055 | 2.09163

# IfcWallStandardCase: Basic Wall:21_WA_isolatie_50_gen_bdg (3)
In: 00 begane grond
Type - PredefinedType: STANDARD; Material: n7_isolatie_PIR 50 mm
Type - Analytical Properties - Roughness: 1; Absorptance: 0.1
Type - Materials and Finishes - Structural Material: n7_isolatie_PIR
Type - Graphics - Coarse Scale Fill Pattern: <Solid fill>; Coarse Scale Fill Color: 4210752
Type - Construction - Wrapping at Inserts: Do not wrap; Function: Exterior; Width: 50 mm
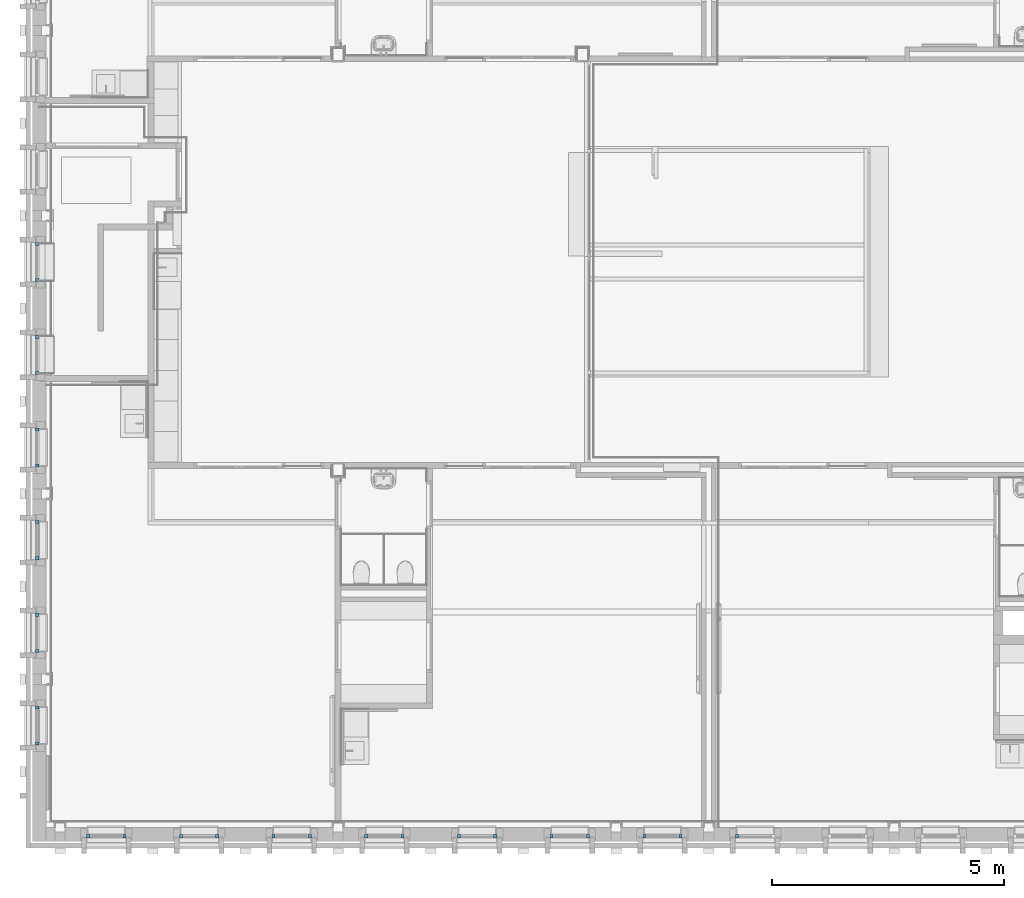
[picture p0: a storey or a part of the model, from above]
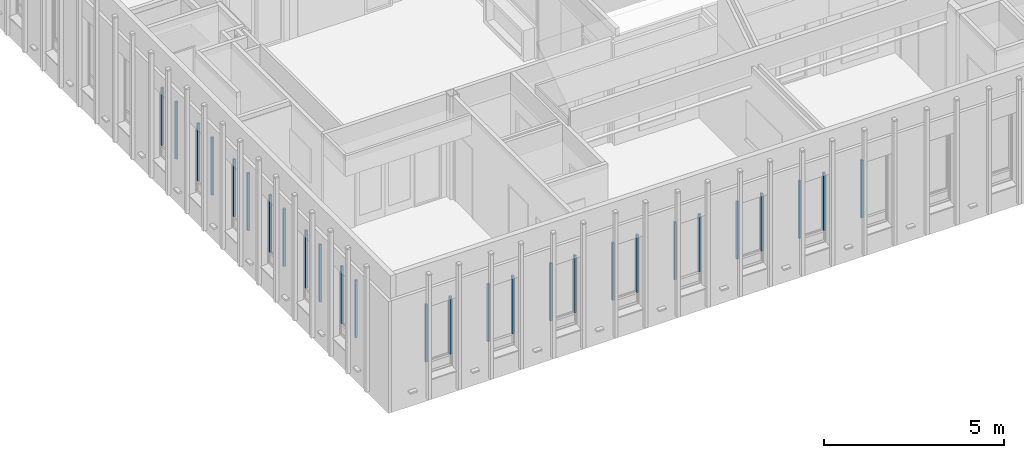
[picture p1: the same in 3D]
Properties of the parts of a building model (IFC2X3), part 84 of 94

# IfcWallStandardCase: Basic Wall:21_WA_isolatie_50_gen_bdg (3)
Type - Identity Data - Workset: Wall Types; Assembly Code: 2D(21.10); Datum_Gewijzigd: 26-05-2014; Description: PIR isolatie; Model: LOD300; SmartRevit_Versie: 2015.1; Type Comments: hatch; Type Name: 21_WA_isolatie_50_gen_bdg
Type - Other - Category: Walls; Family Name: Basic Wall
Classification: 2D(21.10) Uniformat (Uniformat)
Cross-Section Definition - Cross-Section: Vertical
Constraints - Base Extension Distance: 0 mm; Base is Attached: no; Related to Mass: no; Room Bounding: yes; Top Extension Distance: 0 mm; Top is Attached: no; Top Constraint: Up to level: 01 ok. ruwe vloer; Location Line: Finish Face: Interior; Base Constraint: 01 ok. ruwe vloer; Base Offset: -1410 mm; Top Offset: -410 mm; Unconnected Height: 1000 mm
Phasing - Phase Created: 2. nieuwbouw
Structural - Enable Analytical Model: no; Structural: no; Structural Usage: Non-bearing
Identity Data - Workset: Workset1
Other - Family: Basic Wall; Family and Type: Basic Wall: 21_WA_isolatie_50_gen_bdg; Type: 21_WA_isolatie_50_gen_bdg; Type Id: 3357746
Name (Basic Wall:21_WA_isolatie_50_gen_bdg:...) | Area (m2) | Length (mm) | Volume (m3)
3357800 | 0.34 | 290 | 0.017
3357832 | 0.34 | 315 | 0.017
3357893 | 0.24 | 315 | 0.012

# IfcWallStandardCase: Basic Wall:21_WA_metselwerk_donker 100_gen_bdg (62)
In: 00 begane grond
Type - PredefinedType: STANDARD; Material: g2_metselwerk_bruin 100 mm
Type - Analytical Properties - Roughness: 1; Absorptance: 0.1; Heat Transfer Coefficient (U): 5.4 kg/K/s3; Thermal Mass: 130.2; Thermal Resistance (R): 0.185185
Type - Materials and Finishes - Structural Material: g2_metselwerk_bruin
Type - Graphics - Coarse Scale Fill Pattern: <Solid fill>; Coarse Scale Fill Color: 4210752
Type - Construction - Wrapping at Inserts: Do not wrap; Function: Exterior; Width: 100 mm
Type - Identity Data - Workset: Wall Types; Assembly Code: 2D(21.11.11); Datum_Gewijzigd: 26-05-2014; Description: horizontaal metselwerk D=100 mm; Model: LOD300; SmartRevit_Versie: 2015.1; Type Comments: hatch; Type Name: 21_WA_metselwerk_donker 100_gen_bdg
Type - Other - Category: Walls; Family Name: Basic Wall
Classification: 2D(21.11.11) Uniformat (Uniformat)
Cross-Section Definition - Cross-Section: Vertical
Constraints - Base Extension Distance: 0 mm; Base is Attached: no; Related to Mass: no; Room Bounding: yes; Top Extension Distance: 0 mm; Top is Attached: no; Top Constraint: Up to level: 00 begane grond
Phasing - Phase Created: 2. nieuwbouw
Structural - Enable Analytical Model: no; Structural: no; Structural Usage: Non-bearing
Identity Data - Workset: Workset1
Other - Family: Basic Wall; Family and Type: Basic Wall: 21_WA_metselwerk_donker 100_gen_bdg; Type: 21_WA_metselwerk_donker 100_gen_bdg; Type Id: 892924
Name (Basic Wall:21_WA_metselwerk_donker 100_gen_bdg:...) | Location Line | Base Constraint | Base Offset (mm) | Top Offset (mm) | Unconnected Height (mm) | Area (m2) | Length (mm) | Volume (m3)
892491 | Finish Face: Exterior | bk. fundering | 0 | 3012 | 3532 | 1.766 | 500 | 0.1766
892492 | Finish Face: Exterior | bk. fundering | 0 | 3012 | 3532 | 2.43708 | 690 | 0.243708
892493 | Finish Face: Exterior | bk. fundering | 0 | 3012 | 3532 | 1.766 | 500 | 0.1766
892494 | Finish Face: Exterior | bk. fundering | 0 | 3012 | 3532 | 2.43708 | 690 | 0.243708
893289 | Finish Face: Exterior | bk. fundering | 0 | 3003 | 3523 | 2.7726 | 837 | 0.27726
893751 | Finish Face: Exterior | bk. fundering | 0 | 3003 | 3523 | 0.73983 | 160 | 0.073983
894666 | Finish Face: Exterior | bk. fundering | 0 | 3003 | 3523 | 1.31584 | 473.5 | 0.131584
894667 | Finish Face: Exterior | bk. fundering | 0 | 3003 | 3523 | 0.73983 | 160 | 0.073983
894708 | Finish Face: Exterior | bk. fundering | 0 | 3003 | 3523 | 0.73983 | 160 | 0.073983
897582 | Finish Face: Exterior | bk. fundering | 0 | 3003 | 3523 | 1.2718 | 461 | 0.12718
897583 | Finish Face: Exterior | bk. fundering | 0 | 3003 | 3523 | 0.73983 | 160 | 0.073983
897584 | Finish Face: Exterior | bk. fundering | 0 | 3003 | 3523 | 0.73983 | 160 | 0.073983
1219760 | Finish Face: Exterior | bk. fundering | 0 | 3003 | 3523 | 8.01483 | 2325 | 0.801483
1219761 | Finish Face: Exterior | bk. fundering | 0 | 3003 | 3523 | 0.73983 | 160 | 0.073983
1220712 | Finish Face: Exterior | bk. fundering | 0 | 3003 | 3523 | 3.78722 | 1125 | 0.378722
1220713 | Finish Face: Exterior | bk. fundering | 0 | 3003 | 3523 | 0.73983 | 160 | 0.073983
1221329 | Finish Face: Exterior | bk. fundering | 0 | 3003 | 3523 | 0.334685 | 195 | 0.0334685
1221330 | Finish Face: Exterior | bk. fundering | 0 | 3003 | 3523 | 0.73983 | 160 | 0.073983
1221331 | Finish Face: Exterior | bk. fundering | 0 | 3003 | 3523 | 0.73983 | 160 | 0.073983
1221606 | Finish Face: Exterior | bk. fundering | 0 | 3003 | 3523 | 2.73032 | 825 | 0.273032
1221607 | Finish Face: Exterior | bk. fundering | 0 | 3003 | 3523 | 0.73983 | 160 | 0.073983
1222342 | Finish Face: Exterior | bk. fundering | 0 | 3003 | 3523 | 7.6132 | 2261 | 0.76132
1222343 | Finish Face: Exterior | bk. fundering | 0 | 3003 | 3523 | 0.73983 | 160 | 0.073983
1222344 | Finish Face: Exterior | bk. fundering | 0 | 3003 | 3523 | 0.73983 | 160 | 0.073983
1223361 | Finish Face: Exterior | bk. fundering | 0 | 3003 | 3523 | 4.48654 | 1373.5 | 0.448654
1223362 | Finish Face: Exterior | bk. fundering | 0 | 3003 | 3523 | 0.73983 | 160 | 0.073983
1223363 | Finish Face: Exterior | bk. fundering | 0 | 3003 | 3523 | 0.73983 | 160 | 0.073983
1223875 | Finish Face: Exterior | bk. fundering | 0 | 3003 | 3523 | 5.66322 | 1557.5 | 0.566322
1223877 | Finish Face: Exterior | bk. fundering | 0 | 3003 | 3523 | 0.38753 | 160 | 0.038753
1224030 | Finish Face: Exterior | bk. fundering | 0 | 3003 | 3523 | 4.64331 | 1418 | 0.464331
1224031 | Finish Face: Exterior | bk. fundering | 0 | 3003 | 3523 | 0.73983 | 160 | 0.073983
1224032 | Finish Face: Exterior | bk. fundering | 0 | 3003 | 3523 | 0.73983 | 160 | 0.073983
1224082 | Finish Face: Exterior | bk. fundering | 0 | 3003 | 3523 | 8.58731 | 2437.5 | 0.858731
1324218 | Finish Face: Exterior | bk. fundering | 200 | 3003 | 3323 | 6.86518 | 5150 | 0.686518
1327566 | Finish Face: Exterior | bk. fundering | 0 | 3003 | 3523 | 9.96833 | 2879.5 | 0.996833
1341911 | Finish Face: Exterior | bk. fundering | 0 | 3003 | 3523 | 0.686985 | 145 | 0.0686985
1342096 | Finish Face: Exterior | bk. fundering | 0 | 3003 | 3523 | 19.8451 | 5633 | 1.98451
1342502 | Finish Face: Exterior | bk. fundering | 0 | 3003 | 3523 | 2.93994 | 884.5 | 0.293994
1343971 | Finish Face: Exterior | bk. fundering | 0 | 3003 | 3523 | 14.7578 | 4189 | 1.47578
1350230 | Finish Face: Exterior | bk. fundering | 0 | 3003 | 3523 | 4.43722 | 1309.5 | 0.443722
1502280 | Finish Face: Exterior | bk. fundering | 0 | 3003 | 3523 | 3.78722 | 1125 | 0.378722
1502319 | Finish Face: Exterior | bk. fundering | 0 | 3003 | 3523 | 0.73983 | 160 | 0.073983
1502714 | Finish Face: Exterior | bk. fundering | 0 | 3003 | 3523 | 14.7578 | 4189 | 1.47578
1502782 | Finish Face: Exterior | bk. fundering | 0 | 3003 | 3523 | 3.78722 | 1125 | 0.378722
1502783 | Finish Face: Exterior | bk. fundering | 0 | 3003 | 3523 | 0.73983 | 160 | 0.073983
1503214 | Finish Face: Exterior | bk. fundering | 0 | 3003 | 3523 | 11.1855 | 3225 | 1.11855
1503215 | Finish Face: Exterior | bk. fundering | 0 | 3003 | 3523 | 0.73983 | 160 | 0.073983
1823457 | Finish Face: Exterior | bk. fundering | 0 | 3003 | 3523 | 13.8612 | 3884.5 | 1.38612
1823750 | Finish Face: Exterior | bk. fundering | 0 | 3003 | 3523 | 2.76379 | 834.5 | 0.276379
1826256 | Finish Face: Exterior | bk. fundering | 0 | 3003 | 3523 | 3.78722 | 1125 | 0.378722
1826257 | Finish Face: Exterior | bk. fundering | 0 | 3003 | 3523 | 0.73983 | 160 | 0.073983
1862653 | Finish Face: Exterior | bk. fundering | 0 | 3003 | 3523 | 2.73033 | 825 | 0.273033
1862654 | Finish Face: Exterior | bk. fundering | 0 | 3003 | 3523 | 0.73983 | 160 | 0.073983
1863733 | Finish Face: Exterior | bk. fundering | 0 | 3003 | 3523 | 4.18356 | 1137.5 | 0.418356
1863734 | Finish Face: Exterior | bk. fundering | 0 | 3003 | 3523 | 0.38753 | 160 | 0.038753
1933272 | Finish Face: Exterior | bk. fundering | 0 | 3003 | 3523 | 3.83126 | 1137.5 | 0.383126
1933273 | Finish Face: Exterior | bk. fundering | 0 | 3003 | 3523 | 0.73983 | 160 | 0.073983
2041137 | Finish Face: Exterior | bk. fundering | 0 | 3003 | 3523 | 11.1855 | 3225 | 1.11855
2546447 | Finish Face: Exterior | bk. fundering | 0 | 3003 | 3523 | 0.66937 | 140 | 0.066937
4195563 | Wall Centerline | 00 begane grond | 0 | 3003 | 3003 | 10.3934 | 3461 | 1.03934
5094761 | Finish Face: Exterior | 00 begane grond | -320 | -65 | 255 | 0.31518 | 1236 | 0.031518
5094840 | Finish Face: Exterior | 00 begane grond | -320 | -65 | 255 | 0.502752 | 1971.58 | 0.0502752

# IfcWallStandardCase: Basic Wall:21_WA_metselwerk_donker_staand_100_gen_bdg (42)
In: 00 begane grond
Type - PredefinedType: STANDARD; Material: g2_metselwerk_bruin_ staand 100 mm
Type - Analytical Properties - Roughness: 1; Absorptance: 0.1; Heat Transfer Coefficient (U): 5.4 kg/K/s3; Thermal Mass: 130.2; Thermal Resistance (R): 0.185185
Type - Materials and Finishes - Structural Material: g2_metselwerk_bruin_ staand
Type - Graphics - Coarse Scale Fill Pattern: <Solid fill>; Coarse Scale Fill Color: 4210752
Type - Construction - Wrapping at Inserts: Do not wrap; Function: Exterior; Width: 100 mm
Type - Identity Data - Workset: Wall Types; Assembly Code: 2D(21.11.11); Datum_Gewijzigd: 26-05-2014; Description: horizontaal metselwerk D=100 mm; Model: LOD300; SmartRevit_Versie: 2015.1; Type Comments: hatch; Type Name: 21_WA_metselwerk_donker_staand_100_gen_bdg
Type - Other - Category: Walls; Family Name: Basic Wall
Classification: 2D(21.11.11) Uniformat (Uniformat)
Cross-Section Definition - Cross-Section: Vertical
Constraints - Base Extension Distance: 0 mm; Base is Attached: no; Location Line: Finish Face: Exterior; Related to Mass: no; Room Bounding: yes; Top Extension Distance: 0 mm; Top is Attached: no; Base Constraint: 00 begane grond; Top Constraint: Up to level: 00 begane grond; Base Offset: 3003 mm; Top Offset: 3433 mm; Unconnected Height: 430 mm
Phasing - Phase Created: 2. nieuwbouw
Structural - Enable Analytical Model: no; Structural: no; Structural Usage: Non-bearing
Identity Data - Workset: Workset1
Other - Family: Basic Wall; Family and Type: Basic Wall: 21_WA_metselwerk_donker_staand_100_gen_bdg; Type: 21_WA_metselwerk_donker_staand_100_gen_bdg; Type Id: 892019
Name (Basic Wall:21_WA_metselwerk_donker_staand_100_gen_bdg:...) | Area (m2) | Length (mm) | Volume (m3)
892320 | 1.80113 | 4188.68 | 0.180113
892344 | 1.80127 | 4189 | 0.180127
892366 | 1.80127 | 4189 | 0.180127
892378 | 1.80127 | 4189 | 0.180127
892390 | 1.80127 | 4189 | 0.180127
892416 | 1.80127 | 4189 | 0.180127
892441 | 1.80127 | 4189 | 0.180127
892455 | 2.46583 | 5784.5 | 0.246583
892472 | 1.80127 | 4189 | 0.180127
892486 | 1.86384 | 4284.5 | 0.186383
892515 | 0.91805 | 2185 | 0.091805
892526 | 1.80127 | 4189 | 0.180127
892538 | 1.81202 | 4214 | 0.181202
1223870 | 1.17584 | 2684.5 | 0.117584
1224025 | 1.28978 | 2999.5 | 0.128978
1224077 | 1.77594 | 4130.09 | 0.177594
1224133 | 1.80127 | 4189 | 0.180127
1289387 | 0.672735 | 1564.5 | 0.0672735
1289948 | 1.80127 | 4189 | 0.180127
1289969 | 2.52173 | 5864.5 | 0.252173
1291098 | 0.790268 | 1759.29 | 0.0751553 | Graphics - Center Mark Visible: no
1310178 | 1.80127 | 4189 | 0.180127
1310418 | 1.80127 | 4189 | 0.180127
1311158 | 1.80127 | 4189 | 0.180127
1343019 | 1.80127 | 4189 | 0.180127
1343582 | 0.466335 | 1084.5 | 0.0466335
1345434 | 2.50479 | 5825.09 | 0.250479
1348310 | 0.539435 | 1254.5 | 0.0539435
1348673 | 1.80127 | 4189 | 0.180127
1348946 | 1.25968 | 2879.5 | 0.125968
1349246 | 2.193 | 5150 | 0.2193
1500586 | 1.80127 | 4189 | 0.180127
1500616 | 1.80127 | 4189 | 0.180127
1500635 | 1.69184 | 3884.5 | 0.169184
1500904 | 1.80127 | 4189 | 0.180127
1500929 | 1.80127 | 4189 | 0.180127
1500950 | 0.337335 | 834.5 | 0.0337335
2031506 | 0.675069 | 1532.55 | 0.0658997 | Graphics - Center Mark Visible: no; Group: Model Group:21_rond:1344849
2031566 | 0.92267 | 2102.83 | 0.0904188 | Graphics - Center Mark Visible: no; Group: Model Group:21_rond:1344849
2031609 | 0.675069 | 1532.55 | 0.0658997 | Graphics - Center Mark Visible: no; Group: Model Group:21_rond:1344284
2031610 | 0.803653 | 1831.58 | 0.0787579 | Graphics - Center Mark Visible: no; Group: Model Group:21_rond:1344284
2031754 | 0.709215 | 1570.8 | 0.0675356 | Graphics - Center Mark Visible: no

# IfcWallStandardCase: Basic Wall:21_WA_metselwerk_licht_100_gen_bdg (248)
Type - PredefinedType: STANDARD; Material: g2_metselwerk_geel licht 100 mm
Type - Analytical Properties - Roughness: 1; Absorptance: 0.1; Heat Transfer Coefficient (U): 5.4 kg/K/s3; Thermal Mass: 130.2; Thermal Resistance (R): 0.185185
Type - Materials and Finishes - Structural Material: g2_metselwerk_geel licht
Type - Graphics - Coarse Scale Fill Pattern: <Solid fill>; Coarse Scale Fill Color: 4210752
Type - Construction - Wrapping at Inserts: Do not wrap; Function: Exterior; Width: 100 mm
Type - Identity Data - Workset: Wall Types; Assembly Code: 2D(21.11.11); Datum_Gewijzigd: 26-05-2014; Description: horizontaal metselwerk D=100 mm; Model: LOD300; SmartRevit_Versie: 2015.1; Type Comments: hatch; Type Name: 21_WA_metselwerk_licht_100_gen_bdg
Type - Other - Category: Walls; Family Name: Basic Wall
Classification: 2D(21.11.11) Uniformat (Uniformat)
Cross-Section Definition - Cross-Section: Vertical
Constraints - Base Extension Distance: 0 mm; Base is Attached: no; Location Line: Finish Face: Exterior; Related to Mass: no; Room Bounding: yes; Top Extension Distance: 0 mm; Top is Attached: no
Phasing - Phase Created: 2. nieuwbouw
Structural - Enable Analytical Model: no; Structural: no; Structural Usage: Non-bearing
Identity Data - Workset: Workset1
Other - Family: Basic Wall; Family and Type: Basic Wall: 21_WA_metselwerk_licht_100_gen_bdg; Type: 21_WA_metselwerk_licht_100_gen_bdg; Type Id: 1331771
Name (Basic Wall:21_WA_metselwerk_licht_100_gen_bdg:...) | In | Base Constraint | Base Offset (mm) | Top Constraint | Top Offset (mm) | Unconnected Height (mm) | Area (m2) | Length (mm) | Volume (m3) | Group
772509 | 02 tweede verdieping | 02 tweede verdieping | -100 | Up to level: 03 derde verdieping | -100 | 3800 | 64.8957 | 25380 | 6.48957
772510 | 02 tweede verdieping | 02 tweede verdieping | -100 | Up to level: 03 derde verdieping | -100 | 3800 | 66.7517 | 25180 | 6.67517
772511 | 02 tweede verdieping | 02 tweede verdieping | -100 | Up to level: 03 derde verdieping | -100 | 3800 | 64.869 | 25380 | 6.4869
772512 | 02 tweede verdieping | 02 tweede verdieping | 184 | Up to level: 03 derde verdieping | -100 | 3516 | 25.0189 | 10108 | 2.50189
773496 | 01 eerste verdieping | 01 eerste verdieping | 2877 | Up to level: 02 tweede verdieping | -100 | 823 | 24.5912 | 29880 | 2.45912
773497 | 01 eerste verdieping | 01 eerste verdieping | 2877 | Up to level: 02 tweede verdieping | -100 | 823 | 20.6462 | 25180 | 2.06462
773498 | 01 eerste verdieping | 01 eerste verdieping | 2877 | Up to level: 02 tweede verdieping | -100 | 823 | 27.0479 | 32965 | 2.70479
773499 | 01 eerste verdieping | 01 eerste verdieping | 2877 | Up to level: 02 tweede verdieping | -100 | 823 | 12.8676 | 15585 | 1.28676
862781 | 03 derde verdieping | 03 derde verdieping | -100 | Up to level: 03 derde verdieping | 124 | 224 | 5.70752 | 25380 | 0.570752
863248 | 02 tweede verdieping | 02 tweede verdieping | 603 | Up to level: 02 tweede verdieping | 3075 | 2472 | 0.51912 | 210 | 0.051912 | Model Group:21_penant v2:863826
864099 | 02 tweede verdieping | 02 tweede verdieping | 0 | Up to level: 02 tweede verdieping | 4232 | 4232 | 0.48668 | 115 | 0.048668 | Model Group:21_penant v2:863826
864397 | 02 tweede verdieping | 02 tweede verdieping | 603 | Up to level: 02 tweede verdieping | 3075 | 2472 | 0.51912 | 210 | 0.051912 | Model Group:21_penant v2:863826
864398 | 02 tweede verdieping | 02 tweede verdieping | 0 | Up to level: 02 tweede verdieping | 4232 | 4232 | 0.48668 | 115 | 0.048668 | Model Group:21_penant v2:863826
864467 | 02 tweede verdieping | 02 tweede verdieping | 603 | Up to level: 02 tweede verdieping | 3075 | 2472 | 0.51912 | 210 | 0.051912 | Model Group:21_penant v2:864468
864469 | 02 tweede verdieping | 02 tweede verdieping | 0 | Up to level: 02 tweede verdieping | 4232 | 4232 | 0.48668 | 115 | 0.048668 | Model Group:21_penant v2:864468
864470 | 02 tweede verdieping | 02 tweede verdieping | 603 | Up to level: 02 tweede verdieping | 3075 | 2472 | 0.51912 | 210 | 0.051912 | Model Group:21_penant v2:864468
864471 | 02 tweede verdieping | 02 tweede verdieping | 0 | Up to level: 02 tweede verdieping | 4232 | 4232 | 0.48668 | 115 | 0.048668 | Model Group:21_penant v2:864468
864498 | 02 tweede verdieping | 02 tweede verdieping | 603 | Up to level: 02 tweede verdieping | 3075 | 2472 | 0.51912 | 210 | 0.051912 | Model Group:21_penant v2:864499
864500 | 02 tweede verdieping | 02 tweede verdieping | 0 | Up to level: 02 tweede verdieping | 4232 | 4232 | 0.48668 | 115 | 0.048668 | Model Group:21_penant v2:864499
864501 | 02 tweede verdieping | 02 tweede verdieping | 603 | Up to level: 02 tweede verdieping | 3075 | 2472 | 0.51912 | 210 | 0.051912 | Model Group:21_penant v2:864499
864502 | 02 tweede verdieping | 02 tweede verdieping | 0 | Up to level: 02 tweede verdieping | 4232 | 4232 | 0.48668 | 115 | 0.048668 | Model Group:21_penant v2:864499
864793 | 03 derde verdieping | 03 derde verdieping | -100 | Up to level: 03 derde verdieping | 124 | 224 | 5.70752 | 25380 | 0.570752
864822 | 03 derde verdieping | 03 derde verdieping | -100 | Up to level: 03 derde verdieping | 124 | 224 | 5.61792 | 25180 | 0.561792
864825 | 03 derde verdieping | 03 derde verdieping | -100 | Up to level: 03 derde verdieping | 124 | 224 | 5.61792 | 25180 | 0.561792
870618 | 02 tweede verdieping | 02 tweede verdieping | 603 | Up to level: 02 tweede verdieping | 3075 | 2472 | 0.51912 | 210 | 0.051912 | Model Group:21_penant v2:870619
870620 | 02 tweede verdieping | 02 tweede verdieping | 0 | Up to level: 02 tweede verdieping | 4232 | 4232 | 0.48668 | 115 | 0.048668 | Model Group:21_penant v2:870619
870621 | 02 tweede verdieping | 02 tweede verdieping | 603 | Up to level: 02 tweede verdieping | 3075 | 2472 | 0.51912 | 210 | 0.051912 | Model Group:21_penant v2:870619
870622 | 02 tweede verdieping | 02 tweede verdieping | 0 | Up to level: 02 tweede verdieping | 4232 | 4232 | 0.48668 | 115 | 0.048668 | Model Group:21_penant v2:870619
870635 | 02 tweede verdieping | 02 tweede verdieping | 603 | Up to level: 02 tweede verdieping | 3075 | 2472 | 0.51912 | 210 | 0.051912 | Model Group:21_penant v2:870636
870637 | 02 tweede verdieping | 02 tweede verdieping | 0 | Up to level: 02 tweede verdieping | 4232 | 4232 | 0.48668 | 115 | 0.048668 | Model Group:21_penant v2:870636
870638 | 02 tweede verdieping | 02 tweede verdieping | 603 | Up to level: 02 tweede verdieping | 3075 | 2472 | 0.51912 | 210 | 0.051912 | Model Group:21_penant v2:870636
870639 | 02 tweede verdieping | 02 tweede verdieping | 0 | Up to level: 02 tweede verdieping | 4232 | 4232 | 0.48668 | 115 | 0.048668 | Model Group:21_penant v2:870636
870659 | 02 tweede verdieping | 02 tweede verdieping | 603 | Up to level: 02 tweede verdieping | 3075 | 2472 | 0.51912 | 210 | 0.051912 | Model Group:21_penant v2:870660
870661 | 02 tweede verdieping | 02 tweede verdieping | 0 | Up to level: 02 tweede verdieping | 4232 | 4232 | 0.48668 | 115 | 0.048668 | Model Group:21_penant v2:870660
870662 | 02 tweede verdieping | 02 tweede verdieping | 603 | Up to level: 02 tweede verdieping | 3075 | 2472 | 0.51912 | 210 | 0.051912 | Model Group:21_penant v2:870660
870663 | 02 tweede verdieping | 02 tweede verdieping | 0 | Up to level: 02 tweede verdieping | 4232 | 4232 | 0.48668 | 115 | 0.048668 | Model Group:21_penant v2:870660
870700 | 02 tweede verdieping | 02 tweede verdieping | 603 | Up to level: 02 tweede verdieping | 3075 | 2472 | 0.51912 | 210 | 0.051912 | Model Group:21_penant v2:870701
870702 | 02 tweede verdieping | 02 tweede verdieping | 0 | Up to level: 02 tweede verdieping | 4232 | 4232 | 0.48668 | 115 | 0.048668 | Model Group:21_penant v2:870701
870703 | 02 tweede verdieping | 02 tweede verdieping | 603 | Up to level: 02 tweede verdieping | 3075 | 2472 | 0.51912 | 210 | 0.051912 | Model Group:21_penant v2:870701
870704 | 02 tweede verdieping | 02 tweede verdieping | 0 | Up to level: 02 tweede verdieping | 4232 | 4232 | 0.48668 | 115 | 0.048668 | Model Group:21_penant v2:870701
870717 | 02 tweede verdieping | 02 tweede verdieping | 603 | Up to level: 02 tweede verdieping | 3075 | 2472 | 0.51912 | 210 | 0.051912 | Model Group:21_penant v2:870718
870719 | 02 tweede verdieping | 02 tweede verdieping | 0 | Up to level: 02 tweede verdieping | 4232 | 4232 | 0.48668 | 115 | 0.048668 | Model Group:21_penant v2:870718
870720 | 02 tweede verdieping | 02 tweede verdieping | 603 | Up to level: 02 tweede verdieping | 3075 | 2472 | 0.51912 | 210 | 0.051912 | Model Group:21_penant v2:870718
870721 | 02 tweede verdieping | 02 tweede verdieping | 0 | Up to level: 02 tweede verdieping | 4232 | 4232 | 0.48668 | 115 | 0.048668 | Model Group:21_penant v2:870718
870741 | 02 tweede verdieping | 02 tweede verdieping | 603 | Up to level: 02 tweede verdieping | 3075 | 2472 | 0.51912 | 210 | 0.051912 | Model Group:21_penant v2:870742
870743 | 02 tweede verdieping | 02 tweede verdieping | 0 | Up to level: 02 tweede verdieping | 4232 | 4232 | 0.48668 | 115 | 0.048668 | Model Group:21_penant v2:870742
870744 | 02 tweede verdieping | 02 tweede verdieping | 603 | Up to level: 02 tweede verdieping | 3075 | 2472 | 0.51912 | 210 | 0.051912 | Model Group:21_penant v2:870742
870745 | 02 tweede verdieping | 02 tweede verdieping | 0 | Up to level: 02 tweede verdieping | 4232 | 4232 | 0.48668 | 115 | 0.048668 | Model Group:21_penant v2:870742
870813 | 02 tweede verdieping | 02 tweede verdieping | 603 | Up to level: 02 tweede verdieping | 3075 | 2472 | 0.51912 | 210 | 0.051912 | Model Group:21_penant v2:870814
870815 | 02 tweede verdieping | 02 tweede verdieping | 0 | Up to level: 02 tweede verdieping | 4232 | 4232 | 0.48668 | 115 | 0.048668 | Model Group:21_penant v2:870814
870816 | 02 tweede verdieping | 02 tweede verdieping | 603 | Up to level: 02 tweede verdieping | 3075 | 2472 | 0.51912 | 210 | 0.051912 | Model Group:21_penant v2:870814
870817 | 02 tweede verdieping | 02 tweede verdieping | 0 | Up to level: 02 tweede verdieping | 4232 | 4232 | 0.48668 | 115 | 0.048668 | Model Group:21_penant v2:870814
870830 | 02 tweede verdieping | 02 tweede verdieping | 603 | Up to level: 02 tweede verdieping | 3075 | 2472 | 0.51912 | 210 | 0.051912 | Model Group:21_penant v2:870831
870832 | 02 tweede verdieping | 02 tweede verdieping | 0 | Up to level: 02 tweede verdieping | 4232 | 4232 | 0.48668 | 115 | 0.048668 | Model Group:21_penant v2:870831
870833 | 02 tweede verdieping | 02 tweede verdieping | 603 | Up to level: 02 tweede verdieping | 3075 | 2472 | 0.51912 | 210 | 0.051912 | Model Group:21_penant v2:870831
870834 | 02 tweede verdieping | 02 tweede verdieping | 0 | Up to level: 02 tweede verdieping | 4232 | 4232 | 0.48668 | 115 | 0.048668 | Model Group:21_penant v2:870831
870854 | 02 tweede verdieping | 02 tweede verdieping | 603 | Up to level: 02 tweede verdieping | 3075 | 2472 | 0.51912 | 210 | 0.051912 | Model Group:21_penant v2:870855
870856 | 02 tweede verdieping | 02 tweede verdieping | 0 | Up to level: 02 tweede verdieping | 4232 | 4232 | 0.48668 | 115 | 0.048668 | Model Group:21_penant v2:870855
870857 | 02 tweede verdieping | 02 tweede verdieping | 603 | Up to level: 02 tweede verdieping | 3075 | 2472 | 0.51912 | 210 | 0.051912 | Model Group:21_penant v2:870855
870858 | 02 tweede verdieping | 02 tweede verdieping | 0 | Up to level: 02 tweede verdieping | 4232 | 4232 | 0.48668 | 115 | 0.048668 | Model Group:21_penant v2:870855
870921 | 02 tweede verdieping | 02 tweede verdieping | 603 | Up to level: 02 tweede verdieping | 3075 | 2472 | 0.51912 | 210 | 0.051912 | Model Group:21_penant v2:870922
870923 | 02 tweede verdieping | 02 tweede verdieping | 0 | Up to level: 02 tweede verdieping | 4232 | 4232 | 0.48668 | 115 | 0.048668 | Model Group:21_penant v2:870922
870924 | 02 tweede verdieping | 02 tweede verdieping | 603 | Up to level: 02 tweede verdieping | 3075 | 2472 | 0.51912 | 210 | 0.051912 | Model Group:21_penant v2:870922
870925 | 02 tweede verdieping | 02 tweede verdieping | 0 | Up to level: 02 tweede verdieping | 4232 | 4232 | 0.48668 | 115 | 0.048668 | Model Group:21_penant v2:870922
871618 | 02 tweede verdieping | 02 tweede verdieping | 603 | Up to level: 02 tweede verdieping | 3075 | 2472 | 0.51912 | 210 | 0.051912 | Model Group:21_penant v2:871619
871620 | 02 tweede verdieping | 02 tweede verdieping | 0 | Up to level: 02 tweede verdieping | 4232 | 4232 | 0.48668 | 115 | 0.048668 | Model Group:21_penant v2:871619
871621 | 02 tweede verdieping | 02 tweede verdieping | 603 | Up to level: 02 tweede verdieping | 3075 | 2472 | 0.51912 | 210 | 0.051912 | Model Group:21_penant v2:871619
871622 | 02 tweede verdieping | 02 tweede verdieping | 0 | Up to level: 02 tweede verdieping | 4232 | 4232 | 0.48668 | 115 | 0.048668 | Model Group:21_penant v2:871619
871651 | 02 tweede verdieping | 02 tweede verdieping | 603 | Up to level: 02 tweede verdieping | 3075 | 2472 | 0.51912 | 210 | 0.051912 | Model Group:21_penant v2:871652
871653 | 02 tweede verdieping | 02 tweede verdieping | 0 | Up to level: 02 tweede verdieping | 4232 | 4232 | 0.48668 | 115 | 0.048668 | Model Group:21_penant v2:871652
871654 | 02 tweede verdieping | 02 tweede verdieping | 603 | Up to level: 02 tweede verdieping | 3075 | 2472 | 0.51912 | 210 | 0.051912 | Model Group:21_penant v2:871652
871655 | 02 tweede verdieping | 02 tweede verdieping | 0 | Up to level: 02 tweede verdieping | 4232 | 4232 | 0.48668 | 115 | 0.048668 | Model Group:21_penant v2:871652
871684 | 02 tweede verdieping | 02 tweede verdieping | 603 | Up to level: 02 tweede verdieping | 3075 | 2472 | 0.51912 | 210 | 0.051912 | Model Group:21_penant v2:871685
871686 | 02 tweede verdieping | 02 tweede verdieping | 0 | Up to level: 02 tweede verdieping | 4232 | 4232 | 0.48668 | 115 | 0.048668 | Model Group:21_penant v2:871685
871687 | 02 tweede verdieping | 02 tweede verdieping | 603 | Up to level: 02 tweede verdieping | 3075 | 2472 | 0.51912 | 210 | 0.051912 | Model Group:21_penant v2:871685
871688 | 02 tweede verdieping | 02 tweede verdieping | 0 | Up to level: 02 tweede verdieping | 4232 | 4232 | 0.48668 | 115 | 0.048668 | Model Group:21_penant v2:871685
871840 | 02 tweede verdieping | 02 tweede verdieping | 3075 | Up to level: 02 tweede verdieping | 4232 | 1157 | 0.133055 | 115 | 0.0133055 | Model Group:21_penant v2 deur:871839
871841 | 02 tweede verdieping | 02 tweede verdieping | 0 | Up to level: 02 tweede verdieping | 3075 | 3075 | 0.64575 | 210 | 0.064575 | Model Group:21_penant v2 deur:871839
871842 | 02 tweede verdieping | 02 tweede verdieping | 0 | Up to level: 02 tweede verdieping | 4232 | 4232 | 0.48668 | 115 | 0.048668 | Model Group:21_penant v2 deur:871839
871870 | 02 tweede verdieping | 02 tweede verdieping | 603 | Up to level: 02 tweede verdieping | 3075 | 2472 | 0.51912 | 210 | 0.051912 | Model Group:21_penant v2:871871
871872 | 02 tweede verdieping | 02 tweede verdieping | 0 | Up to level: 02 tweede verdieping | 4232 | 4232 | 0.48668 | 115 | 0.048668 | Model Group:21_penant v2:871871
871873 | 02 tweede verdieping | 02 tweede verdieping | 603 | Up to level: 02 tweede verdieping | 3075 | 2472 | 0.51912 | 210 | 0.051912 | Model Group:21_penant v2:871871
871874 | 02 tweede verdieping | 02 tweede verdieping | 0 | Up to level: 02 tweede verdieping | 4232 | 4232 | 0.48668 | 115 | 0.048668 | Model Group:21_penant v2:871871
871902 | 02 tweede verdieping | 02 tweede verdieping | 603 | Up to level: 02 tweede verdieping | 3075 | 2472 | 0.51912 | 210 | 0.051912 | Model Group:21_penant v2:871903
871904 | 02 tweede verdieping | 02 tweede verdieping | 0 | Up to level: 02 tweede verdieping | 4232 | 4232 | 0.48668 | 115 | 0.048668 | Model Group:21_penant v2:871903
871905 | 02 tweede verdieping | 02 tweede verdieping | 603 | Up to level: 02 tweede verdieping | 3075 | 2472 | 0.51912 | 210 | 0.051912 | Model Group:21_penant v2:871903
871906 | 02 tweede verdieping | 02 tweede verdieping | 0 | Up to level: 02 tweede verdieping | 4232 | 4232 | 0.48668 | 115 | 0.048668 | Model Group:21_penant v2:871903
871934 | 02 tweede verdieping | 02 tweede verdieping | 603 | Up to level: 02 tweede verdieping | 3075 | 2472 | 0.51912 | 210 | 0.051912 | Model Group:21_penant v2:871935
871936 | 02 tweede verdieping | 02 tweede verdieping | 0 | Up to level: 02 tweede verdieping | 4232 | 4232 | 0.48668 | 115 | 0.048668 | Model Group:21_penant v2:871935
871937 | 02 tweede verdieping | 02 tweede verdieping | 603 | Up to level: 02 tweede verdieping | 3075 | 2472 | 0.51912 | 210 | 0.051912 | Model Group:21_penant v2:871935
871938 | 02 tweede verdieping | 02 tweede verdieping | 0 | Up to level: 02 tweede verdieping | 4232 | 4232 | 0.48668 | 115 | 0.048668 | Model Group:21_penant v2:871935
871966 | 02 tweede verdieping | 02 tweede verdieping | 603 | Up to level: 02 tweede verdieping | 3075 | 2472 | 0.51912 | 210 | 0.051912 | Model Group:21_penant v2:871967
871968 | 02 tweede verdieping | 02 tweede verdieping | 0 | Up to level: 02 tweede verdieping | 4232 | 4232 | 0.48668 | 115 | 0.048668 | Model Group:21_penant v2:871967
871969 | 02 tweede verdieping | 02 tweede verdieping | 603 | Up to level: 02 tweede verdieping | 3075 | 2472 | 0.51912 | 210 | 0.051912 | Model Group:21_penant v2:871967
871970 | 02 tweede verdieping | 02 tweede verdieping | 0 | Up to level: 02 tweede verdieping | 4232 | 4232 | 0.48668 | 115 | 0.048668 | Model Group:21_penant v2:871967
872008 | 02 tweede verdieping | 02 tweede verdieping | 603 | Up to level: 02 tweede verdieping | 3075 | 2472 | 0.51912 | 210 | 0.051912 | Model Group:21_penant v2:872009
872010 | 02 tweede verdieping | 02 tweede verdieping | 0 | Up to level: 02 tweede verdieping | 4232 | 4232 | 0.48668 | 115 | 0.048668 | Model Group:21_penant v2:872009
872011 | 02 tweede verdieping | 02 tweede verdieping | 603 | Up to level: 02 tweede verdieping | 3075 | 2472 | 0.51912 | 210 | 0.051912 | Model Group:21_penant v2:872009
872012 | 02 tweede verdieping | 02 tweede verdieping | 0 | Up to level: 02 tweede verdieping | 4232 | 4232 | 0.48668 | 115 | 0.048668 | Model Group:21_penant v2:872009
872274 | 02 tweede verdieping | 02 tweede verdieping | 603 | Up to level: 02 tweede verdieping | 3075 | 2472 | 0.51912 | 210 | 0.051912 | Model Group:21_penant v2:872275
872276 | 02 tweede verdieping | 02 tweede verdieping | 0 | Up to level: 02 tweede verdieping | 4232 | 4232 | 0.48668 | 115 | 0.048668 | Model Group:21_penant v2:872275
872277 | 02 tweede verdieping | 02 tweede verdieping | 603 | Up to level: 02 tweede verdieping | 3075 | 2472 | 0.51912 | 210 | 0.051912 | Model Group:21_penant v2:872275
872278 | 02 tweede verdieping | 02 tweede verdieping | 0 | Up to level: 02 tweede verdieping | 4232 | 4232 | 0.48668 | 115 | 0.048668 | Model Group:21_penant v2:872275
872808 | 02 tweede verdieping | 02 tweede verdieping | 603 | Up to level: 02 tweede verdieping | 3075 | 2472 | 0.51912 | 210 | 0.051912 | Model Group:21_penant v2:872809
872810 | 02 tweede verdieping | 02 tweede verdieping | 0 | Up to level: 02 tweede verdieping | 4232 | 4232 | 0.48668 | 115 | 0.048668 | Model Group:21_penant v2:872809
872811 | 02 tweede verdieping | 02 tweede verdieping | 603 | Up to level: 02 tweede verdieping | 3075 | 2472 | 0.51912 | 210 | 0.051912 | Model Group:21_penant v2:872809
872812 | 02 tweede verdieping | 02 tweede verdieping | 0 | Up to level: 02 tweede verdieping | 4232 | 4232 | 0.48668 | 115 | 0.048668 | Model Group:21_penant v2:872809
872841 | 02 tweede verdieping | 02 tweede verdieping | 603 | Up to level: 02 tweede verdieping | 3075 | 2472 | 0.51912 | 210 | 0.051912 | Model Group:21_penant v2:872842
872843 | 02 tweede verdieping | 02 tweede verdieping | 0 | Up to level: 02 tweede verdieping | 4232 | 4232 | 0.48668 | 115 | 0.048668 | Model Group:21_penant v2:872842
872844 | 02 tweede verdieping | 02 tweede verdieping | 603 | Up to level: 02 tweede verdieping | 3075 | 2472 | 0.51912 | 210 | 0.051912 | Model Group:21_penant v2:872842
872845 | 02 tweede verdieping | 02 tweede verdieping | 0 | Up to level: 02 tweede verdieping | 4232 | 4232 | 0.48668 | 115 | 0.048668 | Model Group:21_penant v2:872842
872874 | 02 tweede verdieping | 02 tweede verdieping | 603 | Up to level: 02 tweede verdieping | 3075 | 2472 | 0.51912 | 210 | 0.051912 | Model Group:21_penant v2:872875
872876 | 02 tweede verdieping | 02 tweede verdieping | 0 | Up to level: 02 tweede verdieping | 4232 | 4232 | 0.48668 | 115 | 0.048668 | Model Group:21_penant v2:872875
872877 | 02 tweede verdieping | 02 tweede verdieping | 603 | Up to level: 02 tweede verdieping | 3075 | 2472 | 0.51912 | 210 | 0.051912 | Model Group:21_penant v2:872875
872878 | 02 tweede verdieping | 02 tweede verdieping | 0 | Up to level: 02 tweede verdieping | 4232 | 4232 | 0.48668 | 115 | 0.048668 | Model Group:21_penant v2:872875
872907 | 02 tweede verdieping | 02 tweede verdieping | 603 | Up to level: 02 tweede verdieping | 3075 | 2472 | 0.51912 | 210 | 0.051912 | Model Group:21_penant v2:872908
872909 | 02 tweede verdieping | 02 tweede verdieping | 0 | Up to level: 02 tweede verdieping | 4232 | 4232 | 0.48668 | 115 | 0.048668 | Model Group:21_penant v2:872908
872910 | 02 tweede verdieping | 02 tweede verdieping | 603 | Up to level: 02 tweede verdieping | 3075 | 2472 | 0.51912 | 210 | 0.051912 | Model Group:21_penant v2:872908
872911 | 02 tweede verdieping | 02 tweede verdieping | 0 | Up to level: 02 tweede verdieping | 4232 | 4232 | 0.48668 | 115 | 0.048668 | Model Group:21_penant v2:872908
872940 | 02 tweede verdieping | 02 tweede verdieping | 603 | Up to level: 02 tweede verdieping | 3075 | 2472 | 0.51912 | 210 | 0.051912 | Model Group:21_penant v2:872941
872942 | 02 tweede verdieping | 02 tweede verdieping | 0 | Up to level: 02 tweede verdieping | 4232 | 4232 | 0.48668 | 115 | 0.048668 | Model Group:21_penant v2:872941
872943 | 02 tweede verdieping | 02 tweede verdieping | 603 | Up to level: 02 tweede verdieping | 3075 | 2472 | 0.51912 | 210 | 0.051912 | Model Group:21_penant v2:872941
872944 | 02 tweede verdieping | 02 tweede verdieping | 0 | Up to level: 02 tweede verdieping | 4232 | 4232 | 0.48668 | 115 | 0.048668 | Model Group:21_penant v2:872941
872973 | 02 tweede verdieping | 02 tweede verdieping | 603 | Up to level: 02 tweede verdieping | 3075 | 2472 | 0.51912 | 210 | 0.051912 | Model Group:21_penant v2:872974
872975 | 02 tweede verdieping | 02 tweede verdieping | 0 | Up to level: 02 tweede verdieping | 4232 | 4232 | 0.48668 | 115 | 0.048668 | Model Group:21_penant v2:872974
872976 | 02 tweede verdieping | 02 tweede verdieping | 603 | Up to level: 02 tweede verdieping | 3075 | 2472 | 0.51912 | 210 | 0.051912 | Model Group:21_penant v2:872974
872977 | 02 tweede verdieping | 02 tweede verdieping | 0 | Up to level: 02 tweede verdieping | 4232 | 4232 | 0.48668 | 115 | 0.048668 | Model Group:21_penant v2:872974
873006 | 02 tweede verdieping | 02 tweede verdieping | 603 | Up to level: 02 tweede verdieping | 3075 | 2472 | 0.51912 | 210 | 0.051912 | Model Group:21_penant v2:873007
873008 | 02 tweede verdieping | 02 tweede verdieping | 0 | Up to level: 02 tweede verdieping | 4232 | 4232 | 0.48668 | 115 | 0.048668 | Model Group:21_penant v2:873007
873009 | 02 tweede verdieping | 02 tweede verdieping | 603 | Up to level: 02 tweede verdieping | 3075 | 2472 | 0.51912 | 210 | 0.051912 | Model Group:21_penant v2:873007
873010 | 02 tweede verdieping | 02 tweede verdieping | 0 | Up to level: 02 tweede verdieping | 4232 | 4232 | 0.48668 | 115 | 0.048668 | Model Group:21_penant v2:873007
873039 | 02 tweede verdieping | 02 tweede verdieping | 603 | Up to level: 02 tweede verdieping | 3075 | 2472 | 0.51912 | 210 | 0.051912 | Model Group:21_penant v2:873040
873041 | 02 tweede verdieping | 02 tweede verdieping | 0 | Up to level: 02 tweede verdieping | 4232 | 4232 | 0.48668 | 115 | 0.048668 | Model Group:21_penant v2:873040
873042 | 02 tweede verdieping | 02 tweede verdieping | 603 | Up to level: 02 tweede verdieping | 3075 | 2472 | 0.51912 | 210 | 0.051912 | Model Group:21_penant v2:873040
873043 | 02 tweede verdieping | 02 tweede verdieping | 0 | Up to level: 02 tweede verdieping | 4232 | 4232 | 0.48668 | 115 | 0.048668 | Model Group:21_penant v2:873040
873072 | 02 tweede verdieping | 02 tweede verdieping | 603 | Up to level: 02 tweede verdieping | 3075 | 2472 | 0.51912 | 210 | 0.051912 | Model Group:21_penant v2:873073
873074 | 02 tweede verdieping | 02 tweede verdieping | 0 | Up to level: 02 tweede verdieping | 4232 | 4232 | 0.48668 | 115 | 0.048668 | Model Group:21_penant v2:873073
873075 | 02 tweede verdieping | 02 tweede verdieping | 603 | Up to level: 02 tweede verdieping | 3075 | 2472 | 0.51912 | 210 | 0.051912 | Model Group:21_penant v2:873073
873076 | 02 tweede verdieping | 02 tweede verdieping | 0 | Up to level: 02 tweede verdieping | 4232 | 4232 | 0.48668 | 115 | 0.048668 | Model Group:21_penant v2:873073
873105 | 02 tweede verdieping | 02 tweede verdieping | 603 | Up to level: 02 tweede verdieping | 3075 | 2472 | 0.51912 | 210 | 0.051912 | Model Group:21_penant v2:873106
873107 | 02 tweede verdieping | 02 tweede verdieping | 0 | Up to level: 02 tweede verdieping | 4232 | 4232 | 0.48668 | 115 | 0.048668 | Model Group:21_penant v2:873106
873108 | 02 tweede verdieping | 02 tweede verdieping | 603 | Up to level: 02 tweede verdieping | 3075 | 2472 | 0.51912 | 210 | 0.051912 | Model Group:21_penant v2:873106
873109 | 02 tweede verdieping | 02 tweede verdieping | 0 | Up to level: 02 tweede verdieping | 4232 | 4232 | 0.48668 | 115 | 0.048668 | Model Group:21_penant v2:873106
873391 | 02 tweede verdieping | 02 tweede verdieping | 603 | Up to level: 02 tweede verdieping | 3075 | 2472 | 0.51912 | 210 | 0.051912 | Model Group:21_penant v2:873392
873393 | 02 tweede verdieping | 02 tweede verdieping | 0 | Up to level: 02 tweede verdieping | 4232 | 4232 | 0.48668 | 115 | 0.048668 | Model Group:21_penant v2:873392
873394 | 02 tweede verdieping | 02 tweede verdieping | 603 | Up to level: 02 tweede verdieping | 3075 | 2472 | 0.51912 | 210 | 0.051912 | Model Group:21_penant v2:873392
873395 | 02 tweede verdieping | 02 tweede verdieping | 0 | Up to level: 02 tweede verdieping | 4232 | 4232 | 0.48668 | 115 | 0.048668 | Model Group:21_penant v2:873392
873441 | 02 tweede verdieping | 02 tweede verdieping | 603 | Up to level: 02 tweede verdieping | 3075 | 2472 | 0.51912 | 210 | 0.051912 | Model Group:21_penant v2:873442
873443 | 02 tweede verdieping | 02 tweede verdieping | 0 | Up to level: 02 tweede verdieping | 4232 | 4232 | 0.48668 | 115 | 0.048668 | Model Group:21_penant v2:873442
873444 | 02 tweede verdieping | 02 tweede verdieping | 603 | Up to level: 02 tweede verdieping | 3075 | 2472 | 0.51912 | 210 | 0.051912 | Model Group:21_penant v2:873442
873445 | 02 tweede verdieping | 02 tweede verdieping | 0 | Up to level: 02 tweede verdieping | 4232 | 4232 | 0.48668 | 115 | 0.048668 | Model Group:21_penant v2:873442
873472 | 02 tweede verdieping | 02 tweede verdieping | 603 | Up to level: 02 tweede verdieping | 3075 | 2472 | 0.51912 | 210 | 0.051912 | Model Group:21_penant v2:873473
873474 | 02 tweede verdieping | 02 tweede verdieping | 0 | Up to level: 02 tweede verdieping | 4232 | 4232 | 0.48668 | 115 | 0.048668 | Model Group:21_penant v2:873473
873475 | 02 tweede verdieping | 02 tweede verdieping | 603 | Up to level: 02 tweede verdieping | 3075 | 2472 | 0.51912 | 210 | 0.051912 | Model Group:21_penant v2:873473
873476 | 02 tweede verdieping | 02 tweede verdieping | 0 | Up to level: 02 tweede verdieping | 4232 | 4232 | 0.48668 | 115 | 0.048668 | Model Group:21_penant v2:873473
873503 | 02 tweede verdieping | 02 tweede verdieping | 603 | Up to level: 02 tweede verdieping | 3075 | 2472 | 0.51912 | 210 | 0.051912 | Model Group:21_penant v2:873504
873505 | 02 tweede verdieping | 02 tweede verdieping | 0 | Up to level: 02 tweede verdieping | 4232 | 4232 | 0.48668 | 115 | 0.048668 | Model Group:21_penant v2:873504
873506 | 02 tweede verdieping | 02 tweede verdieping | 603 | Up to level: 02 tweede verdieping | 3075 | 2472 | 0.51912 | 210 | 0.051912 | Model Group:21_penant v2:873504
873507 | 02 tweede verdieping | 02 tweede verdieping | 0 | Up to level: 02 tweede verdieping | 4232 | 4232 | 0.48668 | 115 | 0.048668 | Model Group:21_penant v2:873504
873534 | 02 tweede verdieping | 02 tweede verdieping | 603 | Up to level: 02 tweede verdieping | 3075 | 2472 | 0.51912 | 210 | 0.051912 | Model Group:21_penant v2:873535
873536 | 02 tweede verdieping | 02 tweede verdieping | 0 | Up to level: 02 tweede verdieping | 4232 | 4232 | 0.48668 | 115 | 0.048668 | Model Group:21_penant v2:873535
873537 | 02 tweede verdieping | 02 tweede verdieping | 603 | Up to level: 02 tweede verdieping | 3075 | 2472 | 0.51912 | 210 | 0.051912 | Model Group:21_penant v2:873535
873538 | 02 tweede verdieping | 02 tweede verdieping | 0 | Up to level: 02 tweede verdieping | 4232 | 4232 | 0.48668 | 115 | 0.048668 | Model Group:21_penant v2:873535
873565 | 02 tweede verdieping | 02 tweede verdieping | 603 | Up to level: 02 tweede verdieping | 3075 | 2472 | 0.51912 | 210 | 0.051912 | Model Group:21_penant v2:873566
873567 | 02 tweede verdieping | 02 tweede verdieping | 0 | Up to level: 02 tweede verdieping | 4232 | 4232 | 0.48668 | 115 | 0.048668 | Model Group:21_penant v2:873566
873568 | 02 tweede verdieping | 02 tweede verdieping | 603 | Up to level: 02 tweede verdieping | 3075 | 2472 | 0.51912 | 210 | 0.051912 | Model Group:21_penant v2:873566
873569 | 02 tweede verdieping | 02 tweede verdieping | 0 | Up to level: 02 tweede verdieping | 4232 | 4232 | 0.48668 | 115 | 0.048668 | Model Group:21_penant v2:873566
873596 | 02 tweede verdieping | 02 tweede verdieping | 603 | Up to level: 02 tweede verdieping | 3075 | 2472 | 0.51912 | 210 | 0.051912 | Model Group:21_penant v2:873597
873598 | 02 tweede verdieping | 02 tweede verdieping | 0 | Up to level: 02 tweede verdieping | 4232 | 4232 | 0.48668 | 115 | 0.048668 | Model Group:21_penant v2:873597
873599 | 02 tweede verdieping | 02 tweede verdieping | 603 | Up to level: 02 tweede verdieping | 3075 | 2472 | 0.51912 | 210 | 0.051912 | Model Group:21_penant v2:873597
873600 | 02 tweede verdieping | 02 tweede verdieping | 0 | Up to level: 02 tweede verdieping | 4232 | 4232 | 0.48668 | 115 | 0.048668 | Model Group:21_penant v2:873597
873627 | 02 tweede verdieping | 02 tweede verdieping | 603 | Up to level: 02 tweede verdieping | 3075 | 2472 | 0.51912 | 210 | 0.051912 | Model Group:21_penant v2:873628
873629 | 02 tweede verdieping | 02 tweede verdieping | 0 | Up to level: 02 tweede verdieping | 4232 | 4232 | 0.48668 | 115 | 0.048668 | Model Group:21_penant v2:873628
873630 | 02 tweede verdieping | 02 tweede verdieping | 603 | Up to level: 02 tweede verdieping | 3075 | 2472 | 0.51912 | 210 | 0.051912 | Model Group:21_penant v2:873628
873631 | 02 tweede verdieping | 02 tweede verdieping | 0 | Up to level: 02 tweede verdieping | 4232 | 4232 | 0.48668 | 115 | 0.048668 | Model Group:21_penant v2:873628
873658 | 02 tweede verdieping | 02 tweede verdieping | 603 | Up to level: 02 tweede verdieping | 3075 | 2472 | 0.51912 | 210 | 0.051912 | Model Group:21_penant v2:873659
873660 | 02 tweede verdieping | 02 tweede verdieping | 0 | Up to level: 02 tweede verdieping | 4232 | 4232 | 0.48668 | 115 | 0.048668 | Model Group:21_penant v2:873659
873661 | 02 tweede verdieping | 02 tweede verdieping | 603 | Up to level: 02 tweede verdieping | 3075 | 2472 | 0.51912 | 210 | 0.051912 | Model Group:21_penant v2:873659
873662 | 02 tweede verdieping | 02 tweede verdieping | 0 | Up to level: 02 tweede verdieping | 4232 | 4232 | 0.48668 | 115 | 0.048668 | Model Group:21_penant v2:873659
873689 | 02 tweede verdieping | 02 tweede verdieping | 603 | Up to level: 02 tweede verdieping | 3075 | 2472 | 0.51912 | 210 | 0.051912 | Model Group:21_penant v2:873690
873691 | 02 tweede verdieping | 02 tweede verdieping | 0 | Up to level: 02 tweede verdieping | 4232 | 4232 | 0.48668 | 115 | 0.048668 | Model Group:21_penant v2:873690
873692 | 02 tweede verdieping | 02 tweede verdieping | 603 | Up to level: 02 tweede verdieping | 3075 | 2472 | 0.51912 | 210 | 0.051912 | Model Group:21_penant v2:873690
873693 | 02 tweede verdieping | 02 tweede verdieping | 0 | Up to level: 02 tweede verdieping | 4232 | 4232 | 0.48668 | 115 | 0.048668 | Model Group:21_penant v2:873690
873720 | 02 tweede verdieping | 02 tweede verdieping | 603 | Up to level: 02 tweede verdieping | 3075 | 2472 | 0.51912 | 210 | 0.051912 | Model Group:21_penant v2:873721
873722 | 02 tweede verdieping | 02 tweede verdieping | 0 | Up to level: 02 tweede verdieping | 4232 | 4232 | 0.48668 | 115 | 0.048668 | Model Group:21_penant v2:873721
873723 | 02 tweede verdieping | 02 tweede verdieping | 603 | Up to level: 02 tweede verdieping | 3075 | 2472 | 0.51912 | 210 | 0.051912 | Model Group:21_penant v2:873721
873724 | 02 tweede verdieping | 02 tweede verdieping | 0 | Up to level: 02 tweede verdieping | 4232 | 4232 | 0.48668 | 115 | 0.048668 | Model Group:21_penant v2:873721
879815 | 02 tweede verdieping | 02 tweede verdieping | -100 | Up to level: 02 tweede verdieping | 603 | 703 | 3.1777 | 4500 | 0.31777
879863 | 02 tweede verdieping | 02 tweede verdieping | -100 | Up to level: 02 tweede verdieping | 603 | 703 | 14.9282 | 21235 | 1.49282
879886 | 02 tweede verdieping | 02 tweede verdieping | -100 | Up to level: 02 tweede verdieping | 603 | 703 | 5.27445 | 7585 | 0.527445
1302772 | 01 eerste verdieping | 01 eerste verdieping | 775 | Up to level: 02 tweede verdieping | -100 | 2925 | 25.0075 | 9272.5 | 2.50075
1327643 | 01 eerste verdieping | 01 eerste verdieping | 775 | Up to level: 02 dakrand gymzaal | -519 | 1906 | 1.57245 | 775 | 0.157245
1332387 | 02 tweede verdieping | 02 tweede verdieping | 0 | Up to level: 02 tweede verdieping | 4232 | 4232 | 0.48668 | 165 | 0.048668
1332420 | 02 tweede verdieping | 02 tweede verdieping | 0 | Up to level: 02 tweede verdieping | 4232 | 4232 | 0.48668 | 165 | 0.048668
1332439 | 02 tweede verdieping | 02 tweede verdieping | 0 | Up to level: 02 tweede verdieping | 4232 | 4232 | 0.48668 | 165 | 0.048668
1332440 | 02 tweede verdieping | 02 tweede verdieping | 0 | Up to level: 02 tweede verdieping | 4232 | 4232 | 0.48668 | 165 | 0.048668
1332591 | 02 tweede verdieping | 02 tweede verdieping | -50 | Up to level: 02 tweede verdieping | 603 | 653 | 13.7293 | 20925 | 1.37293
1332625 | 02 tweede verdieping | 02 tweede verdieping | -50 | Up to level: 02 tweede verdieping | 603 | 653 | 2.67077 | 4140 | 0.267077
1334267 | 02 tweede verdieping | 02 tweede verdieping | -50 | Up to level: 02 tweede verdieping | 603 | 653 | 4.74404 | 7315 | 0.474404
1346414 | 02 tweede verdieping | 02 tweede verdieping | -50 | Up to level: 02 tweede verdieping | 603 | 653 | 0.13713 | 310 | 0.013713
1483197 | 02 tweede verdieping | 02 tweede verdieping | 3075 | Up to level: 02 tweede verdieping | 4232 | 1157 | 0.133055 | 115 | 0.0133055 | Model Group:21_penant v2 deur:1483196
1483198 | 02 tweede verdieping | 02 tweede verdieping | 0 | Up to level: 02 tweede verdieping | 3075 | 3075 | 0.64575 | 210 | 0.064575 | Model Group:21_penant v2 deur:1483196
1483199 | 02 tweede verdieping | 02 tweede verdieping | 0 | Up to level: 02 tweede verdieping | 4232 | 4232 | 0.48668 | 115 | 0.048668 | Model Group:21_penant v2 deur:1483196
1884232 | 01 eerste verdieping | 01 eerste verdieping | 775 | Up to level: 02 dakrand gymzaal | -519 | 1906 | 3.39171 | 1785 | 0.337029 | Model Group:MW_gevelvlak_V1 a (members excluded):1885437
1885077 | 01 eerste verdieping | 01 eerste verdieping | 775 | Up to level: 02 dakrand gymzaal | -519 | 1906 | 3.40221 | 1785 | 0.340221 | Model Group:MW_gevelvlak_V1 a (members excluded):1885437
1885223 | 01 eerste verdieping | 01 eerste verdieping | 775 | Up to level: 02 dakrand gymzaal | -519 | 1906 | 3.40221 | 1835 | 0.340221 | Model Group:MW_gevelvlak_V1 a (members excluded):1885437
1885478 | 01 eerste verdieping | 01 eerste verdieping | 775 | Up to level: 02 dakrand gymzaal | -519 | 1906 | 3.40221 | 1785 | 0.340221 | Model Group:MW_gevelvlak_V1 a (members excluded):1885483
1885481 | 01 eerste verdieping | 01 eerste verdieping | 775 | Up to level: 02 dakrand gymzaal | -519 | 1906 | 3.39171 | 1785 | 0.337029 | Model Group:MW_gevelvlak_V1 a (members excluded):1885483
1885482 | 01 eerste verdieping | 01 eerste verdieping | 775 | Up to level: 02 dakrand gymzaal | -519 | 1906 | 3.40221 | 1835 | 0.340221 | Model Group:MW_gevelvlak_V1 a (members excluded):1885483
1885505 | 01 eerste verdieping | 01 eerste verdieping | 775 | Up to level: 02 dakrand gymzaal | -519 | 1906 | 3.39171 | 1785 | 0.337029 | Model Group:MW_gevelvlak_V1 a (members excluded):1885510
1885508 | 01 eerste verdieping | 01 eerste verdieping | 775 | Up to level: 02 dakrand gymzaal | -519 | 1906 | 3.39171 | 1785 | 0.337029 | Model Group:MW_gevelvlak_V1 a (members excluded):1885510
1885509 | 01 eerste verdieping | 01 eerste verdieping | 775 | Up to level: 02 dakrand gymzaal | -519 | 1906 | 3.40221 | 1835 | 0.340221 | Model Group:MW_gevelvlak_V1 a (members excluded):1885510
1885555 | 01 eerste verdieping | 01 eerste verdieping | 775 | Up to level: 02 dakrand gymzaal | -519 | 1906 | 3.39171 | 1785 | 0.337029 | Model Group:MW_gevelvlak_V1 a (members excluded):1885560
1885558 | 01 eerste verdieping | 01 eerste verdieping | 775 | Up to level: 02 dakrand gymzaal | -519 | 1906 | 3.39171 | 1785 | 0.337029 | Model Group:MW_gevelvlak_V1 a (members excluded):1885560
1885559 | 01 eerste verdieping | 01 eerste verdieping | 775 | Up to level: 02 dakrand gymzaal | -519 | 1906 | 3.40221 | 1835 | 0.340221 | Model Group:MW_gevelvlak_V1 a (members excluded):1885560
1885571 | 01 eerste verdieping | 01 eerste verdieping | 775 | Up to level: 02 dakrand gymzaal | -519 | 1906 | 3.40221 | 1785 | 0.340221 | Model Group:MW_gevelvlak_V1 a:1885576
1885574 | 01 eerste verdieping | 01 eerste verdieping | 775 | Up to level: 02 dakrand gymzaal | -519 | 1906 | 3.39171 | 1785 | 0.337029 | Model Group:MW_gevelvlak_V1 a:1885576
1885575 | 01 eerste verdieping | 01 eerste verdieping | 775 | Up to level: 02 dakrand gymzaal | -519 | 1906 | 3.40221 | 1835 | 0.340221 | Model Group:MW_gevelvlak_V1 a:1885576
1886296 | 01 eerste verdieping | 01 eerste verdieping | 775 | Up to level: 02 dakrand gymzaal | -519 | 1906 | 3.40221 | 1785 | 0.340221
1886297 | 01 eerste verdieping | 01 eerste verdieping | 775 | Up to level: 02 dakrand gymzaal | -519 | 1906 | 2.56357 | 1395 | 0.256357
1886476 | 01 eerste verdieping | 01 eerste verdieping | 775 | Up to level: 02 dakrand gymzaal | -519 | 1906 | 3.40221 | 1785 | 0.340221 | Model Group:MW_gevelvlak_V1 a:1886481
1886479 | 01 eerste verdieping | 01 eerste verdieping | 775 | Up to level: 02 dakrand gymzaal | -519 | 1906 | 3.40221 | 1785 | 0.340221 | Model Group:MW_gevelvlak_V1 a:1886481
1886480 | 01 eerste verdieping | 01 eerste verdieping | 775 | Up to level: 02 dakrand gymzaal | -519 | 1906 | 3.40221 | 1835 | 0.340221 | Model Group:MW_gevelvlak_V1 a:1886481
1886482 | 01 eerste verdieping | 01 eerste verdieping | 775 | Up to level: 02 dakrand gymzaal | -519 | 1906 | 3.40221 | 1785 | 0.340221 | Model Group:MW_gevelvlak_V1 a:1886487
1886485 | 01 eerste verdieping | 01 eerste verdieping | 775 | Up to level: 02 dakrand gymzaal | -519 | 1906 | 3.40221 | 1785 | 0.340221 | Model Group:MW_gevelvlak_V1 a:1886487
1886486 | 01 eerste verdieping | 01 eerste verdieping | 775 | Up to level: 02 dakrand gymzaal | -519 | 1906 | 3.40221 | 1835 | 0.340221 | Model Group:MW_gevelvlak_V1 a:1886487
1886488 | 01 eerste verdieping | 01 eerste verdieping | 775 | Up to level: 02 dakrand gymzaal | -519 | 1906 | 3.33234 | 1785 | 0.333234 | Model Group:MW_gevelvlak_V1 a:1886493
1886491 | 01 eerste verdieping | 01 eerste verdieping | 775 | Up to level: 02 dakrand gymzaal | -519 | 1906 | 3.40221 | 1785 | 0.340221 | Model Group:MW_gevelvlak_V1 a:1886493
1886492 | 01 eerste verdieping | 01 eerste verdieping | 775 | Up to level: 02 dakrand gymzaal | -519 | 1906 | 3.34631 | 1835 | 0.334631 | Model Group:MW_gevelvlak_V1 a:1886493
1886584 | 01 eerste verdieping | 01 eerste verdieping | 775 | Up to level: 02 dakrand gymzaal | -519 | 1906 | 1.39615 | 682.5 | 0.139615
1886587 | 01 eerste verdieping | 01 eerste verdieping | 775 | Up to level: 02 dakrand gymzaal | -519 | 1906 | 3.34631 | 1785 | 0.334631
1886588 | 01 eerste verdieping | 01 eerste verdieping | 775 | Up to level: 02 dakrand gymzaal | -519 | 1906 | 3.33234 | 1835 | 0.333234
1886614 | 01 eerste verdieping | 01 eerste verdieping | 775 | Up to level: 02 dakrand gymzaal | -519 | 1906 | 3.40221 | 1785 | 0.340221
1886618 | 01 eerste verdieping | 01 eerste verdieping | 775 | Up to level: 02 dakrand gymzaal | -519 | 1906 | 3.30214 | 1682.5 | 0.330214
1887017 | 01 eerste verdieping | 01 eerste verdieping | 775 | Up to level: 02 dakrand gymzaal | -519 | 1906 | 3.45462 | 1862.5 | 0.345462
1887251 | 01 eerste verdieping | 01 eerste verdieping | 775 | Up to level: 02 dakrand gymzaal | -519 | 1906 | 1.70111 | 942.5 | 0.170111
1887604 | 01 eerste verdieping | 01 eerste verdieping | 775 | Up to level: 02 dakrand gymzaal | -519 | 1906 | 1.39615 | 682.5 | 0.139615
1887607 | 01 eerste verdieping | 01 eerste verdieping | 775 | Up to level: 02 dakrand gymzaal | -519 | 1906 | 3.01624 | 1632.5 | 0.301624
1887903 | 01 eerste verdieping | 01 eerste verdieping | 775 | Up to level: 02 dakrand gymzaal | -519 | 1906 | 3.39171 | 1785 | 0.337029
1888168 | 01 eerste verdieping | 01 eerste verdieping | 775 | Up to level: 02 dakrand gymzaal | -519 | 1906 | 3.40221 | 1835 | 0.340221
1888669 | 01 eerste verdieping | 01 eerste verdieping | 775 | Up to level: 02 dakrand gymzaal | -519 | 1906 | 2.13949 | 1172.5 | 0.213949
2012609 | 02 tweede verdieping | 02 tweede verdieping | 3075 | Up to level: 02 tweede verdieping | 4232 | 1157 | 0.133055 | 115 | 0.0133055 | Model Group:21_penant v2 deur:1483196
2012611 | 02 tweede verdieping | 02 tweede verdieping | 3075 | Up to level: 02 tweede verdieping | 4232 | 1157 | 0.133055 | 115 | 0.0133055 | Model Group:21_penant v2 deur:871839
2303829 | 02 tweede verdieping | 02 tweede verdieping | 150 | Up to level: 03 derde verdieping | -100 | 3550 | 25.0076 | 10108 | 2.50076
2351650 | 02 tweede verdieping | 02 tweede verdieping | 3075 | Up to level: 03 derde verdieping | -100 | 625 | 3.1025 | 4964 | 0.31025
2551642 | 01 eerste verdieping | 01 eerste verdieping | 150 | Up to level: 01 eerste verdieping | 2850 | 2700 | 0.61275 | 220 | 0.061275
2551961 | 01 eerste verdieping | 01 eerste verdieping | 150 | Up to level: 02 tweede verdieping | 603 | 4253 | 17.617 | 9435 | 1.7617
2551975 | 01 eerste verdieping | 01 eerste verdieping | 150 | Up to level: 02 tweede verdieping | 603 | 4253 | 20.7154 | 9325 | 2.07154

# IfcWallStandardCase: Basic Wall:21_WA_metselwerk_licht_staand_100 _gen_bdg (9)
Type - PredefinedType: STANDARD; Material: g2_metselwerk_geel licht_staand 100 mm
Type - Analytical Properties - Roughness: 1; Absorptance: 0.1; Heat Transfer Coefficient (U): 5.4 kg/K/s3; Thermal Mass: 130.2; Thermal Resistance (R): 0.185185
Type - Materials and Finishes - Structural Material: g2_metselwerk_geel licht_staand
Type - Graphics - Coarse Scale Fill Pattern: <Solid fill>; Coarse Scale Fill Color: 4210752
Type - Construction - Wrapping at Inserts: Do not wrap; Function: Exterior; Width: 100 mm
Type - Identity Data - Workset: Wall Types; Assembly Code: 2D(21.11.11); Datum_Gewijzigd: 26-05-2014; Description: horizontaal metselwerk D=100 mm; Model: LOD300; SmartRevit_Versie: 2015.1; Type Comments: hatch; Type Name: 21_WA_metselwerk_licht_staand_100 _gen_bdg
Type - Other - Category: Walls; Family Name: Basic Wall
Classification: 2D(21.11.11) Uniformat (Uniformat)
Cross-Section Definition - Cross-Section: Vertical
Constraints - Base Extension Distance: 0 mm; Base is Attached: no; Location Line: Finish Face: Exterior; Related to Mass: no; Room Bounding: yes; Top Extension Distance: 0 mm; Top is Attached: no
Phasing - Phase Created: 2. nieuwbouw
Structural - Enable Analytical Model: no; Structural: no; Structural Usage: Non-bearing
Identity Data - Workset: Workset1
Other - Family: Basic Wall; Family and Type: Basic Wall: 21_WA_metselwerk_licht_staand_100 _gen_bdg; Type: 21_WA_metselwerk_licht_staand_100 _gen_bdg; Type Id: 1332127
Name (Basic Wall:21_WA_metselwerk_licht_staand_100 _gen_bdg:...) | In | Top Constraint | Base Constraint | Base Offset (mm) | Top Offset (mm) | Unconnected Height (mm) | Area (m2) | Length (mm) | Volume (m3)
862888 | 03 derde verdieping | Up to level: 03 derde verdieping | 03 derde verdieping | 124 | 640 | 516 | 13.1477 | 25380 | 1.31477
864794 | 03 derde verdieping | Up to level: 03 derde verdieping | 03 derde verdieping | 124 | 640 | 516 | 13.1477 | 25380 | 1.31477
864823 | 03 derde verdieping | Up to level: 03 derde verdieping | 03 derde verdieping | 124 | 640 | 516 | 12.9413 | 25180 | 1.29413
864826 | 03 derde verdieping | Up to level: 03 derde verdieping | 03 derde verdieping | 124 | 640 | 516 | 12.9413 | 25180 | 1.29413
1885680 | 01 eerste verdieping | Up to level: 02 dakrand gymzaal | 02 dakrand gymzaal | -519 | 35 | 554 | 8.32108 | 15020 | 0.832108
1885940 | 01 eerste verdieping | Up to level: 02 dakrand gymzaal | 02 dakrand gymzaal | -519 | 35 | 554 | 14.6699 | 26580 | 1.46699
1888319 | 01 eerste verdieping | Up to level: 02 dakrand gymzaal | 02 dakrand gymzaal | -519 | 35 | 554 | 3.02484 | 5410 | 0.302484
1888559 | 01 eerste verdieping | Up to level: 02 dakrand gymzaal | 02 dakrand gymzaal | -519 | 35 | 554 | 14.7807 | 26580 | 1.47807
4014068 | 01 eerste verdieping | Up to level: 02 dakrand gymzaal | 02 dakrand gymzaal | -519 | 35 | 554 | 0.613555 | 1157.5 | 0.0613555

# IfcWallStandardCase: Basic Wall:21_WA_metselwerk_middel_100_gen_bdg (555)
Type - PredefinedType: STANDARD; Material: g2_metselwerk_geel 100 mm
Type - Analytical Properties - Roughness: 1; Absorptance: 0.1; Heat Transfer Coefficient (U): 5.4 kg/K/s3; Thermal Mass: 130.2; Thermal Resistance (R): 0.185185
Type - Materials and Finishes - Structural Material: g2_metselwerk_geel
Type - Graphics - Coarse Scale Fill Pattern: <Solid fill>; Coarse Scale Fill Color: 4210752
Type - Construction - Wrapping at Inserts: Do not wrap; Function: Exterior; Width: 100 mm
Type - Identity Data - Workset: Wall Types; Assembly Code: 2D(21.11.11); Datum_Gewijzigd: 26-05-2014; Description: horizontaal metselwerk D=100 mm; Model: LOD300; SmartRevit_Versie: 2015.1; Type Comments: hatch; Type Name: 21_WA_metselwerk_middel_100_gen_bdg
Type - Other - Category: Walls; Family Name: Basic Wall
Classification: 2D(21.11.11) Uniformat (Uniformat)
Cross-Section Definition - Cross-Section: Vertical
Constraints - Base Extension Distance: 0 mm; Base is Attached: no; Location Line: Finish Face: Exterior; Related to Mass: no; Room Bounding: yes; Top Extension Distance: 0 mm; Top is Attached: no
Phasing - Phase Created: 2. nieuwbouw
Structural - Enable Analytical Model: no; Structural: no; Structural Usage: Non-bearing
Identity Data - Workset: Workset1
Other - Family: Basic Wall; Family and Type: Basic Wall: 21_WA_metselwerk_middel_100_gen_bdg; Type: 21_WA_metselwerk_middel_100_gen_bdg; Type Id: 587139
Name (Basic Wall:21_WA_metselwerk_middel_100_gen_bdg:...) | In | Base Constraint | Base Offset (mm) | Top Constraint | Top Offset (mm) | Unconnected Height (mm) | Area (m2) | Length (mm) | Volume (m3) | Group
772783 | 00 begane grond | bk. fundering | 0 | Up to level: 00 begane grond | 4356 | 4876 | 31.9378 | 6550 | 3.19378
772944 | 00 begane grond | bk. fundering | 0 | Up to level: 00 begane grond | 3433 | 3953 | 6.75568 | 1809 | 0.675568
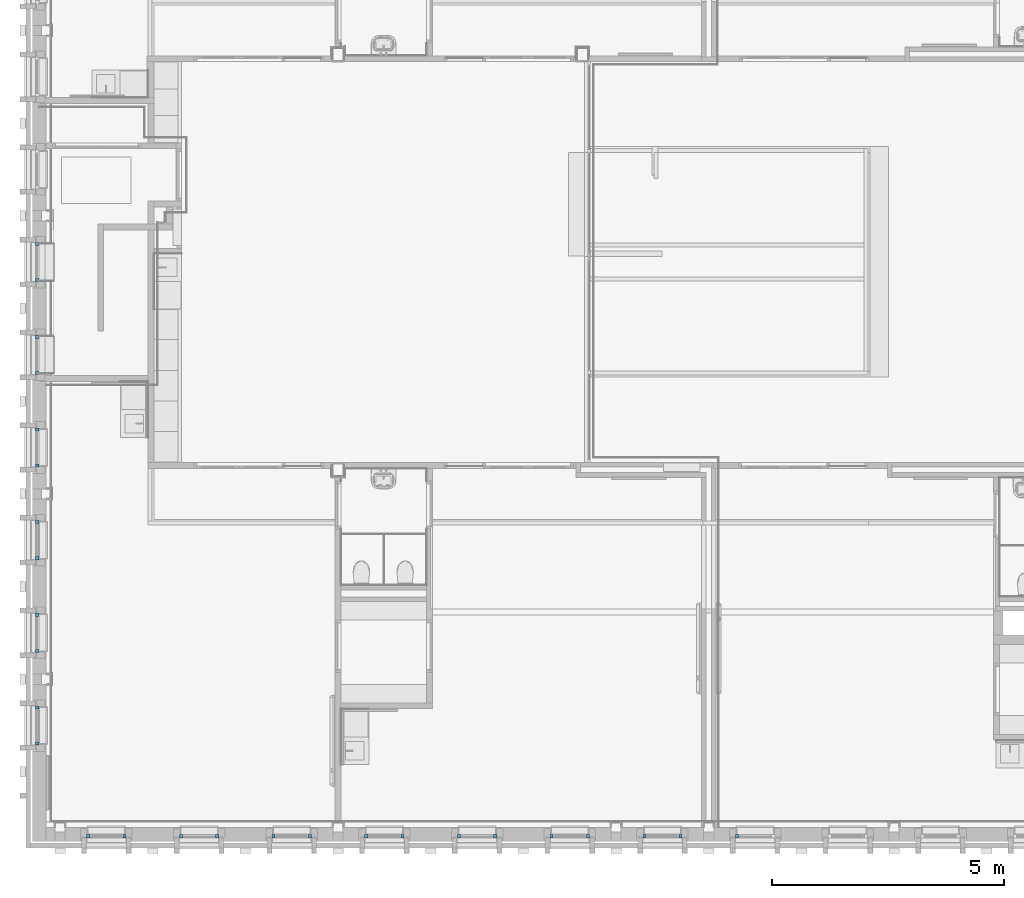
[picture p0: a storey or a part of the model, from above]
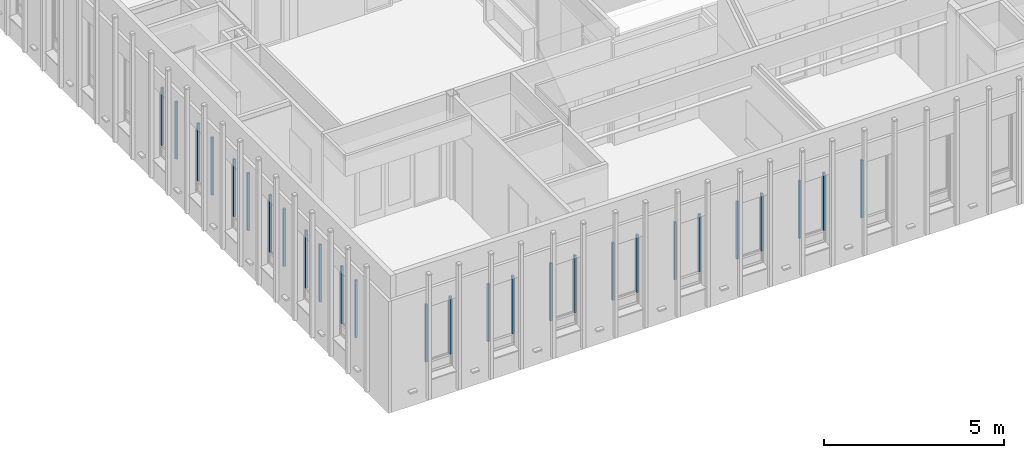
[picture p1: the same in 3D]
Properties of the parts of a building model (IFC2X3), part 85 of 94

# IfcWallStandardCase: Basic Wall:21_WA_metselwerk_middel_100_gen_bdg (555)
Name (Basic Wall:21_WA_metselwerk_middel_100_gen_bdg:...) | In | Base Constraint | Base Offset (mm) | Top Constraint | Top Offset (mm) | Unconnected Height (mm) | Area (m2) | Length (mm) | Volume (m3) | Group
774497 | 01 eerste verdieping | 01 eerste verdieping | 786 | Up to level: 02 tweede verdieping | 419 | 3433 | 0.738095 | 115 | 0.0738095 | Model Group:21_penant v1:774500
859356 | 01 eerste verdieping | 01 eerste verdieping | 2877 | Up to level: 02 tweede verdieping | 419 | 1342 | 0.02013 | 65 | 0.002013 | Model Group:21_penant v1:774500
859357 | 01 eerste verdieping | 01 eerste verdieping | 2877 | Up to level: 02 tweede verdieping | 419 | 1342 | 0.02013 | 65 | 0.002013 | Model Group:21_penant v1:774500
874895 | 01 eerste verdieping | 01 eerste verdieping | 786 | Up to level: 02 tweede verdieping | 419 | 3433 | 0.738095 | 115 | 0.0738095 | Model Group:21_penant v1:874898
874942 | 01 eerste verdieping | 01 eerste verdieping | 2877 | Up to level: 02 tweede verdieping | 419 | 1342 | 0.02013 | 65 | 0.002013 | Model Group:21_penant v1:874898
874943 | 01 eerste verdieping | 01 eerste verdieping | 2877 | Up to level: 02 tweede verdieping | 419 | 1342 | 0.02013 | 65 | 0.002013 | Model Group:21_penant v1:874898
874985 | 01 eerste verdieping | 01 eerste verdieping | 786 | Up to level: 02 tweede verdieping | 419 | 3433 | 0.738095 | 115 | 0.0738095 | Model Group:21_penant v1:874988
875032 | 01 eerste verdieping | 01 eerste verdieping | 2877 | Up to level: 02 tweede verdieping | 419 | 1342 | 0.02013 | 65 | 0.002013 | Model Group:21_penant v1:874988
875033 | 01 eerste verdieping | 01 eerste verdieping | 2877 | Up to level: 02 tweede verdieping | 419 | 1342 | 0.02013 | 65 | 0.002013 | Model Group:21_penant v1:874988
892017 | 00 begane grond | bk. fundering | 0 | Up to level: 01 eerste verdieping | 775 | 5295 | 1.25492 | 237 | 0.125492 | Model Group:21_penant_v0:892303
892047 | 01 eerste verdieping | 01 eerste verdieping | 786 | Up to level: 02 tweede verdieping | 419 | 3433 | 0.738095 | 115 | 0.0738095 | Model Group:21_penant v1:774399
892050 | 01 eerste verdieping | 01 eerste verdieping | 2877 | Up to level: 02 tweede verdieping | 419 | 1342 | 0.02013 | 65 | 0.002013 | Model Group:21_penant v1:774399
892051 | 01 eerste verdieping | 01 eerste verdieping | 2877 | Up to level: 02 tweede verdieping | 419 | 1342 | 0.02013 | 65 | 0.002013 | Model Group:21_penant v1:774399
892057 | 01 eerste verdieping | 01 eerste verdieping | 786 | Up to level: 02 tweede verdieping | 419 | 3433 | 0.738095 | 115 | 0.0738095 | Model Group:21_penant v1:774488
892060 | 01 eerste verdieping | 01 eerste verdieping | 2877 | Up to level: 02 tweede verdieping | 419 | 1342 | 0.02013 | 65 | 0.002013 | Model Group:21_penant v1:774488
892061 | 01 eerste verdieping | 01 eerste verdieping | 2877 | Up to level: 02 tweede verdieping | 419 | 1342 | 0.02013 | 65 | 0.002013 | Model Group:21_penant v1:774488
892062 | 01 eerste verdieping | 01 eerste verdieping | 786 | Up to level: 02 tweede verdieping | 419 | 3433 | 0.738095 | 115 | 0.0738095 | Model Group:21_penant v1:874890
892065 | 01 eerste verdieping | 01 eerste verdieping | 2877 | Up to level: 02 tweede verdieping | 419 | 1342 | 0.02013 | 65 | 0.002013 | Model Group:21_penant v1:874890
892066 | 01 eerste verdieping | 01 eerste verdieping | 2877 | Up to level: 02 tweede verdieping | 419 | 1342 | 0.02013 | 65 | 0.002013 | Model Group:21_penant v1:874890
892067 | 01 eerste verdieping | 01 eerste verdieping | 786 | Up to level: 02 tweede verdieping | 419 | 3433 | 0.738095 | 115 | 0.0738095 | Model Group:21_penant v1:874894
892070 | 01 eerste verdieping | 01 eerste verdieping | 2877 | Up to level: 02 tweede verdieping | 419 | 1342 | 0.02013 | 65 | 0.002013 | Model Group:21_penant v1:874894
892071 | 01 eerste verdieping | 01 eerste verdieping | 2877 | Up to level: 02 tweede verdieping | 419 | 1342 | 0.02013 | 65 | 0.002013 | Model Group:21_penant v1:874894
892072 | 01 eerste verdieping | 01 eerste verdieping | 786 | Up to level: 02 tweede verdieping | 419 | 3433 | 0.738095 | 115 | 0.0738095 | Model Group:21_penant v1:874980
892075 | 01 eerste verdieping | 01 eerste verdieping | 2877 | Up to level: 02 tweede verdieping | 419 | 1342 | 0.02013 | 65 | 0.002013 | Model Group:21_penant v1:874980
892076 | 01 eerste verdieping | 01 eerste verdieping | 2877 | Up to level: 02 tweede verdieping | 419 | 1342 | 0.02013 | 65 | 0.002013 | Model Group:21_penant v1:874980
892077 | 01 eerste verdieping | 01 eerste verdieping | 786 | Up to level: 02 tweede verdieping | 419 | 3433 | 0.738095 | 115 | 0.0738095 | Model Group:21_penant v1:874984
892080 | 01 eerste verdieping | 01 eerste verdieping | 2877 | Up to level: 02 tweede verdieping | 419 | 1342 | 0.02013 | 65 | 0.002013 | Model Group:21_penant v1:874984
892081 | 01 eerste verdieping | 01 eerste verdieping | 2877 | Up to level: 02 tweede verdieping | 419 | 1342 | 0.02013 | 65 | 0.002013 | Model Group:21_penant v1:874984
892082 | 01 eerste verdieping | 01 eerste verdieping | 786 | Up to level: 02 tweede verdieping | 419 | 3433 | 0.738095 | 115 | 0.0738095 | Model Group:21_penant v1:875217
892085 | 01 eerste verdieping | 01 eerste verdieping | 2877 | Up to level: 02 tweede verdieping | 419 | 1342 | 0.02013 | 65 | 0.002013 | Model Group:21_penant v1:875217
892086 | 01 eerste verdieping | 01 eerste verdieping | 2877 | Up to level: 02 tweede verdieping | 419 | 1342 | 0.02013 | 65 | 0.002013 | Model Group:21_penant v1:875217
892087 | 01 eerste verdieping | 01 eerste verdieping | 786 | Up to level: 02 tweede verdieping | 419 | 3433 | 0.738095 | 115 | 0.0738095 | Model Group:21_penant v1:875253
892090 | 01 eerste verdieping | 01 eerste verdieping | 2877 | Up to level: 02 tweede verdieping | 419 | 1342 | 0.02013 | 65 | 0.002013 | Model Group:21_penant v1:875253
892091 | 01 eerste verdieping | 01 eerste verdieping | 2877 | Up to level: 02 tweede verdieping | 419 | 1342 | 0.02013 | 65 | 0.002013 | Model Group:21_penant v1:875253
892092 | 01 eerste verdieping | 01 eerste verdieping | 786 | Up to level: 02 tweede verdieping | 419 | 3433 | 0.738095 | 115 | 0.0738095 | Model Group:21_penant v1:875289
892095 | 01 eerste verdieping | 01 eerste verdieping | 2877 | Up to level: 02 tweede verdieping | 419 | 1342 | 0.02013 | 65 | 0.002013 | Model Group:21_penant v1:875289
892096 | 01 eerste verdieping | 01 eerste verdieping | 2877 | Up to level: 02 tweede verdieping | 419 | 1342 | 0.02013 | 65 | 0.002013 | Model Group:21_penant v1:875289
892097 | 01 eerste verdieping | 01 eerste verdieping | 786 | Up to level: 02 tweede verdieping | 419 | 3433 | 0.738095 | 115 | 0.0738095 | Model Group:21_penant v1:875325
892100 | 01 eerste verdieping | 01 eerste verdieping | 2877 | Up to level: 02 tweede verdieping | 419 | 1342 | 0.02013 | 65 | 0.002013 | Model Group:21_penant v1:875325
892101 | 01 eerste verdieping | 01 eerste verdieping | 2877 | Up to level: 02 tweede verdieping | 419 | 1342 | 0.02013 | 65 | 0.002013 | Model Group:21_penant v1:875325
892102 | 01 eerste verdieping | 01 eerste verdieping | 786 | Up to level: 02 tweede verdieping | 419 | 3433 | 0.738095 | 115 | 0.0738095 | Model Group:21_penant v1:875361
892105 | 01 eerste verdieping | 01 eerste verdieping | 2877 | Up to level: 02 tweede verdieping | 419 | 1342 | 0.02013 | 65 | 0.002013 | Model Group:21_penant v1:875361
892106 | 01 eerste verdieping | 01 eerste verdieping | 2877 | Up to level: 02 tweede verdieping | 419 | 1342 | 0.02013 | 65 | 0.002013 | Model Group:21_penant v1:875361
892107 | 01 eerste verdieping | 01 eerste verdieping | 786 | Up to level: 02 tweede verdieping | 419 | 3433 | 0.738095 | 115 | 0.0738095 | Model Group:21_penant v1:876469
892110 | 01 eerste verdieping | 01 eerste verdieping | 2877 | Up to level: 02 tweede verdieping | 419 | 1342 | 0.02013 | 65 | 0.002013 | Model Group:21_penant v1:876469
892111 | 01 eerste verdieping | 01 eerste verdieping | 2877 | Up to level: 02 tweede verdieping | 419 | 1342 | 0.02013 | 65 | 0.002013 | Model Group:21_penant v1:876469
892112 | 01 eerste verdieping | 01 eerste verdieping | 786 | Up to level: 02 tweede verdieping | 419 | 3433 | 0.738095 | 115 | 0.0738095 | Model Group:21_penant v1:876484
892115 | 01 eerste verdieping | 01 eerste verdieping | 2877 | Up to level: 02 tweede verdieping | 419 | 1342 | 0.02013 | 65 | 0.002013 | Model Group:21_penant v1:876484
892116 | 01 eerste verdieping | 01 eerste verdieping | 2877 | Up to level: 02 tweede verdieping | 419 | 1342 | 0.02013 | 65 | 0.002013 | Model Group:21_penant v1:876484
892117 | 01 eerste verdieping | 01 eerste verdieping | 786 | Up to level: 02 tweede verdieping | 419 | 3433 | 0.738095 | 115 | 0.0738095 | Model Group:21_penant v1:876499
892120 | 01 eerste verdieping | 01 eerste verdieping | 2877 | Up to level: 02 tweede verdieping | 419 | 1342 | 0.02013 | 65 | 0.002013 | Model Group:21_penant v1:876499
892121 | 01 eerste verdieping | 01 eerste verdieping | 2877 | Up to level: 02 tweede verdieping | 419 | 1342 | 0.02013 | 65 | 0.002013 | Model Group:21_penant v1:876499
892122 | 01 eerste verdieping | 01 eerste verdieping | 786 | Up to level: 02 tweede verdieping | 419 | 3433 | 0.738095 | 115 | 0.0738095 | Model Group:21_penant v1:876887
892125 | 01 eerste verdieping | 01 eerste verdieping | 2877 | Up to level: 02 tweede verdieping | 419 | 1342 | 0.02013 | 65 | 0.002013 | Model Group:21_penant v1:876887
892126 | 01 eerste verdieping | 01 eerste verdieping | 2877 | Up to level: 02 tweede verdieping | 419 | 1342 | 0.02013 | 65 | 0.002013 | Model Group:21_penant v1:876887
892127 | 01 eerste verdieping | 01 eerste verdieping | 786 | Up to level: 02 tweede verdieping | 419 | 3433 | 0.738095 | 115 | 0.0738095 | Model Group:21_penant v1:876902
892130 | 01 eerste verdieping | 01 eerste verdieping | 2877 | Up to level: 02 tweede verdieping | 419 | 1342 | 0.02013 | 65 | 0.002013 | Model Group:21_penant v1:876902
892131 | 01 eerste verdieping | 01 eerste verdieping | 2877 | Up to level: 02 tweede verdieping | 419 | 1342 | 0.02013 | 65 | 0.002013 | Model Group:21_penant v1:876902
892132 | 01 eerste verdieping | 01 eerste verdieping | 786 | Up to level: 02 tweede verdieping | 419 | 3433 | 0.738095 | 115 | 0.0738095 | Model Group:21_penant v1:876917
892135 | 01 eerste verdieping | 01 eerste verdieping | 2877 | Up to level: 02 tweede verdieping | 419 | 1342 | 0.02013 | 65 | 0.002013 | Model Group:21_penant v1:876917
892136 | 01 eerste verdieping | 01 eerste verdieping | 2877 | Up to level: 02 tweede verdieping | 419 | 1342 | 0.02013 | 65 | 0.002013 | Model Group:21_penant v1:876917
892137 | 01 eerste verdieping | 01 eerste verdieping | 786 | Up to level: 02 tweede verdieping | 419 | 3433 | 0.738095 | 115 | 0.0738095 | Model Group:21_penant v1:877004
892140 | 01 eerste verdieping | 01 eerste verdieping | 2877 | Up to level: 02 tweede verdieping | 419 | 1342 | 0.02013 | 65 | 0.002013 | Model Group:21_penant v1:877004
892141 | 01 eerste verdieping | 01 eerste verdieping | 2877 | Up to level: 02 tweede verdieping | 419 | 1342 | 0.02013 | 65 | 0.002013 | Model Group:21_penant v1:877004
892142 | 01 eerste verdieping | 01 eerste verdieping | 786 | Up to level: 02 tweede verdieping | 419 | 3433 | 0.738095 | 115 | 0.0738095 | Model Group:21_penant v1:877019
892145 | 01 eerste verdieping | 01 eerste verdieping | 2877 | Up to level: 02 tweede verdieping | 419 | 1342 | 0.02013 | 65 | 0.002013 | Model Group:21_penant v1:877019
892146 | 01 eerste verdieping | 01 eerste verdieping | 2877 | Up to level: 02 tweede verdieping | 419 | 1342 | 0.02013 | 65 | 0.002013 | Model Group:21_penant v1:877019
892147 | 01 eerste verdieping | 01 eerste verdieping | 786 | Up to level: 02 tweede verdieping | 419 | 3433 | 0.738095 | 115 | 0.0738095 | Model Group:21_penant v1:877034
892150 | 01 eerste verdieping | 01 eerste verdieping | 2877 | Up to level: 02 tweede verdieping | 419 | 1342 | 0.02013 | 65 | 0.002013 | Model Group:21_penant v1:877034
892151 | 01 eerste verdieping | 01 eerste verdieping | 2877 | Up to level: 02 tweede verdieping | 419 | 1342 | 0.02013 | 65 | 0.002013 | Model Group:21_penant v1:877034
892152 | 01 eerste verdieping | 01 eerste verdieping | 786 | Up to level: 02 tweede verdieping | 419 | 3433 | 0.738095 | 115 | 0.0738095 | Model Group:21_penant v1:877094
892155 | 01 eerste verdieping | 01 eerste verdieping | 2877 | Up to level: 02 tweede verdieping | 419 | 1342 | 0.02013 | 65 | 0.002013 | Model Group:21_penant v1:877094
892156 | 01 eerste verdieping | 01 eerste verdieping | 2877 | Up to level: 02 tweede verdieping | 419 | 1342 | 0.02013 | 65 | 0.002013 | Model Group:21_penant v1:877094
892157 | 01 eerste verdieping | 01 eerste verdieping | 786 | Up to level: 02 tweede verdieping | 419 | 3433 | 0.738095 | 115 | 0.0738095 | Model Group:21_penant v1:877109
892160 | 01 eerste verdieping | 01 eerste verdieping | 2877 | Up to level: 02 tweede verdieping | 419 | 1342 | 0.02013 | 65 | 0.002013 | Model Group:21_penant v1:877109
892161 | 01 eerste verdieping | 01 eerste verdieping | 2877 | Up to level: 02 tweede verdieping | 419 | 1342 | 0.02013 | 65 | 0.002013 | Model Group:21_penant v1:877109
892162 | 01 eerste verdieping | 01 eerste verdieping | 786 | Up to level: 02 tweede verdieping | 419 | 3433 | 0.738095 | 115 | 0.0738095 | Model Group:21_penant v1:877124
892165 | 01 eerste verdieping | 01 eerste verdieping | 2877 | Up to level: 02 tweede verdieping | 419 | 1342 | 0.02013 | 65 | 0.002013 | Model Group:21_penant v1:877124
892166 | 01 eerste verdieping | 01 eerste verdieping | 2877 | Up to level: 02 tweede verdieping | 419 | 1342 | 0.02013 | 65 | 0.002013 | Model Group:21_penant v1:877124
892167 | 01 eerste verdieping | 01 eerste verdieping | 786 | Up to level: 02 tweede verdieping | 419 | 3433 | 0.738095 | 115 | 0.0738095 | Model Group:21_penant v1:877184
892170 | 01 eerste verdieping | 01 eerste verdieping | 2877 | Up to level: 02 tweede verdieping | 419 | 1342 | 0.02013 | 65 | 0.002013 | Model Group:21_penant v1:877184
892171 | 01 eerste verdieping | 01 eerste verdieping | 2877 | Up to level: 02 tweede verdieping | 419 | 1342 | 0.02013 | 65 | 0.002013 | Model Group:21_penant v1:877184
892172 | 01 eerste verdieping | 01 eerste verdieping | 786 | Up to level: 02 tweede verdieping | 419 | 3433 | 0.738095 | 115 | 0.0738095 | Model Group:21_penant v1:877199
892175 | 01 eerste verdieping | 01 eerste verdieping | 2877 | Up to level: 02 tweede verdieping | 419 | 1342 | 0.02013 | 65 | 0.002013 | Model Group:21_penant v1:877199
892176 | 01 eerste verdieping | 01 eerste verdieping | 2877 | Up to level: 02 tweede verdieping | 419 | 1342 | 0.02013 | 65 | 0.002013 | Model Group:21_penant v1:877199
892177 | 01 eerste verdieping | 01 eerste verdieping | 786 | Up to level: 02 tweede verdieping | 419 | 3433 | 0.738095 | 115 | 0.0738095 | Model Group:21_penant v1:877214
892180 | 01 eerste verdieping | 01 eerste verdieping | 2877 | Up to level: 02 tweede verdieping | 419 | 1342 | 0.02013 | 65 | 0.002013 | Model Group:21_penant v1:877214
892181 | 01 eerste verdieping | 01 eerste verdieping | 2877 | Up to level: 02 tweede verdieping | 419 | 1342 | 0.02013 | 65 | 0.002013 | Model Group:21_penant v1:877214
892182 | 01 eerste verdieping | 01 eerste verdieping | 786 | Up to level: 02 tweede verdieping | 419 | 3433 | 0.738095 | 115 | 0.0738095 | Model Group:21_penant v1:880918
892185 | 01 eerste verdieping | 01 eerste verdieping | 2877 | Up to level: 02 tweede verdieping | 419 | 1342 | 0.02013 | 65 | 0.002013 | Model Group:21_penant v1:880918
892186 | 01 eerste verdieping | 01 eerste verdieping | 2877 | Up to level: 02 tweede verdieping | 419 | 1342 | 0.02013 | 65 | 0.002013 | Model Group:21_penant v1:880918
892187 | 01 eerste verdieping | 01 eerste verdieping | 786 | Up to level: 02 tweede verdieping | 419 | 3433 | 0.738095 | 115 | 0.0738095 | Model Group:21_penant v1:881607
892190 | 01 eerste verdieping | 01 eerste verdieping | 2877 | Up to level: 02 tweede verdieping | 419 | 1342 | 0.02013 | 65 | 0.002013 | Model Group:21_penant v1:881607
892191 | 01 eerste verdieping | 01 eerste verdieping | 2877 | Up to level: 02 tweede verdieping | 419 | 1342 | 0.02013 | 65 | 0.002013 | Model Group:21_penant v1:881607
892192 | 01 eerste verdieping | 01 eerste verdieping | 786 | Up to level: 02 tweede verdieping | 419 | 3433 | 0.738095 | 115 | 0.0738095 | Model Group:21_penant v1:881643
892195 | 01 eerste verdieping | 01 eerste verdieping | 2877 | Up to level: 02 tweede verdieping | 419 | 1342 | 0.02013 | 65 | 0.002013 | Model Group:21_penant v1:881643
892196 | 01 eerste verdieping | 01 eerste verdieping | 2877 | Up to level: 02 tweede verdieping | 419 | 1342 | 0.02013 | 65 | 0.002013 | Model Group:21_penant v1:881643
892197 | 01 eerste verdieping | 01 eerste verdieping | 786 | Up to level: 02 tweede verdieping | 419 | 3433 | 0.738095 | 115 | 0.0738095 | Model Group:21_penant v1:881679
892200 | 01 eerste verdieping | 01 eerste verdieping | 2877 | Up to level: 02 tweede verdieping | 419 | 1342 | 0.02013 | 65 | 0.002013 | Model Group:21_penant v1:881679
892201 | 01 eerste verdieping | 01 eerste verdieping | 2877 | Up to level: 02 tweede verdieping | 419 | 1342 | 0.02013 | 65 | 0.002013 | Model Group:21_penant v1:881679
892202 | 01 eerste verdieping | 01 eerste verdieping | 786 | Up to level: 02 tweede verdieping | 419 | 3433 | 0.738095 | 115 | 0.0738095 | Model Group:21_penant v1:881755
892205 | 01 eerste verdieping | 01 eerste verdieping | 2877 | Up to level: 02 tweede verdieping | 419 | 1342 | 0.02013 | 65 | 0.002013 | Model Group:21_penant v1:881755
892206 | 01 eerste verdieping | 01 eerste verdieping | 2877 | Up to level: 02 tweede verdieping | 419 | 1342 | 0.02013 | 65 | 0.002013 | Model Group:21_penant v1:881755
892207 | 01 eerste verdieping | 01 eerste verdieping | 786 | Up to level: 02 tweede verdieping | 419 | 3433 | 0.738095 | 115 | 0.0738095 | Model Group:21_penant v1:881782
892210 | 01 eerste verdieping | 01 eerste verdieping | 2877 | Up to level: 02 tweede verdieping | 419 | 1342 | 0.02013 | 65 | 0.002013 | Model Group:21_penant v1:881782
892211 | 01 eerste verdieping | 01 eerste verdieping | 2877 | Up to level: 02 tweede verdieping | 419 | 1342 | 0.02013 | 65 | 0.002013 | Model Group:21_penant v1:881782
892212 | 01 eerste verdieping | 01 eerste verdieping | 786 | Up to level: 02 tweede verdieping | 419 | 3433 | 0.738095 | 115 | 0.0738095 | Model Group:21_penant v1:881809
892215 | 01 eerste verdieping | 01 eerste verdieping | 2877 | Up to level: 02 tweede verdieping | 419 | 1342 | 0.02013 | 65 | 0.002013 | Model Group:21_penant v1:881809
892216 | 01 eerste verdieping | 01 eerste verdieping | 2877 | Up to level: 02 tweede verdieping | 419 | 1342 | 0.02013 | 65 | 0.002013 | Model Group:21_penant v1:881809
892217 | 01 eerste verdieping | 01 eerste verdieping | 786 | Up to level: 02 tweede verdieping | 419 | 3433 | 0.738095 | 115 | 0.0738095 | Model Group:21_penant v1:891629
892220 | 01 eerste verdieping | 01 eerste verdieping | 2877 | Up to level: 02 tweede verdieping | 419 | 1342 | 0.02013 | 65 | 0.002013 | Model Group:21_penant v1:891629
892221 | 01 eerste verdieping | 01 eerste verdieping | 2877 | Up to level: 02 tweede verdieping | 419 | 1342 | 0.02013 | 65 | 0.002013 | Model Group:21_penant v1:891629
892222 | 01 eerste verdieping | 01 eerste verdieping | 786 | Up to level: 02 tweede verdieping | 419 | 3433 | 0.738095 | 115 | 0.0738095 | Model Group:21_penant v1:891651
892225 | 01 eerste verdieping | 01 eerste verdieping | 2877 | Up to level: 02 tweede verdieping | 419 | 1342 | 0.02013 | 65 | 0.002013 | Model Group:21_penant v1:891651
892226 | 01 eerste verdieping | 01 eerste verdieping | 2877 | Up to level: 02 tweede verdieping | 419 | 1342 | 0.02013 | 65 | 0.002013 | Model Group:21_penant v1:891651
892227 | 01 eerste verdieping | 01 eerste verdieping | 786 | Up to level: 02 tweede verdieping | 419 | 3433 | 0.738095 | 115 | 0.0738095 | Model Group:21_penant v1:891673
892230 | 01 eerste verdieping | 01 eerste verdieping | 2877 | Up to level: 02 tweede verdieping | 419 | 1342 | 0.02013 | 65 | 0.002013 | Model Group:21_penant v1:891673
892231 | 01 eerste verdieping | 01 eerste verdieping | 2877 | Up to level: 02 tweede verdieping | 419 | 1342 | 0.02013 | 65 | 0.002013 | Model Group:21_penant v1:891673
892232 | 01 eerste verdieping | 01 eerste verdieping | 786 | Up to level: 02 tweede verdieping | 419 | 3433 | 0.738095 | 115 | 0.0738095 | Model Group:21_penant v1:891695
892235 | 01 eerste verdieping | 01 eerste verdieping | 2877 | Up to level: 02 tweede verdieping | 419 | 1342 | 0.02013 | 65 | 0.002013 | Model Group:21_penant v1:891695
892236 | 01 eerste verdieping | 01 eerste verdieping | 2877 | Up to level: 02 tweede verdieping | 419 | 1342 | 0.02013 | 65 | 0.002013 | Model Group:21_penant v1:891695
892237 | 01 eerste verdieping | 01 eerste verdieping | 786 | Up to level: 02 tweede verdieping | 419 | 3433 | 0.738095 | 115 | 0.0738095 | Model Group:21_penant v1:891717
892240 | 01 eerste verdieping | 01 eerste verdieping | 2877 | Up to level: 02 tweede verdieping | 419 | 1342 | 0.02013 | 65 | 0.002013 | Model Group:21_penant v1:891717
892241 | 01 eerste verdieping | 01 eerste verdieping | 2877 | Up to level: 02 tweede verdieping | 419 | 1342 | 0.02013 | 65 | 0.002013 | Model Group:21_penant v1:891717
892242 | 01 eerste verdieping | 01 eerste verdieping | 786 | Up to level: 02 tweede verdieping | 419 | 3433 | 0.738095 | 115 | 0.0738095 | Model Group:21_penant v1:891763
892245 | 01 eerste verdieping | 01 eerste verdieping | 2877 | Up to level: 02 tweede verdieping | 419 | 1342 | 0.02013 | 65 | 0.002013 | Model Group:21_penant v1:891763
892246 | 01 eerste verdieping | 01 eerste verdieping | 2877 | Up to level: 02 tweede verdieping | 419 | 1342 | 0.02013 | 65 | 0.002013 | Model Group:21_penant v1:891763
892247 | 01 eerste verdieping | 01 eerste verdieping | 786 | Up to level: 02 tweede verdieping | 419 | 3433 | 0.738095 | 115 | 0.0738095 | Model Group:21_penant v1:891785
892250 | 01 eerste verdieping | 01 eerste verdieping | 2877 | Up to level: 02 tweede verdieping | 419 | 1342 | 0.02013 | 65 | 0.002013 | Model Group:21_penant v1:891785
892251 | 01 eerste verdieping | 01 eerste verdieping | 2877 | Up to level: 02 tweede verdieping | 419 | 1342 | 0.02013 | 65 | 0.002013 | Model Group:21_penant v1:891785
892252 | 01 eerste verdieping | 01 eerste verdieping | 786 | Up to level: 02 tweede verdieping | 419 | 3433 | 0.738095 | 115 | 0.0738095 | Model Group:21_penant v1:891807
892255 | 01 eerste verdieping | 01 eerste verdieping | 2877 | Up to level: 02 tweede verdieping | 419 | 1342 | 0.02013 | 65 | 0.002013 | Model Group:21_penant v1:891807
892256 | 01 eerste verdieping | 01 eerste verdieping | 2877 | Up to level: 02 tweede verdieping | 419 | 1342 | 0.02013 | 65 | 0.002013 | Model Group:21_penant v1:891807
892257 | 01 eerste verdieping | 01 eerste verdieping | 775 | Up to level: 02 tweede verdieping | 419 | 3444 | 0.74046 | 115 | 0.074046
892258 | 01 eerste verdieping | 01 eerste verdieping | 775 | Up to level: 02 tweede verdieping | 419 | 3444 | 0.05166 | 115 | 0.005166
892259 | 01 eerste verdieping | 01 eerste verdieping | 775 | Up to level: 02 tweede verdieping | 419 | 3444 | 0.05166 | 115 | 0.005166
892262 | 01 eerste verdieping | 01 eerste verdieping | 775 | Up to level: 02 tweede verdieping | 419 | 3444 | 0.74046 | 115 | 0.074046
892263 | 01 eerste verdieping | 01 eerste verdieping | 775 | Up to level: 02 tweede verdieping | 419 | 3444 | 0.05166 | 115 | 0.005166
892264 | 01 eerste verdieping | 01 eerste verdieping | 775 | Up to level: 02 tweede verdieping | 419 | 3444 | 0.05166 | 115 | 0.005166
892277 | 01 eerste verdieping | 01 eerste verdieping | 786 | Up to level: 02 tweede verdieping | 419 | 3433 | 0.738095 | 115 | 0.0738095 | Model Group:21_penant v1:891902
892280 | 01 eerste verdieping | 01 eerste verdieping | 2877 | Up to level: 02 tweede verdieping | 419 | 1342 | 0.02013 | 65 | 0.002013 | Model Group:21_penant v1:891902
892281 | 01 eerste verdieping | 01 eerste verdieping | 2877 | Up to level: 02 tweede verdieping | 419 | 1342 | 0.02013 | 65 | 0.002013 | Model Group:21_penant v1:891902
892282 | 01 eerste verdieping | 01 eerste verdieping | 786 | Up to level: 02 tweede verdieping | 419 | 3433 | 0.738095 | 115 | 0.0738095 | Model Group:21_penant v1:891924
892285 | 01 eerste verdieping | 01 eerste verdieping | 2877 | Up to level: 02 tweede verdieping | 419 | 1342 | 0.02013 | 65 | 0.002013 | Model Group:21_penant v1:891924
892286 | 01 eerste verdieping | 01 eerste verdieping | 2877 | Up to level: 02 tweede verdieping | 419 | 1342 | 0.02013 | 65 | 0.002013 | Model Group:21_penant v1:891924
892287 | 01 eerste verdieping | 01 eerste verdieping | 786 | Up to level: 02 tweede verdieping | 419 | 3433 | 0.738095 | 115 | 0.0738095 | Model Group:21_penant v1:891946
892290 | 01 eerste verdieping | 01 eerste verdieping | 2877 | Up to level: 02 tweede verdieping | 419 | 1342 | 0.02013 | 65 | 0.002013 | Model Group:21_penant v1:891946
892291 | 01 eerste verdieping | 01 eerste verdieping | 2877 | Up to level: 02 tweede verdieping | 419 | 1342 | 0.02013 | 65 | 0.002013 | Model Group:21_penant v1:891946
892292 | 01 eerste verdieping | 01 eerste verdieping | 786 | Up to level: 02 tweede verdieping | 419 | 3433 | 0.738095 | 115 | 0.0738095 | Model Group:21_penant v1:891974
892295 | 01 eerste verdieping | 01 eerste verdieping | 2877 | Up to level: 02 tweede verdieping | 419 | 1342 | 0.02013 | 65 | 0.002013 | Model Group:21_penant v1:891974
892296 | 01 eerste verdieping | 01 eerste verdieping | 2877 | Up to level: 02 tweede verdieping | 419 | 1342 | 0.02013 | 65 | 0.002013 | Model Group:21_penant v1:891974
892297 | 01 eerste verdieping | 01 eerste verdieping | 786 | Up to level: 02 tweede verdieping | 419 | 3433 | 0.738095 | 115 | 0.0738095 | Model Group:21_penant v1:891996
892300 | 01 eerste verdieping | 01 eerste verdieping | 2877 | Up to level: 02 tweede verdieping | 419 | 1342 | 0.02013 | 65 | 0.002013 | Model Group:21_penant v1:891996
892301 | 01 eerste verdieping | 01 eerste verdieping | 2877 | Up to level: 02 tweede verdieping | 419 | 1342 | 0.02013 | 65 | 0.002013 | Model Group:21_penant v1:891996
892309 | 00 begane grond | bk. fundering | 0 | Up to level: 01 eerste verdieping | 775 | 5295 | 1.25492 | 237 | 0.125492 | Model Group:21_penant_v0:892310
892313 | 00 begane grond | bk. fundering | 0 | Up to level: 00 begane grond | 3433 | 3953 | 1.69979 | 430 | 0.169979
892318 | 00 begane grond | bk. fundering | 0 | Up to level: 00 begane grond | 3433 | 3953 | 1.69979 | 380 | 0.169979
892319 | 00 begane grond | bk. fundering | 0 | Up to level: 00 begane grond | 3433 | 3953 | 0.454595 | 165 | 0.0454595
892321 | 00 begane grond | 00 begane grond | 3433 | Up to level: 00 begane grond | 4356 | 923 | 4.66023 | 5049 | 0.466023
892340 | 00 begane grond | bk. fundering | 0 | Up to level: 00 begane grond | 3433 | 3953 | 1.69979 | 380 | 0.169979
892341 | 00 begane grond | bk. fundering | 0 | Up to level: 00 begane grond | 3433 | 3953 | 0.454595 | 165 | 0.0454595
892342 | 00 begane grond | bk. fundering | 0 | Up to level: 00 begane grond | 3433 | 3953 | 1.69979 | 380 | 0.169979
892343 | 00 begane grond | bk. fundering | 0 | Up to level: 00 begane grond | 3433 | 3953 | 0.454595 | 165 | 0.0454595
892345 | 00 begane grond | 00 begane grond | 3433 | Up to level: 00 begane grond | 4356 | 923 | 4.66023 | 5049 | 0.466023
892357 | 00 begane grond | bk. fundering | 0 | Up to level: 01 eerste verdieping | 775 | 5295 | 1.25492 | 237 | 0.125492 | Model Group:21_penant_v0:892358
892362 | 00 begane grond | bk. fundering | 0 | Up to level: 00 begane grond | 3433 | 3953 | 1.69979 | 430 | 0.169979
892364 | 00 begane grond | bk. fundering | 0 | Up to level: 00 begane grond | 3433 | 3953 | 1.69979 | 380 | 0.169979
892365 | 00 begane grond | bk. fundering | 0 | Up to level: 00 begane grond | 3433 | 3953 | 0.454595 | 165 | 0.0454595
892367 | 00 begane grond | 00 begane grond | 3433 | Up to level: 00 begane grond | 4356 | 923 | 4.66023 | 5049 | 0.466023
892369 | 00 begane grond | bk. fundering | 0 | Up to level: 01 eerste verdieping | 775 | 5295 | 1.25492 | 237 | 0.125492 | Model Group:21_penant_v0:892370
892374 | 00 begane grond | bk. fundering | 0 | Up to level: 00 begane grond | 3433 | 3953 | 1.69979 | 380 | 0.169979
892375 | 00 begane grond | bk. fundering | 0 | Up to level: 00 begane grond | 3433 | 3953 | 0.454595 | 165 | 0.0454595
892376 | 00 begane grond | bk. fundering | 0 | Up to level: 00 begane grond | 3433 | 3953 | 1.69979 | 430 | 0.169979
892379 | 00 begane grond | 00 begane grond | 3433 | Up to level: 00 begane grond | 4356 | 923 | 4.66023 | 5049 | 0.466023
892381 | 00 begane grond | bk. fundering | 0 | Up to level: 01 eerste verdieping | 775 | 5295 | 1.25492 | 237 | 0.125492 | Model Group:21_penant_v0:892382
892386 | 00 begane grond | bk. fundering | 0 | Up to level: 00 begane grond | 3433 | 3953 | 1.69979 | 380 | 0.169979
892387 | 00 begane grond | bk. fundering | 0 | Up to level: 00 begane grond | 3433 | 3953 | 0.454595 | 165 | 0.0454595
892388 | 00 begane grond | bk. fundering | 0 | Up to level: 00 begane grond | 3433 | 3953 | 1.69979 | 380 | 0.169979
892389 | 00 begane grond | bk. fundering | 0 | Up to level: 00 begane grond | 3433 | 3953 | 0.454595 | 165 | 0.0454595
892391 | 00 begane grond | 00 begane grond | 3433 | Up to level: 00 begane grond | 4356 | 923 | 4.66023 | 5049 | 0.466023
892407 | 00 begane grond | bk. fundering | 0 | Up to level: 01 eerste verdieping | 775 | 5295 | 1.25492 | 237 | 0.125492 | Model Group:21_penant_v0:892408
892412 | 00 begane grond | bk. fundering | 0 | Up to level: 00 begane grond | 3433 | 3953 | 1.69979 | 380 | 0.169979
892413 | 00 begane grond | bk. fundering | 0 | Up to level: 00 begane grond | 3433 | 3953 | 0.454595 | 165 | 0.0454595
892414 | 00 begane grond | bk. fundering | 0 | Up to level: 00 begane grond | 3433 | 3953 | 1.69979 | 380 | 0.169979
892415 | 00 begane grond | bk. fundering | 0 | Up to level: 00 begane grond | 3433 | 3953 | 0.454595 | 165 | 0.0454595
892417 | 00 begane grond | 00 begane grond | 3433 | Up to level: 00 begane grond | 4356 | 923 | 4.66023 | 5049 | 0.466023
892432 | 00 begane grond | bk. fundering | 0 | Up to level: 01 eerste verdieping | 775 | 5295 | 1.25492 | 237 | 0.125492 | Model Group:21_penant_v0:892433
892437 | 00 begane grond | bk. fundering | 0 | Up to level: 00 begane grond | 3433 | 3953 | 1.69979 | 380 | 0.169979
892438 | 00 begane grond | bk. fundering | 0 | Up to level: 00 begane grond | 3433 | 3953 | 0.454595 | 165 | 0.0454595
892439 | 00 begane grond | bk. fundering | 0 | Up to level: 00 begane grond | 3433 | 3953 | 1.69979 | 380 | 0.169979
892440 | 00 begane grond | bk. fundering | 0 | Up to level: 00 begane grond | 3433 | 3953 | 0.454595 | 165 | 0.0454595
892442 | 00 begane grond | 00 begane grond | 3433 | Up to level: 00 begane grond | 4356 | 923 | 4.66023 | 5049 | 0.466023
892446 | 00 begane grond | bk. fundering | 0 | Up to level: 01 eerste verdieping | 775 | 5295 | 1.25492 | 237 | 0.125492 | Model Group:21_penant_v0:892447
892451 | 00 begane grond | bk. fundering | 0 | Up to level: 00 begane grond | 3433 | 3953 | 1.69979 | 380 | 0.169979
892452 | 00 begane grond | bk. fundering | 0 | Up to level: 00 begane grond | 3433 | 3953 | 0.454595 | 165 | 0.0454595
892456 | 00 begane grond | 00 begane grond | 3433 | Up to level: 00 begane grond | 4356 | 923 | 5.70368 | 6229.5 | 0.570368
892463 | 00 begane grond | bk. fundering | 0 | Up to level: 01 eerste verdieping | 775 | 5295 | 1.25492 | 237 | 0.125492 | Model Group:21_penant_v0:892464
892468 | 00 begane grond | bk. fundering | 0 | Up to level: 00 begane grond | 3433 | 3953 | 1.69979 | 430 | 0.169979
892470 | 00 begane grond | bk. fundering | 0 | Up to level: 00 begane grond | 3433 | 3953 | 1.69979 | 380 | 0.169979
892471 | 00 begane grond | bk. fundering | 0 | Up to level: 00 begane grond | 3433 | 3953 | 0.454595 | 165 | 0.0454595
892473 | 00 begane grond | 00 begane grond | 3433 | Up to level: 00 begane grond | 4356 | 923 | 4.66023 | 5049 | 0.466023
892484 | 00 begane grond | bk. fundering | 0 | Up to level: 00 begane grond | 3433 | 3953 | 1.69979 | 380 | 0.169979
892485 | 00 begane grond | bk. fundering | 0 | Up to level: 00 begane grond | 3433 | 3953 | 1.20962 | 356 | 0.120962
892487 | 00 begane grond | 00 begane grond | 3433 | Up to level: 00 begane grond | 4356 | 923 | 4.31918 | 4729.5 | 0.431918
892508 | 00 begane grond | 00 begane grond | 3433 | Up to level: 00 begane grond | 4356 | 923 | 2.1229 | 2250 | 0.21229
892517 | 00 begane grond | bk. fundering | 0 | Up to level: 01 eerste verdieping | 775 | 5295 | 1.25492 | 237 | 0.125492 | Model Group:21_penant_v0:892518
892522 | 00 begane grond | bk. fundering | 0 | Up to level: 00 begane grond | 3433 | 3953 | 1.69979 | 430 | 0.169979
892524 | 00 begane grond | bk. fundering | 0 | Up to level: 00 begane grond | 3433 | 3953 | 1.69979 | 380 | 0.169979
892525 | 00 begane grond | bk. fundering | 0 | Up to level: 00 begane grond | 3433 | 3953 | 0.454595 | 165 | 0.0454595
892527 | 00 begane grond | 00 begane grond | 3433 | Up to level: 00 begane grond | 4356 | 923 | 4.66023 | 5049 | 0.466023
892529 | 00 begane grond | bk. fundering | 0 | Up to level: 01 eerste verdieping | 775 | 5295 | 1.25492 | 237 | 0.125492 | Model Group:21_penant_v0:892530
892534 | 00 begane grond | bk. fundering | 0 | Up to level: 00 begane grond | 3433 | 3953 | 1.69979 | 430 | 0.169979
892539 | 00 begane grond | 00 begane grond | 3433 | Up to level: 00 begane grond | 4356 | 923 | 0.29536 | 320 | 0.029536
1223868 | 00 begane grond | bk. fundering | 0 | Up to level: 00 begane grond | 3433 | 3953 | 1.69979 | 430 | 0.169979
1223871 | 00 begane grond | 00 begane grond | 3433 | Up to level: 00 begane grond | 4356 | 923 | 2.93468 | 3129.5 | 0.293468
1223873 | 00 begane grond | bk. fundering | 0 | Up to level: 01 eerste verdieping | 775 | 5295 | 1.25492 | 237 | 0.125492 | Model Group:21_penant_v0:1223874
1224021 | 00 begane grond | bk. fundering | 0 | Up to level: 00 begane grond | 3433 | 3953 | 1.69979 | 380 | 0.169979
1224022 | 00 begane grond | bk. fundering | 0 | Up to level: 00 begane grond | 3433 | 3953 | 0.454595 | 165 | 0.0454595
1224026 | 00 begane grond | 00 begane grond | 3433 | Up to level: 00 begane grond | 4356 | 923 | 3.16543 | 3429.5 | 0.316543
1224075 | 00 begane grond | bk. fundering | 0 | Up to level: 00 begane grond | 3433 | 3953 | 1.69979 | 430 | 0.169979
1224078 | 00 begane grond | 00 begane grond | 3433 | Up to level: 00 begane grond | 4356 | 923 | 4.20896 | 4560.09 | 0.420896
1224080 | 00 begane grond | bk. fundering | 0 | Up to level: 01 eerste verdieping | 775 | 5295 | 1.25492 | 237 | 0.125492 | Model Group:21_penant_v0:1224081
1224129 | 00 begane grond | bk. fundering | 0 | Up to level: 00 begane grond | 3433 | 3953 | 1.69979 | 380 | 0.169979
1224130 | 00 begane grond | bk. fundering | 0 | Up to level: 00 begane grond | 3433 | 3953 | 0.454595 | 165 | 0.0454595
1224131 | 00 begane grond | bk. fundering | 0 | Up to level: 00 begane grond | 3433 | 3953 | 1.69979 | 380 | 0.169979
1224132 | 00 begane grond | bk. fundering | 0 | Up to level: 00 begane grond | 3433 | 3953 | 0.454595 | 165 | 0.0454595
1224134 | 00 begane grond | 00 begane grond | 3433 | Up to level: 00 begane grond | 4356 | 923 | 4.66023 | 5049 | 0.466023
1224136 | 00 begane grond | bk. fundering | 0 | Up to level: 01 eerste verdieping | 775 | 5295 | 1.25492 | 237 | 0.125492 | Model Group:21_penant_v0:1224137
1289383 | 00 begane grond | bk. fundering | 0 | Up to level: 00 begane grond | 3433 | 3953 | 1.69979 | 380 | 0.169979
1289388 | 00 begane grond | 00 begane grond | 3433 | Up to level: 00 begane grond | 4356 | 923 | 1.84092 | 1994.5 | 0.184092
1289940 | 00 begane grond | bk. fundering | 0 | Up to level: 01 eerste verdieping | 775 | 5295 | 1.25492 | 237 | 0.125492 | Model Group:21_penant_v0:1289941
1289944 | 00 begane grond | bk. fundering | 0 | Up to level: 00 begane grond | 3438.3 | 3958.3 | 1.69979 | 380 | 0.169979
1289945 | 00 begane grond | bk. fundering | 0 | Up to level: 00 begane grond | 3003 | 3523 | 2.30757 | 655 | 0.230757
1289946 | 00 begane grond | bk. fundering | 0 | Up to level: 00 begane grond | 3433 | 3953 | 1.69979 | 380 | 0.169979
1289947 | 00 begane grond | bk. fundering | 0 | Up to level: 00 begane grond | 3433 | 3953 | 0.454595 | 165 | 0.0454595
1289949 | 00 begane grond | 00 begane grond | 3433 | Up to level: 00 begane grond | 4356 | 923 | 4.66023 | 5049 | 0.466023
1289967 | 00 begane grond | bk. fundering | 0 | Up to level: 00 begane grond | 3438.3 | 3958.3 | 1.70207 | 380 | 0.170207
1289968 | 00 begane grond | bk. fundering | 0 | Up to level: 00 begane grond | 3003 | 3523 | 2.30756 | 655 | 0.230756
1289970 | 00 begane grond | 00 begane grond | 3433 | Up to level: 00 begane grond | 4356 | 923 | 5.80754 | 6294.5 | 0.580754
1290881 | 00 begane grond | 00 begane grond | 3433 | Up to level: 00 begane grond | 4356 | 923 | 1.71807 | 1782.85 | 0.163469 | Graphics - Center Mark Visible: no
1291319 | 00 begane grond | 00 begane grond | 0 | Up to level: 00 begane grond | 3003 | 3003 | 4.83783 | 1711 | 0.483783
1302572 | 01 eerste verdieping | 01 eerste verdieping | 786 | Up to level: 02 tweede verdieping | 419 | 3433 | 0.738095 | 115 | 0.0738095 | Model Group:21_penant v1 ROND:1302570
1302575 | 01 eerste verdieping | 01 eerste verdieping | 2877 | Up to level: 02 tweede verdieping | 419 | 1342 | 0.02013 | 65 | 0.002013 | Model Group:21_penant v1 ROND:1302570
1302576 | 01 eerste verdieping | 01 eerste verdieping | 2877 | Up to level: 02 tweede verdieping | 419 | 1342 | 0.02013 | 65 | 0.002013 | Model Group:21_penant v1 ROND:1302570
1306098 | 01 eerste verdieping | 01 eerste verdieping | 150 | Up to level: 01 eerste verdieping | 775 | 625 | 0.21875 | 250 | 0.021875
1308306 | 00 begane grond | bk. fundering | 0 | Up to level: 01 eerste verdieping | 775 | 5295 | 1.19667 | 226 | 0.119667
1308576 | 00 begane grond | bk. fundering | 0 | Up to level: 01 eerste verdieping | 0 | 4520 | 22.765 | 6670 | 2.2765
1308626 | 00 begane grond | bk. fundering | 0 | Up to level: 01 eerste verdieping | 775 | 5295 | 1.25492 | 237 | 0.125492 | Model Group:21_penant_v0:1308627
1309195 | 00 begane grond | bk. fundering | 0 | Up to level: 01 eerste verdieping | 0 | 4520 | 22.6848 | 6717.5 | 2.26848
1310174 | 00 begane grond | bk. fundering | 0 | Up to level: 00 begane grond | 3433 | 3953 | 1.69979 | 380 | 0.169979
1310175 | 00 begane grond | bk. fundering | 0 | Up to level: 00 begane grond | 3433 | 3953 | 0.454595 | 165 | 0.0454595
1310176 | 00 begane grond | bk. fundering | 0 | Up to level: 00 begane grond | 3433 | 3953 | 1.69979 | 380 | 0.169979
1310177 | 00 begane grond | bk. fundering | 0 | Up to level: 00 begane grond | 3433 | 3953 | 0.454595 | 165 | 0.0454595
1310179 | 00 begane grond | 00 begane grond | 3433 | Up to level: 00 begane grond | 4356 | 923 | 4.66023 | 5049 | 0.466023
1310181 | 00 begane grond | bk. fundering | 0 | Up to level: 01 eerste verdieping | 775 | 5295 | 1.25492 | 237 | 0.125492 | Model Group:21_penant_v0:1310182
1310414 | 00 begane grond | bk. fundering | 0 | Up to level: 00 begane grond | 3438.3 | 3958.3 | 1.69979 | 430 | 0.169979
1310416 | 00 begane grond | bk. fundering | 0 | Up to level: 00 begane grond | 3433 | 3953 | 1.69979 | 380 | 0.169979
1310417 | 00 begane grond | bk. fundering | 0 | Up to level: 00 begane grond | 3433 | 3953 | 0.454595 | 165 | 0.0454595
1310419 | 00 begane grond | 00 begane grond | 3433 | Up to level: 00 begane grond | 4356 | 923 | 4.66023 | 5049 | 0.466023
1311149 | 00 begane grond | bk. fundering | 0 | Up to level: 01 eerste verdieping | 775 | 5295 | 1.25492 | 237 | 0.125492 | Model Group:21_penant_v0:1311150
1311154 | 00 begane grond | bk. fundering | 0 | Up to level: 00 begane grond | 3433 | 3953 | 1.69979 | 380 | 0.169979
1311155 | 00 begane grond | bk. fundering | 0 | Up to level: 00 begane grond | 3433 | 3953 | 0.454595 | 165 | 0.0454595
1311156 | 00 begane grond | bk. fundering | 0 | Up to level: 00 begane grond | 3433 | 3953 | 1.69979 | 430 | 0.169979
1311159 | 00 begane grond | 00 begane grond | 3433 | Up to level: 00 begane grond | 4356 | 923 | 4.66023 | 5049 | 0.466023
1341017 | 01 eerste verdieping | 01 eerste verdieping | 786 | Up to level: 02 tweede verdieping | 419 | 3433 | 0.738095 | 115 | 0.0738095 | Model Group:21_penant v1 ROND:1341016
1341020 | 01 eerste verdieping | 01 eerste verdieping | 2877 | Up to level: 02 tweede verdieping | 419 | 1342 | 0.02013 | 65 | 0.002013 | Model Group:21_penant v1 ROND:1341016
1341021 | 01 eerste verdieping | 01 eerste verdieping | 2877 | Up to level: 02 tweede verdieping | 419 | 1342 | 0.02013 | 65 | 0.002013 | Model Group:21_penant v1 ROND:1341016
1341913 | 00 begane grond | 00 begane grond | 3433 | Up to level: 00 begane grond | 4356 | 923 | 0.39689 | 430 | 0.039689
1343015 | 00 begane grond | bk. fundering | 0 | Up to level: 00 begane grond | 3433 | 3953 | 1.69979 | 430 | 0.169979
1343017 | 00 begane grond | bk. fundering | 0 | Up to level: 00 begane grond | 3433 | 3953 | 1.69979 | 430 | 0.169979
1343020 | 00 begane grond | 00 begane grond | 3433 | Up to level: 00 begane grond | 4356 | 923 | 4.66023 | 5049 | 0.466023
1343143 | 00 begane grond | bk. fundering | 0 | Up to level: 01 eerste verdieping | 775 | 5295 | 1.25492 | 237 | 0.125491 | Model Group:21_penant_v0:1343144
1343580 | 00 begane grond | bk. fundering | 0 | Up to level: 00 begane grond | 3433 | 3953 | 1.70177 | 430.5 | 0.170177
1343583 | 00 begane grond | 00 begane grond | 3433 | Up to level: 00 begane grond | 4356 | 923 | 1.39788 | 1514.5 | 0.139788
1345435 | 00 begane grond | 00 begane grond | 3433 | Up to level: 00 begane grond | 4356 | 923 | 5.37656 | 5825.09 | 0.537656
1348308 | 00 begane grond | bk. fundering | 0 | Up to level: 00 begane grond | 3433 | 3953 | 1.69979 | 430 | 0.169979
1348311 | 00 begane grond | 00 begane grond | 3433 | Up to level: 00 begane grond | 4356 | 923 | 1.55479 | 1684.5 | 0.155479
1348669 | 00 begane grond | bk. fundering | 0 | Up to level: 00 begane grond | 3433 | 3953 | 1.69979 | 430 | 0.169979
1348671 | 00 begane grond | bk. fundering | 0 | Up to level: 00 begane grond | 3433 | 3953 | 1.69979 | 380 | 0.169979
1348672 | 00 begane grond | bk. fundering | 0 | Up to level: 00 begane grond | 3433 | 3953 | 0.454595 | 165 | 0.0454595
1348674 | 00 begane grond | 00 begane grond | 3433 | Up to level: 00 begane grond | 4356 | 923 | 4.66023 | 5049 | 0.466023
1348942 | 00 begane grond | bk. fundering | 0 | Up to level: 00 begane grond | 3433 | 3953 | 1.69979 | 430 | 0.169979
1348947 | 00 begane grond | 00 begane grond | 3433 | Up to level: 00 begane grond | 4356 | 923 | 3.11466 | 3324.5 | 0.311466
1349247 | 00 begane grond | 00 begane grond | 3433 | Up to level: 00 begane grond | 4356 | 923 | 4.7073 | 5150 | 0.47073
1500582 | 00 begane grond | bk. fundering | 0 | Up to level: 00 begane grond | 3433 | 3953 | 1.69979 | 430 | 0.169979
1500584 | 00 begane grond | bk. fundering | 0 | Up to level: 00 begane grond | 3433 | 3953 | 1.69979 | 430 | 0.169979
1500587 | 00 begane grond | 00 begane grond | 3433 | Up to level: 00 begane grond | 4356 | 923 | 4.66023 | 5049 | 0.466023
1500612 | 00 begane grond | bk. fundering | 0 | Up to level: 00 begane grond | 3433 | 3953 | 1.69979 | 430 | 0.169979
1500614 | 00 begane grond | bk. fundering | 0 | Up to level: 00 begane grond | 3433 | 3953 | 1.69979 | 380 | 0.169979
1500615 | 00 begane grond | bk. fundering | 0 | Up to level: 00 begane grond | 3433 | 3953 | 0.454595 | 165 | 0.0454595
1500617 | 00 begane grond | 00 begane grond | 3433 | Up to level: 00 begane grond | 4356 | 923 | 4.66023 | 5049 | 0.466023
1500633 | 00 begane grond | bk. fundering | 0 | Up to level: 00 begane grond | 3433 | 3953 | 1.69979 | 430 | 0.169979
1500636 | 00 begane grond | 00 begane grond | 3433 | Up to level: 00 begane grond | 4356 | 923 | 4.04228 | 4329.5 | 0.404228
1500900 | 00 begane grond | bk. fundering | 0 | Up to level: 00 begane grond | 3433 | 3953 | 1.30449 | 380 | 0.130449
1500902 | 00 begane grond | bk. fundering | 0 | Up to level: 00 begane grond | 3433 | 3953 | 1.69979 | 430 | 0.169979
1500905 | 00 begane grond | 00 begane grond | 3433 | Up to level: 00 begane grond | 4356 | 923 | 4.66023 | 5049 | 0.466023
1500925 | 00 begane grond | bk. fundering | 0 | Up to level: 00 begane grond | 3433 | 3953 | 1.69979 | 380 | 0.169979
1500926 | 00 begane grond | bk. fundering | 0 | Up to level: 00 begane grond | 3433 | 3953 | 0.454595 | 165 | 0.0454595
1500927 | 00 begane grond | bk. fundering | 0 | Up to level: 00 begane grond | 3433 | 3953 | 1.69979 | 380 | 0.169979
1500928 | 00 begane grond | bk. fundering | 0 | Up to level: 00 begane grond | 3433 | 3953 | 0.454595 | 165 | 0.0454595
1500930 | 00 begane grond | 00 begane grond | 3433 | Up to level: 00 begane grond | 4356 | 923 | 4.66023 | 5049 | 0.466023
1500946 | 00 begane grond | bk. fundering | 0 | Up to level: 00 begane grond | 3433 | 3953 | 1.69979 | 430 | 0.169979
1500951 | 00 begane grond | 00 begane grond | 3433 | Up to level: 00 begane grond | 4356 | 923 | 1.13483 | 1279.5 | 0.113483
1758013 | 00 begane grond | bk. fundering | 0 | Up to level: 00 begane grond | 1362 | 1882 | 0.62106 | 330 | 0.062106
1819616 | 00 begane grond | bk. fundering | 0 | Up to level: 00 begane grond | 3433 | 3953 | 0.849895 | 165 | 0.0849895
1909428 | 01 eerste verdieping | 01 eerste verdieping | -50 | Up to level: 01 eerste verdieping | 775 | 825 | 0.226875 | 275 | 0.0226875
1911094 | 00 begane grond | bk. fundering | 0 | Up to level: 01 eerste verdieping | 775 | 5295 | 1.25492 | 237 | 0.125491 | Model Group:21_penant_v0:1343011
1911097 | 00 begane grond | bk. fundering | 0 | Up to level: 01 eerste verdieping | 775 | 5295 | 1.25492 | 237 | 0.125492 | Model Group:21_penant_v0:1348665
1911100 | 00 begane grond | bk. fundering | 0 | Up to level: 01 eerste verdieping | 775 | 5295 | 1.25492 | 237 | 0.125492 | Model Group:21_penant_v0:1348881
1911103 | 00 begane grond | bk. fundering | 0 | Up to level: 01 eerste verdieping | 775 | 5295 | 1.25492 | 237 | 0.125492 | Model Group:21_penant_v0:1500685
1911106 | 00 begane grond | bk. fundering | 0 | Up to level: 01 eerste verdieping | 775 | 5295 | 1.25492 | 237 | 0.125492 | Model Group:21_penant_v0:1500694
1911109 | 00 begane grond | bk. fundering | 0 | Up to level: 01 eerste verdieping | 775 | 5295 | 1.25492 | 237 | 0.125491 | Model Group:21_penant_v0:1500896
1911112 | 00 begane grond | bk. fundering | 0 | Up to level: 01 eerste verdieping | 775 | 5295 | 1.25492 | 237 | 0.125491 | Model Group:21_penant_v0:1500921
1911209 | 01 eerste verdieping | 01 eerste verdieping | 786 | Up to level: 02 dakrand gymzaal | -211 | 2203 | 0.473645 | 115 | 0.0473645 | Model Group:21_penant_v1 gym:1911143
1911212 | 01 eerste verdieping | 01 eerste verdieping | 786 | Up to level: 02 dakrand gymzaal | -211 | 2203 | 0.473645 | 115 | 0.0473645 | Model Group:21_penant_v1 gym:1911150
1911215 | 01 eerste verdieping | 01 eerste verdieping | 786 | Up to level: 02 dakrand gymzaal | -211 | 2203 | 0.473645 | 115 | 0.0473645 | Model Group:21_penant_v1 gym:1911157
1911218 | 01 eerste verdieping | 01 eerste verdieping | 786 | Up to level: 02 dakrand gymzaal | -211 | 2203 | 0.473645 | 115 | 0.0473645 | Model Group:21_penant_v1 gym:1911164
1911221 | 01 eerste verdieping | 01 eerste verdieping | 786 | Up to level: 02 dakrand gymzaal | -211 | 2203 | 0.473645 | 115 | 0.0473645 | Model Group:21_penant_v1 gym:1911171
1911224 | 01 eerste verdieping | 01 eerste verdieping | 786 | Up to level: 02 dakrand gymzaal | -211 | 2203 | 0.473645 | 115 | 0.0473645 | Model Group:21_penant_v1 gym:1911178
1911227 | 01 eerste verdieping | 01 eerste verdieping | 786 | Up to level: 02 dakrand gymzaal | -211 | 2203 | 0.473645 | 115 | 0.0473645 | Model Group:21_penant_v1 gym:1911185
1911538 | 01 eerste verdieping | 01 eerste verdieping | 786 | Up to level: 02 dakrand gymzaal | -211 | 2203 | 0.253345 | 165 | 0.0253345 | Model Group:21_penant_v1 gym:1911143
1911659 | 01 eerste verdieping | 01 eerste verdieping | 786 | Up to level: 02 dakrand gymzaal | -211 | 2203 | 0.253345 | 165 | 0.0253345 | Model Group:21_penant_v1 gym:1911143
1911760 | 01 eerste verdieping | 01 eerste verdieping | 786 | Up to level: 02 dakrand gymzaal | -211 | 2203 | 0.253345 | 165 | 0.0253345 | Model Group:21_penant_v1 gym:1911150
1911761 | 01 eerste verdieping | 01 eerste verdieping | 786 | Up to level: 02 dakrand gymzaal | -211 | 2203 | 0.253345 | 165 | 0.0253345 | Model Group:21_penant_v1 gym:1911150
1911764 | 01 eerste verdieping | 01 eerste verdieping | 786 | Up to level: 02 dakrand gymzaal | -211 | 2203 | 0.253345 | 165 | 0.0253345 | Model Group:21_penant_v1 gym:1911157
1911765 | 01 eerste verdieping | 01 eerste verdieping | 786 | Up to level: 02 dakrand gymzaal | -211 | 2203 | 0.253345 | 165 | 0.0253345 | Model Group:21_penant_v1 gym:1911157
1911768 | 01 eerste verdieping | 01 eerste verdieping | 786 | Up to level: 02 dakrand gymzaal | -211 | 2203 | 0.253345 | 165 | 0.0253345 | Model Group:21_penant_v1 gym:1911164
1911769 | 01 eerste verdieping | 01 eerste verdieping | 786 | Up to level: 02 dakrand gymzaal | -211 | 2203 | 0.253345 | 165 | 0.0253345 | Model Group:21_penant_v1 gym:1911164
1911772 | 01 eerste verdieping | 01 eerste verdieping | 786 | Up to level: 02 dakrand gymzaal | -211 | 2203 | 0.253345 | 165 | 0.0253345 | Model Group:21_penant_v1 gym:1911171
1911773 | 01 eerste verdieping | 01 eerste verdieping | 786 | Up to level: 02 dakrand gymzaal | -211 | 2203 | 0.253345 | 165 | 0.0253345 | Model Group:21_penant_v1 gym:1911171
1911776 | 01 eerste verdieping | 01 eerste verdieping | 786 | Up to level: 02 dakrand gymzaal | -211 | 2203 | 0.253345 | 165 | 0.0253345 | Model Group:21_penant_v1 gym:1911178
1911777 | 01 eerste verdieping | 01 eerste verdieping | 786 | Up to level: 02 dakrand gymzaal | -211 | 2203 | 0.253345 | 165 | 0.0253345 | Model Group:21_penant_v1 gym:1911178
1911780 | 01 eerste verdieping | 01 eerste verdieping | 786 | Up to level: 02 dakrand gymzaal | -211 | 2203 | 0.253345 | 165 | 0.0253345 | Model Group:21_penant_v1 gym:1911185
1911781 | 01 eerste verdieping | 01 eerste verdieping | 786 | Up to level: 02 dakrand gymzaal | -211 | 2203 | 0.253345 | 165 | 0.0253345 | Model Group:21_penant_v1 gym:1911185
1912552 | 01 eerste verdieping | 01 eerste verdieping | 786 | Up to level: 02 dakrand gymzaal | -211 | 2203 | 0.473645 | 115 | 0.0473645 | Model Group:21_penant_v1 gym:1912551
1912553 | 01 eerste verdieping | 01 eerste verdieping | 786 | Up to level: 02 dakrand gymzaal | -211 | 2203 | 0.253345 | 165 | 0.0253345 | Model Group:21_penant_v1 gym:1912551
1912554 | 01 eerste verdieping | 01 eerste verdieping | 786 | Up to level: 02 dakrand gymzaal | -211 | 2203 | 0.253345 | 165 | 0.0253345 | Model Group:21_penant_v1 gym:1912551
1912591 | 01 eerste verdieping | 01 eerste verdieping | 786 | Up to level: 02 dakrand gymzaal | -211 | 2203 | 0.473645 | 115 | 0.0473645 | Model Group:21_penant_v1 gym:1912590
1912592 | 01 eerste verdieping | 01 eerste verdieping | 786 | Up to level: 02 dakrand gymzaal | -211 | 2203 | 0.253345 | 165 | 0.0253345 | Model Group:21_penant_v1 gym:1912590
1912593 | 01 eerste verdieping | 01 eerste verdieping | 786 | Up to level: 02 dakrand gymzaal | -211 | 2203 | 0.253345 | 165 | 0.0253345 | Model Group:21_penant_v1 gym:1912590
1912706 | 01 eerste verdieping | 01 eerste verdieping | 786 | Up to level: 02 dakrand gymzaal | -211 | 2203 | 0.473645 | 115 | 0.0473645 | Model Group:21_penant_v1 gym:1912705
1912707 | 01 eerste verdieping | 01 eerste verdieping | 786 | Up to level: 02 dakrand gymzaal | -211 | 2203 | 0.253345 | 165 | 0.0253345 | Model Group:21_penant_v1 gym:1912705
1912708 | 01 eerste verdieping | 01 eerste verdieping | 786 | Up to level: 02 dakrand gymzaal | -211 | 2203 | 0.253345 | 165 | 0.0253345 | Model Group:21_penant_v1 gym:1912705
1912710 | 01 eerste verdieping | 01 eerste verdieping | 786 | Up to level: 02 dakrand gymzaal | -211 | 2203 | 0.473645 | 115 | 0.0473645 | Model Group:21_penant_v1 gym:1912709
1912711 | 01 eerste verdieping | 01 eerste verdieping | 786 | Up to level: 02 dakrand gymzaal | -211 | 2203 | 0.253345 | 165 | 0.0253345 | Model Group:21_penant_v1 gym:1912709
1912712 | 01 eerste verdieping | 01 eerste verdieping | 786 | Up to level: 02 dakrand gymzaal | -211 | 2203 | 0.253345 | 165 | 0.0253345 | Model Group:21_penant_v1 gym:1912709
1912716 | 01 eerste verdieping | 01 eerste verdieping | 786 | Up to level: 02 dakrand gymzaal | -211 | 2203 | 0.473645 | 115 | 0.0473645 | Model Group:21_penant_v1 gym:1912715
1912717 | 01 eerste verdieping | 01 eerste verdieping | 786 | Up to level: 02 dakrand gymzaal | -211 | 2203 | 0.253345 | 165 | 0.0253345 | Model Group:21_penant_v1 gym:1912715
1912718 | 01 eerste verdieping | 01 eerste verdieping | 786 | Up to level: 02 dakrand gymzaal | -211 | 2203 | 0.253345 | 165 | 0.0253345 | Model Group:21_penant_v1 gym:1912715
1912720 | 01 eerste verdieping | 01 eerste verdieping | 786 | Up to level: 02 dakrand gymzaal | -211 | 2203 | 0.473645 | 115 | 0.0473645 | Model Group:21_penant_v1 gym:1912719
1912721 | 01 eerste verdieping | 01 eerste verdieping | 786 | Up to level: 02 dakrand gymzaal | -211 | 2203 | 0.253345 | 165 | 0.0253345 | Model Group:21_penant_v1 gym:1912719
1912722 | 01 eerste verdieping | 01 eerste verdieping | 786 | Up to level: 02 dakrand gymzaal | -211 | 2203 | 0.253345 | 165 | 0.0253345 | Model Group:21_penant_v1 gym:1912719
1912726 | 01 eerste verdieping | 01 eerste verdieping | 786 | Up to level: 02 dakrand gymzaal | -211 | 2203 | 0.473645 | 115 | 0.0473645 | Model Group:21_penant_v1 gym:1912725
1912727 | 01 eerste verdieping | 01 eerste verdieping | 786 | Up to level: 02 dakrand gymzaal | -211 | 2203 | 0.253345 | 165 | 0.0253345 | Model Group:21_penant_v1 gym:1912725
1912728 | 01 eerste verdieping | 01 eerste verdieping | 786 | Up to level: 02 dakrand gymzaal | -211 | 2203 | 0.253345 | 165 | 0.0253345 | Model Group:21_penant_v1 gym:1912725
1912730 | 01 eerste verdieping | 01 eerste verdieping | 786 | Up to level: 02 dakrand gymzaal | -211 | 2203 | 0.473645 | 115 | 0.0473645 | Model Group:21_penant_v1 gym:1912729
1912731 | 01 eerste verdieping | 01 eerste verdieping | 786 | Up to level: 02 dakrand gymzaal | -211 | 2203 | 0.253345 | 165 | 0.0253345 | Model Group:21_penant_v1 gym:1912729
1912732 | 01 eerste verdieping | 01 eerste verdieping | 786 | Up to level: 02 dakrand gymzaal | -211 | 2203 | 0.253345 | 165 | 0.0253345 | Model Group:21_penant_v1 gym:1912729
1912736 | 01 eerste verdieping | 01 eerste verdieping | 786 | Up to level: 02 dakrand gymzaal | -211 | 2203 | 0.473645 | 115 | 0.0473645 | Model Group:21_penant_v1 gym:1912735
1912737 | 01 eerste verdieping | 01 eerste verdieping | 786 | Up to level: 02 dakrand gymzaal | -211 | 2203 | 0.253345 | 165 | 0.0253345 | Model Group:21_penant_v1 gym:1912735
1912738 | 01 eerste verdieping | 01 eerste verdieping | 786 | Up to level: 02 dakrand gymzaal | -211 | 2203 | 0.253345 | 165 | 0.0253345 | Model Group:21_penant_v1 gym:1912735
1912740 | 01 eerste verdieping | 01 eerste verdieping | 786 | Up to level: 02 dakrand gymzaal | -211 | 2203 | 0.473645 | 115 | 0.0473645 | Model Group:21_penant_v1 gym:1912739
1912741 | 01 eerste verdieping | 01 eerste verdieping | 786 | Up to level: 02 dakrand gymzaal | -211 | 2203 | 0.253345 | 165 | 0.0253345 | Model Group:21_penant_v1 gym:1912739
1912742 | 01 eerste verdieping | 01 eerste verdieping | 786 | Up to level: 02 dakrand gymzaal | -211 | 2203 | 0.253345 | 165 | 0.0253345 | Model Group:21_penant_v1 gym:1912739
1912746 | 01 eerste verdieping | 01 eerste verdieping | 786 | Up to level: 02 dakrand gymzaal | -211 | 2203 | 0.473645 | 115 | 0.0473645 | Model Group:21_penant_v1 gym:1912745
1912747 | 01 eerste verdieping | 01 eerste verdieping | 786 | Up to level: 02 dakrand gymzaal | -211 | 2203 | 0.253345 | 165 | 0.0253345 | Model Group:21_penant_v1 gym:1912745
1912748 | 01 eerste verdieping | 01 eerste verdieping | 786 | Up to level: 02 dakrand gymzaal | -211 | 2203 | 0.253345 | 165 | 0.0253345 | Model Group:21_penant_v1 gym:1912745
1912756 | 01 eerste verdieping | 01 eerste verdieping | 786 | Up to level: 02 dakrand gymzaal | -211 | 2203 | 0.473645 | 115 | 0.0473645 | Model Group:21_penant_v1 gym:1912755
1912757 | 01 eerste verdieping | 01 eerste verdieping | 786 | Up to level: 02 dakrand gymzaal | -211 | 2203 | 0.253345 | 165 | 0.0253345 | Model Group:21_penant_v1 gym:1912755
1912758 | 01 eerste verdieping | 01 eerste verdieping | 786 | Up to level: 02 dakrand gymzaal | -211 | 2203 | 0.253345 | 165 | 0.0253345 | Model Group:21_penant_v1 gym:1912755
1912760 | 01 eerste verdieping | 01 eerste verdieping | 786 | Up to level: 02 dakrand gymzaal | -211 | 2203 | 0.473645 | 115 | 0.0473645 | Model Group:21_penant_v1 gym:1912759
1912761 | 01 eerste verdieping | 01 eerste verdieping | 786 | Up to level: 02 dakrand gymzaal | -211 | 2203 | 0.253345 | 165 | 0.0253345 | Model Group:21_penant_v1 gym:1912759
1912762 | 01 eerste verdieping | 01 eerste verdieping | 786 | Up to level: 02 dakrand gymzaal | -211 | 2203 | 0.253345 | 165 | 0.0253345 | Model Group:21_penant_v1 gym:1912759
1912766 | 01 eerste verdieping | 01 eerste verdieping | 786 | Up to level: 02 dakrand gymzaal | -211 | 2203 | 0.473645 | 115 | 0.0473645 | Model Group:21_penant_v1 gym:1912765
1912767 | 01 eerste verdieping | 01 eerste verdieping | 786 | Up to level: 02 dakrand gymzaal | -211 | 2203 | 0.253345 | 165 | 0.0253345 | Model Group:21_penant_v1 gym:1912765
1912768 | 01 eerste verdieping | 01 eerste verdieping | 786 | Up to level: 02 dakrand gymzaal | -211 | 2203 | 0.253345 | 165 | 0.0253345 | Model Group:21_penant_v1 gym:1912765
1912770 | 01 eerste verdieping | 01 eerste verdieping | 786 | Up to level: 02 dakrand gymzaal | -211 | 2203 | 0.473645 | 115 | 0.0473645 | Model Group:21_penant_v1 gym:1912769
1912771 | 01 eerste verdieping | 01 eerste verdieping | 786 | Up to level: 02 dakrand gymzaal | -211 | 2203 | 0.253345 | 165 | 0.0253345 | Model Group:21_penant_v1 gym:1912769
1912772 | 01 eerste verdieping | 01 eerste verdieping | 786 | Up to level: 02 dakrand gymzaal | -211 | 2203 | 0.253345 | 165 | 0.0253345 | Model Group:21_penant_v1 gym:1912769
1912776 | 01 eerste verdieping | 01 eerste verdieping | 786 | Up to level: 02 dakrand gymzaal | -211 | 2203 | 0.473645 | 115 | 0.0473645 | Model Group:21_penant_v1 gym:1912775
1912777 | 01 eerste verdieping | 01 eerste verdieping | 786 | Up to level: 02 dakrand gymzaal | -211 | 2203 | 0.253345 | 165 | 0.0253345 | Model Group:21_penant_v1 gym:1912775
1912778 | 01 eerste verdieping | 01 eerste verdieping | 786 | Up to level: 02 dakrand gymzaal | -211 | 2203 | 0.253345 | 165 | 0.0253345 | Model Group:21_penant_v1 gym:1912775
1912780 | 01 eerste verdieping | 01 eerste verdieping | 786 | Up to level: 02 dakrand gymzaal | -211 | 2203 | 0.473645 | 115 | 0.0473645 | Model Group:21_penant_v1 gym:1912779
1912781 | 01 eerste verdieping | 01 eerste verdieping | 786 | Up to level: 02 dakrand gymzaal | -211 | 2203 | 0.253345 | 165 | 0.0253345 | Model Group:21_penant_v1 gym:1912779
1912782 | 01 eerste verdieping | 01 eerste verdieping | 786 | Up to level: 02 dakrand gymzaal | -211 | 2203 | 0.253345 | 165 | 0.0253345 | Model Group:21_penant_v1 gym:1912779
1912819 | 01 eerste verdieping | 01 eerste verdieping | 786 | Up to level: 02 dakrand gymzaal | -211 | 2203 | 0.473645 | 115 | 0.0473645 | Model Group:21_penant_v1 gym:1912818
1912820 | 01 eerste verdieping | 01 eerste verdieping | 786 | Up to level: 02 dakrand gymzaal | -211 | 2203 | 0.253345 | 165 | 0.0253345 | Model Group:21_penant_v1 gym:1912818
1912821 | 01 eerste verdieping | 01 eerste verdieping | 786 | Up to level: 02 dakrand gymzaal | -211 | 2203 | 0.253345 | 165 | 0.0253345 | Model Group:21_penant_v1 gym:1912818
1912831 | 01 eerste verdieping | 01 eerste verdieping | 786 | Up to level: 02 dakrand gymzaal | -211 | 2203 | 0.473645 | 115 | 0.0473645 | Model Group:21_penant_v1 gym:1912830
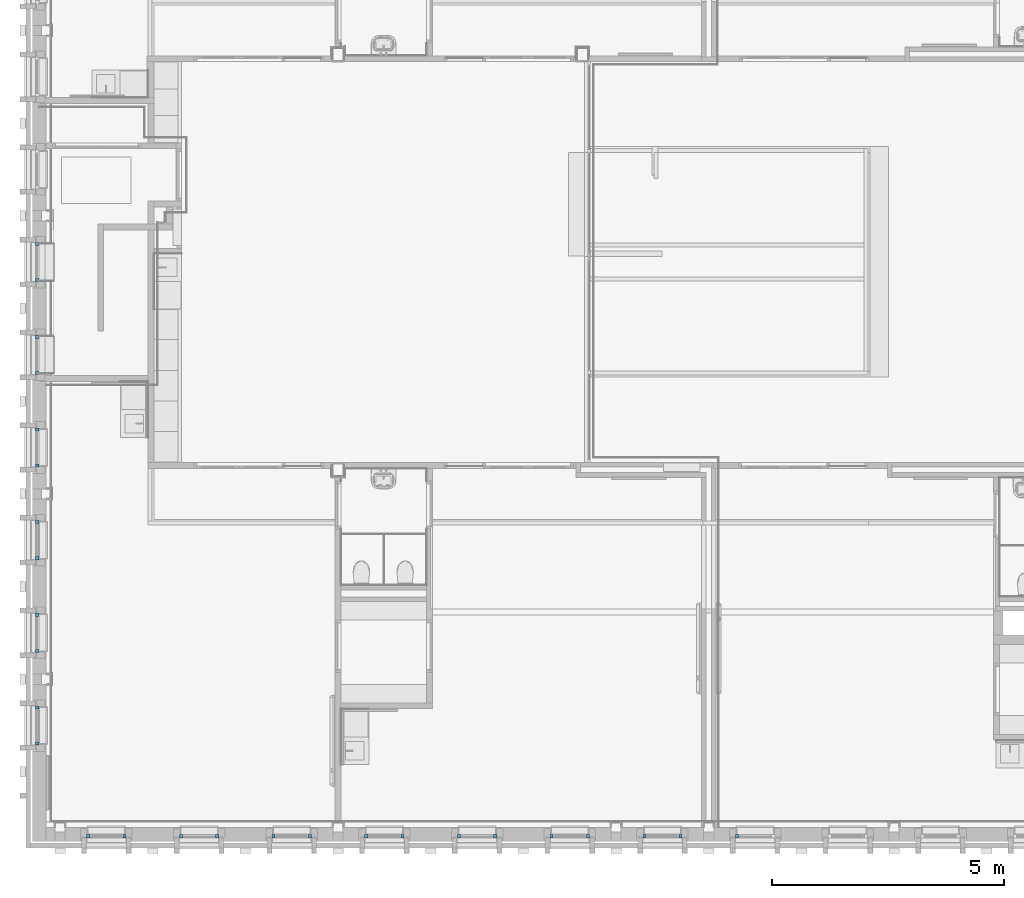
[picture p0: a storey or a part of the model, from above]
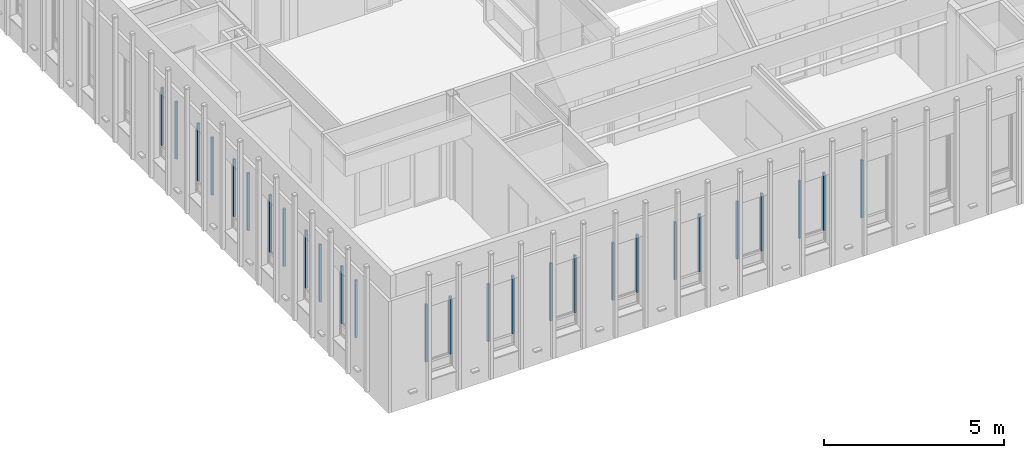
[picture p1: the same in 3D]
Properties of the parts of a building model (IFC2X3), part 86 of 94

# IfcWallStandardCase: Basic Wall:21_WA_metselwerk_middel_100_gen_bdg (555)
Name (Basic Wall:21_WA_metselwerk_middel_100_gen_bdg:...) | In | Base Constraint | Base Offset (mm) | Top Constraint | Top Offset (mm) | Unconnected Height (mm) | Area (m2) | Length (mm) | Volume (m3) | Group
1912832 | 01 eerste verdieping | 01 eerste verdieping | 786 | Up to level: 02 dakrand gymzaal | -211 | 2203 | 0.253345 | 165 | 0.0253345 | Model Group:21_penant_v1 gym:1912830
1912833 | 01 eerste verdieping | 01 eerste verdieping | 786 | Up to level: 02 dakrand gymzaal | -211 | 2203 | 0.253345 | 165 | 0.0253345 | Model Group:21_penant_v1 gym:1912830
1913072 | 01 eerste verdieping | 01 eerste verdieping | 786 | Up to level: 02 dakrand gymzaal | -211 | 2203 | 0.473645 | 115 | 0.0473645 | Model Group:21_penant_v1 gym:1913071
1913073 | 01 eerste verdieping | 01 eerste verdieping | 786 | Up to level: 02 dakrand gymzaal | -211 | 2203 | 0.253345 | 165 | 0.0253345 | Model Group:21_penant_v1 gym:1913071
1913074 | 01 eerste verdieping | 01 eerste verdieping | 786 | Up to level: 02 dakrand gymzaal | -211 | 2203 | 0.253345 | 165 | 0.0253345 | Model Group:21_penant_v1 gym:1913071
1913225 | 01 eerste verdieping | 01 eerste verdieping | 786 | Up to level: 02 dakrand gymzaal | -211 | 2203 | 0.473645 | 115 | 0.0473645 | Model Group:21_penant_v1 gym:1913224
1913226 | 01 eerste verdieping | 01 eerste verdieping | 786 | Up to level: 02 dakrand gymzaal | -211 | 2203 | 0.253345 | 165 | 0.0253345 | Model Group:21_penant_v1 gym:1913224
1913227 | 01 eerste verdieping | 01 eerste verdieping | 786 | Up to level: 02 dakrand gymzaal | -211 | 2203 | 0.253345 | 165 | 0.0253345 | Model Group:21_penant_v1 gym:1913224
1913266 | 01 eerste verdieping | 01 eerste verdieping | 786 | Up to level: 02 dakrand gymzaal | -211 | 2203 | 0.473645 | 115 | 0.0473645 | Model Group:21_penant_v1 gym:1913265
1913267 | 01 eerste verdieping | 01 eerste verdieping | 786 | Up to level: 02 dakrand gymzaal | -211 | 2203 | 0.253345 | 165 | 0.0253345 | Model Group:21_penant_v1 gym:1913265
1913268 | 01 eerste verdieping | 01 eerste verdieping | 786 | Up to level: 02 dakrand gymzaal | -211 | 2203 | 0.253345 | 165 | 0.0253345 | Model Group:21_penant_v1 gym:1913265
1913280 | 01 eerste verdieping | 01 eerste verdieping | 786 | Up to level: 02 dakrand gymzaal | -211 | 2203 | 0.473645 | 115 | 0.0473645 | Model Group:21_penant_v1 gym:1913279
1913281 | 01 eerste verdieping | 01 eerste verdieping | 786 | Up to level: 02 dakrand gymzaal | -211 | 2203 | 0.253345 | 165 | 0.0253345 | Model Group:21_penant_v1 gym:1913279
1913282 | 01 eerste verdieping | 01 eerste verdieping | 786 | Up to level: 02 dakrand gymzaal | -211 | 2203 | 0.253345 | 165 | 0.0253345 | Model Group:21_penant_v1 gym:1913279
1913890 | 01 eerste verdieping | 01 eerste verdieping | 786 | Up to level: 02 dakrand gymzaal | -211 | 2203 | 0.473645 | 115 | 0.0473645 | Model Group:21_penant_v1 gym:1913889
1913891 | 01 eerste verdieping | 01 eerste verdieping | 786 | Up to level: 02 dakrand gymzaal | -211 | 2203 | 0.253345 | 165 | 0.0253345 | Model Group:21_penant_v1 gym:1913889
1913892 | 01 eerste verdieping | 01 eerste verdieping | 786 | Up to level: 02 dakrand gymzaal | -211 | 2203 | 0.253345 | 165 | 0.0253345 | Model Group:21_penant_v1 gym:1913889
1913894 | 01 eerste verdieping | 01 eerste verdieping | 786 | Up to level: 02 dakrand gymzaal | -211 | 2203 | 0.473645 | 115 | 0.0473645 | Model Group:21_penant_v1 gym:1913893
1913895 | 01 eerste verdieping | 01 eerste verdieping | 786 | Up to level: 02 dakrand gymzaal | -211 | 2203 | 0.253345 | 165 | 0.0253345 | Model Group:21_penant_v1 gym:1913893
1913896 | 01 eerste verdieping | 01 eerste verdieping | 786 | Up to level: 02 dakrand gymzaal | -211 | 2203 | 0.253345 | 165 | 0.0253345 | Model Group:21_penant_v1 gym:1913893
1913918 | 01 eerste verdieping | 01 eerste verdieping | 786 | Up to level: 02 dakrand gymzaal | -211 | 2203 | 0.473645 | 115 | 0.0473645 | Model Group:21_penant_v1 gym:1913917
1913919 | 01 eerste verdieping | 01 eerste verdieping | 786 | Up to level: 02 dakrand gymzaal | -211 | 2203 | 0.253345 | 165 | 0.0253345 | Model Group:21_penant_v1 gym:1913917
1913920 | 01 eerste verdieping | 01 eerste verdieping | 786 | Up to level: 02 dakrand gymzaal | -211 | 2203 | 0.253345 | 165 | 0.0253345 | Model Group:21_penant_v1 gym:1913917
1913932 | 01 eerste verdieping | 01 eerste verdieping | 786 | Up to level: 02 dakrand gymzaal | -211 | 2203 | 0.473645 | 115 | 0.0473645 | Model Group:21_penant_v1 gym:1913931
1913933 | 01 eerste verdieping | 01 eerste verdieping | 786 | Up to level: 02 dakrand gymzaal | -211 | 2203 | 0.253345 | 165 | 0.0253345 | Model Group:21_penant_v1 gym:1913931
1913934 | 01 eerste verdieping | 01 eerste verdieping | 786 | Up to level: 02 dakrand gymzaal | -211 | 2203 | 0.253345 | 165 | 0.0253345 | Model Group:21_penant_v1 gym:1913931
1913944 | 01 eerste verdieping | 01 eerste verdieping | 786 | Up to level: 02 dakrand gymzaal | -211 | 2203 | 0.473645 | 115 | 0.0473645 | Model Group:21_penant_v1 gym:1913943
1913945 | 01 eerste verdieping | 01 eerste verdieping | 786 | Up to level: 02 dakrand gymzaal | -211 | 2203 | 0.253345 | 165 | 0.0253345 | Model Group:21_penant_v1 gym:1913943
1913946 | 01 eerste verdieping | 01 eerste verdieping | 786 | Up to level: 02 dakrand gymzaal | -211 | 2203 | 0.253345 | 165 | 0.0253345 | Model Group:21_penant_v1 gym:1913943
2031146 | 00 begane grond | 00 begane grond | 3433 | Up to level: 00 begane grond | 4356 | 923 | 1.7147 | 1820.37 | 0.16802 | Model Group:21_rond:1344849 | Graphics - Center Mark Visible: no
2031208 | 00 begane grond | 00 begane grond | 3433 | Up to level: 00 begane grond | 4356 | 923 | 1.45939 | 1543.76 | 0.142489 | Model Group:21_rond:1344849 | Graphics - Center Mark Visible: no
2031253 | 00 begane grond | 00 begane grond | 3433 | Up to level: 00 begane grond | 4356 | 923 | 1.7147 | 1820.37 | 0.16802 | Model Group:21_rond:1344284 | Graphics - Center Mark Visible: no
2031254 | 00 begane grond | 00 begane grond | 3433 | Up to level: 00 begane grond | 4356 | 923 | 1.45939 | 1543.76 | 0.142489 | Model Group:21_rond:1344284 | Graphics - Center Mark Visible: no
2032098 | 00 begane grond | 00 begane grond | 3433 | Up to level: 00 begane grond | 4356 | 923 | 1.54408 | 1594.36 | 0.14714 | Graphics - Center Mark Visible: no
2163139 | 01 eerste verdieping | 01 eerste verdieping | -50 | Up to level: 02 dakrand gymzaal | -211 | 3039 | 0.653385 | 115 | 0.0653385 | Model Group:21_penant_v1 gym laag:1913291
2163140 | 01 eerste verdieping | 01 eerste verdieping | -50 | Up to level: 02 dakrand gymzaal | -520 | 2730 | 0.3003 | 160 | 0.03003 | Model Group:21_penant_v1 gym laag:1913291
2163141 | 01 eerste verdieping | 01 eerste verdieping | -50 | Up to level: 02 dakrand gymzaal | -520 | 2730 | 0.3003 | 160 | 0.03003 | Model Group:21_penant_v1 gym laag:1913291
2163142 | 01 eerste verdieping | 02 dakrand gymzaal | -520 | Up to level: 02 dakrand gymzaal | -273 | 247 | 0.00247 | 60 | 0.000247 | Model Group:21_penant_v1 gym laag:1913291
2163143 | 01 eerste verdieping | 02 dakrand gymzaal | -520 | Up to level: 02 dakrand gymzaal | -273 | 247 | 0.00247 | 60 | 0.000247 | Model Group:21_penant_v1 gym laag:1913291
2464173 | 00 begane grond | bk. fundering | 0 | Up to level: 01 eerste verdieping | 775 | 5295 | 1.25492 | 237 | 0.125492
2737897 | 01 eerste verdieping | 01 eerste verdieping | 786 | Up to level: 01 eerste verdieping | 1820 | 1034 | 0.21714 | 110 | 0.021714
2737898 | 01 eerste verdieping | 01 eerste verdieping | 786 | Up to level: 01 eerste verdieping | 1820 | 1034 | 0.01551 | 115 | 0.001551
2737899 | 01 eerste verdieping | 01 eerste verdieping | 786 | Up to level: 01 eerste verdieping | 1820 | 1034 | 0.01551 | 115 | 0.001551
2775169 | 01 eerste verdieping | 01 eerste verdieping | 786 | Up to level: 01 eerste verdieping | 3173 | 2387 | 0.50127 | 110 | 0.050127
2775170 | 01 eerste verdieping | 01 eerste verdieping | 786 | Up to level: 01 eerste verdieping | 3173 | 2387 | 0.035805 | 115 | 0.0035805
2775171 | 01 eerste verdieping | 01 eerste verdieping | 786 | Up to level: 01 eerste verdieping | 3173 | 2387 | 0.035805 | 115 | 0.0035805
2775178 | 01 eerste verdieping | 01 eerste verdieping | 786 | Up to level: 02 tweede verdieping | 419 | 3433 | 0.738095 | 115 | 0.0738095
2775179 | 01 eerste verdieping | 01 eerste verdieping | 775 | Up to level: 02 tweede verdieping | 419 | 3444 | 0.05166 | 115 | 0.005166
2775180 | 01 eerste verdieping | 01 eerste verdieping | 775 | Up to level: 02 tweede verdieping | 419 | 3444 | 0.05166 | 115 | 0.005166
2775187 | 01 eerste verdieping | 01 eerste verdieping | 2877 | Up to level: 02 tweede verdieping | 419 | 1342 | 0.28182 | 110 | 0.028182
2775188 | 01 eerste verdieping | 01 eerste verdieping | 2877 | Up to level: 02 tweede verdieping | 419 | 1342 | 0.01342 | 110 | 0.001342
2775189 | 01 eerste verdieping | 01 eerste verdieping | 2877 | Up to level: 02 tweede verdieping | 419 | 1342 | 0.01342 | 110 | 0.001342
3186743 | 01 eerste verdieping | 01 eerste verdieping | 786 | Up to level: 02 tweede verdieping | 419 | 3433 | 0.051495 | 115 | 0.0051495 | Model Group:21_penant v1 ROND:1302570
3186745 | 01 eerste verdieping | 01 eerste verdieping | 786 | Up to level: 02 tweede verdieping | 419 | 3433 | 0.18234 | 115 | 0.018234 | Model Group:21_penant v1 ROND:1341016
3267650 | 00 begane grond | 00 begane grond | 0 | Up to level: 00 begane grond | 3433 | 3433 | 0.738095 | 165 | 0.0738095
4350154 | 01 eerste verdieping | 01 eerste verdieping | 786 | Up to level: 01 eerste verdieping | 2877 | 2091 | 0.470475 | 275 | 0.0470475 | Model Group:21_penant v1:874890
4350203 | 01 eerste verdieping | 01 eerste verdieping | 786 | Up to level: 01 eerste verdieping | 2877 | 2091 | 0.470475 | 275 | 0.0470475 | Model Group:21_penant v1:874890
4350567 | 01 eerste verdieping | 01 eerste verdieping | 786 | Up to level: 01 eerste verdieping | 2877 | 2091 | 0.470475 | 275 | 0.0470475 | Model Group:21_penant v1:774399
4350568 | 01 eerste verdieping | 01 eerste verdieping | 786 | Up to level: 01 eerste verdieping | 2877 | 2091 | 0.470475 | 275 | 0.0470475 | Model Group:21_penant v1:774399
4350571 | 01 eerste verdieping | 01 eerste verdieping | 786 | Up to level: 01 eerste verdieping | 2877 | 2091 | 0.470475 | 275 | 0.0470475 | Model Group:21_penant v1:774488
4350572 | 01 eerste verdieping | 01 eerste verdieping | 786 | Up to level: 01 eerste verdieping | 2877 | 2091 | 0.470475 | 275 | 0.0470475 | Model Group:21_penant v1:774488
4350575 | 01 eerste verdieping | 01 eerste verdieping | 786 | Up to level: 01 eerste verdieping | 2877 | 2091 | 0.470475 | 275 | 0.0470475 | Model Group:21_penant v1:774500
4350576 | 01 eerste verdieping | 01 eerste verdieping | 786 | Up to level: 01 eerste verdieping | 2877 | 2091 | 0.470475 | 275 | 0.0470475 | Model Group:21_penant v1:774500
4350583 | 01 eerste verdieping | 01 eerste verdieping | 786 | Up to level: 01 eerste verdieping | 2877 | 2091 | 0.470475 | 275 | 0.0470475 | Model Group:21_penant v1:874894
4350584 | 01 eerste verdieping | 01 eerste verdieping | 786 | Up to level: 01 eerste verdieping | 2877 | 2091 | 0.470475 | 275 | 0.0470475 | Model Group:21_penant v1:874894
4350587 | 01 eerste verdieping | 01 eerste verdieping | 786 | Up to level: 01 eerste verdieping | 2877 | 2091 | 0.470475 | 275 | 0.0470475 | Model Group:21_penant v1:874898
4350588 | 01 eerste verdieping | 01 eerste verdieping | 786 | Up to level: 01 eerste verdieping | 2877 | 2091 | 0.470475 | 275 | 0.0470475 | Model Group:21_penant v1:874898
4350591 | 01 eerste verdieping | 01 eerste verdieping | 786 | Up to level: 01 eerste verdieping | 2877 | 2091 | 0.470475 | 275 | 0.0470475 | Model Group:21_penant v1:874980
4350592 | 01 eerste verdieping | 01 eerste verdieping | 786 | Up to level: 01 eerste verdieping | 2877 | 2091 | 0.470475 | 275 | 0.0470475 | Model Group:21_penant v1:874980
4350595 | 01 eerste verdieping | 01 eerste verdieping | 786 | Up to level: 01 eerste verdieping | 2877 | 2091 | 0.470475 | 275 | 0.0470475 | Model Group:21_penant v1:874984
4350596 | 01 eerste verdieping | 01 eerste verdieping | 786 | Up to level: 01 eerste verdieping | 2877 | 2091 | 0.470475 | 275 | 0.0470475 | Model Group:21_penant v1:874984
4350599 | 01 eerste verdieping | 01 eerste verdieping | 786 | Up to level: 01 eerste verdieping | 2877 | 2091 | 0.470475 | 275 | 0.0470475 | Model Group:21_penant v1:874988
4350600 | 01 eerste verdieping | 01 eerste verdieping | 786 | Up to level: 01 eerste verdieping | 2877 | 2091 | 0.470475 | 275 | 0.0470475 | Model Group:21_penant v1:874988
4350603 | 01 eerste verdieping | 01 eerste verdieping | 786 | Up to level: 01 eerste verdieping | 2877 | 2091 | 0.470475 | 275 | 0.0470475 | Model Group:21_penant v1:875217
4350604 | 01 eerste verdieping | 01 eerste verdieping | 786 | Up to level: 01 eerste verdieping | 2877 | 2091 | 0.470475 | 275 | 0.0470475 | Model Group:21_penant v1:875217
4350607 | 01 eerste verdieping | 01 eerste verdieping | 786 | Up to level: 01 eerste verdieping | 2877 | 2091 | 0.470475 | 275 | 0.0470475 | Model Group:21_penant v1:875253
4350608 | 01 eerste verdieping | 01 eerste verdieping | 786 | Up to level: 01 eerste verdieping | 2877 | 2091 | 0.470475 | 275 | 0.0470475 | Model Group:21_penant v1:875253
4350611 | 01 eerste verdieping | 01 eerste verdieping | 786 | Up to level: 01 eerste verdieping | 2877 | 2091 | 0.470475 | 275 | 0.0470475 | Model Group:21_penant v1:875289
4350612 | 01 eerste verdieping | 01 eerste verdieping | 786 | Up to level: 01 eerste verdieping | 2877 | 2091 | 0.470475 | 275 | 0.0470475 | Model Group:21_penant v1:875289
4350615 | 01 eerste verdieping | 01 eerste verdieping | 786 | Up to level: 01 eerste verdieping | 2877 | 2091 | 0.470475 | 275 | 0.0470475 | Model Group:21_penant v1:875325
4350616 | 01 eerste verdieping | 01 eerste verdieping | 786 | Up to level: 01 eerste verdieping | 2877 | 2091 | 0.470475 | 275 | 0.0470475 | Model Group:21_penant v1:875325
4350619 | 01 eerste verdieping | 01 eerste verdieping | 786 | Up to level: 01 eerste verdieping | 2877 | 2091 | 0.470475 | 275 | 0.0470475 | Model Group:21_penant v1:875361
4350620 | 01 eerste verdieping | 01 eerste verdieping | 786 | Up to level: 01 eerste verdieping | 2877 | 2091 | 0.470475 | 275 | 0.0470475 | Model Group:21_penant v1:875361
4350623 | 01 eerste verdieping | 01 eerste verdieping | 786 | Up to level: 01 eerste verdieping | 2877 | 2091 | 0.470475 | 275 | 0.0470475 | Model Group:21_penant v1:876469
4350624 | 01 eerste verdieping | 01 eerste verdieping | 786 | Up to level: 01 eerste verdieping | 2877 | 2091 | 0.470475 | 275 | 0.0470475 | Model Group:21_penant v1:876469
4350627 | 01 eerste verdieping | 01 eerste verdieping | 786 | Up to level: 01 eerste verdieping | 2877 | 2091 | 0.470475 | 275 | 0.0470475 | Model Group:21_penant v1:876484
4350628 | 01 eerste verdieping | 01 eerste verdieping | 786 | Up to level: 01 eerste verdieping | 2877 | 2091 | 0.470475 | 275 | 0.0470475 | Model Group:21_penant v1:876484
4350631 | 01 eerste verdieping | 01 eerste verdieping | 786 | Up to level: 01 eerste verdieping | 2877 | 2091 | 0.470475 | 275 | 0.0470475 | Model Group:21_penant v1:876499
4350632 | 01 eerste verdieping | 01 eerste verdieping | 786 | Up to level: 01 eerste verdieping | 2877 | 2091 | 0.470475 | 275 | 0.0470475 | Model Group:21_penant v1:876499
4350635 | 01 eerste verdieping | 01 eerste verdieping | 786 | Up to level: 01 eerste verdieping | 2877 | 2091 | 0.470475 | 275 | 0.0470475 | Model Group:21_penant v1:876887
4350636 | 01 eerste verdieping | 01 eerste verdieping | 786 | Up to level: 01 eerste verdieping | 2877 | 2091 | 0.470475 | 275 | 0.0470475 | Model Group:21_penant v1:876887
4350639 | 01 eerste verdieping | 01 eerste verdieping | 786 | Up to level: 01 eerste verdieping | 2877 | 2091 | 0.470475 | 275 | 0.0470475 | Model Group:21_penant v1:876902
4350640 | 01 eerste verdieping | 01 eerste verdieping | 786 | Up to level: 01 eerste verdieping | 2877 | 2091 | 0.470475 | 275 | 0.0470475 | Model Group:21_penant v1:876902
4350643 | 01 eerste verdieping | 01 eerste verdieping | 786 | Up to level: 01 eerste verdieping | 2877 | 2091 | 0.470475 | 275 | 0.0470475 | Model Group:21_penant v1:876917
4350644 | 01 eerste verdieping | 01 eerste verdieping | 786 | Up to level: 01 eerste verdieping | 2877 | 2091 | 0.470475 | 275 | 0.0470475 | Model Group:21_penant v1:876917
4350647 | 01 eerste verdieping | 01 eerste verdieping | 786 | Up to level: 01 eerste verdieping | 2877 | 2091 | 0.470475 | 275 | 0.0470475 | Model Group:21_penant v1:877004
4350648 | 01 eerste verdieping | 01 eerste verdieping | 786 | Up to level: 01 eerste verdieping | 2877 | 2091 | 0.470475 | 275 | 0.0470475 | Model Group:21_penant v1:877004
4350651 | 01 eerste verdieping | 01 eerste verdieping | 786 | Up to level: 01 eerste verdieping | 2877 | 2091 | 0.470475 | 275 | 0.0470475 | Model Group:21_penant v1:877019
4350652 | 01 eerste verdieping | 01 eerste verdieping | 786 | Up to level: 01 eerste verdieping | 2877 | 2091 | 0.470475 | 275 | 0.0470475 | Model Group:21_penant v1:877019
4350655 | 01 eerste verdieping | 01 eerste verdieping | 786 | Up to level: 01 eerste verdieping | 2877 | 2091 | 0.470475 | 275 | 0.0470475 | Model Group:21_penant v1:877034
4350656 | 01 eerste verdieping | 01 eerste verdieping | 786 | Up to level: 01 eerste verdieping | 2877 | 2091 | 0.470475 | 275 | 0.0470475 | Model Group:21_penant v1:877034
4350659 | 01 eerste verdieping | 01 eerste verdieping | 786 | Up to level: 01 eerste verdieping | 2877 | 2091 | 0.470475 | 275 | 0.0470475 | Model Group:21_penant v1:877094
4350660 | 01 eerste verdieping | 01 eerste verdieping | 786 | Up to level: 01 eerste verdieping | 2877 | 2091 | 0.470475 | 275 | 0.0470475 | Model Group:21_penant v1:877094
4350663 | 01 eerste verdieping | 01 eerste verdieping | 786 | Up to level: 01 eerste verdieping | 2877 | 2091 | 0.470475 | 275 | 0.0470475 | Model Group:21_penant v1:877109
4350664 | 01 eerste verdieping | 01 eerste verdieping | 786 | Up to level: 01 eerste verdieping | 2877 | 2091 | 0.470475 | 275 | 0.0470475 | Model Group:21_penant v1:877109
4350667 | 01 eerste verdieping | 01 eerste verdieping | 786 | Up to level: 01 eerste verdieping | 2877 | 2091 | 0.470475 | 275 | 0.0470475 | Model Group:21_penant v1:877124
4350668 | 01 eerste verdieping | 01 eerste verdieping | 786 | Up to level: 01 eerste verdieping | 2877 | 2091 | 0.470475 | 275 | 0.0470475 | Model Group:21_penant v1:877124
4350671 | 01 eerste verdieping | 01 eerste verdieping | 786 | Up to level: 01 eerste verdieping | 2877 | 2091 | 0.470475 | 275 | 0.0470475 | Model Group:21_penant v1:877184
4350672 | 01 eerste verdieping | 01 eerste verdieping | 786 | Up to level: 01 eerste verdieping | 2877 | 2091 | 0.470475 | 275 | 0.0470475 | Model Group:21_penant v1:877184
4350675 | 01 eerste verdieping | 01 eerste verdieping | 786 | Up to level: 01 eerste verdieping | 2877 | 2091 | 0.470475 | 275 | 0.0470475 | Model Group:21_penant v1:877199
4350676 | 01 eerste verdieping | 01 eerste verdieping | 786 | Up to level: 01 eerste verdieping | 2877 | 2091 | 0.470475 | 275 | 0.0470475 | Model Group:21_penant v1:877199
4350679 | 01 eerste verdieping | 01 eerste verdieping | 786 | Up to level: 01 eerste verdieping | 2877 | 2091 | 0.470475 | 275 | 0.0470475 | Model Group:21_penant v1:877214
4350680 | 01 eerste verdieping | 01 eerste verdieping | 786 | Up to level: 01 eerste verdieping | 2877 | 2091 | 0.470475 | 275 | 0.0470475 | Model Group:21_penant v1:877214
4350683 | 01 eerste verdieping | 01 eerste verdieping | 786 | Up to level: 01 eerste verdieping | 2877 | 2091 | 0.470475 | 275 | 0.0470475 | Model Group:21_penant v1:880918
4350684 | 01 eerste verdieping | 01 eerste verdieping | 786 | Up to level: 01 eerste verdieping | 2877 | 2091 | 0.470475 | 275 | 0.0470475 | Model Group:21_penant v1:880918
4350687 | 01 eerste verdieping | 01 eerste verdieping | 786 | Up to level: 01 eerste verdieping | 2877 | 2091 | 0.470475 | 275 | 0.0470475 | Model Group:21_penant v1:881607
4350688 | 01 eerste verdieping | 01 eerste verdieping | 786 | Up to level: 01 eerste verdieping | 2877 | 2091 | 0.470475 | 275 | 0.0470475 | Model Group:21_penant v1:881607
4350691 | 01 eerste verdieping | 01 eerste verdieping | 786 | Up to level: 01 eerste verdieping | 2877 | 2091 | 0.470475 | 275 | 0.0470475 | Model Group:21_penant v1:881643
4350692 | 01 eerste verdieping | 01 eerste verdieping | 786 | Up to level: 01 eerste verdieping | 2877 | 2091 | 0.470475 | 275 | 0.0470475 | Model Group:21_penant v1:881643
4350695 | 01 eerste verdieping | 01 eerste verdieping | 786 | Up to level: 01 eerste verdieping | 2877 | 2091 | 0.470475 | 275 | 0.0470475 | Model Group:21_penant v1:881679
4350696 | 01 eerste verdieping | 01 eerste verdieping | 786 | Up to level: 01 eerste verdieping | 2877 | 2091 | 0.470475 | 275 | 0.0470475 | Model Group:21_penant v1:881679
4350699 | 01 eerste verdieping | 01 eerste verdieping | 786 | Up to level: 01 eerste verdieping | 2877 | 2091 | 0.470475 | 275 | 0.0470475 | Model Group:21_penant v1:881755
4350700 | 01 eerste verdieping | 01 eerste verdieping | 786 | Up to level: 01 eerste verdieping | 2877 | 2091 | 0.470475 | 275 | 0.0470475 | Model Group:21_penant v1:881755
4350703 | 01 eerste verdieping | 01 eerste verdieping | 786 | Up to level: 01 eerste verdieping | 2877 | 2091 | 0.470475 | 275 | 0.0470475 | Model Group:21_penant v1:881782
4350704 | 01 eerste verdieping | 01 eerste verdieping | 786 | Up to level: 01 eerste verdieping | 2877 | 2091 | 0.470475 | 275 | 0.0470475 | Model Group:21_penant v1:881782
4350707 | 01 eerste verdieping | 01 eerste verdieping | 786 | Up to level: 01 eerste verdieping | 2877 | 2091 | 0.470475 | 275 | 0.0470475 | Model Group:21_penant v1:881809
4350708 | 01 eerste verdieping | 01 eerste verdieping | 786 | Up to level: 01 eerste verdieping | 2877 | 2091 | 0.470475 | 275 | 0.0470475 | Model Group:21_penant v1:881809
4350711 | 01 eerste verdieping | 01 eerste verdieping | 786 | Up to level: 01 eerste verdieping | 2877 | 2091 | 0.470475 | 275 | 0.0470475 | Model Group:21_penant v1:891629
4350712 | 01 eerste verdieping | 01 eerste verdieping | 786 | Up to level: 01 eerste verdieping | 2877 | 2091 | 0.470475 | 275 | 0.0470475 | Model Group:21_penant v1:891629
4350715 | 01 eerste verdieping | 01 eerste verdieping | 786 | Up to level: 01 eerste verdieping | 2877 | 2091 | 0.470475 | 275 | 0.0470475 | Model Group:21_penant v1:891651
4350716 | 01 eerste verdieping | 01 eerste verdieping | 786 | Up to level: 01 eerste verdieping | 2877 | 2091 | 0.470475 | 275 | 0.0470475 | Model Group:21_penant v1:891651
4350719 | 01 eerste verdieping | 01 eerste verdieping | 786 | Up to level: 01 eerste verdieping | 2877 | 2091 | 0.470475 | 275 | 0.0470475 | Model Group:21_penant v1:891673
4350720 | 01 eerste verdieping | 01 eerste verdieping | 786 | Up to level: 01 eerste verdieping | 2877 | 2091 | 0.470475 | 275 | 0.0470475 | Model Group:21_penant v1:891673
4350723 | 01 eerste verdieping | 01 eerste verdieping | 786 | Up to level: 01 eerste verdieping | 2877 | 2091 | 0.470475 | 275 | 0.0470475 | Model Group:21_penant v1:891695
4350724 | 01 eerste verdieping | 01 eerste verdieping | 786 | Up to level: 01 eerste verdieping | 2877 | 2091 | 0.470475 | 275 | 0.0470475 | Model Group:21_penant v1:891695
4350727 | 01 eerste verdieping | 01 eerste verdieping | 786 | Up to level: 01 eerste verdieping | 2877 | 2091 | 0.470475 | 275 | 0.0470475 | Model Group:21_penant v1:891717
4350728 | 01 eerste verdieping | 01 eerste verdieping | 786 | Up to level: 01 eerste verdieping | 2877 | 2091 | 0.470475 | 275 | 0.0470475 | Model Group:21_penant v1:891717
4350731 | 01 eerste verdieping | 01 eerste verdieping | 786 | Up to level: 01 eerste verdieping | 2877 | 2091 | 0.470475 | 275 | 0.0470475 | Model Group:21_penant v1:891763
4350732 | 01 eerste verdieping | 01 eerste verdieping | 786 | Up to level: 01 eerste verdieping | 2877 | 2091 | 0.470475 | 275 | 0.0470475 | Model Group:21_penant v1:891763
4350735 | 01 eerste verdieping | 01 eerste verdieping | 786 | Up to level: 01 eerste verdieping | 2877 | 2091 | 0.470475 | 275 | 0.0470475 | Model Group:21_penant v1:891785
4350736 | 01 eerste verdieping | 01 eerste verdieping | 786 | Up to level: 01 eerste verdieping | 2877 | 2091 | 0.470475 | 275 | 0.0470475 | Model Group:21_penant v1:891785
4350739 | 01 eerste verdieping | 01 eerste verdieping | 786 | Up to level: 01 eerste verdieping | 2877 | 2091 | 0.470475 | 275 | 0.0470475 | Model Group:21_penant v1:891807
4350740 | 01 eerste verdieping | 01 eerste verdieping | 786 | Up to level: 01 eerste verdieping | 2877 | 2091 | 0.470475 | 275 | 0.0470475 | Model Group:21_penant v1:891807
4350743 | 01 eerste verdieping | 01 eerste verdieping | 786 | Up to level: 01 eerste verdieping | 2877 | 2091 | 0.470475 | 275 | 0.0470475 | Model Group:21_penant v1:891902
4350744 | 01 eerste verdieping | 01 eerste verdieping | 786 | Up to level: 01 eerste verdieping | 2877 | 2091 | 0.470475 | 275 | 0.0470475 | Model Group:21_penant v1:891902
4350747 | 01 eerste verdieping | 01 eerste verdieping | 786 | Up to level: 01 eerste verdieping | 2877 | 2091 | 0.470475 | 275 | 0.0470475 | Model Group:21_penant v1:891924
4350748 | 01 eerste verdieping | 01 eerste verdieping | 786 | Up to level: 01 eerste verdieping | 2877 | 2091 | 0.470475 | 275 | 0.0470475 | Model Group:21_penant v1:891924
4350751 | 01 eerste verdieping | 01 eerste verdieping | 786 | Up to level: 01 eerste verdieping | 2877 | 2091 | 0.470475 | 275 | 0.0470475 | Model Group:21_penant v1:891946
4350752 | 01 eerste verdieping | 01 eerste verdieping | 786 | Up to level: 01 eerste verdieping | 2877 | 2091 | 0.470475 | 275 | 0.0470475 | Model Group:21_penant v1:891946
4350755 | 01 eerste verdieping | 01 eerste verdieping | 786 | Up to level: 01 eerste verdieping | 2877 | 2091 | 0.470475 | 275 | 0.0470475 | Model Group:21_penant v1:891974
4350756 | 01 eerste verdieping | 01 eerste verdieping | 786 | Up to level: 01 eerste verdieping | 2877 | 2091 | 0.470475 | 275 | 0.0470475 | Model Group:21_penant v1:891974
4350759 | 01 eerste verdieping | 01 eerste verdieping | 786 | Up to level: 01 eerste verdieping | 2877 | 2091 | 0.470475 | 275 | 0.0470475 | Model Group:21_penant v1:891996
4350760 | 01 eerste verdieping | 01 eerste verdieping | 786 | Up to level: 01 eerste verdieping | 2877 | 2091 | 0.470475 | 275 | 0.0470475 | Model Group:21_penant v1:891996
4363482 | 01 eerste verdieping | 01 eerste verdieping | 786 | Up to level: 01 eerste verdieping | 2877 | 2091 | 0.470475 | 275 | 0.0470475 | Model Group:21_penant v1 ROND:1302570
4363526 | 01 eerste verdieping | 01 eerste verdieping | 786 | Up to level: 01 eerste verdieping | 2877 | 2091 | 0.470475 | 275 | 0.0470475 | Model Group:21_penant v1 ROND:1302570
4363571 | 01 eerste verdieping | 01 eerste verdieping | 786 | Up to level: 01 eerste verdieping | 2877 | 2091 | 0.470475 | 275 | 0.0470475 | Model Group:21_penant v1 ROND:1341016
4363572 | 01 eerste verdieping | 01 eerste verdieping | 786 | Up to level: 01 eerste verdieping | 2877 | 2091 | 0.470475 | 275 | 0.0470475 | Model Group:21_penant v1 ROND:1341016
4444512 | 01 eerste verdieping | 01 eerste verdieping | 786 | Up to level: 02 tweede verdieping | 419 | 3433 | 0.738095 | 115 | 0.0738095 | Model Group:21_penant v1:774467
4444513 | 01 eerste verdieping | 01 eerste verdieping | 2877 | Up to level: 02 tweede verdieping | 419 | 1342 | 0.02013 | 65 | 0.002013 | Model Group:21_penant v1:774467
4444514 | 01 eerste verdieping | 01 eerste verdieping | 2877 | Up to level: 02 tweede verdieping | 419 | 1342 | 0.02013 | 65 | 0.002013 | Model Group:21_penant v1:774467
4444516 | 01 eerste verdieping | 01 eerste verdieping | 786 | Up to level: 01 eerste verdieping | 2877 | 2091 | 0.470475 | 275 | 0.0470475 | Model Group:21_penant v1:774467
4444517 | 01 eerste verdieping | 01 eerste verdieping | 786 | Up to level: 01 eerste verdieping | 2877 | 2091 | 0.470475 | 275 | 0.0470475 | Model Group:21_penant v1:774467
5036874 | 00 begane grond | 00 begane grond | 0 | Up to level: 01 bk. ruwe vloer | 0 | 3950 | 1.185 | 400 | 0.1185
5037054 | 00 begane grond | 00 begane grond | 0 | Up to level: 01 bk. ruwe vloer | 0 | 3950 | 1.185 | 400 | 0.1185

# IfcWallStandardCase: Basic Wall:21_WA_metselwerk_middel_staand_100_gen_bdg (110)
Type - PredefinedType: STANDARD; Material: g2_metselwerk_geel_staand 100 mm
Type - Analytical Properties - Roughness: 1; Absorptance: 0.1; Heat Transfer Coefficient (U): 5.4 kg/K/s3; Thermal Mass: 130.2; Thermal Resistance (R): 0.185185
Type - Materials and Finishes - Structural Material: g2_metselwerk_geel_staand
Type - Graphics - Coarse Scale Fill Pattern: <Solid fill>; Coarse Scale Fill Color: 4210752
Type - Construction - Wrapping at Inserts: Do not wrap; Function: Exterior; Width: 100 mm
Type - Identity Data - Workset: Wall Types; Assembly Code: 2D(21.11.11); Datum_Gewijzigd: 26-05-2014; Description: horizontaal metselwerk D=100 mm; Model: LOD300; SmartRevit_Versie: 2015.1; Type Comments: hatch; Type Name: 21_WA_metselwerk_middel_staand_100_gen_bdg
Type - Other - Category: Walls; Family Name: Basic Wall
Classification: 2D(21.11.11) Uniformat (Uniformat)
Cross-Section Definition - Cross-Section: Vertical
Constraints - Base Extension Distance: 0 mm; Base is Attached: no; Location Line: Finish Face: Exterior; Related to Mass: no; Room Bounding: yes; Top Extension Distance: 0 mm; Top is Attached: no
Phasing - Phase Created: 2. nieuwbouw
Structural - Enable Analytical Model: no; Structural: no; Structural Usage: Non-bearing
Identity Data - Workset: Workset1
Other - Family: Basic Wall; Family and Type: Basic Wall: 21_WA_metselwerk_middel_staand_100_gen_bdg; Type: 21_WA_metselwerk_middel_staand_100_gen_bdg; Type Id: 862910
Name (Basic Wall:21_WA_metselwerk_middel_staand_100_gen_bdg:...) | In | Base Constraint | Base Offset (mm) | Top Constraint | Top Offset (mm) | Unconnected Height (mm) | Area (m2) | Length (mm) | Volume (m3)
772582 | 01 eerste verdieping | 01 eerste verdieping | 356 | Up to level: 01 eerste verdieping | 775 | 419 | 2.4147 | 5763 | 0.24147
892311 | 00 begane grond | bk. fundering | 0 | Up to level: 00 begane grond | 4356 | 4876 | 1.74073 | 357 | 0.174073
892312 | 00 begane grond | bk. fundering | 0 | Up to level: 00 begane grond | 4356 | 4876 | 1.74073 | 357 | 0.174073
892337 | 01 eerste verdieping | 01 eerste verdieping | 356 | Up to level: 01 eerste verdieping | 775 | 419 | 2.4147 | 5763 | 0.24147
892338 | 00 begane grond | bk. fundering | 0 | Up to level: 00 begane grond | 4356 | 4876 | 1.74073 | 357 | 0.174073
892339 | 00 begane grond | bk. fundering | 0 | Up to level: 00 begane grond | 4356 | 4876 | 1.74073 | 357 | 0.174073
892359 | 01 eerste verdieping | 01 eerste verdieping | 356 | Up to level: 01 eerste verdieping | 775 | 419 | 2.4147 | 5763 | 0.24147
892360 | 00 begane grond | bk. fundering | 0 | Up to level: 00 begane grond | 4356 | 4876 | 1.74073 | 357 | 0.174073
892361 | 00 begane grond | bk. fundering | 0 | Up to level: 00 begane grond | 4356 | 4876 | 1.74073 | 357 | 0.174073
892371 | 01 eerste verdieping | 01 eerste verdieping | 356 | Up to level: 01 eerste verdieping | 775 | 419 | 2.4147 | 5763 | 0.24147
892372 | 00 begane grond | bk. fundering | 0 | Up to level: 00 begane grond | 4356 | 4876 | 1.74073 | 357 | 0.174073
892373 | 00 begane grond | bk. fundering | 0 | Up to level: 00 begane grond | 4356 | 4876 | 1.74073 | 357 | 0.174073
892383 | 01 eerste verdieping | 01 eerste verdieping | 356 | Up to level: 01 eerste verdieping | 775 | 419 | 2.4147 | 5763 | 0.24147
892384 | 00 begane grond | bk. fundering | 0 | Up to level: 00 begane grond | 4356 | 4876 | 1.74073 | 357 | 0.174073
892385 | 00 begane grond | bk. fundering | 0 | Up to level: 00 begane grond | 4356 | 4876 | 1.74073 | 357 | 0.174073
892409 | 01 eerste verdieping | 01 eerste verdieping | 356 | Up to level: 01 eerste verdieping | 775 | 419 | 2.4147 | 5763 | 0.24147
892410 | 00 begane grond | bk. fundering | 0 | Up to level: 00 begane grond | 4356 | 4876 | 1.74073 | 357 | 0.174073
892411 | 00 begane grond | bk. fundering | 0 | Up to level: 00 begane grond | 4356 | 4876 | 1.74073 | 357 | 0.174073
892434 | 01 eerste verdieping | 01 eerste verdieping | 356 | Up to level: 01 eerste verdieping | 775 | 419 | 2.4147 | 5763 | 0.24147
892435 | 00 begane grond | bk. fundering | 0 | Up to level: 00 begane grond | 4356 | 4876 | 1.74073 | 357 | 0.174073
892436 | 00 begane grond | bk. fundering | 0 | Up to level: 00 begane grond | 4356 | 4876 | 1.74073 | 357 | 0.174073
892448 | 01 eerste verdieping | 01 eerste verdieping | 356 | Up to level: 01 eerste verdieping | 775 | 419 | 2.78698 | 6601.5 | 0.278698
892449 | 00 begane grond | bk. fundering | 0 | Up to level: 00 begane grond | 4356 | 4876 | 1.74073 | 357 | 0.174073
892465 | 01 eerste verdieping | 01 eerste verdieping | 356 | Up to level: 01 eerste verdieping | 775 | 419 | 2.41491 | 5763.5 | 0.241491
892466 | 00 begane grond | bk. fundering | 0 | Up to level: 00 begane grond | 4356 | 4876 | 1.74073 | 357 | 0.174073
892467 | 00 begane grond | bk. fundering | 0 | Up to level: 00 begane grond | 4356 | 4876 | 1.74073 | 357 | 0.174073
892479 | 01 eerste verdieping | 01 eerste verdieping | 356 | Up to level: 01 eerste verdieping | 775 | 419 | 2.15848 | 5101.5 | 0.215848
892481 | 00 begane grond | bk. fundering | 0 | Up to level: 00 begane grond | 4356 | 4876 | 1.74073 | 357 | 0.174073
892500 | 01 eerste verdieping | 01 eerste verdieping | 356 | Up to level: 01 eerste verdieping | 775 | 419 | 0.94275 | 2250 | 0.094275
892519 | 01 eerste verdieping | 01 eerste verdieping | 356 | Up to level: 01 eerste verdieping | 775 | 419 | 2.4147 | 5763 | 0.24147
892520 | 00 begane grond | bk. fundering | 0 | Up to level: 00 begane grond | 4356 | 4876 | 1.74073 | 357 | 0.174073
892521 | 00 begane grond | bk. fundering | 0 | Up to level: 00 begane grond | 4356 | 4876 | 1.74073 | 357 | 0.174073
892531 | 01 eerste verdieping | 01 eerste verdieping | 356 | Up to level: 01 eerste verdieping | 775 | 419 | 0.256218 | 661.5 | 0.0256218
892532 | 00 begane grond | bk. fundering | 0 | Up to level: 00 begane grond | 4356 | 4876 | 1.74073 | 357 | 0.174073
1223863 | 01 eerste verdieping | 01 eerste verdieping | 356 | Up to level: 01 eerste verdieping | 775 | 419 | 1.44618 | 3501.5 | 0.144618
1223865 | 00 begane grond | bk. fundering | 0 | Up to level: 00 begane grond | 4356 | 4876 | 1.74073 | 357 | 0.174073
1224018 | 01 eerste verdieping | 01 eerste verdieping | 356 | Up to level: 01 eerste verdieping | 775 | 419 | 1.58654 | 3786.5 | 0.158654
1224019 | 00 begane grond | bk. fundering | 0 | Up to level: 00 begane grond | 4356 | 4876 | 1.74073 | 357 | 0.174073
1224070 | 01 eerste verdieping | 01 eerste verdieping | 356 | Up to level: 01 eerste verdieping | 775 | 419 | 2.06026 | 4917.09 | 0.206026
1224072 | 00 begane grond | bk. fundering | 0 | Up to level: 00 begane grond | 4356 | 4876 | 1.74073 | 357 | 0.174073
1224126 | 01 eerste verdieping | 01 eerste verdieping | 356 | Up to level: 01 eerste verdieping | 775 | 419 | 2.4147 | 5763 | 0.24147
1224127 | 00 begane grond | bk. fundering | 0 | Up to level: 00 begane grond | 4356 | 4876 | 1.74073 | 357 | 0.174073
1224128 | 00 begane grond | bk. fundering | 0 | Up to level: 00 begane grond | 4356 | 4876 | 1.74073 | 357 | 0.174073
1289380 | 01 eerste verdieping | 01 eerste verdieping | 356 | Up to level: 01 eerste verdieping | 775 | 419 | 0.985278 | 2351.5 | 0.0985278
1289381 | 00 begane grond | bk. fundering | 0 | Up to level: 00 begane grond | 4356 | 4876 | 1.74073 | 357 | 0.174073
1289939 | 01 eerste verdieping | 01 eerste verdieping | 356 | Up to level: 01 eerste verdieping | 775 | 419 | 2.4147 | 5763 | 0.24147
1289942 | 00 begane grond | bk. fundering | 0 | Up to level: 00 begane grond | 4356 | 4876 | 1.74073 | 357 | 0.174073
1289943 | 00 begane grond | bk. fundering | 0 | Up to level: 00 begane grond | 4356 | 4876 | 1.74073 | 357 | 0.174073
1289960 | 01 eerste verdieping | 01 eerste verdieping | 356 | Up to level: 01 eerste verdieping | 775 | 419 | 2.78698 | 6651.5 | 0.278698
1289964 | 00 begane grond | bk. fundering | 0 | Up to level: 00 begane grond | 4356 | 4876 | 1.74073 | 357 | 0.174073
1290134 | 01 eerste verdieping | 01 eerste verdieping | 356 | Up to level: 01 eerste verdieping | 775 | 419 | 0.789796 | 1806.42 | 0.0751822 | Graphics - Center Mark Visible: no
1310171 | 01 eerste verdieping | 01 eerste verdieping | 356 | Up to level: 01 eerste verdieping | 775 | 419 | 2.4147 | 5763 | 0.24147
1310172 | 00 begane grond | bk. fundering | 0 | Up to level: 00 begane grond | 4356 | 4876 | 1.74073 | 357 | 0.174073
1310173 | 00 begane grond | bk. fundering | 0 | Up to level: 00 begane grond | 4356 | 4876 | 1.74073 | 357 | 0.174073
1310411 | 01 eerste verdieping | 01 eerste verdieping | 356 | Up to level: 01 eerste verdieping | 775 | 419 | 2.4147 | 5763 | 0.24147
1310412 | 00 begane grond | bk. fundering | 0 | Up to level: 00 begane grond | 4356 | 4876 | 1.74073 | 357 | 0.174073
1310413 | 00 begane grond | bk. fundering | 0 | Up to level: 00 begane grond | 4356 | 4876 | 1.74073 | 357 | 0.174073
1311151 | 01 eerste verdieping | 01 eerste verdieping | 356 | Up to level: 01 eerste verdieping | 775 | 419 | 2.4147 | 5763 | 0.24147
1311152 | 00 begane grond | bk. fundering | 0 | Up to level: 00 begane grond | 4356 | 4876 | 1.74073 | 357 | 0.174073
1311153 | 00 begane grond | bk. fundering | 0 | Up to level: 00 begane grond | 4356 | 4876 | 1.74073 | 357 | 0.174073
1312688 | 01 eerste verdieping | 01 eerste verdieping | 356 | Up to level: 01 eerste verdieping | 775 | 419 | 2.79683 | 6725 | 0.279683
1315491 | 00 begane grond | bk. fundering | 0 | Up to level: 01 eerste verdieping | 775 | 5295 | 1.89031 | 357 | 0.189031
1324551 | 01 eerste verdieping | 01 eerste verdieping | 150 | Up to level: 01 eerste verdieping | 775 | 625 | 0.728125 | 1115 | 0.0728125
1341905 | 01 eerste verdieping | 01 eerste verdieping | 356 | Up to level: 01 eerste verdieping | 775 | 419 | 0.329753 | 787 | 0.0329753
1341906 | 00 begane grond | bk. fundering | 0 | Up to level: 00 begane grond | 4356 | 4876 | 1.74073 | 357 | 0.174073
1343012 | 01 eerste verdieping | 01 eerste verdieping | 356 | Up to level: 01 eerste verdieping | 775 | 419 | 2.41616 | 5766.5 | 0.241616
1343013 | 00 begane grond | bk. fundering | 0 | Up to level: 00 begane grond | 4356 | 4876 | 1.74073 | 357 | 0.174073
1343014 | 00 begane grond | bk. fundering | 0 | Up to level: 00 begane grond | 4356 | 4876 | 1.74073 | 357 | 0.174073
1343575 | 01 eerste verdieping | 01 eerste verdieping | 356 | Up to level: 01 eerste verdieping | 775 | 419 | 0.785625 | 1875 | 0.0785625
1343577 | 00 begane grond | bk. fundering | 0 | Up to level: 00 begane grond | 4356 | 4876 | 1.74073 | 357 | 0.174073
1345433 | 01 eerste verdieping | 01 eerste verdieping | 356 | Up to level: 01 eerste verdieping | 775 | 419 | 2.44071 | 5825.09 | 0.244071
1348303 | 01 eerste verdieping | 01 eerste verdieping | 356 | Up to level: 01 eerste verdieping | 775 | 419 | 0.884719 | 2061.5 | 0.0884719
1348305 | 00 begane grond | bk. fundering | 0 | Up to level: 00 begane grond | 4356 | 4876 | 1.74073 | 357 | 0.174073
1348666 | 01 eerste verdieping | 01 eerste verdieping | 356 | Up to level: 01 eerste verdieping | 775 | 419 | 2.4147 | 5763 | 0.24147
1348667 | 00 begane grond | bk. fundering | 0 | Up to level: 00 begane grond | 4356 | 4876 | 1.74073 | 357 | 0.174073
1348668 | 00 begane grond | bk. fundering | 0 | Up to level: 00 begane grond | 4356 | 4876 | 1.74073 | 357 | 0.174073
1348939 | 01 eerste verdieping | 01 eerste verdieping | 356 | Up to level: 01 eerste verdieping | 775 | 419 | 1.52998 | 3701.5 | 0.152998
1348940 | 00 begane grond | bk. fundering | 0 | Up to level: 00 begane grond | 4356 | 4876 | 1.74073 | 357 | 0.174073
1349245 | 01 eerste verdieping | 01 eerste verdieping | 356 | Up to level: 01 eerste verdieping | 775 | 419 | 2.15785 | 5150 | 0.215785
1500579 | 01 eerste verdieping | 01 eerste verdieping | 356 | Up to level: 01 eerste verdieping | 775 | 419 | 2.4147 | 5763 | 0.24147
1500580 | 00 begane grond | bk. fundering | 0 | Up to level: 00 begane grond | 4356 | 4876 | 1.74073 | 357 | 0.174073
1500581 | 00 begane grond | bk. fundering | 0 | Up to level: 00 begane grond | 4356 | 4876 | 1.74073 | 357 | 0.174073
1500609 | 01 eerste verdieping | 01 eerste verdieping | 356 | Up to level: 01 eerste verdieping | 775 | 419 | 2.4147 | 5763 | 0.24147
1500610 | 00 begane grond | bk. fundering | 0 | Up to level: 00 begane grond | 4356 | 4876 | 1.74073 | 357 | 0.174073
1500611 | 00 begane grond | bk. fundering | 0 | Up to level: 00 begane grond | 4356 | 4876 | 1.74073 | 357 | 0.174073
1500628 | 01 eerste verdieping | 01 eerste verdieping | 356 | Up to level: 01 eerste verdieping | 775 | 419 | 1.99088 | 4701.5 | 0.199088
1500630 | 00 begane grond | bk. fundering | 0 | Up to level: 00 begane grond | 4356 | 4876 | 1.74073 | 357 | 0.174073
1500897 | 01 eerste verdieping | 01 eerste verdieping | 356 | Up to level: 01 eerste verdieping | 775 | 419 | 2.4147 | 5763 | 0.24147
1500898 | 00 begane grond | bk. fundering | 0 | Up to level: 00 begane grond | 4356 | 4876 | 1.74073 | 357 | 0.174073
1500899 | 00 begane grond | bk. fundering | 0 | Up to level: 00 begane grond | 4356 | 4876 | 1.74073 | 357 | 0.174073
1500922 | 01 eerste verdieping | 01 eerste verdieping | 356 | Up to level: 01 eerste verdieping | 775 | 419 | 2.4147 | 5763 | 0.24147
1500923 | 00 begane grond | bk. fundering | 0 | Up to level: 00 begane grond | 4356 | 4876 | 1.74073 | 357 | 0.174073
1500924 | 00 begane grond | bk. fundering | 0 | Up to level: 00 begane grond | 4356 | 4876 | 1.74073 | 357 | 0.174073
1500943 | 01 eerste verdieping | 01 eerste verdieping | 356 | Up to level: 01 eerste verdieping | 775 | 419 | 0.671028 | 1651.5 | 0.0671028
1500944 | 00 begane grond | bk. fundering | 0 | Up to level: 00 begane grond | 4356 | 4876 | 1.74073 | 357 | 0.174073
1836009 | 01 eerste verdieping | 01 eerste verdieping | 150 | Up to level: 01 eerste verdieping | 775 | 625 | 0.14375 | 180 | 0.014375
1836010 | 01 eerste verdieping | 01 eerste verdieping | 150 | Up to level: 01 eerste verdieping | 775 | 625 | 0.14375 | 180 | 0.014375
1836011 | 01 eerste verdieping | 01 eerste verdieping | 150 | Up to level: 01 eerste verdieping | 775 | 625 | 8.33437 | 13470 | 0.833438
1836320 | 01 eerste verdieping | 01 eerste verdieping | 171 | Up to level: 01 eerste verdieping | 775 | 604 | 2.42204 | 4110 | 0.242204
1836596 | 01 eerste verdieping | 01 eerste verdieping | 150 | Up to level: 01 eerste verdieping | 775 | 625 | 0.14375 | 180 | 0.014375
1836829 | 01 eerste verdieping | 01 eerste verdieping | 150 | Up to level: 01 eerste verdieping | 775 | 625 | 0.08125 | 180 | 0.008125
1883920 | 01 eerste verdieping | 01 eerste verdieping | 171 | Up to level: 01 eerste verdieping | 775 | 604 | 16.0878 | 26640 | 1.60878
1883967 | 01 eerste verdieping | 01 eerste verdieping | 171 | Up to level: 01 eerste verdieping | 775 | 604 | 0.55719 | 1022.5 | 0.055719
1912340 | 01 eerste verdieping | 01 eerste verdieping | -50 | Up to level: 01 eerste verdieping | 775 | 825 | 0.19191 | 290 | 0.019191
2029922 | 01 eerste verdieping | 01 eerste verdieping | 356 | Up to level: 01 eerste verdieping | 775 | 419 | 0.773697 | 1809.15 | 0.0758034 | Graphics - Center Mark Visible: no; Group: Model Group:21_rond:1344849
2030040 | 01 eerste verdieping | 01 eerste verdieping | 356 | Up to level: 01 eerste verdieping | 775 | 419 | 0.773697 | 1809.15 | 0.0758034 | Graphics - Center Mark Visible: no; Group: Model Group:21_rond:1344284
2030146 | 01 eerste verdieping | 01 eerste verdieping | 356 | Up to level: 01 eerste verdieping | 775 | 419 | 0.667197 | 1554.98 | 0.0651536 | Graphics - Center Mark Visible: no; Group: Model Group:21_rond:1344849
2030194 | 01 eerste verdieping | 01 eerste verdieping | 356 | Up to level: 01 eerste verdieping | 775 | 419 | 0.667197 | 1554.98 | 0.0651536 | Graphics - Center Mark Visible: no; Group: Model Group:21_rond:1344284
2031922 | 01 eerste verdieping | 01 eerste verdieping | 356 | Up to level: 01 eerste verdieping | 775 | 419 | 0.710817 | 1617.92 | 0.067782 | Graphics - Center Mark Visible: no
2988925 | 01 eerste verdieping | 01 eerste verdieping | 150 | Up to level: 01 eerste verdieping | 775 | 625 | 3.68906 | 7125 | 0.368906

# IfcWallStandardCase: Basic Wall:21_WA_tegelwerk 10 (155)
Type - PredefinedType: STANDARD; Material: g3_tegels_creme_150x150 10 mm
Type - Analytical Properties - Roughness: 1; Absorptance: 0.1
Type - Graphics - Coarse Scale Fill Pattern: <Solid fill>; Coarse Scale Fill Color: 4210752
Type - Construction - Wrapping at Inserts: Do not wrap; Function: Exterior; Width: 10 mm
Type - Identity Data - Workset: Wall Types; Assembly Code: 2D(21.10); Datum_Gewijzigd: 26-05-2014; Description: wandtegelwerk 10mm; Model: LOD300; SmartRevit_Versie: 2014.3; Type Name: 21_WA_tegelwerk 10
Type - Other - Category: Walls; Family Name: Basic Wall
Classification: 2D(21.10) Uniformat (Uniformat)
Cross-Section Definition - Cross-Section: Vertical
Constraints - Base Extension Distance: 0 mm; Base is Attached: no; Related to Mass: no; Room Bounding: yes; Top Extension Distance: 0 mm; Top is Attached: no; Top Offset: 0 mm; Unconnected Height: 2800 mm
Phasing - Phase Created: 2. nieuwbouw
Structural - Enable Analytical Model: no; Structural: no; Structural Usage: Non-bearing
Identity Data - Workset: Workset1
Other - Family: Basic Wall; Family and Type: Basic Wall: 21_WA_tegelwerk 10; Type: 21_WA_tegelwerk 10; Type Id: 2160157
Name (Basic Wall:21_WA_tegelwerk 10:...) | In | Base Constraint | Location Line | Base Offset (mm) | Area (m2) | Length (mm) | Volume (m3)
2160282 | 00 begane grond | 00 begane grond | Core Face: Exterior | 100 | 4.3645 | 1840 | 0.043645
2160283 | 00 begane grond | 00 begane grond | Core Face: Exterior | 0 | 5.15484 | 2722.5 | 0.0515484
2160284 | 00 begane grond | 00 begane grond | Core Face: Exterior | 0 | 5.152 | 1840 | 0.05152
2160285 | 00 begane grond | 00 begane grond | Core Face: Exterior | 0 | 5.15484 | 2722.5 | 0.0515484
2160398 | 00 begane grond | 00 begane grond | Core Face: Exterior | 0 | 5.432 | 1940 | 0.05432
2160399 | 00 begane grond | 00 begane grond | Core Face: Exterior | 0 | 4.22384 | 2390 | 0.0422384
2160400 | 00 begane grond | 00 begane grond | Core Face: Exterior | 100 | 4.6445 | 1940 | 0.046445
2160401 | 00 begane grond | 00 begane grond | Core Face: Exterior | 0 | 6.692 | 2390 | 0.06692
2160706 | 00 begane grond | 00 begane grond | Core Face: Exterior | 0 | 3.31913 | 1174.01 | 0.0331564
2160732 | 00 begane grond | 00 begane grond | Core Face: Exterior | 0 | 0.56 | 200 | 0.0056
2160753 | 00 begane grond | 00 begane grond | Core Face: Exterior | 0 | 2.912 | 1040 | 0.02912
2160806 | 00 begane grond | 00 begane grond | Core Face: Exterior | 100 | 7.949 | 3080 | 0.07949
2160843 | 00 begane grond | 00 begane grond | Core Face: Exterior | 0 | 1.4857 | 1495.94 | 0.0148221
2160913 | 00 begane grond | 00 begane grond | Core Face: Exterior | 0 | 8.28201 | 2968.17 | 0.0828201
2161147 | 00 begane grond | 00 begane grond | Core Face: Exterior | 0 | 12.306 | 4395 | 0.12306
2161148 | 00 begane grond | 00 begane grond | Core Face: Exterior | 0 | 3.42584 | 2105 | 0.0342584
2161149 | 00 begane grond | 00 begane grond | Core Face: Exterior | 0 | 12.306 | 4395 | 0.12306
2161150 | 00 begane grond | 00 begane grond | Core Face: Exterior | 0 | 3.42584 | 2105 | 0.0342584
2166262 | 01 eerste verdieping | 01 eerste verdieping | Finish Face: Exterior | 0 | 4.9126 | 1754.5 | 0.049126
2166263 | 01 eerste verdieping | 01 eerste verdieping | Finish Face: Exterior | 0 | 4.04744 | 2317 | 0.0404744
2166264 | 01 eerste verdieping | 01 eerste verdieping | Finish Face: Exterior | 0 | 5.152 | 1840 | 0.05152
2166265 | 01 eerste verdieping | 01 eerste verdieping | Finish Face: Exterior | 0 | 4.57384 | 2515 | 0.0457384
2166604 | 02 tweede verdieping | 02 tweede verdieping | Finish Face: Exterior | 0 | 4.9126 | 1754.5 | 0.049126
2166605 | 02 tweede verdieping | 02 tweede verdieping | Finish Face: Exterior | 0 | 4.04744 | 2317 | 0.0404744
2166606 | 02 tweede verdieping | 02 tweede verdieping | Finish Face: Exterior | 0 | 5.152 | 1840 | 0.05152
2166607 | 02 tweede verdieping | 02 tweede verdieping | Finish Face: Exterior | 0 | 4.57384 | 2515 | 0.0457384
2166622 | 02 tweede verdieping | 02 tweede verdieping | Finish Face: Exterior | 100 | 2.4848 | 1128.5 | 0.024848
2166623 | 02 tweede verdieping | 02 tweede verdieping | Finish Face: Exterior | 0 | 7.196 | 2570 | 0.07196
2166624 | 02 tweede verdieping | 02 tweede verdieping | Finish Face: Exterior | 0 | 3.1598 | 1128.5 | 0.031598
2166625 | 02 tweede verdieping | 02 tweede verdieping | Finish Face: Exterior | 0 | 7.196 | 2570 | 0.07196
2166641 | 02 tweede verdieping | 02 tweede verdieping | Finish Face: Exterior | 100 | 5.36 | 2065 | 0.0536
2166642 | 02 tweede verdieping | 02 tweede verdieping | Finish Face: Exterior | 0 | 3.4398 | 1228.5 | 0.034398
2166643 | 02 tweede verdieping | 02 tweede verdieping | Finish Face: Exterior | 0 | 3.31384 | 2065 | 0.0331384
2166750 | 02 tweede verdieping | 02 tweede verdieping | Finish Face: Exterior | 0 | 5.152 | 1840 | 0.05152
2166751 | 02 tweede verdieping | 02 tweede verdieping | Finish Face: Exterior | 0 | 4.15944 | 2367 | 0.0415944
2166752 | 02 tweede verdieping | 02 tweede verdieping | Finish Face: Exterior | 0 | 4.9406 | 1754.5 | 0.049406
2166753 | 02 tweede verdieping | 02 tweede verdieping | Finish Face: Exterior | 0 | 4.71384 | 2565 | 0.0471384
2166768 | 02 tweede verdieping | 02 tweede verdieping | Finish Face: Exterior | 0 | 3.276 | 1170 | 0.03276
2166769 | 02 tweede verdieping | 02 tweede verdieping | Finish Face: Exterior | 0 | 4.76284 | 2582.5 | 0.0476284
2166770 | 02 tweede verdieping | 02 tweede verdieping | Finish Face: Exterior | 100 | 2.601 | 1170 | 0.02601
2166771 | 02 tweede verdieping | 02 tweede verdieping | Finish Face: Exterior | 0 | 7.231 | 2582.5 | 0.07231
2166882 | 01 eerste verdieping | 01 eerste verdieping | Finish Face: Exterior | 0 | 2.912 | 1040 | 0.02912
2166883 | 01 eerste verdieping | 01 eerste verdieping | Finish Face: Exterior | 100 | 6.717 | 2640 | 0.06717
2166884 | 01 eerste verdieping | 01 eerste verdieping | Finish Face: Exterior | 0 | 0.443845 | 1040 | 0.00443845
2166885 | 01 eerste verdieping | 01 eerste verdieping | Finish Face: Exterior | 0 | 7.392 | 2640 | 0.07392
2166990 | 01 eerste verdieping | 01 eerste verdieping | Finish Face: Exterior | 0 | 3.332 | 1190 | 0.03332
2166991 | 01 eerste verdieping | 01 eerste verdieping | Finish Face: Exterior | 0 | 7.196 | 2570 | 0.07196
2166992 | 01 eerste verdieping | 01 eerste verdieping | Finish Face: Exterior | 100 | 2.657 | 1190 | 0.02657
2166993 | 01 eerste verdieping | 01 eerste verdieping | Finish Face: Exterior | 0 | 4.72784 | 2570 | 0.0472784
2167035 | 01 eerste verdieping | 01 eerste verdieping | Finish Face: Exterior | 0 | 2.912 | 1040 | 0.02912
2167036 | 01 eerste verdieping | 01 eerste verdieping | Finish Face: Exterior | 0 | 4.72784 | 2570 | 0.0472784
2167037 | 01 eerste verdieping | 01 eerste verdieping | Finish Face: Exterior | 100 | 2.3495 | 1040 | 0.023495
2167038 | 01 eerste verdieping | 01 eerste verdieping | Finish Face: Exterior | 0 | 7.196 | 2570 | 0.07196
2167104 | 01 eerste verdieping | 01 eerste verdieping | Finish Face: Exterior | 0 | 5.15201 | 1840 | 0.0515201
2167105 | 01 eerste verdieping | 01 eerste verdieping | Finish Face: Exterior | 0 | 4.15944 | 2367 | 0.0415944
2167106 | 01 eerste verdieping | 01 eerste verdieping | Finish Face: Exterior | 100 | 4.37811 | 1754.5 | 0.0437811
2167107 | 01 eerste verdieping | 01 eerste verdieping | Finish Face: Exterior | 0 | 4.71384 | 2565 | 0.0471384
2426871 | 00 begane grond | 00 begane grond | Core Face: Exterior | 0 | 5.152 | 1840 | 0.05152
2426872 | 00 begane grond | 00 begane grond | Core Face: Exterior | 0 | 5.15484 | 2722.5 | 0.0515484
2426873 | 00 begane grond | 00 begane grond | Core Face: Exterior | 0 | 5.152 | 1840 | 0.05152
2426874 | 00 begane grond | 00 begane grond | Core Face: Exterior | 0 | 5.15484 | 2722.5 | 0.0515484
2426961 | 00 begane grond | 00 begane grond | Core Face: Exterior | 0 | 3.094 | 1095 | 0.03094
2427080 | 00 begane grond | 00 begane grond | Core Face: Exterior | 0 | 6.13274 | 3157 | 0.0613274
2427157 | 00 begane grond | 00 begane grond | Core Face: Exterior | 0 | 1.47284 | 1397.5 | 0.0147284
2427239 | 00 begane grond | 00 begane grond | Core Face: Exterior | 0 | 13.608 | 4860 | 0.13608
2427309 | 00 begane grond | 00 begane grond | Core Face: Exterior | 0 | 1.20614 | 1397.5 | 0.0120614
2427356 | 00 begane grond | 00 begane grond | Core Face: Exterior | 0 | 10.8731 | 4860 | 0.108731
2427381 | 00 begane grond | 00 begane grond | Core Face: Exterior | 0 | 0.597842 | 1095 | 0.00597842
2427428 | 00 begane grond | 00 begane grond | Core Face: Exterior | 0 | 8.8116 | 3157 | 0.088116
2427723 | 00 begane grond | 00 begane grond | Core Face: Exterior | 0 | 3.066 | 1095 | 0.03066
2427724 | 00 begane grond | 00 begane grond | Core Face: Exterior | 0 | 3.472 | 1240 | 0.03472
2427725 | 00 begane grond | 00 begane grond | Core Face: Exterior | 0 | 0.621712 | 1095 | 0.00621712
2427726 | 00 begane grond | 00 begane grond | Core Face: Exterior | 0 | 3.472 | 1240 | 0.03472
2427928 | 00 begane grond | 00 begane grond | Core Face: Exterior | 0 | 13.636 | 4860 | 0.13636
2427954 | 00 begane grond | 00 begane grond | Core Face: Exterior | 0 | 0.888772 | 1190.38 | 0.00888772
2427990 | 00 begane grond | 00 begane grond | Core Face: Exterior | 0 | 1.51794 | 542.121 | 0.0151794
2428015 | 00 begane grond | 00 begane grond | Core Face: Exterior | 0 | 0.364 | 130 | 0.00364
2428037 | 00 begane grond | 00 begane grond | Core Face: Exterior | 0 | 1.51794 | 542.121 | 0.0151794
2428068 | 00 begane grond | 00 begane grond | Core Face: Exterior | 0 | 11.3809 | 4064.62 | 0.113809
2428100 | 00 begane grond | 00 begane grond | Core Face: Exterior | 0 | 3.227 | 1152.5 | 0.03227
2428124 | 00 begane grond | 00 begane grond | Core Face: Exterior | 0 | 0.364 | 130 | 0.00364
2428148 | 00 begane grond | 00 begane grond | Core Face: Exterior | 0 | 2.331 | 832.5 | 0.02331
2428177 | 00 begane grond | 00 begane grond | Core Face: Exterior | 100 | 4.211 | 1745 | 0.04211
2428218 | 00 begane grond | 00 begane grond | Core Face: Exterior | 0 | 2.331 | 832.5 | 0.02331
2428240 | 00 begane grond | 00 begane grond | Core Face: Exterior | 0 | 0.364 | 130 | 0.00364
2428269 | 00 begane grond | 00 begane grond | Core Face: Exterior | 0 | 2.9008 | 1036 | 0.029008
2428306 | 00 begane grond | 00 begane grond | Core Face: Exterior | 0 | 5.488 | 1960 | 0.05488
2428353 | 00 begane grond | 00 begane grond | Core Face: Exterior | 0 | 13.2818 | 4743.5 | 0.132818
2428375 | 00 begane grond | 00 begane grond | Core Face: Exterior | 0 | 6.426 | 2295 | 0.06426
2428408 | 00 begane grond | 00 begane grond | Core Face: Exterior | 0 | 4.718 | 1685 | 0.04718
2428433 | 00 begane grond | 00 begane grond | Core Face: Exterior | 0 | 0.938 | 335 | 0.00938
2428465 | 00 begane grond | 00 begane grond | Core Face: Exterior | 0 | 1.211 | 432.5 | 0.01211
2428487 | 00 begane grond | 00 begane grond | Core Face: Exterior | 0 | 0.364 | 130 | 0.00364
2428552 | 00 begane grond | 00 begane grond | Core Face: Exterior | 0 | 0.847 | 302.5 | 0.00847
2428594 | 00 begane grond | 00 begane grond | Core Face: Exterior | 0 | 4.886 | 1745 | 0.04886
2428620 | 00 begane grond | 00 begane grond | Core Face: Exterior | 0 | 0.847 | 302.5 | 0.00847
2428655 | 00 begane grond | 00 begane grond | Core Face: Exterior | 0 | 0.364 | 130 | 0.00364
2428688 | 00 begane grond | 00 begane grond | Core Face: Exterior | 0 | 3.46084 | 2117.5 | 0.0346084
2428729 | 00 begane grond | 00 begane grond | Core Face: Exterior | 0 | 11.382 | 4065 | 0.11382
2428754 | 00 begane grond | 00 begane grond | Core Face: Exterior | 0 | 1.512 | 540 | 0.01512
2428778 | 00 begane grond | 00 begane grond | Core Face: Exterior | 0 | 0.364 | 130 | 0.00364
2428801 | 00 begane grond | 00 begane grond | Core Face: Exterior | 0 | 1.512 | 540 | 0.01512
2428836 | 00 begane grond | 00 begane grond | Core Face: Exterior | 0 | 0.621012 | 1190 | 0.00621012
2428885 | 00 begane grond | 00 begane grond | Core Face: Exterior | 0 | 0.392 | 130 | 0.00392
2428926 | 00 begane grond | 00 begane grond | Core Face: Exterior | 0 | 5.628 | 2010 | 0.05628
2428945 | 00 begane grond | 00 begane grond | Core Face: Exterior | 0 | 0.364 | 130 | 0.00364
2428986 | 00 begane grond | 00 begane grond | Core Face: Exterior | 0 | 5.6 | 2010 | 0.056
2431061 | 00 begane grond | 00 begane grond | Core Face: Exterior | 0 | 5.516 | 1960 | 0.05516
2431089 | 00 begane grond | 00 begane grond | Core Face: Exterior | 0 | 2.9008 | 1036 | 0.029008
2431112 | 00 begane grond | 00 begane grond | Core Face: Exterior | 0 | 0.364 | 130 | 0.00364
2431142 | 00 begane grond | 00 begane grond | Core Face: Exterior | 0 | 2.331 | 832.5 | 0.02331
2431166 | 00 begane grond | 00 begane grond | Core Face: Exterior | 100 | 4.771 | 1945 | 0.04771
2431193 | 00 begane grond | 00 begane grond | Core Face: Exterior | 0 | 2.331 | 832.5 | 0.02331
2431218 | 00 begane grond | 00 begane grond | Core Face: Exterior | 0 | 0.364 | 130 | 0.00364
2431246 | 00 begane grond | 00 begane grond | Core Face: Exterior | 0 | 3.227 | 1152.5 | 0.03227
2431288 | 00 begane grond | 00 begane grond | Core Face: Exterior | 0 | 8.93962 | 4072.5 | 0.0893962
2431321 | 00 begane grond | 00 begane grond | Core Face: Exterior | 0 | 3.63003 | 1286.44 | 0.0363003
2431353 | 00 begane grond | 00 begane grond | Core Face: Exterior | 0 | 2.8 | 1000 | 0.028
2431382 | 00 begane grond | 00 begane grond | Core Face: Exterior | 0 | 0.364 | 130 | 0.00364
2431403 | 00 begane grond | 00 begane grond | Core Face: Exterior | 0 | 2.8 | 1000 | 0.028
2431454 | 00 begane grond | 00 begane grond | Core Face: Exterior | 0 | 13.5746 | 4848.06 | 0.135746
2431485 | 00 begane grond | 00 begane grond | Core Face: Exterior | 0 | 8.1928 | 2926 | 0.081928
2431512 | 00 begane grond | 00 begane grond | Core Face: Exterior | 0 | 2.8 | 1000 | 0.028
2431537 | 00 begane grond | 00 begane grond | Core Face: Exterior | 0 | 0.364 | 130 | 0.00364
2431567 | 00 begane grond | 00 begane grond | Core Face: Exterior | 0 | 2.8 | 1000 | 0.028
2431596 | 00 begane grond | 00 begane grond | Core Face: Exterior | 0 | 3.1262 | 1116.5 | 0.031262
2431638 | 00 begane grond | 00 begane grond | Core Face: Exterior | 0 | 5.03385 | 3637.5 | 0.0503385
2431692 | 00 begane grond | 00 begane grond | Core Face: Exterior | 0 | 0.364 | 130 | 0.00364
2431717 | 00 begane grond | 00 begane grond | Core Face: Exterior | 0 | 0.847 | 302.5 | 0.00847
2431745 | 00 begane grond | 00 begane grond | Core Face: Exterior | 0 | 5.446 | 1945 | 0.05446
2431770 | 00 begane grond | 00 begane grond | Core Face: Exterior | 0 | 0.847 | 302.5 | 0.00847
2431792 | 00 begane grond | 00 begane grond | Core Face: Exterior | 0 | 0.364 | 130 | 0.00364
2431825 | 00 begane grond | 00 begane grond | Core Face: Exterior | 0 | 5.929 | 2117.5 | 0.05929
2431852 | 00 begane grond | 00 begane grond | Core Face: Exterior | 0 | 5.488 | 1960 | 0.05488
2431907 | 00 begane grond | 00 begane grond | Core Face: Exterior | 0 | 13.2538 | 4743.5 | 0.132538
2431974 | 00 begane grond | 00 begane grond | Core Face: Exterior | 0 | 3.36 | 1190 | 0.0336
2432002 | 00 begane grond | 00 begane grond | Core Face: Exterior | 0 | 3.458 | 1235 | 0.03458
2432026 | 00 begane grond | 00 begane grond | Core Face: Exterior | 0 | 3.332 | 1190 | 0.03332
2432054 | 00 begane grond | 00 begane grond | Core Face: Exterior | 0 | 0.985712 | 1235 | 0.00985712
2433273 | 00 begane grond | 00 begane grond | Core Face: Exterior | 0 | 4.8314 | 1725.5 | 0.048314
2433274 | 00 begane grond | 00 begane grond | Core Face: Exterior | 0 | 2.884 | 1030 | 0.02884
2433275 | 00 begane grond | 00 begane grond | Core Face: Exterior | 0 | 4.8314 | 1725.5 | 0.048314
2433276 | 00 begane grond | 00 begane grond | Core Face: Exterior | 0 | 0.42539 | 1030 | 0.0042539
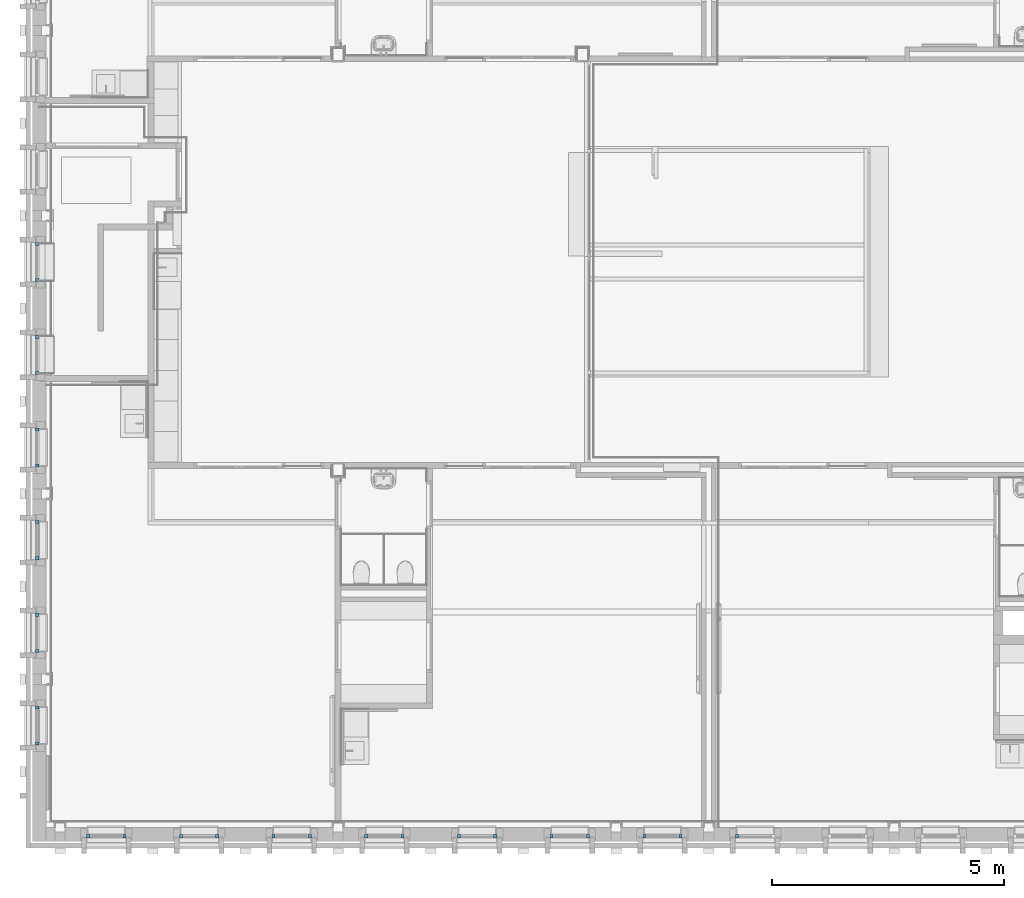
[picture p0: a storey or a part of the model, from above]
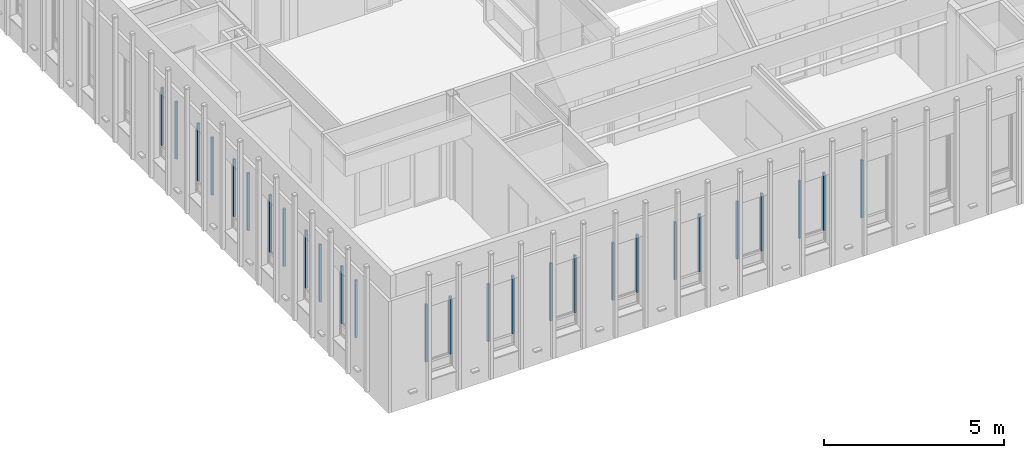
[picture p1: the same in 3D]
Properties of the parts of a building model (IFC2X3), part 87 of 94

# IfcWallStandardCase: Basic Wall:21_WA_tegelwerk 10 (155)
Name (Basic Wall:21_WA_tegelwerk 10:...) | In | Base Constraint | Location Line | Base Offset (mm) | Area (m2) | Length (mm) | Volume (m3)
2728735 | 00 begane grond | 00 begane grond | Core Face: Exterior | 0 | 0.3234 | 115.5 | 0.003234
2728766 | 00 begane grond | 00 begane grond | Core Face: Exterior | 0 | 0.252 | 100 | 0.00252
2779594 | 02 tweede verdieping | 02 tweede verdieping | Finish Face: Exterior | 0 | 0.2394 | 85.5 | 0.002394
2779630 | 02 tweede verdieping | 02 tweede verdieping | Finish Face: Exterior | 0 | 0.5264 | 198 | 0.005264
2779904 | 02 tweede verdieping | 02 tweede verdieping | Finish Face: Exterior | 0 | 0.5544 | 198 | 0.005544
2779927 | 02 tweede verdieping | 02 tweede verdieping | Finish Face: Exterior | 0 | 0.2114 | 85.5 | 0.002114
3534269 | 01 eerste verdieping | 01 eerste verdieping | Finish Face: Exterior | 0 | 0.2394 | 85.5 | 0.002394
3534305 | 01 eerste verdieping | 01 eerste verdieping | Finish Face: Exterior | 0 | 0.5264 | 198 | 0.005264
3535459 | 01 eerste verdieping | 01 eerste verdieping | Finish Face: Exterior | 100 | 0.5544 | 198 | 0.005544
3535486 | 01 eerste verdieping | 01 eerste verdieping | Finish Face: Exterior | 100 | 0.2114 | 85.5 | 0.002114
4193381 | 02 tweede verdieping | 02 tweede verdieping | Finish Face: Exterior | 0 | 3.4118 | 1228.5 | 0.034118
5057061 | 00 begane grond | 00 begane grond | Core Face: Exterior | 100 | 8.635 | 3325 | 0.08635

# IfcWallStandardCase: Basic Wall:22_WA_1xgips+multiplex 25 _gen_bdg, Basic Wall:22_WA_1xgips+multiplex 25 _gen_bdg:2998318
In: 00 begane grond
Type - PredefinedType: STANDARD; Material: f7_gipsvezel 13 mm, i4_multiplex 12 mm
Type - Analytical Properties - Roughness: 1; Absorptance: 0.1
Type - Graphics - Coarse Scale Fill Pattern: <Solid fill>; Coarse Scale Fill Color: 12632256
Type - Construction - Function: Interior; Wrapping at Inserts: Do not wrap; Width: 25 mm
Type - Identity Data - Workset: Wall Types; Assembly Code: 2E(22.11); Datum_Gewijzigd: 26-05-2014; Description: Binnenwand 100mm; Model: LOD300; SmartRevit_Versie: 2015.1; Type Name: 22_WA_1xgips+multiplex 25 _gen_bdg
Type - Other - Category: Walls; Family Name: Basic Wall
Classification: 2E(22.11) Uniformat (Uniformat)
Cross-Section Definition - Cross-Section: Vertical
Constraints - Base Extension Distance: 0 mm; Base is Attached: no; Related to Mass: no; Room Bounding: yes; Top Extension Distance: 0 mm; Top is Attached: no; Top Offset: 0 mm; Base Constraint: 00 begane grond; Top Constraint: Up to level: 01 ok. ruwe vloer; Base Offset: 0 mm; Location Line: Core Face: Exterior; Unconnected Height: 3630 mm
Phasing - Phase Created: 2. nieuwbouw
Structural - Enable Analytical Model: no; Structural: no; Structural Usage: Non-bearing
Dimensions - Area: 0.27951 m2; Length: 77 mm; Volume: 0.00698775 m3
Identity Data - Workset: Workset1
Other - Family: Basic Wall; Family and Type: Basic Wall: 22_WA_1xgips+multiplex 25 _gen_bdg; Type: 22_WA_1xgips+multiplex 25 _gen_bdg; Type Id: 2998390

# IfcWallStandardCase: Basic Wall:22_WA_2xgips 25 _gen_bdg (10)
Type - PredefinedType: STANDARD; Material: f7_gipsvezel 12.5 mm, f7_gips 12.5 mm
Type - Analytical Properties - Roughness: 1; Absorptance: 0.1
Type - Graphics - Coarse Scale Fill Pattern: <Solid fill>; Coarse Scale Fill Color: 12632256
Type - Construction - Function: Interior; Wrapping at Inserts: Do not wrap; Width: 25 mm
Type - Identity Data - Workset: Wall Types; Assembly Code: 2E(22.11); Datum_Gewijzigd: 26-05-2014; Description: Binnenwand 100mm; Model: LOD300; SmartRevit_Versie: 2015.1; Type Name: 22_WA_2xgips 25 _gen_bdg
Type - Other - Category: Walls; Family Name: Basic Wall
Classification: 2E(22.11) Uniformat (Uniformat)
Cross-Section Definition - Cross-Section: Vertical
Constraints - Base Extension Distance: 0 mm; Base is Attached: no; Related to Mass: no; Room Bounding: yes; Top Extension Distance: 0 mm; Top is Attached: no; Top Offset: 0 mm; Base Offset: 0 mm
Phasing - Phase Created: 2. nieuwbouw
Structural - Enable Analytical Model: no; Structural: no; Structural Usage: Non-bearing
Identity Data - Workset: Workset1
Other - Family: Basic Wall; Family and Type: Basic Wall: 22_WA_2xgips 25 _gen_bdg; Type: 22_WA_2xgips 25 _gen_bdg; Type Id: 2997573
Name (Basic Wall:22_WA_2xgips 25 _gen_bdg:...) | In | Base Constraint | Top Constraint | Location Line | Unconnected Height (mm) | Area (m2) | Length (mm) | Volume (m3)
4869562 | 01 eerste verdieping | 01 eerste verdieping | Up to level: 02 ok. ruwe vloer | Wall Centerline | 3430 | 0.87465 | 262.5 | 0.0218663
4869563 | 01 eerste verdieping | 01 eerste verdieping | Up to level: 02 ok. ruwe vloer | Wall Centerline | 3430 | 0.970639 | 282.985 | 0.024266
4869564 | 01 eerste verdieping | 01 eerste verdieping | Up to level: 02 ok. ruwe vloer | Wall Centerline | 3430 | 0.9261 | 283 | 0.0231525
4871610 | 01 eerste verdieping | 01 eerste verdieping | Up to level: 02 ok. ruwe vloer | Wall Centerline | 3430 | 0.9261 | 276.5 | 0.0231525
4871611 | 01 eerste verdieping | 01 eerste verdieping | Up to level: 02 ok. ruwe vloer | Wall Centerline | 3430 | 0.9261 | 270 | 0.0231525
4871612 | 01 eerste verdieping | 01 eerste verdieping | Up to level: 02 ok. ruwe vloer | Wall Centerline | 3430 | 0.9261 | 270 | 0.0231525
4874028 | 02 tweede verdieping | 02 tweede verdieping | Up to level: 03 ok. ruwe vloer | Wall Centerline | 3500 | 0.945 | 276.5 | 0.023625
4875320 | 02 tweede verdieping | 02 tweede verdieping | Up to level: 03 ok. ruwe vloer | Wall Centerline | 3500 | 0.9905 | 283 | 0.0247625
4875321 | 02 tweede verdieping | 02 tweede verdieping | Up to level: 03 ok. ruwe vloer | Wall Centerline | 3500 | 0.9541 | 283 | 0.0238525
4889904 | 02 tweede verdieping | 02 tweede verdieping | Up to level: 03 ok. ruwe vloer | Finish Face: Interior | 3500 | 0.945 | 276.5 | 0.023625

# IfcWallStandardCase: Basic Wall:22_WA_2xgips+rachels 25-20 _gen_bdg (25)
Type - PredefinedType: STANDARD; Material: f7_gipsvezel 12.5 mm, f7_gips 12.5 mm, ISR_Luchtspouw 20 mm
Type - Analytical Properties - Roughness: 1; Absorptance: 0.1
Type - Graphics - Coarse Scale Fill Pattern: <Solid fill>; Coarse Scale Fill Color: 12632256
Type - Construction - Function: Interior; Wrapping at Inserts: Do not wrap; Width: 45 mm
Type - Identity Data - Workset: Wall Types; Assembly Code: 2E(22.11); Datum_Gewijzigd: 26-05-2014; Description: Binnenwand 100mm; Model: LOD300; SmartRevit_Versie: 2015.1; Type Name: 22_WA_2xgips+rachels 25-20 _gen_bdg
Type - Other - Category: Walls; Family Name: Basic Wall
Classification: 2E(22.11) Uniformat (Uniformat)
Cross-Section Definition - Cross-Section: Vertical
Constraints - Base Extension Distance: 0 mm; Base is Attached: no; Related to Mass: no; Top Extension Distance: 0 mm; Top is Attached: no
Phasing - Phase Created: 2. nieuwbouw
Structural - Enable Analytical Model: no; Structural: no; Structural Usage: Non-bearing
Identity Data - Workset: Workset1
Other - Family: Basic Wall; Family and Type: Basic Wall: 22_WA_2xgips+rachels 25-20 _gen_bdg; Type: 22_WA_2xgips+rachels 25-20 _gen_bdg; Type Id: 2196055
Name (Basic Wall:22_WA_2xgips+rachels 25-20 _gen_bdg:...) | In | Room Bounding | Top Offset (mm) | Base Offset (mm) | Base Constraint | Location Line | Top Constraint | Unconnected Height (mm) | Area (m2) | Length (mm) | Volume (m3)
2195909 | 02 tweede verdieping | yes | 0 | 0 | 03 ok. ruwe vloer | Wall Centerline | Up to level: 03 bk. ruwe vloer | 250 | 0.453 | 1812 | 0.020385 | Group: Model Group:BU-42 daklicht B lokaal:2182308
2195968 | 02 tweede verdieping | yes | 0 | 0 | 03 ok. ruwe vloer | Wall Centerline | Up to level: 03 bk. ruwe vloer | 250 | 0.453 | 1812 | 0.020385 | Group: Model Group:BU-42 daklicht B lokaal:2182308
2196285 | 02 tweede verdieping | yes | 0 | 0 | 03 ok. ruwe vloer | Wall Centerline | Up to level: 03 bk. ruwe vloer | 250 | 0.453 | 1812 | 0.020385 | Group: Model Group:BU-42 daklicht B lokaal:2194782
2196395 | 02 tweede verdieping | yes | 0 | 0 | 03 ok. ruwe vloer | Wall Centerline | Up to level: 03 bk. ruwe vloer | 250 | 0.453 | 1812 | 0.020385 | Group: Model Group:BU-42 daklicht B lokaal:2194782
2749157 | 01 eerste verdieping | yes | 0 | 0 | 01 eerste verdieping | Finish Face: Interior | Up to level: 02 ok. ruwe vloer | 3430 | 0.83006 | 242 | 0.0373527
2897905 | 00 begane grond | yes | 0 | 3630 | 00 begane grond | Wall Centerline | Up to level: 01 bk. ruwe vloer | 320 | 0.6544 | 2117.5 | 0.029448
2898152 | 00 begane grond | no | 0 | 3370 | 00 begane grond | Wall Centerline | Up to level: 01 ok. ruwe vloer | 260 | 0.7475 | 2937.5 | 0.0336375
2898201 | 00 begane grond | no | 20 | 3630 | 00 begane grond | Wall Centerline | Up to level: 01 bk. ruwe vloer | 340 | 0.99875 | 2937.5 | 0.0449437
2899508 | 00 begane grond | no | 0 | 3540 | 01 ok. ruwe vloer | Core Face: Exterior | Up to level: 02 ok. ruwe vloer | 260 | 0.86346 | 3383.5 | 0.0388557
2968786 | 02 tweede verdieping | yes | 0 | 0 | 02 tweede verdieping | Core Face: Exterior | Up to level: 03 bk. ruwe vloer | 3750 | 0.868862 | 236.5 | 0.0347863
3459546 | 01 eerste verdieping | yes | 0 | 0 | 02 ok. ruwe vloer | Wall Centerline | Up to level: 02 tweede verdieping | 370 | 0.814 | 2200 | 0.03663
3459547 | 01 eerste verdieping | yes | 0 | 3200 | 01 eerste verdieping | Wall Centerline | Up to level: 02 tweede verdieping | 600 | 0.576 | 1085 | 0.02592
3459548 | 01 eerste verdieping | yes | 0 | 0 | 02 ok. ruwe vloer | Wall Centerline | Up to level: 02 tweede verdieping | 370 | 1.2099 | 3270 | 0.0544455
3459562 | 00 begane grond | yes | 0 | 0 | 01 ok. ruwe vloer | Wall Centerline | Up to level: 01 bk. ruwe vloer | 320 | 0.4704 | 1425 | 0.021168
3459563 | 00 begane grond | yes | 0 | 0 | 01 ok. ruwe vloer | Wall Centerline | Up to level: 01 eerste verdieping | 370 | 0.70037 | 1898.5 | 0.0315167
3459564 | 00 begane grond | yes | 0 | 0 | 01 ok. ruwe vloer | Wall Centerline | Up to level: 01 bk. ruwe vloer | 320 | 0.60032 | 1898.5 | 0.0270144
3459565 | 01 eerste verdieping | yes | 0 | 0 | 02 ok. ruwe vloer | Wall Centerline | Up to level: 02 tweede verdieping | 370 | 0.69412 | 1938.5 | 0.0312354
3459566 | 01 eerste verdieping | yes | 0 | 0 | 02 ok. ruwe vloer | Wall Centerline | Up to level: 02 tweede verdieping | 370 | 0.69412 | 1938.5 | 0.0312354
4347211 | 02 tweede verdieping | yes | 0 | 0 | 02 tweede verdieping | Core Face: Exterior | Up to level: 03 bk. ruwe vloer | 3750 | 0.43125 | 115 | 0.0194063
4347401 | 02 tweede verdieping | yes | 0 | 0 | 02 tweede verdieping | Core Face: Exterior | Up to level: 03 bk. ruwe vloer | 3750 | 0.43125 | 115 | 0.0194063
4347630 | 02 tweede verdieping | yes | 0 | 0 | 02 tweede verdieping | Core Face: Exterior | Up to level: 03 bk. ruwe vloer | 3750 | 0.43125 | 115 | 0.0194063
4347631 | 02 tweede verdieping | yes | 0 | 0 | 02 tweede verdieping | Core Face: Exterior | Up to level: 03 bk. ruwe vloer | 3750 | 0.43125 | 115 | 0.0194063
4735120 | 00 begane grond | yes | 0 | 0 | 01 ok. ruwe vloer | Wall Centerline | Up to level: 01 eerste verdieping | 370 | 0.928888 | 2510.51 | 0.0418
4735268 | 00 begane grond | yes | 0 | -260 | 01 ok. ruwe vloer | Wall Centerline | Up to level: 01 eerste verdieping | 630 | 0.6048 | 1045 | 0.027216
4736673 | 01 eerste verdieping | yes | -260 | 3200 | 01 eerste verdieping | Wall Centerline | Up to level: 02 tweede verdieping | 340 | 0.3264 | 1072.5 | 0.014688

# IfcWallStandardCase: Basic Wall:22_WA_binnenwand_ms100 25-50-25 _gen_bdg (2)
In: 00 begane grond
Type - PredefinedType: STANDARD; Material: f7_gipsvezel 12.5 mm, f7_gips 12.5 mm, n7_isolatie_glaswol 50 mm, f7_gips 12.5 mm, f7_gipsvezel 12.5 mm
Type - Analytical Properties - Roughness: 1; Absorptance: 0.1
Type - Materials and Finishes - Structural Material: f7_gipsvezel
Type - Graphics - Coarse Scale Fill Pattern: <Solid fill>; Coarse Scale Fill Color: 12632256
Type - Construction - Function: Interior; Wrapping at Inserts: Do not wrap; Wrapping at Ends: Exterior; Width: 100 mm
Type - Identity Data - Workset: Wall Types; Assembly Code: 2E(22.11); Datum_Gewijzigd: 26-05-2014; Description: Binnenwand 100mm; Model: LOD300; SmartRevit_Versie: 2015.1; Type Name: 22_WA_binnenwand_ms100 25-50-25 _gen_bdg
Type - Other - Category: Walls; Family Name: Basic Wall
Classification: 2E(22.11) Uniformat (Uniformat)
Cross-Section Definition - Cross-Section: Vertical
Constraints - Base Extension Distance: 0 mm; Base is Attached: no; Related to Mass: no; Room Bounding: yes; Top Extension Distance: 0 mm; Top is Attached: no; Base Constraint: 00 begane grond; Top Constraint: Up to level: 01 ok. ruwe vloer; Base Offset: 0 mm; Location Line: Core Face: Exterior; Top Offset: -60 mm; Unconnected Height: 3570 mm
Phasing - Phase Created: 2. nieuwbouw
Structural - Enable Analytical Model: no; Structural: no; Structural Usage: Non-bearing
Identity Data - Workset: Workset1
Other - Family: Basic Wall; Family and Type: Basic Wall: 22_WA_binnenwand_ms100 25-50-25 _gen_bdg; Type: 22_WA_binnenwand_ms100 25-50-25 _gen_bdg; Type Id: 2720761
Name (Basic Wall:22_WA_binnenwand_ms100 25-50-25 _gen_bdg:...) | Area (m2) | Length (mm) | Volume (m3)
2720548 | 2.3205 | 650 | 0.229961
2720903 | 1.87425 | 587.5 | 0.187425

# IfcWallStandardCase: Basic Wall:22_WA_binnenwand_ms100 25-75 _gen_bdg (14)
Type - PredefinedType: STANDARD; Material: n7_isolatie_glaswol 75 mm, f7_gips 12.5 mm, f7_gipsvezel 12.5 mm
Type - Analytical Properties - Roughness: 1; Absorptance: 0.1
Type - Materials and Finishes - Structural Material: f7_gipsvezel
Type - Graphics - Coarse Scale Fill Pattern: <Solid fill>; Coarse Scale Fill Color: 12632256
Type - Construction - Function: Interior; Wrapping at Inserts: Do not wrap; Wrapping at Ends: Exterior; Width: 100 mm
Type - Identity Data - Workset: Wall Types; Assembly Code: 2E(22.11); Datum_Gewijzigd: 26-05-2014; Description: Binnenwand 100mm; Model: LOD300; SmartRevit_Versie: 2015.1; Type Name: 22_WA_binnenwand_ms100 25-75 _gen_bdg
Type - Other - Category: Walls; Family Name: Basic Wall
Classification: 2E(22.11) Uniformat (Uniformat)
Cross-Section Definition - Cross-Section: Vertical
Constraints - Base Extension Distance: 0 mm; Base is Attached: no; Related to Mass: no; Room Bounding: yes; Top Extension Distance: 0 mm; Top is Attached: no
Phasing - Phase Created: 2. nieuwbouw
Structural - Enable Analytical Model: no; Structural: no; Structural Usage: Non-bearing
Identity Data - Workset: Workset1
Other - Family: Basic Wall; Family and Type: Basic Wall: 22_WA_binnenwand_ms100 25-75 _gen_bdg; Type: 22_WA_binnenwand_ms100 25-75 _gen_bdg; Type Id: 3168910
Name (Basic Wall:22_WA_binnenwand_ms100 25-75 _gen_bdg:...) | In | Base Constraint | Top Constraint | Top Offset (mm) | Base Offset (mm) | Location Line | Unconnected Height (mm) | Area (m2) | Length (mm) | Volume (m3)
1724266 | 01 eerste verdieping | 01 eerste verdieping | Up to level: 02 ok. ruwe vloer | 0 | 0 | Wall Centerline | 3430 | 6.34738 | 2132.5 | 0.634738
2475909 | 02 tweede verdieping | 02 tweede verdieping | Up to level: 03 ok. ruwe vloer | 0 | 0 | Core Face: Interior | 3500 | 3.682 | 1164.5 | 0.3682
3168637 | 00 begane grond | 00 begane grond | Up to level: 01 ok. ruwe vloer | -60 | 0 | Wall Centerline | 3570 | 0.258825 | 72.5 | 0.0258825
4493357 | 01 eerste verdieping | 01 eerste verdieping | Up to level: 02 ok. ruwe vloer | 0 | 0 | Wall Centerline | 3430 | 0.7546 | 220 | 0.07546
4869404 | 01 eerste verdieping | 01 eerste verdieping | Up to level: 02 ok. ruwe vloer | 0 | 0 | Wall Centerline | 3430 | 1.0976 | 220 | 0.10976
4869468 | 01 eerste verdieping | 01 eerste verdieping | Up to level: 02 ok. ruwe vloer | 0 | -50 | Wall Centerline | 3480 | 0.9396 | 220 | 0.09396
4869524 | 01 eerste verdieping | 01 eerste verdieping | Up to level: 02 ok. ruwe vloer | 0 | 0 | Wall Centerline | 3430 | 1.0976 | 220 | 0.10976
4874444 | 02 tweede verdieping | 02 tweede verdieping | Up to level: 03 ok. ruwe vloer | 0 | 0 | Wall Centerline | 3500 | 10.0625 | 2924 | 1.00625
4874893 | 02 tweede verdieping | 02 tweede verdieping | Up to level: 03 ok. ruwe vloer | 0 | 0 | Wall Centerline | 3500 | 0.77 | 220 | 0.077
4875018 | 02 tweede verdieping | 02 tweede verdieping | Up to level: 03 ok. ruwe vloer | 0 | 0 | Wall Centerline | 3500 | 1.085 | 210 | 0.1085
4879738 | 00 begane grond | 00 begane grond | Up to level: 01 ok. ruwe vloer | 0 | 0 | Wall Centerline | 3630 | 3.3396 | 1072.5 | 0.33396
5081102 | 01 eerste verdieping | 01 eerste verdieping | Up to level: 02 ok. ruwe vloer | -580 | 0 | Wall Centerline | 2850 | 0.74955 | 163 | 0.0639799
5081103 | 01 eerste verdieping | 01 eerste verdieping | Up to level: 02 ok. ruwe vloer | -630 | 0 | Wall Centerline | 2800 | 0.3836 | 337 | 0.0238133
5081247 | 01 eerste verdieping | 01 eerste verdieping | Up to level: 02 ok. ruwe vloer | -577 | 0 | Wall Centerline | 2853 | 0.390861 | 337 | 0.0205242

# IfcWallStandardCase: Basic Wall:22_WA_binnenwand_ms125 25-75-25 _Rigitone_gen_bdg 2 (2)
Type - PredefinedType: STANDARD; Material: f7_gipsvezel 12.5 mm, f7_gips 12.5 mm, n7_isolatie_glaswol 75 mm, f7_gips 12.5 mm, f7_gips_rigitone_gyproc 8/18 12.5 mm
Type - Analytical Properties - Roughness: 1; Absorptance: 0.1
Type - Materials and Finishes - Structural Material: f7_gips_rigitone_gyproc 8/18
Type - Graphics - Coarse Scale Fill Pattern: <Solid fill>; Coarse Scale Fill Color: 12632256
Type - Construction - Function: Interior; Wrapping at Inserts: Do not wrap; Wrapping at Ends: Exterior; Width: 125 mm
Type - Identity Data - Workset: Wall Types; Assembly Code: 2E(22.11); Datum_Gewijzigd: 26-05-2014; Description: Binnenwand 100mm; Model: LOD300; SmartRevit_Versie: 2015.1; Type Name: 22_WA_binnenwand_ms125 25-75-25 _Rigitone_gen_bdg 2
Type - Other - Category: Walls; Family Name: Basic Wall
Classification: 2E(22.11) Uniformat (Uniformat)
Cross-Section Definition - Cross-Section: Vertical
Constraints - Base Extension Distance: 0 mm; Base is Attached: no; Related to Mass: no; Room Bounding: yes; Top Extension Distance: 0 mm; Top is Attached: no; Location Line: Wall Centerline; Top Offset: 1050 mm
Phasing - Phase Created: 2. nieuwbouw
Structural - Enable Analytical Model: no; Structural: no; Structural Usage: Non-bearing
Identity Data - Workset: Workset1
Other - Family: Basic Wall; Family and Type: Basic Wall: 22_WA_binnenwand_ms125 25-75-25 _Rigitone_gen_bdg 2; Type: 22_WA_binnenwand_ms125 25-75-25 _Rigitone_gen_bdg 2; Type Id: 3271032
Name (Basic Wall:22_WA_binnenwand_ms125 25-75-25 _Rigitone_gen_bdg 2:...) | In | Top Constraint | Base Constraint | Base Offset (mm) | Unconnected Height (mm) | Area (m2) | Length (mm) | Volume (m3)
2088718 | 00 begane grond | Up to level: 02 tweede verdieping | 01 ok. ruwe vloer | -230 | 5450 | 6.59879 | 5147.43 | 0.824849
3271112 | 01 eerste verdieping | Up to level: 01 eerste verdieping | 01 eerste verdieping | 0 | 1050 | 8.13712 | 7812.14 | 1.01714

# IfcWallStandardCase: Basic Wall:22_WA_binnenwand_ms125 25-75-25 _gen_bdg (165)
Type - PredefinedType: STANDARD; Material: f7_gipsvezel 12.5 mm, f7_gips 12.5 mm, n7_isolatie_glaswol 75 mm, f7_gips 12.5 mm, f7_gipsvezel 12.5 mm
Type - Analytical Properties - Roughness: 1; Absorptance: 0.1
Type - Materials and Finishes - Structural Material: f7_gipsvezel
Type - Graphics - Coarse Scale Fill Pattern: <Solid fill>; Coarse Scale Fill Color: 12632256
Type - Construction - Function: Interior; Wrapping at Inserts: Do not wrap; Width: 125 mm; Wrapping at Ends: Exterior
Type - Identity Data - Workset: Wall Types; Assembly Code: 2E(22.11); Datum_Gewijzigd: 26-05-2014; Description: Binnenwand 100mm; Model: LOD300; SmartRevit_Versie: 2015.1; Type Name: 22_WA_binnenwand_ms125 25-75-25 _gen_bdg
Type - Other - Category: Walls; Family Name: Basic Wall
Classification: 2E(22.11) Uniformat (Uniformat)
Cross-Section Definition - Cross-Section: Vertical
Constraints - Base Extension Distance: 0 mm; Base is Attached: no; Related to Mass: no; Top Extension Distance: 0 mm; Top is Attached: no
Phasing - Phase Created: 2. nieuwbouw
Structural - Enable Analytical Model: no; Structural: no; Structural Usage: Non-bearing
Identity Data - Workset: Workset1
Other - Family: Basic Wall; Family and Type: Basic Wall: 22_WA_binnenwand_ms125 25-75-25 _gen_bdg; Type: 22_WA_binnenwand_ms125 25-75-25 _gen_bdg; Type Id: 875572
Name (Basic Wall:22_WA_binnenwand_ms125 25-75-25 _gen_bdg:...) | In | Base Constraint | Room Bounding | Top Constraint | Top Offset (mm) | Base Offset (mm) | Location Line | Unconnected Height (mm) | Area (m2) | Length (mm) | Volume (m3)
875891 | 02 tweede verdieping | 02 tweede verdieping | yes | Up to level: 03 ok. ruwe vloer | 0 | 0 | Wall Centerline | 3500 | 6.9125 | 1975 | 0.864063
875971 | 02 tweede verdieping | 02 tweede verdieping | yes | Up to level: 03 ok. ruwe vloer | 0 | 0 | Wall Centerline | 3500 | 12.535 | 5185 | 1.56687
882212 | 02 tweede verdieping | 02 tweede verdieping | yes | Up to level: 03 ok. ruwe vloer | 0 | 0 | Wall Centerline | 3500 | 7.20345 | 3896 | 0.900431
882584 | 02 tweede verdieping | 02 tweede verdieping | yes | Up to level: 03 ok. ruwe vloer | 0 | 0 | Wall Centerline | 3500 | 4.42225 | 1251 | 0.552781
882646 | 02 tweede verdieping | 02 tweede verdieping | yes | Up to level: 03 ok. ruwe vloer | 0 | 0 | Wall Centerline | 3500 | 4.06214 | 2099 | 0.507768
883212 | 02 tweede verdieping | 02 tweede verdieping | yes | Up to level: 03 ok. ruwe vloer | 0 | 0 | Wall Centerline | 3500 | 17.57 | 5145 | 2.19625
883342 | 02 tweede verdieping | 02 tweede verdieping | yes | Up to level: 03 ok. ruwe vloer | 0 | 0 | Wall Centerline | 3500 | 7.29095 | 3908.5 | 0.911368
883587 | 02 tweede verdieping | 02 tweede verdieping | yes | Up to level: 03 ok. ruwe vloer | 0 | 0 | Wall Centerline | 3500 | 12.4791 | 5031.52 | 1.55988
883627 | 02 tweede verdieping | 02 tweede verdieping | yes | Up to level: 03 ok. ruwe vloer | 0 | 0 | Wall Centerline | 3500 | 4.13 | 1305 | 0.51625
884331 | 02 tweede verdieping | 02 tweede verdieping | yes | Up to level: 03 ok. ruwe vloer | 0 | 0 | Wall Centerline | 3500 | 20.9525 | 7465 | 2.61906
884440 | 02 tweede verdieping | 02 tweede verdieping | yes | Up to level: 03 ok. ruwe vloer | 0 | 0 | Wall Centerline | 3500 | 6.9125 | 1975 | 0.864063
884509 | 02 tweede verdieping | 02 tweede verdieping | yes | Up to level: 03 ok. ruwe vloer | 0 | 0 | Wall Centerline | 3500 | 12.535 | 5185 | 1.56687
885121 | 02 tweede verdieping | 02 tweede verdieping | yes | Up to level: 03 ok. ruwe vloer | 0 | 0 | Wall Centerline | 3500 | 7.72925 | 2412.5 | 0.966156
885407 | 02 tweede verdieping | 02 tweede verdieping | yes | Up to level: 03 ok. ruwe vloer | 0 | 0 | Wall Centerline | 3500 | 4.83 | 1545 | 0.60375
885964 | 01 eerste verdieping | 01 eerste verdieping | yes | Up to level: 02 ok. ruwe vloer | 0 | 0 | Wall Centerline | 3430 | 6.9259 | 3902.5 | 0.865737
886054 | 01 eerste verdieping | 01 eerste verdieping | yes | Up to level: 02 ok. ruwe vloer | 0 | 0 | Wall Centerline | 3430 | 2.9498 | 1025 | 0.368725
886458 | 01 eerste verdieping | 01 eerste verdieping | yes | Up to level: 02 ok. ruwe vloer | 0 | 0 | Wall Centerline | 3430 | 10.6502 | 2980 | 1.33127
886882 | 01 eerste verdieping | 01 eerste verdieping | yes | Up to level: 02 ok. ruwe vloer | 0 | 0 | Wall Centerline | 3430 | 6.77425 | 1975 | 0.846781
887006 | 01 eerste verdieping | 01 eerste verdieping | yes | Up to level: 02 ok. ruwe vloer | 0 | 0 | Wall Centerline | 3430 | 12.1808 | 5185 | 1.5226
887215 | 01 eerste verdieping | 01 eerste verdieping | yes | Up to level: 02 ok. ruwe vloer | 0 | 0 | Wall Centerline | 3430 | 19.3486 | 5653.5 | 2.41858
887320 | 01 eerste verdieping | 01 eerste verdieping | yes | Up to level: 02 ok. ruwe vloer | 0 | 0 | Wall Centerline | 3430 | 6.5486 | 3922.5 | 0.818575
887788 | 01 eerste verdieping | 01 eerste verdieping | yes | Up to level: 02 ok. ruwe vloer | 370 | -50 | Wall Centerline | 3850 | 5.3463 | 1505 | 0.668287
887921 | 01 eerste verdieping | 01 eerste verdieping | yes | Up to level: 02 ok. ruwe vloer | 0 | 0 | Wall Centerline | 3430 | 10.754 | 4631.52 | 1.34425
887961 | 01 eerste verdieping | 01 eerste verdieping | yes | Up to level: 02 ok. ruwe vloer | 0 | 0 | Wall Centerline | 3430 | 5.2822 | 1665 | 0.660275
888085 | 01 eerste verdieping | 01 eerste verdieping | yes | Up to level: 02 ok. ruwe vloer | 0 | 0 | Wall Centerline | 3430 | 15.675 | 4822.48 | 1.95938
888279 | 01 eerste verdieping | 01 eerste verdieping | yes | Up to level: 02 ok. ruwe vloer | 0 | 0 | Wall Centerline | 3430 | 9.53547 | 2932.52 | 1.19193
888483 | 01 eerste verdieping | 01 eerste verdieping | yes | Up to level: 02 ok. ruwe vloer | 0 | 0 | Wall Centerline | 3430 | 12.6095 | 5185 | 1.57619
888524 | 01 eerste verdieping | 01 eerste verdieping | yes | Up to level: 02 ok. ruwe vloer | 0 | 0 | Wall Centerline | 3430 | 6.34551 | 1975 | 0.793189
889178 | 01 eerste verdieping | 01 eerste verdieping | yes | Up to level: 02 ok. ruwe vloer | 0 | 0 | Wall Centerline | 3430 | 9.61005 | 3995 | 1.20126
889217 | 01 eerste verdieping | 01 eerste verdieping | yes | Up to level: 02 ok. ruwe vloer | 0 | 0 | Wall Centerline | 3430 | 30.5788 | 15325 | 3.82235
889497 | 01 eerste verdieping | 01 eerste verdieping | yes | Up to level: 02 ok. ruwe vloer | 0 | 0 | Wall Centerline | 3430 | 9.24385 | 2780 | 1.15548
889731 | 01 eerste verdieping | 01 eerste verdieping | yes | Up to level: 02 ok. ruwe vloer | 0 | 0 | Wall Centerline | 3430 | 7.546 | 2262.5 | 0.93575
889824 | 01 eerste verdieping | 01 eerste verdieping | yes | Up to level: 02 ok. ruwe vloer | 0 | 0 | Wall Centerline | 3430 | 7.546 | 2262.5 | 0.94325
890481 | 02 tweede verdieping | 02 tweede verdieping | yes | Up to level: 03 ok. ruwe vloer | 0 | 0 | Wall Centerline | 3500 | 5.25038 | 3012.5 | 0.656297
890574 | 02 tweede verdieping | 02 tweede verdieping | yes | Up to level: 03 ok. ruwe vloer | 0 | 0 | Wall Centerline | 3500 | 8.16675 | 2412.5 | 1.02084
895261 | 02 tweede verdieping | 02 tweede verdieping | yes | Up to level: 03 ok. ruwe vloer | 0 | -50 | Wall Centerline | 3550 | 6.4875 | 8650 | 0.810938
896080 | 01 eerste verdieping | 01 eerste verdieping | yes | Up to level: 02 ok. ruwe vloer | 0 | 0 | Wall Centerline | 3430 | 8.34267 | 3488 | 1.04283
1208615 | 01 eerste verdieping | 01 eerste verdieping | yes | Up to level: 02 ok. ruwe vloer | 0 | 0 | Wall Centerline | 3430 | 10.4057 | 8650 | 1.30071
1218256 | 00 begane grond | 00 begane grond | yes | Up to level: 01 ok. ruwe vloer | 0 | 0 | Wall Centerline | 3630 | 11.1988 | 3812.5 | 1.39985
1218258 | 00 begane grond | 00 begane grond | yes | Up to level: 01 ok. ruwe vloer | 0 | 0 | Wall Centerline | 3630 | 17.1704 | 6177.5 | 2.1463
1218259 | 00 begane grond | 00 begane grond | yes | Up to level: 01 ok. ruwe vloer | 0 | 0 | Wall Centerline | 3630 | 16.4439 | 4530 | 2.05549
1218260 | 00 begane grond | 00 begane grond | yes | Up to level: 01 ok. ruwe vloer | 0 | 0 | Wall Centerline | 3630 | 16.7166 | 6177.5 | 2.08958
1218263 | 00 begane grond | 00 begane grond | yes | Up to level: 01 ok. ruwe vloer | 0 | 0 | Wall Centerline | 3630 | 8.4216 | 2445 | 1.0527
1218264 | 00 begane grond | 00 begane grond | yes | Up to level: 01 ok. ruwe vloer | 0 | 0 | Wall Centerline | 3630 | 54.8924 | 21772.5 | 6.86154
1218267 | 00 begane grond | 00 begane grond | yes | Up to level: 01 ok. ruwe vloer | 0 | 0 | Wall Centerline | 3630 | 5.16639 | 2807.5 | 0.645799
1218268 | 00 begane grond | 00 begane grond | yes | Up to level: 01 ok. ruwe vloer | 0 | 0 | Wall Centerline | 3630 | 29.5855 | 14010.5 | 3.69819
1218269 | 00 begane grond | 00 begane grond | yes | Up to level: 01 ok. ruwe vloer | -60 | 0 | Wall Centerline | 3570 | 3.69009 | 1850 | 0.461262
1218271 | 00 begane grond | 00 begane grond | yes | Up to level: 01 ok. ruwe vloer | -60 | 0 | Wall Centerline | 3570 | 6.90099 | 2990 | 0.862624
1218272 | 00 begane grond | 00 begane grond | yes | Up to level: 01 ok. ruwe vloer | -60 | 0 | Wall Centerline | 3570 | 12.3121 | 6402.5 | 1.53901
1218273 | 00 begane grond | 00 begane grond | yes | Up to level: 01 ok. ruwe vloer | -60 | 0 | Wall Centerline | 3570 | 11.8702 | 3450 | 1.48378
1218274 | 00 begane grond | 00 begane grond | yes | Up to level: 01 ok. ruwe vloer | -60 | 0 | Wall Centerline | 3570 | 14.3644 | 4097.5 | 1.79556
1218275 | 00 begane grond | 00 begane grond | yes | Up to level: 01 ok. ruwe vloer | -60 | 0 | Wall Centerline | 3570 | 14.0762 | 5380 | 1.75953
1218276 | 00 begane grond | 00 begane grond | yes | Up to level: 01 ok. ruwe vloer | -60 | 0 | Wall Centerline | 3570 | 7.05075 | 1975 | 0.881343
1218277 | 00 begane grond | 00 begane grond | yes | Up to level: 01 ok. ruwe vloer | -60 | 0 | Wall Centerline | 3570 | 13.63 | 5380 | 1.70374
1218279 | 00 begane grond | 00 begane grond | yes | Up to level: 01 ok. ruwe vloer | -60 | 0 | Wall Centerline | 3570 | 4.80165 | 1345 | 0.600206
1218280 | 00 begane grond | 00 begane grond | yes | Up to level: 01 ok. ruwe vloer | -60 | 0 | Wall Centerline | 3570 | 2.142 | 600 | 0.26775
1218281 | 00 begane grond | 00 begane grond | yes | Up to level: 01 ok. ruwe vloer | -60 | 0 | Wall Centerline | 3570 | 4.39815 | 1432.5 | 0.549769
1218283 | 00 begane grond | 00 begane grond | yes | Up to level: 01 ok. ruwe vloer | 0 | 0 | Wall Centerline | 3630 | 13.8485 | 3980 | 1.73106
1218284 | 00 begane grond | 00 begane grond | yes | Up to level: 01 ok. ruwe vloer | 0 | 0 | Wall Centerline | 3630 | 12.9596 | 4765 | 1.61995
1218285 | 00 begane grond | 00 begane grond | yes | Up to level: 01 ok. ruwe vloer | 0 | 0 | Wall Centerline | 3630 | 11.5253 | 3287.5 | 1.44066
1218289 | 00 begane grond | 00 begane grond | yes | Up to level: 01 ok. ruwe vloer | 0 | 0 | Wall Centerline | 3630 | 12.7567 | 3712.5 | 1.59459
1218290 | 00 begane grond | 00 begane grond | yes | Up to level: 01 ok. ruwe vloer | 0 | 0 | Wall Centerline | 3630 | 12.7567 | 3712.5 | 1.59459
1218292 | 00 begane grond | 00 begane grond | yes | Up to level: 01 ok. ruwe vloer | 0 | 0 | Wall Centerline | 3630 | 1.3989 | 1215.31 | 0.174863
1218293 | 00 begane grond | 00 begane grond | yes | Up to level: 01 ok. ruwe vloer | 0 | 0 | Wall Centerline | 3630 | 27.0285 | 7373.55 | 3.37497
1218294 | 00 begane grond | 00 begane grond | yes | Up to level: 01 ok. ruwe vloer | 0 | 0 | Wall Centerline | 3630 | 6.90693 | 4031.18 | 0.856295
1218295 | 00 begane grond | 00 begane grond | yes | Up to level: 01 ok. ruwe vloer | 0 | 0 | Wall Centerline | 3630 | 11.2167 | 3215 | 1.40209
1218296 | 00 begane grond | 00 begane grond | yes | Up to level: 01 ok. ruwe vloer | 0 | 0 | Wall Centerline | 3630 | 6.1888 | 3669.64 | 0.766529
1218297 | 00 begane grond | 00 begane grond | yes | Up to level: 01 ok. ruwe vloer | 0 | 0 | Wall Centerline | 3630 | 10.9156 | 3118.38 | 1.35738
1218299 | 00 begane grond | 00 begane grond | yes | Up to level: 01 ok. ruwe vloer | 0 | 0 | Wall Centerline | 3630 | 10.0966 | 2767.77 | 1.25501
1218300 | 00 begane grond | 00 begane grond | yes | Up to level: 01 eerste verdieping | 0 | 0 | Wall Centerline | 4000 | 10.2672 | 3002.5 | 1.2834
1218301 | 00 begane grond | 00 begane grond | yes | Up to level: 01 ok. ruwe vloer | 0 | 0 | Wall Centerline | 3630 | 3.5574 | 1042.5 | 0.444675
1218303 | 00 begane grond | 00 begane grond | yes | Up to level: 01 ok. ruwe vloer | 0 | 0 | Wall Centerline | 3630 | 11.1988 | 3812.5 | 1.39985
1218306 | 00 begane grond | 00 begane grond | yes | Up to level: 01 ok. ruwe vloer | 0 | 0 | Wall Centerline | 3630 | 27.3268 | 8287.5 | 3.39638
1218307 | 00 begane grond | 00 begane grond | yes | Up to level: 01 ok. ruwe vloer | -60 | 0 | Wall Centerline | 3570 | 37.9669 | 14727.5 | 4.74586
1219460 | 00 begane grond | 00 begane grond | yes | Up to level: 01 ok. ruwe vloer | 0 | 0 | Wall Centerline | 3630 | 3.29373 | 1782.5 | 0.411717
1225369 | 00 begane grond | 00 begane grond | yes | Up to level: 01 ok. ruwe vloer | -60 | 0 | Wall Centerline | 3570 | 14.0762 | 5380 | 1.75953
1225370 | 00 begane grond | 00 begane grond | yes | Up to level: 01 ok. ruwe vloer | -60 | 0 | Wall Centerline | 3570 | 7.05075 | 1975 | 0.881343
1225371 | 00 begane grond | 00 begane grond | yes | Up to level: 01 ok. ruwe vloer | -60 | 0 | Wall Centerline | 3570 | 13.63 | 5380 | 1.70374
1225373 | 00 begane grond | 00 begane grond | yes | Up to level: 01 ok. ruwe vloer | -60 | 0 | Wall Centerline | 3570 | 4.80165 | 1345 | 0.600206
1225374 | 00 begane grond | 00 begane grond | yes | Up to level: 01 ok. ruwe vloer | -60 | 0 | Wall Centerline | 3570 | 2.142 | 600 | 0.26775
1225375 | 00 begane grond | 00 begane grond | yes | Up to level: 01 ok. ruwe vloer | -60 | 0 | Wall Centerline | 3570 | 4.39815 | 1432.5 | 0.549769
1283160 | 02 tweede verdieping | 02 tweede verdieping | yes | Up to level: 02 tweede verdieping | 1050 | 0 | Finish Face: Exterior | 1050 | 0.651525 | 620.5 | 0.0814406
1330329 | 01 eerste verdieping | 01 eerste verdieping | yes | Up to level: 02 ok. ruwe vloer | 0 | 0 | Wall Centerline | 3430 | 1.13334 | 1175 | 0.141668
1336886 | 00 begane grond | 00 begane grond | yes | Up to level: 01 ok. ruwe vloer | 0 | 0 | Wall Centerline | 3630 | 3.43059 | 1790 | 0.428824
1337641 | 00 begane grond | 00 begane grond | yes | Up to level: 01 ok. ruwe vloer | 0 | 0 | Wall Centerline | 3630 | 23.2025 | 9420 | 2.90031
1359936 | 01 eerste verdieping | 01 eerste verdieping | yes | Up to level: 02 ok. ruwe vloer | 0 | 0 | Wall Centerline | 3430 | 20.3785 | 7450 | 2.54731
1360041 | 01 eerste verdieping | 01 eerste verdieping | yes | Up to level: 02 ok. ruwe vloer | 0 | 0 | Wall Centerline | 3430 | 20.3785 | 7450 | 2.54731
1360460 | 02 tweede verdieping | 02 tweede verdieping | yes | Up to level: 03 ok. ruwe vloer | 0 | 0 | Wall Centerline | 3500 | 20.8545 | 7437 | 2.60681
1421525 | 00 begane grond | 00 begane grond | yes | Up to level: 01 ok. ruwe vloer | 0 | 0 | Wall Centerline | 3630 | 3.49845 | 4427.5 | 0.437306
1421687 | 00 begane grond | 00 begane grond | yes | Up to level: 01 ok. ruwe vloer | 0 | 0 | Wall Centerline | 3630 | 10.4218 | 3562.5 | 1.30272
1516281 | 02 tweede verdieping | 02 tweede verdieping | yes | Up to level: 03 ok. ruwe vloer | 0 | 0 | Wall Centerline | 3500 | 2.18109 | 1532.5 | 0.272637
1516439 | 02 tweede verdieping | 02 tweede verdieping | yes | Up to level: 03 ok. ruwe vloer | 0 | 0 | Wall Centerline | 3500 | 1.55109 | 1392.5 | 0.193887
1615334 | 00 begane grond | 00 begane grond | yes | Up to level: 01 ok. ruwe vloer | 0 | 0 | Wall Centerline | 3630 | 2.33481 | 1810 | 0.291851
1615365 | 00 begane grond | 00 begane grond | yes | Up to level: 01 ok. ruwe vloer | 0 | 0 | Wall Centerline | 3630 | 2.73937 | 2200 | 0.342422
1621197 | 00 begane grond | 00 begane grond | no | Up to level: 01 ok. ruwe vloer | 0 | 0 | Wall Centerline | 3630 | 10.9479 | 4005 | 1.36849
1637240 | 01 eerste verdieping | 01 eerste verdieping | yes | Up to level: 01 eerste verdieping | 1050 | 0 | Wall Centerline | 1050 | 3.00915 | 2865.86 | 0.376144
1638627 | 00 begane grond | 01 ok. ruwe vloer | yes | Up to level: 02 tweede verdieping | 1050 | -230 | Finish Face: Interior | 5450 | 8.51597 | 5228.16 | 1.0645
1664132 | 00 begane grond | 00 begane grond | no | Up to level: 01 ok. ruwe vloer | 0 | 0 | Wall Centerline | 3630 | 2.487 | 2937.5 | 0.310875
1724474 | 02 tweede verdieping | 02 tweede verdieping | yes | Up to level: 02 tweede verdieping | 1050 | 0 | Wall Centerline | 1050 | 2.75625 | 2562.5 | 0.344531
1724689 | 02 tweede verdieping | 02 tweede verdieping | yes | Up to level: 02 tweede verdieping | 1050 | 0 | Wall Centerline | 1050 | 0.9807 | 3025 | 0.122588
1724765 | 02 tweede verdieping | 02 tweede verdieping | yes | Up to level: 02 tweede verdieping | 1050 | 0 | Wall Centerline | 1050 | 2.75919 | 2565.3 | 0.344899
1729892 | 01 eerste verdieping | 01 eerste verdieping | yes | Up to level: 01 eerste verdieping | 1050 | 0 | Wall Centerline | 1050 | 3.00825 | 2865 | 0.376031
1730876 | 01 eerste verdieping | 01 eerste verdieping | yes | Up to level: 02 ok. ruwe vloer | 0 | 0 | Wall Centerline | 3430 | 4.80445 | 2802.5 | 0.600556
1773396 | 01 eerste verdieping | 01 eerste verdieping | yes | Up to level: 02 tweede verdieping | 0 | 0 | Wall Centerline | 3800 | 8.76658 | 2465 | 1.09582
1774118 | 02 tweede verdieping | 02 tweede verdieping | yes | Up to level: 03 ok. ruwe vloer | 0 | 0 | Wall Centerline | 3500 | 8.085 | 2247.5 | 1.01063
1774160 | 02 tweede verdieping | 02 tweede verdieping | yes | Up to level: 03 ok. ruwe vloer | 0 | 0 | Wall Centerline | 3500 | 5.1975 | 1485 | 0.649688
2001891 | 01 eerste verdieping | 01 eerste verdieping | yes | Up to level: 02 ok. ruwe vloer | 0 | 0 | Wall Centerline | 3430 | 13.8575 | 4237.5 | 1.73219
2073717 | 01 eerste verdieping | 01 eerste verdieping | yes | Up to level: 02 ok. ruwe vloer | 0 | 0 | Wall Centerline | 3430 | 1.95451 | 1246.5 | 0.244314
2073770 | 01 eerste verdieping | 01 eerste verdieping | yes | Up to level: 02 ok. ruwe vloer | 0 | 0 | Wall Centerline | 3430 | 2.10088 | 487.5 | 0.262609
2086993 | 02 tweede verdieping | 02 tweede verdieping | yes | Up to level: 02 tweede verdieping | 1050 | 0 | Finish Face: Exterior | 1050 | 4.8069 | 4578 | 0.600862
2087145 | 02 tweede verdieping | 02 tweede verdieping | yes | Up to level: 02 tweede verdieping | 1050 | 0 | Finish Face: Exterior | 1050 | 6.3504 | 5985.5 | 0.7938
2087209 | 02 tweede verdieping | 02 tweede verdieping | yes | Up to level: 02 tweede verdieping | 1050 | -50 | Finish Face: Exterior | 1100 | 5.1898 | 4843 | 0.648725
2089167 | 02 tweede verdieping | 02 tweede verdieping | yes | Up to level: 03 ok. ruwe vloer | 0 | 0 | Wall Centerline | 3500 | 2.1 | 600 | 0.2625
2089168 | 02 tweede verdieping | 02 tweede verdieping | yes | Up to level: 03 ok. ruwe vloer | 0 | 0 | Wall Centerline | 3500 | 1.69964 | 1259 | 0.212455
2089251 | 02 tweede verdieping | 02 tweede verdieping | yes | Up to level: 03 ok. ruwe vloer | 0 | 0 | Wall Centerline | 3500 | 2.975 | 975 | 0.371875
2091985 | 00 begane grond | 00 begane grond | yes | Up to level: 01 ok. ruwe vloer | 0 | 2800 | Wall Centerline | 830 | 7.34336 | 8896.25 | 0.916304
2409317 | 02 tweede verdieping | 02 tweede verdieping | yes | Up to level: 03 ok. ruwe vloer | 0 | 0 | Wall Centerline | 3500 | 1.2985 | 496 | 0.162312
2409326 | 01 eerste verdieping | 01 eerste verdieping | yes | Up to level: 02 ok. ruwe vloer | 0 | 0 | Wall Centerline | 3430 | 1.372 | 400 | 0.1715
2409327 | 01 eerste verdieping | 01 eerste verdieping | yes | Up to level: 02 ok. ruwe vloer | 70 | 0 | Wall Centerline | 3500 | 1.386 | 508.5 | 0.17325
2436050 | 02 tweede verdieping | 02 tweede verdieping | yes | Up to level: 03 ok. ruwe vloer | 0 | 0 | Wall Centerline | 3500 | 2.2659 | 1351 | 0.283237
2437421 | 00 begane grond | 00 begane grond | yes | Up to level: 01 ok. ruwe vloer | 0 | 0 | Wall Centerline | 3630 | 2.904 | 965 | 0.363
2437630 | 00 begane grond | 00 begane grond | yes | Up to level: 01 ok. ruwe vloer | 0 | 0 | Wall Centerline | 3630 | 3.43059 | 1625 | 0.428824
2439282 | 01 eerste verdieping | 01 eerste verdieping | yes | Up to level: 02 ok. ruwe vloer | 0 | 0 | Wall Centerline | 3430 | 2.81089 | 2780 | 0.351361
2444394 | 01 eerste verdieping | 01 eerste verdieping | yes | Up to level: 02 ok. ruwe vloer | 0 | 0 | Wall Centerline | 3430 | 7.28302 | 2912.5 | 0.910377
2473372 | 00 begane grond | 00 begane grond | yes | Up to level: 01 ok. ruwe vloer | -60 | 0 | Wall Centerline | 3570 | 11.8702 | 3450 | 1.48378
2473493 | 00 begane grond | 00 begane grond | yes | Up to level: 01 ok. ruwe vloer | -60 | 0 | Wall Centerline | 3570 | 3.92279 | 2130 | 0.490349
2473573 | 00 begane grond | 00 begane grond | yes | Up to level: 01 ok. ruwe vloer | -60 | 0 | Wall Centerline | 3570 | 37.6813 | 14745 | 4.71016
2474174 | 01 eerste verdieping | 01 eerste verdieping | yes | Up to level: 02 ok. ruwe vloer | 0 | 0 | Wall Centerline | 3430 | 1.62925 | 600 | 0.203656
2474530 | 01 eerste verdieping | 01 eerste verdieping | yes | Up to level: 02 ok. ruwe vloer | 0 | 0 | Wall Centerline | 3430 | 5.15845 | 2336 | 0.644806
2474666 | 01 eerste verdieping | 01 eerste verdieping | yes | Up to level: 02 ok. ruwe vloer | 0 | 0 | Wall Centerline | 3430 | 3.37855 | 922.5 | 0.422319
2474733 | 01 eerste verdieping | 01 eerste verdieping | yes | Up to level: 02 ok. ruwe vloer | 0 | 0 | Wall Centerline | 3430 | 2.058 | 725 | 0.25725
2475423 | 01 eerste verdieping | 01 eerste verdieping | yes | Up to level: 02 ok. ruwe vloer | 0 | 0 | Wall Centerline | 3430 | 5.80527 | 1652.5 | 0.725659
2476092 | 02 tweede verdieping | 02 tweede verdieping | yes | Up to level: 03 ok. ruwe vloer | 0 | 0 | Wall Centerline | 3500 | 7.27934 | 2885 | 0.909918
2476112 | 02 tweede verdieping | 02 tweede verdieping | yes | Up to level: 03 ok. ruwe vloer | 0 | 0 | Wall Centerline | 3500 | 7.96184 | 3092.5 | 0.99523
2499658 | 00 begane grond | 00 begane grond | yes | Up to level: 01 ok. ruwe vloer | 0 | 0 | Wall Centerline | 3630 | 0.902815 | 318.276 | 0.111688 | Graphics - Center Mark Visible: no
2500198 | 00 begane grond | 00 begane grond | yes | Up to level: 01 ok. ruwe vloer | -230 | 0 | Wall Centerline | 3400 | 5.79227 | 2532.5 | 0.724033
2500529 | 00 begane grond | 00 begane grond | yes | Up to level: 01 ok. ruwe vloer | -55.6364 | 0 | Wall Centerline | 3574.36 | 8.97631 | 3842.34 | 1.12204
2500984 | 00 begane grond | 00 begane grond | yes | Up to level: 00 begane grond | 1220 | 0 | Wall Centerline | 1220 | 5.4227 | 4794.84 | 0.677838
2503305 | 02 tweede verdieping | 02 tweede verdieping | yes | Up to level: 02 tweede verdieping | 1050 | -600 | Finish Face: Interior | 1650 | 2.5542 | 1610.5 | 0.319275
2544683 | 00 begane grond | 00 begane grond | yes | Up to level: 01 ok. ruwe vloer | 0 | 0 | Wall Centerline | 3630 | 3.62088 | 1325 | 0.452609
2544812 | 00 begane grond | 00 begane grond | yes | Up to level: 01 ok. ruwe vloer | -1196.03 | 0 | Wall Centerline | 2433.97 | 1.15614 | 600 | 0.144517
2715734 | 00 begane grond | 00 begane grond | yes | Up to level: 01 ok. ruwe vloer | 0 | 0 | Wall Centerline | 3630 | 1.28526 | 1159 | 0.160658
2715807 | 00 begane grond | 00 begane grond | yes | Up to level: 01 ok. ruwe vloer | 0 | 0 | Wall Centerline | 3630 | 1.72425 | 350 | 0.215531
2715926 | 00 begane grond | 00 begane grond | yes | Up to level: 01 ok. ruwe vloer | 0 | 0 | Wall Centerline | 3630 | 8.17113 | 2376 | 1.02139
2719532 | 00 begane grond | 00 begane grond | yes | Up to level: 01 ok. ruwe vloer | -60 | 0 | Core Face: Exterior | 3570 | 1.41015 | 405 | 0.176269
2719867 | 00 begane grond | 00 begane grond | yes | Up to level: 01 ok. ruwe vloer | -60 | 0 | Wall Centerline | 3570 | 2.61165 | 2020 | 0.326456
2848569 | 02 tweede verdieping | 02 tweede verdieping | yes | Up to level: 03 ok. ruwe vloer | 0 | 0 | Wall Centerline | 3500 | 1.736 | 496 | 0.217
4193098 | 02 tweede verdieping | 02 tweede verdieping | yes | Up to level: 03 ok. ruwe vloer | 0 | 0 | Wall Centerline | 3500 | 4.33475 | 1351 | 0.541844
4868582 | 00 begane grond | 00 begane grond | yes | Up to level: 01 ok. ruwe vloer | 0 | 0 | Wall Centerline | 3630 | 11.8725 | 3262.98 | 1.48058
4868796 | 01 eerste verdieping | 01 eerste verdieping | yes | Up to level: 02 ok. ruwe vloer | 0 | 0 | Wall Centerline | 3430 | 10.4966 | 5013.51 | 1.31207
4868999 | 01 eerste verdieping | 01 eerste verdieping | yes | Up to level: 02 ok. ruwe vloer | 0 | 0 | Wall Centerline | 3430 | 8.32804 | 2441 | 1.041
4869150 | 01 eerste verdieping | 01 eerste verdieping | yes | Up to level: 02 ok. ruwe vloer | 0 | 0 | Wall Centerline | 3430 | 7.3361 | 4141.09 | 0.917013
4869244 | 01 eerste verdieping | 01 eerste verdieping | yes | Up to level: 02 ok. ruwe vloer | 0 | 0 | Wall Centerline | 3430 | 9.53547 | 2932.52 | 1.19193
4869288 | 01 eerste verdieping | 01 eerste verdieping | yes | Up to level: 02 ok. ruwe vloer | 0 | -50 | Wall Centerline | 3480 | 7.0644 | 1967.5 | 0.88305
4871045 | 01 eerste verdieping | 01 eerste verdieping | yes | Up to level: 02 ok. ruwe vloer | 0 | 0 | Wall Centerline | 3430 | 1.80439 | 1842.5 | 0.225549
4871370 | 01 eerste verdieping | 01 eerste verdieping | yes | Up to level: 02 ok. ruwe vloer | 0 | 0 | Wall Centerline | 3430 | 7.0308 | 3763.5 | 0.87885
4871488 | 01 eerste verdieping | 01 eerste verdieping | yes | Up to level: 02 ok. ruwe vloer | 0 | 0 | Wall Centerline | 3430 | 4.06094 | 2454 | 0.507618
4871542 | 01 eerste verdieping | 01 eerste verdieping | yes | Up to level: 02 ok. ruwe vloer | 0 | 0 | Wall Centerline | 3430 | 10.4965 | 5006 | 1.31207
4873587 | 02 tweede verdieping | 02 tweede verdieping | yes | Up to level: 03 ok. ruwe vloer | 0 | 0 | Wall Centerline | 3500 | 10.8154 | 5053.5 | 1.35193
4873789 | 02 tweede verdieping | 02 tweede verdieping | yes | Up to level: 03 ok. ruwe vloer | 0 | 0 | Wall Centerline | 3500 | 6.45095 | 3800 | 0.806369
4874842 | 02 tweede verdieping | 02 tweede verdieping | yes | Up to level: 03 ok. ruwe vloer | 0 | 0 | Wall Centerline | 3500 | 26.4773 | 7755 | 3.30967
4874972 | 02 tweede verdieping | 02 tweede verdieping | yes | Up to level: 03 ok. ruwe vloer | 0 | 0 | Wall Centerline | 3500 | 7.5972 | 4177.5 | 0.94965
4875166 | 02 tweede verdieping | 02 tweede verdieping | yes | Up to level: 03 ok. ruwe vloer | 0 | 0 | Wall Centerline | 3500 | 8.519 | 2484 | 1.06487
4875242 | 02 tweede verdieping | 02 tweede verdieping | yes | Up to level: 03 ok. ruwe vloer | 0 | 0 | Wall Centerline | 3500 | 10.7969 | 4993 | 1.34961
4879399 | 00 begane grond | 00 begane grond | yes | Up to level: 01 ok. ruwe vloer | 0 | 0 | Wall Centerline | 3630 | 0.74415 | 102.5 | 0.0930188

# IfcWallStandardCase: Basic Wall:22_WA_binnenwand_ms150 25-100-25 _gen_bdg (2)
Type - PredefinedType: STANDARD; Material: f7_gipsvezel 12.5 mm, f7_gips 12.5 mm, n7_isolatie_glaswol 100 mm, f7_gips 12.5 mm, f7_gipsvezel 12.5 mm
Type - Analytical Properties - Roughness: 1; Absorptance: 0.1
Type - Materials and Finishes - Structural Material: f7_gipsvezel
Type - Graphics - Coarse Scale Fill Pattern: <Solid fill>; Coarse Scale Fill Color: 12632256
Type - Construction - Function: Interior; Wrapping at Inserts: Do not wrap; Wrapping at Ends: Exterior; Width: 150 mm
Type - Identity Data - Workset: Wall Types; Assembly Code: 22.11; Assembly Description: binnenwanden; niet constructief, massieve wanden; Datum_Gewijzigd: 26-05-2014; Description: Binnenwand 150mm; Model: LOD300; SmartRevit_Versie: 2015.1; Type Name: 22_WA_binnenwand_ms150 25-100-25 _gen_bdg
Type - Other - Category: Walls; Family Name: Basic Wall
Classification: 22.11 Uniformat (Uniformat)
Cross-Section Definition - Cross-Section: Vertical
Constraints - Base Extension Distance: 0 mm; Base is Attached: no; Related to Mass: no; Room Bounding: yes; Top Extension Distance: 0 mm; Top is Attached: no; Base Offset: 0 mm; Location Line: Wall Centerline; Unconnected Height: 3430 mm
Phasing - Phase Created: 2. nieuwbouw
Structural - Enable Analytical Model: no; Structural: no; Structural Usage: Non-bearing
Identity Data - Workset: Workset1
Other - Family: Basic Wall; Family and Type: Basic Wall: 22_WA_binnenwand_ms150 25-100-25 _gen_bdg; Type: 22_WA_binnenwand_ms150 25-100-25 _gen_bdg; Type Id: 5035038
Name (Basic Wall:22_WA_binnenwand_ms150 25-100-25 _gen_bdg:...) | In | Base Constraint | Top Constraint | Top Offset (mm) | Area (m2) | Length (mm) | Volume (m3)
5035019 | 01 eerste verdieping | 01 eerste verdieping | Up to level: 02 ok. ruwe vloer | 0 | 4.75913 | 1387.5 | 0.713869
5035334 | 02 tweede verdieping | 02 tweede verdieping | Up to level: 03 ok. ruwe vloer | -70 | 2.65825 | 900 | 0.398738

# IfcWallStandardCase: Basic Wall:22_WA_binnenwand_ms205 25-75-5-75-25 _gen_bdg (23)
Type - PredefinedType: STANDARD; Material: f7_gipsvezel 12.5 mm, f7_gips 12.5 mm, n7_isolatie_glaswol 75 mm, j9_luchtspouw 5 mm, n7_isolatie_glaswol 75 mm, f7_gips 12.5 mm, f7_gipsvezel 12.5 mm
Type - Analytical Properties - Roughness: 1; Absorptance: 0.1
Type - Materials and Finishes - Structural Material: f7_gipsvezel
Type - Graphics - Coarse Scale Fill Pattern: <Solid fill>; Coarse Scale Fill Color: 12632256
Type - Construction - Function: Interior; Wrapping at Inserts: Do not wrap; Width: 205 mm
Type - Identity Data - Workset: Wall Types; Assembly Code: 2E(22.11); Datum_Gewijzigd: 26-05-2014; Description: Binnenwand 100mm; Model: LOD300; SmartRevit_Versie: 2015.1; Type Name: 22_WA_binnenwand_ms205 25-75-5-75-25 _gen_bdg
Type - Other - Category: Walls; Family Name: Basic Wall
Classification: 2E(22.11) Uniformat (Uniformat)
Cross-Section Definition - Cross-Section: Vertical
Constraints - Base Extension Distance: 0 mm; Base is Attached: no; Related to Mass: no; Room Bounding: yes; Top Extension Distance: 0 mm; Top is Attached: no; Base Offset: 0 mm
Phasing - Phase Created: 2. nieuwbouw
Structural - Enable Analytical Model: no; Structural: no; Structural Usage: Non-bearing
Identity Data - Workset: Workset1
Other - Family: Basic Wall; Family and Type: Basic Wall: 22_WA_binnenwand_ms205 25-75-5-75-25 _gen_bdg; Type: 22_WA_binnenwand_ms205 25-75-5-75-25 _gen_bdg; Type Id: 1336659
Name (Basic Wall:22_WA_binnenwand_ms205 25-75-5-75-25 _gen_bdg:...) | In | Base Constraint | Top Constraint | Top Offset (mm) | Location Line | Unconnected Height (mm) | Area (m2) | Length (mm) | Volume (m3)
882298 | 02 tweede verdieping | 02 tweede verdieping | Up to level: 03 ok. ruwe vloer | 0 | Wall Centerline | 3500 | 2.5375 | 672.5 | 0.520187
883801 | 02 tweede verdieping | 02 tweede verdieping | Up to level: 03 ok. ruwe vloer | 0 | Core Face: Interior | 3500 | 6.818 | 1988 | 1.39769
886341 | 01 eerste verdieping | 01 eerste verdieping | Up to level: 02 ok. ruwe vloer | 0 | Wall Centerline | 3430 | 3.06985 | 690 | 0.629319
886385 | 01 eerste verdieping | 01 eerste verdieping | Up to level: 02 ok. ruwe vloer | 0 | Wall Centerline | 3430 | 7.65747 | 2232.5 | 1.56978
887501 | 01 eerste verdieping | 01 eerste verdieping | Up to level: 02 ok. ruwe vloer | 0 | Wall Centerline | 3430 | 16.6955 | 4827.5 | 3.42258
887576 | 01 eerste verdieping | 01 eerste verdieping | Up to level: 02 ok. ruwe vloer | 0 | Wall Centerline | 3430 | 1.48012 | 596.521 | 0.303424
1218257 | 00 begane grond | 00 begane grond | Up to level: 01 ok. ruwe vloer | 0 | Wall Centerline | 3630 | 7.623 | 2162.5 | 1.56272
1218261 | 00 begane grond | 00 begane grond | Up to level: 01 ok. ruwe vloer | 0 | Wall Centerline | 3630 | 12.5053 | 3697.5 | 2.5636
1218262 | 00 begane grond | 00 begane grond | Up to level: 01 ok. ruwe vloer | 0 | Wall Centerline | 3630 | 15.9902 | 4530 | 3.27798
1218265 | 00 begane grond | 00 begane grond | Up to level: 01 ok. ruwe vloer | 0 | Core Face: Interior | 3630 | 6.4977 | 1585 | 1.33203
1218266 | 00 begane grond | 00 begane grond | Up to level: 01 ok. ruwe vloer | 0 | Core Face: Interior | 3630 | 10.291 | 2875 | 2.10967
1218270 | 00 begane grond | 00 begane grond | Up to level: 01 ok. ruwe vloer | -60 | Core Face: Exterior | 3570 | 8.33595 | 2210 | 1.70887
1218304 | 00 begane grond | 00 begane grond | Up to level: 01 ok. ruwe vloer | 0 | Core Face: Exterior | 3630 | 7.623 | 2265 | 1.56272
1218305 | 00 begane grond | 00 begane grond | Up to level: 01 ok. ruwe vloer | 0 | Core Face: Interior | 3630 | 9.8373 | 2875 | 2.01665
1223655 | 02 tweede verdieping | 02 tweede verdieping | Up to level: 03 ok. ruwe vloer | 0 | Core Face: Interior | 3500 | 9.6775 | 2850 | 1.98389
1328499 | 02 tweede verdieping | 02 tweede verdieping | Up to level: 03 ok. ruwe vloer | 0 | Wall Centerline | 3500 | 9.205 | 2630 | 1.88703
1329695 | 01 eerste verdieping | 01 eerste verdieping | Up to level: 02 ok. ruwe vloer | 0 | Wall Centerline | 3430 | 1.42345 | 580 | 0.291807
1337197 | 00 begane grond | 00 begane grond | Up to level: 01 ok. ruwe vloer | 0 | Core Face: Interior | 3630 | 30.0382 | 8337.5 | 6.15784
1337729 | 00 begane grond | 00 begane grond | Up to level: 01 ok. ruwe vloer | 0 | Wall Centerline | 3630 | 4.87328 | 1302.5 | 0.999021
1337864 | 00 begane grond | 00 begane grond | Up to level: 01 ok. ruwe vloer | 0 | Wall Centerline | 3630 | 12.4663 | 3672.5 | 2.5556
1337914 | 00 begane grond | 00 begane grond | Up to level: 01 ok. ruwe vloer | 0 | Wall Centerline | 3630 | 29.8749 | 8174 | 6.12435
2475065 | 01 eerste verdieping | 01 eerste verdieping | Up to level: 02 ok. ruwe vloer | 0 | Wall Centerline | 3430 | 1.66355 | 650 | 0.341028
2476217 | 02 tweede verdieping | 02 tweede verdieping | Up to level: 03 ok. ruwe vloer | 0 | Wall Centerline | 3500 | 1.82 | 672.5 | 0.3731

# IfcWallStandardCase: Basic Wall:22_WA_binnenwand_ms350 25-300-25 _gen_bdg, Basic Wall:22_WA_binnenwand_ms350 25-300-25 _gen_bdg:1219339
In: 00 begane grond
Type - PredefinedType: STANDARD; Material: f7_gipsvezel 12.5 mm, f7_gips 12.5 mm, n7_isolatie_glaswol 300 mm, f7_gips 12.5 mm, f7_gipsvezel 12.5 mm
Type - Analytical Properties - Roughness: 1; Absorptance: 0.1
Type - Materials and Finishes - Structural Material: f7_gipsvezel
Type - Graphics - Coarse Scale Fill Pattern: <Solid fill>; Coarse Scale Fill Color: 12632256
Type - Construction - Function: Interior; Wrapping at Inserts: Do not wrap; Width: 350 mm
Type - Identity Data - Workset: Wall Types; Assembly Code: 2E(22.11); Datum_Gewijzigd: 26-05-2014; Description: Binnenwand 100mm; Model: LOD300; SmartRevit_Versie: 2015.1; Type Name: 22_WA_binnenwand_ms350 25-300-25 _gen_bdg
Type - Other - Category: Walls; Family Name: Basic Wall
Classification: 2E(22.11) Uniformat (Uniformat)
Cross-Section Definition - Cross-Section: Vertical
Constraints - Base Extension Distance: 0 mm; Base is Attached: no; Related to Mass: no; Room Bounding: yes; Top Extension Distance: 0 mm; Top is Attached: no; Base Constraint: 00 begane grond; Top Constraint: Up to level: 01 ok. ruwe vloer; Base Offset: 0 mm; Location Line: Wall Centerline; Top Offset: -277 mm; Unconnected Height: 3353 mm
Phasing - Phase Created: 2. nieuwbouw
Structural - Enable Analytical Model: no; Structural: no; Structural Usage: Non-bearing
Dimensions - Area: 14.3085 m2; Length: 5426.14 mm; Volume: 5.00798 m3
Identity Data - Workset: Workset1
Other - Family: Basic Wall; Family and Type: Basic Wall: 22_WA_binnenwand_ms350 25-300-25 _gen_bdg; Type: 22_WA_binnenwand_ms350 25-300-25 _gen_bdg; Type Id: 2493111

# IfcWallStandardCase: Basic Wall:22_WA_binnenwand_ms75 25-25-25 _gen (3)
Type - PredefinedType: STANDARD; Material: f7_gipsvezel 12.5 mm, f7_gips 12.5 mm, n7_isolatie_glaswol 25 mm, f7_gips 12.5 mm, f7_gipsvezel 12.5 mm
Type - Analytical Properties - Roughness: 1; Absorptance: 0.1
Type - Materials and Finishes - Structural Material: n7_isolatie_glaswol
Type - Graphics - Coarse Scale Fill Pattern: <Solid fill>; Coarse Scale Fill Color: 12632256
Type - Construction - Function: Interior; Wrapping at Inserts: Do not wrap; Wrapping at Ends: Exterior; Width: 75 mm
Type - Identity Data - Workset: Wall Types; Assembly Code: 2E(22.11); Datum_Gewijzigd: 26-05-2014; Description: Binnenwand 100mm; Model: LOD300; SmartRevit_Versie: 2015.1; Type Name: 22_WA_binnenwand_ms75 25-25-25 _gen
Type - Other - Category: Walls; Family Name: Basic Wall
Classification: 2E(22.11) Uniformat (Uniformat)
Cross-Section Definition - Cross-Section: Vertical
Constraints - Base Extension Distance: 0 mm; Base is Attached: no; Related to Mass: no; Room Bounding: yes; Top Extension Distance: 0 mm; Top is Attached: no; Top Offset: 0 mm; Location Line: Wall Centerline
Phasing - Phase Created: 2. nieuwbouw
Structural - Enable Analytical Model: no; Structural: no; Structural Usage: Non-bearing
Identity Data - Workset: Workset1
Other - Family: Basic Wall; Family and Type: Basic Wall: 22_WA_binnenwand_ms75 25-25-25 _gen; Type: 22_WA_binnenwand_ms75 25-25-25 _gen; Type Id: 3022516
Name (Basic Wall:22_WA_binnenwand_ms75 25-25-25 _gen:...) | In | Base Constraint | Base Offset (mm) | Unconnected Height (mm) | Area (m2) | Length (mm) | Volume (m3)
3022594 | 00 begane grond | 00 begane grond | 0 | 3630 | 0.814935 | 182.5 | 0.0611201 | Constraints - Top Constraint: Up to level: 01 ok. ruwe vloer
3023308 | 01 eerste verdieping | 01 eerste verdieping | 850 | 2000 | 0.406 | 203 | 0.03045
4865678 | 00 begane grond | 00 begane grond | 850 | 2000 | 0.223 | 111.5 | 0.016725

# IfcWallStandardCase: Basic Wall:22_WA_kalkzandsteen_100mm, Basic Wall:22_WA_kalkzandsteen_100mm:2136149
In: 00 begane grond
Type - PredefinedType: STANDARD; Material: ISR_Kalkzandsteen 100 mm
Type - Analytical Properties - Roughness: 1; Absorptance: 0.1
Type - Materials and Finishes - Structural Material: ISR_Kalkzandsteen
Type - Graphics - Coarse Scale Fill Pattern: <Solid fill>; Coarse Scale Fill Color: 12632256
Type - Construction - Function: Interior; Wrapping at Inserts: Do not wrap; Width: 100 mm
Type - Identity Data - Workset: Wall Types; Assembly Code: 2B(22.21.21); Cost: 0; Datum_Gewijzigd: 26-05-2014; Description: Kalkzandsteen 250mm; Model: LOD300; SmartRevit_Versie: 2015.1; Type Name: 22_WA_kalkzandsteen_100mm
Type - Other - Category: Walls; Family Name: Basic Wall
Classification: 2B(22.21.21) Uniformat (Uniformat)
Cross-Section Definition - Cross-Section: Vertical
Constraints - Base Extension Distance: 0 mm; Base is Attached: no; Related to Mass: no; Room Bounding: yes; Top Extension Distance: 0 mm; Top is Attached: no; Base Constraint: 00 begane grond; Top Constraint: Up to level: 01 ok. ruwe vloer; Base Offset: 0 mm; Location Line: Wall Centerline; Top Offset: -345 mm; Unconnected Height: 3285 mm
Phasing - Phase Created: 2. nieuwbouw
Structural - Enable Analytical Model: no; Structural: no; Structural Usage: Non-bearing
Dimensions - Area: 18.2662 m2; Length: 5560.5 mm; Volume: 1.82662 m3
Identity Data - Workset: Workset1
Other - Family: Basic Wall; Family and Type: Basic Wall: 22_WA_kalkzandsteen_100mm; Type: 22_WA_kalkzandsteen_100mm; Type Id: 2136193

# IfcWallStandardCase: Basic Wall:22_WA_kalkzandsteen_120mm (39)
In: 00 begane grond
Type - PredefinedType: STANDARD; Material: ISR_Kalkzandsteen 120 mm
Type - Analytical Properties - Roughness: 1; Absorptance: 0.1
Type - Materials and Finishes - Structural Material: ISR_Kalkzandsteen
Type - Graphics - Coarse Scale Fill Pattern: <Solid fill>; Coarse Scale Fill Color: 12632256
Type - Construction - Function: Interior; Wrapping at Inserts: Do not wrap; Width: 120 mm
Type - Identity Data - Workset: Wall Types; Assembly Code: 2B(22.21.21); Cost: 0; Datum_Gewijzigd: 26-05-2014; Description: Kalkzandsteen 250mm; Model: LOD300; SmartRevit_Versie: 2015.1; Type Name: 22_WA_kalkzandsteen_120mm
Type - Other - Category: Walls; Family Name: Basic Wall
Classification: 2B(22.21.21) Uniformat (Uniformat)
Cross-Section Definition - Cross-Section: Vertical
Constraints - Base Extension Distance: 0 mm; Base is Attached: no; Related to Mass: no; Top Extension Distance: 0 mm; Top is Attached: no; Base Constraint: 00 begane grond
Phasing - Phase Created: 2. nieuwbouw
Structural - Enable Analytical Model: no; Structural: no; Structural Usage: Non-bearing
Identity Data - Workset: Workset1
Other - Family: Basic Wall; Family and Type: Basic Wall: 22_WA_kalkzandsteen_120mm; Type: 22_WA_kalkzandsteen_120mm; Type Id: 2134361
Name (Basic Wall:22_WA_kalkzandsteen_120mm:...) | Room Bounding | Top Constraint | Base Offset (mm) | Location Line | Top Offset (mm) | Unconnected Height (mm) | Area (m2) | Length (mm) | Volume (m3)
1218308 | yes | Up to level: 01 ok. ruwe vloer | 0 | Core Face: Exterior | -60 | 3570 | 3.45397 | 1027.5 | 0.414477
1368182 | yes | Up to level: 01 ok. ruwe vloer | 0 | Wall Centerline | -60 | 3570 | 17.8143 | 4990 | 2.13772
1368250 | yes | Up to level: 01 ok. ruwe vloer | 0 | Wall Centerline | -60 | 3570 | 46.1309 | 16397.5 | 5.53571
1368308 | yes | Up to level: 01 ok. ruwe vloer | 0 | Wall Centerline | -60 | 3570 | 7.81086 | 3787.5 | 0.937303
1368346 | yes | Up to level: 01 ok. ruwe vloer | 0 | Wall Centerline | -60 | 3570 | 6.97935 | 2075 | 0.837522
1368390 | yes | Up to level: 01 ok. ruwe vloer | 0 | Wall Centerline | -60 | 3570 | 7.55947 | 2177.5 | 0.907137
1368458 | yes | Up to level: 01 ok. ruwe vloer | 0 | Wall Centerline | -60 | 3570 | 16.97 | 4873.5 | 2.0364
1368514 | yes | Up to level: 01 ok. ruwe vloer | 0 | Wall Centerline | -60 | 3570 | 6.05115 | 1815 | 0.726138
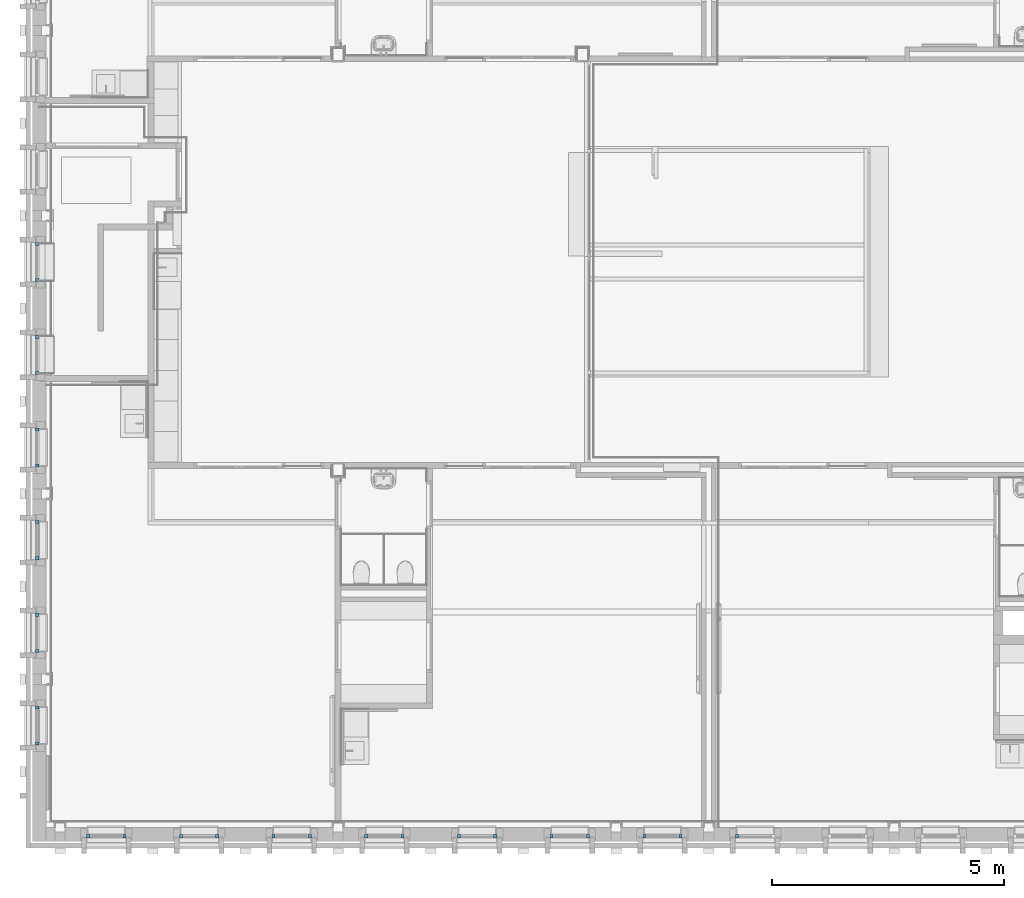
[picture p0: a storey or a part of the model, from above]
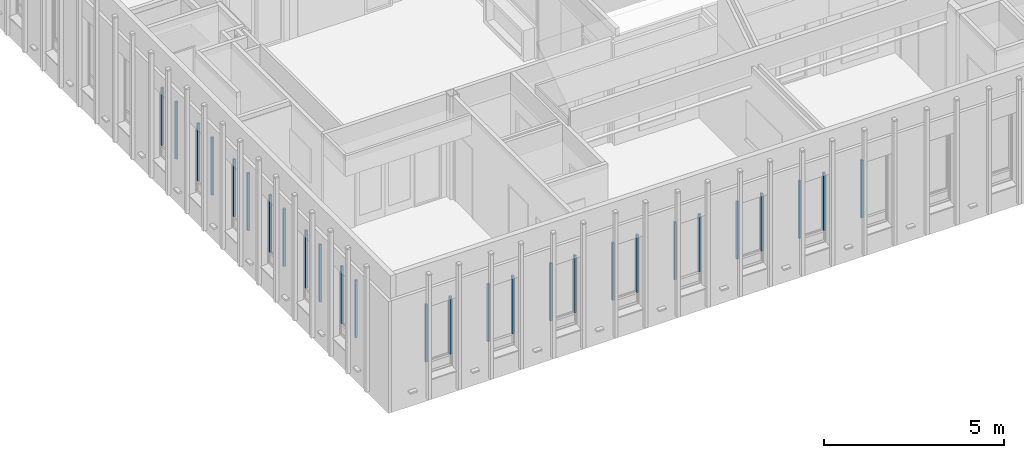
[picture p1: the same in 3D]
Properties of the parts of a building model (IFC2X3), part 88 of 94

# IfcWallStandardCase: Basic Wall:22_WA_kalkzandsteen_120mm (39)
Name (Basic Wall:22_WA_kalkzandsteen_120mm:...) | Room Bounding | Top Constraint | Base Offset (mm) | Location Line | Top Offset (mm) | Unconnected Height (mm) | Area (m2) | Length (mm) | Volume (m3)
1368560 | yes | Up to level: 01 ok. ruwe vloer | 0 | Wall Centerline | -60 | 3570 | 5.09132 | 2177.5 | 0.610958
1368594 | yes | Up to level: 01 ok. ruwe vloer | 0 | Wall Centerline | -60 | 3570 | 6.69375 | 1875 | 0.80325
1368636 | yes | Up to level: 01 ok. ruwe vloer | 0 | Wall Centerline | -60 | 3570 | 5.0694 | 1540 | 0.608328
1368690 | yes | Up to level: 01 ok. ruwe vloer | 0 | Wall Centerline | -60 | 3570 | 6.97935 | 2075 | 0.837522
1368764 | yes | Up to level: 01 ok. ruwe vloer | 0 | Wall Centerline | -60 | 3570 | 17.3859 | 4990 | 2.08631
1368821 | yes | Up to level: 01 ok. ruwe vloer | 0 | Wall Centerline | -60 | 3570 | 14.679 | 4990 | 1.76149
1368942 | no | Up to level: 01 ok. ruwe vloer | 0 | Wall Centerline | -60 | 3570 | 1.47669 | 1225 | 0.177203
1369553 | yes | Up to level: 01 ok. ruwe vloer | 0 | Wall Centerline | -60 | 3570 | 4.11443 | 1212.5 | 0.493731
1369623 | yes | Up to level: 01 ok. ruwe vloer | 0 | Wall Centerline | -60 | 3570 | 4.12692 | 1096 | 0.49523
1369679 | yes | Up to level: 01 ok. ruwe vloer | 0 | Wall Centerline | -60 | 3570 | 4.12692 | 1096 | 0.49523
1369722 | yes | Up to level: 01 ok. ruwe vloer | 0 | Wall Centerline | -60 | 3570 | 4.11443 | 1212.5 | 0.493731
1369850 | yes | Up to level: 01 ok. ruwe vloer | 0 | Finish Face: Interior | -60 | 3570 | 3.94485 | 1225 | 0.473382
1369918 | yes | Up to level: 01 ok. ruwe vloer | 0 | Finish Face: Interior | -60 | 3570 | 4.44465 | 1365 | 0.533358
1369992 | yes | Up to level: 01 ok. ruwe vloer | 0 | Finish Face: Interior | -60 | 3570 | 3.7128 | 1160 | 0.445536
1510613 | yes | Up to level: 01 ok. ruwe vloer | 0 | Wall Centerline | -345 | 3285 | 12.9758 | 3950 | 1.55709
1878850 | yes | Up to level: 01 ok. ruwe vloer | 0 | Finish Face: Interior | -60 | 3570 | 6.26535 | 1875 | 0.751842
1878851 | yes | Up to level: 01 ok. ruwe vloer | 0 | Finish Face: Interior | -60 | 3570 | 6.97935 | 2075 | 0.837522
2136054 | yes | Up to level: 01 ok. ruwe vloer | 0 | Wall Centerline | -345 | 3285 | 15.8979 | 5544.75 | 1.90775
2136529 | yes | Up to level: 01 ok. ruwe vloer | 0 | Finish Face: Interior | -60 | 3570 | 14.4942 | 4180 | 1.7393
2283576 | yes | Up to level: 01 ok. ruwe vloer | 0 | Wall Centerline | -60 | 3570 | 1.07992 | 362.5 | 0.129591
2353210 | yes | Up to level: 01 ok. ruwe vloer | 0 | Wall Centerline | -60 | 3570 | 1.9278 | 600 | 0.231336
2353326 | yes | Up to level: 01 ok. ruwe vloer | 0 | Wall Centerline | -60 | 3570 | 1.93537 | 602.121 | 0.232245
2411534 | yes | Up to level: 01 ok. ruwe vloer | 0 | Wall Centerline | -60 | 3570 | 3.57 | 1000 | 0.4284
2411536 | yes | Up to level: 01 ok. ruwe vloer | 0 | Wall Centerline | -60 | 3570 | 3.57 | 1000 | 0.4284
2411539 | yes | Up to level: 01 ok. ruwe vloer | 0 | Wall Centerline | -60 | 3570 | 7.14 | 2000 | 0.8568
2987313 | yes | Up to level: 00 begane grond | -520 | Finish Face: Exterior | 700 | 1220 | 5.9475 | 4875 | 0.7137
3078908 | yes | Up to level: 01 ok. ruwe vloer | 0 | Core Face: Exterior | -60 | 3570 | 28.1405 | 7882.5 | 3.37686
3078910 | yes | Up to level: 01 ok. ruwe vloer | 0 | Wall Centerline | -345 | 3285 | 27.5655 | 10718 | 3.30785
3080040 | yes | Up to level: 01 ok. ruwe vloer | 0 | Wall Centerline | -345 | 3285 | 2.36848 | 781 | 0.284218
4982683 | yes | Up to level: 01 ok. ruwe vloer | 0 | Wall Centerline | 0 | 3630 | 0.852142 | 294.75 | 0.102257
5027082 | yes | Up to level: 01 ok. ruwe vloer | 0 | Wall Centerline | 0 | 3630 | 23.399 | 6386 | 2.80788

# IfcWallStandardCase: Basic Wall:22_WA_koof_83 12-71 (63)
Type - PredefinedType: STANDARD; Material: f7_gipsvezel 13 mm, ISR_Luchtspouw 71 mm
Type - Analytical Properties - Roughness: 1; Absorptance: 0.1
Type - Graphics - Coarse Scale Fill Pattern: <Solid fill>; Coarse Scale Fill Color: 12632256
Type - Construction - Function: Interior; Wrapping at Inserts: Do not wrap; Width: 84 mm
Type - Identity Data - Workset: Wall Types; Assembly Code: 2E(22.11); Datum_Gewijzigd: 26-05-2014; Description: Binnenwand 125mm; Model: LOD300; SmartRevit_Versie: 2015.1; Type Name: 22_WA_koof_83 12-71
Type - Other - Category: Walls; Family Name: Basic Wall
Classification: 2E(22.11) Uniformat (Uniformat)
Cross-Section Definition - Cross-Section: Vertical
Constraints - Base Extension Distance: 0 mm; Base is Attached: no; Related to Mass: no; Room Bounding: yes; Top Extension Distance: 0 mm
Phasing - Phase Created: 2. nieuwbouw
Structural - Enable Analytical Model: no; Structural: no; Structural Usage: Non-bearing
Identity Data - Workset: Workset1
Other - Family: Basic Wall; Family and Type: Basic Wall: 22_WA_koof_83 12-71; Type: 22_WA_koof_83 12-71; Type Id: 1647323
Name (Basic Wall:22_WA_koof_83 12-71:...) | In | Top is Attached | Top Offset (mm) | Base Constraint | Top Constraint | Location Line | Base Offset (mm) | Unconnected Height (mm) | Area (m2) | Length (mm) | Volume (m3)
1647306 | 00 begane grond | no | 0 | 00 begane grond | Up to level: 01 ok. ruwe vloer | Core Face: Exterior | 2800 | 830 | 6.56447 | 7804.5 | 0.551415
1647627 | 00 begane grond | no | 0 | 00 begane grond | Up to level: 01 ok. ruwe vloer | Core Face: Exterior | 2800 | 830 | 0.875785 | 1272.16 | 0.073566
1647977 | 00 begane grond | no | 0 | 00 begane grond | Up to level: 01 ok. ruwe vloer | Core Face: Exterior | 2800 | 830 | 6.56447 | 7804.5 | 0.551415
1648046 | 00 begane grond | no | 0 | 00 begane grond | Up to level: 01 ok. ruwe vloer | Core Face: Exterior | 2800 | 830 | 1.743 | 2317 | 0.146412
1653728 | 01 eerste verdieping | no | -50 | 01 eerste verdieping | Up to level: 02 tweede verdieping | Finish Face: Exterior | 2800 | 950 | 4.5619 | 4802 | 0.3832
1653805 | 01 eerste verdieping | no | 0 | 01 eerste verdieping | Up to level: 02 tweede verdieping | Finish Face: Exterior | 2800 | 1000 | 5.83335 | 6010.5 | 0.490001
1653915 | 01 eerste verdieping | no | 0 | 01 eerste verdieping | Up to level: 02 tweede verdieping | Finish Face: Exterior | 2800 | 1000 | 6.115 | 6010.5 | 0.51366
1655037 | 02 tweede verdieping | yes | 444.659 | 02 tweede verdieping | Up to level: 03 ok. ruwe vloer | Finish Face: Exterior | 2800 | 1144.66 | 7.09086 | 6010.5 | 0.581908
1655085 | 02 tweede verdieping | no | 0 | 02 tweede verdieping | Up to level: 03 ok. ruwe vloer | Finish Face: Exterior | 2800 | 700 | 3.3614 | 4802 | 0.282358
1655130 | 02 tweede verdieping | no | 250 | 02 tweede verdieping | Up to level: 03 ok. ruwe vloer | Finish Face: Exterior | 2800 | 950 | 5.6107 | 6010.5 | 0.471299
2174472 | 01 eerste verdieping | no | 0 | 01 eerste verdieping | Up to level: 02 ok. ruwe vloer | Finish Face: Exterior | 2800 | 630 | 2.54362 | 3995.5 | 0.213664
2174666 | 01 eerste verdieping | no | 0 | 01 eerste verdieping | Up to level: 02 ok. ruwe vloer | Finish Face: Exterior | 2800 | 630 | 0.71883 | 1183 | 0.0603817
2174958 | 01 eerste verdieping | no | 0 | 01 eerste verdieping | Up to level: 02 ok. ruwe vloer | Finish Face: Exterior | 2800 | 630 | 3.68078 | 5842.5 | 0.309185
2175053 | 01 eerste verdieping | no | 0 | 01 eerste verdieping | Up to level: 02 ok. ruwe vloer | Finish Face: Exterior | 2800 | 630 | 3.79575 | 6067 | 0.318843
2175145 | 01 eerste verdieping | no | 0 | 01 eerste verdieping | Up to level: 02 ok. ruwe vloer | Finish Face: Exterior | 2800 | 630 | 3.68077 | 5842.5 | 0.309185
2175213 | 01 eerste verdieping | no | 0 | 01 eerste verdieping | Up to level: 02 ok. ruwe vloer | Finish Face: Exterior | 2800 | 630 | 3.87765 | 6155 | 0.325723
2175272 | 01 eerste verdieping | no | 0 | 01 eerste verdieping | Up to level: 02 ok. ruwe vloer | Finish Face: Exterior | 2800 | 630 | 0.77175 | 1225 | 0.064827
2175330 | 01 eerste verdieping | no | 0 | 01 eerste verdieping | Up to level: 02 ok. ruwe vloer | Finish Face: Exterior | 2800 | 630 | 2.4907 | 3995.5 | 0.209219
2175529 | 02 tweede verdieping | no | 0 | 02 tweede verdieping | Up to level: 03 ok. ruwe vloer | Finish Face: Exterior | 2800 | 700 | 2.82625 | 3995.5 | 0.237405
2175530 | 02 tweede verdieping | no | 0 | 02 tweede verdieping | Up to level: 03 ok. ruwe vloer | Finish Face: Exterior | 2800 | 700 | 0.7987 | 1183 | 0.0670908
2175531 | 02 tweede verdieping | no | 250 | 02 tweede verdieping | Up to level: 03 ok. ruwe vloer | Finish Face: Exterior | 2800 | 950 | 5.55038 | 5842.5 | 0.466232
2175532 | 02 tweede verdieping | no | 250 | 02 tweede verdieping | Up to level: 03 ok. ruwe vloer | Finish Face: Exterior | 2800 | 950 | 5.73462 | 6068.5 | 0.481708
2175533 | 02 tweede verdieping | no | 0 | 02 tweede verdieping | Up to level: 03 ok. ruwe vloer | Finish Face: Exterior | 2800 | 700 | 4.08975 | 5842.5 | 0.343539
2175534 | 02 tweede verdieping | yes | 543.203 | 02 tweede verdieping | Up to level: 03 ok. ruwe vloer | Finish Face: Exterior | 2800 | 1243.2 | 7.83778 | 6155 | 0.644272
2175535 | 02 tweede verdieping | no | 0 | 02 tweede verdieping | Up to level: 03 ok. ruwe vloer | Finish Face: Exterior | 2800 | 700 | 0.8575 | 1183 | 0.07203
2175536 | 02 tweede verdieping | no | 0 | 02 tweede verdieping | Up to level: 03 ok. ruwe vloer | Finish Face: Exterior | 2800 | 700 | 2.76745 | 3995.5 | 0.232466
2182290 | 02 tweede verdieping | yes | 444.659 | 02 tweede verdieping | Up to level: 03 ok. ruwe vloer | Finish Face: Exterior | 3410 | 534.659 | 3.38876 | 6010.5 | 0.271124
2182291 | 02 tweede verdieping | no | 250 | 02 tweede verdieping | Up to level: 03 ok. ruwe vloer | Finish Face: Exterior | 3410 | 340 | 2.00804 | 6010.5 | 0.168675
2182293 | 02 tweede verdieping | no | 250 | 02 tweede verdieping | Up to level: 03 ok. ruwe vloer | Finish Face: Exterior | 2800 | 950 | 5.6588 | 6104 | 0.475339
2194736 | 02 tweede verdieping | yes | 444.659 | 02 tweede verdieping | Up to level: 03 ok. ruwe vloer | Finish Face: Exterior | 3200 | 744.659 | 10.5527 | 12151 | 0.858587
2194826 | 02 tweede verdieping | no | 250 | 02 tweede verdieping | Up to level: 03 ok. ruwe vloer | Finish Face: Exterior | 3200 | 550 | 6.59912 | 12107.5 | 0.554326
2211934 | 02 tweede verdieping | no | 0 | 02 tweede verdieping | Up to level: 03 ok. ruwe vloer | Finish Face: Exterior | 2800 | 700 | 2.7314 | 3902 | 0.229438
2211998 | 02 tweede verdieping | no | 0 | 02 tweede verdieping | Up to level: 03 ok. ruwe vloer | Finish Face: Exterior | 2800 | 700 | 2.03 | 2900 | 0.17052
2212071 | 02 tweede verdieping | no | 0 | 02 tweede verdieping | Up to level: 03 ok. ruwe vloer | Finish Face: Exterior | 2800 | 700 | 3.46885 | 4955.5 | 0.291383
2279909 | 02 tweede verdieping | no | 0 | 02 tweede verdieping | Up to level: 02 tweede verdieping | Finish Face: Exterior | -600 | 600 | 0.337402 | 624.837 | 0.0283418
2360785 | 00 begane grond | no | -350 | 00 begane grond | Up to level: 01 ok. ruwe vloer | Core Face: Exterior | 2799 | 481 | 1.42665 | 2966 | 0.119838
2361001 | 00 begane grond | no | -350 | 00 begane grond | Up to level: 01 ok. ruwe vloer | Core Face: Exterior | 2812.5 | 467.5 | 1.54275 | 3300 | 0.129591
2361016 | 00 begane grond | no | 0 | 00 begane grond | Up to level: 01 ok. ruwe vloer | Core Face: Exterior | 2812.5 | 817.5 | 0.73575 | 900 | 0.061803
2501230 | 00 begane grond | no | 0 | 00 begane grond | Up to level: 01 eerste verdieping | Core Face: Exterior | 3353 | 647 | 6.61266 | 10158 | 0.555464
2716218 | 00 begane grond | no | 0 | 00 begane grond | Up to level: 01 ok. ruwe vloer | Wall Centerline | 2400 | 1230 | 3.74199 | 3152.5 | 0.314327
2721280 | 00 begane grond | no | -60 | 00 begane grond | Up to level: 01 ok. ruwe vloer | Core Face: Exterior | 2387 | 1183 | 1.44326 | 1332.5 | 0.121234
2721319 | 00 begane grond | no | -60 | 00 begane grond | Up to level: 01 ok. ruwe vloer | Core Face: Exterior | 2387 | 1183 | 2.49613 | 2222.5 | 0.209675
2738394 | 00 begane grond | no | 0 | 00 begane grond | Up to level: 01 ok. ruwe vloer | Finish Face: Interior | 2400 | 1230 | 1.6974 | 1585 | 0.142582
2795932 | 01 eerste verdieping | no | 0 | 01 eerste verdieping | Up to level: 02 ok. ruwe vloer | Finish Face: Exterior | 2800 | 630 | 0.49392 | 742 | 0.0414893
2837986 | 01 eerste verdieping | no | 0 | 01 eerste verdieping | Up to level: 02 ok. ruwe vloer | Finish Face: Exterior | 2387 | 1043 | 1.82525 | 1875 | 0.153321
2838062 | 01 eerste verdieping | no | 0 | 01 eerste verdieping | Up to level: 02 ok. ruwe vloer | Finish Face: Exterior | 2387 | 1043 | 4.71436 | 4632.5 | 0.396006
2854801 | 02 tweede verdieping | no | 0 | 02 tweede verdieping | Up to level: 03 ok. ruwe vloer | Finish Face: Exterior | 2387 | 1113 | 1.94775 | 1875 | 0.163611
2854849 | 02 tweede verdieping | no | 0 | 02 tweede verdieping | Up to level: 03 ok. ruwe vloer | Finish Face: Exterior | 2387 | 1113 | 5.03187 | 4633.5 | 0.422677
3064996 | 00 begane grond | no | 0 | 00 begane grond | Up to level: 01 ok. ruwe vloer | Core Face: Exterior | 3037 | 593 | 4.80799 | 8311.86 | 0.40335
3065276 | 00 begane grond | no | 0 | 00 begane grond | Up to level: 01 ok. ruwe vloer | Core Face: Exterior | 3037 | 593 | 4.72165 | 8166.25 | 0.396097
3135586 | 02 tweede verdieping | no | -250 | 02 tweede verdieping | Up to level: 03 bk. ruwe vloer | Finish Face: Interior | 2400 | 1100 | 1.518 | 1480 | 0.127512
3135599 | 01 eerste verdieping | no | -320 | 01 eerste verdieping | Up to level: 02 bk. ruwe vloer | Finish Face: Interior | 2400 | 1030 | 1.4214 | 1480 | 0.119398
3348211 | 00 begane grond | no | 0 | 00 begane grond | Up to level: 01 ok. ruwe vloer | Core Face: Exterior | 3088 | 542 | 3.95823 | 7303 | 0.332491
4259441 | 00 begane grond | no | 0 | 00 begane grond | Up to level: 01 ok. ruwe vloer | Wall Centerline | 2400 | 1230 | 2.72596 | 2376 | 0.228981
4632010 | 01 eerste verdieping | no | 0 | 01 eerste verdieping | Up to level: 02 ok. ruwe vloer | Finish Face: Exterior | 2400 | 1030 | 2.34325 | 2400 | 0.196833
4662591 | 00 begane grond | no | 0 | 00 begane grond | Up to level: 01 ok. ruwe vloer | Core Face: Exterior | 2800 | 830 | 1.909 | 2360.5 | 0.160356
4662627 | 00 begane grond | no | 0 | 00 begane grond | Up to level: 01 ok. ruwe vloer | Core Face: Exterior | 2800 | 830 | 2.76473 | 3435.5 | 0.232237
4890829 | 02 tweede verdieping | no | 0 | 02 tweede verdieping | Up to level: 03 ok. ruwe vloer | Finish Face: Exterior | 2800 | 700 | 2.7412 | 3958 | 0.230261
4890885 | 02 tweede verdieping | no | 0 | 02 tweede verdieping | Up to level: 03 ok. ruwe vloer | Finish Face: Exterior | 2800 | 700 | 1.7675 | 2483 | 0.14847
4892584 | 02 tweede verdieping | no | 0 | 02 tweede verdieping | Up to level: 03 ok. ruwe vloer | Finish Face: Exterior | 2800 | 700 | 3.74115 | 5302.5 | 0.314257
4892686 | 02 tweede verdieping | no | 0 | 02 tweede verdieping | Up to level: 03 ok. ruwe vloer | Finish Face: Exterior | 2800 | 700 | 1.67965 | 2441.5 | 0.141091
4984155 | 00 begane grond | no | 0 | 00 begane grond | Up to level: 01 ok. ruwe vloer | Core Face: Exterior | 2812.5 | 817.5 | 1.62683 | 2090 | 0.136653
5045626 | 00 begane grond | no | 0 | 00 begane grond | Up to level: 01 ok. ruwe vloer | Core Face: Exterior | 2801 | 829 | 7.11285 | 8783.98 | 0.59675

# IfcWallStandardCase: Basic Wall:22_WA_plafondrekje Rigitone d=125, Basic Wall:22_WA_plafondrekje Rigitone d=125:3271007
In: 00 begane grond
Type - PredefinedType: STANDARD; Material: ISR_Luchtspouw 100 mm, f7_gips 12.5 mm, f7_gips_rigitone_gyproc 8/18 12.5 mm
Type - Analytical Properties - Roughness: 1; Absorptance: 0.1
Type - Materials and Finishes - Structural Material: ISR_Luchtspouw
Type - Graphics - Coarse Scale Fill Pattern: <Solid fill>; Coarse Scale Fill Color: 12632256
Type - Construction - Function: Interior; Wrapping at Ends: Exterior; Wrapping at Inserts: Both; Width: 125 mm
Type - Identity Data - Workset: Wall Types; Assembly Code: 2E(22.11); Datum_Gewijzigd: 26-05-2014; Description: Binnenwand 125mm; Model: LOD300; SmartRevit_Versie: 2015.1; Type Name: 22_WA_plafondrekje Rigitone d=125
Type - Other - Category: Walls; Family Name: Basic Wall
Classification: 2E(22.11) Uniformat (Uniformat)
Cross-Section Definition - Cross-Section: Vertical
Constraints - Base Extension Distance: 0 mm; Base is Attached: no; Related to Mass: no; Room Bounding: yes; Top Extension Distance: 0 mm; Top is Attached: no; Top Offset: 0 mm; Top Constraint: Up to level: 01 eerste verdieping; Base Constraint: 00 begane grond; Location Line: Core Face: Exterior; Base Offset: 3353 mm; Unconnected Height: 647 mm
Phasing - Phase Created: 2. nieuwbouw
Structural - Enable Analytical Model: no; Structural: no; Structural Usage: Non-bearing
Dimensions - Area: 5.09489 m2; Length: 7812.14 mm; Volume: 0.636861 m3
Identity Data - Workset: Workset1
Other - Family: Basic Wall; Family and Type: Basic Wall: 22_WA_plafondrekje Rigitone d=125; Type: 22_WA_plafondrekje Rigitone d=125; Type Id: 3271028

# IfcWallStandardCase: Basic Wall:22_WA_plafondrekje d=125 (6)
Type - PredefinedType: STANDARD; Material: ISR_Luchtspouw 100 mm, f7_gips 12.5 mm, f7_gipsvezel 12.5 mm
Type - Analytical Properties - Roughness: 1; Absorptance: 0.1
Type - Materials and Finishes - Structural Material: ISR_Luchtspouw
Type - Graphics - Coarse Scale Fill Pattern: <Solid fill>; Coarse Scale Fill Color: 12632256
Type - Construction - Function: Interior; Wrapping at Ends: Exterior; Width: 125 mm; Wrapping at Inserts: Both
Type - Identity Data - Workset: Wall Types; Assembly Code: 2E(22.11); Datum_Gewijzigd: 26-05-2014; Description: Binnenwand 125mm; Model: LOD300; SmartRevit_Versie: 2015.1; Type Name: 22_WA_plafondrekje d=125
Type - Other - Category: Walls; Family Name: Basic Wall
Classification: 2E(22.11) Uniformat (Uniformat)
Cross-Section Definition - Cross-Section: Vertical
Constraints - Base Extension Distance: 0 mm; Base is Attached: no; Related to Mass: no; Room Bounding: yes; Top Extension Distance: 0 mm; Top is Attached: no; Location Line: Core Face: Exterior
Phasing - Phase Created: 2. nieuwbouw
Structural - Enable Analytical Model: no; Structural: no; Structural Usage: Non-bearing
Identity Data - Workset: Workset1
Other - Family: Basic Wall; Family and Type: Basic Wall: 22_WA_plafondrekje d=125; Type: 22_WA_plafondrekje d=125; Type Id: 2412699
Name (Basic Wall:22_WA_plafondrekje d=125:...) | In | Top Offset (mm) | Top Constraint | Base Constraint | Base Offset (mm) | Unconnected Height (mm) | Area (m2) | Length (mm) | Volume (m3)
2412701 | 00 begane grond | 0 | Up to level: 01 eerste verdieping | 00 begane grond | 3353 | 647 | 1.2987 | 2605.86 | 0.162337
2801414 | 00 begane grond | 0 | Up to level: 01 eerste verdieping | 00 begane grond | 2800 | 1200 | 5.39159 | 4549.34 | 0.673949
2801527 | 01 eerste verdieping | 200 | Up to level: 02 tweede verdieping | 01 eerste verdieping | 3430 | 570 | 0.936285 | 2572.5 | 0.117036
2801784 | 02 tweede verdieping | -50 | Up to level: 03 derde verdieping | 02 tweede verdieping | 3500 | 250 | 1.14133 | 4565.34 | 0.142667
4630881 | 00 begane grond | 0 | Up to level: 01 ok. ruwe vloer | 00 begane grond | 2800 | 830 | 1.98701 | 2450 | 0.248376
4630882 | 00 begane grond | 0 | Up to level: 01 ok. ruwe vloer | 00 begane grond | 2800 | 830 | 1.0971 | 1384.66 | 0.137137

# IfcWallStandardCase: Basic Wall:22_WA_voorzetwand_ms100 25-20 _gen_bdg, Basic Wall:22_WA_voorzetwand_ms100 25-20 _gen_bdg:3024552
In: 01 eerste verdieping
Type - PredefinedType: STANDARD; Material: f7_gipsvezel 12.5 mm, f7_gips 12.5 mm, n7_isolatie_glaswol 20 mm
Type - Analytical Properties - Roughness: 1; Absorptance: 0.1
Type - Graphics - Coarse Scale Fill Pattern: <Solid fill>; Coarse Scale Fill Color: 12632256
Type - Construction - Function: Interior; Wrapping at Inserts: Do not wrap; Width: 45 mm
Type - Identity Data - Workset: Wall Types; Assembly Code: 2E(22.11); Datum_Gewijzigd: 26-05-2014; Description: Binnenwand 100mm; Model: LOD300; SmartRevit_Versie: 2015.1; Type Name: 22_WA_voorzetwand_ms100 25-20 _gen_bdg
Type - Other - Category: Walls; Family Name: Basic Wall
Classification: 2E(22.11) Uniformat (Uniformat)
Cross-Section Definition - Cross-Section: Vertical
Constraints - Base Extension Distance: 0 mm; Base is Attached: no; Related to Mass: no; Room Bounding: yes; Top Extension Distance: 0 mm; Top is Attached: no; Base Constraint: 01 eerste verdieping; Top Constraint: Up to level: 02 ok. ruwe vloer; Base Offset: 0 mm; Location Line: Wall Centerline; Top Offset: -375 mm; Unconnected Height: 3055 mm
Phasing - Phase Created: 2. nieuwbouw
Structural - Enable Analytical Model: no; Structural: no; Structural Usage: Non-bearing
Dimensions - Area: 23.9497 m2; Length: 7847 mm; Volume: 1.07774 m3
Identity Data - Workset: Workset1
Other - Family: Basic Wall; Family and Type: Basic Wall: 22_WA_voorzetwand_ms100 25-20 _gen_bdg; Type: 22_WA_voorzetwand_ms100 25-20 _gen_bdg; Type Id: 3024607

# IfcWallStandardCase: Basic Wall:22_WA_voorzetwand_ms100 25-65 _gen_bdg, Basic Wall:22_WA_voorzetwand_ms100 25-65 _gen_bdg:2720298
In: 00 begane grond
Type - PredefinedType: STANDARD; Material: f7_gips 12.5 mm, f7_gips 12.5 mm, n7_isolatie_glaswol 65 mm
Type - Analytical Properties - Roughness: 1; Absorptance: 0.1
Type - Graphics - Coarse Scale Fill Pattern: <Solid fill>; Coarse Scale Fill Color: 12632256
Type - Construction - Function: Interior; Wrapping at Inserts: Do not wrap; Width: 90 mm
Type - Identity Data - Workset: Wall Types; Assembly Code: 2E(22.11); Datum_Gewijzigd: 26-05-2014; Description: Binnenwand 100mm; Model: LOD300; SmartRevit_Versie: 2015.1; Type Name: 22_WA_voorzetwand_ms100 25-65 _gen_bdg
Type - Other - Category: Walls; Family Name: Basic Wall
Classification: 2E(22.11) Uniformat (Uniformat)
Cross-Section Definition - Cross-Section: Vertical
Constraints - Base Extension Distance: 0 mm; Base is Attached: no; Related to Mass: no; Room Bounding: yes; Top Extension Distance: 0 mm; Top is Attached: no; Base Constraint: 00 begane grond; Top Constraint: Up to level: 01 ok. ruwe vloer; Base Offset: 0 mm; Location Line: Core Face: Exterior; Top Offset: -60 mm; Unconnected Height: 3570 mm
Phasing - Phase Created: 2. nieuwbouw
Structural - Enable Analytical Model: no; Structural: no; Structural Usage: Non-bearing
Dimensions - Area: 3.7485 m2; Length: 987.5 mm; Volume: 0.337365 m3
Identity Data - Workset: Workset1
Other - Family: Basic Wall; Family and Type: Basic Wall: 22_WA_voorzetwand_ms100 25-65 _gen_bdg; Type: 22_WA_voorzetwand_ms100 25-65 _gen_bdg; Type Id: 2720118

# IfcWallStandardCase: Basic Wall:22_WA_voorzetwand_ms100 25-75 _gen_bdg (93)
Type - PredefinedType: STANDARD; Material: f7_gipsvezel 12.5 mm, f7_gips 12.5 mm, n7_isolatie_glaswol 75 mm
Type - Analytical Properties - Roughness: 1; Absorptance: 0.1
Type - Graphics - Coarse Scale Fill Pattern: <Solid fill>; Coarse Scale Fill Color: 12632256
Type - Construction - Function: Interior; Wrapping at Inserts: Do not wrap; Width: 100 mm
Type - Identity Data - Workset: Wall Types; Assembly Code: 2E(22.11); Datum_Gewijzigd: 26-05-2014; Description: Binnenwand 100mm; Model: LOD300; SmartRevit_Versie: 2015.1; Type Name: 22_WA_voorzetwand_ms100 25-75 _gen_bdg
Type - Other - Category: Walls; Family Name: Basic Wall
Classification: 2E(22.11) Uniformat (Uniformat)
Cross-Section Definition - Cross-Section: Vertical
Constraints - Base Extension Distance: 0 mm; Base is Attached: no; Related to Mass: no; Top Extension Distance: 0 mm
Phasing - Phase Created: 2. nieuwbouw
Structural - Enable Analytical Model: no; Structural: no; Structural Usage: Non-bearing
Identity Data - Workset: Workset1
Other - Family: Basic Wall; Family and Type: Basic Wall: 22_WA_voorzetwand_ms100 25-75 _gen_bdg; Type: 22_WA_voorzetwand_ms100 25-75 _gen_bdg; Type Id: 1223653
Name (Basic Wall:22_WA_voorzetwand_ms100 25-75 _gen_bdg:...) | In | Base Constraint | Room Bounding | Top Constraint | Top is Attached | Top Offset (mm) | Base Offset (mm) | Location Line | Unconnected Height (mm) | Area (m2) | Length (mm) | Volume (m3)
876042 | 02 tweede verdieping | 02 tweede verdieping | yes | Up to level: 03 ok. ruwe vloer | no | 0 | 0 | Wall Centerline | 3500 | 6.475 | 1975 | 0.6475
882510 | 02 tweede verdieping | 02 tweede verdieping | yes | Up to level: 03 ok. ruwe vloer | no | 0 | 0 | Wall Centerline | 3500 | 10.15 | 2900 | 1.015
884639 | 02 tweede verdieping | 02 tweede verdieping | yes | Up to level: 03 ok. ruwe vloer | no | 0 | 0 | Wall Centerline | 3500 | 6.475 | 1975 | 0.6475
886608 | 01 eerste verdieping | 01 eerste verdieping | yes | Up to level: 02 ok. ruwe vloer | no | 0 | 0 | Wall Centerline | 3430 | 25.5535 | 7450 | 2.55535
887060 | 01 eerste verdieping | 01 eerste verdieping | yes | Up to level: 02 ok. ruwe vloer | no | 0 | 0 | Wall Centerline | 3430 | 6.3455 | 1975 | 0.63455
888853 | 01 eerste verdieping | 01 eerste verdieping | yes | Up to level: 02 ok. ruwe vloer | no | 0 | 0 | Wall Centerline | 3430 | 6.34551 | 1975 | 0.634551
889022 | 01 eerste verdieping | 01 eerste verdieping | yes | Up to level: 02 ok. ruwe vloer | no | 0 | 0 | Wall Centerline | 3430 | 25.5535 | 7450 | 2.55535
1218278 | 00 begane grond | 00 begane grond | yes | Up to level: 01 ok. ruwe vloer | no | -60 | 0 | Wall Centerline | 3570 | 6.6045 | 1975 | 0.66045
1218286 | 00 begane grond | 00 begane grond | yes | Up to level: 01 ok. ruwe vloer | no | 0 | 0 | Wall Centerline | 3630 | 7.0785 | 2075 | 0.70785
1223656 | 01 eerste verdieping | 01 eerste verdieping | yes | Up to level: 02 ok. ruwe vloer | no | 0 | 0 | Core Face: Interior | 3430 | 3.6015 | 1175 | 0.36015
1223657 | 01 eerste verdieping | 01 eerste verdieping | yes | Up to level: 02 ok. ruwe vloer | no | 0 | 0 | Core Face: Interior | 3430 | 6.34551 | 1975 | 0.634551
1223658 | 01 eerste verdieping | 01 eerste verdieping | yes | Up to level: 02 ok. ruwe vloer | no | 0 | 0 | Core Face: Interior | 3430 | 6.3455 | 1975 | 0.63455
1223659 | 01 eerste verdieping | 01 eerste verdieping | yes | Up to level: 02 ok. ruwe vloer | no | 0 | 0 | Core Face: Interior | 3430 | 4.116 | 1365 | 0.4116
1223689 | 02 tweede verdieping | 02 tweede verdieping | yes | Up to level: 03 ok. ruwe vloer | no | -70 | 0 | Core Face: Interior | 3430 | 4.0474 | 1305 | 0.40474
1223690 | 02 tweede verdieping | 02 tweede verdieping | yes | Up to level: 03 ok. ruwe vloer | no | 0 | 0 | Core Face: Interior | 3500 | 6.475 | 1975 | 0.6475
1223691 | 02 tweede verdieping | 02 tweede verdieping | yes | Up to level: 03 ok. ruwe vloer | no | -70 | 0 | Core Face: Interior | 3430 | 6.3455 | 1975 | 0.63455
1223696 | 02 tweede verdieping | 02 tweede verdieping | yes | Up to level: 03 ok. ruwe vloer | no | 0 | 0 | Core Face: Interior | 3500 | 9.0475 | 2710 | 0.90475
1225372 | 00 begane grond | 00 begane grond | yes | Up to level: 01 ok. ruwe vloer | no | -60 | 0 | Wall Centerline | 3570 | 6.6045 | 1975 | 0.66045
1291620 | 00 begane grond | 00 begane grond | yes | Up to level: 01 ok. ruwe vloer | no | -60 | 0 | Finish Face: Interior | 3570 | 6.6045 | 1975 | 0.66045
1291621 | 00 begane grond | 00 begane grond | yes | Up to level: 01 ok. ruwe vloer | no | -60 | 0 | Finish Face: Interior | 3570 | 6.6045 | 1975 | 0.66045
1328685 | 02 tweede verdieping | 02 tweede verdieping | yes | Up to level: 03 ok. ruwe vloer | no | 0 | 0 | Wall Centerline | 3500 | 13.8423 | 4197.5 | 1.38423
1328952 | 02 tweede verdieping | 02 tweede verdieping | yes | Up to level: 03 ok. ruwe vloer | no | 0 | 0 | Core Face: Exterior | 3500 | 9.9225 | 2710 | 0.99225
1329784 | 01 eerste verdieping | 01 eerste verdieping | yes | Up to level: 02 ok. ruwe vloer | no | 0 | 0 | Core Face: Exterior | 3430 | 3.6015 | 1050 | 0.36015
1503882 | 00 begane grond | 00 begane grond | yes | Up to level: 01 ok. ruwe vloer | no | 0 | 0 | Finish Face: Interior | 3630 | 7.0785 | 2075 | 0.70785
1509554 | 00 begane grond | 00 begane grond | yes | Up to level: 01 ok. ruwe vloer | no | 0 | 0 | Finish Face: Interior | 3630 | 15.9902 | 4530 | 1.59902
1810499 | 00 begane grond | 00 begane grond | yes | Up to level: 01 ok. ruwe vloer | no | 0 | 0 | Finish Face: Interior | 3630 | 3.99423 | 1202.29 | 0.394897
1810523 | 00 begane grond | 00 begane grond | yes | Up to level: 01 ok. ruwe vloer | no | 0 | 0 | Finish Face: Interior | 3630 | 0.726 | 212.5 | 0.0726
1811466 | 00 begane grond | 00 begane grond | yes | Up to level: 01 ok. ruwe vloer | no | -60 | 0 | Finish Face: Interior | 3570 | 3.26175 | 1100 | 0.326175
1811467 | 00 begane grond | 00 begane grond | yes | Up to level: 01 ok. ruwe vloer | no | -60 | 0 | Finish Face: Interior | 3570 | 0.714 | 212.5 | 0.0714
1814472 | 00 begane grond | 00 begane grond | yes | Up to level: 01 ok. ruwe vloer | no | 0 | 0 | Finish Face: Interior | 3630 | 3.3396 | 1072.5 | 0.33396
1814502 | 00 begane grond | 00 begane grond | yes | Up to level: 01 ok. ruwe vloer | no | 0 | 0 | Finish Face: Interior | 3630 | 1.07085 | 182.5 | 0.107085
1832794 | 00 begane grond | 00 begane grond | yes | Up to level: 01 ok. ruwe vloer | no | -60 | 0 | Core Face: Exterior | 3570 | 29.3633 | 8287.5 | 2.93633
1833038 | 00 begane grond | 00 begane grond | yes | Up to level: 01 ok. ruwe vloer | no | -350 | 0 | Core Face: Exterior | 3280 | 26.978 | 8287.5 | 2.6978
1833561 | 00 begane grond | 00 begane grond | yes | Up to level: 01 ok. ruwe vloer | no | -60 | 0 | Core Face: Exterior | 3570 | 5.97975 | 1737.5 | 0.597975
1834253 | 01 eerste verdieping | 01 eerste verdieping | yes | Up to level: 02 ok. ruwe vloer | no | 0 | 0 | Wall Centerline | 3430 | 25.5535 | 7450 | 2.55535
1834398 | 01 eerste verdieping | 01 eerste verdieping | yes | Up to level: 02 ok. ruwe vloer | no | 0 | 0 | Wall Centerline | 3430 | 25.5535 | 7450 | 2.55535
1890860 | 01 eerste verdieping | 01 eerste verdieping | yes | Up to level: 02 ok. ruwe vloer | no | 0 | 0 | Wall Centerline | 3430 | 6.97148 | 2120 | 0.69286
1932313 | 00 begane grond | 00 begane grond | yes | Up to level: 01 ok. ruwe vloer | no | 0 | 0 | Finish Face: Interior | 3630 | 2.98864 | 923.318 | 0.298864
1932335 | 00 begane grond | 00 begane grond | yes | Up to level: 01 ok. ruwe vloer | no | 0 | 0 | Finish Face: Interior | 3630 | 0.72975 | 212.5 | 0.072975
1932658 | 02 tweede verdieping | 02 tweede verdieping | yes | Up to level: 03 ok. ruwe vloer | no | -70 | 0 | Core Face: Interior | 3430 | 9.65202 | 2714 | 0.965202
1932680 | 02 tweede verdieping | 02 tweede verdieping | yes | Up to level: 03 ok. ruwe vloer | no | -70 | 0 | Core Face: Interior | 3430 | 0.7546 | 207.5 | 0.07546
1983178 | 02 tweede verdieping | 02 tweede verdieping | yes | Up to level: 03 ok. ruwe vloer | no | 0 | 0 | Wall Centerline | 3500 | 26.81 | 7697.5 | 2.67662
1983179 | 02 tweede verdieping | 02 tweede verdieping | yes | Up to level: 03 ok. ruwe vloer | no | 0 | 0 | Wall Centerline | 3500 | 26.04 | 7490 | 2.604
1983299 | 02 tweede verdieping | 02 tweede verdieping | yes | Up to level: 03 ok. ruwe vloer | no | 0 | 0 | Wall Centerline | 3500 | 9.03 | 2680 | 0.903
1983300 | 02 tweede verdieping | 02 tweede verdieping | yes | Up to level: 03 ok. ruwe vloer | no | 0 | 0 | Wall Centerline | 3500 | 13.8423 | 4197.5 | 1.38423
1984003 | 02 tweede verdieping | 02 tweede verdieping | yes | Up to level: 03 ok. ruwe vloer | no | 0 | 0 | Wall Centerline | 3500 | 26.81 | 7710 | 2.681
1984005 | 02 tweede verdieping | 02 tweede verdieping | yes | Up to level: 03 ok. ruwe vloer | no | 0 | 0 | Wall Centerline | 3500 | 26.81 | 7710 | 2.681
1991813 | 01 eerste verdieping | 01 eerste verdieping | yes | Up to level: 02 ok. ruwe vloer | no | 0 | 0 | Wall Centerline | 3430 | 10.7785 | 3242.41 | 1.07785
1991814 | 01 eerste verdieping | 01 eerste verdieping | yes | Up to level: 02 ok. ruwe vloer | no | 0 | 0 | Core Face: Exterior | 3430 | 10.7785 | 3242.41 | 1.07785
2002122 | 02 tweede verdieping | 02 tweede verdieping | yes | Up to level: 03 ok. ruwe vloer | no | 0 | 0 | Finish Face: Interior | 3500 | 10.9988 | 3242.5 | 1.09988
2002126 | 02 tweede verdieping | 02 tweede verdieping | yes | Up to level: 03 ok. ruwe vloer | no | 0 | 0 | Finish Face: Interior | 3500 | 12.4373 | 3553.5 | 1.24373
2002129 | 01 eerste verdieping | 01 eerste verdieping | yes | Up to level: 02 ok. ruwe vloer | no | 0 | 0 | Finish Face: Interior | 3430 | 17.5873 | 5227.5 | 1.75873
2073540 | 01 eerste verdieping | 01 eerste verdieping | yes | Up to level: 02 ok. ruwe vloer | no | 0 | 0 | Wall Centerline | 3430 | 1.62925 | 600 | 0.162925
2194737 | 02 tweede verdieping | 03 ok. ruwe vloer | yes | Up to level: 03 derde verdieping | yes | 1000 | 0 | Wall Centerline | 1300 | 2.10512 | 1858.5 | 0.210512 | Group: Model Group:BU-42 daklicht B lokaal:2182308
2194738 | 02 tweede verdieping | 03 ok. ruwe vloer | yes | Up to level: 03 derde verdieping | yes | 1000 | 0 | Wall Centerline | 1300 | 2.10512 | 1858.5 | 0.210512 | Group: Model Group:BU-42 daklicht B lokaal:2182308
2194824 | 02 tweede verdieping | 03 ok. ruwe vloer | yes | Up to level: 03 derde verdieping | yes | 1000 | 0 | Wall Centerline | 1300 | 2.13108 | 1858.5 | 0.213108 | Group: Model Group:BU-42 daklicht B lokaal:2194782
2194825 | 02 tweede verdieping | 03 ok. ruwe vloer | yes | Up to level: 03 derde verdieping | yes | 1000 | 0 | Wall Centerline | 1300 | 2.13108 | 1858.5 | 0.213108 | Group: Model Group:BU-42 daklicht B lokaal:2194782
2203273 | 01 eerste verdieping | 01 eerste verdieping | yes | Up to level: 02 ok. ruwe vloer | no | 0 | 0 | Wall Centerline | 3430 | 3.15903 | 1021 | 0.315903
2203304 | 01 eerste verdieping | 01 eerste verdieping | yes | Up to level: 02 ok. ruwe vloer | no | 0 | 0 | Wall Centerline | 3430 | 2.058 | 612.5 | 0.2058
2204704 | 02 tweede verdieping | 02 tweede verdieping | yes | Up to level: 03 ok. ruwe vloer | no | -70 | 0 | Wall Centerline | 3430 | 2.44575 | 1007.5 | 0.244575
2204705 | 02 tweede verdieping | 02 tweede verdieping | yes | Up to level: 03 ok. ruwe vloer | no | -70 | 0 | Wall Centerline | 3430 | 2.058 | 612.5 | 0.2058
2270918 | 00 begane grond | 00 begane grond | yes | Up to level: 01 ok. ruwe vloer | no | -60 | 0 | Finish Face: Interior | 3570 | 14.4942 | 3960 | 1.44942
2271787 | 00 begane grond | 00 begane grond | yes | Up to level: 01 ok. ruwe vloer | no | -60 | 0 | Finish Face: Interior | 3570 | 14.1372 | 3960 | 1.41372
2326015 | 00 begane grond | 00 begane grond | yes | Up to level: 01 ok. ruwe vloer | no | 0 | 0 | Wall Centerline | 3630 | 2.45025 | 787.5 | 0.245025
2326410 | 00 begane grond | 00 begane grond | yes | Up to level: 01 ok. ruwe vloer | no | 0 | 0 | Finish Face: Interior | 3630 | 0.726 | 212.5 | 0.0726
2435824 | 01 eerste verdieping | 01 eerste verdieping | yes | Up to level: 02 ok. ruwe vloer | no | 0 | 0 | Wall Centerline | 3430 | 17.9303 | 5227.5 | 1.79303
2436064 | 02 tweede verdieping | 02 tweede verdieping | yes | Up to level: 03 ok. ruwe vloer | no | 0 | 0 | Wall Centerline | 3500 | 12.4653 | 3661.5 | 1.24653
2436520 | 02 tweede verdieping | 02 tweede verdieping | yes | Up to level: 03 ok. ruwe vloer | no | 0 | 0 | Wall Centerline | 3500 | 11.3488 | 3242.5 | 1.13488
2499901 | 00 begane grond | 00 begane grond | yes | Up to level: 01 ok. ruwe vloer | no | -55.6364 | 0 | Wall Centerline | 3574.36 | 1.54119 | 454.148 | 0.142228
2500576 | 00 begane grond | 00 begane grond | yes | Up to level: 01 ok. ruwe vloer | no | -55.6364 | 0 | Wall Centerline | 3574.36 | 0.277013 | 77.5 | 0.0277013
2500698 | 00 begane grond | 00 begane grond | yes | Up to level: 01 ok. ruwe vloer | no | -230 | 0 | Wall Centerline | 3400 | 2.601 | 540 | 0.2601
2500848 | 00 begane grond | 00 begane grond | yes | Up to level: 01 ok. ruwe vloer | no | -230 | 0 | Wall Centerline | 3400 | 1.56665 | 575 | 0.156665
2722843 | 00 begane grond | 00 begane grond | yes | Up to level: 01 ok. ruwe vloer | no | -60 | 0 | Finish Face: Interior | 3570 | 0.597975 | 280 | 0.0597975
2723007 | 00 begane grond | 00 begane grond | yes | Up to level: 01 ok. ruwe vloer | no | -60 | 0 | Finish Face: Interior | 3570 | 0.597975 | 280 | 0.0597975
2723117 | 00 begane grond | 00 begane grond | yes | Up to level: 01 ok. ruwe vloer | no | -60 | 0 | Finish Face: Interior | 3570 | 0.954975 | 280 | 0.0954975
2723190 | 00 begane grond | 00 begane grond | yes | Up to level: 01 ok. ruwe vloer | no | -60 | 0 | Finish Face: Interior | 3570 | 0.597975 | 280 | 0.0597975
2740852 | 00 begane grond | 00 begane grond | yes |  | no | 0 | 0 | Wall Centerline | 900 | 0.864 | 1022.5 | 0.0864
2744040 | 01 eerste verdieping | 01 eerste verdieping | yes | Up to level: 02 ok. ruwe vloer | no | 0 | 0 | Wall Centerline | 3430 | 1.0976 | 207.5 | 0.10976
2748269 | 01 eerste verdieping | 01 eerste verdieping | yes | Up to level: 02 ok. ruwe vloer | no | 0 | 0 | Finish Face: Interior | 3430 | 1.0976 | 207.5 | 0.10976
2779029 | 02 tweede verdieping | 02 tweede verdieping | yes | Up to level: 03 ok. ruwe vloer | no | 0 | 0 | Finish Face: Interior | 3500 | 1.12 | 207.5 | 0.112
2780326 | 02 tweede verdieping | 02 tweede verdieping | yes | Up to level: 03 ok. ruwe vloer | no | 0 | 0 | Finish Face: Interior | 3500 | 1.12 | 207.5 | 0.112
2899445 | 00 begane grond | 01 bk. ruwe vloer | no | Up to level: 03 ok. ruwe vloer | no | -225 | 3480 | Core Face: Exterior | 3645 | 8.30744 | 3396.5 | 0.830744
2968116 | 00 begane grond | 00 begane grond | no | Up to level: 01 bk. ruwe vloer | no | 3220 | 3630 | Core Face: Exterior | 3540 | 5.78524 | 3383.5 | 0.578524
3011415 | 00 begane grond | 00 begane grond | yes | Up to level: 01 bk. ruwe vloer | no | -630 | 0 | Finish Face: Exterior | 3320 | 7.11476 | 2205.5 | 0.711476
3078909 | 00 begane grond | 00 begane grond | yes | Up to level: 01 ok. ruwe vloer | no | -60 | 0 | Core Face: Exterior | 3570 | 0.7497 | 210 | 0.07497
3079734 | 00 begane grond | 00 begane grond | yes | Up to level: 01 ok. ruwe vloer | no | -60 | 0 | Core Face: Exterior | 3570 | 0.33915 | 95 | 0.033915
3267593 | 01 eerste verdieping | 01 eerste verdieping | no | Up to level: 01 bk. ruwe vloer | no | 3220 | 0 | Core Face: Exterior | 3170 | 2.28326 | 1871 | 0.228326
4254654 | 00 begane grond | 00 begane grond | yes | Up to level: 01 bk. ruwe vloer | no | -630 | 0 | Finish Face: Exterior | 3320 | 4.16436 | 1254.33 | 0.416436
4632018 | 02 tweede verdieping | 02 tweede verdieping | yes | Up to level: 03 ok. ruwe vloer | no | -70 | 0 | Core Face: Interior | 3430 | 2.84347 | 898 | 0.284347
4889866 | 02 tweede verdieping | 02 tweede verdieping | yes | Up to level: 03 ok. ruwe vloer | no | 0 | 0 | Wall Centerline | 3500 | 0.51625 | 97.5 | 0.051625
5033381 | 00 begane grond | 00 begane grond | yes | Up to level: 01 ok. ruwe vloer | no | 0 | 0 | Finish Face: Interior | 3630 | 4.51235 | 1427.5 | 0.451235
5033448 | 00 begane grond | 00 begane grond | yes | Up to level: 01 ok. ruwe vloer | no | 0 | 0 | Finish Face: Interior | 3630 | 0.363 | 212.5 | 0.0363
5047166 | 00 begane grond | 00 begane grond | yes | Up to level: 01 ok. ruwe vloer | no | 0 | 0 | Finish Face: Interior | 3630 | 3.85506 | 1062 | 0.385506

# IfcWallStandardCase: Basic Wall:22_WA_voorzetwand_ms100 4*6,5-75 _gen_bdg (2)
In: 00 begane grond
Type - PredefinedType: STANDARD; Material: f7_gips 6.3 mm, f7_gips 6.3 mm, f7_gips 6.3 mm, f7_gips 6.3 mm, n7_isolatie_glaswol 75 mm
Type - Analytical Properties - Roughness: 1; Absorptance: 0.1
Type - Graphics - Coarse Scale Fill Pattern: <Solid fill>; Coarse Scale Fill Color: 12632256
Type - Construction - Function: Interior; Wrapping at Inserts: Do not wrap; Width: 100 mm
Type - Identity Data - Workset: Wall Types; Assembly Code: 2E(22.11); Datum_Gewijzigd: 26-05-2014; Description: Binnenwand 100mm; Model: LOD300; SmartRevit_Versie: 2015.1; Type Name: 22_WA_voorzetwand_ms100 4*6,5-75 _gen_bdg
Type - Other - Category: Walls; Family Name: Basic Wall
Classification: 2E(22.11) Uniformat (Uniformat)
Cross-Section Definition - Cross-Section: Vertical
Constraints - Base Extension Distance: 0 mm; Base is Attached: no; Related to Mass: no; Room Bounding: yes; Top Extension Distance: 0 mm; Top is Attached: no; Base Constraint: 00 begane grond; Top Constraint: Up to level: 01 ok. ruwe vloer; Base Offset: 0 mm; Location Line: Wall Centerline
Phasing - Phase Created: 2. nieuwbouw
Structural - Enable Analytical Model: no; Structural: no; Structural Usage: Non-bearing
Graphics - Center Mark Visible: no
Identity Data - Workset: Workset1
Other - Family: Basic Wall; Family and Type: Basic Wall: 22_WA_voorzetwand_ms100 4*6,5-75 _gen_bdg; Type: 22_WA_voorzetwand_ms100 4*6,5-75 _gen_bdg; Type Id: 3161971
Name (Basic Wall:22_WA_voorzetwand_ms100 4*6,5-75 _gen_bdg:...) | Top Offset (mm) | Unconnected Height (mm) | Area (m2) | Length (mm) | Volume (m3)
2500034 | -230 | 3400 | 2.30638 | 540.954 | 0.20339
2500412 | 0 | 3630 | 3.34992 | 844.303 | 0.306484

# IfcWallStandardCase: Basic Wall:22_WA_voorzetwand_vilt 8 _gen_bdg (2)
In: 00 begane grond
Type - PredefinedType: STANDARD; Material: Tr_21_vilt 8 mm
Type - Analytical Properties - Roughness: 1; Absorptance: 0.1
Type - Graphics - Coarse Scale Fill Pattern: <Solid fill>; Coarse Scale Fill Color: 12632256
Type - Construction - Function: Interior; Wrapping at Inserts: Do not wrap; Width: 8 mm
Type - Identity Data - Workset: Wall Types; Assembly Code: 2E(22.11); Datum_Gewijzigd: 26-05-2014; Description: Binnenwand 100mm; Model: LOD300; SmartRevit_Versie: 2015.1; Type Name: 22_WA_voorzetwand_vilt 8 _gen_bdg
Type - Other - Category: Walls; Family Name: Basic Wall
Classification: 2E(22.11) Uniformat (Uniformat)
Cross-Section Definition - Cross-Section: Vertical
Constraints - Base Extension Distance: 0 mm; Base is Attached: no; Related to Mass: no; Room Bounding: yes; Top Extension Distance: 0 mm; Top is Attached: no; Base Constraint: 00 begane grond; Top Constraint: Up to level: 00 begane grond; Location Line: Core Face: Interior; Top Offset: 6500 mm
Phasing - Phase Created: 2. nieuwbouw
Structural - Enable Analytical Model: no; Structural: no; Structural Usage: Non-bearing
Identity Data - Workset: Workset1
Other - Family: Basic Wall; Family and Type: Basic Wall: 22_WA_voorzetwand_vilt 8 _gen_bdg; Type: 22_WA_voorzetwand_vilt 8 _gen_bdg; Type Id: 2382613
Name (Basic Wall:22_WA_voorzetwand_vilt 8 _gen_bdg:...) | Base Offset (mm) | Unconnected Height (mm) | Area (m2) | Length (mm) | Volume (m3)
2382611 | 4085.75 | 2414.25 | 53.647 | 22217 | 0.429176
2382612 | 4115 | 2385 | 33.8622 | 14202 | 0.270898

# IfcWallStandardCase: Basic Wall:NLRS_20_WA_Kokowall 90 (9)
In: 01 eerste verdieping
Type - PredefinedType: STANDARD; Material: Kokowall 90 mm
Type - Analytical Properties - Roughness: 1; Absorptance: 0.1
Type - Graphics - Coarse Scale Fill Pattern: <Solid fill>; Coarse Scale Fill Color: 4210752
Type - Construction - Wrapping at Inserts: Do not wrap; Function: Exterior; Width: 90 mm
Type - Identity Data - Workset: Wall Types; Description: basis 100mm; Model: LOD200; SmartRevit_Versie: 2018.2; Type Name: NLRS_20_WA_Kokowall 90
Type - Other - Category: Walls; Family Name: Basic Wall
Cross-Section Definition - Cross-Section: Vertical
Constraints - Base Extension Distance: 0 mm; Base is Attached: no; Location Line: Finish Face: Exterior; Related to Mass: no; Room Bounding: yes; Top Extension Distance: 0 mm; Top is Attached: no; Base Constraint: 01 eerste verdieping; Top Constraint: Up to level: 01 eerste verdieping; Base Offset: 250 mm; Top Offset: 2900 mm; Unconnected Height: 2650 mm
Phasing - Phase Created: 2. nieuwbouw
Structural - Enable Analytical Model: no; Structural: no; Structural Usage: Non-bearing
Identity Data - Workset: Workset1
Other - Family: Basic Wall; Family and Type: Basic Wall: NLRS_20_WA_Kokowall 90; Type: NLRS_20_WA_Kokowall 90; Type Id: 2548490
Name (Basic Wall:NLRS_20_WA_Kokowall 90:...) | Area (m2) | Length (mm) | Volume (m3)
2548459 | 4.49917 | 1697.8 | 0.404925
2548460 | 3.47362 | 1355.8 | 0.312626
3318668 | 5.18499 | 1956.6 | 0.466649
3318703 | 5.25124 | 1981.6 | 0.472612
3318750 | 5.25124 | 1981.6 | 0.472612
3318809 | 5.194 | 1960 | 0.46746
3319302 | 5.25124 | 1981.6 | 0.472612
3319396 | 4.48062 | 1645.8 | 0.403256
3319586 | 2.61434 | 986.544 | 0.235291

# IfcWallStandardCase: Basic Wall:NLRS_20_WA_RVS Carlstahl 2 TRANS (41)
Type - PredefinedType: STANDARD; Material: ISR_RVS_Carlstahl 2 mm
Type - Analytical Properties - Roughness: 1; Absorptance: 0.1
Type - Graphics - Coarse Scale Fill Pattern: <Solid fill>; Coarse Scale Fill Color: 4210752
Type - Construction - Wrapping at Inserts: Do not wrap; Function: Exterior; Width: 2 mm
Type - Identity Data - Workset: Wall Types; Description: basis 100mm; Model: LOD200; SmartRevit_Versie: 2018.2; Type Name: NLRS_20_WA_RVS Carlstahl 2 TRANS
Type - Other - Category: Walls; Family Name: Basic Wall
Cross-Section Definition - Cross-Section: Vertical
Constraints - Base Extension Distance: 0 mm; Base is Attached: no; Related to Mass: no; Room Bounding: yes; Top Extension Distance: 0 mm; Top is Attached: no
Phasing - Phase Created: 2. nieuwbouw
Structural - Enable Analytical Model: no; Structural: no; Structural Usage: Non-bearing
Other - Family: Basic Wall; Family and Type: Basic Wall: NLRS_20_WA_RVS Carlstahl 2 TRANS; Type: NLRS_20_WA_RVS Carlstahl 2 TRANS; Type Id: 1830774
Name (Basic Wall:NLRS_20_WA_RVS Carlstahl 2 TRANS:...) | In | Base Constraint | Top Constraint | Location Line | Base Offset (mm) | Top Offset (mm) | Unconnected Height (mm) | Area (m2) | Length (mm) | Volume (m3) | Workset | Comments
2451034 | 01 eerste verdieping | 01 eerste verdieping | Up to level: 01 eerste verdieping | Wall Centerline | 910 | 2850 | 1940 | 3.6375 | 1875 | 0.007275 | Workset1 | RVS-kabelnet
2451035 | 01 eerste verdieping | 01 eerste verdieping | Up to level: 01 eerste verdieping | Wall Centerline | 910 | 2850 | 1940 | 1.77025 | 912.5 | 0.0035405 | Workset1 | RVS-kabelnet
2548337 | 01 eerste verdieping | 01 eerste verdieping | Up to level: 01 eerste verdieping | Wall Centerline | 910 | 2820 | 1910 | 3.88367 | 2033.33 | 0.00776733 | Workset1 | RVS-kabelnet
2548338 | 01 eerste verdieping | 01 eerste verdieping | Up to level: 01 eerste verdieping | Wall Centerline | 910 | 2820 | 1910 | 3.97917 | 2083.33 | 0.00795833 | Workset1 | RVS-kabelnet
2548339 | 01 eerste verdieping | 01 eerste verdieping | Up to level: 01 eerste verdieping | Wall Centerline | 910 | 2820 | 1910 | 3.8165 | 1998.17 | 0.00763299 | Workset1 | RVS-kabelnet
2548435 | 01 eerste verdieping | 01 eerste verdieping | Up to level: 01 eerste verdieping | Wall Centerline | 910 | 2820 | 1910 | 3.01207 | 1577 | 0.00602414 | Workset1 | RVS-kabelnet
2548436 | 01 eerste verdieping | 01 eerste verdieping | Up to level: 01 eerste verdieping | Wall Centerline | 910 | 2810 | 1900 | 3.61 | 1900 | 0.00722 | Workset1 | RVS-kabelnet
2548437 | 01 eerste verdieping | 01 eerste verdieping | Up to level: 01 eerste verdieping | Wall Centerline | 910 | 2810 | 1900 | 3.61 | 1900 | 0.00722 | Workset1 | RVS-kabelnet
2548438 | 01 eerste verdieping | 01 eerste verdieping | Up to level: 01 eerste verdieping | Wall Centerline | 910 | 2820 | 1910 | 3.629 | 1900 | 0.007258 | Workset1 | RVS-kabelnet
2548439 | 01 eerste verdieping | 01 eerste verdieping | Up to level: 01 eerste verdieping | Wall Centerline | 910 | 2820 | 1910 | 3.629 | 1900 | 0.007258 | Workset1 | RVS-kabelnet
2548441 | 01 eerste verdieping | 01 eerste verdieping | Up to level: 01 eerste verdieping | Wall Centerline | 340 | 2820 | 2480 | 2.1328 | 860 | 0.0042656 | Workset1 | RVS-kabelnet
2548442 | 01 eerste verdieping | 01 eerste verdieping | Up to level: 01 eerste verdieping | Wall Centerline | 910 | 2820 | 1910 | 0.178628 | 93.5227 | 0.000357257 | Workset1 | RVS-kabelnet
2548444 | 01 eerste verdieping | 01 eerste verdieping | Up to level: 01 eerste verdieping | Wall Centerline | 910 | 2820 | 1910 | 1.8909 | 990 | 0.0037818 | Workset1 | RVS-kabelnet
2548451 | 01 eerste verdieping | 01 eerste verdieping | Up to level: 01 eerste verdieping | Wall Centerline | 910 | 2820 | 1910 | 3.629 | 1900 | 0.007258 | Workset1 | RVS-kabelnet
2548452 | 01 eerste verdieping | 01 eerste verdieping | Up to level: 01 eerste verdieping | Wall Centerline | 910 | 2820 | 1910 | 3.629 | 1900 | 0.007258 | Workset1 | RVS-kabelnet
2548453 | 01 eerste verdieping | 01 eerste verdieping | Up to level: 01 eerste verdieping | Wall Centerline | 910 | 2820 | 1910 | 3.629 | 1900 | 0.007258 | Workset1 | RVS-kabelnet
2548454 | 01 eerste verdieping | 01 eerste verdieping | Up to level: 01 eerste verdieping | Wall Centerline | 910 | 2820 | 1910 | 3.629 | 1900 | 0.007258 | Workset1 | RVS-kabelnet
2548455 | 01 eerste verdieping | 01 eerste verdieping | Up to level: 01 eerste verdieping | Wall Centerline | 910 | 2820 | 1910 | 3.629 | 1900 | 0.007258 | Workset1 | RVS-kabelnet
2548457 | 01 eerste verdieping | 01 eerste verdieping | Up to level: 01 eerste verdieping | Wall Centerline | 910 | 2820 | 1910 | 3.5717 | 1870 | 0.0071434 | Workset1 | RVS-kabelnet
2548458 | 01 eerste verdieping | 01 eerste verdieping | Up to level: 01 eerste verdieping | Wall Centerline | 910 | 2820 | 1910 | 3.629 | 1900 | 0.007258 | Workset1 | RVS-kabelnet
2548461 | 01 eerste verdieping | 01 eerste verdieping | Up to level: 01 eerste verdieping | Wall Centerline | 910 | 2820 | 1910 | 0.88815 | 465 | 0.0017763 | Workset1 | RVS-kabelnet
2550689 | 00 begane grond | 00 begane grond | Up to level: 01 eerste verdieping | Wall Centerline | 840 | 1210 | 4370 | 6.77704 | 6635 | 0.0135541 | Workset1 | RVS-kabelnet
2552096 | 01 eerste verdieping | 01 eerste verdieping | Up to level: 01 eerste verdieping | Wall Centerline | 910 | 2820 | 1910 | 3.629 | 1900 | 0.007258 | Workset1 | RVS-kabelnet
2552160 | 01 eerste verdieping | 01 eerste verdieping | Up to level: 01 eerste verdieping | Wall Centerline | 910 | 2820 | 1910 | 3.629 | 1900 | 0.007258 | Workset1 | RVS-kabelnet
2552168 | 01 eerste verdieping | 01 eerste verdieping | Up to level: 01 eerste verdieping | Wall Centerline | 910 | 2820 | 1910 | 3.629 | 1900 | 0.007258 | Workset1 | RVS-kabelnet
2552178 | 01 eerste verdieping | 01 eerste verdieping | Up to level: 01 eerste verdieping | Wall Centerline | 910 | 2820 | 1910 | 3.629 | 1900 | 0.007258 | Workset1 | RVS-kabelnet
2552190 | 01 eerste verdieping | 01 eerste verdieping | Up to level: 01 eerste verdieping | Wall Centerline | 910 | 2820 | 1910 | 3.629 | 1900 | 0.007258 | Workset1 | RVS-kabelnet
2552200 | 01 eerste verdieping | 01 eerste verdieping | Up to level: 01 eerste verdieping | Wall Centerline | 910 | 2820 | 1910 | 3.629 | 1900 | 0.007258 | Workset1 | RVS-kabelnet
2552380 | 02 tweede verdieping | 02 tweede verdieping | Up to level: 02 tweede verdieping | Finish Face: Exterior | 313 | 1200 | 887 | 3.50365 | 3949 | 0.0070073 | Workset1
2552381 | 02 tweede verdieping | 02 tweede verdieping | Up to level: 02 tweede verdieping | Finish Face: Exterior | 313 | 1200 | 887 | 18.5605 | 20925 | 0.0371209 | Workset1
2552382 | 02 tweede verdieping | 02 tweede verdieping | Up to level: 02 tweede verdieping | Finish Face: Exterior | 313 | 1200 | 887 | 0.597457 | 673.57 | 0.00119491 | Workset1
2554835 | 02 tweede verdieping | 02 tweede verdieping | Up to level: 02 tweede verdieping | Finish Face: Exterior | 550 | 1180 | 630 | 4.12594 | 5130 | 0.00825188 | Workset1 | RVS-kabelnet
2554836 | 02 tweede verdieping | 02 tweede verdieping | Up to level: 02 tweede verdieping | Finish Face: Exterior | 313 | 1200 | 887 | 6.26932 | 7069 | 0.0125386 | Workset1
2554837 | 02 tweede verdieping | 02 tweede verdieping | Up to level: 02 tweede verdieping | Finish Face: Exterior | 500 | 1200 | 700 | 3.39278 | 3769 | 0.00678556 | Workset1
2556082 | 01 eerste verdieping | 01 eerste verdieping | Up to level: 01 eerste verdieping | Wall Centerline | 910 | 2850 | 1940 | 3.686 | 1900 | 0.007372 | Workset1 | RVS-kabelnet
2772869 | 01 eerste verdieping | 01 eerste verdieping | Up to level: 01 eerste verdieping | Wall Centerline | 300 | 2850 | 2550 | 4.78125 | 1875 | 0.0095625 | Workset1 | RVS-kabelnet
2772870 | 01 eerste verdieping | 01 eerste verdieping | Up to level: 01 eerste verdieping | Wall Centerline | 300 | 2850 | 2550 | 4.78125 | 1875 | 0.0095625 | Workset1 | RVS-kabelnet
2772877 | 01 eerste verdieping | 01 eerste verdieping | Up to level: 01 eerste verdieping | Wall Centerline | 300 | 2850 | 2550 | 4.845 | 1900 | 0.00969 | Workset1 | RVS-kabelnet
3220557 | 02 tweede verdieping | 02 tweede verdieping | Up to level: 02 tweede verdieping | Finish Face: Exterior | 313 | 1200 | 887 | 1.3462 | 1680 | 0.00269241 | Workset1
4034411 | 02 tweede verdieping | 02 tweede verdieping | Up to level: 02 tweede verdieping | Finish Face: Exterior | 550 | 1180 | 630 | 4.27467 | 5130 | 0.00854934 | BDG_fietsenstalling | RVS-kabelnet
4034443 | 02 tweede verdieping | 02 tweede verdieping | Up to level: 02 tweede verdieping | Finish Face: Exterior | 550 | 1180 | 630 | 4.27467 | 5130 | 0.00854934 | BDG_fietsenstalling | RVS-kabelnet

# IfcWallStandardCase: Basic Wall:NLRS_20_WA_glas 8, Basic Wall:NLRS_20_WA_glas 8:3270059
In: 01 eerste verdieping
Type - PredefinedType: STANDARD; Material: ISR_Glas 8 mm
Type - Analytical Properties - Roughness: 1; Absorptance: 0.1
Type - Graphics - Coarse Scale Fill Pattern: <Solid fill>; Coarse Scale Fill Color: 4210752
Type - Construction - Wrapping at Inserts: Do not wrap; Function: Exterior; Width: 8 mm
Type - Identity Data - Workset: Wall Types; Description: basis 100mm; Model: LOD200; SmartRevit_Versie: 2018.2; Type Name: NLRS_20_WA_glas 8
Type - Other - Category: Walls; Family Name: Basic Wall
Cross-Section Definition - Cross-Section: Vertical
Constraints - Base Extension Distance: 0 mm; Base is Attached: no; Related to Mass: no; Room Bounding: yes; Top Extension Distance: 0 mm; Top is Attached: no; Base Constraint: 01 eerste verdieping; Top Constraint: Up to level: 01 eerste verdieping; Location Line: Wall Centerline; Base Offset: 860 mm; Top Offset: 2820 mm; Unconnected Height: 1960 mm
Phasing - Phase Created: 2. nieuwbouw
Structural - Enable Analytical Model: no; Structural: no; Structural Usage: Non-bearing
Dimensions - Area: 0.588 m2; Length: 300 mm; Volume: 0.004704 m3
Identity Data - Workset: Workset1; Comments: RVS-kabelnet
Other - Family: Basic Wall; Family and Type: Basic Wall: NLRS_20_WA_glas 8; Type: NLRS_20_WA_glas 8; Type Id: 3270067

# IfcWallStandardCase: Basic Wall:NLRS_20_WA_staalmat (17)
In: 00 begane grond
Type - PredefinedType: STANDARD; Material: ISR_staalmat 2 mm
Type - Analytical Properties - Roughness: 1; Absorptance: 0.1
Type - Graphics - Coarse Scale Fill Pattern: <Solid fill>; Coarse Scale Fill Color: 4210752
Type - Construction - Wrapping at Inserts: Do not wrap; Function: Exterior; Width: 2 mm
Type - Identity Data - Workset: Wall Types; Description: basis 100mm; Model: LOD200; SmartRevit_Versie: 2018.2; Type Name: NLRS_20_WA_staalmat
Type - Other - Category: Walls; Family Name: Basic Wall
Cross-Section Definition - Cross-Section: Vertical
Constraints - Base Extension Distance: 0 mm; Base is Attached: no; Related to Mass: no; Room Bounding: yes; Top Extension Distance: 0 mm; Top is Attached: no; Top Offset: 0 mm; Base Constraint: 00 begane grond; Location Line: Wall Centerline
Phasing - Phase Created: 2. nieuwbouw
Structural - Enable Analytical Model: no; Structural: no; Structural Usage: Non-bearing
Identity Data - Workset: BDG_fietsenstalling
Other - Family: Basic Wall; Family and Type: Basic Wall: NLRS_20_WA_staalmat; Type: NLRS_20_WA_staalmat; Type Id: 4065370
Name (Basic Wall:NLRS_20_WA_staalmat:...) | Base Offset (mm) | Unconnected Height (mm) | Area (m2) | Length (mm) | Volume (m3) | Group
4034548 | 0 | 4000 | 4.85365 | 2300 | 0.0097073 | Model Group:fietsenstalling:4188142
4034939 | 0 | 4000 | 4.73825 | 2300 | 0.0094765 | Model Group:fietsenstalling:4188142
4036020 | 0 | 2000 | 4.862 | 2431 | 0.009724 | Model Group:fietsenstalling:4188142
4036168 | 0 | 1970 | 4.66299 | 2367 | 0.00932598 | Model Group:fietsenstalling:4188142
4036249 | 0 | 1970 | 4.66299 | 2367 | 0.00932598 | Model Group:fietsenstalling:4188142
4036347 | 0 | 2000 | 4.734 | 2367 | 0.009468 | Model Group:fietsenstalling:4188142
4036435 | 0 | 2000 | 4.734 | 2367 | 0.009468 | Model Group:fietsenstalling:4188142
4158222 | 60 | 2080 | 1.99368 | 958.5 | 0.00398736 | Model Group:enkele deur-kokers:4158221
4158257 | 60 | 2080 | 1.99368 | 958.5 | 0.00398736 | Model Group:enkele deur-kokers:4158256
4158446 | 60 | 2080 | 1.99368 | 958.5 | 0.00398736 | Model Group:enkele deur-kokers:4158445
4158458 | 60 | 2080 | 1.99368 | 958.5 | 0.00398736 | Model Group:enkele deur-kokers:4158457
4158498 | 60 | 2080 | 1.99368 | 958.5 | 0.00398736 | Model Group:enkele deur-kokers:4158497
4158510 | 60 | 2080 | 1.99368 | 958.5 | 0.00398736 | Model Group:enkele deur-kokers:4158509
4158524 | 60 | 2080 | 1.99368 | 958.5 | 0.00398736 | Model Group:enkele deur-kokers:4158523
4158536 | 60 | 2080 | 1.99368 | 958.5 | 0.00398736 | Model Group:enkele deur-kokers:4158535
4158550 | 60 | 2080 | 1.99368 | 958.5 | 0.00398736 | Model Group:enkele deur-kokers:4158549
4158562 | 60 | 2080 | 1.99368 | 958.5 | 0.00398736 | Model Group:enkele deur-kokers:4158561

# IfcWallStandardCase: Basic Wall:NLRS_21_WA_iso hard 105_gen_ISR, Basic Wall:NLRS_21_WA_iso hard 105_gen_ISR:3484583
In: 01 eerste verdieping
Type - PredefinedType: STANDARD; Material: n7_isolatie_Resol 105 mm
Type - Analytical Properties - Roughness: 1; Absorptance: 0.1
Type - Graphics - Coarse Scale Fill Pattern: <Solid fill>; Coarse Scale Fill Color: 4210752
Type - Construction - Wrapping at Inserts: Do not wrap; Function: Exterior; Width: 105 mm
Type - Identity Data - Workset: Wall Types; Assembly Code: 21.10; Assembly Description: buitenwanden; niet constructief, algemeen (verzamelniveau); Description: harde isolatie 100mm; Model: LOD300; SmartRevit_Versie: 2018.2; Type Name: NLRS_21_WA_iso hard 105_gen_ISR
Type - Other - Category: Walls; Family Name: Basic Wall
Classification: 21.10 Uniformat (Uniformat)
Cross-Section Definition - Cross-Section: Vertical
Constraints - Base Extension Distance: 0 mm; Base is Attached: no; Location Line: Finish Face: Exterior; Related to Mass: no; Room Bounding: yes; Top Extension Distance: 0 mm; Top is Attached: no; Base Constraint: 01 eerste verdieping; Top Offset: 0 mm; Top Constraint: Up to level: 02 bk. ruwe vloer; Base Offset: 450 mm; Unconnected Height: 3300 mm
Phasing - Phase Created: 2. nieuwbouw
Structural - Enable Analytical Model: no; Structural: no; Structural Usage: Non-bearing
Dimensions - Area: 1.31505 m2; Length: 398.5 mm; Volume: 0.13808 m3
Identity Data - Workset: Workset1
Other - Family: Basic Wall; Family and Type: Basic Wall: NLRS_21_WA_iso hard 105_gen_ISR; Type: NLRS_21_WA_iso hard 105_gen_ISR; Type Id: 3484505

# IfcWallStandardCase: Basic Wall:NLRS_21_WA_iso hard 140_gen_ISR (12)
Type - PredefinedType: STANDARD; Material: n7_isolatie_Resol 140 mm
Type - Analytical Properties - Roughness: 1; Absorptance: 0.1
Type - Graphics - Coarse Scale Fill Pattern: <Solid fill>; Coarse Scale Fill Color: 4210752
Type - Construction - Wrapping at Inserts: Do not wrap; Function: Exterior; Width: 140 mm
Type - Identity Data - Workset: Wall Types; Assembly Code: 21.10; Assembly Description: buitenwanden; niet constructief, algemeen (verzamelniveau); Description: harde isolatie 100mm; Model: LOD300; SmartRevit_Versie: 2018.2; Type Name: NLRS_21_WA_iso hard 140_gen_ISR
Type - Other - Category: Walls; Family Name: Basic Wall
Classification: 21.10 Uniformat (Uniformat)
Cross-Section Definition - Cross-Section: Vertical
Constraints - Base Extension Distance: 0 mm; Base is Attached: no; Related to Mass: no; Room Bounding: yes; Top Extension Distance: 0 mm; Top is Attached: no
Phasing - Phase Created: 2. nieuwbouw
Structural - Enable Analytical Model: no; Structural: no; Structural Usage: Non-bearing
Identity Data - Workset: Workset1
Other - Family: Basic Wall; Family and Type: Basic Wall: NLRS_21_WA_iso hard 140_gen_ISR; Type: NLRS_21_WA_iso hard 140_gen_ISR; Type Id: 2247446
Name (Basic Wall:NLRS_21_WA_iso hard 140_gen_ISR:...) | In | Top Constraint | Location Line | Base Constraint | Base Offset (mm) | Top Offset (mm) | Unconnected Height (mm) | Area (m2) | Length (mm) | Volume (m3)
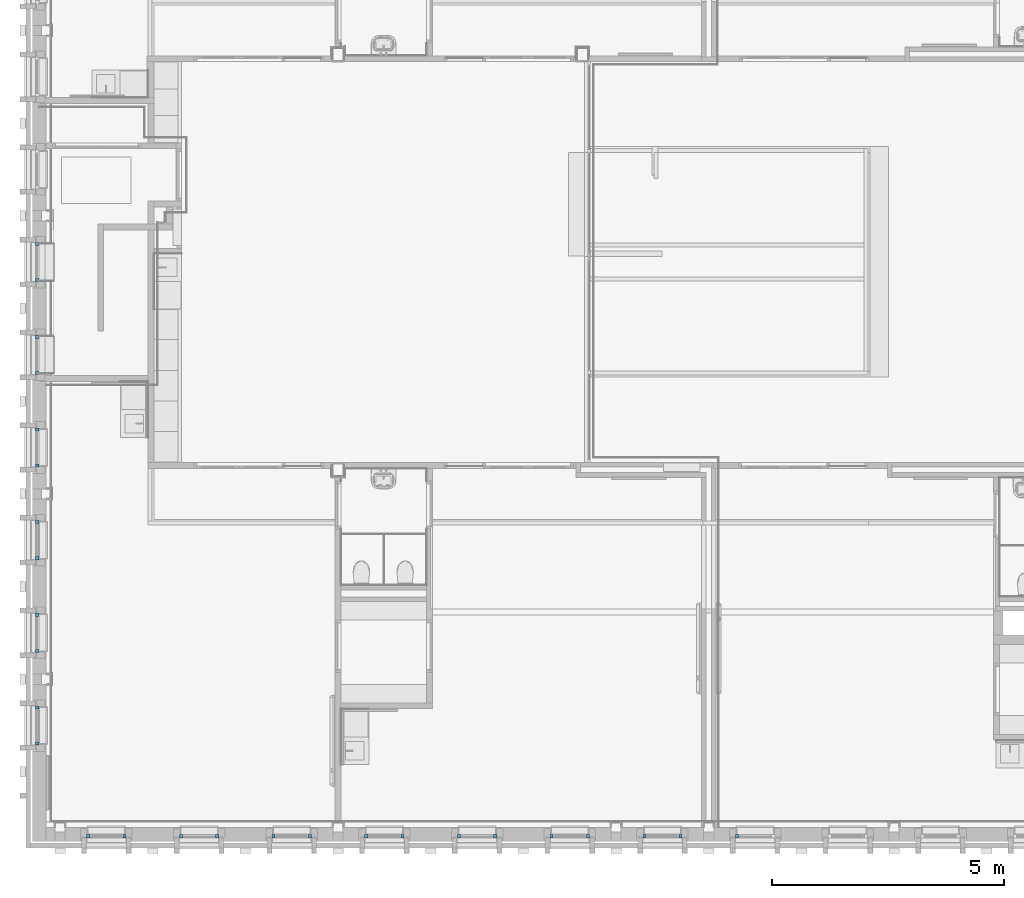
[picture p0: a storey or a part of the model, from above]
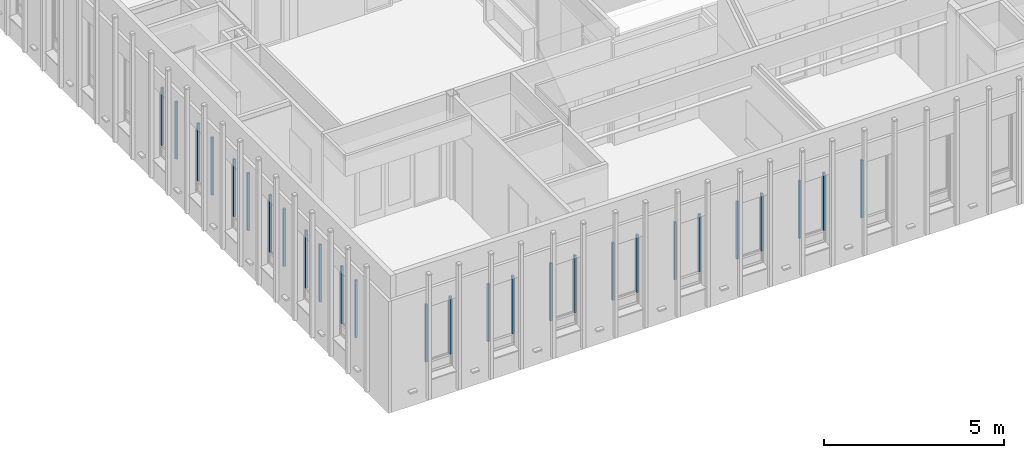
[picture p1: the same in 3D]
Properties of the parts of a building model (IFC2X3), part 89 of 94

# IfcWallStandardCase: Basic Wall:NLRS_21_WA_iso hard 140_gen_ISR (12)
Name (Basic Wall:NLRS_21_WA_iso hard 140_gen_ISR:...) | In | Top Constraint | Location Line | Base Constraint | Base Offset (mm) | Top Offset (mm) | Unconnected Height (mm) | Area (m2) | Length (mm) | Volume (m3)
2118479 | 01 eerste verdieping | Up to level: 02 tweede verdieping | Finish Face: Interior | 02 ok. ruwe vloer | -295 | -30 | 635 | 6.29433 | 9982.34 | 0.881207
2118777 | 01 eerste verdieping | Up to level: 02 tweede verdieping | Finish Face: Interior | 02 ok. ruwe vloer | -345 | -30 | 685 | 20.1356 | 29535 | 2.81898
2118885 | 01 eerste verdieping | Up to level: 02 tweede verdieping | Finish Face: Interior | 02 ok. ruwe vloer | -345 | -30 | 685 | 20.3411 | 29625 | 2.84775
2119108 | 01 eerste verdieping | Up to level: 02 tweede verdieping | Finish Face: Interior | 02 ok. ruwe vloer | -375 | -370 | 375 | 1.31062 | 3495 | 0.183487
2119978 | 00 begane grond | Up to level: 01 eerste verdieping | Finish Face: Interior | 01 ok. ruwe vloer | -345 | -30 | 685 | 20.1493 | 29495 | 2.8209
2119979 | 00 begane grond | Up to level: 01 eerste verdieping | Finish Face: Interior | 01 ok. ruwe vloer | -345 | -30 | 685 | 20.1691 | 29595 | 2.82367
2555481 | 01 eerste verdieping | Up to level: 01 eerste verdieping | Finish Face: Exterior | 01 eerste verdieping | -765 | -50 | 715 | 9.15558 | 12805 | 1.28178
2556339 | 01 eerste verdieping | Up to level: 01 eerste verdieping | Finish Face: Exterior | 01 eerste verdieping | -760 | -50 | 710 | 9.09155 | 12805 | 1.27282
2898725 | 01 eerste verdieping | Up to level: 02 tweede verdieping | Finish Face: Interior | 02 ok. ruwe vloer | -295 | -30 | 635 | 7.48199 | 11712.7 | 1.04748
2898799 | 01 eerste verdieping | Up to level: 02 tweede verdieping | Finish Face: Interior | 02 ok. ruwe vloer | -295 | -350 | 315 | 0.990675 | 3145 | 0.138694
3451442 | 01 eerste verdieping | Up to level: 02 dakrand gymzaal | Core Face: Interior | 02 dakrand gymzaal | -95 | 550 | 645 | 1.6641 | 2580 | 0.232974
3571998 | 01 eerste verdieping | Up to level: 02 tweede verdieping | Finish Face: Interior | 02 ok. ruwe vloer | -375 | -50 | 695 | 14.6541 | 21015 | 2.05157

# IfcWallStandardCase: Basic Wall:NLRS_21_WA_iso hard 160_gen_ISR, Basic Wall:NLRS_21_WA_iso hard 160_gen_ISR:4736299
In: 00 begane grond
Type - PredefinedType: STANDARD; Material: n7_isolatie_Resol 160 mm
Type - Analytical Properties - Roughness: 1; Absorptance: 0.1
Type - Graphics - Coarse Scale Fill Pattern: <Solid fill>; Coarse Scale Fill Color: 4210752
Type - Construction - Wrapping at Inserts: Do not wrap; Function: Exterior; Width: 160 mm
Type - Identity Data - Workset: Wall Types; Assembly Code: 21.10; Assembly Description: buitenwanden; niet constructief, algemeen (verzamelniveau); Description: harde isolatie 100mm; Model: LOD300; SmartRevit_Versie: 2018.2; Type Name: NLRS_21_WA_iso hard 160_gen_ISR
Type - Other - Category: Walls; Family Name: Basic Wall
Classification: 21.10 Uniformat (Uniformat)
Cross-Section Definition - Cross-Section: Vertical
Constraints - Base Extension Distance: 0 mm; Base is Attached: no; Related to Mass: no; Room Bounding: yes; Top Extension Distance: 0 mm; Top is Attached: no; Top Constraint: Up to level: 01 eerste verdieping; Location Line: Finish Face: Interior; Base Constraint: 01 ok. ruwe vloer; Base Offset: -295 mm; Top Offset: -30 mm; Unconnected Height: 635 mm
Phasing - Phase Created: 2. nieuwbouw
Structural - Enable Analytical Model: no; Structural: no; Structural Usage: Non-bearing
Dimensions - Area: 7.10565 m2; Length: 11120 mm; Volume: 1.1369 m3
Identity Data - Workset: Workset1
Other - Family: Basic Wall; Family and Type: Basic Wall: NLRS_21_WA_iso hard 160_gen_ISR; Type: NLRS_21_WA_iso hard 160_gen_ISR; Type Id: 2118386

# IfcWallStandardCase: Basic Wall:NLRS_21_WA_iso hard 190_gen_ISR (2)
In: 01 eerste verdieping
Type - PredefinedType: STANDARD; Material: n7_isolatie_Resol 190 mm
Type - Analytical Properties - Roughness: 1; Absorptance: 0.1
Type - Graphics - Coarse Scale Fill Pattern: <Solid fill>; Coarse Scale Fill Color: 4210752
Type - Construction - Wrapping at Inserts: Do not wrap; Function: Exterior; Width: 190 mm
Type - Identity Data - Workset: Wall Types; Assembly Code: 21.10; Assembly Description: buitenwanden; niet constructief, algemeen (verzamelniveau); Description: harde isolatie 100mm; Model: LOD300; SmartRevit_Versie: 2018.2; Type Name: NLRS_21_WA_iso hard 190_gen_ISR
Type - Other - Category: Walls; Family Name: Basic Wall
Classification: 21.10 Uniformat (Uniformat)
Cross-Section Definition - Cross-Section: Vertical
Constraints - Base Extension Distance: 0 mm; Base is Attached: no; Location Line: Finish Face: Exterior; Related to Mass: no; Room Bounding: yes; Top Extension Distance: 0 mm; Top is Attached: no; Base Constraint: 01 eerste verdieping; Top Constraint: Up to level: 02 bk. ruwe vloer; Base Offset: 450 mm
Phasing - Phase Created: 2. nieuwbouw
Structural - Enable Analytical Model: no; Structural: no; Structural Usage: Non-bearing
Identity Data - Workset: Workset1
Other - Family: Basic Wall; Family and Type: Basic Wall: NLRS_21_WA_iso hard 190_gen_ISR; Type: NLRS_21_WA_iso hard 190_gen_ISR; Type Id: 3483934
Name (Basic Wall:NLRS_21_WA_iso hard 190_gen_ISR:...) | Top Offset (mm) | Unconnected Height (mm) | Area (m2) | Length (mm) | Volume (m3)
3484148 | 0 | 3300 | 0.7161 | 217 | 0.136059
4345747 | -695 | 2605 | 0.5731 | 220 | 0.108889

# IfcWallStandardCase: Basic Wall:NLRS_21_WA_iso hard 60_gen_ISR, Basic Wall:NLRS_21_WA_iso hard 60_gen_ISR:4931368
In: 00 begane grond
Type - PredefinedType: STANDARD; Material: n7_isolatie_Resol 60 mm
Type - Analytical Properties - Roughness: 1; Absorptance: 0.1
Type - Graphics - Coarse Scale Fill Pattern: <Solid fill>; Coarse Scale Fill Color: 4210752
Type - Construction - Wrapping at Inserts: Do not wrap; Function: Exterior; Width: 60 mm
Type - Identity Data - Workset: Wall Types; Assembly Code: 21.10; Assembly Description: buitenwanden; niet constructief, algemeen (verzamelniveau); Description: harde isolatie 100mm; Model: LOD300; SmartRevit_Versie: 2018.2; Type Name: NLRS_21_WA_iso hard 60_gen_ISR
Type - Other - Category: Walls; Family Name: Basic Wall
Classification: 21.10 Uniformat (Uniformat)
Cross-Section Definition - Cross-Section: Vertical
Constraints - Base Extension Distance: 0 mm; Base is Attached: no; Related to Mass: no; Room Bounding: yes; Top Extension Distance: 0 mm; Top is Attached: no; Top Offset: 0 mm; Location Line: Finish Face: Interior; Base Constraint: 01 ok. ruwe vloer; Top Constraint: Up to level: 01 bk. ruwe vloer; Base Offset: -285 mm; Unconnected Height: 605 mm
Phasing - Phase Created: 2. nieuwbouw
Structural - Enable Analytical Model: no; Structural: no; Structural Usage: Non-bearing
Dimensions - Area: 2.8072 m2; Length: 4640 mm; Volume: 0.168432 m3
Identity Data - Workset: Workset1
Other - Family: Basic Wall; Family and Type: Basic Wall: NLRS_21_WA_iso hard 60_gen_ISR; Type: NLRS_21_WA_iso hard 60_gen_ISR; Type Id: 4931475

# IfcWallStandardCase: Basic Wall:NLRS_22_WA_HSB bispouw 100_gen_ISR (9)
In: 00 begane grond
Type - PredefinedType: STANDARD; Material: n7_isolatie_Resol 100 mm
Type - Analytical Properties - Roughness: 1; Absorptance: 0.1
Type - Materials and Finishes - Structural Material: n7_isolatie_Resol
Type - Graphics - Coarse Scale Fill Pattern: <Solid fill>; Coarse Scale Fill Color: 4210752
Type - Construction - Function: Interior; Wrapping at Inserts: Do not wrap; Width: 100 mm
Type - Identity Data - Workset: Wall Types; Assembly Code: 21.10; Assembly Description: buitenwanden; niet constructief, algemeen (verzamelniveau); Description: gevelsluitend element; SmartRevit_Versie: 2018.2; Type Name: NLRS_22_WA_HSB bispouw 100_gen_ISR
Type - Other - Category: Walls; Family Name: Basic Wall
Classification: 21.10 Uniformat (Uniformat)
Cross-Section Definition - Cross-Section: Vertical
Constraints - Base Extension Distance: 0 mm; Base is Attached: no; Location Line: Finish Face: Exterior; Related to Mass: no; Room Bounding: yes; Top Extension Distance: 0 mm; Top is Attached: no; Base Constraint: 00 begane grond; Top Constraint: Up to level: 02 bk. constructie gymzaal; Base Offset: -30 mm; Top Offset: -143 mm; Unconnected Height: 6387 mm
Phasing - Phase Created: 2. nieuwbouw
Structural - Enable Analytical Model: no; Structural: no; Structural Usage: Non-bearing
Identity Data - Workset: Workset1
Other - Family: Basic Wall; Family and Type: Basic Wall: NLRS_22_WA_HSB bispouw 100_gen_ISR; Type: NLRS_22_WA_HSB bispouw 100_gen_ISR; Type Id: 2728154
Name (Basic Wall:NLRS_22_WA_HSB bispouw 100_gen_ISR:...) | Area (m2) | Length (mm) | Volume (m3)
2728984 | 1.66062 | 260 | 0.166062
2729396 | 1.66062 | 260 | 0.166062
2729778 | 1.66062 | 260 | 0.166062
2732133 | 1.59675 | 300 | 0.159675
2732185 | 2.23545 | 300 | 0.223545
2732500 | 1.66062 | 260 | 0.166062
2732823 | 1.66062 | 260 | 0.166062
2733018 | 1.66062 | 260 | 0.166062
2733223 | 2.10771 | 290 | 0.210771

# IfcWallStandardCase: Basic Wall:NLRS_22_WA_HSB bispouw 140-12-13 resol_gen_ISR, Basic Wall:NLRS_22_WA_HSB bispouw 140-12-13 resol_gen_ISR:3627860
In: 00 begane grond
Type - PredefinedType: STANDARD; Material: n7_isolatie_Resol 140 mm, i4_multiplex 12 mm, f7_gipsvezel 13 mm
Type - Analytical Properties - Roughness: 1; Absorptance: 0.1
Type - Materials and Finishes - Structural Material: n7_isolatie_Resol
Type - Graphics - Coarse Scale Fill Pattern: <Solid fill>; Coarse Scale Fill Color: 4210752
Type - Construction - Function: Interior; Wrapping at Inserts: Do not wrap; Width: 165 mm
Type - Identity Data - Workset: Wall Types; Assembly Code: 21.10; Assembly Description: buitenwanden; niet constructief, algemeen (verzamelniveau); Description: gevelsluitend element; SmartRevit_Versie: 2018.2; Type Name: NLRS_22_WA_HSB bispouw 140-12-13 resol_gen_ISR
Type - Other - Category: Walls; Family Name: Basic Wall
Classification: 21.10 Uniformat (Uniformat)
Cross-Section Definition - Cross-Section: Vertical
Constraints - Base Extension Distance: 0 mm; Base is Attached: no; Related to Mass: no; Room Bounding: yes; Top Extension Distance: 0 mm; Top is Attached: no; Base Constraint: 00 begane grond; Top Constraint: Up to level: 01 ok. ruwe vloer; Location Line: Finish Face: Interior; Base Offset: 3502 mm; Top Offset: 142 mm; Unconnected Height: 270 mm
Phasing - Phase Created: 2. nieuwbouw
Structural - Enable Analytical Model: no; Structural: no; Structural Usage: Non-bearing
Dimensions - Area: 2.98431 m2; Length: 11053 mm; Volume: 0.492411 m3
Identity Data - Workset: Workset1
Other - Family: Basic Wall; Family and Type: Basic Wall: NLRS_22_WA_HSB bispouw 140-12-13 resol_gen_ISR; Type: NLRS_22_WA_HSB bispouw 140-12-13 resol_gen_ISR; Type Id: 3627897

# IfcWallStandardCase: Basic Wall:NLRS_22_WA_HSB bispouw 160_gen_ISR, Basic Wall:NLRS_22_WA_HSB bispouw 160_gen_ISR:2349733
In: 00 begane grond
Type - PredefinedType: STANDARD; Material: n7_isolatie_Resol 160 mm
Type - Analytical Properties - Roughness: 1; Absorptance: 0.1
Type - Materials and Finishes - Structural Material: n7_isolatie_Resol
Type - Graphics - Coarse Scale Fill Pattern: <Solid fill>; Coarse Scale Fill Color: 4210752
Type - Construction - Function: Interior; Wrapping at Inserts: Do not wrap; Width: 160 mm
Type - Identity Data - Workset: Wall Types; Assembly Code: 21.10; Assembly Description: buitenwanden; niet constructief, algemeen (verzamelniveau); Description: gevelsluitend element; SmartRevit_Versie: 2018.2; Type Name: NLRS_22_WA_HSB bispouw 160_gen_ISR
Type - Other - Category: Walls; Family Name: Basic Wall
Classification: 21.10 Uniformat (Uniformat)
Cross-Section Definition - Cross-Section: Vertical
Constraints - Base Extension Distance: 0 mm; Base is Attached: no; Location Line: Finish Face: Exterior; Related to Mass: no; Room Bounding: yes; Top Extension Distance: 0 mm; Top is Attached: no; Base Constraint: 00 begane grond; Top Constraint: Up to level: 01 ok. ruwe vloer; Base Offset: -30 mm; Top Offset: -220 mm; Unconnected Height: 3440 mm
Phasing - Phase Created: 2. nieuwbouw
Structural - Enable Analytical Model: no; Structural: no; Structural Usage: Non-bearing
Dimensions - Area: 1.032 m2; Length: 300 mm; Volume: 0.16512 m3
Identity Data - Workset: Workset1
Other - Family: Basic Wall; Family and Type: Basic Wall: NLRS_22_WA_HSB bispouw 160_gen_ISR; Type: NLRS_22_WA_HSB bispouw 160_gen_ISR; Type Id: 2733463

# IfcWallStandardCase: Basic Wall:NLRS_22_WA_HSB bispouw 180_gen_ISR (21)
Type - PredefinedType: STANDARD; Material: n7_isolatie_Resol 180 mm
Type - Analytical Properties - Roughness: 1; Absorptance: 0.1
Type - Materials and Finishes - Structural Material: n7_isolatie_Resol
Type - Graphics - Coarse Scale Fill Pattern: <Solid fill>; Coarse Scale Fill Color: 4210752
Type - Construction - Function: Interior; Wrapping at Inserts: Do not wrap; Width: 180 mm
Type - Identity Data - Workset: Wall Types; Assembly Code: 21.10; Assembly Description: buitenwanden; niet constructief, algemeen (verzamelniveau); Description: gevelsluitend element; SmartRevit_Versie: 2018.2; Type Name: NLRS_22_WA_HSB bispouw 180_gen_ISR
Type - Other - Category: Walls; Family Name: Basic Wall
Classification: 21.10 Uniformat (Uniformat)
Cross-Section Definition - Cross-Section: Vertical
Constraints - Base Extension Distance: 0 mm; Base is Attached: no; Location Line: Finish Face: Exterior; Related to Mass: no; Room Bounding: yes; Top Extension Distance: 0 mm; Top is Attached: no; Base Offset: -30 mm
Phasing - Phase Created: 2. nieuwbouw
Structural - Enable Analytical Model: no; Structural: no; Structural Usage: Non-bearing
Identity Data - Workset: Workset1
Other - Family: Basic Wall; Family and Type: Basic Wall: NLRS_22_WA_HSB bispouw 180_gen_ISR; Type: NLRS_22_WA_HSB bispouw 180_gen_ISR; Type Id: 897588
Name (Basic Wall:NLRS_22_WA_HSB bispouw 180_gen_ISR:...) | In | Base Constraint | Top Constraint | Top Offset (mm) | Unconnected Height (mm) | Area (m2) | Length (mm) | Volume (m3)
897843 | 00 begane grond | 00 begane grond | Up to level: 01 ok. ruwe vloer | -220 | 3440 | 0.4472 | 130 | 0.080496
897870 | 00 begane grond | 00 begane grond | Up to level: 01 ok. ruwe vloer | -220 | 3440 | 0.4472 | 130 | 0.080496 | Group: Model Group:21_hsb_v0_A:897872
897871 | 00 begane grond | 00 begane grond | Up to level: 01 ok. ruwe vloer | -220 | 3440 | 0.4472 | 130 | 0.080496 | Group: Model Group:21_hsb_v0_A:897872
1219765 | 00 begane grond | 00 begane grond | Up to level: 01 ok. ruwe vloer | -220 | 3440 | 0.8944 | 260 | 0.160992
1219766 | 00 begane grond | 00 begane grond | Up to level: 01 ok. ruwe vloer | -220 | 3440 | 0.4472 | 130 | 0.080496
1221338 | 00 begane grond | 00 begane grond | Up to level: 01 ok. ruwe vloer | -220 | 3440 | 0.4472 | 130 | 0.080496
1221339 | 00 begane grond | 00 begane grond | Up to level: 01 ok. ruwe vloer | -220 | 3440 | 0.8944 | 260 | 0.160992
1221592 | 00 begane grond | 00 begane grond | Up to level: 01 ok. ruwe vloer | -220 | 3440 | 0.8944 | 260 | 0.160992
1222347 | 00 begane grond | 00 begane grond | Up to level: 01 ok. ruwe vloer | -220 | 3440 | 0.4472 | 130 | 0.080496 | Group: Model Group:21_hsb_v0_A:1222349
1222348 | 00 begane grond | 00 begane grond | Up to level: 01 ok. ruwe vloer | -220 | 3440 | 0.4472 | 130 | 0.080496 | Group: Model Group:21_hsb_v0_A:1222349
1223367 | 00 begane grond | 00 begane grond | Up to level: 01 ok. ruwe vloer | -220 | 3440 | 0.4472 | 130 | 0.080496
2339610 | 02 tweede verdieping | 02 tweede verdieping | Up to level: 03 bk. ruwe vloer | -340 | 3440 | 0.29756 | 86.5 | 0.0535608
2340773 | 02 tweede verdieping | 02 tweede verdieping | Up to level: 03 bk. ruwe vloer | -340 | 3440 | 0.60716 | 176.5 | 0.109289
2346250 | 00 begane grond | 00 begane grond | Up to level: 01 ok. ruwe vloer | -220 | 3440 | 0.8944 | 260 | 0.160992
2346764 | 00 begane grond | 00 begane grond | Up to level: 01 ok. ruwe vloer | -220 | 3440 | 0.53664 | 156 | 0.0965952
2347245 | 00 begane grond | 00 begane grond | Up to level: 01 ok. ruwe vloer | -220 | 3440 | 0.8944 | 260 | 0.160992
2347407 | 00 begane grond | 00 begane grond | Up to level: 01 ok. ruwe vloer | -220 | 3440 | 0.8944 | 260 | 0.160992
2347655 | 00 begane grond | 00 begane grond | Up to level: 01 ok. ruwe vloer | -220 | 3440 | 0.45236 | 131.5 | 0.0814248
2348412 | 00 begane grond | 00 begane grond | Up to level: 01 ok. ruwe vloer | -295 | 3365 | 0.440815 | 131 | 0.0793467
2348780 | 00 begane grond | 00 begane grond | Up to level: 01 ok. ruwe vloer | -295 | 3365 | 0.8749 | 260 | 0.157482
2349508 | 00 begane grond | 00 begane grond | Up to level: 01 ok. ruwe vloer | -220 | 3440 | 0.878868 | 267 | 0.158196

# IfcWallStandardCase: Basic Wall:NLRS_22_WA_HSB bispouw 200_gen_ISR (17)
Type - PredefinedType: STANDARD; Material: n7_isolatie_Resol 200 mm
Type - Analytical Properties - Roughness: 1; Absorptance: 0.1
Type - Materials and Finishes - Structural Material: n7_isolatie_Resol
Type - Graphics - Coarse Scale Fill Pattern: <Solid fill>; Coarse Scale Fill Color: 4210752
Type - Construction - Function: Interior; Wrapping at Inserts: Do not wrap; Width: 200 mm
Type - Identity Data - Workset: Wall Types; Assembly Code: 21.10; Assembly Description: buitenwanden; niet constructief, algemeen (verzamelniveau); Description: gevelsluitend element; SmartRevit_Versie: 2018.2; Type Name: NLRS_22_WA_HSB bispouw 200_gen_ISR
Type - Other - Category: Walls; Family Name: Basic Wall
Classification: 21.10 Uniformat (Uniformat)
Cross-Section Definition - Cross-Section: Vertical
Constraints - Base Extension Distance: 0 mm; Base is Attached: no; Location Line: Finish Face: Exterior; Related to Mass: no; Room Bounding: yes; Top Extension Distance: 0 mm; Top is Attached: no; Base Offset: -30 mm; Unconnected Height: 3440 mm
Phasing - Phase Created: 2. nieuwbouw
Structural - Enable Analytical Model: no; Structural: no; Structural Usage: Non-bearing
Dimensions - Area: 0.7568 m2; Length: 220 mm; Volume: 0.15136 m3
Identity Data - Workset: Workset1
Other - Family: Basic Wall; Family and Type: Basic Wall: NLRS_22_WA_HSB bispouw 200_gen_ISR; Type: NLRS_22_WA_HSB bispouw 200_gen_ISR; Type Id: 2576073
Name (Basic Wall:NLRS_22_WA_HSB bispouw 200_gen_ISR:...) | In | Base Constraint | Top Constraint | Top Offset (mm) | Group
2340747 | 02 tweede verdieping | 02 tweede verdieping | Up to level: 03 bk. ruwe vloer | -340 | Model Group:HSB iso 200 tpv. kolom V2:2340748
2574365 | 02 tweede verdieping | 02 tweede verdieping | Up to level: 03 bk. ruwe vloer | -340 | Model Group:HSB iso 200 tpv. kolom V2:2339525
2574368 | 02 tweede verdieping | 02 tweede verdieping | Up to level: 03 bk. ruwe vloer | -340 | Model Group:HSB iso 200 tpv. kolom V2:2339559
2574371 | 02 tweede verdieping | 02 tweede verdieping | Up to level: 03 bk. ruwe vloer | -340 | Model Group:HSB iso 200 tpv. kolom V2:2339574
2574374 | 02 tweede verdieping | 02 tweede verdieping | Up to level: 03 bk. ruwe vloer | -340 | Model Group:HSB iso 200 tpv. kolom V2:2339589
2574377 | 02 tweede verdieping | 02 tweede verdieping | Up to level: 03 bk. ruwe vloer | -340 | Model Group:HSB iso 200 tpv. kolom V2:2339600
2574380 | 02 tweede verdieping | 02 tweede verdieping | Up to level: 03 bk. ruwe vloer | -340 | Model Group:HSB iso 200 tpv. kolom V2:2339636
2574383 | 02 tweede verdieping | 02 tweede verdieping | Up to level: 03 bk. ruwe vloer | -340 | Model Group:HSB iso 200 tpv. kolom V2:2340615
2574386 | 02 tweede verdieping | 02 tweede verdieping | Up to level: 03 bk. ruwe vloer | -340 | Model Group:HSB iso 200 tpv. kolom V2:2340655
2574389 | 02 tweede verdieping | 02 tweede verdieping | Up to level: 03 bk. ruwe vloer | -340 | Model Group:HSB iso 200 tpv. kolom V2:2340666
2574392 | 02 tweede verdieping | 02 tweede verdieping | Up to level: 03 bk. ruwe vloer | -340 | Model Group:HSB iso 200 tpv. kolom V2:2340677
2574395 | 02 tweede verdieping | 02 tweede verdieping | Up to level: 03 bk. ruwe vloer | -340 | Model Group:HSB iso 200 tpv. kolom V2:2340688
2574398 | 02 tweede verdieping | 02 tweede verdieping | Up to level: 03 bk. ruwe vloer | -340 | Model Group:HSB iso 200 tpv. kolom V2:2340699
2574401 | 02 tweede verdieping | 02 tweede verdieping | Up to level: 03 bk. ruwe vloer | -340 | Model Group:HSB iso 200 tpv. kolom V2:2340737
2574404 | 02 tweede verdieping | 02 tweede verdieping | Up to level: 03 bk. ruwe vloer | -340 | Model Group:HSB iso 200 tpv. kolom V2:2340761
2574407 | 02 tweede verdieping | 02 tweede verdieping | Up to level: 03 bk. ruwe vloer | -340 | Model Group:HSB iso 200 tpv. kolom V2:2340838
2734717 | 00 begane grond | 00 begane grond | Up to level: 01 ok. ruwe vloer | -220

# IfcWallStandardCase: Basic Wall:NLRS_22_WA_HSB bispouw 210_gen_ISR (7)
In: 00 begane grond
Type - PredefinedType: STANDARD; Material: n7_isolatie_Resol 210 mm
Type - Analytical Properties - Roughness: 1; Absorptance: 0.1
Type - Materials and Finishes - Structural Material: n7_isolatie_Resol
Type - Graphics - Coarse Scale Fill Pattern: <Solid fill>; Coarse Scale Fill Color: 4210752
Type - Construction - Function: Interior; Wrapping at Inserts: Do not wrap; Width: 210 mm
Type - Identity Data - Workset: Wall Types; Assembly Code: 21.10; Assembly Description: buitenwanden; niet constructief, algemeen (verzamelniveau); Description: gevelsluitend element; SmartRevit_Versie: 2018.2; Type Name: NLRS_22_WA_HSB bispouw 210_gen_ISR
Type - Other - Category: Walls; Family Name: Basic Wall
Classification: 21.10 Uniformat (Uniformat)
Cross-Section Definition - Cross-Section: Vertical
Constraints - Base Extension Distance: 0 mm; Base is Attached: no; Location Line: Finish Face: Exterior; Related to Mass: no; Room Bounding: yes; Top Extension Distance: 0 mm; Top is Attached: no; Base Constraint: 00 begane grond; Top Constraint: Up to level: 01 ok. ruwe vloer; Base Offset: -30 mm
Phasing - Phase Created: 2. nieuwbouw
Structural - Enable Analytical Model: no; Structural: no; Structural Usage: Non-bearing
Dimensions - Length: 200 mm
Identity Data - Workset: Workset1
Other - Family: Basic Wall; Family and Type: Basic Wall: NLRS_22_WA_HSB bispouw 210_gen_ISR; Type: NLRS_22_WA_HSB bispouw 210_gen_ISR; Type Id: 2726038
Name (Basic Wall:NLRS_22_WA_HSB bispouw 210_gen_ISR:...) | Top Offset (mm) | Unconnected Height (mm) | Area (m2) | Volume (m3)
1220526 | -220 | 3440 | 0.688 | 0.14448
2349994 | -390 | 3270 | 0.654 | 0.13734
2350004 | -220 | 3440 | 0.688 | 0.14448
2726761 | -350 | 3310 | 0.662 | 0.13902
2727429 | -350 | 3310 | 0.662 | 0.13902
2727442 | -350 | 3310 | 0.662 | 0.13902
2727454 | -350 | 3310 | 0.662 | 0.13902

# IfcWallStandardCase: Basic Wall:NLRS_22_WA_HSB bispouw 30-140-12-13_gen_ISR (2)
In: 00 begane grond
Type - PredefinedType: STANDARD; Material: n7_isolatie_glaswol 30 mm, n7_isolatie_Resol 140 mm, i4_multiplex 12 mm, f7_gipsvezel 13 mm
Type - Analytical Properties - Roughness: 1; Absorptance: 0.1
Type - Materials and Finishes - Structural Material: n7_isolatie_Resol
Type - Graphics - Coarse Scale Fill Pattern: <Solid fill>; Coarse Scale Fill Color: 4210752
Type - Construction - Function: Interior; Wrapping at Inserts: Do not wrap; Width: 195 mm
Type - Identity Data - Workset: Wall Types; Assembly Code: 21.10; Assembly Description: buitenwanden; niet constructief, algemeen (verzamelniveau); Description: gevelsluitend element; SmartRevit_Versie: 2018.2; Type Name: NLRS_22_WA_HSB bispouw 30-140-12-13_gen_ISR
Type - Other - Category: Walls; Family Name: Basic Wall
Classification: 21.10 Uniformat (Uniformat)
Cross-Section Definition - Cross-Section: Vertical
Constraints - Base Extension Distance: 0 mm; Base is Attached: no; Location Line: Finish Face: Exterior; Related to Mass: no; Room Bounding: yes; Top Extension Distance: 0 mm; Top is Attached: no; Base Constraint: 00 begane grond; Top Constraint: Up to level: 00 begane grond; Base Offset: -30 mm
Phasing - Phase Created: 2. nieuwbouw
Structural - Enable Analytical Model: no; Structural: no; Structural Usage: Non-bearing
Identity Data - Workset: Workset1
Other - Family: Basic Wall; Family and Type: Basic Wall: NLRS_22_WA_HSB bispouw 30-140-12-13_gen_ISR; Type: NLRS_22_WA_HSB bispouw 30-140-12-13_gen_ISR; Type Id: 1501842
Name (Basic Wall:NLRS_22_WA_HSB bispouw 30-140-12-13_gen_ISR:...) | Top Offset (mm) | Unconnected Height (mm) | Area (m2) | Length (mm) | Volume (m3)
1501927 | 5320 | 5350 | 20.1962 | 3775 | 3.93827
3224896 | 2520 | 2550 | 1.6065 | 630 | 0.313267

# IfcWallStandardCase: Basic Wall:NLRS_22_WA_HSB bispouw 30-150 glaswol_gen_ISR, Basic Wall:NLRS_22_WA_HSB bispouw 30-150 glaswol_gen_ISR:3558859
In: 01 eerste verdieping
Type - PredefinedType: STANDARD; Material: n7_isolatie_glaswol 30 mm, n7_isolatie_glaswol 150 mm
Type - Analytical Properties - Roughness: 1; Absorptance: 0.1
Type - Materials and Finishes - Structural Material: n7_isolatie_glaswol
Type - Graphics - Coarse Scale Fill Pattern: <Solid fill>; Coarse Scale Fill Color: 4210752
Type - Construction - Function: Interior; Wrapping at Inserts: Do not wrap; Width: 180 mm
Type - Identity Data - Workset: Wall Types; Assembly Code: 21.10; Assembly Description: buitenwanden; niet constructief, algemeen (verzamelniveau); Description: gevelsluitend element; SmartRevit_Versie: 2018.2; Type Name: NLRS_22_WA_HSB bispouw 30-150 glaswol_gen_ISR
Type - Other - Category: Walls; Family Name: Basic Wall
Classification: 21.10 Uniformat (Uniformat)
Cross-Section Definition - Cross-Section: Vertical
Constraints - Base Extension Distance: 0 mm; Base is Attached: no; Location Line: Finish Face: Exterior; Related to Mass: no; Room Bounding: yes; Top Extension Distance: 0 mm; Top is Attached: no; Base Constraint: 01 eerste verdieping; Top Constraint: Up to level: 02 bk. constructie gymzaal; Base Offset: -30 mm; Top Offset: -153 mm; Unconnected Height: 2377 mm
Phasing - Phase Created: 2. nieuwbouw
Structural - Enable Analytical Model: no; Structural: no; Structural Usage: Non-bearing
Dimensions - Area: 12.4792 m2; Length: 5250 mm; Volume: 2.24626 m3
Identity Data - Workset: Workset1
Other - Family: Basic Wall; Family and Type: Basic Wall: NLRS_22_WA_HSB bispouw 30-150 glaswol_gen_ISR; Type: NLRS_22_WA_HSB bispouw 30-150 glaswol_gen_ISR; Type Id: 3559835

# IfcWallStandardCase: Basic Wall:NLRS_22_WA_HSB bispouw 30-245-12-13 glaswol_gen_ISR (86)
Type - PredefinedType: STANDARD; Material: n7_isolatie_glaswol 30 mm, n7_isolatie_glaswol 245 mm, i4_multiplex 12 mm, f7_gipsvezel 13 mm
Type - Analytical Properties - Absorptance: 0.1; Roughness: 1
Type - Materials and Finishes - Structural Material: n7_isolatie_glaswol
Type - Graphics - Coarse Scale Fill Color: 4210752; Coarse Scale Fill Pattern: <Solid fill>
Type - Construction - Function: Interior; Width: 300 mm; Wrapping at Inserts: Do not wrap
Type - Identity Data - Assembly Code: 21.10; Assembly Description: buitenwanden; niet constructief, algemeen (verzamelniveau); Description: gevelsluitend element; SmartRevit_Versie: 2018.2; Type Name: NLRS_22_WA_HSB bispouw 30-245-12-13 glaswol_gen_ISR; Workset: Wall Types
Type - Other - Category: Walls; Family Name: Basic Wall
Classification: 21.10 Uniformat (Uniformat)
Cross-Section Definition - Cross-Section: Vertical
Constraints - Base Extension Distance: 0 mm; Base is Attached: no; Related to Mass: no; Room Bounding: yes; Top Extension Distance: 0 mm
Phasing - Phase Created: 2. nieuwbouw
Structural - Enable Analytical Model: no; Structural: no; Structural Usage: Non-bearing
Identity Data - Workset: Workset1
Other - Family: Basic Wall; Family and Type: Basic Wall: NLRS_22_WA_HSB bispouw 30-245-12-13 glaswol_gen_ISR; Type: NLRS_22_WA_HSB bispouw 30-245-12-13 glaswol_gen_ISR; Type Id: 474264
Name (Basic Wall:NLRS_22_WA_HSB bispouw 30-245-12-13 glaswol_gen_ISR:...) | In | Base Constraint | Base Offset (mm) | Location Line | Top Constraint | Top is Attached | Top Offset (mm) | Unconnected Height (mm) | Area (m2) | Length (mm) | Volume (m3)
772304 | 02 tweede verdieping | 02 tweede verdieping | -30 | Finish Face: Exterior | Up to level: 03 ok. ruwe vloer | no | -264 | 3266 | 1.60034 | 340 | 0.480102
772305 | 02 tweede verdieping | 02 tweede verdieping | -30 | Finish Face: Exterior | Up to level: 03 ok. ruwe vloer | no | -264 | 3266 | 9.14924 | 3240 | 2.48358
772306 | 02 tweede verdieping | 02 tweede verdieping | -30 | Finish Face: Exterior | Up to level: 03 ok. ruwe vloer | no | -264 | 3266 | 1.60034 | 340 | 0.480102
772307 | 02 tweede verdieping | 02 tweede verdieping | -30 | Finish Face: Exterior | Up to level: 03 ok. ruwe vloer | no | -225 | 3305 | 51.4103 | 24700 | 12.8947
772576 | 01 eerste verdieping | 01 eerste verdieping | -30 | Finish Face: Exterior | Up to level: 02 ok. ruwe vloer | no | -345 | 3115 | 41.2586 | 29400 | 8.11701
772577 | 01 eerste verdieping | 01 eerste verdieping | -30 | Finish Face: Exterior | Up to level: 02 ok. ruwe vloer | no | -295 | 3165 | 35.4427 | 24700 | 7.25757
772578 | 01 eerste verdieping | 01 eerste verdieping | -30 | Finish Face: Exterior | Up to level: 02 ok. ruwe vloer | no | -345 | 3115 | 40.6331 | 29151.5 | 7.879
772779 | 00 begane grond | 00 begane grond | -30 | Finish Face: Exterior | Up to level: 01 ok. ruwe vloer | no | -345 | 3315 | 22.7078 | 6550 | 6.81233
772806 | 00 begane grond | 00 begane grond | -30 | Finish Face: Exterior | Up to level: 01 ok. ruwe vloer | no | -345 | 3315 | 10.5086 | 3020 | 3.12642
772864 | 00 begane grond | 00 begane grond | -30 | Finish Face: Exterior | Up to level: 01 ok. ruwe vloer | no | -340 | 3320 | 1.5411 | 2747 | 0.140552
773244 | 00 begane grond | 00 begane grond | -30 | Finish Face: Exterior | Up to level: 01 ok. ruwe vloer | no | -16 | 3644 | 4.65231 | 3767 | 1.14782
892015 | 00 begane grond | 00 begane grond | -30 | Finish Face: Exterior | Up to level: 01 ok. ruwe vloer | no | -375 | 3285 | 17.082 | 5050 | 5.1246
897586 | 00 begane grond | 00 begane grond | -30 | Finish Face: Exterior | Up to level: 01 ok. ruwe vloer | no | -340 | 3320 | 0.5882 | 1850 | 0.0852975
897842 | 00 begane grond | 00 begane grond | -30 | Finish Face: Exterior | Up to level: 01 ok. ruwe vloer | no | -345 | 3315 | 5.7026 | 4081.5 | 1.1583
897869 | 00 begane grond | 00 begane grond | -30 | Finish Face: Exterior | Up to level: 01 ok. ruwe vloer | no | -345 | 3315 | 8.52393 | 5740 | 1.85186 | Group: Model Group:21_hsb_v0_A:897872
1219764 | 00 begane grond | 00 begane grond | -30 | Finish Face: Exterior | Up to level: 01 ok. ruwe vloer | no | -345 | 3315 | 3.89732 | 2760 | 0.816536
1220525 | 00 begane grond | 00 begane grond | -30 | Finish Face: Exterior | Up to level: 01 ok. ruwe vloer | no | -345 | 3315 | 7.82042 | 5020 | 1.92912
1221337 | 00 begane grond | 00 begane grond | -30 | Finish Face: Exterior | Up to level: 01 ok. ruwe vloer | no | -345 | 3315 | 8.98426 | 6117.5 | 1.9757
1221591 | 00 begane grond | 00 begane grond | -30 | Finish Face: Exterior | Up to level: 01 ok. ruwe vloer | no | -345 | 3315 | 4.13489 | 1247.33 | 1.24047
1222346 | 00 begane grond | 00 begane grond | -30 | Finish Face: Exterior | Up to level: 01 ok. ruwe vloer | no | -345 | 3315 | 13.8771 | 5740 | 3.55435 | Group: Model Group:21_hsb_v0_A:1222349
1223365 | 00 begane grond | 00 begane grond | -30 | Finish Face: Exterior | Up to level: 01 ok. ruwe vloer | no | -345 | 3315 | 8.98132 | 6195 | 2.10902
1224034 | 00 begane grond | 00 begane grond | -30 | Finish Face: Exterior | Up to level: 01 ok. ruwe vloer | no | -295 | 3365 | 5.94722 | 3725 | 1.41347
1224142 | 00 begane grond | 00 begane grond | -30 | Finish Face: Exterior | Up to level: 01 ok. ruwe vloer | no | 302 | 3962 | 28.4923 | 10753 | 8.06768
1288656 | 00 begane grond | 00 begane grond | -30 | Finish Face: Exterior | Up to level: 01 ok. ruwe vloer | no | 7 | 3667 | 3.623 | 1138 | 1.07853
1342657 | 00 begane grond | 00 begane grond | -30 | Finish Face: Exterior | Up to level: 01 ok. ruwe vloer | no | -285 | 3375 | 21.1866 | 6427.5 | 6.35597
1499989 | 00 begane grond | 00 begane grond | -30 | Finish Face: Exterior | Up to level: 02 bk. constructie gymzaal | no | -153 | 6377 | 25.7567 | 3889 | 7.72701
1500020 | 00 begane grond | 00 begane grond | -30 | Finish Face: Exterior | Up to level: 02 bk. constructie gymzaal | no | -143 | 6387 | 25.8733 | 5432 | 7.34498
1500057 | 00 begane grond | 00 begane grond | -30 | Finish Face: Exterior | Up to level: 02 bk. constructie gymzaal | no | -153 | 6377 | 11.1597 | 1750 | 3.34792
1501194 | 01 eerste verdieping | 01 eerste verdieping | -30 | Finish Face: Exterior | Up to level: 02 bk. constructie gymzaal | no | -153 | 2377 | 13.1924 | 5550 | 3.95771
1501772 | 00 begane grond | 00 begane grond | -30 | Finish Face: Exterior | Up to level: 02 bk. constructie gymzaal | no | -143 | 6387 | 9.67631 | 1515 | 2.90289
1822551 | 00 begane grond | 00 begane grond | -30 | Finish Face: Exterior | Up to level: 01 ok. ruwe vloer | no | -395 | 3265 | 8.41742 | 6500 | 2.04521
1853783 | 00 begane grond | 00 begane grond | -30 | Finish Face: Exterior | Up to level: 01 ok. ruwe vloer | no | -345 | 3315 | 2.14704 | 647.674 | 0.644112
1882671 | 01 eerste verdieping | 01 eerste verdieping | -30 | Finish Face: Exterior | Up to level: 02 bk. constructie gymzaal | no | -153 | 2377 | 22.32 | 9540 | 6.69601
2194533 | 03 derde verdieping | 03 derde verdieping | -50 | Wall Centerline |  | yes | 0 | 1550 | 1.70984 | 2163.5 | 0.512952 | Group: Model Group:daklicht A1:2182252
2194534 | 03 derde verdieping | 03 derde verdieping | -50 | Wall Centerline |  | yes | 0 | 1550 | 1.70984 | 2163.5 | 0.512952 | Group: Model Group:daklicht A1:2182252
2194537 | 03 derde verdieping | 03 derde verdieping | -50 | Wall Centerline |  | yes | 0 | 1550 | 1.70984 | 2163.5 | 0.512952 | Group: Model Group:daklicht A1 (members excluded):2182288
2194538 | 03 derde verdieping | 03 derde verdieping | -50 | Wall Centerline |  | yes | 0 | 1550 | 1.70984 | 2163.5 | 0.512952 | Group: Model Group:daklicht A1 (members excluded):2182288
2194539 | 03 derde verdieping | 03 derde verdieping | -50 | Wall Centerline |  | yes | 0 | 1550 | 1.70984 | 2163.5 | 0.512952 | Group: Model Group:BU-42 daklicht B lokaal:2182308
2194540 | 03 derde verdieping | 03 derde verdieping | -50 | Wall Centerline |  | yes | 0 | 1550 | 1.70984 | 2163.5 | 0.512952 | Group: Model Group:BU-42 daklicht B lokaal:2182308
2194783 | 03 derde verdieping | 03 derde verdieping | -50 | Wall Centerline |  | yes | 0 | 1550 | 1.70984 | 2163.5 | 0.512952 | Group: Model Group:BU-42 daklicht B lokaal:2194782
2194784 | 03 derde verdieping | 03 derde verdieping | -50 | Wall Centerline |  | yes | 0 | 1550 | 1.70984 | 2163.5 | 0.512952 | Group: Model Group:BU-42 daklicht B lokaal:2194782
2335924 | 02 tweede verdieping | 02 tweede verdieping | -30 | Finish Face: Exterior | Up to level: 03 ok. ruwe vloer | no | -264 | 3266 | 13.11 | 5780 | 3.14941
2336239 | 02 tweede verdieping | 02 tweede verdieping | -30 | Finish Face: Exterior | Up to level: 03 ok. ruwe vloer | no | -264 | 3266 | 0.62054 | 340 | 0.186162
2336364 | 02 tweede verdieping | 02 tweede verdieping | -30 | Finish Face: Exterior | Up to level: 03 ok. ruwe vloer | no | -264 | 3266 | 13.11 | 5780 | 3.14941
2336465 | 02 tweede verdieping | 02 tweede verdieping | -30 | Finish Face: Exterior | Up to level: 03 ok. ruwe vloer | no | -264 | 3266 | 3.89098 | 1780 | 0.9061
2336545 | 02 tweede verdieping | 02 tweede verdieping | -30 | Finish Face: Exterior | Up to level: 03 ok. ruwe vloer | no | -265 | 3265 | 8.49671 | 3780 | 2.02662
2336577 | 02 tweede verdieping | 02 tweede verdieping | -30 | Finish Face: Exterior | Up to level: 03 ok. ruwe vloer | no | -264 | 3266 | 5.41784 | 2247.5 | 1.36416
2338631 | 02 tweede verdieping | 02 tweede verdieping | -30 | Finish Face: Exterior | Up to level: 03 ok. ruwe vloer | no | -264 | 3266 | 7.40964 | 3446 | 1.7005
2338901 | 02 tweede verdieping | 02 tweede verdieping | -30 | Finish Face: Exterior | Up to level: 03 ok. ruwe vloer | no | -264 | 3266 | 8.49802 | 3779.24 | 2.02702
2338990 | 02 tweede verdieping | 02 tweede verdieping | -30 | Finish Face: Exterior | Up to level: 03 ok. ruwe vloer | no | -225 | 3305 | 13.3379 | 5780.76 | 3.21779
2339043 | 02 tweede verdieping | 02 tweede verdieping | -30 | Finish Face: Exterior | Up to level: 03 ok. ruwe vloer | no | -264 | 3266 | 8.50049 | 3780 | 2.02776
2339114 | 02 tweede verdieping | 02 tweede verdieping | -30 | Finish Face: Exterior | Up to level: 03 ok. ruwe vloer | no | -225 | 3305 | 8.64791 | 3780 | 2.07198
2339224 | 02 tweede verdieping | 02 tweede verdieping | -30 | Finish Face: Exterior | Up to level: 03 ok. ruwe vloer | no | -264 | 3266 | 13.11 | 5780 | 3.14941
2341393 | 02 tweede verdieping | 02 tweede verdieping | -30 | Finish Face: Exterior | Up to level: 03 ok. ruwe vloer | no | -264 | 3266 | 8.16944 | 3240 | 2.18964
2341550 | 02 tweede verdieping | 02 tweede verdieping | -30 | Finish Face: Exterior | Up to level: 03 ok. ruwe vloer | no | -264 | 3266 | 13.11 | 5780 | 3.14941
2341762 | 02 tweede verdieping | 02 tweede verdieping | -30 | Finish Face: Exterior | Up to level: 03 ok. ruwe vloer | no | -264 | 3266 | 3.89098 | 1780 | 0.9061
2341873 | 02 tweede verdieping | 02 tweede verdieping | -30 | Finish Face: Exterior | Up to level: 03 ok. ruwe vloer | no | -264 | 3266 | 9.7334 | 4157.5 | 2.39763
2342127 | 02 tweede verdieping | 02 tweede verdieping | -30 | Finish Face: Exterior | Up to level: 03 ok. ruwe vloer | no | -264 | 3266 | 11.9386 | 5421.33 | 2.79798
2342213 | 02 tweede verdieping | 02 tweede verdieping | -30 | Finish Face: Exterior | Up to level: 03 ok. ruwe vloer | no | -264 | 3266 | 0.701125 | 364.674 | 0.210337
2346484 | 00 begane grond | 00 begane grond | -30 | Finish Face: Exterior | Up to level: 01 ok. ruwe vloer | no | -345 | 3315 | 9.0168 | 2720 | 2.70504
2347297 | 00 begane grond | 00 begane grond | -30 | Finish Face: Exterior | Up to level: 01 ok. ruwe vloer | no | -345 | 3315 | 5.25372 | 6040 | 1.09543
2347526 | 00 begane grond | 00 begane grond | -30 | Finish Face: Exterior | Up to level: 01 ok. ruwe vloer | no | -345 | 3315 | 3.54705 | 1220 | 1.06411
2347789 | 00 begane grond | 00 begane grond | -30 | Finish Face: Exterior | Up to level: 01 ok. ruwe vloer | no | -345 | 3315 | 7.12891 | 2150.5 | 2.13867
2348540 | 00 begane grond | 00 begane grond | -30 | Finish Face: Exterior | Up to level: 01 ok. ruwe vloer | no | -295 | 3365 | 3.92684 | 3749 | 0.868008
2348840 | 00 begane grond | 00 begane grond | -30 | Finish Face: Exterior | Up to level: 01 ok. ruwe vloer | no | -345 | 3315 | 8.18672 | 3070 | 2.29659
2349608 | 00 begane grond | 00 begane grond | -30 | Finish Face: Exterior | Up to level: 01 ok. ruwe vloer | no | -345 | 3315 | 2.96182 | 3823.5 | 0.466343
2349780 | 00 begane grond | 00 begane grond | -30 | Finish Face: Exterior | Up to level: 01 ok. ruwe vloer | no | -345 | 3315 | 11.7321 | 6200 | 3.10263
2350073 | 00 begane grond | 00 begane grond | -30 | Finish Face: Exterior | Up to level: 01 ok. ruwe vloer | no | -390 | 3270 | 8.12217 | 6250 | 1.95663
2726434 | 00 begane grond | 00 begane grond | -30 | Finish Face: Exterior | Up to level: 01 ok. ruwe vloer | no | -395 | 3265 | 19.4529 | 6108 | 5.83586
2727333 | 00 begane grond | 00 begane grond | -30 | Finish Face: Exterior | Up to level: 01 ok. ruwe vloer | no | -375 | 3285 | 15.8009 | 5492 | 4.45267
2727573 | 00 begane grond | 00 begane grond | -30 | Finish Face: Exterior | Up to level: 01 ok. ruwe vloer | no | -375 | 3285 | 10.5606 | 5900 | 2.75118
2729110 | 00 begane grond | 00 begane grond | -30 | Finish Face: Exterior | Up to level: 02 bk. constructie gymzaal | no | -153 | 6377 | 16.7468 | 3030 | 4.71965
2729456 | 00 begane grond | 00 begane grond | -30 | Finish Face: Exterior | Up to level: 02 bk. constructie gymzaal | no | -143 | 6387 | 25.1648 | 3940 | 7.54943
2729820 | 00 begane grond | 00 begane grond | -30 | Finish Face: Exterior | Up to level: 02 bk. constructie gymzaal | no | -153 | 6377 | 17.4366 | 4665.5 | 4.75095
2732703 | 00 begane grond | 00 begane grond | -30 | Finish Face: Exterior | Up to level: 02 bk. constructie gymzaal | no | -143 | 6387 | 34.3174 | 5373 | 10.2952
2732862 | 00 begane grond | 00 begane grond | -30 | Finish Face: Exterior | Up to level: 02 bk. constructie gymzaal | no | -143 | 6387 | 24.9663 | 5290 | 7.0729
2734449 | 00 begane grond | 00 begane grond | -30 | Finish Face: Exterior | Up to level: 01 ok. ruwe vloer | no | -345 | 3315 | 9.76267 | 2945 | 2.9288
2734805 | 00 begane grond | 00 begane grond | -30 | Finish Face: Exterior | Up to level: 01 ok. ruwe vloer | no | -345 | 3315 | 9.59693 | 3045 | 2.87908
2898339 | 01 eerste verdieping | 01 eerste verdieping | 3450 | Finish Face: Exterior | Up to level: 02 bk. ruwe vloer | no | 20 | 320 | 1.0064 | 3145 | 0.30192
3224474 | 00 begane grond | 00 begane grond | 5320 | Finish Face: Exterior | Up to level: 02 bk. constructie gymzaal | no | -143 | 1037 | 3.91467 | 3775 | 1.1744
3224788 | 00 begane grond | 00 begane grond | -30 | Finish Face: Exterior | Up to level: 02 bk. constructie gymzaal | no | -143 | 6387 | 2.77196 | 434 | 0.831587
3224817 | 00 begane grond | 00 begane grond | 2520 | Finish Face: Exterior | Up to level: 00 begane grond | no | 6357 | 3837 | 3.0696 | 800 | 0.92088
3528058 | 00 begane grond | 00 begane grond | -30 | Finish Face: Exterior | Up to level: 01 ok. ruwe vloer | no | -375 | 3285 | 9.12561 | 5350 | 2.29103
3558825 | 01 eerste verdieping | 01 eerste verdieping | -30 | Finish Face: Exterior | Up to level: 02 bk. constructie gymzaal | no | -153 | 2377 | 12.4792 | 5250 | 3.74377
3558974 | 01 eerste verdieping | 01 eerste verdieping | -30 | Finish Face: Exterior | Up to level: 02 bk. constructie gymzaal | no | -153 | 2377 | 13.644 | 5590 | 4.09319
4345611 | 01 eerste verdieping | 01 eerste verdieping | -30 | Finish Face: Exterior | Up to level: 02 ok. ruwe vloer | no | -375 | 3085 | 24.2558 | 7862.5 | 7.27674

# IfcWallStandardCase: Basic Wall:NLRS_22_WA_HSB bispouw 60_gen_ISR (3)
In: 01 eerste verdieping
Type - PredefinedType: STANDARD; Material: n7_isolatie_Resol 60 mm
Type - Analytical Properties - Roughness: 1; Absorptance: 0.1
Type - Materials and Finishes - Structural Material: n7_isolatie_Resol
Type - Graphics - Coarse Scale Fill Pattern: <Solid fill>; Coarse Scale Fill Color: 4210752
Type - Construction - Function: Interior; Wrapping at Inserts: Do not wrap; Width: 60 mm
Type - Identity Data - Workset: Wall Types; Assembly Code: 21.10; Assembly Description: buitenwanden; niet constructief, algemeen (verzamelniveau); Description: gevelsluitend element; SmartRevit_Versie: 2018.2; Type Name: NLRS_22_WA_HSB bispouw 60_gen_ISR
Type - Other - Category: Walls; Family Name: Basic Wall
Classification: 21.10 Uniformat (Uniformat)
Cross-Section Definition - Cross-Section: Vertical
Constraints - Base Extension Distance: 0 mm; Base is Attached: no; Related to Mass: no; Room Bounding: yes; Top Extension Distance: 0 mm; Top is Attached: no; Base Constraint: 01 eerste verdieping; Location Line: Finish Face: Interior; Top Constraint: Up to level: 02 bk. constructie gymzaal; Base Offset: -30 mm; Top Offset: -153 mm; Unconnected Height: 2377 mm
Phasing - Phase Created: 2. nieuwbouw
Structural - Enable Analytical Model: no; Structural: no; Structural Usage: Non-bearing
Dimensions - Area: 0.7131 m2; Length: 300 mm; Volume: 0.042786 m3
Identity Data - Workset: Workset1
Other - Family: Basic Wall; Family and Type: Basic Wall: NLRS_22_WA_HSB bispouw 60_gen_ISR; Type: NLRS_22_WA_HSB bispouw 60_gen_ISR; Type Id: 3559274
Name (Basic Wall:NLRS_22_WA_HSB bispouw 60_gen_ISR:...)
3559170
3559402
3559412

# IfcWallStandardCase: Basic Wall:NLRS_22_WA_HSB bispouw 72-12-13 glaswol_gen_ISR, Basic Wall:NLRS_22_WA_HSB bispouw 72-12-13 glaswol_gen_ISR:3560041
In: 01 eerste verdieping
Type - PredefinedType: STANDARD; Material: n7_isolatie_glaswol 72 mm, i4_multiplex 12 mm, f7_gipsvezel 13 mm
Type - Analytical Properties - Roughness: 1; Absorptance: 0.1
Type - Materials and Finishes - Structural Material: n7_isolatie_glaswol
Type - Graphics - Coarse Scale Fill Pattern: <Solid fill>; Coarse Scale Fill Color: 4210752
Type - Construction - Function: Interior; Wrapping at Inserts: Do not wrap; Width: 97 mm
Type - Identity Data - Workset: Wall Types; Assembly Code: 21.10; Assembly Description: buitenwanden; niet constructief, algemeen (verzamelniveau); Description: gevelsluitend element; SmartRevit_Versie: 2018.2; Type Name: NLRS_22_WA_HSB bispouw 72-12-13 glaswol_gen_ISR
Type - Other - Category: Walls; Family Name: Basic Wall
Classification: 21.10 Uniformat (Uniformat)
Cross-Section Definition - Cross-Section: Vertical
Constraints - Base Extension Distance: 0 mm; Base is Attached: no; Related to Mass: no; Room Bounding: yes; Top Extension Distance: 0 mm; Top is Attached: no; Base Constraint: 01 eerste verdieping; Location Line: Finish Face: Interior; Top Constraint: Up to level: 02 bk. constructie gymzaal; Base Offset: -30 mm; Top Offset: -153 mm; Unconnected Height: 2377 mm
Phasing - Phase Created: 2. nieuwbouw
Structural - Enable Analytical Model: no; Structural: no; Structural Usage: Non-bearing
Dimensions - Area: 12.4792 m2; Length: 5250 mm; Volume: 1.21049 m3
Identity Data - Workset: Workset1
Other - Family: Basic Wall; Family and Type: Basic Wall: NLRS_22_WA_HSB bispouw 72-12-13 glaswol_gen_ISR; Type: NLRS_22_WA_HSB bispouw 72-12-13 glaswol_gen_ISR; Type Id: 3560080

# IfcWallStandardCase: Basic Wall:NLRS_22_WA_HSB bispouw 80_gen_ISR (2)
In: 00 begane grond
Type - PredefinedType: STANDARD; Material: n7_isolatie_Resol 80 mm
Type - Analytical Properties - Roughness: 1; Absorptance: 0.1
Type - Materials and Finishes - Structural Material: n7_isolatie_Resol
Type - Graphics - Coarse Scale Fill Pattern: <Solid fill>; Coarse Scale Fill Color: 4210752
Type - Construction - Function: Interior; Wrapping at Inserts: Do not wrap; Width: 80 mm
Type - Identity Data - Workset: Wall Types; Assembly Code: 21.10; Assembly Description: buitenwanden; niet constructief, algemeen (verzamelniveau); Description: gevelsluitend element; SmartRevit_Versie: 2018.2; Type Name: NLRS_22_WA_HSB bispouw 80_gen_ISR
Type - Other - Category: Walls; Family Name: Basic Wall
Classification: 21.10 Uniformat (Uniformat)
Cross-Section Definition - Cross-Section: Vertical
Constraints - Base Extension Distance: 0 mm; Base is Attached: no; Location Line: Finish Face: Exterior; Related to Mass: no; Room Bounding: yes; Top Extension Distance: 0 mm; Top is Attached: no; Base Constraint: 00 begane grond; Top Constraint: Up to level: 02 bk. constructie gymzaal; Base Offset: -30 mm; Top Offset: -143 mm; Unconnected Height: 6387 mm
Phasing - Phase Created: 2. nieuwbouw
Structural - Enable Analytical Model: no; Structural: no; Structural Usage: Non-bearing
Identity Data - Workset: Workset1
Other - Family: Basic Wall; Family and Type: Basic Wall: NLRS_22_WA_HSB bispouw 80_gen_ISR; Type: NLRS_22_WA_HSB bispouw 80_gen_ISR; Type Id: 2728327
Name (Basic Wall:NLRS_22_WA_HSB bispouw 80_gen_ISR:...) | Area (m2) | Length (mm) | Volume (m3)
2728048 | 1.66062 | 260 | 0.13285
2733222 | 1.59675 | 300 | 0.12774

# IfcWallStandardCase: Basic Wall:NLRS_22_WA_HSB bispouw 85_gen_ISR (3)
In: 00 begane grond
Type - PredefinedType: STANDARD; Material: n7_isolatie_Resol 85 mm
Type - Analytical Properties - Roughness: 1; Absorptance: 0.1
Type - Materials and Finishes - Structural Material: n7_isolatie_Resol
Type - Graphics - Coarse Scale Fill Pattern: <Solid fill>; Coarse Scale Fill Color: 4210752
Type - Construction - Function: Interior; Wrapping at Inserts: Do not wrap; Width: 85 mm
Type - Identity Data - Workset: Wall Types; Assembly Code: 21.10; Assembly Description: buitenwanden; niet constructief, algemeen (verzamelniveau); Description: gevelsluitend element; SmartRevit_Versie: 2018.2; Type Name: NLRS_22_WA_HSB bispouw 85_gen_ISR
Type - Other - Category: Walls; Family Name: Basic Wall
Classification: 21.10 Uniformat (Uniformat)
Cross-Section Definition - Cross-Section: Vertical
Constraints - Base Extension Distance: 0 mm; Base is Attached: no; Location Line: Finish Face: Exterior; Related to Mass: no; Room Bounding: yes; Top Extension Distance: 0 mm; Top is Attached: no; Base Constraint: 00 begane grond; Top Constraint: Up to level: 01 ok. ruwe vloer; Base Offset: -30 mm
Phasing - Phase Created: 2. nieuwbouw
Structural - Enable Analytical Model: no; Structural: no; Structural Usage: Non-bearing
Identity Data - Workset: Workset1
Other - Family: Basic Wall; Family and Type: Basic Wall: NLRS_22_WA_HSB bispouw 85_gen_ISR; Type: NLRS_22_WA_HSB bispouw 85_gen_ISR; Type Id: 2798179
Name (Basic Wall:NLRS_22_WA_HSB bispouw 85_gen_ISR:...) | Top Offset (mm) | Unconnected Height (mm) | Area (m2) | Length (mm) | Volume (m3)
2798132 | -220 | 3440 | 0.41108 | 119.5 | 0.0349418
2798833 | -295 | 3365 | 0.4038 | 120 | 0.034323
4792641 | -220 | 3440 | 0.4558 | 132.5 | 0.038743

# IfcWallStandardCase: Basic Wall:NLRS_22_WA_HSB dakopstand 10+230+10 _gen_bdg (3)
In: 01 eerste verdieping
Type - PredefinedType: STANDARD; Material: s9_bitumen 4 mm, i4_multiplex 10 mm, n7_isolatie_glaswol 230 mm, i4_multiplex 10 mm, s9_bitumen 4 mm
Type - Analytical Properties - Roughness: 1; Absorptance: 0.1; Heat Transfer Coefficient (U): 625000 kg/K/s3; Thermal Mass: 15.6576; Thermal Resistance (R): 0.0000016
Type - Materials and Finishes - Structural Material: n7_isolatie_glaswol
Type - Graphics - Coarse Scale Fill Pattern: <Solid fill>; Coarse Scale Fill Color: 4210752
Type - Construction - Function: Interior; Wrapping at Inserts: Do not wrap; Width: 258 mm
Type - Identity Data - Workset: Wall Types; Assembly Code: 21.10; Assembly Description: buitenwanden; niet constructief, algemeen (verzamelniveau); Description: gevelsluitend element; SmartRevit_Versie: 2018.2; Type Name: NLRS_22_WA_HSB dakopstand 10+230+10 _gen_bdg
Type - Other - Category: Walls; Family Name: Basic Wall
Classification: 21.10 Uniformat (Uniformat)
Cross-Section Definition - Cross-Section: Vertical
Constraints - Base Extension Distance: 0 mm; Base is Attached: no; Related to Mass: no; Room Bounding: yes; Top Extension Distance: 0 mm; Top is Attached: no; Base Constraint: 01 eerste verdieping; Top Constraint: Up to level: 01 eerste verdieping; Location Line: Wall Centerline; Base Offset: -50 mm
Phasing - Phase Created: 2. nieuwbouw
Structural - Enable Analytical Model: no; Structural: no; Structural Usage: Non-bearing
Identity Data - Workset: Workset1
Other - Family: Basic Wall; Family and Type: Basic Wall: NLRS_22_WA_HSB dakopstand 10+230+10 _gen_bdg; Type: NLRS_22_WA_HSB dakopstand 10+230+10 _gen_bdg; Type Id: 2772172
Name (Basic Wall:NLRS_22_WA_HSB dakopstand 10+230+10 _gen_bdg:...) | Top Offset (mm) | Unconnected Height (mm) | Area (m2) | Length (mm) | Volume (m3)
2772125 | 775 | 825 | 4.11675 | 4990 | 1.06212
2773399 | 260 | 310 | 1.9127 | 6170 | 0.493477
3307402 | 260 | 310 | 0.3658 | 1180 | 0.0943764

# IfcWallStandardCase: Basic Wall:NLRS_22_WA_HSB dakopstand 12-200-12-13_gen_ISR (4)
In: 03 derde verdieping
Type - PredefinedType: STANDARD; Material: i4_multiplex 12 mm, n7_isolatie_glaswol 200 mm, i4_multiplex 12 mm, f7_gipsvezel 13 mm
Type - Analytical Properties - Roughness: 1; Absorptance: 0.1
Type - Materials and Finishes - Structural Material: n7_isolatie_glaswol
Type - Graphics - Coarse Scale Fill Pattern: <Solid fill>; Coarse Scale Fill Color: 4210752
Type - Construction - Function: Interior; Wrapping at Inserts: Do not wrap; Width: 237 mm
Type - Identity Data - Workset: Wall Types; Assembly Code: 21.10; Assembly Description: buitenwanden; niet constructief, algemeen (verzamelniveau); Description: gevelsluitend element; SmartRevit_Versie: 2018.2; Type Name: NLRS_22_WA_HSB dakopstand 12-200-12-13_gen_ISR
Type - Other - Category: Walls; Family Name: Basic Wall
Classification: 21.10 Uniformat (Uniformat)
Cross-Section Definition - Cross-Section: Vertical
Constraints - Base Extension Distance: 0 mm; Base is Attached: no; Related to Mass: no; Room Bounding: yes; Top Extension Distance: 0 mm; Top is Attached: no; Top Offset: 0 mm; Base Constraint: 03 derde verdieping; Location Line: Wall Centerline; Base Offset: -50 mm; Unconnected Height: 1550 mm
Phasing - Phase Created: 2. nieuwbouw
Structural - Enable Analytical Model: no; Structural: no; Structural Usage: Non-bearing
Identity Data - Workset: Workset1
Other - Family: Basic Wall; Family and Type: Basic Wall: NLRS_22_WA_HSB dakopstand 12-200-12-13_gen_ISR; Type: NLRS_22_WA_HSB dakopstand 12-200-12-13_gen_ISR; Type Id: 2182227
Name (Basic Wall:NLRS_22_WA_HSB dakopstand 12-200-12-13_gen_ISR:...) | Area (m2) | Length (mm) | Volume (m3) | Group
2182226 | 4.1783 | 6206 | 0.990257 | Model Group:daklicht A1:2182252
2182281 | 4.1783 | 6206 | 0.990257 | Model Group:daklicht A1 (members excluded):2182288
2182301 | 7.82912 | 12407.5 | 1.8555 | Model Group:BU-42 daklicht B lokaal:2182308
2194775 | 7.82912 | 12407.5 | 1.8555 | Model Group:BU-42 daklicht B lokaal:2194782

# IfcWallStandardCase: Basic Wall:NLRS_22_WA_HSB dakrand 100 _gen_bdg (3)
In: 01 eerste verdieping
Type - PredefinedType: STANDARD; Material: n7_isolatie_glaswol 100 mm
Type - Analytical Properties - Roughness: 1; Absorptance: 0.1
Type - Materials and Finishes - Structural Material: n7_isolatie_glaswol
Type - Graphics - Coarse Scale Fill Pattern: <Solid fill>; Coarse Scale Fill Color: 4210752
Type - Construction - Function: Interior; Wrapping at Inserts: Do not wrap; Width: 100 mm
Type - Identity Data - Workset: Wall Types; Assembly Code: 21.10; Assembly Description: buitenwanden; niet constructief, algemeen (verzamelniveau); Description: gevelsluitend element; SmartRevit_Versie: 2018.2; Type Name: NLRS_22_WA_HSB dakrand 100 _gen_bdg
Type - Other - Category: Walls; Family Name: Basic Wall
Classification: 21.10 Uniformat (Uniformat)
Cross-Section Definition - Cross-Section: Vertical
Constraints - Base Extension Distance: 0 mm; Base is Attached: no; Related to Mass: no; Room Bounding: yes; Top Extension Distance: 0 mm; Top is Attached: no
Phasing - Phase Created: 2. nieuwbouw
Structural - Enable Analytical Model: no; Structural: no; Structural Usage: Non-bearing
Identity Data - Workset: Workset1
Other - Family: Basic Wall; Family and Type: Basic Wall: NLRS_22_WA_HSB dakrand 100 _gen_bdg; Type: NLRS_22_WA_HSB dakrand 100 _gen_bdg; Type Id: 2369032
Name (Basic Wall:NLRS_22_WA_HSB dakrand 100 _gen_bdg:...) | Location Line | Top Constraint | Base Constraint | Base Offset (mm) | Top Offset (mm) | Unconnected Height (mm) | Area (m2) | Length (mm) | Volume (m3)
2367389 | Finish Face: Exterior | Up to level: 02 bk. constructie gymzaal | 02 bk. constructie gymzaal | -143 | 108 | 251 | 5.7341 | 22730 | 0.57341
2367491 | Finish Face: Exterior | Up to level: 02 bk. constructie gymzaal | 02 bk. constructie gymzaal | -143 | 108 | 251 | 3.70112 | 14765.5 | 0.370112
5096545 | Core Face: Exterior | Up to level: 01 eerste verdieping | 01 eerste verdieping | 0 | 775 | 775 | 2.67375 | 3500 | 0.267375

# IfcWallStandardCase: Basic Wall:NLRS_22_WA_HSB dakrand 130_gen_bdg, Basic Wall:NLRS_22_WA_HSB dakrand 130_gen_bdg:2367424
In: 01 eerste verdieping
Type - PredefinedType: STANDARD; Material: n7_isolatie_glaswol 130 mm
Type - Analytical Properties - Roughness: 1; Absorptance: 0.1
Type - Materials and Finishes - Structural Material: n7_isolatie_glaswol
Type - Graphics - Coarse Scale Fill Pattern: <Solid fill>; Coarse Scale Fill Color: 4210752
Type - Construction - Function: Interior; Wrapping at Inserts: Do not wrap; Width: 130 mm
Type - Identity Data - Workset: Wall Types; Assembly Code: 21.10; Assembly Description: buitenwanden; niet constructief, algemeen (verzamelniveau); Description: gevelsluitend element; SmartRevit_Versie: 2018.2; Type Name: NLRS_22_WA_HSB dakrand 130_gen_bdg
Type - Other - Category: Walls; Family Name: Basic Wall
Classification: 21.10 Uniformat (Uniformat)
Cross-Section Definition - Cross-Section: Vertical
Constraints - Base Extension Distance: 0 mm; Base is Attached: no; Location Line: Finish Face: Exterior; Related to Mass: no; Room Bounding: yes; Top Extension Distance: 0 mm; Top is Attached: no; Top Constraint: Up to level: 02 bk. constructie gymzaal; Base Constraint: 02 bk. constructie gymzaal; Base Offset: -143 mm; Top Offset: 108 mm; Unconnected Height: 251 mm
Phasing - Phase Created: 2. nieuwbouw
Structural - Enable Analytical Model: no; Structural: no; Structural Usage: Non-bearing
Dimensions - Area: 3.70112 m2; Length: 14765.5 mm; Volume: 0.481146 m3
Identity Data - Workset: Workset1
Other - Family: Basic Wall; Family and Type: Basic Wall: NLRS_22_WA_HSB dakrand 130_gen_bdg; Type: NLRS_22_WA_HSB dakrand 130_gen_bdg; Type Id: 2369173

# IfcWallStandardCase: Basic Wall:NLRS_22_WA_HSB dakrand 160+10 _gen_bdg (18)
Type - PredefinedType: STANDARD; Material: n7_isolatie_glaswol 160 mm, i4_multiplex 10 mm
Type - Analytical Properties - Roughness: 1; Absorptance: 0.1
Type - Materials and Finishes - Structural Material: n7_isolatie_glaswol
Type - Graphics - Coarse Scale Fill Pattern: <Solid fill>; Coarse Scale Fill Color: 4210752
Type - Construction - Function: Interior; Wrapping at Inserts: Do not wrap; Width: 170 mm
Type - Identity Data - Workset: Wall Types; Assembly Code: 21.10; Assembly Description: buitenwanden; niet constructief, algemeen (verzamelniveau); Description: gevelsluitend element; SmartRevit_Versie: 2018.2; Type Name: NLRS_22_WA_HSB dakrand 160+10 _gen_bdg
Type - Other - Category: Walls; Family Name: Basic Wall
Classification: 21.10 Uniformat (Uniformat)
Cross-Section Definition - Cross-Section: Vertical
Constraints - Base Extension Distance: 0 mm; Base is Attached: no; Related to Mass: no; Room Bounding: yes; Top Extension Distance: 0 mm; Top is Attached: no
Phasing - Phase Created: 2. nieuwbouw
Structural - Enable Analytical Model: no; Structural: no; Structural Usage: Non-bearing
Identity Data - Workset: Workset1
Other - Family: Basic Wall; Family and Type: Basic Wall: NLRS_22_WA_HSB dakrand 160+10 _gen_bdg; Type: NLRS_22_WA_HSB dakrand 160+10 _gen_bdg; Type Id: 2246985
Name (Basic Wall:NLRS_22_WA_HSB dakrand 160+10 _gen_bdg:...) | In | Location Line | Top Constraint | Base Constraint | Base Offset (mm) | Top Offset (mm) | Unconnected Height (mm) | Area (m2) | Length (mm) | Volume (m3)
873807 | 02 tweede verdieping | Finish Face: Exterior | Up to level: 03 derde verdieping | 03 ok. ruwe vloer | -264 | 640 | 1204 | 30.1361 | 25030 | 5.12314
873808 | 02 tweede verdieping | Finish Face: Exterior | Up to level: 03 derde verdieping | 03 ok. ruwe vloer | -225 | 640 | 1165 | 28.9316 | 24834 | 4.91837
873809 | 02 tweede verdieping | Finish Face: Exterior | Up to level: 03 derde verdieping | 03 ok. ruwe vloer | -265 | 640 | 1205 | 30.1612 | 25030 | 5.1274
873810 | 02 tweede verdieping | Finish Face: Exterior | Up to level: 03 derde verdieping | 03 ok. ruwe vloer | -225 | 640 | 1165 | 28.9316 | 24834 | 4.91837
1914710 | 01 eerste verdieping | Finish Face: Exterior | Up to level: 02 dakrand gymzaal | 02 bk. constructie gymzaal | 108 | 35 | 627 | 9.30468 | 14670 | 1.5818
1914743 | 01 eerste verdieping | Finish Face: Exterior | Up to level: 02 dakrand gymzaal | 02 bk. constructie gymzaal | 108 | 35 | 627 | 14.2141 | 22670 | 2.4164
1914789 | 01 eerste verdieping | Finish Face: Exterior | Up to level: 02 dakrand gymzaal | 02 bk. constructie gymzaal | 108 | 35 | 627 | 9.19809 | 14670 | 1.56368
1914823 | 01 eerste verdieping | Finish Face: Exterior | Up to level: 02 dakrand gymzaal | 02 bk. constructie gymzaal | 108 | 35 | 627 | 14.1075 | 22670 | 2.39828
2033237 | 01 eerste verdieping | Finish Face: Exterior | Up to level: 01 eerste verdieping | 01 eerste verdieping | -50 | 775 | 825 | 5.46975 | 6630 | 0.929857
2247763 | 01 eerste verdieping | Core Face: Exterior | Up to level: 01 eerste verdieping | 01 eerste verdieping | -590 | 775 | 1365 | 9.26903 | 6790.5 | 1.57574
2248307 | 01 eerste verdieping | Core Face: Exterior | Up to level: 01 eerste verdieping | 01 eerste verdieping | -68 | 775 | 843 | 4.91055 | 5825.09 | 0.834793
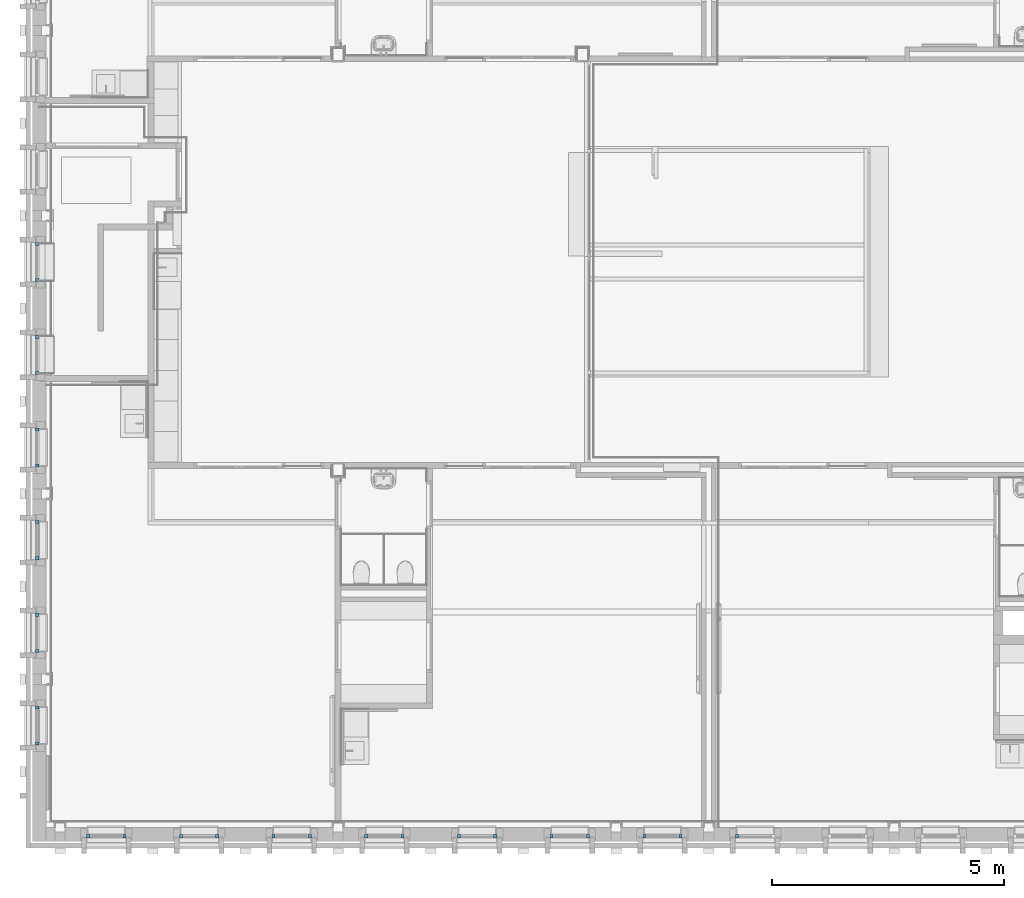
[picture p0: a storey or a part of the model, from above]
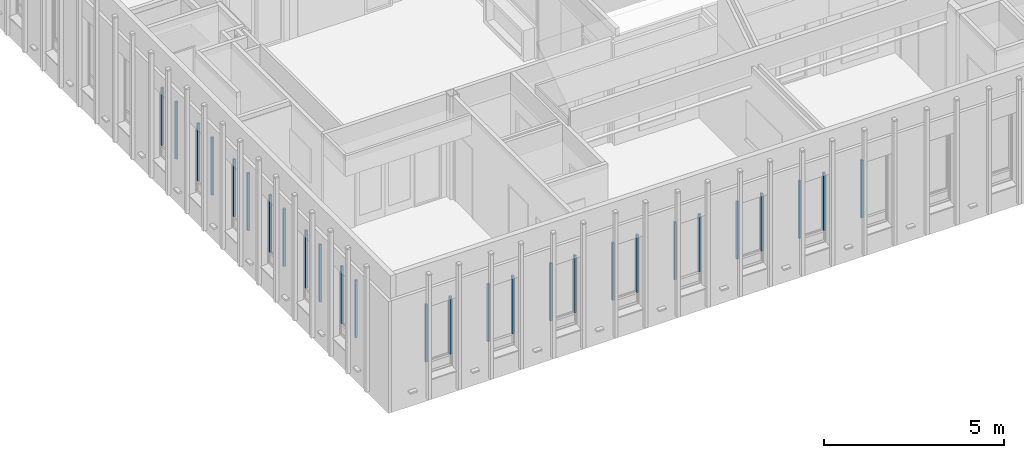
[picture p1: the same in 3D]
Properties of the parts of a building model (IFC2X3), part 90 of 94

# IfcWallStandardCase: Basic Wall:NLRS_22_WA_HSB dakrand 160+10 _gen_bdg (18)
Name (Basic Wall:NLRS_22_WA_HSB dakrand 160+10 _gen_bdg:...) | In | Location Line | Top Constraint | Base Constraint | Base Offset (mm) | Top Offset (mm) | Unconnected Height (mm) | Area (m2) | Length (mm) | Volume (m3)
2248536 | 01 eerste verdieping | Core Face: Exterior | Up to level: 01 eerste verdieping | 01 eerste verdieping | -50 | 775 | 825 | 1.17928 | 1295.91 | 0.18175 | Graphics - Center Mark Visible: no
2355767 | 00 begane grond | Core Face: Exterior | Up to level: 01 eerste verdieping | 01 ok. ruwe vloer | -375 | -68 | 677 | 6.59229 | 9737.5 | 1.12069
2548302 | 01 eerste verdieping | Finish Face: Exterior | Up to level: 01 eerste verdieping | 01 eerste verdieping | -50 | 775 | 825 | 12.5483 | 15250 | 2.1332
2548362 | 01 eerste verdieping | Finish Face: Exterior | Up to level: 01 eerste verdieping | 01 eerste verdieping | -50 | 775 | 825 | 0.1815 | 135 | 0.030855
2548388 | 01 eerste verdieping | Finish Face: Exterior | Up to level: 01 eerste verdieping | 01 eerste verdieping | -50 | 775 | 825 | 10.6342 | 12805 | 1.80782
2548389 | 01 eerste verdieping | Core Face: Exterior | Up to level: 01 eerste verdieping | 01 eerste verdieping | -590 | 775 | 1365 | 18.851 | 13840.5 | 3.20468
2548390 | 01 eerste verdieping | Finish Face: Exterior | Up to level: 01 eerste verdieping | 01 eerste verdieping | -50 | 775 | 825 | 5.2635 | 6550 | 0.894795

# IfcWallStandardCase: Basic Wall:NLRS_22_WA_HSB dakrand 180+10 _gen_bdg (7)
In: 01 eerste verdieping
Type - PredefinedType: STANDARD; Material: n7_isolatie_glaswol 180 mm, i4_multiplex 10 mm
Type - Analytical Properties - Roughness: 1; Absorptance: 0.1
Type - Materials and Finishes - Structural Material: n7_isolatie_glaswol
Type - Graphics - Coarse Scale Fill Pattern: <Solid fill>; Coarse Scale Fill Color: 4210752
Type - Construction - Function: Interior; Wrapping at Inserts: Do not wrap; Width: 190 mm
Type - Identity Data - Workset: Wall Types; Assembly Code: 21.10; Assembly Description: buitenwanden; niet constructief, algemeen (verzamelniveau); Description: gevelsluitend element; SmartRevit_Versie: 2018.2; Type Name: NLRS_22_WA_HSB dakrand 180+10 _gen_bdg
Type - Other - Category: Walls; Family Name: Basic Wall
Classification: 21.10 Uniformat (Uniformat)
Cross-Section Definition - Cross-Section: Vertical
Constraints - Base Extension Distance: 0 mm; Base is Attached: no; Related to Mass: no; Room Bounding: yes; Top Extension Distance: 0 mm; Top is Attached: no; Base Constraint: 01 eerste verdieping; Top Constraint: Up to level: 01 eerste verdieping; Top Offset: 775 mm
Phasing - Phase Created: 2. nieuwbouw
Structural - Enable Analytical Model: no; Structural: no; Structural Usage: Non-bearing
Identity Data - Workset: Workset1
Other - Family: Basic Wall; Family and Type: Basic Wall: NLRS_22_WA_HSB dakrand 180+10 _gen_bdg; Type: NLRS_22_WA_HSB dakrand 180+10 _gen_bdg; Type Id: 873837
Name (Basic Wall:NLRS_22_WA_HSB dakrand 180+10 _gen_bdg:...) | Location Line | Base Offset (mm) | Unconnected Height (mm) | Area (m2) | Length (mm) | Volume (m3) | Center Mark Visible | Group
1298821 | Finish Face: Exterior | -68 | 843 | 11.3894 | 13510.6 | 2.16399
1299897 | Finish Face: Exterior | -50 | 825 | 1.34126 | 1476.55 | 0.231434 | no
1300074 | Finish Face: Exterior | -50 | 825 | 0.144375 | 175 | 0.0274312
3345025 | Core Face: Exterior | -50 | 825 | 1.20884 | 1394.24 | 0.218553 | no | Model Group:21_rond:1344284
3345026 | Core Face: Exterior | -50 | 825 | 1.68375 | 1969.88 | 0.308779 | no | Model Group:21_rond:1344284
3345039 | Core Face: Exterior | -50 | 825 | 1.20884 | 1394.24 | 0.218553 | no | Model Group:21_rond:1344849
3345040 | Core Face: Exterior | -50 | 825 | 1.68375 | 1969.88 | 0.308779 | no | Model Group:21_rond:1344849

# IfcWallStandardCase: Basic Wall:NLRS_22_WA_HSB dakrand 60 _gen_bdg, Basic Wall:NLRS_22_WA_HSB dakrand 60 _gen_bdg:2367851
In: 01 eerste verdieping
Type - PredefinedType: STANDARD; Material: n7_isolatie_glaswol 60 mm
Type - Analytical Properties - Roughness: 1; Absorptance: 0.1
Type - Materials and Finishes - Structural Material: n7_isolatie_glaswol
Type - Graphics - Coarse Scale Fill Pattern: <Solid fill>; Coarse Scale Fill Color: 4210752
Type - Construction - Function: Interior; Wrapping at Inserts: Do not wrap; Width: 60 mm
Type - Identity Data - Workset: Wall Types; Assembly Code: 21.10; Assembly Description: buitenwanden; niet constructief, algemeen (verzamelniveau); Description: gevelsluitend element; SmartRevit_Versie: 2018.2; Type Name: NLRS_22_WA_HSB dakrand 60 _gen_bdg
Type - Other - Category: Walls; Family Name: Basic Wall
Classification: 21.10 Uniformat (Uniformat)
Cross-Section Definition - Cross-Section: Vertical
Constraints - Base Extension Distance: 0 mm; Base is Attached: no; Location Line: Finish Face: Exterior; Related to Mass: no; Room Bounding: yes; Top Extension Distance: 0 mm; Top is Attached: no; Top Constraint: Up to level: 02 bk. constructie gymzaal; Base Constraint: 02 bk. constructie gymzaal; Base Offset: -153 mm; Top Offset: 108 mm; Unconnected Height: 261 mm
Phasing - Phase Created: 2. nieuwbouw
Structural - Enable Analytical Model: no; Structural: no; Structural Usage: Non-bearing
Dimensions - Area: 5.90251 m2; Length: 22730 mm; Volume: 0.354151 m3
Identity Data - Workset: Workset1
Other - Family: Basic Wall; Family and Type: Basic Wall: NLRS_22_WA_HSB dakrand 60 _gen_bdg; Type: NLRS_22_WA_HSB dakrand 60 _gen_bdg; Type Id: 2367315

# IfcWallStandardCase: Basic Wall:NLRS_22_WA_HSB dakrand 90+10 _gen_bdg, Basic Wall:NLRS_22_WA_HSB dakrand 90+10 _gen_bdg:5096521
In: 01 eerste verdieping
Type - PredefinedType: STANDARD; Material: n7_isolatie_glaswol 90 mm, i4_multiplex 10 mm
Type - Analytical Properties - Roughness: 1; Absorptance: 0.1
Type - Materials and Finishes - Structural Material: n7_isolatie_glaswol
Type - Graphics - Coarse Scale Fill Pattern: <Solid fill>; Coarse Scale Fill Color: 4210752
Type - Construction - Function: Interior; Wrapping at Inserts: Do not wrap; Width: 100 mm
Type - Identity Data - Workset: Wall Types; Assembly Code: 21.10; Assembly Description: buitenwanden; niet constructief, algemeen (verzamelniveau); Description: gevelsluitend element; SmartRevit_Versie: 2018.2; Type Name: NLRS_22_WA_HSB dakrand 90+10 _gen_bdg
Type - Other - Category: Walls; Family Name: Basic Wall
Classification: 21.10 Uniformat (Uniformat)
Cross-Section Definition - Cross-Section: Vertical
Constraints - Base Extension Distance: 0 mm; Base is Attached: no; Related to Mass: no; Room Bounding: yes; Top Extension Distance: 0 mm; Top is Attached: no; Base Constraint: 01 eerste verdieping; Top Constraint: Up to level: 01 eerste verdieping; Location Line: Core Face: Exterior; Base Offset: -50 mm; Top Offset: 775 mm; Unconnected Height: 825 mm
Phasing - Phase Created: 2. nieuwbouw
Structural - Enable Analytical Model: no; Structural: no; Structural Usage: Non-bearing
Dimensions - Area: 4.389 m2; Length: 5270 mm; Volume: 0.4389 m3
Identity Data - Workset: Workset1
Other - Family: Basic Wall; Family and Type: Basic Wall: NLRS_22_WA_HSB dakrand 90+10 _gen_bdg; Type: NLRS_22_WA_HSB dakrand 90+10 _gen_bdg; Type Id: 5098152

# IfcWallStandardCase: Basic Wall:NLRS_22_WA_HSB rek 15-170-12-13_gen_ISR (3)
Type - PredefinedType: STANDARD; Material: ISR_Vezelcement 15 mm, n7_isolatie_gen 170 mm, i4_multiplex 12 mm, f7_gipsvezel 13 mm
Type - Analytical Properties - Roughness: 1; Absorptance: 0.1
Type - Materials and Finishes - Structural Material: n7_isolatie_gen
Type - Graphics - Coarse Scale Fill Pattern: <Solid fill>; Coarse Scale Fill Color: 4210752
Type - Construction - Function: Interior; Wrapping at Inserts: Do not wrap; Width: 210 mm
Type - Identity Data - Workset: Wall Types; Assembly Code: 21.10; Assembly Description: buitenwanden; niet constructief, algemeen (verzamelniveau); Description: gevelsluitend element; SmartRevit_Versie: 2018.2; Type Name: NLRS_22_WA_HSB rek 15-170-12-13_gen_ISR
Type - Other - Category: Walls; Family Name: Basic Wall
Classification: 21.10 Uniformat (Uniformat)
Cross-Section Definition - Cross-Section: Vertical
Constraints - Base Extension Distance: 0 mm; Base is Attached: no; Location Line: Finish Face: Exterior; Related to Mass: no; Room Bounding: yes; Top Extension Distance: 0 mm; Top is Attached: no; Base Offset: -30 mm
Phasing - Phase Created: 2. nieuwbouw
Structural - Enable Analytical Model: no; Structural: no; Structural Usage: Non-bearing
Identity Data - Workset: Workset1
Other - Family: Basic Wall; Family and Type: Basic Wall: NLRS_22_WA_HSB rek 15-170-12-13_gen_ISR; Type: NLRS_22_WA_HSB rek 15-170-12-13_gen_ISR; Type Id: 1836028
Name (Basic Wall:NLRS_22_WA_HSB rek 15-170-12-13_gen_ISR:...) | In | Base Constraint | Top Constraint | Top Offset (mm) | Unconnected Height (mm) | Area (m2) | Length (mm) | Volume (m3)
1836027 | 01 eerste verdieping | 01 eerste verdieping | Up to level: 01 eerste verdieping | 227 | 257 | 0.514 | 2000 | 0.10794
1836200 | 01 eerste verdieping | 01 eerste verdieping | Up to level: 01 eerste verdieping | 312 | 342 | 0.569223 | 1832 | 0.106078
1849231 | 02 tweede verdieping | 02 tweede verdieping | Up to level: 02 tweede verdieping | 295 | 325 | 1.4885 | 4906 | 0.289528

# IfcWallStandardCase: Basic Wall:NLRS_22_WA_akoestische voorzetwand hout gym 15_gen_bdg (4)
In: 00 begane grond
Type - PredefinedType: STANDARD; Material: i4_hout_Eiken_gen 15 mm
Type - Analytical Properties - Roughness: 1; Absorptance: 0.1
Type - Graphics - Coarse Scale Fill Pattern: <Solid fill>; Coarse Scale Fill Color: 4210752
Type - Construction - Function: Interior; Wrapping at Inserts: Do not wrap; Width: 15 mm
Type - Identity Data - Workset: Wall Types; Assembly Code: 21.10; Assembly Description: buitenwanden; niet constructief, algemeen (verzamelniveau); Description: akoestische voorzetwand; SmartRevit_Versie: 2018.2; Type Name: NLRS_22_WA_akoestische voorzetwand hout gym 15_gen_bdg
Type - Other - Category: Walls; Family Name: Basic Wall
Classification: 21.10 Uniformat (Uniformat)
Cross-Section Definition - Cross-Section: Vertical
Constraints - Base Extension Distance: 0 mm; Base is Attached: no; Related to Mass: no; Room Bounding: yes; Top Extension Distance: 0 mm; Top is Attached: no; Base Constraint: 00 begane grond; Base Offset: 0 mm; Top Constraint: Up to level: 00 begane grond; Location Line: Core Face: Exterior
Phasing - Phase Created: 2. nieuwbouw
Structural - Enable Analytical Model: no; Structural: no; Structural Usage: Non-bearing
Identity Data - Workset: Workset1
Other - Family: Basic Wall; Family and Type: Basic Wall: NLRS_22_WA_akoestische voorzetwand hout gym 15_gen_bdg; Type: NLRS_22_WA_akoestische voorzetwand hout gym 15_gen_bdg; Type Id: 3225903
Name (Basic Wall:NLRS_22_WA_akoestische voorzetwand hout gym 15_gen_bdg:...) | Top Offset (mm) = Unconnected Height (mm) | Area (m2) | Length (mm) | Volume (m3)
3226473 | 2665 | 9.74057 | 3655 | 0.146109
3226845 | 2000 | 3.485 | 1742.5 | 0.052275
3226957 | 2000 | 3.485 | 1742.5 | 0.052275
4192086 | 2507 | 1.57941 | 630 | 0.0236911

# IfcWallStandardCase: Basic Wall:NLRS_22_WA_akoestische voorzetwand hout gym 96_gen_bdg (7)
In: 00 begane grond
Type - PredefinedType: STANDARD; Material: i4_hout_Eiken_gen 15 mm, ISR_Luchtspouw 18 mm, BDG_Vilt 10 mm, BDG_Vilt 3 mm, n7_isolatie_glaswol 50 mm
Type - Analytical Properties - Roughness: 1; Absorptance: 0.1
Type - Materials and Finishes - Structural Material: ISR_Luchtspouw
Type - Graphics - Coarse Scale Fill Pattern: <Solid fill>; Coarse Scale Fill Color: 4210752
Type - Construction - Function: Interior; Wrapping at Inserts: Do not wrap; Width: 96 mm
Type - Identity Data - Workset: Wall Types; Assembly Code: 21.10; Assembly Description: buitenwanden; niet constructief, algemeen (verzamelniveau); Description: akoestische voorzetwand; SmartRevit_Versie: 2018.2; Type Name: NLRS_22_WA_akoestische voorzetwand hout gym 96_gen_bdg
Type - Other - Category: Walls; Family Name: Basic Wall
Classification: 21.10 Uniformat (Uniformat)
Cross-Section Definition - Cross-Section: Vertical
Constraints - Base Extension Distance: 0 mm; Base is Attached: no; Related to Mass: no; Room Bounding: yes; Top Extension Distance: 0 mm; Top is Attached: no; Base Constraint: 00 begane grond; Top Constraint: Up to level: 00 begane grond; Location Line: Finish Face: Interior; Top Offset: 4000 mm
Phasing - Phase Created: 2. nieuwbouw
Structural - Enable Analytical Model: no; Structural: no; Structural Usage: Non-bearing
Identity Data - Workset: Workset1
Other - Family: Basic Wall; Family and Type: Basic Wall: NLRS_22_WA_akoestische voorzetwand hout gym 96_gen_bdg; Type: NLRS_22_WA_akoestische voorzetwand hout gym 96_gen_bdg; Type Id: 1500251
Name (Basic Wall:NLRS_22_WA_akoestische voorzetwand hout gym 96_gen_bdg:...) | Base Offset (mm) | Unconnected Height (mm) | Area (m2) | Length (mm) | Volume (m3)
1500221 | 0 | 4000 | 14.0591 | 5672 | 1.34968
1500223 | 0 | 4000 | 78.8487 | 22144 | 7.56947
1500224 | 0 | 4000 | 41.6852 | 14144 | 4.00178
1502015 | 0 | 4000 | 41.7751 | 12697 | 4.01041
1510277 | 0 | 4000 | 42.2025 | 13073 | 3.97924
3225500 | 0 | 4000 | 1.508 | 425 | 0.144768
3225526 | 2515 | 1485 | 0.95931 | 646 | 0.0920938

# IfcWallStandardCase: Basic Wall:NLRS_22_WA_cellenbeton 100_gen_bdg (11)
Type - PredefinedType: STANDARD; Material: g2_metselwerk_betonblok 100 mm
Type - Analytical Properties - Roughness: 1; Absorptance: 0.1
Type - Materials and Finishes - Structural Material: g2_metselwerk_betonblok
Type - Graphics - Coarse Scale Fill Pattern: <Solid fill>; Coarse Scale Fill Color: 4210752
Type - Construction - Function: Interior; Wrapping at Inserts: Do not wrap; Width: 100 mm
Type - Identity Data - Workset: Wall Types; Assembly Code: 22.21.41; Assembly Description: binnenmuur, gestort beton; Description: prefab beton 180mm; Model: LOD300; SmartRevit_Versie: 2018.2; Type Name: NLRS_22_WA_cellenbeton 100_gen_bdg
Type - Other - Category: Walls; Family Name: Basic Wall
Classification: 22.21.41 Uniformat (Uniformat)
Cross-Section Definition - Cross-Section: Vertical
Constraints - Base Extension Distance: 0 mm; Base is Attached: no; Location Line: Finish Face: Exterior; Related to Mass: no; Room Bounding: yes; Top Extension Distance: 0 mm; Top is Attached: no
Phasing - Phase Created: 2. nieuwbouw
Structural - Enable Analytical Model: no; Structural: no; Structural Usage: Non-bearing
Identity Data - Workset: Workset1
Other - Family: Basic Wall; Family and Type: Basic Wall: NLRS_22_WA_cellenbeton 100_gen_bdg; Type: NLRS_22_WA_cellenbeton 100_gen_bdg; Type Id: 880553
Name (Basic Wall:NLRS_22_WA_cellenbeton 100_gen_bdg:...) | In | Base Constraint | Top Constraint | Base Offset (mm) | Top Offset (mm) | Unconnected Height (mm) | Area (m2) | Length (mm) | Volume (m3)
880522 | 02 tweede verdieping | 02 tweede verdieping | Up to level: 02 tweede verdieping | -50 | 184 | 234 | 2.29273 | 9928 | 0.229273
1305896 | 01 eerste verdieping | 01 eerste verdieping | Up to level: 01 eerste verdieping | -50 | 150 | 200 | 1.53 | 9450 | 0.153
1341639 | 01 eerste verdieping | 01 eerste verdieping | Up to level: 01 eerste verdieping | -50 | 150 | 200 | 0.211 | 1055 | 0.0211
1347511 | 01 eerste verdieping | 01 eerste verdieping | Up to level: 01 eerste verdieping | -50 | 150 | 200 | 1.2005 | 9450 | 0.12005
1347512 | 01 eerste verdieping | 01 eerste verdieping | Up to level: 01 eerste verdieping | -50 | 150 | 200 | 1.525 | 7575 | 0.1525
1347513 | 01 eerste verdieping | 01 eerste verdieping | Up to level: 01 eerste verdieping | -50 | 150 | 200 | 0.024 | 220 | 0.0024
2301021 | 01 eerste verdieping | 01 eerste verdieping | Up to level: 01 eerste verdieping | -50 | 150 | 200 | 0.822 | 4110 | 0.0822
2303148 | 01 eerste verdieping | 01 eerste verdieping | Up to level: 01 eerste verdieping | -50 | 171 | 221 | 0.884 | 4000 | 0.0884
2304045 | 02 tweede verdieping | 02 tweede verdieping | Up to level: 02 tweede verdieping | -50 | 150 | 200 | 1.9596 | 9928 | 0.19596
4689128 | 00 begane grond | 01 bk. ruwe vloer | Up to level: 01 eerste verdieping | 0 | 171 | 221 | 5.75042 | 26020 | 0.575042
4689399 | 00 begane grond | 01 bk. ruwe vloer | Up to level: 01 eerste verdieping | 0 | 110 | 160 | 0.1476 | 972.5 | 0.01476

# IfcWallStandardCase: Basic Wall:NLRS_22_WA_iso+binnenafw 12+13 _gen_bdg 2, Basic Wall:NLRS_22_WA_iso+binnenafw 12+13 _gen_bdg 2:2368460
In: 01 eerste verdieping
Type - PredefinedType: STANDARD; Material: f7_gips 13 mm, i4_multiplex 12 mm
Type - Analytical Properties - Roughness: 1; Absorptance: 0.1
Type - Materials and Finishes - Structural Material: i4_multiplex
Type - Graphics - Coarse Scale Fill Pattern: <Solid fill>; Coarse Scale Fill Color: 4210752
Type - Construction - Function: Interior; Wrapping at Inserts: Do not wrap; Width: 25 mm
Type - Identity Data - Workset: Wall Types; Assembly Code: 21.10; Assembly Description: buitenwanden; niet constructief, algemeen (verzamelniveau); Description: gevelsluitend element; SmartRevit_Versie: 2018.2; Type Name: NLRS_22_WA_iso+binnenafw 12+13 _gen_bdg 2
Type - Other - Category: Walls; Family Name: Basic Wall
Classification: 21.10 Uniformat (Uniformat)
Cross-Section Definition - Cross-Section: Vertical
Constraints - Base Extension Distance: 0 mm; Base is Attached: no; Location Line: Finish Face: Exterior; Related to Mass: no; Room Bounding: yes; Top Extension Distance: 0 mm; Top is Attached: no; Top Offset: 0 mm; Top Constraint: Up to level: 02 bk. constructie gymzaal; Base Constraint: 02 bk. constructie gymzaal; Base Offset: -153 mm; Unconnected Height: 153 mm
Phasing - Phase Created: 2. nieuwbouw
Structural - Enable Analytical Model: no; Structural: no; Structural Usage: Non-bearing
Dimensions - Area: 2.18836 m2; Length: 14322.8 mm; Volume: 0.054709 m3
Identity Data - Workset: Workset1
Other - Family: Basic Wall; Family and Type: Basic Wall: NLRS_22_WA_iso+binnenafw 12+13 _gen_bdg 2; Type: NLRS_22_WA_iso+binnenafw 12+13 _gen_bdg 2; Type Id: 2369309

# IfcWallStandardCase: Basic Wall:NLRS_22_WA_iso+binnenafw 38+12+13 _gen_bdg (2)
In: 01 eerste verdieping
Type - PredefinedType: STANDARD; Material: f7_gips 13 mm, i4_multiplex 12 mm, n7_isolatie_glaswol 38 mm
Type - Analytical Properties - Roughness: 1; Absorptance: 0.1
Type - Materials and Finishes - Structural Material: i4_multiplex
Type - Graphics - Coarse Scale Fill Pattern: <Solid fill>; Coarse Scale Fill Color: 4210752
Type - Construction - Function: Interior; Wrapping at Inserts: Do not wrap; Width: 63 mm
Type - Identity Data - Workset: Wall Types; Assembly Code: 21.10; Assembly Description: buitenwanden; niet constructief, algemeen (verzamelniveau); Description: gevelsluitend element; SmartRevit_Versie: 2018.2; Type Name: NLRS_22_WA_iso+binnenafw 38+12+13 _gen_bdg
Type - Other - Category: Walls; Family Name: Basic Wall
Classification: 21.10 Uniformat (Uniformat)
Cross-Section Definition - Cross-Section: Vertical
Constraints - Base Extension Distance: 0 mm; Base is Attached: no; Location Line: Finish Face: Exterior; Related to Mass: no; Room Bounding: yes; Top Extension Distance: 0 mm; Top is Attached: no; Top Offset: 0 mm; Top Constraint: Up to level: 02 bk. constructie gymzaal; Base Constraint: 02 bk. constructie gymzaal; Base Offset: -153 mm; Unconnected Height: 153 mm
Phasing - Phase Created: 2. nieuwbouw
Structural - Enable Analytical Model: no; Structural: no; Structural Usage: Non-bearing
Identity Data - Workset: Workset1
Other - Family: Basic Wall; Family and Type: Basic Wall: NLRS_22_WA_iso+binnenafw 38+12+13 _gen_bdg; Type: NLRS_22_WA_iso+binnenafw 38+12+13 _gen_bdg; Type Id: 2368870
Name (Basic Wall:NLRS_22_WA_iso+binnenafw 38+12+13 _gen_bdg:...) | Area (m2) | Length (mm) | Volume (m3)
2368513 | 3.41236 | 22284 | 0.214979
2368544 | 2.17872 | 14322.7 | 0.137259

# IfcWallStandardCase: Basic Wall:NLRS_22_WA_iso+binnenafw 77.5+12+13 _gen_bdg, Basic Wall:NLRS_22_WA_iso+binnenafw 77.5+12+13 _gen_bdg:2367797
In: 01 eerste verdieping
Type - PredefinedType: STANDARD; Material: f7_gipsvezel 13 mm, i4_multiplex 12 mm, n7_isolatie_glaswol 77.5 mm
Type - Analytical Properties - Roughness: 1; Absorptance: 0.1
Type - Materials and Finishes - Structural Material: i4_multiplex
Type - Graphics - Coarse Scale Fill Pattern: <Solid fill>; Coarse Scale Fill Color: 4210752
Type - Construction - Function: Interior; Wrapping at Inserts: Do not wrap; Width: 102.5 mm
Type - Identity Data - Workset: Wall Types; Assembly Code: 21.10; Assembly Description: buitenwanden; niet constructief, algemeen (verzamelniveau); Description: gevelsluitend element; SmartRevit_Versie: 2018.2; Type Name: NLRS_22_WA_iso+binnenafw 77.5+12+13 _gen_bdg
Type - Other - Category: Walls; Family Name: Basic Wall
Classification: 21.10 Uniformat (Uniformat)
Cross-Section Definition - Cross-Section: Vertical
Constraints - Base Extension Distance: 0 mm; Base is Attached: no; Location Line: Finish Face: Exterior; Related to Mass: no; Room Bounding: yes; Top Extension Distance: 0 mm; Top is Attached: no; Top Offset: 0 mm; Top Constraint: Up to level: 02 bk. constructie gymzaal; Base Constraint: 02 bk. constructie gymzaal; Base Offset: -153 mm; Unconnected Height: 153 mm
Phasing - Phase Created: 2. nieuwbouw
Structural - Enable Analytical Model: no; Structural: no; Structural Usage: Non-bearing
Dimensions - Area: 3.41618 m2; Length: 22284 mm; Volume: 0.350159 m3
Identity Data - Workset: Workset1
Other - Family: Basic Wall; Family and Type: Basic Wall: NLRS_22_WA_iso+binnenafw 77.5+12+13 _gen_bdg; Type: NLRS_22_WA_iso+binnenafw 77.5+12+13 _gen_bdg; Type Id: 2367730

# IfcWallStandardCase: Basic Wall:NLRS_41_WA_akoestische panelen 40_gen_ISR (54)
Type - PredefinedType: STANDARD; Material: f7_binnenwandafwerking 1 mm, ISR_Luchtspouw 39 mm
Type - Analytical Properties - Roughness: 1; Absorptance: 0.1
Type - Graphics - Coarse Scale Fill Pattern: <Solid fill>; Coarse Scale Fill Color: 4210752
Type - Construction - Function: Interior; Wrapping at Inserts: Do not wrap; Wrapping at Ends: Exterior; Width: 40 mm
Type - Identity Data - Workset: Wall Types; Assembly Code: 41.12; Assembly Description: buitenwandafwerkingen; bekledingen; Description: beplating 12mm; Model: LOD300; SmartRevit_Versie: 2018.2; Type Mark: ak. pan.; Type Name: NLRS_41_WA_akoestische panelen 40_gen_ISR
Type - Other - Category: Walls; Family Name: Basic Wall
Classification: 41.12 Uniformat (Uniformat)
Cross-Section Definition - Cross-Section: Vertical
Constraints - Base Extension Distance: 0 mm; Base is Attached: no; Related to Mass: no; Top Extension Distance: 0 mm; Top is Attached: no; Unconnected Height: 1160 mm
Phasing - Phase Created: 2. nieuwbouw
Structural - Enable Analytical Model: no; Structural: no; Structural Usage: Non-bearing
Dimensions - Area: 1.3456 m2; Length: 1160 mm; Volume: 0.053824 m3
Identity Data - Workset: Workset1
Other - Family: Basic Wall; Family and Type: Basic Wall: NLRS_41_WA_akoestische panelen 40_gen_ISR; Type: NLRS_41_WA_akoestische panelen 40_gen_ISR; Type Id: 3671017
Name (Basic Wall:NLRS_41_WA_akoestische panelen 40_gen_ISR:...) | In | Location Line | Base Constraint | Top Offset (mm) | Room Bounding | Base Offset (mm)
3671464 | 01 eerste verdieping | Finish Face: Exterior | 01 eerste verdieping | 0 | no | 1450
3671625 | 01 eerste verdieping | Finish Face: Exterior | 01 eerste verdieping | 0 | no | 1450
3671626 | 01 eerste verdieping | Finish Face: Exterior | 01 eerste verdieping | 0 | no | 1450
3672144 | 01 eerste verdieping | Finish Face: Exterior | 01 eerste verdieping | 0 | no | 1450
3672145 | 01 eerste verdieping | Finish Face: Exterior | 01 eerste verdieping | 0 | no | 1450
3672550 | 01 eerste verdieping | Finish Face: Exterior | 01 eerste verdieping | 0 | no | 250
3672721 | 01 eerste verdieping | Finish Face: Exterior | 01 eerste verdieping | 0 | no | 1450
3672722 | 01 eerste verdieping | Finish Face: Exterior | 01 eerste verdieping | 0 | no | 1450
3672723 | 00 begane grond | Finish Face: Exterior | 00 ok. plafond | 0 | no | 1450
3672780 | 01 eerste verdieping | Finish Face: Exterior | 01 eerste verdieping | 0 | no | 1450
3672781 | 01 eerste verdieping | Finish Face: Exterior | 01 eerste verdieping | 0 | no | 1450
3672782 | 01 eerste verdieping | Finish Face: Exterior | 01 eerste verdieping | 0 | no | 1450
3672835 | 01 eerste verdieping | Finish Face: Exterior | 01 eerste verdieping | 0 | no | 1450
3672836 | 01 eerste verdieping | Finish Face: Exterior | 01 eerste verdieping | 0 | no | 1450
3672883 | 01 eerste verdieping | Finish Face: Exterior | 01 eerste verdieping | 0 | no | 1450
3673547 | 01 eerste verdieping | Finish Face: Exterior | 01 eerste verdieping | 0 | no | 1450
3673548 | 01 eerste verdieping | Finish Face: Exterior | 01 eerste verdieping | 0 | no | 1450
3673549 | 01 eerste verdieping | Finish Face: Exterior | 01 eerste verdieping | 0 | no | 1450
3673855 | 02 tweede verdieping | Finish Face: Exterior | 02 tweede verdieping | 0 | no | 1450
3673856 | 02 tweede verdieping | Finish Face: Exterior | 02 tweede verdieping | 0 | no | 1450
3673903 | 02 tweede verdieping | Finish Face: Exterior | 02 tweede verdieping | 0 | no | 1450
3674080 | 02 tweede verdieping | Finish Face: Exterior | 02 tweede verdieping | 0 | no | 1450
3674081 | 02 tweede verdieping | Finish Face: Exterior | 02 tweede verdieping | 0 | no | 1450
3674219 | 02 tweede verdieping | Finish Face: Exterior | 02 tweede verdieping | 0 | no | 1450
3674220 | 02 tweede verdieping | Finish Face: Exterior | 02 tweede verdieping | 0 | no | 1450
3674688 | 02 tweede verdieping | Finish Face: Exterior | 02 tweede verdieping | 0 | no | 1450
3674689 | 02 tweede verdieping | Finish Face: Exterior | 02 tweede verdieping | 0 | no | 1450
3674735 | 02 tweede verdieping | Finish Face: Exterior | 02 tweede verdieping | 0 | no | 1450
3674896 | 02 tweede verdieping | Finish Face: Exterior | 02 tweede verdieping | 0 | no | 1450
3674897 | 02 tweede verdieping | Finish Face: Exterior | 02 tweede verdieping | 0 | no | 1450
3675373 | 02 tweede verdieping | Finish Face: Exterior | 02 tweede verdieping | 0 | no | 1450
3675699 | 02 tweede verdieping | Finish Face: Exterior | 02 tweede verdieping | 0 | no | 1450
3675925 | 02 tweede verdieping | Finish Face: Exterior | 02 tweede verdieping | 0 | no | 1450
3975401 | 02 tweede verdieping | Finish Face: Exterior | 02 tweede verdieping | 0 | no | 240
3975697 | 02 tweede verdieping | Finish Face: Exterior | 02 tweede verdieping | 0 | no | 1450
3975698 | 02 tweede verdieping | Finish Face: Exterior | 02 tweede verdieping | 0 | no | 240
3975939 | 02 tweede verdieping | Finish Face: Exterior | 02 tweede verdieping | 0 | no | 240
3976191 | 02 tweede verdieping | Finish Face: Exterior | 02 tweede verdieping | 0 | no | 240
3976363 | 02 tweede verdieping | Finish Face: Exterior | 02 tweede verdieping | 0 | no | 1450
3976538 | 02 tweede verdieping | Finish Face: Exterior | 02 tweede verdieping | 0 | no | 1450
3976617 | 02 tweede verdieping | Finish Face: Exterior | 02 tweede verdieping | 0 | no | 240
3976707 | 02 tweede verdieping | Finish Face: Exterior | 02 tweede verdieping | 0 | no | 240
3977875 | 00 begane grond | Finish Face: Interior | 00 begane grond | -153 | yes | 1450
3978014 | 00 begane grond | Finish Face: Interior | 00 begane grond | -153 | yes | 1450
3978089 | 00 begane grond | Finish Face: Interior | 00 begane grond | -153 | yes | 240
3978174 | 00 begane grond | Finish Face: Interior | 00 begane grond | -153 | yes | 1450
3978175 | 00 begane grond | Finish Face: Interior | 00 begane grond | -153 | yes | 1450
3978176 | 00 begane grond | Finish Face: Interior | 00 begane grond | -153 | yes | 240
3978178 | 00 begane grond | Finish Face: Interior | 00 begane grond | -153 | yes | 1450
3978179 | 00 begane grond | Finish Face: Interior | 00 begane grond | -153 | yes | 1450
3978180 | 00 begane grond | Finish Face: Interior | 00 begane grond | -153 | yes | 240
3978181 | 00 begane grond | Finish Face: Interior | 00 begane grond | -153 | yes | 1450
3978182 | 00 begane grond | Finish Face: Interior | 00 begane grond | -153 | yes | 1450
3978183 | 00 begane grond | Finish Face: Interior | 00 begane grond | -153 | yes | 240

# IfcWallStandardCase: Basic Wall:NLRS_41_WA_alu panelen 54+4_gen_ISR (8)
In: 01 eerste verdieping
Type - PredefinedType: STANDARD; Material: Aluminium 4 mm, ISR_Luchtspouw 54 mm
Type - Analytical Properties - Roughness: 1; Absorptance: 0.1
Type - Graphics - Coarse Scale Fill Pattern: <Solid fill>; Coarse Scale Fill Color: 4210752
Type - Construction - Function: Interior; Wrapping at Inserts: Do not wrap; Wrapping at Ends: Exterior; Width: 58 mm
Type - Identity Data - Workset: Wall Types; Assembly Code: 41.12; Assembly Description: buitenwandafwerkingen; bekledingen; Description: beplating 12mm; Model: LOD300; SmartRevit_Versie: 2018.2; Type Name: NLRS_41_WA_alu panelen 54+4_gen_ISR
Type - Other - Category: Walls; Family Name: Basic Wall
Classification: 41.12 Uniformat (Uniformat)
Cross-Section Definition - Cross-Section: Vertical
Constraints - Base Extension Distance: 0 mm; Base is Attached: no; Location Line: Finish Face: Exterior; Related to Mass: no; Room Bounding: yes; Top Extension Distance: 0 mm; Top is Attached: no; Base Constraint: 01 eerste verdieping; Top Constraint: Up to level: 02 bk. constructie gymzaal; Base Offset: 235.5 mm; Top Offset: 565 mm; Unconnected Height: 2829.5 mm
Phasing - Phase Created: 2. nieuwbouw
Structural - Enable Analytical Model: no; Structural: no; Structural Usage: Non-bearing
Dimensions - Area: 2.95683 m2; Length: 1045 mm; Volume: 0.171496 m3
Identity Data - Workset: Workset1
Other - Family: Basic Wall; Family and Type: Basic Wall: NLRS_41_WA_alu panelen 54+4_gen_ISR; Type: NLRS_41_WA_alu panelen 54+4_gen_ISR; Type Id: 3669062
Name (Basic Wall:NLRS_41_WA_alu panelen 54+4_gen_ISR:...)
3669986
4014937
4014946
4014955
4014964
4014973
4014982
4015077

# IfcWallStandardCase: Basic Wall:NLRS_41_WA_aluminium voorzet 20+15+22_gen_ISR (4)
In: 00 begane grond
Type - PredefinedType: STANDARD; Material: Aluminium_RAL7022 2 mm, ISR_Luchtspouw 18 mm, i4_multiplex 15 mm, ISR_Luchtspouw 22 mm
Type - Analytical Properties - Roughness: 1; Absorptance: 0.1
Type - Graphics - Coarse Scale Fill Pattern: <Solid fill>; Coarse Scale Fill Color: 4210752
Type - Construction - Function: Interior; Wrapping at Inserts: Do not wrap; Width: 57 mm
Type - Identity Data - Workset: Wall Types; Assembly Code: 41.12; Assembly Description: buitenwandafwerkingen; bekledingen; Description: beplating 12mm; Model: LOD300; SmartRevit_Versie: 2018.2; Type Name: NLRS_41_WA_aluminium voorzet 20+15+22_gen_ISR
Type - Other - Category: Walls; Family Name: Basic Wall
Classification: 41.12 Uniformat (Uniformat)
Cross-Section Definition - Cross-Section: Vertical
Constraints - Base Extension Distance: 0 mm; Base is Attached: no; Related to Mass: no; Room Bounding: yes; Top Extension Distance: 0 mm; Top is Attached: no; Base Constraint: 00 begane grond; Top Constraint: Up to level: 00 begane grond; Location Line: Finish Face: Interior; Base Offset: -30 mm; Top Offset: 3020 mm; Unconnected Height: 3050 mm
Phasing - Phase Created: 2. nieuwbouw
Structural - Enable Analytical Model: no; Structural: no; Structural Usage: Non-bearing
Identity Data - Workset: Workset1
Other - Family: Basic Wall; Family and Type: Basic Wall: NLRS_41_WA_aluminium voorzet 20+15+22_gen_ISR; Type: NLRS_41_WA_aluminium voorzet 20+15+22_gen_ISR; Type Id: 3613219
Name (Basic Wall:NLRS_41_WA_aluminium voorzet 20+15+22_gen_ISR:...) | Area (m2) | Length (mm) | Volume (m3)
1938116 | 3.0805 | 981.5 | 0.175588
1938146 | 3.89028 | 1304 | 0.221746
1938983 | 0.75335 | 275.5 | 0.042941
3701713 | 12.411 | 4086.5 | 0.707426

# IfcWallStandardCase: Basic Wall:NLRS_41_WA_beplating 12_gen_ISR (55)
Type - PredefinedType: STANDARD; Material: f7_gips 12 mm
Type - Analytical Properties - Roughness: 1; Absorptance: 0.1
Type - Materials and Finishes - Structural Material: f7_gips
Type - Graphics - Coarse Scale Fill Pattern: <Solid fill>; Coarse Scale Fill Color: 4210752
Type - Construction - Function: Interior; Wrapping at Inserts: Do not wrap; Width: 12 mm
Type - Identity Data - Workset: Wall Types; Assembly Code: 41.12; Assembly Description: buitenwandafwerkingen; bekledingen; Description: beplating 12mm; Model: LOD300; SmartRevit_Versie: 2018.2; Type Name: NLRS_41_WA_beplating 12_gen_ISR
Type - Other - Category: Walls; Family Name: Basic Wall
Classification: 41.12 Uniformat (Uniformat)
Cross-Section Definition - Cross-Section: Vertical
Constraints - Base Extension Distance: 0 mm; Base is Attached: no; Related to Mass: no; Top Extension Distance: 0 mm; Top is Attached: no
Phasing - Phase Created: 2. nieuwbouw
Structural - Enable Analytical Model: no; Structural: no; Structural Usage: Non-bearing
Identity Data - Workset: Workset1
Other - Family: Basic Wall; Family and Type: Basic Wall: NLRS_41_WA_beplating 12_gen_ISR; Type: NLRS_41_WA_beplating 12_gen_ISR; Type Id: 474266
Name (Basic Wall:NLRS_41_WA_beplating 12_gen_ISR:...) | In | Base Constraint | Location Line | Room Bounding | Base Offset (mm) | Top Offset (mm) | Unconnected Height (mm) | Area (m2) | Length (mm) | Volume (m3)
2411522 | 00 begane grond | 00 begane grond | Wall Centerline | no | 150 | 2000 | 1850 | 3.6445 | 1970 | 0.043734 | Constraints - Top Constraint: Up to level: 00 begane grond
2411523 | 00 begane grond | 00 begane grond | Wall Centerline | yes | 150 | 2000 | 1850 | 0.74 | 400 | 0.00888 | Constraints - Top Constraint: Up to level: 00 begane grond
2411526 | 00 begane grond | 00 begane grond | Wall Centerline | no | 150 | 2000 | 1850 | 3.6445 | 1970 | 0.043734 | Constraints - Top Constraint: Up to level: 00 begane grond
2411527 | 00 begane grond | 00 begane grond | Wall Centerline | yes | 150 | 2000 | 1850 | 0.74 | 400 | 0.00888 | Constraints - Top Constraint: Up to level: 00 begane grond
2440522 | 00 begane grond | 00 begane grond | Wall Centerline | yes | 150 | 2000 | 1850 | 0.888 | 480 | 0.010656 | Constraints - Top Constraint: Up to level: 00 begane grond
2862583 | 00 begane grond | 00 begane grond | Finish Face: Interior | yes | 900 | 250 | 600 | 0.945 | 1575 | 0.01134
2862927 | 00 begane grond | 00 begane grond | Finish Face: Exterior | yes | 900 | 250 | 300 | 0.54 | 1800 | 0.00648
2863116 | 00 begane grond | 00 begane grond | Finish Face: Exterior | yes | 900 | 250 | 300 | 0.3588 | 1208 | 0.0043056
2863353 | 00 begane grond | 00 begane grond | Finish Face: Exterior | yes | 900 | 250 | 300 | 0.156749 | 584.996 | 0.00188098
2863455 | 00 begane grond | 00 begane grond | Finish Face: Interior | yes | 900 | 250 | 300 | 0.18 | 594 | 0.00216
2863507 | 00 begane grond | 00 begane grond | Finish Face: Interior | yes | 900 | 250 | 300 | 0.3624 | 1208 | 0.0043488
2863531 | 00 begane grond | 00 begane grond | Finish Face: Interior | yes | 900 | 250 | 300 | 0.1764 | 594 | 0.0021168
2863923 | 01 eerste verdieping | 01 eerste verdieping | Finish Face: Interior | yes | 900 | 250 | 300 | 0.363 | 1204 | 0.004356
2863952 | 01 eerste verdieping | 01 eerste verdieping | Finish Face: Interior | yes | 900 | 250 | 300 | 0.1764 | 594 | 0.0021168
2864036 | 01 eerste verdieping | 01 eerste verdieping | Finish Face: Interior | yes | 900 | 250 | 300 | 0.18 | 594 | 0.00216
2864072 | 01 eerste verdieping | 01 eerste verdieping | Finish Face: Interior | yes | 900 | 250 | 300 | 0.3594 | 1204 | 0.0043128
2864140 | 01 eerste verdieping | 01 eerste verdieping | Finish Face: Interior | yes | 900 | 250 | 300 | 0.363 | 1204 | 0.004356
2864163 | 01 eerste verdieping | 01 eerste verdieping | Finish Face: Interior | yes | 900 | 250 | 300 | 0.1764 | 594 | 0.0021168
2864223 | 01 eerste verdieping | 01 eerste verdieping | Finish Face: Interior | yes | 900 | 250 | 300 | 0.18 | 594 | 0.00216
2864257 | 01 eerste verdieping | 01 eerste verdieping | Finish Face: Interior | yes | 900 | 250 | 300 | 0.355194 | 1189.98 | 0.00426232
2864319 | 01 eerste verdieping | 01 eerste verdieping | Finish Face: Interior | yes | 900 | 250 | 300 | 0.363 | 1204 | 0.004356
2864350 | 01 eerste verdieping | 01 eerste verdieping | Finish Face: Interior | yes | 900 | 250 | 300 | 0.1764 | 594 | 0.0021168
2864400 | 01 eerste verdieping | 01 eerste verdieping | Finish Face: Interior | yes | 900 | 250 | 300 | 0.18 | 594 | 0.00216
2864430 | 01 eerste verdieping | 01 eerste verdieping | Finish Face: Interior | yes | 900 | 250 | 300 | 0.3594 | 1204 | 0.0043128
2864510 | 01 eerste verdieping | 01 eerste verdieping | Finish Face: Interior | yes | 900 | 250 | 300 | 0.18 | 594 | 0.00216
2864553 | 01 eerste verdieping | 01 eerste verdieping | Finish Face: Interior | yes | 900 | 250 | 300 | 0.3594 | 1204 | 0.0043128
2865751 | 02 tweede verdieping | 02 tweede verdieping | Finish Face: Interior | yes | 900 | 250 | 300 | 0.363 | 1204 | 0.004356
2865752 | 02 tweede verdieping | 02 tweede verdieping | Finish Face: Interior | yes | 900 | 250 | 300 | 0.1764 | 594 | 0.0021168
2865753 | 02 tweede verdieping | 02 tweede verdieping | Finish Face: Interior | yes | 900 | 250 | 300 | 0.18 | 594 | 0.00216
2865754 | 02 tweede verdieping | 02 tweede verdieping | Finish Face: Interior | yes | 900 | 250 | 300 | 0.3594 | 1204 | 0.0043128
2865757 | 02 tweede verdieping | 02 tweede verdieping | Finish Face: Interior | yes | 900 | 250 | 300 | 0.18 | 594 | 0.00216
2865758 | 02 tweede verdieping | 02 tweede verdieping | Finish Face: Interior | yes | 900 | 250 | 300 | 0.3594 | 1204 | 0.0043128
2865759 | 02 tweede verdieping | 02 tweede verdieping | Finish Face: Interior | yes | 900 | 250 | 300 | 0.363 | 1204 | 0.004356
2865760 | 02 tweede verdieping | 02 tweede verdieping | Finish Face: Interior | yes | 900 | 250 | 300 | 0.1764 | 594 | 0.0021168
2865761 | 02 tweede verdieping | 02 tweede verdieping | Finish Face: Interior | yes | 900 | 250 | 300 | 0.363 | 1204 | 0.004356
2865762 | 02 tweede verdieping | 02 tweede verdieping | Finish Face: Interior | yes | 900 | 250 | 300 | 0.1764 | 594 | 0.0021168
2865763 | 02 tweede verdieping | 02 tweede verdieping | Finish Face: Interior | yes | 900 | 250 | 300 | 0.18 | 594 | 0.00216
2865764 | 02 tweede verdieping | 02 tweede verdieping | Finish Face: Interior | yes | 900 | 250 | 300 | 0.3594 | 1204 | 0.0043128
2866535 | 00 begane grond | 00 begane grond | Finish Face: Interior | yes | 900 | 250 | 300 | 0.4725 | 1575 | 0.00567
3199747 | 02 tweede verdieping | 02 tweede verdieping | Finish Face: Interior | yes | 900 | 250 | 300 | 0.18 | 594 | 0.00216
3199748 | 02 tweede verdieping | 02 tweede verdieping | Finish Face: Interior | yes | 900 | 250 | 300 | 0.3594 | 1204 | 0.0043128
4747935 | 01 eerste verdieping | 01 eerste verdieping | Finish Face: Interior | yes | 900 | 250 | 300 | 0.723 | 2404 | 0.008676
4747936 | 01 eerste verdieping | 01 eerste verdieping | Finish Face: Interior | yes | 900 | 250 | 300 | 0.1764 | 594 | 0.0021168
4748017 | 01 eerste verdieping | 01 eerste verdieping | Finish Face: Interior | yes | 900 | 250 | 150 | 0.2715 | 1804 | 0.003258
4748018 | 01 eerste verdieping | 01 eerste verdieping | Finish Face: Interior | yes | 900 | 250 | 150 | 0.0882 | 594 | 0.0010584
5027842 | 00 begane grond | 00 begane grond | Finish Face: Exterior | yes | 900 | 250 | 300 | 0.366 | 1208 | 0.004392
5027843 | 00 begane grond | 00 begane grond | Finish Face: Exterior | yes | 900 | 250 | 300 | 0.1764 | 594 | 0.0021168
5027844 | 00 begane grond | 00 begane grond | Finish Face: Exterior | yes | 900 | 250 | 300 | 0.1764 | 594 | 0.0021168
5027934 | 00 begane grond | 00 begane grond | Finish Face: Exterior | yes | 900 | 250 | 300 | 0.180001 | 662.504 | 0.00216002
5027935 | 00 begane grond | 00 begane grond | Finish Face: Exterior | yes | 900 | 250 | 300 | 0.180001 | 662.504 | 0.00216002
5027936 | 00 begane grond | 00 begane grond | Finish Face: Exterior | yes | 900 | 250 | 300 | 0.3624 | 1208 | 0.0043488
5027937 | 00 begane grond | 00 begane grond | Finish Face: Exterior | yes | 900 | 250 | 300 | 0.1764 | 594 | 0.0021168
5027938 | 00 begane grond | 00 begane grond | Finish Face: Exterior | yes | 900 | 250 | 300 | 0.366 | 1208 | 0.004392
5027939 | 00 begane grond | 00 begane grond | Finish Face: Exterior | yes | 900 | 250 | 300 | 0.1764 | 594 | 0.0021168
5027940 | 00 begane grond | 00 begane grond | Finish Face: Exterior | yes | 900 | 250 | 300 | 0.1764 | 594 | 0.0021168

# IfcWallStandardCase: Basic Wall:NLRS_41_WA_beplating cement 12_gen_ISR 2 (4)
In: 03 derde verdieping
Type - PredefinedType: STANDARD; Material: ISR_Vezelcement 12 mm
Type - Analytical Properties - Roughness: 1; Absorptance: 0.1
Type - Materials and Finishes - Structural Material: ISR_Vezelcement
Type - Graphics - Coarse Scale Fill Pattern: <Solid fill>; Coarse Scale Fill Color: 4210752
Type - Construction - Function: Interior; Wrapping at Inserts: Do not wrap; Width: 12 mm
Type - Identity Data - Workset: Wall Types; Assembly Code: 41.12; Assembly Description: buitenwandafwerkingen; bekledingen; Description: beplating 12mm; Model: LOD300; SmartRevit_Versie: 2018.2; Type Name: NLRS_41_WA_beplating cement 12_gen_ISR 2
Type - Other - Category: Walls; Family Name: Basic Wall
Classification: 41.12 Uniformat (Uniformat)
Cross-Section Definition - Cross-Section: Vertical
Constraints - Base Extension Distance: 0 mm; Base is Attached: no; Related to Mass: no; Room Bounding: yes; Top Extension Distance: 0 mm; Top is Attached: no; Top Offset: 0 mm; Base Constraint: 03 derde verdieping; Location Line: Wall Centerline; Base Offset: 250 mm; Unconnected Height: 1531 mm
Phasing - Phase Created: 2. nieuwbouw
Structural - Enable Analytical Model: no; Structural: no; Structural Usage: Non-bearing
Identity Data - Workset: Workset1
Other - Family: Basic Wall; Family and Type: Basic Wall: NLRS_41_WA_beplating cement 12_gen_ISR 2; Type: NLRS_41_WA_beplating cement 12_gen_ISR 2; Type Id: 2444130
Name (Basic Wall:NLRS_41_WA_beplating cement 12_gen_ISR 2:...) | Area (m2) | Length (mm) | Volume (m3) | Group
2194541 | 4.05469 | 6506 | 0.0486562 | Model Group:daklicht A1:2182252
2194584 | 4.05469 | 6506 | 0.0486562 | Model Group:daklicht A1 (members excluded):2182288
2194600 | 7.58768 | 12707.5 | 0.0910522 | Model Group:BU-42 daklicht B lokaal:2182308
2194785 | 7.58768 | 12707.5 | 0.0910522 | Model Group:BU-42 daklicht B lokaal:2194782

# IfcWallStandardCase: Basic Wall:NLRS_41_WA_brandwerende beplating 15_gen_ISR (239)
Type - PredefinedType: STANDARD; Material: ISR_brandwerende beplating 15 mm
Type - Analytical Properties - Roughness: 1; Absorptance: 0.1
Type - Graphics - Coarse Scale Fill Pattern: <Solid fill>; Coarse Scale Fill Color: 4210752
Type - Construction - Function: Interior; Wrapping at Inserts: Do not wrap; Width: 15 mm
Type - Identity Data - Workset: Wall Types; Assembly Code: 41.12; Assembly Description: buitenwandafwerkingen; bekledingen; Description: sanitairwand 13mm; Model: LOD300; SmartRevit_Versie: 2018.2; Type Name: NLRS_41_WA_brandwerende beplating 15_gen_ISR
Type - Other - Category: Walls; Family Name: Basic Wall
Classification: 41.12 Uniformat (Uniformat)
Cross-Section Definition - Cross-Section: Vertical
Constraints - Base Extension Distance: 0 mm; Base is Attached: no; Related to Mass: no; Room Bounding: yes; Top Extension Distance: 0 mm; Top is Attached: no
Phasing - Phase Created: 2. nieuwbouw
Structural - Enable Analytical Model: no; Structural: no; Structural Usage: Non-bearing
Identity Data - Workset: Workset1
Other - Family: Basic Wall; Family and Type: Basic Wall: NLRS_41_WA_brandwerende beplating 15_gen_ISR; Type: NLRS_41_WA_brandwerende beplating 15_gen_ISR; Type Id: 3011353
Name (Basic Wall:NLRS_41_WA_brandwerende beplating 15_gen_ISR:...) | In | Base Constraint | Top Constraint | Base Offset (mm) | Location Line | Top Offset (mm) | Unconnected Height (mm) | Area (m2) | Length (mm) | Volume (m3)
2724545 | 00 begane grond | 00 begane grond | Up to level: 01 ok. ruwe vloer | 0 | Finish Face: Interior | -60 | 3570 | 0.91035 | 247.5 | 0.0136553
2724578 | 00 begane grond | 00 begane grond | Up to level: 01 ok. ruwe vloer | 0 | Finish Face: Interior | -60 | 3570 | 0.91035 | 255 | 0.0136553
2724608 | 00 begane grond | 00 begane grond | Up to level: 01 ok. ruwe vloer | 0 | Finish Face: Interior | -60 | 3570 | 0.8568 | 247.5 | 0.012852
2724906 | 00 begane grond | 00 begane grond | Up to level: 01 ok. ruwe vloer | 0 | Finish Face: Interior | -60 | 3570 | 0.48195 | 127.5 | 0.00722925
2724908 | 00 begane grond | 00 begane grond | Up to level: 01 ok. ruwe vloer | 0 | Finish Face: Interior | -60 | 3570 | 0.48195 | 127.5 | 0.00722925
2724915 | 00 begane grond | 00 begane grond | Up to level: 01 ok. ruwe vloer | 0 | Finish Face: Interior | -60 | 3570 | 0.48195 | 127.5 | 0.00722925
2725037 | 00 begane grond | 00 begane grond | Up to level: 01 ok. ruwe vloer | 0 | Finish Face: Interior | -60 | 3570 | 0.580125 | 217.5 | 0.00870187
2725038 | 00 begane grond | 00 begane grond | Up to level: 01 ok. ruwe vloer | 0 | Finish Face: Interior | -60 | 3570 | 0.4284 | 127.5 | 0.006426
2725880 | 00 begane grond | 00 begane grond | Up to level: 01 ok. ruwe vloer | 0 | Finish Face: Interior | -60 | 3570 | 0.48195 | 127.5 | 0.00722925
2725882 | 00 begane grond | 00 begane grond | Up to level: 01 ok. ruwe vloer | 0 | Finish Face: Interior | -60 | 3570 | 0.48195 | 127.5 | 0.00722925
2725895 | 00 begane grond | 00 begane grond | Up to level: 01 ok. ruwe vloer | 0 | Finish Face: Interior | -60 | 3570 | 0.37485 | 97.5 | 0.00562275
2725897 | 00 begane grond | 00 begane grond | Up to level: 01 ok. ruwe vloer | 0 | Finish Face: Interior | -60 | 3570 | 0.37485 | 97.5 | 0.00562275
2727261 | 00 begane grond | 00 begane grond | Up to level: 01 ok. ruwe vloer | 0 | Finish Face: Interior | -60 | 3570 | 0.37485 | 97.5 | 0.00562275
2727288 | 00 begane grond | 00 begane grond | Up to level: 01 ok. ruwe vloer | 0 | Finish Face: Interior | -60 | 3570 | 0.47124 | 202 | 0.0070686
2727430 | 00 begane grond | 00 begane grond | Up to level: 01 ok. ruwe vloer | 0 | Finish Face: Interior | -60 | 3570 | 0.37485 | 97.5 | 0.00562275
2727431 | 00 begane grond | 00 begane grond | Up to level: 01 ok. ruwe vloer | 0 | Finish Face: Interior | -60 | 3570 | 0.69615 | 195 | 0.0104423
2727443 | 00 begane grond | 00 begane grond | Up to level: 01 ok. ruwe vloer | 0 | Finish Face: Interior | -60 | 3570 | 0.37485 | 97.5 | 0.00562275
2727444 | 00 begane grond | 00 begane grond | Up to level: 01 ok. ruwe vloer | 0 | Finish Face: Interior | -60 | 3570 | 0.69615 | 195 | 0.0104423
2727455 | 00 begane grond | 00 begane grond | Up to level: 01 ok. ruwe vloer | 0 | Finish Face: Interior | -60 | 3570 | 0.37485 | 97.5 | 0.00562275
2727456 | 00 begane grond | 00 begane grond | Up to level: 01 ok. ruwe vloer | 0 | Finish Face: Interior | -60 | 3570 | 0.69615 | 195 | 0.0104423
2727481 | 00 begane grond | 00 begane grond | Up to level: 01 ok. ruwe vloer | 0 | Finish Face: Interior | -60 | 3570 | 0.3213 | 97.5 | 0.0048195
2727506 | 00 begane grond | 00 begane grond | Up to level: 01 ok. ruwe vloer | 0 | Finish Face: Interior | -60 | 3570 | 0.3213 | 97.5 | 0.0048195
2727531 | 00 begane grond | 00 begane grond | Up to level: 01 ok. ruwe vloer | 0 | Finish Face: Interior | -60 | 3570 | 0.3213 | 97.5 | 0.0048195
2734386 | 00 begane grond | 00 begane grond | Up to level: 01 ok. ruwe vloer | 0 | Finish Face: Interior | -60 | 3570 | 0.48195 | 127.5 | 0.00722925
2734387 | 00 begane grond | 00 begane grond | Up to level: 01 ok. ruwe vloer | 0 | Finish Face: Interior | -60 | 3570 | 0.91035 | 255 | 0.0136553
2734388 | 00 begane grond | 00 begane grond | Up to level: 01 ok. ruwe vloer | 0 | Finish Face: Interior | -60 | 3570 | 0.4284 | 127.5 | 0.006426
2735048 | 00 begane grond | 00 begane grond | Up to level: 01 ok. ruwe vloer | 0 | Finish Face: Interior | -60 | 3570 | 0.48195 | 127.5 | 0.00722925
2735083 | 00 begane grond | 00 begane grond | Up to level: 01 ok. ruwe vloer | 0 | Finish Face: Interior | -60 | 3570 | 0.36414 | 169.5 | 0.0054621
2735124 | 00 begane grond | 00 begane grond | Up to level: 01 ok. ruwe vloer | 0 | Finish Face: Interior | -60 | 3570 | 0.8211 | 215 | 0.0123165
2735148 | 00 begane grond | 00 begane grond | Up to level: 01 ok. ruwe vloer | 0 | Finish Face: Interior | -60 | 3570 | 0.357 | 107.5 | 0.005355
2735178 | 00 begane grond | 00 begane grond | Up to level: 01 ok. ruwe vloer | 0 | Finish Face: Interior | -60 | 3570 | 0.357 | 107.5 | 0.005355
2735403 | 00 begane grond | 00 begane grond | Up to level: 01 ok. ruwe vloer | 0 | Finish Face: Interior | -60 | 3570 | 0.7497 | 195 | 0.0112455
2735404 | 00 begane grond | 00 begane grond | Up to level: 01 ok. ruwe vloer | 0 | Finish Face: Interior | -60 | 3570 | 0.3213 | 97.5 | 0.0048195
2735405 | 00 begane grond | 00 begane grond | Up to level: 01 ok. ruwe vloer | 0 | Finish Face: Interior | -60 | 3570 | 0.3213 | 97.5 | 0.0048195
2735517 | 00 begane grond | 00 begane grond | Up to level: 01 ok. ruwe vloer | 0 | Finish Face: Interior | -60 | 3570 | 1.1067 | 295 | 0.0166005
2735518 | 00 begane grond | 00 begane grond | Up to level: 01 ok. ruwe vloer | 0 | Finish Face: Interior | -60 | 3570 | 0.4998 | 147.5 | 0.007497
2735519 | 00 begane grond | 00 begane grond | Up to level: 01 ok. ruwe vloer | 0 | Finish Face: Interior | -60 | 3570 | 0.4998 | 147.5 | 0.007497
2735675 | 00 begane grond | 00 begane grond | Up to level: 01 ok. ruwe vloer | 0 | Finish Face: Interior | -60 | 3570 | 0.933555 | 254 | 0.0140033
2735677 | 00 begane grond | 00 begane grond | Up to level: 01 ok. ruwe vloer | 0 | Finish Face: Interior | -60 | 3570 | 0.4284 | 127.5 | 0.006426
2735828 | 00 begane grond | 00 begane grond | Up to level: 01 ok. ruwe vloer | 0 | Finish Face: Interior | -60 | 3570 | 0.933555 | 254 | 0.0140033
2735829 | 00 begane grond | 00 begane grond | Up to level: 01 ok. ruwe vloer | 0 | Finish Face: Interior | -60 | 3570 | 0.4284 | 127.5 | 0.006426
2735929 | 00 begane grond | 00 begane grond | Up to level: 01 ok. ruwe vloer | 0 | Finish Face: Interior | -60 | 3570 | 0.48195 | 127.5 | 0.00722925
2735930 | 00 begane grond | 00 begane grond | Up to level: 01 ok. ruwe vloer | 0 | Finish Face: Interior | -60 | 3570 | 0.4284 | 127.5 | 0.006426
2735931 | 00 begane grond | 00 begane grond | Up to level: 01 ok. ruwe vloer | 0 | Finish Face: Interior | -60 | 3570 | 0.4284 | 127.5 | 0.006426
2735960 | 00 begane grond | 00 begane grond | Up to level: 01 ok. ruwe vloer | 0 | Finish Face: Interior | -60 | 3570 | 0.48195 | 127.5 | 0.00722925
2736131 | 00 begane grond | 00 begane grond | Up to level: 01 ok. ruwe vloer | 0 | Finish Face: Interior | -60 | 3570 | 0.9639 | 255 | 0.0144585
2736132 | 00 begane grond | 00 begane grond | Up to level: 01 ok. ruwe vloer | 0 | Finish Face: Interior | -60 | 3570 | 0.4284 | 127.5 | 0.006426
2736133 | 00 begane grond | 00 begane grond | Up to level: 01 ok. ruwe vloer | 0 | Finish Face: Interior | -60 | 3570 | 0.4284 | 127.5 | 0.006426
2736144 | 00 begane grond | 00 begane grond | Up to level: 01 ok. ruwe vloer | 0 | Finish Face: Interior | -60 | 3570 | 0.9639 | 255 | 0.0144585
2736145 | 00 begane grond | 00 begane grond | Up to level: 01 ok. ruwe vloer | 0 | Finish Face: Interior | -60 | 3570 | 0.4284 | 127.5 | 0.006426
2736146 | 00 begane grond | 00 begane grond | Up to level: 01 ok. ruwe vloer | 0 | Finish Face: Interior | -60 | 3570 | 0.4284 | 127.5 | 0.006426
2744770 | 01 eerste verdieping | 01 eerste verdieping | Up to level: 02 ok. ruwe vloer | 0 | Finish Face: Interior | 0 | 3430 | 0.87465 | 255 | 0.0131198
2778670 | 02 tweede verdieping | 02 tweede verdieping | Up to level: 03 bk. ruwe vloer | 0 | Finish Face: Interior | 0 | 3750 | 0.8625 | 215 | 0.0129375
3079867 | 00 begane grond | 00 begane grond | Up to level: 01 ok. ruwe vloer | 0 | Finish Face: Interior | -60 | 3570 | 1.06208 | 352.5 | 0.0159311
3079890 | 00 begane grond | 00 begane grond | Up to level: 01 ok. ruwe vloer | 0 | Finish Face: Interior | -60 | 3570 | 1.05315 | 295 | 0.0157973
3079919 | 00 begane grond | 00 begane grond | Up to level: 01 ok. ruwe vloer | 0 | Finish Face: Interior | -60 | 3570 | 1.00853 | 352.5 | 0.0151279
3079985 | 00 begane grond | 00 begane grond | Up to level: 01 ok. ruwe vloer | 0 | Finish Face: Interior | -60 | 3570 | 1.06208 | 352.5 | 0.0159311
3079986 | 00 begane grond | 00 begane grond | Up to level: 01 ok. ruwe vloer | 0 | Finish Face: Interior | -60 | 3570 | 1.05315 | 295 | 0.0157973
3079987 | 00 begane grond | 00 begane grond | Up to level: 01 ok. ruwe vloer | 0 | Finish Face: Interior | -60 | 3570 | 1.00853 | 352.5 | 0.0151279
3179426 | 02 tweede verdieping | 02 tweede verdieping | Up to level: 03 bk. ruwe vloer | 0 | Finish Face: Interior | 0 | 3750 | 0.43125 | 107.5 | 0.00646875
3179447 | 02 tweede verdieping | 02 tweede verdieping | Up to level: 03 bk. ruwe vloer | 0 | Finish Face: Interior | 0 | 3750 | 0.80625 | 215 | 0.0120938
3179482 | 02 tweede verdieping | 02 tweede verdieping | Up to level: 03 bk. ruwe vloer | 0 | Finish Face: Interior | 0 | 3750 | 0.375 | 107.5 | 0.005625
3179683 | 02 tweede verdieping | 02 tweede verdieping | Up to level: 03 bk. ruwe vloer | 0 | Finish Face: Interior | 0 | 3750 | 0.43125 | 107.5 | 0.00646875
3179684 | 02 tweede verdieping | 02 tweede verdieping | Up to level: 03 bk. ruwe vloer | 0 | Finish Face: Interior | 0 | 3750 | 0.80625 | 215 | 0.0120938
3179685 | 02 tweede verdieping | 02 tweede verdieping | Up to level: 03 bk. ruwe vloer | 0 | Finish Face: Interior | 0 | 3750 | 0.375 | 107.5 | 0.005625
3179696 | 02 tweede verdieping | 02 tweede verdieping | Up to level: 03 bk. ruwe vloer | 0 | Finish Face: Interior | 0 | 3750 | 0.43125 | 107.5 | 0.00646875
3179697 | 02 tweede verdieping | 02 tweede verdieping | Up to level: 03 bk. ruwe vloer | 0 | Finish Face: Interior | 0 | 3750 | 0.80625 | 215 | 0.0120938
3179698 | 02 tweede verdieping | 02 tweede verdieping | Up to level: 03 bk. ruwe vloer | 0 | Finish Face: Interior | 0 | 3750 | 0.375 | 107.5 | 0.005625
3179709 | 02 tweede verdieping | 02 tweede verdieping | Up to level: 03 bk. ruwe vloer | 0 | Finish Face: Interior | 0 | 3750 | 0.43125 | 107.5 | 0.00646875
3179710 | 02 tweede verdieping | 02 tweede verdieping | Up to level: 03 bk. ruwe vloer | 0 | Finish Face: Interior | 0 | 3750 | 0.80625 | 215 | 0.0120938
3179711 | 02 tweede verdieping | 02 tweede verdieping | Up to level: 03 bk. ruwe vloer | 0 | Finish Face: Interior | 0 | 3750 | 0.375 | 107.5 | 0.005625
3179720 | 02 tweede verdieping | 02 tweede verdieping | Up to level: 03 bk. ruwe vloer | 0 | Finish Face: Interior | 0 | 3750 | 0.43125 | 107.5 | 0.00646875
3179721 | 02 tweede verdieping | 02 tweede verdieping | Up to level: 03 bk. ruwe vloer | 0 | Finish Face: Interior | 0 | 3750 | 0.80625 | 215 | 0.0120938
3179722 | 02 tweede verdieping | 02 tweede verdieping | Up to level: 03 bk. ruwe vloer | 0 | Finish Face: Interior | 0 | 3750 | 0.375 | 107.5 | 0.005625
3179731 | 02 tweede verdieping | 02 tweede verdieping | Up to level: 03 bk. ruwe vloer | 0 | Finish Face: Interior | 0 | 3750 | 0.43125 | 107.5 | 0.00646875
3179732 | 02 tweede verdieping | 02 tweede verdieping | Up to level: 03 bk. ruwe vloer | 0 | Finish Face: Interior | 0 | 3750 | 0.80625 | 215 | 0.0120938
3179733 | 02 tweede verdieping | 02 tweede verdieping | Up to level: 03 bk. ruwe vloer | 0 | Finish Face: Interior | 0 | 3750 | 0.375 | 107.5 | 0.005625
3179789 | 02 tweede verdieping | 02 tweede verdieping | Up to level: 03 bk. ruwe vloer | 0 | Finish Face: Interior | 0 | 3750 | 0.43125 | 107.5 | 0.00646875
3179790 | 02 tweede verdieping | 02 tweede verdieping | Up to level: 03 bk. ruwe vloer | 0 | Finish Face: Interior | 0 | 3750 | 0.80625 | 215 | 0.0120938
3179791 | 02 tweede verdieping | 02 tweede verdieping | Up to level: 03 bk. ruwe vloer | 0 | Finish Face: Interior | 0 | 3750 | 0.375 | 107.5 | 0.005625
3179800 | 02 tweede verdieping | 02 tweede verdieping | Up to level: 03 bk. ruwe vloer | 0 | Finish Face: Interior | 0 | 3750 | 0.43125 | 107.5 | 0.00646875
3179801 | 02 tweede verdieping | 02 tweede verdieping | Up to level: 03 bk. ruwe vloer | 0 | Finish Face: Interior | 0 | 3750 | 0.80625 | 215 | 0.0120938
3179802 | 02 tweede verdieping | 02 tweede verdieping | Up to level: 03 bk. ruwe vloer | 0 | Finish Face: Interior | 0 | 3750 | 0.375 | 107.5 | 0.005625
3179813 | 02 tweede verdieping | 02 tweede verdieping | Up to level: 03 bk. ruwe vloer | 0 | Finish Face: Interior | 0 | 3750 | 0.43125 | 107.5 | 0.00646875
3179814 | 02 tweede verdieping | 02 tweede verdieping | Up to level: 03 bk. ruwe vloer | 0 | Finish Face: Interior | 0 | 3750 | 0.80625 | 215 | 0.0120938
3179815 | 02 tweede verdieping | 02 tweede verdieping | Up to level: 03 bk. ruwe vloer | 0 | Finish Face: Interior | 0 | 3750 | 0.375 | 107.5 | 0.005625
3179824 | 02 tweede verdieping | 02 tweede verdieping | Up to level: 03 bk. ruwe vloer | 0 | Finish Face: Interior | 0 | 3750 | 0.43125 | 107.5 | 0.00646875
3179825 | 02 tweede verdieping | 02 tweede verdieping | Up to level: 03 bk. ruwe vloer | 0 | Finish Face: Interior | 0 | 3750 | 0.80625 | 215 | 0.0120938
3179826 | 02 tweede verdieping | 02 tweede verdieping | Up to level: 03 bk. ruwe vloer | 0 | Finish Face: Interior | 0 | 3750 | 0.375 | 107.5 | 0.005625
3180373 | 01 eerste verdieping | 01 eerste verdieping | Up to level: 02 ok. ruwe vloer | 0 | Finish Face: Interior | 0 | 3430 | 0.7889 | 215 | 0.0118335
3180374 | 01 eerste verdieping | 01 eerste verdieping | Up to level: 02 ok. ruwe vloer | 0 | Finish Face: Interior | 0 | 3430 | 0.343 | 107.5 | 0.005145
3180375 | 01 eerste verdieping | 01 eerste verdieping | Up to level: 02 ok. ruwe vloer | 0 | Finish Face: Interior | 0 | 3430 | 0.343 | 107.5 | 0.005145
3180449 | 01 eerste verdieping | 01 eerste verdieping | Up to level: 02 ok. ruwe vloer | 0 | Finish Face: Interior | 0 | 3430 | 0.7889 | 215 | 0.0118335
3180450 | 01 eerste verdieping | 01 eerste verdieping | Up to level: 02 ok. ruwe vloer | 0 | Finish Face: Interior | 0 | 3430 | 0.343 | 107.5 | 0.005145
3180451 | 01 eerste verdieping | 01 eerste verdieping | Up to level: 02 ok. ruwe vloer | 0 | Finish Face: Interior | 0 | 3430 | 0.343 | 107.5 | 0.005145
3180460 | 01 eerste verdieping | 01 eerste verdieping | Up to level: 02 ok. ruwe vloer | 0 | Finish Face: Interior | 0 | 3430 | 0.7889 | 215 | 0.0118335
3180461 | 01 eerste verdieping | 01 eerste verdieping | Up to level: 02 ok. ruwe vloer | 0 | Finish Face: Interior | 0 | 3430 | 0.63455 | 192.5 | 0.00951825
3180462 | 01 eerste verdieping | 01 eerste verdieping | Up to level: 02 ok. ruwe vloer | 0 | Finish Face: Interior | 0 | 3430 | 0.634087 | 192.365 | 0.0095113
3180505 | 01 eerste verdieping | 01 eerste verdieping | Up to level: 02 ok. ruwe vloer | 0 | Finish Face: Interior | 0 | 3430 | 0.39445 | 107.5 | 0.00591675
3180507 | 01 eerste verdieping | 01 eerste verdieping | Up to level: 02 ok. ruwe vloer | 0 | Finish Face: Interior | 0 | 3430 | 0.343 | 107.5 | 0.005145
3189508 | 01 eerste verdieping | 01 eerste verdieping | Up to level: 02 ok. ruwe vloer | 0 | Finish Face: Interior | 0 | 3430 | 0.7889 | 215 | 0.0118335
3189509 | 01 eerste verdieping | 01 eerste verdieping | Up to level: 02 ok. ruwe vloer | 0 | Finish Face: Interior | 0 | 3430 | 0.686 | 215 | 0.01029
3189510 | 01 eerste verdieping | 01 eerste verdieping | Up to level: 02 ok. ruwe vloer | 0 | Finish Face: Interior | 0 | 3430 | 0.73125 | 299.5 | 0.0109687
3189530 | 01 eerste verdieping | 01 eerste verdieping | Up to level: 02 ok. ruwe vloer | 0 | Finish Face: Interior | 0 | 3430 | 0.73745 | 215 | 0.0110618
3526958 | 00 begane grond | 00 begane grond | Up to level: 01 ok. ruwe vloer | 0 | Finish Face: Interior | -60 | 3570 | 0.8568 | 255 | 0.012852
3526959 | 00 begane grond | 00 begane grond | Up to level: 01 ok. ruwe vloer | 0 | Finish Face: Interior | -60 | 3570 | 1.13348 | 427.5 | 0.0170021
3526960 | 00 begane grond | 00 begane grond | Up to level: 01 ok. ruwe vloer | 0 | Finish Face: Interior | -60 | 3570 | 0.8568 | 255 | 0.012852
3526961 | 00 begane grond | 00 begane grond | Up to level: 01 ok. ruwe vloer | 0 | Finish Face: Interior | -60 | 3570 | 0.6426 | 195 | 0.009639
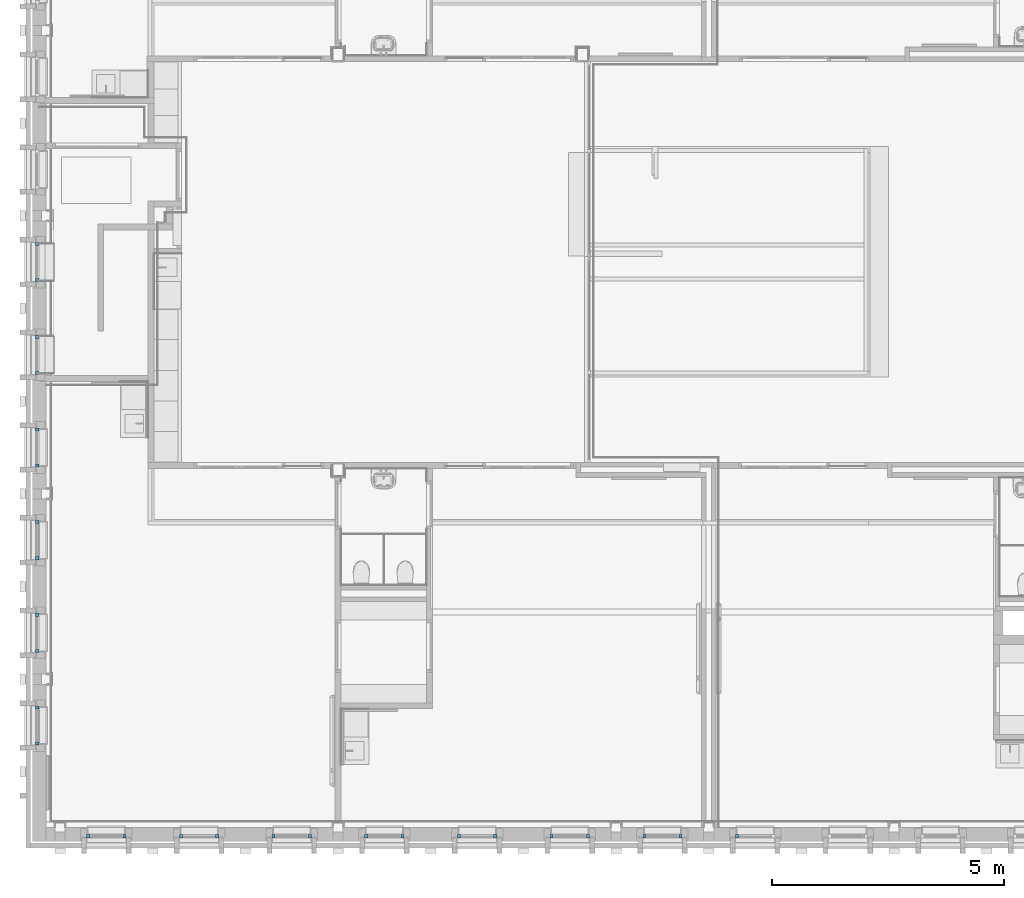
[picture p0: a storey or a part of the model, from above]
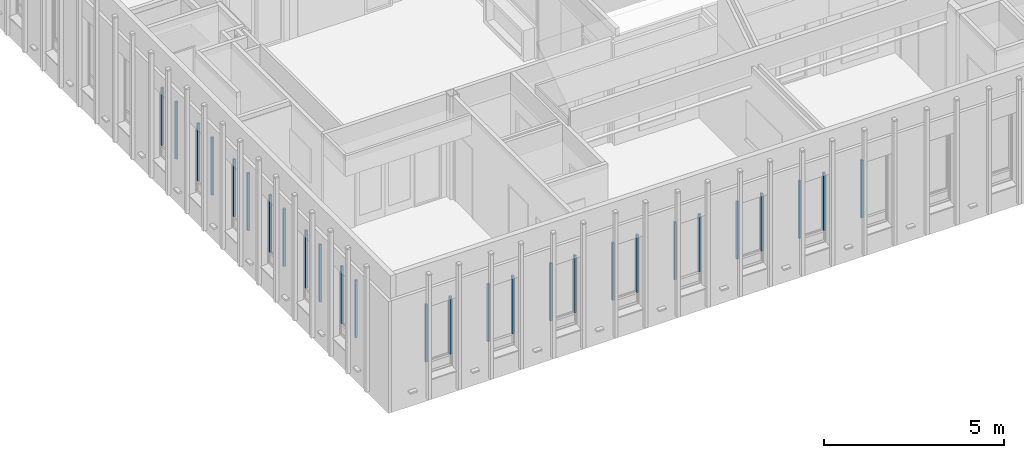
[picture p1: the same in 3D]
Properties of the parts of a building model (IFC2X3), part 91 of 94

# IfcWallStandardCase: Basic Wall:NLRS_41_WA_brandwerende beplating 15_gen_ISR (239)
Name (Basic Wall:NLRS_41_WA_brandwerende beplating 15_gen_ISR:...) | In | Base Constraint | Top Constraint | Base Offset (mm) | Location Line | Top Offset (mm) | Unconnected Height (mm) | Area (m2) | Length (mm) | Volume (m3)
3528542 | 00 begane grond | 00 begane grond | Up to level: 01 ok. ruwe vloer | 0 | Finish Face: Interior | -60 | 3570 | 0.48195 | 127.5 | 0.00722925
3528544 | 00 begane grond | 00 begane grond | Up to level: 01 ok. ruwe vloer | 0 | Finish Face: Interior | -60 | 3570 | 0.48195 | 127.5 | 0.00722925
3528545 | 00 begane grond | 00 begane grond | Up to level: 01 ok. ruwe vloer | 0 | Finish Face: Interior | -60 | 3570 | 0.05355 | 125 | 0.00080325
3528672 | 00 begane grond | 00 begane grond | Up to level: 01 ok. ruwe vloer | 0 | Finish Face: Interior | -60 | 3570 | 0.0714 | 27.5 | 0.001071
3529876 | 00 begane grond | 00 begane grond | Up to level: 01 ok. ruwe vloer | 0 | Finish Face: Interior | -60 | 3570 | 0.48195 | 127.5 | 0.00722925
3529877 | 00 begane grond | 00 begane grond | Up to level: 01 ok. ruwe vloer | 0 | Finish Face: Interior | -60 | 3570 | 0.91035 | 255 | 0.0136553
3529878 | 00 begane grond | 00 begane grond | Up to level: 01 ok. ruwe vloer | 0 | Finish Face: Interior | -60 | 3570 | 0.4284 | 127.5 | 0.006426
3530265 | 01 eerste verdieping | 01 eerste verdieping | Up to level: 02 ok. ruwe vloer | 0 | Finish Face: Interior | 0 | 3430 | 0.39445 | 107.5 | 0.00591675
3530314 | 01 eerste verdieping | 01 eerste verdieping | Up to level: 02 ok. ruwe vloer | 0 | Finish Face: Interior | 0 | 3430 | 0.73745 | 215 | 0.0110618
3530365 | 01 eerste verdieping | 01 eerste verdieping | Up to level: 02 ok. ruwe vloer | 0 | Finish Face: Interior | 0 | 3430 | 0.343 | 107.5 | 0.005145
3531005 | 01 eerste verdieping | 01 eerste verdieping | Up to level: 02 ok. ruwe vloer | 0 | Finish Face: Interior | 0 | 3430 | 0.39445 | 107.5 | 0.00591675
3531006 | 01 eerste verdieping | 01 eerste verdieping | Up to level: 02 ok. ruwe vloer | 0 | Finish Face: Interior | 0 | 3430 | 0.73745 | 215 | 0.0110618
3531007 | 01 eerste verdieping | 01 eerste verdieping | Up to level: 02 ok. ruwe vloer | 0 | Finish Face: Interior | 0 | 3430 | 0.343 | 107.5 | 0.005145
3531019 | 01 eerste verdieping | 01 eerste verdieping | Up to level: 02 ok. ruwe vloer | 0 | Finish Face: Interior | 0 | 3430 | 0.39445 | 107.5 | 0.00591675
3531020 | 01 eerste verdieping | 01 eerste verdieping | Up to level: 02 ok. ruwe vloer | 0 | Finish Face: Interior | 0 | 3430 | 0.73745 | 215 | 0.0110618
3531021 | 01 eerste verdieping | 01 eerste verdieping | Up to level: 02 ok. ruwe vloer | 0 | Finish Face: Interior | 0 | 3430 | 0.343 | 107.5 | 0.005145
3531033 | 01 eerste verdieping | 01 eerste verdieping | Up to level: 02 ok. ruwe vloer | 0 | Finish Face: Interior | 0 | 3430 | 0.39445 | 107.5 | 0.00591675
3531034 | 01 eerste verdieping | 01 eerste verdieping | Up to level: 02 ok. ruwe vloer | 0 | Finish Face: Interior | 0 | 3430 | 0.73745 | 215 | 0.0110618
3531035 | 01 eerste verdieping | 01 eerste verdieping | Up to level: 02 ok. ruwe vloer | 0 | Finish Face: Interior | 0 | 3430 | 0.343 | 107.5 | 0.005145
3531049 | 01 eerste verdieping | 01 eerste verdieping | Up to level: 02 ok. ruwe vloer | 0 | Finish Face: Interior | 0 | 3430 | 0.39445 | 107.5 | 0.00591675
3531050 | 01 eerste verdieping | 01 eerste verdieping | Up to level: 02 ok. ruwe vloer | 0 | Finish Face: Interior | 0 | 3430 | 0.73745 | 215 | 0.0110618
3531051 | 01 eerste verdieping | 01 eerste verdieping | Up to level: 02 ok. ruwe vloer | 0 | Finish Face: Interior | 0 | 3430 | 0.343 | 107.5 | 0.005145
3531091 | 01 eerste verdieping | 01 eerste verdieping | Up to level: 02 ok. ruwe vloer | 0 | Finish Face: Interior | 0 | 3430 | 0.39445 | 107.5 | 0.00591675
3531092 | 01 eerste verdieping | 01 eerste verdieping | Up to level: 02 ok. ruwe vloer | 0 | Finish Face: Interior | 0 | 3430 | 0.73745 | 215 | 0.0110618
3531093 | 01 eerste verdieping | 01 eerste verdieping | Up to level: 02 ok. ruwe vloer | 0 | Finish Face: Interior | 0 | 3430 | 0.343 | 107.5 | 0.005145
3531107 | 01 eerste verdieping | 01 eerste verdieping | Up to level: 02 ok. ruwe vloer | 0 | Finish Face: Interior | 0 | 3430 | 0.39445 | 107.5 | 0.00591675
3531108 | 01 eerste verdieping | 01 eerste verdieping | Up to level: 02 ok. ruwe vloer | 0 | Finish Face: Interior | 0 | 3430 | 0.73745 | 215 | 0.0110618
3531109 | 01 eerste verdieping | 01 eerste verdieping | Up to level: 02 ok. ruwe vloer | 0 | Finish Face: Interior | 0 | 3430 | 0.343 | 107.5 | 0.005145
3531121 | 01 eerste verdieping | 01 eerste verdieping | Up to level: 02 ok. ruwe vloer | 0 | Finish Face: Interior | 0 | 3430 | 0.39445 | 107.5 | 0.00591675
3531122 | 01 eerste verdieping | 01 eerste verdieping | Up to level: 02 ok. ruwe vloer | 0 | Finish Face: Interior | 0 | 3430 | 0.73745 | 215 | 0.0110618
3531123 | 01 eerste verdieping | 01 eerste verdieping | Up to level: 02 ok. ruwe vloer | 0 | Finish Face: Interior | 0 | 3430 | 0.343 | 107.5 | 0.005145
3531137 | 01 eerste verdieping | 01 eerste verdieping | Up to level: 02 ok. ruwe vloer | 0 | Finish Face: Interior | 0 | 3430 | 0.39445 | 107.5 | 0.00591675
3531138 | 01 eerste verdieping | 01 eerste verdieping | Up to level: 02 ok. ruwe vloer | 0 | Finish Face: Interior | 0 | 3430 | 0.73745 | 215 | 0.0110618
3531139 | 01 eerste verdieping | 01 eerste verdieping | Up to level: 02 ok. ruwe vloer | 0 | Finish Face: Interior | 0 | 3430 | 0.343 | 107.5 | 0.005145
3531151 | 01 eerste verdieping | 01 eerste verdieping | Up to level: 02 ok. ruwe vloer | 0 | Finish Face: Interior | 0 | 3430 | 0.39445 | 107.5 | 0.00591675
3531152 | 01 eerste verdieping | 01 eerste verdieping | Up to level: 02 ok. ruwe vloer | 0 | Finish Face: Interior | 0 | 3430 | 0.73745 | 215 | 0.0110618
3531153 | 01 eerste verdieping | 01 eerste verdieping | Up to level: 02 ok. ruwe vloer | 0 | Finish Face: Interior | 0 | 3430 | 0.343 | 107.5 | 0.005145
3531184 | 01 eerste verdieping | 01 eerste verdieping | Up to level: 02 ok. ruwe vloer | 0 | Finish Face: Interior | 0 | 3430 | 0.39445 | 107.5 | 0.00591675
3531185 | 01 eerste verdieping | 01 eerste verdieping | Up to level: 02 ok. ruwe vloer | 0 | Finish Face: Interior | 0 | 3430 | 0.73745 | 215 | 0.0110618
3531186 | 01 eerste verdieping | 01 eerste verdieping | Up to level: 02 ok. ruwe vloer | 0 | Finish Face: Interior | 0 | 3430 | 0.343 | 107.5 | 0.005145
3531198 | 01 eerste verdieping | 01 eerste verdieping | Up to level: 02 ok. ruwe vloer | 0 | Finish Face: Interior | 0 | 3430 | 0.39445 | 107.5 | 0.00591675
3531199 | 01 eerste verdieping | 01 eerste verdieping | Up to level: 02 ok. ruwe vloer | 0 | Finish Face: Interior | 0 | 3430 | 0.73745 | 215 | 0.0110618
3531200 | 01 eerste verdieping | 01 eerste verdieping | Up to level: 02 ok. ruwe vloer | 0 | Finish Face: Interior | 0 | 3430 | 0.343 | 107.5 | 0.005145
3531231 | 01 eerste verdieping | 01 eerste verdieping | Up to level: 02 ok. ruwe vloer | 0 | Finish Face: Interior | 0 | 3430 | 0.39445 | 107.5 | 0.00591675
3531232 | 01 eerste verdieping | 01 eerste verdieping | Up to level: 02 ok. ruwe vloer | 0 | Finish Face: Interior | 0 | 3430 | 0.73745 | 215 | 0.0110618
3531233 | 01 eerste verdieping | 01 eerste verdieping | Up to level: 02 ok. ruwe vloer | 0 | Finish Face: Interior | 0 | 3430 | 0.343 | 107.5 | 0.005145
3531245 | 01 eerste verdieping | 01 eerste verdieping | Up to level: 02 ok. ruwe vloer | 0 | Finish Face: Interior | 0 | 3430 | 0.39445 | 107.5 | 0.00591675
3531246 | 01 eerste verdieping | 01 eerste verdieping | Up to level: 02 ok. ruwe vloer | 0 | Finish Face: Interior | 0 | 3430 | 0.73745 | 215 | 0.0110618
3531247 | 01 eerste verdieping | 01 eerste verdieping | Up to level: 02 ok. ruwe vloer | 0 | Finish Face: Interior | 0 | 3430 | 0.343 | 107.5 | 0.005145
3531711 | 01 eerste verdieping | 01 eerste verdieping | Up to level: 02 ok. ruwe vloer | 0 | Finish Face: Interior | 0 | 3430 | 0.39445 | 107.5 | 0.00591675
3531806 | 01 eerste verdieping | 01 eerste verdieping | Up to level: 02 ok. ruwe vloer | 0 | Finish Face: Interior | 0 | 3430 | 0.35672 | 111.5 | 0.0053508
3532004 | 02 tweede verdieping | 02 tweede verdieping | Up to level: 03 ok. ruwe vloer | 0 | Finish Face: Interior | 0 | 3500 | 0.945 | 262.5 | 0.014175
3532048 | 02 tweede verdieping | 02 tweede verdieping | Up to level: 03 ok. ruwe vloer | 0 | Finish Face: Interior | 0 | 3500 | 0.8925 | 255 | 0.0133875
3532088 | 02 tweede verdieping | 02 tweede verdieping | Up to level: 03 ok. ruwe vloer | 0 | Finish Face: Interior | 0 | 3500 | 0.8925 | 255 | 0.0133875
3532322 | 02 tweede verdieping | 02 tweede verdieping | Up to level: 03 ok. ruwe vloer | 0 | Finish Face: Interior | 0 | 3500 | 0.945 | 255 | 0.014175
3532367 | 02 tweede verdieping | 02 tweede verdieping | Up to level: 03 ok. ruwe vloer | 0 | Finish Face: Interior | 0 | 3500 | 0.84 | 247.5 | 0.0126
3532368 | 02 tweede verdieping | 02 tweede verdieping |  | 0 | Finish Face: Exterior | 0 | 2800 | 0.714 | 247.5 | 0.01071
3532369 | 02 tweede verdieping | 02 tweede verdieping | Up to level: 03 ok. ruwe vloer | 0 | Finish Face: Interior | 0 | 3500 | 0.8925 | 247.5 | 0.0133875
3532370 | 02 tweede verdieping | 02 tweede verdieping | Up to level: 03 ok. ruwe vloer | 0 | Finish Face: Interior | 0 | 3500 | 0.945 | 255 | 0.014175
3532406 | 02 tweede verdieping | 02 tweede verdieping | Up to level: 03 ok. ruwe vloer | 0 | Finish Face: Interior | 0 | 3500 | 0.84 | 247.5 | 0.0126
3532407 | 02 tweede verdieping | 02 tweede verdieping |  | 0 | Finish Face: Exterior | 0 | 2800 | 0.714 | 247.5 | 0.01071
3532408 | 02 tweede verdieping | 02 tweede verdieping | Up to level: 03 ok. ruwe vloer | 0 | Finish Face: Interior | 0 | 3500 | 0.8925 | 247.5 | 0.0133875
3532447 | 02 tweede verdieping | 02 tweede verdieping |  | 0 | Finish Face: Exterior | 0 | 2800 | 0.672 | 255 | 0.01008
3532448 | 02 tweede verdieping | 02 tweede verdieping | Up to level: 03 ok. ruwe vloer | 0 | Finish Face: Interior | 0 | 3500 | 0.84 | 255 | 0.0126
3532449 | 02 tweede verdieping | 02 tweede verdieping | Up to level: 03 ok. ruwe vloer | 0 | Finish Face: Interior | 0 | 3500 | 0.49 | 147.5 | 0.00735
3532727 | 02 tweede verdieping | 02 tweede verdieping | Up to level: 03 ok. ruwe vloer | 0 | Finish Face: Interior | 0 | 3500 | 0.84 | 255 | 0.0126
3532770 | 02 tweede verdieping | 02 tweede verdieping | Up to level: 03 ok. ruwe vloer | 0 | Finish Face: Interior | 0 | 3500 | 0.49 | 147.5 | 0.00735
3532999 | 02 tweede verdieping | 02 tweede verdieping | Up to level: 03 bk. ruwe vloer | 0 | Finish Face: Interior | 0 | 3750 | 0.43125 | 107.5 | 0.00646875
3533000 | 02 tweede verdieping | 02 tweede verdieping | Up to level: 03 bk. ruwe vloer | 0 | Finish Face: Interior | 0 | 3750 | 0.43125 | 107.5 | 0.00646875
3533001 | 02 tweede verdieping | 02 tweede verdieping | Up to level: 03 bk. ruwe vloer | 0 | Finish Face: Interior | 0 | 3750 | 0.375 | 107.5 | 0.005625
3533002 | 02 tweede verdieping | 02 tweede verdieping | Up to level: 03 bk. ruwe vloer | 0 | Finish Face: Interior | 0 | 3750 | 0.43125 | 107.5 | 0.00646875
3533003 | 02 tweede verdieping | 02 tweede verdieping | Up to level: 03 bk. ruwe vloer | 0 | Finish Face: Interior | 0 | 3750 | 0.43125 | 107.5 | 0.00646875
3533108 | 02 tweede verdieping | 02 tweede verdieping | Up to level: 03 bk. ruwe vloer | 0 | Finish Face: Interior | 0 | 3750 | 0.43125 | 107.5 | 0.00646875
3533109 | 02 tweede verdieping | 02 tweede verdieping | Up to level: 03 bk. ruwe vloer | 0 | Finish Face: Interior | 0 | 3750 | 0.43125 | 107.5 | 0.00646875
3533110 | 02 tweede verdieping | 02 tweede verdieping | Up to level: 03 bk. ruwe vloer | 0 | Finish Face: Interior | 0 | 3750 | 0.375 | 107.5 | 0.005625
3533111 | 02 tweede verdieping | 02 tweede verdieping | Up to level: 03 bk. ruwe vloer | 0 | Finish Face: Interior | 0 | 3750 | 0.43125 | 107.5 | 0.00646875
3533112 | 02 tweede verdieping | 02 tweede verdieping | Up to level: 03 bk. ruwe vloer | 0 | Finish Face: Interior | 0 | 3750 | 0.43125 | 107.5 | 0.00646875
3533149 | 02 tweede verdieping | 02 tweede verdieping | Up to level: 03 bk. ruwe vloer | 0 | Finish Face: Interior | 0 | 3750 | 0.75 | 215 | 0.01125
3533150 | 02 tweede verdieping | 02 tweede verdieping | Up to level: 03 bk. ruwe vloer | 0 | Finish Face: Interior | 0 | 3750 | 0.75 | 215 | 0.01125
3533151 | 02 tweede verdieping | 02 tweede verdieping | Up to level: 03 bk. ruwe vloer | 0 | Finish Face: Interior | 0 | 3750 | 0.75 | 215 | 0.01125
3533152 | 02 tweede verdieping | 02 tweede verdieping | Up to level: 03 bk. ruwe vloer | 0 | Finish Face: Interior | 0 | 3750 | 0.75 | 215 | 0.01125
3533383 | 02 tweede verdieping | 02 tweede verdieping | Up to level: 03 ok. ruwe vloer | 0 | Finish Face: Interior | 0 | 3500 | 0.595 | 240 | 0.008925
3533418 | 02 tweede verdieping | 02 tweede verdieping | Up to level: 03 ok. ruwe vloer | 0 | Finish Face: Interior | 0 | 3500 | 0.1085 | 73.5 | 0.0016275
3533949 | 01 eerste verdieping | 01 eerste verdieping | Up to level: 02 ok. ruwe vloer | 0 | Finish Face: Interior | 0 | 3430 | 0.9261 | 255 | 0.0138915
3533951 | 01 eerste verdieping | 01 eerste verdieping | Up to level: 02 ok. ruwe vloer | 0 | Finish Face: Interior | 0 | 3430 | 0.87465 | 255 | 0.0131198
3533981 | 01 eerste verdieping | 01 eerste verdieping | Up to level: 02 ok. ruwe vloer | 0 | Finish Face: Interior | 0 | 3430 | 0.8232 | 247.5 | 0.012348
3533982 | 01 eerste verdieping | 01 eerste verdieping | Up to level: 02 ok. ruwe vloer | 0 | Finish Face: Interior | 0 | 3430 | 0.5831 | 240 | 0.0087465
3533983 | 01 eerste verdieping | 01 eerste verdieping | Up to level: 02 ok. ruwe vloer | 0 | Finish Face: Interior | 0 | 3430 | 0.8232 | 247.5 | 0.012348
3533984 | 01 eerste verdieping | 01 eerste verdieping | Up to level: 02 ok. ruwe vloer | 0 | Finish Face: Interior | 0 | 3430 | 0.87465 | 247.5 | 0.0131198
3534025 | 01 eerste verdieping | 01 eerste verdieping | Up to level: 02 ok. ruwe vloer | 0 | Finish Face: Interior | 0 | 3430 | 0.8232 | 247.5 | 0.012348
3534026 | 01 eerste verdieping | 01 eerste verdieping | Up to level: 02 ok. ruwe vloer | 0 | Finish Face: Interior | 0 | 3430 | 1.0633 | 240 | 0.0159495
3534027 | 01 eerste verdieping | 01 eerste verdieping | Up to level: 02 ok. ruwe vloer | 0 | Finish Face: Interior | 0 | 3430 | 0.87465 | 247.5 | 0.0131198
3534028 | 01 eerste verdieping | 01 eerste verdieping | Up to level: 02 ok. ruwe vloer | 0 | Finish Face: Interior | 0 | 3430 | 0.87465 | 247.5 | 0.0131198
3534051 | 01 eerste verdieping | 01 eerste verdieping | Up to level: 02 ok. ruwe vloer | 0 | Finish Face: Interior | 0 | 3430 | 0.8232 | 255 | 0.012348
3534777 | 01 eerste verdieping | 01 eerste verdieping | Up to level: 02 ok. ruwe vloer | 0 | Finish Face: Interior | 0 | 3430 | 0.87465 | 255 | 0.0131198
3534780 | 01 eerste verdieping | 01 eerste verdieping | Up to level: 02 ok. ruwe vloer | 0 | Finish Face: Interior | 0 | 3430 | 0.8232 | 247.5 | 0.012348
3534781 | 01 eerste verdieping | 01 eerste verdieping | Up to level: 02 ok. ruwe vloer | 0 | Finish Face: Interior | 0 | 3430 | 0.87465 | 247.5 | 0.0131198
3535201 | 01 eerste verdieping | 01 eerste verdieping | Up to level: 02 ok. ruwe vloer | 0 | Finish Face: Interior | 0 | 3430 | 0.87465 | 255 | 0.0131198
3535204 | 01 eerste verdieping | 01 eerste verdieping | Up to level: 02 ok. ruwe vloer | 0 | Finish Face: Interior | 0 | 3430 | 0.8232 | 247.5 | 0.012348
3535205 | 01 eerste verdieping | 01 eerste verdieping | Up to level: 02 ok. ruwe vloer | 0 | Finish Face: Interior | 0 | 3430 | 0.87465 | 247.5 | 0.0131198
4234165 | 00 begane grond | 00 begane grond | Up to level: 01 ok. ruwe vloer | 0 | Finish Face: Interior | -60 | 3570 | 1.28877 | 353.5 | 0.0193316
4234166 | 00 begane grond | 00 begane grond | Up to level: 01 ok. ruwe vloer | 0 | Finish Face: Interior | -60 | 3570 | 1.04422 | 300 | 0.0156634
4334081 | 00 begane grond | 00 begane grond | Up to level: 01 ok. ruwe vloer | 0 | Finish Face: Interior | -60 | 3570 | 0.9639 | 255 | 0.0144585
4334082 | 00 begane grond | 00 begane grond | Up to level: 01 ok. ruwe vloer | 0 | Finish Face: Interior | -60 | 3570 | 0.4284 | 127.5 | 0.006426
4334083 | 00 begane grond | 00 begane grond | Up to level: 01 ok. ruwe vloer | 0 | Finish Face: Interior | -60 | 3570 | 0.4284 | 127.5 | 0.006426
4334221 | 00 begane grond | 00 begane grond | Up to level: 01 ok. ruwe vloer | 0 | Finish Face: Interior | -60 | 3570 | 0.9639 | 255 | 0.0144585
4334222 | 00 begane grond | 00 begane grond | Up to level: 01 ok. ruwe vloer | 0 | Finish Face: Interior | -60 | 3570 | 0.4284 | 127.5 | 0.006426
4334223 | 00 begane grond | 00 begane grond | Up to level: 01 ok. ruwe vloer | 0 | Finish Face: Interior | -60 | 3570 | 0.4284 | 127.5 | 0.006426
4345457 | 01 eerste verdieping | 01 eerste verdieping | Up to level: 02 ok. ruwe vloer | 0 | Finish Face: Interior | 0 | 3430 | 0.39445 | 107.5 | 0.00591675
4345458 | 01 eerste verdieping | 01 eerste verdieping | Up to level: 02 ok. ruwe vloer | 0 | Finish Face: Interior | 0 | 3430 | 0.73745 | 215 | 0.0110618
4345459 | 01 eerste verdieping | 01 eerste verdieping | Up to level: 02 ok. ruwe vloer | 0 | Finish Face: Interior | 0 | 3430 | 0.343 | 107.5 | 0.005145
4346730 | 01 eerste verdieping | 01 eerste verdieping | Up to level: 02 ok. ruwe vloer | 0 | Finish Face: Interior | 0 | 3430 | 0.39445 | 107.5 | 0.00591675
4346731 | 01 eerste verdieping | 01 eerste verdieping | Up to level: 02 ok. ruwe vloer | 0 | Finish Face: Interior | 0 | 3430 | 0.73745 | 215 | 0.0110618
4346732 | 01 eerste verdieping | 01 eerste verdieping | Up to level: 02 ok. ruwe vloer | 0 | Finish Face: Interior | 0 | 3430 | 0.343 | 107.5 | 0.005145
4346776 | 02 tweede verdieping | 02 tweede verdieping | Up to level: 03 bk. ruwe vloer | 0 | Finish Face: Interior | 0 | 3750 | 0.43125 | 107.5 | 0.00646875
4346777 | 02 tweede verdieping | 02 tweede verdieping | Up to level: 03 bk. ruwe vloer | 0 | Finish Face: Interior | 0 | 3750 | 0.80625 | 215 | 0.0120938
4346778 | 02 tweede verdieping | 02 tweede verdieping | Up to level: 03 bk. ruwe vloer | 0 | Finish Face: Interior | 0 | 3750 | 0.375 | 107.5 | 0.005625
4347075 | 02 tweede verdieping | 02 tweede verdieping | Up to level: 03 bk. ruwe vloer | 0 | Finish Face: Interior | 0 | 3750 | 0.43125 | 107.5 | 0.00646875
4347076 | 02 tweede verdieping | 02 tweede verdieping | Up to level: 03 bk. ruwe vloer | 0 | Finish Face: Interior | 0 | 3750 | 0.80625 | 215 | 0.0120938
4347077 | 02 tweede verdieping | 02 tweede verdieping | Up to level: 03 bk. ruwe vloer | 0 | Finish Face: Interior | 0 | 3750 | 0.375 | 107.5 | 0.005625
4347919 | 01 eerste verdieping | 01 eerste verdieping | Up to level: 02 ok. ruwe vloer | 0 | Finish Face: Interior | 0 | 3430 | 0.39445 | 107.5 | 0.00591675
4347920 | 01 eerste verdieping | 01 eerste verdieping | Up to level: 02 ok. ruwe vloer | 0 | Finish Face: Interior | 0 | 3430 | 0.73745 | 215 | 0.0110618
4347921 | 01 eerste verdieping | 01 eerste verdieping | Up to level: 02 ok. ruwe vloer | 0 | Finish Face: Interior | 0 | 3430 | 0.343 | 107.5 | 0.005145
4898121 | 01 eerste verdieping | 02 ok. ruwe vloer | Up to level: 02 ok. ruwe vloer | -325 | Finish Face: Interior | 0 | 325 | 9.36575 | 28805 | 0.140486
4898488 | 01 eerste verdieping | 02 ok. ruwe vloer | Up to level: 02 ok. ruwe vloer | -275 | Finish Face: Interior | 0 | 275 | 6.62337 | 24085 | 0.0993506
4898809 | 01 eerste verdieping | 02 ok. ruwe vloer | Up to level: 02 ok. ruwe vloer | -325 | Finish Face: Interior | 0 | 325 | 9.36162 | 28805 | 0.140424
4901166 | 01 eerste verdieping | 02 ok. ruwe vloer | Up to level: 02 ok. ruwe vloer | -355 | Finish Face: Interior | 0 | 355 | 8.54485 | 24085 | 0.128173
4906275 | 02 tweede verdieping | 03 ok. ruwe vloer | Up to level: 03 ok. ruwe vloer | -205 | Finish Face: Interior | 0 | 205 | 4.94972 | 24145 | 0.0742459
4906489 | 02 tweede verdieping | 03 ok. ruwe vloer | Up to level: 03 ok. ruwe vloer | -205 | Finish Face: Interior | 0 | 205 | 4.9528 | 24145 | 0.074292
4906656 | 02 tweede verdieping | 03 ok. ruwe vloer | Up to level: 03 ok. ruwe vloer | -245 | Finish Face: Interior | 0 | 245 | 5.97065 | 24385 | 0.0895597
4907059 | 02 tweede verdieping | 03 ok. ruwe vloer | Up to level: 03 ok. ruwe vloer | -245 | Finish Face: Interior | 0 | 245 | 5.97432 | 24385 | 0.0896149

# IfcWallStandardCase: Basic Wall:NLRS_41_WA_gips 10_gen_ISR (73)
Type - PredefinedType: STANDARD; Material: f7_gipsvezel 10 mm
Type - Analytical Properties - Roughness: 1; Absorptance: 0.1
Type - Graphics - Coarse Scale Fill Pattern: <Solid fill>; Coarse Scale Fill Color: 4210752
Type - Construction - Function: Interior; Wrapping at Inserts: Do not wrap; Width: 10 mm
Type - Identity Data - Workset: Wall Types; Assembly Code: 41.12; Assembly Description: buitenwandafwerkingen; bekledingen; Description: sanitairwand 13mm; Model: LOD300; SmartRevit_Versie: 2018.2; Type Name: NLRS_41_WA_gips 10_gen_ISR
Type - Other - Category: Walls; Family Name: Basic Wall
Classification: 41.12 Uniformat (Uniformat)
Cross-Section Definition - Cross-Section: Vertical
Constraints - Base Extension Distance: 0 mm; Base is Attached: no; Related to Mass: no; Room Bounding: yes; Top Extension Distance: 0 mm; Top is Attached: no
Phasing - Phase Created: 2. nieuwbouw
Structural - Enable Analytical Model: no; Structural: no; Structural Usage: Non-bearing
Identity Data - Workset: Workset1
Other - Family: Basic Wall; Family and Type: Basic Wall: NLRS_41_WA_gips 10_gen_ISR; Type: NLRS_41_WA_gips 10_gen_ISR; Type Id: 3180673
Name (Basic Wall:NLRS_41_WA_gips 10_gen_ISR:...) | In | Base Constraint | Top Constraint | Base Offset (mm) | Location Line | Top Offset (mm) | Unconnected Height (mm) | Area (m2) | Length (mm) | Volume (m3)
2749048 | 01 eerste verdieping | 01 eerste verdieping | Up to level: 02 ok. ruwe vloer | 0 | Finish Face: Interior | -355 | 3075 | 0.839475 | 273 | 0.00839475
2749049 | 01 eerste verdieping | 01 eerste verdieping | Up to level: 02 ok. ruwe vloer | 0 | Finish Face: Interior | -355 | 3075 | 0.507375 | 170 | 0.00507375
2749050 | 01 eerste verdieping | 01 eerste verdieping | Up to level: 02 ok. ruwe vloer | 0 | Finish Face: Interior | -355 | 3075 | 0.538125 | 170 | 0.00538125
2749063 | 01 eerste verdieping | 01 eerste verdieping | Up to level: 02 ok. ruwe vloer | 0 | Finish Face: Interior | -355 | 3075 | 0.212175 | 136.5 | 0.00212175
2749064 | 01 eerste verdieping | 01 eerste verdieping | Up to level: 02 ok. ruwe vloer | 0 | Finish Face: Interior | -355 | 3075 | 0.507375 | 170 | 0.00507375
2749065 | 01 eerste verdieping | 01 eerste verdieping | Up to level: 02 ok. ruwe vloer | 0 | Finish Face: Interior | -355 | 3075 | 0.538125 | 170 | 0.00538125
2749127 | 01 eerste verdieping | 01 eerste verdieping | Up to level: 02 ok. ruwe vloer | 0 | Finish Face: Interior | -305 | 3125 | 0.853125 | 273 | 0.00853125
2749128 | 01 eerste verdieping | 01 eerste verdieping | Up to level: 02 ok. ruwe vloer | 0 | Finish Face: Interior | -305 | 3125 | 0.453125 | 150 | 0.00453125
2749129 | 01 eerste verdieping | 01 eerste verdieping | Up to level: 02 ok. ruwe vloer | 0 | Finish Face: Interior | -305 | 3125 | 0.484375 | 150 | 0.00484375
2749158 | 01 eerste verdieping | 01 eerste verdieping | Up to level: 02 ok. ruwe vloer | 0 | Finish Face: Interior | 0 | 3430 | 0.3773 | 132.5 | 0.003773
2749159 | 01 eerste verdieping | 01 eerste verdieping | Up to level: 02 ok. ruwe vloer | 0 | Finish Face: Interior | 0 | 3430 | 0.53165 | 132.5 | 0.0053165
2749247 | 01 eerste verdieping | 01 eerste verdieping | Up to level: 02 ok. ruwe vloer | 0 | Finish Face: Interior | -355 | 3075 | 0.212175 | 74 | 0.00212175
2749248 | 01 eerste verdieping | 01 eerste verdieping | Up to level: 02 ok. ruwe vloer | 0 | Finish Face: Interior | -355 | 3075 | 0.507375 | 170 | 0.00507375
2749249 | 01 eerste verdieping | 01 eerste verdieping | Up to level: 02 ok. ruwe vloer | 0 | Finish Face: Interior | -355 | 3075 | 0.538125 | 170 | 0.00538125
2749573 | 01 eerste verdieping | 01 eerste verdieping | Up to level: 02 ok. ruwe vloer | 0 | Finish Face: Interior | 0 | 3430 | 0.485345 | 136.5 | 0.00485345
2749574 | 01 eerste verdieping | 01 eerste verdieping | Up to level: 02 ok. ruwe vloer | 0 | Finish Face: Interior | 0 | 3430 | 0.39445 | 120 | 0.0039445
2749611 | 01 eerste verdieping | 01 eerste verdieping | Up to level: 02 ok. ruwe vloer | 0 | Finish Face: Interior | 0 | 3430 | 0.4805 | 270 | 0.004805
2749612 | 01 eerste verdieping | 01 eerste verdieping | Up to level: 02 ok. ruwe vloer | 0 | Finish Face: Interior | 0 | 3430 | 0.433895 | 131.5 | 0.00433895
2777992 | 01 eerste verdieping | 01 eerste verdieping | Up to level: 02 ok. ruwe vloer | 0 | Finish Face: Interior | -355 | 3075 | 0.242925 | 74 | 0.00242925
2778129 | 01 eerste verdieping | 01 eerste verdieping | Up to level: 02 ok. ruwe vloer | 0 | Finish Face: Interior | -355 | 3075 | 0.242925 | 136.5 | 0.00242925
3011556 | 00 begane grond | 00 begane grond | Up to level: 01 bk. ruwe vloer | 0 | Finish Face: Exterior | -630 | 3320 | 0.4482 | 141.5 | 0.004482
3527108 | 00 begane grond | 00 begane grond | Up to level: 01 ok. ruwe vloer | 0 | Finish Face: Interior | -60 | 3570 | 0.52836 | 141.5 | 0.0052836
3531002 | 01 eerste verdieping | 01 eerste verdieping | Up to level: 02 ok. ruwe vloer | 0 | Finish Face: Interior | -305 | 3125 | 0.853125 | 273 | 0.00853125
3531003 | 01 eerste verdieping | 01 eerste verdieping | Up to level: 02 ok. ruwe vloer | 0 | Finish Face: Interior | -305 | 3125 | 0.453125 | 150 | 0.00453125
3531004 | 01 eerste verdieping | 01 eerste verdieping | Up to level: 02 ok. ruwe vloer | 0 | Finish Face: Interior | -305 | 3125 | 0.484375 | 150 | 0.00484375
3531016 | 01 eerste verdieping | 01 eerste verdieping | Up to level: 02 ok. ruwe vloer | 0 | Finish Face: Interior | -305 | 3125 | 0.853125 | 273 | 0.00853125
3531017 | 01 eerste verdieping | 01 eerste verdieping | Up to level: 02 ok. ruwe vloer | 0 | Finish Face: Interior | -305 | 3125 | 0.453125 | 150 | 0.00453125
3531018 | 01 eerste verdieping | 01 eerste verdieping | Up to level: 02 ok. ruwe vloer | 0 | Finish Face: Interior | -305 | 3125 | 0.484375 | 150 | 0.00484375
3531030 | 01 eerste verdieping | 01 eerste verdieping | Up to level: 02 ok. ruwe vloer | 0 | Finish Face: Interior | -305 | 3125 | 0.853125 | 273 | 0.00853125
3531031 | 01 eerste verdieping | 01 eerste verdieping | Up to level: 02 ok. ruwe vloer | 0 | Finish Face: Interior | -305 | 3125 | 0.453125 | 150 | 0.00453125
3531032 | 01 eerste verdieping | 01 eerste verdieping | Up to level: 02 ok. ruwe vloer | 0 | Finish Face: Interior | -305 | 3125 | 0.484375 | 150 | 0.00484375
3531046 | 01 eerste verdieping | 01 eerste verdieping | Up to level: 02 ok. ruwe vloer | 0 | Finish Face: Interior | -355 | 3075 | 0.839475 | 273 | 0.00839475
3531047 | 01 eerste verdieping | 01 eerste verdieping | Up to level: 02 ok. ruwe vloer | 0 | Finish Face: Interior | -355 | 3075 | 0.507375 | 170 | 0.00507375
3531048 | 01 eerste verdieping | 01 eerste verdieping | Up to level: 02 ok. ruwe vloer | 0 | Finish Face: Interior | -355 | 3075 | 0.538125 | 170 | 0.00538125
3531088 | 01 eerste verdieping | 01 eerste verdieping | Up to level: 02 ok. ruwe vloer | 0 | Finish Face: Interior | -355 | 3075 | 0.839475 | 273 | 0.00839475
3531089 | 01 eerste verdieping | 01 eerste verdieping | Up to level: 02 ok. ruwe vloer | 0 | Finish Face: Interior | -355 | 3075 | 0.507375 | 170 | 0.00507375
3531090 | 01 eerste verdieping | 01 eerste verdieping | Up to level: 02 ok. ruwe vloer | 0 | Finish Face: Interior | -355 | 3075 | 0.538125 | 170 | 0.00538125
3531104 | 01 eerste verdieping | 01 eerste verdieping | Up to level: 02 ok. ruwe vloer | 0 | Finish Face: Interior | -355 | 3075 | 0.839475 | 273 | 0.00839475
3531105 | 01 eerste verdieping | 01 eerste verdieping | Up to level: 02 ok. ruwe vloer | 0 | Finish Face: Interior | -355 | 3075 | 0.507375 | 170 | 0.00507375
3531106 | 01 eerste verdieping | 01 eerste verdieping | Up to level: 02 ok. ruwe vloer | 0 | Finish Face: Interior | -355 | 3075 | 0.538125 | 170 | 0.00538125
3531118 | 01 eerste verdieping | 01 eerste verdieping | Up to level: 02 ok. ruwe vloer | 0 | Finish Face: Interior | -355 | 3075 | 0.839475 | 273 | 0.00839475
3531119 | 01 eerste verdieping | 01 eerste verdieping | Up to level: 02 ok. ruwe vloer | 0 | Finish Face: Interior | -355 | 3075 | 0.353625 | 120 | 0.00353625
3531120 | 01 eerste verdieping | 01 eerste verdieping | Up to level: 02 ok. ruwe vloer | 0 | Finish Face: Interior | -355 | 3075 | 0.384375 | 120 | 0.00384375
3531134 | 01 eerste verdieping | 01 eerste verdieping | Up to level: 02 ok. ruwe vloer | 0 | Finish Face: Interior | -355 | 3075 | 0.839475 | 273 | 0.00839475
3531135 | 01 eerste verdieping | 01 eerste verdieping | Up to level: 02 ok. ruwe vloer | 0 | Finish Face: Interior | -355 | 3075 | 0.353625 | 120 | 0.00353625
3531136 | 01 eerste verdieping | 01 eerste verdieping | Up to level: 02 ok. ruwe vloer | 0 | Finish Face: Interior | -355 | 3075 | 0.384375 | 120 | 0.00384375
3531148 | 01 eerste verdieping | 01 eerste verdieping | Up to level: 02 ok. ruwe vloer | 0 | Finish Face: Interior | 0 | 3430 | 0.93639 | 273 | 0.0093639
3531149 | 01 eerste verdieping | 01 eerste verdieping | Up to level: 02 ok. ruwe vloer | 0 | Finish Face: Interior | 0 | 3430 | 0.39445 | 120 | 0.0039445
3531150 | 01 eerste verdieping | 01 eerste verdieping | Up to level: 02 ok. ruwe vloer | 0 | Finish Face: Interior | 0 | 3430 | 0.42875 | 120 | 0.0042875
3531181 | 01 eerste verdieping | 01 eerste verdieping | Up to level: 02 ok. ruwe vloer | 0 | Finish Face: Interior | 0 | 3430 | 0.8232 | 240 | 0.008232
3531182 | 01 eerste verdieping | 01 eerste verdieping | Up to level: 02 ok. ruwe vloer | 0 | Finish Face: Interior | 0 | 3430 | 0.39445 | 120 | 0.0039445
3531183 | 01 eerste verdieping | 01 eerste verdieping | Up to level: 02 ok. ruwe vloer | 0 | Finish Face: Interior | 0 | 3430 | 0.2744 | 75 | 0.002744
3531195 | 01 eerste verdieping | 01 eerste verdieping | Up to level: 02 ok. ruwe vloer | 0 | Finish Face: Interior | -355 | 3075 | 0.839475 | 273 | 0.00839475
3531196 | 01 eerste verdieping | 01 eerste verdieping | Up to level: 02 ok. ruwe vloer | 0 | Finish Face: Interior | -355 | 3075 | 0.353625 | 120 | 0.00353625
3531197 | 01 eerste verdieping | 01 eerste verdieping | Up to level: 02 ok. ruwe vloer | 0 | Finish Face: Interior | -355 | 3075 | 0.384375 | 120 | 0.00384375
3531228 | 01 eerste verdieping | 01 eerste verdieping | Up to level: 02 ok. ruwe vloer | 0 | Finish Face: Interior | -355 | 3075 | 0.839475 | 273 | 0.00839475
3531229 | 01 eerste verdieping | 01 eerste verdieping | Up to level: 02 ok. ruwe vloer | 0 | Finish Face: Interior | -355 | 3075 | 0.507375 | 170 | 0.00507375
3531230 | 01 eerste verdieping | 01 eerste verdieping | Up to level: 02 ok. ruwe vloer | 0 | Finish Face: Interior | -355 | 3075 | 0.538125 | 170 | 0.00538125
3531242 | 01 eerste verdieping | 01 eerste verdieping | Up to level: 02 ok. ruwe vloer | 0 | Finish Face: Interior | -355 | 3075 | 0.839475 | 273 | 0.00839475
3531243 | 01 eerste verdieping | 01 eerste verdieping | Up to level: 02 ok. ruwe vloer | 0 | Finish Face: Interior | -355 | 3075 | 0.507375 | 170 | 0.00507375
3531244 | 01 eerste verdieping | 01 eerste verdieping | Up to level: 02 ok. ruwe vloer | 0 | Finish Face: Interior | -355 | 3075 | 0.538125 | 170 | 0.00538125
4345454 | 01 eerste verdieping | 01 eerste verdieping | Up to level: 02 ok. ruwe vloer | 0 | Finish Face: Interior | -355 | 3075 | 0.0353625 | 66.5 | 0.000353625
4345455 | 01 eerste verdieping | 01 eerste verdieping | Up to level: 02 ok. ruwe vloer | 0 | Finish Face: Interior | -355 | 3075 | 0.507375 | 170 | 0.00507375
4345456 | 01 eerste verdieping | 01 eerste verdieping | Up to level: 02 ok. ruwe vloer | 0 | Finish Face: Interior | -355 | 3075 | 0.538125 | 170 | 0.00538125
4347916 | 01 eerste verdieping | 01 eerste verdieping | Up to level: 02 ok. ruwe vloer | 0 | Finish Face: Interior | -355 | 3075 | 0.0353625 | 66.5 | 0.000353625
4347917 | 01 eerste verdieping | 01 eerste verdieping | Up to level: 02 ok. ruwe vloer | 0 | Finish Face: Interior | -355 | 3075 | 0.507375 | 170 | 0.00507375
4347918 | 01 eerste verdieping | 01 eerste verdieping | Up to level: 02 ok. ruwe vloer | 0 | Finish Face: Interior | -355 | 3075 | 0.538125 | 170 | 0.00538125
4902200 | 01 eerste verdieping | 02 ok. ruwe vloer | Up to level: 02 ok. ruwe vloer | -355 | Finish Face: Interior | 0 | 355 | 7.84373 | 22165 | 0.0784373
4902244 | 01 eerste verdieping | 02 ok. ruwe vloer | Up to level: 02 ok. ruwe vloer | -305 | Finish Face: Interior | 0 | 305 | 2.73661 | 9042.5 | 0.0273661
4902290 | 01 eerste verdieping | 02 ok. ruwe vloer | Up to level: 02 ok. ruwe vloer | -355 | Finish Face: Interior | 0 | 355 | 7.84373 | 22165 | 0.0784373
4902393 | 01 eerste verdieping | 02 ok. ruwe vloer | Up to level: 02 ok. ruwe vloer | -275 | Finish Face: Interior | 0 | 275 | 2.6015 | 9530 | 0.026015
4903694 | 01 eerste verdieping | 01 eerste verdieping | Up to level: 02 ok. ruwe vloer | 0 | Finish Face: Interior | -355 | 3075 | 0.0661125 | 66.5 | 0.000661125
4907353 | 01 eerste verdieping | 01 eerste verdieping | Up to level: 02 ok. ruwe vloer | 0 | Finish Face: Interior | -355 | 3075 | 0.0661125 | 66.5 | 0.000661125

# IfcWallStandardCase: Basic Wall:NLRS_41_WA_gips 13_gen_ISR (172)
Type - PredefinedType: STANDARD; Material: f7_gipsvezel 13 mm
Type - Analytical Properties - Roughness: 1; Absorptance: 0.1
Type - Graphics - Coarse Scale Fill Pattern: <Solid fill>; Coarse Scale Fill Color: 4210752
Type - Construction - Function: Interior; Wrapping at Inserts: Do not wrap; Width: 13 mm
Type - Identity Data - Workset: Wall Types; Assembly Code: 41.12; Assembly Description: buitenwandafwerkingen; bekledingen; Description: sanitairwand 13mm; Model: LOD300; SmartRevit_Versie: 2018.2; Type Name: NLRS_41_WA_gips 13_gen_ISR
Type - Other - Category: Walls; Family Name: Basic Wall
Classification: 41.12 Uniformat (Uniformat)
Cross-Section Definition - Cross-Section: Vertical
Constraints - Base Extension Distance: 0 mm; Base is Attached: no; Related to Mass: no; Room Bounding: yes; Top Extension Distance: 0 mm; Top is Attached: no; Base Offset: 0 mm
Phasing - Phase Created: 2. nieuwbouw
Structural - Enable Analytical Model: no; Structural: no; Structural Usage: Non-bearing
Identity Data - Workset: Workset1
Other - Family: Basic Wall; Family and Type: Basic Wall: NLRS_41_WA_gips 13_gen_ISR; Type: NLRS_41_WA_gips 13_gen_ISR; Type Id: 2724502
Name (Basic Wall:NLRS_41_WA_gips 13_gen_ISR:...) | In | Top Offset (mm) | Base Constraint | Top Constraint | Location Line | Unconnected Height (mm) | Area (m2) | Length (mm) | Volume (m3)
1218302 | 00 begane grond | 0 | 00 begane grond | Up to level: 01 ok. ruwe vloer | Core Face: Exterior | 3630 | 0.488235 | 141 | 0.00634706
2724907 | 00 begane grond | -60 | 00 begane grond | Up to level: 01 ok. ruwe vloer | Finish Face: Interior | 3570 | 0.9639 | 283 | 0.0125307
2724916 | 00 begane grond | -60 | 00 begane grond | Up to level: 01 ok. ruwe vloer | Finish Face: Interior | 3570 | 1.18703 | 441.5 | 0.0154313
2725881 | 00 begane grond | -60 | 00 begane grond | Up to level: 01 ok. ruwe vloer | Finish Face: Interior | 3570 | 0.9639 | 283 | 0.0125307
2725896 | 00 begane grond | -60 | 00 begane grond | Up to level: 01 ok. ruwe vloer | Finish Face: Interior | 3570 | 0.7497 | 223 | 0.0097461
2728507 | 00 begane grond | -60 | 00 begane grond | Up to level: 01 ok. ruwe vloer | Finish Face: Interior | 3570 | 0.357 | 93.5 | 0.004641
2728533 | 00 begane grond | -60 | 00 begane grond | Up to level: 01 ok. ruwe vloer | Finish Face: Interior | 3570 | 0.580125 | 169 | 0.00754162
2736626 | 00 begane grond | 0 | 00 begane grond | Up to level: 01 ok. ruwe vloer | Finish Face: Interior | 3630 | 1.07448 | 283 | 0.0139682
2736652 | 00 begane grond | 0 | 00 begane grond | Up to level: 01 ok. ruwe vloer | Finish Face: Interior | 3630 | 0.49005 | 141.5 | 0.00637065
2736716 | 00 begane grond | 0 | 00 begane grond | Up to level: 01 ok. ruwe vloer | Finish Face: Interior | 3630 | 0.49005 | 141.5 | 0.00637065
2736968 | 00 begane grond | 0 | 00 begane grond | Up to level: 01 ok. ruwe vloer | Finish Face: Interior | 3630 | 1.07448 | 283 | 0.0139682
2736969 | 00 begane grond | 0 | 00 begane grond | Up to level: 01 ok. ruwe vloer | Finish Face: Interior | 3630 | 0.49005 | 141.5 | 0.00637065
2736970 | 00 begane grond | 0 | 00 begane grond | Up to level: 01 ok. ruwe vloer | Finish Face: Interior | 3630 | 0.49005 | 141.5 | 0.00637065
2737378 | 00 begane grond | 0 | 00 begane grond | Up to level: 01 ok. ruwe vloer | Finish Face: Interior | 3630 | 0.64614 | 234 | 0.00839982
2737509 | 00 begane grond | 0 | 00 begane grond | Up to level: 01 ok. ruwe vloer | Finish Face: Interior | 3630 | 0.589875 | 169 | 0.00766837
2744354 | 01 eerste verdieping | 0 | 01 eerste verdieping | Up to level: 02 ok. ruwe vloer | Finish Face: Interior | 3430 | 1.01528 | 283 | 0.0131986
2744376 | 01 eerste verdieping | 0 | 01 eerste verdieping | Up to level: 02 ok. ruwe vloer | Finish Face: Interior | 3430 | 0.87465 | 261.5 | 0.0113705
2744408 | 01 eerste verdieping | 0 | 01 eerste verdieping | Up to level: 02 ok. ruwe vloer | Finish Face: Interior | 3430 | 0.63455 | 254 | 0.00824915
2744451 | 01 eerste verdieping | 0 | 01 eerste verdieping | Up to level: 02 ok. ruwe vloer | Finish Face: Interior | 3430 | 0.67914 | 254 | 0.00882882
2744497 | 01 eerste verdieping | 0 | 01 eerste verdieping | Up to level: 02 ok. ruwe vloer | Finish Face: Interior | 3430 | 0.248675 | 141.5 | 0.00323277
2744531 | 01 eerste verdieping | 0 | 01 eerste verdieping | Up to level: 02 ok. ruwe vloer | Finish Face: Interior | 3430 | 0.293265 | 141.5 | 0.00381245
2744577 | 01 eerste verdieping | 0 | 01 eerste verdieping | Up to level: 02 ok. ruwe vloer | Finish Face: Interior | 3430 | 0.63455 | 254 | 0.00824915
2744798 | 01 eerste verdieping | 0 | 01 eerste verdieping | Up to level: 02 ok. ruwe vloer | Finish Face: Interior | 3430 | 0.63455 | 254 | 0.00824915
2744831 | 01 eerste verdieping | 0 | 01 eerste verdieping | Up to level: 02 ok. ruwe vloer | Finish Face: Interior | 3430 | 0.63455 | 254 | 0.00824915
2744880 | 01 eerste verdieping | 0 | 01 eerste verdieping | Up to level: 02 ok. ruwe vloer | Finish Face: Interior | 3430 | 1.01528 | 283 | 0.0131986
2744906 | 01 eerste verdieping | 0 | 01 eerste verdieping | Up to level: 02 ok. ruwe vloer | Finish Face: Interior | 3430 | 0.63455 | 191.5 | 0.00824915
2744953 | 01 eerste verdieping | 0 | 01 eerste verdieping | Up to level: 02 ok. ruwe vloer | Finish Face: Interior | 3430 | 0.63455 | 191.5 | 0.00824915
2777714 | 02 tweede verdieping | 0 | 02 tweede verdieping | Up to level: 03 bk. ruwe vloer | Finish Face: Interior | 3750 | 0.96 | 243 | 0.01248
2777820 | 02 tweede verdieping | 0 | 02 tweede verdieping | Up to level: 03 bk. ruwe vloer | Finish Face: Interior | 3750 | 0.43125 | 121.5 | 0.00560625
2777905 | 02 tweede verdieping | 0 | 02 tweede verdieping | Up to level: 03 bk. ruwe vloer | Finish Face: Interior | 3750 | 0.43125 | 121.5 | 0.00560625
2777940 | 02 tweede verdieping | 0 | 02 tweede verdieping | Up to level: 03 bk. ruwe vloer | Finish Face: Interior | 3750 | 0.26125 | 121.5 | 0.00339625
2777941 | 02 tweede verdieping | 0 | 02 tweede verdieping | Up to level: 03 bk. ruwe vloer | Finish Face: Interior | 3750 | 0.43125 | 121.5 | 0.00560625
2777942 | 02 tweede verdieping | 0 | 02 tweede verdieping | Up to level: 03 bk. ruwe vloer | Finish Face: Interior | 3750 | 0.43125 | 121.5 | 0.00560625
2777953 | 02 tweede verdieping | 0 | 02 tweede verdieping | Up to level: 03 bk. ruwe vloer | Finish Face: Interior | 3750 | 0.96 | 243 | 0.01248
2777954 | 02 tweede verdieping | 0 | 02 tweede verdieping | Up to level: 03 bk. ruwe vloer | Finish Face: Interior | 3750 | 0.43125 | 121.5 | 0.00560625
2777955 | 02 tweede verdieping | 0 | 02 tweede verdieping | Up to level: 03 bk. ruwe vloer | Finish Face: Interior | 3750 | 0.43125 | 121.5 | 0.00560625
2777964 | 02 tweede verdieping | 0 | 02 tweede verdieping | Up to level: 03 bk. ruwe vloer | Finish Face: Interior | 3750 | 0.96 | 243 | 0.01248
2777965 | 02 tweede verdieping | 0 | 02 tweede verdieping | Up to level: 03 bk. ruwe vloer | Finish Face: Interior | 3750 | 0.43125 | 121.5 | 0.00560625
2777966 | 02 tweede verdieping | 0 | 02 tweede verdieping | Up to level: 03 bk. ruwe vloer | Finish Face: Interior | 3750 | 0.43125 | 121.5 | 0.00560625
2777975 | 02 tweede verdieping | 0 | 02 tweede verdieping | Up to level: 03 bk. ruwe vloer | Finish Face: Interior | 3750 | 0.96 | 243 | 0.01248
2777976 | 02 tweede verdieping | 0 | 02 tweede verdieping | Up to level: 03 bk. ruwe vloer | Finish Face: Interior | 3750 | 0.43125 | 121.5 | 0.00560625
2777977 | 02 tweede verdieping | 0 | 02 tweede verdieping | Up to level: 03 bk. ruwe vloer | Finish Face: Interior | 3750 | 0.43125 | 121.5 | 0.00560625
2778185 | 02 tweede verdieping | 0 | 02 tweede verdieping | Up to level: 03 bk. ruwe vloer | Finish Face: Interior | 3750 | 0.26125 | 121.5 | 0.00339625
2778407 | 02 tweede verdieping | 0 | 02 tweede verdieping | Up to level: 03 bk. ruwe vloer | Finish Face: Interior | 3750 | 0.96 | 243 | 0.01248
2778452 | 02 tweede verdieping | 0 | 02 tweede verdieping | Up to level: 03 bk. ruwe vloer | Finish Face: Interior | 3750 | 0.43125 | 121.5 | 0.00560625
2778521 | 02 tweede verdieping | 0 | 02 tweede verdieping | Up to level: 03 bk. ruwe vloer | Finish Face: Interior | 3750 | 0.43125 | 121.5 | 0.00560625
2778562 | 02 tweede verdieping | 0 | 02 tweede verdieping | Up to level: 03 bk. ruwe vloer | Finish Face: Interior | 3750 | 0.96 | 243 | 0.01248
2778563 | 02 tweede verdieping | 0 | 02 tweede verdieping | Up to level: 03 bk. ruwe vloer | Finish Face: Interior | 3750 | 0.43125 | 121.5 | 0.00560625
2778564 | 02 tweede verdieping | 0 | 02 tweede verdieping | Up to level: 03 bk. ruwe vloer | Finish Face: Interior | 3750 | 0.43125 | 121.5 | 0.00560625
2778573 | 02 tweede verdieping | 0 | 02 tweede verdieping | Up to level: 03 bk. ruwe vloer | Finish Face: Interior | 3750 | 0.96 | 243 | 0.01248
2778574 | 02 tweede verdieping | 0 | 02 tweede verdieping | Up to level: 03 bk. ruwe vloer | Finish Face: Interior | 3750 | 0.43125 | 121.5 | 0.00560625
2778575 | 02 tweede verdieping | 0 | 02 tweede verdieping | Up to level: 03 bk. ruwe vloer | Finish Face: Interior | 3750 | 0.43125 | 121.5 | 0.00560625
2778586 | 02 tweede verdieping | 0 | 02 tweede verdieping | Up to level: 03 bk. ruwe vloer | Finish Face: Interior | 3750 | 0.91125 | 243 | 0.0118462
2778587 | 02 tweede verdieping | 0 | 02 tweede verdieping | Up to level: 03 bk. ruwe vloer | Finish Face: Interior | 3750 | 0.48 | 121.5 | 0.00624
2778588 | 02 tweede verdieping | 0 | 02 tweede verdieping | Up to level: 03 bk. ruwe vloer | Finish Face: Interior | 3750 | 0.43125 | 121.5 | 0.00560625
2778597 | 02 tweede verdieping | 0 | 02 tweede verdieping | Up to level: 03 bk. ruwe vloer | Finish Face: Interior | 3750 | 0.96 | 243 | 0.01248
2778598 | 02 tweede verdieping | 0 | 02 tweede verdieping | Up to level: 03 bk. ruwe vloer | Finish Face: Interior | 3750 | 0.43125 | 121.5 | 0.00560625
2778599 | 02 tweede verdieping | 0 | 02 tweede verdieping | Up to level: 03 bk. ruwe vloer | Finish Face: Interior | 3750 | 0.43125 | 121.5 | 0.00560625
2778608 | 02 tweede verdieping | 0 | 02 tweede verdieping | Up to level: 03 bk. ruwe vloer | Finish Face: Interior | 3750 | 0.96 | 243 | 0.01248
2778609 | 02 tweede verdieping | 0 | 02 tweede verdieping | Up to level: 03 bk. ruwe vloer | Finish Face: Interior | 3750 | 0.43125 | 121.5 | 0.00560625
2778610 | 02 tweede verdieping | 0 | 02 tweede verdieping | Up to level: 03 bk. ruwe vloer | Finish Face: Interior | 3750 | 0.43125 | 121.5 | 0.00560625
2778659 | 02 tweede verdieping | 0 | 02 tweede verdieping | Up to level: 03 bk. ruwe vloer | Finish Face: Interior | 3750 | 0.96 | 243 | 0.01248
2778660 | 02 tweede verdieping | 0 | 02 tweede verdieping | Up to level: 03 bk. ruwe vloer | Finish Face: Interior | 3750 | 0.43125 | 121.5 | 0.00560625
2778661 | 02 tweede verdieping | 0 | 02 tweede verdieping | Up to level: 03 bk. ruwe vloer | Finish Face: Interior | 3750 | 0.43125 | 121.5 | 0.00560625
2778672 | 02 tweede verdieping | 0 | 02 tweede verdieping | Up to level: 03 bk. ruwe vloer | Finish Face: Interior | 3750 | 0.58125 | 155 | 0.00755625
2778681 | 02 tweede verdieping | 0 | 02 tweede verdieping | Up to level: 03 bk. ruwe vloer | Finish Face: Interior | 3750 | 0.96 | 243 | 0.01248
2778682 | 02 tweede verdieping | 0 | 02 tweede verdieping | Up to level: 03 bk. ruwe vloer | Finish Face: Interior | 3750 | 0.43125 | 121.5 | 0.00560625
2778683 | 02 tweede verdieping | 0 | 02 tweede verdieping | Up to level: 03 bk. ruwe vloer | Finish Face: Interior | 3750 | 0.43125 | 121.5 | 0.00560625
2778692 | 02 tweede verdieping | 0 | 02 tweede verdieping | Up to level: 03 bk. ruwe vloer | Finish Face: Interior | 3750 | 0.96 | 243 | 0.01248
2778693 | 02 tweede verdieping | 0 | 02 tweede verdieping | Up to level: 03 bk. ruwe vloer | Finish Face: Interior | 3750 | 0.43125 | 121.5 | 0.00560625
2778694 | 02 tweede verdieping | 0 | 02 tweede verdieping | Up to level: 03 bk. ruwe vloer | Finish Face: Interior | 3750 | 0.43125 | 121.5 | 0.00560625
2779324 | 02 tweede verdieping | 0 | 02 tweede verdieping | Up to level: 03 ok. ruwe vloer | Finish Face: Interior | 3500 | 0.29925 | 141.5 | 0.00389025
2779352 | 02 tweede verdieping | 0 | 02 tweede verdieping | Up to level: 03 ok. ruwe vloer | Finish Face: Interior | 3500 | 0.6475 | 254 | 0.0084175
2779390 | 02 tweede verdieping | 0 | 02 tweede verdieping | Up to level: 03 ok. ruwe vloer | Finish Face: Interior | 3500 | 0.29925 | 141.5 | 0.00389025
2779455 | 02 tweede verdieping | 0 | 02 tweede verdieping | Up to level: 03 ok. ruwe vloer | Finish Face: Interior | 3500 | 0.6475 | 191.5 | 0.0084175
2779727 | 02 tweede verdieping | 0 | 02 tweede verdieping |  | Finish Face: Exterior | 2800 | 0.2394 | 141.5 | 0.0031122
2779762 | 02 tweede verdieping | 0 | 02 tweede verdieping |  | Finish Face: Exterior | 2800 | 0.518 | 254 | 0.006734
2779796 | 02 tweede verdieping | 0 | 02 tweede verdieping |  | Finish Face: Exterior | 2800 | 0.2394 | 141.5 | 0.0031122
2779797 | 02 tweede verdieping | 0 | 02 tweede verdieping |  | Finish Face: Exterior | 2800 | 0.518 | 254 | 0.006734
2780124 | 02 tweede verdieping | 0 | 02 tweede verdieping | Up to level: 03 ok. ruwe vloer | Finish Face: Interior | 3500 | 1.036 | 283 | 0.013468
2780151 | 02 tweede verdieping | 0 | 02 tweede verdieping | Up to level: 03 ok. ruwe vloer | Finish Face: Interior | 3500 | 0.6475 | 254 | 0.0084175
2780184 | 02 tweede verdieping | 0 | 02 tweede verdieping | Up to level: 03 ok. ruwe vloer | Finish Face: Interior | 3500 | 0.8925 | 261.5 | 0.0116025
2780517 | 02 tweede verdieping | 0 | 02 tweede verdieping | Up to level: 03 ok. ruwe vloer | Finish Face: Interior | 3500 | 0.76825 | 163 | 0.00998725
2780552 | 02 tweede verdieping | 0 | 02 tweede verdieping | Up to level: 03 ok. ruwe vloer | Finish Face: Interior | 3500 | 1.085 | 304 | 0.014105
2780780 | 02 tweede verdieping | 0 | 02 tweede verdieping | Up to level: 03 ok. ruwe vloer | Finish Face: Interior | 3500 | 1.1305 | 310 | 0.0146965
2780817 | 02 tweede verdieping | 0 | 02 tweede verdieping | Up to level: 03 ok. ruwe vloer | Finish Face: Interior | 3500 | 0.76125 | 224 | 0.00989625
2997749 | 00 begane grond | 0 | 00 begane grond | Up to level: 01 ok. ruwe vloer | Core Face: Exterior | 3630 | 1.02729 | 276.5 | 0.0133548
3001915 | 00 begane grond | 0 | 00 begane grond | Up to level: 01 ok. ruwe vloer | Core Face: Exterior | 3630 | 0.53724 | 141.5 | 0.00698412
3002016 | 00 begane grond | 0 | 00 begane grond | Up to level: 01 ok. ruwe vloer | Core Face: Exterior | 3630 | 0.571725 | 164 | 0.00743242
3011576 | 00 begane grond | -630 | 00 begane grond | Up to level: 01 bk. ruwe vloer | Finish Face: Exterior | 3320 | 1.03418 | 306.5 | 0.0134443
3079319 | 00 begane grond | -60 | 00 begane grond | Up to level: 01 ok. ruwe vloer | Finish Face: Interior | 3570 | 0.48195 | 128.5 | 0.00626535
3079320 | 00 begane grond | -60 | 00 begane grond | Up to level: 01 ok. ruwe vloer | Finish Face: Interior | 3570 | 1.0353 | 296.5 | 0.0134589
3079400 | 00 begane grond | -60 | 00 begane grond | Up to level: 01 ok. ruwe vloer | Finish Face: Interior | 3570 | 0.48195 | 188.5 | 0.00626535
3079401 | 00 begane grond | -60 | 00 begane grond | Up to level: 01 ok. ruwe vloer | Finish Face: Interior | 3570 | 1.0353 | 296.5 | 0.0134589
3526779 | 00 begane grond | -60 | 00 begane grond | Up to level: 01 ok. ruwe vloer | Finish Face: Interior | 3570 | 1.05672 | 283 | 0.0137374
3526826 | 00 begane grond | -60 | 00 begane grond | Up to level: 01 ok. ruwe vloer | Finish Face: Interior | 3570 | 0.48195 | 141.5 | 0.00626535
3526872 | 00 begane grond | -60 | 00 begane grond | Up to level: 01 ok. ruwe vloer | Finish Face: Interior | 3570 | 0.48195 | 141.5 | 0.00626535
3527107 | 00 begane grond | -60 | 00 begane grond | Up to level: 01 ok. ruwe vloer | Finish Face: Interior | 3570 | 0.52836 | 141.5 | 0.00686868
3527109 | 00 begane grond | -60 | 00 begane grond | Up to level: 01 ok. ruwe vloer | Finish Face: Interior | 3570 | 0.52836 | 141.5 | 0.00686868
3527110 | 00 begane grond | -60 | 00 begane grond | Up to level: 01 ok. ruwe vloer | Finish Face: Interior | 3570 | 0.42126 | 111.5 | 0.00547638
3527111 | 00 begane grond | -60 | 00 begane grond | Up to level: 01 ok. ruwe vloer | Finish Face: Interior | 3570 | 0.42126 | 111.5 | 0.00547638
3527112 | 00 begane grond | -60 | 00 begane grond | Up to level: 01 ok. ruwe vloer | Finish Face: Interior | 3570 | 0.42126 | 111.5 | 0.00547638
3527113 | 00 begane grond | -60 | 00 begane grond | Up to level: 01 ok. ruwe vloer | Finish Face: Interior | 3570 | 0.42126 | 111.5 | 0.00547638
3527114 | 00 begane grond | -60 | 00 begane grond | Up to level: 01 ok. ruwe vloer | Finish Face: Interior | 3570 | 0.45696 | 121.5 | 0.00594048
3527115 | 00 begane grond | -60 | 00 begane grond | Up to level: 01 ok. ruwe vloer | Finish Face: Interior | 3570 | 0.42126 | 111.5 | 0.00547638
3527116 | 00 begane grond | -60 | 00 begane grond | Up to level: 01 ok. ruwe vloer | Finish Face: Interior | 3570 | 0.59976 | 161.5 | 0.00779688
3527117 | 00 begane grond | -60 | 00 begane grond | Up to level: 01 ok. ruwe vloer | Finish Face: Interior | 3570 | 0.52836 | 141.5 | 0.00686868
3527118 | 00 begane grond | -60 | 00 begane grond | Up to level: 01 ok. ruwe vloer | Finish Face: Interior | 3570 | 0.52836 | 141.5 | 0.00686868
3527119 | 00 begane grond | -60 | 00 begane grond | Up to level: 01 ok. ruwe vloer | Finish Face: Interior | 3570 | 0.52836 | 141.5 | 0.00686868
3527120 | 00 begane grond | -60 | 00 begane grond | Up to level: 01 ok. ruwe vloer | Finish Face: Interior | 3570 | 0.52836 | 141.5 | 0.00686868
3527191 | 00 begane grond | -60 | 00 begane grond | Up to level: 01 ok. ruwe vloer | Finish Face: Interior | 3570 | 0.5712 | 216 | 0.0074256
3527192 | 00 begane grond | -60 | 00 begane grond | Up to level: 01 ok. ruwe vloer | Finish Face: Interior | 3570 | 0.79611 | 223 | 0.0103494
3527193 | 00 begane grond | -60 | 00 begane grond | Up to level: 01 ok. ruwe vloer | Finish Face: Interior | 3570 | 0.79611 | 223 | 0.0103494
3527194 | 00 begane grond | -60 | 00 begane grond | Up to level: 01 ok. ruwe vloer | Finish Face: Interior | 3570 | 0.79611 | 223 | 0.0103494
3527401 | 00 begane grond | -60 | 00 begane grond | Up to level: 01 ok. ruwe vloer | Finish Face: Interior | 3570 | 0.52836 | 141.5 | 0.00686868
3527402 | 00 begane grond | -60 | 00 begane grond | Up to level: 01 ok. ruwe vloer | Finish Face: Interior | 3570 | 0.52836 | 141.5 | 0.00686868
3527403 | 00 begane grond | -60 | 00 begane grond | Up to level: 01 ok. ruwe vloer | Finish Face: Interior | 3570 | 0.52836 | 141.5 | 0.00686868
3527404 | 00 begane grond | -60 | 00 begane grond | Up to level: 01 ok. ruwe vloer | Finish Face: Interior | 3570 | 0.42126 | 111.5 | 0.00547638
3527405 | 00 begane grond | -60 | 00 begane grond | Up to level: 01 ok. ruwe vloer | Finish Face: Interior | 3570 | 0.37485 | 111.5 | 0.00487305
3527406 | 00 begane grond | -60 | 00 begane grond | Up to level: 01 ok. ruwe vloer | Finish Face: Interior | 3570 | 0.37485 | 111.5 | 0.00487305
3527407 | 00 begane grond | -60 | 00 begane grond | Up to level: 01 ok. ruwe vloer | Finish Face: Interior | 3570 | 0.37485 | 111.5 | 0.00487305
3527408 | 00 begane grond | -60 | 00 begane grond | Up to level: 01 ok. ruwe vloer | Finish Face: Interior | 3570 | 0.37485 | 111.5 | 0.00487305
3527409 | 00 begane grond | -60 | 00 begane grond | Up to level: 01 ok. ruwe vloer | Finish Face: Interior | 3570 | 0.52836 | 141.5 | 0.00686868
3527410 | 00 begane grond | -60 | 00 begane grond | Up to level: 01 ok. ruwe vloer | Finish Face: Interior | 3570 | 0.45696 | 121.5 | 0.00594048
3527411 | 00 begane grond | -60 | 00 begane grond | Up to level: 01 ok. ruwe vloer | Finish Face: Interior | 3570 | 0.42126 | 111.5 | 0.00547638
3527412 | 00 begane grond | -60 | 00 begane grond | Up to level: 01 ok. ruwe vloer | Finish Face: Interior | 3570 | 0.59976 | 161.5 | 0.00779688
3527413 | 00 begane grond | -60 | 00 begane grond | Up to level: 01 ok. ruwe vloer | Finish Face: Interior | 3570 | 0.52836 | 141.5 | 0.00686868
3527414 | 00 begane grond | -60 | 00 begane grond | Up to level: 01 ok. ruwe vloer | Finish Face: Interior | 3570 | 0.52836 | 141.5 | 0.00686868
3527415 | 00 begane grond | -60 | 00 begane grond | Up to level: 01 ok. ruwe vloer | Finish Face: Interior | 3570 | 0.52836 | 141.5 | 0.00686868
3527416 | 00 begane grond | -60 | 00 begane grond | Up to level: 01 ok. ruwe vloer | Finish Face: Interior | 3570 | 0.52836 | 141.5 | 0.00686868
3527513 | 00 begane grond | -60 | 00 begane grond | Up to level: 01 ok. ruwe vloer | Finish Face: Interior | 3570 | 0.41769 | 183.5 | 0.00542997
3527514 | 00 begane grond | -60 | 00 begane grond | Up to level: 01 ok. ruwe vloer | Finish Face: Interior | 3570 | 0.8211 | 243 | 0.0106743
3527515 | 00 begane grond | -60 | 00 begane grond | Up to level: 01 ok. ruwe vloer | Finish Face: Interior | 3570 | 0.7497 | 223 | 0.0097461
3527516 | 00 begane grond | -60 | 00 begane grond | Up to level: 01 ok. ruwe vloer | Finish Face: Interior | 3570 | 1.1067 | 323 | 0.0143871
3527517 | 00 begane grond | -60 | 00 begane grond | Up to level: 01 ok. ruwe vloer | Finish Face: Interior | 3570 | 0.933555 | 268 | 0.0121362
3527518 | 00 begane grond | -60 | 00 begane grond | Up to level: 01 ok. ruwe vloer | Finish Face: Interior | 3570 | 0.933555 | 268 | 0.0121362
3527519 | 00 begane grond | -60 | 00 begane grond | Up to level: 01 ok. ruwe vloer | Finish Face: Interior | 3570 | 0.116025 | 141.5 | 0.00150833
3527520 | 00 begane grond | -60 | 00 begane grond | Up to level: 01 ok. ruwe vloer | Finish Face: Interior | 3570 | 0.116025 | 141.5 | 0.00150832
3527521 | 00 begane grond | -60 | 00 begane grond | Up to level: 01 ok. ruwe vloer | Finish Face: Interior | 3570 | 0.9639 | 283 | 0.0125307
3527522 | 00 begane grond | -60 | 00 begane grond | Up to level: 01 ok. ruwe vloer | Finish Face: Interior | 3570 | 0.9639 | 283 | 0.0125307
3528543 | 00 begane grond | -60 | 00 begane grond | Up to level: 01 ok. ruwe vloer | Finish Face: Interior | 3570 | 0.1071 | 36.5 | 0.0013923
3528546 | 00 begane grond | -60 | 00 begane grond | Up to level: 01 ok. ruwe vloer | Finish Face: Interior | 3570 | 0.52836 | 141.5 | 0.00686868
3528547 | 00 begane grond | -60 | 00 begane grond | Up to level: 01 ok. ruwe vloer | Finish Face: Interior | 3570 | 0.52836 | 141.5 | 0.00686868
3528632 | 00 begane grond | -60 | 00 begane grond | Up to level: 01 ok. ruwe vloer | Finish Face: Interior | 3570 | 0.73185 | 102.5 | 0.00951405
3528751 | 00 begane grond | -60 | 00 begane grond | Up to level: 01 ok. ruwe vloer | Finish Face: Interior | 3570 | 0.12495 | 41.5 | 0.00162435
3529879 | 00 begane grond | -60 | 00 begane grond | Up to level: 01 ok. ruwe vloer | Finish Face: Interior | 3570 | 1.05672 | 283 | 0.0137374
3529880 | 00 begane grond | -60 | 00 begane grond | Up to level: 01 ok. ruwe vloer | Finish Face: Interior | 3570 | 0.48195 | 141.5 | 0.00626535
3529881 | 00 begane grond | -60 | 00 begane grond | Up to level: 01 ok. ruwe vloer | Finish Face: Interior | 3570 | 0.48195 | 141.5 | 0.00626535
3533465 | 02 tweede verdieping | 0 | 02 tweede verdieping | Up to level: 03 ok. ruwe vloer | Finish Face: Interior | 3500 | 2.0125 | 700 | 0.0261625
3534094 | 01 eerste verdieping | 0 | 01 eerste verdieping | Up to level: 02 ok. ruwe vloer | Finish Face: Interior | 3430 | 0.293265 | 141.5 | 0.00381244
3534095 | 01 eerste verdieping | 0 | 01 eerste verdieping | Up to level: 02 ok. ruwe vloer | Finish Face: Interior | 3430 | 0.293265 | 141.5 | 0.00381245
3534778 | 01 eerste verdieping | 0 | 01 eerste verdieping | Up to level: 02 ok. ruwe vloer | Finish Face: Interior | 3430 | 0.63455 | 254 | 0.00824915
3534779 | 01 eerste verdieping | 0 | 01 eerste verdieping | Up to level: 02 ok. ruwe vloer | Finish Face: Interior | 3430 | 0.63455 | 254 | 0.00824915
3534782 | 01 eerste verdieping | 0 | 01 eerste verdieping | Up to level: 02 ok. ruwe vloer | Finish Face: Interior | 3430 | 0.09604 | 71.5 | 0.00124852
3534783 | 01 eerste verdieping | 0 | 01 eerste verdieping | Up to level: 02 ok. ruwe vloer | Finish Face: Interior | 3430 | 0.09604 | 71.5 | 0.00124852
3535202 | 01 eerste verdieping | 0 | 01 eerste verdieping | Up to level: 02 ok. ruwe vloer | Finish Face: Interior | 3430 | 1.0633 | 254 | 0.0138229
3535203 | 01 eerste verdieping | 0 | 01 eerste verdieping | Up to level: 02 ok. ruwe vloer | Finish Face: Interior | 3430 | 1.0633 | 254 | 0.0138229
3535206 | 01 eerste verdieping | 0 | 01 eerste verdieping | Up to level: 02 ok. ruwe vloer | Finish Face: Interior | 3430 | 0.09604 | 71.5 | 0.00124852
3535207 | 01 eerste verdieping | 0 | 01 eerste verdieping | Up to level: 02 ok. ruwe vloer | Finish Face: Interior | 3430 | 0.09604 | 71.5 | 0.00124852
3537778 | 00 begane grond | -60 | 00 begane grond | Up to level: 01 ok. ruwe vloer | Finish Face: Interior | 3570 | 1.10849 | 366.5 | 0.0144103
3537779 | 00 begane grond | -60 | 00 begane grond | Up to level: 01 ok. ruwe vloer | Finish Face: Interior | 3570 | 1.10849 | 366.5 | 0.0144103
3537806 | 00 begane grond | -60 | 00 begane grond | Up to level: 01 ok. ruwe vloer | Finish Face: Interior | 3570 | 1.10849 | 366.5 | 0.0144103
3537807 | 00 begane grond | -60 | 00 begane grond | Up to level: 01 ok. ruwe vloer | Finish Face: Interior | 3570 | 1.10849 | 366.5 | 0.0144103
3537837 | 00 begane grond | -60 | 00 begane grond | Up to level: 01 ok. ruwe vloer | Finish Face: Interior | 3570 | 1.1067 | 323 | 0.0143871
3537877 | 00 begane grond | -60 | 00 begane grond | Up to level: 01 ok. ruwe vloer | Finish Face: Interior | 3570 | 1.1067 | 323 | 0.0143871
4193690 | 02 tweede verdieping | 0 | 02 tweede verdieping | Up to level: 03 ok. ruwe vloer | Finish Face: Interior | 3500 | 0.5425 | 161.5 | 0.0070525
4194213 | 02 tweede verdieping | 0 | 02 tweede verdieping | Up to level: 03 ok. ruwe vloer | Finish Face: Interior | 3500 | 2.0125 | 700 | 0.0261625
4210850 | 00 begane grond | -60 | 00 begane grond | Up to level: 01 ok. ruwe vloer | Core Face: Exterior | 3570 | 4.3554 | 1282.5 | 0.0566202
4234163 | 00 begane grond | -60 | 00 begane grond | Up to level: 01 ok. ruwe vloer | Finish Face: Interior | 3570 | 1.24593 | 405 | 0.0161971
4234164 | 00 begane grond | -60 | 00 begane grond | Up to level: 01 ok. ruwe vloer | Finish Face: Interior | 3570 | 0.817673 | 235.54 | 0.0106297
4256237 | 00 begane grond | -60 | 00 begane grond | Up to level: 01 ok. ruwe vloer | Finish Face: Interior | 3570 | 0.630105 | 244 | 0.00819136
4868647 | 00 begane grond | 0 | 00 begane grond | Up to level: 01 ok. ruwe vloer | Wall Centerline | 3630 | 0.978991 | 269.695 | 0.0127269

# IfcWallStandardCase: Basic Wall:NLRS_41_WA_multiplex 25 (5)
In: 00 begane grond
Type - PredefinedType: STANDARD; Material: i4_multiplex 25 mm
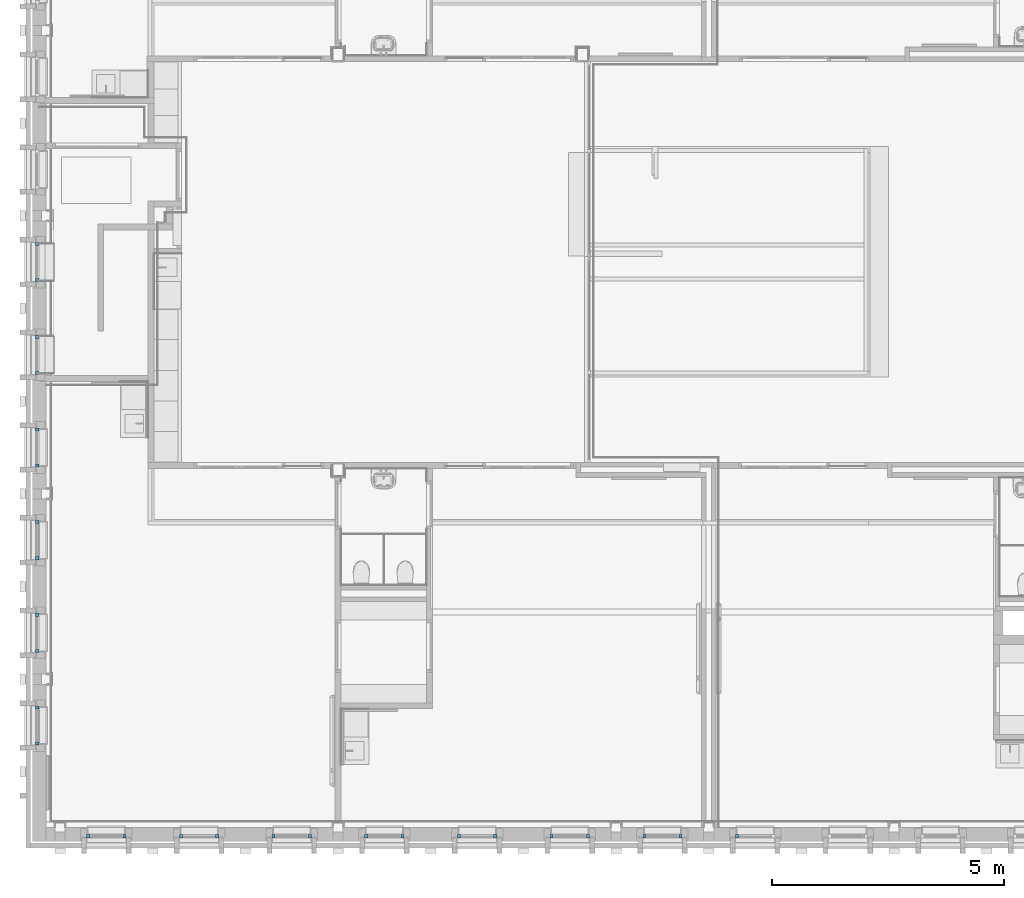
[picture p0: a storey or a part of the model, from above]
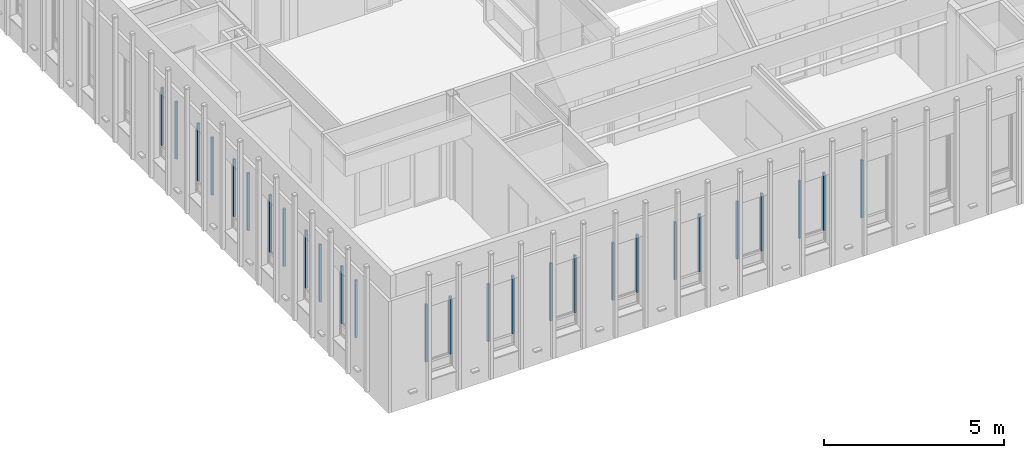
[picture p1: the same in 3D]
Properties of the parts of a building model (IFC2X3), part 92 of 94

# IfcWallStandardCase: Basic Wall:NLRS_41_WA_multiplex 25 (5)
Type - Analytical Properties - Roughness: 1; Absorptance: 0.1
Type - Graphics - Coarse Scale Fill Pattern: <Solid fill>; Coarse Scale Fill Color: 4210752
Type - Construction - Function: Interior; Wrapping at Inserts: Do not wrap; Width: 25 mm
Type - Identity Data - Workset: Wall Types; Assembly Code: 41.12; Assembly Description: buitenwandafwerkingen; bekledingen; Description: beplating 12mm; Model: LOD300; SmartRevit_Versie: 2018.2; Type Name: NLRS_41_WA_multiplex 25
Type - Other - Category: Walls; Family Name: Basic Wall
Classification: 41.12 Uniformat (Uniformat)
Cross-Section Definition - Cross-Section: Vertical
Constraints - Base Extension Distance: 0 mm; Related to Mass: no; Room Bounding: yes; Top Extension Distance: 0 mm; Base Constraint: 00 begane grond; Base Offset: 0 mm; Top Constraint: Up to level: 00 begane grond; Location Line: Finish Face: Interior; Top is Attached: yes; Base is Attached: yes; Top Offset: 1700 mm; Unconnected Height: 1700 mm
Phasing - Phase Created: 2. nieuwbouw
Structural - Enable Analytical Model: no; Structural: no; Structural Usage: Non-bearing
Identity Data - Workset: Workset1
Other - Family: Basic Wall; Family and Type: Basic Wall: NLRS_41_WA_multiplex 25; Type: NLRS_41_WA_multiplex 25; Type Id: 3462486
Name (Basic Wall:NLRS_41_WA_multiplex 25:...) | Area (m2) | Length (mm) | Volume (m3)
3462488 | 1.8354 | 1355 | 0.045885
3462489 | 0.51205 | 410 | 0.0128013
3462490 | 0.0532 | 27.5 | 0.00133
3462491 | 0.51205 | 410 | 0.0128013
3462492 | 0.0532 | 27.5 | 0.00133

# IfcWallStandardCase: Basic Wall:NLRS_41_WA_sanitairwand 13_gen_ISR (22)
Type - PredefinedType: STANDARD; Material: a_binnenwand_gen 13 mm
Type - Analytical Properties - Roughness: 1; Absorptance: 0.1
Type - Materials and Finishes - Structural Material: a_binnenwand_gen
Type - Graphics - Coarse Scale Fill Pattern: <Solid fill>; Coarse Scale Fill Color: 4210752
Type - Construction - Function: Interior; Wrapping at Inserts: Do not wrap; Width: 13 mm
Type - Identity Data - Workset: Wall Types; Assembly Code: 41.12; Assembly Description: buitenwandafwerkingen; bekledingen; Description: sanitairwand 13mm; Model: LOD300; SmartRevit_Versie: 2018.2; Type Name: NLRS_41_WA_sanitairwand 13_gen_ISR
Type - Other - Category: Walls; Family Name: Basic Wall
Classification: 41.12 Uniformat (Uniformat)
Cross-Section Definition - Cross-Section: Vertical
Constraints - Base Extension Distance: 0 mm; Base is Attached: no; Related to Mass: no; Top Extension Distance: 0 mm; Top is Attached: no; Location Line: Wall Centerline; Base Offset: 150 mm; Room Bounding: no; Top Offset: 2150 mm; Unconnected Height: 2000 mm
Phasing - Phase Created: 2. nieuwbouw
Structural - Enable Analytical Model: no; Structural: no; Structural Usage: Non-bearing
Identity Data - Workset: Workset1
Other - Family: Basic Wall; Family and Type: Basic Wall: NLRS_41_WA_sanitairwand 13_gen_ISR; Type: NLRS_41_WA_sanitairwand 13_gen_ISR; Type Id: 1245057
Name (Basic Wall:NLRS_41_WA_sanitairwand 13_gen_ISR:...) | In | Base Constraint | Top Constraint | Area (m2) | Length (mm) | Volume (m3)
1291606 | 02 tweede verdieping | 02 tweede verdieping | Up to level: 02 tweede verdieping | 3.675 | 1900 | 0.047775
1291607 | 02 tweede verdieping | 02 tweede verdieping | Up to level: 02 tweede verdieping | 2.2 | 1156.5 | 0.0286
1291608 | 02 tweede verdieping | 02 tweede verdieping | Up to level: 02 tweede verdieping | 2.36 | 1305 | 0.03068
1291609 | 02 tweede verdieping | 02 tweede verdieping | Up to level: 02 tweede verdieping | 2.277 | 1251 | 0.029601
1291611 | 02 tweede verdieping | 02 tweede verdieping | Up to level: 02 tweede verdieping | 3.7 | 1975 | 0.0481
1291612 | 02 tweede verdieping | 02 tweede verdieping | Up to level: 02 tweede verdieping | 2.2 | 1156.5 | 0.0286
1291613 | 01 eerste verdieping | 01 eerste verdieping | Up to level: 01 eerste verdieping | 3.7 | 1975 | 0.0481
1291614 | 01 eerste verdieping | 01 eerste verdieping | Up to level: 01 eerste verdieping | 2.2 | 1156.5 | 0.0286
1291615 | 01 eerste verdieping | 01 eerste verdieping | Up to level: 01 eerste verdieping | 2.1 | 1175 | 0.0273
1291616 | 01 eerste verdieping | 01 eerste verdieping | Up to level: 01 eerste verdieping | 3.70001 | 1975 | 0.0481001
1291617 | 01 eerste verdieping | 01 eerste verdieping | Up to level: 01 eerste verdieping | 2.2 | 1156.5 | 0.0286
1291618 | 01 eerste verdieping | 01 eerste verdieping | Up to level: 01 eerste verdieping | 2.1 | 1175 | 0.0273
1291619 | 01 eerste verdieping | 01 eerste verdieping | Up to level: 01 eerste verdieping | 2.4 | 1200 | 0.0312
1291622 | 00 begane grond | 00 begane grond | Up to level: 00 begane grond | 3.86 | 1930 | 0.05018
1291623 | 00 begane grond | 00 begane grond | Up to level: 00 begane grond | 2.2 | 1156.5 | 0.0286
1291624 | 00 begane grond | 00 begane grond | Up to level: 00 begane grond | 3.7 | 1975 | 0.0481
1291625 | 00 begane grond | 00 begane grond | Up to level: 00 begane grond | 2.2 | 1156.5 | 0.0286
1291626 | 00 begane grond | 00 begane grond | Up to level: 00 begane grond | 3.7 | 1975 | 0.0481
1291627 | 00 begane grond | 00 begane grond | Up to level: 00 begane grond | 2.4 | 1256.5 | 0.0312
1509585 | 00 begane grond | 00 begane grond | Up to level: 00 begane grond | 0.82 | 460 | 0.01066
1509880 | 00 begane grond | 00 begane grond | Up to level: 00 begane grond | 0.82 | 460 | 0.01066
1510112 | 00 begane grond | 00 begane grond | Up to level: 00 begane grond | 0.82 | 460 | 0.01066

# IfcWallStandardCase: Basic Wall:NLRS_41_WA_vezelcement voorzet 10+22_gen_ISR (5)
In: 01 eerste verdieping
Type - PredefinedType: STANDARD; Material: ISR_Vezelcement 10 mm, ISR_Luchtspouw 22 mm
Type - Analytical Properties - Roughness: 1; Absorptance: 0.1
Type - Graphics - Coarse Scale Fill Pattern: <Solid fill>; Coarse Scale Fill Color: 4210752
Type - Construction - Function: Interior; Wrapping at Inserts: Do not wrap; Width: 32 mm
Type - Identity Data - Workset: Wall Types; Assembly Code: 41.12; Assembly Description: buitenwandafwerkingen; bekledingen; Description: beplating 12mm; Model: LOD300; SmartRevit_Versie: 2018.2; Type Name: NLRS_41_WA_vezelcement voorzet 10+22_gen_ISR
Type - Other - Category: Walls; Family Name: Basic Wall
Classification: 41.12 Uniformat (Uniformat)
Cross-Section Definition - Cross-Section: Vertical
Constraints - Base Extension Distance: 0 mm; Base is Attached: no; Related to Mass: no; Room Bounding: yes; Top Extension Distance: 0 mm; Top is Attached: no; Base Constraint: 01 eerste verdieping; Top Constraint: Up to level: 01 eerste verdieping; Location Line: Finish Face: Interior; Top Offset: 775 mm
Phasing - Phase Created: 2. nieuwbouw
Structural - Enable Analytical Model: no; Structural: no; Structural Usage: Non-bearing
Identity Data - Workset: Workset1
Other - Family: Basic Wall; Family and Type: Basic Wall: NLRS_41_WA_vezelcement voorzet 10+22_gen_ISR; Type: NLRS_41_WA_vezelcement voorzet 10+22_gen_ISR; Type Id: 1916250
Name (Basic Wall:NLRS_41_WA_vezelcement voorzet 10+22_gen_ISR:...) | Base Offset (mm) | Unconnected Height (mm) | Center Mark Visible | Area (m2) | Length (mm) | Volume (m3)
3345265 | 350 | 425 | no | 0.554098 | 1278.63 | 0.0173893
3345270 | 350 | 425 |  | 0.08075 | 340 | 0.002584
3345274 | 180 | 595 | no | 0.787318 | 1311.26 | 0.0249664
3345279 | 180 | 595 | no | 0.621188 | 799.744 | 0.0192179
3345284 | 231.135 | 543.865 |  | 7.10966 | 13525.6 | 0.227509

# IfcWallStandardCase: Basic Wall:NLRS_41_WA_vezelcement voorzet 35+8_buitenberging int (3)
In: 00 begane grond
Type - PredefinedType: STANDARD; Material: ISR_Vezelcement 8 mm, ISR_Luchtspouw 35 mm
Type - Analytical Properties - Roughness: 1; Absorptance: 0.1
Type - Graphics - Coarse Scale Fill Pattern: <Solid fill>; Coarse Scale Fill Color: 4210752
Type - Construction - Function: Interior; Wrapping at Inserts: Do not wrap; Width: 43 mm
Type - Identity Data - Workset: Wall Types; Assembly Code: 41.12; Assembly Description: buitenwandafwerkingen; bekledingen; Description: beplating 12mm; Model: LOD300; SmartRevit_Versie: 2018.2; Type Name: NLRS_41_WA_vezelcement voorzet 35+8_buitenberging int
Type - Other - Category: Walls; Family Name: Basic Wall
Classification: 41.12 Uniformat (Uniformat)
Cross-Section Definition - Cross-Section: Vertical
Constraints - Base Extension Distance: 0 mm; Base is Attached: no; Related to Mass: no; Room Bounding: yes; Top Extension Distance: 0 mm; Top is Attached: no; Base Constraint: 00 begane grond; Top Constraint: Up to level: 01 ok. ruwe vloer; Location Line: Finish Face: Interior; Base Offset: -30 mm; Top Offset: -220 mm; Unconnected Height: 3440 mm
Phasing - Phase Created: 2. nieuwbouw
Structural - Enable Analytical Model: no; Structural: no; Structural Usage: Non-bearing
Identity Data - Workset: Workset1
Other - Family: Basic Wall; Family and Type: Basic Wall: NLRS_41_WA_vezelcement voorzet 35+8_buitenberging int; Type: NLRS_41_WA_vezelcement voorzet 35+8_buitenberging int; Type Id: 2738966
Name (Basic Wall:NLRS_41_WA_vezelcement voorzet 35+8_buitenberging int:...) | Area (m2) | Length (mm) | Volume (m3)
2738863 | 12.4356 | 3593.5 | 0.534731
2739246 | 10.1308 | 2966.5 | 0.435624
4196141 | 7.2928 | 2120 | 0.31359

# IfcWallStandardCase: Basic Wall:NLRS_41_WA_vezelcement voorzet 8+15+22_gen_ISR (2)
Type - PredefinedType: STANDARD; Material: ISR_Vezelcement 8 mm, i4_multiplex 15 mm, ISR_Luchtspouw 22 mm
Type - Analytical Properties - Roughness: 1; Absorptance: 0.1
Type - Graphics - Coarse Scale Fill Pattern: <Solid fill>; Coarse Scale Fill Color: 4210752
Type - Construction - Function: Interior; Wrapping at Inserts: Do not wrap; Width: 45 mm
Type - Identity Data - Workset: Wall Types; Assembly Code: 41.12; Assembly Description: buitenwandafwerkingen; bekledingen; Description: beplating 12mm; Model: LOD300; SmartRevit_Versie: 2018.2; Type Name: NLRS_41_WA_vezelcement voorzet 8+15+22_gen_ISR
Type - Other - Category: Walls; Family Name: Basic Wall
Classification: 41.12 Uniformat (Uniformat)
Cross-Section Definition - Cross-Section: Vertical
Constraints - Base Extension Distance: 0 mm; Base is Attached: no; Related to Mass: no; Room Bounding: yes; Top Extension Distance: 0 mm; Top is Attached: no; Location Line: Finish Face: Interior
Phasing - Phase Created: 2. nieuwbouw
Structural - Enable Analytical Model: no; Structural: no; Structural Usage: Non-bearing
Identity Data - Workset: Workset1
Other - Family: Basic Wall; Family and Type: Basic Wall: NLRS_41_WA_vezelcement voorzet 8+15+22_gen_ISR; Type: NLRS_41_WA_vezelcement voorzet 8+15+22_gen_ISR; Type Id: 2093359
Name (Basic Wall:NLRS_41_WA_vezelcement voorzet 8+15+22_gen_ISR:...) | In | Base Constraint | Top Constraint | Base Offset (mm) | Top Offset (mm) | Unconnected Height (mm) | Area (m2) | Length (mm) | Volume (m3)
1916431 | 01 eerste verdieping | 01 eerste verdieping | Up to level: 02 dakrand gymzaal | -50 | 35 | 3285 | 48.2419 | 14765.5 | 2.17088
3468343 | 00 begane grond | 00 begane grond | Up to level: 01 ok. ruwe vloer | -30 | 410 | 4070 | 20.2393 | 4925 | 0.910766

# IfcWindow: 31_WI_raam_1:deur kabelnet L (2)
In: 01 eerste verdieping
Type - ParameterTakesPrecedence: no; Sizeable: no; Material: h2_staal_gen
Type - Analytical Properties - Define Thermal Properties by: Schematic Type; Analytic Construction: <None>
Type - Constraints - offset: -8 mm; offset_bovenkant: -30 mm; offset_links: -10 mm; offset_onderkant: -50 mm; offset_rechts: -2.5 mm
Type - Dimensions - SillStacks: 0; Frame: 80 mm; Head: 80 mm; Sill: 80 mm; Thickness: 40 mm
Type - Identity Data - Workset: Family : Windows : 31_WI_raam_1; Assembly Code: 31.2; Description: raam met 1 subvak; Manufacturer: ITANNEX; Model: 01-05-2018; Type Comments: ramen; Type Mark: 98; Type Name: deur kabelnet L; URL: www.bimvoorfabrikanten.nl
Type - Other - Category: Windows; Family Name: 31_WI_raam_1
OverallHeight: 2590 mm
Model Properties - diepte_offset: 0 mm; subpaneel_a1_roedes_hor: 0; subpaneel_a1_roedes_ver: 0; draairichting_a_type: BI deur rechts BDG : BI deur rechts; subpaneel_a1_type: WI_subvak : RVS kabelnet
Constraints - Level: 01 eerste verdieping
Phasing - Phase Created: 2. nieuwbouw
Materials and Finishes - paneel_exterieur_materiaal: h2_staal_gen; paneel_interieur_materiaal: h2_staal_gen
Dimensions - Height: 2590 mm; netto_hoogte: 2510 mm
Identity Data - Workset: Workset1
Other - Family: 31_WI_raam_1; offset_b: 0 mm; SillStacksCalc: 2; offset_bovenkant_b: 0 mm; offset_links_b: 0 mm; offset_onderkant_b: 0 mm; offset_rechts_b: 0 mm; Family and Type: 31_WI_raam_1: deur kabelnet L; HeightReport: 2590 mm; offset_a: 8 mm; offset_bovenkant_a: 30 mm; offset_links_a: 10 mm; offset_onderkant_a: 50 mm; offset_rechts_a: 2.5 mm; subpaneel_1_hoogte: 2350 mm; Type: deur kabelnet L; Type Id: 3204399
Name (31_WI_raam_1:deur kabelnet L:...) | OverallWidth (mm) = Width (mm) = WidthReport (mm) | Area (m2) | netto_breedte (mm) | paneel_oppervlakte (m2) | Volume (m3) | Host Id | subpaneel_a_breedte (mm) | subpaneel_a1_oppervlakte (m2)
2757051 | 950 | 2.4605 | 937.5 | 0.526 | 0.004921 | 2756939 | 777.5 | 1.82713
2765842 | 740 | 1.9166 | 727.5 | 0.4924 | 0.0038332 | 2765839 | 567.5 | 1.33363 | Identity Data - Mark: 685

# IfcWindow: 31_WI_raam_1:deur kabelnet R, 31_WI_raam_1:deur kabelnet R:2769525
In: 01 eerste verdieping
Type - ParameterTakesPrecedence: no; Sizeable: no; Material: a_kozijn
Type - Analytical Properties - Define Thermal Properties by: Schematic Type; Analytic Construction: <None>
Type - Constraints - offset: -8 mm; offset_bovenkant: -30 mm; offset_links: -2.5 mm; offset_onderkant: -50 mm; offset_rechts: -10 mm
Type - Dimensions - SillStacks: 0; Frame: 80 mm; Head: 80 mm; Sill: 80 mm; Thickness: 40 mm
Type - Identity Data - Workset: Family : Windows : 31_WI_raam_1; Assembly Code: 31.2; Description: raam met 1 subvak; Manufacturer: ITANNEX; Model: 01-05-2018; Type Comments: ramen; Type Mark: 91; Type Name: deur kabelnet R; URL: www.bimvoorfabrikanten.nl
Type - Other - Category: Windows; Family Name: 31_WI_raam_1
OverallHeight: 2590 mm; OverallWidth: 912.5 mm
Model Properties - diepte_offset: 0 mm; subpaneel_a1_roedes_hor: 0; subpaneel_a1_roedes_ver: 0; draairichting_a_type: BU deur links BDG : BU deur links; subpaneel_a1_type: WI_subvak : RVS kabelnet
Constraints - Level: 01 eerste verdieping
Phasing - Phase Created: 2. nieuwbouw
Dimensions - Area: 2.36338 m2; Height: 2590 mm; netto_breedte: 900 mm; netto_hoogte: 2510 mm; paneel_oppervlakte: 0.52 m2; Volume: 0.00472675 m3; Width: 912.5 mm
Identity Data - Workset: Workset1; Mark: 690
Other - Family: 31_WI_raam_1; offset_b: 0 mm; SillStacksCalc: 2; offset_bovenkant_b: 0 mm; offset_links_b: 0 mm; offset_onderkant_b: 0 mm; offset_rechts_b: 0 mm; Family and Type: 31_WI_raam_1: deur kabelnet R; Type: deur kabelnet R; Type Id: 2757127; HeightReport: 2590 mm; Host Id: 2769524; offset_a: 8 mm; offset_bovenkant_a: 30 mm; offset_links_a: 2.5 mm; offset_onderkant_a: 50 mm; offset_rechts_a: 10 mm; subpaneel_1_hoogte: 2350 mm; subpaneel_a_breedte: 740 mm; subpaneel_a1_oppervlakte: 1.739 m2; WidthReport: 912.5 mm

# IfcWindow: 31_WI_raam_1:deur kabelnet R (2)
In: 01 eerste verdieping
Type - ParameterTakesPrecedence: no; Sizeable: no; Material: h2_staal_gen
Type - Analytical Properties - Define Thermal Properties by: Schematic Type; Analytic Construction: <None>
Type - Constraints - offset: -8 mm; offset_bovenkant: -30 mm; offset_links: -2.5 mm; offset_onderkant: -50 mm; offset_rechts: -10 mm
Type - Dimensions - SillStacks: 0; Frame: 80 mm; Head: 80 mm; Sill: 80 mm; Thickness: 40 mm
Type - Identity Data - Workset: Family : Windows : 31_WI_raam_1; Assembly Code: 31.2; Description: raam met 1 subvak; Manufacturer: ITANNEX; Model: 01-05-2018; Type Comments: ramen; Type Mark: 91; Type Name: deur kabelnet R; URL: www.bimvoorfabrikanten.nl
Type - Other - Category: Windows; Family Name: 31_WI_raam_1
OverallHeight: 2590 mm; OverallWidth: 950 mm
Model Properties - diepte_offset: 0 mm; subpaneel_a1_roedes_hor: 0; subpaneel_a1_roedes_ver: 0; draairichting_a_type: BI deur links BDG : BI deur links; subpaneel_a1_type: WI_subvak : RVS kabelnet
Constraints - Level: 01 eerste verdieping
Phasing - Phase Created: 2. nieuwbouw
Materials and Finishes - paneel_exterieur_materiaal: h2_staal_gen; paneel_interieur_materiaal: h2_staal_gen
Dimensions - Area: 2.4605 m2; Height: 2590 mm; netto_breedte: 937.5 mm; netto_hoogte: 2510 mm; paneel_oppervlakte: 0.526 m2; Volume: 0.004921 m3; Width: 950 mm
Identity Data - Workset: Workset1
Other - Family: 31_WI_raam_1; offset_b: 0 mm; SillStacksCalc: 2; offset_bovenkant_b: 0 mm; offset_links_b: 0 mm; offset_onderkant_b: 0 mm; offset_rechts_b: 0 mm; Family and Type: 31_WI_raam_1: deur kabelnet R; HeightReport: 2590 mm; offset_a: 8 mm; offset_bovenkant_a: 30 mm; offset_links_a: 2.5 mm; offset_onderkant_a: 50 mm; offset_rechts_a: 10 mm; subpaneel_1_hoogte: 2350 mm; subpaneel_a_breedte: 777.5 mm; subpaneel_a1_oppervlakte: 1.82713 m2; Type: deur kabelnet R; Type Id: 2757127; WidthReport: 950 mm
Name (31_WI_raam_1:deur kabelnet R:...) | Host Id
2756940 | 2756939
2765840 | 2765839 | Identity Data - Mark: 684

# IfcWindow: 31_WI_raam_1:raam RT72 (106)
Type - ParameterTakesPrecedence: no; Sizeable: no; Material: a_kozijn
Type - Analytical Properties - Define Thermal Properties by: Schematic Type; Analytic Construction: <None>
Type - Constraints - offset: -8 mm; offset_bovenkant: 28 mm; offset_links: 28 mm; offset_onderkant: 28 mm; offset_rechts: 28 mm
Type - Dimensions - Frame: 68 mm; Head: 68 mm; Sill: 68 mm; SillStacks: 0; Thickness: 72 mm
Type - Identity Data - Assembly Code: 31.2; Description: raam met 1 subvak; Manufacturer: ITANNEX; Model: 01-05-2018; Type Comments: ramen; Type Mark: 69; Type Name: raam RT72; URL: www.bimvoorfabrikanten.nl; Workset: Family : Windows : 31_WI_raam_1
Type - Other - Category: Windows; Family Name: 31_WI_raam_1
Model Properties - subpaneel_a1_roedes_hor: 0; subpaneel_a1_roedes_ver: 0; subpaneel_a1_type: WI_subvak : glas 2
Phasing - Phase Created: 2. nieuwbouw
Identity Data - Workset: Workset1
Other - Family: 31_WI_raam_1; Family and Type: 31_WI_raam_1: raam RT72; offset_bovenkant_a: 28 mm; offset_bovenkant_b: 56 mm; offset_links_a: 28 mm; offset_links_b: 56 mm; offset_onderkant_a: 28 mm; offset_onderkant_b: 56 mm; offset_rechts_a: 28 mm; offset_rechts_b: 56 mm; SillStacksCalc: 2; Type: raam RT72; Type Id: 835114
Name (31_WI_raam_1:raam RT72:...) | In | OverallHeight (mm) | OverallWidth (mm) = netto_breedte (mm) | diepte_offset (mm) | draairichting_a_type | Level | Area (m2) | Height (mm) = HeightReport (mm) | netto_hoogte (mm) | paneel_oppervlakte (m2) | Volume (m3) | Width (mm) = WidthReport (mm) | Host Id | offset_a (mm) | offset_b (mm) | subpaneel_1_hoogte (mm) | subpaneel_a_breedte (mm) | subpaneel_a1_oppervlakte (m2) | Group | Mark
1864418 | 01 eerste verdieping | 1952 | 393 | 0 | BI draai-val rechts | 01 eerste verdieping | 0.634908 | 1884 | 1940 | 0.298792 | 0.00126982 | 337 | 875025 | 8 | 0 | 1804 | 257 | 0.463628 | Model Group:31_1A DKD L:875031
875050 | 01 eerste verdieping | 1952 | 393 | 0 | BI draai-val links | 01 eerste verdieping | 0.634908 | 1884 | 1940 | 0.298792 | 0.00126982 | 337 | 875049 | 8 | 0 | 1804 | 257 | 0.463628 | Model Group:31_1A DK R:875055
1864680 | 01 eerste verdieping | 1952 | 1276 | 0 | BI draai-val rechts | 01 eerste verdieping | 2.29848 | 1884 | 1940 | 0.41888 | 0.00459696 | 1220 | 875049 | 8 | 0 | 1804 | 1140 | 2.05656 | Model Group:31_1A DK R:875055
875305 | 01 eerste verdieping | 1952 | 393 | 0 | BI draai-val links | 01 eerste verdieping | 0.634908 | 1884 | 1940 | 0.298792 | 0.00126982 | 337 | 875304 | 8 | 0 | 1804 | 257 | 0.463628 | Model Group:31_1A DKD R:875310
891758 | 01 eerste verdieping | 1952 | 496 | 0 | BI draai-val links | 01 eerste verdieping | 0.82896 | 1884 | 1940 | 0.3128 | 0.00165792 | 440 | 891757 | 8 | 0 | 1804 | 360 | 0.64944 | Model Group:BU-30:2700215
892039 | 00 begane grond | 2365 | 820 | 0 | BI val | 00 begane grond | 1.75491 | 2297 | 2353 | 0.413032 | 0.00350982 | 764 | 892038 | 8 | 0 | 2217 | 684 | 1.51643 | Model Group:BU-07 b900:894363
1861204 | 00 begane grond | 2365 | 956 | 0 | BI val | 00 begane grond | 2.0673 | 2297 | 2353 | 0.431528 | 0.0041346 | 900 | 1220070 | 8 | 0 | 2217 | 820 | 1.81794 | Model Group:BU-08 b2100:1220076
1220170 | 00 begane grond | 2365 | 956 | 0 | BI val | 00 begane grond | 2.0673 | 2297 | 2353 | 0.431528 | 0.0041346 | 900 | 1220169 | 8 | 0 | 2217 | 820 | 1.81794 | Model Group:BU-09 b1500:1220175
1220848 | 00 begane grond | 2365 | 956 | 0 | BI val | 00 begane grond | 2.0673 | 2297 | 2353 | 0.431528 | 0.0041346 | 900 | 1220847 | 8 | 0 | 2217 | 820 | 1.81794 | Model Group:BU-11 b3000:1220846
1300402 | 00 begane grond | 2365 | 820 | 0 | BI val | 00 begane grond | 1.75491 | 2297 | 2353 | 0.413032 | 0.00350982 | 764 | 1300401 | 8 | 0 | 2217 | 684 | 1.51643 | Model Group:BU-07 b900 (members excluded):1300407
1491381 | 00 begane grond | 565 | 956 | 0 | BI val | 00 begane grond | 0.4473 | 497 | 553 | 0.186728 | 0.0008946 | 900 | 1300742 | 8 | 0 | 417 | 820 | 0.34194 | Model Group:BU-21 b2966:1300741 | 296
1493858 | 00 begane grond | 2365 | 956 | 0 | BI val | 00 begane grond | 2.0673 | 2297 | 2353 | 0.431528 | 0.0041346 | 900 | 1493475 | 8 | 0 | 2217 | 820 | 1.81794 | Model Group:BU-25 b3000:1493474
1494106 | 00 begane grond | 2365 | 956 | 0 | BI val | 00 begane grond | 2.0673 | 2297 | 2353 | 0.431528 | 0.0041346 | 900 | 1494105 | 8 | 0 | 2217 | 820 | 1.81794 | Model Group:BU-02 b4200:1494104
1494112 | 00 begane grond | 2365 | 956 | 0 | BI val | 00 begane grond | 2.0673 | 2297 | 2353 | 0.431528 | 0.0041346 | 900 | 1494105 | 8 | 0 | 2217 | 820 | 1.81794 | Model Group:BU-02 b4200:1494104
1502982 | 00 begane grond | 2365 | 820 | 0 | BI val | 00 begane grond | 1.75491 | 2297 | 2353 | 0.413032 | 0.00350982 | 764 | 1502981 | 8 | 0 | 2217 | 684 | 1.51643 | Model Group:BU-07 b900:1502980
1817350 | 00 begane grond | 2365 | 956 | 0 | BI val | 00 begane grond | 2.0673 | 2297 | 2353 | 0.431528 | 0.0041346 | 900 | 1817349 | 8 | 0 | 2217 | 820 | 1.81794 | Model Group:BU-12 b4200:1817348 | 397
1818870 | 00 begane grond | 2365 | 956 | 0 | BI val | 00 begane grond | 2.0673 | 2297 | 2353 | 0.431528 | 0.0041346 | 900 | 1818869 | 8 | 0 | 2217 | 820 | 1.81794 | Model Group:BU-03 b5800:1818868
1819716 | 00 begane grond | 2365 | 956 | 0 | BI val | 00 begane grond | 2.0673 | 2297 | 2353 | 0.431528 | 0.0041346 | 900 | 1818869 | 8 | 0 | 2217 | 820 | 1.81794 | Model Group:BU-03 b5800:1818868
1856667 | 00 begane grond | 2365 | 870 | 0 | BI val | 00 begane grond | 1.86976 | 2297 | 2353 | 0.419832 | 0.00373952 | 814 | 1853992 | 8 | 0 | 2217 | 734 | 1.62728 | Model Group:BU-18 b3017:2651211
1862282 | 00 begane grond | 1950 | 956 | 0 | BI val | 00 begane grond | 1.6938 | 1882 | 1938 | 0.375088 | 0.0033876 | 900 | 1862275 | 8 | 0 | 1802 | 820 | 1.47764 | Model Group:BU-13 b3300:1862274
1864933 | 01 eerste verdieping | 1952 | 393 | 0 | BI draai-val links | 01 eerste verdieping | 0.634908 | 1884 | 1940 | 0.298792 | 0.00126982 | 337 | 1864932 | 8 | 0 | 1804 | 257 | 0.463628 | Model Group:31_1A DK R:1864938 | 478
1864941 | 01 eerste verdieping | 1952 | 1276 | 0 | BI draai-val rechts | 01 eerste verdieping | 2.29848 | 1884 | 1940 | 0.41888 | 0.00459696 | 1220 | 1864932 | 8 | 0 | 1804 | 1140 | 2.05656 | Model Group:31_1A DK R:1864938 | 479
1864985 | 01 eerste verdieping | 1952 | 393 | 0 | BI draai-val rechts | 01 eerste verdieping | 0.634908 | 1884 | 1940 | 0.298792 | 0.00126982 | 337 | 1864976 | 8 | 0 | 1804 | 257 | 0.463628 | Model Group:31_1A DKD L:1864982 | 490
1865002 | 01 eerste verdieping | 1952 | 393 | 0 | BI draai-val links | 01 eerste verdieping | 0.634908 | 1884 | 1940 | 0.298792 | 0.00126982 | 337 | 1865001 | 8 | 0 | 1804 | 257 | 0.463628 | Model Group:31_1A DK R:1865007 | 493
1865010 | 01 eerste verdieping | 1952 | 1276 | 0 | BI draai-val rechts | 01 eerste verdieping | 2.29848 | 1884 | 1940 | 0.41888 | 0.00459696 | 1220 | 1865001 | 8 | 0 | 1804 | 1140 | 2.05656 | Model Group:31_1A DK R:1865007 | 494
1865033 | 01 eerste verdieping | 1952 | 393 | 0 | BI draai-val rechts | 01 eerste verdieping | 0.634908 | 1884 | 1940 | 0.298792 | 0.00126982 | 337 | 1865024 | 8 | 0 | 1804 | 257 | 0.463628 | Model Group:31_1A DKD L:1865030 | 499
1865341 | 01 eerste verdieping | 1952 | 393 | 0 | BI draai-val links | 01 eerste verdieping | 0.634908 | 1884 | 1940 | 0.298792 | 0.00126982 | 337 | 1865340 | 8 | 0 | 1804 | 257 | 0.463628 | Model Group:31_1A DKD R:1865346 | 506
1865362 | 01 eerste verdieping | 1952 | 1276 | 0 | BI draai-val links | 01 eerste verdieping | 2.29848 | 1884 | 1940 | 0.41888 | 0.00459696 | 1220 | 1865361 | 8 | 0 | 1804 | 1140 | 2.05656 | Model Group:31_1A DK L:1865367 | 509
1865370 | 01 eerste verdieping | 1952 | 393 | 0 | BI draai-val rechts | 01 eerste verdieping | 0.634908 | 1884 | 1940 | 0.298792 | 0.00126982 | 337 | 1865361 | 8 | 0 | 1804 | 257 | 0.463628 | Model Group:31_1A DK L:1865367 | 510
1865569 | 01 eerste verdieping | 1952 | 393 | 0 | BI draai-val links | 01 eerste verdieping | 0.634908 | 1884 | 1940 | 0.298792 | 0.00126982 | 337 | 1865568 | 8 | 0 | 1804 | 257 | 0.463628 | Model Group:31_1A DKD R:1865574 | 487
1865603 | 01 eerste verdieping | 1952 | 393 | 0 | BI draai-val links | 01 eerste verdieping | 0.634908 | 1884 | 1940 | 0.298792 | 0.00126982 | 337 | 1865602 | 8 | 0 | 1804 | 257 | 0.463628 | Model Group:31_1A DKD R:1865608 | 518
1865650 | 01 eerste verdieping | 1952 | 1276 | 0 | BI draai-val links | 01 eerste verdieping | 2.29848 | 1884 | 1940 | 0.41888 | 0.00459696 | 1220 | 1865649 | 8 | 0 | 1804 | 1140 | 2.05656 | Model Group:31_1A DK L:1865655 | 527
1865658 | 01 eerste verdieping | 1952 | 393 | 0 | BI draai-val rechts | 01 eerste verdieping | 0.634908 | 1884 | 1940 | 0.298792 | 0.00126982 | 337 | 1865649 | 8 | 0 | 1804 | 257 | 0.463628 | Model Group:31_1A DK L:1865655 | 528
1865669 | 01 eerste verdieping | 1952 | 1276 | 0 | BI draai-val links | 01 eerste verdieping | 2.29848 | 1884 | 1940 | 0.41888 | 0.00459696 | 1220 | 1865668 | 8 | 0 | 1804 | 1140 | 2.05656 | Model Group:31_1A DK L:1865674 | 533
1865677 | 01 eerste verdieping | 1952 | 393 | 0 | BI draai-val rechts | 01 eerste verdieping | 0.634908 | 1884 | 1940 | 0.298792 | 0.00126982 | 337 | 1865668 | 8 | 0 | 1804 | 257 | 0.463628 | Model Group:31_1A DK L:1865674 | 534
1865776 | 01 eerste verdieping | 1952 | 393 | 0 | BI draai-val links | 01 eerste verdieping | 0.634908 | 1884 | 1940 | 0.298792 | 0.00126982 | 337 | 1865775 | 8 | 0 | 1804 | 257 | 0.463628 | Model Group:31_1A DKD R:1865781 | 554
1865797 | 01 eerste verdieping | 1952 | 1276 | 0 | BI draai-val links | 01 eerste verdieping | 2.29848 | 1884 | 1940 | 0.41888 | 0.00459696 | 1220 | 1865796 | 8 | 0 | 1804 | 1140 | 2.05656 | Model Group:31_1A DK L:1865802 | 557
1865805 | 01 eerste verdieping | 1952 | 393 | 0 | BI draai-val rechts | 01 eerste verdieping | 0.634908 | 1884 | 1940 | 0.298792 | 0.00126982 | 337 | 1865796 | 8 | 0 | 1804 | 257 | 0.463628 | Model Group:31_1A DK L:1865802 | 558
1865918 | 01 eerste verdieping | 1952 | 393 | 0 | BI draai-val links | 01 eerste verdieping | 0.634908 | 1884 | 1940 | 0.298792 | 0.00126982 | 337 | 1865917 | 8 | 0 | 1804 | 257 | 0.463628 | Model Group:31_1A DK R:1865923 | 563
1865926 | 01 eerste verdieping | 1952 | 1276 | 0 | BI draai-val rechts | 01 eerste verdieping | 2.29848 | 1884 | 1940 | 0.41888 | 0.00459696 | 1220 | 1865917 | 8 | 0 | 1804 | 1140 | 2.05656 | Model Group:31_1A DK R:1865923 | 564
1865949 | 01 eerste verdieping | 1952 | 393 | 0 | BI draai-val rechts | 01 eerste verdieping | 0.634908 | 1884 | 1940 | 0.298792 | 0.00126982 | 337 | 1865940 | 8 | 0 | 1804 | 257 | 0.463628 | Model Group:31_1A DKD L:1865946 | 569
1866077 | 01 eerste verdieping | 1952 | 1276 | 0 | BI draai-val links | 01 eerste verdieping | 2.29848 | 1884 | 1940 | 0.41888 | 0.00459696 | 1220 | 1866076 | 8 | 0 | 1804 | 1140 | 2.05656 | Model Group:31_1A DKg R:1866082 | 486
1867680 | 02 tweede verdieping | 1987 | 770 | 0 | BI draai-val links | 02 tweede verdieping | 1.37017 | 1919 | 1975 | 0.354824 | 0.00274033 | 714 | 1867671 | 8 | 0 | 1839 | 634 | 1.16593 | Model Group:31_2A DK R:1867677
1869347 | 02 tweede verdieping | 1987 | 770 | 0 | BI draai-val links | 02 tweede verdieping | 1.37017 | 1919 | 1975 | 0.354824 | 0.00274033 | 714 | 1869339 | 8 | 0 | 1839 | 634 | 1.16593 | Model Group:31_2A DK R:1869345 | 515
1869364 | 02 tweede verdieping | 1987 | 770 | 0 | BI draai-val links | 02 tweede verdieping | 1.37017 | 1919 | 1975 | 0.354824 | 0.00274033 | 714 | 1869356 | 8 | 0 | 1839 | 634 | 1.16593 | Model Group:31_2A DK R:1869362 | 541
1869381 | 02 tweede verdieping | 1987 | 770 | 0 | BI draai-val links | 02 tweede verdieping | 1.37017 | 1919 | 1975 | 0.354824 | 0.00274033 | 714 | 1869373 | 8 | 0 | 1839 | 634 | 1.16593 | Model Group:31_2A DK R:1869379 | 574
1869398 | 02 tweede verdieping | 1987 | 770 | 0 | BI draai-val links | 02 tweede verdieping | 1.37017 | 1919 | 1975 | 0.354824 | 0.00274033 | 714 | 1869390 | 8 | 0 | 1839 | 634 | 1.16593 | Model Group:31_2A DK R:1869396 | 577
1869415 | 02 tweede verdieping | 1987 | 770 | 0 | BI draai-val links | 02 tweede verdieping | 1.37017 | 1919 | 1975 | 0.354824 | 0.00274033 | 714 | 1869407 | 8 | 0 | 1839 | 634 | 1.16593 | Model Group:31_2A DK R:1869413 | 580
1869432 | 02 tweede verdieping | 1987 | 770 | 0 | BI draai-val links | 02 tweede verdieping | 1.37017 | 1919 | 1975 | 0.354824 | 0.00274033 | 714 | 1869424 | 8 | 0 | 1839 | 634 | 1.16593 | Model Group:31_2A DK R:1869430 | 583
1869449 | 02 tweede verdieping | 1987 | 770 | 0 | BI draai-val links | 02 tweede verdieping | 1.37017 | 1919 | 1975 | 0.354824 | 0.00274033 | 714 | 1869441 | 8 | 0 | 1839 | 634 | 1.16593 | Model Group:31_2A DK R:1869447 | 586
1869469 | 02 tweede verdieping | 1987 | 770 | 0 | BI draai-val rechts | 02 tweede verdieping | 1.37017 | 1919 | 1975 | 0.354824 | 0.00274033 | 714 | 1869461 | 8 | 0 | 1839 | 634 | 1.16593 | Model Group:31_2A DK L:1869467 | 589
1869608 | 02 tweede verdieping | 1987 | 770 | 0 | BI draai-val rechts | 02 tweede verdieping | 1.37017 | 1919 | 1975 | 0.354824 | 0.00274033 | 714 | 1869600 | 8 | 0 | 1839 | 634 | 1.16593 | Model Group:31_2A DK L:1869606 | 592
1869625 | 02 tweede verdieping | 1987 | 770 | 0 | BI draai-val rechts | 02 tweede verdieping | 1.37017 | 1919 | 1975 | 0.354824 | 0.00274033 | 714 | 1869617 | 8 | 0 | 1839 | 634 | 1.16593 | Model Group:31_2A DK L:1869623 | 595
1869642 | 02 tweede verdieping | 1987 | 770 | 0 | BI draai-val rechts | 02 tweede verdieping | 1.37017 | 1919 | 1975 | 0.354824 | 0.00274033 | 714 | 1869634 | 8 | 0 | 1839 | 634 | 1.16593 | Model Group:31_2A DK L:1869640 | 598
1869659 | 02 tweede verdieping | 1987 | 770 | 0 | BI draai-val rechts | 02 tweede verdieping | 1.37017 | 1919 | 1975 | 0.354824 | 0.00274033 | 714 | 1869651 | 8 | 0 | 1839 | 634 | 1.16593 | Model Group:31_2A DK L:1869657 | 601
1869676 | 02 tweede verdieping | 1987 | 770 | 0 | BI draai-val rechts | 02 tweede verdieping | 1.37017 | 1919 | 1975 | 0.354824 | 0.00274033 | 714 | 1869668 | 8 | 0 | 1839 | 634 | 1.16593 | Model Group:31_2A DK L:1869674 | 604
1869693 | 02 tweede verdieping | 1987 | 770 | 0 | BI draai-val rechts | 02 tweede verdieping | 1.37017 | 1919 | 1975 | 0.354824 | 0.00274033 | 714 | 1869685 | 8 | 0 | 1839 | 634 | 1.16593 | Model Group:31_2A DK L:1869691 | 607
1869710 | 02 tweede verdieping | 1987 | 770 | 0 | BI draai-val rechts | 02 tweede verdieping | 1.37017 | 1919 | 1975 | 0.354824 | 0.00274033 | 714 | 1869702 | 8 | 0 | 1839 | 634 | 1.16593 | Model Group:31_2A DK L:1869708 | 610
1869729 | 02 tweede verdieping | 1987 | 770 | 0 | BI draai-val rechts | 02 tweede verdieping | 1.37017 | 1919 | 1975 | 0.354824 | 0.00274033 | 714 | 1869721 | 8 | 0 | 1839 | 634 | 1.16593 | Model Group:31_2A DK L:1869727 | 613
1869746 | 02 tweede verdieping | 1987 | 770 | 0 | BI draai-val rechts | 02 tweede verdieping | 1.37017 | 1919 | 1975 | 0.354824 | 0.00274033 | 714 | 1869738 | 8 | 0 | 1839 | 634 | 1.16593 | Model Group:31_2A DK L:1869744 | 616
1869763 | 02 tweede verdieping | 1987 | 770 | 0 | BI draai-val links | 02 tweede verdieping | 1.37017 | 1919 | 1975 | 0.354824 | 0.00274033 | 714 | 1869755 | 8 | 0 | 1839 | 634 | 1.16593 | Model Group:31_2A DK R:1869761 | 619
1869780 | 02 tweede verdieping | 1987 | 770 | 0 | BI draai-val links | 02 tweede verdieping | 1.37017 | 1919 | 1975 | 0.354824 | 0.00274033 | 714 | 1869772 | 8 | 0 | 1839 | 634 | 1.16593 | Model Group:31_2A DK R:1869778 | 622
1869799 | 02 tweede verdieping | 1987 | 770 | 0 | BI draai-val links | 02 tweede verdieping | 1.37017 | 1919 | 1975 | 0.354824 | 0.00274033 | 714 | 1869791 | 8 | 0 | 1839 | 634 | 1.16593 | Model Group:31_2A DK R:1869797 | 625
1869816 | 02 tweede verdieping | 1987 | 770 | 0 | BI draai-val links | 02 tweede verdieping | 1.37017 | 1919 | 1975 | 0.354824 | 0.00274033 | 714 | 1869808 | 8 | 0 | 1839 | 634 | 1.16593 | Model Group:31_2A DK R:1869814 | 628
1869833 | 02 tweede verdieping | 1987 | 770 | 0 | BI draai-val links | 02 tweede verdieping | 1.37017 | 1919 | 1975 | 0.354824 | 0.00274033 | 714 | 1869825 | 8 | 0 | 1839 | 634 | 1.16593 | Model Group:31_2A DK R:1869831 | 631
1869850 | 02 tweede verdieping | 1987 | 770 | 0 | BI draai-val links | 02 tweede verdieping | 1.37017 | 1919 | 1975 | 0.354824 | 0.00274033 | 714 | 1869842 | 8 | 0 | 1839 | 634 | 1.16593 | Model Group:31_2A DK R:1869848 | 634
1897633 | 00 begane grond | 2365 | 820 | 0 | BI val | 00 begane grond | 1.75491 | 2297 | 2353 | 0.413032 | 0.00350982 | 764 | 1897632 | 8 | 0 | 2217 | 684 | 1.51643 | Model Group:BU-07 b900 (members excluded):1300686 | 433
1897647 | 00 begane grond | 2365 | 820 | 0 | BI val | 00 begane grond | 1.75491 | 2297 | 2353 | 0.413032 | 0.00350982 | 764 | 1897646 | 8 | 0 | 2217 | 684 | 1.51643 | Model Group:BU-07 b900 (members excluded):1818605 | 464
1898040 | 01 eerste verdieping | 1952 | 393 | 0 | BI draai-val links | 01 eerste verdieping | 0.634908 | 1884 | 1940 | 0.298792 | 0.00126982 | 337 | 1898039 | 8 | 0 | 1804 | 257 | 0.463628 | Model Group:31_1A DKD R:1898045 | 298
2012534 | 01 eerste verdieping | 1952 | 393 | 0 | BI draai-val rechts | 01 eerste verdieping | 0.634908 | 1884 | 1940 | 0.298792 | 0.00126982 | 337 | 2012525 | 8 | 0 | 1804 | 257 | 0.463628 | Model Group:31_1A DKD L:2012531 | 649
2012564 | 01 eerste verdieping | 1952 | 393 | 0 | BI draai-val rechts | 01 eerste verdieping | 0.634908 | 1884 | 1940 | 0.298792 | 0.00126982 | 337 | 2012555 | 8 | 0 | 1804 | 257 | 0.463628 | Model Group:31_1A DKD L:2012561 | 655
2012571 | 01 eerste verdieping | 1902 | 393 | 0 | BI draai-val links | 01 eerste verdieping | 0.618058 | 1834 | 1890 | 0.291992 | 0.00123612 | 337 | 2012570 | 8 | 0 | 1754 | 257 | 0.450778 | Model Group:BU-38:2702101 | 658
2182230 | 03 derde verdieping | 932 | 1425.5 | 1 | BU uitzet | 03 derde verdieping | 1.18325 | 864 | 920 | 0.300492 | 0.0023665 | 1369.5 | 2182229 | 1 | 2 | 784 | 1289.5 | 1.01097 | Model Group:daklicht A1:2182252
2194548 | 03 derde verdieping | 932 | 1454.5 | 1 | BU uitzet | 03 derde verdieping | 1.2083 | 864 | 920 | 0.304436 | 0.00241661 | 1398.5 | 2182229 | 1 | 2 | 784 | 1318.5 | 1.0337 | Model Group:daklicht A1:2182252
2194543 | 03 derde verdieping | 932 | 1454.5 | 1 | BU uitzet | 03 derde verdieping | 1.2083 | 864 | 920 | 0.304436 | 0.00241661 | 1398.5 | 2182229 | 1 | 2 | 784 | 1318.5 | 1.0337 | Model Group:daklicht A1:2182252
2194555 | 03 derde verdieping | 932 | 1425.5 | 1 | BU uitzet | 03 derde verdieping | 1.18325 | 864 | 920 | 0.300492 | 0.0023665 | 1369.5 | 2182229 | 1 | 2 | 784 | 1289.5 | 1.01097 | Model Group:daklicht A1:2182252
2182283 | 03 derde verdieping | 932 | 1425.5 | 1 | BU uitzet | 03 derde verdieping | 1.18325 | 864 | 920 | 0.300492 | 0.0023665 | 1369.5 | 2182282 | 1 | 2 | 784 | 1289.5 | 1.01097 | Model Group:daklicht A1 (members excluded):2182288
2194591 | 03 derde verdieping | 932 | 1454.5 | 1 | BU uitzet | 03 derde verdieping | 1.2083 | 864 | 920 | 0.304436 | 0.00241661 | 1398.5 | 2182282 | 1 | 2 | 784 | 1318.5 | 1.0337 | Model Group:daklicht A1 (members excluded):2182288
2194586 | 03 derde verdieping | 932 | 1454.5 | 1 | BU uitzet | 03 derde verdieping | 1.2083 | 864 | 920 | 0.304436 | 0.00241661 | 1398.5 | 2182282 | 1 | 2 | 784 | 1318.5 | 1.0337 | Model Group:daklicht A1 (members excluded):2182288
2194596 | 03 derde verdieping | 932 | 1425.5 | 1 | BU uitzet | 03 derde verdieping | 1.18325 | 864 | 920 | 0.300492 | 0.0023665 | 1369.5 | 2182282 | 1 | 2 | 784 | 1289.5 | 1.01097 | Model Group:daklicht A1 (members excluded):2182288
2182303 | 03 derde verdieping | 932 | 1455.25 | 1 | BU uitzet | 03 derde verdieping | 1.20895 | 864 | 920 | 0.304538 | 0.0024179 | 1399.25 | 2182302 | 1 | 2 | 784 | 1319.25 | 1.03429 | Model Group:31_daklicht_B (members excluded):2194619
2194891 | 03 derde verdieping | 932 | 1484.25 | 1 | BU uitzet | 03 derde verdieping | 1.23401 | 864 | 920 | 0.308482 | 0.00246802 | 1428.25 | 2182302 | 1 | 2 | 784 | 1348.25 | 1.05703 | Model Group:31_daklicht_B (members excluded):2194619
2194880 | 03 derde verdieping | 932 | 1484.25 | 1 | BU uitzet | 03 derde verdieping | 1.23401 | 864 | 920 | 0.308482 | 0.00246802 | 1428.25 | 2182302 | 1 | 2 | 784 | 1348.25 | 1.05703 | Model Group:31_daklicht_B (members excluded):2194619
2194902 | 03 derde verdieping | 932 | 1455.25 | 1 | BU uitzet | 03 derde verdieping | 1.20895 | 864 | 920 | 0.304538 | 0.0024179 | 1399.25 | 2182302 | 1 | 2 | 784 | 1319.25 | 1.03429 | Model Group:31_daklicht_B (members excluded):2194619
2194630 | 03 derde verdieping | 932 | 1409.62 | 1 | BU uitzet | 03 derde verdieping | 1.16953 | 864 | 920 | 0.298333 | 0.00233906 | 1353.62 | 2194629 | 1 | 2 | 784 | 1273.62 | 0.998522 | Model Group:31_daklicht_C:2194635
2195059 | 03 derde verdieping | 932 | 1438.62 | 1 | BU uitzet | 03 derde verdieping | 1.19459 | 864 | 920 | 0.302277 | 0.00238918 | 1382.62 | 2194629 | 1 | 2 | 784 | 1302.62 | 1.02126 | Model Group:31_daklicht_C:2194635
2195049 | 03 derde verdieping | 932 | 1438.62 | 1 | BU uitzet | 03 derde verdieping | 1.19459 | 864 | 920 | 0.302277 | 0.00238918 | 1382.62 | 2194629 | 1 | 2 | 784 | 1302.62 | 1.02126 | Model Group:31_daklicht_C:2194635
2195070 | 03 derde verdieping | 932 | 1409.62 | 1 | BU uitzet | 03 derde verdieping | 1.16953 | 864 | 920 | 0.298333 | 0.00233906 | 1353.62 | 2194629 | 1 | 2 | 784 | 1273.62 | 0.998522 | Model Group:31_daklicht_C:2194635
2194777 | 03 derde verdieping | 932 | 1455.25 | 1 | BU uitzet | 03 derde verdieping | 1.20895 | 864 | 920 | 0.304538 | 0.0024179 | 1399.25 | 2194776 | 1 | 2 | 784 | 1319.25 | 1.03429 | Model Group:31_daklicht_B:2194786
2194976 | 03 derde verdieping | 932 | 1484.25 | 1 | BU uitzet | 03 derde verdieping | 1.23401 | 864 | 920 | 0.308482 | 0.00246802 | 1428.25 | 2194776 | 1 | 2 | 784 | 1348.25 | 1.05703 | Model Group:31_daklicht_B:2194786
2194971 | 03 derde verdieping | 932 | 1484.25 | 1 | BU uitzet | 03 derde verdieping | 1.23401 | 864 | 920 | 0.308482 | 0.00246802 | 1428.25 | 2194776 | 1 | 2 | 784 | 1348.25 | 1.05703 | Model Group:31_daklicht_B:2194786
2194981 | 03 derde verdieping | 932 | 1455.25 | 1 | BU uitzet | 03 derde verdieping | 1.20895 | 864 | 920 | 0.304538 | 0.0024179 | 1399.25 | 2194776 | 1 | 2 | 784 | 1319.25 | 1.03429 | Model Group:31_daklicht_B:2194786
2194788 | 03 derde verdieping | 932 | 1409.62 | 1 | BU uitzet | 03 derde verdieping | 1.16953 | 864 | 920 | 0.298333 | 0.00233906 | 1353.62 | 2194787 | 1 | 2 | 784 | 1273.62 | 0.998522 | Model Group:31_daklicht_C:2194793
2195098 | 03 derde verdieping | 932 | 1438.62 | 1 | BU uitzet | 03 derde verdieping | 1.19459 | 864 | 920 | 0.302277 | 0.00238918 | 1382.62 | 2194787 | 1 | 2 | 784 | 1302.62 | 1.02126 | Model Group:31_daklicht_C:2194793
2195093 | 03 derde verdieping | 932 | 1438.62 | 1 | BU uitzet | 03 derde verdieping | 1.19459 | 864 | 920 | 0.302277 | 0.00238918 | 1382.62 | 2194787 | 1 | 2 | 784 | 1302.62 | 1.02126 | Model Group:31_daklicht_C:2194793
2195103 | 03 derde verdieping | 932 | 1409.62 | 1 | BU uitzet | 03 derde verdieping | 1.16953 | 864 | 920 | 0.298333 | 0.00233906 | 1353.62 | 2194787 | 1 | 2 | 784 | 1273.62 | 0.998522 | Model Group:31_daklicht_C:2194793
2266686 | 01 eerste verdieping | 1952 | 1276 | 0 | BI draai-val links | 01 eerste verdieping | 2.29848 | 1884 | 1940 | 0.41888 | 0.00459696 | 1220 | 2266685 | 8 | 0 | 1804 | 1140 | 2.05656 | Model Group:31_1A DK L:2266691 | 288
2266694 | 01 eerste verdieping | 1952 | 393 | 0 | BI draai-val rechts | 01 eerste verdieping | 0.634908 | 1884 | 1940 | 0.298792 | 0.00126982 | 337 | 2266685 | 8 | 0 | 1804 | 257 | 0.463628 | Model Group:31_1A DK L:2266691 | 289
2266710 | 02 tweede verdieping | 1987 | 770 | 0 | BI draai-val rechts | 02 tweede verdieping | 1.37017 | 1919 | 1975 | 0.354824 | 0.00274033 | 714 | 2266702 | 8 | 0 | 1839 | 634 | 1.16593 | Model Group:31_2A DK L:2266708 | 336
2266725 | 02 tweede verdieping | 1987 | 770 | 0 | BI draai-val links | 02 tweede verdieping | 1.37017 | 1919 | 1975 | 0.354824 | 0.00274033 | 714 | 2266717 | 8 | 0 | 1839 | 634 | 1.16593 | Model Group:31_2A DK R:2266723 | 351
2649835 | 00 begane grond | 2365 | 956 | 0 | BI val | 00 begane grond | 2.0673 | 2297 | 2353 | 0.431528 | 0.0041346 | 900 | 2649834 | 8 | 0 | 2217 | 820 | 1.81794 | Model Group:BU-47 b4200:1822720 | 416
2652545 | 00 begane grond | 2365 | 956 | 0 | BI val | 00 begane grond | 2.0673 | 2297 | 2353 | 0.431528 | 0.0041346 | 900 | 2652544 | 8 | 0 | 2217 | 820 | 1.81794 | Model Group:BU-11 b3000:1502212 | 465
2652631 | 00 begane grond | 2365 | 956 | 0 | BI val | 00 begane grond | 2.0673 | 2297 | 2353 | 0.431528 | 0.0041346 | 900 | 2652630 | 8 | 0 | 2217 | 820 | 1.81794 | Model Group:BU-11 b3000:1502763 | 646
3016884 | 00 begane grond | 2365 | 589 | 0 | BI val | 00 begane grond | 1.2243 | 2297 | 2353 | 0.381616 | 0.0024486 | 533 | 3016883 | 8 | 0 | 2217 | 453 | 1.0043 |  | 706
3058231 | 01 eerste verdieping | 1952 | 393 | 0 | BI draai-val links | 01 eerste verdieping | 0.634908 | 1884 | 1940 | 0.298792 | 0.00126982 | 337 | 3058230 | 8 | 0 | 1804 | 257 | 0.463628 | Model Group:31_1A DKD R:3058236 | 707
3451931 | 00 begane grond | 1950 | 820 | 0 | BI val | 00 begane grond | 1.43785 | 1882 | 1938 | 0.356592 | 0.0028757 | 764 | 3451930 | 8 | 0 | 1802 | 684 | 1.23257 | Model Group:BU-45 b900:2546304 | 712

# IfcWindow: BI deur links BDG:BI deur links (29)
Type - ParameterTakesPrecedence: no; Sizeable: no; Material: <Unnamed>
Type - Analytical Properties - Define Thermal Properties by: Schematic Type; Analytic Construction: <None>
Type - Constraints - Default Elevation: 1219.2 mm
Type - Graphics - Elevation Symbol: yes; FloorPlan Symbol: yes
Type - Identity Data - Description: binnendraaiende deur links; Manufacturer: ITANNEX; Model: 01-05-2018; Type Comments: draarichting; Type Mark: 59; Type Name: BI deur links; URL: www.bimvoorfabrikanten.nl; Workset: Family : Windows : BI deur links BDG
Type - Other - Category: Windows; Family Name: BI deur links BDG
Phasing - Phase Created: 2. nieuwbouw
Dimensions - Rough Width: 0 mm; Rough Height: 0 mm
Other - Family: BI deur links BDG; Family and Type: BI deur links BDG: BI deur links; Type: BI deur links; Type Id: 835080
Name (BI deur links BDG:BI deur links:...) | In | OverallHeight (mm) = Height (mm) | OverallWidth (mm) = Width (mm) | Level | Offset from Host (mm) | Work Plane | Thickness (mm) | Workset | Mark | Group
1511186 | 00 begane grond | 2000 | 850 | 00 begane grond | 150 | Level : 00 begane grond | 40 | Workset1 | 384 | Constraints - Schedule Level: 00 begane grond
1511555 | 00 begane grond | 2000 | 850 | 00 begane grond | 150 | Level : 00 begane grond | 40 | Workset1 | 386 | Constraints - Schedule Level: 00 begane grond
1511564 | 00 begane grond | 2000 | 850 | 00 begane grond | 150 | Level : 00 begane grond | 40 | Workset1 | 388 | Constraints - Schedule Level: 00 begane grond
1511983 | 01 eerste verdieping | 2000 | 850 | 01 eerste verdieping | 150 | Level : 01 eerste verdieping | 40 | Workset1 | 389 | Constraints - Schedule Level: 01 eerste verdieping
1512325 | 01 eerste verdieping | 2000 | 850 | 01 eerste verdieping | 150 | Level : 01 eerste verdieping | 40 | Workset1 | 392 | Constraints - Schedule Level: 01 eerste verdieping
1514307 | 01 eerste verdieping | 2000 | 850 | 01 eerste verdieping | 150 | Level : 01 eerste verdieping | 40 | Workset1 | 394 | Constraints - Schedule Level: 01 eerste verdieping
1516897 | 02 tweede verdieping | 2000 | 800 | 02 tweede verdieping | 150 | Level : 02 tweede verdieping | 40 | Workset1 | 398 | Constraints - Schedule Level: 02 tweede verdieping
1518592 | 02 tweede verdieping | 2000 | 800 | 02 tweede verdieping | 150 | Level : 02 tweede verdieping | 40 | Workset1 | 399 | Constraints - Schedule Level: 02 tweede verdieping
1518835 | 02 tweede verdieping | 2000 | 800 | 02 tweede verdieping | 150 | Level : 02 tweede verdieping | 40 | Workset1 | 401 | Constraints - Schedule Level: 02 tweede verdieping
1730461 | 01 eerste verdieping | 2463 | 937 | 01 eerste verdieping | 40 |  | 40 | Workset1 | 408 | Model Group:BI-22 1965x2550:2532537 | Constraints - Moves With Nearby Elements: no; Host: Curtain Wall : 32_ontwerpkozijn binnen 125*67
1732149 | 02 tweede verdieping | 2300 | 916 | 02 tweede verdieping | 40 |  | 40 | Workset1 | 412 | Model Group:BI-28:2534707 | Constraints - Moves With Nearby Elements: no; Host: Curtain Wall : 32_ontwerpkozijn binnen 125*67
1822163 | 00 begane grond | 2353 | 956 | 00 begane grond | -17 |  | 72 | Workset1 | 334 | Model Group:BU-10 b1800:1822150 | Constraints - Moves With Nearby Elements: no; Host: Curtain Wall : NLRS_21_CW_Ontwerpkozijn_aluminium_RT72
1939781 | 00 begane grond | 2322.5 | 864.5 | 00 begane grond | 40 |  | 50 | Workset1 | 279 | Model Group:BI-13bw 7515x2800:2527306 | Constraints - Moves With Nearby Elements: no; Host: Curtain Wall : 32_BDG_Jansen Economy 50
2080511 | 01 eerste verdieping | 2300 | 900 | 01 eerste verdieping | 40 |  | 40 | Workset1 | 523 | Model Group:BI-23w 4635x2800:2532690 | Constraints - Moves With Nearby Elements: no; Host: Curtain Wall : 32_ontwerpkozijn binnen 125*67
2140985 | 00 begane grond | 2320 | 900 | 00 begane grond | 0 |  | 40 | Workset1 | 542 | Model Group:BI-16y 1334x2387:2530506 | Constraints - Moves With Nearby Elements: no; Host: Curtain Wall : 32_ontwerpkozijn binnen 125*67
2181735 | 01 eerste verdieping | 2540 | 1400 | 01 eerste verdieping | 80 | <not associated> | 40 | Workset1 | 652 | Constraints - Schedule Level: 01 eerste verdieping
2691648 | 02 tweede verdieping | 2302.5 | 927.337 | 02 tweede verdieping | 3 |  | 50 | Workset1 | 696 | Model Group:BI-29bw 60min:1476114 | Constraints - Moves With Nearby Elements: no; Host: Curtain Wall : 32_BDG_Jansen Economy 50
2757106 | 01 eerste verdieping | 2510 | 937.5 | 01 eerste verdieping | -28 |  | 40 | Workset1 | 638 | Constraints - Moves With Nearby Elements: no; Host: Curtain Wall : 20_opening
2765843 | 01 eerste verdieping | 2510 | 937.5 | 01 eerste verdieping | -28 |  | 40 | Workset1 | 686 | Constraints - Moves With Nearby Elements: no; Host: Curtain Wall : 20_opening
4159337 | 00 begane grond | 2200 | 1078.5 |  | -60 | <not associated> | 60 | BDG_fietsenstalling | 912 | Model Group:enkele deur-kokers:4158256
4159490 | 00 begane grond | 2200 | 1078.5 |  | -60 | <not associated> | 60 | BDG_fietsenstalling | 879 | Model Group:enkele deur-kokers:4158221
4159494 | 00 begane grond | 2200 | 1078.5 |  | -60 | <not associated> | 60 | BDG_fietsenstalling | 880 | Model Group:enkele deur-kokers:4158445
4159498 | 00 begane grond | 2200 | 1078.5 |  | -60 | <not associated> | 60 | BDG_fietsenstalling | 881 | Model Group:enkele deur-kokers:4158457
4159510 | 00 begane grond | 2200 | 1078.5 |  | -60 | <not associated> | 60 | BDG_fietsenstalling | 882 | Model Group:enkele deur-kokers:4158497
4159514 | 00 begane grond | 2200 | 1078.5 |  | -60 | <not associated> | 60 | BDG_fietsenstalling | 883 | Model Group:enkele deur-kokers:4158509
4159518 | 00 begane grond | 2200 | 1078.5 |  | -40 | <not associated> | 60 | BDG_fietsenstalling | 884 | Model Group:enkele deur-kokers:4158523
4159522 | 00 begane grond | 2200 | 1078.5 |  | -60 | <not associated> | 60 | BDG_fietsenstalling | 885 | Model Group:enkele deur-kokers:4158535
4159526 | 00 begane grond | 2200 | 1078.5 |  | -60 | <not associated> | 60 | BDG_fietsenstalling | 886 | Model Group:enkele deur-kokers:4158549
4159530 | 00 begane grond | 2200 | 1078.5 |  | -60 | <not associated> | 60 | BDG_fietsenstalling | 887 | Model Group:enkele deur-kokers:4158561

# IfcWindow: BI deur rechts BDG:BI deur rechts (17)
Type - ParameterTakesPrecedence: no; Sizeable: no; Material: <Unnamed>
Type - Analytical Properties - Define Thermal Properties by: Schematic Type; Analytic Construction: <None>
Type - Constraints - Default Elevation: 1219.2 mm
Type - Graphics - Elevation Symbol: yes; FloorPlan Symbol: yes
Type - Identity Data - Description: binnendraaiende deur rechts; Manufacturer: ITANNEX; Model: 01-05-2018; Type Comments: draarichting; Type Mark: 60; Type Name: BI deur rechts; URL: www.bimvoorfabrikanten.nl; Workset: Family : Windows : BI deur rechts BDG
Type - Other - Category: Windows; Family Name: BI deur rechts BDG
Phasing - Phase Created: 2. nieuwbouw
Dimensions - Rough Width: 0 mm; Rough Height: 0 mm
Identity Data - Workset: Workset1
Other - Family: BI deur rechts BDG; Family and Type: BI deur rechts BDG: BI deur rechts; Type: BI deur rechts; Type Id: 835081
Name (BI deur rechts BDG:BI deur rechts:...) | In | OverallHeight (mm) = Height (mm) | OverallWidth (mm) = Width (mm) | Level | Schedule Level | Offset from Host (mm) | Work Plane | Thickness (mm) | Mark
1511185 | 00 begane grond | 2000 | 850 | 00 begane grond | 00 begane grond | 150 | Level : 00 begane grond | 40 | 383
1511554 | 00 begane grond | 2000 | 850 | 00 begane grond | 00 begane grond | 150 | Level : 00 begane grond | 40 | 385
1511563 | 00 begane grond | 2000 | 850 | 00 begane grond | 00 begane grond | 150 | Level : 00 begane grond | 40 | 387
1512232 | 01 eerste verdieping | 2000 | 850 | 01 eerste verdieping | 01 eerste verdieping | 150 | Level : 01 eerste verdieping | 40 | 390
1512298 | 01 eerste verdieping | 2000 | 850 | 01 eerste verdieping | 01 eerste verdieping | 150 | Level : 01 eerste verdieping | 40 | 391
1514306 | 01 eerste verdieping | 2000 | 850 | 01 eerste verdieping | 01 eerste verdieping | 150 | Level : 01 eerste verdieping | 40 | 393
1514353 | 01 eerste verdieping | 2000 | 850 | 01 eerste verdieping | 01 eerste verdieping | 150 | Level : 01 eerste verdieping | 40 | 395
1516651 | 02 tweede verdieping | 2000 | 800 | 02 tweede verdieping | 02 tweede verdieping | 150 | Level : 02 tweede verdieping | 40 | 396
1516866 | 02 tweede verdieping | 2000 | 800 | 02 tweede verdieping | 02 tweede verdieping | 150 | Level : 02 tweede verdieping | 40 | 397
1518892 | 02 tweede verdieping | 2000 | 800 | 02 tweede verdieping | 02 tweede verdieping | 150 | Level : 02 tweede verdieping | 40 | 402
1729488 | 02 tweede verdieping | 2300 | 916 | 02 tweede verdieping |  | 40 |  | 40 | 406 | Constraints - Moves With Nearby Elements: no; Host: Curtain Wall : 32_ontwerpkozijn binnen 125*67; Group: Model Group:BI-28:2534707
1730480 | 01 eerste verdieping | 2463 | 937 | 01 eerste verdieping |  | 40 |  | 40 | 410 | Constraints - Moves With Nearby Elements: no; Host: Curtain Wall : 32_ontwerpkozijn binnen 125*67; Group: Model Group:BI-22 1965x2550:2532537
2140989 | 00 begane grond | 2320 | 300 | 00 begane grond |  | 0 |  | 40 | 543 | Constraints - Moves With Nearby Elements: no; Host: Curtain Wall : 32_ontwerpkozijn binnen 125*67; Group: Model Group:BI-16y 1334x2387:2530506
2649852 | 00 begane grond | 2353 | 956 | 00 begane grond |  | 3 |  | 72 | 553 | Constraints - Moves With Nearby Elements: no; Host: Curtain Wall : NLRS_21_CW_Ontwerpkozijn_aluminium_RT72; Group: Model Group:BU-47 b4200:1822720
2691604 | 02 tweede verdieping | 2302.5 | 919.963 | 02 tweede verdieping |  | 3 |  | 50 | 694 | Constraints - Moves With Nearby Elements: no; Host: Curtain Wall : 32_BDG_Jansen Economy 50; Group: Model Group:BI-29bw 60min:1476114
2757125 | 01 eerste verdieping | 2510 | 937.5 | 01 eerste verdieping |  | -28 |  | 40 | 666 | Constraints - Moves With Nearby Elements: no; Host: Curtain Wall : 20_opening
2765845 | 01 eerste verdieping | 2510 | 727.5 | 01 eerste verdieping |  | -28 |  | 40 | 688 | Constraints - Moves With Nearby Elements: no; Host: Curtain Wall : 20_opening

# IfcWindow: BI draai-val links:BI draai-val links (34)
Type - ParameterTakesPrecedence: no; Sizeable: no; Material: <Unnamed>
Type - Analytical Properties - Define Thermal Properties by: Schematic Type; Analytic Construction: <None>
Type - Constraints - Default Elevation: 1219.2 mm
Type - Graphics - Elevation Symbol: yes; FloorPlan Symbol: yes
Type - Identity Data - Description: draai-val links; Manufacturer: ITANNEX; Model: 01-05-2018; Type Comments: draarichting; Type Mark: 61; Type Name: BI draai-val links; URL: www.bimvoorfabrikanten.nl; Workset: Family : Windows : BI draai-val links
Type - Other - Category: Windows; Family Name: BI draai-val links
Constraints - Moves With Nearby Elements: no; Host: Curtain Wall : NLRS_21_CW_Ontwerpkozijn_aluminium_RT72; Offset from Host: -28 mm
Phasing - Phase Created: 2. nieuwbouw
Dimensions - Rough Width: 0 mm; Rough Height: 0 mm; Thickness: 72 mm
Identity Data - Workset: Workset1
Other - Family: BI draai-val links; Family and Type: BI draai-val links: BI draai-val links; Type: BI draai-val links; Type Id: 835082
Name (BI draai-val links:BI draai-val links:...) | In | OverallHeight (mm) = Height (mm) | OverallWidth (mm) = Width (mm) | Level | Mark | Group
1864739 | 01 eerste verdieping | 1940 | 393 | 01 eerste verdieping | 474 | Model Group:31_1A DK R:875055
1864945 | 01 eerste verdieping | 1940 | 393 | 01 eerste verdieping | 480 | Model Group:31_1A DK R:1864938
1865014 | 01 eerste verdieping | 1940 | 393 | 01 eerste verdieping | 495 | Model Group:31_1A DK R:1865007
1865156 | 01 eerste verdieping | 1940 | 393 | 01 eerste verdieping | 502 | Model Group:31_1A DKD R:875310
1865244 | 01 eerste verdieping | 1940 | 496 | 01 eerste verdieping | 504 | Model Group:BU-30:2700215
1865353 | 01 eerste verdieping | 1940 | 393 | 01 eerste verdieping | 507 | Model Group:31_1A DKD R:1865346
1865374 | 01 eerste verdieping | 1940 | 1276 | 01 eerste verdieping | 511 | Model Group:31_1A DK L:1865367
1865581 | 01 eerste verdieping | 1940 | 393 | 01 eerste verdieping | 488 | Model Group:31_1A DKD R:1865574
1865615 | 01 eerste verdieping | 1940 | 393 | 01 eerste verdieping | 519 | Model Group:31_1A DKD R:1865608
1865662 | 01 eerste verdieping | 1940 | 1276 | 01 eerste verdieping | 529 | Model Group:31_1A DK L:1865655
1865681 | 01 eerste verdieping | 1940 | 1276 | 01 eerste verdieping | 535 | Model Group:31_1A DK L:1865674
1865788 | 01 eerste verdieping | 1940 | 393 | 01 eerste verdieping | 555 | Model Group:31_1A DKD R:1865781
1865809 | 01 eerste verdieping | 1940 | 1276 | 01 eerste verdieping | 559 | Model Group:31_1A DK L:1865802
1865930 | 01 eerste verdieping | 1940 | 393 | 01 eerste verdieping | 565 | Model Group:31_1A DK R:1865923
1866089 | 01 eerste verdieping | 1940 | 1276 | 01 eerste verdieping | 516 | Model Group:31_1A DKg R:1866082
1869239 | 02 tweede verdieping | 1975 | 770 | 02 tweede verdieping | 484 | Model Group:31_2A DK R:1867677
1869354 | 02 tweede verdieping | 1975 | 770 | 02 tweede verdieping | 539 | Model Group:31_2A DK R:1869345
1869371 | 02 tweede verdieping | 1975 | 770 | 02 tweede verdieping | 572 | Model Group:31_2A DK R:1869362
1869388 | 02 tweede verdieping | 1975 | 770 | 02 tweede verdieping | 575 | Model Group:31_2A DK R:1869379
1869405 | 02 tweede verdieping | 1975 | 770 | 02 tweede verdieping | 578 | Model Group:31_2A DK R:1869396
1869422 | 02 tweede verdieping | 1975 | 770 | 02 tweede verdieping | 581 | Model Group:31_2A DK R:1869413
1869439 | 02 tweede verdieping | 1975 | 770 | 02 tweede verdieping | 584 | Model Group:31_2A DK R:1869430
1869456 | 02 tweede verdieping | 1975 | 770 | 02 tweede verdieping | 587 | Model Group:31_2A DK R:1869447
1869769 | 02 tweede verdieping | 1975 | 770 | 02 tweede verdieping | 620 | Model Group:31_2A DK R:1869761
1869786 | 02 tweede verdieping | 1975 | 770 | 02 tweede verdieping | 623 | Model Group:31_2A DK R:1869778
1869805 | 02 tweede verdieping | 1975 | 770 | 02 tweede verdieping | 626 | Model Group:31_2A DK R:1869797
1869822 | 02 tweede verdieping | 1975 | 770 | 02 tweede verdieping | 629 | Model Group:31_2A DK R:1869814
1869839 | 02 tweede verdieping | 1975 | 770 | 02 tweede verdieping | 632 | Model Group:31_2A DK R:1869831
1869856 | 02 tweede verdieping | 1975 | 770 | 02 tweede verdieping | 635 | Model Group:31_2A DK R:1869848
1898052 | 01 eerste verdieping | 1940 | 393 | 01 eerste verdieping | 301 | Model Group:31_1A DKD R:1898045
2012583 | 01 eerste verdieping | 1890 | 393 | 01 eerste verdieping | 659 | Model Group:BU-38:2702101
2266698 | 01 eerste verdieping | 1940 | 1276 | 01 eerste verdieping | 303 | Model Group:31_1A DK L:2266691
2266730 | 02 tweede verdieping | 1975 | 770 | 02 tweede verdieping | 352 | Model Group:31_2A DK R:2266723
3058243 | 01 eerste verdieping | 1940 | 393 | 01 eerste verdieping | 708 | Model Group:31_1A DKD R:3058236

# IfcWindow: BI draai-val rechts:BI draai-val rechts (26)
Type - ParameterTakesPrecedence: no; Sizeable: no; Material: <Unnamed>
Type - Analytical Properties - Define Thermal Properties by: Schematic Type; Analytic Construction: <None>
Type - Constraints - Default Elevation: 1219.2 mm
Type - Graphics - Elevation Symbol: yes; FloorPlan Symbol: yes
Type - Identity Data - Description: draai-val rechts; Manufacturer: ITANNEX; Model: 01-05-2018; Type Comments: draarichting; Type Mark: 62; Type Name: BI draai-val rechts; URL: www.bimvoorfabrikanten.nl; Workset: Family : Windows : BI draai-val rechts
Type - Other - Category: Windows; Family Name: BI draai-val rechts
Constraints - Moves With Nearby Elements: no; Host: Curtain Wall : NLRS_21_CW_Ontwerpkozijn_aluminium_RT72; Offset from Host: -28 mm
Phasing - Phase Created: 2. nieuwbouw
Dimensions - Rough Width: 0 mm; Rough Height: 0 mm; Thickness: 72 mm
Identity Data - Workset: Workset1
Other - Family: BI draai-val rechts; Family and Type: BI draai-val rechts: BI draai-val rechts; Type: BI draai-val rechts; Type Id: 835083
Name (BI draai-val rechts:BI draai-val rechts:...) | In | OverallHeight (mm) = Height (mm) | OverallWidth (mm) = Width (mm) | Level | Mark | Group
1864500 | 01 eerste verdieping | 1940 | 393 | 01 eerste verdieping | 469 | Model Group:31_1A DKD L:875031
1864766 | 01 eerste verdieping | 1940 | 1276 | 01 eerste verdieping | 476 | Model Group:31_1A DK R:875055
1864947 | 01 eerste verdieping | 1940 | 1276 | 01 eerste verdieping | 482 | Model Group:31_1A DK R:1864938
1864989 | 01 eerste verdieping | 1940 | 393 | 01 eerste verdieping | 491 | Model Group:31_1A DKD L:1864982
1865016 | 01 eerste verdieping | 1940 | 1276 | 01 eerste verdieping | 497 | Model Group:31_1A DK R:1865007
1865037 | 01 eerste verdieping | 1940 | 393 | 01 eerste verdieping | 500 | Model Group:31_1A DKD L:1865030
1865376 | 01 eerste verdieping | 1940 | 393 | 01 eerste verdieping | 513 | Model Group:31_1A DK L:1865367
1865664 | 01 eerste verdieping | 1940 | 393 | 01 eerste verdieping | 531 | Model Group:31_1A DK L:1865655
1865683 | 01 eerste verdieping | 1940 | 393 | 01 eerste verdieping | 537 | Model Group:31_1A DK L:1865674
1865811 | 01 eerste verdieping | 1940 | 393 | 01 eerste verdieping | 561 | Model Group:31_1A DK L:1865802
1865932 | 01 eerste verdieping | 1940 | 1276 | 01 eerste verdieping | 567 | Model Group:31_1A DK R:1865923
1865953 | 01 eerste verdieping | 1940 | 393 | 01 eerste verdieping | 570 | Model Group:31_1A DKD L:1865946
1869475 | 02 tweede verdieping | 1975 | 770 | 02 tweede verdieping | 590 | Model Group:31_2A DK L:1869467
1869613 | 02 tweede verdieping | 1975 | 770 | 02 tweede verdieping | 593 | Model Group:31_2A DK L:1869606
1869630 | 02 tweede verdieping | 1975 | 770 | 02 tweede verdieping | 596 | Model Group:31_2A DK L:1869623
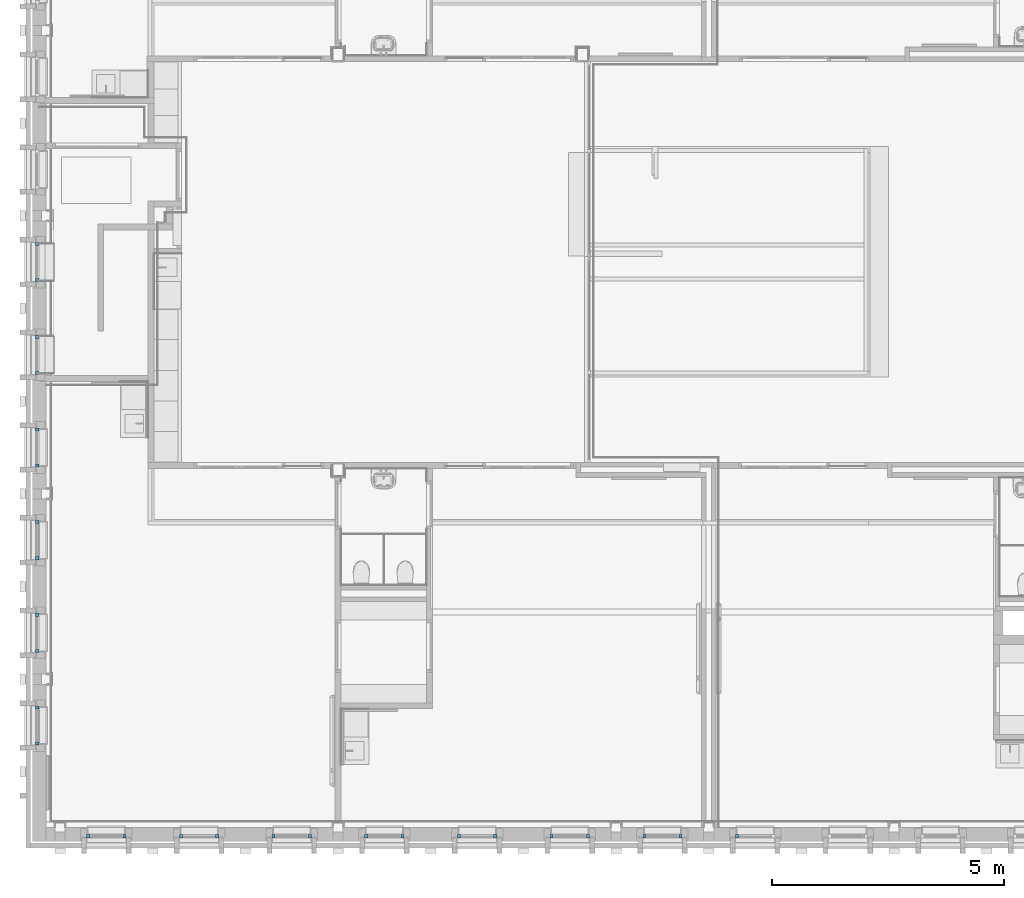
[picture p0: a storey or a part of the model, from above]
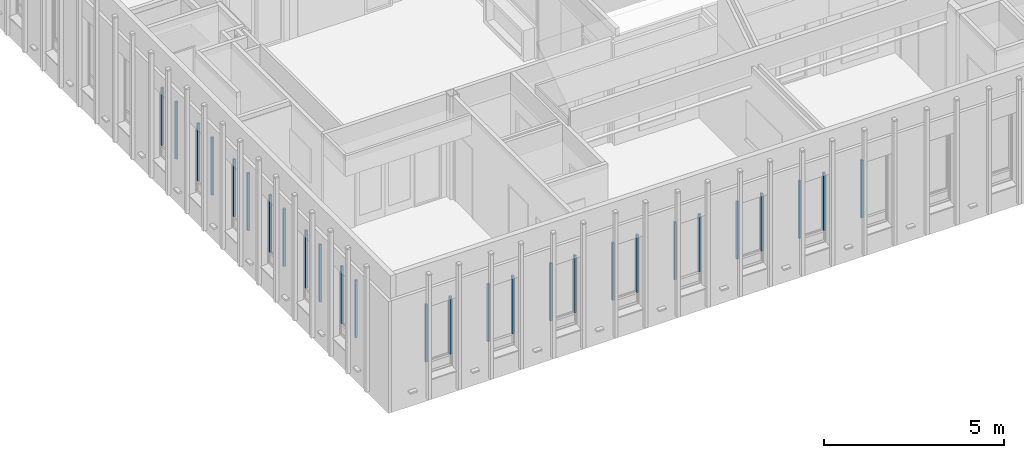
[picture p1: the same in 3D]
Properties of the parts of a building model (IFC2X3), part 93 of 94

# IfcWindow: BI draai-val rechts:BI draai-val rechts (26)
Name (BI draai-val rechts:BI draai-val rechts:...) | In | OverallHeight (mm) = Height (mm) | OverallWidth (mm) = Width (mm) | Level | Mark | Group
1869647 | 02 tweede verdieping | 1975 | 770 | 02 tweede verdieping | 599 | Model Group:31_2A DK L:1869640
1869664 | 02 tweede verdieping | 1975 | 770 | 02 tweede verdieping | 602 | Model Group:31_2A DK L:1869657
1869681 | 02 tweede verdieping | 1975 | 770 | 02 tweede verdieping | 605 | Model Group:31_2A DK L:1869674
1869698 | 02 tweede verdieping | 1975 | 770 | 02 tweede verdieping | 608 | Model Group:31_2A DK L:1869691
1869715 | 02 tweede verdieping | 1975 | 770 | 02 tweede verdieping | 611 | Model Group:31_2A DK L:1869708
1869734 | 02 tweede verdieping | 1975 | 770 | 02 tweede verdieping | 614 | Model Group:31_2A DK L:1869727
1869751 | 02 tweede verdieping | 1975 | 770 | 02 tweede verdieping | 617 | Model Group:31_2A DK L:1869744
2012538 | 01 eerste verdieping | 1940 | 393 | 01 eerste verdieping | 650 | Model Group:31_1A DKD L:2012531
2012568 | 01 eerste verdieping | 1940 | 393 | 01 eerste verdieping | 656 | Model Group:31_1A DKD L:2012561
2266700 | 01 eerste verdieping | 1940 | 393 | 01 eerste verdieping | 309 | Model Group:31_1A DK L:2266691
2266715 | 02 tweede verdieping | 1975 | 770 | 02 tweede verdieping | 349 | Model Group:31_2A DK L:2266708

# IfcWindow: BI val:BI val (22)
In: 00 begane grond
Type - ParameterTakesPrecedence: no; Sizeable: no; Material: <Unnamed>
Type - Analytical Properties - Define Thermal Properties by: Schematic Type; Analytic Construction: <None>
Type - Constraints - Default Elevation: 1219.2 mm
Type - Graphics - Elevation Symbol: yes; FloorPlan Symbol: yes
Type - Identity Data - Description: draai-val links; Manufacturer: ITANNEX; Model: 01-05-2018; Type Comments: draarichting; Type Mark: 99; Type Name: BI val; URL: www.bimvoorfabrikanten.nl; Workset: Family : Windows : BI val
Type - Other - Category: Windows; Family Name: BI val
Constraints - Level: 00 begane grond; Moves With Nearby Elements: no; Host: Curtain Wall : NLRS_21_CW_Ontwerpkozijn_aluminium_RT72; Offset from Host: -28 mm
Phasing - Phase Created: 2. nieuwbouw
Dimensions - Rough Width: 0 mm; Rough Height: 0 mm; Thickness: 72 mm
Identity Data - Workset: Workset1
Other - Family: BI val; Family and Type: BI val: BI val; Type: BI val; Type Id: 835118
Name (BI val:BI val:...) | OverallHeight (mm) = Height (mm) | OverallWidth (mm) = Width (mm) | Mark | Group
1857516 | 2353 | 956 | 445 | Model Group:BU-03 b5800:1818868
1857535 | 2353 | 956 | 447 | Model Group:BU-03 b5800:1818868
1857654 | 2353 | 820 | 449 | Model Group:BU-07 b900:894363
1857836 | 2353 | 820 | 453 | Model Group:BU-07 b900 (members excluded):1300407
1857839 | 2353 | 820 | 455 | Model Group:BU-07 b900:1502980
1857941 | 2353 | 956 | 457 | Model Group:BU-11 b3000:1220846
1859916 | 2353 | 956 | 285 | Model Group:BU-09 b1500:1220175
1861305 | 2353 | 956 | 299 | Model Group:BU-08 b2100:1220076
1862947 | 1938 | 956 | 461 | Model Group:BU-13 b3300:1862274
1863871 | 2353 | 956 | 451 | Model Group:BU-25 b3000:1493474
1869869 | 2353 | 956 | 639 | Model Group:BU-02 b4200:1494104
1897643 | 2353 | 820 | 434 | Model Group:BU-07 b900 (members excluded):1300686
1897657 | 2353 | 820 | 641 | Model Group:BU-07 b900 (members excluded):1818605
1898107 | 553 | 956 | 310 | Model Group:BU-21 b2966:1300741
1899586 | 2353 | 956 | 323 | Model Group:BU-12 b4200:1817348
1934470 | 2353 | 870 | 418 | Model Group:BU-18 b3017:2651211
2012623 | 2353 | 956 | 664 | Model Group:BU-02 b4200:1494104
2649862 | 2353 | 956 | 643 | Model Group:BU-47 b4200:1822720
2652562 | 2353 | 956 | 466 | Model Group:BU-11 b3000:1502212
2652648 | 2353 | 956 | 654 | Model Group:BU-11 b3000:1502763
3016892 | 2353 | 589 | 709
3451941 | 1938 | 820 | 713 | Model Group:BU-45 b900:2546304

# IfcWindow: BU deur links BDG:BU deur links (19)
Type - ParameterTakesPrecedence: no; Sizeable: no; Material: <Unnamed>
Type - Analytical Properties - Define Thermal Properties by: Schematic Type; Analytic Construction: <None>
Type - Constraints - Default Elevation: 1219.2 mm
Type - Graphics - Elevation Symbol: yes; FloorPlan Symbol: yes
Type - Identity Data - Description: buitendraaiend deur links; Manufacturer: ITANNEX; Model: 01-05-2018; Type Comments: draarichting; Type Mark: 54; Type Name: BU deur links; URL: www.bimvoorfabrikanten.nl; Workset: Family : Windows : BU deur links BDG
Type - Other - Category: Windows; Family Name: BU deur links BDG
Constraints - Moves With Nearby Elements: no
Phasing - Phase Created: 2. nieuwbouw
Dimensions - Rough Width: 0 mm; Rough Height: 0 mm
Identity Data - Workset: Workset1
Other - Family: BU deur links BDG; Family and Type: BU deur links BDG: BU deur links; Type: BU deur links; Type Id: 835044
Name (BU deur links BDG:BU deur links:...) | In | OverallHeight (mm) = Height (mm) | OverallWidth (mm) = Width (mm) | Offset from Host (mm) | Level | Host | Thickness (mm) | Mark | Group
877881 | 02 tweede verdieping | 2393 | 900 | 0 | 02 tweede verdieping | Curtain Wall : NLRS_21_CW_Ontwerpkozijn_aluminium_RT72 | 72 | 186 | Model Group:BU-40:2712884
1475828 | 01 eerste verdieping | 2302.5 | 919.813 | 40 | 01 eerste verdieping | Curtain Wall : 32_BDG_Jansen Economy 50 | 50 | 348 | Model Group:BI-26bw:2535201
1480267 | 00 begane grond | 2322.5 | 935.5 | 20 | 00 begane grond | Curtain Wall : 32_BDG_Jansen Economy 50 | 50 | 354 | Model Group:BI-13bw 7515x2800:2527306
1613748 | 00 begane grond | 2300 | 916 | 40 | 00 begane grond | Curtain Wall : 32_ontwerpkozijn binnen 125*67 | 40 | 366 | Model Group:BI-10 4215x2800:2522162
1817770 | 00 begane grond | 2353 | 956 | 3 | 00 begane grond | Curtain Wall : NLRS_21_CW_Ontwerpkozijn_aluminium_RT72 | 72 | 346 | Model Group:BU-12 b4200:1817348
1823334 | 00 begane grond | 2331 | 956 | 3 | 00 begane grond | Curtain Wall : NLRS_21_CW_Ontwerpkozijn_aluminium_RT72 | 72 | 422 | Model Group:BU-15 b4200:1823297
1837632 | 01 eerste verdieping | 2528 | 956 | 3 | 01 eerste verdieping | Curtain Wall : NLRS_21_CW_Ontwerpkozijn_aluminium_RT72 | 72 | 428 | Model Group:BU-32:892003
1850033 | 01 eerste verdieping | 2491 | 817.5 | 0 | 01 eerste verdieping | Curtain Wall : NLRS_21_CW_Ontwerpkozijn_aluminium_RT72 | 72 | 431 | Model Group:BU-31:891953
1856778 | 00 begane grond | 2297 | 940.75 | 0 | 00 begane grond | Curtain Wall : NLRS_21_CW_Ontwerpkozijn_aluminium_RT72 | 72 | 435 | Model Group:BU-18 b3017:2651211
1863500 | 00 begane grond | 2297 | 939 | 0 | 00 begane grond | Curtain Wall : NLRS_21_CW_Ontwerpkozijn_aluminium_RT72 | 72 | 423 | Model Group:BU-14 b3000:1494513
2691667 | 02 tweede verdieping | 2302.5 | 925 | 3 | 02 tweede verdieping | Curtain Wall : 32_BDG_Jansen Economy 50 | 50 | 698 | Model Group:BI-29bw 60min:1476114
2769528 | 01 eerste verdieping | 2510 | 900 | -28 | 01 eerste verdieping | Curtain Wall : 20_opening | 40 | 700
3003084 | 00 begane grond | 2331 | 917 | 3 | 00 begane grond | Curtain Wall : NLRS_21_CW_Ontwerpkozijn_aluminium_RT72 | 72 | 716 | Model Group:BU-01 b1500:3003067
3702036 | 00 begane grond | 2317 | 900 | 0 | 00 begane grond | Curtain Wall : NLRS_21_CW_Ontwerpkozijn_aluminium_RT72 | 72 | 752 | Model Group:BU-04 b2500:1820005
3836675 | 00 begane grond | 2373 | 960 | -28 | 00 begane grond | Curtain Wall : NLRS_21_CW_Ontwerpkozijn_aluminium_RT72 | 72 | 766 | Model Group:BU-16:3836676
3844463 | 00 begane grond | 2320 | 900 | 20 | 00 begane grond | Curtain Wall : 32_ontwerpkozijn binnen 125*67 | 40 | 796 | Model Group:BI-02 2198x2387 (members excluded):3844191
4720937 | 00 begane grond | 2010 | 930 | 20 | 00 begane grond | Floor : NLRS_43_FL_cementdekvloer 60_gen_ISR | 59.2255 | 725
4720938 | 00 begane grond | 2010 | 930 | 4020 | 00 begane grond | Floor : NLRS_43_FL_cementdekvloer 60_gen_ISR | 59.2255 | 726
4720939 | 00 begane grond | 2010 | 930 | 7820 | 00 begane grond | Floor : NLRS_43_FL_cementdekvloer 60_gen_ISR | 59.2255 | 760

# IfcWindow: BU deur rechts BDG:BU deur rechts (18)
Type - ParameterTakesPrecedence: no; Sizeable: no; Material: <Unnamed>
Type - Analytical Properties - Define Thermal Properties by: Schematic Type; Analytic Construction: <None>
Type - Constraints - Default Elevation: 1219.2 mm
Type - Graphics - Elevation Symbol: yes; FloorPlan Symbol: yes
Type - Identity Data - Description: buitendraaiend deur rechts; Manufacturer: ITANNEX; Model: 01-05-2018; Type Comments: draarichting; Type Mark: 58; Type Name: BU deur rechts; URL: www.bimvoorfabrikanten.nl; Workset: Family : Windows : BU deur rechts BDG
Type - Other - Category: Windows; Family Name: BU deur rechts BDG
Phasing - Phase Created: 2. nieuwbouw
Dimensions - Rough Width: 0 mm; Rough Height: 0 mm
Identity Data - Workset: Workset1
Other - Family: BU deur rechts BDG; Family and Type: BU deur rechts BDG: BU deur rechts; Type: BU deur rechts; Type Id: 835079
Name (BU deur rechts BDG:BU deur rechts:...) | In | OverallHeight (mm) = Height (mm) | OverallWidth (mm) = Width (mm) | Moves With Nearby Elements | Offset from Host (mm) | Level | Host | Thickness (mm) | Mark | Group
877882 | 02 tweede verdieping | 2393 | 900 | no | 0 | 02 tweede verdieping | Curtain Wall : NLRS_21_CW_Ontwerpkozijn_aluminium_RT72 | 72 | 187 | Model Group:BU-40:2712884
1475740 | 01 eerste verdieping | 2302.5 | 920 | no | 40 | 01 eerste verdieping | Curtain Wall : 32_BDG_Jansen Economy 50 | 50 | 344 | Model Group:BI-26bw:2535201
1489685 | 00 begane grond | 2353 | 956 | no | -17 | 00 begane grond | Curtain Wall : NLRS_21_CW_Ontwerpkozijn_aluminium_RT72 | 72 | 326 | Model Group:BU-22 b2700:1300414
1491249 | 00 begane grond | 2353 | 956 | no | 3 | 00 begane grond | Curtain Wall : NLRS_21_CW_Ontwerpkozijn_aluminium_RT72 | 72 | 328 | Model Group:BU-21 b2966:1300741
1492304 | 00 begane grond | 2353 | 956 | no | 3 | 00 begane grond | Curtain Wall : NLRS_21_CW_Ontwerpkozijn_aluminium_RT72 | 72 | 332 | Model Group:BU-20 b3300:1300930
1613692 | 00 begane grond | 2300 | 916 | no | 40 | 00 begane grond | Curtain Wall : 32_ontwerpkozijn binnen 125*67 | 40 | 364 | Model Group:BI-10 4215x2800:2522162
1823332 | 00 begane grond | 2331 | 956 | no | 3 | 00 begane grond | Curtain Wall : NLRS_21_CW_Ontwerpkozijn_aluminium_RT72 | 72 | 420 | Model Group:BU-15 b4200:1823297
1850034 | 01 eerste verdieping | 2491 | 817.5 | no | 0 | 01 eerste verdieping | Curtain Wall : NLRS_21_CW_Ontwerpkozijn_aluminium_RT72 | 72 | 432 | Model Group:BU-31:891953
1856779 | 00 begane grond | 2297 | 940.75 | no | 0 | 00 begane grond | Curtain Wall : NLRS_21_CW_Ontwerpkozijn_aluminium_RT72 | 72 | 436 | Model Group:BU-18 b3017:2651211
1863501 | 00 begane grond | 2297 | 939 | no | 0 | 00 begane grond | Curtain Wall : NLRS_21_CW_Ontwerpkozijn_aluminium_RT72 | 72 | 424 | Model Group:BU-14 b3000:1494513
1932998 | 00 begane grond | 2353 | 956 | no | 3 | 00 begane grond | Curtain Wall : NLRS_21_CW_Ontwerpkozijn_aluminium_RT72 | 72 | 368 | Model Group:BU-17 b3000:1900158
2411524 | 00 begane grond | 2000 | 850 |  | 0 |  |  | 40 | 682 | Constraints - Work Plane: Floor : NLRS_43_FL_cementdekvloer 60_gen_ISR
2411528 | 00 begane grond | 2000 | 850 |  | 0 |  |  | 40 | 683 | Constraints - Work Plane: Floor : NLRS_43_FL_cementdekvloer 60_gen_ISR
2691560 | 02 tweede verdieping | 2302.5 | 920 | no | 3 | 02 tweede verdieping | Curtain Wall : 32_BDG_Jansen Economy 50 | 50 | 692 | Model Group:BI-29bw 60min:1476114
3003101 | 00 begane grond | 2331 | 651 | no | 40 | 00 begane grond | Curtain Wall : NLRS_21_CW_Ontwerpkozijn_aluminium_RT72 | 72 | 718 | Model Group:BU-01 b1500:3003067
3702037 | 00 begane grond | 2317 | 900 | no | 0 | 00 begane grond | Curtain Wall : NLRS_21_CW_Ontwerpkozijn_aluminium_RT72 | 72 | 753 | Model Group:BU-04 b2500:1820005
3836674 | 00 begane grond | 2373 | 931.577 | no | -28 | 00 begane grond | Curtain Wall : NLRS_21_CW_Ontwerpkozijn_aluminium_RT72 | 72 | 765 | Model Group:BU-16:3836676
4196790 | 00 begane grond | 2373 | 1156 | no | -28 | 00 begane grond | Curtain Wall : NLRS_21_CW_Ontwerpkozijn_aluminium_RT72 | 72 | 888 | Model Group:BU-46:4200502

# IfcWindow: BU uitzet:BU uitzet (24)
In: 03 derde verdieping
Type - ParameterTakesPrecedence: no; Sizeable: no; Material: <Unnamed>
Type - Analytical Properties - Define Thermal Properties by: Schematic Type; Analytic Construction: <None>
Type - Constraints - Default Elevation: 1219.2 mm
Type - Graphics - Elevation Symbol: yes; FloorPlan Symbol: yes
Type - Identity Data - Description: uitzet; Manufacturer: ITANNEX; Model: 01-05-2018; Type Comments: draarichting; Type Mark: 104; Type Name: BU uitzet; URL: www.bimvoorfabrikanten.nl; Workset: Family : Windows : BU uitzet
Type - Other - Category: Windows; Family Name: BU uitzet
OverallHeight: 920 mm
Constraints - Moves With Nearby Elements: no; Level: 03 derde verdieping; Host: Curtain Wall : NLRS_21_CW_Ontwerpkozijn_aluminium_RT72; Offset from Host: -28 mm
Phasing - Phase Created: 2. nieuwbouw
Dimensions - Rough Width: 0 mm; Rough Height: 0 mm; Height: 920 mm; Thickness: 72 mm
Identity Data - Workset: Workset1
Other - Family: BU uitzet; Family and Type: BU uitzet: BU uitzet; Type: BU uitzet; Type Id: 3838990
Name (BU uitzet:BU uitzet:...) | OverallWidth (mm) = Width (mm) | Mark | Group
3839160 | 1455.25 | 440 | Model Group:31_daklicht_B (members excluded):2194619
3839204 | 1484.25 | 444 | Model Group:31_daklicht_B (members excluded):2194619
3839223 | 1484.25 | 544 | Model Group:31_daklicht_B (members excluded):2194619
3839250 | 1455.25 | 546 | Model Group:31_daklicht_B (members excluded):2194619
3840020 | 1455.25 | 548 | Model Group:31_daklicht_B:2194786
3840022 | 1484.25 | 550 | Model Group:31_daklicht_B:2194786
3840024 | 1484.25 | 719 | Model Group:31_daklicht_B:2194786
3840026 | 1455.25 | 721 | Model Group:31_daklicht_B:2194786
3840519 | 1409.62 | 723 | Model Group:31_daklicht_C:2194635
3840563 | 1438.62 | 728 | Model Group:31_daklicht_C:2194635
3840582 | 1438.62 | 730 | Model Group:31_daklicht_C:2194635
3840584 | 1409.62 | 732 | Model Group:31_daklicht_C:2194635
3840902 | 1409.62 | 734 | Model Group:31_daklicht_C:2194793
3840904 | 1438.62 | 736 | Model Group:31_daklicht_C:2194793
3840906 | 1438.62 | 738 | Model Group:31_daklicht_C:2194793
3840908 | 1409.62 | 740 | Model Group:31_daklicht_C:2194793
3841131 | 1425.5 | 742 | Model Group:daklicht A1 (members excluded):2182288
3841175 | 1454.5 | 744 | Model Group:daklicht A1 (members excluded):2182288
3841194 | 1454.5 | 746 | Model Group:daklicht A1 (members excluded):2182288
3841196 | 1425.5 | 748 | Model Group:daklicht A1 (members excluded):2182288
3841499 | 1425.5 | 750 | Model Group:daklicht A1:2182252
3841501 | 1454.5 | 756 | Model Group:daklicht A1:2182252
3841503 | 1454.5 | 758 | Model Group:daklicht A1:2182252
3841505 | 1425.5 | 763 | Model Group:daklicht A1:2182252

# IfcWindow: NLRS_41_GM_WPB_spouwlat_isolatie_gen_bdg:187x38 + isolatie 110x180 (144)
Type - ParameterTakesPrecedence: no; Sizeable: no; Material: n7_isolatie_Resol, ISR_Hout
Type - Constraints - Default Elevation: 0 mm
Type - Materials and Finishes - materiaal isolatie: n7_isolatie_Resol; materiaal: ISR_Hout
Type - Dimensions - spouwlat_ruimte_tbv_kierdichting: 0 mm; hoogte: 77 mm; isolatie_breedte: 110 mm; isolatie_diepte: 180 mm; spouwlat_breedte: 38 mm; spouwlat_diepte_incl_kierdichting: 187 mm
Type - Identity Data - Workset: Family : Generic Models : NLRS_41_GM_WPB_spouwlat_isolatie_gen_bdg; Assembly Code: 31.10; Assembly Description: buitenwandopeningen; niet gevuld, algemeen (verzamelniveau); Datum_Gewijzigd: 14-11-2012; Description: spouwlat; Model: LOD300; SmartRevit_Versie: 2014.1; Type Name: 187x38 + isolatie 110x180
Type - Other - Category: Generic Models; isolatie zichtbaar: yes; Family Name: NLRS_41_GM_WPB_spouwlat_isolatie_gen_bdg
OverallHeight: 187 mm; Classification: 31.10 Uniformat (Uniformat)
Constraints - Moves With Nearby Elements: no
Phasing - Phase Created: 2. nieuwbouw
Graphics - hoek_a: 0 deg; hoek_b: 0 deg
Identity Data - Workset: Workset1
Other - berekende_hoek_a: 0 deg; berekende_overstek_a: 0 mm; berekende_overstek_b: 0 mm; Family: NLRS_41_GM_WPB_spouwlat_isolatie_gen_bdg; Family and Type: NLRS_41_GM_WPB_spouwlat_isolatie_gen_bdg: 187x38 + isolatie 110x180; Type: 187x38 + isolatie 110x180; Type Id: 2313838
Name (NLRS_41_GM_WPB_spouwlat_isolatie_gen_bdg:187x38 + isolatie 110x180:...) | In | OverallWidth (mm) | Level | Elevation from Level (mm) = Offset from Host (mm) | Host | lengte (mm) | Area (m2) | element_lengte (mm) | verlenging_a (mm) = verlenging_b (mm) | Volume (m3) | berekende_verlenging_a (mm) = berekende_verlenging_b (mm)
859968 | 02 tweede verdieping | 2390 | 02 tweede verdieping | 29183.4 | Basic Wall : NLRS_22_WA_HSB bispouw 30-245-12-13 glaswol_gen_ISR | 2390 | 1.24025 | 2356 | -17 | 0.0633905 | 1983
859969 | 02 tweede verdieping | 2390 | 02 tweede verdieping | -11996.9 | Basic Wall : NLRS_22_WA_HSB bispouw 30-245-12-13 glaswol_gen_ISR | 2390 | 1.24025 | 2356 | -17 | 0.0633905 | 1983
864454 | 02 tweede verdieping | 2390 | 02 tweede verdieping | 29183.4 | Level : 02 tweede verdieping | 2390 | 1.24025 | 2356 | -17 | 0.0633905 | 1983
864455 | 02 tweede verdieping | 2390 | 02 tweede verdieping | -11996.9 | Level : 02 tweede verdieping | 2390 | 1.24025 | 2356 | -17 | 0.0633905 | 1983
864485 | 02 tweede verdieping | 2390 | 02 tweede verdieping | 29183.4 | Level : 02 tweede verdieping | 2390 | 1.24025 | 2356 | -17 | 0.0633905 | 1983
864486 | 02 tweede verdieping | 2390 | 02 tweede verdieping | -11996.9 | Level : 02 tweede verdieping | 2390 | 1.24025 | 2356 | -17 | 0.0633905 | 1983
870612 | 02 tweede verdieping | 2390 | 02 tweede verdieping | 29183.4 | Level : 02 tweede verdieping | 2390 | 1.24025 | 2356 | -17 | 0.0633905 | 1983
870613 | 02 tweede verdieping | 2390 | 02 tweede verdieping | -11996.9 | Level : 02 tweede verdieping | 2390 | 1.24025 | 2356 | -17 | 0.0633905 | 1983
870629 | 02 tweede verdieping | 2390 | 02 tweede verdieping | 29183.4 | Level : 02 tweede verdieping | 2390 | 1.24025 | 2356 | -17 | 0.0633905 | 1983
870630 | 02 tweede verdieping | 2390 | 02 tweede verdieping | -11996.9 | Level : 02 tweede verdieping | 2390 | 1.24025 | 2356 | -17 | 0.0633905 | 1983
870646 | 02 tweede verdieping | 2390 | 02 tweede verdieping | 29183.4 | Level : 02 tweede verdieping | 2390 | 1.24025 | 2356 | -17 | 0.0633905 | 1983
870647 | 02 tweede verdieping | 2390 | 02 tweede verdieping | -11996.9 | Level : 02 tweede verdieping | 2390 | 1.24025 | 2356 | -17 | 0.0633905 | 1983
870694 | 02 tweede verdieping | 2390 | 02 tweede verdieping | 29183.4 | Level : 02 tweede verdieping | 2390 | 1.24025 | 2356 | -17 | 0.0633905 | 1983
870695 | 02 tweede verdieping | 2390 | 02 tweede verdieping | -11996.9 | Level : 02 tweede verdieping | 2390 | 1.24025 | 2356 | -17 | 0.0633905 | 1983
870711 | 02 tweede verdieping | 2390 | 02 tweede verdieping | 29183.4 | Level : 02 tweede verdieping | 2390 | 1.24025 | 2356 | -17 | 0.0633905 | 1983
870712 | 02 tweede verdieping | 2390 | 02 tweede verdieping | -11996.9 | Level : 02 tweede verdieping | 2390 | 1.24025 | 2356 | -17 | 0.0633905 | 1983
870728 | 02 tweede verdieping | 2390 | 02 tweede verdieping | 29183.4 | Level : 02 tweede verdieping | 2390 | 1.24025 | 2356 | -17 | 0.0633905 | 1983
870729 | 02 tweede verdieping | 2390 | 02 tweede verdieping | -11996.9 | Level : 02 tweede verdieping | 2390 | 1.24025 | 2356 | -17 | 0.0633905 | 1983
870807 | 02 tweede verdieping | 2390 | 02 tweede verdieping | 29183.4 | Level : 02 tweede verdieping | 2390 | 1.24025 | 2356 | -17 | 0.0633905 | 1983
870808 | 02 tweede verdieping | 2390 | 02 tweede verdieping | -11996.9 | Level : 02 tweede verdieping | 2390 | 1.24025 | 2356 | -17 | 0.0633905 | 1983
870824 | 02 tweede verdieping | 2390 | 02 tweede verdieping | 29183.4 | Level : 02 tweede verdieping | 2390 | 1.24025 | 2356 | -17 | 0.0633905 | 1983
870825 | 02 tweede verdieping | 2390 | 02 tweede verdieping | -11996.9 | Level : 02 tweede verdieping | 2390 | 1.24025 | 2356 | -17 | 0.0633905 | 1983
870841 | 02 tweede verdieping | 2390 | 02 tweede verdieping | 29183.4 | Level : 02 tweede verdieping | 2390 | 1.24025 | 2356 | -17 | 0.0633905 | 1983
870842 | 02 tweede verdieping | 2390 | 02 tweede verdieping | -11996.9 | Level : 02 tweede verdieping | 2390 | 1.24025 | 2356 | -17 | 0.0633905 | 1983
870951 | 02 tweede verdieping | 2390 | 02 tweede verdieping | 20684.6 | Basic Wall : 21_WA_metselwerk_licht_100_gen_bdg | 2390 | 1.24025 | 2356 | -17 | 0.0633905 | 1983
870952 | 02 tweede verdieping | 2390 | 02 tweede verdieping | -2165.36 | Basic Wall : 21_WA_metselwerk_licht_100_gen_bdg | 2390 | 1.24025 | 2356 | -17 | 0.0633905 | 1983
871629 | 02 tweede verdieping | 2390 | 02 tweede verdieping | 20684.6 | Level : 02 tweede verdieping | 2390 | 1.24025 | 2356 | -17 | 0.0633905 | 1983
871630 | 02 tweede verdieping | 2390 | 02 tweede verdieping | -2165.36 | Level : 02 tweede verdieping | 2390 | 1.24025 | 2356 | -17 | 0.0633905 | 1983
871662 | 02 tweede verdieping | 2390 | 02 tweede verdieping | 20684.6 | Level : 02 tweede verdieping | 2390 | 1.24025 | 2356 | -17 | 0.0633905 | 1983
871663 | 02 tweede verdieping | 2390 | 02 tweede verdieping | -2165.36 | Level : 02 tweede verdieping | 2390 | 1.24025 | 2356 | -17 | 0.0633905 | 1983
871695 | 02 tweede verdieping | 2390 | 02 tweede verdieping | 20684.6 | Level : 02 tweede verdieping | 2390 | 1.24025 | 2356 | -17 | 0.0633905 | 1983
871696 | 02 tweede verdieping | 2390 | 02 tweede verdieping | -2165.36 | Level : 02 tweede verdieping | 2390 | 1.24025 | 2356 | -17 | 0.0633905 | 1983
871881 | 02 tweede verdieping | 2390 | 02 tweede verdieping | 20684.6 | Level : 02 tweede verdieping | 2390 | 1.24025 | 2356 | -17 | 0.0633905 | 1983
871882 | 02 tweede verdieping | 2390 | 02 tweede verdieping | -2165.36 | Level : 02 tweede verdieping | 2390 | 1.24025 | 2356 | -17 | 0.0633905 | 1983
871913 | 02 tweede verdieping | 2390 | 02 tweede verdieping | 20684.6 | Level : 02 tweede verdieping | 2390 | 1.24025 | 2356 | -17 | 0.0633905 | 1983
871914 | 02 tweede verdieping | 2390 | 02 tweede verdieping | -2165.36 | Level : 02 tweede verdieping | 2390 | 1.24025 | 2356 | -17 | 0.0633905 | 1983
871945 | 02 tweede verdieping | 2390 | 02 tweede verdieping | 20684.6 | Level : 02 tweede verdieping | 2390 | 1.24025 | 2356 | -17 | 0.0633905 | 1983
871946 | 02 tweede verdieping | 2390 | 02 tweede verdieping | -2165.36 | Level : 02 tweede verdieping | 2390 | 1.24025 | 2356 | -17 | 0.0633905 | 1983
871977 | 02 tweede verdieping | 2390 | 02 tweede verdieping | 20684.6 | Level : 02 tweede verdieping | 2390 | 1.24025 | 2356 | -17 | 0.0633905 | 1983
871978 | 02 tweede verdieping | 2390 | 02 tweede verdieping | -2165.36 | Level : 02 tweede verdieping | 2390 | 1.24025 | 2356 | -17 | 0.0633905 | 1983
872041 | 02 tweede verdieping | 2390 | 02 tweede verdieping | 40853.9 | Basic Wall : 21_WA_metselwerk_licht_100_gen_bdg | 2390 | 1.24025 | 2356 | -17 | 0.0633905 | 1983
872042 | 02 tweede verdieping | 2390 | 02 tweede verdieping | -22334.6 | Basic Wall : 21_WA_metselwerk_licht_100_gen_bdg | 2390 | 1.24025 | 2356 | -17 | 0.0633905 | 1983
872076 | 02 tweede verdieping | 2390 | 02 tweede verdieping | 40990.8 | Basic Wall : 21_WA_metselwerk_licht_100_gen_bdg | 2390 | 1.24025 | 2356 | -17 | 0.0633905 | 1983
872077 | 02 tweede verdieping | 2390 | 02 tweede verdieping | -22471.5 | Basic Wall : 21_WA_metselwerk_licht_100_gen_bdg | 2390 | 1.24025 | 2356 | -17 | 0.0633905 | 1983
872802 | 02 tweede verdieping | 2390 | 02 tweede verdieping | 40990.8 | Level : 02 tweede verdieping | 2390 | 1.24025 | 2356 | -17 | 0.0633905 | 1983
872803 | 02 tweede verdieping | 2390 | 02 tweede verdieping | -22471.5 | Level : 02 tweede verdieping | 2390 | 1.24025 | 2356 | -17 | 0.0633905 | 1983
872835 | 02 tweede verdieping | 2390 | 02 tweede verdieping | 40990.8 | Level : 02 tweede verdieping | 2390 | 1.24025 | 2356 | -17 | 0.0633905 | 1983
872836 | 02 tweede verdieping | 2390 | 02 tweede verdieping | -22471.5 | Level : 02 tweede verdieping | 2390 | 1.24025 | 2356 | -17 | 0.0633905 | 1983
872868 | 02 tweede verdieping | 2390 | 02 tweede verdieping | 40990.8 | Level : 02 tweede verdieping | 2390 | 1.24025 | 2356 | -17 | 0.0633905 | 1983
872869 | 02 tweede verdieping | 2390 | 02 tweede verdieping | -22471.5 | Level : 02 tweede verdieping | 2390 | 1.24025 | 2356 | -17 | 0.0633905 | 1983
872901 | 02 tweede verdieping | 2390 | 02 tweede verdieping | 40990.8 | Level : 02 tweede verdieping | 2390 | 1.24025 | 2356 | -17 | 0.0633905 | 1983
872902 | 02 tweede verdieping | 2390 | 02 tweede verdieping | -22471.5 | Level : 02 tweede verdieping | 2390 | 1.24025 | 2356 | -17 | 0.0633905 | 1983
872934 | 02 tweede verdieping | 2390 | 02 tweede verdieping | 40990.8 | Level : 02 tweede verdieping | 2390 | 1.24025 | 2356 | -17 | 0.0633905 | 1983
872935 | 02 tweede verdieping | 2390 | 02 tweede verdieping | -22471.5 | Level : 02 tweede verdieping | 2390 | 1.24025 | 2356 | -17 | 0.0633905 | 1983
872967 | 02 tweede verdieping | 2390 | 02 tweede verdieping | 40990.8 | Level : 02 tweede verdieping | 2390 | 1.24025 | 2356 | -17 | 0.0633905 | 1983
872968 | 02 tweede verdieping | 2390 | 02 tweede verdieping | -22471.5 | Level : 02 tweede verdieping | 2390 | 1.24025 | 2356 | -17 | 0.0633905 | 1983
873000 | 02 tweede verdieping | 2390 | 02 tweede verdieping | 40990.8 | Level : 02 tweede verdieping | 2390 | 1.24025 | 2356 | -17 | 0.0633905 | 1983
873001 | 02 tweede verdieping | 2390 | 02 tweede verdieping | -22471.5 | Level : 02 tweede verdieping | 2390 | 1.24025 | 2356 | -17 | 0.0633905 | 1983
873033 | 02 tweede verdieping | 2390 | 02 tweede verdieping | 40990.8 | Level : 02 tweede verdieping | 2390 | 1.24025 | 2356 | -17 | 0.0633905 | 1983
873034 | 02 tweede verdieping | 2390 | 02 tweede verdieping | -22471.5 | Level : 02 tweede verdieping | 2390 | 1.24025 | 2356 | -17 | 0.0633905 | 1983
873066 | 02 tweede verdieping | 2390 | 02 tweede verdieping | 40990.8 | Level : 02 tweede verdieping | 2390 | 1.24025 | 2356 | -17 | 0.0633905 | 1983
873067 | 02 tweede verdieping | 2390 | 02 tweede verdieping | -22471.5 | Level : 02 tweede verdieping | 2390 | 1.24025 | 2356 | -17 | 0.0633905 | 1983
873099 | 02 tweede verdieping | 2390 | 02 tweede verdieping | 40990.8 | Level : 02 tweede verdieping | 2390 | 1.24025 | 2356 | -17 | 0.0633905 | 1983
873100 | 02 tweede verdieping | 2390 | 02 tweede verdieping | -22471.5 | Level : 02 tweede verdieping | 2390 | 1.24025 | 2356 | -17 | 0.0633905 | 1983
873410 | 02 tweede verdieping | 2390 | 02 tweede verdieping | 40853.9 | Level : 02 tweede verdieping | 2390 | 1.24025 | 2356 | -17 | 0.0633905 | 1983
873411 | 02 tweede verdieping | 2390 | 02 tweede verdieping | -22334.6 | Level : 02 tweede verdieping | 2390 | 1.24025 | 2356 | -17 | 0.0633905 | 1983
873460 | 02 tweede verdieping | 2390 | 02 tweede verdieping | 40853.9 | Level : 02 tweede verdieping | 2390 | 1.24025 | 2356 | -17 | 0.0633905 | 1983
873461 | 02 tweede verdieping | 2390 | 02 tweede verdieping | -22334.6 | Level : 02 tweede verdieping | 2390 | 1.24025 | 2356 | -17 | 0.0633905 | 1983
873491 | 02 tweede verdieping | 2390 | 02 tweede verdieping | 40853.9 | Level : 02 tweede verdieping | 2390 | 1.24025 | 2356 | -17 | 0.0633905 | 1983
873492 | 02 tweede verdieping | 2390 | 02 tweede verdieping | -22334.6 | Level : 02 tweede verdieping | 2390 | 1.24025 | 2356 | -17 | 0.0633905 | 1983
873522 | 02 tweede verdieping | 2390 | 02 tweede verdieping | 40853.9 | Level : 02 tweede verdieping | 2390 | 1.24025 | 2356 | -17 | 0.0633905 | 1983
873523 | 02 tweede verdieping | 2390 | 02 tweede verdieping | -22334.6 | Level : 02 tweede verdieping | 2390 | 1.24025 | 2356 | -17 | 0.0633905 | 1983
873553 | 02 tweede verdieping | 2390 | 02 tweede verdieping | 40853.9 | Level : 02 tweede verdieping | 2390 | 1.24025 | 2356 | -17 | 0.0633905 | 1983
873554 | 02 tweede verdieping | 2390 | 02 tweede verdieping | -22334.6 | Level : 02 tweede verdieping | 2390 | 1.24025 | 2356 | -17 | 0.0633905 | 1983
873584 | 02 tweede verdieping | 2390 | 02 tweede verdieping | 40853.9 | Level : 02 tweede verdieping | 2390 | 1.24025 | 2356 | -17 | 0.0633905 | 1983
873585 | 02 tweede verdieping | 2390 | 02 tweede verdieping | -22334.6 | Level : 02 tweede verdieping | 2390 | 1.24025 | 2356 | -17 | 0.0633905 | 1983
873615 | 02 tweede verdieping | 2390 | 02 tweede verdieping | 40853.9 | Level : 02 tweede verdieping | 2390 | 1.24025 | 2356 | -17 | 0.0633905 | 1983
873616 | 02 tweede verdieping | 2390 | 02 tweede verdieping | -22334.6 | Level : 02 tweede verdieping | 2390 | 1.24025 | 2356 | -17 | 0.0633905 | 1983
873646 | 02 tweede verdieping | 2390 | 02 tweede verdieping | 40853.9 | Level : 02 tweede verdieping | 2390 | 1.24025 | 2356 | -17 | 0.0633905 | 1983
873647 | 02 tweede verdieping | 2390 | 02 tweede verdieping | -22334.6 | Level : 02 tweede verdieping | 2390 | 1.24025 | 2356 | -17 | 0.0633905 | 1983
873677 | 02 tweede verdieping | 2390 | 02 tweede verdieping | 40853.9 | Level : 02 tweede verdieping | 2390 | 1.24025 | 2356 | -17 | 0.0633905 | 1983
873678 | 02 tweede verdieping | 2390 | 02 tweede verdieping | -22334.6 | Level : 02 tweede verdieping | 2390 | 1.24025 | 2356 | -17 | 0.0633905 | 1983
873708 | 02 tweede verdieping | 2390 | 02 tweede verdieping | 40853.9 | Level : 02 tweede verdieping | 2390 | 1.24025 | 2356 | -17 | 0.0633905 | 1983
873709 | 02 tweede verdieping | 2390 | 02 tweede verdieping | -22334.6 | Level : 02 tweede verdieping | 2390 | 1.24025 | 2356 | -17 | 0.0633905 | 1983
873739 | 02 tweede verdieping | 2390 | 02 tweede verdieping | 40853.9 | Level : 02 tweede verdieping | 2390 | 1.24025 | 2356 | -17 | 0.0633905 | 1983
873740 | 02 tweede verdieping | 2390 | 02 tweede verdieping | -22334.6 | Level : 02 tweede verdieping | 2390 | 1.24025 | 2356 | -17 | 0.0633905 | 1983
897885 | 00 begane grond | 3008 | 00 begane grond | 25879.6 | Basic Wall : NLRS_22_WA_HSB bispouw 30-245-12-13 glaswol_gen_ISR | 3008 | 1.55852 | 2974 | -17 | 0.0800184 | 1983
897938 | 00 begane grond | 3008 | 00 begane grond | 27499.6 | Basic Wall : NLRS_22_WA_HSB bispouw 30-245-12-13 glaswol_gen_ISR | 3008 | 1.55852 | 2974 | -17 | 0.0800184 | 1983
897939 | 00 begane grond | 3008 | 00 begane grond | -24580.4 | Basic Wall : NLRS_22_WA_HSB bispouw 30-245-12-13 glaswol_gen_ISR | 3008 | 1.55852 | 2974 | -17 | 0.0800184 | 1983
898546 | 00 begane grond | 3008 | 00 begane grond | 25879.6 | Basic Wall : NLRS_22_WA_HSB bispouw 30-245-12-13 glaswol_gen_ISR | 3008 | 1.55852 | 2974 | -17 | 0.0800184 | 1983
898547 | 00 begane grond | 3008 | 00 begane grond | -22960.4 | Basic Wall : NLRS_22_WA_HSB bispouw 30-245-12-13 glaswol_gen_ISR | 3008 | 1.55852 | 2974 | -17 | 0.0800184 | 1983
898558 | 00 begane grond | 3008 | 00 begane grond | 27499.6 | Basic Wall : NLRS_22_WA_HSB bispouw 30-245-12-13 glaswol_gen_ISR | 3008 | 1.55852 | 2974 | -17 | 0.0800184 | 1983
898559 | 00 begane grond | 3008 | 00 begane grond | -24580.4 | Basic Wall : NLRS_22_WA_HSB bispouw 30-245-12-13 glaswol_gen_ISR | 3008 | 1.55852 | 2974 | -17 | 0.0800184 | 1983
1219784 | 00 begane grond | 3008 | 00 begane grond | 27499.6 | Basic Wall : NLRS_22_WA_HSB bispouw 30-245-12-13 glaswol_gen_ISR | 3008 | 1.55852 | 2974 | -17 | 0.0800184 | 1983
1219785 | 00 begane grond | 3008 | 00 begane grond | -24580.4 | Basic Wall : NLRS_22_WA_HSB bispouw 30-245-12-13 glaswol_gen_ISR | 3008 | 1.55852 | 2974 | -17 | 0.0800184 | 1983
1220534 | 00 begane grond | 3008 | 00 begane grond | 25879.6 | Basic Wall : NLRS_22_WA_HSB bispouw 30-245-12-13 glaswol_gen_ISR | 3008 | 1.55852 | 2974 | -17 | 0.0800184 | 1983
1220535 | 00 begane grond | 3008 | 00 begane grond | -22960.4 | Basic Wall : NLRS_22_WA_HSB bispouw 30-245-12-13 glaswol_gen_ISR | 3008 | 1.55852 | 2974 | -17 | 0.0800184 | 1983
1221368 | 00 begane grond | 3008 | 00 begane grond | 25879.6 | Basic Wall : NLRS_22_WA_HSB bispouw 30-245-12-13 glaswol_gen_ISR | 3008 | 1.55852 | 2974 | -17 | 0.0800184 | 1983
1221369 | 00 begane grond | 3008 | 00 begane grond | -22960.4 | Basic Wall : NLRS_22_WA_HSB bispouw 30-245-12-13 glaswol_gen_ISR | 3008 | 1.55852 | 2974 | -17 | 0.0800184 | 1983
1221379 | 00 begane grond | 3008 | 00 begane grond | 27499.6 | Basic Wall : NLRS_22_WA_HSB bispouw 30-245-12-13 glaswol_gen_ISR | 3008 | 1.55852 | 2974 | -17 | 0.0800184 | 1983
1221380 | 00 begane grond | 3008 | 00 begane grond | -24580.4 | Basic Wall : NLRS_22_WA_HSB bispouw 30-245-12-13 glaswol_gen_ISR | 3008 | 1.55852 | 2974 | -17 | 0.0800184 | 1983
1221600 | 00 begane grond | 3008 | 00 begane grond | 25879.6 | Basic Wall : NLRS_22_WA_HSB bispouw 30-245-12-13 glaswol_gen_ISR | 3008 | 1.55852 | 2974 | -17 | 0.0800184 | 1983
1221601 | 00 begane grond | 3008 | 00 begane grond | -22960.4 | Basic Wall : NLRS_22_WA_HSB bispouw 30-245-12-13 glaswol_gen_ISR | 3008 | 1.55852 | 2974 | -17 | 0.0800184 | 1983
1222355 | 00 begane grond | 3008 | 00 begane grond | 25879.6 | Basic Wall : NLRS_22_WA_HSB bispouw 30-245-12-13 glaswol_gen_ISR | 3008 | 1.55852 | 2974 | -17 | 0.0800184 | 1983
1222356 | 00 begane grond | 3008 | 00 begane grond | -22960.4 | Basic Wall : NLRS_22_WA_HSB bispouw 30-245-12-13 glaswol_gen_ISR | 3008 | 1.55852 | 2974 | -17 | 0.0800184 | 1983
1222797 | 00 begane grond | 3008 | 00 begane grond | 25879.6 | Basic Wall : NLRS_22_WA_HSB bispouw 30-245-12-13 glaswol_gen_ISR | 3008 | 1.55852 | 2974 | -17 | 0.0800184 | 1983
1222798 | 00 begane grond | 3008 | 00 begane grond | -22960.4 | Basic Wall : NLRS_22_WA_HSB bispouw 30-245-12-13 glaswol_gen_ISR | 3008 | 1.55852 | 2974 | -17 | 0.0800184 | 1983
1223374 | 00 begane grond | 3008 | 00 begane grond | 25879.6 | Basic Wall : NLRS_22_WA_HSB bispouw 30-245-12-13 glaswol_gen_ISR | 3008 | 1.55852 | 2974 | -17 | 0.0800184 | 1983
1223375 | 00 begane grond | 3008 | 00 begane grond | -22960.4 | Basic Wall : NLRS_22_WA_HSB bispouw 30-245-12-13 glaswol_gen_ISR | 3008 | 1.55852 | 2974 | -17 | 0.0800184 | 1983
1224043 | 00 begane grond | 3008 | 00 begane grond | 25879.6 | Basic Wall : NLRS_22_WA_HSB bispouw 30-245-12-13 glaswol_gen_ISR | 3008 | 1.55852 | 2974 | -17 | 0.0800184 | 1983
1224055 | 00 begane grond | 3008 | 00 begane grond | -22960.4 | Basic Wall : NLRS_22_WA_HSB bispouw 30-245-12-13 glaswol_gen_ISR | 3008 | 1.55852 | 2974 | -17 | 0.0800184 | 1983
1224162 | 00 begane grond | 3008 | 00 begane grond | 25879.6 | Basic Wall : NLRS_22_WA_HSB bispouw 30-245-12-13 glaswol_gen_ISR | 3008 | 1.55852 | 2974 | -17 | 0.0800184 | 1983
1224163 | 00 begane grond | 3008 | 00 begane grond | -22960.4 | Basic Wall : NLRS_22_WA_HSB bispouw 30-245-12-13 glaswol_gen_ISR | 3008 | 1.55852 | 2974 | -17 | 0.0800184 | 1983
1488571 | 00 begane grond | 3008 | 00 begane grond | 35426.1 | Basic Wall : 22_WA_binnenwand_ms125 25-75-25 _gen_bdg | 3008 | 1.55852 | 2974 | -17 | 0.0800184 | 1983
1488572 | 00 begane grond | 3008 | 00 begane grond | -32506.9 | Basic Wall : 22_WA_binnenwand_ms125 25-75-25 _gen_bdg | 3008 | 1.55852 | 2974 | -17 | 0.0800184 | 1983
1492645 | 00 begane grond | 3008 | 00 begane grond | 49479.9 | Basic Wall : NLRS_22_WA_HSB bispouw 30-245-12-13 glaswol_gen_ISR | 3008 | 1.55852 | 2974 | -17 | 0.0800184 | 1983
1492646 | 00 begane grond | 3008 | 00 begane grond | -44515.7 | Basic Wall : NLRS_22_WA_HSB bispouw 30-245-12-13 glaswol_gen_ISR | 3008 | 1.55852 | 2974 | -17 | 0.0800184 | 1983
1492946 | 00 begane grond | 2621 | 00 begane grond | -45129.4 | Basic Wall : 21_WA_metselwerk_middel_100_gen_bdg | 2621 | 1.35921 | 2587 | -17 | 0.0696058 | 1983
1492947 | 00 begane grond | 2621 | 00 begane grond | 48048.7 | Basic Wall : 21_WA_metselwerk_middel_100_gen_bdg | 2621 | 1.35921 | 2587 | -17 | 0.0696058 | 1983
1493181 | 00 begane grond | 3008 | 00 begane grond | -45129.4 | Level : 00 begane grond | 3008 | 1.55852 | 2974 | -17 | 0.0800184 | 1983
1493182 | 00 begane grond | 3008 | 00 begane grond | 48048.7 | Level : 00 begane grond | 3008 | 1.55852 | 2974 | -17 | 0.0800184 | 1983
1502430 | 00 begane grond | 3008 | 00 begane grond | -64890.4 | Level : 00 begane grond | 3008 | 1.55852 | 2974 | -17 | 0.0800184 | 1983
1502431 | 00 begane grond | 3008 | 00 begane grond | 67809.6 | Level : 00 begane grond | 3008 | 1.55852 | 2974 | -17 | 0.0800184 | 1983
1502789 | 00 begane grond | 3008 | 00 begane grond | -64890.4 | Level : 00 begane grond | 3008 | 1.55852 | 2974 | -17 | 0.0800184 | 1983
1502790 | 00 begane grond | 3008 | 00 begane grond | 67809.6 | Level : 00 begane grond | 3008 | 1.55852 | 2974 | -17 | 0.0800184 | 1983
1503070 | 00 begane grond | 3008 | 00 begane grond | 28584.6 | Level : 00 begane grond | 3008 | 1.55852 | 2974 | -17 | 0.0800184 | 1983
1503071 | 00 begane grond | 3008 | 00 begane grond | -25665.4 | Level : 00 begane grond | 3008 | 1.55852 | 2974 | -17 | 0.0800184 | 1983
1503712 | 00 begane grond | 3008 | 00 begane grond | 28584.6 | Level : 00 begane grond | 3008 | 1.55852 | 2974 | -17 | 0.0800184 | 1983
1503713 | 00 begane grond | 3008 | 00 begane grond | -25665.4 | Level : 00 begane grond | 3008 | 1.55852 | 2974 | -17 | 0.0800184 | 1983
1818655 | 00 begane grond | 3008 | 00 begane grond | 13964 | Basic Wall : NLRS_22_WA_HSB bispouw 30-245-12-13 glaswol_gen_ISR | 3008 | 1.55852 | 2974 | -17 | 0.0800184 | 1983
1822618 | 00 begane grond | 3008 | 00 begane grond | -46321.9 | Basic Wall : NLRS_22_WA_HSB bispouw 30-245-12-13 glaswol_gen_ISR | 3008 | 1.55852 | 2974 | -17 | 0.0800184 | 1983
1822619 | 00 begane grond | 3008 | 00 begane grond | 51286.2 | Basic Wall : NLRS_22_WA_HSB bispouw 30-245-12-13 glaswol_gen_ISR | 3008 | 1.55852 | 2974 | -17 | 0.0800184 | 1983
1847949 | 02 tweede verdieping | 2807 | 02 tweede verdieping | 31134.6 | Basic Wall : 22_WA_binnenwand_ms125 25-75-25 _gen_bdg | 2807 | 1.455 | 2773 | -17 | 0.0746103 | 1983
1847950 | 02 tweede verdieping | 2807 | 02 tweede verdieping | -12615.4 | Basic Wall : 22_WA_binnenwand_ms125 25-75-25 _gen_bdg | 2807 | 1.455 | 2773 | -17 | 0.0746103 | 1983
2239505 | 00 begane grond | 1409 | 00 begane grond | 38462.6 | Basic Wall : NLRS_22_WA_HSB bispouw 30-245-12-13 glaswol_gen_ISR | 1353 | 0.752541 | 1409 | 28 | 0.0379106 | 2028
2239517 | 00 begane grond | 3036 | 00 begane grond | -8752.86 | Basic Wall : NLRS_22_WA_HSB bispouw 30-245-12-13 glaswol_gen_ISR | 3036 | 1.57294 | 3002 | -17 | 0.0807718 | 1983
2239551 | 00 begane grond | 889 | 00 begane grond | -5937.36 | Basic Wall : NLRS_22_WA_HSB bispouw 30-245-12-13 glaswol_gen_ISR | 833 | 0.484741 | 889 | 28 | 0.0239194 | 2028
2239552 | 00 begane grond | 3036 | 00 begane grond | 36644.8 | Basic Wall : NLRS_22_WA_HSB bispouw 30-245-12-13 glaswol_gen_ISR | 3036 | 1.57294 | 3002 | -17 | 0.0807718 | 1983
2546397 | 00 begane grond | 2621 | 00 begane grond | -45129.4 | Level : 00 begane grond | 2621 | 1.35921 | 2587 | -17 | 0.0696058 | 1983
2546398 | 00 begane grond | 2621 | 00 begane grond | 48048.7 | Level : 00 begane grond | 2621 | 1.35921 | 2587 | -17 | 0.0696058 | 1983
2785706 | 00 begane grond | 1906.5 | 00 begane grond | 27795.1 | Basic Wall : 22_WA_binnenwand_ms125 25-75-25 _gen_bdg | 1850.5 | 1.00875 | 1906.5 | 28 | 0.0512963 | 2028
2786084 | 00 begane grond | 2350 | 00 begane grond | 21317.6 | Basic Wall : NLRS_22_WA_HSB bispouw 30-245-12-13 glaswol_gen_ISR | 2294 | 1.23716 | 2350 | 28 | 0.0632291 | 2028
2790503 | 00 begane grond | 3142.76 | 00 begane grond | 14030.1 | Basic Wall : 22_WA_binnenwand_ms125 25-75-25 _gen_bdg | 3086.76 | 1.64543 | 3142.76 | 28 | 0.0845591 | 2028
2790504 | 00 begane grond | 3008 | 00 begane grond | -31772 | Basic Wall : 22_WA_binnenwand_ms125 25-75-25 _gen_bdg | 3008 | 1.55852 | 2974 | -17 | 0.0800184 | 1983

# IfcWindow: NLRS_41_GM_WPB_spouwlat_isolatie_gen_bdg:187x38 + isolatie 113x200 (44)
In: 02 tweede verdieping
Type - ParameterTakesPrecedence: no; Sizeable: no; Material: n7_isolatie_Resol, 00_Hout_generiek
Type - Constraints - Default Elevation: 0 mm
Type - Materials and Finishes - materiaal: 00_Hout_generiek; materiaal isolatie: n7_isolatie_Resol
Type - Dimensions - spouwlat_ruimte_tbv_kierdichting: 0 mm; hoogte: 77 mm; isolatie_breedte: 113 mm; isolatie_diepte: 200 mm; spouwlat_breedte: 38 mm; spouwlat_diepte_incl_kierdichting: 187 mm
Type - Identity Data - Workset: Family : Generic Models : NLRS_41_GM_WPB_spouwlat_isolatie_gen_bdg; Assembly Code: 31.10; Assembly Description: buitenwandopeningen; niet gevuld, algemeen (verzamelniveau); Datum_Gewijzigd: 14-11-2012; Description: spouwlat; Model: LOD300; SmartRevit_Versie: 2014.1; Type Name: 187x38 + isolatie 113x200
Type - Other - Category: Generic Models; isolatie zichtbaar: yes; Family Name: NLRS_41_GM_WPB_spouwlat_isolatie_gen_bdg
OverallHeight: 200 mm; Classification: 31.10 Uniformat (Uniformat)
Constraints - Moves With Nearby Elements: no; Level: 02 tweede verdieping
Phasing - Phase Created: 2. nieuwbouw
Graphics - hoek_a: 0 deg; hoek_b: 0 deg
Identity Data - Workset: Workset1
Other - berekende_hoek_a: 0 deg; berekende_overstek_a: 0 mm; berekende_overstek_b: 0 mm; Family: NLRS_41_GM_WPB_spouwlat_isolatie_gen_bdg; Family and Type: NLRS_41_GM_WPB_spouwlat_isolatie_gen_bdg: 187x38 + isolatie 113x200; Type: 187x38 + isolatie 113x200; Type Id: 3277580
Name (NLRS_41_GM_WPB_spouwlat_isolatie_gen_bdg:187x38 + isolatie 113x200:...) | OverallWidth (mm) = element_lengte (mm) | Elevation from Level (mm) = Offset from Host (mm) | Host | lengte (mm) | Area (m2) | verlenging_a (mm) = verlenging_b (mm) | Volume (m3) | berekende_verlenging_a (mm) = berekende_verlenging_b (mm)
859967 | 892 | 18926.3 | Basic Wall : NLRS_22_WA_HSB bispouw 30-245-12-13 glaswol_gen_ISR | 850 | 0.509602 | 21 | 0.0264978 | 2021
864453 | 892 | 18926.3 | Level : 02 tweede verdieping | 850 | 0.509602 | 21 | 0.0264978 | 2021
864484 | 892 | 18926.3 | Level : 02 tweede verdieping | 850 | 0.509602 | 21 | 0.0264978 | 2021
870611 | 892 | 18926.3 | Level : 02 tweede verdieping | 850 | 0.509602 | 21 | 0.0264978 | 2021
870628 | 892 | 18926.3 | Level : 02 tweede verdieping | 850 | 0.509602 | 21 | 0.0264978 | 2021
870645 | 892 | 18926.3 | Level : 02 tweede verdieping | 850 | 0.509602 | 21 | 0.0264978 | 2021
870693 | 892 | 18926.3 | Level : 02 tweede verdieping | 850 | 0.509602 | 21 | 0.0264978 | 2021
870710 | 892 | 18926.3 | Level : 02 tweede verdieping | 850 | 0.509602 | 21 | 0.0264978 | 2021
870727 | 892 | 18926.3 | Level : 02 tweede verdieping | 850 | 0.509602 | 21 | 0.0264978 | 2021
870806 | 892 | 18926.3 | Level : 02 tweede verdieping | 850 | 0.509602 | 21 | 0.0264978 | 2021
870823 | 892 | 18926.3 | Level : 02 tweede verdieping | 850 | 0.509602 | 21 | 0.0264978 | 2021
870840 | 892 | 18926.3 | Level : 02 tweede verdieping | 850 | 0.509602 | 21 | 0.0264978 | 2021
870950 | 892 | -25247.4 | Basic Wall : 21_WA_metselwerk_licht_100_gen_bdg | 850 | 0.509602 | 21 | 0.0264978 | 2021
871628 | 892 | -25247.4 | Level : 02 tweede verdieping | 850 | 0.509602 | 21 | 0.0264978 | 2021
871661 | 892 | -25247.4 | Level : 02 tweede verdieping | 850 | 0.509602 | 21 | 0.0264978 | 2021
871694 | 892 | -25247.4 | Level : 02 tweede verdieping | 850 | 0.509602 | 21 | 0.0264978 | 2021
871880 | 892 | -25247.4 | Level : 02 tweede verdieping | 850 | 0.509602 | 21 | 0.0264978 | 2021
871912 | 892 | -25247.4 | Level : 02 tweede verdieping | 850 | 0.509602 | 21 | 0.0264978 | 2021
871944 | 892 | -25247.4 | Level : 02 tweede verdieping | 850 | 0.509602 | 21 | 0.0264978 | 2021
871976 | 892 | -25247.4 | Level : 02 tweede verdieping | 850 | 0.509602 | 21 | 0.0264978 | 2021
872040 | 892 | 44532.6 | Basic Wall : 21_WA_metselwerk_licht_100_gen_bdg | 850 | 0.509602 | 21 | 0.0264978 | 2021
872075 | 892 | 44532.6 | Basic Wall : 21_WA_metselwerk_licht_100_gen_bdg | 850 | 0.509602 | 21 | 0.0264978 | 2021
872801 | 892 | 44532.6 | Level : 02 tweede verdieping | 850 | 0.509602 | 21 | 0.0264978 | 2021
872834 | 892 | 44532.6 | Level : 02 tweede verdieping | 850 | 0.509602 | 21 | 0.0264978 | 2021
872867 | 892 | 44532.6 | Level : 02 tweede verdieping | 850 | 0.509602 | 21 | 0.0264978 | 2021
872900 | 892 | 44532.6 | Level : 02 tweede verdieping | 850 | 0.509602 | 21 | 0.0264978 | 2021
872933 | 892 | 44532.6 | Level : 02 tweede verdieping | 850 | 0.509602 | 21 | 0.0264978 | 2021
872966 | 892 | 44532.6 | Level : 02 tweede verdieping | 850 | 0.509602 | 21 | 0.0264978 | 2021
872999 | 892 | 44532.6 | Level : 02 tweede verdieping | 850 | 0.509602 | 21 | 0.0264978 | 2021
873032 | 892 | 44532.6 | Level : 02 tweede verdieping | 850 | 0.509602 | 21 | 0.0264978 | 2021
873065 | 892 | 44532.6 | Level : 02 tweede verdieping | 850 | 0.509602 | 21 | 0.0264978 | 2021
873098 | 892 | 44532.6 | Level : 02 tweede verdieping | 850 | 0.509602 | 21 | 0.0264978 | 2021
873409 | 892 | 44532.6 | Level : 02 tweede verdieping | 850 | 0.509602 | 21 | 0.0264978 | 2021
873459 | 892 | 44532.6 | Level : 02 tweede verdieping | 850 | 0.509602 | 21 | 0.0264978 | 2021
873490 | 892 | 44532.6 | Level : 02 tweede verdieping | 850 | 0.509602 | 21 | 0.0264978 | 2021
873521 | 892 | 44532.6 | Level : 02 tweede verdieping | 850 | 0.509602 | 21 | 0.0264978 | 2021
873552 | 892 | 44532.6 | Level : 02 tweede verdieping | 850 | 0.509602 | 21 | 0.0264978 | 2021
873583 | 892 | 44532.6 | Level : 02 tweede verdieping | 850 | 0.509602 | 21 | 0.0264978 | 2021
873614 | 892 | 44532.6 | Level : 02 tweede verdieping | 850 | 0.509602 | 21 | 0.0264978 | 2021
873645 | 892 | 44532.6 | Level : 02 tweede verdieping | 850 | 0.509602 | 21 | 0.0264978 | 2021
873676 | 892 | 44532.6 | Level : 02 tweede verdieping | 850 | 0.509602 | 21 | 0.0264978 | 2021
873707 | 892 | 44532.6 | Level : 02 tweede verdieping | 850 | 0.509602 | 21 | 0.0264978 | 2021
873738 | 892 | 44532.6 | Level : 02 tweede verdieping | 850 | 0.509602 | 21 | 0.0264978 | 2021
1847948 | 4906 | -22594.9 | Basic Wall : 22_WA_binnenwand_ms125 25-75-25 _gen_bdg | 4850 | 2.66913 | 28 | 0.145738 | 2028

# IfcWindow: NLRS_41_GM_WPB_spouwlat_isolatie_gen_bdg:187x38 + isolatie 126x200 (2)
In: 01 eerste verdieping
Type - ParameterTakesPrecedence: no; Sizeable: no; Material: n7_isolatie_Resol, 00_Hout_generiek
Type - Constraints - Default Elevation: 0 mm
Type - Materials and Finishes - materiaal: 00_Hout_generiek; materiaal isolatie: n7_isolatie_Resol
Type - Dimensions - spouwlat_ruimte_tbv_kierdichting: 0 mm; hoogte: 77 mm; isolatie_breedte: 126 mm; isolatie_diepte: 200 mm; spouwlat_breedte: 38 mm; spouwlat_diepte_incl_kierdichting: 187 mm
Type - Identity Data - Workset: Family : Generic Models : NLRS_41_GM_WPB_spouwlat_isolatie_gen_bdg; Assembly Code: 31.10; Assembly Description: buitenwandopeningen; niet gevuld, algemeen (verzamelniveau); Datum_Gewijzigd: 14-11-2012; Description: spouwlat; Model: LOD300; SmartRevit_Versie: 2014.1; Type Name: 187x38 + isolatie 126x200
Type - Other - Category: Generic Models; isolatie zichtbaar: yes; Family Name: NLRS_41_GM_WPB_spouwlat_isolatie_gen_bdg
OverallHeight: 200 mm; OverallWidth: 1995 mm; Classification: 31.10 Uniformat (Uniformat)
Constraints - Moves With Nearby Elements: no; Level: 01 eerste verdieping; Elevation from Level: -31681.3 mm; Host: Level : 01 eerste verdieping; lengte: 1771 mm; Offset from Host: -31681.3 mm
Phasing - Phase Created: 2. nieuwbouw
Graphics - hoek_a: 0 deg; hoek_b: 0 deg
Dimensions - Area: 1.13155 m2; element_lengte: 1995 mm; verlenging_a: 112 mm; verlenging_b: 112 mm; Volume: 0.0644505 m3
Identity Data - Workset: Workset1
Other - berekende_hoek_a: 0 deg; berekende_overstek_a: 0 mm; berekende_overstek_b: 0 mm; Family: NLRS_41_GM_WPB_spouwlat_isolatie_gen_bdg; berekende_verlenging_a: 2112 mm; berekende_verlenging_b: 2112 mm; Family and Type: NLRS_41_GM_WPB_spouwlat_isolatie_gen_bdg: 187x38 + isolatie 126x200; Type: 187x38 + isolatie 126x200; Type Id: 3931312
Name (NLRS_41_GM_WPB_spouwlat_isolatie_gen_bdg:187x38 + isolatie 126x200:...)
891939
2749543

# IfcWindow: NLRS_41_GM_WPB_spouwlat_isolatie_gen_bdg:187x38 + isolatie 127x200 (27)
Type - ParameterTakesPrecedence: no; Sizeable: no; Material: n7_isolatie_Resol, 00_Hout_generiek
Type - Constraints - Default Elevation: 0 mm
Type - Materials and Finishes - materiaal: 00_Hout_generiek; materiaal isolatie: n7_isolatie_Resol
Type - Dimensions - spouwlat_ruimte_tbv_kierdichting: 0 mm; hoogte: 77 mm; isolatie_breedte: 127 mm; isolatie_diepte: 200 mm; spouwlat_breedte: 38 mm; spouwlat_diepte_incl_kierdichting: 187 mm
Type - Identity Data - Workset: Family : Generic Models : NLRS_41_GM_WPB_spouwlat_isolatie_gen_bdg; Assembly Code: 31.10; Assembly Description: buitenwandopeningen; niet gevuld, algemeen (verzamelniveau); Datum_Gewijzigd: 14-11-2012; Description: spouwlat; Model: LOD300; SmartRevit_Versie: 2014.1; Type Name: 187x38 + isolatie 127x200
Type - Other - Category: Generic Models; isolatie zichtbaar: yes; Family Name: NLRS_41_GM_WPB_spouwlat_isolatie_gen_bdg
OverallHeight: 200 mm; Classification: 31.10 Uniformat (Uniformat)
Constraints - Moves With Nearby Elements: no
Phasing - Phase Created: 2. nieuwbouw
Graphics - hoek_a: 0 deg; hoek_b: 0 deg
Identity Data - Workset: Workset1
Other - berekende_hoek_a: 0 deg; berekende_overstek_a: 0 mm; berekende_overstek_b: 0 mm; Family: NLRS_41_GM_WPB_spouwlat_isolatie_gen_bdg; Family and Type: NLRS_41_GM_WPB_spouwlat_isolatie_gen_bdg: 187x38 + isolatie 127x200; Type: 187x38 + isolatie 127x200; Type Id: 2352022
Name (NLRS_41_GM_WPB_spouwlat_isolatie_gen_bdg:187x38 + isolatie 127x200:...) | In | OverallWidth (mm) = element_lengte (mm) | Level | Elevation from Level (mm) = Offset from Host (mm) | Host | lengte (mm) | Area (m2) | verlenging_a (mm) | verlenging_b (mm) | Volume (m3) | berekende_verlenging_a (mm) | berekende_verlenging_b (mm)
880829 | 01 eerste verdieping | 1995 | 01 eerste verdieping | -2907.36 | Basic Wall : NLRS_22_WA_HSB bispouw 30-245-12-13 glaswol_gen_ISR | 1771 | 1.13375 | 112 | 112 | 0.0648495 | 2112 | 2112
881597 | 01 eerste verdieping | 1995 | 01 eerste verdieping | -2907.36 | Level : 01 eerste verdieping | 1771 | 1.13375 | 112 | 112 | 0.0648495 | 2112 | 2112
897884 | 00 begane grond | 1856 | 00 begane grond | 12392.6 | Basic Wall : NLRS_22_WA_HSB bispouw 30-245-12-13 glaswol_gen_ISR | 1800 | 1.05702 | 28 | 28 | 0.0603311 | 2028 | 2028
897937 | 00 begane grond | 956 | 00 begane grond | 12392.6 | Basic Wall : NLRS_22_WA_HSB bispouw 30-245-12-13 glaswol_gen_ISR | 900 | 0.560218 | 28 | 28 | 0.0310757 | 2028 | 2028
898545 | 00 begane grond | 2156 | 00 begane grond | 12392.6 | Basic Wall : NLRS_22_WA_HSB bispouw 30-245-12-13 glaswol_gen_ISR | 2100 | 1.22262 | 28 | 28 | 0.0700829 | 2028 | 2028
898557 | 00 begane grond | 1556 | 00 begane grond | 12392.6 | Basic Wall : NLRS_22_WA_HSB bispouw 30-245-12-13 glaswol_gen_ISR | 1500 | 0.891418 | 28 | 28 | 0.0505793 | 2028 | 2028
1219783 | 00 begane grond | 1856 | 00 begane grond | 12392.6 | Basic Wall : NLRS_22_WA_HSB bispouw 30-245-12-13 glaswol_gen_ISR | 1800 | 1.05702 | 28 | 28 | 0.0603311 | 2028 | 2028
1220533 | 00 begane grond | 3056 | 00 begane grond | 12392.6 | Basic Wall : NLRS_22_WA_HSB bispouw 30-245-12-13 glaswol_gen_ISR | 3000 | 1.71942 | 28 | 28 | 0.0993383 | 2028 | 2028
1221367 | 00 begane grond | 956 | 00 begane grond | 12392.6 | Basic Wall : NLRS_22_WA_HSB bispouw 30-245-12-13 glaswol_gen_ISR | 900 | 0.560218 | 28 | 28 | 0.0310757 | 2028 | 2028
1221378 | 00 begane grond | 3022 | 00 begane grond | 12392.6 | Basic Wall : NLRS_22_WA_HSB bispouw 30-245-12-13 glaswol_gen_ISR | 2966 | 1.70065 | 28 | 28 | 0.0982331 | 2028 | 2028
1221599 | 00 begane grond | 3356 | 00 begane grond | 12392.6 | Basic Wall : NLRS_22_WA_HSB bispouw 30-245-12-13 glaswol_gen_ISR | 3300 | 1.88502 | 28 | 28 | 0.10909 | 2028 | 2028
1222354 | 00 begane grond | 956 | 00 begane grond | 12392.6 | Basic Wall : NLRS_22_WA_HSB bispouw 30-245-12-13 glaswol_gen_ISR | 900 | 0.560218 | 28 | 28 | 0.0310757 | 2028 | 2028
1222796 | 00 begane grond | 956 | 00 begane grond | 12392.6 | Basic Wall : NLRS_22_WA_HSB bispouw 30-245-12-13 glaswol_gen_ISR | 900 | 0.560218 | 28 | 28 | 0.0310757 | 2028 | 2028
1223373 | 00 begane grond | 2756 | 00 begane grond | 12392.6 | Basic Wall : NLRS_22_WA_HSB bispouw 30-245-12-13 glaswol_gen_ISR | 2700 | 1.55382 | 28 | 28 | 0.0895865 | 2028 | 2028
1224042 | 00 begane grond | 3011.5 | 00 begane grond | 12392.6 | Basic Wall : NLRS_22_WA_HSB bispouw 30-245-12-13 glaswol_gen_ISR | 2955.5 | 1.69485 | 28 | 28 | 0.0978918 | 2028 | 2028
1224053 | 00 begane grond | 2305 | 00 begane grond | 12392.6 | Basic Wall : NLRS_22_WA_HSB bispouw 30-245-12-13 glaswol_gen_ISR | 2249 | 1.30487 | 28 | 28 | 0.0749263 | 2028 | 2028
1224161 | 00 begane grond | 4231 | 00 begane grond | 12392.6 | Basic Wall : NLRS_22_WA_HSB bispouw 30-245-12-13 glaswol_gen_ISR | 4175 | 2.36802 | 28 | 28 | 0.137533 | 2028 | 2028
1488570 | 00 begane grond | 3056 | 00 begane grond | -24594.9 | Basic Wall : 22_WA_binnenwand_ms125 25-75-25 _gen_bdg | 3000 | 1.71942 | 28 | 28 | 0.0993383 | 2028 | 2028
1492644 | 00 begane grond | 4231 | 00 begane grond | 36212.6 | Basic Wall : NLRS_22_WA_HSB bispouw 30-245-12-13 glaswol_gen_ISR | 4175 | 2.36802 | 28 | 28 | 0.137533 | 2028 | 2028
1493180 | 00 begane grond | 3056 | 00 begane grond | -7612.36 | Level : 00 begane grond | 3000 | 1.71942 | 28 | 28 | 0.0993383 | 2028 | 2028
1502429 | 00 begane grond | 3056 | 00 begane grond | -35582.4 | Level : 00 begane grond | 3000 | 1.71942 | 28 | 28 | 0.0993383 | 2028 | 2028
1502788 | 00 begane grond | 3056 | 00 begane grond | -35582.4 | Level : 00 begane grond | 3000 | 1.71942 | 28 | 28 | 0.0993383 | 2028 | 2028
1503069 | 00 begane grond | 956 | 00 begane grond | -78982.4 | Level : 00 begane grond | 900 | 0.560218 | 28 | 28 | 0.0310757 | 2028 | 2028
1503711 | 00 begane grond | 4231 | 00 begane grond | -78982.4 | Level : 00 begane grond | 4175 | 2.36802 | 28 | 28 | 0.137533 | 2028 | 2028
1818653 | 00 begane grond | 5056 | 00 begane grond | -8684.36 | Basic Wall : NLRS_22_WA_HSB bispouw 30-245-12-13 glaswol_gen_ISR | 5000 | 2.82342 | 28 | 28 | 0.16435 | 2028 | 2028
1822617 | 00 begane grond | 4231 | 00 begane grond | -5937.36 | Basic Wall : NLRS_22_WA_HSB bispouw 30-245-12-13 glaswol_gen_ISR | 4175 | 2.36802 | 28 | 28 | 0.137533 | 2028 | 2028
4343091 | 01 eerste verdieping | 1538 | 01 eerste verdieping | -2907.36 | Level : 01 eerste verdieping | 1398 | 0.881482 | 112 | 28 | 0.0499942 | 2112 | 2028

# IfcWindow: NLRS_41_GM_WPB_spouwlat_isolatie_gen_bdg:187x38 + isolatie 156x200 (42)
In: 01 eerste verdieping
Type - ParameterTakesPrecedence: no; Sizeable: no; Material: n7_isolatie_Resol, 00_Hout_generiek
Type - Constraints - Default Elevation: 0 mm
Type - Materials and Finishes - materiaal: 00_Hout_generiek; materiaal isolatie: n7_isolatie_Resol
Type - Dimensions - hoogte: 77 mm; isolatie_breedte: 156 mm; isolatie_diepte: 200 mm; spouwlat_breedte: 38 mm; spouwlat_diepte_incl_kierdichting: 187 mm; spouwlat_ruimte_tbv_kierdichting: 0 mm
Type - Identity Data - Assembly Code: 31.10; Assembly Description: buitenwandopeningen; niet gevuld, algemeen (verzamelniveau); Datum_Gewijzigd: 14-11-2012; Description: spouwlat; Model: LOD300; SmartRevit_Versie: 2014.1; Type Name: 187x38 + isolatie 156x200; Workset: Family : Generic Models : NLRS_41_GM_WPB_spouwlat_isolatie_gen_bdg
Type - Other - Category: Generic Models; Family Name: NLRS_41_GM_WPB_spouwlat_isolatie_gen_bdg; isolatie zichtbaar: yes
OverallHeight: 200 mm; Classification: 31.10 Uniformat (Uniformat)
Constraints - Moves With Nearby Elements: no; Level: 01 eerste verdieping
Phasing - Phase Created: 2. nieuwbouw
Graphics - hoek_a: 0 deg; hoek_b: 0 deg
Dimensions - verlenging_a: 112 mm; verlenging_b: 112 mm
Identity Data - Workset: Workset1
Other - berekende_hoek_a: 0 deg; berekende_overstek_a: 0 mm; berekende_overstek_b: 0 mm; berekende_verlenging_a: 2112 mm; berekende_verlenging_b: 2112 mm; Family: NLRS_41_GM_WPB_spouwlat_isolatie_gen_bdg; Family and Type: NLRS_41_GM_WPB_spouwlat_isolatie_gen_bdg: 187x38 + isolatie 156x200; Type: 187x38 + isolatie 156x200; Type Id: 4804123
Name (NLRS_41_GM_WPB_spouwlat_isolatie_gen_bdg:187x38 + isolatie 156x200:...) | OverallWidth (mm) = element_lengte (mm) | Elevation from Level (mm) = Offset from Host (mm) | Host | lengte (mm) | Area (m2) | Volume (m3)
832752 | 1995 | 15817.6 | Basic Wall : NLRS_22_WA_HSB bispouw 30-245-12-13 glaswol_gen_ISR | 1771 | 1.1974 | 0.0764205
858912 | 1995 | 15817.6 | Level : 01 eerste verdieping | 1771 | 1.1974 | 0.0764205
858938 | 1995 | 15817.6 | Level : 01 eerste verdieping | 1771 | 1.1974 | 0.0764205
874904 | 1995 | 15817.6 | Level : 01 eerste verdieping | 1771 | 1.1974 | 0.0764205
874916 | 1995 | 15817.6 | Level : 01 eerste verdieping | 1771 | 1.1974 | 0.0764205
874928 | 1995 | 15817.6 | Level : 01 eerste verdieping | 1771 | 1.1974 | 0.0764205
874994 | 1995 | 15817.6 | Level : 01 eerste verdieping | 1771 | 1.1974 | 0.0764205
875006 | 1995 | 15817.6 | Level : 01 eerste verdieping | 1771 | 1.1974 | 0.0764205
875018 | 1995 | 15817.6 | Level : 01 eerste verdieping | 1771 | 1.1974 | 0.0764205
875223 | 1995 | 15817.6 | Level : 01 eerste verdieping | 1771 | 1.1974 | 0.0764205
875259 | 1995 | 15817.6 | Level : 01 eerste verdieping | 1771 | 1.1974 | 0.0764205
875295 | 1995 | 15817.6 | Level : 01 eerste verdieping | 1771 | 1.1974 | 0.0764205
875331 | 1995 | 15817.6 | Level : 01 eerste verdieping | 1771 | 1.1974 | 0.0764205
875367 | 1995 | 15817.6 | Level : 01 eerste verdieping | 1771 | 1.1974 | 0.0764205
876532 | 1995 | -28997.4 | Level : 01 eerste verdieping | 1771 | 1.1974 | 0.0764205
876769 | 1995 | -28997.4 | Level : 01 eerste verdieping | 1771 | 1.1974 | 0.0764205
876788 | 1995 | -28997.4 | Level : 01 eerste verdieping | 1771 | 1.1974 | 0.0764205
876934 | 1995 | -28997.4 | Level : 01 eerste verdieping | 1771 | 1.1974 | 0.0764205
876946 | 1995 | -28997.4 | Level : 01 eerste verdieping | 1771 | 1.1974 | 0.0764205
876958 | 1995 | -28997.4 | Level : 01 eerste verdieping | 1771 | 1.1974 | 0.0764205
877051 | 1995 | -28997.4 | Level : 01 eerste verdieping | 1771 | 1.1974 | 0.0764205
877063 | 1995 | -28997.4 | Level : 01 eerste verdieping | 1771 | 1.1974 | 0.0764205
877075 | 1995 | -28997.4 | Level : 01 eerste verdieping | 1771 | 1.1974 | 0.0764205
877141 | 1995 | -28997.4 | Level : 01 eerste verdieping | 1771 | 1.1974 | 0.0764205
877153 | 1995 | -28997.4 | Level : 01 eerste verdieping | 1771 | 1.1974 | 0.0764205
877165 | 1995 | -28997.4 | Level : 01 eerste verdieping | 1771 | 1.1974 | 0.0764205
877231 | 1995 | -28997.4 | Level : 01 eerste verdieping | 1771 | 1.1974 | 0.0764205
877243 | 1995 | -28997.4 | Level : 01 eerste verdieping | 1771 | 1.1974 | 0.0764205
881633 | 1995 | -2907.36 | Level : 01 eerste verdieping | 1771 | 1.1974 | 0.0764205
881669 | 1995 | -2907.36 | Level : 01 eerste verdieping | 1771 | 1.1974 | 0.0764205
881745 | 1995 | -2907.36 | Level : 01 eerste verdieping | 1771 | 1.1974 | 0.0764205
881772 | 1995 | -2907.36 | Level : 01 eerste verdieping | 1771 | 1.1974 | 0.0764205
891644 | 1995 | -2907.36 | Level : 01 eerste verdieping | 1771 | 1.1974 | 0.0764205
891666 | 1995 | -2907.36 | Level : 01 eerste verdieping | 1771 | 1.1974 | 0.0764205
891688 | 1995 | -2907.36 | Level : 01 eerste verdieping | 1771 | 1.1974 | 0.0764205
891710 | 1995 | -2907.36 | Level : 01 eerste verdieping | 1771 | 1.1974 | 0.0764205
891750 | 1995 | -31681.3 | Basic Wall : 21_WA_metselwerk_licht_100_gen_bdg | 1771 | 1.1974 | 0.0764205
891778 | 1995 | -31681.3 | Level : 01 eerste verdieping | 1771 | 1.1974 | 0.0764205
891895 | 1995 | -31681.3 | Level : 01 eerste verdieping | 1771 | 1.1974 | 0.0764205
891917 | 1995 | -31681.3 | Level : 01 eerste verdieping | 1771 | 1.1974 | 0.0764205
891967 | 1995 | -31681.3 | Level : 01 eerste verdieping | 1771 | 1.1974 | 0.0764205
2749759 | 800 | 15817.6 | Level : 01 eerste verdieping | 576 | 0.503106 | 0.0306448

# IfcWindow: NLRS_41_GM_WPB_spouwlat_isolatie_gen_bdg:187x38 + isolatie 225x180, NLRS_41_GM_WPB_spouwlat_isolatie_gen_bdg:187x38 + isolatie 225x180:2786085
In: 00 begane grond
Type - ParameterTakesPrecedence: no; Sizeable: no; Material: n7_isolatie_Resol, 00_Hout_generiek
Type - Constraints - Default Elevation: 0 mm
Type - Materials and Finishes - materiaal: 00_Hout_generiek; materiaal isolatie: n7_isolatie_Resol
Type - Dimensions - spouwlat_ruimte_tbv_kierdichting: 0 mm; hoogte: 77 mm; isolatie_breedte: 225 mm; isolatie_diepte: 180 mm; spouwlat_breedte: 38 mm; spouwlat_diepte_incl_kierdichting: 187 mm
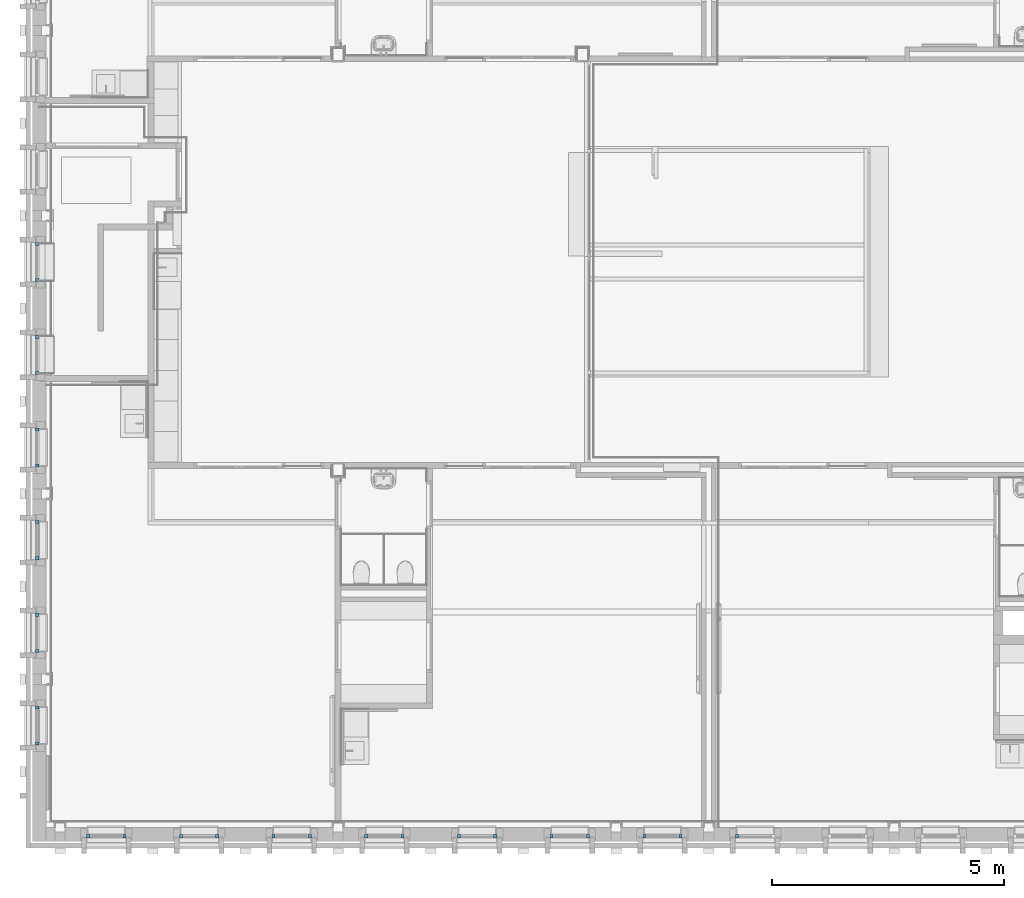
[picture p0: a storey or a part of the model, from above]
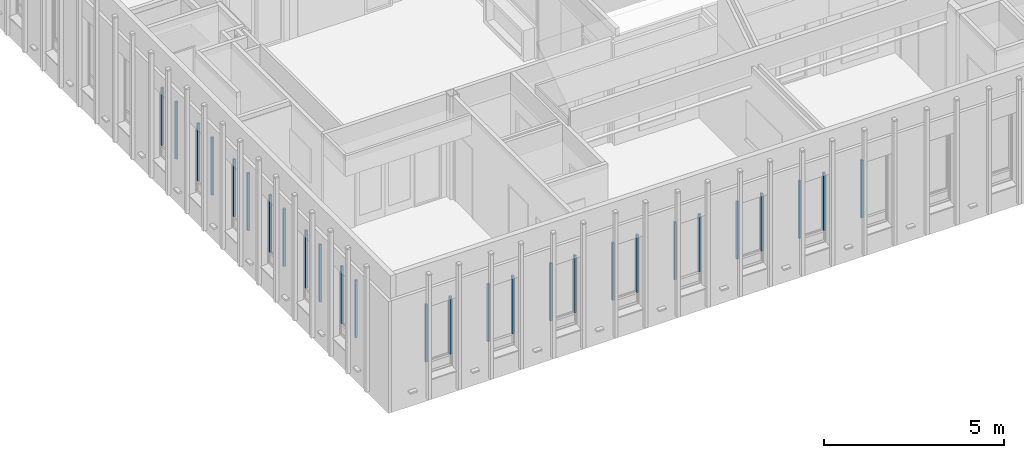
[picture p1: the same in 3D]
Properties of the parts of a building model (IFC2X3), part 94 of 94

# IfcWindow: NLRS_41_GM_WPB_spouwlat_isolatie_gen_bdg:187x38 + isolatie 225x180, NLRS_41_GM_WPB_spouwlat_isolatie_gen_bdg:187x38 + isolatie 225x180:2786085
Type - Identity Data - Workset: Family : Generic Models : NLRS_41_GM_WPB_spouwlat_isolatie_gen_bdg; Assembly Code: 31.10; Assembly Description: buitenwandopeningen; niet gevuld, algemeen (verzamelniveau); Datum_Gewijzigd: 14-11-2012; Description: spouwlat; Model: LOD300; SmartRevit_Versie: 2014.1; Type Name: 187x38 + isolatie 225x180
Type - Other - Category: Generic Models; isolatie zichtbaar: yes; Family Name: NLRS_41_GM_WPB_spouwlat_isolatie_gen_bdg
OverallHeight: 187 mm; OverallWidth: 3008 mm; Classification: 31.10 Uniformat (Uniformat)
Constraints - Level: 00 begane grond; Moves With Nearby Elements: no; Elevation from Level: -8635.36 mm; Host: Basic Wall : NLRS_22_WA_HSB bispouw 30-245-12-13 glaswol_gen_ISR; lengte: 3008 mm; Offset from Host: -8635.36 mm
Phasing - Phase Created: 2. nieuwbouw
Graphics - hoek_a: 0 deg; hoek_b: 0 deg
Dimensions - Area: 1.92123 m2; element_lengte: 2974 mm; verlenging_a: -17 mm; verlenging_b: -17 mm; Volume: 0.14158 m3
Identity Data - Workset: Workset1
Other - berekende_hoek_a: 0 deg; berekende_overstek_a: 0 mm; berekende_overstek_b: 0 mm; Family: NLRS_41_GM_WPB_spouwlat_isolatie_gen_bdg; berekende_verlenging_a: 1983 mm; berekende_verlenging_b: 1983 mm; Family and Type: NLRS_41_GM_WPB_spouwlat_isolatie_gen_bdg: 187x38 + isolatie 225x180; Type: 187x38 + isolatie 225x180; Type Id: 3704336

# IfcWindow: NLRS_41_GM_WPB_spouwlat_isolatie_gen_bdg:187x38 + isolatie 60x180 (2)
In: 00 begane grond
Type - ParameterTakesPrecedence: no; Sizeable: no; Material: n7_isolatie_Resol, 00_Hout_generiek
Type - Constraints - Default Elevation: 0 mm
Type - Materials and Finishes - materiaal: 00_Hout_generiek; materiaal isolatie: n7_isolatie_Resol
Type - Dimensions - spouwlat_ruimte_tbv_kierdichting: 0 mm; hoogte: 77 mm; isolatie_breedte: 60 mm; isolatie_diepte: 180 mm; spouwlat_breedte: 38 mm; spouwlat_diepte_incl_kierdichting: 187 mm
Type - Identity Data - Workset: Family : Generic Models : NLRS_41_GM_WPB_spouwlat_isolatie_gen_bdg; Assembly Code: 31.10; Assembly Description: buitenwandopeningen; niet gevuld, algemeen (verzamelniveau); Datum_Gewijzigd: 14-11-2012; Description: spouwlat; Model: LOD300; SmartRevit_Versie: 2014.1; Type Name: 187x38 + isolatie 60x180
Type - Other - Category: Generic Models; isolatie zichtbaar: yes; Family Name: NLRS_41_GM_WPB_spouwlat_isolatie_gen_bdg
OverallHeight: 187 mm; OverallWidth: 3008 mm; Classification: 31.10 Uniformat (Uniformat)
Constraints - Level: 00 begane grond; Moves With Nearby Elements: no; Host: Basic Wall : NLRS_22_WA_HSB bispouw 30-245-12-13 glaswol_gen_ISR; lengte: 3008 mm
Phasing - Phase Created: 2. nieuwbouw
Graphics - hoek_a: 0 deg; hoek_b: 0 deg
Dimensions - Area: 1.40082 m2; element_lengte: 2974 mm; verlenging_a: -17 mm; verlenging_b: -17 mm; Volume: 0.0532524 m3
Identity Data - Workset: Workset1
Other - berekende_hoek_a: 0 deg; berekende_overstek_a: 0 mm; berekende_overstek_b: 0 mm; Family: NLRS_41_GM_WPB_spouwlat_isolatie_gen_bdg; berekende_verlenging_a: 1983 mm; berekende_verlenging_b: 1983 mm; Family and Type: NLRS_41_GM_WPB_spouwlat_isolatie_gen_bdg: 187x38 + isolatie 60x180; Type: 187x38 + isolatie 60x180; Type Id: 2786985
Name (NLRS_41_GM_WPB_spouwlat_isolatie_gen_bdg:187x38 + isolatie 60x180:...) | Elevation from Level (mm) = Offset from Host (mm)
1224054 | 25879.6
1818654 | -8999.7

# IfcWindow: NLRS_41_GM_WPB_spouwlat_isolatie_gen_bdg:187x38 + isolatie 93.5x187 (99)
In: 01 eerste verdieping
Type - ParameterTakesPrecedence: no; Sizeable: no; Material: n7_isolatie_Resol, 00_Hout_generiek
Type - Constraints - Default Elevation: 0 mm
Type - Materials and Finishes - materiaal: 00_Hout_generiek; materiaal isolatie: n7_isolatie_Resol
Type - Dimensions - spouwlat_ruimte_tbv_kierdichting: 0 mm; hoogte: 77 mm; isolatie_breedte: 93.5 mm; isolatie_diepte: 187 mm; spouwlat_breedte: 38 mm; spouwlat_diepte_incl_kierdichting: 187 mm
Type - Identity Data - Workset: Family : Generic Models : NLRS_41_GM_WPB_spouwlat_isolatie_gen_bdg; Assembly Code: 31.10; Assembly Description: buitenwandopeningen; niet gevuld, algemeen (verzamelniveau); Datum_Gewijzigd: 14-11-2012; Description: spouwlat; Model: LOD300; SmartRevit_Versie: 2014.1; Type Name: 187x38 + isolatie 93.5x187
Type - Other - Category: Generic Models; isolatie zichtbaar: yes; Family Name: NLRS_41_GM_WPB_spouwlat_isolatie_gen_bdg
OverallHeight: 187 mm; Classification: 31.10 Uniformat (Uniformat)
Constraints - Moves With Nearby Elements: no; Level: 01 eerste verdieping
Phasing - Phase Created: 2. nieuwbouw
Graphics - hoek_a: 0 deg; hoek_b: 0 deg
Dimensions - verlenging_a: -17 mm; verlenging_b: -17 mm
Identity Data - Workset: Workset1
Other - berekende_hoek_a: 0 deg; berekende_overstek_a: 0 mm; berekende_overstek_b: 0 mm; Family: NLRS_41_GM_WPB_spouwlat_isolatie_gen_bdg; berekende_verlenging_a: 1983 mm; berekende_verlenging_b: 1983 mm; Family and Type: NLRS_41_GM_WPB_spouwlat_isolatie_gen_bdg: 187x38 + isolatie 93.5x187; Type: 187x38 + isolatie 93.5x187; Type Id: 3476186
Name (NLRS_41_GM_WPB_spouwlat_isolatie_gen_bdg:187x38 + isolatie 93.5x187:...) | OverallWidth (mm) = lengte (mm) | Elevation from Level (mm) = Offset from Host (mm) | Host | Area (m2) | element_lengte (mm) | Volume (m3)
832753 | 2020 | 27324.6 | Basic Wall : NLRS_22_WA_HSB bispouw 30-245-12-13 glaswol_gen_ISR | 1.02851 | 1986 | 0.0488367
832754 | 2020 | -16405.4 | Basic Wall : NLRS_22_WA_HSB bispouw 30-245-12-13 glaswol_gen_ISR | 1.02851 | 1986 | 0.0488367
858913 | 2020 | 27324.6 | Level : 01 eerste verdieping | 1.02851 | 1986 | 0.0488367
858914 | 2020 | -16405.4 | Level : 01 eerste verdieping | 1.02851 | 1986 | 0.0488367
858939 | 2020 | 27324.6 | Level : 01 eerste verdieping | 1.02851 | 1986 | 0.0488367
858940 | 2020 | -16405.4 | Level : 01 eerste verdieping | 1.02851 | 1986 | 0.0488367
874905 | 2020 | 27324.6 | Level : 01 eerste verdieping | 1.02851 | 1986 | 0.0488367
874906 | 2020 | -16405.4 | Level : 01 eerste verdieping | 1.02851 | 1986 | 0.0488367
874917 | 2020 | 27324.6 | Level : 01 eerste verdieping | 1.02851 | 1986 | 0.0488367
874918 | 2020 | -16405.4 | Level : 01 eerste verdieping | 1.02851 | 1986 | 0.0488367
874929 | 2020 | 27324.6 | Level : 01 eerste verdieping | 1.02851 | 1986 | 0.0488367
874930 | 2020 | -16405.4 | Level : 01 eerste verdieping | 1.02851 | 1986 | 0.0488367
874995 | 2020 | 27324.6 | Level : 01 eerste verdieping | 1.02851 | 1986 | 0.0488367
874996 | 2020 | -16405.4 | Level : 01 eerste verdieping | 1.02851 | 1986 | 0.0488367
875007 | 2020 | 27324.6 | Level : 01 eerste verdieping | 1.02851 | 1986 | 0.0488367
875008 | 2020 | -16405.4 | Level : 01 eerste verdieping | 1.02851 | 1986 | 0.0488367
875019 | 2020 | 27324.6 | Level : 01 eerste verdieping | 1.02851 | 1986 | 0.0488367
875020 | 2020 | -16405.4 | Level : 01 eerste verdieping | 1.02851 | 1986 | 0.0488367
875224 | 2020 | 27324.6 | Level : 01 eerste verdieping | 1.02851 | 1986 | 0.0488367
875225 | 2020 | -16405.4 | Level : 01 eerste verdieping | 1.02851 | 1986 | 0.0488367
875260 | 2020 | 27324.6 | Level : 01 eerste verdieping | 1.02851 | 1986 | 0.0488367
875261 | 2020 | -16405.4 | Level : 01 eerste verdieping | 1.02851 | 1986 | 0.0488367
875296 | 2020 | 27324.6 | Level : 01 eerste verdieping | 1.02851 | 1986 | 0.0488367
875297 | 2020 | -16405.4 | Level : 01 eerste verdieping | 1.02851 | 1986 | 0.0488367
875332 | 2020 | 27324.6 | Level : 01 eerste verdieping | 1.02851 | 1986 | 0.0488367
875333 | 2020 | -16405.4 | Level : 01 eerste verdieping | 1.02851 | 1986 | 0.0488367
875368 | 2020 | 27324.6 | Level : 01 eerste verdieping | 1.02851 | 1986 | 0.0488367
875369 | 2020 | -16405.4 | Level : 01 eerste verdieping | 1.02851 | 1986 | 0.0488367
876533 | 2020 | -17895.4 | Level : 01 eerste verdieping | 1.02851 | 1986 | 0.0488367
876534 | 2020 | 28814.6 | Level : 01 eerste verdieping | 1.02851 | 1986 | 0.0488367
876770 | 2020 | -17895.4 | Level : 01 eerste verdieping | 1.02851 | 1986 | 0.0488367
876771 | 2020 | 28814.6 | Level : 01 eerste verdieping | 1.02851 | 1986 | 0.0488367
876789 | 2020 | -17895.4 | Level : 01 eerste verdieping | 1.02851 | 1986 | 0.0488367
876790 | 2020 | 28814.6 | Level : 01 eerste verdieping | 1.02851 | 1986 | 0.0488367
876935 | 2020 | -17895.4 | Level : 01 eerste verdieping | 1.02851 | 1986 | 0.0488367
876936 | 2020 | 28814.6 | Level : 01 eerste verdieping | 1.02851 | 1986 | 0.0488367
876947 | 2020 | -17895.4 | Level : 01 eerste verdieping | 1.02851 | 1986 | 0.0488367
876948 | 2020 | 28814.6 | Level : 01 eerste verdieping | 1.02851 | 1986 | 0.0488367
876959 | 2020 | -17895.4 | Level : 01 eerste verdieping | 1.02851 | 1986 | 0.0488367
876960 | 2020 | 28814.6 | Level : 01 eerste verdieping | 1.02851 | 1986 | 0.0488367
877052 | 2020 | -17895.4 | Level : 01 eerste verdieping | 1.02851 | 1986 | 0.0488367
877053 | 2020 | 28814.6 | Level : 01 eerste verdieping | 1.02851 | 1986 | 0.0488367
877064 | 2020 | -17895.4 | Level : 01 eerste verdieping | 1.02851 | 1986 | 0.0488367
877065 | 2020 | 28814.6 | Level : 01 eerste verdieping | 1.02851 | 1986 | 0.0488367
877076 | 2020 | -17895.4 | Level : 01 eerste verdieping | 1.02851 | 1986 | 0.0488367
877077 | 2020 | 28814.6 | Level : 01 eerste verdieping | 1.02851 | 1986 | 0.0488367
877142 | 2020 | -17895.4 | Level : 01 eerste verdieping | 1.02851 | 1986 | 0.0488367
877143 | 2020 | 28814.6 | Level : 01 eerste verdieping | 1.02851 | 1986 | 0.0488367
877154 | 2020 | -17895.4 | Level : 01 eerste verdieping | 1.02851 | 1986 | 0.0488367
877155 | 2020 | 28814.6 | Level : 01 eerste verdieping | 1.02851 | 1986 | 0.0488367
877166 | 2020 | -17895.4 | Level : 01 eerste verdieping | 1.02851 | 1986 | 0.0488367
877167 | 2020 | 28814.6 | Level : 01 eerste verdieping | 1.02851 | 1986 | 0.0488367
877232 | 2020 | -17895.4 | Level : 01 eerste verdieping | 1.02851 | 1986 | 0.0488367
877233 | 2020 | 28814.6 | Level : 01 eerste verdieping | 1.02851 | 1986 | 0.0488367
877244 | 2020 | -17895.4 | Level : 01 eerste verdieping | 1.02851 | 1986 | 0.0488367
877245 | 2020 | 28814.6 | Level : 01 eerste verdieping | 1.02851 | 1986 | 0.0488367
880830 | 2020 | 38857.1 | Basic Wall : NLRS_22_WA_HSB bispouw 30-245-12-13 glaswol_gen_ISR | 1.02851 | 1986 | 0.0488367
880831 | 2020 | -26937.8 | Basic Wall : NLRS_22_WA_HSB bispouw 30-245-12-13 glaswol_gen_ISR | 1.02851 | 1986 | 0.0488367
881598 | 2020 | 38857.1 | Level : 01 eerste verdieping | 1.02851 | 1986 | 0.0488367
881599 | 2020 | -26937.8 | Level : 01 eerste verdieping | 1.02851 | 1986 | 0.0488367
881634 | 1970 | 38857.1 | Level : 01 eerste verdieping | 1.00324 | 1936 | 0.0476072
881635 | 1970 | -26937.8 | Level : 01 eerste verdieping | 1.00324 | 1936 | 0.0476072
881670 | 2020 | 38857.1 | Level : 01 eerste verdieping | 1.02851 | 1986 | 0.0488367
881671 | 2020 | -26937.8 | Level : 01 eerste verdieping | 1.02851 | 1986 | 0.0488367
881746 | 2020 | 38857.1 | Level : 01 eerste verdieping | 1.02851 | 1986 | 0.0488367
881747 | 2020 | -26937.8 | Level : 01 eerste verdieping | 1.02851 | 1986 | 0.0488367
881773 | 2020 | 38857.1 | Level : 01 eerste verdieping | 1.02851 | 1986 | 0.0488367
881774 | 2020 | -26937.8 | Level : 01 eerste verdieping | 1.02851 | 1986 | 0.0488367
891623 | 2020 | 38857.1 | Level : 01 eerste verdieping | 1.02851 | 1986 | 0.0488367
891645 | 2020 | 38857.1 | Level : 01 eerste verdieping | 1.02851 | 1986 | 0.0488367
891646 | 2020 | -26937.8 | Level : 01 eerste verdieping | 1.02851 | 1986 | 0.0488367
891667 | 2020 | 38857.1 | Level : 01 eerste verdieping | 1.02851 | 1986 | 0.0488367
891668 | 2020 | -26937.8 | Level : 01 eerste verdieping | 1.02851 | 1986 | 0.0488367
891689 | 2020 | 38857.1 | Level : 01 eerste verdieping | 1.02851 | 1986 | 0.0488367
891690 | 2020 | -26937.8 | Level : 01 eerste verdieping | 1.02851 | 1986 | 0.0488367
891711 | 2020 | 38857.1 | Level : 01 eerste verdieping | 1.02851 | 1986 | 0.0488367
891712 | 2020 | -26937.8 | Level : 01 eerste verdieping | 1.02851 | 1986 | 0.0488367
891751 | 2020 | 17941.4 | Basic Wall : 21_WA_metselwerk_licht_100_gen_bdg | 1.02851 | 1986 | 0.0488367
891752 | 2020 | -3289.98 | Basic Wall : 21_WA_metselwerk_licht_100_gen_bdg | 1.02851 | 1986 | 0.0488367
891779 | 2020 | 17941.4 | Level : 01 eerste verdieping | 1.02851 | 1986 | 0.0488367
891780 | 2020 | -3289.98 | Level : 01 eerste verdieping | 1.02851 | 1986 | 0.0488367
891896 | 2020 | 17941.4 | Level : 01 eerste verdieping | 1.02851 | 1986 | 0.0488367
891897 | 2020 | -3289.98 | Level : 01 eerste verdieping | 1.02851 | 1986 | 0.0488367
891918 | 2020 | 17941.4 | Level : 01 eerste verdieping | 1.02851 | 1986 | 0.0488367
891919 | 2020 | -3289.98 | Level : 01 eerste verdieping | 1.02851 | 1986 | 0.0488367
891940 | 2622 | 17941.4 | Level : 01 eerste verdieping | 1.33282 | 2588 | 0.0636402
891941 | 2622 | -3289.98 | Level : 01 eerste verdieping | 1.33282 | 2588 | 0.0636402
891968 | 2020 | 17941.4 | Level : 01 eerste verdieping | 1.02851 | 1986 | 0.0488367
891969 | 2020 | -3289.98 | Level : 01 eerste verdieping | 1.02851 | 1986 | 0.0488367
2239348 | 2020 | 17941.4 | Level : 01 eerste verdieping | 1.02851 | 1986 | 0.0488367
2239385 | 2020 | 44944.9 | Basic Wall : NLRS_22_WA_HSB bispouw 30-245-12-13 glaswol_gen_ISR | 1.02851 | 1986 | 0.0488367
2239479 | 2020 | 40098.5 | Basic Wall : NLRS_22_WA_HSB bispouw 30-245-12-13 glaswol_gen_ISR | 1.02851 | 1986 | 0.0488367
2239497 | 2020 | -4355.36 | Basic Wall : NLRS_22_WA_HSB bispouw 30-245-12-13 glaswol_gen_ISR | 1.02851 | 1986 | 0.0488367
2749544 | 2608 | 17941.4 | Level : 01 eerste verdieping | 1.32575 | 2574 | 0.0632959
2749545 | 2608 | -3289.98 | Level : 01 eerste verdieping | 1.32575 | 2574 | 0.0632959
2749760 | 2020 | 27324.6 | Level : 01 eerste verdieping | 1.02851 | 1986 | 0.0488367
2759481 | 2020 | -5115.36 | Basic Wall : 22_WA_binnenwand_ms125 25-75-25 _gen_bdg | 1.02851 | 1986 | 0.0488367
2762377 | 2020 | -4701.86 | Basic Wall : 22_WA_koof_96 12-12-50 | 1.02851 | 1986 | 0.0488367
4343092 | 2020 | 38857.1 | Level : 01 eerste verdieping | 1.02851 | 1986 | 0.0488367

# IfcWindow: WI_subvak:RVS kabelnet (5)
In: 01 eerste verdieping
Type - ParameterTakesPrecedence: no; Sizeable: no; Material: ISR_RVS_Carlstahl
Type - Analytical Properties - Define Thermal Properties by: Schematic Type; Analytic Construction: <None>
Type - General - VentilationType: ventilatierooster : Type 1
Type - Materials and Finishes - FinishExteriorMaterial: ISR_RVS_Carlstahl
Type - Dimensions - VentilationHeight: 0 mm; decoratie_breedte: 30 mm; decoratie_diepte: 10 mm; Thickness: 2 mm
Type - Identity Data - Workset: Family : Windows : WI_subvak; Assembly Code: 31.11; Assembly Description: buitenwandopeningen; niet gevuld, daglichtopeningen; Description: enkel glas; Manufacturer: ITANNEX; Model: 01-05-2018; Type Comments: subvakken; Type Mark: 92; Type Name: RVS kabelnet; URL: www.bimvoorfabrikanten.nl
Type - Other - Category: Windows; Family Name: WI_subvak
OverallHeight: 2430 mm; Classification: 31.11 Uniformat (Uniformat)
Model Properties - subpaneel_1_roedes_hor: 0; subpaneel_1_roedes_ver: 0
Constraints - Moves With Nearby Elements: no; Level: 01 eerste verdieping; Host: Curtain Wall : 20_opening; Offset from Host: 40 mm
Phasing - Phase Created: 2. nieuwbouw
Dimensions - Height: 2350 mm; Rough Height: 2350 mm
Identity Data - Workset: Workset1
Other - CalcHorMultiple: no; CalcHorSingle: no; CalcVertMultiple: no; CalcVertSingle: no; Family: WI_subvak; SubPanel_1_h_Calc: 2; SubPanel_1_v_Calc: 2; Ventilation: no; CalcStartHor: 783.333 mm; CalcVentilationHeight: 80 mm; Family and Type: WI_subvak: RVS kabelnet; subpaneel_1_hoogte: 2350 mm; Type: RVS kabelnet; Type Id: 2757327
Name (WI_subvak:RVS kabelnet:...) | OverallWidth (mm) = Rough Width (mm) = Width (mm) | FrameExteriorMaterial = FrameInteriorMaterial | Area (m2) | Volume (m3) | Mark | CalcStartVert (mm)
2757107 | 777.5 | h2_staal_gen | 0.7542 | 0.0056295 | 663 | 259.167
2757126 | 777.5 | h2_staal_gen | 0.7542 | 0.0056295 | 667 | 259.167
2765844 | 777.5 | h2_staal_gen | 0.7542 | 0.0056295 | 687 | 259.167
2765846 | 567.5 | h2_staal_gen | 0.7038 | 0.0052515 | 689 | 189.167
2769529 | 740 |  | 0.7452 | 0.005562 | 701 | 246.667

# IfcWindow: WI_subvak:glas 2 (143)
Type - ParameterTakesPrecedence: no; Sizeable: no; Material: ISR_Glas
Type - Analytical Properties - Define Thermal Properties by: Schematic Type; Analytic Construction: <None>
Type - General - VentilationType: ventilatierooster : Type 1
Type - Dimensions - decoratie_breedte: 30 mm; decoratie_diepte: 10 mm; Thickness: 24 mm; VentilationHeight: 0 mm
Type - Identity Data - Assembly Code: 31.11; Assembly Description: buitenwandopeningen; niet gevuld, daglichtopeningen; Description: enkel glas + rooster; Manufacturer: ITANNEX; Model: 01-05-2018; Type Comments: subvakken; Type Mark: ○○; Type Name: glas 2; URL: www.bimvoorfabrikanten.nl; Workset: Family : Windows : WI_subvak
Type - Other - Category: Windows; Family Name: WI_subvak
Classification: 31.11 Uniformat (Uniformat)
Model Properties - subpaneel_1_roedes_hor: 0; subpaneel_1_roedes_ver: 0
Constraints - Moves With Nearby Elements: no
Phasing - Phase Created: 2. nieuwbouw
Identity Data - Workset: Workset1
Other - CalcHorMultiple: no; CalcHorSingle: no; CalcVentilationHeight: 80 mm; CalcVertMultiple: no; CalcVertSingle: no; Family: WI_subvak; Family and Type: WI_subvak: glas 2; SubPanel_1_h_Calc: 2; SubPanel_1_v_Calc: 2; Type: glas 2; Type Id: 835028; Ventilation: no
Name (WI_subvak:glas 2:...) | In | OverallHeight (mm) | OverallWidth (mm) = Rough Width (mm) = Width (mm) | Level | Host | Offset from Host (mm) | Area (m2) | Height (mm) = Rough Height (mm) = subpaneel_1_hoogte (mm) | Volume (m3) | Mark | CalcStartHor (mm) | CalcStartVert (mm) | Group
877883 | 02 tweede verdieping | 2285 | 712 | 02 tweede verdieping | Curtain Wall : NLRS_21_CW_Ontwerpkozijn_aluminium_RT72 | 94 | 0.70368 | 2205 | 0.0052506 | 188 | 735 | 237.333 | Model Group:BU-40:2712884
877884 | 02 tweede verdieping | 2285 | 712 | 02 tweede verdieping | Curtain Wall : NLRS_21_CW_Ontwerpkozijn_aluminium_RT72 | 94 | 0.70368 | 2205 | 0.0052506 | 189 | 735 | 237.333 | Model Group:BU-40:2712884
1475739 | 01 eerste verdieping | 2242.5 | 780 | 01 eerste verdieping | Curtain Wall : 32_BDG_Jansen Economy 50 | 200 | 0.7098 | 2162.5 | 0.0052965 | 343 | 720.833 | 260 | Model Group:BI-26bw:2535201
1475827 | 01 eerste verdieping | 2242.5 | 779.813 | 01 eerste verdieping | Curtain Wall : 32_BDG_Jansen Economy 50 | 200 | 0.709755 | 2162.5 | 0.00529616 | 347 | 720.833 | 259.938 | Model Group:BI-26bw:2535201
1480266 | 00 begane grond | 2262.5 | 795.5 | 00 begane grond | Curtain Wall : 32_BDG_Jansen Economy 50 | 200 | 0.71832 | 2182.5 | 0.0053604 | 353 | 727.5 | 265.167 | Model Group:BI-13bw 7515x2800:2527306
1489684 | 00 begane grond | 2245 | 768 | 00 begane grond | Curtain Wall : NLRS_21_CW_Ontwerpkozijn_aluminium_RT72 | 77 | 0.70752 | 2165 | 0.0052794 | 325 | 721.667 | 256 | Model Group:BU-22 b2700:1300414
1491248 | 00 begane grond | 2245 | 768 | 00 begane grond | Curtain Wall : NLRS_21_CW_Ontwerpkozijn_aluminium_RT72 | 77 | 0.70752 | 2165 | 0.0052794 | 327 | 721.667 | 256 | Model Group:BU-21 b2966:1300741
1492303 | 00 begane grond | 2245 | 768 | 00 begane grond | Curtain Wall : NLRS_21_CW_Ontwerpkozijn_aluminium_RT72 | 77 | 0.70752 | 2165 | 0.0052794 | 331 | 721.667 | 256 | Model Group:BU-20 b3300:1300930
1613691 | 00 begane grond | 2115 | 746 | 00 begane grond | Curtain Wall : 32_ontwerpkozijn binnen 125*67 | 200 | 0.67104 | 2035 | 0.0050058 | 363 | 678.333 | 248.667 | Model Group:BI-10 4215x2800:2522162
1613747 | 00 begane grond | 2115 | 746 | 00 begane grond | Curtain Wall : 32_ontwerpkozijn binnen 125*67 | 200 | 0.67104 | 2035 | 0.0050058 | 365 | 678.333 | 248.667 | Model Group:BI-10 4215x2800:2522162
1729487 | 02 tweede verdieping | 2115 | 746 | 02 tweede verdieping | Curtain Wall : 32_ontwerpkozijn binnen 125*67 | 200 | 0.67104 | 2035 | 0.0050058 | 405 | 678.333 | 248.667 | Model Group:BI-28:2534707
1730460 | 01 eerste verdieping | 2278 | 767 | 01 eerste verdieping | Curtain Wall : 32_ontwerpkozijn binnen 125*67 | 200 | 0.7152 | 2198 | 0.005337 | 407 | 732.667 | 255.667 | Model Group:BI-22 1965x2550:2532537
1730479 | 01 eerste verdieping | 2278 | 767 | 01 eerste verdieping | Curtain Wall : 32_ontwerpkozijn binnen 125*67 | 200 | 0.7152 | 2198 | 0.005337 | 409 | 732.667 | 255.667 | Model Group:BI-22 1965x2550:2532537
1732148 | 02 tweede verdieping | 2115 | 746 | 02 tweede verdieping | Curtain Wall : 32_ontwerpkozijn binnen 125*67 | 200 | 0.67104 | 2035 | 0.0050058 | 411 | 678.333 | 248.667 | Model Group:BI-28:2534707
1817769 | 00 begane grond | 2245 | 768 | 00 begane grond | Curtain Wall : NLRS_21_CW_Ontwerpkozijn_aluminium_RT72 | 77 | 0.70752 | 2165 | 0.0052794 | 345 | 721.667 | 256 | Model Group:BU-12 b4200:1817348
1822162 | 00 begane grond | 2245 | 768 | 00 begane grond | Curtain Wall : NLRS_21_CW_Ontwerpkozijn_aluminium_RT72 | 77 | 0.70752 | 2165 | 0.0052794 | 333 | 721.667 | 256 | Model Group:BU-10 b1800:1822150
1823331 | 00 begane grond | 2223 | 768 | 00 begane grond | Curtain Wall : NLRS_21_CW_Ontwerpkozijn_aluminium_RT72 | 77 | 0.70224 | 2143 | 0.0052398 | 419 | 714.333 | 256 | Model Group:BU-15 b4200:1823297
1823333 | 00 begane grond | 2223 | 768 | 00 begane grond | Curtain Wall : NLRS_21_CW_Ontwerpkozijn_aluminium_RT72 | 77 | 0.70224 | 2143 | 0.0052398 | 421 | 714.333 | 256 | Model Group:BU-15 b4200:1823297
1837631 | 01 eerste verdieping | 2420 | 768 | 01 eerste verdieping | Curtain Wall : NLRS_21_CW_Ontwerpkozijn_aluminium_RT72 | 77 | 0.74952 | 2340 | 0.0055944 | 427 | 780 | 256 | Model Group:BU-32:892003
1850208 | 01 eerste verdieping | 2383 | 629.5 | 01 eerste verdieping | Curtain Wall : NLRS_21_CW_Ontwerpkozijn_aluminium_RT72 | 94 | 0.7074 | 2303 | 0.0052785 | 441 | 767.667 | 209.833 | Model Group:BU-31:891953
1850209 | 01 eerste verdieping | 2383 | 629.5 | 01 eerste verdieping | Curtain Wall : NLRS_21_CW_Ontwerpkozijn_aluminium_RT72 | 94 | 0.7074 | 2303 | 0.0052785 | 442 | 767.667 | 209.833 | Model Group:BU-31:891953
1856780 | 00 begane grond | 2189 | 752.75 | 00 begane grond | Curtain Wall : NLRS_21_CW_Ontwerpkozijn_aluminium_RT72 | 94 | 0.69042 | 2109 | 0.00515115 | 437 | 703 | 250.917 | Model Group:BU-18 b3017:2651211
1856781 | 00 begane grond | 2189 | 752.75 | 00 begane grond | Curtain Wall : NLRS_21_CW_Ontwerpkozijn_aluminium_RT72 | 94 | 0.69042 | 2109 | 0.00515115 | 438 | 703 | 250.917 | Model Group:BU-18 b3017:2651211
1857517 | 00 begane grond | 2297 | 820 | 00 begane grond | Curtain Wall : NLRS_21_CW_Ontwerpkozijn_aluminium_RT72 | 40 | 0.73248 | 2217 | 0.0054666 | 446 | 739 | 273.333 | Model Group:BU-03 b5800:1818868
1857536 | 00 begane grond | 2297 | 820 | 00 begane grond | Curtain Wall : NLRS_21_CW_Ontwerpkozijn_aluminium_RT72 | 40 | 0.73248 | 2217 | 0.0054666 | 448 | 739 | 273.333 | Model Group:BU-03 b5800:1818868
1857655 | 00 begane grond | 2297 | 684 | 00 begane grond | Curtain Wall : NLRS_21_CW_Ontwerpkozijn_aluminium_RT72 | 40 | 0.69984 | 2217 | 0.0052218 | 450 | 739 | 228 | Model Group:BU-07 b900:894363
1857837 | 00 begane grond | 2297 | 684 | 00 begane grond | Curtain Wall : NLRS_21_CW_Ontwerpkozijn_aluminium_RT72 | 40 | 0.69984 | 2217 | 0.0052218 | 454 | 739 | 228 | Model Group:BU-07 b900 (members excluded):1300407
1857840 | 00 begane grond | 2297 | 684 | 00 begane grond | Curtain Wall : NLRS_21_CW_Ontwerpkozijn_aluminium_RT72 | 40 | 0.69984 | 2217 | 0.0052218 | 456 | 739 | 228 | Model Group:BU-07 b900:1502980
1857942 | 00 begane grond | 2297 | 820 | 00 begane grond | Curtain Wall : NLRS_21_CW_Ontwerpkozijn_aluminium_RT72 | 40 | 0.73248 | 2217 | 0.0054666 | 458 | 739 | 273.333 | Model Group:BU-11 b3000:1220846
1859917 | 00 begane grond | 2297 | 820 | 00 begane grond | Curtain Wall : NLRS_21_CW_Ontwerpkozijn_aluminium_RT72 | 40 | 0.73248 | 2217 | 0.0054666 | 286 | 739 | 273.333 | Model Group:BU-09 b1500:1220175
1861306 | 00 begane grond | 2297 | 820 | 00 begane grond | Curtain Wall : NLRS_21_CW_Ontwerpkozijn_aluminium_RT72 | 40 | 0.73248 | 2217 | 0.0054666 | 300 | 739 | 273.333 | Model Group:BU-08 b2100:1220076
1862948 | 00 begane grond | 1882 | 820 | 00 begane grond | Curtain Wall : NLRS_21_CW_Ontwerpkozijn_aluminium_RT72 | 40 | 0.63288 | 1802 | 0.0047196 | 462 | 600.667 | 273.333 | Model Group:BU-13 b3300:1862274
1863502 | 00 begane grond | 2189 | 751 | 00 begane grond | Curtain Wall : NLRS_21_CW_Ontwerpkozijn_aluminium_RT72 | 94 | 0.69 | 2109 | 0.005148 | 425 | 703 | 250.333 | Model Group:BU-14 b3000:1494513
1863503 | 00 begane grond | 2189 | 751 | 00 begane grond | Curtain Wall : NLRS_21_CW_Ontwerpkozijn_aluminium_RT72 | 94 | 0.69 | 2109 | 0.005148 | 426 | 703 | 250.333 | Model Group:BU-14 b3000:1494513
1863872 | 00 begane grond | 2297 | 820 | 00 begane grond | Curtain Wall : NLRS_21_CW_Ontwerpkozijn_aluminium_RT72 | 40 | 0.73248 | 2217 | 0.0054666 | 452 | 739 | 273.333 | Model Group:BU-25 b3000:1493474
1864501 | 01 eerste verdieping | 1884 | 257 | 01 eerste verdieping | Curtain Wall : NLRS_21_CW_Ontwerpkozijn_aluminium_RT72 | 40 | 0.49824 | 1804 | 0.0037098 | 470 | 601.333 | 85.6667 | Model Group:31_1A DKD L:875031
1864740 | 01 eerste verdieping | 1884 | 257 | 01 eerste verdieping | Curtain Wall : NLRS_21_CW_Ontwerpkozijn_aluminium_RT72 | 40 | 0.49824 | 1804 | 0.0037098 | 475 | 601.333 | 85.6667 | Model Group:31_1A DK R:875055
1864767 | 01 eerste verdieping | 1884 | 1140 | 01 eerste verdieping | Curtain Wall : NLRS_21_CW_Ontwerpkozijn_aluminium_RT72 | 40 | 0.71016 | 1804 | 0.0052992 | 477 | 601.333 | 380 | Model Group:31_1A DK R:875055
1864946 | 01 eerste verdieping | 1884 | 257 | 01 eerste verdieping | Curtain Wall : NLRS_21_CW_Ontwerpkozijn_aluminium_RT72 | 40 | 0.49824 | 1804 | 0.0037098 | 481 | 601.333 | 85.6667 | Model Group:31_1A DK R:1864938
1864948 | 01 eerste verdieping | 1884 | 1140 | 01 eerste verdieping | Curtain Wall : NLRS_21_CW_Ontwerpkozijn_aluminium_RT72 | 40 | 0.71016 | 1804 | 0.0052992 | 483 | 601.333 | 380 | Model Group:31_1A DK R:1864938
1864990 | 01 eerste verdieping | 1884 | 257 | 01 eerste verdieping | Curtain Wall : NLRS_21_CW_Ontwerpkozijn_aluminium_RT72 | 40 | 0.49824 | 1804 | 0.0037098 | 492 | 601.333 | 85.6667 | Model Group:31_1A DKD L:1864982
1865015 | 01 eerste verdieping | 1884 | 257 | 01 eerste verdieping | Curtain Wall : NLRS_21_CW_Ontwerpkozijn_aluminium_RT72 | 40 | 0.49824 | 1804 | 0.0037098 | 496 | 601.333 | 85.6667 | Model Group:31_1A DK R:1865007
1865017 | 01 eerste verdieping | 1884 | 1140 | 01 eerste verdieping | Curtain Wall : NLRS_21_CW_Ontwerpkozijn_aluminium_RT72 | 40 | 0.71016 | 1804 | 0.0052992 | 498 | 601.333 | 380 | Model Group:31_1A DK R:1865007
1865038 | 01 eerste verdieping | 1884 | 257 | 01 eerste verdieping | Curtain Wall : NLRS_21_CW_Ontwerpkozijn_aluminium_RT72 | 40 | 0.49824 | 1804 | 0.0037098 | 501 | 601.333 | 85.6667 | Model Group:31_1A DKD L:1865030
1865157 | 01 eerste verdieping | 1884 | 257 | 01 eerste verdieping | Curtain Wall : NLRS_21_CW_Ontwerpkozijn_aluminium_RT72 | 40 | 0.49824 | 1804 | 0.0037098 | 503 | 601.333 | 85.6667 | Model Group:31_1A DKD R:875310
1865245 | 01 eerste verdieping | 1884 | 360 | 01 eerste verdieping | Curtain Wall : NLRS_21_CW_Ontwerpkozijn_aluminium_RT72 | 40 | 0.52296 | 1804 | 0.0038952 | 505 | 601.333 | 120 | Model Group:BU-30:2700215
1865354 | 01 eerste verdieping | 1884 | 257 | 01 eerste verdieping | Curtain Wall : NLRS_21_CW_Ontwerpkozijn_aluminium_RT72 | 40 | 0.49824 | 1804 | 0.0037098 | 508 | 601.333 | 85.6667 | Model Group:31_1A DKD R:1865346
1865375 | 01 eerste verdieping | 1884 | 1140 | 01 eerste verdieping | Curtain Wall : NLRS_21_CW_Ontwerpkozijn_aluminium_RT72 | 40 | 0.71016 | 1804 | 0.0052992 | 512 | 601.333 | 380 | Model Group:31_1A DK L:1865367
1865377 | 01 eerste verdieping | 1884 | 257 | 01 eerste verdieping | Curtain Wall : NLRS_21_CW_Ontwerpkozijn_aluminium_RT72 | 40 | 0.49824 | 1804 | 0.0037098 | 514 | 601.333 | 85.6667 | Model Group:31_1A DK L:1865367
1865582 | 01 eerste verdieping | 1884 | 257 | 01 eerste verdieping | Curtain Wall : NLRS_21_CW_Ontwerpkozijn_aluminium_RT72 | 40 | 0.49824 | 1804 | 0.0037098 | 489 | 601.333 | 85.6667 | Model Group:31_1A DKD R:1865574
1865616 | 01 eerste verdieping | 1884 | 257 | 01 eerste verdieping | Curtain Wall : NLRS_21_CW_Ontwerpkozijn_aluminium_RT72 | 40 | 0.49824 | 1804 | 0.0037098 | 520 | 601.333 | 85.6667 | Model Group:31_1A DKD R:1865608
1865663 | 01 eerste verdieping | 1884 | 1140 | 01 eerste verdieping | Curtain Wall : NLRS_21_CW_Ontwerpkozijn_aluminium_RT72 | 40 | 0.71016 | 1804 | 0.0052992 | 530 | 601.333 | 380 | Model Group:31_1A DK L:1865655
1865665 | 01 eerste verdieping | 1884 | 257 | 01 eerste verdieping | Curtain Wall : NLRS_21_CW_Ontwerpkozijn_aluminium_RT72 | 40 | 0.49824 | 1804 | 0.0037098 | 532 | 601.333 | 85.6667 | Model Group:31_1A DK L:1865655
1865682 | 01 eerste verdieping | 1884 | 1140 | 01 eerste verdieping | Curtain Wall : NLRS_21_CW_Ontwerpkozijn_aluminium_RT72 | 40 | 0.71016 | 1804 | 0.0052992 | 536 | 601.333 | 380 | Model Group:31_1A DK L:1865674
1865684 | 01 eerste verdieping | 1884 | 257 | 01 eerste verdieping | Curtain Wall : NLRS_21_CW_Ontwerpkozijn_aluminium_RT72 | 40 | 0.49824 | 1804 | 0.0037098 | 538 | 601.333 | 85.6667 | Model Group:31_1A DK L:1865674
1865789 | 01 eerste verdieping | 1884 | 257 | 01 eerste verdieping | Curtain Wall : NLRS_21_CW_Ontwerpkozijn_aluminium_RT72 | 40 | 0.49824 | 1804 | 0.0037098 | 556 | 601.333 | 85.6667 | Model Group:31_1A DKD R:1865781
1865810 | 01 eerste verdieping | 1884 | 1140 | 01 eerste verdieping | Curtain Wall : NLRS_21_CW_Ontwerpkozijn_aluminium_RT72 | 40 | 0.71016 | 1804 | 0.0052992 | 560 | 601.333 | 380 | Model Group:31_1A DK L:1865802
1865812 | 01 eerste verdieping | 1884 | 257 | 01 eerste verdieping | Curtain Wall : NLRS_21_CW_Ontwerpkozijn_aluminium_RT72 | 40 | 0.49824 | 1804 | 0.0037098 | 562 | 601.333 | 85.6667 | Model Group:31_1A DK L:1865802
1865931 | 01 eerste verdieping | 1884 | 257 | 01 eerste verdieping | Curtain Wall : NLRS_21_CW_Ontwerpkozijn_aluminium_RT72 | 40 | 0.49824 | 1804 | 0.0037098 | 566 | 601.333 | 85.6667 | Model Group:31_1A DK R:1865923
1865933 | 01 eerste verdieping | 1884 | 1140 | 01 eerste verdieping | Curtain Wall : NLRS_21_CW_Ontwerpkozijn_aluminium_RT72 | 40 | 0.71016 | 1804 | 0.0052992 | 568 | 601.333 | 380 | Model Group:31_1A DK R:1865923
1865954 | 01 eerste verdieping | 1884 | 257 | 01 eerste verdieping | Curtain Wall : NLRS_21_CW_Ontwerpkozijn_aluminium_RT72 | 40 | 0.49824 | 1804 | 0.0037098 | 571 | 601.333 | 85.6667 | Model Group:31_1A DKD L:1865946
1866090 | 01 eerste verdieping | 1884 | 1140 | 01 eerste verdieping | Curtain Wall : NLRS_21_CW_Ontwerpkozijn_aluminium_RT72 | 40 | 0.71016 | 1804 | 0.0052992 | 517 | 601.333 | 380 | Model Group:31_1A DKg R:1866082
1869240 | 02 tweede verdieping | 1919 | 634 | 02 tweede verdieping | Curtain Wall : NLRS_21_CW_Ontwerpkozijn_aluminium_RT72 | 40 | 0.59712 | 1839 | 0.0044514 | 485 | 613 | 211.333 | Model Group:31_2A DK R:1867677
1869355 | 02 tweede verdieping | 1919 | 634 | 02 tweede verdieping | Curtain Wall : NLRS_21_CW_Ontwerpkozijn_aluminium_RT72 | 40 | 0.59712 | 1839 | 0.0044514 | 540 | 613 | 211.333 | Model Group:31_2A DK R:1869345
1869372 | 02 tweede verdieping | 1919 | 634 | 02 tweede verdieping | Curtain Wall : NLRS_21_CW_Ontwerpkozijn_aluminium_RT72 | 40 | 0.59712 | 1839 | 0.0044514 | 573 | 613 | 211.333 | Model Group:31_2A DK R:1869362
1869389 | 02 tweede verdieping | 1919 | 634 | 02 tweede verdieping | Curtain Wall : NLRS_21_CW_Ontwerpkozijn_aluminium_RT72 | 40 | 0.59712 | 1839 | 0.0044514 | 576 | 613 | 211.333 | Model Group:31_2A DK R:1869379
1869406 | 02 tweede verdieping | 1919 | 634 | 02 tweede verdieping | Curtain Wall : NLRS_21_CW_Ontwerpkozijn_aluminium_RT72 | 40 | 0.59712 | 1839 | 0.0044514 | 579 | 613 | 211.333 | Model Group:31_2A DK R:1869396
1869423 | 02 tweede verdieping | 1919 | 634 | 02 tweede verdieping | Curtain Wall : NLRS_21_CW_Ontwerpkozijn_aluminium_RT72 | 40 | 0.59712 | 1839 | 0.0044514 | 582 | 613 | 211.333 | Model Group:31_2A DK R:1869413
1869440 | 02 tweede verdieping | 1919 | 634 | 02 tweede verdieping | Curtain Wall : NLRS_21_CW_Ontwerpkozijn_aluminium_RT72 | 40 | 0.59712 | 1839 | 0.0044514 | 585 | 613 | 211.333 | Model Group:31_2A DK R:1869430
1869457 | 02 tweede verdieping | 1919 | 634 | 02 tweede verdieping | Curtain Wall : NLRS_21_CW_Ontwerpkozijn_aluminium_RT72 | 40 | 0.59712 | 1839 | 0.0044514 | 588 | 613 | 211.333 | Model Group:31_2A DK R:1869447
1869476 | 02 tweede verdieping | 1919 | 634 | 02 tweede verdieping | Curtain Wall : NLRS_21_CW_Ontwerpkozijn_aluminium_RT72 | 40 | 0.59712 | 1839 | 0.0044514 | 591 | 613 | 211.333 | Model Group:31_2A DK L:1869467
1869614 | 02 tweede verdieping | 1919 | 634 | 02 tweede verdieping | Curtain Wall : NLRS_21_CW_Ontwerpkozijn_aluminium_RT72 | 40 | 0.59712 | 1839 | 0.0044514 | 594 | 613 | 211.333 | Model Group:31_2A DK L:1869606
1869631 | 02 tweede verdieping | 1919 | 634 | 02 tweede verdieping | Curtain Wall : NLRS_21_CW_Ontwerpkozijn_aluminium_RT72 | 40 | 0.59712 | 1839 | 0.0044514 | 597 | 613 | 211.333 | Model Group:31_2A DK L:1869623
1869648 | 02 tweede verdieping | 1919 | 634 | 02 tweede verdieping | Curtain Wall : NLRS_21_CW_Ontwerpkozijn_aluminium_RT72 | 40 | 0.59712 | 1839 | 0.0044514 | 600 | 613 | 211.333 | Model Group:31_2A DK L:1869640
1869665 | 02 tweede verdieping | 1919 | 634 | 02 tweede verdieping | Curtain Wall : NLRS_21_CW_Ontwerpkozijn_aluminium_RT72 | 40 | 0.59712 | 1839 | 0.0044514 | 603 | 613 | 211.333 | Model Group:31_2A DK L:1869657
1869682 | 02 tweede verdieping | 1919 | 634 | 02 tweede verdieping | Curtain Wall : NLRS_21_CW_Ontwerpkozijn_aluminium_RT72 | 40 | 0.59712 | 1839 | 0.0044514 | 606 | 613 | 211.333 | Model Group:31_2A DK L:1869674
1869699 | 02 tweede verdieping | 1919 | 634 | 02 tweede verdieping | Curtain Wall : NLRS_21_CW_Ontwerpkozijn_aluminium_RT72 | 40 | 0.59712 | 1839 | 0.0044514 | 609 | 613 | 211.333 | Model Group:31_2A DK L:1869691
1869716 | 02 tweede verdieping | 1919 | 634 | 02 tweede verdieping | Curtain Wall : NLRS_21_CW_Ontwerpkozijn_aluminium_RT72 | 40 | 0.59712 | 1839 | 0.0044514 | 612 | 613 | 211.333 | Model Group:31_2A DK L:1869708
1869735 | 02 tweede verdieping | 1919 | 634 | 02 tweede verdieping | Curtain Wall : NLRS_21_CW_Ontwerpkozijn_aluminium_RT72 | 40 | 0.59712 | 1839 | 0.0044514 | 615 | 613 | 211.333 | Model Group:31_2A DK L:1869727
1869752 | 02 tweede verdieping | 1919 | 634 | 02 tweede verdieping | Curtain Wall : NLRS_21_CW_Ontwerpkozijn_aluminium_RT72 | 40 | 0.59712 | 1839 | 0.0044514 | 618 | 613 | 211.333 | Model Group:31_2A DK L:1869744
1869770 | 02 tweede verdieping | 1919 | 634 | 02 tweede verdieping | Curtain Wall : NLRS_21_CW_Ontwerpkozijn_aluminium_RT72 | 40 | 0.59712 | 1839 | 0.0044514 | 621 | 613 | 211.333 | Model Group:31_2A DK R:1869761
1869787 | 02 tweede verdieping | 1919 | 634 | 02 tweede verdieping | Curtain Wall : NLRS_21_CW_Ontwerpkozijn_aluminium_RT72 | 40 | 0.59712 | 1839 | 0.0044514 | 624 | 613 | 211.333 | Model Group:31_2A DK R:1869778
1869806 | 02 tweede verdieping | 1919 | 634 | 02 tweede verdieping | Curtain Wall : NLRS_21_CW_Ontwerpkozijn_aluminium_RT72 | 40 | 0.59712 | 1839 | 0.0044514 | 627 | 613 | 211.333 | Model Group:31_2A DK R:1869797
1869823 | 02 tweede verdieping | 1919 | 634 | 02 tweede verdieping | Curtain Wall : NLRS_21_CW_Ontwerpkozijn_aluminium_RT72 | 40 | 0.59712 | 1839 | 0.0044514 | 630 | 613 | 211.333 | Model Group:31_2A DK R:1869814
1869840 | 02 tweede verdieping | 1919 | 634 | 02 tweede verdieping | Curtain Wall : NLRS_21_CW_Ontwerpkozijn_aluminium_RT72 | 40 | 0.59712 | 1839 | 0.0044514 | 633 | 613 | 211.333 | Model Group:31_2A DK R:1869831
1869857 | 02 tweede verdieping | 1919 | 634 | 02 tweede verdieping | Curtain Wall : NLRS_21_CW_Ontwerpkozijn_aluminium_RT72 | 40 | 0.59712 | 1839 | 0.0044514 | 636 | 613 | 211.333 | Model Group:31_2A DK R:1869848
1869870 | 00 begane grond | 2297 | 820 | 00 begane grond | Curtain Wall : NLRS_21_CW_Ontwerpkozijn_aluminium_RT72 | 40 | 0.73248 | 2217 | 0.0054666 | 640 | 739 | 273.333 | Model Group:BU-02 b4200:1494104
1897644 | 00 begane grond | 2297 | 684 | 00 begane grond | Curtain Wall : NLRS_21_CW_Ontwerpkozijn_aluminium_RT72 | 40 | 0.69984 | 2217 | 0.0052218 | 463 | 739 | 228 | Model Group:BU-07 b900 (members excluded):1300686
1897658 | 00 begane grond | 2297 | 684 | 00 begane grond | Curtain Wall : NLRS_21_CW_Ontwerpkozijn_aluminium_RT72 | 40 | 0.69984 | 2217 | 0.0052218 | 642 | 739 | 228 | Model Group:BU-07 b900 (members excluded):1818605
1898053 | 01 eerste verdieping | 1884 | 257 | 01 eerste verdieping | Curtain Wall : NLRS_21_CW_Ontwerpkozijn_aluminium_RT72 | 40 | 0.49824 | 1804 | 0.0037098 | 302 | 601.333 | 85.6667 | Model Group:31_1A DKD R:1898045
1898108 | 00 begane grond | 497 | 820 | 00 begane grond | Curtain Wall : NLRS_21_CW_Ontwerpkozijn_aluminium_RT72 | 40 | 0.30048 | 417 | 0.0022266 | 311 | 139 | 273.333 | Model Group:BU-21 b2966:1300741
1899587 | 00 begane grond | 2297 | 820 | 00 begane grond | Curtain Wall : NLRS_21_CW_Ontwerpkozijn_aluminium_RT72 | 40 | 0.73248 | 2217 | 0.0054666 | 324 | 739 | 273.333 | Model Group:BU-12 b4200:1817348
1932997 | 00 begane grond | 2245 | 768 | 00 begane grond | Curtain Wall : NLRS_21_CW_Ontwerpkozijn_aluminium_RT72 | 77 | 0.70752 | 2165 | 0.0052794 | 367 | 721.667 | 256 | Model Group:BU-17 b3000:1900158
1934471 | 00 begane grond | 2297 | 734 | 00 begane grond | Curtain Wall : NLRS_21_CW_Ontwerpkozijn_aluminium_RT72 | 40 | 0.71184 | 2217 | 0.0053118 | 521 | 739 | 244.667 | Model Group:BU-18 b3017:2651211
1939780 | 00 begane grond | 2262.5 | 724.5 | 00 begane grond | Curtain Wall : 32_BDG_Jansen Economy 50 | 200 | 0.70128 | 2182.5 | 0.0052326 | 278 | 727.5 | 241.5 | Model Group:BI-13bw 7515x2800:2527306
2012539 | 01 eerste verdieping | 1884 | 257 | 01 eerste verdieping | Curtain Wall : NLRS_21_CW_Ontwerpkozijn_aluminium_RT72 | 40 | 0.49824 | 1804 | 0.0037098 | 651 | 601.333 | 85.6667 | Model Group:31_1A DKD L:2012531
2012569 | 01 eerste verdieping | 1884 | 257 | 01 eerste verdieping | Curtain Wall : NLRS_21_CW_Ontwerpkozijn_aluminium_RT72 | 40 | 0.49824 | 1804 | 0.0037098 | 657 | 601.333 | 85.6667 | Model Group:31_1A DKD L:2012561
2012584 | 01 eerste verdieping | 1834 | 257 | 01 eerste verdieping | Curtain Wall : NLRS_21_CW_Ontwerpkozijn_aluminium_RT72 | 40 | 0.48624 | 1754 | 0.0036198 | 660 | 584.667 | 85.6667 | Model Group:BU-38:2702101
2012624 | 00 begane grond | 2297 | 820 | 00 begane grond | Curtain Wall : NLRS_21_CW_Ontwerpkozijn_aluminium_RT72 | 40 | 0.73248 | 2217 | 0.0054666 | 665 | 739 | 273.333 | Model Group:BU-02 b4200:1494104
2080510 | 01 eerste verdieping | 2115 | 730 | 01 eerste verdieping | Curtain Wall : 32_ontwerpkozijn binnen 125*67 | 200 | 0.6672 | 2035 | 0.004977 | 522 | 678.333 | 243.333 | Model Group:BI-23w 4635x2800:2532690
2266699 | 01 eerste verdieping | 1884 | 1140 | 01 eerste verdieping | Curtain Wall : NLRS_21_CW_Ontwerpkozijn_aluminium_RT72 | 40 | 0.71016 | 1804 | 0.0052992 | 308 | 601.333 | 380 | Model Group:31_1A DK L:2266691
2266701 | 01 eerste verdieping | 1884 | 257 | 01 eerste verdieping | Curtain Wall : NLRS_21_CW_Ontwerpkozijn_aluminium_RT72 | 40 | 0.49824 | 1804 | 0.0037098 | 335 | 601.333 | 85.6667 | Model Group:31_1A DK L:2266691
2266716 | 02 tweede verdieping | 1919 | 634 | 02 tweede verdieping | Curtain Wall : NLRS_21_CW_Ontwerpkozijn_aluminium_RT72 | 40 | 0.59712 | 1839 | 0.0044514 | 350 | 613 | 211.333 | Model Group:31_2A DK L:2266708
2266731 | 02 tweede verdieping | 1919 | 634 | 02 tweede verdieping | Curtain Wall : NLRS_21_CW_Ontwerpkozijn_aluminium_RT72 | 40 | 0.59712 | 1839 | 0.0044514 | 355 | 613 | 211.333 | Model Group:31_2A DK R:2266723
2649851 | 00 begane grond | 2245 | 768 | 00 begane grond | Curtain Wall : NLRS_21_CW_Ontwerpkozijn_aluminium_RT72 | 77 | 0.70752 | 2165 | 0.0052794 | 552 | 721.667 | 256 | Model Group:BU-47 b4200:1822720
2649863 | 00 begane grond | 2297 | 820 | 00 begane grond | Curtain Wall : NLRS_21_CW_Ontwerpkozijn_aluminium_RT72 | 40 | 0.73248 | 2217 | 0.0054666 | 644 | 739 | 273.333 | Model Group:BU-47 b4200:1822720
2652563 | 00 begane grond | 2297 | 820 | 00 begane grond | Curtain Wall : NLRS_21_CW_Ontwerpkozijn_aluminium_RT72 | 40 | 0.73248 | 2217 | 0.0054666 | 645 | 739 | 273.333 | Model Group:BU-11 b3000:1502212
2652649 | 00 begane grond | 2297 | 820 | 00 begane grond | Curtain Wall : NLRS_21_CW_Ontwerpkozijn_aluminium_RT72 | 40 | 0.73248 | 2217 | 0.0054666 | 661 | 739 | 273.333 | Model Group:BU-11 b3000:1502763
2691559 | 02 tweede verdieping | 2242.5 | 780 | 02 tweede verdieping | Curtain Wall : 32_BDG_Jansen Economy 50 | 77 | 0.7098 | 2162.5 | 0.0052965 | 691 | 720.833 | 260 | Model Group:BI-29bw 60min:1476114
2691603 | 02 tweede verdieping | 2242.5 | 779.963 | 02 tweede verdieping | Curtain Wall : 32_BDG_Jansen Economy 50 | 77 | 0.709791 | 2162.5 | 0.00529643 | 693 | 720.833 | 259.988 | Model Group:BI-29bw 60min:1476114
2691647 | 02 tweede verdieping | 2242.5 | 787.337 | 02 tweede verdieping | Curtain Wall : 32_BDG_Jansen Economy 50 | 77 | 0.711561 | 2162.5 | 0.00530971 | 695 | 720.833 | 262.446 | Model Group:BI-29bw 60min:1476114
2691666 | 02 tweede verdieping | 2242.5 | 785 | 02 tweede verdieping | Curtain Wall : 32_BDG_Jansen Economy 50 | 77 | 0.711 | 2162.5 | 0.0053055 | 697 | 720.833 | 261.667 | Model Group:BI-29bw 60min:1476114
3003083 | 00 begane grond | 2223 | 729 | 00 begane grond | Curtain Wall : NLRS_21_CW_Ontwerpkozijn_aluminium_RT72 | 77 | 0.69288 | 2143 | 0.0051696 | 715 | 714.333 | 243 | Model Group:BU-01 b1500:3003067
3003100 | 00 begane grond | 2223 | 463 | 00 begane grond | Curtain Wall : NLRS_21_CW_Ontwerpkozijn_aluminium_RT72 | 200 | 0.62904 | 2143 | 0.0046908 | 717 | 714.333 | 154.333 | Model Group:BU-01 b1500:3003067
3016893 | 00 begane grond | 2297 | 453 | 00 begane grond | Curtain Wall : NLRS_21_CW_Ontwerpkozijn_aluminium_RT72 | 40 | 0.6444 | 2217 | 0.004806 | 710 | 739 | 151
3058244 | 01 eerste verdieping | 1884 | 257 | 01 eerste verdieping | Curtain Wall : NLRS_21_CW_Ontwerpkozijn_aluminium_RT72 | 40 | 0.49824 | 1804 | 0.0037098 | 711 | 601.333 | 85.6667 | Model Group:31_1A DKD R:3058236
3451942 | 00 begane grond | 1882 | 684 | 00 begane grond | Curtain Wall : NLRS_21_CW_Ontwerpkozijn_aluminium_RT72 | 40 | 0.60024 | 1802 | 0.0044748 | 714 | 600.667 | 228 | Model Group:BU-45 b900:2546304
3702038 | 00 begane grond | 2209 | 712 | 00 begane grond | Curtain Wall : NLRS_21_CW_Ontwerpkozijn_aluminium_RT72 | 94 | 0.68544 | 2129 | 0.0051138 | 754 | 709.667 | 237.333 | Model Group:BU-04 b2500:1820005
3702039 | 00 begane grond | 2209 | 712 | 00 begane grond | Curtain Wall : NLRS_21_CW_Ontwerpkozijn_aluminium_RT72 | 94 | 0.68544 | 2129 | 0.0051138 | 755 | 709.667 | 237.333 | Model Group:BU-04 b2500:1820005
3839161 | 03 derde verdieping | 864 | 1319.25 | 03 derde verdieping | Curtain Wall : NLRS_21_CW_Ontwerpkozijn_aluminium_RT72 | 40 | 0.50838 | 784 | 0.00378585 | 443 | 261.333 | 439.75 | Model Group:31_daklicht_B (members excluded):2194619
3839205 | 03 derde verdieping | 864 | 1348.25 | 03 derde verdieping | Curtain Wall : NLRS_21_CW_Ontwerpkozijn_aluminium_RT72 | 40 | 0.51534 | 784 | 0.00383805 | 467 | 261.333 | 449.417 | Model Group:31_daklicht_B (members excluded):2194619
3839224 | 03 derde verdieping | 864 | 1348.25 | 03 derde verdieping | Curtain Wall : NLRS_21_CW_Ontwerpkozijn_aluminium_RT72 | 40 | 0.51534 | 784 | 0.00383805 | 545 | 261.333 | 449.417 | Model Group:31_daklicht_B (members excluded):2194619
3839251 | 03 derde verdieping | 864 | 1319.25 | 03 derde verdieping | Curtain Wall : NLRS_21_CW_Ontwerpkozijn_aluminium_RT72 | 40 | 0.50838 | 784 | 0.00378585 | 547 | 261.333 | 439.75 | Model Group:31_daklicht_B (members excluded):2194619
3840021 | 03 derde verdieping | 864 | 1319.25 | 03 derde verdieping | Curtain Wall : NLRS_21_CW_Ontwerpkozijn_aluminium_RT72 | 40 | 0.50838 | 784 | 0.00378585 | 549 | 261.333 | 439.75 | Model Group:31_daklicht_B:2194786
3840023 | 03 derde verdieping | 864 | 1348.25 | 03 derde verdieping | Curtain Wall : NLRS_21_CW_Ontwerpkozijn_aluminium_RT72 | 40 | 0.51534 | 784 | 0.00383805 | 551 | 261.333 | 449.417 | Model Group:31_daklicht_B:2194786
3840025 | 03 derde verdieping | 864 | 1348.25 | 03 derde verdieping | Curtain Wall : NLRS_21_CW_Ontwerpkozijn_aluminium_RT72 | 40 | 0.51534 | 784 | 0.00383805 | 720 | 261.333 | 449.417 | Model Group:31_daklicht_B:2194786
3840027 | 03 derde verdieping | 864 | 1319.25 | 03 derde verdieping | Curtain Wall : NLRS_21_CW_Ontwerpkozijn_aluminium_RT72 | 40 | 0.50838 | 784 | 0.00378585 | 722 | 261.333 | 439.75 | Model Group:31_daklicht_B:2194786
3840520 | 03 derde verdieping | 864 | 1273.62 | 03 derde verdieping | Curtain Wall : NLRS_21_CW_Ontwerpkozijn_aluminium_RT72 | 40 | 0.49743 | 784 | 0.00370372 | 724 | 261.333 | 424.542 | Model Group:31_daklicht_C:2194635
3840564 | 03 derde verdieping | 864 | 1302.62 | 03 derde verdieping | Curtain Wall : NLRS_21_CW_Ontwerpkozijn_aluminium_RT72 | 40 | 0.50439 | 784 | 0.00375592 | 729 | 261.333 | 434.208 | Model Group:31_daklicht_C:2194635
3840583 | 03 derde verdieping | 864 | 1302.62 | 03 derde verdieping | Curtain Wall : NLRS_21_CW_Ontwerpkozijn_aluminium_RT72 | 40 | 0.50439 | 784 | 0.00375592 | 731 | 261.333 | 434.208 | Model Group:31_daklicht_C:2194635
3840585 | 03 derde verdieping | 864 | 1273.62 | 03 derde verdieping | Curtain Wall : NLRS_21_CW_Ontwerpkozijn_aluminium_RT72 | 40 | 0.49743 | 784 | 0.00370372 | 733 | 261.333 | 424.542 | Model Group:31_daklicht_C:2194635
3840903 | 03 derde verdieping | 864 | 1273.62 | 03 derde verdieping | Curtain Wall : NLRS_21_CW_Ontwerpkozijn_aluminium_RT72 | 40 | 0.49743 | 784 | 0.00370372 | 735 | 261.333 | 424.542 | Model Group:31_daklicht_C:2194793
3840905 | 03 derde verdieping | 864 | 1302.62 | 03 derde verdieping | Curtain Wall : NLRS_21_CW_Ontwerpkozijn_aluminium_RT72 | 40 | 0.50439 | 784 | 0.00375592 | 737 | 261.333 | 434.208 | Model Group:31_daklicht_C:2194793
3840907 | 03 derde verdieping | 864 | 1302.62 | 03 derde verdieping | Curtain Wall : NLRS_21_CW_Ontwerpkozijn_aluminium_RT72 | 40 | 0.50439 | 784 | 0.00375592 | 739 | 261.333 | 434.208 | Model Group:31_daklicht_C:2194793
3840909 | 03 derde verdieping | 864 | 1273.62 | 03 derde verdieping | Curtain Wall : NLRS_21_CW_Ontwerpkozijn_aluminium_RT72 | 40 | 0.49743 | 784 | 0.00370372 | 741 | 261.333 | 424.542 | Model Group:31_daklicht_C:2194793
3841132 | 03 derde verdieping | 864 | 1289.5 | 03 derde verdieping | Curtain Wall : NLRS_21_CW_Ontwerpkozijn_aluminium_RT72 | 40 | 0.50124 | 784 | 0.0037323 | 743 | 261.333 | 429.833 | Model Group:daklicht A1 (members excluded):2182288
3841176 | 03 derde verdieping | 864 | 1318.5 | 03 derde verdieping | Curtain Wall : NLRS_21_CW_Ontwerpkozijn_aluminium_RT72 | 40 | 0.5082 | 784 | 0.0037845 | 745 | 261.333 | 439.5 | Model Group:daklicht A1 (members excluded):2182288
3841195 | 03 derde verdieping | 864 | 1318.5 | 03 derde verdieping | Curtain Wall : NLRS_21_CW_Ontwerpkozijn_aluminium_RT72 | 40 | 0.5082 | 784 | 0.0037845 | 747 | 261.333 | 439.5 | Model Group:daklicht A1 (members excluded):2182288
3841197 | 03 derde verdieping | 864 | 1289.5 | 03 derde verdieping | Curtain Wall : NLRS_21_CW_Ontwerpkozijn_aluminium_RT72 | 40 | 0.50124 | 784 | 0.0037323 | 749 | 261.333 | 429.833 | Model Group:daklicht A1 (members excluded):2182288
3841500 | 03 derde verdieping | 864 | 1289.5 | 03 derde verdieping | Curtain Wall : NLRS_21_CW_Ontwerpkozijn_aluminium_RT72 | 40 | 0.50124 | 784 | 0.0037323 | 751 | 261.333 | 429.833 | Model Group:daklicht A1:2182252
3841502 | 03 derde verdieping | 864 | 1318.5 | 03 derde verdieping | Curtain Wall : NLRS_21_CW_Ontwerpkozijn_aluminium_RT72 | 40 | 0.5082 | 784 | 0.0037845 | 757 | 261.333 | 439.5 | Model Group:daklicht A1:2182252
3841504 | 03 derde verdieping | 864 | 1318.5 | 03 derde verdieping | Curtain Wall : NLRS_21_CW_Ontwerpkozijn_aluminium_RT72 | 40 | 0.5082 | 784 | 0.0037845 | 762 | 261.333 | 439.5 | Model Group:daklicht A1:2182252
3841506 | 03 derde verdieping | 864 | 1289.5 | 03 derde verdieping | Curtain Wall : NLRS_21_CW_Ontwerpkozijn_aluminium_RT72 | 40 | 0.50124 | 784 | 0.0037323 | 764 | 261.333 | 429.833 | Model Group:daklicht A1:2182252

# IfcWindow: rht7014:RHT1015, rht7014:RHT1015:1326828
In: 03 derde verdieping
Type - ParameterTakesPrecedence: no; Sizeable: no; Material: a_kozijn, Gorter_Material 2, Gorter_Material 1
Type - Analytical Properties - Define Thermal Properties by: Schematic Type; Analytic Construction: <None>
Type - Materials and Finishes - Hatch Material: Gorter_Material 1; Oppervlaktebehandeling binnenzijde: Gepoedercoat RAL9010; Oppervlaktebehandeling buitenzijde: Gepoedercoat RAL7047
Type - Dimensions - A: 1000 mm; B: 1500 mm; Height: 1500 mm; Rough Height: 1500 mm; Rough Width: 1000 mm; Width: 1000 mm
Type - Identity Data - Assembly Code: 37.22.28; Assembly Description: dakluik; Belastbaarheid: 1050 kg/m2; Bestendigheid tegen sneeuwbelasting: 405 kg/m²; Bestendigheid tegen windbelasting: 3000 Pa; Constructiesterkte: ± 3000 Pa; Geluidwerendheid: 27 dB; Hard body impact test (EN 356): Class P5A; Isolatiewaarde deksel: Rc = 4,52 (m2.K)W; U = 0,221 W/(m2.K); Isolatiewaarde opstand: Rc = 4,41 (m2.K)W; U = 0,227 W/(m2.K); Luchtdichtheid: 0,5 m3/hm1; Manufacturer: Gorter; Model: RHT; Soft body impact test (EN 13049): Class 5; Type Mark: 76; Type Name: RHT1015; URL: http://www.gortergroup.com/nl-nederlands/producten/dakluiken.html; Wind- en waterdichtheid: 650 Pa; Workset: Family : Windows : rht7014
Type - Other - Category: Windows; Family Name: rht7014; Weight (kg): 65
OverallHeight: 3326.69 mm; OverallWidth: 3029.53 mm; Classification: 37.22.28 Uniformat (Uniformat)
Constraints - Moves With Nearby Elements: no; Level: 03 derde verdieping
Phasing - Phase Created: 2. nieuwbouw
Dimensions - Area: 4.88888 m2; Offset to structural layer: 50 mm; Volume: 0.281474 m3
Identity Data - Workset: Workset1; Mark: 312
Other - Family: rht7014; Family and Type: rht7014: RHT1015; Host Id: 874240; Type: RHT1015; Type Id: 1314590
